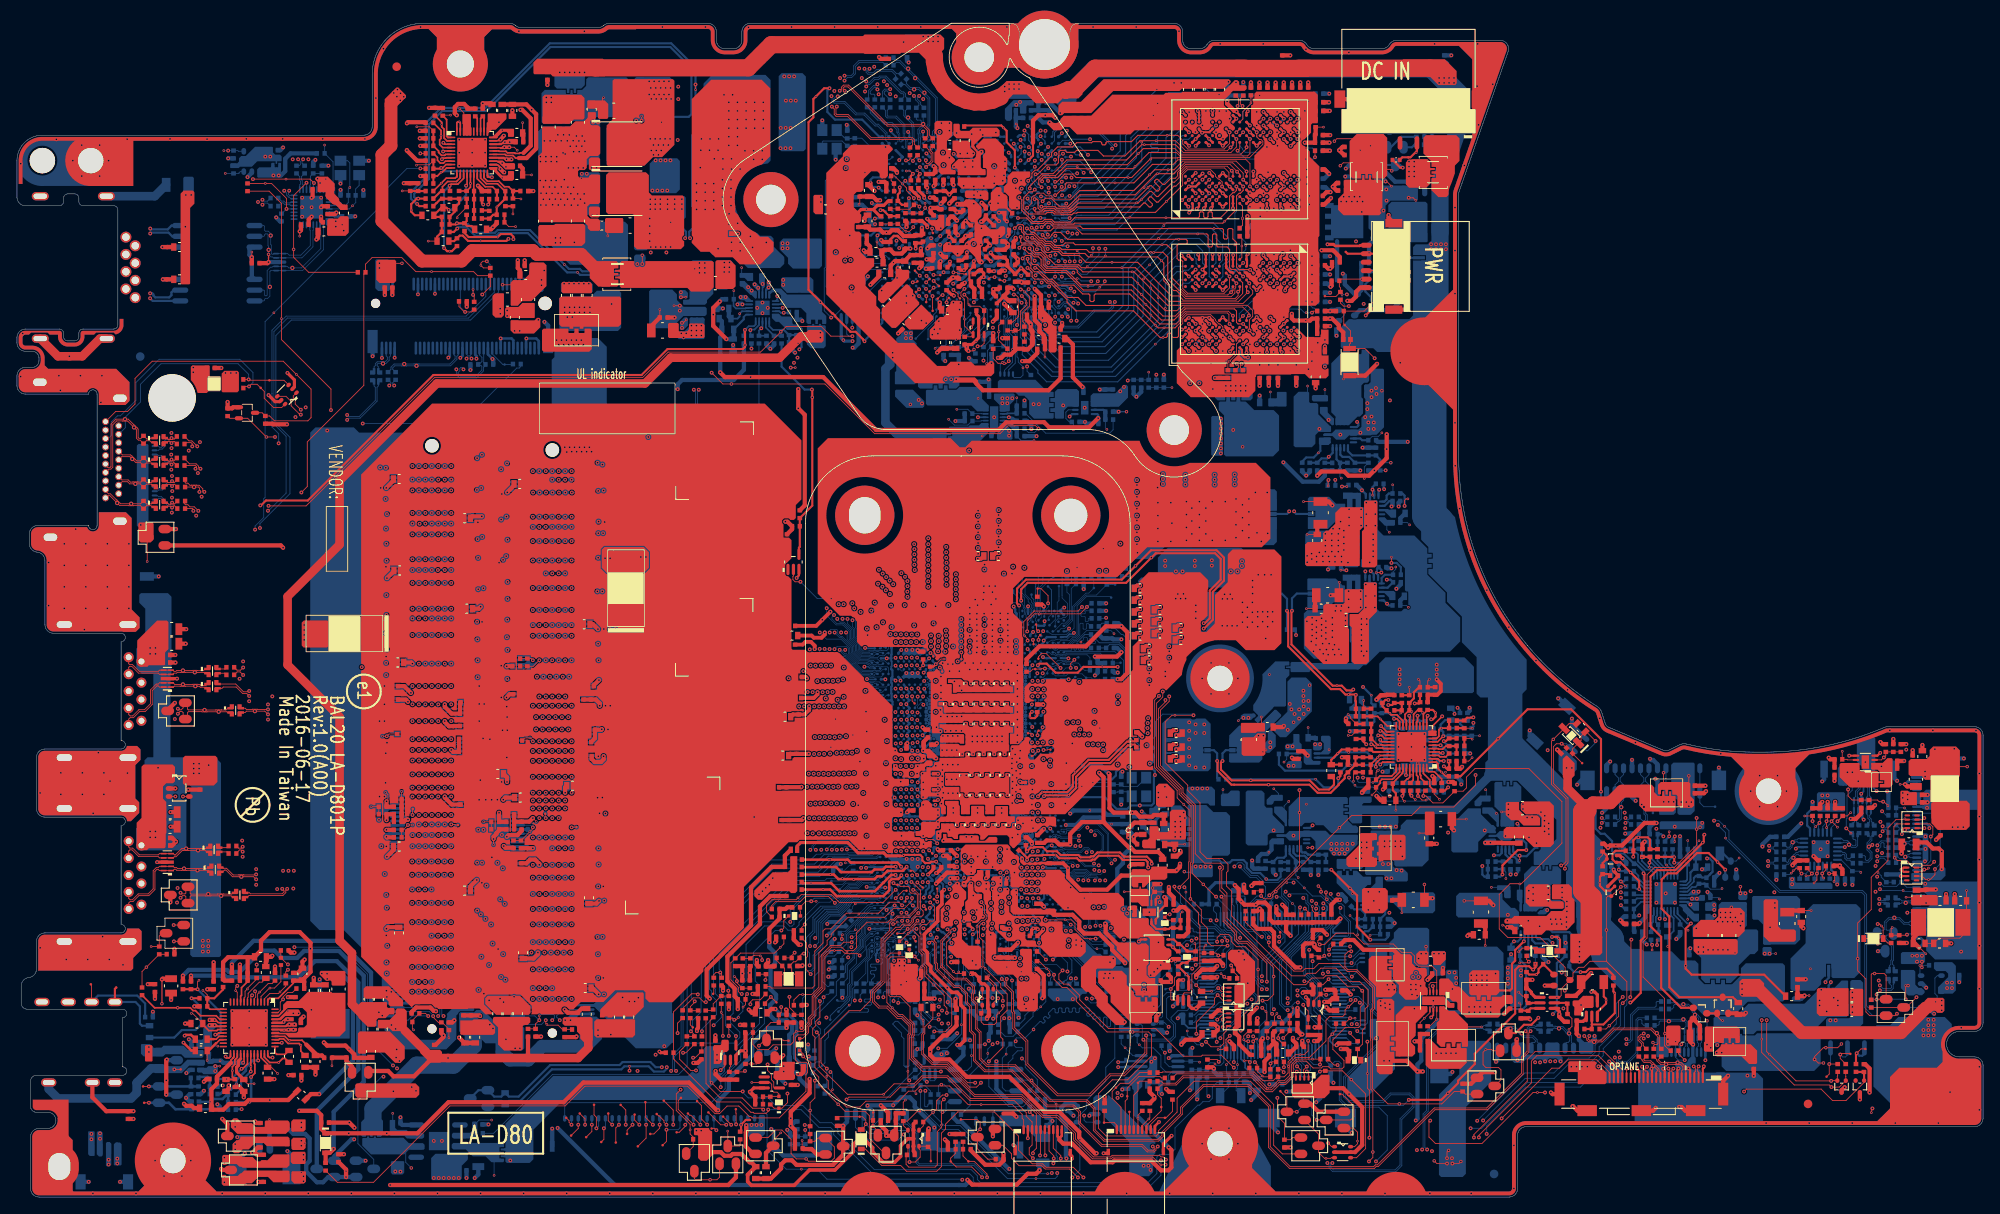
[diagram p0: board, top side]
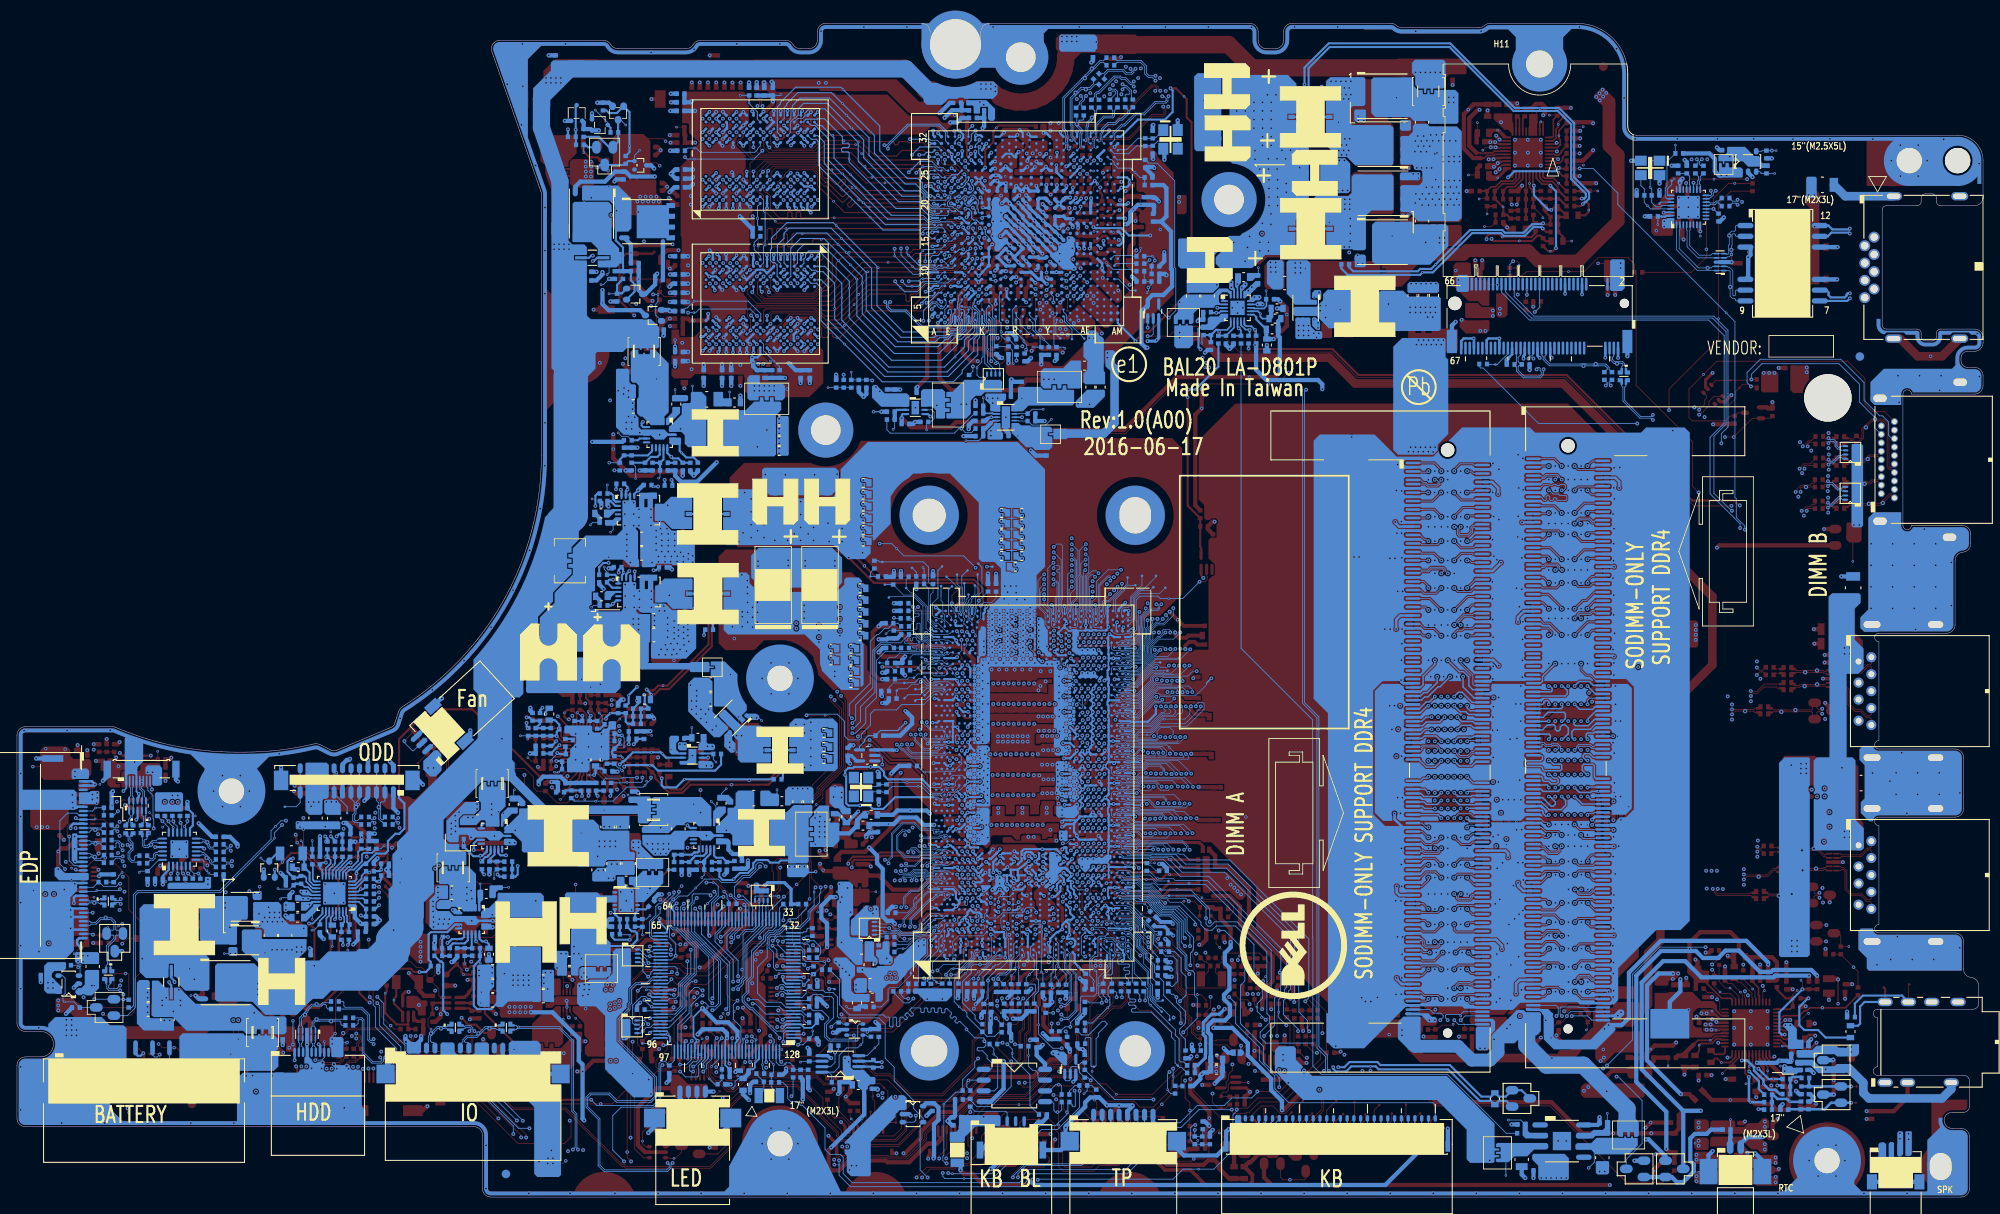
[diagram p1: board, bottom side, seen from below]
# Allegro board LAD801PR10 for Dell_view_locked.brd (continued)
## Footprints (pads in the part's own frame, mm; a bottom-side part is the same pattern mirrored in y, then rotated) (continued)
ACES_50271-0020N-001_2P
  oval 0.787x1.6 smd: 1(0,0) 2(1.25,0)
  rect 2.108x2.997 smd: 3(3.8,-2.9) 4(-2.55,-2.9)
ACES_50406-03071-001_30P
  oval 0.254x1.295 smd: 1(0,0) 2(0.5,0) 3(1,0) 4(1.5,0) 5(2,0) 6(2.5,0) 7(3,0) 8(3.5,0) 9(4,0) 10(4.5,0) 11(5,0) 12(5.5,0) 13(6,0) 14(6.5,0) 15(7,0) 16(7.5,0) 17(8,0) 18(8.5,0) 19(9,0) 20(9.5,0) 21(10,0) 22(10.5,0) 23(11,0) 24(11.5,0) 25(12,0) 26(12.5,0) 27(13,0) 28(13.5,0) 29(14,0) 30(14.5,0)
  rect 1.194x2.692 smd: 31(16.9,1.95) 35(-2.4,1.95)
  rect 2.311x1.295 smd: 32(13.65,3.9) 33(7.25,3.9) 34(0.85,3.9)
ACES_50458-00601-001_6P-T
  oval 0.559x1.6 smd: 1(0,0) 2(2,0) 3(4,0) 4(6,0) 5(8,0) 6(10,0)
  rect 1.295x2.057 smd: 7(-3.1,-5.175) 8(13.1,-5.175)
ACES_50458-01001-P01_10P-T
  oval 0.559x1.803 smd: 1(0,0) 2(2,0) 3(4,0) 4(6,0) 5(8,0) 6(10,0) 7(12,0) 8(14,0) 9(16,0) 10(18,0)
  rect 1.295x2.057 smd: 11(-3.1,-5.275) 12(21.1,-5.275)
ACES_50463-0104A-001_10P
  oval 0.203x1.194 smd: 1(0,0) 2(-0.4,0) 3(-0.8,0) 4(-1.2,0) 5(-1.6,0) 6(-2,0) 7(-2.4,0) 8(-2.8,0) 9(-3.2,0) 10(-3.6,0)
  rect 0.889x2.007 smd: 11(-5.85,-1.37) 12(2.25,-1.37)
ACES_50673-0120N-001_12P-T
  oval 0.61x1.499 smd: 1(0,0) 3(-1,0) 5(-2,0) 7(-3,0) 9(-4,0) 11(-5,0) 13(-6,0) 15(-7,0) 17(-8,0) 19(-9,0) 21(-10,0) 23(-11,0)
  oval 0.61x1.194 smd: 2(0,2.85) 4(-1,2.85) 6(-2,2.85) 8(-3,2.85) 10(-4,2.85) 12(-5,2.85) 14(-6,2.85) 16(-7,2.85) 18(-8,2.85) 20(-9,2.85) 22(-10,2.85) 24(-11,2.85)
  rect 1.702x2.311 smd: 25(-13.25,1.425) 26(2.25,1.425)
ACES_51524-0040N-001_4P
  oval 0.61x1.448 smd: 1(0,0) 2(1,0) 3(2,0) 4(3,0)
  rect 2.489x2.21 smd: 5(-3,-3.125) 6(6,-3.125)
ACES_51524-0160N-001_16P
  oval 0.61x1.295 smd: 1(0,0) 2(1,0) 3(2,0) 4(3,0) 5(4,0) 6(5,0) 7(6,0) 8(7,0) 9(8,0) 10(9,0) 11(10,0) 12(11,0) 13(12,0) 14(13,0) 15(14,0) 16(15,0)
  rect 2.159x2.21 smd: 17(-2.825,-3.05) 18(17.825,-3.05)
ACES_51540-04001-P01_40P
  oval 0.305x1.092 smd: 1(0,0) 2(0.5,0) 3(1,0) 4(1.5,0) 5(2,0) 6(2.5,0) 7(3,0) 8(3.5,0) 9(4,0) 10(4.5,0) 11(5,0) 12(5.5,0) 13(6,0) 14(6.5,0) 15(7,0) 16(7.5,0) 17(8,0) 18(8.5,0) 19(9,0) 20(9.5,0) 21(10,0) 22(10.5,0) 23(11,0) 24(11.5,0) 25(12,0) 26(12.5,0) 27(13,0) 28(13.5,0) 29(14,0) 30(14.5,0) 31(15,0) 32(15.5,0) 33(16,0) 34(16.5,0) 35(17,0) 36(17.5,0) 37(18,0) 38(18.5,0) 39(19,0) 40(19.5,0)
  rect 0.787x2.489 smd: 41(21.2,-3.6) 42(-1.7,-3.6)
ACES_51575-00401-001_4P-T
  oval 0.406x1.194 smd: 1(0,0) 2(1,0) 3(2,0) 4(3,0)
  rect 0.787x2.007 smd: 5(-2.2,-3.4) 6(5.2,-3.4)
ACES_51625-01201-001_12P
  oval 0.305x1.092 smd: 1(0,0) 2(0.5,0) 3(1,0) 4(1.5,0) 5(2,0) 6(2.5,0) 7(3,0) 8(3.5,0) 9(4,0) 10(4.5,0) 11(5,0) 12(5.5,0)
  rect 0.991x2.489 smd: 13(-1.8,-3.6) 14(7.3,-3.6)
ACON_TARA4-9K1311_9P
  round 1.194 hole 0.711: 1(0,0) 2(-2.5,0) 3(-4.5,0) 4(-7,0) 5(-7.5,-1.5) 6(-5.5,-1.5) 7(-3.5,-1.5) 8(-1.5,-1.5) 9(0.5,-1.5)
  oval 1.397x2.591 hole 0.787x2.007: 10(-11.35,-1.59) 13(4.35,-1.59)
  oval 1.397x2.388 hole 0.787x1.803: 11(-11.35,-9.09) 12(4.35,-9.09)
ALC3246-CG_MQFN48_6X6-S
  oval 0.889x0.203 smd: 1(0,0) 2(0,-0.4) 3(0,-0.8) 4(0,-1.2) 5(0,-1.6) 6(0,-2) 7(0,-2.4) 8(0,-2.8) 9(0,-3.2) 10(0,-3.6) 11(0,-4) 12(0,-4.4) 25(6.1,-4.4) 26(6.1,-4) 27(6.1,-3.6) 28(6.1,-3.2) 29(6.1,-2.8) 30(6.1,-2.4) 31(6.1,-2) 32(6.1,-1.6) 33(6.1,-1.2) 34(6.1,-0.8) 35(6.1,-0.4) 36(6.1,0)
  oval 0.203x0.889 smd: 13(0.85,-5.25) 14(1.25,-5.25) 15(1.65,-5.25) 16(2.05,-5.25) 17(2.45,-5.25) 18(2.85,-5.25) 19(3.25,-5.25) 20(3.65,-5.25) 21(4.05,-5.25) 22(4.45,-5.25) 23(4.85,-5.25) 24(5.25,-5.25) 37(5.25,0.85) 38(4.85,0.85) 39(4.45,0.85) 40(4.05,0.85) 41(3.65,0.85) 42(3.25,0.85) 43(2.85,0.85) 44(2.45,0.85) 45(2.05,0.85) 46(1.65,0.85) 47(1.25,0.85) 48(0.85,0.85)
  rect 4.394x4.394 smd: 49(3.05,-2.2)
AON7934_DFN3X3A8-10
  oval 0.457x0.508 smd: 1(0,0) 2(0.65,0) 3(1.3,0) 4(1.95,0) 5(1.95,2.76) 6(1.3,2.76) 7(0.65,2.76) 8(0,2.76)
  rect 2.54x1.041 smd: 9(0.975,1.813)
  rect 2.54x0.559 smd: 10(0.975,0.708)
AOZ5019QI_QFN23_5X3P5
  oval 0.254x0.762 smd: 1(0,0) 2(0.5,0) 3(1,0) 4(1.5,0) 5(2,0)
  rect 3.175x1.524 smd: 6(1.475,1.335)
  custom 0.588x0.588 smd: 7(1.005,2.425)
  rect 1.956x0.864 smd: 8(1.255,4.787)
  oval 0.762x0.254 smd: 9(-0.67,2.925) 10(-0.67,1.925) 11(-0.67,1.425) 12(-0.67,0.925) 13(-0.67,0.425)
AZ5123-02SPR7G_SOT23-3
  oval 1.016x1.524 smd: 1(0,0) 2(0.965,2.083) 3(-0.965,2.083)
AZ5125-01HPR7G_SOD523-2
  rect 0.61x0.787 smd: 1(0,0) 2(1.5,0)
AZ5125-02SPR7G_SOT23-3
  oval 1.016x1.524 smd: 1(0,0) 2(0.965,2.083) 3(-0.965,2.083)
AZ5725-01F_DFN2
  rect 0.559x0.61 smd: 1(0,0) 2(0.85,0)
AZC199-02SPR7G_SOT23-3
  oval 1.016x1.524 smd: 1(0,0) 2(0.965,2.083) 3(-0.965,2.083)
BAS40C_SOT23-3
  oval 1.016x1.524 smd: 1(0,0) 2(0.965,2.083) 3(-0.965,2.083)
BAT54C-7-F_SOT23-3
  oval 1.016x1.524 smd: 1(0,0) 2(0.965,2.083) 3(-0.965,2.083)
BAV99W_SC70-3
  oval 0.508x0.559 smd: 1(0,0) 2(-0.65,-1.85) 3(0.65,-1.85)
C_5X4P5
  oval 2.997x1.6 smd: 1(0,0) 2(-4.4,0)
C_25CL33LD
  oval 3.607x1.803 smd: 1(0,0) 2(5.4,0)
C_0201
  rect 0.381x0.356 smd: 1(0,0) 2(0.584,0)
C_0402
  rect 0.508x0.559 smd: 1(0,0) 2(0.914,0)
C_0603
  rect 0.635x0.889 smd: 1(0,0) 2(1.397,0)
C_0805
  rect 0.813x1.397 smd: 1(0,0) 2(1.702,0)
C_1206
  rect 1.016x1.651 smd: 1(0,0) 2(2.667,0)
C_D2
  rect 2.388x2.794 smd: 1(0,0) 2(6.4,0)
CONCR_099AKAC19NBLCNF_19P
  round 0.813 hole 0.559: 1(0,0) 2(0.5,1.55) 3(1,0) 4(1.5,1.55) 5(2,0) 6(2.5,1.55) 7(3,0) 8(3.5,1.55) 9(4,0) 10(4.5,1.55) 11(5,0) 12(5.5,1.55) 13(6,0) 14(6.5,1.55) 15(7,0) 16(7.5,1.55) 17(8,0) 18(8.5,1.55) 19(9,0)
  oval 1.499x2.21 hole 0.889x1.6: 20(-2.75,1.7) 21(-4.65,-6.5) 22(11.75,1.7) 23(13.65,-7.75)
DDTA144VCA-7-F_SOT23-3
  oval 1.016x1.524 smd: 1(0,0) 2(0.965,2.083) 3(-0.965,2.083)
DEREN_40-42261-26001RHF_260P-T
  round 1.092 hole 1.092 unplated: (-67.775,-4.1)
  round 1.6 hole 1.6 unplated: (1.025,-4.1)
  oval 0.305x1.753 smd: 1(0,0) 2(-0.25,-8.2) 3(-0.5,0) 4(-0.75,-8.2) 5(-1,0) 6(-1.25,-8.2) 7(-1.5,0) 8(-1.75,-8.2) 9(-2,0) 10(-2.25,-8.2) 11(-2.5,0) 12(-2.75,-8.2) 13(-3,0) 14(-3.25,-8.2) 15(-3.5,0) 16(-3.75,-8.2) 17(-4,0) 18(-4.25,-8.2) 19(-4.5,0) 20(-4.75,-8.2) 21(-5,0) 22(-5.25,-8.2) 23(-5.5,0) 24(-5.75,-8.2) 25(-6,0) 26(-6.25,-8.2) 27(-6.5,0) 28(-6.75,-8.2) 29(-7,0) 30(-7.25,-8.2) 31(-7.5,0) 32(-7.75,-8.2) 33(-8,0) 34(-8.25,-8.2) 35(-8.5,0) 36(-8.75,-8.2) 37(-9,0) 38(-9.25,-8.2) 39(-9.5,0) 40(-9.75,-8.2) 41(-10,0) 42(-10.25,-8.2) 43(-10.5,0) 44(-10.75,-8.2) 45(-11,0) 46(-11.25,-8.2) 47(-11.5,0) 48(-11.75,-8.2) 49(-12,0) 50(-12.25,-8.2) 51(-12.5,0) 52(-12.75,-8.2) 53(-13,0) 54(-13.25,-8.2) 55(-13.5,0) 56(-13.75,-8.2) 57(-14,0) 58(-14.25,-8.2) 59(-14.5,0) 60(-14.75,-8.2) 61(-15,0) 62(-15.25,-8.2) 63(-15.5,0) 64(-15.75,-8.2) 65(-16,0) 66(-16.25,-8.2) 67(-16.5,0) 68(-16.75,-8.2) 69(-17,0) 70(-17.25,-8.2) 71(-17.5,0) 72(-17.75,-8.2) 73(-18,0) 74(-18.25,-8.2) 75(-18.5,0) 76(-18.75,-8.2) 77(-19,0) 78(-19.25,-8.2) 79(-19.5,0) 80(-19.75,-8.2) 81(-20,0) 82(-20.25,-8.2) 83(-20.5,0) 84(-20.75,-8.2) 85(-21,0) 86(-21.25,-8.2) 87(-21.5,0) 88(-21.75,-8.2) 89(-22,0) 90(-22.25,-8.2) 91(-22.5,0) 92(-22.75,-8.2) 93(-23,0) 94(-23.25,-8.2) 95(-23.5,0) 96(-23.75,-8.2) 97(-24,0) 98(-24.25,-8.2) 99(-24.5,0) 100(-24.75,-8.2) 101(-25,0) 102(-25.25,-8.2) 103(-25.5,0) 104(-25.75,-8.2) 105(-26,0) 106(-26.25,-8.2) 107(-26.5,0) 108(-26.75,-8.2) 109(-27,0) 110(-27.25,-8.2) 111(-27.5,0) 112(-27.75,-8.2) 113(-28,0) 114(-28.25,-8.2) 115(-28.5,0) 116(-28.75,-8.2) 117(-29,0) 118(-29.25,-8.2) 119(-29.5,0) 120(-29.75,-8.2) 121(-30,0) 122(-30.25,-8.2) 123(-30.5,0) 124(-30.75,-8.2) 125(-31,0) 126(-31.25,-8.2) 127(-31.5,0) 128(-31.75,-8.2) 129(-32,0) 130(-32.25,-8.2) 131(-32.5,0) 132(-32.75,-8.2) 133(-33,0) 134(-33.25,-8.2) 135(-33.5,0) 136(-33.75,-8.2) 137(-34,0) 138(-34.25,-8.2) 139(-34.5,0) 140(-34.75,-8.2) 141(-35,0) 142(-35.25,-8.2) 143(-35.5,0) 144(-35.75,-8.2) 145(-38,0) 146(-38.25,-8.2) 147(-38.5,0) 148(-38.75,-8.2) 149(-39,0) 150(-39.25,-8.2) 151(-39.5,0) 152(-39.75,-8.2) 153(-40,0) 154(-40.25,-8.2) 155(-40.5,0) 156(-40.75,-8.2) 157(-41,0) 158(-41.25,-8.2) 159(-41.5,0) 160(-41.75,-8.2) 161(-42,0) 162(-42.25,-8.2) 163(-42.5,0) 164(-42.75,-8.2) 165(-43,0) 166(-43.25,-8.2) 167(-43.5,0) 168(-43.75,-8.2) 169(-44,0) 170(-44.25,-8.2) 171(-44.5,0) 172(-44.75,-8.2) 173(-45,0) 174(-45.25,-8.2) 175(-45.5,0) 176(-45.75,-8.2) 177(-46,0) 178(-46.25,-8.2) 179(-46.5,0) 180(-46.75,-8.2) 181(-47,0) 182(-47.25,-8.2) 183(-47.5,0) 184(-47.75,-8.2) 185(-48,0) 186(-48.25,-8.2) 187(-48.5,0) 188(-48.75,-8.2) 189(-49,0) 190(-49.25,-8.2) 191(-49.5,0) 192(-49.75,-8.2) 193(-50,0) 194(-50.25,-8.2) 195(-50.5,0) 196(-50.75,-8.2) 197(-51,0) 198(-51.25,-8.2) 199(-51.5,0) 200(-51.75,-8.2) 201(-52,0) 202(-52.25,-8.2) 203(-52.5,0) 204(-52.75,-8.2) 205(-53,0) 206(-53.25,-8.2) 207(-53.5,0) 208(-53.75,-8.2) 209(-54,0) 210(-54.25,-8.2) 211(-54.5,0) 212(-54.75,-8.2) 213(-55,0) 214(-55.25,-8.2) 215(-55.5,0) 216(-55.75,-8.2) 217(-56,0) 218(-56.25,-8.2) 219(-56.5,0) 220(-56.75,-8.2) 221(-57,0) 222(-57.25,-8.2) 223(-57.5,0) 224(-57.75,-8.2) 225(-58,0) 226(-58.25,-8.2) 227(-58.5,0) 228(-58.75,-8.2) 229(-59,0) 230(-59.25,-8.2) 231(-59.5,0) 232(-59.75,-8.2) 233(-60,0) 234(-60.25,-8.2) 235(-60.5,0) 236(-60.75,-8.2) 237(-61,0) 238(-61.25,-8.2) 239(-61.5,0) 240(-61.75,-8.2) 241(-62,0) 242(-62.25,-8.2) 243(-62.5,0) 244(-62.75,-8.2) 245(-63,0) 246(-63.25,-8.2) 247(-63.5,0) 248(-63.75,-8.2) 249(-64,0) 250(-64.25,-8.2) 251(-64.5,0) 252(-64.75,-8.2) 253(-65,0) 254(-65.25,-8.2) 255(-65.5,0) 256(-65.75,-8.2) 257(-66,0) 258(-66.25,-8.2) 259(-66.5,0) 260(-66.75,-8.2)
  rect 3.505x4.597 smd: 261(0.425,-16.1) 262(-67.175,-16.1)
DEREN_40-42271-26001RHF_260P-T
  round 1.6 hole 1.6 unplated: (-1.025,4.1)
  round 1.092 hole 1.092 unplated: (67.775,4.1)
  oval 0.305x1.753 smd: 1(0,0) 2(0.25,8.2) 3(0.5,0) 4(0.75,8.2) 5(1,0) 6(1.25,8.2) 7(1.5,0) 8(1.75,8.2) 9(2,0) 10(2.25,8.2) 11(2.5,0) 12(2.75,8.2) 13(3,0) 14(3.25,8.2) 15(3.5,0) 16(3.75,8.2) 17(4,0) 18(4.25,8.2) 19(4.5,0) 20(4.75,8.2) 21(5,0) 22(5.25,8.2) 23(5.5,0) 24(5.75,8.2) 25(6,0) 26(6.25,8.2) 27(6.5,0) 28(6.75,8.2) 29(7,0) 30(7.25,8.2) 31(7.5,0) 32(7.75,8.2) 33(8,0) 34(8.25,8.2) 35(8.5,0) 36(8.75,8.2) 37(9,0) 38(9.25,8.2) 39(9.5,0) 40(9.75,8.2) 41(10,0) 42(10.25,8.2) 43(10.5,0) 44(10.75,8.2) 45(11,0) 46(11.25,8.2) 47(11.5,0) 48(11.75,8.2) 49(12,0) 50(12.25,8.2) 51(12.5,0) 52(12.75,8.2) 53(13,0) 54(13.25,8.2) 55(13.5,0) 56(13.75,8.2) 57(14,0) 58(14.25,8.2) 59(14.5,0) 60(14.75,8.2) 61(15,0) 62(15.25,8.2) 63(15.5,0) 64(15.75,8.2) 65(16,0) 66(16.25,8.2) 67(16.5,0) 68(16.75,8.2) 69(17,0) 70(17.25,8.2) 71(17.5,0) 72(17.75,8.2) 73(18,0) 74(18.25,8.2) 75(18.5,0) 76(18.75,8.2) 77(19,0) 78(19.25,8.2) 79(19.5,0) 80(19.75,8.2) 81(20,0) 82(20.25,8.2) 83(20.5,0) 84(20.75,8.2) 85(21,0) 86(21.25,8.2) 87(21.5,0) 88(21.75,8.2) 89(22,0) 90(22.25,8.2) 91(22.5,0) 92(22.75,8.2) 93(23,0) 94(23.25,8.2) 95(23.5,0) 96(23.75,8.2) 97(24,0) 98(24.25,8.2) 99(24.5,0) 100(24.75,8.2) 101(25,0) 102(25.25,8.2) 103(25.5,0) 104(25.75,8.2) 105(26,0) 106(26.25,8.2) 107(26.5,0) 108(26.75,8.2) 109(27,0) 110(27.25,8.2) 111(27.5,0) 112(27.75,8.2) 113(28,0) 114(28.25,8.2) 115(28.5,0) 116(28.75,8.2) 117(29,0) 118(29.25,8.2) 119(29.5,0) 120(29.75,8.2) 121(30,0) 122(30.25,8.2) 123(30.5,0) 124(30.75,8.2) 125(31,0) 126(31.25,8.2) 127(31.5,0) 128(31.75,8.2) 129(32,0) 130(32.25,8.2) 131(32.5,0) 132(32.75,8.2) 133(33,0) 134(33.25,8.2) 135(33.5,0) 136(33.75,8.2) 137(34,0) 138(34.25,8.2) 139(34.5,0) 140(34.75,8.2) 141(35,0) 142(35.25,8.2) 143(35.5,0) 144(35.75,8.2) 145(38,0) 146(38.25,8.2) 147(38.5,0) 148(38.75,8.2) 149(39,0) 150(39.25,8.2) 151(39.5,0) 152(39.75,8.2) 153(40,0) 154(40.25,8.2) 155(40.5,0) 156(40.75,8.2) 157(41,0) 158(41.25,8.2) 159(41.5,0) 160(41.75,8.2) 161(42,0) 162(42.25,8.2) 163(42.5,0) 164(42.75,8.2) 165(43,0) 166(43.25,8.2) 167(43.5,0) 168(43.75,8.2) 169(44,0) 170(44.25,8.2) 171(44.5,0) 172(44.75,8.2) 173(45,0) 174(45.25,8.2) 175(45.5,0) 176(45.75,8.2) 177(46,0) 178(46.25,8.2) 179(46.5,0) 180(46.75,8.2) 181(47,0) 182(47.25,8.2) 183(47.5,0) 184(47.75,8.2) 185(48,0) 186(48.25,8.2) 187(48.5,0) 188(48.75,8.2) 189(49,0) 190(49.25,8.2) 191(49.5,0) 192(49.75,8.2) 193(50,0) 194(50.25,8.2) 195(50.5,0) 196(50.75,8.2) 197(51,0) 198(51.25,8.2) 199(51.5,0) 200(51.75,8.2) 201(52,0) 202(52.25,8.2) 203(52.5,0) 204(52.75,8.2) 205(53,0) 206(53.25,8.2) 207(53.5,0) 208(53.75,8.2) 209(54,0) 210(54.25,8.2) 211(54.5,0) 212(54.75,8.2) 213(55,0) 214(55.25,8.2) 215(55.5,0) 216(55.75,8.2) 217(56,0) 218(56.25,8.2) 219(56.5,0) 220(56.75,8.2) 221(57,0) 222(57.25,8.2) 223(57.5,0) 224(57.75,8.2) 225(58,0) 226(58.25,8.2) 227(58.5,0) 228(58.75,8.2) 229(59,0) 230(59.25,8.2) 231(59.5,0) 232(59.75,8.2) 233(60,0) 234(60.25,8.2) 235(60.5,0) 236(60.75,8.2) 237(61,0) 238(61.25,8.2) 239(61.5,0) 240(61.75,8.2) 241(62,0) 242(62.25,8.2) 243(62.5,0) 244(62.75,8.2) 245(63,0) 246(63.25,8.2) 247(63.5,0) 248(63.75,8.2) 249(64,0) 250(64.25,8.2) 251(64.5,0) 252(64.75,8.2) 253(65,0) 254(65.25,8.2) 255(65.5,0) 256(65.75,8.2) 257(66,0) 258(66.25,8.2) 259(66.5,0) 260(66.75,8.2)
  rect 3.505x4.597 smd: 261(-0.425,-7.9) 262(67.175,-7.9)
DMN66D0LDW-7_SOT363-6
  oval 0.432x0.61 smd: 1(0,0) 2(0.65,0) 3(1.3,0) 4(1.3,1.9) 5(0.65,1.9) 6(0,1.9)
EM5209VF_DFN14_3X2-S
  oval 0.203x0.711 smd: 1(0,0) 2(0.4,0) 3(0.8,0) 4(1.2,0) 5(1.6,0) 6(2,0) 7(2.4,0) 8(2.4,2) 9(2,2) 10(1.6,2) 11(1.2,2) 12(0.8,2) 13(0.4,2) 14(0,2)
  rect 2.591x0.991 smd: 15(1.2,1)
F_1206L150PR
  rect 0.991x1.803 smd: 1(0,0) 2(2.8,0)
F_MF-NSMF050-2
  rect 0.991x1.6 smd: 1(0,0) 2(3,0)
F_SMD1812P110TF-24
  rect 1.778x3.15 smd: 1(0,0) 2(5.23,0)
FDV301N_NL_SOT23-3
  oval 1.016x1.524 smd: 1(0,0) 2(0.965,2.083) 3(-0.965,2.083)
FIDUCIAL_C40M80
  round 1.016 smd: 1(0,0)
H5GC4H24AJR-R0C_BGA_170P
  round 0.343 smd: A1(0,0) A2(0.8,0) A3(1.6,0) A4(2.4,0) A5(3.2,0) A10(7.201,0) A11(8.001,0) A12(8.801,0) A13(9.601,0) A14(10.401,0) B1(0,-0.8) B2(0.8,-0.8) B3(1.6,-0.8) B4(2.4,-0.8) B5(3.2,-0.8) B10(7.201,-0.8) B11(8.001,-0.8) B12(8.801,-0.8) B13(9.601,-0.8) B14(10.401,-0.8) C1(0,-1.6) C2(0.8,-1.6) C3(1.6,-1.6) C4(2.4,-1.6) C5(3.2,-1.6) C10(7.201,-1.6) C11(8.001,-1.6) C12(8.801,-1.6) C13(9.601,-1.6) C14(10.401,-1.6) D1(0,-2.4) D2(0.8,-2.4) D3(1.6,-2.4) D4(2.4,-2.4) D5(3.2,-2.4) D10(7.201,-2.4) D11(8.001,-2.4) D12(8.801,-2.4) D13(9.601,-2.4) D14(10.401,-2.4) E1(0,-3.2) E2(0.8,-3.2) E3(1.6,-3.2) E4(2.4,-3.2) E5(3.2,-3.2) E10(7.201,-3.2) E11(8.001,-3.2) E12(8.801,-3.2) E13(9.601,-3.2) E14(10.401,-3.2) F1(0,-4) F2(0.8,-4) F3(1.6,-4) F4(2.4,-4) F5(3.2,-4) F10(7.201,-4) F11(8.001,-4) F12(8.801,-4) F13(9.601,-4) F14(10.401,-4) G1(0,-4.801) G2(0.8,-4.801) G3(1.6,-4.801) G4(2.4,-4.801) G5(3.2,-4.801) G10(7.201,-4.801) G11(8.001,-4.801) G12(8.801,-4.801) G13(9.601,-4.801) G14(10.401,-4.801) H1(0,-5.601) H2(0.8,-5.601) H3(1.6,-5.601) H4(2.4,-5.601) H5(3.2,-5.601) H10(7.201,-5.601) H11(8.001,-5.601) H12(8.801,-5.601) H13(9.601,-5.601) H14(10.401,-5.601) J1(0,-6.401) J2(0.8,-6.401) J3(1.6,-6.401) J4(2.4,-6.401) J5(3.2,-6.401) J10(7.201,-6.401) J11(8.001,-6.401) J12(8.801,-6.401) J13(9.601,-6.401) J14(10.401,-6.401) K1(0,-7.201) K2(0.8,-7.201) K3(1.6,-7.201) K4(2.4,-7.201) K5(3.2,-7.201) K10(7.201,-7.201) K11(8.001,-7.201) K12(8.801,-7.201) K13(9.601,-7.201) K14(10.401,-7.201) L1(0,-8.001) L2(0.8,-8.001) L3(1.6,-8.001) L4(2.4,-8.001) L5(3.2,-8.001) L10(7.201,-8.001) L11(8.001,-8.001) L12(8.801,-8.001) L13(9.601,-8.001) L14(10.401,-8.001) M1(0,-8.801) M2(0.8,-8.801) M3(1.6,-8.801) M4(2.4,-8.801) M5(3.2,-8.801) M10(7.201,-8.801) M11(8.001,-8.801) M12(8.801,-8.801) M13(9.601,-8.801) M14(10.401,-8.801) N1(0,-9.601) N2(0.8,-9.601) N3(1.6,-9.601) N4(2.4,-9.601) N5(3.2,-9.601) N10(7.201,-9.601) N11(8.001,-9.601) N12(8.801,-9.601) N13(9.601,-9.601) N14(10.401,-9.601) P1(0,-10.401) P2(0.8,-10.401) P3(1.6,-10.401) P4(2.4,-10.401) P5(3.2,-10.401) P10(7.201,-10.401) P11(8.001,-10.401) P12(8.801,-10.401) P13(9.601,-10.401) P14(10.401,-10.401) R1(0,-11.201) R2(0.8,-11.201) R3(1.6,-11.201) R4(2.4,-11.201) R5(3.2,-11.201) R10(7.201,-11.201) R11(8.001,-11.201) R12(8.801,-11.201) R13(9.601,-11.201) R14(10.401,-11.201) T1(0,-12.002) T2(0.8,-12.002) T3(1.6,-12.002) T4(2.4,-12.002) T5(3.2,-12.002) T10(7.201,-12.002) T11(8.001,-12.002) T12(8.801,-12.002) T13(9.601,-12.002) T14(10.401,-12.002) U1(0,-12.802) U2(0.8,-12.802) U3(1.6,-12.802) U4(2.4,-12.802) U5(3.2,-12.802) U10(7.201,-12.802) U11(8.001,-12.802) U12(8.801,-12.802) U13(9.601,-12.802) U14(10.401,-12.802)
H_3P0-G
  round 3.505 hole 2.997: 1(0,0)
H_3P0N
  round 2.997 hole 2.997 unplated: (0,0)
H_3P2
  round 3.708 hole 3.2: 1(0,0)
H_3P2X2P6
  oval 3.708x3.099 hole 3.2x2.591: 1(0,0)
H_3P5
  round 4.013 hole 3.505: 1(0,0)
H_3P7
  round 4.216 hole 3.708: 1(0,0)
H_3P7X4P3
  oval 4.216x4.801 hole 3.708x4.293: 1(0,0)
H_3P9
  round 4.42 hole 3.912: 1(0,0)
H_5P6N
  round 5.588 hole 5.588 unplated: (0,0)
H_6P0
  round 6.502 hole 5.994: 1(0,0)
INPAQ_HCM1012GH900BP_4P-NPM
  rect 0.711x0.305 smd: 1(0,0) 2(1.25,0) 3(1.25,-0.5) 4(0,-0.5)
INPAQ_MCM1012B900F06BP_4P
  rect 0.711x0.305 smd: 1(0,0) 2(1.25,0) 3(1.25,-0.5) 4(0,-0.5)
INPAQ_MCM1012B900F06BP_4P-NPM
  rect 0.711x0.305 smd: 1(0,0) 2(1.25,0) 3(1.25,-0.5) 4(0,-0.5)
IP4292CZ10-TBR_XSON10_2P5X1
  oval 0.254x0.889 smd: 1(0,0)
  oval 0.254x0.838 smd: 2(0.5,-0.025) 3(1,-0.025) 4(1.5,-0.025) 5(2,-0.025) 6(2,1.125) 7(1.5,1.125) 8(1,1.125) 9(0.5,1.125) 10(0,1.125)
ISL62771HRTZ-T_TQFN40_5X5-S
  oval 0.203x1.016 smd: 1(0,0) 2(0.4,0) 3(0.8,0) 4(1.2,0) 5(1.6,0) 6(2,0) 7(2.4,0) 8(2.8,0) 9(3.2,0) 10(3.6,0) 21(3.6,4.975) 22(3.2,4.975) 23(2.8,4.975) 24(2.4,4.975) 25(2,4.975) 26(1.6,4.975) 27(1.2,4.975) 28(0.8,4.975) 29(0.4,4.975) 30(0,4.975)
  oval 1.016x0.203 smd: 11(4.288,0.688) 12(4.288,1.088) 13(4.288,1.488) 14(4.288,1.888) 15(4.288,2.288) 16(4.288,2.688) 17(4.288,3.088) 18(4.288,3.488) 19(4.288,3.888) 20(4.288,4.288) 31(-0.688,4.288) 32(-0.688,3.888) 33(-0.688,3.488) 34(-0.688,3.088) 35(-0.688,2.688) 36(-0.688,2.288) 37(-0.688,1.888) 38(-0.688,1.488) 39(-0.688,1.088) 40(-0.688,0.688)
  rect 3.505x3.505 smd: 41(1.8,2.488)
ISL62883CHRTZ-T_TQFN40_5X5-S
  oval 0.203x0.991 smd: 1(0,0) 2(0.4,0) 3(0.8,0) 4(1.2,0) 5(1.6,0) 6(2,0) 7(2.4,0) 8(2.8,0) 9(3.2,0) 10(3.6,0) 21(3.6,4.95) 22(3.2,4.95) 23(2.8,4.95) 24(2.4,4.95) 25(2,4.95) 26(1.6,4.95) 27(1.2,4.95) 28(0.8,4.95) 29(0.4,4.95) 30(0,4.95)
  oval 0.991x0.203 smd: 11(4.275,0.675) 12(4.275,1.075) 13(4.275,1.475) 14(4.275,1.875) 15(4.275,2.275) 16(4.275,2.675) 17(4.275,3.075) 18(4.275,3.475) 19(4.275,3.875) 20(4.275,4.275) 31(-0.675,4.275) 32(-0.675,3.875) 33(-0.675,3.475) 34(-0.675,3.075) 35(-0.675,2.675) 36(-0.675,2.275) 37(-0.675,1.875) 38(-0.675,1.475) 39(-0.675,1.075) 40(-0.675,0.675)
  rect 3.505x3.505 smd: 41(1.8,2.475)
ISL95520HRZ-T_QFN32_4X4-S
  oval 0.889x0.203 smd: 1(0,0) 2(0,-0.4) 3(0,-0.8) 4(0,-1.2) 5(0,-1.6) 6(0,-2) 7(0,-2.4) 8(0,-2.8) 17(4.1,-2.8) 18(4.1,-2.4) 19(4.1,-2) 20(4.1,-1.6) 21(4.1,-1.2) 22(4.1,-0.8) 23(4.1,-0.4) 24(4.1,0)
  oval 0.203x0.889 smd: 9(0.65,-3.45) 10(1.05,-3.45) 11(1.45,-3.45) 12(1.85,-3.45) 13(2.25,-3.45) 14(2.65,-3.45) 15(3.05,-3.45) 16(3.45,-3.45) 25(3.45,0.65) 26(3.05,0.65) 27(2.65,0.65) 28(2.25,0.65) 29(1.85,0.65) 30(1.45,0.65) 31(1.05,0.65) 32(0.65,0.65)
  rect 2.642x2.642 smd: 33(2.05,-1.4)
ISL95808HRZ-TS2378_DFN8_2X2-S
  oval 0.254x0.787 smd: 1(0,0) 2(0.5,0) 3(1,0) 4(1.5,0) 5(1.5,2.2) 6(1,2.2) 7(0.5,2.2) 8(0,2.2)
  rect 1.549x0.889 smd: 9(0.75,1.1)
JUMP_43X39
  custom 0.191x0.191 smd: 1(0,0) 2(0.914,0)
JUMP_43X79
  custom 0.188x0.188 smd: 1(0,0) 2(1.1,0)
JUMP_43X79-NPM
  custom 0.188x0.188 smd: 1(0,0) 2(1.1,0)
JUMP_43X118
  custom 0.187x0.187 smd: 1(0,0) 2(1.1,0)
JXT_FP202DH-008M10M_8P
  oval 0.61x1.448 smd: 1(0,0) 2(1,0) 3(2,0) 4(3,0) 5(4,0) 6(5,0) 7(6,0) 8(7,0)
  rect 2.159x2.21 smd: 9(-2.825,-3.125) 10(9.825,-3.125)
JXT_FP226H-006S1BM_6P
  oval 0.61x1.295 smd: 1(0,0) 2(1,0) 3(2,0) 4(3,0) 5(4,0) 6(5,0)
  rect 0.991x2.007 smd: 7(-2.6,-3.25) 8(7.6,-3.25)
JXT_FP241AH-010GAAM_10P
  oval 0.305x1.092 smd: 1(0,0) 2(0.5,0) 3(1,0) 4(1.5,0) 5(2,0) 6(2.5,0) 7(3,0) 8(3.5,0) 9(4,0) 10(4.5,0)
  rect 0.406x0.787 smd: 11(-1,-2.65) 12(5.5,-2.65)
JXT_WB247H-004S10M_4P
  oval 0.61x1.549 smd: 1(0,0) 2(1,0) 3(2,0) 4(3,0)
  rect 1.194x1.803 smd: 5(-1.3,-3.875) 6(4.3,-3.875)
L2N7002WT1G_SC70-3
  oval 0.711x0.889 smd: 1(0,0) 2(0.65,1.9) 3(-0.65,1.9)
L03ESDL5V0CC3-2_SOT23-3
  oval 1.016x1.524 smd: 1(0,0) 2(0.965,2.083) 3(-0.965,2.083)
L05ESDL5V0NA-4_SLP2510P8-10-9
  rect 0.203x0.686 smd: 1(0,0) 2(-0.5,0) 4(-1.5,0) 5(-2,0) 6(-2,-0.875) 7(-1.5,-0.875) 8(-0.5,-0.875) 9(0,-0.875)
  rect 0.406x1.549 smd: 3(-1,-0.437)
L_5X5X3_M
  custom 0.54x0.54 smd: 1(0,0) 4(4.35,0)
  rect 0.762x0.508 smd: 2(0.699,0) 3(3.652,0)
L_5X5X3_M_2P
  rect 2.159x2.794 smd: 1(0,0) 2(4.35,0)
L_5X5X3_M_2P-NPM
  rect 2.159x2.794 smd: 1(0,0) 2(4.35,0)
L_7X7X3_M_2P
  rect 2.362x3.505 smd: 1(0,0) 2(6.05,0)
L_7X7X4_M
  custom 0.591x0.591 smd: 1(0,0) 4(6.05,0)
  rect 0.762x0.508 smd: 2(0.8,0) 3(5.25,0)
LCN_DAN05-67406-0100_67P
  round 1.092 hole 1.092 unplated: (-0.75,-5.275)
  round 1.6 hole 1.6 unplated: (19.25,-5.275)
  oval 0.305x1.549 smd: 1(0,0) 2(0.25,-7.55) 3(0.5,0) 4(0.75,-7.55) 5(1,0) 6(1.25,-7.55) 7(1.5,0) 8(3.75,-7.55) 9(4,0) 10(4.25,-7.55) 11(4.5,0) 12(4.75,-7.55) 13(5,0) 14(5.25,-7.55) 15(5.5,0) 16(5.75,-7.55) 17(6,0) 18(6.25,-7.55) 19(6.5,0) 20(6.75,-7.55) 21(7,0) 22(7.25,-7.55) 23(7.5,0) 24(7.75,-7.55) 25(8,0) 26(8.25,-7.55) 27(8.5,0) 28(8.75,-7.55) 29(9,0) 30(9.25,-7.55) 31(9.5,0) 32(9.75,-7.55) 33(10,0) 34(10.25,-7.55) 35(10.5,0) 36(10.75,-7.55) 37(11,0) 38(11.25,-7.55) 39(11.5,0) 40(11.75,-7.55) 41(12,0) 42(12.25,-7.55) 43(12.5,0) 44(12.75,-7.55) 45(13,0) 46(13.25,-7.55) 47(13.5,0) 48(13.75,-7.55) 49(14,0) 50(14.25,-7.55) 51(14.5,0) 52(14.75,-7.55) 53(15,0) 54(15.25,-7.55) 55(15.5,0) 56(15.75,-7.55) 57(16,0) 58(16.25,-7.55) 59(16.5,0) 60(16.75,-7.55) 61(17,0) 62(17.25,-7.55) 63(17.5,0) 64(17.75,-7.55) 65(18,0) 66(18.25,-7.55) 67(18.5,0)
  rect 1.194x2.743 smd: 68(-1.1,-0.775) 69(19.6,-0.775)
LMBT3904LT1G_SOT23-3
  oval 1.016x1.524 smd: 1(0,0) 2(0.965,2.083) 3(-0.965,2.083)
LMUN5113T1G_SOT323-3
  oval 0.711x0.889 smd: 1(0,0) 2(0.65,1.9) 3(-0.65,1.9)
LN2306LT1G_SOT23-3
  oval 1.016x1.524 smd: 1(0,0) 2(0.965,2.083) 3(-0.965,2.083)
LRB715FT1G_SOT323-3
  oval 0.711x0.889 smd: 1(0,0) 2(0.65,1.9) 3(-0.65,1.9)
LTC015EUBFS8TL_UMT3F
  oval 0.787x0.889 smd: 1(0,0) 2(-0.65,-1.6) 3(0.65,-1.6)
MDU1512RH_POWERDFN56-8-5
  oval 0.61x1.27 smd: 1(0,0) 2(1.27,0) 3(2.54,0) 4(3.81,0)
  custom 1.105x1.105 smd: 5(1.905,3.715)
MEC1404-NU-TR_VTQFP128_14X14
  oval 1.753x0.203 smd: 1(0,0) 2(0,-0.4) 3(0,-0.8) 4(0,-1.2) 5(0,-1.6) 6(0,-2) 7(0,-2.4) 8(0,-2.8) 9(0,-3.2) 10(0,-3.6) 11(0,-4) 12(0,-4.4) 13(0,-4.8) 14(0,-5.2) 15(0,-5.6) 16(0,-6) 17(0,-6.4) 18(0,-6.8) 19(0,-7.2) 20(0,-7.6) 21(0,-8) 22(0,-8.4) 23(0,-8.8) 24(0,-9.2) 25(0,-9.6) 26(0,-10) 27(0,-10.4) 28(0,-10.8) 29(0,-11.2) 30(0,-11.6) 31(0,-12) 32(0,-12.4) 65(15.654,-12.4) 66(15.654,-12) 67(15.654,-11.6) 68(15.654,-11.2) 69(15.654,-10.8) 70(15.654,-10.4) 71(15.654,-10) 72(15.654,-9.6) 73(15.654,-9.2) 74(15.654,-8.8) 75(15.654,-8.4) 76(15.654,-8) 77(15.654,-7.6) 78(15.654,-7.2) 79(15.654,-6.8) 80(15.654,-6.4) 81(15.654,-6) 82(15.654,-5.6) 83(15.654,-5.2) 84(15.654,-4.8) 85(15.654,-4.4) 86(15.654,-4) 87(15.654,-3.6) 88(15.654,-3.2) 89(15.654,-2.8) 90(15.654,-2.4) 91(15.654,-2) 92(15.654,-1.6) 93(15.654,-1.2) 94(15.654,-0.8) 95(15.654,-0.4) 96(15.654,0)
  oval 0.203x1.753 smd: 33(1.627,-14.027) 34(2.027,-14.027) 35(2.427,-14.027) 36(2.827,-14.027) 37(3.227,-14.027) 38(3.627,-14.027) 39(4.027,-14.027) 40(4.427,-14.027) 41(4.827,-14.027) 42(5.227,-14.027) 43(5.627,-14.027) 44(6.027,-14.027) 45(6.427,-14.027) 46(6.827,-14.027) 47(7.227,-14.027) 48(7.627,-14.027) 49(8.027,-14.027) 50(8.427,-14.027) 51(8.827,-14.027) 52(9.227,-14.027) 53(9.627,-14.027) 54(10.027,-14.027) 55(10.427,-14.027) 56(10.827,-14.027) 57(11.227,-14.027) 58(11.627,-14.027) 59(12.027,-14.027) 60(12.427,-14.027) 61(12.827,-14.027) 62(13.227,-14.027) 63(13.627,-14.027) 64(14.027,-14.027) 97(14.027,1.627) 98(13.627,1.627) 99(13.227,1.627) 100(12.827,1.627) 101(12.427,1.627) 102(12.027,1.627) 103(11.627,1.627) 104(11.227,1.627) 105(10.827,1.627) 106(10.427,1.627) 107(10.027,1.627) 108(9.627,1.627) 109(9.227,1.627) 110(8.827,1.627) 111(8.427,1.627) 112(8.027,1.627) 113(7.627,1.627) 114(7.227,1.627) 115(6.827,1.627) 116(6.427,1.627) 117(6.027,1.627) 118(5.627,1.627) 119(5.227,1.627) 120(4.827,1.627) 121(4.427,1.627) 122(4.027,1.627) 123(3.627,1.627) 124(3.227,1.627) 125(2.827,1.627) 126(2.427,1.627) 127(2.027,1.627) 128(1.627,1.627)
MHPC_NS681677_12P
  oval 0.635x1.905 smd: 1(0,0) 2(1.27,0) 3(2.54,0) 4(6.35,0) 5(7.62,0) 6(8.89,0) 7(8.89,8.765) 8(7.62,8.765) 9(6.35,8.765) 10(2.54,8.765) 11(1.27,8.765) 12(0,8.765)
MURAT_BLM15AG102SN1D_2P
  rect 0.457x0.508 smd: 1(0,0) 2(0.85,0)
MURAT_BLM15BB221SN1D_2P
  rect 0.457x0.508 smd: 1(0,0) 2(0.85,0)
MURAT_BLM15BD601SN1D_2P
  rect 0.508x0.762 smd: 1(0,0) 2(0.75,0)
MURAT_BLM15PD600SN1D_2P
  rect 0.508x0.762 smd: 1(0,0) 2(0.75,0)
MURAT_BLM15PX221SN1D_2P
  rect 0.457x0.508 smd: 1(0,0) 2(0.85,0)
MURAT_BLM15PX330SN1D_2P
  rect 0.508x0.762 smd: 1(0,0) 2(0.75,0)
NCT7718W_MSOP8
  oval 0.381x1.575 smd: 1(0,0) 2(0.65,0) 3(1.3,0) 4(1.95,0) 5(1.95,4.35) 6(1.3,4.35) 7(0.65,4.35) 8(0,4.35)
PESD5V0U2BT_SOT23-3
  oval 1.016x1.524 smd: 1(0,0) 2(0.965,2.083) 3(-0.965,2.083)
R0402_0OHM
  rect 0.508x0.559 smd: 1(0,0) 2(0.914,0)
R0603_0OHM
  rect 0.635x0.889 smd: 1(0,0) 2(1.397,0)
R0805_0OHM
  rect 0.813x1.397 smd: 1(0,0) 2(1.702,0)
R_0402
  rect 0.508x0.559 smd: 1(0,0) 2(0.914,0)
R_0402-NPM
  rect 0.508x0.559 smd: 1(0,0) 2(0.914,0)
R_0603
  rect 0.635x0.889 smd: 1(0,0) 2(1.397,0)
R_0805
  rect 0.813x1.397 smd: 1(0,0) 2(1.702,0)
R_1206
  rect 1.016x1.651 smd: 1(0,0) 2(2.667,0)
R_1206_4P
  custom 0.476x0.476 smd: 1(0,0) 4(5.08,0)
  rect 1.397x0.381 smd: 2(1.206,0) 3(3.873,0)
RB551V-30_SOD323-2
  rect 0.559x0.813 smd: 1(0,0) 2(2.3,0)
RB751S40T1G_SOD523-2
  rect 0.406x0.406 smd: 1(0,0) 2(1.4,0)
RHU002N06_SOT323-3
  oval 0.813x0.914 smd: 1(0,0) 2(0.65,1.6) 3(-0.65,1.6)
RP_0804_8P4R
  oval 0.66x0.254 smd: 1(0,0) 2(0,-0.5) 3(0,-1) 4(0,-1.5) 5(1.15,-1.5) 6(1.15,-1) 7(1.15,-0.5) 8(1.15,0)
RT8207PGQW_WQFN20_3X3-S
  oval 0.203x0.889 smd: 1(0,0) 2(0.4,0) 3(0.8,0) 4(1.2,0) 5(1.6,0) 11(1.6,3.1) 12(1.2,3.1) 13(0.8,3.1) 14(0.4,3.1) 15(0,3.1)
  oval 0.889x0.203 smd: 6(2.35,0.75) 7(2.35,1.15) 8(2.35,1.55) 9(2.35,1.95) 10(2.35,2.35) 16(-0.75,2.35) 17(-0.75,1.95) 18(-0.75,1.55) 19(-0.75,1.15) 20(-0.75,0.75)
  rect 1.702x1.702 smd: 21(0.8,1.55)
RT904225GSP_SO8
  oval 0.635x1.854 smd: 1(0,0) 2(1.27,0) 3(2.54,0) 4(3.81,0) 5(3.81,5.157) 6(2.54,5.157) 7(1.27,5.157) 8(0,5.157)
  rect 2.159x2.159 smd: 9(1.905,2.579)
RTL8106E-CG_QFN32_4X4-S
  oval 0.203x0.838 smd: 1(0,0) 2(0.4,0) 3(0.8,0) 4(1.2,0) 5(1.6,0) 6(2,0) 7(2.4,0) 8(2.8,0) 17(2.8,4.15) 18(2.4,4.15) 19(2,4.15) 20(1.6,4.15) 21(1.2,4.15) 22(0.8,4.15) 23(0.4,4.15) 24(0,4.15)
  oval 0.838x0.203 smd: 9(3.475,0.675) 10(3.475,1.075) 11(3.475,1.475) 12(3.475,1.875) 13(3.475,2.275) 14(3.475,2.675) 15(3.475,3.075) 16(3.475,3.475) 25(-0.675,3.475) 26(-0.675,3.075) 27(-0.675,2.675) 28(-0.675,2.275) 29(-0.675,1.875) 30(-0.675,1.475) 31(-0.675,1.075) 32(-0.675,0.675)
  rect 2.692x2.692 smd: 33(1.4,2.075)
RUM002N02GT2L_VMT3
  oval 0.508x0.457 smd: 1(0,0)
  oval 0.406x0.457 smd: 2(-0.4,-1.15) 3(0.4,-1.15)
SANTA_130460-N_8P-T
  round 1.295 hole 0.889: 1(0,0) 2(-1.02,1.1) 3(-2.04,0) 4(-3.06,1.1) 5(-4.08,0) 6(-5.1,1.1) 7(-6.12,0) 8(-7.14,1.1)
  oval 0.991x2.007 hole 0.61x1.6: 9(4.83,-10.1) 10(4.83,-2.3) 11(-11.97,-2.3) 12(-11.97,-10.1)
SDMK0340L-7-F_SOD323-2
  rect 1.346x0.66 smd: 1(0,0) 2(2.4,0)
SHORTPADS
  custom 0.19x0.19 smd: 1(-0.483,0) 2(0.483,0)
SIR472DP-T1-GE3_POWERPAK8-5
  oval 0.61x1.27 smd: 1(0,0) 2(1.27,0) 3(2.54,0) 4(3.81,0)
  custom 1.105x1.105 smd: 5(1.905,3.715)
SIS412DN-T1-GE3_POWERPAK8-5
  oval 0.406x0.991 smd: 1(0,0) 2(0.66,0) 3(1.32,0) 4(1.98,0)
  custom 0.559x0.559 smd: 5(0.99,2.247)
SKL-U_BGA_1356P-T
  round 0.356 smd: A3(-0.965,0) A70(-40.166,0) B2(-0.483,0.483) B71(-40.629,0.462) BA1(0,22.166) BA71(-40.629,22.166) BB2(-0.462,22.628) BB70(-40.166,22.628) C1(0,0.965)
  round 0.33 smd: A4(-1.615,0) A69(-39.516,0) AY1(0,21.516) AY71(-40.629,21.516) B3(-1.118,0.635) B70(-39.999,0.63) BA2(-0.629,21.999) BA70(-39.999,21.999) BB3(-1.113,22.628) BB69(-39.516,22.628) C2(-0.635,1.118) C71(-40.629,1.113) D1(0,1.615)
  round 0.305 smd: A5(-2.266,0) A68(-38.866,0) AA2(-0.975,10.804) AA4(-1.951,10.804) AA63(-35.427,10.719) AA64(-36.077,10.719) AA65(-36.727,10.719) AA66(-37.377,10.719) AA67(-38.028,10.719) AA68(-38.678,10.719) AA69(-39.328,10.719) AA70(-39.978,10.719) AA71(-40.629,10.719) AB4(-1.951,11.467) AB6(-2.729,11.181) AB7(-3.379,11.181) AB8(-4.029,11.181) AB9(-4.679,11.181) AB10(-5.33,11.181) AB11(-5.98,11.181) AB12(-6.63,11.181) AB13(-7.28,11.181) AB15(-8.126,11.305) AB16(-8.776,11.305) AB17(-9.426,11.305) AB18(-10.077,11.305) AB19(-10.727,11.305) AB20(-11.377,11.305) AB21(-12.027,11.305) AB62(-34.958,11.176) AC3(-1.626,12.13) AC63(-35.427,11.633) AC64(-36.077,11.633) AC65(-36.727,11.633) AC66(-37.377,11.633) AC67(-38.028,11.633) AC68(-38.678,11.633) AC69(-39.328,11.633) AC70(-39.978,11.633) AC71(-40.629,11.633) AD4(-1.951,12.792) AD6(-2.729,12.248) AD7(-3.379,12.248) AD8(-4.029,12.248) AD9(-4.679,12.248) AD10(-5.33,12.248) AD11(-5.98,12.248) AD12(-6.63,12.248) AD13(-7.28,12.248) AD15(-8.126,12.143) AD16(-8.776,12.143) AD17(-9.426,12.143) AD18(-10.077,12.143) AD19(-10.727,12.143) AD20(-11.377,12.143) AD21(-12.027,12.143) AD62(-34.958,12.09) AE62(-34.958,13.005) AE63(-35.427,12.547) AE64(-36.077,12.547) AE65(-36.727,12.547) AE66(-37.377,12.547) AE67(-38.028,12.547) AE68(-38.678,12.547) AE69(-39.328,12.547) AF2(-0.975,13.455) AF4(-1.951,13.455) AF6(-2.729,13.315) AF7(-3.379,13.315) AF8(-4.029,13.315) AF9(-4.679,13.315) AF10(-5.33,13.315) AF11(-5.98,13.315) AF12(-6.63,13.315) AF13(-7.28,13.315) AF15(-8.126,12.982) AF16(-8.776,12.982) AF17(-9.426,12.982) AF18(-10.077,12.982) AF19(-10.727,12.982) AF20(-11.377,12.982) AF21(-12.027,12.982) AF63(-35.427,13.462) AF64(-36.077,13.462) AF65(-36.727,13.462) AF66(-37.377,13.462) AF67(-38.028,13.462) AF68(-38.678,13.253) AF69(-39.328,13.253) AG4(-1.951,14.118) AG15(-8.126,13.82) AG16(-8.776,13.82) AG17(-9.426,13.82) AG18(-10.077,13.82) AG19(-10.727,13.82) AG20(-11.377,13.82) AG21(-12.027,13.82) AG62(-34.958,13.919) AG69(-39.003,13.916) AH3(-1.626,14.781) AH6(-2.729,14.381) AH7(-3.379,14.381) AH8(-4.029,14.381) AH9(-4.679,14.381) AH10(-5.33,14.381) AH11(-5.98,14.381) AH12(-6.63,14.381) AH13(-7.28,14.381) AH63(-35.427,14.376) AH64(-36.077,14.376) AH65(-36.727,14.376) AH66(-37.377,14.376) AH67(-38.028,14.376) AJ4(-1.951,15.444) AJ15(-8.126,14.658) AJ16(-8.776,14.658) AJ17(-9.426,14.658) AJ18(-10.077,14.658) AJ19(-10.727,14.658) AJ20(-11.377,14.658) AJ21(-12.027,14.658) AJ62(-34.958,14.833) AK6(-2.729,15.321) AK7(-3.379,15.321) AK8(-4.029,15.321) AK9(-4.679,15.321) AK10(-5.33,15.321) AK11(-5.98,15.321) AK12(-6.63,15.321) AK13(-7.28,15.321) AK15(-8.126,15.496) AK16(-8.776,15.496) AK17(-9.426,15.496) AK18(-10.077,15.496) AK19(-10.727,15.496) AK20(-11.377,15.496) AK21(-12.027,15.496) AK22(-12.719,15.323) AK23(-13.633,15.323) AK25(-14.547,15.323) AK27(-15.462,15.323) AK28(-16.376,15.323) AK30(-17.291,15.323) AK32(-18.205,15.323) AK33(-19.119,15.323) AK35(-20.034,15.323) AK37(-20.948,15.323) AK38(-21.863,15.323) AK40(-22.777,15.323) AK42(-23.691,15.323) AK43(-24.606,15.323) AK45(-25.52,15.323) AK46(-26.435,15.323) AK48(-27.349,15.323) AK50(-28.263,15.323) AK52(-29.178,15.323) AK53(-30.092,15.323) AK55(-31.007,15.323) AK56(-31.921,15.323) AK58(-32.835,15.323) AK60(-33.75,15.323) AK62(-34.774,15.458) AK63(-35.427,15.291) AK64(-36.077,15.291) AK65(-36.727,15.291) AK66(-37.377,15.291) AK67(-38.028,15.291) AK68(-38.678,15.143) AK69(-39.653,15.143) AL2(-0.975,16.107) AL4(-1.951,16.107) AL23(-13.176,15.788) AL25(-14.09,15.788) AL27(-15.005,15.788) AL28(-15.919,15.788) AL30(-16.833,15.788) AL32(-17.748,15.788) AL33(-18.662,15.788) AL35(-19.577,15.788) AL37(-20.491,15.788) AL38(-21.405,15.788) AL40(-22.32,15.788) AL42(-23.234,15.788) AL43(-24.149,15.788) AL45(-25.063,15.788) AL46(-25.977,15.788) AL48(-26.892,15.788) AL50(-27.806,15.788) AL52(-28.721,15.788) AL53(-29.635,15.788) AL55(-30.549,15.788) AL56(-31.464,15.788) AL58(-32.378,15.788) AL60(-33.293,15.788) AL61(-34.207,15.788) AL63(-35.427,16.159) AL64(-36.077,16.159) AL65(-36.727,16.159) AL66(-37.377,16.159) AM4(-1.951,16.77) AM5(-2.66,16.261) AM7(-3.575,16.261) AM8(-4.489,16.261) AM10(-5.403,16.261) AM11(-6.318,16.261) AM13(-7.232,16.261) AM15(-8.147,16.261) AM16(-9.061,16.261) AM18(-9.975,16.261) AM20(-10.89,16.261) AM21(-11.804,16.261) AM22(-12.719,16.261) AM23(-13.633,16.261) AM25(-14.547,16.261) AM27(-15.462,16.261) AM28(-16.376,16.261) AM30(-17.291,16.261) AM32(-18.205,16.261) AM33(-19.119,16.261) AM35(-20.034,16.261) AM37(-20.948,16.261) AM38(-21.863,16.261) AM40(-22.777,16.261) AM42(-23.691,16.261) AM43(-24.606,16.261) AM45(-25.52,16.261) AM46(-26.435,16.261) AM48(-27.349,16.261) AM50(-28.263,16.261) AM52(-29.178,16.261) AM53(-30.092,16.261) AM55(-31.007,16.261) AM56(-31.921,16.261) AM58(-32.835,16.261) AM60(-33.75,16.261) AM61(-34.664,16.261) AM68(-38.353,16.37) AM69(-39.003,16.37) AN3(-1.626,17.433) AN5(-2.66,16.911) AN7(-3.575,16.911) AN8(-4.489,16.911) AN10(-5.403,16.911) AN11(-6.318,16.911) AN13(-7.232,16.911) AN15(-8.147,16.911) AN16(-9.061,16.911) AN18(-9.975,16.911) AN20(-10.89,16.911) AN21(-11.804,16.911) AN22(-12.719,16.911) AN23(-13.633,16.911) AN25(-14.547,16.911) AN27(-15.462,16.911) AN28(-16.376,16.911) AN30(-17.291,16.911) AN32(-18.205,16.911) AN33(-19.119,16.911) AN35(-20.034,16.911) AN37(-20.948,16.911) AN38(-21.863,16.911) AN40(-22.777,16.911) AN42(-23.691,16.911) AN43(-24.606,16.911) AN45(-25.52,16.911) AN46(-26.435,16.911) AN48(-27.349,16.911) AN50(-28.263,16.911) AN52(-29.178,16.911) AN53(-30.092,16.911) AN55(-31.007,16.911) AN56(-31.921,16.911) AN58(-32.835,16.911) AN60(-33.75,16.911) AN61(-34.664,16.911) AN63(-35.579,16.911) AN65(-36.493,16.911) AN66(-37.407,16.911) AN68(-38.678,17.033) AN69(-39.328,17.033) AP4(-1.951,18.096) AP5(-2.66,17.561) AP7(-3.575,17.561) AP8(-4.489,17.561) AP10(-5.403,17.561) AP11(-6.318,17.561) AP13(-7.232,17.561) AP15(-8.147,17.561) AP16(-9.061,17.561) AP18(-9.975,17.561) AP20(-10.89,17.561) AP21(-11.804,17.561) AP22(-12.719,17.561) AP23(-13.633,17.561) AP25(-14.547,17.561) AP27(-15.462,17.561) AP28(-16.376,17.561) AP30(-17.291,17.561) AP32(-18.205,17.561) AP33(-19.119,17.561) AP35(-20.034,17.561) AP37(-20.948,17.561) AP38(-21.863,17.561) AP40(-22.777,17.561) AP42(-23.691,17.561) AP43(-24.606,17.561) AP45(-25.52,17.561) AP46(-26.435,17.561) AP48(-27.349,17.561) AP50(-28.263,17.561) AP52(-29.178,17.561) AP53(-30.092,17.561) AP55(-31.007,17.561) AP56(-31.921,17.561) AP58(-32.835,17.561) AP60(-33.75,17.561) AP61(-34.664,17.561) AP63(-35.579,17.561) AP65(-36.493,17.561) AP66(-37.407,17.561) AP68(-38.353,17.646) AP70(-39.572,17.646) AR5(-2.66,18.211) AR7(-3.575,18.211) AR8(-4.489,18.211) AR10(-5.403,18.211) AR11(-6.318,18.211) AR13(-7.232,18.211) AR15(-8.147,18.211) AR16(-9.061,18.211) AR18(-9.975,18.211) AR20(-10.89,18.211) AR21(-11.804,18.211) AR22(-12.719,18.211) AR23(-13.633,18.211) AR25(-14.547,18.211) AR27(-15.462,18.211) AR28(-16.376,18.211) AR30(-17.291,18.211) AR32(-18.205,18.211) AR33(-19.119,18.211) AR35(-20.034,18.211) AR37(-20.948,18.211) AR38(-21.863,18.211) AR40(-22.777,18.211) AR42(-23.691,18.211) AR43(-24.606,18.211) AR45(-25.52,18.211) AR46(-26.435,18.211) AR48(-27.349,18.211) AR50(-28.263,18.211) AR52(-29.178,18.211) AR53(-30.092,18.211) AR55(-31.007,18.211) AR56(-31.921,18.211) AR58(-32.835,18.211) AR60(-33.75,18.211) AR61(-34.664,18.211) AR63(-35.579,18.211) AR65(-36.493,18.211) AR66(-37.407,18.211) AR68(-38.678,18.26) AR69(-39.328,18.26) AT2(-0.975,18.759) AT4(-1.951,18.759) AT5(-2.66,18.862) AT7(-3.575,18.862) AT8(-4.489,18.862) AT10(-5.403,18.862) AT11(-6.318,18.862) AT13(-7.232,18.862) AT15(-8.147,18.862) AT16(-9.061,18.862) AT18(-9.975,18.862) AT20(-10.89,18.862) AT21(-11.804,18.862) AT22(-12.719,18.862) AT23(-13.633,18.862) AT25(-14.547,18.862) AT27(-15.462,18.862) AT28(-16.376,18.862) AT30(-17.291,18.862) AT32(-18.205,18.862) AT33(-19.119,18.862) AT35(-20.034,18.862) AT37(-20.948,18.862) AT38(-21.863,18.862) AT40(-22.777,18.862) AT42(-23.691,18.862) AT43(-24.606,18.862) AT45(-25.52,18.862) AT46(-26.435,18.862) AT48(-27.349,18.862) AT50(-28.263,18.862) AT52(-29.178,18.862) AT53(-30.092,18.862) AT55(-31.007,18.862) AT56(-31.921,18.862) AT58(-32.835,18.862) AT60(-33.75,18.862) AT61(-34.664,18.862) AT63(-35.579,18.862) AT65(-36.493,18.862) AT66(-37.407,18.862) AT68(-38.353,18.823) AT69(-39.003,18.823) AU4(-1.951,19.422) AU5(-2.66,19.512) AU7(-3.575,19.512) AU8(-4.489,19.512) AU10(-5.403,19.512) AU11(-6.318,19.512) AU13(-7.232,19.512) AU15(-8.147,19.512) AU16(-9.061,19.512) AU18(-9.975,19.512) AU20(-10.89,19.512) AU21(-11.804,19.512) AU22(-12.719,19.512) AU23(-13.633,19.512) AU25(-14.547,19.512) AU27(-15.462,19.512) AU28(-16.376,19.512) AU30(-17.291,19.512) AU32(-18.205,19.512) AU33(-19.119,19.512) AU35(-20.034,19.512) AU37(-20.948,19.512) AU38(-21.863,19.512) AU40(-22.777,19.512) AU42(-23.691,19.512) AU43(-24.606,19.512) AU45(-25.52,19.512) AU46(-26.435,19.512) AU48(-27.349,19.512) AU50(-28.263,19.512) AU52(-29.178,19.512) AU53(-30.092,19.512) AU55(-31.007,19.512) AU56(-31.921,19.512) AU58(-32.835,19.512) AU60(-33.75,19.512) AU61(-34.664,19.512) AU63(-35.579,19.512) AU65(-36.493,19.512) AU66(-37.407,19.512) AV3(-1.626,20.113) AV68(-38.343,20.026) AV69(-39.328,20.215) AV70(-39.978,20.215) AW1(0,20.866) AW5(-2.534,20.226) AW6(-3.184,20.353) AW7(-3.75,20.678) AW8(-4.328,20.353) AW9(-4.898,20.678) AW10(-5.561,20.353) AW11(-6.171,20.678) AW12(-6.749,20.353) AW13(-7.319,20.678) AW14(-7.982,20.353) AW15(-8.592,20.678) AW16(-9.17,20.353) AW17(-9.74,20.678) AW18(-10.403,20.353) AW20(-11.012,20.678) AW21(-11.59,20.353) AW22(-12.16,20.678) AW23(-12.849,20.353) AW25(-13.486,20.678) AW26(-14.05,20.353) AW27(-14.713,20.678) AW28(-15.326,20.353) AW29(-15.94,20.678) AW30(-16.603,20.353) AW31(-17.167,20.678) AW32(-17.83,20.353) AW33(-18.467,20.678) AW34(-19.031,20.353) AW35(-19.694,20.678) AW36(-20.307,20.353) AW37(-20.921,20.678) AW38(-21.584,20.353) AW39(-22.148,20.678) AW41(-22.785,20.353) AW42(-23.423,20.678) AW43(-23.986,20.353) AW44(-24.649,20.678) AW45(-25.263,20.353) AW46(-25.876,20.678) AW47(-26.477,20.353) AW48(-27.041,20.678) AW49(-27.669,20.353) AW50(-28.298,20.678) AW51(-28.862,20.353) AW52(-29.463,20.678) AW53(-30.076,20.353) AW54(-30.69,20.678) AW55(-31.352,20.353) AW56(-31.916,20.678) AW57(-32.554,20.353) AW59(-33.191,20.678) AW60(-33.755,20.353) AW61(-34.418,20.678) AW62(-35.032,20.353) AW63(-35.645,20.678) AW64(-36.308,20.353) AW65(-36.872,20.678) AW66(-37.407,20.215) AW67(-38.332,20.685) AW68(-38.936,20.936) AW69(-39.581,20.85) AW70(-39.999,21.349) AW71(-40.629,20.866) AY2(-0.629,21.348) AY3(-1.286,21.342) AY4(-2.04,21.357) AY5(-2.649,21.003) AY8(-4.328,21.003) AY12(-6.749,21.003) AY16(-9.17,21.003) AY21(-11.59,21.003) AY26(-14.05,21.003) AY27(-14.713,21.328) AY29(-15.94,21.328) AY30(-16.603,21.003) AY34(-19.031,21.003) AY35(-19.694,21.328) AY37(-20.921,21.328) AY38(-21.584,21.003) AY43(-23.986,21.003) AY44(-24.649,21.328) AY46(-25.876,21.328) AY47(-26.477,21.003) AY51(-28.862,21.003) AY52(-29.463,21.328) AY54(-30.69,21.328) AY55(-31.352,21.003) AY60(-33.755,21.003) AY61(-34.418,21.328) AY63(-35.645,21.328) AY64(-36.308,21.003) AY66(-37.535,21.003) AY68(-38.85,21.581) B5(-2.266,0.65) B6(-2.847,0.975) B10(-5.325,0.975) B14(-7.803,0.975) B18(-10.281,0.975) B22(-12.759,0.975) B26(-15.237,0.975) B30(-17.715,0.975) B34(-20.194,0.975) B39(-22.672,0.975) B44(-25.15,0.975) B48(-27.628,0.975) B53(-30.106,0.975) B58(-32.584,0.975) B62(-35.062,0.975) B66(-37.54,0.975) B69(-39.349,0.63) BA3(-1.279,21.999) BA5(-2.599,21.94) BA8(-4.328,21.653) BA12(-6.749,21.653) BA16(-9.17,21.653) BA21(-11.59,21.653) BA23(-12.849,21.572) BA28(-15.326,21.572) BA32(-17.83,21.572) BA36(-20.307,21.572) BA41(-22.785,21.572) BA45(-25.263,21.572) BA49(-27.669,21.653) BA53(-30.076,21.572) BA57(-32.554,21.572) BA62(-35.032,21.572) BA68(-39.349,21.999) BB4(-1.763,22.628) BB68(-38.866,22.628) C4(-1.699,0.978) C5(-2.266,1.3) C7(-3.523,1.3) C8(-4.086,0.975) C9(-4.65,1.3) C11(-6.001,1.3) C12(-6.564,0.975) C13(-7.128,1.3) C15(-8.479,1.3) C16(-9.042,0.975) C17(-9.606,1.3) C19(-10.957,1.3) C20(-11.52,0.975) C21(-12.084,1.3) C23(-13.435,1.3) C24(-13.998,0.975) C25(-14.562,1.3) C27(-15.913,1.3) C28(-16.476,0.975) C29(-17.04,1.3) C31(-18.391,1.3) C32(-18.954,0.975) C33(-19.518,1.3) C36(-20.869,1.3) C37(-21.433,0.975) C38(-21.996,1.3) C40(-23.347,1.3) C41(-23.911,0.975) C42(-24.474,1.3) C45(-25.825,1.3) C46(-26.389,0.975) C47(-26.952,1.3) C50(-28.303,1.3) C51(-28.867,0.975) C52(-29.43,1.3) C54(-30.781,1.3) C55(-31.345,0.975) C56(-31.908,1.3) C59(-33.259,1.3) C60(-33.823,0.975) C61(-34.386,1.3) C63(-35.737,1.3) C64(-36.301,0.975) C65(-36.864,1.3) C67(-38.799,1.015) C68(-38.936,1.693) C70(-39.999,1.28) D3(-0.975,1.706) D4(-1.624,1.646) D5(-2.224,1.951) D6(-2.873,1.991) D7(-3.523,1.951) D8(-4.086,1.626) D9(-4.65,1.951) D10(-5.325,1.991) D11(-6.001,1.951) D12(-6.564,1.626) D13(-7.128,1.951) D14(-7.803,1.991) D15(-8.479,1.951) D16(-9.042,1.626) D17(-9.606,1.951) D18(-10.281,1.991) D19(-10.957,1.951) D20(-11.52,1.626) D21(-12.084,1.951) D22(-12.759,1.991) D23(-13.435,1.951) D24(-13.998,1.626) D25(-14.562,1.951) D26(-15.237,1.991) D27(-15.913,1.951) D28(-16.476,1.626) D29(-17.04,1.951) D30(-17.715,1.991) D31(-18.391,1.951) D32(-18.954,1.626) D33(-19.518,1.951) D34(-20.194,1.991) D36(-20.869,1.951) D37(-21.433,1.626) D38(-21.996,1.951) D39(-22.672,1.991) D40(-23.347,1.951) D41(-23.911,1.626) D42(-24.474,1.951) D44(-25.15,1.991) D45(-25.825,1.951) D46(-26.389,1.626) D47(-26.952,1.951) D48(-27.628,1.991) D50(-28.303,1.951) D51(-28.867,1.626) D52(-29.43,1.951) D53(-30.106,1.991) D54(-30.781,1.951) D55(-31.345,1.626) D56(-31.908,1.951) D58(-32.584,1.991) D59(-33.259,1.951) D60(-33.823,1.626) D61(-34.386,1.951) D62(-35.062,1.991) D63(-35.737,1.951) D64(-36.301,1.626) D65(-36.864,1.951) D66(-37.54,1.991) D67(-38.213,1.3) D68(-39.582,1.779) D69(-38.876,2.343) D71(-40.629,1.763) E1(0,2.274) E2(-0.65,2.274) E3(-1.3,2.274) E5(-2.66,2.723) E6(-3.575,2.723) E8(-4.489,2.723) E10(-5.403,2.723) E11(-6.318,2.723) E13(-7.232,2.723) E15(-8.147,2.723) E16(-9.061,2.723) E18(-9.975,2.723) E20(-10.89,2.723) E21(-11.804,2.723) E22(-12.719,2.723) E23(-13.633,2.723) E25(-14.547,2.723) E27(-15.462,2.723) E28(-16.376,2.723) E30(-17.291,2.723) E32(-18.205,2.723) E33(-19.119,2.723) E35(-20.034,2.723) E37(-20.948,2.723) E38(-21.863,2.723) E40(-22.777,2.723) E42(-23.691,2.723) E43(-24.606,2.723) E45(-25.52,2.723) E46(-26.435,2.723) E48(-27.349,2.723) E50(-28.263,2.723) E52(-29.178,2.723) E53(-30.092,2.723) E55(-31.007,2.723) E56(-31.921,2.723) E58(-32.835,2.723) E60(-33.75,2.723) E61(-34.664,2.723) E63(-35.629,2.659) E65(-36.645,2.659) E66(-37.661,2.659) E68(-38.213,1.951) F2(-0.975,2.848) F4(-1.951,2.848) F5(-2.66,3.373) F6(-3.575,3.373) F8(-4.489,3.373) F10(-5.403,3.373) F11(-6.318,3.373) F13(-7.232,3.373) F15(-8.147,3.373) F16(-9.061,3.373) F18(-9.975,3.373) F20(-10.89,3.373) F21(-11.804,3.373) F22(-12.719,3.373) F23(-13.633,3.373) F25(-14.547,3.373) F27(-15.462,3.373) F28(-16.376,3.373) F30(-17.291,3.373) F32(-18.205,3.373) F33(-19.119,3.373) F35(-20.034,3.373) F37(-20.948,3.373) F38(-21.863,3.373) F40(-22.777,3.373) F42(-23.691,3.373) F43(-24.606,3.373) F45(-25.52,3.373) F46(-26.435,3.373) F48(-27.349,3.373) F50(-28.263,3.373) F52(-29.178,3.373) F53(-30.092,3.373) F55(-31.007,3.373) F56(-31.921,3.373) F58(-32.835,3.373) F60(-33.75,3.373) F61(-34.664,3.373) F63(-35.629,3.31) F65(-36.645,3.31) F66(-37.661,3.31) F68(-38.876,2.994) G4(-1.951,3.511) G5(-2.66,4.023) G6(-3.575,4.023) G8(-4.489,4.023) G10(-5.403,4.023) G11(-6.318,4.023) G13(-7.232,4.023) G15(-8.147,4.023) G16(-9.061,4.023) G18(-9.975,4.023) G20(-10.89,4.023) G21(-11.804,4.023) G22(-12.719,4.023) G23(-13.633,4.023) G25(-14.547,4.023) G27(-15.462,4.023) G28(-16.376,4.023) G30(-17.291,4.023) G32(-18.205,4.023) G33(-19.119,4.023) G35(-20.034,4.023) G37(-20.948,4.023) G38(-21.863,4.023) G40(-22.777,4.023) G42(-23.691,4.023) G43(-24.606,4.023) G45(-25.52,4.023) G46(-26.435,4.023) G48(-27.349,4.023) G50(-28.263,4.023) G52(-29.178,4.023) G53(-30.092,4.023) G55(-31.007,4.023) G56(-31.921,4.023) G58(-32.835,4.023) G60(-33.75,4.023) G61(-34.664,4.023) G63(-35.629,3.96) G65(-36.645,3.96) G66(-37.661,3.96) G68(-38.678,3.655) G69(-39.328,3.655) H3(-1.626,4.174) H5(-2.66,4.674) H6(-3.575,4.674) H8(-4.489,4.674) H10(-5.403,4.674) H11(-6.318,4.674) H13(-7.232,4.674) H15(-8.147,4.674) H16(-9.061,4.674) H18(-9.975,4.674) H20(-10.89,4.674) H21(-11.804,4.674) H63(-35.629,4.61) H65(-36.645,4.61) H66(-37.661,4.61) H69(-39.003,4.218) J4(-1.951,4.837) J5(-2.66,5.324) J6(-3.575,5.324) J8(-4.489,5.324) J10(-5.403,5.324) J11(-6.318,5.324) J13(-7.232,5.324) J22(-13.176,4.488) J23(-14.09,4.488) J25(-15.005,4.488) J27(-15.919,4.488) J28(-16.833,4.488) J30(-17.748,4.488) J32(-18.662,4.488) J33(-19.577,4.488) J35(-20.491,4.488) J37(-21.405,4.488) J38(-22.32,4.488) J40(-23.234,4.488) J42(-24.149,4.488) J43(-25.063,4.488) J45(-25.977,4.488) J46(-26.892,4.488) J48(-27.806,4.488) J50(-28.721,4.488) J52(-29.635,4.488) J53(-30.549,4.488) J55(-31.464,4.488) J56(-32.378,4.488) J58(-33.293,4.488) J60(-34.207,4.488) J68(-38.676,4.794) K15(-8.126,5.438) K16(-8.776,5.438) K17(-9.426,5.438) K18(-10.077,5.438) K19(-10.727,5.438) K20(-11.377,5.438) K21(-12.027,5.438) K22(-12.719,4.952) K23(-13.633,4.952) K25(-14.547,4.952) K27(-15.462,4.952) K28(-16.376,4.952) K30(-17.291,4.952) K32(-18.205,4.952) K33(-19.119,4.952) K35(-20.034,4.952) K37(-20.948,4.952) K38(-21.863,4.952) K40(-22.777,4.952) K42(-23.691,4.952) K43(-24.606,4.952) K45(-25.52,4.952) K46(-26.435,4.952) K48(-27.349,4.952) K50(-28.263,4.952) K52(-29.178,4.952) K53(-30.092,4.952) K55(-31.007,4.952) K56(-31.921,4.952) K58(-32.835,4.952) K60(-33.75,4.952) K61(-34.664,4.952) K63(-35.447,5.26) K64(-36.097,5.26) K65(-36.747,5.26) K66(-37.398,5.26) K67(-38.048,5.26) K68(-38.666,5.468) K70(-39.653,5.57) L2(-0.975,5.5) L4(-1.951,5.5) L6(-2.729,5.974) L7(-3.379,5.974) L8(-4.029,5.974) L9(-4.679,5.974) L10(-5.33,5.974) L11(-5.98,5.974) L12(-6.63,5.974) L13(-7.28,5.974) L15(-8.126,6.276) L16(-8.776,6.276) L17(-9.426,6.276) L18(-10.077,6.276) L19(-10.727,6.276) L20(-11.377,6.276) L21(-12.027,6.276) L62(-34.958,5.689) L63(-35.427,6.147) L64(-36.077,6.147) L65(-36.727,6.147) L66(-37.377,6.147) L67(-38.028,6.147) L68(-38.678,6.147) L69(-39.328,6.147) L70(-39.978,6.147) L71(-40.629,6.147) M4(-1.951,6.163) M62(-34.958,6.604) N3(-1.626,6.826) N6(-2.729,6.914) N7(-3.379,6.914) N8(-4.029,6.914) N9(-4.679,6.914) N10(-5.33,6.914) N11(-5.98,6.914) N12(-6.63,6.914) N13(-7.28,6.914) N15(-8.126,7.114) N16(-8.776,7.114) N17(-9.426,7.114) N18(-10.077,7.114) N19(-10.727,7.114) N20(-11.377,7.114) N21(-12.027,7.114) N63(-35.427,7.061) N64(-36.077,7.061) N65(-36.727,7.061) N66(-37.377,7.061) N67(-38.028,7.061) N68(-38.678,7.061) N69(-39.328,7.061) N70(-39.978,7.061) N71(-40.629,7.061) P4(-1.951,7.489) P15(-8.126,7.952) P16(-8.776,7.952) P17(-9.426,7.952) P18(-10.077,7.952) P19(-10.727,7.952) P20(-11.377,7.952) P21(-12.027,7.952) P62(-34.958,7.518) R6(-2.729,7.981) R7(-3.379,7.981) R8(-4.029,7.981) R9(-4.679,7.981) R10(-5.33,7.981) R11(-5.98,7.981) R12(-6.63,7.981) R13(-7.28,7.981) R63(-35.427,7.975) R64(-36.077,7.975) R65(-36.727,7.975) R66(-37.377,7.975) R67(-38.028,7.975) R68(-38.678,7.975) R69(-39.328,7.975) R70(-39.978,7.975) R71(-40.629,7.975) T2(-0.975,8.152) T4(-1.951,8.152) T15(-8.126,8.791) T16(-8.776,8.791) T17(-9.426,8.791) T18(-10.077,8.791) T19(-10.727,8.791) T20(-11.377,8.791) T21(-12.027,8.791) T62(-34.958,8.433) U4(-1.951,8.815) U6(-2.729,9.047) U7(-3.379,9.047) U8(-4.029,9.047) U9(-4.679,9.047) U10(-5.33,9.047) U11(-5.98,9.047) U12(-6.63,9.047) U13(-7.28,9.047) U63(-35.427,8.89) U64(-36.077,8.89) U65(-36.727,8.89) U66(-37.377,8.89) U67(-38.028,8.89) U68(-38.678,8.89) U69(-39.328,8.89) U70(-39.978,8.89) U71(-40.629,8.89) V3(-1.626,9.478) V15(-8.126,9.629) V16(-8.776,9.629) V17(-9.426,9.629) V18(-10.077,9.629) V19(-10.727,9.629) V20(-11.377,9.629) V21(-12.027,9.629) V62(-34.958,9.347) W4(-1.951,10.141) W6(-2.729,10.114) W7(-3.379,10.114) W8(-4.029,10.114) W9(-4.679,10.114) W10(-5.33,10.114) W11(-5.98,10.114) W12(-6.63,10.114) W13(-7.28,10.114) W63(-35.427,9.804) W64(-36.077,9.804) W65(-36.727,9.804) W66(-37.377,9.804) W67(-38.028,9.804) W68(-38.678,9.804) W69(-39.328,9.804) W70(-39.978,9.804) W71(-40.629,9.804) Y15(-8.126,10.467) Y16(-8.776,10.467) Y17(-9.426,10.467) Y18(-10.077,10.467) Y19(-10.727,10.467) Y20(-11.377,10.467) Y21(-12.027,10.467) Y62(-34.958,10.261)
  oval 0.254x0.343 smd: A6(-2.847,0.325) A7(-3.523,0) A9(-4.65,0) A10(-5.325,0.325) A11(-6.001,0) A13(-7.128,0) A14(-7.803,0.325) A15(-8.479,0) A17(-9.606,0) A18(-10.281,0.325) A19(-10.957,0) A21(-12.084,0) A22(-12.759,0.325) A23(-13.435,0) A25(-14.562,0) A26(-15.237,0.325) A27(-15.913,0) A29(-17.04,0) A30(-17.715,0.325) A31(-18.391,0) A33(-19.518,0) A34(-20.194,0.325) A36(-20.869,0) A38(-21.996,0) A39(-22.672,0.325) A40(-23.347,0) A42(-24.474,0) A44(-25.15,0.325) A45(-25.825,0) A47(-26.952,0) A48(-27.628,0.325) A50(-28.303,0) A52(-29.43,0) A53(-30.106,0.325) A54(-30.781,0) A56(-31.908,0) A58(-32.584,0.325) A59(-33.259,0) A61(-34.386,0) A62(-35.062,0.325) A63(-35.737,0) A65(-36.864,0) A66(-37.54,0.325) A67(-38.215,0) AY7(-3.763,21.328) AY9(-4.898,21.328) AY11(-6.184,21.328) AY13(-7.319,21.328) AY15(-8.604,21.328) AY17(-9.74,21.328) AY20(-11.025,21.328) AY22(-12.16,21.328) AY25(-13.486,21.328) AY31(-17.167,21.328) AY33(-18.467,21.328) AY39(-22.148,21.328) AY42(-23.423,21.328) AY48(-27.103,21.328) AY50(-28.236,21.328) AY56(-31.916,21.328) AY59(-33.191,21.328) AY65(-36.872,21.328) AY67(-38.216,21.328) B7(-3.523,0.65) B9(-4.65,0.65) B11(-6.001,0.65) B13(-7.128,0.65) B15(-8.479,0.65) B17(-9.606,0.65) B19(-10.957,0.65) B21(-12.084,0.65) B23(-13.435,0.65) B25(-14.562,0.65) B27(-15.913,0.65) B29(-17.04,0.65) B31(-18.391,0.65) B33(-19.518,0.65) B36(-20.869,0.65) B38(-21.996,0.65) B40(-23.347,0.65) B42(-24.474,0.65) B45(-25.825,0.65) B47(-26.952,0.65) B50(-28.303,0.65) B52(-29.43,0.65) B54(-30.781,0.65) B56(-31.908,0.65) B59(-33.259,0.65) B61(-34.386,0.65) B63(-35.737,0.65) B65(-36.864,0.65) B67(-38.215,0.65) BA4(-1.948,22.004) BA6(-3.141,21.572) BA7(-3.705,21.978) BA9(-4.898,21.978) BA10(-5.561,21.572) BA11(-6.125,21.978) BA13(-7.319,21.978) BA14(-7.982,21.572) BA15(-8.546,21.978) BA17(-9.74,21.978) BA18(-10.403,21.572) BA20(-10.966,21.978) BA22(-12.16,21.978) BA25(-13.486,21.978) BA26(-14.149,21.653) BA27(-14.812,21.978) BA29(-15.841,21.978) BA30(-16.504,21.653) BA31(-17.167,21.978) BA33(-18.467,21.978) BA34(-19.13,21.653) BA35(-19.793,21.978) BA37(-20.822,21.978) BA38(-21.485,21.653) BA39(-22.148,21.978) BA42(-23.423,21.978) BA43(-24.086,21.653) BA44(-24.748,21.978) BA46(-25.777,21.978) BA47(-26.44,21.653) BA48(-27.103,21.978) BA50(-28.236,21.978) BA51(-28.899,21.653) BA52(-29.562,21.978) BA54(-30.59,21.978) BA55(-31.253,21.653) BA56(-31.916,21.978) BA59(-33.191,21.978) BA60(-33.854,21.653) BA61(-34.517,21.978) BA63(-35.546,21.978) BA64(-36.209,21.653) BA65(-36.872,21.978) BA66(-37.535,21.653) BA67(-38.216,21.978) BB5(-2.529,22.628) BB6(-3.141,22.303) BB7(-3.705,22.628) BB9(-4.898,22.628) BB10(-5.561,22.303) BB11(-6.125,22.628) BB13(-7.319,22.628) BB14(-7.982,22.303) BB15(-8.546,22.628) BB17(-9.74,22.628) BB18(-10.403,22.303) BB20(-10.966,22.628) BB22(-12.16,22.628) BB23(-12.849,22.222) BB25(-13.486,22.628) BB26(-14.149,22.303) BB27(-14.812,22.628) BB29(-15.841,22.628) BB30(-16.504,22.303) BB31(-17.167,22.628) BB32(-17.83,22.222) BB33(-18.467,22.628) BB34(-19.13,22.303) BB35(-19.793,22.628) BB37(-20.822,22.628) BB38(-21.485,22.303) BB39(-22.148,22.628) BB41(-22.785,22.222) BB42(-23.423,22.628) BB43(-24.086,22.303) BB44(-24.748,22.628) BB46(-25.777,22.628) BB47(-26.44,22.303) BB48(-27.103,22.628) BB50(-28.236,22.628) BB51(-28.899,22.303) BB52(-29.562,22.628) BB54(-30.59,22.628) BB55(-31.253,22.303) BB56(-31.916,22.628) BB57(-32.554,22.222) BB59(-33.191,22.628) BB60(-33.854,22.303) BB61(-34.517,22.628) BB63(-35.546,22.628) BB64(-36.209,22.303) BB65(-36.872,22.628) BB66(-37.535,22.303) BB67(-38.216,22.628)
  oval 0.343x0.254 smd: AA1(-0.325,10.804) AB1(0,11.467) AB2(-0.65,11.467) AB3(-1.3,11.467) AC1(-0.325,12.13) AC2(-0.975,12.13) AD1(0,12.792) AD2(-0.65,12.792) AD3(-1.3,12.792) AF1(-0.325,13.455) AF70(-39.978,13.154) AF71(-40.629,13.154) AG1(0,14.118) AG2(-0.65,14.118) AG3(-1.3,14.118) AG70(-39.653,13.817) AG71(-40.303,13.817) AH1(-0.325,14.781) AH2(-0.975,14.781) AH68(-38.678,14.48) AH69(-39.328,14.48) AH70(-39.978,14.48) AH71(-40.629,14.48) AJ1(0,15.444) AJ2(-0.65,15.444) AJ3(-1.3,15.444) AK70(-40.303,15.143) AL1(-0.325,16.107) AL68(-38.678,15.806) AL69(-39.328,15.806) AL70(-39.978,15.806) AL71(-40.629,15.806) AM1(0,16.77) AM2(-0.65,16.77) AM3(-1.3,16.77) AM70(-39.653,16.469) AM71(-40.303,16.469) AN1(-0.325,17.433) AN2(-0.975,17.433) AN70(-39.978,17.132) AN71(-40.629,17.132) AP1(0,18.096) AP2(-0.65,18.096) AP3(-1.3,18.096) AR70(-39.978,18.16) AR71(-40.629,18.16) AT1(-0.325,18.759) AT70(-39.653,18.823) AT71(-40.303,18.823) AU1(0,19.422) AU2(-0.65,19.422) AU3(-1.3,19.422) AU68(-38.678,19.461) AU69(-39.328,19.486) AU70(-39.978,19.486) AU71(-40.629,19.486) AV1(0,20.142) AV2(-0.95,20.113) AV71(-40.629,20.215) AW2(-0.625,20.677) AW3(-1.275,20.677) E70(-39.978,2.305) E71(-40.629,2.413) F1(-0.325,2.848) F70(-39.526,2.994) F71(-40.176,2.931) G1(0,3.511) G2(-0.65,3.511) G3(-1.3,3.511) G70(-39.978,3.555) G71(-40.629,3.555) H1(-0.325,4.174) H2(-0.975,4.174) H70(-39.653,4.218) H71(-40.303,4.218) J1(0,4.837) J2(-0.65,4.837) J3(-1.3,4.837) J69(-39.328,4.881) J70(-39.978,4.881) J71(-40.629,4.881) K71(-40.303,5.57) L1(-0.325,5.5) M1(0,6.163) M2(-0.65,6.163) M3(-1.3,6.163) N1(-0.325,6.826) N2(-0.975,6.826) P1(0,7.489) P2(-0.65,7.489) P3(-1.3,7.489) T1(-0.325,8.152) U1(0,8.815) U2(-0.65,8.815) U3(-1.3,8.815) V1(-0.325,9.478) V2(-0.975,9.478) W1(0,10.141) W2(-0.65,10.141) W3(-1.3,10.141)
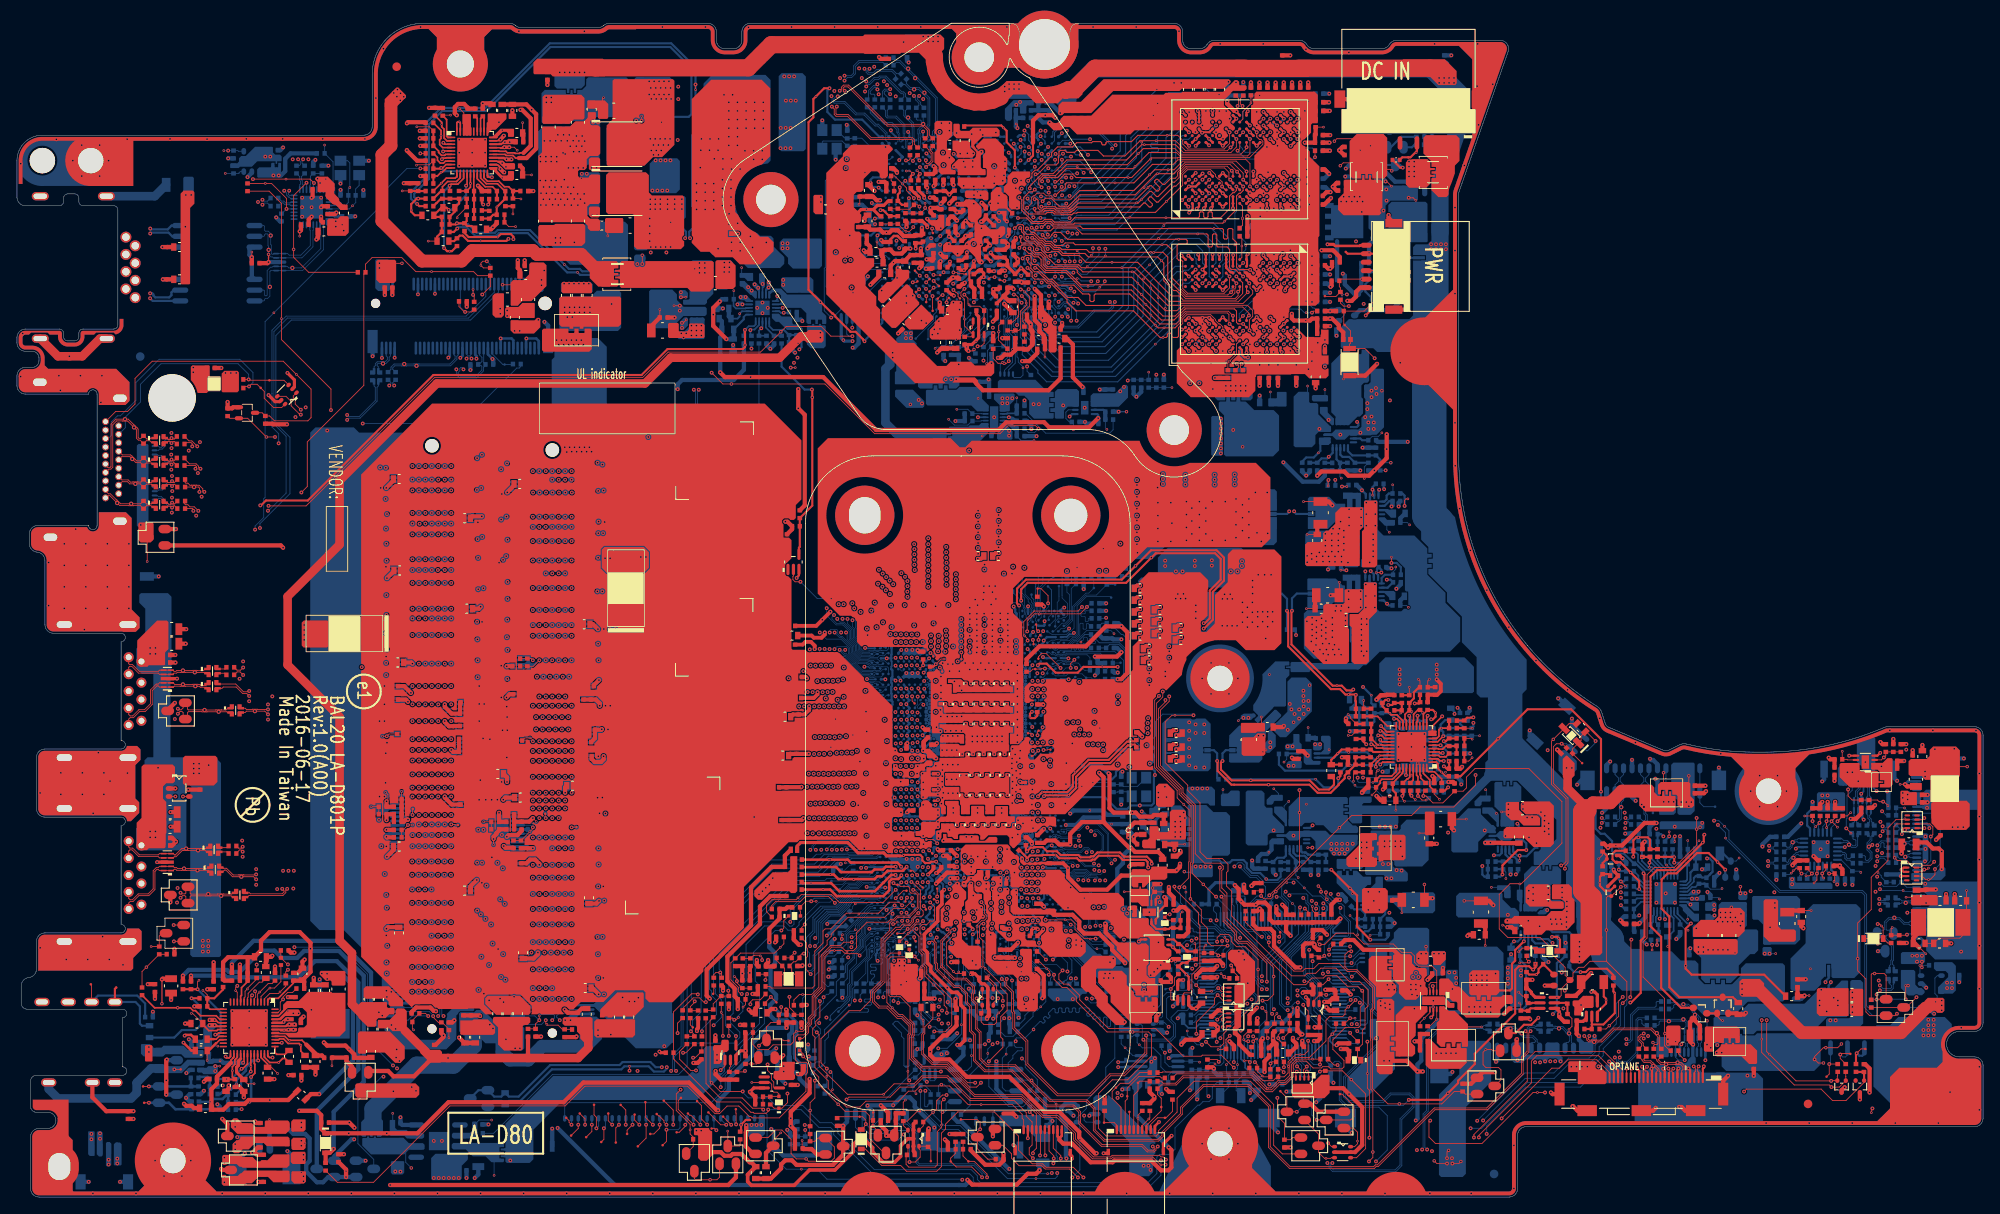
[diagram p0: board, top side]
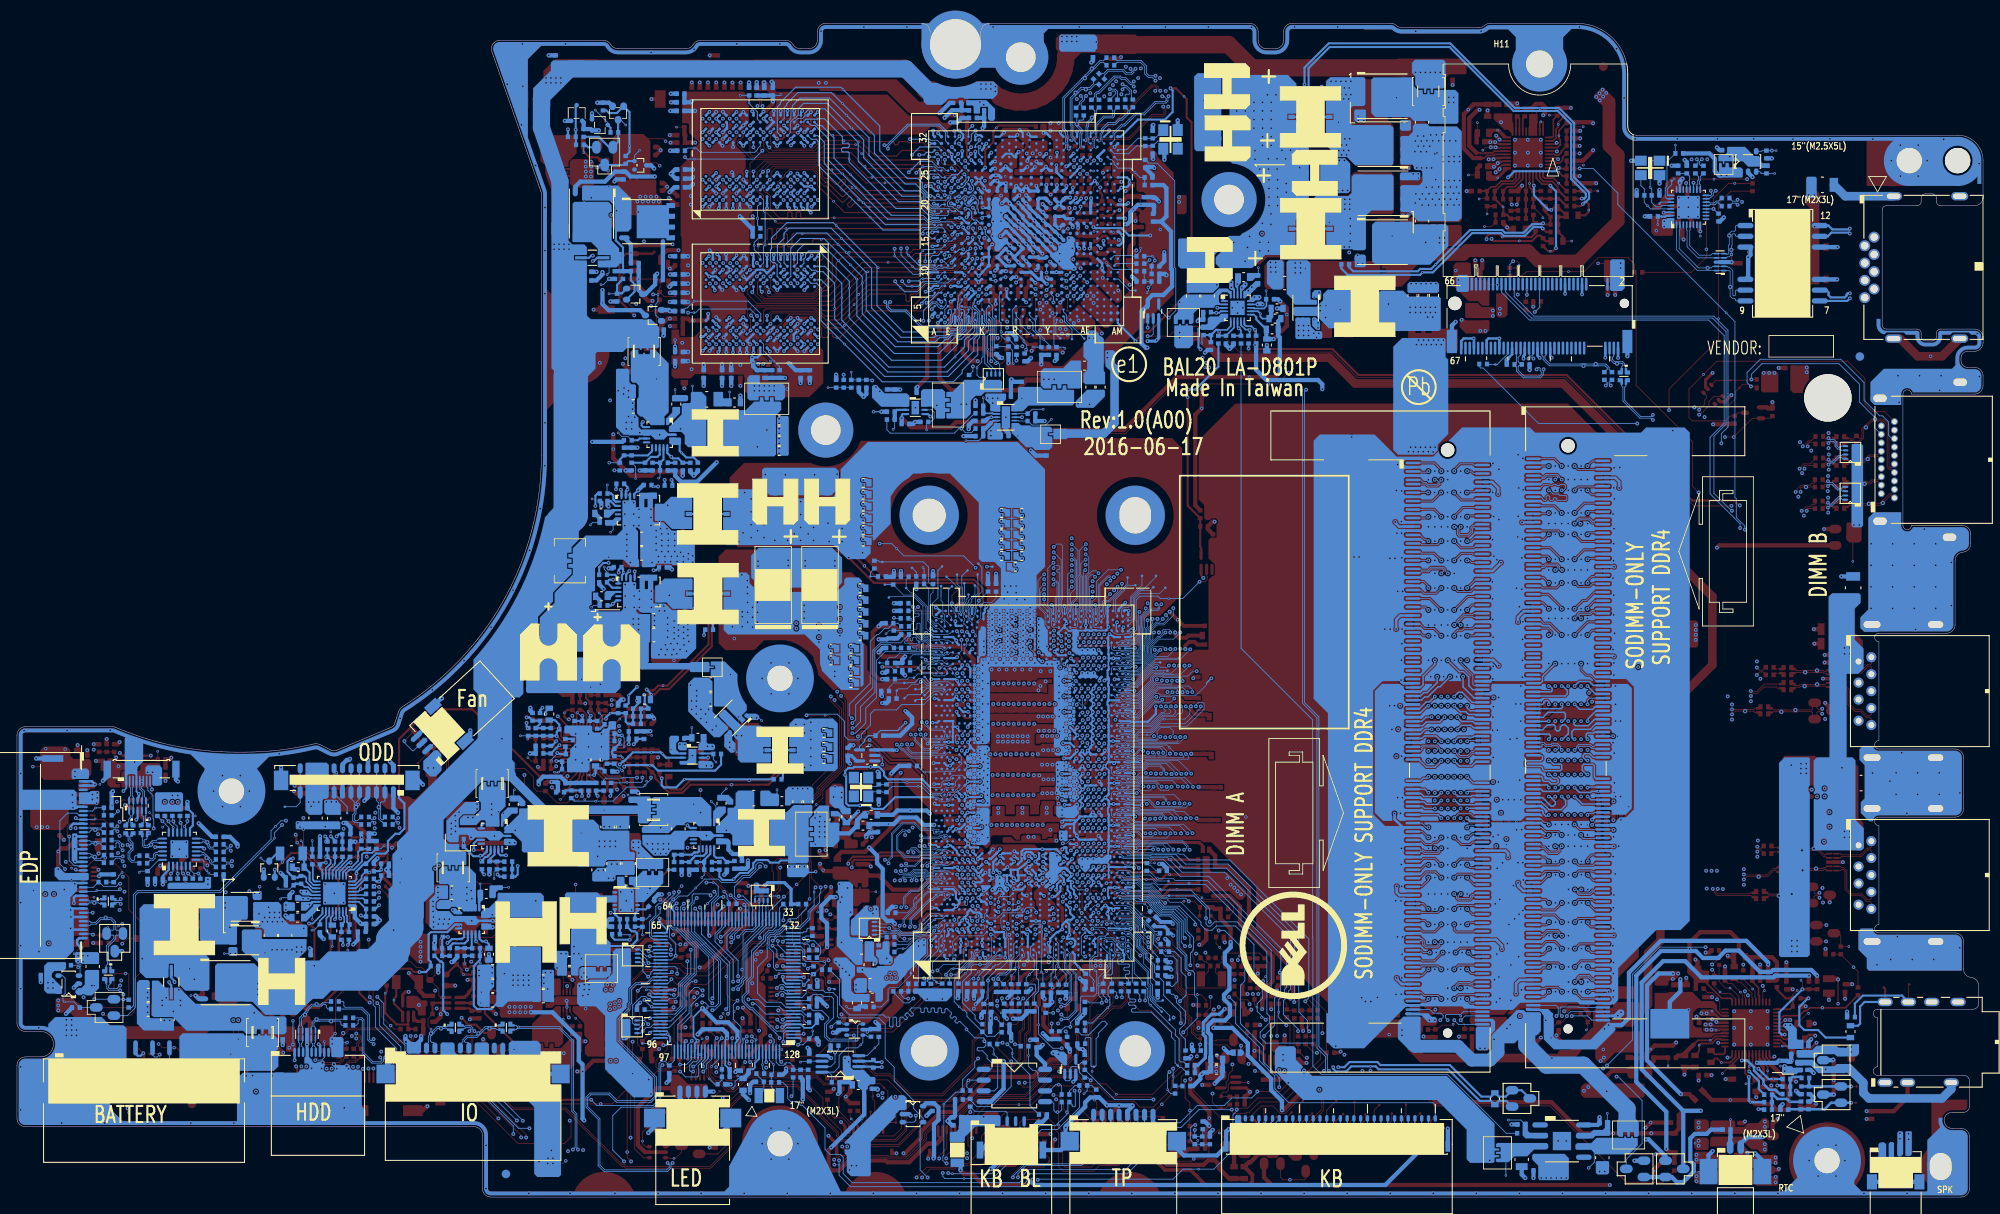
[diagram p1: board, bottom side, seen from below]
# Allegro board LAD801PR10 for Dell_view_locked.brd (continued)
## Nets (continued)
DDR_B_DQS0: JDIMM2.34 UC1.AH65
DDR_B_DQS1: JDIMM2.13 UC1.AG70
DDR_B_DQS2: JDIMM2.55 UC1.AR65
DDR_B_DQS3: JDIMM2.76 UC1.AR60
DDR_B_DQS4: JDIMM2.179 UC1.AR38
DDR_B_DQS5: JDIMM2.200 UC1.AR32
DDR_B_DQS6: JDIMM2.221 UC1.AR27
DDR_B_DQS7: JDIMM2.242 UC1.AR21
DDR_B_DQS#0: JDIMM2.32 UC1.AH66
DDR_B_DQS#1: JDIMM2.11 UC1.AG69
DDR_B_DQS#2: JDIMM2.53 UC1.AR66
DDR_B_DQS#3: JDIMM2.74 UC1.AR61
DDR_B_DQS#4: JDIMM2.177 UC1.AT38
DDR_B_DQS#5: JDIMM2.198 UC1.AT32
DDR_B_DQS#6: JDIMM2.219 UC1.AR25
DDR_B_DQS#7: JDIMM2.240 UC1.AR22
DDR_B_MA0: JDIMM2.144 UC1.BA46
DDR_B_MA1: JDIMM2.133 UC1.AY46
DDR_B_MA2: JDIMM2.132 UC1.AY47
DDR_B_MA3: JDIMM2.131 UC1.BB46
DDR_B_MA4: JDIMM2.128 UC1.BA47
DDR_B_MA5: JDIMM2.126 UC1.AY48
DDR_B_MA6: JDIMM2.127 UC1.BA48
DDR_B_MA7: JDIMM2.122 UC1.AP48
DDR_B_MA8: JDIMM2.125 UC1.BB48
DDR_B_MA9: JDIMM2.121 UC1.AP50
DDR_B_MA10: JDIMM2.146 UC1.AW46
DDR_B_MA11: JDIMM2.120 UC1.AN48
DDR_B_MA12: JDIMM2.119 UC1.AN50
DDR_B_MA13: JDIMM2.158 UC1.BA43
DDR_B_ODT0: JDIMM2.155 UC1.BA42
DDR_B_ODT1: JDIMM2.161 UC1.AW42
DDR_B_PAR: JDIMM2.143 UC1.AP43
DDR_B_RAS#: JDIMM2.152 UC1.AW44
DDR_B_WE#: JDIMM2.151 UC1.AY44
DDR_VTT_CNTL: UC1.AW67 UC2.2
DGPU_HOLD_RST#: RC48.1 UC1.P3 UV2.2
DGPU_PWR_EN: PR1116.1 RC49.2 RC50.2 RZ6.1 RZ7.1 RZ8.1 UC1.U1
DGPU_PWROK: PR1122.2 PR1403.1 RC116.2 UC1.C8
DIMM_CHA_SA0: JDIMM1.256 RD1.2 RD4.1
DIMM_CHA_SA1: JDIMM1.260 RD2.2 RD5.1
DIMM_CHA_SA2: JDIMM1.166 RD3.2 RD6.1
DIMM_CHB_SA0: JDIMM2.256 RD13.2 RD16.1
DIMM_CHB_SA1: JDIMM2.260 RD14.2 RD17.1
DIMM_CHB_SA2: JDIMM2.166 RD15.2 RD18.1
DMIC_CLK: L5.2 UA1.3
DMIC_CLK_EDP: CA9.1 JEDP1.28 L5.1 R56.1
DMIC_DATA: RA42.2 UA1.2
DMIC_DATA_EDP: JEDP1.29 RA42.1
DP_VSSR: UV1.AF19 UV1.AF20 UV1.AF23 UV1.AG14 UV1.AG23 UV1.AH14 UV1.AM14 UV1.AM16 UV1.AM18 UV1.AM20 UV1.AM22 UV1.AM24
DRAM_RST: RV36.1 UV12.J2 UV13.J2 UV14.J2 UV15.J2
DRAM_RST_G: CV97.1 RV37.1 RV38.1 UV1.L10
DRMOS_EN: PR655.2 PU603.12 PU605.12
E51_TX1: JWLAN1.36 RW6.2
EC_AGND: CE1.2 CE2.2 CE21.2 CE25.2 CE30.2 RE4.1 RE6.1 RE50.1 UE1.112
EC_MUTE#: RA8.2 RE24.1 RE28.1 UA1.47
EC_MUTE#_R: RE28.2 UE1.119
EC_SPI_CLK: RE33.2 UE1.32
EC_SPI_CS0#: RE38.1 UE1.27
EC_SPI_MISO: RE35.2 UE1.29
EC_SPI_MOSI: RE34.2 UE1.28
EC_WAKE#: RC100.1 UE1.35
EDP_AUX: C11.2 JEDP1.14
EDP_AUX#: C10.2 JEDP1.15
EDP_AUX_DN: C10.1 UC1.E45
EDP_AUX_DP: C11.1 UC1.F45
EDP_BKLT_CTRL: D3.2 R8.2 R9.2
EDP_COMP: RC4.2 UC1.E52
EDP_HPD: JEDP1.11 RP1.6 UC1.L10
EDP_TX0: C7.2 JEDP1.18
EDP_TX0#: C6.2 JEDP1.17
EDP_TX0_DN: C6.1 UC1.C47
EDP_TX0_DP: C7.1 UC1.C46
EDP_TX1: C9.2 JEDP1.21
EDP_TX1#: C8.2 JEDP1.20
EDP_TX1_DN: C8.1 UC1.D46
EDP_TX1_DP: C9.1 UC1.C45
EDP_VDD_EN: D4.2 UC1.U13
EDRAM_OPIO_RCOMP: RC121.1 UC1.H66
EMMC_RCOMP: RC8.1 UC1.AT1
EN_0.6VSP: PC203.1 PR202.2 PU200.7
EN_1.0V_VCCST_ON: CZ1.1 DZ5.2 RZ1.2 RZ9.1 UZ1.3
EN_1.2V: PC202.1 PR201.2 PU200.8
EN_1.8VALW: PC502.1 PR501.2 PR502.2 PU500.5
EN_2.5V: PC805.1 PR803.2 PU800.2
EN_3V: PR121.1 PU100.12
EN_5V: PR120.1 PU102.12
EN_+1.35VGPU: PC1404.1 PR1403.2 PR1404.1 PU1400.11
EN_+1VALW: PC304.1 PR301.2 PR302.1 PU300.11
ENABLE_VGA: PR1116.2 PU1100.8
ENLDO_3V5V: PR102.1 PR103.1 PU100.11 PU102.11
EOPIO_RCOMP: RC122.1 UC1.H65
FAN1_PWM: JFAN1.2 R50.1 UE1.47 ZT14.1(TP-1)
FAN1_TACH: CE28.1 D8.2 R55.2 RE13.1 UE1.40
FB_1.2V: PC214.1 PR204.1 PR207.1 PU200.6
FB_1.8VALW: PC503.2 PR504.1 PR505.1 PU500.6
FB_+1.35VGPU: PC1409.2 PR1410.1 PR1411.1 PU1400.14
FB_+1VALW: PC309.2 PR309.1 PR310.1 PU300.14
FB_GND: RV158.1 UV1.AD20
FB_IA: PR645.2 PR648.2 PR650.1 PU602.17
FB_VDDC: RV159.1 UV1.AC20
FB_VDDCI: TP67.1(TP-1) UV1.W1
FB_VSA: PR646.1 PR649.1 PR652.1 PU602.25
FCCM_GT: PR671.2 PU602.11
FCCM_IA: PR659.2 PU602.21
FCCM_VSA: PR679.2 PU602.29
FW_UPDATE: DX3.2 J3D1.8 RX10.2 RX13.2 UE1.34
FW_UPDATE_PCH: DX3.1 UC1.AP5
GPIO19_CTF: RV151.2 RV152.1 UV1.M2
GPIO28: RV21.2 UV1.R5
GPP_B23: RC39.1 UC1.AM7
GPP_C5: RC38.1 UC1.W1
GPU_PWR_LEVEL: RV260.1 UE1.21 UV1.T9
GT1N: PL605.2 PR673.1
GT1P: PL605.3 PR674.2
GT_SNUB1: PC678.1 PR676.2
GT_SW1: PL605.4 PR676.1 PU605.8
H_CATERR#: RC111.2 UC1.D63
H_CPU_SVIDALRT#: RC153.1 UC1.B63
H_CPUPWRGD: CC15.1 RC95.2 UC1.A68
H_CPUPWRGD_R: RC95.1 TP7.1(TP-1)
H_DRAMRST#: RD7.2 RD8.2 UC1.AT13
H_PROCHOT#: CE26.1 PC605.2 PQ2.6 PQ3.1 PQ721.1 PR678.1 PR777.1 RC113.2 RC117.1 UE2.4
H_PROCHOT#_R: RC117.2 UC1.C65
H_PROCHOT_EC: RE53.2 UE1.83 UE2.2
H_THERMTRIP#: RC112.2 TP14.1(TP-1) UC1.C63
H_VCCST_PWRGD: RC96.1 RC104.1 UC7.4
HDA_BIT_CLK: RC124.2 UC1.AY22
HDA_CODEC_BITCLK: CC16.1 RC124.1 UA1.6
HDA_CODEC_RST#: RC127.1 TP74.1(TP-1)
HDA_CODEC_SDIN0: RA7.2 UA1.8
HDA_CODEC_SDOUT: RC125.1 UA1.5
HDA_CODEC_SYNC: RC123.1 UA1.10
HDA_RST#: CC89.1 RC127.2 UC1.AW22
HDA_SDIN0: RA7.1 UC1.BA21
HDA_SDOUT: RC125.2 RC126.2 RC129.2 UC1.BB22
HDA_SYNC: RC123.2 UC1.BA22
HDD_DEVSLP: RS1.2 UC1.J1
HDD_DEVSLP_R: JHDD1.8 RS1.1
HDMI_CLK: CI2.1 UC1.G56
HDMI_CLK#: CI1.1 UC1.F56
HDMI_CLK#_R: CI1.2 LI1.2 RI2.1 RPI2.7
HDMI_CLK#_R_C: JHDMI1.12 LI1.1 RI2.2 RI3.1
HDMI_CLK_R: CI2.2 LI1.3 RI1.1 RPI2.8
HDMI_CLK_R_C: JHDMI1.10 LI1.4 RI1.2 RI3.2
HDMI_DATA0: CI4.1 UC1.G53
HDMI_DATA0#: CI3.1 UC1.F53
HDMI_DATA0#_R: CI3.2 LI2.2 RI4.1 RPI2.5
HDMI_DATA0#_R_C: JHDMI1.9 LI2.1 RI4.2 RI6.1
HDMI_DATA0_R: CI4.2 LI2.3 RI5.1 RPI2.6
HDMI_DATA0_R_C: JHDMI1.7 LI2.4 RI5.2 RI6.2
HDMI_DATA1: CI6.1 UC1.F58
HDMI_DATA1#: CI5.1 UC1.E58
HDMI_DATA1#_R: CI5.2 LI4.2 RI11.1 RPI1.5
HDMI_DATA1#_R_C: JHDMI1.6 LI4.1 RI11.2 RI12.1
HDMI_DATA1_R: CI6.2 LI4.3 RI10.1 RPI1.6
HDMI_DATA1_R_C: JHDMI1.4 LI4.4 RI10.2 RI12.2
HDMI_DATA2: CI8.1 UC1.F55
HDMI_DATA2#: CI7.1 UC1.E55
HDMI_DATA2#_R: CI7.2 LI3.2 RI8.1 RPI1.7
HDMI_DATA2#_R_C: JHDMI1.3 LI3.1 RI8.2 RI9.1
HDMI_DATA2_R: CI8.2 LI3.3 RI7.1 RPI1.8
HDMI_DATA2_R_C: JHDMI1.1 LI3.4 RI7.2 RI9.2
HDMI_HPD: QI3.3 RI15.2 UC1.L9
HDMI_HPD_B: JHDMI1.19 QI3.1 RI16.1
HDMI_PLL_GND: QI1.1 RPI1.1 RPI1.2 RPI1.3 RPI1.4 RPI2.1 RPI2.2 RPI2.3 RPI2.4
HOST_DEBUG_TX: JDEG1.8 JWLAN1.30 RE59.2 RW6.1 RW8.1 UE1.81 ZT57.1(TP-1)
HPOUT_L: CA35.1 DA4.2 JHP1.1 RA30.1 RA36.2 ZT19.1(TP-1)
HPOUT_R: CA34.1 DA4.3 JHP1.2 RA34.1 RA37.2 ZT22.1(TP-1)
I2C_SCL_TP: Q10.1 R34.2 UC1.U6
I2C_SCL_TP_Q: JTP1.6 Q10.6 R46.2 ZT9.1(TP-1)
I2C_SDA_TP: Q10.4 R33.2 UC1.U7
I2C_SDA_TP_Q: JTP1.7 Q10.3 R47.2 ZT8.1(TP-1)
I_ADP: PC748.1 PR774.1 RE51.2
I_ADP_R: CE25.1 RE51.1 UE1.110
I_BATT: PC749.2 PR775.1 RE54.2
I_BATT_R: CE30.1 RE54.1 UE1.114
I_SYS: PR620.1 PR727.1 PU703.8 RE44.1
ICSP_CLK: RE24.2 RE60.1 UE1.101
ICSP_CLK_R: JDEG1.2 RE60.2 ZT53.1(TP-1)
ICSP_CLR: RE61.1 UE1.87
ICSP_CLR_R: JDEG1.3 RE61.2 ZT54.1(TP-1)
ICSP_DAT: RE26.2 RE63.1 UE1.102
ICSP_DAT_R: JDEG1.5 RE63.2 ZT56.1(TP-1)
ILMT_+1.35VGPU: PR1406.2 PR1407.1 PU1400.13
ILMT_+1VALW: PR304.2 PR305.1 PU300.13
IMON_IA: PC625.2 PR629.2 PU602.14
IMON_VGA: PC1117.2 PR1117.2 PU1100.10
IMON_VSA: PC643.1 PR651.1 PU602.23
IMVP_VR_ON: PR616.1 PR655.1 RC107.2
INT_TP#: JTP1.4 Q9.3 R39.2 ZT10.1(TP-1)
INTRUDER#: RC91.1 UC1.AP16
IR_CAM_DETECT#: JEDP1.34 RC64.2 UC1.P4
IR_GND: JEDP1.25 JEDP1.26 R54.1
ISEN1_VGA: PC1120.2 PR1124.1 PU1100.13
ISEN2_VGA: PC1119.2 PR1104.1 PU1100.12
ISOLATE#: RL3.2 RL4.1 UL1.20
ISUMN_GT: PC624.2 PC626.2 PC641.1 PH602.2 PR632.1 PR633.2 PR638.1 PR673.2
ISUMN_IA: PC642.2 PC645.1 PC646.2 PH605.2 PL603.2 PR640.2 PR644.2 PR656.2
ISUMN_VSA: PC633.2 PC637.2 PC644.1 PH604.2 PL601.2 PR636.2 PR641.2 PR643.1
ISUMP_GT: PC624.1 PC626.1 PR628.1 PR633.1 PR637.1 PR674.1 PU602.7
ISUMP_IA: PC642.1 PC646.1 PR653.1 PR656.1 PR657.1 PR661.2 PU602.19
ISUMP_VSA: PC633.1 PC637.1 PR624.2 PR642.1 PR643.2 PR654.1 PU602.27
JACK_PLUG: JHP1.5 RA39.2 ZT20.1(TP-1)
JACK_PLUG_DET: JHP1.6 RA40.1 ZT21.1(TP-1)
JTAG_TCK: RV369.1 UV1.L3
JTAG_TDI_GPU: RP34.7 UV1.L5
JTAG_TDO_GPU: RP34.8 UV1.K4
JTAG_TMS_GPU: RP34.6 UV1.L1
JTAG_TRSTB: RP34.5 UV1.L6
KB_BL_CTRL#: EC3001.1 JKBBL1.4 Q8.1 ZT52.1(TP-1)
KB_DET#: JKB1.30 RC45.1 UC1.BB7 ZT24.1(TP-1)
KB_LED_BL_DET: R26.1 R27.1 UC1.W8
KB_LED_DET_C: JKBBL1.2 R26.2 ZT51.1(TP-1)
KB_LED_PWM: Q8.2 UE1.44
KSI0: JKB1.22 RPE1.4 UE1.98 ZT32.1(TP-1)
KSI1: JKB1.24 RPE1.3 UE1.99 ZT30.1(TP-1)
KSI2: JKB1.26 RPE1.2 UE1.6 ZT28.1(TP-1)
KSI3: JKB1.23 RPE1.1 UE1.7 ZT31.1(TP-1)
KSI4: JKB1.27 RPE2.1 UE1.104 ZT27.1(TP-1)
KSI5: JKB1.25 RPE2.2 UE1.105 ZT29.1(TP-1)
KSI6: JKB1.28 RPE2.3 UE1.107 ZT26.1(TP-1)
KSI7: JKB1.29 RPE2.4 UE1.108 ZT25.1(TP-1)
KSO0: JKB1.13 RPE3.8 UE1.2 ZT41.1(TP-1)
KSO1: JKB1.15 RPE3.7 UE1.14 ZT39.1(TP-1)
KSO2: JKB1.14 RPE3.6 UE1.15 ZT40.1(TP-1)
KSO3: JKB1.16 RPE3.5 UE1.16 ZT38.1(TP-1)
KSO4: JKB1.20 RPE4.8 UE1.37 ZT34.1(TP-1)
KSO5: JKB1.21 RPE4.7 UE1.38 ZT33.1(TP-1)
KSO6: JKB1.18 RPE4.6 UE1.39 ZT36.1(TP-1)
KSO7: JKB1.19 RPE4.5 UE1.50 ZT35.1(TP-1)
KSO8: JKB1.17 RPE6.8 UE1.46 ZT37.1(TP-1)
KSO9: JKB1.7 RE15.1 UE1.68 ZT47.1(TP-1)
KSO10: JKB1.5 RPE5.8 UE1.72 ZT49.1(TP-1)
KSO11: JKB1.6 RPE5.7 UE1.74 ZT48.1(TP-1)
KSO12: JKB1.12 RPE5.6 UE1.75 ZT42.1(TP-1)
KSO13: JKB1.9 RPE5.5 UE1.76 ZT45.1(TP-1)
KSO14: JKB1.8 RPE6.6 UE1.77 ZT46.1(TP-1)
KSO15: JKB1.10 RPE6.7 UE1.86 ZT44.1(TP-1)
KSO16: JKB1.11 RPE6.5 UE1.92 ZT43.1(TP-1)
L_BKLT_CTRL: R8.1 UC1.R11
L_BKLT_EN_EC: RC6.2 UC1.R12 UE1.91
LAN_EN: RL6.2 UE1.3 UL3.4
LAN_MDI0N: EU3501.2 EU3501.8 TL1.5 UL1.2
LAN_MDI0P: EU3501.1 EU3501.9 TL1.6 UL1.1
LAN_MDI1N: EU3501.5 EU3501.6 TL1.1 UL1.5
LAN_MDI1P: EU3501.4 EU3501.7 TL1.2 UL1.4
LAN_TXN_C_PCH_RXN6: CL2.2 UL1.18
LAN_TXP_C_PCH_RXP6: CL1.2 UL1.17
LAN_WAKE#: RC85.2 RC100.2 UC1.AM15
LANXIN: CL10.1 UL1.28 YL1.1
LANXOUT: CL11.1 UL1.29 YL1.3
LCD_BRIGHTNESS: JEDP1.23 RP2.2
LCD_TST: D3.3 RP2.6 UE1.26
LCD_TST_C: JEDP1.12 RP2.3
LCD_VCC_TEST_EN: RE44.2 RE64.2 UE1.113
LCD_VCC_TEST_EN_R: D4.3 RE64.1
LCDVDD_EN: D4.1 R10.1 U1.4
LDO1_CAP: CA20.2 RA41.2 UA1.27
LDO2_CAP: CA21.2 UA1.39
LDO3_CAP: CA22.2 UA1.7
LDO_+1.35VGPU: PC1406.1 PU1400.16 PU1400.17
LDO_+1VALW: PC306.1 PU300.16 PU300.17
LED1: RL1.2 UL1.26
LG1_VGA: PQ1105.4 PQ1106.4 PU1100.24
LG2_VGA: PQ1102.4 PQ1103.4 PU1100.27
LG_1.2V: PQ201.8 PU200.15
LGATE_CHG: PQ708.4 PU703.21
LID_CLOSE#: CE19.1 D5.1 R22.1 RE25.2 UE1.41
LID_CLOSE#_C: EC2902.1 JPWR1.2 R22.2 ZT3.1(TP-1)
LINE1-L_C: CA32.2 RA28.1
LINE1-L_R: CA33.2 RA32.1
LINE1_L: CA32.1 UA1.22
LINE1_R: CA33.1 UA1.21
LOM_TCT: CL12.1 TL1.3 TL1.4
LPC_LAD0: JDB1.8 UC1.AY13 UE1.59
LPC_LAD1: JDB1.7 UC1.BA13 UE1.60
LPC_LAD2: JDB1.6 UC1.BB13 UE1.61
LPC_LAD3: JDB1.5 UC1.AY12 UE1.62
LPC_LFRAME#: JDB1.4 UC1.BA12 UE1.58
LPSS_UART2_CTS#: RC43.1 UC1.AD4
LX1_VGA: PC1118.2 PL1103.4 PQ1104.1 PQ1104.2 PQ1104.3 PQ1105.5 PQ1106.5 PR1125.1 PU1100.23
LX2_VGA: PC1108.2 PL1102.4 PQ1101.1 PQ1101.2 PQ1101.3 PQ1102.5 PQ1103.5 PR1107.1 PU1100.28
LX_1.2V: PC200.2 PC207.1 PL200.2 PQ201.9 PU200.16
LX_1.8VALW: PL501.1 PR506.1 PU500.2 PU500.3
LX_3V: PC102.2 PL100.1 PR106.1 PU100.6 PU100.19 PU100.20
LX_5V: PC114.2 PL101.1 PR112.1 PU102.6 PU102.19 PU102.20
LX_+1.35VGPU: PC1407.2 PL1401.1 PR1408.1 PU1400.6 PU1400.19 PU1400.20
LX_+1VALW: PC307.2 PL301.1 PR307.1 PU300.6 PU300.19 PU300.20
M0_MA0: UV1.K17 UV12.H4 UV13.K4
M0_MA1: UV1.J20 UV12.H5 UV13.K5
M0_MA2: UV1.H23 UV12.H11 UV13.K11
M0_MA3: UV1.G23 UV12.H10 UV13.K10
M0_MA4: UV1.G24 UV12.K11 UV13.H11
M0_MA5: UV1.H24 UV12.K10 UV13.H10
M0_MA6: UV1.J19 UV12.K5 UV13.H5
M0_MA7: UV1.K19 UV12.K4 UV13.H4
M0_MA8: UV1.G20 UV12.J5 UV13.J5
M1_MA0: UV1.J14 UV14.H4 UV15.K4
M1_MA1: UV1.K14 UV14.H5 UV15.K5
M1_MA2: UV1.J11 UV14.H11 UV15.K11
M1_MA3: UV1.J13 UV14.H10 UV15.K10
M1_MA4: UV1.H11 UV14.K11 UV15.H11
M1_MA5: UV1.G11 UV14.K10 UV15.H10
M1_MA6: UV1.J16 UV14.K5 UV15.H5
M1_MA7: UV1.L15 UV14.K4 UV15.H4
M1_MA8: UV1.G14 UV14.J5 UV15.J5
M2_SLOT2_PEDET: JSSD1.18 UC1.G4
M_ADBI0: UV1.L18 UV12.J4 UV13.J4
M_ADBI1: UV1.K16 UV14.J4 UV15.J4
M_CAS#0: UV1.G19 UV12.L3 UV13.G3
M_CAS#1: UV1.G16 UV14.L3 UV15.G3
M_CKE0: UV1.K20 UV12.J3 UV13.J3
M_CKE1: UV1.J17 UV14.J3 UV15.J3
M_CLK0: RV79.2 UV1.H26 UV12.J12 UV13.J12
M_CLK1: RV85.2 UV1.G9 UV14.J12 UV15.J12
M_CLK#0: RV80.2 UV1.H25 UV12.J11 UV13.J11
M_CLK#1: RV86.2 UV1.H9 UV14.J11 UV15.J11
M_CS0B#0: UV1.H22 UV12.G12 UV13.L12
M_CS1B#0: UV1.G13 UV14.G12 UV15.L12
M_DA0: UV1.K27 UV13.A2
M_DA1: UV1.J29 UV13.B2
M_DA2: UV1.H30 UV13.A4
M_DA3: UV1.H32 UV13.B4
M_DA4: UV1.G29 UV13.F2
M_DA5: UV1.F28 UV13.F4
M_DA6: UV1.F32 UV13.E4
M_DA7: UV1.F30 UV13.E2
M_DA8: UV1.C30 UV12.M11
M_DA9: UV1.F27 UV12.T13
M_DA10: UV1.A28 UV12.N11
M_DA11: UV1.C28 UV12.T11
M_DA12: UV1.E27 UV12.N13
M_DA13: UV1.G26 UV12.U13
M_DA14: UV1.D26 UV12.M13
M_DA15: UV1.F25 UV12.U11
M_DA16: UV1.A25 UV12.F4
M_DA17: UV1.C25 UV12.B4
M_DA18: UV1.E25 UV12.E4
M_DA19: UV1.D24 UV12.A4
M_DA20: UV1.E23 UV12.B2
M_DA21: UV1.F23 UV12.E2
M_DA22: UV1.D22 UV12.A2
M_DA23: UV1.F21 UV12.F2
M_DA24: UV1.E21 UV13.M11
M_DA25: UV1.D20 UV13.M13
M_DA26: UV1.F19 UV13.N13
M_DA27: UV1.A19 UV13.N11
M_DA28: UV1.D18 UV13.U13
M_DA29: UV1.F17 UV13.T13
M_DA30: UV1.A17 UV13.U11
M_DA31: UV1.C17 UV13.T11
M_DA32: UV1.E17 UV15.U13
M_DA33: UV1.D16 UV15.U11
M_DA34: UV1.F15 UV15.T11
M_DA35: UV1.A15 UV15.T13
M_DA36: UV1.D14 UV15.N11
M_DA37: UV1.F13 UV15.M13
M_DA38: UV1.A13 UV15.M11
M_DA39: UV1.C13 UV15.N13
M_DA40: UV1.E11 UV14.B2
M_DA41: UV1.A11 UV14.A4
M_DA42: UV1.C11 UV14.A2
M_DA43: UV1.F11 UV14.B4
M_DA44: UV1.A9 UV14.E2
M_DA45: UV1.C9 UV14.F2
M_DA46: UV1.F9 UV14.F4
M_DA47: UV1.D8 UV14.E4
M_DA48: UV1.E7 UV14.M11
M_DA49: UV1.A7 UV14.N11
M_DA50: UV1.C7 UV14.T11
M_DA51: UV1.F7 UV14.M13
M_DA52: UV1.A5 UV14.U11
M_DA53: UV1.E5 UV14.N13
M_DA54: UV1.C3 UV14.U13
M_DA55: UV1.E1 UV14.T13
M_DA56: UV1.G7 UV15.F4
M_DA57: UV1.G6 UV15.E4
M_DA58: UV1.G1 UV15.E2
M_DA59: UV1.G3 UV15.F2
M_DA60: UV1.J6 UV15.A4
M_DA61: UV1.J1 UV15.B2
M_DA62: UV1.J3 UV15.A2
M_DA63: UV1.J5 UV15.B4
M_DBI0#: UV1.H27 UV13.D2
M_DBI1#: UV1.A27 UV12.P13
M_DBI2#: UV1.C23 UV12.D2
M_DBI3#: UV1.C19 UV13.P13
M_DBI4#: UV1.C15 UV15.P13
M_DBI5#: UV1.E9 UV14.D2
M_DBI6#: UV1.C5 UV14.P13
M_DBI7#: UV1.H4 UV15.D2
M_EDC_0: UV1.H28 UV13.C2
M_EDC_1: UV1.C27 UV12.R13
M_EDC_2: UV1.A23 UV12.C2
M_EDC_3: UV1.E19 UV13.R13
M_EDC_4: UV1.E15 UV15.R13
M_EDC_5: UV1.D10 UV14.C2
M_EDC_6: UV1.D6 UV14.R13
M_EDC_7: UV1.G5 UV15.C2
M_RAS#0: UV1.G22 UV12.G3 UV13.L3
M_RAS#1: UV1.G17 UV14.G3 UV15.L3
M_WCKA0_0: UV1.E32 UV12.P4 UV13.D4
M_WCKA0_0#: UV1.E30 UV12.P5 UV13.D5
M_WCKA0_1: UV1.A21 UV12.D4 UV13.P4
M_WCKA0_1#: UV1.C21 UV12.D5 UV13.P5
M_WCKA1_0: UV1.E13 UV14.D4 UV15.P4
M_WCKA1_0#: UV1.D12 UV14.D5 UV15.P5
M_WCKA1_1: UV1.E3 UV14.P4 UV15.D4
M_WCKA1_1#: UV1.F4 UV14.P5 UV15.D5
M_WE#0: UV1.G25 UV12.L12 UV13.G12
M_WE#1: UV1.H10 UV14.L12 UV15.G12
MCT: CL13.1 RL14.1 RL15.1
MCT0: RL15.2 TL1.9
MCT1: RL14.2 TL1.10
MDO0+: JLAN1.1 TL1.7
MDO0-: JLAN1.2 TL1.8
MDO1+: JLAN1.3 TL1.11
MDO1-: JLAN1.6 TL1.12
ME_FWP_EC: RC126.1 RE19.1 UE1.80
ME_SUS_PWR_ACK: RC84.2 UC1.AR13 UE1.42
MEC_XTAL1: CE3.1 RE47.2 YE1.1
MEC_XTAL1_R: RE47.1 UE1.123
MEC_XTAL2: CE4.1 RE45.1 UE1.125 YE1.2
MIC_CAP: CA26.1 UA1.19
MODEL_ID: CE1.1 RE3.2 RE4.2 UE1.109
MPHYP_PWR_EN: TP13.1(TP-1) UC1.AM10
NCT7718_DXN: C22.2 C23.2 Q14.3 U2.3
NCT7718_DXP: C22.1 C23.1 Q14.1 Q14.2 U2.2
NRB_BIT: RC44.2 UC1.AR7
NTC_IA: PR635.2 PU602.15
OCP_L: PR1112.2 PU1100.4
ONE_DIMM#: RC181.2 RC182.1 UC1.M2
PANEL_BKEN_EC: RP2.8 UE1.117
PBAT_CHG_SMBCLK: PD2.3 PR18.2 PR770.1 RE9.1 UE1.9
PBAT_CHG_SMBDAT: PD2.2 PR20.2 PR769.1 RE8.1 UE1.8
PBAT_PRES#: CE16.1 PC14.1 PC753.2 PD3.2 PR15.2 PR16.1 PR756.1 PR764.1 UE1.97
PCH_BATLOW#: RC89.1 UC1.AU13
PCH_DPWROK: RC87.1 RC97.2 UC1.BB20
PCH_HDMI_CLK: QI2.1 RC1.1 UC1.L13
PCH_HDMI_DATA: QI2.4 RC2.1 UC1.L12
PCH_JTAG_TCK1: RC147.1 TPC3.1(TP-1) UC1.B56
PCH_PCIE_WAKE#: RC99.2 UC1.BB15
PCH_PLTRST#: RC108.1 UC1.AN10 UC4.1 UC4.2
PCH_PLTRST#_EC: CE27.1 JDB1.3 JSSD1.23 RC108.2 RC109.1 RL12.1 RW4.2 UC4.4 UE1.56 UV2.1
PCH_POPIRCOMP: RC120.1 UC1.AU16
PCH_RSMRST#: RE20.1 UC5.1 UE1.88
PCH_RSMRST#_Q: RC94.2 RC97.1 RC148.1 UC1.AY17 UC5.4
PCH_RTCRST#: CC5.1 JCMOS1.1 QC2.1 RC78.1 TPS7.1(TP-1) UC1.AM16
PCH_RTCX1: CC8.1 RC82.2 UC1.AM18 YC2.1
PCH_RTCX2: RC82.1 RC83.2 UC1.AM20
PCH_RTCX2_R: CC9.1 RC83.1 YC2.2
PCH_SMB_ALERT#: RC37.1 UC1.R10
PCH_SMBCLK: JDIMM1.253 JDIMM2.253 QC1.1 RC28.2
PCH_SMBDATA: JDIMM1.254 JDIMM2.254 QC1.4 RC27.2
PCH_SPI_CLK_0_R: RC178.1 UC3.6
PCH_SPI_CLK_R: RC21.2 RC24.2 RC178.2 RE33.1
PCH_SPI_CLK_R1: RC24.1 UC1.AV2
PCH_SPI_CS#0_R1: RC18.2 RE38.2 UC1.AU3 UC3.1
PCH_SPI_D0_0_R: RC179.1 UC3.5
PCH_SPI_D0_R: RC23.2 RC179.2 RE34.1
PCH_SPI_D0_R1: RC23.1 RC40.2 UC1.AV3
PCH_SPI_D1_0_R: RC180.1 UC3.2
PCH_SPI_D1_R: RC22.2 RC180.2 RE35.1
PCH_SPI_D1_R1: RC22.1 UC1.AW3
PCH_SPI_D2_0_R: RC176.2 UC3.3
PCH_SPI_D2_R: RC26.2 RC176.1
PCH_SPI_D2_R1: RC19.2 RC26.1 RC41.2 UC1.AW2
PCH_SPI_D3_0_R: RC177.2 UC3.7
PCH_SPI_D3_R: RC25.2 RC177.1
PCH_SPI_D3_R1: RC20.2 RC25.1 UC1.AU4
PCI_CLK_LPC1: RC15.1 RC16.1 UC1.AY9
PCIE_CRX_LANTX_N6: CL2.1 UC1.G18
PCIE_CRX_LANTX_P6: CL1.1 UC1.F18
PCIE_CRX_SSDTX_N11: JSSD1.8 UC1.E28
PCIE_CRX_SSDTX_N12: JSSD1.14 UC1.E30
PCIE_CRX_SSDTX_P11: JSSD1.9 UC1.E27
PCIE_CRX_SSDTX_P12: JSSD1.15 UC1.F30
PCIE_CRX_WLANTX_N5: JWLAN1.35 UC1.F16
PCIE_CRX_WLANTX_P5: JWLAN1.33 UC1.E16
PCIE_CTX_C_SSDRX_N11: CS18.2 JSSD1.6
PCIE_CTX_C_SSDRX_N12: CS16.2 JSSD1.12
PCIE_CTX_C_SSDRX_P11: CS19.2 JSSD1.5
PCIE_CTX_C_SSDRX_P12: CS17.2 JSSD1.11
PCIE_CTX_LANRX_N6: CL4.1 UC1.D20
PCIE_CTX_LANRX_P6: CL3.1 UC1.C20
PCIE_CTX_SSDRX_N11: CS18.1 UC1.D24
PCIE_CTX_SSDRX_N12: CS16.1 UC1.A25
PCIE_CTX_SSDRX_P11: CS19.1 UC1.C24
PCIE_CTX_SSDRX_P12: CS17.1 UC1.B25
PCIE_CTX_WLANRX_N5: CW1.2 JWLAN1.29
PCIE_CTX_WLANRX_N5_C: CW1.1 UC1.C19
PCIE_CTX_WLANRX_P5: CW2.2 JWLAN1.27
PCIE_CTX_WLANRX_P5_C: CW2.1 UC1.D19
PCIE_PTX_LANRX_N6_C: CL4.2 UL1.14
PCIE_PTX_LANRX_P6_C: CL3.2 UL1.13
PCIE_RCOMPN: RC65.1 UC1.F5
PCIE_RCOMPP: RC65.2 UC1.E5
PCIE_WAKE#: JSSD1.19 RC99.1 RE12.2 UE1.4 UL1.21
PECI_EC: DE1.1 RE23.2 UC1.A54
PECI_MEC1404: RE23.1 UE1.94
PEG_CLKREQ#: RC71.2 RV153.1 UC1.AR10
PEG_CLKREQ#_G: RV153.2 RV368.2 UV1.N7
PEG_GTX_C_HRX_N0: CV2.1 UC1.G13
PEG_GTX_C_HRX_N1: CV4.1 UC1.F11
PEG_GTX_C_HRX_N2: CV6.1 UC1.G16
PEG_GTX_C_HRX_N3: CV8.1 UC1.F15
PEG_GTX_C_HRX_P0: CV1.1 UC1.H13
PEG_GTX_C_HRX_P1: CV3.1 UC1.G11
PEG_GTX_C_HRX_P2: CV5.1 UC1.H16
PEG_GTX_C_HRX_P3: CV7.1 UC1.G15
PEG_GTX_HRX_N0: CV2.2 UV1.AG31
PEG_GTX_HRX_N1: CV4.2 UV1.AF28
PEG_GTX_HRX_N2: CV6.2 UV1.AF26
PEG_GTX_HRX_N3: CV8.2 UV1.AD26
PEG_GTX_HRX_P0: CV1.2 UV1.AH30
PEG_GTX_HRX_P1: CV3.2 UV1.AG29
PEG_GTX_HRX_P2: CV5.2 UV1.AF27
PEG_GTX_HRX_P3: CV7.2 UV1.AD27
PEG_HTX_C_GRX_N0: CV306.2 UC1.A17
PEG_HTX_C_GRX_N1: CV305.2 UC1.C16
PEG_HTX_C_GRX_N2: CV309.2 UC1.C17
PEG_HTX_C_GRX_N3: CV304.2 UC1.A19
PEG_HTX_C_GRX_P0: CV312.2 UC1.B17
PEG_HTX_C_GRX_P1: CV308.2 UC1.D16
PEG_HTX_C_GRX_P2: CV307.2 UC1.D17
PEG_HTX_C_GRX_P3: CV313.2 UC1.B19
PEG_HTX_GRX_N0: CV306.1 UV1.AE31
PEG_HTX_GRX_N1: CV305.1 UV1.AD28
PEG_HTX_GRX_N2: CV309.1 UV1.AC31
PEG_HTX_GRX_N3: CV304.1 UV1.AB28
PEG_HTX_GRX_P0: CV312.1 UV1.AF30
PEG_HTX_GRX_P1: CV308.1 UV1.AE29
PEG_HTX_GRX_P2: CV307.1 UV1.AD30
PEG_HTX_GRX_P3: CV313.1 UV1.AC29
PHASE_CHG: PC721.2 PL700.1 PQ704.1 PQ704.2 PQ704.3 PQ708.5 PR766.1 PU703.22
PIRQA#: RC187.2 UC1.BB11
PLL_ANALOG_IN: TP68.1(TP-1) UV1.AA1
PLL_ANALOG_OUT: RV83.1 UV1.AA3
PLT_RST#_LAN: RL12.2 UL1.19
PLT_RST_NGFF#: JWLAN1.44 RW4.1
PLT_RST_VGA#: RV4.1 UE1.24 UV1.AL27 UV2.4
PME#: TP12.1(TP-1) UC1.AU11
POK: CC10.1 PR13.1 PR107.2 PR113.2 PR301.1 PR501.1 PU100.9 PU102.9 RC102.1 UC5.2
POWER_SW#_MB: EC2901.1 ED2901.1 JPWR1.3 RE43.2 SW1.1 ZT2.1(TP-1)
POWER_SW_IN#: CE33.1 RE41.2 RE43.1 UE1.127
PROG: PR753.2 PU703.9
PROH: PQ720.2 PR777.2 PR781.2 PU703.5
PROJECT_ID1: RC51.2 RC52.1 UC1.AY8
PROJECT_ID2: RC53.2 RC54.1 UC1.BA8
PS_0: CV29.1 RV8.2 RV9.1 UV1.AC19
PS_1: CV28.1 RV11.2 RV12.1 UV1.AD19
PS_2: CV11.1 RV13.1 RV28.2 UV1.AE17
PS_3: CV15.1 RV15.2 RV16.1 UV1.AE20
PS_ID: PD5.1 PR3.1 PR4.2 UE1.36
PSID: PJPDC1.3 PL2.2 ZT103.1(TP-1)
PSID-1: PQ5.2 PR6.1 PR9.2
PSID-2: PQ5.1 PQ6.2 PR8.2 PR11.1
PSID-3: PQ6.3 PR4.1
PTP_DIS#: D6.1 RE22.1 RE26.1
PTP_DIS#_R: RE22.2 UE1.90
PWM1_GT: PR680.1 PU602.12 PU605.13
PWM_IA: PR662.1 PU602.22 PU603.13
PWM_VSA: PU602.30 PU606.3
PWR_LED_R#: Q15.2 Q16.1
PWRGD_VGA: PR1119.2 PR1122.1 PU1100.9 PU1100.20
PX_EN: TP73.1(TP-1) UV1.AB16
RESET_OUT#: CE31.1 RE16.1 UC1.BA20 UE1.73
RING2: RA25.2 RA35.1 UA1.17
RING2_R: CA36.1 DA5.2 JHP1.4 RA35.2 ZT23.1(TP-1)
RTC_DET#: Q1.1 RC46.1 UC1.P1
RTC_PWR: D1.3 Q1.2 R1.1 R2.1
RTCRST_ON: QC2.2 RC164.1 UE1.31
RUNPWROK: RE42.1 UE1.48
SA_SNUB: PC622.1 PR627.2
SA_SW: PL601.4 PQ601.9 PR619.2 PR627.1 PU606.8
SATA3_CRX_HDDTX_N0: CS3.1 UC1.F20
SATA3_CRX_HDDTX_P0: CS4.1 UC1.E20
SATA3_CTX_HDDRX_N0: CS2.1 UC1.B21
SATA3_CTX_HDDRX_P0: CS1.1 UC1.A21
SATA_CRX_ODDTX_N1: CS10.2 UC1.G21
SATA_CRX_ODDTX_P1: CS9.2 UC1.F21
SATA_CTX_ODDRX_N1: CS11.2 UC1.D21
SATA_CTX_ODDRX_P1: CS12.2 UC1.C21
SATA_LED#: Q5.3 RC69.1 UC1.H1
SATA_LED_EN: Q5.2 R23.2 UE1.30
SATA_ODD_DA#: JODD1.23 JODD1.24 TP46.1(TP-1)
SATA_ODD_PRSNT#: JODD1.15 JODD1.16 TP47.1(TP-1)
SATA_RXN0_R: CS3.2 EU3101.2 EU3101.8 JHDD1.5
SATA_RXN2_R: CS10.1 JODD1.9 JODD1.10
SATA_RXP0_R: CS4.2 EU3101.1 EU3101.9 JHDD1.6
SATA_RXP2_R: CS9.1 JODD1.11 JODD1.12
SATA_TXN0_R: CS2.2 EU3101.4 EU3101.7 JHDD1.3
SATA_TXN2_R: CS11.1 JODD1.5 JODD1.6
SATA_TXP0_R: CS1.2 EU3101.5 EU3101.6 JHDD1.2
SATA_TXP2_R: CS12.1 JODD1.3 JODD1.4
SD_RCOMP: RC130.1 UC1.AB7
SERIRQ: RC14.2 UC1.AY11 UE1.55
SIO_EXT_SCI#: RC70.1 UC1.J2 UE1.66
SIO_EXT_SMI#: RC5.2 UC1.L6 UE1.10
SIO_EXT_WAKE#: RC47.1 UC1.AD3 UE1.116
SIO_PWRBTN#: RC93.2 UC1.BA15 UE1.52
SIO_RCIN#: RC13.2 UC1.AW13 UE1.53
SIO_SLP_A#: TPS6.1(TP-1) UC1.AN16
SIO_SLP_LAN#: RC88.1 TP10.1(TP-1) UC1.AW15
SIO_SLP_S0#: TPS2.1(TP-1) UC1.AT11 UC9.2
SIO_SLP_S3#: CE29.1 DZ4.1 RC103.1 RZ2.1 TPS3.1(TP-1) UC1.AP15 UC9.1 UE1.23 UZ3.3 UZ3.5
SIO_SLP_S4#: DZ5.1 PR201.1 PR803.1 RZ1.1 TPS4.1(TP-1) UC1.BA16 UE1.67
SIO_SLP_S5#: PQ711.2 TPS5.1(TP-1) UC1.AY16
SIO_SLP_SUS#: TP75.1(TP-1) UC1.AN15
SIO_SLP_WLAN#: TP11.1(TP-1) UC1.BB17
SLEEVE: RA26.2 RA38.1 UA1.18
SLEEVE_R: CA37.1 DA5.3 JHP1.3 RA38.2 ZT18.1(TP-1)
SM_RCOMP0: RC10.1 UC1.AR18
SM_RCOMP1: RC11.1 UC1.AT18
SM_RCOMP2: RC12.1 UC1.AU18
SMBCLK: QC1.6 RC29.1 UC1.R7
SMBDATA: QC1.3 RC30.1 UC1.R8
SML0_SMBCLK: RC33.1 UC1.R9
SML0_SMBDATA: RC34.1 UC1.W2
SML1CLK: Q11.3 QV1.6 RC31.1 RE11.1 UC1.W3 UE1.12
SML1DATA: Q11.6 QV1.3 RC32.1 RE10.1 UC1.V3 UE1.11
SNUB_+1.35VGPU: PC1408.1 PR1408.2
SNUB_+1VALW: PC308.1 PR307.2
SOC_XDP_TDI: RC141.1 TPC5.1(TP-1) UC1.D59 UC1.D60
SOC_XDP_TDO: RC142.1 TPC1.1(TP-1) UC1.A56 UC1.A61
SOC_XDP_TMS: RC140.1 TPC4.1(TP-1) UC1.C59 UC1.C60
SOC_XDP_TRST#: TPC6.1(TP-1) UC1.B59 UC1.C61
SPKR: DA3.3 RC128.2 UC1.AW5
SRTCRST#: CC4.1 RC77.1 UC1.AN18
SUS_STAT#/LPCPD#: RC35.1 UC1.BA11
SUSCLK: RC74.2 RC75.2 RC110.1 RC189.2 UC1.BA17
SUSCLK_EC: RC75.1 RE45.2
SUSCLK_SSD: JSSD1.22 RC189.1
SUSCLK_WLAN: JWLAN1.42 RC74.1
SVI2_SVC: PU1100.3 RV84.1 RV89.2 RV157.2
SVI2_SVD: PU1100.5 RV87.1 RV88.2 RV155.2
SVI2_SVT: PU1100.7 RV156.2
SYS_PWROK: UC1.B6 UE1.89
SYS_RESET#: RC86.2 TPS1.1(TP-1) UC1.B5
SYSPWR_PRES: RE29.1 RE32.1 UE1.120
T_CRIT#: R29.2 U2.4
TESTEN: RV17.2 RV154.2 UV1.K7
THM_SML1_CLK: C24.1 Q11.4 R49.2 U2.8
THM_SML1_DATA: C25.1 Q11.1 R48.2 U2.7
TON_1.2V: PR208.2 PU200.9
TOUCH_SCREEN_PD#: D5.2 R19.2 RC115.2 RC118.1
TOUCH_SCREEN_PD#_R: RC118.2 UC1.A7
TOUCHPAD_INTR#: DZ3.1 Q9.1 RE14.1 UE1.33
TOUCHPAD_INTR#_D: DZ3.2 RC114.2 UC1.BA5
TP_EN: C16.1 JEDP1.39 R19.1
TP_LOCK#: D6.2 JTP1.3 R41.2 ZT11.1(TP-1)
TP_ON#_GATE: C18.2 Q12.2 Q13.2 R38.2
TP_PW_EN#: R38.1 UE1.49
UG1_VGA: PQ1104.4 PU1100.22
UG2_VGA: PQ1101.4 PU1100.29
UG_1.2V: PQ201.1 PU200.17
UGATE_CHG: PR761.1 PU703.23
USB2_ID: RC67.1 UC1.AG3
USB2_VBUSSENSE: RC68.1 UC1.AG4
USB3_CM_P0: RX16.2 RX17.2 UX2.14
USB3_CRX_C_RD_DTX_N3: CX6.2 UX2.11
USB3_CRX_C_RD_DTX_P3: CX7.2 UX2.12
USB3_CRX_DTX_N1: LU3.3 RU5.2 UC1.H8
USB3_CRX_DTX_N1_C: EU2601.1 EU2601.9 JUSB1.5 LU3.4 RU5.1
USB3_CRX_DTX_N2: LU6.3 RU11.2 UC1.J6
USB3_CRX_DTX_N2_C: EU2603.1 EU2603.9 JUSB2.5 LU6.4 RU11.1
USB3_CRX_DTX_N3: CX6.1 UC1.J10
USB3_CRX_DTX_P1: LU3.2 RU6.2 UC1.G8
USB3_CRX_DTX_P1_C: EU2601.2 EU2601.8 JUSB1.6 LU3.1 RU6.1
USB3_CRX_DTX_P2: LU6.2 RU12.2 UC1.H6
USB3_CRX_DTX_P2_C: EU2603.2 EU2603.8 JUSB2.6 LU6.1 RU12.1
USB3_CRX_DTX_P3: CX7.1 UC1.H10
USB3_CRX_L_DTX_N3: DX1.4 DX1.7 J3D1.5 LX2.2 RX9.2
USB3_CRX_L_DTX_P3: DX1.5 DX1.6 J3D1.6 LX2.1 RX8.2
USB3_CRX_RD_DTX_N3: LX2.3 RX9.1 UX2.20
USB3_CRX_RD_DTX_P3: LX2.4 RX8.1 UX2.19
USB3_CTX_C_DRX_N3: CX11.2 LX1.3 RX4.1
USB3_CTX_C_DRX_P3: CX9.2 LX1.4 RX7.1
USB3_CTX_C_RD_DRX_N3: CX8.2 UX2.8
USB3_CTX_C_RD_DRX_P3: CX10.2 UX2.9
USB3_CTX_DRX_N1: CU2.1 UC1.C13
USB3_CTX_DRX_N1_C: EU2601.4 EU2601.7 JUSB1.8 LU2.4 RU3.1
USB3_CTX_DRX_N1_R: CU2.2 LU2.3 RU3.2
USB3_CTX_DRX_N2: CU4.1 UC1.B13
USB3_CTX_DRX_N2_C: EU2603.4 EU2603.7 JUSB2.8 LU5.4 RU9.1
USB3_CTX_DRX_N2_R: CU4.2 LU5.3 RU9.2
USB3_CTX_DRX_N3: CX8.1 UC1.B15
USB3_CTX_DRX_P1: CU1.1 UC1.D13
USB3_CTX_DRX_P1_C: EU2601.5 EU2601.6 JUSB1.9 LU2.1 RU4.1
USB3_CTX_DRX_P1_R: CU1.2 LU2.2 RU4.2
USB3_CTX_DRX_P2: CU3.1 UC1.A13
USB3_CTX_DRX_P2_C: EU2603.5 EU2603.6 JUSB2.9 LU5.1 RU10.1
USB3_CTX_DRX_P2_R: CU3.2 LU5.2 RU10.2
USB3_CTX_DRX_P3: CX10.1 UC1.A15
USB3_CTX_L_DRX_N3: DX1.1 DX1.10 J3D1.2 LX1.2 RX4.2
USB3_CTX_L_DRX_P3: DX1.2 DX1.9 J3D1.3 LX1.1 RX7.2
USB3_CTX_RD_DRX_N3: CX11.1 UX2.23
USB3_CTX_RD_DRX_P3: CX9.1 UX2.22
USB3_DE1_P0: RX28.2 RX29.2 UX2.3
USB3_DE2_P0: RX22.2 RX23.2 UX2.16
USB3_EQ1_P0: RX30.2 RX31.2 UX2.2
USB3_EQ2_P0: RX24.2 RX25.2 UX2.17
USB3_ERD_P0: RX18.2 RX19.2 UX2.5
USB3_OS1_P0: RX26.2 RX27.2 UX2.4
USB3_OS2_P0: RX20.2 RX21.2 UX2.15
USB3_P0_PIN6: RX11.2 RX12.2 UX2.6
USB3_P0_PIN18: RX14.2 RX15.2 UX2.18
USB20_VCCA: JIOB1.13 JIOB1.14 JIOB1.15 JIOB1.16 UU3.1
USB30_VCCA: CU6.1 CU7.1 CU8.1 CU9.1 CU10.1 CU18.1 CU19.1 CU20.1 CU21.1 CU22.1 JUSB1.1 JUSB2.1 UU1.1
USB_CAMERA_EDP: JEDP1.32 L3.4 R18.1
USB_CAMERA_EDP#: JEDP1.31 L3.1 R17.1
USB_EN#: RE17.1 UE1.13 UU1.4 UU3.4
USB_OC#0_1: RPC1.3 UC1.A9 UU1.3
USB_OC#2_3: RPC1.2 UC1.C9 UU3.3
USB_OC#4_5: RPC1.1 UC1.D9
USB_OC#6_7: RPC1.4 UC1.B9
USB_PN1: LU1.2 RU1.2 UC1.AB9
USB_PN1_C: EU2602.3 JUSB1.2 LU1.1 RU1.1
USB_PN2: LU4.2 RU8.1 UC1.AD6
USB_PN2_C: EU2604.3 JUSB2.2 LU4.1 RU8.2
USB_PN3: LU7.3 RU14.1 UC1.AH3
USB_PN3_C: JIOB1.8 LU7.4 RU14.2
USB_PN5: L3.2 R17.2 UC1.AJ1
USB_PN6: LU8.2 RU15.1 UC1.AF6
USB_PN6_C: JIOB1.3 LU8.1 RU15.2
USB_PN7: L4.2 R20.2 UC1.AH1
USB_PN7_TPNL: DA6.2 JEDP1.36 L4.1 R20.1
USB_PN8: LW1.3 RW1.2 UC1.AF8
USB_PN8_R: JWLAN1.5 LW1.4 RW1.1
USB_PP1: LU1.3 RU2.2 UC1.AB10
USB_PP1_C: EU2602.2 JUSB1.3 LU1.4 RU2.1
USB_PP2: LU4.3 RU7.1 UC1.AD7
USB_PP2_C: EU2604.2 JUSB2.3 LU4.4 RU7.2
USB_PP3: LU7.2 RU13.1 UC1.AJ3
USB_PP3_C: JIOB1.7 LU7.1 RU13.2
USB_PP5: L3.3 R18.2 UC1.AJ2
USB_PP6: LU8.3 RU16.1 UC1.AF7
USB_PP6_C: JIOB1.4 LU8.4 RU16.2
USB_PP7: L4.3 R21.2 UC1.AH2
USB_PP7_TPNL: DA6.3 JEDP1.37 L4.4 R21.1
USB_PP8: LW1.2 RW2.2 UC1.AF9
USB_PP8_R: JWLAN1.3 LW1.1 RW2.1
USBCOMP: RC66.1 UC1.AB6
VBIOS_ID1: RC59.2 RC60.1 UC1.AP8
VBIOS_ID2: RC61.2 RC62.1 UC1.AW7
VBIOS_ID3: RC190.2 RC191.1 UC1.AY7
VCI_IN1: RE30.1 UE1.126
VCIN0_PH: C32.1 C33.1 R42.2 R43.2 R44.1 RE37.1
VCREF0: CE23.1 RE46.2 RE48.1 UE1.25
VD_IN1_C: C32.2 C33.2 R44.2 R45.1
VGA_SMB_CK3: QV1.1 RV6.2 UV1.U7
VGA_SMB_DA3: QV1.4 RV5.2 UV1.U8
VIDALERT_N: PR607.1 RC152.2 RC153.2
VIDSCLK: PR606.1 UC1.A63
VIDSOUT: PR609.1 RC154.2 UC1.D64
VL: PC126.1 PU102.15
VR_ALERT#: PR625.2 PU602.36
VR_CAP: CE24.1 TP44.1(TP-1) UE1.18
VR_SCLK: PR618.2 PU602.37
VR_SDA: PR626.2 PU602.35
VRALERT#: RC92.1 UC1.AM11
VSA_SEN+: PC640.2 PC650.1 PC652.1 PR649.2 RC159.2 UC1.H20
VSA_SEN-: PC649.1 PC650.2 PU602.26 RC160.1 UC1.H21
VSUM+_VGA: PC1230.1 PC1232.1 PR1108.1 PR1126.1 PR1131.1 PR1132.1 PU1100.14
VSUM-_VGA: PC1119.1 PC1120.1 PC1230.2 PC1231.1 PC1232.2 PH1102.2 PR1110.1 PR1128.1 PR1132.2 PR1136.1 PR1137.1
VTTREF_1.2V: PC210.1 PU200.4
WAKEB: RV162.2 RV163.1 UV1.AJ27
WHITE_LED_BAT: JLED1.3 Q4.1 ZT16.1(TP-1)
WHITE_LED_PWR: JPWR1.5 Q15.1 ZT1.1(TP-1)
WLAN_RADIO_DIS#: JWLAN1.48 RC3.1 UC1.B7
XCLK_BIASREF: RC76.1 UC1.E42
XDP_HOOK0: RC148.2 TPC32.1(TP-1)
XDP_ITP_PMODE: RC143.2 TPC7.1(TP-1) UC1.E8
XDP_OBS0_R: TP15.1(TP-1) UC1.C55
XDP_OBS1_R: TP16.1(TP-1) UC1.D55
XDP_OBS2_R: TP17.1(TP-1) UC1.B54
XDP_OBS3_R: TP18.1(TP-1) UC1.C56
XDP_PRDY#: TPC31.1(TP-1) UC1.D56
XDP_PREQ#: TPC30.1(TP-1) UC1.D61
XDP_PRSENT_CPU: RC144.1 RC175.2 TPC33.1(TP-1)
XDP_SPI_IO2: RC41.1 RC145.1 TPC9.1(TP-1)
XDP_SPI_SI: RC40.1 RC139.2 TPC8.1(TP-1)
XTAL24_IN: CC6.1 RC80.2 UC1.E37 YC1.3
XTAL24_OUT: CC7.1 RC80.1 UC1.E35 YC1.1
XTALIN: CV17.1 RV20.1 UV1.AM28 YV1.1
XTALOUT: CV18.1 RV20.2 UV1.AK28 YV1.3
N16741477: TP61.1(TP-1) UV1.AB8
N16741489: TP57.1(TP-1) UV1.AD7
N16741505: TP63.1(TP-1) UV1.AB4
N16741517: TP55.1(TP-1) UV1.AD9
N16741525: TP65.1(TP-1) UV1.Y8
N16741803: RV29.2 UV1.AC22
N16741825: RV59.2 UV1.AB22
N16751828: TP58.1(TP-1) UV1.AC8
N16751830: TP54.1(TP-1) UV1.AE8
N16751834: TP52.1(TP-1) UV1.AE9
N16751836: TP50.1(TP-1) UV1.N9
N16751838: TP64.1(TP-1) UV1.AB2
N16751842: TP60.1(TP-1) UV1.AB9
N16751844: TP56.1(TP-1) UV1.AC10
N16751848: TP51.1(TP-1) UV1.L9
N16751852: TP62.1(TP-1) UV1.AB7
N16751854: TP59.1(TP-1) UV1.AC7
N16751856: TP53.1(TP-1) UV1.Y11
N16751858: TP66.1(TP-1) UV1.Y7
N16808781: RV157.1 UV1.AJ11
N16808782: RV155.1 UV1.AK12
N16808783: RV156.1 UV1.AL11
N17003698: TP71.1(TP-1) UE1.96
N17003752: JDIMM1.134 RD23.2
N17004366: JDIMM2.134 RD24.2
N17230024: TP48.1(TP-1) UL1.27
N17230026: TP49.1(TP-1) UL1.25
N17231159: RL2.2 UL1.31
N17237617: PC705.1 PC760.1 PC762.1 PC763.1 PC764.1 PC765.1 PC780.1 PC781.1 PJP701.2 PL704.2 PQ704.5
N17268429: PQ720.1 PR790.1 PR791.2
N17273333: QA1.3 RA5.2 RA6.1
N17274212: RL7.2 UL3.3
N17284062: PL601.3 PR624.1
N17297569: JDEG1.9 RE56.2 ZT58.1(TP-1)
N17389450: PC128.1 PD102.2 PR114.2 PR120.2 PR121.2 PR122.1
N17415515: PJP2.2 PJPDC1.1 PJPDC1.2 PL4.1 ZT101.1(TP-1) ZT102.1(TP-1)
N17426748: CZ3.1 UZ1.6
N17427506: CZ14.2 UZ4.6
N17444580: PC695.2 PR601.2 PR606.2 PR618.1
N17452420: PBATT1.5 PR15.1 ZT106.1(TP-1)
N17563414: RA9.1 UA1.4
N17745606: C13.1 R56.2
N17847259: TP72.1(TP-1) UV1.AL9
N17855318: PQ740.4 PR778.1
N17855352: PC742.1 PC744.1 PQ709.1 PQ718.4 PR762.1 PR778.2
N17877344: TP69.1(TP-1) UV1.R1
N17877347: TP70.1(TP-1) UV1.R3
N18047481: JDEG1.1 RE58.2 ZT60.1(TP-1)
N18047924: D8.1 JFAN1.3 R30.1 R55.1 ZT15.1(TP-1)
N18330820: CZ19.2 UZ5.10
N18330832: CZ18.2 UZ5.12
N18336277: Q13.1 R37.1
N18336387: C18.1 Q12.3 R35.2
N18390627: PQ710.2 PQ711.1
N18612614: TP28.1(TP-1) UC1.AY4
N18612616: TP29.1(TP-1) UC1.BB3
N18612618: TP27.1(TP-1) UC1.BB5
N18855880: R57.2 U1.3
N18894766: PC640.1 PR646.2
N18894780: PC601.1 PR652.2
N18894855: PC632.1 PR636.1 PU602.28
N18894856: PC632.2 PR641.1
N18894871: PH604.1 PR642.2
N19050685: RX6.1 UX2.24
N19050753: RX5.1 UX2.7
N19179553: JDEG1.4 ZT55.1(TP-1)
N19179559: JDEG1.7 RE57.2
N19179561: JDEG1.6 RE55.2
N19675639: CX3.1 UX1.6
N19910104: CE18.1 RE27.1
N20135010: PC1227.2 PR1136.2 PU1100.15
N20135022: PC1227.1 PR1137.2
N20135024: PC1110.1 PR1114.1 PU1100.25
N20135039: PR1121.2 PU1100.11
N20135040: PC1122.1 PC1124.1 PR1133.1 PR1138.1 PU1100.16
N20135043: PC1229.1 PR1139.1 PU1100.17
N20135074: PC1121.1 PR1125.2
N20135091: PC1118.1 PR1123.2
N20135096: PL1103.3 PR1124.2 PR1126.2
N20135098: PL1103.2 PR1128.2
N20135126: PH1101.2 PR1120.2 PR1121.1
N20135134: PC1123.1 PR1129.2 PR1133.2 PR1134.1 PR1135.1 PU1100.18
N20135137: PC1122.2 PR1129.1
N20135139: PC1233.1 PR1135.2
N20135141: PC1123.2 PC1228.2 PR1130.1 PU1100.19
N20135144: PC1228.1 PR1134.2
N20135171: PH1102.1 PR1131.2
N20135184: PL1102.3 PR1104.2 PR1108.2
N20135197: PC1109.1 PR1107.2
N20135212: PC1108.1 PR1103.2
N20135219: PL1102.2 PR1110.2
N20135248: PU1100.39 PU1100.40
N20135251: PR1140.1 PU1100.36 PU1100.37 PU1100.38
N20135257: PR1101.2 PU1100.1
N20135258: PR1111.2 PU1100.2
N20135263: PR1105.2 PU1100.34
N20135264: PR1106.2 PU1100.32 PU1100.33
N20750654: CC14.1 DZ4.2 RC103.2 RC192.1 UC6.2
N21194767: PR1401.2 PU1400.9
N21194773: PC1405.1 PR1405.2 PU1400.15
N21195175: PR1409.1 PR1410.2
N23700319: PD4.2 PL2.1 PQ6.1 PR6.2
N26505655: PR604.2 PR607.2 PR625.1
N26505677: PR605.2 PR609.2 PR626.1
N26506002: PR616.2 PU602.40
N26506037: PR612.2 PU602.39
N26506689: PR678.2 PU602.38
N26508248: PC603.1 PR602.1 PU602.34
N26508256: PC604.1 PR603.1 PU602.33
N26509112: PR608.1 PU602.32
N26509117: PR611.1 PU602.31
N26518420: PC630.1 PR640.1 PU602.20
N26519264: PH605.1 PR657.2
N26522108: PC639.2 PR645.1
N26523008: PC647.2 PR650.2
N26523611: PC629.2 PR639.1
N26526626: PC627.1 PR632.2
N26527807: PH602.1 PR628.2
N26528911: PC627.2 PR638.2 PU602.8
N26532119: PC621.2 PR623.1
N26532121: PR621.2 PR622.2 PR623.2 PU602.5
N26533060: PC616.2 PR617.2 PU602.4
N26533062: PC614.2 PR617.1
N26533293: PR610.2 PU602.3
N26533871: PC613.2 PR613.2 PU602.2
N26535263: PL603.3 PR661.1
N26554964: PC617.2 PR621.1
N26566701: PC631.1 PR630.2
N26570644: PC630.2 PR644.1
N27286345: PD704.1 PR743.2
N28424999: TP30.1(TP-1) UC1.AW71
N28425002: TP31.1(TP-1) UC1.AW70
N28483977: PQ1.2 PR2.1 PR12.2 PR13.2
N28483985: PQ1.3 PR5.2
N28484391: PC16.1 PQ2.3 PR28.2
N28484395: PC16.2 PQ2.2 PR29.1
N28484412: PQ2.5 PR31.1 PR33.2
N28484439: PC14.2 PQ3.2 PR32.1
N28484451: PQ1.5 PQ1.6 PR7.1 PR10.2
N28712229: PC671.2 PU605.5
N28712232: PR672.2 PU605.3
N28712235: PC671.1 PR672.1
N28714500: PR769.2 PU703.3
N28714504: PR770.2 PU703.4
N28714507: PC744.2 PQ709.3 PQ718.1 PQ718.2 PQ718.3 PQ740.1 PQ740.2 PQ740.3 PR737.1 PR763.1
N28714524: PC750.1 PU703.27
N28714534: PC752.2 PR754.1
N28714559: PR774.2 PU703.6
N28714562: PR775.2 PU703.7
N28714564: PC721.1 PR771.2
N28714572: PC757.2 PR743.1 PU703.18
N28714582: PR755.2 PU703.12
N28714583: PC708.1 PR776.1 PU703.14
N28714585: PC708.2 PR742.1 PU703.15
N28714598: PC747.1 PR740.2 PU703.31
N28714599: PC747.2 PR772.2 PU703.32
N28714601: PC750.2 PU703.28
N28714604: PR773.1 PU703.25
N28714606: PQ704.4 PR761.2
N28714608: PR745.1 PU703.26
N28714612: PR771.1 PU703.24
N28714614: PR757.2 PU703.17
N28714617: PQ718.5 PR703.1
N28714625: PR757.1 PR779.2
N28714693: PC779.1 PL700.2 PQ717.1 PQ717.2 PQ717.3 PR765.1
N28714721: PR742.2 PR765.2
N28714724: PR765.3 PR776.2
N28714743: PQ709.2 PR737.2 PR738.1
N28714752: PR703.2 PR772.1
N28714753: PR703.3 PR740.1
N28714782: PC767.1 PR766.2
N28714793: PC779.2 PQ717.4 PR773.2
N28714854: PC655.2 PU603.5
N28714856: PR660.2 PU603.3
N28714858: PC655.1 PR660.1
N28714964: PR659.1 PU603.1
N28718522: PC611.2 PU606.2
N28718526: PC611.1 PR619.1
N28810503: CZ10.1 UZ3.12
N28810563: CZ11.1 UZ3.10
N28842863: CC56.1 UC1.AL1
N28843886: CC69.1 UC1.BB10
N28856399: TP19.1(TP-1) UC1.BA70
N28856402: TP20.1(TP-1) UC1.BA68
N28857231: TP21.1(TP-1) UC1.BB68
N28857234: TP22.1(TP-1) UC1.BB69
N28857237: TP23.1(TP-1) UC1.AK13
N28857240: TP24.1(TP-1) UC1.AK12
N28861827: RC138.1 UC1.C64
N28938912: CC2.2 RC21.1
N29189918: PR764.2 PU703.13
N29207759: PH601.2 PR610.1 PR631.2
N29270847: PH603.2 PR635.1 PR647.2
N29708599: TP25.1(TP-1) UC1.AU5
N29708601: TP26.1(TP-1) UC1.AT5
N32012960: PQ601.8 PU606.5
N32012964: PQ601.1 PU606.1
N32015249: PR679.1 PU606.7
N32433695: RV120.1 UV14.J13
N32433703: RV116.1 UV14.J1
N32433714: RV118.1 UV14.J10
N32434049: RV121.1 UV15.J13
N32434050: RV117.1 UV15.J1
N32434053: RV119.1 UV15.J10
N32437553: RV123.1 UV12.J13
N32437559: RV132.1 UV13.J13
N32437560: RV131.1 UV13.J1
N32437563: RV133.1 UV13.J10
N32778757: PR671.1 PU605.1
N32842463: RC137.2 UC1.U11 UC1.U12
N33124395: PC204.2 PR210.1 PU200.12
N33124472: PC207.2 PR203.1
N33188643: CA31.1 RA23.2 RA24.1
N36085760: PD6.1 PR11.2
N37640332: RV2.2 UV1.N10
N37640410: RV3.1 UV1.AA22
N37828209: RV1.1 UV1.Y22
N38038746: CV96.1 RV36.2 RV37.2
N38038992: CV98.2 UV1.K8
N38038994: CV99.2 UV1.L7
N38038995: CV98.1 RV40.2
N38038996: CV99.1 RV41.2
N38349725: RV39.2 UV1.K25
N38996077: RV134.1 UV12.J1
N38996080: RV135.1 UV12.J10
N39282118: PC501.1 PJP501.2 PU500.8 PU500.9 PU500.10
N39282176: PC504.1 PR506.2
N39282188: PR503.1 PR504.2
N40598435: PC102.1 PR100.2
N40598492: PC119.1 PU102.16 PU102.17
N40598500: PC114.1 PR111.2
N40598503: PC113.2 PR108.1
N40598539: PC127.2 PR117.1
N40598619: PD102.1 PR116.2
N40605947: PC305.1 PR303.2 PU300.15
N40606056: PR308.1 PR309.2
N40664383: JDIMM1.165 TP41.1(TP-1)
N40665360: JDIMM2.165 TP42.1(TP-1)
N40665398: JDIMM2.162 TP43.1(TP-1)
N41321201: PC790.1 PQ721.2 PR790.2
N41527020: JDIMM1.162 TP40.1(TP-1)
N124752685: CD30.2 RD11.1
N124753277: CD59.2 RD22.1
N233927670: PR620.2 PU602.1

Pads without a net: FD1 1; FD2 1; FD3 1; FD4 1; JDIMM1 87 88 91 92 95 97 100 101 104 105; JDIMM2 87 88 91 92 95 97 100 101 104 105; JEDP1 5; JHDD1 9; JHDMI1 13 14; JIOB1 11; JKB1 2 3; JKBBL1 3; JLAN1 4 5 7 8; JPWR1 4; JSSD1 17; JWLAN1 6 8 9 11 12 13 14 15 16 17 19 20 21 22 23 24 26 28 32 34 38 40 47 50 51 52 53 54 56 57 58 59 60 62 63 65; PD3 3; PD4 3; PJPDC1 4; PU100 10 15; PU102 10; PU300 9 10 12; PU500 1 4 7; PU602 13; PU603 4 9; PU605 4 9; PU800 1 5; PU1100 35; PU1400 10 12; RP1 4 5; RP2 4 5; UA1 11 12 14 15 23 24 48; UC1 A3 A4 A6 A11 A23 A26 A27 A29 A31 A33 A36 A38 A40 A45 A47 A50 A52 A65 A69 AB1 AB4 AB11 AB12 AB13 AB62 AC1 AC2 AC3 AD1 AD2 AD9 AD10 AD11 AD12 AE62 AF11 AF12 AF13 AG1 AG2 AG62 AH7 AH8 AH9 AH10 AH11 AH12 AK6 AK7 AK9 AK10 AL25 AL27 AM1 AM2 AM3 AM4 AN1 AN2 AN3 AN5 AN8 AN11 AN13 AP1 AP2 AP3 AP4 AP7 AP11 AP13 AP56 AR56 AT15 AU1 AU2 AU7 AU8 AU56 AW1 AW9 AW17 AW20 AW48 AW68 AW69 AY1 AY2 AY5 AY20 AY21 AY68 B2 B3 B11 B23 B26 B27 B29 B31 B33 B36 B38 B40 B45 B47 B50 B52 B69 B70 BA3 BA4 BA9 BB2 BB4 BB9 C2 C4 C7 C11 C12 C15 C23 C27 C28 C29 C31 C32 C33 C36 C37 C38 C50 C51 C52 C54 C70 C71 D1 D3 D4 D5 D7 D8 D12 D15 D23 D27 D28 D29 D31 D32 D33 D36 D37 D38 D50 D51 D52 D54 D71 E1 E2 E3 E10 E22 E23 E25 E38 E40 E48 E61 F6 F10 F25 F48 F50 F52 F60 F61 F65 G1 G2 G3 G50 G61 G65 H2 H3 H5 H11 H63 J3 J4 J5 J68 J71 K45 K46 L7 M1 M3 M4 N1 N2 N3 N7 N8 N9 N11 N12 P62 U2 U3 U4 U8 U9 V1 V2 V62 W4 W7 W10 W11 W12; UC2 1; UC6 1; UC7 1; UE2 1; UL1 3 6 7 9 10 11 22 24; UV1 AA5 AA6 AA29 AA31 AB23 AB25 AB26 AB27 AB30 AC1 AC3 AC5 AC6 AC16 AC23 AC25 AD2 AD4 AD10 AD11 AD13 AD16 AD22 AD23 AD24 AE1 AE3 AE5 AE6 AE10 AE11 AE13 AE16 AE19 AE22 AE23 AE24 AE25 AE26 AF2 AF4 AF6 AF7 AF8 AF9 AF10 AF11 AF13 AF16 AF17 AF22 AF24 AF25 AG1 AG3 AG5 AG6 AG7 AG8 AG9 AG10 AG11 AG13 AG15 AG16 AG17 AG18 AG19 AG20 AG21 AG22 AG24 AG25 AG26 AH1 AH3 AH5 AH6 AH8 AH12 AH16 AH18 AH20 AH22 AH24 AH26 AJ7 AJ9 AJ13 AJ15 AJ17 AJ19 AJ21 AJ23 AJ25 AK1 AK3 AK5 AK6 AK8 AK10 AK14 AK16 AK18 AK20 AK22 AK24 AK26 AL7 AL13 AL15 AL17 AL19 AL21 AL23 AL25 AM3 AM5 AM6 AM8 AM10 AM12 AM26 J8 J22 J25 K13 K30 L16 L17 L29 L31 M4 M27 M28 M30 N1 N3 N5 N6 N8 N26 N29 N31 P2 P4 P7 P8 P10 P23 P24 P26 P27 P28 P30 R6 R29 R31 T2 T4 T7 T8 T23 T24 T26 T27 T28 T30 U5 U6 U23 U24 U26 U29 U31 V2 V4 V6 V27 V28 V30 W3 W5 W6 W7 W8 W23 W24 W29 W31 Y2 Y4 Y6 Y23 Y24 Y26 Y27 Y28 Y30; UV12 A5 A11 A13 B11 B13 E11 E13 F11 F13 M2 M4 N2 N4 R2 T2 T4 U2 U4 U5; UV13 A5 A11 A13 B11 B13 E11 E13 F11 F13 M2 M4 N2 N4 R2 T2 T4 U2 U4 U5; UV14 A5 A11 A13 B11 B13 E11 E13 F11 F13 M2 M4 N2 N4 R2 T2 T4 U2 U4 U5; UV15 A5 A11 A13 B11 B13 E11 E13 F11 F13 M2 M4 N2 N4 R2 T2 T4 U2 U4 U5; YC1 2 4

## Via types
v1: diameter 0.305, hole 0.152, TOP to BOTTOM, 581 vias
v2: diameter 0.457, hole 0.203, TOP to BOTTOM, 5398 vias
v3: diameter 0.406, hole 0.203, TOP to BOTTOM, 185 vias
v4: diameter 0.508, hole 0.254, TOP to BOTTOM, 58 vias

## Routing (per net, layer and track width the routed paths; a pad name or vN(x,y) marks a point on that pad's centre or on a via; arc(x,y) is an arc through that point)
0.6V_DDR_VTT_ON: length 27.5
  TOP w0.254: v2(93.76,95.28) 93.81,95.24 v3(93.81,94.37) 93.81,81.59 RC9.2 CC90.1 92.34,76.73 92.24,76.63 UC2.4
  BOTTOM w0.254: PR202.1 90.19,97.99 92.89,95.28 v2(93.76,95.28)
1.2V_VTT_PWRGD: length 258.3
  TOP w0.254: v2(85.87,102.32) v3(85.87,100.54) 85.87,100.32 85.62,100.06 76.73,100.06 73.67,97 49.11,97 34.31,82.19 29.36,82.19 28.79,81.62 v2(28.7,81.62)
  IN3 w0.142: v2(126.17,23.42) 126.17,20.87 127.79,19.25 127.79,15.93 121.96,10.1 121.66,10.1 120.49,8.93 115.19,8.93 110.97,4.71 110.74,4.71 109.39,3.35 55.47,3.35 54.75,4.07 48.64,4.07 40.81,11.89 40.81,17.22 37.07,20.97 37.07,28.03 33.6,31.49 28.7,31.49 25.82,34.37 25.82,38.67 27.11,39.97 27.11,54.11 25.6,55.63 25.6,59.6 28.03,62.02 28.03,64.52 27.66,64.89 27.66,78.93 28.7,79.97 v2(28.7,81.62)
  BOTTOM w0.102: v2(126.17,23.42) 126.68,22.91 127.29,22.91 128.52,24.14 RC106.1
  BOTTOM w0.203: PR209.2 85.74,102.2 v2(85.87,102.32) 86.31,102.76 86.93,102.76 87.13,102.96 PU200.10
2.5V_VIN: length 1.8
  BOTTOM w0.102: 56.28,4.31 v1(56.28,2.56)
3V_FB: length 3.5
  BOTTOM w0.254: PU100.13 175.57,40.41 176.17,39.81 PR110.1 PC113.1 174.41,39.6 PR109.2
3V_SN: length 0.8
  TOP w0.102: 166.2,42.94 v1(165.36,42.94)
3V_VIN: length 0.7
  TOP w0.102: 175.79,45.45 v1(175.11,45.45)
  vias: v2(175.91,46.37) v2(175.91,45.74) v2(175.91,45.11) v2(178.12,44.79) v2(178.71,44.79)
5V_FB: length 3.5
  BOTTOM w0.254: PU102.13 178.26,29.41 178.22,29.37 ; 178.22,29.37 PC127.1 PR118.1 ; 178.22,29.37 PR115.2
5V_SN: length 2.8
  TOP w0.102: v1(173.18,29.69) PC125.1
  TOP w0.508: PR112.2 173.18,31.77 PC125.1
5V_VIN:
  vias: v2(178.33,36.16) v2(178.83,36.53) v2(178.83,35.77) v2(178.83,35.01) v2(180.62,36.47) v2(180.62,35.7) v2(180.62,34.94) v3(178.24,35.21)
+0.6V_DDR_VTT: length 151.5
  TOP w1.016: 40.6,21.68 39.52,22.76 39.52,28.79 38.06,30.25 38.06,56.66 31.92,62.79 31.92,70.86 38.06,76.99 38.06,84.54 49.52,96.01 74.08,96.01 77.12,99.05 89.96,99.05 92.47,101.55 93.81,101.55
  IN2 w1.016: 58.95,16.47 49.93,16.47 47.64,18.76 44,18.76 43.01,19.75 43.01,20.41
  BOTTOM w0.305: JDIMM2.258 43.12,21.38 v2(43.08,21.41)
  vias: v2(42.69,21.8) v2(58.76,17.55) v2(59.33,17.55) v2(94.76,102) v2(94.76,101.41) v3(57.68,18.61)
+0.6VSP:
  vias: v3(94.76,105.59)
+0.95VSDGPU: length 16.2
  TOP w0.508: 113.18,95.97 113.94,95.2 121.68,95.2 123.1,96.61 LV8.1 ; RV30.2 101.66,108.64 v2(100.67,107.65)
  vias: v2(109.04,126.73) v2(109.56,96.5) v2(109.99,126.73) v2(109.99,125.84) v2(110.19,96.5) v2(110.78,96.5) v3(109.98,122.64)
+0.95VSDGPU_ON: length 3.5
  BOTTOM w0.102: v1(117.93,94.32) CZ15.2
  BOTTOM w0.203: RZ7.2 116.81,92.48 116.75,92.42 UZ5.3
  BOTTOM w0.508: CZ15.2 RZ7.2
+0.95VSDGPU_OUT:
  vias: v1(113.37,94.24)
+1.0V_AMPHYPLL: length 12.2
  TOP w0.508: v2(130.7,27.61) 130.7,27.65 129.18,29.17 129.18,29.55 127.63,31.1 125.89,31.1 125.3,31.69 125.3,32.51 124.5,33.31 122.3,33.31 121.81,33.8
  vias: v1(117.9,35.67) v2(117.85,36.17)
+1.0V_APLL: length 27.6
  TOP w0.508: L1.2 132.8,44.18 CC83.1 131.81,44.18 131.08,43.45 v1(131.08,43.29) v2(131.08,42.45)
  IN2 w0.254: v2(131.08,42.45) 131.08,42.35 130.51,41.78 130.51,39.26 129.24,37.99 127.45,37.99 127.45,37.99 124.74,37.99 122.52,35.77 118.88,35.77 118.86,35.79 118.32,35.79 118.17,35.64 117.39,35.64 117.23,35.81 114.21,35.81 113.86,36.16 113.86,36.55 v2(113.43,36.98)
  BOTTOM w0.254: UC1.V15 113.53,36.98 v2(113.43,36.98)
+1.0V_APLLEBB: length 13.6
  IN2 w0.508: 116.73,39.71 116.73,39.39 115.99,38.65 v2(115.99,38.28) ; 117.11,41.67 117.12,41.68 117.84,41.68 118.89,42.73 118.89,43.39
  BOTTOM w0.254: v2(115.99,38.28) 116.36,38.57 UC1.N18
  BOTTOM w0.508: RC162.1 131.22,44.01 CC63.1 v1(129.1,44.01) 128.5,44.01 127.72,44.79 125.81,44.79 124.93,43.9 v2(123.72,43.9)
+1.0V_CLK2: length 22
  TOP w0.102: v1(137.74,41.63) CC76.1
  TOP w0.508: v2(136.53,40.93) CC76.1 135.4,41.63 RC170.1
  IN2 w0.508: 122,38.33 122.59,38.33 124,39.74 126.58,39.74 126.79,39.95 127.52,39.95 131.72,44.15 133.31,44.15 v2(136.53,40.93)
  BOTTOM w0.254: UC1.K19 118.42,38.88 v2(118.49,38.88)
+1.0V_CLK4: length 25.5
  TOP w0.102: v2(116.74,38.31) v1(116.38,37.95)
  IN2 w0.254: v2(116.74,38.31) 117.31,38.88 117.61,38.88 118.08,39.35 118.08,40.09 118.36,40.37 118.76,40.37 118.84,40.29 120.11,40.29 120.16,40.33 120.93,40.33 121.32,40.72 122.31,40.72 126.64,45.05 132.23,45.05 132.67,45.48 v2(132.67,45.51)
  BOTTOM w0.254: v2(116.74,38.31) 116.74,39.53 UC1.N20
  BOTTOM w0.381: v2(132.67,45.51) 134.01,44.16 CC84.1 134.08,44.26 135.05,45.23 RC173.1
+1.0V_CLK5: length 32.3
  TOP w0.508: RC171.1 135.26,45.07 CC77.1 134.11,45.08 133.92,44.89 132.43,44.89 131.95,45.37 v3(131.57,45.37) 129.37,45.37 128.86,45.88 128.86,49.89 v2(128.76,49.99)
  IN2 w0.508: v2(128.76,49.99) 128.76,49.93 128.8,49.89 128.8,47.92 123.25,42.37 119.5,42.37 117.6,40.46 117.6,39.55 v2(117.59,39.55)
  BOTTOM w0.254: UC1.L19 117.48,39.55 v2(117.59,39.55)
  BOTTOM w0.508: RC76.2 127.87,50.88 v2(128.76,49.99)
+1.0V_MPHYGT:
  vias: v2(115.08,36.35) v2(115.99,37.65) v2(115.99,36.98) v2(116.82,36.29) v2(124.92,30.33) v2(124.92,29.74) v2(125.56,30.2) v2(125.56,29.61) v3(115.77,35.59)
+1.0V_PRIM: length 294.8
  TOP w0.508: CC57.1 110.46,39.06 110.57,38.95 v2(110.88,38.95) ; CE17.1 155.87,18.13 v2(155.66,17.93) ; v2(117.68,28.22) 117.65,28.26 CC72.1 116.85,28.27 CC87.1 v2(115.33,28.27)
  IN2 w0.508: v2(155.66,17.93) 155.4,18.18 155.4,19.2 153.68,20.92 152.71,20.92 152.41,20.62 148.14,20.62 147.42,21.35 147.04,21.72 146.63,21.72 146.6,21.74 144.04,21.74 142.96,20.66 142.96,19.9 142.45,19.39 141.37,19.39 140.86,18.88 140.86,17.37 141.22,17.01 142.56,17.01 142.92,16.65 142.92,14.88 142.41,14.37 140.68,14.37 140.36,14.05 134.7,14.05 133.37,12.72
  IN2 w2.54: 131.47,10.43 128.16,7.13 121.5,7.13 ; 112.92,93.62 110.38,93.62 107.78,91.02 77.74,91.02 76.37,92.39 44.74,92.39 36.15,83.81 36.15,32.95 39.07,30.03 39.07,15.81 43.74,11.14 45.74,11.14 45.83,11.04 45.91,11.04 46.64,10.31 57.12,10.31 63.32,4.11 102.76,4.11 103.13,4.48 ; 109.37,4.97 110.18,4.97 110.79,5.58 110.94,5.58 110.97,5.61 114.37,5.61
  BOTTOM w0.203: UC1.A10 123.43,34.14 v2(123.97,34.14) ; v2(155.66,17.93) 155.64,17.91 155.36,17.91 154.88,18.39 154.88,18.92 155.14,19.18 UE1.95 ; UC1.A14 123.17,36.32 124.08,36.32 v2(124.29,36.54) ; v2(115.33,28.27) 115.32,28.28 UC1.T1
  BOTTOM w0.254: v2(116.79,41.05) 117.2,40.64 UC1.L21 ; v2(117.66,38.29) 117.99,37.96 UC1.K17 ; UC1.AB19 112.46,38.97 112.55,38.97 v2(112.55,38.97) 112.65,38.97 UC1.Y18 v2(112.55,38.26) UC1.AB17 ; UC1.AB20 112.49,40.23 v2(112.54,40.23) ; UC1.AF18 110.54,38.61 v2(110.88,38.95) ; v2(108.4,40.26) 108.05,39.91 UC1.AK20 ; UC1.P18 115.41,38.61 v2(115.08,38.94) ; v2(114.28,40.22) UC1.V20 ; v2(114.27,40.81) UC1.V21 ; UC1.L1 117.98,28.49 117.71,28.22 v2(117.68,28.22) ; UC1.AF19 110.81,39.58 v2(110.86,39.58)
  BOTTOM w0.508: 135.44,42.93 135.43,42.92 133.71,42.92 RC162.2 132.8,44.44 132.14,45.1 RC161.2
  vias: v2(116.22,94.26) v2(116.22,93.67) v2(116.81,94.26) v2(116.81,93.67) v2(117.39,94.26) v2(129.82,12.28) v2(129.81,11.7) v2(130.3,12) v2(133.73,26.19) v2(134.12,26.58) v2(134.53,26.96) v2(134.91,27.38) v2(135.3,27.77) v2(136.61,44.3) v2(136.61,43.71) v2(136.61,43.08) v2(136.61,42.51) v2(137.18,44.91) v2(137.24,44.3) v2(137.24,43.71) v2(137.24,43.08) v2(137.24,42.51) v2(137.62,45.38) v2(137.75,44.72) v3(113.33,40.18)
+1.0V_SRAM: length 27.7
  TOP w0.508: CC62.1 110.21,40.92 110.87,40.26 110.87,40.26 v2(110.87,40.26)
  IN1 w0.508: 113.49,40.91 111.67,40.91 111.01,40.26 v2(110.87,40.26) ; 113.49,40.91 114.21,41.63 118.8,41.63 119.53,42.36 121.97,42.36 122.78,43.17 122.78,44.56 123.25,45.03 124,45.03 v2(124.23,45.25) ; 113.49,40.91 113.49,40.1 114,39.59 v2(114.28,39.59)
  BOTTOM w0.254: UC1.AF21 110.57,40.56 v2(110.87,40.26) 110.52,39.91 UC1.AF20 ; UC1.T19 114.6,39.26 v2(114.28,39.59) 114.32,39.59 114.65,39.91 UC1.T20
  BOTTOM w0.508: RC161.1 128.57,45.1 128.06,45.61 v1(126.54,45.61) 124.59,45.61 v2(124.23,45.25)
+1.0V_VCCST: length 143.9
  TOP w0.457: 123.97,37.74 v2(123.97,38.82) 123.4,39.39 121.66,39.39
  TOP w0.508: 123.97,37.74 125.44,36.27 128.6,36.27 130.26,37.93 131.4,37.93 CC41.1 CC44.1 ; v2(127.15,63.78) 129.76,63.78 v2(130.27,64.29) ; v2(137.18,39.33) 137.18,39.13 137.17,39.12 137.17,38.93 v3(136.81,38.58) 136.7,38.47 RZ4.2
  IN1 w0.508: v2(170.36,48.7) 169.4,47.74 168.55,47.74 168.33,47.96 163.04,47.96 162.53,47.45 162.53,47.08 162.02,46.57 159.86,46.57 155.79,42.5 154.58,42.5 154.07,41.99 154.07,41.45 152.65,40.03 147.74,40.03 146.78,39.07 145.05,39.07 144.47,39.65 138.31,39.65 137.99,39.33 v2(137.18,39.33)
  IN2 w0.508: v2(127.15,63.78) 127.82,63.1 127.82,58.08 v2(127.1,57.36)
  IN3 w0.508: v2(130.27,65.81) v2(130.27,64.29) 130.27,64.28 130.64,63.9 130.64,61.24 131.27,60.6 131.27,58.04 130.64,57.41 130.64,52.69 131.15,52.18 134.62,52.18 136.87,49.93 152.23,49.93 153.69,48.47 158.96,48.47 159.47,47.96 159.47,47.26 160.1,46.63 168.29,46.63 v2(170.36,48.7)
  BOTTOM w0.203: v2(123.97,38.82) 123.8,38.82 123.8,38.82 UC1.A18
  BOTTOM w0.254: UC1.K20 118.54,39.91 v2(118.56,39.89) 118.56,39.91 118.56,39.92 118.56,40.04 UC1.K21
  BOTTOM w0.508: v2(130.27,64.29) 129.76,64.79 RC152.1 ; PR605.1 PR604.1 PR601.1 165.99,48.87 166.01,48.86 166.6,48.86 166.61,48.85 PC602.1 167.2,49.03 167.77,49.6 169.84,49.6 170.36,49.08 v2(170.36,48.7) ; v2(127.1,57.36) 126.32,56.58 126.32,55.85 127.72,54.45 RC104.2 ; RC154.1 128.06,65.92 RC138.2 129.19,65.92 129.3,65.81 v2(130.27,65.81) ; v2(127.15,63.78) 127.48,63.45 RC111.1 127.51,63.02 RC112.1
+1.0V_VCCST_C: length 0.9
  TOP w0.102: 131.5,36.02 v1(130.6,36.02)
+1.0V_VCCSTG: length 82.2
  TOP w0.508: 129.81,29.81 128.41,31.22 128.41,31.99 128.42,32 128.42,32.2 v2(128.35,32.26) ; CC42.1 121.16,41.79 121.45,42.08 122.45,42.08 122.92,41.61 v2(124.23,41.61) 124.23,42.85 125.62,44.25 128.16,44.25 ; v2(127.65,50.06) 128.16,49.55 128.16,44.25 ; RZ4.1 135.13,40.22 134.63,40.73 131.87,40.73 v2(131.37,41.23) 131.18,41.23 128.16,44.25 ; v2(129.84,61.11) 130.24,61.11 130.96,61.82 130.96,66.65 v2(130.27,67.34) 128.42,67.34 126.07,64.98 120.59,64.98 119.08,63.47 RC141.2
  IN2 w0.254: v2(119.75,39.81) 119.74,39.81 119.74,39.81 119.76,39.79 119.76,39.62 120.02,39.37 120.78,39.37 120.81,39.4 122.26,39.4 124.23,41.36 v2(124.23,41.61)
  IN3 w0.508: v2(127.65,50.06) 127.65,50.5 128.92,51.77 128.92,53.7 129.26,54.04 129.26,57.62 129.85,58.21 v2(129.85,58.29) 130.11,58.29 130.64,58.82 130.64,60.31 v2(129.84,61.11)
  BOTTOM w0.203: UC1.A22 123.24,41.29 123.27,41.3 123.52,41.55 124.17,41.55 v2(124.23,41.61)
  BOTTOM w0.254: v2(119.75,39.81) 119.74,39.81 119.74,39.72 UC1.G20
  BOTTOM w0.508: RC140.2 v2(129.84,61.11) ; v2(130.27,67.34) 129.9,67.71 RC113.1 ; v2(129.85,58.29) 129.32,58.29 129.06,58.55 RC142.2 ; v2(128.35,32.26) 128.69,32.59 129.28,32.59 129.79,33.1 129.79,38.73 130.45,39.39 130.45,40.31 v2(131.37,41.23)
  vias: v3(132.18,26.82)
+1.0V_XDP: length 2.6
  BOTTOM w0.102: v1(134.09,22.51) 133.81,22.23 RC149.2
  BOTTOM w0.508: RC149.2 132.54,22.5 131.82,22.5 RC143.1
+1.0VS_VCCIO: length 28.6
  TOP w0.508: v2(121.05,58.1) 121.02,58.13 RC4.1 ; v2(106.9,52.67) 106.94,52.71 CC49.1 106.94,53.72 CC50.1
  IN1 w0.508: v2(121.05,58.1) 120.77,58.1 120.35,57.68 120.35,56.79 119.91,56.35 119.46,56.35 119.08,55.97 119.08,46.88 116.74,44.54 109.56,44.54 109.03,45.06 v2(108.63,45.06)
  BOTTOM w0.254: v2(106.9,52.67) 106.9,52.54 UC1.AM42 107.67,51.77 UC1.AL42 v2(108.4,51.77)
  vias: v2(103.46,27.29) v2(104.09,27.88) v2(104.09,27.29) v2(104.68,27.88) v2(104.68,27.29) v2(106.88,46.28) v2(108.63,45.67) v2(128.21,25.83) v2(128.34,26.38) v2(128.77,25.84) v2(128.9,26.39) v2(129.32,25.85) v3(104.27,25.04)
+1.2V_DDR: length 137.4
  BOTTOM w0.152: UC1.BB23 101.03,41.38 101.01,41.38 100.16,41.38 v2(99.95,41.16) ; UC1.BB41 100.35,51.32
  BOTTOM w0.178: v2(100.23,54.93) 100.3,54.97 100.65,54.97 UC1.BB47 ; v2(99.23,46.24) 100.15,46.24 100.27,46.35 101.04,46.35 101.06,46.36 UC1.BB32
  BOTTOM w0.203: UC1.BB51 100.55,57.43 100.39,57.28 v2(100.14,57.28) ; v2(106.93,41.64) 107.62,41.64 UC1.AL23
  BOTTOM w0.254: 100.35,51.32 99.5,51.32 v2(99.43,51.39) ; v2(104.28,45.39) 103.96,45.08 UC1.AU28 ; v2(104.24,49.02) 104.24,49.02 103.96,48.74 UC1.AU35 ; v2(104.33,42.62) 104.25,42.61 UC1.AU23 ; v2(106.96,51.74) 107.21,51.49 UC1.AM40 ; v2(103.58,52.69) 103.58,52.53 103.89,52.23 UC1.AU42
  BOTTOM w0.305: JDIMM1.124 58.08,56.38 v2(57.81,56.64) ; v2(42.76,56.16) 42.76,56.37 43.27,56.87 JDIMM2.124 ; JDIMM2.199 54.24,36.12 54.84,36.72 v2(54.84,37.08) ; v2(54.65,49.2) 54.58,49.12 JDIMM2.147 ; JDIMM1.142 57.94,51.87 v2(57.78,51.87) ; v2(56.86,74.85) 57.84,73.88 JDIMM1.54 ; JDIMM1.148 57.65,48.38 57.17,48.86 v2(57.17,48.98) ; JDIMM1.123 68.61,56.62 69.72,55.52 v2(69.72,55.18) 69.67,55.13 69.67,54.97 69.37,54.67 68.75,54.67 68.3,55.13 JDIMM1.129 ; v2(55.99,46.87) 55.99,45.77 55.34,45.12 JDIMM2.163 ; JDIMM2.112 43.65,59.87 43.35,60.18 v2(43.35,60.3) ; JDIMM1.12 57.89,84.37 57.19,83.67 v2(57.19,82.96) ; v2(54.52,58.18) 54.08,58.62 JDIMM2.117 ; v2(55.07,24) 55.07,25.21 54.65,25.63 JDIMM2.241 ; JDIMM1.136 57.76,53.38 57.28,53.85 v2(57.28,55.09) ; JDIMM2.153 53.98,47.62 54.51,47.09 v2(54.51,46.87) ; JDIMM1.178 56.32,40.87 56.02,40.57 v2(56.02,40.09) ; JDIMM1.135 68.17,53.62 68.57,53.22 v2(68.57,52.02) 68.47,52.13 JDIMM1.141 ; JDIMM1.160 57.96,45.38 56.66,46.67 v2(56.66,46.89) 56.66,47.01 57.11,47.46 57.63,47.46 57.89,47.2 58.06,47.03 58.06,46.95 58.13,46.87 JDIMM1.154 ; JDIMM2.12 43.39,84.88 42.91,84.39 v2(42.91,83.68) ; JDIMM2.135 54.43,54.12 54.44,54.12 v2(54.98,54.12) ; JDIMM2.96 43.64,63.87 v2(43.54,63.78) ; v2(43.35,56.16) 43.35,55.68 43.65,55.38 JDIMM2.130 ; JDIMM2.123 54.39,57.13 55.11,57.84 v2(55.11,58.18) ; JDIMM1.159 68.37,45.63 v2(68.71,45.28) 68.71,45.06 68.28,44.63 JDIMM1.163 ; JDIMM1.112 58.22,59.38 58.07,59.52 57.55,59.52 57.13,59.1 v2(57.13,58.95) ; v2(57.84,55.08) 58.05,54.87 JDIMM1.130 ; v2(55.3,46.87) 55.3,46.66 54.77,46.12 JDIMM2.159 ; JDIMM1.199 68.84,35.63 69.16,35.94 v2(69.16,36.65) ; JDIMM2.33 54.28,79.62 54.28,79.62 v2(54.37,79.62) ; v2(43.35,58.14) 43.58,58.38 JDIMM2.118 ; JDIMM1.33 68.22,79.13 68.23,79.12 68.88,79.12 69.32,79.56 v2(69.32,79.65) ; v2(68.48,47.12) 68.43,47.12 68.43,47.13 JDIMM1.153 ; JDIMM1.96 57.79,63.38 v2(57.12,62.7) ; JDIMM2.54 v2(43.52,74.38) ; v2(69.42,57.97) 69.42,58.19 69.11,58.51 68.47,58.51 68.09,58.13 JDIMM1.117 ; JDIMM1.147 68.52,48.62 69.05,48.1 v2(69.05,47.14) ; v2(69.16,25.85) 69.16,25.73 68.55,25.13 JDIMM1.241 ; v2(57.77,57.88) JDIMM1.118 ; v2(54.52,56.16) 53.99,55.62 JDIMM2.129 ; JDIMM1.220 57.43,30.38 56.75,29.69 v2(56.75,29.26) ; v2(43.35,47.26) 43.46,47.38 JDIMM2.154 ; v2(69.22,67.03) 69.22,68.14 68.73,68.62 JDIMM1.75 ; JDIMM2.148 v2(43.48,48.87) ; JDIMM2.178 v2(43.57,41.38) ; v2(54.52,60.3) 54.35,60.13 JDIMM2.111 ; JDIMM2.75 54.17,69.13 54.86,68.44 v2(54.86,67.86) ; v2(55.78,54.02) 54.38,52.62 JDIMM2.141 ; JDIMM2.220 v2(43.55,30.87) ; v2(42.76,47.26) 42.76,46.5 43.38,45.87 JDIMM2.160 ; JDIMM1.111 68.75,59.62 69.98,58.39 v2(69.98,57.97) ; JDIMM2.136 44.84,53.87 43.9,53.87 v2(43.64,53.61) ; JDIMM2.142 v2(43.5,52.38)
  vias: v2(63.65,101.12) v2(63.9,100.59) v2(64.23,101.12) v2(64.48,100.59) v2(64.62,88.48) v2(64.81,101.12) v2(64.85,87.91) v2(65.07,100.59) v2(65.18,88.48) v2(65.4,101.12) v2(65.44,87.95) v2(65.65,100.59) v2(65.77,88.48) v2(65.98,101.12) v2(66.02,87.95) v2(66.24,100.59) v2(66.35,88.48) v2(66.57,101.12) v2(66.6,87.95) v2(66.82,100.59) v2(66.93,88.48) v2(67.19,87.95) v2(67.52,88.48) v2(67.77,87.95) v3(86.95,44.85)
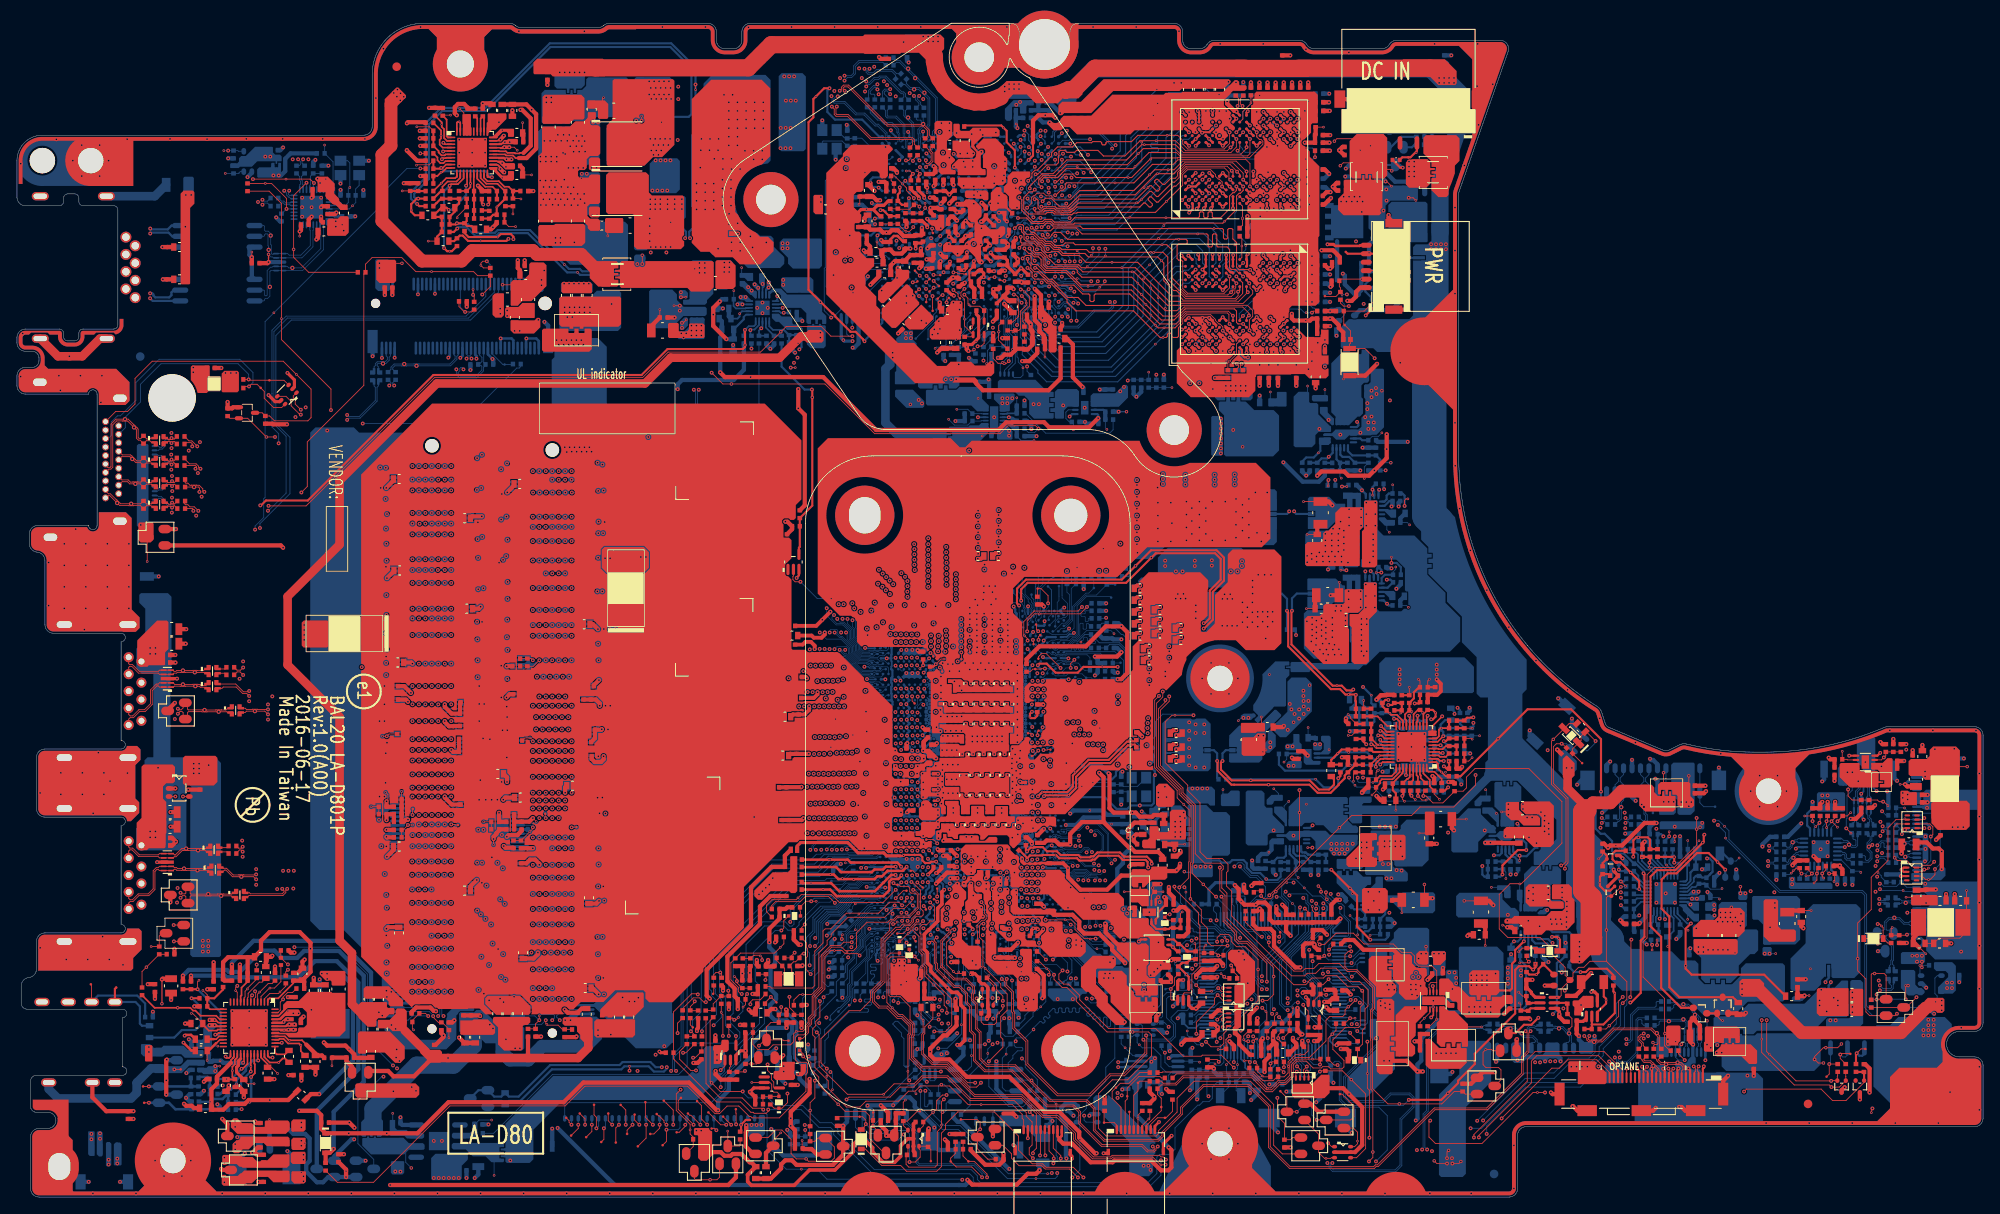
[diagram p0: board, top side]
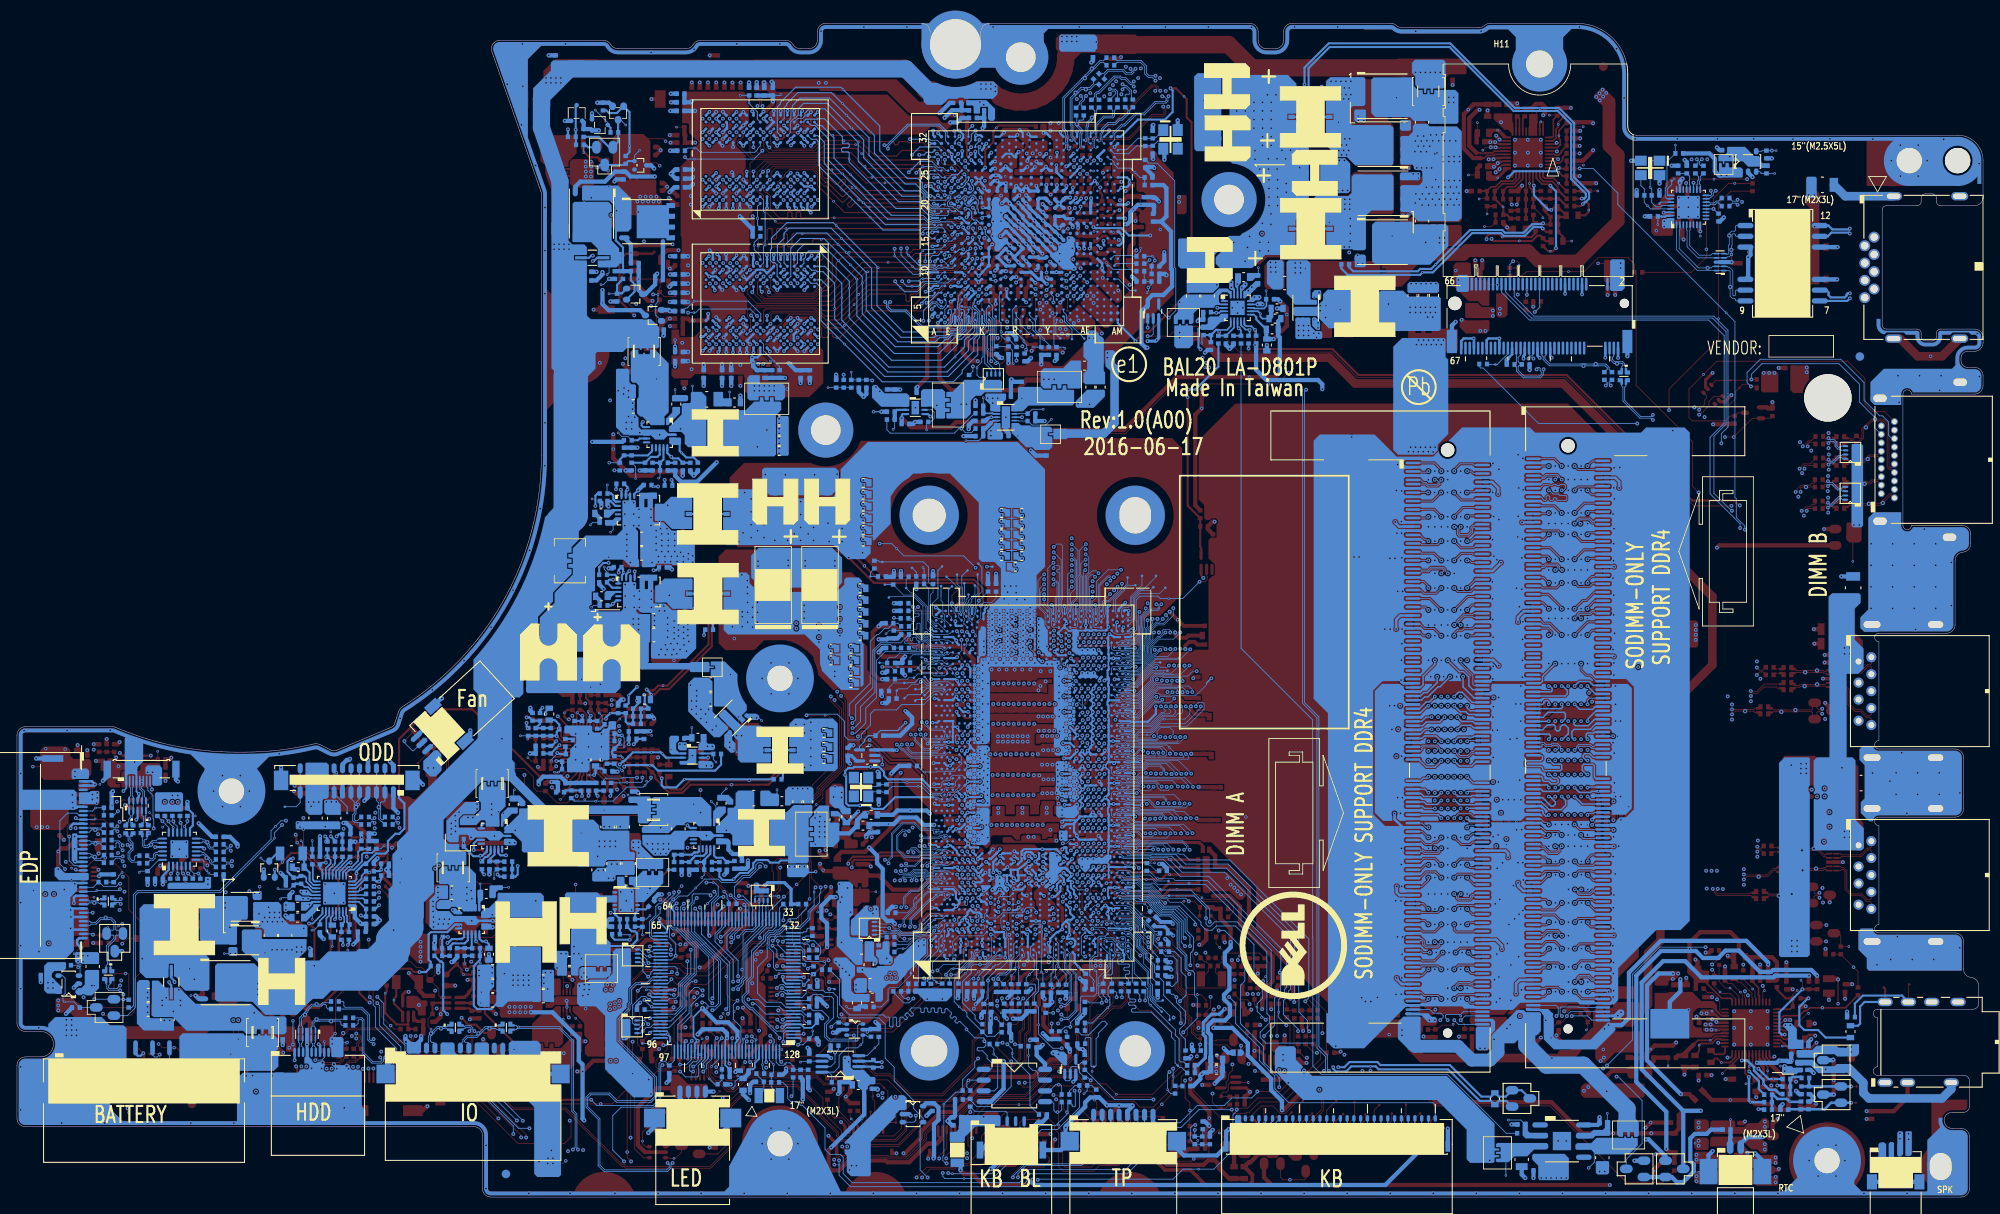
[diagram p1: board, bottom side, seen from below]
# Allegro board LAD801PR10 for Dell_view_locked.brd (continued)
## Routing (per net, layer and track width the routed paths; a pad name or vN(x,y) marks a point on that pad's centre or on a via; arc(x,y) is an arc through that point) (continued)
+1.2VP: length 63.1
  IN2 w0.254: v2(66.35,104.38) 66.35,102.41 69.87,98.89 70.05,98.89 70.11,98.83 90.01,98.83 91.3,100.12 92.19,100.12 v2(92.29,100.03)
  IN2 w0.762: 88.79,106.57 88.79,106.13 89.43,105.49 89.43,102.07 88.67,101.31 86.7,101.31 84.85,99.46 70.37,99.46 67.14,102.7 67.14,103.14
  BOTTOM w0.254: PR207.2 92.35,102.63 92.54,102.44 92.54,100.28 v2(92.29,100.03)
  vias: v2(64.6,104.99) v2(64.6,104.38) v2(64.92,103.83) v2(65.18,104.99) v2(65.18,104.38) v2(65.5,103.84) v2(65.77,104.99) v2(65.77,104.38) v2(66.35,104.99) v2(66.93,104.99) v2(66.93,104.38) v2(67.58,104.99) v2(67.58,104.38) v2(88.66,107.92) v2(88.66,107.34) v3(70.14,105.38)
+1.8V_AVDD: length 7
  TOP w0.203: 34.13,17.99 33.62,18.5 v1(32.16,18.5) 32.06,18.5 31.6,18.96 UA1.40
  TOP w0.508: 34.13,17.99 35.21,16.91 CA12.1 35.97,16.7 RA5.1
+1.8V_CPVDD: length 23.8
  TOP w0.203: UA1.36 29.59,16.67 29.79,16.46 v2(30.15,16.46)
  TOP w0.508: CA13.1 41.69,16.42 CA14.1 39.82,16.42 RA6.2 39.78,16.84 v1(39.18,17.44) 38.75,17.87 36.58,17.87 36.21,18.24 v2(36.2,18.24)
  IN2 w0.508: v2(36.2,18.24) 36.34,18.38 36.34,20.47 34.5,22.31 31.2,22.31 29.46,20.57 29.1,20.57 28.6,20.06 28.6,17.42 29.55,16.46 v2(30.15,16.46)
+1.8V_PRIM: length 302.9
  IN1 w1.016: 114.06,29.11 118.13,29.11 118.22,29.01 118.66,29.01 119.71,27.96 120.24,27.96 121.06,27.14 122.5,27.14 122.81,27.45 122.82,27.45 122.97,27.6 123.69,27.6 123.81,27.48 127.42,27.48 129.2,29.26 130.68,29.26 131.46,30.04 131.46,30.51 131.96,31.02 132.23,31.02 136.22,35.01 137.41,35.01 140.07,37.67 144.35,37.67 144.86,38.18 147.15,38.18 148.11,39.14 153.01,39.14 153.36,39.48 155.39,39.48 155.4,39.48 156.02,39.48 157.63,37.87 157.63,34.43 159.03,33.02 159.85,33.02 160.98,31.88 160.98,28.03 162.64,26.38 162.7,26.38 163.05,26.02
  IN2 w1.016: 116.03,90.07 110.51,90.07 109.11,88.67 71.58,88.67 69.77,90.49 45.52,90.49 38.06,83.02 38.06,33.74 40.98,30.82 40.98,17.69 44.93,13.74 45.93,13.74
  IN3 w1.016: 47.78,11.9 48.92,10.76 49.37,10.76 52.43,7.7 56.08,7.7 56.46,7.31 62.67,7.31 63,6.98 89.14,6.98 89.83,7.67 89.83,8.29 90.9,9.37 99.3,9.37 99.54,9.61 105.12,9.61 106.07,10.56 109.59,10.56 110.61,11.58 110.61,12.87 113.28,15.55 113.28,20.39 112.22,21.45 112.22,23.52
  BOTTOM w0.203: v2(112.7,27.87) 112.61,27.96 112.61,28.79 UC1.AA1
  BOTTOM w0.254: v2(110.91,36.98) UC1.AF16
  vias: v2(46.56,12.98) v2(47.07,12.53) v2(113.11,27.39) v2(117.02,90.41) v2(117.02,89.84) v2(164.67,25.97) v2(165.02,26.45) v2(165.31,25.96) v3(44.39,12.48)
+1.8VALWP: length 8.9
  TOP w0.102: v2(166.2,28.72) v3(166.2,29.56)
  BOTTOM w0.254: PC503.1 PR503.2 159.39,31.37 159,31.37 158.74,31.1 158.74,30.35 159.47,29.62 163.3,29.62
  vias: v2(165.32,28.15) v2(165.63,28.72)
+1.8VGS: length 122.2
  TOP w0.381: 101,116.52 101.48,117.01 102.23,117.01 102.75,117.53 RV11.1 ; 101,116.52 101.79,115.73 RV28.1 ; 101,116.52 99.56,116.52 99.23,116.2 LV2.1
  TOP w0.508: PR1113.1 v2(47.52,125.82) ; LV6.1 115.58,103.77 v2(115.11,103.3) ; LV7.1 120.34,99.59 119.39,98.64 v2(118.57,98.64) ; RV8.1 104.93,115.07 v2(104.93,114.46)
  IN1 w0.508: v2(115.11,103.3) 114.72,103.3 114.21,102.79 114.21,99.76 114.95,99.02 v2(114.95,98.4)
  IN2 w0.508: v2(118.57,98.64) 117.37,99.84 115.46,99.84 114.95,99.33 v2(114.95,98.4)
  IN3 w0.508: v2(102.45,123.9) 102.45,127.21 101.49,128.17 98.19,128.17 97.55,127.53 95.77,127.53 94.76,128.54 94.76,135.25 93.64,136.37 88.16,136.37 85.71,133.91 82.04,133.91 79.73,136.23 62.26,136.23 55.82,129.78 51.52,129.78 47.55,125.82 v2(47.52,125.82)
  BOTTOM w0.254: v2(102.45,123.9) 102.45,123.93 UV1.AM30 ; v2(98.23,113.47) 100.74,113.47 101.6,114.33 104.8,114.33 v2(104.93,114.46)
  BOTTOM w0.508: v2(96.31,108.79) 96.35,108.79 96.49,108.93 RV87.2 97.16,108.91 RV84.2 ; RV81.2 RV82.2 v2(111.09,98.26) ; RV152.2 v2(114.95,98.4)
  BOTTOM w1.016: 108.71,90.09 103.72,90.09 102.44,91.36 102.44,97.74 102.89,98.19
  vias: v2(103.28,99.62) v2(103.3,99.05) v3(97.05,114.17)
+1.8VGS_GPU_ON: length 5.2
  BOTTOM w0.127: CZ16.2 118.46,89.25 v1(119.96,89.25)
  BOTTOM w0.203: 117.01,91.34 116.74,91.62 UZ5.5
  BOTTOM w0.508: 117.01,91.34 117.68,90.68 RZ8.2 CZ16.2
+1.8VGS_OUT:
  vias: v1(113.85,89.81)
+1.35V_MEM_GFX: length 139.5
  TOP w0.254: UV12.G4 v2(143.05,119.23) UV12.H3 ; UV14.P12 v2(139.83,102.23) ; UV14.T12 v2(138.23,102.23) ; v2(139.85,120.78) 139.52,120.45 UV12.C5 ; v2(139.03,109.43) 138.63,109.03 UV14.T3 ; UV14.G11 v2(146.23,103.03) ; UV14.T1 v2(138.17,111.09) ; v2(140.63,118.45) 140.23,118.85 UV12.D3 ; v2(141.81,111.21) 141.83,111.2 UV14.M1 ; v2(142.63,111.15) 142.63,111.15 UV14.L1 UV14.L2 142.63,109.64 143.15,109.12 143.34,109.12 UV14.K3 ; UV12.K12 145.03,126.05 v2(145.43,125.65) 145.83,125.25 UV12.L11 ; v2(140.63,120.85) 141.03,120.45 UV12.E5 ; UV12.D11 140.23,125.25 v2(140.61,124.87) 141.03,124.45 UV12.E10 ; UV14.P11 v2(139.83,103.03) ; UV12.F3 141.83,118.85 v2(142.23,118.45) 142.63,118.05 UV12.G2 ; UV14.G14 v2(145.83,99.66) ; UV12.B1 138.67,117.2 138.67,116.57 v2(138.26,116.16) ; UV14.C10 v2(149.43,103.83) ; UV14.L11 v2(143.03,102.23) UV14.K12 ; UV14.M12 v2(142.23,101.43) UV14.L13 ; v2(140,116.68) 140.23,116.91 UV12.D1 ; UV12.F12 v2(141.43,125.65) ; UV14.M14 v2(142.23,99.83) UV14.L14 ; v2(139.03,118.45) 138.63,118.85 UV12.B3 ; UV14.P14 v2(139.83,99.83) ; v2(139.83,108.63) UV14.P3 140.23,109.03 v2(139.83,109.43) 140.22,109.83 UV14.P2 UV14.P1 140.23,111.27 v2(140.24,111.29) ; UV12.G1 142.63,117.24 v2(142.23,116.85) 141.83,117.25 UV12.F1 ; UV14.M3 141.83,109.03 v2(141.43,109.43) ; UV14.D11 v2(147.85,103.01) UV14.E10 ; v2(145.43,100.63) UV14.G13 UV14.H12 ; UV14.D14 v2(148.23,99.71) ; UV12.K3 145.03,118.85 v2(145.43,118.45) ; UV14.L4 v2(142.23,107.83) ; UV14.R5 v2(139.03,107.83) ; UV14.N5 v2(141.43,107.83) ; UV14.T14 v2(139.03,99.83) ; v2(139.03,124.05) 139.43,124.44 UV12.C10
  TOP w0.508: CV52.1 118.04,110.29 v2(118.04,110.68) 117.55,111.17 CV178.1 ; CV177.1 118.53,107.92 v2(118.48,107.97) 118.44,108.01 CV176.1 ; CV227.1 v2(152.75,109.94) ; CV51.1 CV40.1 116.87,112.18 v2(116.87,112.43) 116.53,112.77 CV175.1
  BOTTOM w0.254: UV14.F12 146.23,102.22 v2(146.22,102.22) ; v2(140,116.68) 140.23,116.91 UV12.D1 ; UV14.C10 v2(149.43,103.83) ; v2(150.23,116.85) 149.83,117.25 UV12.T1 ; v2(146.23,120.05) 145.83,119.65 UV12.L4 ; v2(149.43,118.45) 149.83,118.84 UV12.T3 ; UV14.M14 v2(142.23,99.83) UV14.L14 ; v2(139.83,103.73) 139.52,103.43 UV14.R10 ; v2(138.26,128.02) 138.63,127.65 UV12.B14 ; UV14.L13 v2(142.23,101.43) UV14.M12 ; UV14.N5 v2(141.43,107.83) ; UV12.E5 141.03,120.45 v2(140.63,120.85) ; v2(146.61,99.65) 146.63,99.67 UV14.F14 ; UV12.R10 149.03,124.4 v2(148.68,124.05) ; UV12.N5 147.43,120.79 v2(147.57,120.93) ; v2(120.05,110.49) 119.66,110.87 UV1.H13 ; UV14.B14 v2(150.2,99.86) ; UV12.D12 140.23,126.05 v2(139.83,126.45) ; UV14.F3 v2(146.23,109.43) UV14.G2 ; v2(139.03,118.45) 138.63,118.85 UV12.B3 ; v2(142.63,128.15) 142.63,128.15 UV12.G14 ; v2(147.03,118.45) 146.63,118.85 UV12.M3 ; v2(142.25,124.87) 142.63,125.24 UV12.G11 ; UV12.L2 145.83,118.05 v2(145.43,118.45) 145.03,118.85 UV12.K3 ; v2(140.24,111.29) 140.23,111.27 UV14.P1 ; UV14.D1 148.23,111.19 v2(148.26,111.23) ; v2(119.89,115.61) 119.66,115.84 UV1.H19 ; UV12.F1 141.83,117.25 v2(142.23,116.85) 142.63,117.24 UV12.G1 ; UV14.T1 v2(138.17,111.09) ; v2(150.2,111.71) 149.83,111.35 UV14.B1 ; UV14.C5 149.03,107.36 v2(148.71,107.04) ; UV14.D12 148.23,101.74 v2(148.54,101.43) ; UV14.T12 v2(138.23,102.23) ; v2(140.23,128.16) 140.23,128.16 UV12.D14 ; UV12.H3 v2(143.05,119.23) UV12.G4 ; UV14.D3 148.13,109.03 v2(147.73,109.43) 148.13,109.83 UV15.P2 ; UV14.M3 141.83,109.03 v2(141.43,109.43) ; UV1.K24 118.07,120.32 v2(118.43,119.96) ; v2(148.63,124.85) 148.23,125.25 UV12.P11 ; UV1.L22 117.49,118.72 v2(117.81,119.04) 117.81,119.27 UV1.K23 118.06,119.58 v2(118.43,119.96) ; v2(139.85,120.78) 139.52,120.45 UV12.C5 ; UV14.L1 142.63,111.15 v2(142.63,111.15) ; v2(118.43,119.96) 118.79,120.32 UV1.J24 ; v2(118.43,119.96) 118.86,119.53 UV1.J23 ; v2(117.96,116.76) 117.91,116.72 UV1.L20 UV1.L21 ; UV14.T14 v2(139.03,99.83) ; UV12.N10 147.43,123.91 v2(147.43,123.91) ; v2(138.26,116.16) 138.67,116.57 138.67,117.2 UV12.B1 ; UV12.C10 139.43,124.44 v2(139.03,124.05) ; v2(140.63,103.74) 140.94,103.43 UV14.N10 ; v2(149.43,128.05) 149.83,127.65 UV12.T14 ; UV1.J9 118.83,108.32 v2(118.48,107.97) 118.13,108.32 UV1.K9 ; v2(146.65,116.71) 146.63,116.73 UV12.M1 ; UV12.M14 146.63,127.65 v2(146.23,128.05) 145.83,127.65 UV12.L14 ; UV14.G11 v2(146.23,103.03) ; UV14.M1 141.83,111.2 v2(141.81,111.21) ; UV12.R5 149.03,120.45 v2(149.43,120.05) ; v2(141.82,128.15) 141.83,128.14 UV12.F14 ; UV14.H12 UV14.G13 v2(145.43,100.63) ; UV12.F12 v2(141.43,125.65) ; UV14.D14 v2(148.23,99.71) ; v2(116.87,112.43) 117.26,112.04 UV1.L13 UV1.L12 ; UV1.L12 117.8,110.92 v2(118.04,110.68) ; UV1.L12 UV1.L11 UV1.K10 118.06,109.08 v2(118.45,108.69) 118.86,109.1 UV1.J10 ; UV14.B3 149.52,109.34 v2(149.52,109.42) ; v2(143.03,127.25) 142.63,126.85 UV12.G13 UV12.H12 ; v2(150.23,125.65) 149.83,126.05 UV12.T12 ; UV14.G14 v2(145.83,99.66) ; UV12.E10 141.03,124.45 v2(140.61,124.87) 140.23,125.25 UV12.D11 ; UV12.M12 146.63,126.05 v2(146.23,126.45) 145.83,126.85 UV12.L13 ; UV14.R5 v2(139.03,107.83) ; UV14.E5 v2(147.02,107.02) ; UV14.F1 v2(146.15,111.11) 145.83,110.78 UV14.G1 ; v2(145.43,116.85) 145.83,117.24 UV12.L1 ; UV12.D3 140.23,118.85 v2(140.63,118.45) 140.23,118.05 UV13.P2 ; UV14.P14 v2(139.83,99.83) ; v2(146.21,108.63) 145.83,108.25 UV14.G4 UV14.H3 144.63,109.43 143.83,109.43 UV14.K3 UV14.L2 ; UV12.L11 145.83,125.25 v2(145.43,125.65) 145.03,126.05 UV12.K12 ; UV12.P14 148.23,127.65 v2(148.63,128.05) ; UV1.H16 120.29,114.35 v2(120.29,114.41) ; UV15.D13 140.29,101.08 140.29,101.77 UV14.P12 v2(139.83,102.23) ; UV14.L4 v2(142.23,107.83) ; v2(139.03,109.43) 138.63,109.03 UV14.T3 ; UV14.D11 v2(147.85,103.01) UV14.E10 ; UV12.G2 142.63,118.05 v2(142.23,118.45) 141.83,118.85 UV12.F3 ; UV12.P3 148.23,118.85 v2(148.63,118.45) ; UV14.P3 v2(139.83,108.63) ; UV14.K12 v2(143.03,102.23) UV14.L11 ; v2(148.25,116.68) 148.23,116.7 UV12.P1 ; UV14.P11 v2(139.83,103.03) ; UV13.D13 148.16,126.78 148.16,126.11 UV12.P12 148.23,126.05 v2(148.63,125.65) ; UV12.B12 138.63,126.05 v2(139,125.67) ; UV14.B12 150.22,101.44 v2(150.31,101.44)
  BOTTOM w0.508: CV334.1 v2(150.89,98.19) ; CV342.1 152.55,119.15 v2(152.17,119.53) ; CV162.1 v2(152.75,111.02) ; CV343.1 152.36,120.17 v2(152.16,120.36) ; CV161.1 v2(147.66,98.19) ; v2(140.86,98.39) 140.05,97.57 CV333.1 CV165.1 ; CV341.1 CV235.1 152.44,129.18 v2(152.3,129.32) ; CV164.1 v2(148.74,98.19) ; RV33.1 119.61,127.33 RV32.1 121,126.81 v2(121.81,126.81) ; CV173.1 v2(152.75,105.62) ; RV54.1 143.76,131.51 v2(143.78,131.53) ; CV233.1 v2(151.91,128.17) ; CV170.1 v2(152.75,106.7) ; RV117.2 RV131.2 145.24,114.32 v2(146.64,115.72) ; CV336.1 v2(152.74,98.64) ; CV169.1 v2(152.75,107.78) ; CV221.1 v2(152.75,99.72) ; CV166.1 v2(152.75,108.86) ; CV198.1 v2(152.17,121.25)
  vias: v2(142.59,95.72) v2(142.59,95.13) v2(143.17,95.72) v2(143.17,95.13) v2(143.76,95.72) v2(143.76,95.13) v2(144.34,95.72) v2(144.34,95.13) v2(144.93,95.72) v2(144.93,95.13) v2(146.58,98.19) v2(152.33,97.69) v2(152.42,118.13) v2(152.42,117.12) v2(153.43,100.8) v3(141.05,95.34)
+1.35VGPUP: length 17
  IN3 w0.508: v2(143.45,90.52) 143.45,87.32 144.07,86.7 v2(149.37,86.7)
  BOTTOM w0.508: PC1409.1 155.12,85.74 PR1409.2 154.26,85.11 153.57,84.42 151.66,84.42 v2(149.37,86.7)
  vias: v3(144.57,88.52)
+1VALWP: length 11.9
  BOTTOM w0.254: PC310.1 141.83,39.71 142.08,39.46 143.05,39.46 143.35,39.77 144.67,39.77 145.05,39.39 145.05,38.87 145.68,38.24 146.63,38.24 v3(147.34,37.53) 147.46,37.41 148.66,37.41 149.05,37.81 PR308.2 149.92,38.62 PC309.1
+2.5V_MEM: length 30.5
  BOTTOM w1.524: 57.2,18.75 57.21,18.74 57.21,17.1 58.14,16.16 60.3,16.16 61.92,17.79 67,17.79 67.07,17.87
  BOTTOM w2.032: 53.82,19.6 53.82,17.9 51.48,15.56 47.15,15.56 41.99,10.41 41.99,9.14
  vias: v2(55.77,20.34) v2(56.15,19.9) v2(68.54,19.71) v2(68.54,19.07) v3(70.05,19.17)
+2.5VP: length 2.3
  BOTTOM w0.102: 45.85,5.42 45.85,4.09 v3(46.51,3.43)
+3.3V_ALW_DSW: length 54.3
  TOP w0.508: RC90.2 90.85,34.19 90.66,34 RC93.1 RC89.2 89.95,32.86 88.74,31.66 v2(88.74,30.08) ; v2(92.15,14.51) 92.5,14.51 92.74,14.75 RC163.1 ; v2(110.89,38.28) 109.72,38.28 v1(109.11,37.68) v2(108.41,36.98)
  IN1 w0.508: 102.77,37.33 101.36,38.74 101.36,39.39 100.73,40.03 98.89,40.03 97.51,38.65 97.51,37.86 90.46,30.82 89.25,30.82 88.74,30.31 v2(88.74,30.08)
  BOTTOM w0.254: UC1.AD17 111.32,37.96 v2(110.89,38.28) 111.3,38.62 UC1.AD18 ; v2(108.41,36.98) 108.41,37.56 UC1.AJ17
  BOTTOM w0.508: RC85.1 93.16,13.1 92.32,13.94 92.32,14.33 v2(92.15,14.51) 91.96,14.69 91.45,14.69 CC81.1 91.09,15.05 CC80.1 91.09,19.13 91.43,19.47 91.43,20.21 90.8,20.85 89.41,20.85 88.83,21.43 88.83,22.66 89.53,23.36 89.53,23.87 88.89,24.51 88.89,27.04 89.43,27.58 89.43,28.79 88.74,29.47 v2(88.74,30.08)
+3.3V_HDA: length 18.9
  TOP w0.254: 104.16,40.26 104.54,40.26 v1(104.58,40.3) 104.65,40.38 106.54,40.38 106.79,40.12 106.79,39.73 107.1,39.42 107.68,39.42 107.83,39.57 v2(108.41,39.57)
  TOP w0.381: 104.16,40.26 102.59,40.26 102.24,40.61 99.21,40.61 97.99,41.83 92.44,41.83 92.02,41.41 L2.2
  BOTTOM w0.254: v2(108.41,39.57) 108.41,39.57 108.72,39.26 UC1.AJ19
+3.3V_OUT:
  vias: v3(164.83,22.23)
+3.3V_SPI: length 54.2
  TOP w0.432: v2(109.37,36.26) 109.1,35.99 109.1,34.57 108.6,34.07 108.6,32.55 107.57,31.51 107.54,31.51 107.02,31 107.02,29.22 107.38,28.85 107.38,27.62 107.79,27.22 107.79,26.64 v3(109.73,24.7) 110.27,24.15 110.9,24.15 111.33,23.72 111.33,22.66 111.79,22.21 111.79,18.48 111.26,17.96 v2(110.91,17.96)
  TOP w0.508: RC17.1 88.52,21.74 88.98,22.19 v2(89.45,22.19)
  IN1 w0.508: v2(89.45,22.19) 89.45,21.91 90.07,21.3 91.24,21.3 91.35,21.18 v2(95.48,21.18) ; v2(110.91,17.96) 110.5,17.96 109.83,18.63 107.66,18.63 105.87,20.42 105.87,21.13 v2(106.19,21.46)
  BOTTOM w0.254: v2(109.37,36.26) 109.24,36.38 109.24,36.89 UC1.AJ16
  BOTTOM w0.381: v2(89.45,22.19) 90.07,21.58 91,21.58 91.98,20.59 91.98,19.17 91.69,18.88 91.69,16.88 91.73,16.84 91.73,16.44 92.63,15.54 RC20.1 RC139.1
  BOTTOM w0.508: RC19.1 106.83,20.57 106.83,20.83 v2(106.19,21.46) 105.94,21.71 RC18.1 ; UC3.8 110.63,15.73 111.63,16.72 CC3.1 111.23,17.65 v2(110.91,17.96)
+3.3V_WLAN: length 20
  TOP w0.102: v3(57.27,107.65) 58.36,107.65 58.44,107.73 ; 44.6,110.18 v3(45.41,110.18)
  IN1 w1.016: 60.9,107.98 56.28,107.98 55.14,109.12 46.31,109.12 45.48,109.94 43.71,109.94
  vias: v2(42.75,110.2) v2(42.75,109.62) v2(61.87,108.22) v2(61.87,107.59) v3(62.19,109.33)
+3V_DVDD: length 33.1
  TOP w0.203: CA17.1 27.21,25.43 26.49,24.71 26.49,23.82 26.39,23.72 UA1.9 ; CA16.1 32.59,25.23 30.82,23.46 29.79,23.46 29.59,23.25 UA1.1
  TOP w0.508: CA15.1 34.63,26.57 v3(34.63,29.3) 34.63,29.99 33.36,31.26 29.8,31.26 28.79,30.24 28.79,29.11 CA5.1 27.98,28.3 27.21,28.3 ; CA15.1 33.6,25.54 CA16.1 ; CA15.1 33.88,25.41 RA8.1 ; CA17.1 CA6.1 27.21,28.3 ; 27.21,28.3 24.9,28.3 24.32,27.72 RA3.2 24.47,25.54 RA2.1
+3VALW: length 710.7
  TOP w0.381: v2(137.56,25.61) 137.05,25.61 136.91,25.47 UC9.5
  TOP w0.432: Q2.2 Q2.5 157.82,5.29
  TOP w0.508: 163.15,28.4 162.38,29.18 158.82,29.18 157.67,30.33 156.64,30.33 RE15.2 ; PR16.2 218.01,15.67 218.52,15.17 v2(218.52,12.34) ; v2(174.33,14.74) 172.88,14.74 Q16.2 171.51,13.37 R53.1 ; PR28.1 178.37,21.09 v2(178.48,20.97) ; RE25.1 144.74,36.2 v2(144.74,36.85) ; v2(161.56,90) v3(161.56,88.26) 161.56,87.2 v2(160.1,85.74) 159.49,85.13 157.04,85.13 156.55,85.62 153.86,85.62 v2(153.37,85.13) ; v2(37.36,5.68) 36.91,5.22 D2.2 RC88.2 ; 157.82,5.29 158.67,6.14 158.67,10.6 v2(157.12,12.15) 156.42,12.85 154.34,12.85 ; RE56.1 135.9,12.41 v2(135.55,12.76) ; JPWR1.1 158.45,107.31 157.96,106.82 157.96,106.27 157.45,105.75 v2(156.93,105.75) ; 143.81,19.26 144.17,18.9 144.17,18.05 145.44,16.78 RE40.2 ; v2(193.38,44.14) 193.16,44.14 193.16,44.14 191.97,44.14 189.31,41.48 187.92,41.48 v2(187.66,41.23) 187.2,41.69 PR791.1 ; CC85.1 110.83,20.24 109.66,19.07 109.28,19.07 107.71,17.51 v2(107.71,17.16) 107.71,16.75 108.22,16.24 109.97,16.24 112.03,14.18 117.07,14.18 121.21,10.04 122.95,10.04 124.28,8.72 124.28,8.71 125.3,7.69 125.3,7.01 127.15,5.16 v2(127.34,5.16) ; RE59.1 133.61,12.37 v2(134.14,11.84) 134.14,11.61 RE57.1 RE55.1 ; R35.1 91.76,7.91 v2(91.27,8.4) v3(91.27,9.3) 91.27,10.05 93.49,12.27 v2(93.49,13.94) ; v2(137.35,17.99) 137.35,18.06 137.85,18.56 139.27,18.56 139.78,19.07 RE2.2 ; RE58.1 v2(128.29,11.83) ; RA11.2 v2(19.58,26.12)
  IN1 w0.508: 155.85,106.07 155.57,106.35 155.57,112.55 154.07,114.05 154.07,114.07 153.69,114.45 153.69,120.52 155.11,121.94 156.5,121.94 159.48,124.93 166.52,124.93 166.91,125.32 v2(166.91,126) ; 155.85,106.07 156.29,106.07 156.6,105.75 v2(156.93,105.75) ; 155.85,106.07 155.57,105.79 155.57,103.24 157.88,100.92 160.24,100.92 162.29,98.87 162.29,94.93 162.9,94.32 162.9,91.34 v2(161.56,90) ; v2(153.5,38) 152.86,37.36 151.59,37.36 150.94,38.01 v2(148.48,38.01) ; v2(178.48,20.97) 179.12,20.34 179.88,20.34 ; 179.88,20.34 183.08,20.34 185.15,22.41 185.15,23.34 185.08,23.4 185.08,24.76 186.41,26.08 186.41,39.72 187.66,40.97 v2(187.66,41.23) ; 179.88,20.34 179.88,18.08 177.34,15.54 175.43,15.54 174.63,14.74 v2(174.33,14.74) 173.91,14.74 172.87,15.78 172.87,18.69 169.72,21.83 168.21,21.83 167.54,22.5 165.69,22.5 165.15,23.04 v2(165.15,23.77)
  IN2 w0.508: v2(134.14,11.84) 134.14,12.43 134.59,12.88 135.43,12.88 v2(135.55,12.76) ; v2(107.71,17.16) 107.41,16.85 105.18,16.85 101.4,20.63 98.6,20.63 95.93,17.96 95.93,16.68 94.7,15.45 v2(90.44,15.45) ; v2(218.52,12.34) 215.16,12.34 214.14,11.32 182.54,11.32 181.61,10.38 178.68,10.38 v2(174.33,14.74) ; v2(37.36,5.68) 38.75,5.68 38.76,5.66 38.82,5.66 39.17,5.31 39.17,5.29 45.21,5.29 46.19,4.32 v2(58.19,4.32) ; v2(137.35,17.99) 137.35,18.41 141.65,22.71 142.71,22.71 145.18,25.18 v2(145.18,25.23) 145.18,25.26 146.59,26.67 148.31,26.67 149.82,25.16 149.83,25.16 149.97,25.02 151.43,25.02 151.59,24.86 153.32,24.86 153.56,25.1 154.55,25.1 155.15,24.5 155.15,22.88 156.17,21.86 157.63,21.86 159.41,20.08 159.41,19.26 159.91,18.75 v2(160.29,18.75) 164.8,23.26
  IN2 w1.016: 56.53,105.68 56.53,108.45 55.52,109.47 51.3,109.47 43.9,116.87 43.9,122.52 42.82,123.59 32.4,123.59 31.58,122.77 30.82,122.77 ; 75.18,94.3 62.5,94.3 58.35,98.44 58.35,101.23 56.05,103.53 56.05,104.2 ; 158.71,42.94 158.26,43.39 154.45,43.39 153.69,44.15 153.69,47.31 154.41,48.02 156.74,48.02 157.31,48.6 160.4,48.6 160.93,49.13 161.4,49.13 162.96,50.69 167.22,50.69 168.01,49.9 170.87,49.9 174.33,53.36 174.33,61.94 162.98,73.28 162.98,78.98 161.25,80.72 161.25,82.3 162.71,83.76 162.71,87.01 161.31,88.41 161.31,89.11 ; 77.16,94.3 78.53,92.92 103.72,92.92 106.36,95.56 119.11,95.56 120.2,94.47 125.92,94.47 126.83,93.55 132.66,93.55 133.14,94.03 139.25,94.03 140.15,93.13 142.79,93.13 143.35,92.57 156.08,92.57 156.99,91.65 156.99,90.13 157.82,89.3 159.98,89.3
  IN3 w0.508: 128.77,8.62 128.77,11.14 128.29,11.62 v2(128.29,11.83) ; 128.77,8.62 133.05,8.62 135.66,11.23 135.66,11.91 135.66,11.91 135.66,12.42 135.66,12.42 135.66,12.65 v2(135.55,12.76) 135.55,14 137.35,15.8 v2(137.35,17.99) 137.18,18.15 137.18,20.19 138.08,21.09 138.08,25.09 v2(137.56,25.61) ; 128.77,8.62 127.34,7.19 v2(127.34,5.16) ; v2(158.58,41.87) 157.76,42.69 155.16,42.69 154.33,43.52 154.33,44.76 152.8,46.29 152.8,48.02 151.51,49.32 136.47,49.32 134.64,51.15 v2(133.62,51.15)
  BOTTOM w0.254: PR3.2 v2(166.91,126)
  BOTTOM w0.381: UC7.5 132.85,51.46 133.47,52.09 CC13.1
  BOTTOM w0.508: RE17.2 137.48,25.54 v2(137.56,25.61) ; PR304.1 v2(153.5,38) ; R43.1 91.79,8.92 v2(91.27,8.4) ; PR209.1 85.74,97.62 84.54,96.41 78.44,96.41 77.93,95.9 v2(77.93,95.33) ; v2(193.38,44.14) 193.06,44.14 192.55,43.63 192.55,42.87 PR756.2 ; v2(107.71,17.16) 107.71,17.42 108.03,17.74 RC92.2 ; PR1405.1 v2(153.37,85.13) ; CC13.1 133.9,51.43 v2(133.62,51.15) ; v2(148.48,38.01) 148.16,38.33 PR303.1 ; v2(37.36,5.68) 37.36,10.06 40.9,13.6 40.9,26.13 37.99,29.04 33.87,29.04 33.04,28.21 31.24,28.21 30.37,29.08 28.81,29.08 26.29,26.57 25,26.57 24.77,26.8 20.25,26.8 v2(19.58,26.12) ; RE18.2 137.55,18.62 137.35,18.41 v2(137.35,17.99) ; PR1406.1 v2(160.1,85.74)
  vias: v2(29.29,122.77) v2(29.88,122.77) v2(56.99,104.83) v2(57,104.22) v2(82.57,16.79) v2(82.57,16.15) v2(90.44,14.82) v2(144.12,28.97) v2(144.62,28.68) v2(157.94,39.97) v2(158.58,41.24) v2(158.58,40.6) v2(158.58,39.97) v2(159.21,41.87) v2(159.21,41.24) v2(164.42,25.07) v2(164.42,24.48) v2(164.55,23.9) v2(165,25.07) v2(165,24.48) v2(165.56,24.92) v3(144.76,28)
+3VALW_EC: length 108.3
  TOP w0.508: v2(150.22,30.82) 149.69,31.36 CE8.2 ; CE12.1 141.29,20.39 v2(141.62,20.06) 141.62,19.71 RE2.1 ; v2(151.61,18.43) 151.61,17.92 CE11.1 ; CE8.2 152.84,32.4 CE9.1 155.61,32.42 156.05,32.85 v2(156.1,32.85) ; CE8.2 CE15.1 148.16,32.4 CE7.2 147.76,34.21 147.22,34.75 146.39,34.75 v2(146.13,34.49) 144.8,34.49 v1(144.4,34.9) 144.1,35.19 144.1,36.34 143.66,36.78 v2(143.66,36.81) ; v2(154.33,24.47) 155.33,24.47 CE10.1 155.52,24.28 CE5.1 155.14,23.42 154.77,23.04 v2(154.2,23.04) ; v2(146.92,18.74) 146.92,18.64 146.74,18.46 CE21.1 146.77,17.56 CE13.1 ; v2(141.56,27.27) 141.12,26.82 CE6.1 140.86,26.83 CE20.1 139.78,26.83 139.09,26.15 v2(139.09,25.92) ; RE3.1 v2(151.03,22.31)
  IN2 w0.508: v2(141.56,27.27) 141.56,27.45 142.3,28.19 143.57,28.19 143.73,28.03 144.89,28.03 145.78,28.92 148.64,28.92 150.22,30.5 v2(150.22,30.82) ; v2(154.2,23.04) 154.2,23.07 153.82,22.69 152.8,22.69 152.04,21.93 151.41,21.93 v2(151.03,22.31) ; v2(146.92,18.74) 146.92,18.03 148.55,16.41 148.55,14.69 147.72,13.87 v2(147.72,13.3) ; v2(136.35,22.51) 137.21,23.37 137.21,23.74 137.97,24.5 137.97,24.88 139.01,25.92 v2(139.09,25.92)
  IN3 w0.508: v2(136.92,21.11) 136.92,21.99 136.42,22.5 136.42,22.51 v2(136.35,22.51) ; v2(141.62,20.06) 141.62,19.81 141.98,19.45 142.61,19.45 142.8,19.64 143.3,19.64 143.81,19.13 143.81,17.14 144.82,16.13 144.82,15.51 147.03,13.3 v2(147.72,13.3)
  BOTTOM w0.203: UE1.43 145.96,34.32 v2(146.13,34.49) ; v2(154.33,24.47) 155.03,24.47 155.11,24.38 UE1.82 ; v2(156.1,32.85) 156.1,32.45 155.23,31.58 155.23,31.33 155.38,31.18 UE1.65 ; v2(150.22,30.82) 150.36,30.96 UE1.54 ; UE1.22 141.48,27.18 v2(141.56,27.27) ; v2(139.09,25.92) 139.08,25.92 139.08,25.93 139.13,25.98 UE1.19 ; RE8.2 137.55,20.57 138.16,19.96 139.02,19.96 139.44,20.38 UE1.5 141.16,20.38 141.23,20.31 141.24,20.31 141.49,20.06 v2(141.62,20.06) ; v2(146.92,18.74) 146.92,18.43 147.16,18.2 UE1.115 ; UE1.103 151.96,18.13 151.65,18.43 v2(151.61,18.43) 152.1,18.93 152.1,21.24 v2(151.03,22.31)
  BOTTOM w0.381: RE12.1 RE14.2 140.59,36.33 141.37,37.1 143.36,37.1 v2(143.66,36.81)
  BOTTOM w0.508: v2(151.03,22.31) 151.03,22.26 149.4,20.62 148.01,20.62 146.92,19.54 v2(146.92,18.74) ; v2(136.35,22.51) 136.36,22.51 137.24,23.39 RE11.2 RE10.2 ; v2(136.92,21.11) 137.31,21.49 RE9.2 RE8.2 ; v2(147.72,13.3) 148.32,13.3 RE1.1
+3VALW_PCH: length 199.8
  TOP w0.457: v2(108.42,38.24) 108.51,38.24 109.02,38.75 CC65.1
  TOP w0.508: RC84.1 92.59,22.67 v2(93.16,22.67) ; RC45.2 87.32,22.48 87.1,22.27 87.1,21.77 RC17.2 86.69,21.74 v2(86.32,22.12) ; v2(81.71,23.41) 81.35,23.77 81.35,26.82 86.58,32.06 86.58,36.56 88.98,38.96 CC61.1 90.57,40.28 L2.1 ; v2(216.3,44.63) 216.9,44.63 217.53,45.26 RX13.1 ; RX2.1 v2(221.32,54.05)
  IN1 w0.508: 216.32,44.63 v2(216.3,44.63) ; 216.32,44.63 217.13,43.82 217.13,25.86 215.86,24.59 215.86,20.84 214.9,19.89 210.86,19.89 207.75,16.78 202.73,16.78 200.47,14.52 190.95,14.52 190.68,14.25 185.87,14.25 185.37,14.74 175.59,14.74 174.91,14.06 173.73,14.06 171.91,15.87 171.91,18.74 169.46,21.19 167.95,21.19 167.28,21.86 165.25,21.86 162.65,24.47 v2(162.45,24.47) ; 216.32,44.63 216.32,47.29 217.13,48.09 217.13,51.65 218.52,53.05 220.31,53.05 v2(221.32,54.05) ; v2(81.71,23.41) 82.58,23.41 82.81,23.18 84.92,23.18 85.99,22.12 v2(86.32,22.12)
  IN2 w0.508: 94.91,24.22 94.61,24.22 93.16,22.77 v2(93.16,22.67) 93.16,22.02 92.65,21.51 86.92,21.51 v2(86.32,22.12) ; 94.91,24.22 94.91,31.57 v2(95.57,32.23) ; 94.91,24.22 96.66,24.22 v2(97.35,23.52) 98.29,22.59 99.71,22.59 99.74,22.62 102.26,22.62 102.71,22.17 106.64,22.17 107.14,21.66 107.14,21.46 108.93,19.67 110.55,19.67 v2(110.89,19.33)
  BOTTOM w0.076: RC29.2 114.7,21.92 ; RC47.2 109.94,24.1
  BOTTOM w0.254: UC1.Y16 112.97,37.31 v2(112.54,37.62) ; UC1.AK15 107.98,36.21 107.66,35.89 v2(107.66,35.41) ; UC1.AK17 108.14,37.96 v2(108.42,38.24) ; v2(111.7,36.98) 111.38,36.66 UC1.AD15 ; UC1.Y15 113.01,36.64 113.37,36.28 114.26,36.28 v2(114.32,36.35) ; UC1.AJ21 109.29,41.04 v2(110.96,41.04) 110.98,41.06 113.12,41.06 113.4,40.78 113.4,39.71 UC1.V19 ; v2(114.33,36.99) 114.65,37.31 UC1.T16 ; v2(110,36.32) 109.99,36.32 109.99,36.33 UC1.AG15
  BOTTOM w0.381: v2(118.83,22.76) 118.47,23.11 118.47,23.16 118.01,23.61 RC33.2
  BOTTOM w0.457: RC35.2 96.98,32.47 95.81,32.47 v2(95.57,32.23)
  BOTTOM w0.508: RC39.2 110.16,22.64 v2(109.79,23.01) 109.94,23.15 109.94,24.1 ; v2(110.89,19.33) 110.2,18.64 RC129.1 RC128.1 ; RC37.2 RC29.2 ; 114.7,21.92 RC30.2 115.46,21.36 v2(115.14,21.04) ; RC34.2 RC38.2 ; RC38.2 RC31.2 RC32.2 ; RC38.2 114.64,23.92 v2(115.07,23.48) ; v2(119.91,23.31) 119.83,23.39 119.83,24.25 RC46.2 ; v2(97.35,23.52) 97.35,23.97 97.35,23.97 RC44.1
  vias: v2(114.85,30.95) v2(119.02,22.23) v2(130.53,33.98) v2(130.94,33.46) v2(161.63,25.04) v2(161.82,24.47) v2(162.26,25.06)
+3VALWP: length 62.4
  IN1 w0.508: v2(163.21,41.36) 166.2,38.37 173.14,38.37 174.76,36.75 176.01,36.75 179.24,33.52 179.24,30.11 180.63,28.73 180.66,28.73 182.2,27.19 v2(182.2,26.5)
  IN3 w0.254: v2(174.21,40.33) 173.43,39.54 172.64,39.54 172.36,39.26 172.36,38.75 172.11,38.5 164.61,38.5 163.6,39.52 162.89,39.52 161.94,40.46 v2(161.94,41.36) ; v2(161.31,41.36) 161.31,40.56 162.73,39.13 163.44,39.13 164.45,38.12 172.36,38.12 172.84,38.6 v2(172.84,39.06)
  BOTTOM w0.254: v2(174.21,40.33) 174.87,40.33 175.12,40.58 PU100.14 ; PR109.1 PR108.2 PR107.1 173.1,37.81 172.84,38.06 v2(172.84,39.06)
  BOTTOM w0.508: PR113.1 182.22,27.23 182.22,26.51 v2(182.2,26.5)
  vias: v2(161.31,42) v2(161.94,42) v2(162.58,42) v2(162.58,41.36) v2(163.21,42) v3(163.41,40.2)
+3VGS: length 148.4
  TOP w0.102: v2(112.22,99.85) 112.73,99.85 v3(112.88,100.01)
  TOP w0.356: QV1.5 QV1.2
  TOP w0.381: RV5.1 112.63,100.6 113.43,101.39 QV1.5 ; RV6.1 113.16,104.17 113.43,103.9 QV1.2
  TOP w0.508: v2(112.22,99.85) 112.03,100.04 112.03,100.34 RV5.1 ; v2(116.22,101.37) 116.25,101.35 RV154.1 ; PR1115.1 v2(47.58,124.04)
  IN1 w0.508: v2(120.54,93.56) 120.54,95.48 119.03,96.99 118.13,96.99 117.68,97.43 117.68,101.62 116.72,102.58 v2(115.11,102.58)
  IN2 w0.508: v2(47.58,124.04) 49.04,122.58 49.04,119.84 53.32,115.57 57.82,115.57 63.81,109.59 63.81,102.53 62.71,101.43 62.71,99.65 64.04,98.32 83.14,98.32 84.48,96.98 91.59,96.98 94.83,100.23 v2(98.57,100.23) 98.72,100.37 109.66,100.37 110.19,99.85 v2(112.22,99.85) 112.36,99.71 113.49,99.71 114.99,101.21 116.07,101.21 v2(116.22,101.37)
  IN3 w0.508: v2(119.91,93.56) 119.91,94.13 116.35,97.68 116.35,99.66 116.22,99.78 v2(116.22,101.37) 116.22,101.81 115.45,102.58 v2(115.11,102.58)
  BOTTOM w0.508: LV4.1 96.94,115.1 ; 96.94,115.1 95.78,113.94 95.78,109.52 95.65,109.39 95.65,107.46 96.67,106.44 97.97,106.44 98.52,105.88 UV2.5 98.52,105.22 99.27,104.48 99.27,100.73 98.76,100.23 v2(98.57,100.23) ; 96.94,115.1 96.32,115.72 96.32,119.05 96.68,119.41 RV162.1
+3VGS_GPU_ON: length 3.6
  BOTTOM w0.102: v1(128.56,90.58) 128.38,90.76 RZ6.2
  BOTTOM w0.254: UZ4.3 128.14,92.89 CZ13.2
  BOTTOM w0.508: CZ13.2 128.36,91.76 RZ6.2
+3VGS_OUT:
  vias: v2(123.4,93.41)
+3VLP: length 209.8
  TOP w0.508: v2(173.18,41.81) v3(173.79,41.81) 175.12,41.81 175.17,41.76 PC111.1 ; RE29.2 146.27,21.06 v2(146.32,21.11)
  IN1 w0.508: v2(182.57,24.35) 182.57,24.77 182.84,25.04 182.84,27.45 180.93,29.36 180.89,29.36 179.88,30.37 179.88,36.76 179.25,37.39 175.03,37.39 173.5,38.91 173.5,41.49 v2(173.18,41.81)
  IN2 w0.508: v2(182.57,24.35) 182.57,23.75 181.44,22.62 178.05,22.62 175.44,20.02 163.18,20.02 160.01,16.85 154.64,16.85 153.6,17.89 153.6,18.77 153.24,19.13 152.87,19.13 152.01,19.99 147.88,19.99 146.78,21.08 146.36,21.08 146.34,21.11 v2(146.32,21.11) 144.31,21.11 143.72,20.52 143.72,18.75 144.8,17.67 145.56,17.67 146.62,16.61 146.62,15.37 144.51,13.26 141.18,13.26 140.71,12.78 139.4,12.78 138.61,12 136.39,12 127.71,3.32 124.23,3.32 123.01,2.1 118.24,2.1 117.05,3.29 v2(117.05,3.32) 111.55,3.32 110.26,2.03 62.46,2.03 58.67,5.82 46.99,5.82 45.1,7.71 40.34,7.71 39.77,7.14 v2(39.77,6.81)
  BOTTOM w0.508: v2(117.05,3.32) 116.98,3.32 111.42,8.88 110.94,8.88 110.43,9.38 R42.1 ; D1.2 37.45,4.81 39.45,6.81 v2(39.77,6.81)
+3VS: length 582.3
  TOP w0.305: JDB1.9 122.74,7.16 122.96,6.94 123.24,7.22 JDB1.10
  TOP w0.381: v2(75.77,17.17) 75.91,17.04 RC188.1 ; v2(29.67,94.63) 30.45,93.85 30.99,93.85 QI2.5 ; RC43.2 112.97,26.37 RC27.1 113.48,25.49 113.82,25.15 114.12,25.15 114.51,24.76 QC1.5 ; QI2.2 32.72,95.59 32.72,96.42 v2(31.9,97.24) ; CE22.1 153.6,20.11 UE2.5
  TOP w0.406: QC1.2 QC1.5
  TOP w0.432: 105.74,6.88 105.74,7.89 Q10.2 105.75,8.61 R34.1 ; 105.74,6.88 105.74,6 Q10.5 105.75,5.42 105.89,5.28 R33.1 ; 105.74,6.88 105.06,6.88 104.22,6.04 104.22,4.81 103.52,4.1 102.15,4.1 100.92,5.33 100.92,5.83 100.14,6.61 99.06,6.61 98.64,6.19 98.64,5.35 96.48,3.19 93.48,3.19 91.67,1.38 86.63,1.38 86.19,1.83 86.19,2.63 ; QC1.2 114.51,22.27 114.65,22.13 RC28.1
  TOP w0.508: v2(165.82,14.82) v3(165.18,14.82) 163.93,16.08 v2(161.88,16.08) ; PR1112.1 48.13,126.83 46.11,126.83 v2(45.99,126.71) ; RD15.1 v2(43.58,43.33) ; v2(92.16,95.34) v3(92.16,93.07) 92.92,92.31 92.92,81.61 RC9.1 ; RC13.1 RC14.1 91.64,30.36 92.22,29.78 v2(92.45,29.78) ; RA2.2 v2(25.36,27.43) ; R11.1 v2(228.56,35.75) ; 86.19,2.63 R36.1 86.62,4.1 86.43,4.1 85.45,5.08 84.41,5.08 84.21,4.88 83.44,4.88 83.03,5.29 81.81,5.29 ; v2(114.42,21.04) 114.42,21.19 114.65,21.42 RC28.1 ; 122.96,6.94 122.96,6.75 123.4,6.3 124.46,6.3 126.66,4.1 129.23,4.1 129.43,4.31 133.78,4.31 134.94,3.15 135.81,3.15 136.16,3.51 136.16,5.54 v2(135.85,5.86) ; PR1119.1 47.19,122.29 45.99,123.49 v2(45.99,123.53) ; v2(219.16,46.25) 218.84,45.93 RX10.1 ; CE22.1 153.12,20.03 153.12,20.03 v2(153.05,20.03) ; RD13.1 51.34,20.61 v2(51.58,20.85) ; RC190.1 85.35,20.31 85.35,20.31 v2(85.28,20.31) ; R50.2 181.69,52.79 181.69,52.79 v2(181.68,52.79) ; v2(166.96,49.68) 167.15,49.49 PR612.1 ; v2(24.85,93.81) RI15.1 25.37,93.06 25.5,93.19 QI3.2 ; v2(87.27,27.96) 87.27,27.41 RC61.1 ; 48.81,16.24 46.82,14.25 44.41,14.25 43.78,14.88 41.61,14.88 QA1.2 ; RE13.2 145.83,32.14 146.32,31.65 147.85,31.65 148.27,31.23 148.27,29.62 150.8,27.09 v2(151.38,27.09) ; RC57.1 v2(85.55,26.38) 85.55,27.19 RC53.1 RC59.1 ; RD1.1 60.28,16.41 ; R23.1 v2(150.2,5.85) ; RX1.1 v2(222.84,53.44) ; v2(120.95,23.46) 121.1,23.61 121.1,26.18 120.37,26.92 RC70.2 ; R16.1 v2(227.54,35.75) ; RD3.1 58.5,41.22 57.62,41.22 v2(57.42,41.42) ; v2(86.76,23.96) RC73.1 RC71.1
  TOP w1.016: 45.74,19.65 48.19,17.2 ; 50.1,16.41 v3(50.85,16.41) 66.19,16.41 67.39,17.61 67.39,19.65
  IN1 w0.508: v2(153.05,20.03) 153.05,20.02 154.81,18.27 154.81,17.76 155.88,16.69 156.89,16.69 157.51,16.08 v2(161.25,16.08) ; v2(57.42,41.42) 52.79,41.42 52.1,42.11 46.4,42.11 45.18,43.33 v2(43.58,43.33) ; v2(150.2,5.85) 147.41,5.85 143.91,9.35 140.48,9.35 137.12,5.99 135.97,5.99 v2(135.85,5.86)
  IN1 w1.016: 184.86,16.26 185.71,16.26 187.89,18.44 187.89,24.02 188.78,24.91 188.78,31.58 ; 181.22,51.8 181.22,50.08 184.43,46.87 189.42,46.87 190.63,45.65 190.63,44.93
  IN2 w0.508: v2(151.38,27.09) 151.76,26.71 153.29,26.71 153.75,27.17 155.03,27.17 155.79,26.42 155.79,23.14 156.43,22.5 157.89,22.5 158.46,21.93 160.04,21.93 ; v2(44.17,20.3) 44.17,21.85 42.12,23.9 42.12,31.3 39.2,34.22 39.2,41.55 40.98,43.33 v2(43.58,43.33) ; v2(122.75,23.36) 122.71,23.4 121.01,23.4 v2(120.95,23.46)
  IN2 w1.016: 58.73,104.13 61.02,101.84 61.02,98.28 62.45,96.85 80.18,96.85 81.69,95.34 v2(92.16,95.34) 93.43,94.06 102.89,94.06 106.19,97.36 117.05,97.36 117.36,97.05 119.24,97.05 119.81,96.48 127.97,96.48 128.86,95.59 129.37,95.59 ; 182.27,15.03 176.81,15.03 175.88,15.96 v2(174.45,15.96) 168.83,15.96 167.69,14.82 v2(165.82,14.82) 164.9,14.82 163.71,16.01 162.83,16.01 ; 131.46,95.4 133.31,95.4 133.54,95.17 139.72,95.17 140.62,94.27 143.26,94.27 143.82,93.71 156.83,93.71 159.59,96.48 163.02,96.48 164.04,95.46 v2(164.04,89.11) 164.04,88.61 165.18,87.46 165.18,80.79 170.35,75.62 170.35,68.43 176.1,62.67 176.1,55.32 178.69,52.73 179.66,52.73 ; 58.06,105.49 58.06,105.49 58.06,109.16 55.9,111.32 52.46,111.32 48.79,115 48.79,117.7 45.99,120.5 v2(45.99,123.53) v2(45.99,126.71)
  IN3 w0.508: 28.66,94.7 29.61,94.7 v2(29.67,94.63) ; v2(31.9,97.24) 31.46,97.69 28.53,97.69 ; v2(166.96,49.68) 167.28,49.99 171.03,49.99 173.76,52.73 v2(180.55,52.73)
  BOTTOM w0.254: CX5.2 214.7,37.9 213.99,38.61 UX2.1 ; RX16.1 211.16,45.25 211.16,43.84 211.49,43.5 UX2.13
  BOTTOM w0.381: v2(95.52,30.85) 95.8,31.13 RC36.2 96.15,31.52 96.53,31.9 97.66,31.9 RC187.1
  BOTTOM w0.432: Q11.2 134.91,19.76 R48.1 ; R49.1 131.25,19.76 Q11.5
  BOTTOM w0.508: RC51.1 96.18,27.7 v2(95.8,27.7) ; v2(164.04,89.11) 160.5,89.11 PR1401.1 ; RC72.1 96.28,26 v2(95.7,26) ; v2(210.46,44.09) 208.87,42.51 CX4.2 ; RL16.1 31.04,115.13 v2(30.57,115.6) ; RC181.1 117.11,20.39 RC63.1 117.05,20.46 v2(117.05,21.11) 117.05,21.79 RC49.1 ; R28.1 138.45,17.42 v2(138.64,17.61) ; R5.1 220.73,47.73 220.59,47.87 v2(220.59,47.87) ; RC114.1 93.31,17.43 v2(93.31,17.99) ; RC64.1 120.88,24.24 120.88,23.53 v2(120.95,23.46) ; CX5.2 v2(214.7,36.89) ; v2(135.85,5.86) 131.97,9.74 C20.1 ; RL3.1 34.94,122.13 v2(35.2,122.39) ; R48.1 135.26,19.4 v2(135.65,19.4) ; v2(130.64,20.66) 130.24,20.27 R29.1 131.16,19.82 R49.1 ; JIOB1.12 174.6,16.1 v2(174.45,15.96) ; v2(25.36,27.43) 25.36,27.68 27.91,30.23 38.02,30.23 41.76,26.48 41.76,21.14 42.61,20.3 v2(44.17,20.3) ; RX16.1 v2(211.79,46.63) ; RC42.1 112.79,21.91 RC55.1 112.79,21.68 113.43,21.04 v2(114.42,21.04)
  vias: v2(44.66,19.84) v2(57.82,104.61) v2(57.82,103.97) v2(64.66,20.87) v2(65.3,20.87) v2(75.33,16.8) v2(80.14,7.84) v2(80.71,7.84) v2(109.05,16.85) v2(109.68,16.98) v2(124.54,23.36) v2(128.92,27.71) v2(129.31,28.15) v2(130.13,95.08) v2(130.57,95.59) v2(133.81,15.96) v2(134.22,16.38) v2(160.84,23.14) v2(160.86,22.58) v2(161.36,22.88) v2(161.38,22.33) v2(161.92,22.74) v2(161.95,22.17) v2(183.33,15.37) v2(183.95,15.39) v2(184.59,15.39) v2(185.22,15.39) v2(209.38,37.5) v2(209.38,36.92) v2(212.93,47.39) v2(213.57,47.39) v2(222.84,52.79) v2(227.65,25.3) v2(227.65,24.66) v2(228.24,25.3) v2(228.24,24.66)
+3VS_CAM: length 2.6
  TOP w0.102: 223.59,35.37 v1(222.82,35.37)
  BOTTOM w0.305: v2(225.18,34.69) 225.18,35.34 224.97,35.55 224.08,35.55 JEDP1.30
+5V_AVDD: length 18.6
  TOP w0.203: 25.23,15.84 25.23,16.15 25.47,16.39 25.47,16.4 25.52,16.45 25.52,16.46 25.59,16.53 UA1.26
  TOP w0.508: 25.23,15.84 23.59,14.2 CA10.1 23.59,13.38 22.94,12.73 CA11.1 23.13,10.31 24.35,10.31 25.02,10.98 26.86,10.98 27.33,11.45 v3(29.81,11.45) 31.99,11.45 RA4.2
+5V_CAM:
  vias: v2(215.91,50.13) v2(216.49,50.13) v3(217.18,49.07)
+5V_HDD: length 4.4
  BOTTOM w0.102: v3(194.38,19.3) 194.73,18.95 v2(194.73,18.63) ; v3(199.35,20.79) v2(199.35,17.99) ; 193.75,18.23 v3(192.97,18.23)
  vias: v2(194.73,18.07) v2(199.79,17.61)
+5V_HDMI: length 11
  IN1 w1.016: 13.04,91.34 14.42,92.73 14.42,95.53 16.8,97.91 19.65,97.91
  vias: v2(20.8,97.88) v2(20.8,97.33)
+5V_KB_BL: length 1.7
  TOP w0.508: ZT61.1 117.5,9.86 v2(117.88,9.48)
+5V_OUT: length 2
  TOP w0.102: 170.8,20.07 v1(172.75,20.07)
+5V_PVDD:
  vias: v3(34.73,22.09)
+5VALW: length 544.4
  TOP w0.203: v2(167,24.9) 167.06,24.84 UZ3.4 ; PU602.9 PU602.10 166.96,55.58 v2(168.1,56.72) ; 59.75,123.21 59.32,123.21 59.25,123.15 58.76,123.15 58.69,123.21 57.86,123.21 57.67,123.4 56.85,123.4 56.82,123.44 PU1100.26
  TOP w0.254: CZ22.1 134.61,33.62 134.61,33.07 134.31,32.76 UZ1.4 ; UX1.4 219.44,52.08 v2(219.77,52.41)
  TOP w0.305: CZ5.1 136.84,28.99 v2(136.35,29.49) 136.09,29.75 UZ2.3
  TOP w0.508: v2(135.34,35.39) 135.52,35.21 CZ22.1 ; v2(176.92,18.63) 176.88,18.58 Q15.3 ; v2(127.53,91.91) 126.45,90.83 121.75,90.83 121.14,91.43 117.39,91.43 117.37,91.41 116.67,91.41 115.78,90.51 101.34,90.51 95.1,96.75 v3(86.53,96.75) 83.5,96.75 v2(82.95,97.31) ; EC2230.1 156.03,110.93 155.23,111.72 v2(153.88,111.72) ; v2(150.38,51.85) 150.53,51.7 PC685.1 ; Q3.3 v2(154.2,10.07) 153.51,10.07 152.56,11.02 Q4.3 ; v2(59.39,128.29) 59.58,128.29 60.6,127.28 60.6,124.06 59.75,123.21
  IN1 w0.508: v2(56.85,126.83) 56.85,128.04 57.65,128.84 58.84,128.84 v2(59.39,128.29) ; v2(219.77,52.41) 219.54,52.18 219.54,51.2 v2(219.92,50.82) ; v2(162.13,81.49) 162.13,76.49 162.83,75.79 162.83,73.7 161.98,72.85 v2(161.57,72.85) 161.57,71.13 165.63,67.08 165.63,60.15 168.1,57.68 v2(168.1,56.72) 168.1,56.66 170.52,54.25 170.52,52.16 171.34,51.33 171.34,48.48 169.49,46.63 163.22,46.63 162.23,45.64 160.64,45.64 160.13,45.13 160.13,37.72 161.56,36.28 161.56,34.12 161.87,33.81 v2(161.87,33.55) 161.87,28.4 163.01,27.27 166.39,27.27 167,26.66 v2(167,24.9) 168.89,23.01 170.71,23.01 v2(171.28,22.44) ; v2(163.26,125.87) 159.52,125.87 156.23,122.58 154.7,122.58 153.05,120.93 153.05,113.83 153.87,113.02 153.87,111.73 v2(153.88,111.72) 153.87,111.71 153.87,101.62 155.2,100.29 159.97,100.29 161.63,98.64 161.63,94.32 v2(161.94,94)
  IN2 w0.508: v2(82.95,97.31) 82.3,96.66 81.59,96.66 80.53,97.71 63.51,97.71 62.08,99.14 62.08,102.01 60.5,103.59 60.5,108.24 56.17,112.57 52.57,112.57 49.68,115.46 49.68,118.07 48.41,119.34 48.41,121.46 46.88,122.99 46.88,126.71 47.01,126.83 v2(56.85,126.83) ; v2(127.53,91.91) 127.34,92.1 125.49,92.1 124.67,91.27 120.79,91.27 120.05,92.02 v2(117,92.02) ; v2(161.07,50.2) 161.03,50.2 160.99,50.16 159.81,50.16 159.28,50.69 152.17,50.69 151.01,51.85 v2(150.38,51.85) ; v2(136.35,29.49) 136.66,29.49 138.55,31.37 139.27,31.37 139.82,30.82 141.24,30.82 141.74,31.32 142.2,31.32 143.79,32.92 151.73,32.92 152.84,31.81 156.89,31.81 157.99,32.92 161.24,32.92 v2(161.87,33.55) ; v2(154.2,10.07) 155.22,9.04 v2(164.99,9.04) ; v2(219.92,50.82) 218.84,50.82 218.46,50.44 217.32,50.44 216.84,50.92 211.45,50.92 210.48,49.95 210.48,46.98 208.02,44.52 204.61,44.52 199.77,49.36 195.19,49.36 193.57,50.98 189.66,50.98 188.3,52.33 182.23,52.33 181.76,51.87 178.3,51.87 175.22,54.95 175.22,62.3 163.87,73.65 163.87,79.34 162.13,81.08 v2(162.13,81.49) 162.13,81.93 163.66,83.45 163.66,87.46 162.58,88.54 162.58,93.5 162.07,94 v2(161.94,94)
  IN3 w0.508: v2(161.94,94) 161.94,95.97 161.31,96.61 146.71,96.61 145.68,97.63 140.67,97.63 140.1,97.06 136.55,97.06 135.08,95.59 131.58,95.59 127.91,91.91 v2(127.53,91.91) ; v2(168.1,56.72) 166.77,55.39 166.77,51.14 166.26,50.63 163.14,50.63 162.71,50.2 v2(161.07,50.2)
  BOTTOM w0.203: UZ5.4 v2(117,92.02) 117.24,92.02 117.42,91.84
  BOTTOM w0.254: PU603.2 161.67,71.9 PC661.1 162.01,72.85 v2(161.57,72.85) ; PU606.6 v2(150.38,51.85) ; PC677.1 161.88,82.13 161.31,81.56 PU605.2 ; v2(127.53,91.91) 127.53,92.29 127.43,92.39 UZ4.4
  BOTTOM w0.508: PR602.2 161.62,50.2 v2(161.07,50.2) ; PD5.3 165.06,126.81 PR8.1 164.23,126.02 PD6.3 v2(163.26,125.87) ; PC677.1 162.25,81.61 v2(162.13,81.49) ; 117.42,91.84 117.67,91.59 CZ30.1 ; v2(164.99,9.04) 165.19,9.24 165.19,15.64 165.64,16.09 165.64,18.71 168.73,21.8 v2(171.28,21.8) ; v2(123.78,4.55) 123.78,4.65 123.73,4.71 123.73,8.58 123.21,9.1 123.21,10.56 123.72,11.07 CU17.1 124.69,11.07 UU3.5 ; v2(135.34,35.39) 135.97,35.39 137.02,34.34 137.02,32.94 136.35,32.27 v2(136.35,29.49) ; v2(82.95,97.31) 82.95,101.43 83.14,101.62 PR206.1 83.14,103.34 PR210.2 ; CZ27.1 127.55,91.88 v2(127.53,91.91)
  vias: v2(20.85,51.14) v2(20.85,50.56) v2(20.85,49.99) v2(21.48,51.14) v2(21.48,50.56) v2(21.48,49.99) v2(21.93,30.24) v2(21.93,29.61) v2(21.93,28.97) v2(22.56,30.24) v2(22.56,29.61) v2(22.56,28.97) v2(49.17,2.25) v2(49.75,2.25) v2(50.34,2.25) v2(50.95,2.25) v2(51.53,2.25) v2(52.11,2.25) v2(171.91,22.44) v2(171.91,21.8) v2(172.55,22.44) v2(172.55,21.8) v2(173.18,22.44) v2(173.18,21.8) v2(173.82,22.44) v2(173.82,21.8) v3(22.61,50.97) v3(169.31,24.55)
+5VALWP: length 20
  TOP w0.254: 174.4,24.78 174.81,24.38 176.1,24.38 176.33,24.61 176.33,27.51 176.71,27.89 176.71,29.14 v2(177.74,30.17)
  BOTTOM w0.254: PU102.14 177.81,30.24 v2(177.74,30.17) ; PC120.1 175.95,22.19 177.63,22.19 178.01,22.57 178.01,27.27 177.3,27.98 PR117.2 PR115.1
  vias: v2(171.53,26.17) v2(171.53,25.59) v2(171.53,25) v2(172.17,26.17) v2(172.17,25.59) v2(172.17,25) v2(172.8,26.17) v2(172.8,25.59) v2(172.8,25) v2(173.39,26.17) v2(173.39,25.59) v2(173.39,25) v3(174.4,26.37)
+5VS: length 311.6
  TOP w0.508: v2(112.11,2.03) 112.68,1.47 117.93,1.47 119.21,2.75 120.23,2.75 120.61,3.13 v2(120.61,3.17) ; v2(31.39,76.62) 31.12,76.89 QI1.2 ; RA4.1 34.66,12.15 v2(35.64,12.15) ; R12.1 v2(228.15,29.93) ; Q7.3 84.8,2.32 83.9,1.42 v2(44.02,1.42)
  TOP w1.016: 182.9,49.77 182.9,48.21 185.06,46.06 185.06,45.69
  TOP w1.524: 185.06,45.69 185.9,46.53 187.94,46.53 189.31,47.9 192.23,47.9
  TOP w2.54: 185.69,30.64 185.69,35.26 184.81,36.15 184.81,45.43 185.06,45.69
  IN1 w1.524: 32.6,39.71 32.6,43.83 31.39,45.04 v2(31.39,76.62) 31.39,86.76 25.99,92.16 25.99,95.65
  IN2 w1.016: 184.42,50.63 186.56,50.63 187.75,49.44 191.9,49.44 194.08,47.26
  IN2 w2.54: 186.48,28.78 187.6,27.66 187.6,22.69
  IN3 w0.508: v2(44.02,1.42) 41.04,1.42 39.67,2.79 39.67,5.77 35.77,9.68 35.77,12.02 v2(35.64,12.15) ; v2(228.15,29.93) 226.08,29.93 224.29,31.72 224.29,44.27 221.3,47.26 218.4,47.26 218.02,46.89 216.17,46.89 214.68,45.39 210.74,45.39 208.74,43.39 204.36,43.39 200.51,47.24 194.67,47.24
  BOTTOM w0.508: v2(36.57,26.36) 36.59,26.36 36.59,26.38 38.25,26.38 39.63,24.99 39.63,16.13 v2(35.64,12.15) ; v2(120.61,3.17) 120.61,3.67 F3.2 ; v2(112.11,2.03) 112.11,1.68 111.86,1.42 111.11,1.42 70.5,1.42 v2(63.77,8.15)
  vias: v2(24.59,97.24) v2(25.23,97.24) v2(25.86,97.24) v2(31.39,38.5) v2(32.02,38.5) v2(32.66,38.5) v2(35.96,26.37) v2(36.6,25.74) v2(167.39,16.97) v2(167.98,16.97) v2(168.56,16.97) v2(169.15,16.97) v2(169.73,16.97) v2(182.77,50.63) v2(183.41,50.63) v2(184.3,30.12) v2(184.3,29.53) v2(184.3,28.95) v2(184.3,28.36) v2(184.3,27.78) v2(194.24,46.63) v2(194.82,46.63) v2(195.41,46.63) v2(200.49,17.04) v2(201.07,17.04) v3(191.64,46.32)
+5VS_ODD: length 2.2
  TOP w0.102: 197.2,48.76 v3(197.2,49.7) ; 194.22,48.8 v3(194.22,50.07)
  vias: v2(196.3,46.61) v2(196.91,46.61) v2(197.49,46.61) v3(197.2,46.12)
+17.4V_BATT+: length 17.6
  TOP w0.508: v2(203.92,21.74) 203.73,21.55 PR780.2 202.9,21.68 PQ710.3
  IN3 w0.508: v2(195.72,30.45) 195.72,26.25 200.42,21.55 203.73,21.55 v2(203.92,21.74)
  BOTTOM w0.508: PR745.2 196.17,30.9 v2(195.72,30.45)
  vias: v2(212.62,23.2) v2(212.62,22.61) v2(214.78,23.2) v2(214.78,22.61) v3(212.81,24.45) v3(213.46,21.9) v3(214.29,23.51)
+17.4V_BATT++: length 5.3
  TOP w0.102: v3(213.08,15.82) 212.47,15.82 v2(212.03,16.25) 212.03,16.59 213.07,17.63 v3(213.36,17.63) 214.76,17.63 v3(215.2,18.06)
+19V_ADPIN: length 5.3
  TOP w0.102: 161.23,121.26 161.98,121.26 v3(162.16,121.09) ; v3(156.09,121.7) 156.43,122.04 157.5,122.04 ; 158.03,124.88 155.68,124.88 v3(155.39,124.59)
+19V_VIN: length 140.5
  TOP w0.508: v2(185.67,26.43) 184.6,25.37 PR5.1 184.5,24.42 PR7.2 PR31.2
  IN1 w0.508: v2(157.94,112.77) 157.94,107.4 158.96,106.39 165.66,106.39 166.55,105.49 166.55,71.45 173.3,64.7 173.3,56.78 185.08,45 185.08,43.4 185.67,42.82 v2(185.67,26.43)
  IN2 w0.508: v2(192.23,29.8) 192.02,30.02 192.02,36.43 193.9,38.32 196.5,38.32 197.51,39.32 202.11,39.32 v2(202.79,38.65)
  IN3 w0.508: v2(192.23,29.8) 191.6,29.8 190.96,29.16 188.08,29.16 185.67,26.75 v2(185.67,26.43)
  BOTTOM w0.457: PR729.1 191.69,30.35 v2(192.23,29.8)
  BOTTOM w0.508: 155.71,112.79 PC742.2 ; PD704.2 v2(202.79,38.65)
  vias: v2(156.18,117.47) v2(156.48,118.04) v2(156.81,117.47) v2(157.12,118.04) v2(157.45,117.47) v2(157.75,118.04) v2(158.08,117.47) v2(158.39,118.04) v2(158.72,117.47) v3(158.62,116.24)
+19VB: length 356.9
  TOP w1.524: 205.13,24.59 205.32,24.59 210.51,19.4 222.22,19.4 225.13,22.31 ; 67.95,109.83 66.56,111.23 61.32,111.23 60.87,111.69 53.69,111.69 52.45,110.44 47.77,110.44 43.05,115.17 43.05,122.98 44.11,124.05 44.11,128.96
  TOP w2.032: 166.73,133.18 166.71,133.21 151.18,133.21 ; 68.22,133.24 68.22,133.25 86.25,133.25 88.98,135.98 100.67,135.98 ; 108.21,134.68 108.21,133.98 108.42,132.95 108.82,131.99 109.4,131.13 110.13,130.39 111,129.82 111.96,129.42 112.98,129.22 114.02,129.22 115.04,129.42 116,129.82 ; 124.92,130.96 127.18,133.21 144.83,133.21
  IN1 w1.524: 62.96,132.78 57.06,132.78 54.26,129.99 50.62,129.99 50.26,130.35 46.67,130.35
  IN1 w2.032: 68.27,133.18 68.28,133.18 86.44,133.18 89.24,135.98 103.52,135.98 ; 108.03,134.9 108.03,134.42 arc(108.39,132.64) 109.39,131.13 110.13,130.39 111,129.82 111.96,129.42 112.98,129.22 114.02,129.22 115.04,129.42 115.69,129.69
  IN2 w1.524: 229,42.38 229,40.79 229.89,39.9 229.89,34.06 226.33,30.5 226.33,24.27
  IN2 w2.032: 169.25,129.12 169.25,122.81 168.04,119.38 167.94,119.09 167.85,118.45 167.87,118.28 167.87,114.64
  BOTTOM w1.016: 173.57,49.87 173.57,49.55 169.71,45.7 PL302.1
  BOTTOM w2.032: 166.71,133.12 127.04,133.12 124.09,130.17 123.58,130.17 ; 167.85,113.82 167.85,119.81 170.04,126.19 170.04,129.6 170.01,129.63
  BOTTOM w4.064: 185.99,33.95 185.99,31.8 187.53,30.26 187.53,29.23 ; 167.53,79.53 166.58,80.48 166.58,96.92 ; 175.53,53.3 175.53,62.57
  vias: v2(44.44,130.28) v2(44.81,129.85) v2(44.88,130.68) v2(45.24,130.24) v2(45.21,129.41) v2(45.63,129.82) v2(64.03,132.71) v2(64.61,132.71) v2(65.19,132.71) v2(65.78,132.71) v2(66.36,132.71) v2(66.95,132.71) v2(106.89,136.94) v2(106.89,136.36) v2(107.47,136.94) v2(107.47,136.36) v2(108.06,136.94) v2(108.06,136.36) v2(108.64,136.94) v2(108.64,136.36) v2(116.5,131.04) v2(116.5,130.45) v2(117.02,131.33) v2(117.02,130.74) v2(117.61,131.33) v2(117.61,130.74) v2(118.19,131.33) v2(118.19,130.74) v2(166.79,112.43) v2(166.79,111.85) v2(167.38,112.43) v2(167.38,111.85) v2(167.75,132.05) v2(167.75,131.47) v2(167.96,112.43) v2(167.96,111.85) v2(168.33,132.05) v2(168.33,131.47) v2(168.55,112.43) v2(168.55,111.85) v2(168.92,132.05) v2(168.92,131.47) v2(169.5,132.05) v2(169.5,131.47) v2(203.47,25.17) v2(203.47,24.53) v2(203.47,23.9) v2(227.03,23.2) v2(227.03,22.61) v2(227.03,22.03) v2(228.3,43.65) v2(228.94,43.65) v2(229.57,43.65) v3(104.58,136.29)
+19VB_1.2V: length 23.6
  IN1 w0.254: v2(81.13,110.22) 81.13,110.56 81.6,111.02 85.43,111.02 86.86,109.59 89.3,109.59 89.81,109.09 89.81,107.27 90.25,106.83 90.25,106 89.68,105.43 89.68,100.16 88.98,99.46 87.29,99.46 v2(86.63,100.11)
  BOTTOM w0.254: PR208.1 v2(86.63,100.11)
  vias: v1(79.94,109.53) v2(80.5,110.22) v2(80.5,109.64) v2(80.5,109.05) v2(81.13,109.64) v2(81.13,109.05)
+19VB_+1.35VGPU:
  vias: v1(156.46,96.54)
+19VB_+1VALW:
  vias: v1(152.09,46.36)
+19VB_GPU: length 24.2
  IN3 w3.048: 66.19,112.93 68.54,112.93 70.69,115.09 70.69,127.83 69.28,129.25 65.23,129.25
  vias: v2(62.44,129.75) v2(62.44,129.17) v2(63.02,129.75) v2(63.02,129.17) v2(63.52,113.18) v2(63.52,112.6) v2(64.1,113.18) v2(64.1,112.6) v3(65.74,112.65)
+VCC_CORE: length 50.4
  TOP w0.457: v2(132.48,68.78) 132.93,68.78 PC1080.1 ; v2(132.48,65.99) 132.93,65.99 PC1082.1 ; PC1079.1 132.93,70.18 v2(132.48,70.18) ; v2(132.48,67.39) 132.93,67.39 PC1081.1 ; PC1070.1 135.28,66.24 v2(134.83,66.24) ; PC1073.1 135.28,67.64 v2(134.83,67.64) ; PC1074.1 137.75,66.88 v2(137.31,66.88) ; PC1078.1 132.93,71.58 v2(132.48,71.58) ; PC1076.1 134.01,64.46 v2(133.56,64.46) ; v2(133.56,63.07) 134.01,63.07 PC1077.1 ; v2(134.83,69.04) 135.28,69.04 PC1071.1 ; v2(137.31,65.48) 137.75,65.48 PC1075.1
  BOTTOM w0.102: 106.91,47.65 UC1.AM33 ; UC1.AM33 107.52,47.65 ; UC1.AM33 107.21,47.35 ; UC1.AM33 107.21,47.96 ; 119.45,46.44 UC1.G32 ; UC1.G32 119.72,46.47 ; UC1.G32 119.15,46.74 ; UC1.AM35 107.52,48.57 ; UC1.AM35 107.21,48.26 ; UC1.AM35 107.21,48.87 ; UC1.AM35 106.91,48.57 ; 107.52,46.74 UC1.AM32 ; UC1.AM32 106.95,47.01 ; UC1.AM32 107.21,47.05 ; 119.45,48.26 UC1.G35 ; UC1.G35 119.76,48.57 ; UC1.G35 119.72,48.3 ; UC1.G35 119.15,48.57 ; UC1.J37 119.29,49.94 ; UC1.J37 118.99,49.64 ; UC1.J37 118.99,50.25 ; UC1.J37 118.68,49.94 ; 108.46,50.4 UC1.AK38 ; UC1.AK38 108.15,50.7 ; UC1.AK38 108.42,50.66 ; UC1.AK38 107.85,50.4 ; 107.85,48.57 UC1.AK35 ; UC1.AK35 108.46,48.57 ; UC1.AK35 108.15,48.87 ; UC1.AK35 108.42,48.84 ; UC1.G33 119.45,47.96 ; UC1.G33 119.72,47.92 ; UC1.G33 119.15,47.65 ; 106.91,49.48 UC1.AM37 ; UC1.AM37 107.21,49.79 ; UC1.AM37 107.21,49.18 ; UC1.AM37 107.52,49.48 ; 108.46,49.48 UC1.AK37 ; UC1.AK37 108.15,49.18 ; UC1.AK37 108.42,49.22 ; UC1.AK37 107.85,49.48 ; 106.91,50.4 UC1.AM38 ; UC1.AM38 106.95,50.13 ; UC1.AM38 107.52,50.4 ; UC1.AM38 107.21,50.09 ; UC1.AL33 107.99,47.2 ; UC1.AL33 107.38,47.2 ; UC1.AL33 107.69,46.89 ; UC1.AL33 107.69,47.5 ; UC1.K40 118.52,51.62 ; UC1.K40 118.22,51.31 ; UC1.K40 118.83,51.31 ; UC1.K40 118.26,51.58 ; 107.69,48.72 UC1.AL37 ; UC1.AL37 107.99,49.03 ; UC1.AL37 107.38,49.03 ; UC1.AL37 107.69,49.33 ; 119.15,49.48 UC1.G37 ; UC1.G37 119.72,49.75 ; UC1.G37 119.45,49.79 ; UC1.G37 119.76,49.48 ; 118.22,48.57 UC1.K35 ; UC1.K35 118.83,48.57 ; UC1.K35 118.52,48.26 ; UC1.K35 118.26,48.3 ; 118.22,53.14 UC1.K43 ; UC1.K43 118.52,52.84 ; UC1.K43 118.26,52.87 ; UC1.K42 118.83,52.23 ; UC1.K42 118.22,52.23 ; UC1.K42 118.52,52.53 ; UC1.K42 118.52,51.92 ; UC1.AK33 108.42,47.39 ; UC1.AK33 108.15,47.35 ; UC1.AK33 108.46,47.65 ; UC1.AK33 107.85,47.65 ; UC1.J33 118.99,48.42 ; UC1.J33 119.29,48.11 ; UC1.J33 118.99,47.81 ; UC1.J33 118.68,48.11 ; 118.99,51.46 UC1.J40 ; UC1.J40 118.68,51.77 ; UC1.J40 119.29,51.77 ; UC1.J40 118.99,52.07 ; 119.15,52.23 UC1.G42 ; UC1.G42 119.45,51.92 ; UC1.G42 119.72,51.96 ; 118.99,45.98 UC1.J30 ; UC1.J30 119.29,46.28 ; UC1.J30 118.99,46.59 ; UC1.J30 118.68,46.28 ; 118.22,50.4 UC1.K38 ; UC1.K38 118.83,50.4 ; UC1.K38 118.26,50.13 ; UC1.K38 118.52,50.09 ; UC1.G40 119.72,51.58 ; UC1.G40 119.76,51.31 ; UC1.G40 119.15,51.31 ; UC1.G40 119.45,51.62 ; UC1.K37 118.26,49.75 ; UC1.K37 118.83,49.48 ; UC1.K37 118.22,49.48 ; UC1.K37 118.52,49.79 ; 108.15,51.01 UC1.AK40 ; UC1.AK40 108.42,51.05 ; UC1.AK40 108.46,51.31 ; UC1.G30 119.72,46.09 ; UC1.G30 119.15,45.83 ; UC1.G30 119.45,46.13 ; 118.83,47.65 UC1.K33 ; UC1.K33 118.52,47.96 ; UC1.K33 118.26,47.92 ; 107.69,50.55 UC1.AL40 107.99,50.86 ; UC1.G38 119.72,50.13 ; UC1.G38 119.45,50.09 ; UC1.G38 119.15,50.4 ; UC1.G38 119.76,50.4
  BOTTOM w0.152: UC1.A44 124.32,53.68 v2(124.48,53.52)
  BOTTOM w0.203: v2(123.78,51.21) UC1.A39 ; v2(123.65,46.44) 123.47,46.25 UC1.A30 ; UC1.A34 v2(123.73,48.73)
  vias: v2(106.82,49.97) v2(106.89,48.93) v2(106.91,48.09) v2(106.88,47.19) v2(108.38,50.88) v2(108.63,49.33) v2(108.63,48.72) v2(108.63,47.5) v2(109.04,46.42) v2(109.13,49.01) v2(109.21,54.41) v2(109.19,51.03) v2(109.15,50.39) v2(109.15,49.66) v2(109.15,48.39) v2(109.16,47.11) v2(109.27,47.69) v2(109.8,54.41) v2(109.77,51.02) v2(109.84,47.66) v2(110.38,54.41) v2(110.38,51.02) v2(110.4,47.66) v2(110.97,54.41) v2(110.99,51.02) v2(110.95,47.66) v2(112.1,52.24) v2(112.61,49.8) v2(112.61,47.41) v2(113.41,52.23) v2(113.81,49.8) v2(113.81,47.41) v2(114.68,52.24) v2(115.02,49.8) v2(115.02,47.41) v2(115.89,52.23) v2(116.23,49.8) v2(116.23,47.41) v2(117.1,52.25) v2(117.43,52.9) v2(117.38,51.75) v2(117.36,51.17) v2(117.36,50.58) v2(117.43,49.8) v2(117.43,49.01) v2(117.42,48.23) v2(117.43,47.41) v2(117.39,46.49) v2(117.74,52.23) v2(117.83,47.82) v2(117.93,51.33) v2(117.85,50.3) v2(117.93,49.46) v2(117.9,48.61) v2(118.33,52.67) v2(118.28,51.78) v2(118.33,49.94) v2(118.32,48.11) v2(119.72,46.32) v2(119.77,48.09) v2(133.56,61.8) v2(133.56,60.4) v2(135.44,62.02) v2(135.44,61.44) v2(135.91,64.4) v2(135.91,63.07) v2(136.67,70.62) v2(136.93,71.16) v2(137.26,70.62) v2(137.59,71.18) v2(137.84,70.62) v2(139.05,69.83) v2(139.05,69.07) v2(139.05,68.31) v2(142.18,70.58) v2(142.16,67.4) v2(142.44,71.13) v2(142.74,67.4) v2(142.77,70.58) v2(143.1,71.14) v2(143.33,67.4) v2(143.35,70.58) v2(143.91,67.4) v2(144.55,70.17) v2(144.55,69) v2(144.55,67.84) v2(145.13,69.59) v2(145.13,68.42) v2(145.13,67.25) v2(145.74,72.74) v2(145.74,71.98) v2(145.74,71.21) v2(145.71,70.17) v2(145.71,69) v2(145.71,67.84) v2(146.35,69.06) v2(146.35,68.47) v2(146.35,67.3) v2(146.4,73.42) v2(146.93,69.06) v2(146.93,67.89) v2(147.16,73.42) v2(147.52,69.06) v2(147.52,68.47) v2(147.52,67.3) v2(147.92,73.42) v2(148.1,69.06) v2(148.1,67.89) v3(147.29,65.91)
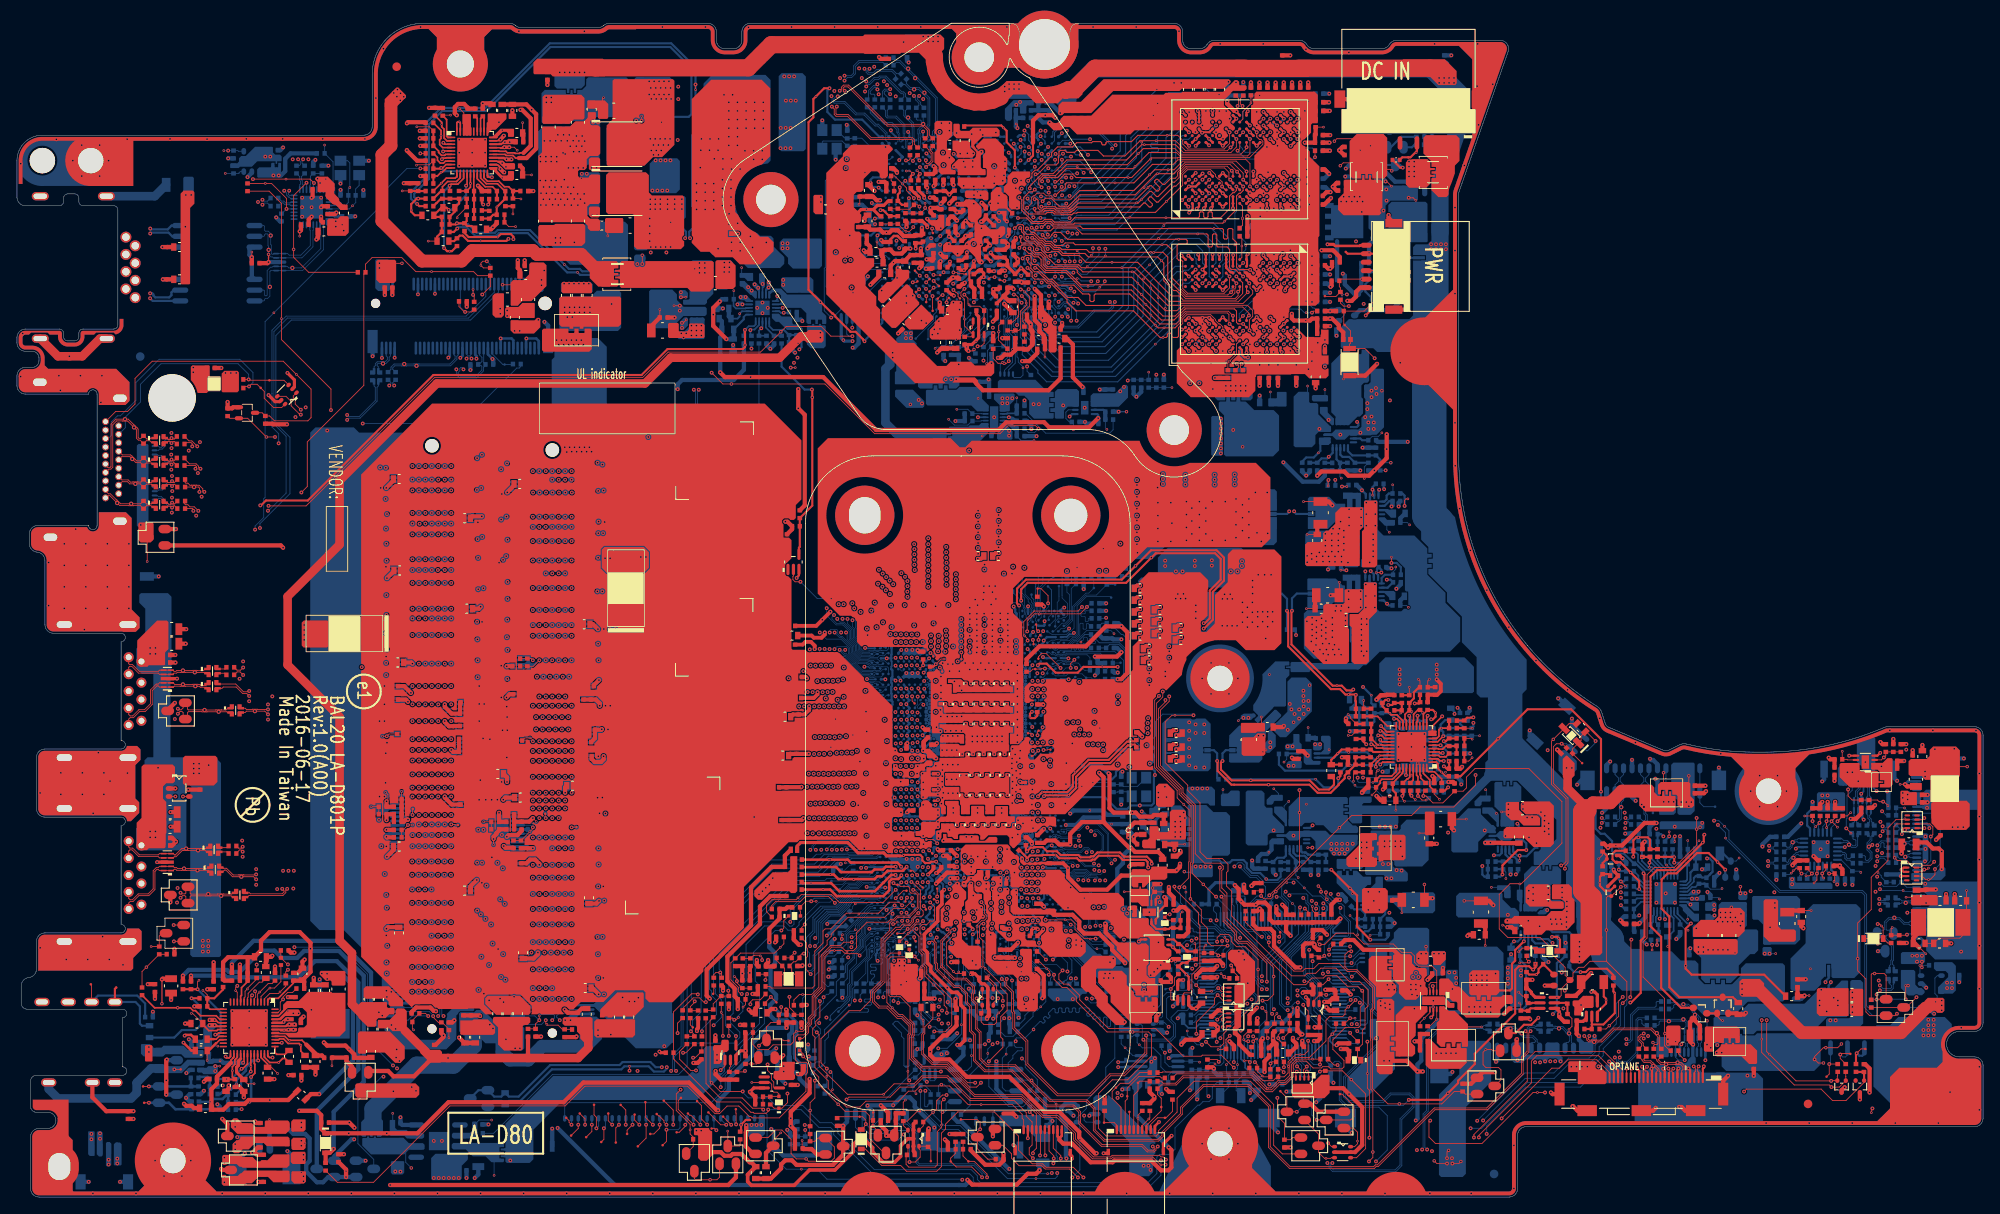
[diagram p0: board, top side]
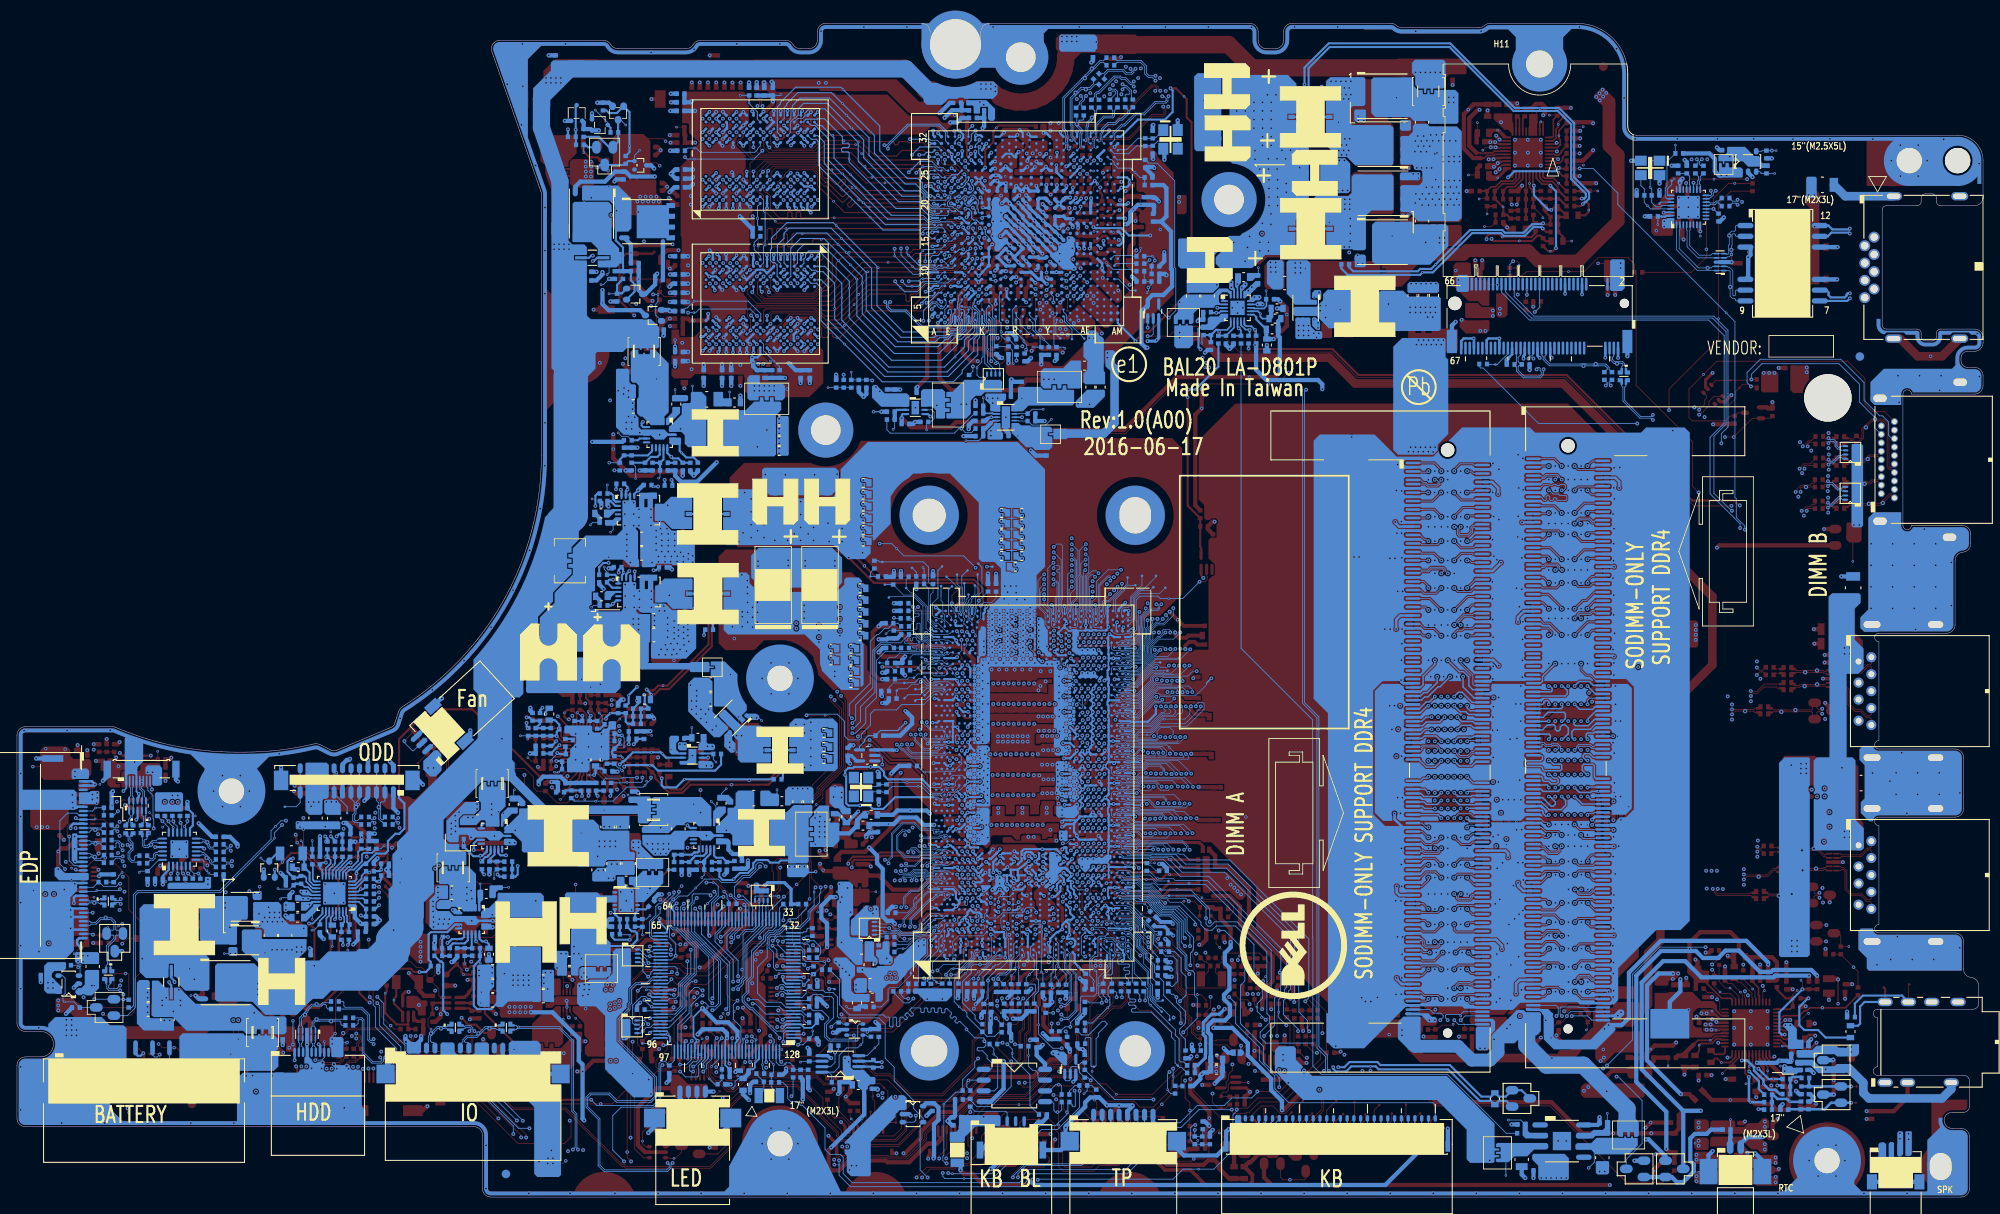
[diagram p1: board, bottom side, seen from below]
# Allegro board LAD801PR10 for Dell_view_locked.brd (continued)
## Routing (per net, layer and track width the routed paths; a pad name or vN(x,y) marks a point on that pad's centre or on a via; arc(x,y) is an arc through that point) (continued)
+VCC_CORE_G0: length 1.1
  TOP w0.254: TP32.1 118.03,46.76 118.01,46.74 v2(117.96,46.74)
  BOTTOM w0.254: UC1.K32 v2(117.96,46.74)
+VCC_CORE_G1: length 1
  TOP w0.254: TP33.1 108.53,46.76 v2(108.63,46.86)
  BOTTOM w0.254: v2(108.63,46.86) 108.53,46.76 108.17,46.76 UC1.AK32
+VCC_GT: length 124.1
  BOTTOM w0.102: UC1.AC70 111.84,68.82 ; UC1.AC70 111.84,68.21 ; UC1.AC70 112.15,68.51 ; UC1.AC70 112.11,68.78 ; 107.85,52.23 UC1.AK42 ; UC1.AK42 108.15,52.53 ; UC1.AK42 108.42,52.49 ; UC1.AK42 108.46,52.23 ; UC1.AA69 113.06,67.86 ; UC1.AA69 112.76,67.56 ; UC1.AA69 112.76,68.17 ; UC1.AA69 112.45,67.86 ; 116.11,68.51 UC1.N70 ; UC1.N70 116.41,68.82 ; UC1.N70 116.41,68.21 ; UC1.N70 116.72,68.51 ; UC1.AL53 107.69,58.48 ; UC1.AL53 107.69,57.87 ; UC1.AL53 107.99,58.17 ; UC1.AL53 107.38,58.17 ; 108.46,57.71 UC1.AK52 ; UC1.AK52 108.15,58.02 ; UC1.AK52 108.42,57.98 ; UC1.AK52 107.85,57.71 ; 113.67,68.21 UC1.W70 ; UC1.W70 113.4,68.25 ; UC1.W70 113.67,68.82 ; UC1.W70 113.37,68.51 ; UC1.R63 115.81,63.96 ; UC1.R63 115.19,63.96 ; UC1.R63 115.5,64.27 ; UC1.R63 115.5,63.66 ; UC1.AK45 108.15,54.36 ; UC1.AK45 108.46,54.06 ; UC1.AK45 107.85,54.06 ; UC1.AK45 108.42,54.32 ; 115.19,64.61 UC1.R64 ; UC1.R64 115.81,64.61 ; UC1.R64 115.5,64.92 ; UC1.R64 115.5,64.31 ; UC1.L64 117.06,64.35 ; UC1.L64 117.02,64.61 ; UC1.L64 117.33,64.92 ; UC1.L64 117.33,64.31 ; UC1.L67 117.33,66.87 ; UC1.L67 117.02,66.56 ; UC1.L67 117.33,66.26 ; UC1.L67 117.06,66.3 ; UC1.K50 118.52,57.1 ; UC1.K50 118.83,56.8 ; UC1.K50 118.52,56.49 ; UC1.K50 118.22,56.8 ; UC1.U68 114.85,67.48 ; UC1.U68 114.59,66.91 ; UC1.U68 114.89,67.21 ; UC1.U68 114.32,66.95 ; UC1.AK60 108.42,62.02 ; UC1.AK60 107.85,62.29 ; UC1.AK60 108.15,61.98 ; UC1.AK60 108.46,62.29 ; UC1.R69 115.81,67.86 ; UC1.R69 115.5,67.56 ; UC1.R69 115.19,67.86 ; UC1.R69 115.5,68.17 ; UC1.AL60 107.69,62.13 ; UC1.AL60 107.38,61.83 ; UC1.AL60 107.99,61.83 ; UC1.AL60 107.69,61.52 ; UC1.R67 115.5,66.87 ; UC1.R67 115.19,66.56 ; UC1.R67 115.23,66.3 ; UC1.R67 115.5,66.26 ; UC1.W64 113.4,64.35 ; UC1.W64 113.37,64.61 ; UC1.W64 113.67,64.31 ; UC1.W64 113.67,64.92 ; 118.99,60.3 UC1.J55 ; UC1.J55 118.99,59.69 ; UC1.J55 118.68,60 ; UC1.AC71 111.84,69.47 ; UC1.AC71 111.84,68.86 ; UC1.AC71 112.15,69.16 ; UC1.AC71 112.11,69.43 ; 118.22,61.37 UC1.K58 ; UC1.K58 118.52,61.68 ; UC1.K58 118.83,61.37 ; UC1.K58 118.52,61.07 ; UC1.N63 116.41,64.27 ; UC1.N63 116.11,63.96 ; UC1.N63 116.41,63.66 ; UC1.N63 116.72,63.96 ; 117.33,65.61 UC1.L66 ; UC1.L66 117.33,66.22 ; UC1.L66 117.06,65.65 ; UC1.L66 117.02,65.91 ; UC1.M62 116.87,63.8 ; UC1.M62 117.18,63.49 ; UC1.M62 116.87,63.19 ; UC1.M62 116.57,63.49 ; UC1.L63 117.06,64.23 ; UC1.L63 117.33,63.66 ; UC1.L63 117.33,64.27 ; UC1.L63 117.02,63.96 ; 107.85,55.88 UC1.AK48 ; UC1.AK48 108.15,55.58 ; UC1.AK48 108.46,55.88 ; UC1.AK48 108.15,56.19 ; UC1.R70 115.5,68.82 ; UC1.R70 115.19,68.51 ; UC1.R70 115.81,68.51 ; UC1.R70 115.5,68.21 ; 107.52,57.71 UC1.AM52 107.21,57.41 ; 118.99,57.56 UC1.J50 ; UC1.J50 118.68,57.26 ; UC1.J50 118.99,56.95 ; 116.41,64.31 UC1.N64 ; UC1.N64 116.11,64.61 ; UC1.N64 116.72,64.61 ; UC1.N64 116.41,64.92 ; 107.85,59.54 UC1.AK55 ; UC1.AK55 108.15,59.85 ; UC1.AK55 108.42,59.81 ; UC1.AK55 108.46,59.54 ; 107.69,56.04 UC1.AL50 ; UC1.AL50 107.99,56.34 ; UC1.AL50 107.69,56.65 ; UC1.AL50 107.38,56.34 ; 118.99,55.12 UC1.J46 ; UC1.J46 118.68,55.43 ; UC1.J46 118.99,55.73 ; UC1.AM58 107.52,61.37 ; UC1.AA67 113.06,66.56 ; UC1.AA67 112.49,66.3 ; UC1.AA67 113.02,66.83 ; UC1.AA67 112.76,66.26 ; 113.37,69.16 UC1.W71 ; UC1.W71 113.98,69.16 ; UC1.W71 113.67,68.86 ; UC1.W71 113.67,69.47 ; 108.46,53.14 UC1.AK43 ; UC1.AK43 108.42,52.87 ; UC1.AK43 107.85,53.14 ; UC1.AK43 108.15,52.84 ; UC1.R65 115.81,65.26 ; UC1.R65 115.5,65.57 ; UC1.R65 115.5,64.96 ; UC1.R65 115.19,65.26 ; 108.15,54.66 UC1.AK46 ; UC1.AK46 108.46,54.97 ; UC1.AK46 108.15,55.28 ; UC1.AK46 107.85,54.97 ; UC1.AK58 108.15,61.68 ; UC1.AK58 108.46,61.37 ; UC1.AK58 108.42,61.64 ; UC1.AK58 107.85,61.37 ; 118.99,62.44 UC1.J60 118.68,62.74 ; 118.99,59.39 UC1.J53 ; UC1.J53 118.68,59.08 ; UC1.J53 118.99,58.78 ; UC1.L69 117.06,67.6 ; UC1.L69 117.33,68.17 ; UC1.L69 117.33,67.56 ; UC1.L69 117.02,67.86 ; 115.5,65.61 UC1.R66 ; UC1.R66 115.5,66.22 ; UC1.R66 115.23,65.65 ; UC1.R66 115.19,65.91 ; UC1.AK53 108.42,58.36 ; UC1.AK53 108.46,58.63 ; UC1.AK53 108.15,58.32 ; UC1.AK53 107.85,58.63 ; UC1.N66 116.72,65.91 ; UC1.N66 116.15,66.18 ; UC1.N66 116.68,66.18 ; UC1.N66 116.41,66.22 ; 118.52,55.58 UC1.K48 ; UC1.K48 118.52,56.19 ; UC1.K48 118.83,55.88 ; UC1.K48 118.22,55.88 ; 118.99,62.13 UC1.J58 ; UC1.J58 118.68,61.83 ; UC1.J58 118.99,61.52 ; 113.37,65.91 UC1.W66 ; UC1.W66 113.4,65.65 ; UC1.W66 113.67,66.22 ; UC1.W66 113.67,65.61 ; UC1.W67 113.67,66.87 ; UC1.W67 113.37,66.56 ; UC1.W67 113.4,66.3 ; UC1.W67 113.67,66.26 ; UC1.L68 117.06,66.95 ; UC1.L68 117.33,67.52 ; UC1.L68 117.02,67.21 ; UC1.L68 117.33,66.91 ; 117.02,68.51 UC1.L70 ; UC1.L70 117.33,68.21 ; UC1.L70 117.33,68.82 ; UC1.L70 117.06,68.25 ; UC1.K60 118.52,62.59 ; UC1.K60 118.83,62.29 ; UC1.K60 118.52,61.98 ; UC1.K60 118.22,62.29 ; UC1.N69 116.41,68.17 ; UC1.N69 116.41,67.56 ; UC1.N69 116.11,67.86 ; UC1.N69 116.72,67.86 ; UC1.L65 117.06,65 ; UC1.L65 117.33,64.96 ; UC1.L65 117.33,65.57 ; UC1.L65 117.02,65.26 ; UC1.R68 115.5,67.52 ; UC1.R68 115.23,66.95 ; UC1.R68 115.19,67.21 ; UC1.R68 115.5,66.91 ; 118.52,58.32 UC1.K53 ; UC1.K53 118.22,58.63 ; UC1.K53 118.83,58.63 ; UC1.K53 118.52,58.93 ; 113.06,64.61 UC1.AA64 ; UC1.AA64 112.49,64.35 ; UC1.AA64 112.76,64.31 ; UC1.AA64 112.76,64.92 ; UC1.AC67 112.11,66.3 ; UC1.AC67 112.15,66.56 ; UC1.AC67 111.84,66.26 ; UC1.N71 116.72,69.16 ; UC1.N71 116.41,68.86 ; UC1.N71 116.11,69.16 ; UC1.N71 116.41,69.47 ; 107.69,60.3 UC1.AL56 ; UC1.AL56 107.99,60 ; UC1.AL56 107.69,59.69 ; 114.28,69.16 UC1.U71 ; UC1.U71 114.89,69.16 ; UC1.U71 114.59,69.47 ; UC1.U71 114.59,68.86 ; 118.22,59.54 UC1.K55 ; UC1.K55 118.52,59.24 ; UC1.K55 118.83,59.54 ; UC1.K55 118.52,59.85 ; 118.99,56.65 UC1.J48 ; UC1.J48 118.99,56.04 ; UC1.J48 118.68,56.34 ; UC1.W68 113.4,66.95 ; UC1.W68 113.67,66.91 ; UC1.W68 113.67,67.52 ; UC1.W68 113.37,67.21 ; UC1.U65 114.89,65.26 ; UC1.U65 114.32,65 ; UC1.U65 114.85,65.53 ; UC1.U65 114.59,64.96 ; 118.99,57.87 UC1.J52 ; UC1.J52 118.99,58.48 ; UC1.J52 118.68,58.17 ; 111.84,67.52 UC1.AC68 112.11,67.48 ; UC1.AC66 111.84,66.22 ; UC1.AC66 112.11,66.18 ; UC1.AC66 112.15,65.91 ; 118.68,53.6 UC1.J43 118.99,53.9 ; UC1.AC69 112.11,68.13 ; UC1.AC69 111.84,68.17 ; UC1.AC69 111.84,67.56 ; UC1.AC69 112.15,67.86 ; 118.52,57.41 UC1.K52 ; UC1.K52 118.22,57.71 ; UC1.K52 118.83,57.71 ; UC1.K52 118.52,58.02 ; 107.52,55.88 UC1.AM48 107.21,56.19 ; UC1.W65 113.67,65.57 ; UC1.W65 113.4,65 ; UC1.W65 113.67,64.96 ; UC1.W65 113.37,65.26 ; UC1.AL46 107.99,54.51 ; UC1.AL46 107.69,54.21 ; UC1.AL46 107.69,54.82 ; UC1.W69 113.4,67.6 ; UC1.W69 113.67,67.56 ; UC1.W69 113.67,68.17 ; UC1.W69 113.37,67.86 ; UC1.AA66 112.49,66.18 ; UC1.AA66 113.02,66.18 ; UC1.AA66 112.76,66.22 ; UC1.AA66 113.06,65.91 ; 107.85,60.46 UC1.AK56 ; UC1.AK56 108.15,60.15 ; UC1.AK56 108.46,60.46 ; UC1.AK56 108.42,60.19 ; 115.19,69.16 UC1.R71 ; UC1.R71 115.81,69.16 ; UC1.R71 115.5,68.86 ; UC1.R71 115.5,69.47 ; 116.41,66.26 UC1.N67 ; UC1.N67 116.15,66.3 ; UC1.N67 116.72,66.56 ; UC1.N67 116.68,66.83 ; 113.67,63.66 UC1.W63 ; UC1.W63 113.37,63.96 ; UC1.W63 113.67,64.27 ; UC1.W63 113.4,64.23 ; UC1.Y62 113.52,63.49 ; UC1.Y62 112.91,63.49 ; UC1.Y62 113.21,63.8 ; UC1.Y62 113.21,63.19 ; 112.76,63.66 UC1.AA63 ; UC1.AA63 113.06,63.96 ; UC1.AA63 112.45,63.96 ; UC1.AA63 112.76,64.27 ; UC1.AA71 112.76,69.47 ; UC1.AA71 112.45,69.16 ; UC1.AA71 112.76,68.86 ; UC1.AA71 113.06,69.16 ; 107.52,58.63 UC1.AM53 107.21,58.32 ; 118.99,60.61 UC1.J56 ; UC1.J56 118.68,60.91 ; UC1.J56 118.99,61.22 ; UC1.L62 117.52,63.23 ; UC1.L62 118.09,63.49 ; UC1.L62 117.48,63.49 ; UC1.L62 117.79,63.19 ; 118.99,54.21 UC1.J45 ; UC1.J45 118.99,54.82 ; UC1.J45 118.68,54.51 ; 107.69,52.38 UC1.AL43 ; UC1.AL43 107.69,52.99 ; UC1.AL43 107.99,52.68 ; 117.33,68.86 UC1.L71 ; UC1.L71 117.02,69.16 ; UC1.L71 117.06,69.43 ; UC1.L71 117.06,68.9 ; 107.21,57.1 UC1.AM50 ; UC1.AM50 107.52,56.8 ; UC1.AM50 107.21,56.49 ; UC1.K56 118.83,60.46 ; UC1.K56 118.52,60.15 ; UC1.K56 118.22,60.46 ; UC1.K56 118.52,60.76 ; UC1.AA70 113.06,68.51 ; UC1.AA70 112.76,68.21 ; UC1.AA70 112.76,68.82 ; UC1.AA70 112.45,68.51 ; UC1.AM56 107.52,60.46 ; UC1.T62 115.04,63.8 ; UC1.T62 114.74,63.49 ; UC1.T62 115.35,63.49 ; UC1.T62 115.04,63.19 ; UC1.AK50 108.42,56.53 ; UC1.AK50 107.85,56.8 ; UC1.AK50 108.46,56.8 ; UC1.AK50 108.15,56.49
  BOTTOM w0.127: v2(100.26,61.12) 100.29,61.09 UC1.BB57 ; UC1.AK70 108.33,69.69 v2(108.35,69.71)
  BOTTOM w0.203: UC1.A48 123.33,55.99 v2(123.9,55.99) ; UC1.A53 123.34,58.83 v2(123.67,58.83) ; UC1.AC64 UC1.AC65 UC1.AC66 ; v2(124.67,66.57) 124.52,66.41 124.14,66.41 123.83,66.1 123.38,66.1 123.35,66.08 UC1.A66 ; v2(124.05,61.09) 124.05,61.1 124.03,61.12 UC1.A58 ; UC1.A62 123.98,63.6 v2(124.02,63.56) ; UC1.AC67 UC1.AC68
  BOTTOM w0.254: UC1.AU58 104.09,61.25 104.09,61.24 104.21,61.11 v2(104.21,60.93) ; v2(104.31,64.56) 104.3,64.56 103.96,64.22 UC1.AU63 ; v2(100.34,66.31) 100.57,66.08 101.08,66.08 101.09,66.07 UC1.BB66
  BOTTOM w0.508: RC155.1 v2(117.37,73.56)
  vias: v2(108.47,55.44) v2(108.94,57.49) v2(108.91,54.96) v2(108.99,61.42) v2(108.99,60.36) v2(108.99,59.54) v2(108.99,58.83) v2(108.97,56.71) v2(109.19,63) v2(109.74,56.7) v2(109.81,62.89) v2(110,62.06) v2(110.12,58.18) v2(110.31,56.7) v2(110.38,62.89) v2(110.87,56.71) v2(111.15,62.06) v2(111.32,58.18) v2(111.42,56.72) v2(111.84,63.01) v2(112.39,69.54) v2(112.39,68.83) v2(112.4,68.19) v2(112.38,67.52) v2(112.39,66.23) v2(112.38,62.25) v2(112.53,60.6) v2(112.53,58.18) v2(112.53,55.83) v2(112.8,63.01) v2(113.02,70.5) v2(113.23,68.84) v2(113.21,68.19) v2(113.23,67.51) v2(113.23,66.87) v2(113.23,66.24) v2(113.23,65.6) v2(113.2,64.25) v2(113.3,69.84) v2(113.26,64.86) v2(113.33,62.25) v2(113.37,80.99) v2(113.37,79.72) v2(113.37,78.45) v2(113.37,77.18) v2(113.37,75.91) v2(113.69,63.01) v2(113.74,60.6) v2(113.74,58.18) v2(113.74,55.83) v2(114.05,72.09) v2(114.04,71.33) v2(113.96,70.5) v2(114.13,74.64) v2(114.07,68.84) v2(114.07,66.92) v2(114.1,64.93) v2(114.22,62.25) v2(114.64,63.01) v2(114.68,72.09) v2(114.9,69.92) v2(114.94,60.6) v2(114.94,58.18) v2(114.94,55.83) v2(115.03,68.17) v2(115.03,66.19) v2(115.03,64.94) v2(115.03,64.28) v2(115.06,71.38) v2(115.06,68.88) v2(115.06,67.53) v2(115.06,66.9) v2(115.06,65.58) v2(115.17,62.25) v2(115.38,72.09) v2(115.46,70.58) v2(115.53,63.01) v2(115.78,80.48) v2(115.78,79.21) v2(115.78,77.94) v2(115.78,76.67) v2(115.78,75.4) v2(115.95,64.28) v2(115.97,68.88) v2(115.98,68.15) v2(115.98,67.51) v2(116,66.27) v2(115.98,64.91) v2(116.06,62.25) v2(116.15,60.6) v2(116.15,58.18) v2(116.15,55.83) v2(116.42,63.01) v2(116.89,68.85) v2(116.86,68.17) v2(116.86,67.51) v2(116.89,66.87) v2(116.89,66.24) v2(116.86,65.58) v2(116.89,64.92) v2(116.86,64.25) v2(116.95,62.25) v2(117.3,63.01) v2(117.36,60.6) v2(117.36,58.18) v2(117.36,55.83) v2(118,62.76) v2(118,61.8) v2(118,60.91) v2(118,59.96) v2(118,59.07) v2(118,58.18) v2(118,57.23) v2(118,56.34) v2(118,55.45) v2(118,54.5) v2(118,53.68) v2(132.1,84.02) v2(132.1,82.63) v2(132.1,81.23) v2(132.1,79.83) v2(132.1,78.43) v2(132.1,77.04) v2(132.16,76.03) v2(134.54,83.72) v2(134.58,81.93) v2(134.58,80.41) v2(134.58,78.89) v2(134.58,77.36) v2(136.1,81.93) v2(136.1,77.36) v2(137.94,82.06) v2(137.94,80.54) v2(137.94,79.01) v2(137.94,77.49) v2(138.58,81.3) v2(138.58,79.77) v2(138.58,78.25) v2(139.47,82.06) v2(139.47,80.54) v2(139.47,79.01) v2(139.47,77.49) v2(140.23,81.3) v2(140.23,79.77) v2(140.23,78.25) v2(140.99,82.06) v2(140.99,77.49) v2(142.51,82.06) v2(142.51,77.49) v2(143.78,82.38) v2(143.78,80.85) v2(143.78,79.33) v2(143.78,77.81) v2(144.55,81.68) v2(144.55,80.16) v2(144.55,78.63) v2(145.31,82.38) v2(145.31,80.85) v2(145.31,79.33) v2(145.31,77.81) v2(146.07,83.14) v2(146.26,78.38) v2(146.77,77.36) v2(147.47,83.14) v2(147.53,78.31) v3(136.23,79.52)
+VCC_SA: length 16
  TOP w0.457: PC1058.1 137.18,51.45 v2(136.74,51.45) ; PC1059.1 137.18,52.84 v2(136.74,52.84) ; v2(136.74,54.5) 137.18,54.5 PC1060.1
  BOTTOM w0.102: 119.45,43.69 UC1.G27 ; UC1.G27 119.45,44.3 ; UC1.G27 119.72,44.26 ; UC1.G27 119.15,44 ; UC1.J22 119.29,41.71 ; UC1.J22 118.68,41.71 ; UC1.J22 118.99,42.02 ; UC1.G23 119.72,42.44 ; UC1.G23 119.15,42.17 ; UC1.G23 119.45,42.47 ; 119.15,43.08 UC1.G25 ; UC1.G25 119.45,42.78 ; UC1.G25 119.45,43.39 ; UC1.G25 119.76,43.08 ; UC1.K28 118.83,44.91 ; UC1.K28 118.52,44.61 ; UC1.K28 118.52,45.22 ; UC1.K28 118.22,44.91 ; UC1.J27 118.99,44.76 ; UC1.J27 118.68,44.45 ; UC1.J27 118.99,44.15 ; UC1.J27 119.29,44.45 ; UC1.G28 119.72,44.64 ; UC1.G28 119.15,44.91 ; UC1.G28 119.45,44.61 ; 118.99,42.32 UC1.J23 ; UC1.J23 118.68,42.63 ; UC1.J23 119.29,42.63 ; UC1.J23 118.99,42.93 ; UC1.K27 118.52,44.3 ; UC1.K27 118.26,44.26 ; UC1.K27 118.83,44 ; 118.22,42.17 UC1.K23 ; UC1.K23 118.83,42.17 ; UC1.K23 118.52,41.86 ; UC1.K23 118.52,42.47 ; 118.52,45.52 UC1.K30 ; UC1.K30 118.26,45.56 ; UC1.K30 118.22,45.83 ; UC1.K25 118.26,42.82 ; UC1.K25 118.22,43.08 ; UC1.K25 118.52,42.78 ; UC1.K25 118.83,43.08
  vias: v2(108.69,42.93) v2(108.69,42.35) v2(110,43.33) v2(111.51,43.9) v2(112.72,43.9) v2(113.93,43.9) v2(115.13,43.9) v2(116.34,43.9) v2(117.39,42.41) v2(117.58,43.9) v2(118.08,44.47) v2(118.05,42.79) v2(119.71,44.45) v2(119.84,43.52) v2(138.26,56.03) v2(138.26,55.01) v2(138.26,53.99) v2(138.26,52.98) v2(138.26,51.96) v2(138.26,50.95) v2(139.02,55.77) v2(139.02,54.76) v2(139.02,50.69) v2(140.04,55.77) v2(140.04,54.76) v2(140.04,50.69) v3(118.66,44.1)
+VDD_CT: length 8.8
  TOP w0.102: v1(99.32,117.15) 99.41,117.24 LV3.2
  TOP w0.508: v2(108.98,117.2) 109.38,117.6 CV63.1 ; v2(101.8,117.62) 101.41,117.62 100.96,118.07 CV61.1 99.43,118.07 LV3.2 ; CV62.1 108.16,117.94 v2(107.68,117.94)
  BOTTOM w0.381: UV1.AB20 108.5,116.72 v2(108.98,117.2) ; v2(108.98,117.2) UV1.AB21 108.24,117.94 v2(107.68,117.94) ; v2(108.98,117.2) UV1.AA20 ; v2(108.98,117.2) 109.26,117.49 109.46,117.68 UV1.AA21
+VDDR3: length 16.9
  IN3 w0.508: v2(107.37,115.43) 103.09,115.43 102.47,114.8 v2(101.21,114.8)
  BOTTOM w0.381: v2(107.37,115.43) 107.39,115.44 108.19,115.44 UV1.AB18 UV1.AA18 UV1.AA17 109.07,114.33 v2(108.97,114.33) 108.58,114.72 UV1.AB17
  BOTTOM w0.508: LV4.2 97.8,116.11 CV123.1 97.89,117.08 CV64.1 99.68,117.08 v1(100.2,116.56) 100.58,116.18 100.58,115.17 100.96,114.8 v2(101.21,114.8)
GND: length 3018.4
  TOP w0.152: v2(29.67,110.32) 29.67,110.82 29.67,110.83 v3(29.67,111.23) ; v2(17.1,25.68) v3(17.1,22.82)
  TOP w0.203: UZ3.11 167.06,21.45 v2(166.81,21.2)
  TOP w0.254: v2(139.32,111.19) 139.43,111.09 UV14.R1 ; UV12.C3 139.43,118.85 v2(139.83,118.45) ; v2(147.03,119.25) 147.03,119.24 UV12.N3 ; UX1.5 v2(216.11,52.08) ; v2(140.61,124.1) 140.26,124.45 UV12.D10 ; UV12.U12 150.63,126.05 v2(151.03,125.65) ; UV14.K13 v2(143.03,101.43) ; UV12.F10 141.83,124.45 v2(142.23,124.05) 142.63,124.44 UV12.G10 ; CV11.2 RV13.2 102.88,115.75 102.18,116.45 v2(101.86,116.45) ; UV14.R4 v2(139.03,108.63) UV14.R3 ; v2(143.09,99.77) 143.43,100.11 UV14.K14 ; v2(150.23,128.05) 150.63,127.65 UV12.U14 ; UV12.H13 143.43,126.85 v2(143.83,127.25) 143.43,127.65 UV12.H14 ; UV14.E1 147.02,111.04 v2(147.02,111.14) ; v2(138.23,125.65) 137.83,126.05 UV12.A12 ; UV14.C11 v2(149.43,103.03) UV14.B10 ; UV14.L5 v2(142.23,107.03) UV14.M5 ; UV14.R14 v2(139.03,100.63) ; v2(147.83,124.85) 148.23,124.45 UV12.P10 ; UV14.N14 v2(141.43,99.83) ; UV12.C13 UV12.C14 139.43,128.01 v2(139.28,128.16) ; v2(149.43,124.85) 149.83,124.45 UV12.T10 ; UV14.A3 v2(150.23,108.63) 149.43,108.63 UV14.C4 ; UV14.R12 v2(139.03,102.23) UV14.R11 ; v2(150.29,111.02) 150.63,110.68 UV14.A1 ; v2(145.18,128.13) 145.03,127.97 UV12.K14 ; UV12.M5 146.63,120.45 v2(147.03,120.05) ; UV14.N12 v2(141.43,101.43) ; v2(141.03,111.21) 141.03,111.18 141.03,111.18 UV14.N1 ; v2(191.1,15.13) 191.35,14.88 JSSD1.16 ; UV12.L5 145.83,121.01 v2(145.83,121.01) ; UV12.K2 145.43,117.65 v2(145.43,117.65) 145.03,117.25 UV12.K1 ; UV14.M10 v2(142.23,103.83) UV14.L10 ; JSSD1.13 192.85,15.07 192.79,15.13 v2(192.79,15.13) ; UV12.M10 146.63,124.44 v2(146.23,124.05) 145.83,124.45 UV12.L10 ; UV12.E3 141.03,118.85 v2(141.43,118.45) ; v2(151.03,116.85) 150.63,117.25 UV12.U1 ; v2(187.8,15.99) 188.85,14.94 JSSD1.21 ; UV14.F5 v2(146.23,107.03) UV14.G5 ; UV12.E12 141.03,126.03 140.64,125.65 139.85,125.65 v2(139.79,125.59) 139.43,125.96 UV12.C12 ; v2(143.43,116.68) 143.43,116.68 UV12.H1 UV12.H2 ; UV12.N14 147.43,127.65 v2(147.03,128.05) ; v2(138.23,99.83) UV14.U14 ; UV14.A14 150.63,100.23 v2(151,99.86) ; v2(151.2,101.53) 150.93,101.53 150.63,101.83 UV14.A12 ; v2(91.97,73.05) 91.97,73.1 92.24,73.37 UC2.3 ; RP1.3 v2(222.21,37.87) ; UV14.G10 v2(146.23,103.83) UV14.F10 ; v2(147.85,103.77) 148.2,103.43 UV14.D10 ; v2(149.14,116.68) 149.03,116.79 UV12.R1 ; UV14.N3 v2(141.43,108.63) ; UV12.R11 149.03,125.25 v2(149.43,125.65) 149.03,126.05 UV12.R12 ; UV14.P10 v2(140.63,103.03) ; v2(139.16,116.63) 139.43,116.9 UV12.C1 ; UV12.N12 147.43,126.05 v2(147.03,126.45) ; v2(194.16,15.13) 194.35,14.95 JSSD1.10 ; v2(137.46,128.02) UV12.A14 ; UV12.C11 139.43,125.24 v2(139.03,124.85) 138.63,124.45 UV12.B10 ; UV14.H14 v2(145.03,99.66) ; UV12.R3 149.03,118.85 v2(149.43,119.25) 149.03,119.65 UV12.R4 ; v2(149.18,99.71) 149.03,99.87 UV14.C14 ; v2(195.98,15.17) 195.85,15.04 JSSD1.7 ; v2(132.32,30.15) 132.57,30.4 UZ2.5 ; UV12.C4 139.03,119.25 v2(138.23,119.25) 137.83,118.85 UV12.A3 ; v2(147.45,116.68) 147.43,116.7 UV12.N1 ; v2(149.43,127.25) 149.03,127.65 UV12.R14 ; v2(104.13,119.14) 104.13,118.52 103.9,118.3 RV12.2 104.37,117.08 CV28.2 ; v2(147.44,99.7) 147.43,99.71 UV14.E14 ; UV12.E14 141.03,128.16 v2(141.02,128.17) ; UV14.B5 149.59,107.19 v2(149.59,106.99) ; v2(149.43,120.85) 149.83,120.45 UV12.T5 ; v2(140.84,116.68) 141.03,116.86 UV12.E1 ; v2(197.15,15.18) 197.35,14.98 JSSD1.4 ; UV14.U12 137.46,101.46 v2(137.38,101.46) ; UV12.A1 137.83,117.2 v2(138.17,116.85) ; UV14.C1 149.03,110.97 v2(149.3,111.25) ; JSSD1.1 198.85,15.14 198.97,15.26 v2(198.97,15.42) ; v2(145.43,126.45) 145.03,126.85 UV12.K13 ; UV12.U3 150.63,118.85 v2(150.23,119.25) ; v2(134.6,35.39) 134.56,35.39 134.31,35.14 UZ1.5 ; CV89.2 116.49,116.99 CV53.2 ; UV14.E3 v2(147.03,109.43) ; UV12.G5 142.63,120.45 v2(142.23,120.85) 141.83,120.45 UV12.F5 ; UV14.H2 145.09,109.89 145.09,110.57 UV14.H1 145.03,111.12 v2(145.18,111.28) ; UV14.T10 v2(139.03,103.03) ; RP1.2 222.53,38.37 v2(222.28,38.62) 222.54,38.87 RP1.1 ; UV12.B5 138.63,120.45 v2(139.03,120.85) ; JDB1.2 v2(119.24,6.95) ; UV14.C12 v2(149.43,101.43) UV14.C13 ; UV14.E12 v2(147.03,101.43) ; UV14.U3 v2(138.23,108.63) ; v2(144.63,100.63) UV14.H13 ; UV14.K2 UV14.K1 143.43,111.12 v2(143.46,111.15) ; UV14.U1 v2(137.36,111.09) ; UV14.T5 v2(139.03,107.03) ; UV14.C3 v2(148.63,109.43)
  TOP w0.305: CV26.2 103,112.98 103.43,113.41 103.86,113.41 104.48,112.78 CV35.2 ; JPWR1.6 158.46,112.31 158.38,112.24 155.46,112.24 155.28,112.42 ; v2(134.7,8.86) 134.22,8.38 JDEG1.10
  TOP w0.356: CC65.2 108.11,38.7 v2(107.46,38.06)
  TOP w0.381: PC1085.2 118.43,48.92 v2(118.32,49.03) ; UC9.3 138.21,22.63 138.59,22.25 v2(139.07,22.25) ; UC5.3 84.81,16.74 85.33,17.26 v2(85.93,17.26) ; JDEG1.12 135.22,6.27 v2(136.19,7.24) ; CV52.2 116.82,109.84 CV176.2 118.42,109.61 v2(118.43,109.61) 118.49,109.61 CV177.2 ; CV52.2 116.82,110.52 CV40.2 CV51.2 115.36,110.87 114.86,111.37 v2(114.86,111.45) ; CV52.2 115.92,109.98 CV112.2 ; CV118.2 112.95,108.89 113.41,109.36 RV2.1 114.03,109.01 v2(114.03,108.55) 113.78,108.55 113.44,108.2 CV73.2 113.44,107.53 CV125.2 ; EU2601.3 v2(18.88,61.17) ; v2(86.46,12.41) 86.92,12.87 UC6.3 ; PQ1.1 185.11,21.11 184.73,20.73 184.08,20.73 PR10.1 ; v2(154.58,112.42) 155.28,112.42 ; v2(107.37,114.43) 107.37,114.6 106.79,115.18 CV29.2 RV9.2 ; v2(116.83,37.65) 116.69,37.51 CC55.2 ; v2(108.63,48.11) 108.57,48.05 PC1030.2 ; PQ721.3 188.82,37.84 PC790.2 188.82,37.98 188.48,38.33 188.48,38.34 188.33,38.48 v2(188.33,38.63) ; v2(106,111.92) 106,112.54 CV21.2 106.69,112.57 CV20.2 ; CV100.2 111.33,109.37 111.7,109.37 v2(111.7,109.36) 111.97,109.63 CV74.2 ; v2(110.51,106.36) 110.38,106.49 110.23,106.49 109.71,107.01 CV104.2 ; PQ2.1 179.1,23.57 178.63,24.03 178.63,24.17 178.17,24.63 PR29.2 ; v2(185.69,24.21) 186.08,24.21 186.41,23.88 PQ1.4 ; CV76.2 110.05,110 v2(110.05,110.38) ; PQ2.4 181.54,22.27 181.92,21.89 v2(181.92,21.6) ; v2(152.03,23.58) 152.03,23.57 152.3,23.3 UE2.3 ; CV62.2 108.48,118.71 CV63.2 109.54,118.71 v2(109.97,118.28) 110.46,118.77 110.46,118.76 CV111.2
  TOP w0.406: v2(117.54,6.15) 117.74,5.95 JDB1.11 ; v2(189.38,39.97) 189.04,40.3 PQ720.3 ; EU2603.3 v2(16.53,39.52) ; JDEG1.11 128.57,5.16 v2(128.16,5.16) ; v2(124.42,4.53) 124.42,4.81 124.24,4.99 JDB1.12
  TOP w0.457: v2(136.74,52.03) 136.37,52.03 PC1058.2 ; PC1060.2 136.37,55.08 v2(136.74,55.08) ; v2(80.2,19.59) 80.2,19.8 80.35,19.95 CC89.2 ; v2(94.09,64.66) 94.09,65.07 93.65,65.51 93,65.51 92.68,65.19 CC35.2 ; PC1059.2 136.37,53.43 v2(136.74,53.43) ; PC1082.2 132.11,66.57 v2(132.48,66.57) ; v2(132.48,69.37) 132.11,69.37 PC1080.2 ; v2(93.44,57.9) 93.44,57.47 92.91,56.95 CC34.2 ; v2(167.47,61.07) 167.47,61.05 167.94,60.58 167.94,59.68 167.52,59.26 PC647.1 167.26,59.27 PR647.1 ; PC1180.2 113.72,75.32 v2(113.34,75.32) ; PC1079.2 132.11,70.76 v2(132.48,70.76) ; PC1081.2 132.11,67.97 v2(132.48,67.97) ; v2(137.31,66.06) 136.94,66.06 PC1075.2 ; v2(134.83,68.22) 134.46,68.22 PC1073.2 ; v2(133.56,65.05) 133.19,65.05 PC1076.2 ; PC1078.2 132.11,72.16 v2(132.48,72.16) ; PC1182.2 115.42,75.98 v2(115.8,75.98) ; CC39.2 94.27,67.4 v3(94.99,68.12) v2(95.94,69.07) ; PC1071.2 134.46,69.62 v2(134.83,69.62) ; PC1070.2 134.46,66.83 v2(134.83,66.83) ; v2(137.31,67.46) 136.94,67.46 PC1074.2 ; PC1077.2 133.19,63.65 v2(133.56,63.65) ; v2(95.28,66.62) 95.28,66.37 94.9,66 93.98,66 93.73,66.25 CC38.2 ; v2(94.43,59.57) 94.43,59.33 93.99,58.89 CC43.2
  TOP w0.508: CV46.2 CV179.2 100.62,112.16 CV27.2 100.08,111.51 v2(99.88,111.71) ; CV19.2 99.97,115.53 v2(99.97,115.17) ; CU19.2 18.31,41.48 v2(18.75,41.93) 18.3,42.38 CU7.2 ; v2(79.79,15.83) 80.3,15.83 CC16.2 ; v2(178.75,25.64) PR32.2 178.03,25.62 PR29.2 ; DA1.1 24.82,8.62 v2(24.21,9.23) ; v2(141.18,15.16) 141.04,15.31 CE32.1 ; CC50.2 107.09,55.15 v2(106.82,55.43) ; v2(149.24,34.5) 149.69,34.05 CE8.1 150.55,33.31 CE27.2 ; v2(180.93,12.34) 181.12,12.15 JSSD1.31 ; v2(108.6,41.03) 108.72,40.92 CC62.2 ; CD37.2 CD38.2 52.79,18.18 v2(52.15,18.82) ; RA9.2 v2(30.44,27.2) ; RD4.2 v2(61.82,18.93) ; v2(147.15,14.76) 147.15,16.01 147.68,16.54 CE13.2 ; v2(156.03,35.08) 155.62,35.08 155.04,34.5 CE18.2 ; v2(33.93,28.03) 33.67,27.77 CA15.2 33.11,26.45 CA16.2 ; v2(29.67,110.32) 29.55,110.2 CL12.2 ; DA2.1 24.21,3.2 v2(24.09,3.32) ; v2(34.75,117.92) 34.87,118.03 CL14.2 ; CA22.1 29.36,27.71 29.42,27.77 CA5.2 29.99,28.34 v2(30.12,28.47) ; v2(156.16,17.48) 156.17,17.48 156.17,17.47 156.86,17.47 CE17.2 157.12,16.27 DE1.2 ; PR611.2 PR608.2 159.21,48.35 158.71,47.84 158.71,47.77 v2(158.64,47.71) ; v2(160.42,98.32) 159.03,96.93 SW1.2 ; CC28.2 93.02,61.36 v2(93.17,61.22) ; CD51.2 46.51,63.08 v2(46.65,62.94) ; v2(18.12,43.71) CU8.2 ; CD23.2 58.63,83.95 v2(57.83,83.16) ; v2(201.82,14.31) 201.25,13.73 JSSD1.35 ; CD22.2 67.96,67.59 v2(68.53,67.02) ; JPWR1.7 v2(163.88,104.71) ; v2(219.79,53.68) 220.03,53.44 RX3.2 ; v2(47.58,120.48) PC1117.1 PR1117.1 ; v2(114.32,37.62) 114.5,37.8 CC64.2 ; v2(35.01,25.86) CA1.2 CA3.2 ; CE29.2 152.86,30.58 CE9.2 153.96,31.51 v2(154.51,30.95) ; v2(90.72,22.12) 90.77,22.07 CC5.2 ; EC2216.2 v2(204.86,14.31) ; CW7.2 v2(59.89,110.54) ; v2(180.2,24.95) PQ3.3 ; PR680.2 166.4,58.41 PR647.1 ; RE50.2 150.15,17 CE11.2 150.88,18.12 150.5,18.51 v2(150.5,18.78) ; RX31.1 215.31,38.67 215.01,38.97 v2(215.01,39.11) 214.32,39.11 RX29.1 ; RX27.1 212.39,39.74 v2(211.92,40.22) ; CD21.2 60.94,28.15 61.45,28.66 v2(61.45,28.85) ; v2(93.4,52.3) 93.4,52.3 CC27.2 91.22,52.3 CC36.2 ; RC94.1 83.28,24.8 v2(83.28,24.36) ; JPWR1.8 161.78,115.53 v2(161.78,115.88) ; CU21.2 v2(18.12,45.42) ; v2(160.36,47.33) 160.86,46.82 PC604.2 ; CU5.2 v2(20.2,48.07) ; v2(18.63,58.31) 17.77,57.46 EU2602.1 ; v2(82.4,14.88) 82.4,14.47 83.03,13.85 CC10.2 RC102.2 ; CV160.2 v2(146.58,95.73) ; v2(115.72,99.02) 116.1,99.02 116.48,99.4 117.22,99.4 117.73,99.91 RV41.1 ; v2(90.38,16.72) 90.11,16.46 QC2.3 ; CE26.2 153.68,19.12 CE22.2 153.69,18.67 153.43,18.41 v2(152.99,18.41) ; CV198.2 154.26,121.25 v2(154.77,120.74) ; RA18.1 v2(32.02,14.39) ; v2(109.44,6.8) 109.81,6.44 C26.2 ; v2(121.76,105.66) 121.7,105.6 CV93.2 ; v2(59.07,110.54) 59.07,109.62 59.33,109.37 CW6.2 ; EC2901.2 v2(154.88,104.54) RV118.2 ; PR10.1 183.98,19.84 PR2.2 183.97,19.27 v2(184.23,19) ; v2(106.44,109.61) 106.59,109.76 106.59,109.8 106.69,109.89 CV33.2 CV34.2 ; C2.2 v2(225.35,47.46) ; v2(43.64,73.04) 44.47,73.86 CD52.2 ; CC34.2 91.53,56.95 CC37.2 ; CV39.2 103.38,121.39 103.8,120.98 v2(103.8,120.87) ; CA30.2 28.32,4.99 28.09,5.23 v2(27.77,5.23) 28.4,5.85 CA27.2 ; RV135.2 v2(154.86,123.47) ; v2(215.57,12.95) 215.21,12.59 PD2.1 ; v2(110.87,115.22) 110.41,115.68 CV106.2 109.83,115.36 CV102.2 ; RV369.2 115.15,101.94 v2(115.14,101.94) ; CV67.2 CV70.2 109.03,100.15 v2(108.54,99.66) ; EU2604.1 v2(18.09,34.78) ; CE15.2 148.55,33.56 v2(148.55,34.31) ; v2(117.79,113.18) 117.79,112.95 117.55,112.71 CV178.2 ; CC8.2 92.59,27.27 v2(92.65,27.33) ; v2(101.14,118.71) 100.49,119.36 CV61.2 ; v2(50.46,58.14) 50.46,57.85 51.26,57.05 CD47.2 52.27,58.32 CD48.2 ; CV394.2 v2(154.9,125.31) ; RE32.2 145.38,21.47 v2(146.26,22.35) ; CZ3.2 v2(134.89,36.93) ; CZ10.2 CZ11.2 165.5,18.39 EC2215.2 ; v2(92.53,48.4) 92.49,48.36 CC26.2 90.75,48.35 CC31.2 ; PR1101.1 49.32,128.51 PR1111.1 v2(48.61,128.52) ; v2(54.69,69.65) 54.47,69.43 CD55.2 ; v2(56.86,45.34) RD11.2 RD12.2 ; CD29.2 57.78,62.65 v2(57.77,62.63) ; CZ6.2 135.07,25.38 v2(136.11,25.38) 136.11,25.92 135.79,26.23 CZ4.2 ; C16.2 v2(222.9,29.98) ; CD43.2 51.29,46.32 50.46,47.14 v2(50.46,47.26) ; RX17.1 RX21.1 212.68,46.38 v2(212.93,46.63) ; v2(57.8,48.98) 57.8,49.52 CD26.2 ; CV66.2 109.01,116.56 108.71,116.56 108.56,116.72 v2(107.76,116.72) 107.76,116.2 CV65.2 ; v2(39.8,8.18) v3(39.2,8.79) C1.2 ; v2(134.64,21.55) 134.64,21.54 134.38,21.29 CZ8.2 ; RV53.2 v2(154.81,124.42) ; v2(51.22,52.76) 51.44,52.54 CD44.2 CD45.2 ; RW8.2 v2(53.05,105.05) ; C27.2 112.5,5.52 114.21,3.81 115.86,3.81 116.36,4.31 EC3001.2 v2(116.36,5.16) ; v2(101.93,112.93) 102.16,112.69 CV26.2 ; PC1229.2 PC1124.2 54.83,118.88 v2(54.37,119.34) ; v2(111,113.51) 110.69,113.81 CV77.2 ; CC45.2 105.2,45.62 v2(104.99,45.41) ; CE5.2 154.82,22.02 v2(154.45,22.39) ; v2(57.74,58.95) 58.12,59.33 CD18.2 ; RE19.2 152.91,24.85 152.91,24.02 RE53.1 152.6,24.19 151.76,24.19 v2(151.66,24.09) ; CC86.2 110.46,27.75 110.44,27.74 110.22,27.74 v2(110.19,27.71) ; PC711.1 189.56,32.23 v2(189.12,32.66) ; RV17.1 117.75,101.34 117.75,100.74 117.73,100.73 RV41.1 ; EC2302.2 v2(15.44,25.12) ; R2.2 v2(38.56,5.05) ; v2(115.11,7.17) 115.11,7.79 Q8.3 ; PC125.2 171.22,30.95 v2(171.09,30.82) ; RD6.2 60.2,41.16 60.21,41.16 v2(60.85,41.16) ; EC2902.2 155.06,107.54 v2(154.93,107.41) ; CD24.2 67.88,24.66 v2(68.62,23.93) ; v2(17.1,25.68) 17.19,25.77 RA22.1 ; CX13.2 CX3.2 213.89,51.65 v2(213.7,51.84) ; RD5.2 65.92,18.87 v2(66,18.95) ; v2(51.88,127.66) 51.65,127.89 51.65,128.61 52.02,128.98 52.74,128.98 53.17,128.56 PR1140.2 PR1105.1 ; EC2222.2 v2(85.05,113.68) ; CV88.2 108.84,104.9 v2(108.84,105.55) ; RV41.1 118.74,100.11 RV40.1 119.22,100.02 119.78,100.58 119.78,102.11 CV85.2 119.57,102.33 v2(119.57,102.97) 119.57,103.05 119.13,103.48 CV86.2 ; C5.2 v2(223.6,52.73) ; v2(43.59,44.47) RD22.2 RD21.2 CD58.2 ; CD25.2 68.34,34.63 v2(68.66,34.94) ; RC164.2 v2(85.93,17.26) 85.93,19.37 RC191.2 ; RD18.2 43.64,42.44 v2(43.58,42.51) ; v2(117.05,31.65) 116.4,31.65 CC60.2 ; CV235.2 v2(154.76,129.18) ; CC44.2 CC41.2 131.46,39.28 v2(131.2,39.01) ; PC112.2 v2(167.47,41.68) ; v2(210.71,31.71) 210.46,31.96 PC767.2 ; v2(175.41,21.61) 176.04,22.24 EC2229.2 ; v2(181.92,21.6) 181.92,21.28 182.52,20.68 PR33.1 ; CX2.1 v2(214.38,49.11) ; RC158.2 106.39,64.36 v2(106.24,64.51) ; v2(156.75,56.48) 156.75,56.13 PC601.2 ; CC4.2 v2(92.54,19.96) ; RV123.2 v2(145.55,131.52) ; v2(26.29,27.43) CA6.2 CA17.2 ; RC136.1 120.88,69.92 v2(121.11,69.7) ; CV124.2 115.76,107.13 v2(115.16,107.13) 115.16,106.61 CV82.2 ; CC57.2 109.7,40.28 v2(109.24,40.28) ; CE28.2 146.28,33.74 146.56,34.03 v2(146.58,34.03) 146.84,33.76 CE7.1 ; PC622.2 149.31,55.46 v2(149.43,55.59) ; v2(107.3,110.65) 107.83,110.65 CV113.2 108.1,110.68 CV127.2 ; v2(88.6,27.96) 88.6,27.71 88.35,27.46 RC62.2 89.3,27.21 CC9.2 ; R40.2 C19.2 102.75,9.97 v2(101.9,10.82) ; PC1233.2 56.58,114.87 v2(56.14,114.43) 55.91,114.2 PC1231.2 ; v2(86.02,8.47) 86.02,7.71 85.97,7.66 85.97,5.95 86.84,5.09 Q13.3 ; CV233.2 v2(154.83,128.17) ; PC605.1 169.38,48.99 v2(168.85,48.99) ; CV158.2 154.46,118.58 v2(154.92,118.58) ; v2(28.09,8.91) 28.26,8.74 CA28.2 ; EC2210.2 v2(150.18,134.71) ; CD12.2 67.79,51.7 68.15,51.34 68.89,51.34 69.2,51.65 v2(69.2,52.02) ; v2(46.12,58.44) 45.87,58.7 CD41.2 ; CA4.2 33.48,20.98 v2(33.8,21.3) ; v2(108.5,53.54) 108.32,53.36 CC49.2 ; CZ25.2 166.92,26.18 v2(166.38,25.63) ; v2(64.6,22.12) 64.97,21.75 CD9.2 66.62,22.25 CD10.2 ; CV227.2 154.65,109.56 v2(154.9,109.56) 155.11,109.78 EC2230.2 ; CV157.2 154.2,117.12 154.64,117.56 154.66,117.56 v2(154.99,117.89) ; CI9.2 v2(24.1,97.83) ; CV211.2 v2(150.4,131.52) ; v2(142.26,27.27) 142.26,27.43 142.2,27.49 142.2,27.53 141.82,27.9 141.3,27.9 141.27,27.87 RE48.2 CE23.2 ; v2(170.45,50.76) 170.25,50.55 PR631.1 169.8,50.58 PC621.1 ; CD16.2 CD15.2 68.27,58.71 68.74,58.24 v2(68.74,57.97) ; RX19.1 RX12.1 209.95,39.72 209.44,39.22 v2(209.44,39.14) ; CZ23.2 v2(168.19,27.04) ; CL6.2 35.98,116.91 v2(35.87,116.8) ; RE16.2 153.43,29.18 153.03,29.57 v2(153.03,29.81) 152.91,29.93 151.99,29.93 151.7,29.64 151.7,28.54 CE31.2 ; PJPDC1.8 v2(157.05,129.56) ; v2(50.46,56.16) 50.46,56.06 50.97,55.55 51.47,55.55 51.51,55.59 CD46.2 ; RC110.2 v2(83.97,22.16) ; CV390.2 v2(154.88,102.77) ; v2(89.43,30.06) 89.54,30.17 RC60.2 ; CC33.2 104.92,53.46 v2(105.01,53.55) ; CU20.2 v2(19.96,67.01) ; v2(110.7,23.39) 110.7,22.47 110.83,22.34 CC85.2 ; CZ22.2 136.43,35.36 135.87,35.92 v2(135.87,36.58) ; CV225.2 v2(153.18,95.43) ; CV161.2 v2(147.66,95.73) ; CC82.2 131.72,42.04 v2(131.72,42.5) 132,42.78 CC83.2 ; PC644.2 PR654.2 v2(156.28,51.89) ; v2(43.64,40.16) 44.41,40.93 CD54.2 ; CZ21.2 131.84,33.32 CZ2.2 131.33,34.14 v2(131.21,34.02) ; v2(121.13,43.44) 120.4,42.71 CC42.2 ; CX1.2 CX12.2 v2(222.59,51.46) ; v2(226.36,42.15) 226.88,42.67 EC2212.2 ; CV164.2 v2(148.74,95.73) ; v2(119.71,41.71) 119.71,41.88 119.14,42.44 RC160.2 ; PC685.2 151.71,52.61 v2(152.23,52.1) ; CZ7.2 137.65,30.77 138.16,31.28 CZ1.2 RZ9.2 138.16,33.74 137.69,34.21 137.22,34.21 136.82,33.81 v2(136.41,33.81) ; v2(101.68,134.51) 101.89,134.31 EC2207.2 ; CC12.2 v2(92.09,13.23) ; PC4.2 155.66,119.66 v2(155.21,119.21) 155.66,118.77 PC3.2 ; ED2901.2 156.44,102.03 155.92,102.55 155.92,102.87 155.13,103.66 v2(154.88,103.66) RV49.2 ; CL5.2 34.41,115.34 v2(34.75,115.68) ; v2(86.46,12.41) 87.03,11.84 CC14.2 RC192.2 ; CC75.2 120.79,34.61 v2(121.12,34.28) ; v2(183.48,10.71) 183.55,10.71 184.07,10.2 JSSD1.32 ; C4.2 v2(224.75,53.34) ; v2(17.61,12.09) v3(17.61,13.77) 17.61,16.15 v2(17.67,16.21) ; v2(32.72,28.85) 32.29,28.85 CA9.2 ; C15.2 225.11,36.22 C14.2 v2(226.32,36.3) ; RV116.2 RV134.2 v2(145.13,115.73) ; JSSD1.34 196.77,10.2 196.35,10.62 v2(196.06,10.62) ; v2(68.98,55.2) 68.98,55.21 68.92,55.14 CD17.2 68.17,54.13 CD14.2 ; CD42.2 45.68,60.29 v2(46.47,59.49) ; CA25.1 v2(30.36,13.92) ; v2(54.24,37.41) 53.49,36.66 CD49.2 ; CL8.2 35.87,115.23 v2(35.87,115.68) ; CU9.2 v2(19.9,65.3) ; RX23.1 v2(213.57,46.63) ; CA29.2 v2(28.45,1.79) ; CE24.2 139.09,22.25 v2(139.07,22.25) ; v2(35.33,113) 35.48,113.15 35.48,113.35 35.52,113.39 CL7.2 ; CD19.2 57.61,47.14 v2(57.36,46.89) ; PC1110.2 v2(58.44,128.23) ; PJPDC1.7 v2(172.23,131.09) ; RA24.2 v2(18.57,29.29) ; CV247.2 v2(146.55,131.51) ; RX15.1 RX25.1 v2(214.46,46.63) ; CU6.2 v2(18.67,63.97) ; CE12.2 140.94,21.31 141.65,22.02 v2(142.1,22.02) ; v2(54.63,21.36) 54.55,21.44 CD36.2 CD35.2 ; RD17.2 46.55,21.84 47.09,22.37 48.76,22.37 49.17,21.96 49.39,21.96 v2(49.42,21.93) ; EC2204.2 v2(62.57,131.23) ; RI16.2 30.14,91.25 30.21,91.18 v2(31.85,91.18) ; RV120.2 v2(141.31,96.66) ; v2(110.91,37.64) 110.88,37.61 v2(110.1,37.61) ; CC11.2 v2(82.38,19.07) ; CE10.2 156.84,24.38 v2(157.32,23.91) ; CD20.2 64.66,48.35 v2(64.66,47.71) ; CV221.2 v2(154.27,100.35) ; CC87.2 116.85,29.18 CC72.2 117.23,29.17 v2(118.07,30.01) ; CW8.2 v2(43.39,106.45) ; v2(191.98,41.93) 191.73,41.68 PR752.1 ; v2(141.56,25.99) 141.48,25.91 CE6.2 140.86,25.92 CE20.2 ; QI1.3 v2(18.75,78.82) ; JSSD1.33 192.97,10.2 v2(193.3,10.53) ; CS5.2 CS6.2 198.51,20.24 PQ711.3 197.34,20.65 CS7.2 197.34,18.36 v2(197.7,18) ; CD11.2 60.08,39.38 60.52,39.83 61.1,39.83 61.61,39.32 v2(61.61,39.2) ; CV80.2 CV125.2 ; v2(68.65,61) 68.04,60.4 CD13.2 ; EC2226.2 49.37,17.95 50.31,18.89 v2(50.31,19.07) 50.06,19.33 RD16.2 ; v2(54.83,80.33) 53.71,80.33 CD50.2 ; CV213.2 v2(147.5,131.51) ; UU1.2 v2(18.68,48.21) ; PR1130.2 v2(60.9,118.71) ; v2(57.79,42.52) 57.98,42.71 59.01,42.71 59.04,42.73 59.05,42.73 59.28,42.96 59.28,42.98 59.52,43.22 CD28.2 ; CV92.2 123.1,102.63 123.27,102.8 v2(123.27,103.15) ; v2(125.69,95.59) 124.54,96.73 124.54,100.6 123.85,101.3 CV91.2 ; CV334.2 v2(150.89,95.73) ; R54.2 222.31,40.57 v2(222.27,40.54) ; v2(92.77,44.69) 92.56,44.49 CC29.2 CC30.2 ; CZ5.2 136.31,28.08 v2(136.18,27.95) ; C3.2 v2(225.34,46.57) ; PD3.1 v2(217.37,11.53) ; v2(45.63,119.64) PH1101.1 47.3,119.64 PR1120.1 ; CC1.2 91.42,78.8 CC90.2 90.88,79.7 v2(90.63,79.7) ; CU18.2 v2(18.69,63.07) ; v2(111.79,107.88) 111.65,107.75 111.51,107.75 111.21,107.45 CV114.2 ; CC76.2 136.81,40.23 137.23,40.66 v2(137.23,40.86) ; v2(43.55,83.68) 44.41,84.53 CD53.2 ; RC58.2 v2(86.44,26.45) 86.44,27.19 RC54.2 ; CV242.2 v2(148.46,131.51) ; CV248.2 v2(151.36,131.52) ; PC1.2 156.36,123.91 v2(155.97,123.53) 155.97,123.52 156.53,122.96 PC2.2 ; v2(199.22,47.9) 198.97,47.65 CS13.2 ; v2(108.13,121.64) 108.3,121.46 RV59.1 108.07,120.71 RV29.1 ; CC51.2 CC52.2 CC53.2 v2(108.22,23.42) ; v2(43.58,31.66) 43.76,31.84 CD56.2 ; PC651.1 162.4,59.27 161.56,59.27 161.51,59.22 PC654.1 160.88,59.22 v2(160.36,58.7) ; CS14.2 v2(199.15,48.54) ; CZ12.2 EC2215.2 ; EC2215.2 v2(164.84,18.38) ; CV81.2 116.46,105.37 v2(116.46,105.4) ; v2(145.62,36.72) 145.63,36.72 145.63,36.72 145.96,37.05 CE19.2 ; CV243.2 v2(149.42,131.52) ; PC1111.2 55.9,129.06 v2(54.95,129.06) PR1106.1 ; CV210.2 v2(152.3,131.52) ; RC151.2 132.22,54.84 v2(132.71,54.35) ; PC1226.2 v2(47.52,124.93) ; v2(101.64,119.79) 102.34,119.79 RV16.2 CV15.2 ; CW9.2 v2(44.28,106.44) ; CA2.2 v2(31.96,23.6) ; v2(103.94,101.91) 104.41,102.38 EC2223.2 ; EC2301.2 v2(13.73,9.22) ; RA17.1 v2(23.2,27.7) ; CC54.2 106.65,25.93 v2(106.52,25.8)
  TOP w1.016: JLAN1.11 9.79,101.3 7.7,99.21 v3(6.18,99.21) 4.84,99.21 JLAN1.12
  GND1 w0.203: 4.22,29.27 JUSB2.11 ; JUSB2.11 6.96,30.15 ; JUSB2.11 4.22,30.15 ; JUSB2.11 6.96,29.27 ; JUSB2.11 5.59,29.27 ; 121.72,14.96 HCPU4.1 ; HCPU4.1 126.88,14.96 ; HCPU4.1 121.72,17.25 ; HCPU4.1 126.88,19.54 ; HCPU4.1 124.3,19.54 ; HCPU4.1 121.72,19.54 ; HCPU4.1 124.3,14.96 ; HCPU4.1 126.88,17.25 ; 18.4,2.37 H1.1 ; H1.1 20.33,4.3 ; H1.1 16.98,2.88 ; H1.1 16.47,4.3 ; H1.1 19.82,5.72 ; H1.1 18.4,6.23 ; H1.1 16.98,5.72 ; H1.1 19.82,2.88 ; H8.1 90.53,116.1 ; H8.1 90.53,119.3 ; H8.1 87.33,119.3 ; H8.1 88.93,119.88 ; H8.1 88.93,115.52 ; H8.1 91.11,117.7 ; H8.1 86.75,117.7 ; H8.1 87.33,116.1 ; JHDMI1.11 10.91,87.96 ; JHDMI1.11 9.87,87.5 ; JHDMI1.11 10.91,87.04 ; JHDMI1.11 11.03,87.5 ; JHDMI1.11 9.99,87.04 ; JHDMI1.11 9.99,87.96 ; 10.55,117.43 JLAN1.10 ; JLAN1.10 9.37,117.43 ; JLAN1.10 11.73,118.77 ; JLAN1.10 11.73,117.43 ; JLAN1.10 9.37,118.1 ; JLAN1.10 9.37,118.77 ; JLAN1.10 10.55,118.77 ; JLAN1.10 11.73,118.1 ; H5.1 143.32,62.62 ; H5.1 141.9,63.13 ; H5.1 143.32,59.78 ; H5.1 139.97,61.2 ; H5.1 141.9,59.27 ; H5.1 143.83,61.2 ; H5.1 140.48,59.78 ; H5.1 140.48,62.62 ; H3.1 143.32,7.72 ; H3.1 141.9,4.37 ; H3.1 139.97,6.3 ; H3.1 140.48,7.72 ; H3.1 143.32,4.88 ; H3.1 141.9,8.23 ; H3.1 140.48,4.88 ; H3.1 143.83,6.3 ; JUSB1.11 6.96,51.85 ; JUSB1.11 4.22,50.97 ; JUSB1.11 4.22,51.85 ; JUSB1.11 5.59,50.97 ; JUSB1.11 6.96,50.97 ; JHDMI1.20 12.15,80.68 ; JHDMI1.20 13.43,80.68 ; JHDMI1.20 13.43,78.82 ; JHDMI1.20 12.15,78.82 ; JHDMI1.20 10.87,78.82 ; JHDMI1.20 10.87,80.68 ; JHDMI1.20 13.43,79.75 ; JHDMI1.20 10.87,79.75 ; 1.57,118.77 JLAN1.9 ; JLAN1.9 3.93,118.77 ; JLAN1.9 1.57,118.1 ; JLAN1.9 2.75,117.43 ; JLAN1.9 2.75,118.77 ; JLAN1.9 1.57,117.43 ; JLAN1.9 3.93,117.43 ; JLAN1.9 3.93,118.1 ; H9.1 115.1,132.9 ; H9.1 115.68,134.5 ; H9.1 113.5,132.32 ; H9.1 111.9,136.1 ; H9.1 111.31,134.5 ; H9.1 115.1,136.1 ; H9.1 111.9,132.9 ; H9.1 113.5,136.69 ; JUSB1.4 15.28,55.6 ; JUSB1.4 14.68,56.98 ; JUSB1.4 14.08,55.6 ; JUSB1.4 15.28,56.8 ; JUSB1.4 14.68,55.43 ; JUSB1.4 14.08,56.8 ; JUSB1.4 15.46,56.2 ; JUSB1.4 13.9,56.2 ; JHDMI1.22 12.15,95.18 ; JHDMI1.22 12.15,93.32 ; JHDMI1.22 10.87,95.18 ; JHDMI1.22 13.43,94.25 ; JHDMI1.22 13.43,95.18 ; JHDMI1.22 13.43,93.32 ; JHDMI1.22 10.87,93.32 ; JHDMI1.22 10.87,94.25 ; 14.68,33.73 JUSB2.4 ; JUSB2.4 14.68,35.28 ; JUSB2.4 15.46,34.5 ; JUSB2.4 14.08,33.9 ; JUSB2.4 14.08,35.1 ; JUSB2.4 15.28,33.9 ; JUSB2.4 13.9,34.5 ; JUSB2.4 15.28,35.1 ; 11.54,83.46 JHDMI1.2 ; JHDMI1.2 12.46,83.46 ; JHDMI1.2 11.42,83 ; JHDMI1.2 12.46,82.54 ; JHDMI1.2 12,82.42 ; JHDMI1.2 11.54,82.54 ; JHDMI1.2 12.58,83 ; JLAN1.11 11.73,101.3 ; JLAN1.11 9.37,100.63 ; JLAN1.11 9.37,101.3 ; JLAN1.11 11.73,100.63 ; JLAN1.11 11.73,101.97 ; JLAN1.11 10.55,100.63 ; JLAN1.11 9.37,101.97 ; JLAN1.11 10.55,101.97 ; JUSB1.10 14.56,50.97 ; JUSB1.10 14.56,51.85 ; JUSB1.10 13.09,52.73 ; JUSB1.10 14.56,52.73 ; JUSB1.10 13.09,50.97 ; JUSB1.10 11.62,51.85 ; JUSB1.10 11.62,50.97 ; H10.1 136.5,92.69 ; H10.1 134.9,92.1 ; H10.1 134.32,90.5 ; H10.1 138.1,92.1 ; H10.1 134.9,88.9 ; H10.1 138.69,90.5 ; H10.1 138.1,88.9 ; H10.1 136.5,88.32 ; HCPU3.1 101.67,15.58 ; HCPU3.1 97.71,17.25 ; HCPU3.1 98.33,15.58 ; HCPU3.1 100,19.54 ; HCPU3.1 98.33,18.92 ; HCPU3.1 100,14.96 ; HCPU3.1 102.29,17.25 ; HCPU3.1 101.67,18.92 ; JHDMI1.8 12.58,86 ; JHDMI1.8 11.54,85.54 ; JHDMI1.8 12.46,86.46 ; JHDMI1.8 11.54,86.46 ; JHDMI1.8 11.42,86 ; JHDMI1.8 12.46,85.54 ; JUSB2.13 14.56,44.97 ; JUSB2.13 13.09,46.73 ; JUSB2.13 13.09,44.97 ; JUSB2.13 14.56,45.85 ; JUSB2.13 11.62,46.73 ; JUSB2.13 14.56,46.73 ; JUSB2.13 11.62,45.85 ; 9.87,90.5 JHDMI1.17 ; JHDMI1.17 9.99,90.96 ; JHDMI1.17 10.91,90.04 ; JHDMI1.17 11.03,90.5 ; JHDMI1.17 9.99,90.04 ; JHDMI1.17 10.91,90.96 ; 2.67,76.92 JHDMI1.21 ; JHDMI1.21 5.23,76.92 ; JHDMI1.21 5.23,78.78 ; JHDMI1.21 2.67,78.78 ; JHDMI1.21 3.95,76.92 ; JHDMI1.21 3.95,78.78 ; JHDMI1.21 5.23,77.85 ; JHDMI1.21 2.67,77.85 ; JUSB2.12 5.59,46.73 ; JUSB2.12 6.96,46.73 ; JUSB2.12 4.22,45.85 ; JUSB2.12 6.96,45.85 ; JUSB2.12 4.22,46.73 ; 5,1.57 H12.1 ; H12.1 3.27,3.6 ; H12.1 3.27,5.63 ; H12.1 3.27,1.57 ; H12.1 6.73,3.6 ; H12.1 5,5.63 ; H12.1 6.73,5.63 ; H12.1 6.73,1.57 ; 97.71,80.45 HCPU1.1 ; HCPU1.1 97.71,77.87 ; HCPU1.1 102.29,83.03 ; HCPU1.1 97.71,83.03 ; HCPU1.1 100,77.87 ; HCPU1.1 102.29,77.87 ; HCPU1.1 102.29,80.45 ; HCPU1.1 100,83.03 ; 2.75,100.63 JLAN1.12 ; JLAN1.12 2.75,101.97 ; JLAN1.12 3.93,100.63 ; JLAN1.12 3.93,101.97 ; JLAN1.12 3.93,101.3 ; JLAN1.12 1.57,101.97 ; JLAN1.12 1.57,101.3 ; JLAN1.12 1.57,100.63 ; JUSB1.12 5.59,68.43 ; JUSB1.12 6.96,67.55 ; JUSB1.12 6.96,68.43 ; JUSB1.12 4.22,68.43 ; JUSB1.12 4.22,67.55 ; 1.42,96.15 JHDMI1.23 ; JHDMI1.23 2.7,97.08 ; JHDMI1.23 3.98,97.08 ; JHDMI1.23 3.98,95.22 ; JHDMI1.23 1.42,97.08 ; JHDMI1.23 2.7,95.22 ; JHDMI1.23 1.42,95.22 ; JHDMI1.23 3.98,96.15 ; 13.09,29.27 JUSB2.10 ; JUSB2.10 11.62,29.27 ; JUSB2.10 14.56,30.15 ; JUSB2.10 14.56,29.27 ; JUSB2.10 11.62,30.15 ; JUSB2.10 13.09,31.03 ; JUSB2.10 14.56,31.03 ; H11.1 52.3,135.73 ; H11.1 53.79,135.19 ; H11.1 50.81,135.19 ; H11.1 54.33,133.7 ; H11.1 50.27,133.7 ; H11.1 50.81,132.21 ; H11.1 52.3,131.67 ; H11.1 53.79,132.21 ; 13.09,66.67 JUSB1.13 ; JUSB1.13 14.56,67.55 ; JUSB1.13 11.62,67.55 ; JUSB1.13 11.62,68.43 ; JUSB1.13 13.09,68.43 ; JUSB1.13 14.56,68.43 ; JUSB1.13 14.56,66.67 ; JUSB1.7 13.18,60.48 ; JUSB1.7 13.96,59.7 ; JUSB1.7 13.18,58.92 ; JUSB1.7 13.78,59.1 ; JUSB1.7 13.78,60.3 ; HCPU2.1 126.04,82.19 ; HCPU2.1 124.3,78.06 ; HCPU2.1 121.91,80.45 ; HCPU2.1 126.04,78.71 ; HCPU2.1 122.56,78.71 ; HCPU2.1 124.3,82.84 ; HCPU2.1 122.56,82.19 ; HCPU2.1 126.69,80.45 ; JUSB2.7 13.78,38.6 ; JUSB2.7 13.78,37.4 ; JUSB2.7 13.18,38.78 ; JUSB2.7 13.18,37.22 ; JUSB2.7 13.96,38 ; 205.18,49.32 H4.1 ; H4.1 208.02,49.32 ; H4.1 204.67,47.9 ; H4.1 206.6,49.83 ; H4.1 205.18,46.48 ; H4.1 206.6,45.97 ; H4.1 208.53,47.9 ; H4.1 208.02,46.48 ; 6.77,122.3 H2.1 ; H2.1 10.12,123.72 ; H2.1 8.7,120.37 ; H2.1 10.12,120.88 ; H2.1 7.28,120.88 ; H2.1 7.28,123.72 ; H2.1 8.7,124.23 ; H2.1 10.63,122.3 ; JHDMI1.5 10.91,84.04 ; JHDMI1.5 9.87,84.5 ; JHDMI1.5 9.99,84.04 ; JHDMI1.5 9.99,84.96 ; JHDMI1.5 11.03,84.5 ; JHDMI1.5 10.91,84.96
  IN1 w1.016: JLAN1.9 4.05,119.4 7.15,119.4 7.74,119.15 8.38,119.02 8.88,119.02 9.8,118.1 JLAN1.10
  VCC w0.203: H9.1 115.68,134.5 ; H9.1 115.1,136.1 ; H9.1 115.1,132.9 ; H9.1 111.9,132.9 ; H9.1 113.5,136.69 ; H9.1 113.5,132.32 ; H9.1 111.9,136.1 ; H9.1 111.31,134.5 ; JHDMI1.17 10.91,90.96 ; JHDMI1.17 11.03,90.5 ; JHDMI1.17 10.91,90.04 ; 6.77,122.3 H2.1 ; H2.1 10.12,120.88 ; H2.1 10.12,123.72 ; H2.1 10.63,122.3 ; H2.1 8.7,120.37 ; H2.1 7.28,120.88 ; H2.1 7.28,123.72 ; 11.54,85.54 JHDMI1.8 ; JHDMI1.8 11.42,86 ; JHDMI1.8 11.54,86.46 ; JHDMI1.8 12.58,86 ; JHDMI1.8 12.46,86.46 ; JHDMI1.8 12.46,85.54 ; H11.1 53.79,135.19 ; H11.1 50.27,133.7 ; H11.1 50.81,132.21 ; H11.1 52.3,135.73 ; H11.1 50.81,135.19 ; H11.1 53.79,132.21 ; H11.1 54.33,133.7 ; H11.1 52.3,131.67 ; 10.87,94.25 JHDMI1.22 ; JHDMI1.22 13.43,93.32 ; JHDMI1.22 12.15,95.18 ; JHDMI1.22 10.87,93.32 ; JHDMI1.22 13.43,94.25 ; JHDMI1.22 13.43,95.18 ; JHDMI1.22 12.15,93.32 ; JHDMI1.22 10.87,95.18 ; JUSB1.13 14.56,67.55 ; JUSB1.13 14.56,66.67 ; JUSB1.13 14.56,68.43 ; JUSB1.13 13.09,68.43 ; JUSB1.13 11.62,68.43 ; 14.08,35.1 JUSB2.4 ; JUSB2.4 15.46,34.5 ; JUSB2.4 14.08,33.9 ; JUSB2.4 15.28,33.9 ; JUSB2.4 13.9,34.5 ; JUSB2.4 14.68,35.28 ; JUSB2.4 14.68,33.73 ; JUSB2.4 15.28,35.1 ; 14.68,55.43 JUSB1.4 ; JUSB1.4 14.08,55.6 ; JUSB1.4 14.68,56.98 ; JUSB1.4 15.28,55.6 ; JUSB1.4 14.08,56.8 ; JUSB1.4 13.9,56.2 ; JUSB1.4 15.46,56.2 ; JUSB1.4 15.28,56.8 ; JUSB1.11 6.96,50.97 ; JUSB1.11 4.22,50.97 ; JUSB1.11 5.59,50.97 ; JLAN1.10 10.55,118.77 ; JLAN1.10 11.73,118.77 ; JLAN1.10 9.37,118.77 ; JUSB2.13 14.56,44.97 ; JUSB2.13 14.56,45.85 ; JUSB2.13 11.62,46.73 ; JUSB2.13 14.56,46.73 ; JUSB2.13 13.09,46.73 ; JUSB1.7 13.78,59.1 ; JUSB1.7 13.96,59.7 ; JUSB1.7 13.78,60.3 ; 18.4,2.37 H1.1 ; H1.1 19.82,5.72 ; H1.1 18.4,6.23 ; H1.1 20.33,4.3 ; H1.1 16.98,2.88 ; H1.1 16.98,5.72 ; H1.1 19.82,2.88 ; H1.1 16.47,4.3 ; 5.59,29.27 JUSB2.11 ; JUSB2.11 4.22,29.27 ; JUSB2.11 6.96,29.27 ; JUSB2.12 6.96,46.73 ; JUSB2.12 4.22,46.73 ; JUSB2.12 5.59,46.73 ; JUSB2.10 14.56,29.27 ; JUSB2.10 13.09,29.27 ; JUSB2.10 14.56,30.15 ; JUSB2.10 14.56,31.03 ; JUSB2.10 11.62,29.27 ; JUSB1.12 5.59,68.43 ; JUSB1.12 6.28,68.43 ; JUSB1.12 6.96,68.43 ; JLAN1.12 3.93,100.96 ; JLAN1.12 3.93,100.63 ; JLAN1.12 3.34,100.63 ; 10.87,79.75 JHDMI1.20 ; JHDMI1.20 12.15,80.68 ; JHDMI1.20 13.43,80.68 ; JHDMI1.20 13.43,78.82 ; JHDMI1.20 10.87,80.68 ; JHDMI1.20 12.15,78.82 ; JHDMI1.20 13.43,79.75 ; JHDMI1.20 10.87,78.82 ; 3.95,76.92 JHDMI1.21 ; JHDMI1.21 5.23,76.92 ; JHDMI1.21 5.23,77.85 ; JUSB2.7 13.78,37.4 ; JUSB2.7 13.96,38 ; JUSB2.7 13.78,38.6 ; 11.54,83.46 JHDMI1.2 ; JHDMI1.2 12,82.42 ; JHDMI1.2 12.46,82.54 ; JHDMI1.2 11.42,83 ; JHDMI1.2 11.54,82.54 ; JHDMI1.2 12.58,83 ; JHDMI1.2 12.46,83.46 ; H12.1 6.73,5.63 ; H12.1 3.27,1.57 ; H12.1 3.27,5.63 ; H12.1 5,1.57 ; H12.1 5,5.63 ; H12.1 6.73,3.6 ; H12.1 3.27,3.6 ; H12.1 6.73,1.57 ; 11.62,50.97 JUSB1.10 ; JUSB1.10 14.56,50.97 ; JUSB1.10 14.56,52.73 ; JUSB1.10 14.56,51.85 ; JUSB1.10 13.09,50.97 ; JLAN1.9 2.75,118.77 ; JLAN1.9 1.57,118.77 ; JLAN1.9 3.93,118.77 ; JHDMI1.23 3.34,97.08 ; JHDMI1.23 3.98,96.15 ; JHDMI1.23 3.98,97.08 ; JHDMI1.5 10.91,84.96 ; JHDMI1.5 11.03,84.5 ; JHDMI1.5 10.91,84.04 ; H4.1 208.02,46.48 ; H4.1 204.67,47.9 ; H4.1 208.53,47.9 ; H4.1 205.18,49.32 ; H4.1 206.6,45.97 ; H4.1 205.18,46.48 ; H4.1 206.6,49.83 ; H4.1 208.02,49.32 ; JHDMI1.11 11.03,87.5 ; JHDMI1.11 10.91,87.04 ; JHDMI1.11 10.91,87.96 ; JLAN1.11 11.73,100.63 ; JLAN1.11 10.55,100.63 ; JLAN1.11 9.37,100.63
  IN3 w0.508: v2(17.1,25.68) 17.1,25.68 17.1,22.81 17.67,22.24 v2(17.67,16.21)
  GND2 w0.203: JHDMI1.21 3.95,78.78 ; JHDMI1.21 5.23,76.92 ; JHDMI1.21 3.95,76.92 ; JHDMI1.21 2.67,78.78 ; JHDMI1.21 2.67,77.85 ; JHDMI1.21 2.67,76.92 ; JHDMI1.21 5.23,78.78 ; JHDMI1.21 5.23,77.85 ; 1.42,97.08 JHDMI1.23 ; JHDMI1.23 1.42,96.15 ; JHDMI1.23 2.7,95.22 ; JHDMI1.23 1.42,95.22 ; JHDMI1.23 3.98,96.15 ; JHDMI1.23 3.98,97.08 ; JHDMI1.23 3.98,95.22 ; JHDMI1.23 2.7,97.08 ; 9.99,90.96 JHDMI1.17 ; JHDMI1.17 9.87,90.5 ; JHDMI1.17 10.91,90.04 ; JHDMI1.17 9.99,90.04 ; JHDMI1.17 10.91,90.96 ; JHDMI1.17 11.03,90.5 ; 11.54,82.54 JHDMI1.2 ; JHDMI1.2 12.46,83.46 ; JHDMI1.2 12,82.42 ; JHDMI1.2 12.46,82.54 ; JHDMI1.2 11.54,83.46 ; JHDMI1.2 12.58,83 ; JHDMI1.2 11.42,83 ; JHDMI1.8 12.46,85.54 ; JHDMI1.8 11.42,86 ; JHDMI1.8 12.46,86.46 ; JHDMI1.8 11.54,86.46 ; JHDMI1.8 11.54,85.54 ; JHDMI1.8 12.58,86 ; JUSB2.13 14.56,44.97 ; JUSB2.13 14.56,45.85 ; JUSB2.13 14.56,46.73 ; JUSB2.13 11.62,46.73 ; JUSB2.13 11.62,45.85 ; JUSB2.13 13.09,46.73 ; JUSB2.13 13.09,44.97 ; 121.72,17.25 HCPU4.1 ; HCPU4.1 121.72,19.54 ; HCPU4.1 126.88,14.96 ; HCPU4.1 126.88,19.54 ; HCPU4.1 126.88,17.25 ; HCPU4.1 121.72,14.96 ; HCPU4.1 124.3,14.96 ; HCPU4.1 124.3,19.54 ; H1.1 19.82,5.72 ; H1.1 18.4,2.37 ; H1.1 16.98,2.88 ; H1.1 20.33,4.3 ; H1.1 18.4,6.23 ; H1.1 16.98,5.72 ; H1.1 19.82,2.88 ; H1.1 16.47,4.3 ; H12.1 6.73,1.57 ; H12.1 3.27,1.57 ; H12.1 3.27,3.6 ; H12.1 5,1.57 ; H12.1 3.27,5.63 ; H12.1 6.73,5.63 ; H12.1 6.73,3.6 ; H12.1 5,5.63 ; 4.22,45.85 JUSB2.12 ; JUSB2.12 6.96,46.73 ; JUSB2.12 6.96,45.85 ; JUSB2.12 4.22,46.73 ; JUSB2.12 5.59,46.73 ; 9.87,87.5 JHDMI1.11 ; JHDMI1.11 10.91,87.96 ; JHDMI1.11 9.99,87.04 ; JHDMI1.11 9.99,87.96 ; JHDMI1.11 10.91,87.04 ; JHDMI1.11 11.03,87.5 ; HCPU1.1 102.29,77.87 ; HCPU1.1 100,83.03 ; HCPU1.1 97.71,77.87 ; HCPU1.1 97.71,83.03 ; HCPU1.1 100,77.87 ; HCPU1.1 102.29,80.45 ; HCPU1.1 102.29,83.03 ; HCPU1.1 97.71,80.45 ; 134.9,88.9 H10.1 ; H10.1 138.1,92.1 ; H10.1 136.5,88.32 ; H10.1 134.32,90.5 ; H10.1 138.1,88.9 ; H10.1 136.5,92.69 ; H10.1 134.9,92.1 ; H10.1 138.69,90.5 ; 5.59,29.27 JUSB2.11 ; JUSB2.11 4.22,29.27 ; JUSB2.11 4.22,30.15 ; JUSB2.11 6.96,30.15 ; JUSB2.11 6.96,29.27 ; 13.09,29.27 JUSB2.10 ; JUSB2.10 11.62,29.27 ; JUSB2.10 13.09,31.03 ; JUSB2.10 14.56,30.15 ; JUSB2.10 14.56,29.27 ; JUSB2.10 14.56,31.03 ; JUSB2.10 11.62,30.15 ; H3.1 143.32,4.88 ; H3.1 139.97,6.3 ; H3.1 140.48,4.88 ; H3.1 141.9,4.37 ; H3.1 143.32,7.72 ; H3.1 143.83,6.3 ; H3.1 140.48,7.72 ; H3.1 141.9,8.23 ; JUSB1.4 15.46,56.2 ; JUSB1.4 13.9,56.2 ; JUSB1.4 14.68,56.98 ; JUSB1.4 14.08,55.6 ; JUSB1.4 14.08,56.8 ; JUSB1.4 14.68,55.43 ; JUSB1.4 15.28,55.6 ; JUSB1.4 15.28,56.8 ; 13.18,58.92 JUSB1.7 ; JUSB1.7 13.78,60.3 ; JUSB1.7 13.96,59.7 ; JUSB1.7 13.78,59.1 ; JUSB1.7 13.18,60.48 ; JLAN1.10 11.73,118.1 ; JLAN1.10 10.55,117.43 ; JLAN1.10 9.37,118.77 ; JLAN1.10 9.37,118.1 ; JLAN1.10 11.73,117.43 ; JLAN1.10 10.55,118.77 ; JLAN1.10 11.73,118.77 ; JLAN1.10 9.37,117.43 ; 10.55,100.63 JLAN1.11 ; JLAN1.11 11.73,101.3 ; JLAN1.11 10.55,101.97 ; JLAN1.11 9.37,100.63 ; JLAN1.11 9.37,101.97 ; JLAN1.11 9.37,101.3 ; JLAN1.11 11.73,101.97 ; JLAN1.11 11.73,100.63 ; 111.9,136.1 H9.1 ; H9.1 115.68,134.5 ; H9.1 113.5,132.32 ; H9.1 111.31,134.5 ; H9.1 115.1,136.1 ; H9.1 111.9,132.9 ; H9.1 115.1,132.9 ; H9.1 113.5,136.69 ; JUSB2.7 13.18,38.78 ; JUSB2.7 13.18,37.22 ; JUSB2.7 13.78,38.6 ; JUSB2.7 13.78,37.4 ; JUSB2.7 13.96,38 ; 11.62,67.55 JUSB1.13 ; JUSB1.13 13.09,68.43 ; JUSB1.13 11.62,68.43 ; JUSB1.13 14.56,67.55 ; JUSB1.13 14.56,66.67 ; JUSB1.13 14.56,68.43 ; JUSB1.13 13.09,66.67 ; JHDMI1.20 12.15,80.68 ; JHDMI1.20 10.87,79.75 ; JHDMI1.20 13.43,79.75 ; JHDMI1.20 10.87,80.68 ; JHDMI1.20 12.15,78.82 ; JHDMI1.20 10.87,78.82 ; JHDMI1.20 13.43,78.82 ; JHDMI1.20 13.43,80.68 ; 122.56,78.71 HCPU2.1 ; HCPU2.1 122.56,82.19 ; HCPU2.1 126.04,78.71 ; HCPU2.1 126.69,80.45 ; HCPU2.1 124.3,82.84 ; HCPU2.1 121.91,80.45 ; HCPU2.1 124.3,78.06 ; HCPU2.1 126.04,82.19 ; 4.22,50.97 JUSB1.11 ; JUSB1.11 5.59,50.97 ; JUSB1.11 4.22,51.85 ; JUSB1.11 6.96,50.97 ; JUSB1.11 6.96,51.85 ; H4.1 206.6,49.83 ; H4.1 208.53,47.9 ; H4.1 204.67,47.9 ; H4.1 206.6,45.97 ; H4.1 205.18,46.48 ; H4.1 208.02,49.32 ; H4.1 208.02,46.48 ; H4.1 205.18,49.32 ; JHDMI1.5 10.91,84.96 ; JHDMI1.5 9.99,84.96 ; JHDMI1.5 11.03,84.5 ; JHDMI1.5 9.99,84.04 ; JHDMI1.5 10.91,84.04 ; JHDMI1.5 9.87,84.5 ; 1.57,101.97 JLAN1.12 ; JLAN1.12 3.93,101.97 ; JLAN1.12 3.93,101.3 ; JLAN1.12 2.75,100.63 ; JLAN1.12 2.75,101.97 ; JLAN1.12 3.93,100.63 ; JLAN1.12 1.57,100.63 ; JLAN1.12 1.57,101.3 ; 141.9,59.27 H5.1 ; H5.1 143.32,59.78 ; H5.1 143.32,62.62 ; H5.1 139.97,61.2 ; H5.1 141.9,63.13 ; H5.1 143.83,61.2 ; H5.1 140.48,59.78 ; H5.1 140.48,62.62 ; JLAN1.9 3.93,117.43 ; JLAN1.9 3.93,118.77 ; JLAN1.9 2.75,117.43 ; JLAN1.9 1.57,118.77 ; JLAN1.9 3.93,118.1 ; JLAN1.9 1.57,117.43 ; JLAN1.9 1.57,118.1 ; JLAN1.9 2.75,118.77 ; H11.1 53.79,132.21 ; H11.1 54.33,133.7 ; H11.1 50.81,135.19 ; H11.1 52.3,131.67 ; H11.1 50.81,132.21 ; H11.1 53.79,135.19 ; H11.1 52.3,135.73 ; H11.1 50.27,133.7 ; 8.7,120.37 H2.1 ; H2.1 6.77,122.3 ; H2.1 7.28,123.72 ; H2.1 8.7,124.23 ; H2.1 10.63,122.3 ; H2.1 10.12,123.72 ; H2.1 7.28,120.88 ; H2.1 10.12,120.88 ; 98.33,15.58 HCPU3.1 ; HCPU3.1 97.71,17.25 ; HCPU3.1 100,19.54 ; HCPU3.1 100,14.96 ; HCPU3.1 98.33,18.92 ; HCPU3.1 101.67,18.92 ; HCPU3.1 101.67,15.58 ; HCPU3.1 102.29,17.25 ; JUSB1.10 13.09,52.73 ; JUSB1.10 14.56,52.73 ; JUSB1.10 13.09,50.97 ; JUSB1.10 11.62,51.85 ; JUSB1.10 11.62,50.97 ; JUSB1.10 14.56,50.97 ; JUSB1.10 14.56,51.85 ; JUSB2.4 15.28,35.1 ; JUSB2.4 15.28,33.9 ; JUSB2.4 14.08,35.1 ; JUSB2.4 13.9,34.5 ; JUSB2.4 14.68,33.73 ; JUSB2.4 14.68,35.28 ; JUSB2.4 15.46,34.5 ; JUSB2.4 14.08,33.9 ; JUSB1.12 5.59,68.43 ; JUSB1.12 6.96,67.55 ; JUSB1.12 4.22,68.43 ; JUSB1.12 4.22,67.55 ; JUSB1.12 6.96,68.43 ; JHDMI1.22 13.43,93.32 ; JHDMI1.22 13.43,94.25 ; JHDMI1.22 13.43,95.18 ; JHDMI1.22 10.87,94.25 ; JHDMI1.22 10.87,95.18 ; JHDMI1.22 12.15,95.18 ; JHDMI1.22 12.15,93.32 ; JHDMI1.22 10.87,93.32 ; 88.93,115.52 H8.1 ; H8.1 90.53,119.3 ; H8.1 87.33,119.3 ; H8.1 91.11,117.7 ; H8.1 88.93,119.88 ; H8.1 86.75,117.7 ; H8.1 90.53,116.1 ; H8.1 87.33,116.1
  BOTTOM w0.076: UC1.F35 120.67,48 120.95,48 121.31,47.64 121.32,47.64 121.53,47.43 121.53,47.35 121.86,47.02 121.86,46.84 122.06,46.65 122.96,46.65 123.13,46.82 123.13,47.03 123.28,47.18 123.76,47.18 ; RC130.2 110.89,24.1
  BOTTOM w0.089: 124.16,48.34 122.98,48.34 122.8,48.52 122.8,48.9 122.59,49.12 121.97,49.12 121.81,49.27 121.81,49.52 121.56,49.77 120.39,49.77 UC1.F37 119.77,49.15 v2(119.77,49.03)
  BOTTOM w0.127: UC1.BB60 101.13,62.43 100.56,62.43 100.42,62.58 v2(99.96,62.58)
  BOTTOM w0.152: v2(109.86,69.86) 109.66,69.66 UC1.AG71 ; PC311.2 137.77,38.32 v3(137.69,38.4) ; v2(104.71,69.86) 104.65,69.79 UC1.AT71 ; UC1.BB67 100.52,67.07 v2(100.25,67.07) ; v2(167.06,23.16) 167.04,23.14 v3(167.04,22.42) ; v3(130.87,92.67) v2(129.94,92.67) ; v3(154.27,101.14) v2(154.27,100.35)
  BOTTOM w0.178: v2(100.21,42.63) 100.37,42.63 100.41,42.67 101.16,42.67 UC1.BB26 ; UC1.BB43 100.33,52.62 v2(100.3,52.64) ; UC1.BB34 101.14,47.64 99.86,47.64 v2(99.82,47.68) ; UC1.AM71 107.01,69.12 107.01,69.79 v2(106.94,69.86)
  BOTTOM w0.203: v2(154.08,34.66) 154.15,34.66 154.54,34.26 154.54,33.88 154.36,33.7 UE1.64 ; UC1.AL52 v2(108.38,57.26) ; UE1.100 153.16,18.25 v2(152.99,18.41) ; v2(119.26,69.71) UC1.H71 ; UC1.AP68 105.89,66.83 107.05,66.83 UC1.AM68 107.49,66.89 107.58,66.8 107.85,66.8 108.26,67.21 UC1.AK68 108.45,67.21 UC1.AH67 ; UV1.AF32 105.26,125.54 v2(105.11,125.69) ; UC1.D44 UC1.D45 121.52,54.37 121.52,54.75 121.49,54.78 121.49,55.12 121.52,55.14 121.52,55.48 UC1.D47 UC1.D48 ; UC1.AW62 103.12,63.27 103.18,63.21 103.18,62.65 103.12,62.59 UC1.AW60 ; UC1.F38 v2(119.71,50.86) UC1.F40 ; UC1.AW21 103.19,40.19 103.19,40.94 103.12,41.01 UC1.AW23 ; UC1.AY3 102.13,29.68 101.62,29.16 UC1.BA2 101.45,29.14 101.45,28.81 101.39,28.75 101.39,28.75 101.31,28.66 UC1.BA1 101.31,28.08 v2(101.52,27.87) ; v2(143.53,15.92) 143.56,15.95 UE1.124 ; v2(103.08,125.88) 103.08,125.7 UV1.AH32 ; UC1.AW32 103.12,46 103.23,45.89 103.23,45.24 UC1.AW30 ; UC1.AW16 103.12,38 103.14,38.01 103.14,38.55 103.12,38.57 UC1.AW18 103.12,39.22 103.42,39.52 ; v2(217.53,47.59) 217.8,47.86 J3D1.4 ; v2(100.54,31.66) 100.56,31.68 UC1.BB6 UC1.BA6 102.13,31.68 102.17,31.72 UC1.AW6 ; UC1.C1 122.51,28.33 v2(122.19,28.02) ; v2(157.32,23.91) 157.31,23.91 156.99,23.58 UE1.84 ; UC1.BA18 UC1.BB18 100.25,38.94 v2(100.15,38.84) ; v2(141.56,25.99) 141.56,25.51 141.23,25.18 UE1.17 ; UV1.F22 121.45,118.53 121.7,118.53 v2(121.7,118.53) ; UC1.AT68 104.61,66.85 103.48,66.85 UC1.AV68 ; UC1.A67 123.77,66.75 v2(124.1,67.08) ; v2(106.26,61.84) UC1.AN58 ; UC1.AW12 103.12,35.41 103.22,35.51 103.22,36.42 UC1.AW14 ; UC1.BB38 100.19,50.02 v2(100.15,49.98) ; v2(123.95,113.83) 123.79,113.83 123.7,113.92 UV1.B16 ; UC1.F35 119.77,48.9 v2(119.77,49.03) ; UV1.K2 118.06,103 v2(117.96,102.91) ; UC1.BB55 101.17,59.79 100.14,59.79 v2(100.08,59.73) ; UC1.AW26 103.14,42.6 103.14,43.44 103.12,43.46 UC1.AW28 ; v2(105.6,61.82) UC1.AP58 ; v2(89.68,106.32) 89.69,106.3 89.69,105.94 PU200.1 ; v2(219.35,47.9) 219,48.25 J3D1.1 ; v2(100.03,64.8) 100.09,64.74 UC1.BB64 ; UE1.51 149.16,33.65 148.55,34.26 v2(148.55,34.31) ; UC1.AW51 103.12,57 103.22,56.9 103.22,56.62 103.12,56.53 UC1.AW49 ; PU200.3 v2(90.32,104.92) ; v2(100,44.91) 100.14,45.04 UC1.BB30 ; UC1.AW43 103.12,52.14 103.15,52.11 103.15,51.81 103.12,51.78 UC1.AW41 103.17,51.32 v2(103.63,50.86) 103.12,50.35 UC1.AW38 103.12,49.63 103.14,49.62 103.14,49.3 103.12,49.28 UC1.AW36 103.12,48.41 103.15,48.38 103.15,48.08 103.12,48.05 UC1.AW34 ; UZ5.11 v2(113.35,92.02) ; UC1.AL55 v2(108.38,59.08) ; UC1.AL58 v2(108.38,60.91)
  BOTTOM w0.22: v2(123.93,112.19) 123.87,112.24 123.34,112.24 UV1.B14 ; v2(123.76,117.23) 123.65,117.12 UV1.B20 ; v2(124.12,119.28) 123.56,118.72 UV1.B22 ; v2(124.16,115.52) UV1.B18 ; v2(123.62,110.4) 123.3,110.72 UV1.B12
  BOTTOM w0.229: JKB1.1 v2(87.81,8.5)
  BOTTOM w0.25: v2(120.74,125.84) 120.28,125.37 120.28,124.99 120.47,124.8 120.47,124.73 UV1.G31 ; UV1.B26 123.26,122.4 v2(123.25,122.4) ; UV1.H17 119.85,114.92 120.47,115.54 v2(120.72,115.54) ; v2(123.74,120.3) 123.72,120.3 123.72,120.32 UV1.B24
  BOTTOM w0.254: UC1.AW45 103.12,53.36 103.17,53.31 103.17,52.94 103.12,52.9 UC1.AW43 ; UC1.AW45 103.12,54.22 103.17,54.26 103.17,54.56 103.12,54.61 UC1.AW47 103.12,55.38 103.17,55.42 103.17,55.73 103.12,55.77 UC1.AW49 ; UC1.AW45 v2(102.61,53.8) UC1.BA45 ; v2(103.63,50.86) UC1.AU38 ; v2(109.22,123.24) 109.22,122.75 UV1.AA27 ; 119.71,53.65 119.45,53.92 UC1.G45 ; 119.71,53.65 119.7,53.65 119.45,53.2 UC1.G43 ; 119.71,53.65 v2(119.73,53.65) ; UC1.AT42 UC1.AR42 105.26,52.35 v2(105.6,52.69) ; UV14.H13 v2(144.63,100.63) ; v2(137.38,101.46) 137.46,101.46 UV14.U12 ; UC1.N19 116.29,39.26 v2(115.92,39.64) 115.55,39.26 UC1.P19 ; UV1.T6 113.2,105.92 v2(112.87,105.58) ; UV12.N3 147.43,118.85 v2(147.03,119.25) ; UX2.10 210.01,41.29 v2(209.82,41.11) ; UC1.G5 119.72,31.46 119.72,31.85 UC1.G6 119.82,32.48 v2(119.82,32.63) 119.96,32.77 119.96,32.82 120.1,32.96 UC1.F8 ; UC1.K70 UC1.K71 117.75,69 117.75,69.37 117.56,69.55 v2(117.56,69.68) ; UC1.AM27 UC1.AK27 108.47,43.68 v2(108.63,43.68) ; UC1.AM27 UC1.AM25 106.88,42.75 v2(106.88,42.63) 106.88,42.49 UC1.AN23 UC1.AP23 UC1.AR23 105.24,42.19 104.64,42.19 UC1.AT23 ; UC1.AM27 107.21,44.12 106.88,44.45 ; UV1.N27 115.26,123.11 114.63,123.11 114.23,122.72 UV1.R27 ; UC1.F13 120.1,35.98 v2(120.35,36.22) 120.35,36.28 UC1.E15 ; UV14.F10 v2(146.23,103.83) UV14.G10 ; UC1.K22 UC1.G22 v2(119.71,41.71) ; v2(119.78,62.76) 119.45,62.43 UC1.G60 UC1.G58 ; v2(124.16,92.1) 124.45,92.39 UZ4.5 ; PU605.10 159.09,82.95 v2(158.64,83.4) ; UV14.N12 v2(141.43,101.43) ; UV1.P32 114.13,125.12 v2(113.92,125.33) ; UC1.AN40 106.24,51.63 v2(106.24,51.75) 106.24,51.91 UC1.AN42 106.56,52.31 v2(106.22,52.66) 106.22,52.5 105.94,52.23 UC1.AP42 105.6,52.54 v2(105.6,52.69) ; v2(147.03,120.05) 146.63,120.45 UV12.M5 ; UC1.E11 120.76,34.85 121.16,35.25 121.16,36.01 UC1.D14 UC1.B14 ; UC1.E11 120.75,34.64 v2(121.12,34.28) ; UC1.E11 120.75,35 v2(120.49,35.27) ; UV12.R11 149.03,125.25 v2(149.43,125.65) 149.03,126.05 UV12.R12 ; UV12.G5 142.63,120.45 v2(142.23,120.85) 141.83,120.45 UV12.F5 ; UV12.A14 v2(137.46,128.02) ; UC1.F8 120.41,32.71 v2(120.41,32.63) 120.75,32.29 UC1.E6 ; UC1.F8 119.79,33.34 119.79,33.6 UC1.G10 119.08,33.57 118.41,33.57 118.15,33.32 UC1.J8 ; v2(106.95,35.33) 106.95,35.51 UC1.AM13 107.21,36.16 107.59,36.54 107.59,37 v2(107.44,37.15) 107.61,37.31 UC1.AK16 107.98,37.44 107.61,37.81 107.61,37.82 107.46,37.97 v2(107.46,38.06) 107.98,38.58 UC1.AK18 ; UC1.W9 113.83,33.21 v2(113.94,33.1) ; v2(121.76,105.66) 121.65,105.66 121.39,105.92 UV1.F6 ; UC1.AL48 107.67,55.43 UC1.AM46 ; v2(116,66.89) UC1.N68 ; v2(109.75,34.12) 110,33.87 UC1.AF10 ; UV15.C13 v2(139.03,100.63) UV14.R14 ; UV1.M6 116.46,105.41 v2(116.46,105.4) ; UC1.AK8 107.77,32.18 v2(107.77,30.94) 107.78,30.94 108.03,30.69 UC1.AJ4 UC1.AL4 107.08,30.2 107.08,29.8 UC1.AL2 ; UC1.AK8 107.99,32.73 107.52,32.73 107.23,33.02 UC1.AM8 107.67,33.48 v2(107.67,34.1) 107.74,34.1 UC1.AK11 ; UC1.AK8 108.6,32.11 v2(108.6,31.58) 108.69,31.59 UC1.AH6 109.24,31.26 UC1.AF4 110.02,30.19 v2(110.23,29.98) 110.23,29.72 UC1.AF2 110.08,29.45 110.08,28.92 UC1.AF1 ; v2(106.23,47.29) 106.23,47.07 UC1.AN32 106.24,46.42 v2(106.24,46.27) 106.24,46.17 106.56,45.85 UC1.AN30 ; v2(106.17,49.97) 106.56,49.51 UC1.AN37 v2(106.25,48.94) ; UC1.AD62 111.1,63.21 v2(110.95,63.21) ; UC1.AW57 103.49,61.09 v2(103.63,60.95) ; UC1.AW57 103.12,61.25 103.26,61.38 103.26,62.15 UC1.AW60 ; UC1.AW57 103.12,60.7 103.2,60.62 103.2,60.28 103.12,60.2 UC1.AW55 103.12,59.42 103.17,59.38 103.17,58.65 UC1.AW53 ; v2(138.23,125.65) 137.83,126.05 UV12.A12 ; v2(150.23,119.25) 150.63,118.85 UV12.U3 ; UC1.E71 121.11,69.21 v2(121.11,69.7) ; UC1.R13 115.51,35.82 v2(115.97,36.28) 116.43,35.82 UC1.N13 ; UC1.BB70 100.82,68.73 100.82,69.15 v2(100.77,69.2) 100.84,69.27 101.2,69.27 UC1.BA71 ; v2(121.07,57.27) 120.84,56.8 UC1.E50 ; 102.57,46.36 v2(102.55,46.39) 102.53,46.36 ; 102.57,46.36 102.53,46.36 ; 102.57,46.36 UC1.AW32 103.12,46.74 v2(103.53,47.14) ; UV12.C11 139.43,125.24 v2(139.03,124.85) 138.63,124.45 UV12.B10 ; v2(121.27,102.91) 121.25,102.91 121.25,103.91 UV1.F2 ; v2(105.6,52.69) 105.26,53.02 UC1.AR43 105.26,53.18 105.01,53.43 v2(105.01,53.55) 105.01,53.78 UC1.AR45 104.98,54.37 v2(104.98,54.45) 104.98,54.69 UC1.AR46 104.93,55.3 v2(104.93,55.42) 104.93,55.55 105.26,55.88 UC1.AR48 105.26,55.88 104.95,56.19 v2(104.95,56.32) 104.95,56.49 UC1.AR50 105,57.06 v2(105,57.22) 105,57.36 105.26,57.62 UC1.AR52 104.9,58.08 v2(104.9,58.16) 104.9,58.27 UC1.AR53 104.96,58.93 v2(104.96,59.1) 104.96,59.24 UC1.AR55 v2(104.91,60.01) UC1.AT56 ; UC1.AV1 103.33,28 v2(103.46,27.88) ; UC1.D6 121.65,31.57 v2(122.01,31.57) 122.01,30.96 UC1.C5 ; v2(121.12,34.28) 121.38,34.54 UC1.D11 ; v2(121.12,34.28) 121.48,33.91 UC1.D10 UC1.B10 ; UC1.BA28 v2(102.63,43.86) UC1.AW28 103.12,44.23 103.17,44.27 103.17,44.68 103.12,44.72 UC1.AW30 ; UV1.B8 123.77,107.52 124.08,107.21 v2(124.31,107.21) ; UC1.V17 113.76,37.88 113.76,37.4 UC1.V16 114,37.31 v2(114.32,37.62) 114.65,37.96 UC1.T17 ; UC1.V17 UC1.Y17 ; UC1.V17 UC1.V18 ; UV1.C32 123.25,125.51 v2(123.25,125.54) ; UV12.M10 146.63,124.44 v2(146.23,124.05) 145.83,124.45 UV12.L10 ; 102.53,46.36 UC1.BA32 ; v2(124.25,124.31) 124.25,124.28 124.21,124.32 UV1.A30 ; UV14.M10 v2(142.23,103.83) UV14.L10 ; UV14.E14 147.44,100.22 147.44,99.95 147.44,99.96 v2(147.44,99.7) ; v2(113.75,34.16) 114.04,33.87 UC1.U10 ; v2(119.77,47.28) 119.69,47.2 UC1.J32 118.27,47.2 v2(118.14,47.33) ; v2(119.77,47.28) 120.1,47.61 UC1.F33 ; v2(119.77,47.28) 120.1,46.95 UC1.F32 ; UC1.AM46 107.21,54.89 v2(106.81,54.49) 107.21,54.09 UC1.AM45 ; UC1.AM46 v2(106.82,55.43) ; UV14.A1 150.63,110.68 v2(150.29,111.02) ; UC1.AT58 v2(104.9,61.83) UC1.AR58 ; 103.52,34.44 103.57,34.44 103.96,34.05 UC1.AU10 ; 103.52,34.44 v2(103.52,34.41) ; 103.52,34.44 103.47,34.44 UC1.AW10 ; UC1.G66 119.52,66.34 v2(119.86,66.68) ; v2(143.46,111.15) 143.43,111.12 UV14.K1 UV14.K2 ; UC1.BA41 102.36,51.32 v2(102.5,51.19) 102.63,51.32 UC1.AW41 ; v2(108.82,125.68) 108.82,125.48 UV1.AB32 ; v2(140.61,124.1) 140.26,124.45 UV12.D10 ; UV12.H13 143.43,126.85 v2(143.83,127.25) 143.43,127.65 UV12.H14 ; UC1.D30 122.01,46.25 v2(122.01,46.25) 122.01,46.25 UC1.B30 ; 114.13,68.19 v2(114.12,68.19) ; 114.13,68.19 114.31,68.37 114.31,68.37 114.46,68.51 UC1.U70 ; 114.13,68.19 UC1.U69 v2(114.12,67.51) ; UV12.C1 139.43,116.9 v2(139.16,116.63) ; v2(106.2,48.08) 105.91,48.37 UC1.AP35 UC1.AR35 UC1.AT35 ; v2(106.2,48.08) 106.56,48.44 UC1.AN35 ; v2(106.2,48.08) 106.56,47.72 UC1.AN33 ; 123.76,47.18 128.32,47.18 129.7,45.8 130.96,45.8 131.36,46.21 v2(132.44,46.21) 133.84,46.21 134.1,46.46 134.1,49.68 v2(134.22,49.8) 134.22,50.25 133.84,50.63 133.29,50.63 133.17,50.75 v2(131.2,50.75) 130.21,50.75 129.62,50.17 129.62,49.75 129.17,49.29 125.12,49.29 124.16,48.34 ; UV1.C1 122.9,103.52 v2(123.27,103.15) ; v2(104.31,37.14) 103.96,36.79 UC1.AU15 ; UC1.U64 v2(114.12,64.27) UC1.U63 ; v2(122.87,105.64) 123.14,105.92 UV1.B6 ; v2(118.33,50.84) 118.34,50.86 UC1.J38 v2(119.71,50.86) ; UC1.F27 120.1,43.96 120.61,43.45 120.91,43.45 120.92,43.44 v2(121.13,43.44) UC1.D25 ; UC1.AR15 104.9,37.05 v2(104.9,37.14) 104.9,37.23 UC1.AR16 104.95,37.91 v2(104.95,37.97) ; UV12.K14 145.03,127.97 v2(145.18,128.13) ; UV12.H2 UV12.H1 143.43,116.68 v2(143.43,116.68) ; v2(104.92,33.55) 104.92,33.49 105.26,33.14 UC1.AR8 ; UV1.P6 115.16,106.22 v2(115.16,107.13) ; 102.39,41.38 UC1.BA23 ; 102.39,41.38 v2(102.39,41.39) ; 102.39,41.38 UC1.AW23 103.12,41.84 103.17,41.89 103.17,42.23 103.12,42.27 UC1.AW26 ; v2(112.57,39.64) 112.63,39.64 UC1.Y19 UC1.V18 ; UC1.BA53 UC1.AW53 ; UC1.AW53 103.27,58.46 103.27,58.09 103.17,57.99 103.17,57.44 UC1.AW51 ; v2(101.17,70.14) 101.96,69.36 UC1.AY71 ; UC1.L20 117.01,39.91 UC1.N21 115.97,40.95 v2(115.97,41.04) ; UC1.A5 123.99,30.29 v2(124.07,30.29) ; 103.27,33.42 103.27,33.68 103.12,33.83 UC1.AW10 ; 103.27,33.42 103.27,33.28 103.12,33.13 UC1.AW8 ; 103.27,33.42 v2(103.28,33.42) ; PU102.18 v2(175.79,32.6) ; v2(119.14,38.88) 118.8,38.54 UC1.H18 118.8,38.47 118.51,38.18 v2(118.51,38.05) ; UC1.P20 115.87,40.26 v2(115.95,40.26) 115.65,40.56 UC1.P21 UC1.T21 ; UC1.E46 v2(120.98,55.43) 121.04,55.49 UC1.D47 ; UV12.K1 145.03,117.25 v2(145.43,117.65) 145.03,118.05 UV12.K2 ; v2(116.98,123.24) 117.26,122.96 UV1.L27 ; UC1.L16 117.17,37.31 v2(116.83,37.65) 117.14,37.96 UC1.L17 UC1.L18 ; UV14.N3 v2(141.43,108.63) ; UV14.R11 v2(139.03,102.23) UV14.R12 ; UV12.E1 141.03,116.86 v2(140.84,116.68) ; UC1.AW36 v2(102.48,48.84) UC1.BA36 ; UV1.F26 121.26,122.08 121.64,122.46 v2(121.64,123.02) 121.64,123.1 UV1.E28 ; UC1.K18 118.19,38.46 118.19,38.37 v2(118.51,38.05) ; UC1.AK63 108.22,63.93 109.07,63.93 UC1.AH63 109.11,63.96 v2(109.51,64.36) 109.26,64.61 UC1.AH64 ; UC1.B58 UC1.D58 121.21,61.12 v2(121,60.91) 120.78,60.46 UC1.E56 ; UV12.T10 149.83,124.45 v2(149.43,124.85) ; v2(118.51,38.05) 118.51,37.91 118.04,37.44 UC1.K16 118.21,37.14 v2(119.07,37.14) UC1.H15 ; v2(116,65.65) UC1.N65 ; UC1.AP70 v2(105.83,67.46) UC1.AP68 105.45,66.89 105.39,66.82 105.1,66.82 105.04,66.89 UC1.AT68 ; UC1.AM55 107.21,59.6 107.02,59.79 107.02,59.98 v2(107.01,59.98) ; v2(143.09,99.77) 143.09,99.83 143.43,100.17 UV14.K14 ; v2(139.32,111.19) 139.43,111.09 UV14.R1 ; v2(108.63,44.28) 108.45,44.45 UC1.AL28 106.88,44.45 ; v2(151,99.86) 150.63,100.23 UV14.A14 ; UV1.K32 118.23,125.29 v2(118.77,125.29) 118.86,125.21 UV1.J31 ; UV1.M32 115.96,125.12 v2(115.47,125.61) ; UC1.A70 UC1.B71 123.01,69.16 123.41,69.56 v2(123.53,69.56) ; UC1.B44 v2(121.99,53.68) UC1.D44 ; UC1.AW14 v2(102.41,36.52) UC1.BA14 ; UV12.F10 141.83,124.45 v2(142.23,124.05) 142.63,124.44 UV12.G10 ; UV12.R1 149.03,116.79 v2(149.14,116.68) ; v2(119.71,41.71) 119.71,41.68 120.08,41.25 UC1.F22 ; v2(119.71,41.71) 119.71,41.76 120.06,42.17 UC1.F23 ; UV14.D10 148.2,103.43 v2(147.85,103.77) ; UV14.M5 v2(142.23,107.03) UV14.L5 ; UC1.AE65 UC1.AE66 UC1.AE67 UC1.AE68 UC1.AE69 111.06,67.86 v2(111.39,68.19) ; UC1.AK21 108.12,40.7 108.12,41.22 UC1.AK22 108.38,41.25 v2(108.6,41.03) ; UV14.C14 149.03,99.87 v2(149.18,99.71) ; v2(121.72,117.26) 121.56,117.26 121.42,117.12 UV1.F20 ; v2(112.39,65.57) UC1.AA65 ; UV14.N1 141.03,111.18 141.03,111.18 v2(141.03,111.21) ; v2(150.23,128.05) 150.63,127.65 UV12.U14 ; UV12.C12 139.43,125.96 v2(139.79,125.59) ; UC1.AU32 103.92,46.74 v2(103.53,47.14) ; v2(106.51,121.53) 106.86,121.18 UV1.AD25 UV1.AC24 ; UC1.AT2 104.72,29.8 v2(104.93,30.02) 104.93,30.27 UC1.AT4 ; 115.14,37.96 UC1.T17 ; 115.14,37.96 UC1.P17 ; 115.14,37.96 115.14,37.01 v2(115.11,36.98) UC1.T15 ; UC1.T17 UC1.T18 UC1.V18 ; v2(116.99,32.28) 117.22,32.28 UC1.L8 ; UC1.AA2 UC1.AA4 112.67,30.93 v2(112.74,31) 112.87,31 113.13,31.26 UC1.W6 ; UC1.B62 UC1.D62 121.14,63.6 v2(121.02,63.72) ; UV14.C3 v2(148.63,109.43) ; v2(121.21,67.95) 121.21,67.49 UC1.D69 UC1.F68 ; v2(108.84,105.55) 108.47,105.92 UV1.AB6 ; v2(139.28,128.16) 139.43,128.01 UV12.C14 ; v2(112.37,66.92) UC1.AA68 ; UV14.F5 v2(146.23,107.03) UV14.G5 ; UV14.N14 v2(141.43,99.83) ; UV14.E3 v2(147.03,109.43) ; v2(107.23,107.16) 106.87,107.52 UV1.AD8 ; UC1.B22 122.26,41.29 122.06,41.49 v2(122.06,41.49) 122.06,41.49 121.75,41.49 121.55,41.29 UC1.D22 121.48,41.25 121.03,40.8 121.03,40.61 UC1.E21 ; 121.1,59.08 v2(121.09,59.08) ; 121.1,59.08 120.91,58.68 UC1.E53 ; 121.1,59.08 121.1,59.08 121.1,59.08 121.48,58.7 UC1.D53 UC1.B53 ; UC1.G52 119.72,57.98 v2(119.72,58.13) ; UC1.AP32 v2(105.54,47.2) ; UC1.AK68 108.33,67.48 v2(108.11,67.7) 108.11,67.97 UC1.AK69 ; UC1.E18 120.98,38.74 120.98,38.89 v2(121.01,38.92) 121.01,38.92 121.38,38.92 UC1.D18 UC1.B18 ; UV12.K13 145.03,126.85 v2(145.43,126.45) ; v2(149.43,120.85) 149.83,120.45 UV12.T5 ; v2(112.79,35.58) 113.13,35.58 UC1.W13 ; v2(119.57,102.97) 119.65,103.05 119.65,103.91 UV1.H2 ; UV14.R3 v2(139.03,108.63) UV14.R4 ; UV12.N1 147.43,116.7 v2(147.45,116.68) ; UC1.AB18 111.71,38.16 v2(111.71,37.67) 111.36,37.31 UC1.AD16 111.24,37.31 v2(110.91,37.64) ; UC1.AV68 103.17,67.16 v2(103.17,67.27) 103.26,67.36 UC1.AV69 UC1.AV70 UC1.AV71 103.26,69.63 v2(103.1,69.79) ; UV14.A3 v2(150.23,108.63) 149.43,108.63 UV14.C4 ; UC1.G55 119.45,59.65 v2(119.76,59.96) ; UV12.L5 145.83,121.01 v2(145.83,121.01) ; UV14.B5 149.59,107.19 v2(149.59,106.99) ; UC1.T2 UC1.T4 115.49,30.66 UC1.R6 UC1.N6 116.94,31.65 v2(117.05,31.65) ; v2(109.78,35.46) 109.45,35.46 UC1.AH13 108.82,36.09 UC1.AJ15 ; UV14.T5 v2(139.03,107.03) ; UV1.K28 118.06,123.58 117.82,123.82 117.82,124.01 117.57,124.27 v2(117.57,124.29) ; UV1.AD32 106.86,125.71 v2(106.88,125.73) ; UC1.B66 UC1.D66 121.1,65.7 v2(121.1,65.67) 121.1,65.47 UC1.E65 ; UC1.J28 v2(119.78,45.37) 119.78,45.36 120.1,45.04 UC1.F28 ; v2(124.61,109.08) 124.24,109.08 124.2,109.12 UV1.B10 ; UV1.AE27 v2(106.45,122.33) ; v2(119.21,64.67) 119.52,64.36 UC1.G63 ; UV14.E1 147.02,111.04 v2(147.02,111.14) ; v2(149.3,111.25) 149.03,110.97 UV14.C1 ; UC1.G48 119.75,55.58 v2(119.75,55.46) ; v2(119.18,113.21) 119.16,113.21 119.16,112.91 119.55,112.52 UV1.H14 ; UC1.AW18 UC1.BA18 ; UV12.N14 147.43,127.65 v2(147.03,128.05) ; v2(141.43,118.45) 141.03,118.85 UV12.E3 ; UV1.F14 121.26,112.2 v2(121.58,111.88) ; UC1.L4 118.07,30.39 v2(118.07,30.01) 118.07,29.6 UC1.L2 ; v2(120.72,115.54) 120.74,115.52 UV1.F18 ; UC1.K61 118.52,63.67 UC1.K63 118.16,63.98 v2(117.85,64.3) ; UC1.AN38 106.56,50.51 v2(106.24,50.83) 105.91,50.5 UC1.AP38 ; UV12.C3 139.43,118.85 v2(139.83,118.45) ; v2(217.82,44.54) 217.67,44.69 DX1.3 ; UC1.AL32 v2(108.33,46.28) ; v2(121.75,107.45) 121.73,107.47 121.54,107.47 121.49,107.52 UV1.F8 121.08,107.52 120.98,107.42 120.56,107.42 UV1.G8 ; UC1.AW10 102.8,34.1 102.57,33.87 v2(102.57,33.87) 102.35,34.1 UC1.BA10 ; v2(103.53,47.14) 103.12,47.54 UC1.AW34 ; v2(111.8,40.22) 111.8,40.22 112.14,40.56 UC1.AB21 112.32,40.72 112.85,40.72 UC1.Y21 113.06,40.52 113.06,39.96 UC1.Y20 ; v2(114.12,65.6) UC1.U66 ; v2(111.39,64.87) 110.97,64.6 UC1.AE64 ; UC1.J42 118.99,52.68 UC1.G43 ; v2(114.12,66.24) UC1.U67 ; UC1.D34 v2(121.99,48.73) UC1.B34 ; UV12.R3 149.03,118.85 v2(149.43,119.25) 149.03,119.65 UV12.R4 ; UX2.21 v2(215.6,41.29) ; UV12.U12 150.63,126.05 v2(151.03,125.65) ; UV1.T32 113.26,125.55 v2(113.62,125.91) ; v2(106.89,40.81) 107.21,40.49 UC1.AM21 ; UV12.E12 v2(141.43,126.45) ; UV1.AD6 106.81,105.92 v2(106.41,106.32) 106.06,106.67 UV1.AE7 ; UC1.AB8 111.73,32.56 v2(111.71,32.59) 111.69,32.56 UC1.AD8 ; UV12.A1 137.83,117.2 v2(138.17,116.85) ; UV14.B10 v2(149.43,103.03) UV14.C11 ; UV12.N12 147.43,126.05 v2(147.03,126.45) ; v2(108.63,49.94) UC1.AL38 ; v2(106.95,61.88) 107.21,62.15 UC1.AM60 ; UV14.E12 v2(147.03,101.43) ; UC1.L11 117.5,34.57 117.79,34.86 117.8,34.85 118.15,34.85 UC1.J11 118.15,34.97 v2(118.51,35.33) 118.15,35.69 UC1.J13 ; UC1.J25 118.25,43.54 v2(118.13,43.66) ; v2(147.83,124.85) 148.23,124.45 UV12.P10 ; UC1.N10 116.33,33.63 v2(116.14,33.63) ; UC1.D39 121.79,50.9 v2(121.86,50.9) 122.19,50.9 UC1.B39 ; UV12.R14 149.03,127.65 v2(149.43,127.25) 149.03,126.85 UV13.C13 ; UC1.AH67 109.09,66.51 v2(108.71,66.22) ; UC1.G43 119.45,53.01 v2(119.82,52.65) 120.1,52.36 UC1.F42 ; UV12.A3 137.83,118.85 v2(138.23,119.25) 139.03,119.25 UV12.C4 ; UV1.G27 120.4,122.78 v2(120.4,123.42) ; 106.88,44.45 106.56,44.77 UC1.AN28 UC1.AP28 UC1.AR28 ; UC1.AD21 UC1.AD20 111.45,39.91 v2(111.78,39.58) 111.46,39.26 UC1.AD19 ; v2(141.02,128.17) 141.03,128.16 UV12.E14 ; v2(107.59,63.56) 107.22,63.2 UC1.AM61 ; v2(108.5,53.54) 108.45,53.6 UC1.AL45 107.23,53.14 UC1.AM43 ; UC1.AB15 112.18,36.73 v2(112.55,37.01) UC1.AB16 ; UC1.C25 v2(121.88,43.48) UC1.D26 ; UV12.B5 138.63,120.45 v2(139.03,120.85) ; v2(110.76,35.53) 111.12,35.82 UC1.AD13 ; UC1.AR28 105.26,45.14 v2(104.99,45.41) 104.61,45.03 UC1.AT28 UC1.AR28 ; UV14.U3 v2(138.23,108.63) ; v2(145.18,111.28) 145.03,111.12 UV14.H1 145.09,110.57 145.09,109.89 UV14.H2 ; UV14.C12 v2(149.43,101.43) ; UV14.A12 150.63,101.83 150.93,101.53 v2(151.2,101.53) ; UC1.D48 UC1.B48 ; UV1.F10 UV1.G10 120.43,109.12 120.15,108.84 120.15,108.75 v2(120.14,108.75) ; UV14.U1 v2(137.36,111.09) ; v2(102.43,61.09) UC1.BA57 ; UC1.BA49 101.76,56.15 100.56,56.15 100.49,56.08 98.51,56.08 97.57,57.02 v2(97.57,57.9) ; UV14.T10 v2(139.03,103.03) ; UV14.P10 v2(140.63,103.03) ; UC1.BA62 v2(102.59,63.57) UC1.AW62 103.12,63.98 103.17,64.03 103.17,64.8 UC1.AW64 103.19,64.91 103.19,65.88 UC1.AW66 v2(103.03,66.43) UC1.AY66 UC1.BA66 ; UC1.AR5 105.38,31.2 105.84,31.65 v2(106.1,31.65) ; v2(151.03,116.85) 150.63,117.25 UV12.U1 ; v2(217.53,47.59) 217.53,47.23 217.67,47.09 DX1.8 ; UC1.AP10 105.91,34.16 v2(105.68,34.4) 105.26,34.81 UC1.AR11 ; UC1.F1 UC1.F2 120.55,29.59 v2(120.55,30) 120.55,30.41 UC1.F4 ; v2(108.63,48.11) UC1.AL35 ; UV1.J27 v2(118.86,123.37) ; UV14.H14 v2(145.03,99.66) ; UV14.U14 v2(138.23,99.83) ; JHDD1.1 v2(199.15,16.15) ; v2(118.32,49.03) UC1.J35 119.77,49.03 v2(119.77,49.03) ; UV14.K13 v2(143.03,101.43) ; PU603.10 v2(159.04,73.83)
  BOTTOM w0.3: UV1.F12 121.66,110.32 v2(121.66,110.25) ; v2(112.61,125.43) 112.29,125.12 UV1.V32 ; v2(121.62,119.9) 121.62,119.91 121.45,120.25 UV1.F24 ; v2(103.91,109.63) 103.91,109.37 UV1.AH10 ; UV1.K6 118.1,105.92 118.5,105.51 v2(118.5,105.53)
  BOTTOM w0.305: v2(119.33,107.13) 118.92,106.72 UV1.J7 UV1.H6 ; v2(55.69,23.21) 55.61,23.12 JDIMM2.251 ; JDIMM1.22 57.75,81.88 57.11,81.23 v2(57.11,79.95) ; JDIMM1.176 58.22,41.38 57.77,41.82 57.77,42.25 57.79,42.27 v2(57.79,42.52) 57.8,42.52 57.8,42.5 57.93,42.38 JDIMM1.172 ; JDIMM1.26 58.04,80.88 57.73,80.57 v2(57.73,80.3) 57.73,80.18 58.04,79.88 JDIMM1.30 ; v2(69.93,67.02) 69.87,67.08 69.87,68.6 69.35,69.13 JDIMM1.73 ; UV1.U27 112.67,122.51 112.67,122.32 v2(112.73,122.26) ; JEDP1.27 224.99,37.05 v2(225.08,36.96) ; JDIMM1.86 57.98,65.88 v2(57.79,66.06) 57.71,66.14 57.71,66.57 58.02,66.88 JDIMM1.82 ; v2(225.56,43.53) 225.56,43.75 225.26,44.05 224.08,44.05 JEDP1.13 ; UV1.W27 110.86,122.73 v2(110.49,123.1) ; JDIMM2.43 54.03,77.13 54.34,77.43 v2(54.34,77.64) 54.34,77.82 54.03,78.13 JDIMM2.39 ; JDIMM1.9 68.32,85.13 69.06,85.86 v2(69.06,86.43) ; JDIMM1.167 68.45,43.63 69.41,44.59 v2(69.41,45.26) ; JDIMM2.36 v2(43.53,78.87) ; JDIMM2.217 54.4,31.63 55.26,32.48 v2(55.26,32.83) ; JDIMM2.52 43.8,74.87 v2(43.59,75.08) 43.59,75.65 43.81,75.87 JDIMM2.48 ; JDIMM2.244 43.92,24.87 43.58,24.53 v2(43.58,24.34) ; JDIMM1.248 57.77,23.38 v2(57.4,23.01) 57.4,22.68 57.7,22.38 JDIMM1.252 ; JDIMM2.184 43.92,39.87 v2(43.64,40.16) 43.64,40.57 43.94,40.87 JDIMM2.180 ; JDIMM1.226 58.09,28.87 57.88,28.66 v2(57.35,28.66) 57.35,29.18 58.04,29.87 JDIMM1.222 ; JHDD1.7 196.15,17.86 v2(196.31,18.03) ; JDIMM1.72 58.13,69.38 57.83,69.07 v2(57.83,68.13) 58.09,67.88 JDIMM1.78 ; JDIMM2.31 54.63,80.13 v2(54.83,80.33) 54.83,80.76 54.46,81.13 JDIMM2.27 ; JDIMM1.251 68.09,22.63 69.24,23.78 v2(69.24,23.92) ; v2(57.2,42.73) 57.85,43.38 JDIMM1.168 ; v2(54.72,33.37) 53.98,32.63 JDIMM2.213 ; JDIMM1.81 68.42,67.13 v2(68.53,67.02) 68.53,67.91 68.31,68.13 JDIMM1.77 ; JWLAN1.37 54.05,99.39 54.2,99.24 v2(54.2,98.93) ; JDIMM2.193 54.02,37.63 v2(54.24,37.41) 54.24,36.93 53.93,36.63 JDIMM2.197 ; JDIMM2.214 43.88,32.38 43.58,32.07 v2(43.58,31.66) 43.86,31.38 JDIMM2.218 ; JDIMM1.10 57.32,84.88 57.1,85.09 v2(57.1,85.88) 57.11,85.88 JDIMM1.6 ; JDIMM2.98 43.89,63.38 v2(43.54,63.03) ; JDIMM2.168 43.34,43.87 v2(42.7,44.51) ; JDIMM1.238 57.84,25.87 v2(57.61,25.65) 57.61,26.57 57.92,26.87 JDIMM1.234 ; JDIMM2.175 54.15,42.12 55.02,43 v2(55.02,43.33) ; JDIMM1.93 68.23,64.13 68.6,63.75 v2(68.6,63.34) 68.6,62.93 68.3,62.62 JDIMM1.99 ; v2(42.98,41.4) 42.98,41.62 43.25,41.88 43.69,41.88 43.7,41.87 JDIMM2.176 ; JDIMM2.57 54.6,73.62 55.02,73.2 v2(55.02,71.85) ; JDIMM1.69 68.41,70.13 69.04,70.76 v2(69.04,71.47) 69.04,72.73 68.65,73.13 JDIMM1.57 ; JDIMM2.86 43.61,66.38 v2(43.47,66.52) 43.47,67.14 43.7,67.38 JDIMM2.82 ; v2(112.73,121.56) 112.8,121.56 113.23,121.12 UV1.T25 ; v2(57.77,62.63) 58.01,62.87 59.05,62.87 JDIMM1.98 ; 57.54,34.56 58.22,33.87 JDIMM1.206 ; 57.54,34.56 v2(57.54,34.6) ; 57.54,34.56 57.54,33.56 58.22,32.87 JDIMM1.210 ; UV1.Y25 110.08,121.12 v2(110.53,121.57) 110.98,121.12 UV1.W25 ; UV1.R27 114.06,123.02 v2(113.75,123.34) ; JDIMM2.189 53.98,38.63 54.28,38.93 v2(54.28,39.46) 54.11,39.63 JDIMM2.185 ; JDIMM2.222 43.96,30.38 43.67,30.08 43.67,29.65 v2(43.67,29.64) 43.94,29.38 JDIMM2.226 ; JDIMM2.2 43.8,87.37 42.84,86.42 v2(42.84,86.09) ; JDIMM2.202 43.83,35.38 v2(43.55,35.65) 43.55,36.66 43.77,36.88 44.85,36.88 JDIMM2.196 ; JDIMM2.223 55.89,30.12 v2(56.1,29.91) ; JDIMM1.192 57.52,37.38 57.3,37.59 57.3,38.78 57.31,38.79 v2(57.31,38.79) 57.32,38.79 57.74,38.38 JDIMM1.188 ; UV1.AH28 104.42,122.75 104.42,122.72 ; JDIMM1.36 58.16,78.38 57.85,78.07 v2(57.85,77.56) 58.04,77.38 JDIMM1.40 ; JDIMM2.102 43.76,62.38 43.54,62.16 v2(43.54,61.59) 43.76,61.38 JDIMM2.106 ; JEDP1.33 224.08,34.05 225.39,34.05 v2(225.57,33.87) ; JDIMM1.61 68.2,72.13 68.46,71.87 v2(68.46,71.47) 68.46,71.46 68.12,71.13 JDIMM1.65 ; JDIMM1.181 68.29,40.13 68.6,40.43 v2(68.6,41.14) 68.6,41.32 68.29,41.63 JDIMM1.175 ; JDIMM1.189 68.58,38.13 68.77,38.31 68.77,39.09 v2(68.61,39.24) 68.49,39.13 JDIMM1.185 ; UV1.AG27 104.42,122.72 ; 104.42,122.72 v2(104.06,122.36) ; JDIMM2.40 43.78,77.87 43.57,77.66 v2(43.57,77.09) 43.78,76.87 JDIMM2.44 ; JDIMM1.243 68.41,24.63 68.62,24.42 v2(68.62,23.93) 68.31,23.63 JDIMM1.247 ; JDIMM2.93 54.11,64.62 54.33,64.41 v2(54.33,63.34) 54.12,63.13 JDIMM2.99 ; JDIMM2.85 54.06,66.62 54.37,66.32 54.37,65.87 v2(54.31,65.81) 54.13,65.62 JDIMM2.89 ; v2(69.13,78.34) 69.13,77.04 68.72,76.62 JDIMM1.43 ; v2(111.79,107.88) 112.22,108.32 UV1.U9 ; v2(109.29,121.77) 109.29,120.95 UV1.AB24 ; UV1.AC27 107.27,123.11 v2(107.27,123.14) ; v2(107.28,108.69) UV1.AC9 ; JDIMM2.72 43.8,69.87 43.58,69.66 v2(43.58,68.69) 43.9,68.38 JDIMM2.78 ; JDIMM1.64 58.17,71.38 57.86,71.07 v2(57.86,70.58) 58.07,70.38 JDIMM1.68 ; v2(111.66,122.19) 111.38,121.92 UV1.W26 ; JDIMM1.56 58.13,73.38 57.83,73.07 57.83,72.63 v2(57.87,72.59) 58.08,72.38 JDIMM1.60 ; JDIMM1.52 58.16,74.38 v2(57.34,75.19) ; JDIMM1.39 68.27,77.62 68.57,77.93 v2(68.57,78.34) 68.29,78.62 JDIMM1.35 ; v2(54.86,39.45) 54.86,39.99 54.22,40.63 JDIMM2.181 ; JDIMM2.231 54.54,28.12 v2(54.78,28.36) 54.81,28.39 54.81,28.82 54.5,29.12 JDIMM2.227 ; JDIMM2.77 54.06,68.62 54.27,68.41 v2(54.27,67.88) 54.02,67.62 JDIMM2.81 ; JDIMM2.47 54.09,76.13 54.4,75.82 v2(54.4,75.42) 54.1,75.13 JDIMM2.51 ; JDIMM2.68 43.72,70.87 v2(43.57,71.03) 43.57,71.66 43.78,71.87 JDIMM2.64 ; v2(118.51,118.99) 118.51,118.97 UV1.K22 ; JDIMM1.197 68.14,36.13 68.57,36.56 v2(68.57,36.65) 68.57,36.91 68.36,37.13 JDIMM1.193 ; JEDP1.38 224.08,31.55 225.41,31.55 v2(225.57,31.71) ; JDIMM2.171 54.19,43.12 v2(54.41,43.34) 54.41,43.93 54.2,44.14 53.07,44.14 JDIMM2.167 ; JDIMM1.231 68.27,27.63 68.6,27.95 68.6,28.6 68.54,28.66 v2(68.53,28.66) 67.96,28.66 67.93,28.63 JDIMM1.227 ; UV1.Y32 110.5,125.56 v2(110.83,125.56) ; JEDP1.9 224.08,46.05 224.77,46.05 224.89,45.93 v2(225.29,45.93) ; JDIMM1.18 58.11,82.88 v2(57.83,83.16) 57.83,83.57 58.14,83.88 JDIMM1.14 ; v2(69.2,83.37) 69.2,82.03 68.79,81.62 JDIMM1.23 ; v2(54.76,83.67) 54.76,82.43 54.45,82.13 JDIMM2.23 ; v2(69.27,34.97) 69.27,33.49 68.91,33.13 JDIMM1.209 ; JDIMM1.107 68.43,60.62 68.65,60.84 v2(68.65,61) 68.65,61.32 68.34,61.62 JDIMM1.103 ; JDIMM2.19 53.94,83.13 54.25,83.43 v2(54.25,83.44) 54.25,83.82 53.94,84.13 JDIMM2.15 ; v2(43.58,42.51) 43.95,42.87 JDIMM2.172 ; JDIMM1.19 68.26,82.62 68.56,82.93 v2(68.56,83.32) 68.26,83.62 JDIMM1.15 ; JDIMM2.201 54.71,35.63 55.38,36.3 v2(55.38,36.75) ; v2(69.07,30.7) 69.07,31.66 68.6,32.13 JDIMM1.213 ; JDIMM1.1 68.22,87.13 68.48,86.86 v2(68.48,86.65) 68.48,86.43 68.18,86.13 JDIMM1.5 ; JDIMM2.61 54.07,72.62 54.41,72.28 54.41,71.74 v2(54.4,71.73) 54.3,71.62 JDIMM2.65 ; JDIMM2.22 v2(43.49,82.37) ; v2(57.11,25.97) 57.09,25.98 57.09,27.38 57.59,27.87 JDIMM1.230 ; JDIMM2.192 43.63,37.87 v2(43.38,38.12) 43.37,38.14 43.37,38.57 43.67,38.87 JDIMM2.188 ; JDIMM1.218 57.21,30.87 v2(55.92,32.16) 57.93,32.16 58.22,31.87 JDIMM1.214 ; JDIMM1.2 58.1,86.88 57.8,86.57 57.8,86.58 v2(57.8,86.58) ; JDIMM2.10 43.81,85.37 43.51,85.68 v2(43.51,86.05) 43.51,86.07 43.81,86.37 JDIMM2.6 ; v2(54.87,77.9) 54.87,78.23 53.97,79.13 JDIMM2.35 ; JWLAN1.31 52.55,99.28 v2(52.29,99.03) ; JDIMM2.247 54.15,24.12 54.45,24.43 v2(54.45,24.45) 54.45,24.82 54.15,25.12 JDIMM2.243 ; JDIMM2.69 54.37,70.62 54.59,70.41 54.59,69.76 v2(54.69,69.65) 54.66,69.62 JDIMM2.73 ; JDIMM1.205 68.45,34.13 68.71,34.39 68.71,34.89 v2(68.66,34.94) 68.47,35.13 JDIMM1.201 ; JDIMM2.234 43.89,27.38 v2(43.58,27.68) 43.58,28.11 43.85,28.38 JDIMM2.230 ; JDIMM2.239 55.39,26.12 55.69,26.43 v2(55.69,27.38) 55.67,27.41 54.16,27.41 53.88,27.12 JDIMM2.235 ; UV1.AG12 103.91,110.17 v2(103.91,109.63) ; JWLAN1.55 58.55,101.1 58.33,101.31 v2(57.05,101.31) JWLAN1.49 ; JDIMM1.51 68.32,74.62 68.56,74.87 68.56,75.3 68.55,75.31 v2(68.55,75.43) 68.36,75.62 JDIMM1.47 ; JEDP1.19 225.07,41.05 v2(225.1,41.08) ; JDIMM2.9 54.3,85.62 54.84,86.17 v2(54.84,87.59) ; UV1.F16 121.28,113.92 121.59,113.61 v2(121.59,113.56) ; v2(108.13,121.64) 107.94,121.64 UV1.AC26 ; JDIMM2.210 43.78,33.38 43.62,33.54 v2(43.62,34.14) 43.86,34.38 JDIMM2.206 ; JEDP1.35 224.08,33.05 v2(225.53,33.05) ; UV1.K11 118.43,109.74 v2(118.43,109.61) ; JEDP1.16 v2(225.1,42.55) ; JDIMM1.44 58.01,76.38 57.7,76.07 v2(57.7,75.63) 57.7,75.63 57.95,75.38 JDIMM1.48 ; JDIMM2.103 54.12,62.13 54.34,61.91 v2(54.34,61.34) 54.12,61.13 JDIMM2.107 ; JDIMM1.94 58.14,63.88 57.86,64.16 v2(57.86,64.57) 57.86,64.57 58.16,64.88 JDIMM1.90 ; JWLAN1.7 v2(44.55,99.04) ; JDIMM1.85 68.27,66.13 68.55,65.85 v2(68.55,65.29) 68.38,65.13 JDIMM1.89 ; JDIMM2.90 43.86,65.38 43.64,65.16 v2(43.64,64.62) 43.88,64.38 JDIMM2.94 ; JDIMM2.26 43.92,81.37 43.64,81.1 v2(43.64,80.59) 43.86,80.37 JDIMM2.30 ; JDIMM1.202 57.98,34.87 57.75,35.11 57.03,35.11 v2(57,35.13) 57,35.99 57.39,36.38 JDIMM1.196 ; JDIMM1.171 66.34,42.63 65.63,41.92 65.21,41.92 64.7,42.43 v2(64.66,42.43) ; JDIMM1.184 56.74,39.38 v2(56.67,39.44) 56.67,39.99 57.05,40.38 JDIMM1.180 ; JWLAN1.61 60.05,101.27 v2(60.09,101.31) 61.25,101.31 61.55,101.01 JWLAN1.67 ; JWLAN1.1 v2(43.05,99.02) ; v2(50.88,99.05) 51.05,99.22 JWLAN1.25 ; v2(56.98,23.42) 57.94,24.38 JDIMM1.244 ; JDIMM1.27 68.27,80.62 68.6,80.3 v2(68.6,79.7) 68.58,79.7 68.5,79.62 JDIMM1.31 ; v2(225.05,39.62) 224.98,39.55 JEDP1.22 ; JDIMM2.56 43.86,73.87 43.64,73.66 v2(43.64,73.04) 43.8,72.87 JDIMM2.60 ; JWLAN1.18 v2(49.3,106.58) ; JDIMM1.239 68.33,25.63 v2(68.56,25.85) 68.56,26.32 68.26,26.63 JDIMM1.235 ; JDIMM2.252 43.93,22.87 43.63,23.18 v2(43.63,23.61) 43.89,23.87 JDIMM2.248 ; JDIMM2.5 53.97,86.62 54.28,86.93 v2(54.28,87.18) 54.28,87.31 53.96,87.62 JDIMM2.1 ; JDIMM2.14 43.86,84.37 43.55,84.07 v2(43.55,83.68) 43.86,83.37 JDIMM2.18 ; v2(56.08,98.89) 56.03,98.94 56.03,98.96 55.55,99.44 JWLAN1.43 ; UV1.AE14 106.06,111.97 v2(106,111.92) ; JDIMM2.205 54.01,34.63 54.29,34.35 54.29,33.8 v2(54.28,33.8) 54.11,33.63 JDIMM2.209 ; JDIMM1.223 68.17,29.63 68.48,29.93 v2(68.48,30.69) 68.48,30.77 68.12,31.13 JDIMM1.217 ; UV1.U25 v2(111.83,121.54) ; JDIMM1.106 58.1,60.88 v2(57.84,61.14) 57.84,61.57 58.14,61.88 JDIMM1.102 ; JDIMM2.238 v2(43.62,26.38) ; JWLAN1.10 v2(47.3,106.52)
  BOTTOM w0.381: v2(114.03,108.55) 114.43,108.55 UV1.P9 ; UV1.V11 111.46,109.6 111.7,109.37 v2(111.7,109.36) ; UC7.3 128.66,52.76 128.64,52.74 v2(128.12,52.74) ; v2(107.32,13.59) 107.01,13.91 UC4.3 ; UV1.H20 119.18,117.79 119.18,117.83 v2(119.2,117.83) ; UV1.Y10 109.3,109.12 v2(109.3,109.12) 109.29,109.12 UV1.AB10 ; UV1.P25 114.75,121.12 v2(115.27,121.64) 115.79,121.12 UV1.N25 ; v2(107.37,114.43) 107.37,114.63 UV1.AC17 ; UV1.R12 UV1.T13 113.26,111.98 v2(113.69,112.41) 114.2,112.92 UV1.R15 114.72,113.38 114.72,113.44 115.2,113.92 UV1.N16 115.78,113.4 v2(115.86,113.4) ; UV1.R12 114.26,110.79 v2(113.78,110.31) 113.39,109.92 UV1.T11 ; UV1.R12 114.79,111.45 v2(114.86,111.45) 115.26,111.85 UV1.N13 UV1.M12 UV1.N11 115.22,109.88 114.3,109.88 UV1.R11 ; UV1.T21 113.26,117.62 v2(112.86,117.22) 112.46,116.82 UV1.U20 UV1.V18 111.37,115.72 v2(110.87,115.22) 110.46,114.8 UV1.Y17 110.26,114.72 UV1.AA16 109.42,113.92 v2(108.9,113.4) 108.46,112.95 UV1.AB15 ; v2(158.39,22.94) 158.4,22.94 158.78,22.56 RE20.2 ; EU3101.3 v2(197.7,18) ; v2(110.91,117.17) UV1.Y20 ; UV1.N18 UV1.R17 114.17,114.72 v2(113.76,114.31) 113.65,114.31 UV1.T16 112.46,113.12 UV1.U15 112.46,112.9 112.05,112.49 v2(112.05,112.44) 112.05,112.36 111.6,111.92 UV1.V13 111.46,111.83 v2(110.94,111.31) ; UV2.3 97.22,101.37 v3(97.47,101.12) 97.59,101 v2(98.56,101) ; UV1.AA11 109.58,109.92 v2(110.05,110.38) ; U2.5 136.26,16.68 135.97,16.4 v2(135.85,16.4) ; v2(115.72,117.28) 115.7,117.28 UV1.N21 115.19,117.72 114.8,117.32 v2(114.8,117.26) UV1.R20 UV1.T18 113.26,115.52 UV1.U17 112.26,114.72 UV1.V16 111.41,113.92 v2(111,113.51) 110.46,112.97 UV1.Y15 110.38,112.92 v2(109.91,112.45) 109.91,112.37 UV1.AA13
  BOTTOM w0.4: v2(123.95,103.87) 123.92,103.87 123.92,104.06 UV1.A3
  BOTTOM w0.457: PC1140.2 136.36,52.03 v2(136.74,52.03) ; v2(132.1,80.42) 131.73,80.42 PC1014.2 ; v2(132.48,66.57) 132.11,66.57 PC1082.2 ; PC1027.2 131.66,77.62 v2(132.1,77.62) ; v2(135.91,64.99) 135.48,64.99 PC1069.2 ; PC1173.2 135.54,63.65 v2(135.91,63.65) ; PC1080.2 132.11,69.37 v2(132.48,69.37) ; RC109.2 105.95,17.2 106.04,17.29 106.04,17.31 v2(106.19,17.46) 106.57,17.46 106.83,17.72 RC145.2 ; v2(115.8,78.52) 115.41,78.52 PC1136.2 ; PC1184.2 131.73,81.81 v2(132.1,81.81) ; v2(133.56,63.65) 133.19,63.65 PC1077.2 ; PC1076.2 133.19,65.05 v2(133.56,65.05) ; PC1021.2 115.41,79.79 v2(115.8,79.79) ; PC1059.2 136.37,53.43 v2(136.74,53.43) ; v2(132.48,67.97) 132.11,67.97 PC1081.2 ; PC1130.2 115.41,77.25 v2(115.8,77.25) ; v2(114.1,74.05) 114.5,74.05 PC1178.2 ; PC1079.2 132.11,70.76 v2(132.48,70.76) ; v2(113.34,79.13) 113.73,79.13 PC1019.2 ; v2(133.56,62.38) 133.19,62.38 PC1072.2 ; PC1002.2 133.19,60.98 v2(133.56,60.98) ; v2(115.8,75.98) 115.41,75.98 PC1132.2 ; PC1025.2 131.73,83.21 v2(132.1,83.21) ; PC1016.2 113.73,76.59 v2(113.34,76.59) ; PC1018.2 113.73,75.32 v2(113.34,75.32) ; PC1022.2 113.73,77.86 v2(113.34,77.86) ; PC1015.2 131.73,79.02 v2(132.1,79.02) ; PC1017.2 115.41,81.06 v2(115.8,81.06) ; PC1179.2 131.73,84.61 v2(132.1,84.61) ; v2(132.48,72.16) 132.11,72.16 PC1078.2 ; PC1020.2 113.73,80.4 v2(113.34,80.4) ; PC1060.2 136.37,55.08 v2(136.74,55.08)
  BOTTOM w0.508: RL6.1 v2(24.91,122.57) ; DA6.1 v2(219.5,29.02) ; PC661.2 163.23,72.3 v2(162.71,71.78) ; v2(88.96,8.02) 89.28,7.7 JKB1.31 90.36,4.91 94.25,4.91 95.08,5.73 JTP1.10 ; PC802.2 54.42,2.67 v2(54,2.25) ; PC128.2 v2(182.66,30) 182.6,30.06 PR122.2 ; PC1406.2 151.59,85.61 v2(152.06,85.14) 152.48,85.56 PC1405.2 ; PQ5.3 162.06,129.13 PR9.1 v2(163.45,129.13) ; v2(130.39,50.19) 130.24,50.05 CC6.2 ; v2(155.28,13.48) 154.96,13.8 CE16.2 ; v2(112.29,99.01) 112.68,98.62 RV21.1 ; JODD1.25 v2(200.75,50.68) ; PC677.2 162.97,81.94 v2(162.97,81.49) ; JODD1.26 184.53,49.17 v2(184.02,48.66) ; PR731.2 189.57,33.11 v2(189.12,32.66) 189.57,32.22 PR732.2 ; v2(178.43,55.06) 178.43,54.38 179.04,53.77 JFAN1.5 ; CC69.2 96.09,30.11 v2(96.45,30.46) ; CC80.2 89.69,15.05 CC81.2 89.72,14.29 v2(90.63,13.38) ; PR753.1 PC751.1 190.39,42.87 PC752.1 v2(189.69,42.89) ; JEDP1.42 227.51,51.75 227.51,51.75 v2(229.64,51.75) ; v2(198.75,38.68) 199.17,38.68 PC757.1 ; CZ29.2 114.66,96.41 v2(114.61,96.47) 114.33,96.2 CZ31.2 ; CZ20.1 111.72,87.5 v2(112.31,88.09) ; CV233.2 v2(154.83,128.17) ; J3D1.12 221.25,49.62 v2(221.76,49.11) ; v2(135.05,12.17) 134.88,12.33 C24.2 133.69,13.55 C20.2 ; C17.2 v2(229.09,25.36) ; PC748.2 188.03,38.33 v2(188.33,38.63) 188.03,38.94 PC749.1 ; v2(193.25,49.36) 193.5,49.11 JODD1.13 ; C25.2 135.92,17.35 135.98,17.29 v2(135.98,17.23) ; PC769.1 PC768.1 200.25,37.74 200.3,37.74 v2(200.81,38.25) ; JDIMM2.262 36.95,23.03 35.71,24.28 v2(35.71,25.69) ; PR738.2 v2(161.89,105.68) ; v2(189.38,39.97) 189.81,39.54 PR727.2 ; v2(168.85,48.99) 168.25,48.99 PC602.2 168.1,48.84 168.1,47.96 PC695.1 ; v2(141.18,15.16) 141.18,14.81 141.56,14.44 CE4.2 ; J3D1.11 213.15,49.27 v2(212.93,49.05) ; v2(91.78,99.64) 91.46,99.96 PR204.2 ; CV165.2 v2(138.39,96.04) ; v2(17.67,16.21) 17.73,16.15 DA5.1 ; RC52.2 95.95,27.04 v2(95.75,26.85) ; CV64.2 97.89,117.99 CV123.2 97.62,117.9 v2(97.19,117.47) ; v2(129.88,59.1) 129.95,59.17 RC147.2 ; v2(226.12,21.63) 225.41,22.34 R10.2 ; v2(145.43,12.27) 145.43,13.23 145.07,13.6 CE3.2 ; JCMOS1.2 89.03,17.04 v2(89.56,17.56) ; v2(109.49,98.65) 109.29,98.85 RV83.2 ; v2(93.4,16.59) 93.62,16.38 CC88.2 ; UU3.2 126.68,9.79 v2(126.49,9.61) ; PR653.2 160.99,58.32 160.61,58.7 v2(160.36,58.7) ; JLED1.4 v2(149.73,12.44) ; JKBBL1.5 118.14,5.55 v2(117.54,6.15) ; JSPK1.5 v2(12.15,1.79) ; v2(176.17,38.07) 176.17,38.08 PR110.2 ; RV38.2 132.6,95.01 v2(132.04,94.44) 131.71,94.77 CV97.2 ; PD4.1 157.12,121.75 v2(156.74,121.37) ; JODD1.7 190.5,47.18 v2(190.93,46.75) ; v2(128.23,34.25) 128.68,34.25 129.19,33.74 RC7.2 ; CX5.1 v2(215.61,36.89) ; PR502.1 162.06,31.9 v2(162.48,32.33) 162.02,32.79 PC502.2 ; v2(125.69,95.59) 125.79,95.48 CZ28.2 ; RC56.2 112.65,24.2 v2(112.27,24.58) ; v2(162.12,74.19) 161.64,74.19 PR662.2 ; EC2201.2 v2(163.54,109.18) ; C34.2 121.62,8.47 v2(122.13,8.98) 121.68,9.42 EC3002.2 121.25,9.61 R27.2 ; JSPK1.6 v2(8.46,1.79) ; RC134.2 129.43,61.89 v2(129.84,61.89) ; v2(97.87,126.51) 97.94,126.45 CV17.2 ; v2(115.72,99.02) 115.93,99.02 RV151.1 ; CC13.2 133.6,53.31 v2(133.24,53.31) ; v2(225.19,24.71) 224.72,25.18 U1.2 ; RV368.1 114.05,101.43 114.56,101.94 v2(115.14,101.94) ; JODD1.14 193.5,51.06 192.99,51.57 192.75,51.57 v2(192.62,51.71) ; CL10.2 v2(38.17,118.85) ; R45.2 91.21,7.57 v2(90.86,7.92) ; CL9.2 31.07,123.53 v2(31.39,123.85) ; v2(158.64,83.4) 158.03,84.02 PH601.1 ; JIOB1.2 184.6,18.2 184.23,18.56 v2(184.23,19) ; v2(152.61,38) PR305.2 PR310.2 ; CV164.2 v2(148.74,95.73) ; EC2203.2 155.61,101.67 v2(155.64,101.64) ; CU10.2 v2(13.04,50.03) ; PC204.1 v2(83.27,104.86) ; C13.2 222.02,38.07 v2(222.21,37.87) ; RL4.2 v2(36.73,121.7) ; CE33.2 138.58,12.82 v2(138.36,12.61) ; v2(96.58,111.49) 96.58,110.42 97.14,109.86 RV88.1 ; v2(124.62,9.61) 124.61,9.61 124.05,10.16 CU17.2 ; RC122.2 v2(128.47,69.18) ; v2(127.15,61.56) 127.48,61.89 RC146.2 ; RC121.2 v2(128.47,70.06) ; v2(154.93,107.41) 154.56,107.78 CV169.2 ; PQ712.3 155.02,104.68 v2(154.88,104.54) RV118.2 ; v2(154.92,118.58) 154.35,119.15 CV342.2 ; PR505.2 156.73,35.24 156.29,35.69 156.24,35.69 156.22,35.71 v2(155.85,35.71) ; CV235.2 v2(154.76,129.18) ; v2(120.25,89.79) CZ16.1 ; v2(171.34,57.73) 171.34,57.38 PC641.2 ; RC156.2 v2(116.41,73.56) ; v2(127.72,95.29) EC2225.2 128.36,95.29 CZ26.2 ; RV89.1 99.85,108.13 v2(100.36,108.64) ; YL1.2 v2(41.51,122.29) ; CV391.2 RV120.2 RV121.2 v2(141.31,96.66) ; PR755.1 192.6,41.07 PC753.1 v2(191.98,41.93) ; v2(142.89,131.6) 142.74,131.44 RV55.2 ; v2(153.24,11.2) 153.73,11.68 153.73,12.42 JLED1.1 ; PH603.1 154.9,74.31 v2(154.64,74.06) ; EC2209.2 121.86,129.11 v2(123.05,127.91) ; v2(183.41,56.45) 183.41,55.73 JFAN1.4 ; CV162.2 v2(154.88,111.02) ; JIOB1.18 169.07,14.53 v2(169.31,14.76) ; v2(56.08,98.89) 56.18,98.8 EC3201.2 ; JHDD1.13 200.99,13.47 v2(201.82,14.31) ; EC2214.2 158.79,47.85 158.71,47.77 158.71,47.77 v2(158.64,47.71) ; RC48.2 119.02,24.15 v2(119.02,23.39) ; v2(115.52,16.01) 115.53,16.01 115.53,12.76 117.03,11.26 UC3.4 ; v2(156.75,56.48) 156.99,56.72 PC645.2 ; CV161.2 v2(147.66,95.73) ; CU22.2 v2(16.72,73.23) ; UL3.2 27.7,120.86 v2(27.2,120.36) ; CE14.2 147,14.91 v2(147.15,14.76) ; v2(197.37,29.35) 197.25,29.23 EC2202.2 ; v2(97.76,121.42) 97.88,121.55 98.71,121.55 98.78,121.47 RV4.2 98.78,121.45 98.78,121.4 97.97,120.58 RV163.2 ; v2(97.87,122.47) 97.94,122.54 CV18.2 ; PR1411.2 PR1407.2 v2(158.45,85.74) ; v2(45.24,9.42) PR802.2 45.44,8.51 PU800.8 ; PD6.2 v2(164.08,127.89) ; v2(114.62,18.45) 114.64,18.47 114.64,19.26 RC182.2 RC6.1 ; EU3501.3 v2(29.67,110.32) ; CC7.2 v2(130.24,46.31) ; v2(204.11,14.33) 204.08,14.36 PC8.2 ; PC1404.2 PR1404.2 v2(158.72,88.43) ; v2(110.7,23.39) 110.89,23.58 110.89,24.1 ; CV221.2 v2(154.27,100.35) ; v2(115.26,92.02) 115.26,90.44 114.94,90.12 CZ17.2 ; 229.01,12.38 v2(228.01,12.38) ; v2(162.83,109.13) 162.83,108.88 163.55,108.16 EC2208.2 ; v2(229.31,28.96) 229.19,28.85 JEDP1.41 ; PC209.2 v2(84.47,100.54) ; RL2.1 v2(39.9,115.72) ; PC210.2 PC213.2 92.47,103.53 v2(92.63,103.37) ; PC618.1 PC619.1 v2(171.41,52.35) ; v2(31.9,5.42) 32.38,4.94 JRTC1.4 ; JDIMM2.261 36.95,90.09 v2(36.59,90.45) ; v2(131.72,42.5) 131.72,42.68 131.38,43.02 131.34,43.02 131.33,43.03 130.41,43.03 CC63.2 ; PC203.2 89.3,100.54 v2(88.86,100.1) 88.41,100.54 PC202.2 ; JRTC1.2 28.58,6.31 28.06,6.83 28.01,6.83 27.77,7.07 v2(25.99,7.07) ; v2(187.92,51.4) 187.5,50.98 JODD1.2 ; v2(119.64,90.62) 119.64,91.08 119.13,91.59 CZ30.2 ; JODD1.8 v2(190.5,51.59) ; v2(180.64,27.74) 180.52,27.74 179.98,28.28 PR118.2 ; v2(145.69,39.71) 145.69,38.95 145.89,38.75 PC306.2 PC305.2 ; CV170.2 v2(154.88,106.7) ; CV173.2 v2(154.88,105.62) ; PC805.2 v2(55.61,8.57) ; v2(74.47,89.69) 75.15,89 JDIMM1.261 ; YV1.2 96.56,123.57 v2(96.56,122.41) ; JKB1.32 v2(63.13,8.07) ; PC649.2 158.81,54.96 PC652.2 v2(157.19,54.96) ; CV336.2 v2(154.27,98) ; YL1.4 v2(38.16,119.59) ; CV343.2 154.2,120.17 v2(154.77,120.74) 154.26,121.25 CV198.2 ; v2(157.44,7.57) 156.73,8.28 156.73,9.29 JLED1.5 ; YV1.4 v2(94.99,127.04) ; EC2206.2 104.98,134.07 v2(105.17,133.88) ; Q1.3 v2(41.12,4.29) ; CV334.2 v2(150.89,95.73) ; CZ13.1 v2(129.94,92.67) ; v2(187.8,15.99) 188.42,15.37 JIOB1.17 ; RX5.2 v2(207.52,37.43) ; v2(108.22,23.42) 108.16,23.48 RC68.2 RC67.2 ; EC2205.2 v2(169.18,134.72) ; JIOB1.1 185.6,18.13 186.08,18.61 v2(186.08,19) ; CZ27.2 126.2,91.23 v2(125.97,91.46) CZ14.1 ; JFAN1.6 182.82,57.9 181.88,58.84 v2(181.78,58.84) ; RC144.2 129.38,73.19 RC131.1 128.47,73.28 v2(128.47,73.9) ; v2(26.88,5.16) 26.03,4.31 JRTC1.3 ; EC3202.2 v2(53.49,97.59) ; CV395.2 v2(144.65,131.56) ; CC3.2 112.35,18.57 v2(112.41,18.5) ; v2(118.15,21.15) 118.15,21.18 118.13,21.2 118.13,21.6 RC50.1 ; CV341.2 v2(154.78,130.2) ; CZ15.1 v2(118.84,94) ; v2(97.17,39.31) 96.78,39.31 96.27,38.8 RC87.2 ; C21.2 130.46,12.77 130.38,12.7 v2(130.37,12.7) ; RV135.2 v2(154.86,123.47) ; v2(148.74,7.64) 147.73,8.65 147.73,9.29 JLED1.6 ; PC126.2 v2(176.23,28.66) ; JTP1.5 100.9,10.13 100.32,10.71 v2(100.32,10.79) 100.36,10.82 v2(101.9,10.82) 101.92,10.84 v2(103.35,10.84) 103.35,10.85 104.25,11.76 CC2.1 105.31,11.76 105.9,11.17 105.9,10.65 108.2,8.35 v2(108.2,8.2) 108.22,8.17 108.22,7.43 107.73,6.94 JTP1.9 108.77,5.55 JKBBL1.6 ; JODD1.1 187.5,45.88 v2(186.96,45.34) ; PC7.2 v2(200.55,17.93) ; RC8.2 105.85,24.64 CC56.2 106.15,25.44 v2(106.52,25.8) ; PC1408.2 v2(146.58,94.58) ; CV96.2 v2(135.28,97.04) ; v2(204.86,14.31) 204.81,14.25 204.81,12.38 ; DA4.1 v2(17.61,12.09) ; CL11.2 v2(40.86,118.83) ; CV333.2 v2(139.46,96.04) ; JDIMM1.262 75.15,18.68 76.03,17.8 v2(76.35,17.8) ; RC133.1 v2(123.84,73.86) ; CV166.2 v2(154.88,108.86) ; CZ18.1 111.79,92.43 CZ19.1 v2(110.7,91.57) ; v2(62.21,103.27) 62.65,102.83 JWLAN1.69 ; v2(196.16,42.57) PR779.1 196.16,40.18 PR751.1 ; RX6.2 v2(216.49,36.83) ; CC15.2 v2(125.82,71.74) ; JWLAN1.68 v2(41.95,99.22) ; RV123.2 v2(145.55,131.52) ; RC132.1 v2(127.64,73.89) ; PD5.2 v2(167.28,126.99) ; v2(205.89,41.36) 205.89,41.62 206.77,42.51 CX4.1 ; PC801.2 v2(53.02,2.25)
  BOTTOM w1.016: JLAN1.10 16.26,118.1 CL13.2
  vias: v2(0.43,96.82) v2(0.45,121.94) v2(0.68,101.89) v2(2.73,47.68) v2(2.74,29.41) v2(3.73,74.88) v2(3.73,69.8) v2(4.64,124.81) v2(4.95,96.92) v2(5.13,95.19) v2(5.18,50.06) v2(5.18,47.52) v2(5.58,77.08) v2(5.58,74.54) v2(5.58,72) v2(5.58,69.46) v2(5.81,28.03) v2(6.59,122.3) v2(6.94,78.82) v2(7.49,96.92) v2(7.65,124.13) v2(7.65,120.47) v2(7.72,50.06) v2(7.72,47.52) v2(7.95,66.96) v2(8.12,77.08) v2(8.12,74.54) v2(8.12,72) v2(8.12,69.46) v2(8.35,28.03) v2(8.99,45.28) v2(8.96,0.43) v2(9.6,52.44) v2(9.75,124.13) v2(9.75,120.47) v2(9.9,93.77) v2(10.03,96.92) v2(10.11,30.74) v2(10.26,50.06) v2(10.26,47.52) v2(10.66,77.08) v2(10.66,74.54) v2(10.66,72) v2(10.66,69.46) v2(10.81,122.3) v2(10.89,28.03) v2(13,124.83) v2(13.2,77.08) v2(13.2,74.54) v2(13.2,72) v2(13.2,69.46) v2(14.04,0.43) v2(16.29,4.3) v2(17.35,6.13) v2(17.35,2.47) v2(18.05,124.86) v2(18.22,90.16) v2(18.23,88.37) v2(18.19,87.61) v2(18.21,85.83) v2(18.28,85.08) v2(18.32,83.3) v2(18.28,82.53) v2(18.27,80.76) v2(18.63,56.41) v2(18.94,36.47) v2(18.88,34.75) v2(19.45,6.13) v2(19.45,2.47) v2(20.26,88.08) v2(20.51,4.3) v2(21.14,80.4) v2(21.34,85.43) v2(21.58,89.08) v2(21.79,82.64) v2(22.42,124.83) v2(24.2,0.43) v2(25.42,21.93) v2(25.42,19.96) v2(25.42,17.99) v2(26.26,61.16) v2(26.56,42.06) v2(26.63,40.16) v2(26.68,63.21) v2(27.05,124.86) v2(27.39,58.51) v2(27.39,21.93) v2(27.39,19.96) v2(27.39,17.99) v2(28.21,38.69) v2(28.21,36.85) v2(28.43,117.42) v2(29.28,0.43) v2(29.36,21.93) v2(29.36,19.96) v2(29.36,17.99) v2(29.61,58.13) v2(29.61,56.34) v2(30.12,59.08) v2(30.69,36.34) v2(31.34,124.86) v2(32.53,122.45) v2(32.6,36.4) v2(32.85,92.04) v2(33.64,117.92) v2(33.64,116.8) v2(33.64,115.68) v2(33.88,67.5) v2(33.88,66.92) v2(33.88,66.33) v2(33.88,65.75) v2(34.05,93.18) v2(34.37,122.45) v2(34.36,0.43) v2(34.75,116.8) v2(35.87,117.92) v2(36.06,124.86) v2(39.44,0.43) v2(41.04,124.86) v2(42.34,129.69) v2(43.23,135.5) v2(44.52,0.43) v2(44.62,3.02) v2(44.72,16.46) v2(45.1,16.05) v2(45.23,3) v2(46.65,84.66) v2(46.65,79.47) v2(46.65,73.99) v2(46.65,68.28) v2(46.65,52.76) v2(46.65,42.72) v2(46.65,41.4) v2(46.62,36.3) v2(46.62,25.38) v2(47.41,86.26) v2(47.41,84.66) v2(47.41,83.39) v2(47.41,80.72) v2(47.41,78.2) v2(47.41,75.26) v2(47.41,73.99) v2(47.41,72.47) v2(47.41,69.42) v2(47.41,66.32) v2(47.41,60.3) v2(47.41,58.14) v2(47.41,56.16) v2(47.41,54.03) v2(47.41,51.51) v2(47.41,49.87) v2(47.41,48.31) v2(47.41,47.26) v2(47.41,45.09) v2(47.41,43.97) v2(47.41,41.4) v2(47.38,39.6) v2(47.38,38.03) v2(47.38,34.71) v2(47.38,32.44) v2(47.38,29.31) v2(47.38,27.15) v2(47.38,24.23) v2(47.61,138.06) v2(48.17,84.66) v2(48.17,73.99) v2(48.17,62.94) v2(48.17,51.51) v2(48.17,49.87) v2(48.17,45.09) v2(48.17,42.72) v2(48.17,41.4) v2(48.94,86.26) v2(48.94,84.66) v2(48.94,83.39) v2(48.94,80.72) v2(48.94,79.47) v2(48.94,78.2) v2(48.94,75.26) v2(48.94,73.99) v2(48.94,72.47) v2(48.94,69.42) v2(48.94,68.28) v2(48.94,66.32) v2(48.94,62.94) v2(48.94,60.3) v2(48.94,58.14) v2(48.94,56.16) v2(48.94,54.03) v2(48.94,52.76) v2(48.94,51.51) v2(48.94,49.87) v2(48.94,48.31) v2(48.94,47.26) v2(48.94,45.09) v2(48.94,43.97) v2(48.94,42.72) v2(48.94,41.4) v2(48.9,39.6) v2(48.9,38.03) v2(48.9,36.3) v2(48.9,34.71) v2(48.9,32.44) v2(48.9,30.84) v2(48.9,29.31) v2(48.9,27.15) v2(48.9,25.38) v2(48.9,24.23) v2(49.17,6.62) v2(49.6,0.43) v2(49.7,79.47) v2(49.7,68.28) v2(49.7,62.94) v2(49.7,51.51) v2(49.7,49.87) v2(49.7,45.09) v2(49.7,43.97) v2(50.12,6.62) v2(50.43,39.6) v2(50.43,38.03) v2(50.43,34.71) v2(50.43,32.44) v2(50.43,29.31) v2(50.43,27.15) v2(50.43,24.23) v2(50.46,86.26) v2(50.46,83.39) v2(50.46,80.72) v2(50.46,79.47) v2(50.46,78.2) v2(50.46,75.26) v2(50.46,72.47) v2(50.46,69.42) v2(50.46,68.28) v2(50.46,66.32) v2(50.46,60.3) v2(50.46,54.03) v2(50.46,51.51) v2(50.46,49.87) v2(50.46,48.31) v2(50.46,45.09) v2(50.46,43.97) v2(50.46,42.72) v2(51.22,84.66) v2(51.22,79.47) v2(51.22,73.99) v2(51.22,68.28) v2(51.22,62.94) v2(51.22,41.4) v2(51.19,30.84) v2(52.16,124.76) v2(52.16,123.24) v2(52.16,121.71) v2(53.69,124.76) v2(53.69,123.24) v2(53.69,121.71) v2(54.68,0.43) v2(55.21,124.76) v2(55.21,123.24) v2(55.21,121.71) v2(58.69,102.2) v2(59.2,137.57) v2(59.3,102.2) v2(59.76,0.43) v2(60.85,79.08) v2(60.85,67.5) v2(60.85,52.64) v2(60.85,51.47) v2(60.85,46.8) v2(60.85,35.76) v2(60.85,30.08) v2(60.85,24.65) v2(61.23,56.63) v2(61.23,55.18) v2(61.5,103.51) v2(61.61,85.66) v2(61.64,83.13) v2(61.61,80.27) v2(61.61,77.4) v2(61.61,75.12) v2(61.61,71.87) v2(61.61,69.28) v2(61.61,66.23) v2(61.62,59.06) v2(61.61,57.97) v2(61.61,53.78) v2(61.61,51.47) v2(61.61,49.59) v2(61.61,47.71) v2(61.61,46.8) v2(61.61,45.86) v2(61.61,44.71) v2(61.61,42.43) v2(61.61,37.69) v2(61.61,33.99) v2(61.61,32.18) v2(61.61,30.08) v2(61.61,26.87) v2(61.61,23.38) v2(61.74,122.77) v2(61.74,122.19) v2(61.72,119.95) v2(61.81,118.46) v2(61.79,117.07) v2(62.11,119.18) v2(62.08,117.73) v2(62.09,61.4) v2(62.2,124.62) v2(62.39,122.77) v2(62.39,122.19) v2(62.35,119.94) v2(62.44,118.45) v2(62.4,117.05) v2(62.37,73.59) v2(62.37,63.34) v2(62.37,49.59) v2(62.37,45.86) v2(62.37,30.08) v2(62.81,119.18) v2(62.82,117.75) v2(62.76,56.63) v2(62.76,55.18) v2(62.89,124.63) v2(63.01,122.77) v2(63.01,122.19) v2(63.01,119.95) v2(62.98,28.85) v2(63.11,118.43) v2(63.14,85.66) v2(63.14,84.64) v2(63.14,80.27) v2(63.14,79.08) v2(63.14,77.4) v2(63.14,75.12) v2(63.14,71.87) v2(63.14,69.28) v2(63.14,67.5) v2(63.14,66.23) v2(63.15,59.06) v2(63.14,57.97) v2(63.14,53.78) v2(63.14,52.64) v2(63.14,51.47) v2(63.14,49.59) v2(63.14,47.71) v2(63.14,46.8) v2(63.14,45.86) v2(63.14,44.71) v2(63.14,42.43) v2(63.14,41.16) v2(63.14,39.2) v2(63.14,37.69) v2(63.14,35.76) v2(63.14,33.99) v2(63.14,32.18) v2(63.14,30.08) v2(63.14,26.87) v2(63.14,24.65) v2(63.14,23.38) v2(63.18,117.09) v2(63.16,83.13) v2(63.55,124.63) v2(63.46,119.17) v2(63.49,117.76) v2(63.52,55.18) v2(63.59,119.95) v2(63.62,61.4) v2(63.67,122.76) v2(63.67,122.17) v2(63.8,125.34) v2(63.82,118.45) v2(63.85,117.06) v2(63.9,79.08) v2(63.9,67.5) v2(63.9,63.34) v2(63.91,59.06) v2(63.9,57.97) v2(63.9,49.59) v2(63.9,45.86) v2(63.9,35.76) v2(64.14,117.75) v2(64.19,124.63) v2(64.21,119.19) v2(64.28,56.63) v2(64.28,55.18) v2(64.47,125.34) v2(64.52,118.43) v2(64.53,107.78) v2(64.5,28.85) v2(64.6,117.06) v2(64.66,85.66) v2(64.69,83.13) v2(64.66,80.27) v2(64.66,79.08) v2(64.66,77.4) v2(64.66,75.12) v2(64.66,73.59) v2(64.66,71.87) v2(64.66,69.28) v2(64.66,67.5) v2(64.66,66.23) v2(64.66,57.97) v2(64.66,53.78) v2(64.66,51.47) v2(64.66,49.59) v2(64.66,46.8) v2(64.66,39.2) v2(64.66,37.69) v2(64.66,35.76) v2(64.66,33.99) v2(64.66,32.18) v2(64.66,26.87) v2(64.66,23.38) v2(64.84,0.43) v2(64.9,124.63) v2(64.94,117.75) v2(65.04,121.44) v2(64.98,119.17) v2(65.15,125.33) v2(65.12,107.78) v2(65.14,61.4) v2(65.26,124) v2(65.34,118.39) v2(65.39,117.05) v2(65.42,84.64) v2(65.42,79.08) v2(65.42,67.5) v2(65.42,63.34) v2(65.42,53.78) v2(65.42,52.64) v2(65.42,51.47) v2(65.42,41.16) v2(65.42,35.76) v2(65.42,30.08) v2(65.6,124.64) v2(65.63,121.44) v2(65.65,123.35) v2(65.67,119.16) v2(65.73,117.77) v2(65.7,107.78) v2(65.98,125.2) v2(65.97,124.01) v2(66.14,118.37) v2(66.21,121.44) v2(66.16,117.05) v2(66.28,124.62) v2(66.31,123.35) v2(66.29,107.78) v2(66.47,117.75) v2(66.63,124.01) v2(66.67,125.2) v2(66.8,121.44) v2(66.92,137.56) v2(66.9,118.37) v2(66.87,107.78) v2(66.96,124.61) v2(67.01,123.36) v2(66.96,117.29) v2(67.46,107.78) v2(69.36,75.38) v2(69.92,0.43) v2(69.96,75.38) v2(70.57,67.02) v2(72.22,23.07) v2(72.85,23.07) v2(73.3,23.52) v2(73.59,75.53) v2(74.19,75.53) v2(74.76,111.46) v2(74.95,118.77) v2(75,0.43) v2(75.33,122.32) v2(75.53,118.77) v2(75.91,122.32) v2(76.13,138.07) v2(76.12,118.77) v2(76.5,122.32) v2(76.6,111.46) v2(76.7,118.77) v2(77.08,122.32) v2(77.93,124.73) v2(78,131.02) v2(78,129.56) v2(78.35,101.92) v2(78.94,101.92) v2(79.56,102.83) v2(79.56,102.25) v2(79.56,101.66) v2(80.14,102.83) v2(80.14,102.25) v2(80.14,101.66) v2(80.08,0.43) v2(80.73,102.83) v2(80.73,102.25) v2(80.73,101.66) v2(81.21,138.07) v2(83.43,110.28) v2(83.44,109.71) v2(83.42,109.15) v2(84.04,110.29) v2(84.03,109.71) v2(84,109.15) v2(84.98,105.33) v2(85.16,0.43) v2(85.57,105.33) v2(86.29,138.03) v2(86.65,8.5) v2(87.24,8.5) v2(87.31,104.92) v2(87.52,35.71) v2(87.93,105.55) v2(87.93,104.3) v2(87.93,36.09) v2(88.32,36.49) v2(88.56,104.92) v2(88.74,36.86) v2(90.09,126.15) v2(90.06,123.77) v2(90.24,0.43) v2(90.3,112.55) v2(90.3,111.96) v2(90.38,108.22) v2(90.38,107.64) v2(90.49,132.24) v2(90.65,123.77) v2(90.7,129.38) v2(90.67,126.15) v2(90.89,112.54) v2(90.89,111.96) v2(91.08,132.24) v2(91.23,123.77) v2(91.28,129.38) v2(91.26,126.15) v2(91.37,138.07) v2(91.66,132.24) v2(91.87,129.38) v2(93.97,49.96) v2(94.04,44.68) v2(94.19,62.71) v2(94.39,48.42) v2(94.6,42.92) v2(94.69,54.29) v2(94.83,118) v2(94.83,117.42) v2(94.86,40.98) v2(95.05,60.91) v2(95.22,57.9) v2(95.32,0.43) v2(95.42,62.72) v2(95.38,46.48) v2(95.73,49.92) v2(95.85,64.66) v2(95.83,44.68) v2(95.91,52.33) v2(96.25,60.91) v2(96.2,59.61) v2(96.3,48.41) v2(96.45,138.07) v2(96.41,130.52) v2(96.45,54.25) v2(96.45,42.92) v2(96.71,40.98) v2(97.08,132.04) v2(97.21,66.62) v2(97.34,46.48) v2(97.38,68.23) v2(97.57,49.97) v2(97.66,44.65) v2(98.21,42.92) v2(98.44,48.43) v2(98.5,52.44) v2(99.33,133.18) v2(99.65,132.04) v2(100.03,130.45) v2(100.4,0.43) v2(101.11,133.37) v2(101.53,138.07) v2(101.64,130.13) v2(102,106.97) v2(102.11,73.57) v2(102.25,131.66) v2(102.48,71.6) v2(102.63,131.21) v2(103.36,72.32) v2(103.65,129.88) v2(103.81,108.46) v2(104.92,64.56) v2(104.94,39.9) v2(105.03,72.68) v2(105.02,71.44) v2(105.3,130.26) v2(105.48,0.43) v2(105.61,64.56) v2(105.6,39.9) v2(105.85,76.45) v2(105.85,74.62) v2(106.25,39.88) v2(106.25,38.97) v2(106.36,94.06) v2(106.61,138.07) v2(106.69,103.43) v2(106.75,93.64) v2(106.84,65.49) v2(106.89,129.56) v2(107.24,103.12) v2(107.49,77.73) v2(107.49,76.4) v2(107.49,74.56) v2(107.49,72.65) v2(109.13,52.74) v2(109.11,22.01) v2(109.1,20.48) v2(109.3,42.06) v2(109.51,58.18) v2(109.54,55.01) v2(109.61,75.44) v2(109.63,73.54) v2(109.68,52.74) v2(109.67,49.29) v2(110.04,37) v2(110.14,55.01) v2(110.27,52.74) v2(110.26,49.29) v2(110.42,64.96) v2(110.43,45.92) v2(110.43,45.33) v2(110.57,60.85) v2(110.56,0.43) v2(110.74,72.89) v2(110.74,71.13) v2(110.71,58.18) v2(110.76,55.02) v2(110.81,49.29) v2(110.75,32.4) v2(110.85,52.74) v2(110.9,43.9) v2(111.18,60.31) v2(111.31,49.76) v2(111.39,67.53) v2(111.39,66.88) v2(111.39,66.23) v2(111.39,65.55) v2(111.42,59.79) v2(111.4,55.01) v2(111.49,52.27) v2(111.92,60.6) v2(111.92,58.18) v2(111.92,55.83) v2(111.96,49.76) v2(112,47.41) v2(111.97,42.5) v2(112.11,43.9) v2(112.61,42.5) v2(112.68,54.37) v2(112.68,53.74) v2(112.78,52.28) v2(113.13,60.6) v2(113.13,58.18) v2(113.13,55.83) v2(113.2,49.8) v2(113.2,47.41) v2(113.27,54.37) v2(113.27,53.74) v2(113.3,45.92) v2(113.3,45.33) v2(113.32,43.9) v2(113.85,54.37) v2(113.85,53.74) v2(114.04,52.28) v2(114.33,60.6) v2(114.33,58.18) v2(114.33,55.83) v2(114.43,54.37) v2(114.43,53.74) v2(114.41,49.8) v2(114.41,47.41) v2(114.52,43.9) v2(115.02,54.37) v2(115.02,53.74) v2(115.27,52.28) v2(115.54,60.6) v2(115.54,58.18) v2(115.54,55.83) v2(115.6,54.37) v2(115.6,53.74) v2(115.62,49.8) v2(115.62,47.41) v2(115.64,0.43) v2(115.73,43.9) v2(115.83,118.17) v2(116.15,45.9) v2(116.15,45.32) v2(116.19,54.37) v2(116.19,53.74) v2(116.49,52.25) v2(116.75,60.6) v2(116.75,58.18) v2(116.75,55.83) v2(116.77,138.07) v2(116.82,49.8) v2(116.82,47.41) v2(116.97,43.9) v2(117.72,119.92) v2(117.85,65.6) v2(117.85,64.95) v2(117.86,128.88) v2(118.32,129.22) v2(118.45,36.28) v2(120.72,0.43) v2(125.18,37.45) v2(125.41,55.17) v2(125.8,0.43) v2(125.94,93.14) v2(126.26,43.6) v2(126.93,138.07) v2(127.08,38.61) v2(128.36,37.36) v2(130.88,0.43) v2(132.01,138.07) v2(132.94,25.06) v2(132.94,24.47) v2(133.56,33.62) v2(134.63,47.73) v2(134.63,47.15) v2(134.79,34.8) v2(135.17,85.31) v2(135.17,84.73) v2(135.17,84.14) v2(135.43,75.09) v2(135.43,74.46) v2(135.96,0.43) v2(136.48,131.47) v2(136.7,73.83) v2(137.06,137.58) v2(137.33,131.47) v2(137.48,73.83) v2(137.82,85.24) v2(137.82,84.65) v2(137.82,84.07) v2(138.64,48.21) v2(138.93,75.09) v2(138.93,74.46) v2(139.02,38.99) v2(139.22,48.21) v2(139.6,38.99) v2(139.79,61.2) v2(139.81,48.21) v2(139.79,6.3) v2(140.19,38.99) v2(140.39,48.21) v2(140.85,63.03) v2(140.85,59.37) v2(140.77,38.99) v2(140.85,8.13) v2(140.85,4.47) v2(140.94,75.14) v2(140.94,74.51) v2(141.04,0.43) v2(141.27,85.24) v2(141.27,84.65) v2(141.27,84.07) v2(141.91,136.07) v2(142,91.84) v2(142,91.26) v2(142,90.68) v2(142,90.09) v2(142,89.51) v2(142,88.92) v2(142,88.34) v2(142,87.76) v2(142.95,63.03) v2(142.95,59.37) v2(142.95,8.13) v2(142.95,4.47) v2(143.17,73.83) v2(143.63,85.26) v2(143.63,84.68) v2(143.63,84.09) v2(143.96,73.83) v2(144.01,61.2) v2(144.01,6.3) v2(144.5,75.02) v2(144.48,74.46) v2(146.12,0.43) v2(146.99,136.07) v2(149.89,55.12) v2(150.13,58.18) v2(150.32,57.55) v2(150.57,42.65) v2(150.69,57) v2(151.23,57.54) v2(151.23,56.46) v2(151.2,0.43) v2(151.73,59.75) v2(151.73,59.12) v2(151.76,58.53) v2(151.77,57.9) v2(151.77,57) v2(152.04,135.44) v2(152.18,75.66) v2(152.18,74.91) v2(152.15,67.94) v2(152.33,58.54) v2(152.31,57.54) v2(152.7,75.92) v2(152.72,75.28) v2(152.66,65.56) v2(152.73,34.95) v2(152.76,68.35) v2(152.76,67.59) v2(152.76,66.95) v2(152.76,66.25) v2(153.22,65.14) v2(153.28,75.59) v2(153.31,74.95) v2(153.27,68.02) v2(153.27,67.26) v2(153.27,66.62) v2(153.27,65.92) v2(153.61,76.07) v2(153.69,64.6) v2(153.88,68.3) v2(153.88,67.54) v2(153.88,66.9) v2(153.88,66.2) v2(154.02,75.61) v2(154.04,74.98) v2(154.01,65.3) v2(154.07,64.1) v2(154.32,78.26) v2(154.32,77.49) v2(154.32,76.86) v2(154.32,76.16) v2(154.39,67.97) v2(154.39,67.21) v2(154.39,66.57) v2(154.39,65.87) v2(154.45,64.6) v2(154.7,75.59) v2(154.65,63.99) v2(154.81,74.98) v2(154.77,65.3) v2(155.02,41.68) v2(155.02,41.04) v2(155.09,78.26) v2(155.09,77.49) v2(155.09,76.86) v2(155.09,76.16) v2(155.15,68.35) v2(155.15,67.59) v2(155.15,66.83) v2(155.15,66.06) v2(155.23,78.87) v2(155.21,64.6) v2(155.34,40.54) v2(155.4,65.17) v2(155.42,63.99) v2(155.47,75.59) v2(155.47,74.95) v2(155.51,69.17) v2(155.61,69.74) v2(155.66,41.68) v2(155.66,41.04) v2(155.85,78.26) v2(155.85,77.49) v2(155.85,76.86) v2(155.85,76.16) v2(155.93,64.64) v2(155.99,78.87) v2(155.97,40.54) v2(156.09,89.96) v2(156.23,75.59) v2(156.23,74.95) v2(156.22,69.74) v2(156.15,69.17) v2(156.18,63.99) v2(156.29,41.68) v2(156.29,41.04) v2(156.28,0.43) v2(156.51,78.64) v2(156.51,77.87) v2(156.51,77.11) v2(156.51,76.35) v2(156.61,40.54) v2(156.7,68.6) v2(156.7,68.01) v2(156.7,67.43) v2(156.93,41.68) v2(156.93,41.04) v2(156.99,74.87) v2(157.1,135.07) v2(157.12,81.16) v2(157.12,80.2) v2(157.12,79.24) v2(157.07,71.5) v2(157.07,70.54) v2(157.07,69.58) v2(157.56,41.68) v2(158.45,90.19) v2(158.54,81.16) v2(158.54,80.2) v2(158.54,79.24) v2(158.49,71.5) v2(158.49,70.54) v2(158.49,69.58) v2(158.85,105.39) v2(159.02,92.03) v2(159.28,93.68) v2(159.28,92.98) v2(159.39,91.4) v2(159.39,90.64) v2(159.39,36.02) v2(159.39,33.88) v2(159.77,95.15) v2(159.77,94.38) v2(159.77,92.1) v2(160.04,91.4) v2(160.04,90.64) v2(160.04,34.95) v2(160.29,95.46) v2(160.36,94.76) v2(160.74,43.71) v2(160.69,36.02) v2(160.69,33.88) v2(161.12,39.29) v2(161.37,43.71) v2(161.36,0.43) v2(161.54,37.62) v2(161.75,39.29) v2(162.01,43.71) v2(162.12,37.62) v2(162.64,43.71) v2(162.73,38.58) v2(162.96,54.64) v2(162.96,53.12) v2(162.96,51.59) v2(163.09,62.25) v2(163.09,61.67) v2(163.09,61.09) v2(163.09,60.5) v2(163.15,98.44) v2(163.32,38.52) v2(164.19,122.18) v2(164.19,121.6) v2(164.19,121.01) v2(164.19,120.43) v2(164.48,54.64) v2(164.48,53.12) v2(164.48,51.59) v2(164.8,122.18) v2(164.8,121.6) v2(164.8,121.01) v2(164.8,120.43) v2(165.12,5.54) v2(166.01,54.64) v2(166.01,53.12) v2(166.01,51.59) v2(166.66,0.44) v2(166.9,5.42) v2(167.14,28.72) v2(167.21,136.07) v2(167.47,62.83) v2(167.47,62.24) v2(167.47,61.66) v2(167.72,28.72) v2(168.31,28.72) v2(168.8,43.01) v2(168.93,26.5) v2(169.62,116.76) v2(169.62,111.68) v2(169.62,106.6) v2(169.62,91.36) v2(169.64,86.28) v2(169.56,26.5) v2(169.75,25.87) v2(169.75,25.23) v2(170.18,81.23) v2(170.72,121.72) v2(171.43,76.31) v2(171.52,0.43) v2(172.29,136.07) v2(172.4,126.52) v2(173.38,71.62) v2(174.08,131.31) v2(175.57,42.6) v2(175.85,27.07) v2(175.85,26.44) v2(175.85,25.8) v2(175.85,25.17) v2(175.97,67.25) v2(176.57,6.1) v2(176.57,1.02) v2(176.99,16.15) v2(177.4,26.76) v2(177.4,26.12) v2(177.63,46.37) v2(177.63,45.79) v2(178.34,42.44) v2(178.26,32.6) v2(179.17,63.3) v2(179.75,45.42) v2(180.21,44.99) v2(180.17,44.41) v2(180.16,43.77) v2(180.18,43.14) v2(180.25,16.02) v2(180.67,44.09) v2(180.67,43.45) v2(180.69,42.82) v2(180.9,32.79) v2(181.03,32.22) v2(181.49,32.79) v2(181.62,32.22) v2(182.07,32.79) v2(182.07,16.02) v2(182.25,36.53) v2(182.25,35.94) v2(182.25,35.36) v2(182.2,32.22) v2(182.82,34.88) v2(182.82,34.29) v2(182.82,33.71) v2(182.77,33.04) v2(182.77,32.45) v2(182.77,31.87) v2(182.9,59.85) v2(186.7,56.48) v2(186.77,43.58) v2(188.93,17.16) v2(189.63,45.36) v2(189.69,43.52) v2(190.9,53.63) v2(192.39,19) v2(193.37,36.93) v2(193.37,34.75) v2(194.47,35.84) v2(195.54,43.71) v2(195.56,36.93) v2(195.56,34.75) v2(198.08,31.71) v2(198.78,44.15) v2(200.6,32.49) v2(200.93,33.58) v2(200.93,32.99) v2(200.97,52.3) v2(201.19,32.49) v2(201.52,33.58) v2(201.52,32.99) v2(201.77,32.49) v2(202.1,33.58) v2(202.1,32.99) v2(202.35,32.49) v2(202.69,32.99) v2(202.94,32.49) v2(203.28,32.02) v2(203.52,32.54) v2(204.49,47.9) v2(204.49,36.09) v2(205.55,49.73) v2(205.55,46.07) v2(206.31,8.73) v2(207.28,35.96) v2(207.65,49.73) v2(207.65,46.07) v2(208.71,47.9) v2(211.39,8.73) v2(211.92,41.87) v2(212.74,41.04) v2(213.57,41.87) v2(213.57,40.22) v2(213.89,20.85) v2(214.52,20.85) v2(216.49,24.15) v2(216.49,23.52) v2(216.49,22.44) v2(216.49,21.8) v2(216.47,8.73) v2(218.01,51.33) v2(218.84,41.55) v2(219.22,39.07) v2(219.22,36.03) v2(219.35,23.9) v2(219.41,37.81) v2(219.6,25.55) v2(219.79,44.28) v2(219.79,42.63) v2(219.79,33.87) v2(219.98,40.59) v2(220.91,55.07) v2(221.55,8.73) v2(224.87,19.71) v2(224.87,19.07) v2(225.44,20.92) v2(225.44,20.28) v2(225.44,19.71) v2(225.44,19.07) v2(225.99,55.07) v2(226.08,20.92) v2(226.08,20.28) v2(226.08,19.71) v2(226.08,19.07) v2(226.63,8.73) v2(229.33,19.97) v2(231.07,55.04) v2(231.47,49.98) v2(231.47,44.9) v2(231.47,39.82) v2(231.47,34.74) v2(231.47,29.66) v2(231.47,24.58) v2(231.47,15.36) v2(231.47,10.28) v3(10.98,49.08) v3(12.5,27.4) v3(44.15,24.21) v3(44.79,17.42) v3(58.63,23.64) v3(64.41,123.21) v3(64.56,120.06) v3(64.66,123.08) v3(71.43,23.55) v3(78.62,101.43) v3(89.15,37.64) v3(105.38,93.53) v3(113.22,33.88) v3(133.94,36.47) v3(134.64,30.05) v3(135.4,48.42) v3(135.59,47.2) v3(150.58,56.03) v3(152.47,60.41) v3(152.93,64.41) v3(154.41,63.33) v3(156.12,79.7) v3(160.99,95.14) v3(165.23,51.21) v3(179.23,41.76) v3(179.6,31.96) v3(198.52,43.64) v3(202.22,34.19) v3(203.35,33.42)
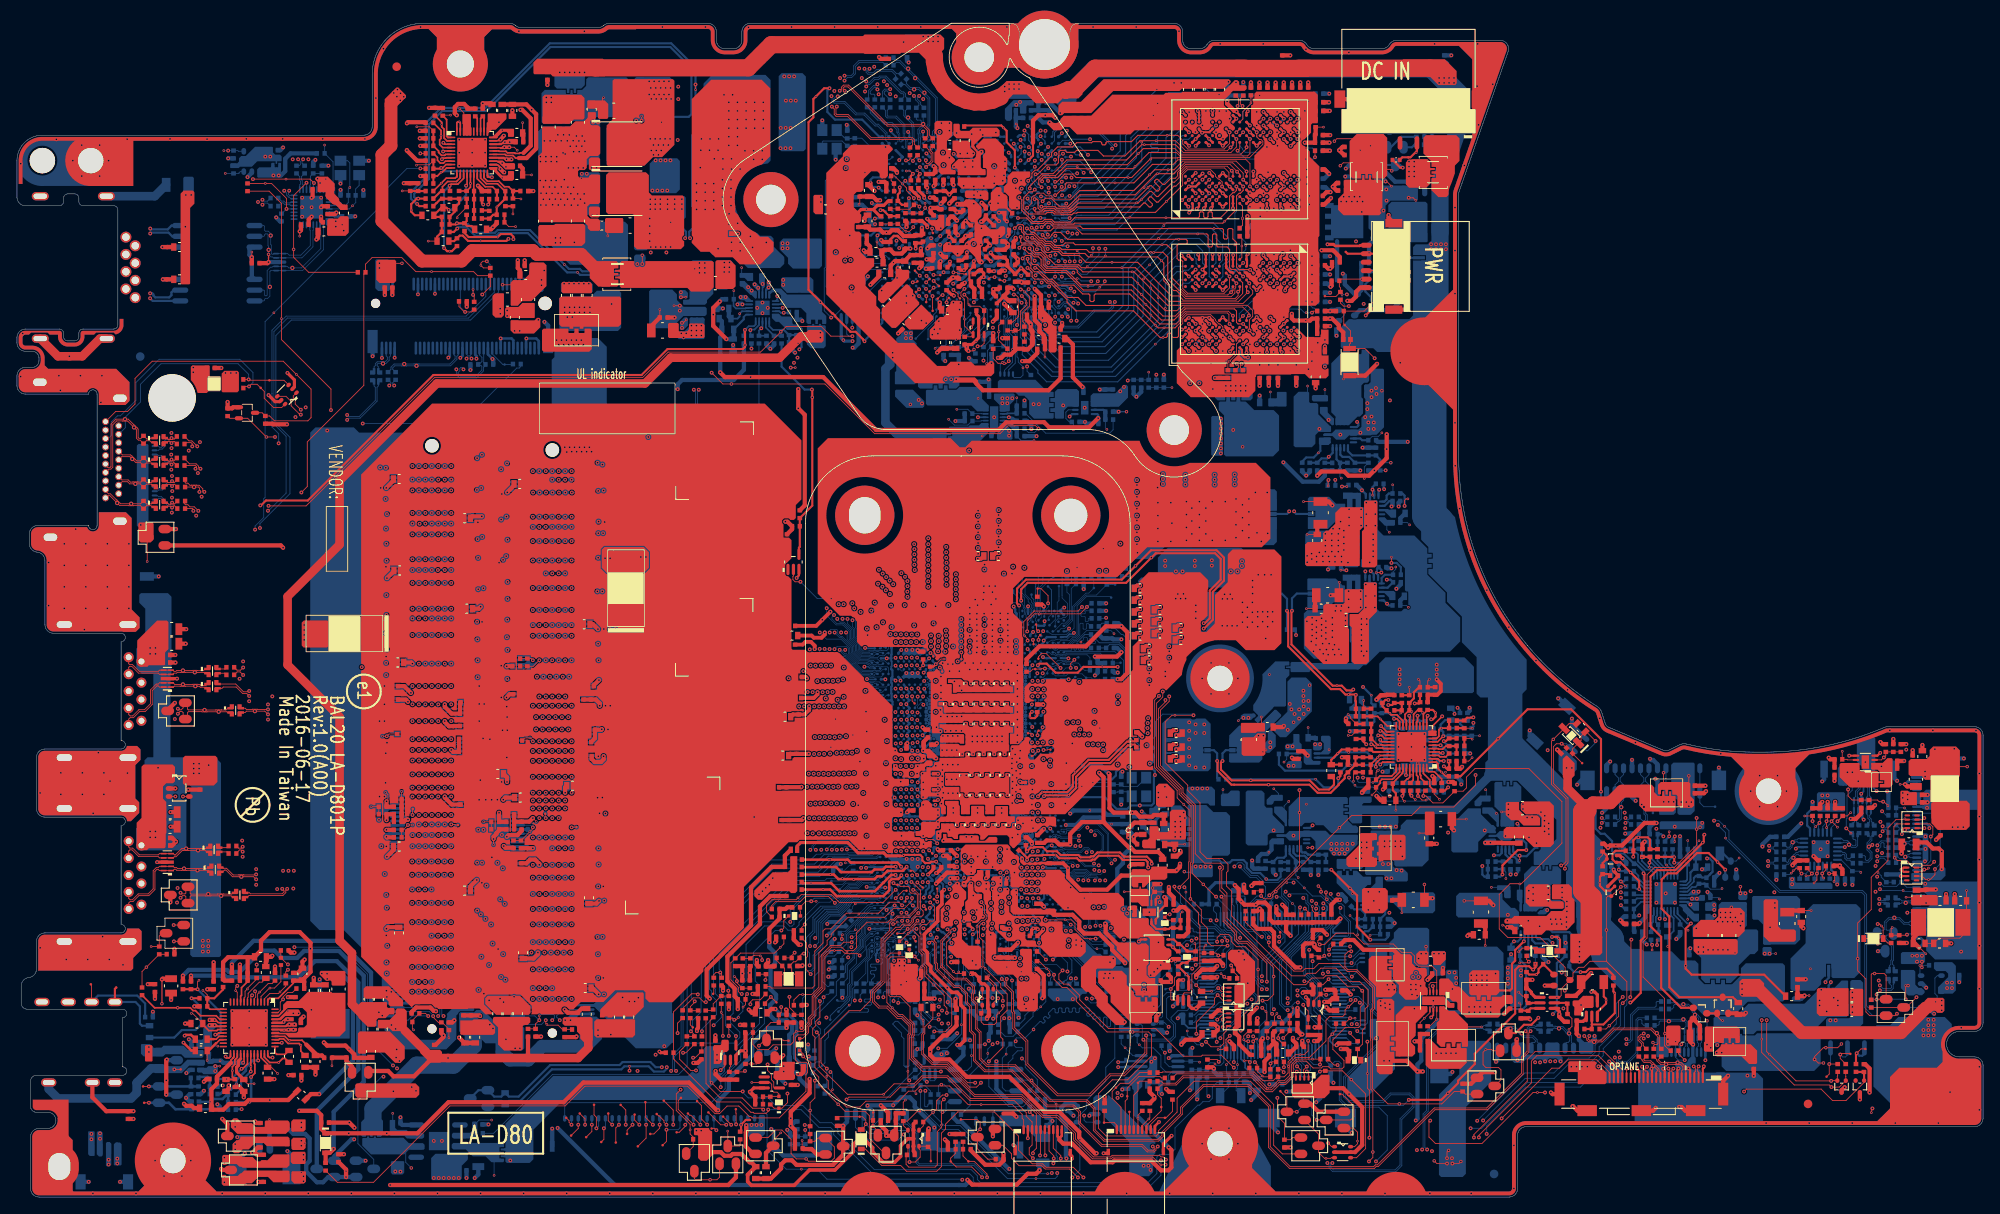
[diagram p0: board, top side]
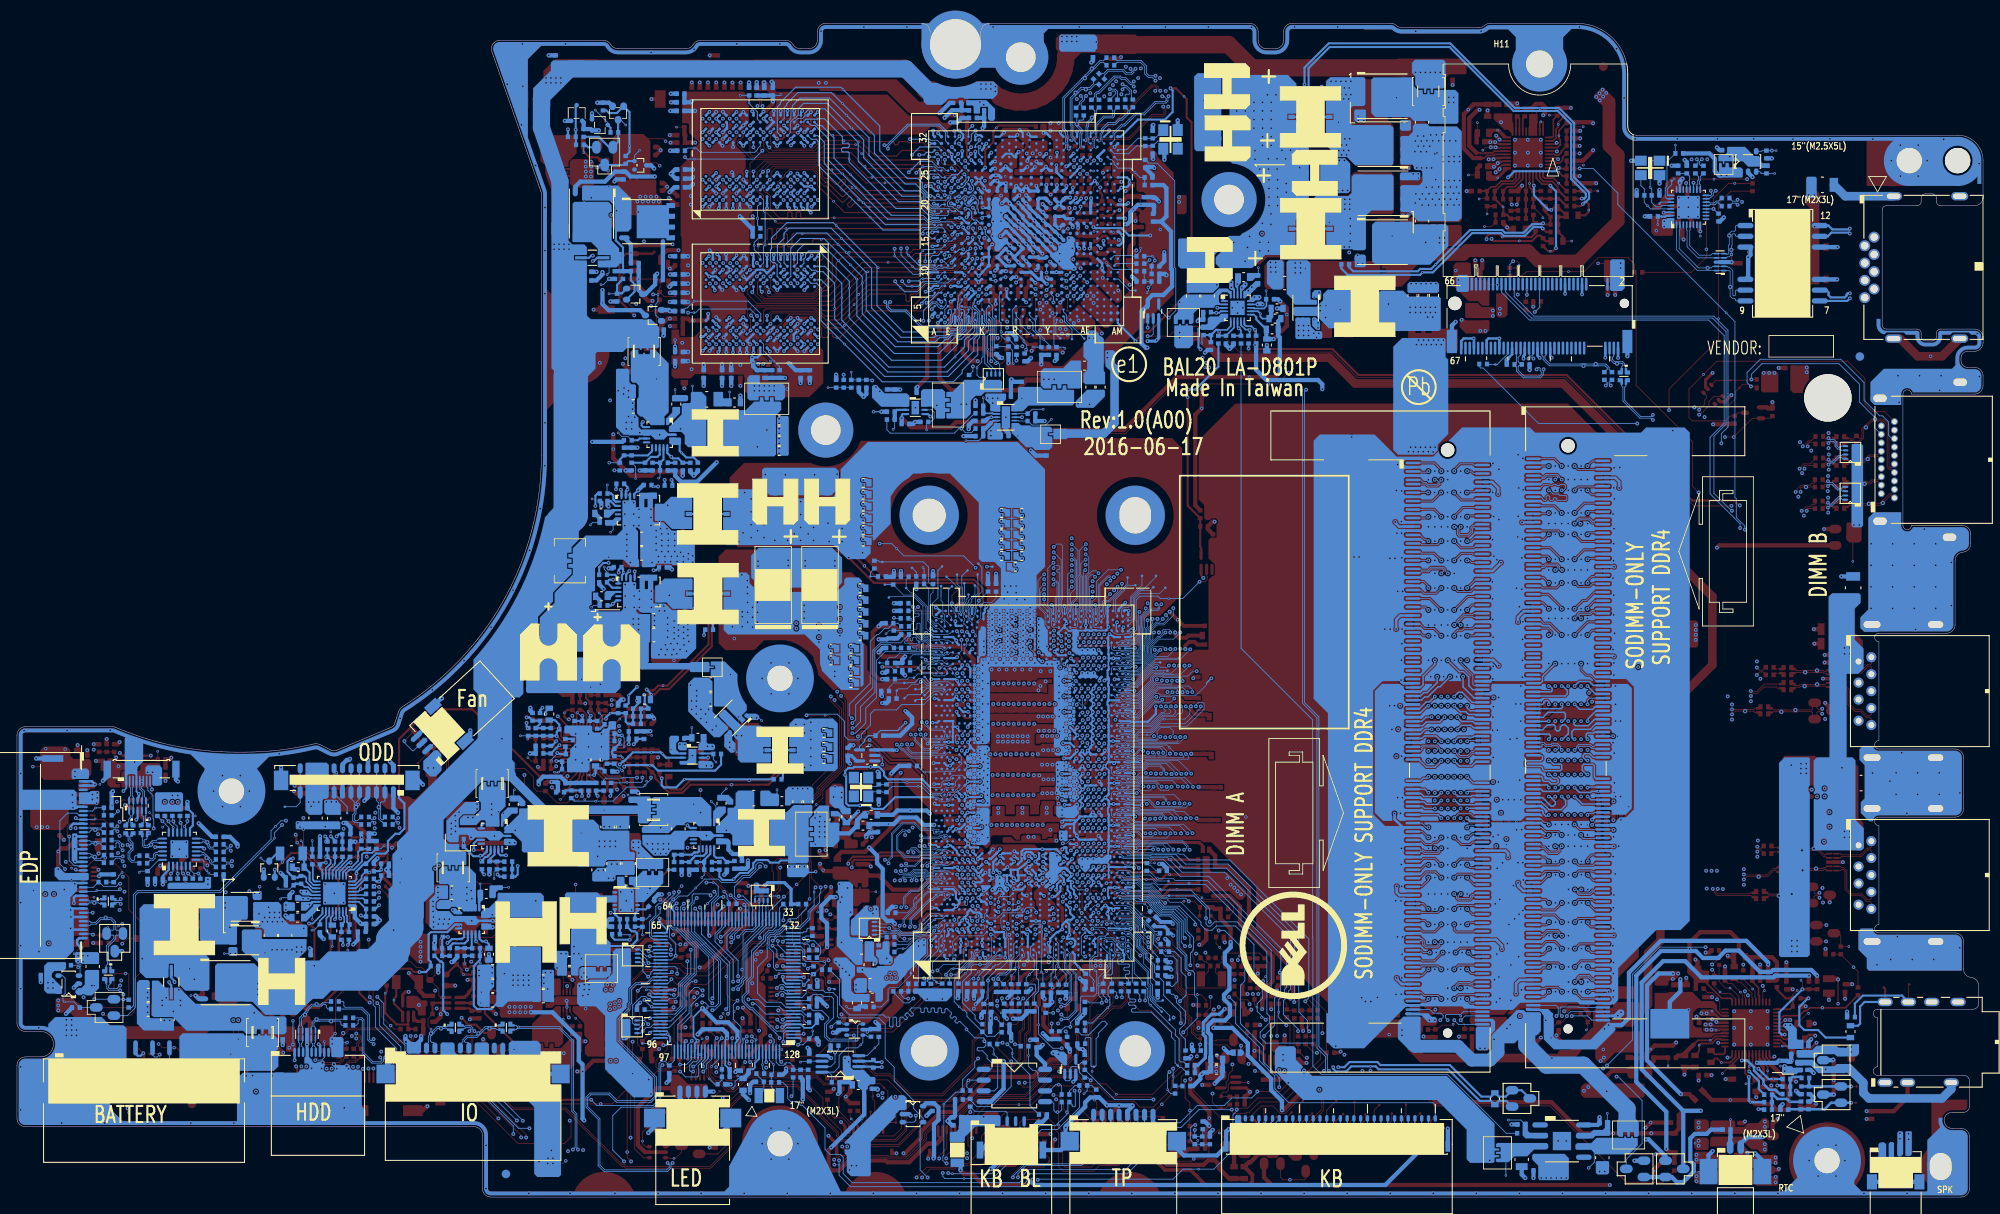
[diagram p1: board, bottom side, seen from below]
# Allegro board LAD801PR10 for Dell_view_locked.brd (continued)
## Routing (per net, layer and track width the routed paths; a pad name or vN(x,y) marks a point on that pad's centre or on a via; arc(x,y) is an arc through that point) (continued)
V3D3_STB: length 10.8
  TOP w0.102: v1(21.47,25.58) 21.3,25.42 v2(21.3,24.52)
  TOP w0.203: UA1.20 23.77,19.36 23.57,19.17 v2(23.39,19.17)
  TOP w0.254: RA11.1 RA12.1 v2(21.3,24.52)
  BOTTOM w0.254: v2(21.3,24.52) 24.02,21.8 24.02,19.42 23.77,19.17 v2(23.39,19.17)
VCC_EDRAM_SENSE: length 1.9
  TOP w0.102: v2(112.36,64.95) 112.36,64.33 TP34.1
  BOTTOM w0.102: UC1.AC63 111.84,64.16 112.36,64.68 v2(112.36,64.95)
VCC_GT_SENSE: length 77.1
  TOP w0.254: v2(118.45,70.37) 118.45,71.72 119.21,72.48 130.82,72.48 v3(133.8,75.46) 134.31,75.96 141.32,75.96 141.98,75.3 141.98,72.85 140.7,71.56 140.7,68.31 140.11,67.71 v2(139.97,67.71) ; v2(168.3,53.8) 168.54,53.8 168.86,54.12 PR622.1 169.8,54.12 PC617.1
  IN1 w0.254: v2(139.97,67.71) 140.99,67.71 146.15,62.56 151.63,62.56 156.19,58 159.75,58 161.85,55.9 164.73,55.9 165.41,55.23 165.41,54.37 165.67,54.11 167.1,54.11 167.41,53.8 v2(168.3,53.8)
  BOTTOM w0.076: UC1.J70 118.81,68.75 118.81,68.92 118.86,69.06 118.86,69.35 118.72,69.49 118.72,69.49 118.69,69.52 118.69,69.82 118.57,69.94 118.57,70.01 118.45,70.14 v2(118.45,70.37) RC155.2
  BOTTOM w0.254: v2(168.3,53.8) 168.36,53.8 168.36,53.68 168.79,53.25 PC620.1 168.94,53.24 PC618.2
VCCEOPIO_SENSE: length 1.1
  TOP w0.102: TP36.1 108.08,63.87 v2(107.75,64.2)
  BOTTOM w0.076: UC1.AL63 107.52,63.96 v2(107.75,64.2)
VCCIO_SENSE: length 3
  TOP w0.102: TP38.1 108.1,42.19 v2(108.54,41.74)
  BOTTOM w0.076: v2(108.54,41.74) 108.1,41.74 107.67,42.17 UC1.AM23
VCCSA_B+:
  vias: v1(147.73,61.65)
VCCSENSE: length 63
  TOP w0.254: PC653.1 PR648.1 163.34,57.44 PC639.1 PC651.2 162.21,58.06 v2(161.75,58.06) ; v2(121.14,47.3) 121.24,47.4 v1(124.04,47.4) 124.92,48.28 124.92,49.59 126.54,51.2 128.94,51.2 131.03,53.3 v2(131.34,53.3) 131.43,53.4 131.86,53.4 132.04,53.22 RC150.2
  IN3 w0.254: v2(131.34,53.3) 131.44,53.41 131.62,53.41 131.87,53.66 131.87,57.17 132.49,57.78 135.97,57.78 136.86,58.68 136.86,59.64 136.81,59.7 136.81,63.5 139.53,66.22 149.18,66.22 157.63,57.76 160.77,57.76 161.19,58.19 161.63,58.19 v2(161.75,58.06)
  BOTTOM w0.254: v2(121.14,47.3) 120.75,46.91 UC1.E32
VCCSENSE_VCCGTUS: length 2.6
  TOP w0.102: v1(109.34,63.49) 108.99,63.49 v2(108.37,62.87)
  TOP w0.254: RC157.2 108.09,62.58 v2(108.37,62.87)
  BOTTOM w0.254: UC1.AK62 108.02,63.23 v2(108.37,62.87)
VCCSENSE_VGA: length 85.9
  TOP w0.102: v2(106.51,120.74) 106.51,120.81 v1(106.19,121.13)
  TOP w0.254: PR1138.2 54.83,117.3 55,117.13 v2(55,117.12) ; v2(106.51,120.74) 106.33,120.56 RV159.2
  IN3 w0.254: v2(55,117.12) 55,117.22 55.38,117.6 55.78,117.6 56.34,117.04 56.34,115.91 57.23,115.02 57.23,108.12 59.71,105.64 59.71,104.49 61.42,102.78 67.55,102.78 68.81,101.53 73.53,101.53 76.06,98.99 89.77,98.99 91.24,100.46 91.24,105 93.69,107.46 94.33,107.46 95.66,107.46 96.79,108.59 96.79,111.02 97.3,111.53 97.3,114.21 97.94,114.84 97.94,120.01 100.25,122.32 103.01,122.32 103.65,121.68 105.56,121.68 v2(106.51,120.74)
VCCST_PWRGD: length 9.4
  BOTTOM w0.076: RC96.2 126.41,68.29 126.36,68.24 126.36,67.98 126.28,67.9 126.08,67.9 126,67.98 126,68.44 125.93,68.52 125.57,68.52 125.5,68.6 125.5,68.75 125.57,68.82 125.93,68.82 126,68.9 126,69.08 125.91,69.17 125.28,69.17 125.2,69.09 125.2,66.35 124.86,66 124.5,66 124.15,65.66 123.11,65.66 122.85,65.4 UC1.B65
VCCSTG_EN: length 5.1
  TOP w0.254: RZ3.1 138.43,28.07 DZ2.1 137.45,27.64 137.37,27.57 137.34,27.57 RZ2.2 v1(137.96,26.25) 138.21,25.99 UC9.4
VCCSTG_EN_R: length 4.8
  TOP w0.102: v1(138.93,29.91) 139.02,29.82 RZ3.2
  TOP w0.254: UZ2.4 136.44,30.4 CZ7.1 137.19,29.86 DZ2.2 138.06,28.99 RZ3.2
VDD_1.2V: length 11
  TOP w0.508: v2(83.67,101.24) 82.13,102.79 v3(82.13,104.13) 82.13,104.92 v2(82.89,105.68)
  BOTTOM w0.203: PU200.11 85.99,104.12 85.72,103.85
  BOTTOM w0.254: 85.72,103.85 85.72,103.57 PR206.2
  BOTTOM w0.508: PR206.2 84.54,101.31 PC209.1 v2(83.67,101.24) ; v2(82.89,105.68) 83.15,105.94 PR205.1
VDD_CHG: length 29.2
  TOP w0.254: v2(190.65,40.16) 190.66,40.17 PR781.1 190.66,42.11 190.99,42.44 v3(191.24,42.44) 192.36,42.44 192.61,42.19 PR750.2 PR749.2
  IN2 w0.254: v2(199.35,39.96) 197.26,39.96 196.61,40.6 193.02,40.6 192.57,40.16 v2(190.65,40.16) 190.65,38.36 189.88,37.6 189.88,35.14 v2(189.19,34.44)
  BOTTOM w0.203: PU703.19 197,36.44 197.78,37.22 197.78,37.64
  BOTTOM w0.254: 197.78,37.64 198.02,37.88 PR760.1 198.58,37.88 198.76,37.7 199.27,37.7 ; 199.27,37.7 199.32,37.7 199.68,38.06 199.68,38.06 199.82,38.21 199.83,38.21 199.99,38.38 199.99,39.61 199.64,39.96 v2(199.35,39.96) ; 199.27,37.7 PC768.2 ; v2(189.19,34.44) 189.63,34 PR741.1
VDDIO_VGA: length 6.6
  TOP w0.102: v1(47.16,126.29) 48.64,126.29 PR1113.2
  TOP w0.203: PU1100.6 50.57,123.04 50.45,122.92 50.07,122.92 49.74,123.26 49.74,123.42 PR1115.2
  TOP w0.254: PR1113.2 PC1226.1 PR1115.2
VDDP_CHG: length 5.3
  BOTTOM w0.102: PC769.2 199.28,36.79 199.73,36.33 201.04,36.33 v1(201.11,36.4)
  BOTTOM w0.203: PR760.2 198.37,36.97 197.98,36.58 197.57,36.58 197.03,36.04 PU703.20
  BOTTOM w0.254: PC769.2 199.08,36.98 199.01,36.98 198.88,36.97 PR760.2
VDDR4: length 2.1
  BOTTOM w0.381: UV1.U12 UV1.V12 111.33,110.79 110.59,110.79 UV1.Y12
VSS_EDRAM_SENSE: length 1.4
  TOP w0.102: v2(111.39,64.27) 111.4,64.26 TP35.1
  BOTTOM w0.102: UC1.AE63 111.08,63.96 v2(111.39,64.27)
VSS_GT_SENSE: length 80.6
  TOP w0.203: v2(167.91,53.32) 167.91,53.29 167.89,53.32 PU602.6
  TOP w0.254: v2(139.97,67.08) 140.02,67.08 141.05,68.11 141.05,71.42 142.36,72.73 142.36,75.46 141.5,76.32 133.78,76.32 v3(131.93,74.48) 130.32,72.86 119.02,72.86 117.95,71.79 117.95,70.05 v2(118.2,69.8)
  IN1 w0.254: v2(167.91,53.32) 167.81,53.42 167.25,53.42 166.94,53.73 165.52,53.73 165.03,54.21 165.03,54.53 165.03,55.07 164.58,55.52 161.69,55.52 159.59,57.62 155.83,57.62 151.32,62.13 145.69,62.13 140.73,67.08 v2(139.97,67.08)
  BOTTOM w0.076: UC1.J69 118.59,67.95 118.26,68.29 118.26,68.91 118.2,68.96 v2(118.2,69.8) 118.2,69.86 117.94,70.13 116.99,70.13 116.41,70.7 RC156.1
  BOTTOM w0.254: v2(167.91,53.32) 167.91,53.29 167.97,53.29 PC620.2 169.79,52.34 PC619.2
VSS_MECH: length 82.3
  TOP w0.254: v2(95.84,130.83) 95.21,130.83 v1(94.24,129.87) 93.94,129.56 93.94,127.4 93.36,126.83 93.36,107.06 96.16,104.26 96.23,104.26 96.51,103.98 96.51,103.91 98.29,102.13 98.3,102.13 98.32,102.1 98.91,102.1 99.78,101.24 99.78,101.18 v2(99.97,100.98)
  IN2 w0.254: v2(95.84,130.83) 96.09,131.09 98.51,131.09 100.51,129.08 115.25,129.08 115.53,128.8 115.53,127.99 115.92,127.6 119.53,127.6 120.8,128.87 123.15,128.87 123.83,128.18 v2(123.83,125.83)
  BOTTOM w0.254: v2(95.84,130.83) 95.59,130.58 95.59,128.04 96.49,127.14 99.68,127.14 101.7,125.12 UV1.AM32 ; UV1.AM1 102.06,103.14 99.97,101.05 v2(99.97,100.98) ; UV1.A32 123.83,125.29 v2(123.83,125.83)
VSSEOPIO_SENSE: length 1.7
  TOP w0.102: TP37.1 109.13,62.22 v2(108.86,62.48)
  BOTTOM w0.076: v2(108.86,62.48) 108.74,62.6 108.74,63.39 UC1.AJ62
VSSIO_SENSE: length 1.1
  TOP w0.102: TP39.1 v2(107.59,40.91)
  BOTTOM w0.076: v2(107.59,40.91) 107.25,41.25 UC1.AM22
VSSSENSE: length 65
  TOP w0.203: PU602.18 163.48,56.18 162.77,56.9 162.08,56.9 PC653.2
  TOP w0.254: v2(161.75,58.66) 161.41,58.66 PC654.2 161.05,57.92 PC653.2 ; RC151.1 131.89,53.78 131.5,53.78 v2(131.34,53.94) 131.15,53.74 130.94,53.74 128.78,51.59 126.38,51.59 124.54,49.74 124.54,48.44 123.88,47.78 v1(120.92,47.78) v2(120.43,47.29)
  IN3 w0.254: v2(161.75,58.66) 161.66,58.57 161.07,58.57 160.62,58.12 157.77,58.12 149.3,66.6 139.37,66.6 136.43,63.66 136.43,59.54 136.48,59.48 136.48,58.84 135.81,58.16 132.16,58.16 131.47,57.48 131.47,54.07 v2(131.34,53.94)
  BOTTOM w0.254: UC1.E33 120.43,47.33 v2(120.43,47.29)
VSSSENSE_VCCGTUS: length 2.1
  TOP w0.102: v1(106.49,62.35) v2(106.88,62.74)
  TOP w0.254: v2(106.88,62.74) 106.89,62.75 RC158.1
  BOTTOM w0.254: v2(106.88,62.74) UC1.AL61
VSSSENSE_VGA: length 84.4
  TOP w0.102: v1(104.9,121.07) 105.35,121.07 v2(105.68,120.74)
  TOP w0.254: v2(105.68,120.74) 105.43,120.48 RV158.2 ; PR1139.2 55.7,117.23 v2(55.58,117.12)
  IN3 w0.254: v2(55.58,117.12) 55.96,116.74 55.96,115.75 56.85,114.86 56.85,107.96 59.33,105.48 59.33,104.33 61.26,102.4 67.4,102.4 68.65,101.15 73.37,101.15 75.9,98.61 89.93,98.61 91.62,100.31 91.62,104.85 93.85,107.07 95.82,107.07 97.18,108.43 97.18,110.87 97.68,111.37 97.68,114.05 98.32,114.68 98.32,119.85 100.41,121.94 102.89,121.94 103.51,121.32 105.1,121.32 v2(105.68,120.74)
3D_CAM_EN: length 208.7
  TOP w0.102: UX1.3 219.91,51.58 v2(220.2,51.88) 220.24,51.88 220.43,52.07 RX3.1 RX2.2 RX1.2 ; v2(159.52,7) 159.52,12.61 159.28,12.84 v1(159.28,14.57) v2(159.28,18.34) ; DX2.2 103.05,28.79 102.61,28.34 102.61,22.95 104.02,21.54 104.45,21.54 105.62,20.37 105.62,19.13 105.5,19 105.5,16.46 106.73,15.23 109.55,15.23 112.93,11.85 118.5,11.85 120.94,9.41 122.64,9.41 124.64,7.41 124.64,6.93 124.64,6.74 126.86,4.51 129.06,4.51 129.26,4.71 133.98,4.71 134.88,3.81 135.46,3.81 v2(135.48,3.83)
  IN1 w0.119: v2(159.28,18.34) 159.11,18.51 159.11,23.23 158.25,24.09 158.25,24.97 158.49,25.21 158.49,25.72 158.49,25.92 157.54,26.87 156.5,26.87 v2(154.77,28.6) ; v2(135.48,3.83) 136.8,2.51 149.58,2.51 154.07,7 v2(159.52,7) 160.5,6.02 173.57,6.02 177.08,9.53 213.91,9.53 218.96,14.57 218.96,16.67 221.06,18.77 221.06,50.51 220.2,51.37 v2(220.2,51.88)
  BOTTOM w0.102: UE1.71 154.95,28.78 v2(154.77,28.6)
3D_CAM_EN_PCH: length 4
  TOP w0.102: DX2.1 104.19,30.19 v1(105.11,31.11) 105.45,31.44 105.45,31.84 v2(106.22,32.61)
  BOTTOM w0.076: UC1.AN7 106.56,32.27 v2(106.22,32.61)
+BIF_VDDC: length 1.5
  BOTTOM w0.381: v2(113.66,118.19) 113.8,118.19 114.26,117.74 UV1.R21 ; v2(112.88,118.23) 112.46,117.81 UV1.U21
  vias: v1(113.29,118.62) v2(111.25,123.11) v2(112.09,123.17) v2(112.8,123.14)
+DCBAT_CAM: length 4.9
  TOP w0.102: v2(222.7,48.7) v1(222.12,48.7)
  TOP w0.508: R51.1 222.95,48.45 v2(222.7,48.7)
  BOTTOM w0.305: JEDP1.3 224.07,49.05 223.05,49.05 v2(222.7,48.7) 222.85,48.55 224.07,48.55 JEDP1.4
+DCBAT_LCD: length 2.6
  TOP w0.102: F1.2 v3(230.03,50.79)
  vias: v2(225.06,50.22) v2(225.06,49.62) v3(226.22,52.85) v3(228.51,52.9)
+DP_VDDC: length 6.6
  TOP w0.508: RV30.1 103.05,109.92 v1(103.39,110.26) 103.56,110.43 CV30.1 104.71,110.47 105.39,111.15 CV34.1 CV33.1 106.61,111.22 v2(106.61,111.94)
  BOTTOM w0.305: UV1.AD14 106.86,112.19 v2(106.61,111.94)
+DP_VDDR: length 7.4
  TOP w0.102: v1(101.44,112.71) 101.44,112.08 CV27.1
  TOP w0.508: v2(105.38,111.92) 104.77,111.92 CV35.1 104.71,111.69 104.35,111.33 103.45,111.33 CV26.1 102.29,111.78 CV27.1 102.02,111.01 102.16,110.87 RV27.1
  BOTTOM w0.305: UV1.AF14 105.26,112.04 v2(105.38,111.92)
+FB0_VREFCL: length 6.6
  TOP w0.254: v2(143.84,128.08) 143.84,128.04 144.23,127.65 UV12.J14
  TOP w0.508: v2(143.84,128.08) 143.75,128.17 143.59,128.17 142.74,129.02 v2(142.74,129.28)
  BOTTOM w0.102: v1(141.79,130.1) 141.91,129.98 RV55.1
  BOTTOM w0.254: v2(143.84,128.08) 143.84,128.04 144.23,127.65 UV12.J14
  BOTTOM w0.508: CV395.1 RV54.2 RV55.1 v2(142.74,129.28)
+FB0_VREFDL: length 21.6
  TOP w0.102: RV52.2 v1(154.11,126.25)
  TOP w0.254: UV12.U10 150.63,124.44 v2(150.23,124.05) ; v2(138.26,124.05) 137.86,124.45 UV12.A10
  TOP w0.508: RV52.2 153.18,125.39 CV394.1 RV53.1 v2(151.9,124.42)
  IN2 w0.508: v2(151.9,124.42) 151.52,124.05 v2(150.23,124.05) 150.23,123.69 149.31,122.77 139.08,122.77 138.26,123.6 v2(138.26,124.05)
  BOTTOM w0.254: UV12.U10 150.63,124.44 v2(150.23,124.05) ; UV12.A10 137.86,124.45 v2(138.26,124.05)
+FB1_VREFCL: length 7.2
  TOP w0.254: UV14.J14 144.48,99.97 144.48,99.4 144.8,99.08 v2(145.19,99.08)
  BOTTOM w0.254: v2(145.19,99.08) 144.55,99.08 144.23,99.4 UV14.J14
  BOTTOM w0.508: RV51.1 CV391.1 RV50.2 145.07,98.03 v1(145.07,98.47) 145.19,98.6 v2(145.19,99.08)
+FB1_VREFDL: length 20.1
  TOP w0.254: v2(138.23,103.73) 138.09,103.73 137.83,103.47 UV14.U10
  TOP w0.508: RV48.2 CV390.1 RV49.1 152.75,103.66 152.52,103.43 v1(152.01,103.43) UV14.A10 150.37,103.68 v2(150.37,104.22)
  IN1 w0.508: v2(150.37,104.22) 150.05,104.22 149.66,104.61 139.1,104.61 v2(138.23,103.73)
  BOTTOM w0.254: UV14.U10 138.13,103.73 v2(138.23,103.73) ; v2(150.37,104.22) 150.37,103.68 150.63,103.43 UV14.A10
+LAN_VDD10: length 9.4
  TOP w0.102: v2(33.35,113.95) v1(33.35,113.39)
  TOP w0.508: v2(37.67,116.17) 37.5,115.99 CL6.1 ; CL5.1 33.5,114.09 v2(33.35,113.95)
  IN2 w0.508: v2(37.67,116.17) 37.28,116.17 35.06,113.95 v2(33.35,113.95)
  BOTTOM w0.203: UL1.8 v2(33.35,113.95) ; v2(37.67,116.17) 37.64,116.2 UL1.30
+LAN_VDD33: length 6.4
  BOTTOM w0.508: v2(30.88,120.55) 31.13,120.55 31.64,121.05 31.64,122.52 32.28,123.15 RL1.1
  vias: v2(30.24,120.55) v2(37.61,115.15) v2(37.61,114.51) v3(38.54,114.04)
+LAN_VDDREG: length 3
  TOP w0.635: 37.52,117.59 38.31,116.79 RL5.2
  TOP w1.016: 36.9,118.97 36.9,118.21 37.52,117.59
  vias: v1(36.43,120.11) v2(35.45,120.16) v2(35.75,119.66)
+LCDVDD:
  vias: v3(223.06,24.95)
+LCDVDD_LCD: length 48.4
  TOP w0.127: v2(224.11,28.47) v3(223.55,28.47) ; v2(224.69,27.77) v3(224.69,27.09)
  IN1 w1.016: 223.03,28.54 222.01,29.55 222.01,35.46 223.35,36.79 223.35,44.66 223.07,44.94 223.07,45.97
  IN3 w1.016: 224.18,47.96 224.64,47.96 225,48.32 226.86,48.32 227.22,47.96 227.22,40.72 230.22,37.72 230.22,28.66 229.21,27.64 225.95,27.64
  vias: v2(222.43,47.69) v2(222.43,47.1) v2(223.01,47.5) v2(223.01,46.91) v2(224.11,27.77) v2(224.69,28.47) v3(222.5,46.49)
+LINE1_VREFO_L: length 5.6
  TOP w0.203: UA1.31 v1(27.59,15.41) 27.59,14.82 v2(27.58,14.81)
  BOTTOM w0.254: RA29.1 25.81,12.11 26.44,12.73 26.44,13.67 v2(27.58,14.81)
+LINE1_VREFO_R: length 5.5
  TOP w0.203: v2(26.49,15.13) 26.61,15.13 27.19,15.71 UA1.30
  BOTTOM w0.254: v2(26.49,15.13) 25.29,13.92 v1(24.72,13.92) RA33.1
+MIC2-VREFO: length 6.2
  TOP w0.203: v2(26.67,15.84) 26.78,15.95 26.78,16.91 UA1.29
  BOTTOM w0.508: RA26.1 22.63,16.1 RA25.1 23.03,15.98 23.13,16.08 v1(23.96,16.08) 24.09,16.08 24.33,15.84 v2(26.67,15.84)
+MPLL_PVDD: length 5.1
  TOP w0.381: LV6.2 115.58,105.46 116.39,106.27 CV82.1
  TOP w0.508: CV81.1 116.96,105.76 116.42,106.3 CV82.1 116.83,106.75 CV124.1 117.4,107.29 v2(117.55,107.14)
  BOTTOM w0.381: UV1.L8 117.17,107.52 v2(117.55,107.14)
+MVREFDA: length 8.9
  TOP w0.102: v1(117.87,126.63) 118,126.5 v2(118,126.13)
  IN1 w0.508: v2(118,126.13) 116.99,125.12 116.99,124.05 117.21,123.82 117.22,123.82 118.36,122.68 v2(118.36,122.32)
  BOTTOM w0.254: UV1.K26 118.06,122.02 v2(118.36,122.32)
  BOTTOM w0.508: CV94.1 117.82,126.31 v2(118,126.13) ; CV94.1 RV33.2 ; CV94.1 RV34.1
+MVREFSA: length 12.7
  TOP w0.254: v2(119.33,122.37) 119.84,122.88 119.84,124.41
  TOP w0.508: v2(122.48,127.37) 122.19,127.65 v3(121.28,127.65) 120.48,127.65 119.84,127.02 119.84,124.41
  BOTTOM w0.254: v2(119.33,122.37) 119.31,122.37 UV1.J26
  BOTTOM w0.508: v2(122.48,127.37) 121.6,128.24 RV32.2 ; CV95.1 119.61,128.24 RV32.2 ; RV35.1 120.48,129.04 RV32.2
+PCIE_VDDC: length 11.3
  BOTTOM w0.381: v2(116.54,122.2) 116.78,122.2 UV1.L26 ; UV1.L23 116.66,119.92 v2(116.28,119.92) 116.26,119.92 UV1.N23 ; v2(111.66,119.32) UV1.V22 UV1.U22 v2(112.86,119.25) 113.26,118.85 UV1.T22 113.46,118.72 v2(114.04,119.3) UV1.R22 ; v2(116.54,121.37) 116.81,121.37 UV1.L25 ; UV1.N24 116.1,120.56 v2(116.42,120.56) 116.82,120.56 UV1.L24 ; UV1.N22 v2(115.26,119.62) 115.76,119.62 UV1.N23 ; UV1.N23 116.26,119.12 UV1.M22
  vias: v1(115.32,120.45) v2(104.86,101.94) v2(104.86,101.35) v2(105.44,101.94) v2(105.44,101.35)
+RTC_CELL: length 306.8
  TOP w0.508: RE30.2 143.54,17.85 v2(143.01,18.38) ; RC77.2 91.64,20.6 RC78.2 v2(90.77,19.96) ; RA12.2 v2(20.53,26.12) ; v2(33.29,10.18) 35.38,10.18 35.88,9.67 C1.1 35.88,8.04 D2.1 v2(39.14,7.52) v3(43.62,7.52) 47.23,7.52 50.89,11.19 64.48,11.19 66.81,13.51 79.26,13.51 82.52,10.25 v2(82.7,10.25) ; CC70.1 CC71.1 88.87,35.52 87.64,34.28 87.64,32.21 83.8,28.38 83.8,25.45 84.65,24.6 84.65,23.7 RC91.2 v2(85.02,22.19)
  IN1 w0.508: v2(85.02,22.19) 85.8,21.41 86.69,21.41 87.33,22.05 87.33,23.33 88.89,24.88 88.89,27.08 92.24,30.43 92.8,30.43 95.34,32.97 96.6,32.97 v2(100.22,36.59)
  IN2 w0.508: v2(145.56,11.45) 145.56,11.12 145.14,10.69 140.35,10.69 139.51,11.53 v2(139.2,11.53) 139.03,11.53 135.74,8.25 133.71,8.25 126.89,1.42 62.2,1.42 58.7,4.93 46.48,4.93 45.51,5.9 39.66,5.9 39.14,6.43 v2(39.14,7.52)
  IN3 w0.254: v2(107.45,39.91) 106.99,39.91 106.5,39.43 105.86,39.43 105.85,39.44 104.89,39.44 104.88,39.44 103.35,39.44 100.91,37.01 100.63,37.01 v2(100.22,36.59)
  IN3 w0.508: v2(85.02,22.19) 85.07,22.19 87.36,19.9 90.71,19.9 v2(90.77,19.96) ; v2(143.01,18.38) 142.92,18.28 142.92,15.79 140.45,13.32 140.45,12.78 v2(139.2,11.53)
  BOTTOM w0.254: UC1.BB14 101.15,36.54 101.06,36.54 101.03,36.55 100.27,36.55 100.22,36.6 v2(100.22,36.59) ; UC1.AK19 107.98,39.32 107.45,39.84 v2(107.45,39.91)
  BOTTOM w0.508: v2(139.2,11.53) 139.2,11.58 139.21,11.59 139.21,13.67 139.24,13.7 139.24,13.88 RE41.1 ; 35.36,10.18 40.26,15.08 40.26,25.31 37.74,27.84 35.13,27.84 33.23,25.93 24.72,25.93 24.52,26.12 v2(20.53,26.12) ; 35.36,10.18 D1.1 ; 35.36,10.18 v2(33.29,10.18) ; v2(82.7,10.25) 82.7,11.35 83.97,12.62 83.97,13.97 86.72,16.72 86.72,18.14 88.54,19.96 v2(90.77,19.96) ; RE7.2 146.26,12.15 v2(145.56,11.45)
+RTC_CELL_VBAT: length 6.2
  BOTTOM w0.102: v1(147.47,12.82) 147.21,13.09 147.21,13.61 146.83,13.99 RE7.1
  BOTTOM w0.203: CE14.1 145.45,15.07 145.07,15.07 144.86,15.28 144.86,15.81 144.36,16.31 UE1.122
  BOTTOM w0.508: CE14.1 145.61,14.57 146.12,14.06 146.2,14.06 RE7.1
+RTC_VCC: length 3.3
  BOTTOM w0.102: v1(29.79,9.14) R1.2
  BOTTOM w0.508: R1.2 29.79,7.09 29.83,7.04 JRTC1.1
+SPLL_PVDD: length 8.3
  TOP w0.102: LV7.2 v1(121.25,99.12)
  TOP w0.508: v2(120.03,106.29) 120.03,104.75 120.05,104.73 CV86.1 120.05,103.47 120.62,102.9 CV85.1 120.62,102.16 121.12,101.66 121.12,101.16 CV84.1 121.25,101.03 LV7.2
  BOTTOM w0.381: v2(120.03,106.29) 119.66,106.66 UV1.H7
+SPLL_VDDC: length 3.1
  TOP w0.508: v2(120.05,107.16) 120.79,106.43 CV93.1
  BOTTOM w0.305: UV1.H8 120.01,107.16 v2(120.05,107.16)
  vias: v3(120.96,103.73)
+TP_VDD: length 43.1
  TOP w0.102: R47.1 104.54,11.19 v1(104.8,11.45)
  TOP w0.508: R39.1 101.89,8.46 102.54,7.8 v2(102.54,7.23) 103.42,7.23 Q9.2 103.66,7.48 R40.1 C19.1 104.52,9.89 R47.1 ; R32.1 R31.1 v2(110,7.44) ; R46.1 107.46,7.82 107.54,7.89 107.54,8.04 107.53,8.05 v2(107.53,8.1) ; R36.2 R37.2 88.93,2.18 90.13,3.38 90.13,3.84 ZT59.1 91.41,4.34 91.95,3.8 96.25,3.8 97.45,4.99 Q12.1 97.45,8.38 v2(97.43,8.4) R41.1
  IN2 w0.508: v2(110,7.44) 108.04,7.44 107.53,7.94 v2(107.53,8.1) 103.4,8.1 v2(102.54,7.23) 98.03,7.23 97.43,7.83 v2(97.43,8.4)
  BOTTOM w0.508: v2(97.43,8.4) 97.9,8.88 JTP1.8
+TPAN_VDD: length 6.6
  TOP w0.102: v1(225.15,28.71) 224.44,29.42 v2(224.36,29.42)
  TOP w0.508: v2(224.36,29.42) 223.86,29.93 R13.2 223.67,30.57 224.29,31.19 F2.2
  BOTTOM w0.305: v2(224.36,29.42) 224.79,29.85 224.79,30.34 224.57,30.55 224.08,30.55 JEDP1.40
+TPAN_VDD_F: length 10.3
  TOP w0.102: v1(229.95,36.16) R11.2 229.95,32.84 F2.1 229.52,30.9 229.18,30.55 226.7,30.55 R12.2 R13.1
+TSVDD: length 9.8
  TOP w0.508: v2(106.74,114.37) 106.74,113.79 CV20.1 106.69,113.49 CV21.1 105.89,113.4 104.58,113.4 103.9,114.09 103.18,114.09 102.91,113.81 v1(102.56,113.81) 102.15,113.81 101.81,114.16 100.63,114.16 CV19.1 99.25,114.47 LV2.2
  BOTTOM w0.381: v2(106.74,114.37) 106.74,114.8 UV1.AD17
+V_DDR_REFA: length 6.7
  TOP w0.102: v2(60.85,44.71) v1(61.25,44.31)
  TOP w0.508: RD12.1 58.64,45.15 RD10.2 ; RD12.1 59.51,44.28 CD28.1 60.43,44.3 v2(60.85,44.71) ; RD12.1 RD9.2
  BOTTOM w0.305: v2(60.85,44.71) 60.51,44.38 JDIMM1.164
+V_DDR_REFA_R: length 154
  TOP w0.127: v2(56.22,42.25) v1(56.22,41.57)
  TOP w0.508: v2(56.22,42.25) 56.22,42.51 56.56,42.85 56.56,42.95 56.86,43.25 CD30.1 RD9.1
  IN1 w0.381: 90.95,90.83 92.09,90.83 94.69,88.23 103.39,88.23 110.19,81.44 110.19,72.22 110.18,72.22 110.18,71.84 109.8,71.46 107.36,71.46 104.67,68.77 103.09,68.77 v2(102.15,67.82)
  IN1 w0.508: v2(56.22,42.25) 56.22,44.09 54.5,45.81 47.14,45.81 45.1,47.84 45.1,49.62 39.45,55.27 39.45,84.2 46.08,90.83 90.95,90.83
  BOTTOM w0.152: UC1.AY67 102.22,66.83 102.22,67.75 v2(102.15,67.82)
+V_DDR_REFB: length 5.9
  TOP w0.102: RD20.2 v1(45.37,47.87)
  TOP w0.508: v2(46.12,44.54) 46.06,44.54 46.03,44.51 45.87,44.51 45.64,44.28 CD58.1 RD21.1 RD19.2 RD20.2
  BOTTOM w0.305: v2(46.12,44.54) 45.78,44.87 JDIMM2.164
+V_DDR_REFB_R: length 145.7
  TOP w0.102: v2(43.59,46.7) 43.62,46.7 43.75,46.83 43.75,47.49 v1(43.49,47.75)
  TOP w0.508: RD19.1 CD59.1 v2(43.59,46.7)
  IN1 w0.381: 92.41,91.46 95.14,88.74 103.6,88.74 110.69,81.65 110.69,74.31 111.29,73.71 111.29,70.08 110.19,68.98 105.6,68.98 104.87,68.26 103.38,68.26 102.36,67.24 v2(101.39,67.24)
  IN1 w0.508: v2(43.59,46.7) 43.96,46.7 44.47,47.2 44.47,49.35 38.82,55.01 38.82,84.46 45.82,91.46 92.41,91.46
  BOTTOM w0.254: v2(101.39,67.24) 101.5,67.13 UC1.BA67
+VGA_CORE: length 75
  TOP w0.254: CV118.1 112.81,109.8 112.34,109.33 112.34,108.19 CV73.1
  TOP w0.381: CV118.1 112.87,109.82 v2(112.87,110.43) ; CV87.1 117.01,113.57 v2(116.83,113.39) ; v2(115.84,115.16) 115.78,115.16 CV90.1 ; CV115.1 112.45,114.65 v2(111.89,115.22) 111.61,114.94 CV77.1 ; v2(115.83,116.16) 116.4,116.16 CV89.1 116.48,115.41 v2(116.76,115.12) ; CV117.1 110.05,113.32 v2(109.94,113.32) 109.94,113.83 CV102.1 ; 114.29,115.58 CV79.1 ; CV72.1 114.76,112.42 v2(114.76,112.28) 114.6,112.28 CV101.1 ; CV100.1 111.48,110.52 111.82,110.86 CV74.1 112.04,110.94 v2(112.04,111.47) ; v2(114.88,110.4) CV75.1
  TOP w0.508: CV114.1 110.96,108.49 v2(110.42,108.49) 110.31,108.49 109.75,107.93 CV104.1 ; v2(113.79,117.33) 114.28,116.83 CV78.1 ; v2(107.23,109.53) 107.86,109.53 CV113.1 ; CV112.1 116.1,109.32 v2(116.53,109.32) ; CV116.1 111.39,116.22 v2(110.89,116.22) 110.51,116.59 CV106.1 ; v2(109.98,117.24) 109.98,117.24 CV111.1 ; CV127.1 107.77,112.3 v2(107.41,111.94) ; v2(113.73,115.11) 113.88,115.11 114.29,115.52 CV105.1 ; CV76.1 108.84,110.33 v2(108.93,110.42) ; CV126.1 109.32,110.92 v2(108.91,111.33) ; CV80.1 CV125.1 112.52,107.53 CV73.1 ; CV103.1 112.37,113.42 v2(111.89,113.42) 111.89,113.3 CV71.1
  BOTTOM w0.381: UV1.N12 115.26,110.78 v2(114.88,110.4) ; UV1.W10 UV1.W9 ; UV1.W9 110.52,107.77 v2(110.42,107.77) ; UV1.W9 111.46,108.32 UV1.U10 UV1.T10 ; UV1.U11 112.46,110.03 v2(112.87,110.43) 113.26,110.83 UV1.T12 ; v2(113.79,117.33) 113.26,116.8 UV1.T20 112.46,115.92 UV1.U18 112.39,115.72 v2(111.89,115.22) 111.46,114.79 UV1.V17 110.66,113.92 UV1.Y16 110.46,113.88 109.94,113.36 v2(109.94,113.32) 109.9,113.32 109.5,112.92 UV1.AA15 108.91,112.36 v2(108.88,112.36) 108.46,111.94 UV1.AB13 107.86,111.32 UV1.AC13 107.41,111.57 v2(107.41,111.94) 107.41,112.26 UV1.AC14 107.82,112.68 v2(107.82,113.14) ; UV1.Y9 110.25,108.32 v2(110.42,108.49) ; UV1.M18 116.26,115.62 v2(116.76,115.12) ; v2(108.91,111.33) 108.5,110.92 UV1.AB12 ; UV1.AB11 108.46,109.94 v2(108.93,110.42) 109.43,110.92 UV1.AA12 ; UV1.M13 UV1.M15 ; UV1.Y18 110.89,116.15 v2(110.89,116.22) 110.96,116.22 UV1.V20 UV1.V21 111.31,117.87 110.61,117.87 UV1.Y21 v2(109.98,117.24) ; UV1.AA12 UV1.Y13 110.89,112.35 110.89,112.42 111.39,112.92 UV1.V15 111.89,113.35 v2(111.89,113.42) 112.39,113.92 UV1.U16 UV1.T17 113.35,114.72 v2(113.73,115.11) 114.26,115.63 UV1.R18 UV1.N20 115.82,116.16 v2(115.83,116.16) 115.83,116.29 UV1.M20 UV1.M21 ; UV1.AA12 109.46,110.96 ; UV1.N15 115.26,112.78 v2(114.76,112.28) 114.4,111.92 UV1.R13 ; v2(116.53,109.32) 116.26,109.59 UV1.M11 ; UV1.M16 UV1.M17 116.26,114.74 v2(115.84,115.16) 115.71,115.16 UV1.N17 115.06,114.72 UV1.R16 UV1.T15 113.26,112.85 v2(112.86,112.45) 112.46,112.05 UV1.U13 112.46,111.89 v2(112.04,111.47) ; v2(107.23,109.53) 107.66,109.97 UV1.AC11
  vias: v2(80.16,119.59) v2(80.16,118.57) v2(80.16,117.56) v2(80.16,116.54) v2(80.73,124.86) v2(80.67,123.53) v2(81.17,119.59) v2(81.17,118.57) v2(81.17,117.56) v2(81.17,116.54) v2(81.74,124.86) v2(81.68,123.53) v2(82.19,119.59) v2(82.19,118.57) v2(82.19,117.56) v2(82.19,116.54) v2(82.25,122.51) v2(82.7,123.53) v2(82.7,111.91) v2(82.76,124.86) v2(83.21,120.03) v2(83.21,119.02) v2(83.21,118) v2(83.21,116.99) v2(83.27,122.51) v2(83.27,121.3) v2(83.4,130.07) v2(83.97,129.18) v2(83.97,128.16) v2(83.97,127.15) v2(83.97,126.13) v2(83.97,125.11) v2(83.97,124.1) v2(83.99,116.02) v2(83.99,114.78) v2(84.22,120.03) v2(84.22,119.02) v2(84.22,118) v2(84.22,116.99) v2(84.28,122.51) v2(84.28,121.3) v2(84.28,112.67) v2(84.28,111.65) v2(84.41,130.07) v2(84.98,129.18) v2(84.98,128.16) v2(84.98,127.15) v2(84.98,126.13) v2(84.98,125.11) v2(84.98,124.1) v2(85.01,114.9) v2(85.3,121.3) v2(85.3,112.67) v2(85.3,111.65) v2(85.87,123.46) v2(85.87,122.45) v2(86,129.18) v2(86,128.16) v2(86,127.15) v2(86,126.13) v2(86.51,113.35) v2(86.76,112.06) v2(86.89,123.46) v2(86.89,122.45) v2(87.02,129.18) v2(87.02,128.16) v2(87.02,127.15) v2(87.02,126.13) v2(87.04,110.43) v2(87.9,123.46) v2(87.9,122.45) v2(88.03,129.18) v2(88.03,128.16) v2(88.03,127.15) v2(88.03,126.13) v2(88.39,112.64) v2(104.91,106.32) v2(104.91,105.49) v2(105.66,106.36) v2(107.96,101.76) v2(108.2,102.39) v2(108.63,101.88) v2(108.73,103.36) v2(108.86,102.44) v2(109.76,104.31) v2(110.46,105.55) v2(111.18,104.72) v2(111.19,102.3) v2(111.27,105.5) v3(80.6,121.47)
AC_DIS: length 141
  IN1 w0.119: v2(182.4,22.26) 182.94,22.8 183.44,22.8 184.27,23.63 184.27,24.52 185.23,25.48 185.23,42.58 184.64,43.16 184.64,44.82 172.86,56.59 172.86,64.51 166.11,71.26 166.11,105.2 165.73,105.58 162.39,105.58 161.66,104.86 158.58,104.86 156.93,106.51 v2(156.87,106.51)
  IN3 w0.142: v2(182.4,22.26) 182.27,22.38 177.88,22.38 175.33,19.83 162.68,19.83 160.24,22.26 160.24,25.66 158.49,27.42 158.49,28.51 157.44,29.57 v2(157.24,29.57)
  BOTTOM w0.102: UE1.69 157.23,29.58 v2(157.24,29.57) ; v2(156.87,106.51) v1(156.29,106.51) 156.29,105.63 156.56,105.36 156.56,104.06 PQ712.2
AC_PRESENT: length 12.8
  TOP w0.102: DZ1.2 92.41,33.7 92.36,33.76 RC90.1 92.36,34.21 93.05,34.9 v2(93.68,34.9) v1(94.27,34.9)
  BOTTOM w0.076: UC1.AY15 101.84,37.14 101.65,37.34 99.69,37.34 99.07,36.71 98.17,36.71 96.85,35.39 96.27,35.39 96.14,35.26 95.21,35.26
  BOTTOM w0.102: v2(93.68,34.9) 94.04,35.26 95.21,35.26
ACAV_IN: length 173.9
  TOP w0.102: CE32.2 141.56,16.22 141.75,16.03 v2(141.75,15.96) ; v2(90.16,31.46) 90.44,31.74 90.44,32.6 DZ1.1 ; PR12.1 187.42,19.83 v3(187.81,20.22) 188.92,21.33 188.92,23.13 v2(189.4,23.61)
  IN1 w0.119: v2(172.23,9) 172.15,9.08 167.86,9.08 164.29,12.65 158.1,12.65 152.85,17.9 146.81,17.9 145.99,17.08 144.95,17.08 144.21,16.34 142.28,16.34 141.9,15.96 v2(141.75,15.96)
  IN1 w0.254: v2(191.34,33.23) 191.98,32.6 191.98,31.26 189.76,29.04 189.76,23.97 v2(189.4,23.61)
  IN2 w0.127: v2(141.75,15.96) 141.12,16.59 138.15,16.59 136.54,18.2 134.16,18.2 133.88,17.92 130.45,17.92 125.83,13.3 120.85,13.3 119.17,14.97 110.74,14.97 109.66,13.89 108.6,13.89 107.62,14.88 104.65,14.88 101.63,11.86 100.1,11.86 98.23,9.99 94.46,9.99 92.69,11.77 84.3,11.77 83.2,12.87 83.11,12.87 v2(83.01,12.97)
  BOTTOM w0.102: v2(189.4,23.61) 188.64,22.85 188.64,20.43 186.14,17.92 186.14,17.09 185.83,16.78 185.44,16.4 183.02,16.4 181.27,14.64 177.85,14.64 172.23,9.02 v2(172.23,9) ; v2(83.01,12.97) 83.01,14.09 84.86,15.93 84.86,17.73 87.59,20.46 87.59,24.98 87.08,25.49 87.08,27.33 86.86,27.54 86.86,28.88 89.44,31.46 v2(90.16,31.46) ; v2(141.75,15.96) 141.96,16.16 UE1.128
  BOTTOM w0.203: PU703.2 191.56,34.84 PR741.2 PR731.1 191.22,33.11 v2(191.34,33.23)
ACIN_CHG: length 102.1
  TOP w0.508: v2(191.41,32.35) 191.29,32.23 PC711.2
  IN1 w0.508: v2(162.83,107.02) 165.98,107.02 167.16,105.84 167.16,71.81 173.94,65.04 173.94,62.69 188.46,48.16 190.4,48.16 191.54,47.02 191.54,42.35 191.37,42.19 191.37,41.47 191.94,40.9 191.94,39.15 190.73,37.94 190.73,32.85 191.24,32.35 v2(191.41,32.35)
  BOTTOM w0.508: PR729.2 190.72,31.36 PR732.1 191.28,32.22 v2(191.41,32.35) 192.04,32.98 192.04,33.81 ; v2(162.83,107.02) v1(162.83,105.5) 162.83,105.36 162.12,104.65 158.4,104.65 PQ712.1
ACLIM: length 4.9
  TOP w0.254: v2(195.47,39.46) v3(195.47,40.11) 195.44,40.14 PR749.1
  BOTTOM w0.203: PU703.16 195.87,38.55 196.17,38.85 PR751.2 195.97,39.46 v2(195.47,39.46)
ADJ_2.5V: length 1.2
  BOTTOM w0.102: v1(44.32,9.88) PR802.1
ALERT#: length 2.6
  BOTTOM w0.102: U2.6 138.43,16.03 R28.2 139.4,16.01 v1(139.49,15.92)
ALL_SYS_PWRGD: length 120.7
  TOP w0.102: v2(147.72,35.61) 151.28,39.16 v3(151.28,45.37) v2(151.28,48.02) ; UC6.4 89.36,12.87 89.26,12.98 89.26,13.58 88.99,13.86 88.99,14.5 88.54,14.95 v2(88.54,15.64)
  IN2 w0.127: v2(147.72,35.61) 147.72,34.31 146.83,33.42 143.66,33.42 142.01,31.77 141.56,31.77 141.44,31.65 140.08,31.65 139.91,31.82 137.38,31.82 135.72,30.16 135.72,26.85 134.42,25.55 132.13,25.55 130.18,23.59 126.95,23.59 126.79,23.43 126.79,23.42 v2(126.79,23.42) 125.55,22.19 121.58,22.19 120.93,21.54 119.95,21.54 117.88,19.47 114.25,19.47 113.18,18.4 113.18,18.31 112.68,17.82 112.15,17.82 111.58,18.38 109.15,18.38 108.89,18.64 104.37,18.64 101.69,21.33 98.31,21.33 95.19,18.21 95.19,17.06 94.28,16.15 89.04,16.15 v2(88.54,15.64)
  IN3 w0.142: v2(129.83,51.03) 130.18,51.39 131.29,51.39 132.01,50.67 134.52,50.67 136.55,48.63 150.67,48.63 v2(151.28,48.02)
  BOTTOM w0.076: RC107.1 RC105.2 RC106.2 127.6,24.15
  BOTTOM w0.102: RE42.2 147.02,34.9 v2(147.72,35.61) ; 127.6,24.15 127.6,23.84 127.19,23.42 v2(126.79,23.42) ; v2(129.83,51.03) 129.83,51.81 130.13,52.11 UC7.2
ALWON: length 50.7
  IN2 w0.127: v2(145.23,18.97) 145.23,19.02 145.75,19.54 150.8,19.54 151.19,19.16 151.19,17.53 152.32,16.4 160.15,16.4 163.27,19.51 175.56,19.51 178.23,22.18 180.56,22.18 v2(181.16,21.58)
  BOTTOM w0.102: v2(145.23,18.97) 144.76,18.5 UE1.121
  BOTTOM w0.254: v2(181.16,21.58) 181.63,22.05 v1(181.63,23.56) 181.63,27.59 181.83,27.79 181.98,27.79 PR114.1
AMBER_LED_BAT: length 11.6
  TOP w0.102: ZT17.1 156.29,12.15 157.69,10.75 157.69,9.48 157.31,9.1 154.43,9.1 Q3.1 v2(153.31,9.1)
  BOTTOM w0.102: JLED1.2 152.7,11.58 152.73,11.56 152.73,9.68 v2(153.31,9.1)
ASGATE: length 109.6
  TOP w0.102: v2(161.42,119.84) 161.56,119.84 v1(162.12,119.28)
  IN1 w0.508: v2(161.42,119.84) 160.48,118.9 160.48,108.67 161.42,107.73 166.13,107.73 167.77,106.09 167.77,72.06 174.55,65.29 174.55,62.94 188.71,48.77 190.65,48.77 192.15,47.28 192.15,42.63 192.59,42.19 192.59,41.14 193.16,40.57 193.16,38.65 191.95,37.44 191.95,33.76 192.86,32.85 v2(193.76,32.85)
  BOTTOM w0.203: PU703.30 193.87,32.96 v2(193.76,32.85)
  BOTTOM w0.508: v2(161.42,119.84) 161.18,120.08 PR762.2
AUD_AGND: length 40.7
  TOP w0.203: v2(24.61,16.58) 24.61,16.53 24.73,16.41 25.01,16.41 25.19,16.59 UA1.25 ; v2(31.24,18.2) 31.2,18.16 UA1.38
  TOP w0.508: CA26.2 v2(19.83,20.47) ; v2(22.05,13.61) 22.37,13.93 CA10.2 ; v2(13.73,10.13) EC2301.1 ZT64.1 8.9,11.76 JHP1.7 ; RA22.2 v2(18.18,23.26) ; CA21.1 35.2,15.31 CA12.2 v2(35.21,14.45) ; EC2302.1 v2(16.27,23.39) ; v2(19.71,11) 19.94,10.77 20.62,10.77 20.88,10.5 CA11.2 ; RA17.2 v2(22.45,24.52) ; CA20.1 24.97,12.79 v2(24.97,13.17) ; RA41.1 26.23,12.99 CA23.2 v2(26.75,11.77) ; RA18.2 v2(33.55,13.75) ; CA7.2 v2(20.92,22.5)
  GND1 w0.203: JHP1.7 9.98,12.84 ; JHP1.7 7.82,13.52 ; JHP1.7 8.9,12.84 ; JHP1.7 9.98,13.52 ; JHP1.7 7.82,12.84
  VCC w0.203: 8.9,12.84 JHP1.7 ; JHP1.7 7.82,12.84 ; JHP1.7 9.98,12.84
  GND2 w0.203: 8.9,12.84 JHP1.7 ; JHP1.7 9.98,12.84 ; JHP1.7 7.82,12.84 ; JHP1.7 9.98,13.52 ; JHP1.7 7.82,13.52
  BOTTOM w0.508: 19.95,11.7 v2(19.95,11.7) ; 19.95,11.7 20.39,12.14 CA34.2 ; 19.95,11.7 20.37,11.28 CA35.2 ; v2(20.28,18.62) 20.59,18.31 CA37.2 ; v2(19.98,14.64) 20.35,15 CA36.2 ; v2(22.05,12.53) 21.66,12.14 RA34.2 ; v2(23.64,10.95) 23.91,10.68 RA30.2 ; RA40.2 v2(16.03,21.87)
AUD_HP1_JACK_L: length 7.6
  TOP w0.203: v2(27.61,14.17) 28.06,14.61 28.06,15.68 27.99,15.75 UA1.32
  BOTTOM w0.305: v2(27.61,14.17) 27.61,11.36 v1(27.44,11.19) RA27.1
AUD_HP1_JACK_L1: length 5.6
  BOTTOM w0.305: RA28.2 24.9,10.31 RA27.2 RA29.2 24.77,12.08 24.26,11.58 23.12,11.58 v1(22.78,11.23) 21.51,11.23 RA36.1
AUD_HP1_JACK_R: length 7.8
  TOP w0.203: v2(28.46,16.12) 28.39,16.19 UA1.33
  BOTTOM w0.305: RA31.1 23.97,12.15 24.47,12.66 25.21,12.66 v1(25.9,13.35) 25.9,13.82 27,14.92 27,15.31 27.81,16.12 v2(28.46,16.12)
AUD_HP1_JACK_R1: length 3.3
  BOTTOM w0.305: RA31.2 22.74,12.61 22.74,12.62 RA32.2 RA33.2 22.49,14.18 21.53,14.18 RA37.1
AUD_PC_BEEP: length 10.8
  TOP w0.203: CA31.2 16.24,22.33 v3(18.96,22.33) 20.45,22.33 20.78,21.99 21.06,21.99 21.66,21.39 23.5,21.39 23.93,20.96 UA1.16
AUD_PC_BEEP_C: length 3.1
  TOP w0.102: v1(15.83,29.56) RA23.1 16.78,30.82 17.1,31.13 DA3.1
AUD_SENSE: length 11.2
  TOP w0.254: RA10.1 v2(20.59,23.46)
  BOTTOM w0.254: v2(20.59,23.46) 20.65,23.46 21.67,22.44 21.67,20.29 21.09,19.71 19.45,19.71 18.56,18.82 RA39.1
AUD_SENSE_A: length 6.7
  TOP w0.102: v1(21.93,24.38) 22.45,23.87 RA10.2
  TOP w0.203: UA1.13 22.75,22.16 22.45,22.47 CA7.1
  TOP w0.254: CA7.1 RA10.2 23.27,23.45 24.32,24.5 RA3.1
AUD_SPK_L+: length 13.2
  IN1 w1.016: 35.71,19.52 36.47,19.52 38.12,17.87 38.12,12.81 34.52,9.21
  vias: v1(31.52,19.69) v2(32.02,19.75) v2(32.61,19.75) v2(33.55,8.8) v2(33.55,8.22)
AUD_SPK_L+_C: length 16
  IN1 w1.016: 25.04,8.46 24.35,7.77 22.94,7.77 21.74,8.98 15.32,8.98 13.48,7.14 10.62,7.14
  vias: v2(9.8,7.52) v2(9.8,6.88) v2(25.74,8.91) v2(25.74,8.28)
AUD_SPK_L-: length 18.5
  IN1 w1.016: 34.82,7.77 39.39,12.34 39.39,18.73 37.42,20.69 34.53,20.69
  vias: v1(33.97,6.36) v2(32.14,20.36) v2(32.72,20.36) v2(33.55,6.64) v2(33.55,6.06)
AUD_SPK_L-_C: length 17.9
  IN1 w1.016: 25.04,6.25 22.24,6.25 20.72,7.77 16.38,7.77 14.47,5.87 8.53,5.87
  vias: v2(8.78,7.45) v2(8.78,6.82) v2(25.74,6.25) v2(25.74,5.61)
AUD_SPK_R+: length 23.6
  IN1 w1.016: 34.73,5.82 34.73,6.03 35.96,7.25 35.96,7.26 40.66,11.96 40.66,19.07 37.42,22.31 34.12,22.31
  vias: v1(31.96,21.95) v2(32.59,21.68) v2(33.23,21.68) v2(33.8,4.99) v2(33.8,4.41)
AUD_SPK_R+_C: length 16.9
  IN3 w1.016: 23.52,4.27 23.39,4.4 23.39,6.88 21.45,8.81 14.9,8.81 13.86,7.77 13.1,7.77 12.08,6.75 12.08,5.48
  vias: v2(11.83,4.53) v2(11.83,3.96) v2(24.47,4.66) v2(24.47,4.02)
AUD_SPK_R-: length 32.2
  IN1 w1.016: 34.44,3.39 35.29,4.25 35.29,4.75 36.02,5.48 36.02,5.68 41.93,11.58 41.93,19.65 37.93,23.65 33.29,23.65 31.51,21.87
  vias: v1(33.54,2.91) v2(31.45,20.66) v2(31.96,20.98) v2(33.8,2.45) v2(33.8,1.87)
AUD_SPK_R-_C: length 19.5
  IN3 w1.016: 23.64,2.11 21.93,3.83 21.93,6.27 20.55,7.64 16.15,7.64 14.12,5.61 14.12,3.96 13.1,2.94 10.75,2.94
  vias: v2(10.81,4.41) v2(10.81,3.83) v2(24.47,2.37) v2(24.47,1.74)
AUD_VREF: length 5.1
  TOP w0.102: CA23.1 26.75,13.8 27.19,13.37 v1(27.97,13.37)
  TOP w0.203: UA1.28 26.39,16.33
  TOP w0.381: 26.39,16.33 26.11,16.05 26.11,15.52 25.9,15.31 25.9,14.72 CA23.1
BA: length 32.5
  TOP w0.254: v2(201.49,38.63) v3(200.59,39.53) 199.53,40.59 198.15,40.59 195.75,38.19 194.71,38.19 193.98,37.47 193.98,34.02 194.9,33.1 194.9,24.76 196.08,23.58 PQ710.1 202.4,23.58 PR780.1
  BOTTOM w0.254: PD704.3 v2(201.49,38.63)
BAT1_LED#: length 43.4
  TOP w0.102: Q2.1 155.07,5.94 v2(154.64,6.37)
  IN3 w0.142: v2(139.77,17.97) 139.7,17.9 139.7,15.52 137.67,13.48 137.67,9.66 135.1,7.09 135.1,5.76 134.51,5.17 134.51,3.95 135.23,3.23 151.5,3.23 v2(154.64,6.37)
  BOTTOM w0.102: v1(138.03,19.6) 138.03,19.12 RE18.1 139.18,17.97 v2(139.77,17.97) 139.4,18.34 139.4,18.69 139.49,18.78 UE1.1
BAT2_LED#: length 20.9
  TOP w0.102: Q2.4 158,4.64 159.07,5.72 159.07,12.16 v3(157.38,13.85) 156.34,14.9 RE21.1 153.77,14.9 153.69,14.81 v2(153.69,14.81)
  BOTTOM w0.102: UE1.106 150.76,16.28 151.53,15.51 151.53,14.28 151.63,14.18 153.05,14.18 v2(153.69,14.81)
BATT_WHITE_LED_R#: length 6.7
  TOP w0.102: Q2.3 155.04,4.64 154.96,4.56 v1(154.4,4.56) 154.22,4.56 153.52,5.26 Q5.1 153.52,7.42 151.87,9.07 Q4.2
BEEP: length 154.9
  TOP w0.102: DA3.2 v2(18.51,30.17) ; v2(72.25,14.91) v1(72.25,15.44)
  IN1 w0.119: v2(18.51,30.17) 19.45,30.17 26.34,23.28 28.68,23.28 29.99,24.59 39.75,24.59 41.75,22.59 41.75,21.26 44.14,18.87 44.14,18.1 44.14,18.05 48.3,13.89 53.3,13.89 54.25,12.94 58.85,12.94 59.8,13.89 71.22,13.89 v2(72.25,14.91)
  IN2 w0.127: v2(72.25,14.91) 72.7,14.46 78.6,14.46 79.54,15.4 86.18,15.4 87.24,14.34 91.09,14.34 91.37,14.06 92.63,14.06 93.31,14.73 94.46,14.73 96.04,13.16 101.18,13.16 104.22,16.2 104.26,16.2 112.5,16.2 113.83,17.54 114.99,17.54 114.99,17.54 118.46,17.54 122.12,21.2 126.76,21.2 128.04,22.48 134.99,22.48 136.92,24.41 136.92,25.93 137.52,26.53 139.59,26.53 139.72,26.66 139.72,28.09 140.82,29.2 142.12,29.2 142.38,28.94 143.03,28.94 144.14,30.06 146.96,30.06 147.54,30.64 v2(147.66,30.64)
  BOTTOM w0.102: v2(147.66,30.64) 147.66,30.88 146.76,31.78 UE1.45
BKLT_CTRL: length 33.7
  TOP w0.102: v2(226.14,39.56) 225.72,39.15 224.8,39.15 224.53,38.87 RP1.8 223.74,38.87 222.9,39.71 221.8,39.71 v3(221.48,40.03) 221.38,40.13 221.38,43.71 221.7,44.03 RP2.7 ; R9.1 222.54,22.36 D3.1 222.85,22.38 v2(224.05,23.58)
  IN1 w0.119: v2(224.05,23.58) 224.05,24.91 226.02,26.88 226.02,36.01 225.81,36.22 225.81,39.06 226.14,39.38 v2(226.14,39.56)
BLON_OUT_C: length 8.7
  TOP w0.102: v1(225.46,38.82) 225.29,38.64 v2(224.97,38.64) 224.7,38.37 RP1.7 ; RP2.1 v2(224.98,43.53)
  IN1 w0.119: v2(224.97,38.64) 224.52,39.09 224.52,43.08 v2(224.98,43.53)
  BOTTOM w0.102: v2(224.97,38.64) 224.88,38.55 JEDP1.24
BLUETOOTH_EN: length 214.1
  IN3 w0.142: v2(29.61,80.98) 29.61,78.88 28.64,77.91 28.64,65.29 29,64.93 29,60.8 28.2,60 28.2,55.85 28.99,55.06 28.99,35.62 30.44,34.17 34.67,34.17 39.72,29.13 39.72,22.07 43.47,18.32 43.47,17.09 44.93,15.62 45.42,15.62 49.4,11.64 49.45,11.64 52.1,8.99 55.79,8.99 56.79,7.99 62.45,7.99 63.46,9 89.27,9 90.34,10.07 99.01,10.07 99.25,10.32 103.55,10.32 106.7,13.47 106.7,16.78 107.53,17.61 108.61,17.61 v2(108.67,17.55)
  BOTTOM w0.102: JWLAN1.46 56.3,106.77 53.25,103.72 31.9,103.72 30.31,102.12 30.31,91.21 31.74,89.78 31.74,83.05 29.64,80.95 29.64,80.98 v2(29.61,80.98) ; UC1.AB2 111.65,28.83 111.65,25.87 111.4,25.61 111.4,24.28 111.67,24.01 111.67,24 111.91,23.77 RC42.2 111.91,22.82 111.4,22.31 v1(111.4,20.34) 111.4,19.22 109.72,17.55 v2(108.67,17.55)
BOARD_ID: length 5.3
  BOTTOM w0.102: v1(150.24,13.96) 149.59,13.31 RE1.2 148.75,13.82 RE6.2 CE2.1 148.75,15.54 148.76,15.55 UE1.111
BOARD_ID2: length 9.2
  BOTTOM w0.102: UC1.AB3 112.35,29.49 112.35,28.46 111.91,28.01 111.91,26.83 v1(112.47,26.26) 112.86,25.88 RC56.1 111.88,25.12 111.78,25.02 111.78,24.24 112.79,23.23 RC55.2
BOARD_ID3: length 22.9
  TOP w0.102: RC58.1 RC57.2 84.92,25.28 v2(84.92,25.48) 84.92,25.72 v1(84.63,26.01)
  IN3 w0.142: v2(84.92,25.48) 85.04,25.36 86.62,25.36 88.43,27.17 91,27.17 91.69,27.87 95.08,27.87 95.91,28.7 96.4,28.7 97.19,29.48 v2(98.42,29.48)
  BOTTOM w0.076: UC1.BA7 101.26,32.24 101.01,32.49 100.37,32.49 99.78,31.91 99.78,31.15 99.08,30.44 99.08,30.14 v2(98.42,29.48)
BP_0: length 4.7
  BOTTOM w0.102: v1(112.02,100.32) 111.98,100.28 111.51,100.28 111.51,100.29 RV82.1 111.22,100.42 111.22,101.46 112.07,102.31 112.07,103.13 UV1.U1
BP_1: length 5
  BOTTOM w0.102: RV81.1 110.19,100.6 v1(110.8,101.21) 110.8,101.33 111.78,102.31 111.78,103.38 112.46,104.06 UV1.U3
BREATH_LED#: length 34.2
  TOP w0.102: Q16.3 170.83,12.15 R53.2 169.53,12.46 168.06,10.99 v3(163.05,10.99) 161.7,10.99 159.89,12.8 159.89,18.59 159.85,18.64 159.85,21.96 160.12,22.23 160.12,22.39 160.12,24.76 158.05,26.83 156.99,26.83 156.63,27.18 156.63,28.58 157.05,29 v2(157.38,29)
  BOTTOM w0.102: UE1.70 156.76,29.18 156.94,29 v2(157.38,29)
BST1_VGA:
  vias: v1(57.24,120.26)
BST2_VGA:
  vias: v1(57.24,125.89)
BST_1.2V:
  vias: v2(87.95,107.74)
BST_1.2V_R: length 1
  BOTTOM w0.102: PC200.1 85.48,108.82 v1(85.48,109.67)
BST_3V:
  vias: v1(174.51,45.28)
BST_5V: length 1.2
  BOTTOM w0.102: v1(177.26,36.95) 177.25,36.94 PR111.1
BST_+1.35VGPU:
  vias: v2(154.71,91.7)
BST_+1.35VGPU_R: length 1.1
  BOTTOM w0.102: v1(154.27,95.28) 154.27,94.51 154.13,94.36 PR1402.2
BST_+1VALW: length 1.2
  BOTTOM w0.102: 149.46,45.7 149.46,46.14 v1(150.01,46.69)
BST_+1VALW_R: length 1.3
  BOTTOM w0.102: PR306.2 148.8,47.62 v1(148.24,48.18)
CAM_DETECT#: length 130.4
  TOP w0.102: v2(215.77,43.5) v1(216.33,42.95)
  IN2 w0.127: v2(118.31,27.44) 118.93,28.06 118.93,29.44 120.05,30.57 122.32,30.57 122.95,31.2 122.95,32.2 123.97,33.21 129.56,33.21 130.74,32.03 132.8,32.03 136.04,35.27 139.38,35.27 141.07,36.96 141.89,36.96 142.76,37.83 144.93,37.83 145.07,37.97 146.6,37.97 147.38,38.75 150.5,38.75 152.27,36.98 159.64,36.98 160.97,38.31 162.04,38.31 162.61,37.74 173.59,37.74 174.51,38.66 177.61,38.66 180.48,41.53 181.4,41.53 182.84,42.98 183.75,42.98 186.62,45.85 192.71,45.85 193.39,45.17 197.08,45.17 198.7,43.55 199.68,43.55 200.53,42.7 208.23,42.7 208.26,42.72 208.27,42.72 208.94,43.39 215.66,43.39 v2(215.77,43.5)
  BOTTOM w0.102: RC63.2 118.24,20.39 118.88,21.04 118.88,21.43 120.39,22.94 120.39,25.39 119.35,26.43 119.35,27.19 119.1,27.44 v2(118.31,27.44) 117.63,27.44 116.35,28.72 116.35,28.82 UC1.P2 ; J3D1.7 216.6,48.43 216.47,48.29 216.47,48 215.86,47.39 215.86,44.69 215.77,44.61 v2(215.77,43.5)
CAP_LED: length 2.9
  TOP w0.254: R25.2 85.41,7.83 v2(85.41,8.51) 85.41,8.54 85.96,9.1 ZT50.1
  BOTTOM w0.254: JKB1.4 v2(85.41,8.51)
CAP_LED#: length 102
  TOP w0.102: v2(78.28,12.67) 77.77,12.17 77.77,10.22 79.4,8.58 v1(79.4,7.93) 79.4,7.44 79.76,7.08 R24.2 79.76,5.95 Q6.3
  IN2 w0.127: v2(78.28,12.67) 79.32,12.67 80.29,13.64 84.13,13.64 84.57,13.19 88.68,13.19 89.22,12.65 91.46,12.65 91.56,12.56 95.3,12.56 97.16,10.7 98.22,10.7 99.63,12.11 101.53,12.11 104.55,15.13 107.72,15.13 108.71,14.15 109.59,14.15 110.67,15.23 119.28,15.23 120.95,13.55 125.76,13.55 130.36,18.15 133.78,18.15 134.07,18.43 136.33,18.43 141.05,23.16 142.53,23.16 143.27,23.9 143.27,23.98 146.49,27.2 148.42,27.2 150.15,25.47 v2(151.85,25.47)
  BOTTOM w0.102: v2(151.85,25.47) 152.3,25.47 152.98,24.79 152.98,22 155,19.98 UE1.93
CAP_LED_Q: length 3.9
  TOP w0.102: v1(83.84,7.78) Q7.1 85.2,6.02 85.3,6.12 R25.1
CAP_LED_R#: length 5.6
  TOP w0.102: Q6.1 79.9,2.17 80.03,2.04 v3(81.76,2.04) 82.57,2.04 82.87,2.35 Q7.2
CBN: length 4
  TOP w0.203: CA24.1 31.63,16.35 31.34,16.35 v1(30.87,15.88) 29.81,15.88 29.19,16.5 UA1.35
CBP: length 2.6
  TOP w0.203: CA24.2 31.64,16.85 30.64,16.85 30.44,17.05 UA1.37
CCLIM: length 4.4
  TOP w0.102: v2(192.55,39.46) v1(192.55,38.91)
  TOP w0.254: PR752.2 PR750.1 192.61,39.52 v2(192.55,39.46)
  BOTTOM w0.203: v2(192.55,39.46) 192.79,39.46 193.87,38.38 PU703.11
CFG0: length 12
  BOTTOM w0.076: UC1.E68 121.8,66.57 122.09,66.4 123.8,66.4 124.1,66.7 124.24,66.7 124.68,67.14 124.68,69.62 126.1,71.04 127.32,71.04 128.55,72.26
  BOTTOM w0.102: 128.55,72.26 RC131.2 128.97,72.27 128.99,72.29 129.22,72.29 129.24,72.27 TPC10.1
CFG1: length 8.7
  BOTTOM w0.076: UC1.B67 123.15,67.08 123.57,67.08 124.52,68.03 124.52,69.69 126.09,71.27 126.42,71.27 TPC11.1 127.02,72.88 126.89,73.01
  BOTTOM w0.102: 126.89,73.01 126.73,73.18 RC132.2
CFG2: length 11.7
  BOTTOM w0.076: TPC12.1 128.94,70.86 126.16,70.86 125.04,69.75 125.04,66.41 124.81,66.19 124.23,66.19 123.87,65.82 122.72,65.82 122.41,65.72 122.04,65.72 UC1.D65
CFG3: length 15.9
  BOTTOM w0.076: UC1.D67 122.31,66.75 123.27,67.71 123.65,67.71 124.16,68.22 124.16,71.06 123.84,71.38 RC133.2 124.15,72.34 124.38,72.57 124.38,73.01
  BOTTOM w0.102: 124.38,73.01 124.38,74.34 124.99,74.95 TPC13.1 130.13,74.95 130.27,75.09 RC175.1
CFG4: length 5.2
  TOP w0.102: v2(121.62,70.06) 121.62,70.97 120.79,71.8 TPC14.1 120.35,71.76 RC136.2
  BOTTOM w0.076: UC1.E70 121.17,68.79 121.37,68.99 121.37,69.35 121.67,69.64 121.67,70.02 v2(121.62,70.06)
CFG5: length 5.1
  BOTTOM w0.076: 122.91,70.88 122.91,70.38 122.7,70.17 122.7,68.91 122.51,68.72 122.51,68.2 UC1.C68
  BOTTOM w0.102: TPC15.1 122.91,70.88
CFG6: length 4.2
  BOTTOM w0.076: 122.02,69.04 122.02,68.77 121.7,68.45 UC1.D68
  BOTTOM w0.102: 122.02,69.04 122.02,71.65 TPC16.1
CFG7: length 8.6
  BOTTOM w0.076: UC1.C67 122.46,67.91 122.77,68.22 123.21,68.22 123.37,68.38 123.65,68.38 123.91,68.64 123.91,70.06 123.27,70.7 123.27,70.96
  BOTTOM w0.102: TPC17.1 123.27,73.92 123.27,70.96
CFG8: length 5
  BOTTOM w0.076: 121.01,73.01 121.01,72.33 120.56,71.88 120.56,69.1 120.61,69.05 120.61,68.78 UC1.F71
  BOTTOM w0.102: TPC20.1 121.01,73.01
CFG9: length 4.9
  BOTTOM w0.076: 119.85,69.86 119.85,69.52 119.65,69.32 119.65,69.06 119.71,68.94 119.71,68.8 119.64,68.57 119.64,68.44 119.72,68.22 119.72,67.96 UC1.G69 ; 119.65,70.21 119.65,70.39 118.9,71.14 TPC21.1
  BOTTOM w0.089: 119.85,69.86 119.85,70.01 119.65,70.21
CFG10: length 6
  BOTTOM w0.076: 121.98,72.99 120.73,71.73 120.73,69.16 120.8,69.1 120.8,68.88 120.81,68.87 120.81,68.39 UC1.F70
  BOTTOM w0.102: TPC22.1 122.05,72.99 121.98,72.99
CFG11: length 7.4
  BOTTOM w0.076: UC1.G68 119.82,67.29 120.22,67.69 120.22,67.93 120.11,68.04 120.11,68.23 120.28,68.4 120.28,68.87 120.4,68.99 120.4,71.95 120.45,72.01 120.45,73.01
  BOTTOM w0.102: TPC23.1 120.45,73.27 120.45,73.01
CFG12: length 7.2
  BOTTOM w0.076: UC1.H70 119.03,68.42 119.03,68.65 118.97,68.78 118.97,68.89 119.03,69.03 119.03,69.42 118.89,69.56 118.89,69.56 118.86,69.59 118.86,70.67 118.08,71.45 118.08,73.01
  BOTTOM w0.102: TPC24.1 118.08,74.31 118.08,73.01
CFG13: length 2.2
  BOTTOM w0.076: 119.94,70.51 119.94,70.22 120.07,70.1 120.07,69.38 119.92,69.23 UC1.G71
  BOTTOM w0.102: 119.94,70.51 119.67,70.78 TPC25.1
CFG14: length 6.6
  BOTTOM w0.076: UC1.H69 119.26,67.74 119.53,68.01 119.53,68.27 119.47,68.43 119.47,68.57 119.53,68.79 119.53,68.91 119.5,68.99 119.49,69.02 119.49,69.39 119.65,69.55 119.65,69.87 119.27,70.25 119.27,70.53 118.55,71.25 118.55,72.78 118.59,72.82 118.59,73.01
  BOTTOM w0.102: TPC26.1 118.59,73.01
CFG15: length 4.1
  BOTTOM w0.076: 120.17,70.63 120.17,70.27 120.23,70.21 120.23,69.05 120.11,68.94 120.11,68.71 UC1.G70
  BOTTOM w0.102: TPC27.1 120.16,72.1 120.12,72.07 120.12,70.67 120.17,70.63
CFG16: length 2.4
  TOP w0.102: TPC19.1 120.49,66.11 v2(120.49,65.74)
  BOTTOM w0.076: UC1.E63 120.49,64.49 v2(120.49,65.74)
CFG17: length 2.2
  TOP w0.102: v2(119.83,65.74) 119.91,65.66 TPC18.1
  BOTTOM w0.076: UC1.F63 120.17,64.76 119.87,65.06 119.87,65.7 v2(119.83,65.74)
CFG18: length 11.6
  IN1 w0.119: v2(117.49,74.38) 116.86,73.75 116.86,69.8 118.7,67.96 119.85,67.96 v2(121.04,66.78)
  BOTTOM w0.076: v2(121.04,66.78) 120.82,66.55 UC1.E66
  BOTTOM w0.102: TPC29.1 v2(117.49,74.38)
CFG19: length 1.6
  TOP w0.102: TPC28.1 120.26,67.51 120.26,66.97 v2(120.45,66.78)
  BOTTOM w0.076: UC1.F66 120.17,66.49 v2(120.45,66.78)
CFG_RCOMP: length 12.5
  TOP w0.254: v2(129.83,62.56) v1(128.01,62.56) 125.8,62.56 125.12,61.88 122.51,61.88 121.44,62.94 120.59,62.94 v2(120.41,62.76)
  BOTTOM w0.076: v2(129.83,62.56) 128.81,62.56 128.34,62.09 RC134.1
  BOTTOM w0.254: v2(120.41,62.76) 120.41,62.62 UC1.E60
CHG_AMBER_LED_R#: length 4.1
  TOP w0.102: Q3.2 157.63,8.14 158.11,7.66 v1(158.11,6.6) 158.11,6.28 157.77,5.94 Q2.6
CLK_ITPXDP_N: length 1.6
  TOP w0.102: v2(120.47,52.68) 119.85,52.06 119.7,52.06 TP8.1
  BOTTOM w0.076: UC1.F43 120.1,53.04 v2(120.47,52.68)
CLK_ITPXDP_P: length 1.4
  TOP w0.102: v2(121.09,52.75) 121.52,52.75 121.57,52.8 TP9.1
  BOTTOM w0.076: v2(121.09,52.75) 121.08,52.75 120.75,53.08 UC1.E43
CLK_PCI_LPC_MEC: length 77.5
  TOP w0.102: v2(151.9,34.04) 152.34,33.6 RE27.2
  IN1 w0.119: v2(95.14,23.58) 95.14,24.85 97.1,26.81 107.09,26.81 108.12,25.77 111.34,25.77 112.12,25 112.97,25 113.52,24.44 114.68,24.44 115.22,23.9 119.1,23.9 119.45,23.55 119.45,22.92 119.57,22.8 124.42,22.8 124.55,22.93 127.45,22.93 127.93,23.4 130.14,23.4 131.61,24.87 131.61,25.37 133.9,27.66 133.9,27.98 136.64,30.72 137.01,30.72 139.97,33.68 145.25,33.68 146.06,32.86 150.73,32.86 v2(151.9,34.04)
  BOTTOM w0.102: CC88.1 94.06,18.59 94.76,19.29 94.76,19.81 94.06,20.51 94.06,21.9 95.14,22.97 v2(95.14,23.58) 95.48,23.92 95.73,23.92 96.08,24.28 RC15.2 ; UE1.57 151.56,33.69 v2(151.9,34.04)
CLK_PCI_LPDEBUG: length 46.9
  TOP w0.102: JDB1.1 118.74,9.12 118.56,9.3 118.56,9.76 117.42,10.91 v1(113.72,10.91) 112.2,10.91 110,13.1 106.56,13.1 105.95,12.5 105.16,12.5 103.98,11.31 100.13,11.31 99.44,10.62 97.86,10.62 95.68,12.8 95.68,13.72 94.13,15.27 94.13,18.87 93.86,19.14 93.86,19.86 94.22,20.22 94.22,20.72 94.71,21.21 v2(94.71,23.12)
  BOTTOM w0.102: RC16.2 95.35,28.96 94.89,28.5 94.59,28.2 94.59,26.61 94,26.01 94,23.83 v2(94.71,23.12)
CLK_PCIE_LAN_N2: length 161
  IN3 w0.142: v2(128.12,53.4) 128.12,53.89 128.55,54.33 128.55,57.91 129.13,58.49 129.13,66.81 130.22,67.9 130.22,75.19 129.62,75.8 129.62,84.07 126.37,87.33 114.32,87.33 106.89,94.76 77.69,94.76 72.68,99.77 57.64,99.77 55.94,101.48 34.3,101.48 32.78,103 32.78,116.88 32.11,117.55 v2(32.11,118.75)
  BOTTOM w0.076: UC1.D41 122.1,52.45 122.41,52.14 123.86,52.14 124.22,51.78 126.46,51.78 127.4,52.72 127.56,52.72 127.93,53.09 127.93,53.21 v2(128.12,53.4)
  BOTTOM w0.102: UL1.16 32.13,118.2 32.02,118.3 32.02,118.66 v2(32.11,118.75)
CLK_PCIE_LAN_P2: length 160.9
  IN3 w0.142: v2(127.53,53.4) 127.53,53.42 127.87,53.75 127.87,54 128.3,54.43 128.3,58.01 128.88,58.59 128.88,66.92 129.97,68.01 129.97,75.09 129.37,75.69 129.37,83.97 126.26,87.08 114.22,87.08 106.79,94.51 77.59,94.51 72.57,99.52 57.54,99.52 55.84,101.23 34.2,101.23 32.53,102.89 32.53,116.77 31.86,117.45 31.86,118.39 31.52,118.73 v2(31.52,118.75)
  BOTTOM w0.076: v2(127.53,53.4) 127.65,53.4 127.77,53.28 127.77,53.16 127.5,52.89 127.33,52.89 126.39,51.95 124.29,51.95 123.93,52.3 122.59,52.3 122.5,52.39 UC1.C41
  BOTTOM w0.102: v2(31.52,118.75) 31.53,118.75 31.82,118.46 31.82,118.22 32.04,117.99 32.12,117.99 32.32,117.8 UL1.15
CLK_PCIE_LAN_REQ#: length 183
  TOP w0.102: RC73.2 88.07,23.73 88.07,23.68 87.67,23.28 86.77,23.28 86.51,23.01 v2(86.51,22.76) ; v2(37.04,92.86) 37.04,95.34 31.2,101.18 v1(31.2,103.65) 31.2,117.24 29.75,118.69 RL13.1
  IN3 w0.142: v2(37.04,92.86) 37.17,92.99 39.68,92.99 41.84,90.82 41.84,37.96 45.97,33.84 45.97,33.37 46.04,33.29 46.04,24.07 47.57,22.55 49.81,22.55 51.01,21.34 51.01,20.82 56.93,14.9 60.32,14.9 60.58,14.64 62.11,14.64 62.47,14.28 73.63,14.28 75.17,15.81 75.76,15.81 78.89,18.94 81.45,18.94 83.14,20.63 83.14,22.06 84.03,22.95 85.3,22.95 85.49,22.76 v2(86.51,22.76) 88.42,20.85 92.38,20.85 92.69,21.15 93.64,21.15 96.11,23.63 96.85,23.63 99.33,26.11 100.35,26.11 102.17,27.93 102.17,29.01 103.33,30.16 103.33,30.8 103.98,31.44 103.98,32.16 v2(104.4,32.59)
  BOTTOM w0.076: v2(104.4,32.59) 104.61,32.8 UC1.AT8
CLK_PCIE_LAN_REQ#_R: length 8.3
  TOP w0.102: v2(31.79,116.6) 31.79,117.84 30.03,119.61 v1(29.29,119.61) RL13.2
  BOTTOM w0.102: UL1.12 v2(31.79,116.6) 31.24,116.05 RL16.2
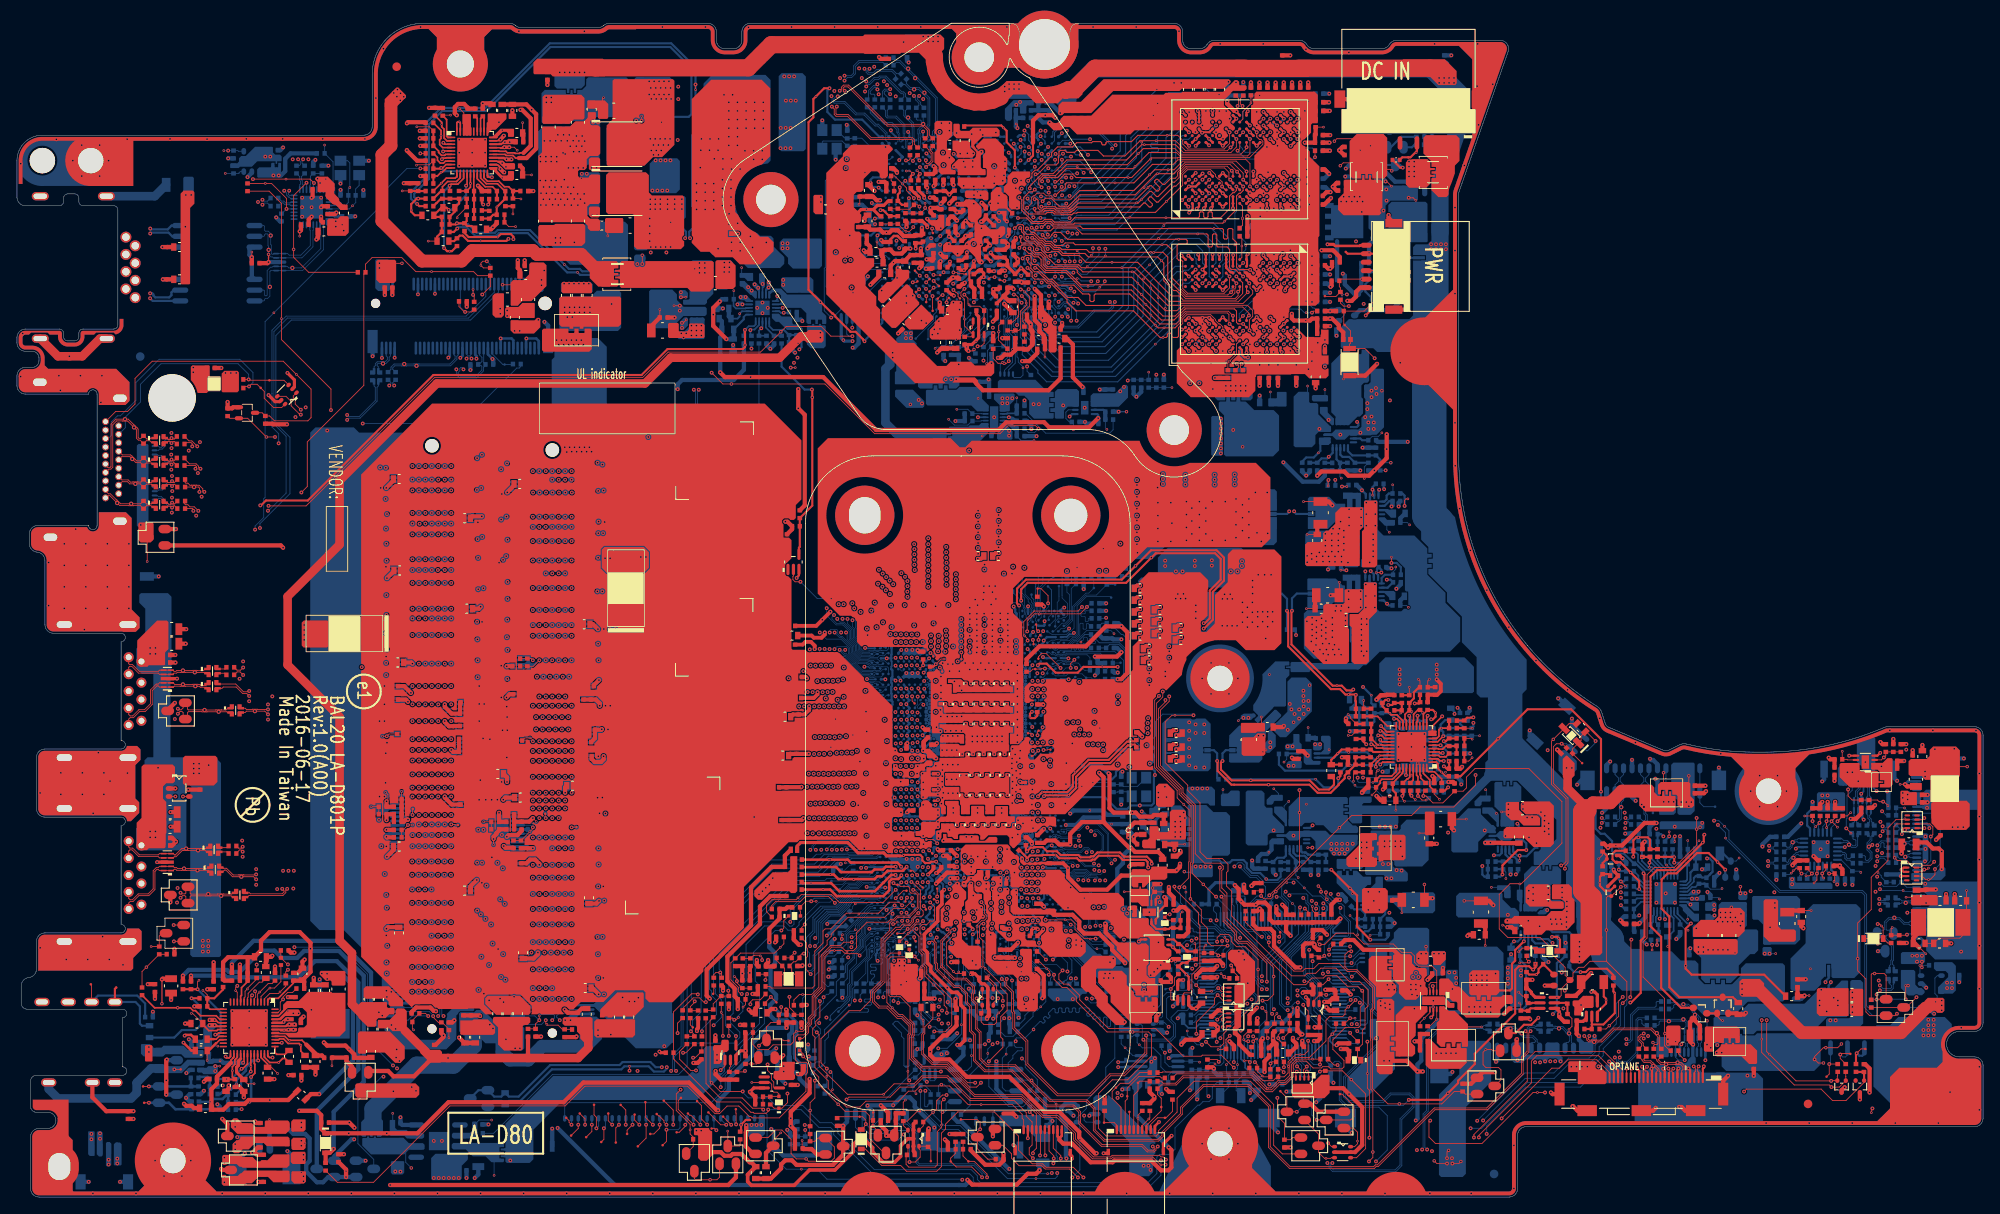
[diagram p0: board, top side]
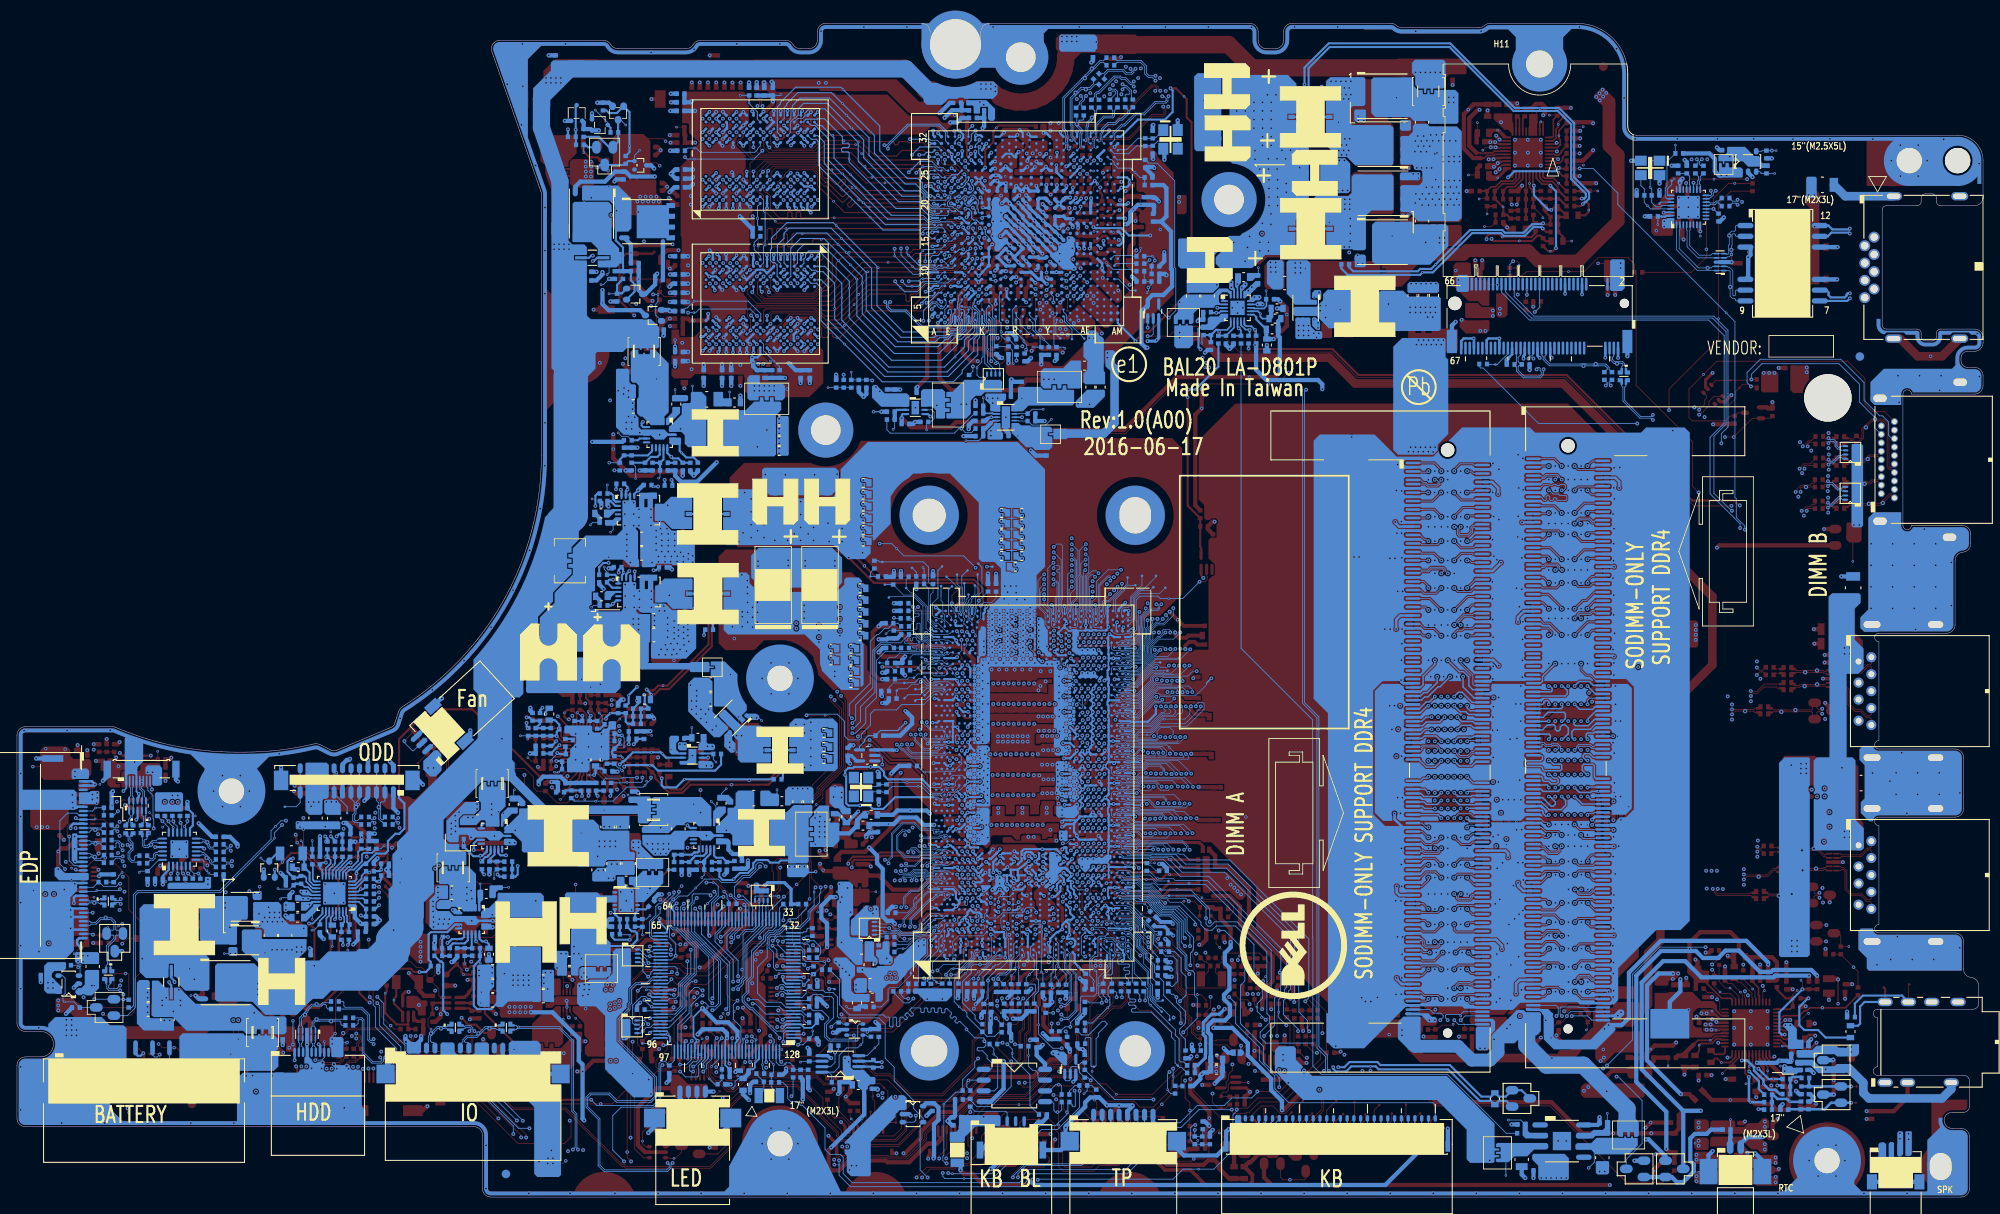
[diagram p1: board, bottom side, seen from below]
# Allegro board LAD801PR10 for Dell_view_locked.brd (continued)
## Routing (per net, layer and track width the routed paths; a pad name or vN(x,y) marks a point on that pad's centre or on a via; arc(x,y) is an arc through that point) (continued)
CLK_PCIE_SSD_N3: length 104
  TOP w0.102: v2(197.77,15.41) 197.96,15.22 197.96,14.81 197.85,14.7 JSSD1.3
  IN3 w0.142: v2(121.08,51.67) 121.19,51.56 121.19,50.31 125.1,46.39 125.18,46.39 129.62,41.95 130.26,41.95 130.56,41.66 131.82,41.66 132.89,40.58 135.26,40.58 135.84,40 137.62,40 138.04,39.58 144.61,39.58 145.22,38.97 149.32,38.97 153.02,35.27 154.07,35.27 155.42,33.92 155.42,30.22 156.05,29.59 156.05,28.01 159.47,24.59 159.47,21.94 160.91,20.5 160.91,19.89 161.74,19.05 175.65,19.05 178.2,21.61 180.17,21.61 180.92,20.86 182.14,20.86 183.27,21.98 193.51,21.98 196.87,18.62 196.87,16.94 197.93,15.89 197.93,15.57 v2(197.77,15.41)
  BOTTOM w0.076: v2(121.08,51.67) 121.31,51.67 UC1.D40
CLK_PCIE_SSD_P3: length 103.9
  TOP w0.102: v2(198.36,15.41) 198.24,15.3 198.24,14.84 198.35,14.73 JSSD1.2
  IN3 w0.142: v2(198.36,15.41) 198.18,15.59 198.18,15.99 197.12,17.04 197.12,18.73 193.61,22.24 183.16,22.24 182.04,21.11 181.03,21.11 180.28,21.86 178.1,21.86 175.54,19.31 161.84,19.31 161.16,19.99 161.16,20.61 159.72,22.05 159.72,24.7 156.31,28.11 156.31,29.69 155.67,30.32 155.67,34.02 154.18,35.52 153.12,35.52 149.42,39.22 145.32,39.22 144.72,39.83 138.15,39.83 137.73,40.25 135.95,40.25 135.36,40.83 133,40.83 131.92,41.91 130.66,41.91 130.36,42.2 129.72,42.2 125.28,46.65 125.21,46.65 121.44,50.42 121.44,51.09 v2(121.86,51.52)
  BOTTOM w0.076: UC1.C40 121.86,51.57 v2(121.86,51.52)
CLK_PCIE_SSD_REQ#: length 179.7
  TOP w0.102: JSSD1.20 189.35,15.02 187.21,17.16 179.06,17.16 178.14,16.24 178.14,13.67 171.85,7.38 v2(171.85,7.03) ; v2(80.31,23.91) 80.23,23.99 79.57,23.99 77.44,21.85 RC188.2 77.44,16.3 82.52,11.22 85.34,11.22 86.56,10 86.84,10 86.95,9.89 88.37,9.89 88.61,10.12 v2(88.61,10.32)
  IN1 w0.119: v2(104.32,33.55) 103.84,33.55 103.33,34.05 103.14,34.05 102.83,34.37 102.83,35.01 101.87,35.96 101.87,37.25 100.67,38.45 100.67,39.11 100.45,39.32 99.17,39.32 98.2,38.36 98.2,37.56 95.14,34.49 95.14,33.75 92.51,31.13 91.95,31.13 89.73,28.91 87.21,28.91 86,27.7 86,25.4 84.48,23.87 83.1,23.87 82.63,24.35 80.75,24.35 v2(80.31,23.91) ; v2(134.93,4.33) 134.93,4.42 135.34,4.83 136.18,4.83 137.78,3.23 149.24,3.23 154.5,8.49 160.09,8.49 161.55,7.03 v2(171.85,7.03)
  BOTTOM w0.076: v2(104.32,33.55) 104.61,33.84 UC1.AT10
  BOTTOM w0.102: v2(88.61,10.32) 92.49,10.32 94.59,8.21 95.97,8.21 96.34,7.84 96.34,7.35 100.94,2.75 112.36,2.75 112.8,2.32 112.8,1.87 113.45,1.22 133.58,1.22 134.93,2.57 v1(134.93,3.79) v2(134.93,4.33)
CLK_PCIE_WLAN_N1: length 128.3
  IN3 w0.142: v2(126.91,53.43) 126.91,54.06 127.78,54.92 127.78,58.27 128.36,58.85 128.36,67.13 129.38,68.16 129.38,74.46 128.67,75.18 128.67,83.12 128.62,83.16 128.62,83.54 125.61,86.56 112.92,86.56 105.49,93.99 77.37,93.99 72.39,98.97 57.09,98.97 56.49,99.57 55.54,99.57 54.47,98.5 52.35,98.5 52.01,98.16 52.01,97.87 51.83,97.69 v2(51.83,97.67)
  BOTTOM w0.076: v2(126.91,53.43) 126.91,52.82 126.36,52.28 124.19,52.28 123.99,52.48 123.34,52.48 122.95,52.87 122.95,52.88 UC1.B42
  BOTTOM w0.102: v2(51.83,97.67) 51.83,97.06 52.22,96.66 54.21,96.66 55.04,97.49 55.04,97.9 55.26,98.12 EC3201.1 55.05,98.46 JWLAN1.41
CLK_PCIE_WLAN_P1: length 128.3
  IN3 w0.142: v2(52.66,97.67) 52.44,97.67 52.26,97.85 52.26,98.05 52.45,98.25 54.57,98.25 55.64,99.32 56.38,99.32 56.99,98.71 72.28,98.71 77.26,93.73 105.39,93.73 112.82,86.3 125.51,86.3 128.37,83.44 128.37,83.06 128.42,83.01 128.42,75.08 129.13,74.36 129.13,68.26 128.11,67.24 128.11,58.95 127.53,58.37 127.53,55.03 126.64,54.14 126.64,53.76 126.33,53.45 v2(126.33,53.43)
  BOTTOM w0.076: UC1.A42 123.43,53.05 123.27,53.05 123.19,52.98 123.19,52.87 123.41,52.65 124.05,52.65 124.26,52.44 126.3,52.44 126.75,52.89 126.75,53.07 126.39,53.43 v2(126.33,53.43)
  BOTTOM w0.102: v2(52.66,97.67) 52.66,97.77 52.53,97.9 52.36,97.9 52.23,97.77 52.23,97.5 52.03,97.3 52.03,97.14 52.31,96.87 54.13,96.87 54.83,97.57 54.83,98.03 54.73,98.13 54.51,98.13 EC3202.1 54.56,98.4 54.66,98.4 54.84,98.59 54.84,99.08 54.55,99.37 JWLAN1.39
CLK_PCIE_WLAN_REQ#: length 166.4
  IN3 w0.142: v2(40.79,91.27) 40.79,63.51 41.32,62.97 41.32,37.28 45.52,33.08 45.52,23.73 48.53,20.72 49.65,20.72 52.5,17.87 53.22,17.87 56.71,14.37 60.11,14.37 60.37,14.12 61.89,14.12 62.25,13.75 76.73,13.75 77.33,14.35 77.98,14.35 79,15.37 80.47,15.37 81.6,16.5 81.6,17.16 82.88,18.44 85.37,18.44 86.04,19.11 92.51,19.11 93.11,19.71 93.8,19.71 v2(94.62,20.53)
  BOTTOM w0.076: 99.51,30.39 100.11,30.99 100.11,31.77 100.37,32.03 100.66,32.03 100.7,31.99 102.36,31.99 102.51,32.13 102.51,32.47 102.62,32.58 103.88,32.58 104.36,32.11 UC1.AT7
  BOTTOM w0.102: RW9.1 59.42,98 59.24,97.82 58.95,97.82 52.4,91.27 v2(40.79,91.27) ; v2(94.62,20.53) 94.62,21.77 95.62,22.77 95.62,22.78 96.64,23.8 96.64,25.39 97.35,26.1 RC72.2 97.72,26.52 97.72,27.39 98.61,28.28 98.61,28.76 99.51,29.66 99.51,30.39
CLK_PCIE_WLAN_REQ#_R: length 3.7
  BOTTOM w0.102: RW9.2 58.45,98.24 ZT63.1 57.31,98.24 56.05,99.5 JWLAN1.45
CLK_PEG_VGA: length 114.7
  IN1 w0.119: v2(96.07,129.91) 95.2,129.04 93.72,129.04 91.72,127.04 91.72,122.35 91.72,121.23 92.03,120.91 92.03,115.76 91.37,115.1 91.37,107.14 91.97,106.54 91.97,101.45 92.71,100.7 92.71,98.27 93.51,97.47 99.05,91.93 99.06,91.93 99.08,91.91 104.74,91.91 112.25,84.4 115.02,84.4 115.02,84.41 116.59,84.41 116.94,84.05 119.82,81.18 119.82,77.38 122.48,74.71 122.48,73.39 124.99,70.89 124.99,68.1 126.47,66.62 126.47,59.41 125.89,58.83 v2(125.89,54.58)
  BOTTOM w0.076: v2(125.89,54.58) 125.89,53.93 124.85,52.89 124.3,52.89 123.75,53.44 123.34,53.44 123.24,53.41 123.05,53.41 122.96,53.44 122.71,53.44 122.23,53.3 122.18,53.3 121.8,53.19 UC1.D42
  BOTTOM w0.102: v2(96.07,129.91) 96.14,129.83 96.14,129.32 96.39,129.07 97.56,129.07 98.94,127.7 99.91,127.7 101.22,126.39 101.52,126.39 102.42,125.49 102.42,124.76 UV1.AK30
CLK_PEG_VGA#: length 114.6
  IN1 w0.119: v2(96.82,129.89) 96.63,129.89 96.24,129.5 95.96,129.5 95.29,128.82 93.81,128.82 91.94,126.95 91.94,122.26 91.94,121.32 92.25,121 92.25,115.67 91.58,115.01 91.58,107.23 92.19,106.63 92.19,101.54 92.93,100.79 92.93,98.36 93.6,97.69 99.14,92.15 99.15,92.15 99.17,92.13 104.83,92.13 112.34,84.62 112.75,84.62 114.93,84.62 116.68,84.62 117.03,84.27 120.02,81.29 120.03,81.27 120.03,77.47 122.7,74.81 122.7,73.48 125.2,70.98 125.2,68.19 126.69,66.71 126.69,59.32 126.11,58.74 126.11,54.95 126.48,54.59 v2(126.48,54.58)
  BOTTOM w0.076: v2(126.48,54.58) 126.42,54.58 126.06,54.23 126.06,53.86 124.92,52.73 124.23,52.73 123.68,53.28 123.37,53.28 123.25,53.22 123.1,53.22 122.91,53.28 122.74,53.28 122.24,53.11 122.17,53.02 UC1.C42
  BOTTOM w0.102: UV1.AK32 102.72,125.12 102.62,125.22 102.62,125.58 101.6,126.59 101.31,126.59 100,127.9 99.03,127.9 97.65,129.28 96.48,129.28 96.35,129.41 96.35,129.62 96.62,129.89 v2(96.82,129.89)
CLK_SMB: length 4.6
  TOP w0.102: ZT104.1 213.76,14.52 v2(213.76,15.69) PR18.1
  BOTTOM w0.102: PBATT1.7 213.91,15.84 v2(213.76,15.69)
CLK_TP_SIO: length 109.6
  TOP w0.102: v2(114.42,2.33) 114.42,2.71 112.92,4.21 ZT13.1 111.58,4.85 C27.1 111.6,5.66 R32.2
  IN3 w0.142: v2(114.42,2.33) 115.02,1.73 122.86,1.73 124.11,2.98 126.63,2.98 127.27,2.33 153.34,2.33 154.57,3.56 v2(154.57,4.02)
  BOTTOM w0.102: JTP1.1 104.9,8.98 106.27,7.61 106.27,4.09 106.44,3.92 112.96,3.92 114.42,2.46 v2(114.42,2.33) ; UE1.78 156.9,25.98 157.59,25.29 158.93,25.29 159.61,24.61 159.61,22.96 159.8,22.77 159.8,22.2 161.01,20.99 161.01,18.41 156.67,14.08 156.67,11.89 157.18,11.38 161.09,11.38 161.98,12.27 164.29,12.27 164.78,11.79 164.78,10.6 163.34,9.16 163.34,3.7 162.64,3 155.18,3 154.76,3.43 154.76,3.83 v2(154.57,4.02)
CLKRUN#: length 77.9
  TOP w0.102: v2(97.3,30.45) 97.3,30.88 v1(97.37,30.96)
  IN2 w0.127: v2(154.08,34.07) 154.08,34.07 153.67,34.48 153.67,34.82 152.78,35.71 151.74,35.71 151.39,36.07 150.26,36.07 149.75,36.58 147.36,36.58 147.23,36.45 146.66,36.45 145.82,35.61 144.09,35.61 142.67,34.19 140.46,34.19 139.83,33.55 137.81,33.55 134.48,30.22 134.48,28.97 129.81,24.3 125.83,24.3 125.83,24.3 125.8,24.3 125.4,23.9 115.25,23.9 115.24,23.9 114.89,23.9 114.89,23.9 104.54,23.9 101.17,27.27 98.32,27.27 97.3,28.28 v2(97.3,30.45)
  BOTTOM w0.076: 100.43,34.14 100.55,34.26 100.88,34.26 101.01,34.39 102.49,34.39 UC1.AW11 ; RC36.1 97.06,30.69 v2(97.3,30.45)
  BOTTOM w0.102: UE1.63 153.96,33.95 v2(154.08,34.07) ; 100.43,34.14 99.94,33.66 99.94,33.6 99,32.66 99,32.65 97.68,31.32 97.25,31.32 RC36.1
CMP_STRAP0: length 2.6
  TOP w0.102: v1(146.24,18.65) 146.09,18.65 v2(145.81,18.38) 145.81,17.88 RE40.1
  BOTTOM w0.102: UE1.118 145.96,18.23 v2(145.81,18.38)
CMP_VIN0: length 5.9
  TOP w0.102: v1(142.02,26.36) v2(142.4,25.99) 142.58,25.8 RE52.1
  BOTTOM w0.102: v2(142.4,25.99) 141.99,26.39 141.45,26.39 141.44,26.38 UE1.20 138.44,26.38 138.36,26.3 RE37.2
CMP_VOUT0: length 54.1
  TOP w0.102: RE52.2 143.92,26.16 RE49.2 143.39,27.15 v2(143.21,27.33) ; v1(177.25,27.65) 178.2,27.65 v2(178.33,27.77) 178.07,28.03 PR116.1
  IN2 w0.127: v2(143.21,27.33) 145.18,27.33 146.07,28.22 152.29,28.22 152.67,27.83 v2(152.82,27.83) 153.44,28.44 153.44,28.55 154.49,29.61 155.6,29.61 156.67,28.53 156.67,27.45 157.94,26.18 163.15,26.18 163.79,25.55 165.63,25.55 166.2,24.97 166.2,24.53 166.68,24.05 168.44,24.05 169.12,23.37 176.91,23.37 178.33,24.78 v2(178.33,27.77)
  BOTTOM w0.102: UE1.85 155.17,23.18 154.9,23.45 154.2,23.45 153.89,23.76 153.89,25.17 152.82,26.24 v2(152.82,27.83)
CMSRC: length 97.1
  IN1 w0.508: v2(162.06,108.34) 166.38,108.34 168.38,106.34 168.38,72.32 175.16,65.54 175.16,63.19 188.97,49.38 190.9,49.38 192.76,47.53 192.76,42.88 193.2,42.44 193.2,41.39 193.77,40.82 193.77,38.39 192.56,37.19 192.56,34.02 193.12,33.46 194.01,33.46 194.39,33.08 v2(194.39,32.79)
  BOTTOM w0.102: v1(163.01,107.66) 162.74,107.66 v2(162.06,108.34)
  BOTTOM w0.203: v2(194.39,32.79) 194.27,32.92 PU703.29
  BOTTOM w0.508: PR763.2 v2(162.06,108.34)
COMP: length 5.3
  BOTTOM w0.203: PC751.2 PR754.2 191.66,40.71 v1(191.66,40.07) 191.66,39.67 192.37,38.96 192.81,38.96 193.47,38.31 PU703.10
COMP_IA: length 3.4
  TOP w0.203: PU602.16 164.28,56.72 v2(164.21,56.79)
  BOTTOM w0.102: v1(164.53,57.3) 164.53,57.11 v2(164.21,56.79)
  BOTTOM w0.254: v2(164.21,56.79) 164.35,56.65 PC636.2 PR639.2
COMP_VSA: length 4.7
  TOP w0.203: v2(160.8,53.94) 161.03,53.72 PU602.24
  BOTTOM w0.102: PR630.1 160.66,52.04 v1(160.46,51.84)
  BOTTOM w0.254: v2(160.8,53.94) 160.8,53.54 PC628.1 161.68,52.66 161.68,52.28 PR630.1
CORE_SNUB: length 2.7
  TOP w0.102: v1(152.08,69.43) PC662.1
  TOP w0.508: PR663.2 153.12,70.88 PC662.1
CORE_SW: length 2.5
  TOP w0.102: PR663.1 155.97,71.07 v1(155.97,72.55)
  TOP w0.508: v2(154.96,71.02) PR663.1
CPU_B+: length 37.3
  TOP w0.508: PR603.2 161.36,48.34 v2(161.12,48.09)
  IN1 w0.254: v2(159.21,64.41) 162.45,64.41 164.98,61.88 164.98,59.97 167.6,57.36 167.6,56.45 169.37,54.68 169.37,50.5 167.72,48.85 162.26,48.85 161.51,48.09 v2(161.12,48.09)
  BOTTOM w0.762: 151.72,62.63 158.13,62.63 158.71,63.21
  vias: v2(158.58,68.22) v2(158.58,67.59) v2(158.58,66.95) v2(158.58,66.32) v2(158.58,65.68) v2(158.58,65.05) v2(158.58,64.41) v2(159.1,72.29) v2(159.1,70.93) v2(159.1,69.57) v2(159.15,81.95) v2(159.15,80.59) v2(159.15,79.23) v2(159.21,68.22) v2(159.21,67.59) v2(159.56,74.88) v2(159.96,78.22) v2(159.96,77.58) v2(159.96,76.95) v2(159.96,76.22) v2(159.96,75.59) v2(160.22,81.95) v2(160.22,80.59) v2(160.22,79.23) v2(160.17,72.29) v2(160.17,70.93) v2(160.17,69.57) v3(158.86,63.86)
CPU_DP3_AUXN: length 1.2
  TOP w0.102: TP1.1 119.52,54.73 v2(119.74,54.51)
  BOTTOM w0.076: v2(119.74,54.51) 119.74,54.68 UC1.G46
CPU_DP3_AUXP: length 1.2
  TOP w0.102: TP2.1 120.38,54.91 v2(120.38,54.49)
  BOTTOM w0.076: UC1.F46 120.38,54.7 v2(120.38,54.49)
CPU_POPIRCOMP: length 14.3
  TOP w0.305: RC119.1 v1(95.08,36.28) 95.92,36.28 96.7,35.5 102.18,35.5 102.89,36.21 102.89,37.23 103.19,37.53 103.95,37.53 104.31,37.88 v2(104.31,37.97)
  BOTTOM w0.254: UC1.AT16 104.31,37.9 104.31,37.97 v2(104.31,37.97)
CPU_XDP_TCK0: length 6.8
  BOTTOM w0.076: TPC2.1 125.39,62.24 125.39,62.14 125.17,61.93 123.91,61.93 123.78,61.79 UC1.A59 ; TPC2.1 125.39,62.69 125.39,62.8 125.17,63.02 123.8,63.02 123.63,63.19 123.37,63.19 122.88,62.95 122.86,62.92 UC1.B61 ; TPC2.1 125.91,62.16 126.02,62.16 126.02,62.16 RC146.1
CPVEE: length 3.4
  TOP w0.102: CA25.2 30.01,15.31 v1(30.74,14.58)
  TOP w0.203: CA25.2 29.56,15.69 28.79,16.46 UA1.34
CS_1.2V: length 3.8
  BOTTOM w0.102: v1(84.55,106.95) PR205.2
  BOTTOM w0.203: PR205.2 84.52,105.92 84.52,105.14 84.81,104.85 85.93,104.85 86,104.92 PU200.13
CSI2_COMP: length 10.2
  BOTTOM w0.076: UC1.E13 120.75,36 121.37,36.62 123.27,36.62 123.32,36.57 123.33,36.57 123.34,36.55 123.75,36.55 124.17,36.97 124.43,36.97 125.01,36.38 125.01,36.16 v1(125.9,35.28) 126.17,35.01 126.17,34.26 126.87,33.55 RC7.1
DAT_SMB: length 4.6
  TOP w0.102: ZT105.1 216.2,16.95 215.19,16.95 v2(215.06,16.82) 215.06,16.34 PR20.1
  BOTTOM w0.102: v2(215.06,16.82) 215.35,16.53 215.67,16.53 215.91,16.77 PBATT1.6
DAT_TP_SIO: length 111.8
  TOP w0.102: R31.2 110.71,5.66 C26.1 110.72,5.18 110.13,4.59 ZT12.1 110.79,3.55 112.62,3.55 v2(113.84,2.33)
  IN3 w0.142: v2(113.84,2.33) 113.84,2.31 114.66,1.48 122.96,1.48 124.22,2.74 126.52,2.74 127.17,2.09 153.48,2.09 155.15,3.76 v2(155.15,4.02)
  BOTTOM w0.102: JTP1.2 103.9,8.76 104.06,8.6 104.99,8.6 106.07,7.53 106.07,4.01 106.36,3.71 112.88,3.71 113.84,2.75 v2(113.84,2.33) ; UE1.79 157.01,25.58 157.51,25.09 158.85,25.09 159.41,24.53 159.41,22.88 159.6,22.69 159.6,22.12 160.8,20.91 160.8,18.5 156.47,14.17 156.47,11.81 157.1,11.18 161.18,11.18 162.07,12.07 164.21,12.07 164.58,11.7 164.58,10.69 163.14,9.25 163.14,3.79 162.56,3.21 155.26,3.21 154.96,3.51 154.96,3.83 v2(155.15,4.02)
DBC_EN: length 147.1
  TOP w0.102: v2(152.8,41.23) v1(152.24,41.23)
  IN1 w0.119: v2(106.91,31.71) 107.21,31.71 107.78,32.28 108.46,32.28 109.09,31.65 109.09,30.61 109.32,30.38 110.95,30.38 111.11,30.22 117.13,30.22 117.77,30.87 118.49,30.87 120.14,29.22 124.36,29.22 124.63,28.95 126.86,28.95 128.6,30.7 128.98,30.7 130.98,32.7 131.88,32.7 132.4,33.22 132.4,34.09 133.38,35.07 133.38,36.71 136.57,39.9 137.55,39.9 139.46,41.8 139.46,45.19 140.47,46.2 152.21,46.2 153.23,45.18 153.23,41.48 152.98,41.23 v2(152.8,41.23)
  IN2 w0.127: v2(152.8,41.23) 152.8,41.23 152.8,40.92 153.71,40.01 155.93,40.01 156.42,39.52 158.73,39.52 159.63,40.43 159.63,42.88 159.56,42.96 159.56,44.2 162.34,46.98 162.34,47.65 163.02,48.34 168.17,48.34 168.58,47.93 172.56,47.93 176.08,51.45 181.94,51.45 182.4,51.91 188.13,51.91 189.48,50.56 193.4,50.56 195.01,48.94 196.08,48.94 199.87,45.15 200.51,45.15 202.2,43.46 207.73,43.46 209.57,45.3 219.77,45.3 v2(219.99,45.53)
  BOTTOM w0.076: UC1.AM5 107.21,31.41 106.92,31.71 v2(106.91,31.71)
  BOTTOM w0.102: v2(219.99,45.53) 220.47,45.05 R6.2
DBC_EN_R: length 3.5
  BOTTOM w0.102: R6.1 R5.2 222.61,45.93 v1(222.63,45.91) 222.99,45.55 224.07,45.55 JEDP1.10
DDC_CLK_HDMI: length 32.8
  TOP w0.102: RI13.1 26.89,95.65 v2(27.37,95.65) 27.62,95.9 28.33,95.9 ZT66.1 29.17,95.06 29.17,94.26 30.25,93.17 31.23,93.17 QI2.6
  BOTTOM w0.102: JHDMI1.15 10.76,89.5 11.17,89.91 11.17,91.49 11.86,92.18 12.2,92.18 14.04,94.02 14.04,96.12 16.77,98.86 26.28,98.86 27.83,97.3 27.83,96.11 v2(27.37,95.65)
DDC_DATA_HDMI: length 27.5
  TOP w0.102: QI2.3 31.5,96.37 ZT65.1 29.76,96.39 27.42,96.39 27.42,96.38 v2(27.33,96.48) RI14.1
  BOTTOM w0.102: JHDMI1.16 12.78,90.78 12.78,92.03 14.56,93.81 14.56,95.9 16.99,98.33 26.08,98.33 27.33,97.08 v2(27.33,96.48)
DDR4_DRAMRST#: length 26
  TOP w0.102: CD29.1 60.19,62.65 RD8.1 60.9,62.63 v2(61.61,63.34)
  IN1 w0.119: v2(47.41,62.94) 48.45,63.99 61.1,63.99 61.61,63.47 v2(61.61,63.34)
  BOTTOM w0.102: JDIMM1.108 60.03,60.38 60.18,60.53 60.18,61.61 61.61,63.04 v2(61.61,63.34) ; v2(47.41,62.94) 47.41,62.18 46.81,61.58 46.32,61.58 45.62,60.87 JDIMM2.108
DDR_A_ACT#: length 49.7
  IN1 w0.188: v2(94.83,62.72) 94.83,62.79 94.42,63.2 92.11,63.2 90.25,65.06 89.63,65.06 89.06,65.63 69.53,65.63 68.73,64.84 68.02,64.84 67.48,64.3 66.51,64.3 65.87,63.66 65.87,63.16 65.61,62.89 61.94,62.89 61.33,62.29 v2(61.33,61.4)
  BOTTOM w0.076: UC1.BA55 101.6,60.01 101.38,60.01 101.37,60.02 101.36,60.02 101.36,60.02 101.27,60.06 101.07,60.06 100.98,60.02 100.98,60.02 100.62,60.02 100.55,60.09 99.73,60.09 97.88,61.95 96.68,61.95 96.53,61.8 95.75,61.8 v2(94.83,62.72)
  BOTTOM w0.17: JDIMM1.114 60.01,58.88 61.33,60.2 v2(61.33,61.4)
DDR_A_ALERT#: length 49.9
  IN1 w0.188: v2(91.01,61.21) 89.03,63.19 87.79,63.19 87.22,63.76 72.37,63.76 71.23,62.63 69.99,62.63 69.78,62.43 67.91,62.43 65.97,60.48 63.8,60.48 62.38,59.07 v2(62.38,59.06)
  BOTTOM w0.076: UC1.AW50 102.57,56.83 102.32,57.08 102.13,57.08 102.1,57.05 101.94,57 101.65,57 101.61,57.03 101.37,57.03 101.37,57.03 101.21,56.98 101.07,56.98 101.04,57 101.03,57.01 100.95,57.04 100.87,57.04 100.86,57.03 100.7,57.03 100.6,56.93 100.41,56.74 99.77,56.74 97.86,58.66 97.29,58.66 97.15,58.8 97.15,58.97 97.07,59.05 95.7,59.05 95.54,59.21 95.11,59.21 95.09,59.19 92.85,59.19 91.59,60.45 91.59,60.65
  BOTTOM w0.17: JDIMM1.116 60.25,58.38 61.44,59.56 61.88,59.56 v2(62.38,59.06) ; v2(91.01,61.21) 91.01,61.21 91.01,61.23 91.59,60.65
DDR_A_BG0: length 50.5
  IN1 w0.188: v2(62.86,61.4) 62.86,62.24 63.04,62.43 65.8,62.43 66.34,62.96 66.34,63.46 66.71,63.83 67.67,63.83 68.21,64.37 68.93,64.37 69.72,65.16 88.86,65.16 89.43,64.59 90.06,64.59 91.92,62.73 92.79,62.73 92.79,62.73 93.6,62.73 v2(93.6,62.72)
  BOTTOM w0.076: UC1.AY55 102.37,59.89 102.08,59.6 101.92,59.52 101.74,59.52 101.58,59.57 101.44,59.57 101.22,59.51 101.1,59.51 101.02,59.54 100.99,59.56 100.64,59.56 100.44,59.36 99.8,59.36 98.16,61 98.16,61.36 97.73,61.78 96.75,61.78 96.6,61.64 95.52,61.64 95.45,61.71 94.62,61.71 v2(93.6,62.72)
  BOTTOM w0.17: JDIMM1.115 66.26,58.62 65.86,59.02 65.47,59.02 64.27,60.22 64.04,60.22 v2(62.86,61.4)
DDR_A_BG1: length 50.9
  IN1 w0.188: v2(92.76,62.06) 92.55,62.26 92.28,62.26 92.08,62.06 91.49,62.06 91.15,62.39 91.15,62.83 90.93,63.06 90.49,63.06 90.25,63.3 90.25,63.74 89.86,64.13 88.18,64.13 88.09,64.22 88.09,64.6 88,64.7 71.38,64.7 71.07,64.39 71.07,63.78 70.88,63.6 70.5,63.6 70.31,63.78 70.31,64.57 70.19,64.7 69.91,64.7 69.62,64.41 69.62,63.59 69.45,63.41 69.18,63.41 68.96,63.63 68.96,63.8 68.85,63.9 68.41,63.9 67.87,63.36 66.99,63.36 66.81,63.17 66.81,62.64 65.85,61.68 65.5,61.68 65.22,61.96 64.28,61.96 64.14,61.83 64.14,61.64 v2(64.38,61.4)
  BOTTOM w0.076: UC1.AY54 102.05,59.33 101.79,59.33 101.58,59.4 101.44,59.4 101.21,59.34 101.07,59.34 100.95,59.39 100.71,59.39 100.49,59.18 99.75,59.18 97.99,60.94 97.99,61.29 97.66,61.62 96.82,61.62 96.67,61.47 93.78,61.47 93.19,62.06 v2(92.76,62.06)
  BOTTOM w0.17: JDIMM1.113 66.37,59.13 65.97,59.52 65.57,59.52 64.38,60.71 v2(64.38,61.4)
DDR_A_BS0: length 51.1
  IN1 w0.076: v2(103.61,57.22) 103.61,57.22 103.14,56.76 103.14,55.98 101.68,54.52 100.25,53.08 100.13,53.08
  IN1 w0.089: 100.13,53.08 99.31,52.26 99.07,52.26 98.71,51.9 93.27,51.9 92.29,52.89
  IN1 w0.188: 92.29,52.89 91.48,53.7 80.01,53.7 76.21,49.9 70.36,49.9 69.99,49.53 67.13,49.53 66.73,49.12 62.26,49.12 v2(60.85,47.71)
  BOTTOM w0.076: v2(103.61,57.22) 103.61,57.23 103.96,57.58 UC1.AU52
  BOTTOM w0.17: v2(60.85,47.71) 60.69,47.87 JDIMM1.150
DDR_A_BS1: length 51.3
  IN1 w0.076: 95.43,53.14 98.49,53.14 98.6,53.25 100.08,53.25 102.94,56.11 102.94,57.29 103.31,57.66 103.8,57.66 103.99,57.47 103.99,56.62 v2(104.29,56.32)
  IN1 w0.089: 95.43,53.14 95.19,53.14
  IN1 w0.188: 95.19,53.14 93.91,53.14 92.88,54.17 79.82,54.17 79.43,53.78 79.28,53.78 78.89,54.17 78.66,54.17 78.37,53.87 78.37,53.61 78.68,53.3 78.68,53.03 78.41,52.76 78.15,52.76 77.84,53.07 77.57,53.07 77.3,52.81 77.3,52.54 77.61,52.23 77.61,51.97 77.35,51.7 77.08,51.7 76.77,52.01 76.51,52.01 76.24,51.74 76.24,51.48 76.55,51.17 76.55,50.9 76.28,50.64 76.02,50.64 75.71,50.95 75.44,50.95 74.86,50.37 70.17,50.37 69.79,49.99 66.94,49.99 66.53,49.59 v2(65.42,49.59)
  BOTTOM w0.076: UC1.AT48 104.29,56.21 v2(104.29,56.32)
  BOTTOM w0.17: v2(65.42,49.59) 65.6,49.41 66.02,49.41 66.31,49.13 JDIMM1.145
DDR_A_CAS#: length 51.8
  IN1 w0.076: v2(103.67,55.41) 103.99,55.09 103.99,54.15 103.89,54.05 103.37,54.05 103.25,54.17 102.42,54.17 102.25,53.99 102.25,52.63 101.12,51.5 100.06,51.5 99.54,50.98 99.25,50.98 99.03,51.21 97.98,51.21 97.95,51.24 91.49,51.24 90.9,51.83
  IN1 w0.188: 90.9,51.83 82.91,51.83 79.11,48.03 71.14,48.03 70.76,47.66 67.91,47.66 67.5,47.25 62.82,47.25 v2(62.37,46.8)
  BOTTOM w0.076: v2(103.67,55.41) 103.96,55.71 UC1.AU48
  BOTTOM w0.17: JDIMM1.156 59.85,46.38 59.92,46.3 61.75,46.3 62.25,46.8 v2(62.37,46.8)
DDR_A_CKE0: length 48.8
  IN1 w0.188: v2(96.02,62.72) 96.02,62.83 95.19,63.66 92.31,63.66 90.44,65.53 89.82,65.53 89.25,66.1 68.14,66.1 67.9,65.85 67.41,65.85 67.32,65.76 67.32,65.5 67.52,65.3 67.52,65.03 67.29,64.81 66.95,64.81 66.79,64.97 66.52,64.97 66.24,64.68 65.81,64.68 65.62,64.49 65.62,64.1 65.44,63.91 65.1,63.91 64.87,64.14 64.87,64.49 64.68,64.68 64.51,64.68 64.07,64.24 64.07,63.93 v2(64.66,63.34)
  BOTTOM w0.076: v2(96.02,62.72) 96.23,62.51 97.04,62.51 97.37,62.85 97.68,62.85 97.91,62.61 97.91,62.61 99.94,60.59 100.58,60.59 100.64,60.65 100.64,60.65 100.7,60.71 100.99,60.71 101.14,60.61 101.34,60.61 UC1.BA56
  BOTTOM w0.17: JDIMM1.109 66.37,60.13 66.05,60.45 66.05,61.48 64.66,62.86 v2(64.66,63.34)
DDR_A_CKE1: length 48.1
  IN1 w0.188: v2(97.53,62.48) 95.88,64.13 92.5,64.13 90.64,66 90.02,66 89.44,66.57 67.95,66.57 67.7,66.32 67.21,66.32 66.04,65.15 64.32,65.15 63.14,63.97 v2(63.14,63.34)
  BOTTOM w0.076: UC1.BB56 100.82,60.43 99.87,60.43 97.81,62.48 v2(97.53,62.48)
  BOTTOM w0.17: v2(63.14,63.34) 61.8,62.01 61.3,62.01 60.65,61.35 60.65,60.34 60.19,59.88 JDIMM1.110
DDR_A_CKE2: length 7.5
  BOTTOM w0.076: UC1.AW56 102.53,60.19 101.39,60.19 101.3,60.22 101.04,60.22 100.94,60.19 100.69,60.19 100.62,60.26 99.8,60.26 97.95,62.11 96.52,62.11 96.51,62.11 TP3.1
DDR_A_CKE3: length 6.3
  BOTTOM w0.076: TP4.1 97.68,63.09 98.08,62.68 100.01,60.76 100.51,60.76 100.63,60.88 101.05,60.88 101.17,60.79 101.7,60.79 UC1.AY56
DDR_A_CLK0: length 50.7
  IN1 w0.076: 93.64,56.37 101.05,56.37 103.22,58.53 103.99,58.53 104.17,58.71 104.17,58.88 v2(104.38,59.08)
  IN1 w0.119: v2(63.91,52.64) 64.17,52.38 64.17,52.16 64.42,51.91 65.94,51.91 66.51,52.48 72.85,52.48 73.22,52.85 73.39,52.85 73.7,52.54 74.11,52.54 74.43,52.86 74.43,53.27 74.12,53.58 74.12,53.75 74.37,54 74.54,54 74.85,53.69 75.2,53.69 75.59,54.07 75.59,54.42 75.27,54.73 75.27,54.9 76.6,56.23 93.51,56.23 93.64,56.37
  BOTTOM w0.076: v2(104.38,59.08) 104.38,58.86 UC1.AT53
  BOTTOM w0.102: v2(63.91,52.64) 64.14,52.86 64.14,53 64.45,53.32 66.11,53.32 66.3,53.13 JDIMM1.137
DDR_A_CLK1: length 50.7
  IN1 w0.076: v2(104.27,60) 104.11,60.15 104.11,60.37 103.93,60.55 103.27,60.55 102.92,60.21 102.89,60.21 102.88,60.19
  IN1 w0.119: 102.88,60.19 101.32,58.63 100.01,58.63 98.77,57.39 92.98,57.39 92.88,57.29 76.16,57.29 72.43,53.57 66.09,53.57 65.89,53.36 62.02,53.36 61.78,53.12 61.78,52.8 v2(61.61,52.64)
  BOTTOM w0.076: UC1.AT55 v2(104.27,60)
  BOTTOM w0.102: v2(61.61,52.64) 61.83,52.42 61.83,52.28 61.64,52.09 60.79,52.09 60.3,52.58 60.12,52.58 59.83,52.87 JDIMM1.138
DDR_A_CLK#0: length 50.8
  IN1 w0.076: 93.49,56.52 93.5,56.53 93.51,56.53 93.52,56.52 93.56,56.56 93.67,56.57 93.67,56.56 93.72,56.56 93.75,56.54 100.98,56.54 103.14,58.7 103.93,58.7 104.01,58.78 104.01,59.26 103.93,59.33 103.78,59.33 103.62,59.18 v2(103.62,59.08)
  IN1 w0.119: v2(64.66,52.64) 64.39,52.37 64.39,52.25 64.51,52.13 65.85,52.13 66.42,52.7 72.76,52.7 73.13,53.07 73.48,53.07 73.79,52.75 74.02,52.75 74.21,52.95 74.21,53.18 73.9,53.49 73.9,53.84 74.28,54.22 74.63,54.22 74.94,53.91 75.11,53.91 75.37,54.16 75.37,54.33 75.05,54.64 75.05,54.99 76.51,56.45 93.41,56.45 93.49,56.52
  BOTTOM w0.076: v2(103.62,59.08) 103.96,58.74 UC1.AU53
  BOTTOM w0.102: JDIMM1.139 66.35,52.62 66.19,52.79 66.19,52.95 66.02,53.11 64.53,53.11 64.34,52.92 64.34,52.77 64.48,52.64 v2(64.66,52.64)
DDR_A_CLK#1: length 50.6
  IN1 w0.076: 103.03,60.04 103.04,60.04 103.04,60.07 103.08,60.11 103.34,60.38 103.86,60.38 103.94,60.3 103.94,60.19 103.74,60 v2(103.63,60)
  IN1 w0.119: 103.03,60.04 101.41,58.42 100.1,58.42 98.86,57.17 93.07,57.17 92.97,57.08 76.25,57.08 72.52,53.35 66.19,53.35 65.98,53.15 62.11,53.15 61.99,53.03 61.99,52.84 62.2,52.64 v2(62.37,52.64)
  BOTTOM w0.076: UC1.AU55 v2(103.63,60)
  BOTTOM w0.102: JDIMM1.140 60.22,52.38 60.7,51.89 61.73,51.89 62.03,52.19 62.03,52.3 v2(62.37,52.64)
DDR_A_CS#0: length 52.8
  IN1 w0.076: 90.94,52.3 91.83,51.4 98.02,51.4 98.05,51.37 98.89,51.37 99.28,51.76 101.13,51.76 102.07,52.7 102.07,54.07 102.42,54.42 v2(103.62,54.42)
  IN1 w0.188: 90.94,52.3 82.72,52.3 82.07,51.64 81.63,51.64 80.98,52.3 80.59,52.3 80.33,52.04 80.33,51.77 81.13,50.98 81.13,50.71 80.87,50.44 80.6,50.44 79.8,51.24 79.54,51.24 79.27,50.98 79.27,50.71 80.07,49.91 80.07,49.65 79.8,49.38 79.54,49.38 78.74,50.18 78.47,50.18 78.21,49.91 78.21,49.65 78.82,49.03 78.82,48.77 78.56,48.5 78.29,48.5 77.67,49.11 77.41,49.11 76.79,48.5 70.94,48.5 70.57,48.12 67.71,48.12 67.3,47.71 v2(65.42,47.71)
  BOTTOM w0.076: UC1.AU45 103.96,54.08 v2(103.62,54.42)
  BOTTOM w0.17: JDIMM1.149 65.83,48.13 v2(65.42,47.71)
DDR_A_CS#1: length 55.1
  IN1 w0.076: 97.19,50.9 97.82,50.9 97.85,50.88 98.89,50.88 99.12,50.65 100.77,50.65 103.64,53.52 v2(103.65,53.52)
  IN1 w0.089: 89.55,50.89 92.18,50.89 92.18,50.9 97.19,50.9
  IN1 w0.188: 89.55,50.89 83.3,50.89 78.04,45.64 75.94,45.64 75.75,45.82 75.75,46.95 75.61,47.1 75.15,47.1 75,46.95 75,45.17 74.86,45.03 74.39,45.03 74.25,45.17 74.25,46.95 74.1,47.1 73.64,47.1 73.5,46.95 73.5,45.17 73.36,45.03 72.89,45.03 72.75,45.17 72.75,46.95 72.6,47.1 71.52,47.1 71.15,46.72 69.93,46.72 69.41,46.21 65.37,46.21 65.02,45.86 v2(64.66,45.86)
  BOTTOM w0.076: UC1.AU43 103.65,53.45 v2(103.65,53.52)
  BOTTOM w0.17: v2(64.66,45.86) 65.87,45.86 66.14,46.13 JDIMM1.157
DDR_A_D0: length 67.8
  IN1 w0.119: v2(62.37,85.66) 62.79,86.07 67.32,86.07 70.17,88.93 90.37,88.93 91.53,87.77 93.5,87.77 94.13,87.14 102.82,87.14 108.86,81.1 108.86,74.65 v2(107.49,73.29)
  BOTTOM w0.076: v2(107.49,73.29) 107.11,72.9 107.11,71.75 107.65,71.21 107.65,69.19 UC1.AL71
  BOTTOM w0.102: v2(62.37,85.66) 62.37,85.83 61.67,86.53 60.17,86.53 60.02,86.37 JDIMM1.4
DDR_A_D1: length 69.3
  IN1 w0.119: v2(63.9,85.66) 64.31,85.24 65.94,85.24 66.06,85.12 66.06,84.73 66.18,84.61 66.42,84.61 66.54,84.73 66.54,85.12 66.66,85.24 66.9,85.24 67.02,85.12 67.02,84.73 67.14,84.61 67.38,84.61 67.5,84.73 67.5,85.12 67.62,85.24 68.93,85.24 71.59,87.91 90.45,87.91 91.25,87.1 93.22,87.1 93.86,86.47 102.54,86.47 107.91,81.1 107.91,77.45 v2(107.49,77.03)
  BOTTOM w0.076: v2(107.49,77.03) 106.76,76.3 106.76,73.31 106.57,73.12 106.57,69.59 106.78,69.39 106.78,69.02 106.76,68.99 106.73,68.91 106.73,68.79 106.79,68.57 106.79,68.43 106.74,68.27 106.74,68.09 106.78,68.01 106.78,67.53 106.79,67.41 106.97,67.22 107.14,67.21 UC1.AL68
  BOTTOM w0.102: JDIMM1.3 64.72,86.62 63.9,85.8 v2(63.9,85.66)
DDR_A_D2: length 70.1
  IN1 w0.119: v2(105.85,75.84) 105.85,75.86 105.41,76.3 105.41,80.31 101.46,84.26 92.95,84.26 92.35,84.86 78.16,84.86 78.04,84.98 78.04,85.52 77.92,85.64 77.68,85.64 77.56,85.52 77.56,84.98 77.45,84.86 77.21,84.86 77.09,84.98 77.09,85.52 76.97,85.64 76.73,85.64 76.61,85.52 76.61,84.98 76.49,84.86 76.25,84.86 76.13,84.98 76.13,85.52 76.01,85.64 75.77,85.64 75.65,85.52 75.65,84.98 75.54,84.86 75.3,84.86 75.18,84.98 75.18,85.52 75.06,85.64 74.82,85.64 74.7,85.52 74.7,84.98 74.58,84.86 74.33,84.86 74.21,84.98 74.21,85.43 74.09,85.55 73.85,85.55 73.73,85.43 73.73,84.98 73.61,84.86 73.11,84.86 70.49,82.24 68.11,82.24 68.03,82.32 63.21,82.32 v2(62.4,83.13)
  BOTTOM w0.076: UC1.AN68 106.16,67.73 106.12,67.94 106.15,68.04 106.17,68.15 106.12,68.32 105.91,68.52 105.91,69.31 105.91,69.31 105.91,73.29 105.48,73.73 105.48,75.46 v2(105.85,75.84)
  BOTTOM w0.102: v2(62.4,83.13) 61.52,82.25 60.05,82.25 59.93,82.37 JDIMM1.20
DDR_A_D3: length 69.1
  IN1 w0.119: v2(63.93,83.13) 64.4,82.66 68.17,82.66 68.25,82.57 70.35,82.57 73.88,86.1 78.26,86.1 78.38,85.98 78.38,85.48 78.5,85.36 78.74,85.36 78.86,85.48 78.86,85.98 78.97,86.1 79.21,86.1 79.33,85.98 79.33,85.48 79.45,85.36 79.69,85.36 79.81,85.48 79.81,85.98 79.93,86.1 80.17,86.1 80.29,85.98 80.29,85.48 80.41,85.36 80.65,85.36 80.77,85.48 80.77,85.98 80.88,86.1 81.12,86.1 81.24,85.98 81.24,85.48 81.36,85.36 81.6,85.36 81.72,85.48 81.72,85.98 81.84,86.1 82.08,86.1 82.2,85.98 82.2,85.48 82.32,85.36 82.56,85.36 82.68,85.48 82.68,85.98 82.79,86.1 83.03,86.1 83.15,85.98 83.15,85.41 83.27,85.29 92.39,85.29 93.09,84.6 101.6,84.6 105.83,80.37 v2(105.83,77.04)
  BOTTOM w0.076: UC1.AN69 106.54,67.96 106.54,68.22 106.62,68.44 106.62,68.57 106.55,68.8 106.55,68.96 106.61,69.08 106.61,69.32 106.4,69.53 106.4,73.19 106.6,73.38 106.6,76.27 v2(105.83,77.04)
  BOTTOM w0.102: JDIMM1.21 64.93,82.13 v2(63.93,83.13)
DDR_A_D4: length 68.8
  IN1 w0.119: v2(107.49,72.01) 109.19,73.71 109.19,81.23 102.96,87.47 94.27,87.47 93.64,88.11 91.67,88.11 90.5,89.27 70.04,89.27 67.18,86.41 61.6,86.41 v2(60.85,85.66)
  BOTTOM w0.076: UC1.AL70 107.67,68.66 107.84,68.84 107.9,68.96 107.92,69.04 107.92,69.32 107.81,69.43 107.81,71.69 v2(107.49,72.01)
  BOTTOM w0.102: JDIMM1.8 60.1,85.37 60.38,85.66 v2(60.85,85.66)
DDR_A_D5: length 69.3
  IN1 w0.119: v2(65.42,85.66) 68.87,85.66 69.34,86.13 71.45,88.24 71.8,88.24 71.92,88.36 71.92,88.47 72.04,88.59 72.28,88.59 72.4,88.47 72.4,88.36 72.52,88.24 72.76,88.24 72.88,88.36 72.88,88.47 73,88.59 73.24,88.59 73.36,88.47 73.36,88.36 73.47,88.24 73.71,88.24 73.83,88.36 73.83,88.47 73.95,88.59 74.19,88.59 74.31,88.47 74.31,88.36 74.43,88.24 74.67,88.24 74.79,88.36 74.79,88.47 74.91,88.59 75.15,88.59 75.27,88.47 75.27,88.36 75.38,88.24 75.62,88.24 75.74,88.36 75.74,88.47 75.86,88.59 76.1,88.59 76.22,88.47 76.22,88.36 76.34,88.24 76.58,88.24 76.7,88.36 76.7,88.47 76.82,88.59 77.06,88.59 77.18,88.47 77.18,88.36 77.29,88.24 77.53,88.24 77.65,88.36 77.65,88.47 77.77,88.59 78.01,88.59 78.13,88.47 78.13,88.36 78.25,88.24 78.49,88.24 78.61,88.36 78.61,88.47 78.73,88.59 78.97,88.59 79.09,88.47 79.09,88.36 79.21,88.24 79.44,88.24 79.56,88.36 79.56,88.47 79.68,88.59 79.92,88.59 80.04,88.47 80.04,88.36 80.16,88.24 80.4,88.24 80.52,88.36 80.52,88.47 80.64,88.59 80.88,88.59 81,88.47 81,88.36 81.12,88.24 81.35,88.24 81.47,88.36 81.47,88.47 81.59,88.59 81.83,88.59 81.95,88.47 81.95,88.36 82.07,88.24 82.31,88.24 82.43,88.36 82.43,88.47 82.55,88.59 82.79,88.59 82.91,88.47 82.91,88.36 83.03,88.24 83.26,88.24 83.38,88.36 83.38,88.47 83.5,88.59 83.74,88.59 83.86,88.47 83.86,88.36 83.98,88.24 84.22,88.24 84.34,88.36 84.34,88.47 84.46,88.59 84.7,88.59 84.82,88.47 84.82,88.36 84.94,88.24 85.3,88.24 85.42,88.36 85.42,88.47 85.54,88.59 85.78,88.59 85.9,88.47 85.9,88.36 86.02,88.24 90.58,88.24 91.39,87.44 93.36,87.44 93.99,86.8 102.68,86.8 108.52,80.96 108.52,74.95 v2(107.49,73.92)
  BOTTOM w0.076: v2(107.49,73.92) 107.98,73.43 107.98,69.51 108.09,69.4 108.09,69.01 108.08,68.97 108.06,68.9 108.05,68.82 108.01,68.69 108.01,68.69 107.94,68.5 107.94,68.33 107.67,68.07 UC1.AL69
  BOTTOM w0.102: JDIMM1.7 66.39,85.62 66.3,85.53 65.55,85.53 v2(65.42,85.66)
DDR_A_D6: length 67.8
  IN1 w0.119: v2(105.89,73.99) 103.18,76.7 103.18,82.06 101.32,83.93 92.81,83.93 92.21,84.52 78.19,84.52 78.07,84.41 78.07,83.89 77.95,83.77 77.71,83.77 77.59,83.89 77.59,84.41 77.47,84.52 77.24,84.52 77.12,84.41 77.12,83.89 77,83.77 76.76,83.77 76.64,83.89 76.64,84.41 76.52,84.52 76.28,84.52 76.16,84.41 76.16,83.89 76.04,83.77 75.8,83.77 75.68,83.89 75.68,84.41 75.56,84.52 75.33,84.52 75.21,84.41 75.21,83.89 75.09,83.77 74.85,83.77 74.73,83.89 74.73,84.41 74.61,84.52 74.37,84.52 74.25,84.41 74.25,83.89 74.13,83.77 73.89,83.77 73.77,83.89 73.77,84.41 73.65,84.52 73.25,84.52 70.63,81.9 67.74,81.9 67.66,81.99 62.02,81.99 v2(60.88,83.13)
  BOTTOM w0.076: UC1.AN70 106.08,68.78 106.08,69.34 106.07,69.34 106.07,73.87 105.95,73.99 v2(105.89,73.99)
  BOTTOM w0.102: v2(60.88,83.13) 60.79,83.22 60.03,83.22 59.88,83.37 JDIMM1.16
DDR_A_D7: length 66.8
  IN1 w0.119: v2(65.45,83.13) 68.17,83.13 68.39,82.91 70.21,82.91 73.74,86.43 83.73,86.43 83.85,86.31 83.85,85.75 83.97,85.63 84.21,85.63 84.33,85.75 84.33,86.31 84.45,86.43 84.69,86.43 84.81,86.31 84.81,85.75 84.93,85.63 85.17,85.63 85.29,85.75 85.29,86.31 85.41,86.43 85.64,86.43 85.76,86.31 85.76,85.75 85.88,85.63 86.12,85.63 86.24,85.75 86.24,86.31 86.36,86.43 86.6,86.43 86.72,86.31 86.72,85.75 86.84,85.63 87.08,85.63 87.2,85.75 87.2,86.31 87.32,86.43 87.55,86.43 87.67,86.31 87.67,85.75 87.79,85.63 88.03,85.63 88.15,85.75 88.15,86.31 88.27,86.43 88.51,86.43 88.63,86.31 88.63,85.75 88.75,85.63 88.99,85.63 89.11,85.75 89.11,86.31 89.23,86.43 89.46,86.43 89.58,86.31 89.58,85.75 89.7,85.63 92.53,85.63 93.23,84.93 101.74,84.93 106.26,80.41 106.26,78.54 106.27,78.53 106.27,75.57 105.92,75.21 v2(105.85,75.21)
  BOTTOM w0.076: v2(105.85,75.21) 105.92,75.21 106.43,74.7 106.43,73.45 106.24,73.26 106.24,69.37 106.34,69.27 UC1.AN71
  BOTTOM w0.102: JDIMM1.17 65.67,83.13 65.66,83.13 v2(65.45,83.13)
DDR_A_D8: length 58.8
  IN1 w0.119: v2(65.42,80.27) 65.49,80.34 66.78,80.34 66.85,80.27 69.91,80.27 70.03,80.15 70.03,79.98 70.15,79.86 70.39,79.86 70.51,79.98 70.51,80.15 70.63,80.27 71.96,80.27 72.81,81.12 80.83,81.12 80.95,81.24 80.95,82.71 81.07,82.83 81.3,82.83 81.42,82.71 81.42,81.24 81.54,81.12 81.85,81.12 81.97,81.24 81.97,82.71 82.08,82.83 82.32,82.83 82.44,82.71 82.44,81.48 82.56,81.36 82.9,81.36 83.01,81.48 83.01,82.25 83.24,82.48 91.02,82.48 97.61,75.89 98.53,75.89 99.11,75.3 102.27,75.3 103.9,73.67 103.9,73.44 104.16,73.18 v2(104.74,73.18)
  BOTTOM w0.076: UC1.AR70 105.31,68.66 105.58,68.93 105.58,69.25 105.58,69.25 105.58,73.08 105.24,73.42 104.97,73.42 v2(104.74,73.18)
  BOTTOM w0.102: v2(65.42,80.27) 65.57,80.13 JDIMM1.29
DDR_A_D9: length 60.6
  IN1 w0.119: v2(63.9,80.27) 64.31,80.69 66.99,80.69 67.07,80.61 71.82,80.61 72.67,81.45 79.37,81.45 79.66,81.74 79.66,82.77 79.78,82.89 80.01,82.89 80.13,82.77 80.13,81.68 80.25,81.56 80.49,81.56 80.61,81.68 80.61,82.85 80.93,83.16 90.81,83.16 97.75,76.22 98.66,76.22 99.24,75.65 102.39,75.65 104.32,73.73 v2(104.32,73.61)
  BOTTOM w0.076: UC1.AR68 105.22,67.41 105.54,67.74 105.54,67.77 105.55,67.86 105.54,67.92 105.49,68.03 105.48,68.09 105.51,68.24 105.75,68.52 105.75,69.28 105.74,69.28 105.74,73.22 105.08,73.89 104.59,73.89 v2(104.32,73.61)
  BOTTOM w0.102: v2(63.9,80.27) 63.9,80.32 64.74,81.16 66.15,81.16 66.19,81.13 JDIMM1.25
DDR_A_D10: length 57.2
  IN1 w0.119: v2(102.96,71.16) 102.96,72.04 101.51,73.49 98.25,73.49 97.67,74.08 96.86,74.08 90.81,80.13 90.35,80.13 89.53,79.31 88.42,79.31 88.3,79.43 88.3,80.52 88.15,80.67 87.91,80.67 87.79,80.55 87.79,79.43 87.67,79.31 87.43,79.31 87.31,79.43 87.31,80.55 87.19,80.67 86.95,80.67 86.83,80.55 86.83,79.43 86.71,79.31 86.48,79.31 86.36,79.43 86.36,80.55 86.24,80.67 86,80.67 85.88,80.55 85.88,79.43 85.76,79.31 85.52,79.31 85.4,79.43 85.4,80.55 85.28,80.67 85.04,80.67 84.92,80.55 84.92,79.43 84.8,79.31 73.56,79.31 71.84,77.59 65.61,77.59 v2(65.42,77.4)
  BOTTOM w0.076: UC1.AU71 103.88,69.27 103.88,70.24 v2(102.96,71.16)
  BOTTOM w0.102: v2(65.42,77.4) 65.63,77.61 65.89,77.61 66.41,78.13 JDIMM1.37
DDR_A_D11: length 59.7
  IN1 w0.119: v2(63.9,77.4) 64.42,77.92 69.63,77.92 69.75,78.04 69.75,78.27 69.87,78.39 70.11,78.39 70.23,78.27 70.23,78.04 70.35,77.92 70.59,77.92 70.71,78.04 70.71,78.27 70.83,78.39 71.07,78.39 71.19,78.27 71.19,78.04 71.31,77.92 71.7,77.92 73.42,79.64 83.54,79.64 84.9,81 88.52,81 88.64,80.88 88.64,79.76 88.75,79.64 88.99,79.64 89.11,79.76 89.11,80.8 89.23,80.92 89.47,80.92 89.59,80.8 89.59,80.6 89.71,80.48 90.93,80.48 97,74.41 97.91,74.41 98.5,73.83 101.49,73.83 v2(101.67,74.01)
  BOTTOM w0.076: UC1.AU68 104.36,67.21 104.79,67.23 104.91,67.34 104.99,67.49 104.99,67.56 104.92,67.75 104.94,68.21 104.87,68.43 104.87,68.57 104.93,68.79 104.93,68.91 104.9,68.99 104.88,69.02 104.88,69.39 105.08,69.59 105.08,70.27 104.58,70.77 104.58,72.62 103.18,74.02 101.68,74.02 v2(101.67,74.01)
  BOTTOM w0.102: v2(63.9,77.4) 64.33,76.97 66.24,76.97 66.39,77.13 JDIMM1.41
DDR_A_D12: length 57.6
  IN1 w0.119: v2(62.37,80.27) 63.12,81.02 67.19,81.02 67.27,80.94 71.68,80.94 72.53,81.79 78.8,81.79 79.32,82.31 79.32,83.01 79.81,83.5 91.88,83.5 92.51,82.87 92.51,82.67 98.62,76.56 98.82,76.56 99.39,75.99 102.53,75.99 105.44,73.08 105.44,72.5 105.04,72.1 v2(105.04,72.08)
  BOTTOM w0.076: v2(105.04,72.08) 105.34,72.08 105.41,72 105.41,69.26 UC1.AR71
  BOTTOM w0.102: JDIMM1.24 61.32,81.37 62.37,80.32 v2(62.37,80.27)
DDR_A_D13: length 58.7
  IN1 w0.119: v2(60.85,80.27) 61.94,81.36 67.4,81.36 67.48,81.28 71.54,81.28 72.38,82.12 77.49,82.12 79.2,83.83 92.02,83.83 92.85,83.01 92.85,82.81 98.73,76.92 98.93,76.92 99.53,76.32 102.67,76.32 105.78,73.22 105.78,71.56 105.06,70.83 v2(105.04,70.83)
  BOTTOM w0.076: UC1.AR69 105.11,67.96 105.11,68.22 105.04,68.44 105.04,68.57 105.1,68.8 105.1,68.9 105.11,68.91 105.05,69.06 105.05,69.32 105.25,69.52 105.25,70.63 v2(105.04,70.83)
  BOTTOM w0.102: JDIMM1.28 60.75,80.37 v2(60.85,80.27)
DDR_A_D14: length 57.3
  IN1 w0.119: v2(102.08,72.02) 102.08,72.45 101.37,73.16 98.12,73.16 97.53,73.74 95.94,73.74 90.71,78.97 75.72,78.97 75.53,78.79 75.53,77.69 75.42,77.57 75.18,77.57 75.06,77.69 75.06,78.85 74.94,78.97 74.52,78.97 74.4,78.85 74.4,77.69 74.28,77.57 74.04,77.57 73.92,77.69 73.92,78.77 73.8,78.89 73.62,78.89 71.98,77.25 66.01,77.25 65.26,76.5 63.28,76.5 v2(62.37,77.4)
  BOTTOM w0.076: v2(102.08,72.02) 102.08,71.46 103.15,70.4 103.42,70.4 103.71,70.11 103.71,68.79 UC1.AU70
  BOTTOM w0.102: v2(62.37,77.4) 61.59,76.62 60.11,76.62 59.86,76.88 JDIMM1.42
DDR_A_D15: length 58.1
  IN1 w0.119: v2(101.57,72.37) 101.12,72.82 97.98,72.82 97.39,73.41 95.8,73.41 90.8,78.41 79.26,78.41 78.09,77.24 77.42,77.24 77.3,77.36 77.3,78.52 77.18,78.64 76.94,78.64 76.83,78.52 76.83,77.36 76.71,77.24 76.47,77.24 76.35,77.36 76.35,78.52 76.23,78.64 75.99,78.64 75.87,78.52 75.87,77.36 75.75,77.24 72.82,77.24 72.5,76.92 66.15,76.92 65.39,76.17 61.04,76.17 60.72,76.48 60.72,77.28 v2(60.85,77.4)
  BOTTOM w0.076: v2(101.57,72.37) 101.57,71.74 103.08,70.23 103.35,70.23 103.53,70.05 103.53,68.71 103.61,68.63 103.61,68.45 103.99,68.07 UC1.AU69
  BOTTOM w0.102: JDIMM1.38 59.95,77.88 60.42,77.4 v2(60.85,77.4)
DDR_A_D16: length 50.9
  IN1 w0.119: v2(63.9,75.12) 64.31,74.7 72.18,74.7 73.42,75.94 80.95,75.94 81.07,76.06 81.07,76.99 81.19,77.11 81.43,77.11 81.55,76.99 81.55,76.06 81.67,75.94 81.84,75.94 82.97,77.08 90.3,77.08 95.26,72.11 96.85,72.11 98.53,70.43 v2(98.53,70.07)
  BOTTOM w0.076: v2(98.53,70.07) 98.33,69.86 98.33,69.38 99.25,68.46 99.25,67.32 99.32,67.25 99.32,66.27 100.09,65.5 100.76,65.5 UC1.BB65
  BOTTOM w0.102: JDIMM1.45 66.37,76.13 66.21,75.97 64.75,75.97 v2(63.9,75.12)
DDR_A_D17: length 52.6
  IN1 w0.119: v2(98.55,68.07) 98.55,68.67 99.18,69.3 99.18,70.26 96.99,72.45 95.4,72.45 90.4,77.45 80.61,77.45 80.49,77.33 80.49,76.4 80.38,76.28 80.14,76.28 80.02,76.4 80.02,77.33 79.9,77.45 79.66,77.45 79.54,77.33 79.54,76.4 79.42,76.28 73.22,76.28 72.8,75.85 66.44,75.85 65.71,75.12 v2(65.42,75.12)
  BOTTOM w0.076: v2(98.55,68.07) 98.55,67.31 98.82,67.04 98.82,66.06 99.55,65.34 99.55,64.72 99.84,64.43 100.45,64.43 100.52,64.5 101.02,64.5 101.1,64.47 101.22,64.47 101.44,64.53 101.58,64.53 101.74,64.48 101.97,64.48 102.01,64.51 102.61,64.51 102.8,64.7 UC1.AW65
  BOTTOM w0.102: JDIMM1.49 65.43,75.13 v2(65.42,75.12)
DDR_A_D18: length 54
  IN1 w0.119: v2(95.51,69.49) 95.03,69 94.86,69 92.76,71.11 92.37,71.11 90.09,73.38 89.14,73.38 89.03,73.5 89.03,74.45 88.88,74.6 88.69,74.6 88.55,74.46 88.55,73.5 88.43,73.38 88.19,73.38 88.07,73.5 88.07,74.45 87.93,74.6 87.74,74.6 87.59,74.45 87.59,73.5 87.47,73.38 76.93,73.38 76.21,72.66 74.52,72.66 74.08,72.22 66.37,72.22 65.59,71.45 64.31,71.45 v2(63.9,71.87)
  BOTTOM w0.076: v2(95.51,69.49) 95.51,69.48 95.51,68.63 96.63,67.51 97.42,67.51 98.16,66.77 98.16,65.79 98.89,65.06 98.89,64.45 99.56,63.77 100.52,63.77 100.63,63.66 101.52,63.66 101.72,63.87 101.86,63.88 101.99,63.88 102.12,63.86 102.28,63.86 102.29,63.87 102.29,63.87 102.6,64.18 UC1.AW63
  BOTTOM w0.102: v2(63.9,71.87) 64.52,71.25 65.93,71.25 66.31,71.62 JDIMM1.63
DDR_A_D19: length 52.7
  IN1 w0.119: v2(97.96,68.22) 97.96,68.61 97.68,68.89 97.26,68.89 95.85,70.3 94.51,70.3 93.04,71.78 92.65,71.78 89.16,75.27 84.53,75.27 84.05,74.78 84.05,74.17 83.93,74.05 83.76,74.05 83.64,74.17 83.64,74.71 83.52,74.83 83.28,74.83 83.16,74.71 83.16,74.17 83.05,74.05 76.53,74.05 75.8,73.33 74.24,73.33 73.8,72.89 65.95,72.89 65.34,72.28 61.27,72.28 v2(60.85,71.87)
  BOTTOM w0.076: UC1.AY63 102.05,64.28 101.79,64.28 101.58,64.36 101.44,64.36 101.21,64.29 101.07,64.29 100.98,64.34 100.59,64.34 100.52,64.26 99.77,64.26 99.38,64.65 99.38,65.27 98.65,66 98.65,66.98 97.96,67.67 v2(97.96,68.22)
  BOTTOM w0.102: v2(60.85,71.87) 59.84,72.88 JDIMM1.58
DDR_A_D20: length 51.5
  IN1 w0.119: v2(60.85,75.12) 60.49,75.12 60.37,75 60.37,74.49 60.49,74.37 73.19,74.37 73.63,74.8 75.19,74.8 75.92,75.53 81.9,75.53 83.11,76.74 90.16,76.74 95.12,71.78 96.71,71.78 98.09,70.4 98.09,69.92 98.57,69.44 98.74,69.44 v2(98.76,69.47)
  BOTTOM w0.076: v2(98.76,69.47) 98.76,69.18 99.41,68.53 99.41,67.38 99.48,67.32 99.48,66.34 100.16,65.66 100.98,65.66 101.2,65.56 101.2,65.55 101.21,65.55 101.35,65.41 UC1.BA65
  BOTTOM w0.102: v2(60.85,75.12) 60.57,75.12 60.33,74.88 JDIMM1.50
DDR_A_D21: length 51.9
  IN1 w0.119: v2(99.51,69.05) 99.51,69.05 99.51,70.4 97.13,72.78 95.54,72.78 90.54,77.78 79.52,77.78 78.35,76.61 73.08,76.61 72.66,76.18 66.3,76.18 65.65,75.54 62.79,75.54 v2(62.37,75.12)
  BOTTOM w0.076: UC1.AY65 101.94,65.41 101.68,65.67 101.4,65.67 101.26,65.73 101.23,65.73 101.02,65.83 100.23,65.83 99.65,66.41 99.65,68.91 v2(99.51,69.05)
  BOTTOM w0.102: v2(62.37,75.12) 61.54,75.96 60.28,75.96 60.2,75.88 JDIMM1.46
DDR_A_D22: length 52.5
  IN1 w0.119: v2(65.42,71.87) 66.11,72.56 73.94,72.56 74.38,73 76.04,73 76.76,73.72 84.27,73.72 84.38,73.84 84.38,74.64 84.5,74.76 84.74,74.76 84.86,74.64 84.86,73.84 84.98,73.72 85.23,73.72 85.35,73.84 85.35,74.71 85.47,74.83 85.71,74.83 85.83,74.71 85.83,73.84 85.94,73.72 86.18,73.72 86.3,73.84 86.3,74.71 86.42,74.83 86.66,74.83 86.78,74.71 86.78,73.84 86.9,73.72 87.14,73.72 87.26,73.84 87.26,74.81 87.38,74.93 89.02,74.93 92.51,71.44 92.9,71.44 94.37,69.97 95.71,69.97 96.36,69.32 96.36,68.7 v2(96.38,68.68)
  BOTTOM w0.076: v2(96.38,68.68) 96.13,68.43 96.13,68.24 96.69,67.67 97.49,67.67 98.32,66.84 98.32,65.86 99.05,65.13 99.05,64.52 99.63,63.93 100.59,63.93 100.7,63.83 101.03,63.83 101.29,64.08 UC1.BA63
  BOTTOM w0.102: v2(65.42,71.87) 65.42,72.07 65.98,72.62 JDIMM1.59
DDR_A_D23: length 51.5
  IN1 w0.119: v2(62.37,71.87) 62.2,71.87 61.8,71.47 61.8,71.3 62.01,71.1 65.73,71.1 66.52,71.89 74.22,71.89 74.62,72.29 77.16,72.29 77.32,72.44 77.32,72.93 77.44,73.05 77.68,73.05 77.8,72.93 77.8,72.44 77.91,72.33 78.15,72.33 78.27,72.44 78.27,72.93 78.39,73.05 78.63,73.05 78.75,72.93 78.75,72.44 78.87,72.33 79.12,72.33 79.82,73.03 89.97,73.03 92.23,70.77 92.62,70.77 95.06,68.33 95.98,68.33 96.09,68.23 v2(96.75,68.23)
  BOTTOM w0.076: UC1.BB63 100.83,64.1 99.7,64.1 99.22,64.58 99.22,65.2 98.49,65.93 98.49,66.91 97.56,67.84 97.09,67.84 96.75,68.18 v2(96.75,68.23)
  BOTTOM w0.102: v2(62.37,71.87) 61.97,71.46 60.42,71.46 60.01,71.88 JDIMM1.62
DDR_A_D24: length 49.4
  IN1 w0.119: v2(63.9,69.28) 64.42,69.8 66.26,69.8 66.85,70.39 74.55,70.39 75.16,70.99 81.4,70.99 81.52,71.11 81.52,71.49 81.64,71.61 81.88,71.61 82,71.49 82,71.11 82.12,70.99 82.36,70.99 82.48,71.11 82.48,71.49 82.59,71.61 82.83,71.61 82.95,71.49 82.95,71.11 83.07,70.99 83.31,70.99 83.43,71.11 83.43,71.61 83.55,71.73 89.3,71.73 91.57,69.47 92.08,69.47 94.52,67.03 95.45,67.03 95.86,66.62 v2(95.86,66.62)
  BOTTOM w0.076: UC1.BA61 101.28,63.05 101,63.33 100.49,63.33 100.38,63.44 99.43,63.44 98.56,64.31 98.56,64.93 97.32,66.17 97.1,66.17 96.82,66.45 96.82,66.85 96.68,66.99 95.99,66.99 95.86,66.86 v2(95.86,66.62)
  BOTTOM w0.102: v2(63.9,69.28) 65.25,70.62 JDIMM1.67
DDR_A_D25: length 50.3
  IN1 w0.119: v2(60.85,69.28) 62.04,70.47 65.99,70.47 66.57,71.06 74.28,71.06 74.88,71.66 79.68,71.66 79.8,71.78 79.8,72.12 80.08,72.4 89.58,72.4 91.84,70.14 92.36,70.14 94.8,67.7 95.73,67.7 96.03,67.4 96.44,67.4 96.62,67.22 97.32,67.22 97.79,66.75 v2(97.79,66.62)
  BOTTOM w0.076: UC1.AW61 102.67,62.95 102.35,63.27 102.12,63.27 101.99,63.25 101.77,63.25 101.77,63.25 101.76,63.25 101.51,63.5 100.56,63.5 100.45,63.6 99.5,63.6 98.72,64.38 98.72,64.99 97.92,65.8 97.92,66.49 v2(97.79,66.62)
  BOTTOM w0.102: JDIMM1.70 60.25,69.88 v2(60.85,69.28)
DDR_A_D26: length 49.1
  IN1 w0.119: v2(63.9,66.23) 63.66,66.23 63.53,66.35 63.53,66.62 63.65,66.74 65.75,66.74 66.66,67.65 67.15,67.65 67.61,68.11 76,68.11 76.17,68.28 76.17,68.72 76.28,68.84 76.52,68.84 76.64,68.72 76.64,68.28 76.76,68.16 77,68.16 77.12,68.28 77.12,68.72 77.24,68.84 77.48,68.84 77.6,68.72 77.6,68.28 77.72,68.16 77.96,68.16 78.08,68.28 78.08,68.72 78.19,68.84 89.16,68.84 90.68,67.33 91.19,67.33 93.06,65.46 95.44,65.46 95.59,65.31 95.59,65 v2(95.26,64.68)
  BOTTOM w0.076: v2(95.26,64.68) 96.16,63.78 97.68,63.78 98.57,62.89 98.57,62.89 99.63,61.83 100.74,61.83 UC1.BB59
  BOTTOM w0.102: JDIMM1.79 66.4,67.62 65.87,67.09 64.76,67.09 v2(63.9,66.23)
DDR_A_D27: length 51.3
  IN1 w0.089: 95.6,65.67 96.43,64.84 v2(96.43,64.65)
  IN1 w0.119: 95.6,65.67 93.32,65.67 91.33,67.66 90.82,67.66 89.3,69.18 75.9,69.18 75.3,68.58 67.6,68.58 67.01,67.99 66.52,67.99 65.61,67.08 60.09,67.08 59.96,66.95 59.96,66.69 60.08,66.57 60.73,66.57 60.85,66.45 v2(60.85,66.23)
  BOTTOM w0.076: v2(96.43,64.65) 96.72,64.94 97.85,64.94 98.06,64.72 98.06,64.1 99.22,62.94 100.18,62.94 100.29,62.84 100.43,62.84 100.64,62.62 100.98,62.62 100.98,62.62 101.08,62.66 101.27,62.66 101.36,62.62 101.36,62.62 101.37,62.62 101.38,62.61 101.6,62.61 101.69,62.64 101.95,62.64 102.05,62.57 102.66,62.57 102.8,62.43 UC1.AW59
  BOTTOM w0.102: v2(60.85,66.23) 60.02,66.23 59.87,66.38 JDIMM1.84
DDR_A_D28: length 48.3
  IN1 w0.119: v2(62.37,69.28) 62.37,69.67 62.83,70.13 66.12,70.13 66.71,70.72 74.41,70.72 75.02,71.33 80.11,71.33 80.23,71.45 80.23,71.95 80.35,72.07 89.44,72.07 91.7,69.81 92.22,69.81 94.66,67.37 95.59,67.37 95.89,67.07 96,67.07 96.45,66.62 v2(96.45,66.62)
  BOTTOM w0.076: v2(96.45,66.62) 96.45,66.59 97.04,66 97.25,66 98.39,64.86 98.39,64.24 99.36,63.27 100.32,63.27 100.42,63.17 100.73,63.17 UC1.BB61
  BOTTOM w0.102: v2(62.37,69.28) 60.77,70.88 JDIMM1.66
DDR_A_D29: length 50.2
  IN1 w0.119: v2(94.69,66.62) 94.46,66.62 91.94,69.14 91.43,69.14 89.91,70.66 89.15,70.66 89.03,70.78 89.03,71.28 88.91,71.4 88.67,71.4 88.55,71.28 88.55,70.78 88.43,70.66 88.19,70.66 88.07,70.78 88.07,71.28 87.95,71.4 87.71,71.4 87.59,71.28 87.59,70.78 87.47,70.66 87.24,70.66 87.12,70.78 87.12,71.28 87,71.4 86.76,71.4 86.64,71.28 86.64,70.78 86.52,70.66 86.28,70.66 86.16,70.78 86.16,71.28 86.04,71.4 85.8,71.4 85.68,71.28 85.68,70.78 85.56,70.66 85.32,70.66 85.2,70.78 85.2,71.28 85.08,71.4 84.84,71.4 84.72,71.28 84.72,70.78 84.6,70.66 84.36,70.66 84.24,70.78 84.24,71.28 84.12,71.4 83.88,71.4 83.77,71.28 83.77,70.78 83.65,70.66 75.3,70.66 74.69,70.05 66.99,70.05 66.4,69.46 65.61,69.46 v2(65.42,69.28)
  BOTTOM w0.076: UC1.AY61 102.02,62.82 101.7,62.82 101.6,62.79 101.39,62.79 101.3,62.82 101.06,62.82 100.95,62.79 100.71,62.79 100.49,63 100.35,63 100.25,63.11 99.29,63.11 98.23,64.17 98.23,64.79 97.18,65.84 95.48,65.84 v2(94.69,66.62)
  BOTTOM w0.102: JDIMM1.71 65.77,69.62 v2(65.42,69.28)
DDR_A_D30: length 50.1
  IN1 w0.119: v2(65.42,66.23) 65.71,66.23 66.8,67.32 67.29,67.32 67.75,67.78 78.53,67.78 78.65,67.9 78.65,68.39 78.77,68.51 79,68.51 79.12,68.39 79.12,67.9 79.24,67.78 79.48,67.78 79.6,67.9 79.6,68.39 79.72,68.51 79.96,68.51 80.08,68.39 80.08,67.9 80.2,67.78 80.44,67.78 80.56,67.9 80.56,68.39 80.68,68.51 80.91,68.51 81.03,68.39 81.03,67.9 81.15,67.78 81.39,67.78 81.51,67.9 81.51,68.39 81.63,68.51 81.87,68.51 81.99,68.39 81.99,67.9 82.11,67.78 82.35,67.78 82.47,67.9 82.47,68.39 82.59,68.51 82.82,68.51 82.94,68.39 82.94,67.9 83.06,67.78 83.3,67.78 83.42,67.9 83.42,68.39 83.54,68.51 83.78,68.51 83.9,68.39 83.9,67.9 84.02,67.78 84.26,67.78 84.38,67.9 84.38,68.39 84.5,68.51 89.02,68.51 90.54,66.99 91.05,66.99 92.92,65.13 94.56,65.13 94.68,65.01 v2(94.68,64.68)
  BOTTOM w0.076: v2(94.68,64.68) 94.68,63.86 94.95,63.59 97.64,63.59 98.41,62.82 98.41,62.82 99.56,61.67 100.5,61.67 100.7,61.47 100.98,61.47 101.11,61.53 101.11,61.6 101.26,61.75 101.48,61.75 UC1.BA59
  BOTTOM w0.102: v2(65.42,66.23) 66.02,66.23 66.42,66.62 JDIMM1.83
DDR_A_D31: length 50.7
  IN1 w0.119: v2(62.37,66.23) 62.79,65.81 65.77,65.81 66.94,66.98 67.43,66.98 67.89,67.44 84.59,67.44 84.71,67.56 84.71,67.98 84.83,68.1 85.07,68.1 85.19,67.98 85.19,67.5 85.31,67.38 85.55,67.38 85.67,67.5 85.67,67.98 85.79,68.1 86.02,68.1 86.14,67.98 86.14,67.5 86.26,67.38 86.5,67.38 86.62,67.5 86.62,67.98 86.74,68.1 86.98,68.1 87.1,67.98 87.1,67.5 87.22,67.38 89.57,67.38 90.29,66.66 90.91,66.66 92.78,64.79 93.34,64.79 v2(93.51,64.63)
  BOTTOM w0.076: v2(93.51,64.63) 94.72,63.42 97.58,63.42 98.24,62.75 98.24,62.75 99.5,61.5 100.44,61.5 100.63,61.31 101.01,61.31 101.05,61.33 101.19,61.37 101.94,61.37 102.15,61.58 UC1.AY59
  BOTTOM w0.102: v2(62.37,66.23) 62.37,66.48 61.97,66.88 61.42,66.88 61.24,67.07 60.23,67.07 59.92,67.38 JDIMM1.80
DDR_A_D32: length 51.2
  IN1 w0.076: 89.61,48.96 90.89,48.96 91.89,49.96 v2(93.39,49.96)
  IN1 w0.119: v2(62.37,42.43) 62.37,43.48 62.61,43.72 62.81,43.72 62.93,43.6 62.93,42.96 63.05,42.84 63.29,42.84 63.41,42.96 63.41,43.6 63.53,43.72 63.77,43.72 63.89,43.6 63.89,43.31 64.01,43.19 64.25,43.19 64.37,43.31 64.37,43.6 64.49,43.72 64.91,43.72 65.01,43.62 65.01,43.37 65.17,43.2 66.5,43.2 66.61,43.1 75.66,43.1 76.27,43.71 78.84,43.71 84.1,48.96 89.61,48.96
  BOTTOM w0.076: v2(93.39,49.96) 93.39,50 94.89,51.5 98.73,51.5 99.22,51.01 100.48,51.01 100.59,51.11 100.99,51.11 101.4,50.95 101.68,50.95 101.94,50.68 UC1.AY39
  BOTTOM w0.102: v2(62.37,42.43) 61.54,41.59 60.5,41.59 60.22,41.87 JDIMM1.174
DDR_A_D33: length 49
  IN1 w0.076: v2(98.73,50.04) 98.73,50.15 98.51,50.37 92.85,50.37 92.65,50.17 91.36,50.17 90.49,49.3 89.61,49.3
  IN1 w0.119: 89.61,49.3 83.96,49.3 78.7,44.04 76.13,44.04 75.52,43.43 67.13,43.43 66.51,44.05 62.47,44.05 v2(60.85,42.43)
  BOTTOM w0.076: UC1.AW39 102.8,50.03 102.51,49.74 102.01,49.74 101.72,49.76 101.66,49.78 101.34,49.78 101.27,49.76 101.06,49.75 100.94,49.78 100.6,49.78 100.44,49.61 99.88,49.61 99.45,50.04 v2(98.73,50.04)
  BOTTOM w0.102: v2(60.85,42.43) 60.69,42.43 60.24,42.87 JDIMM1.170
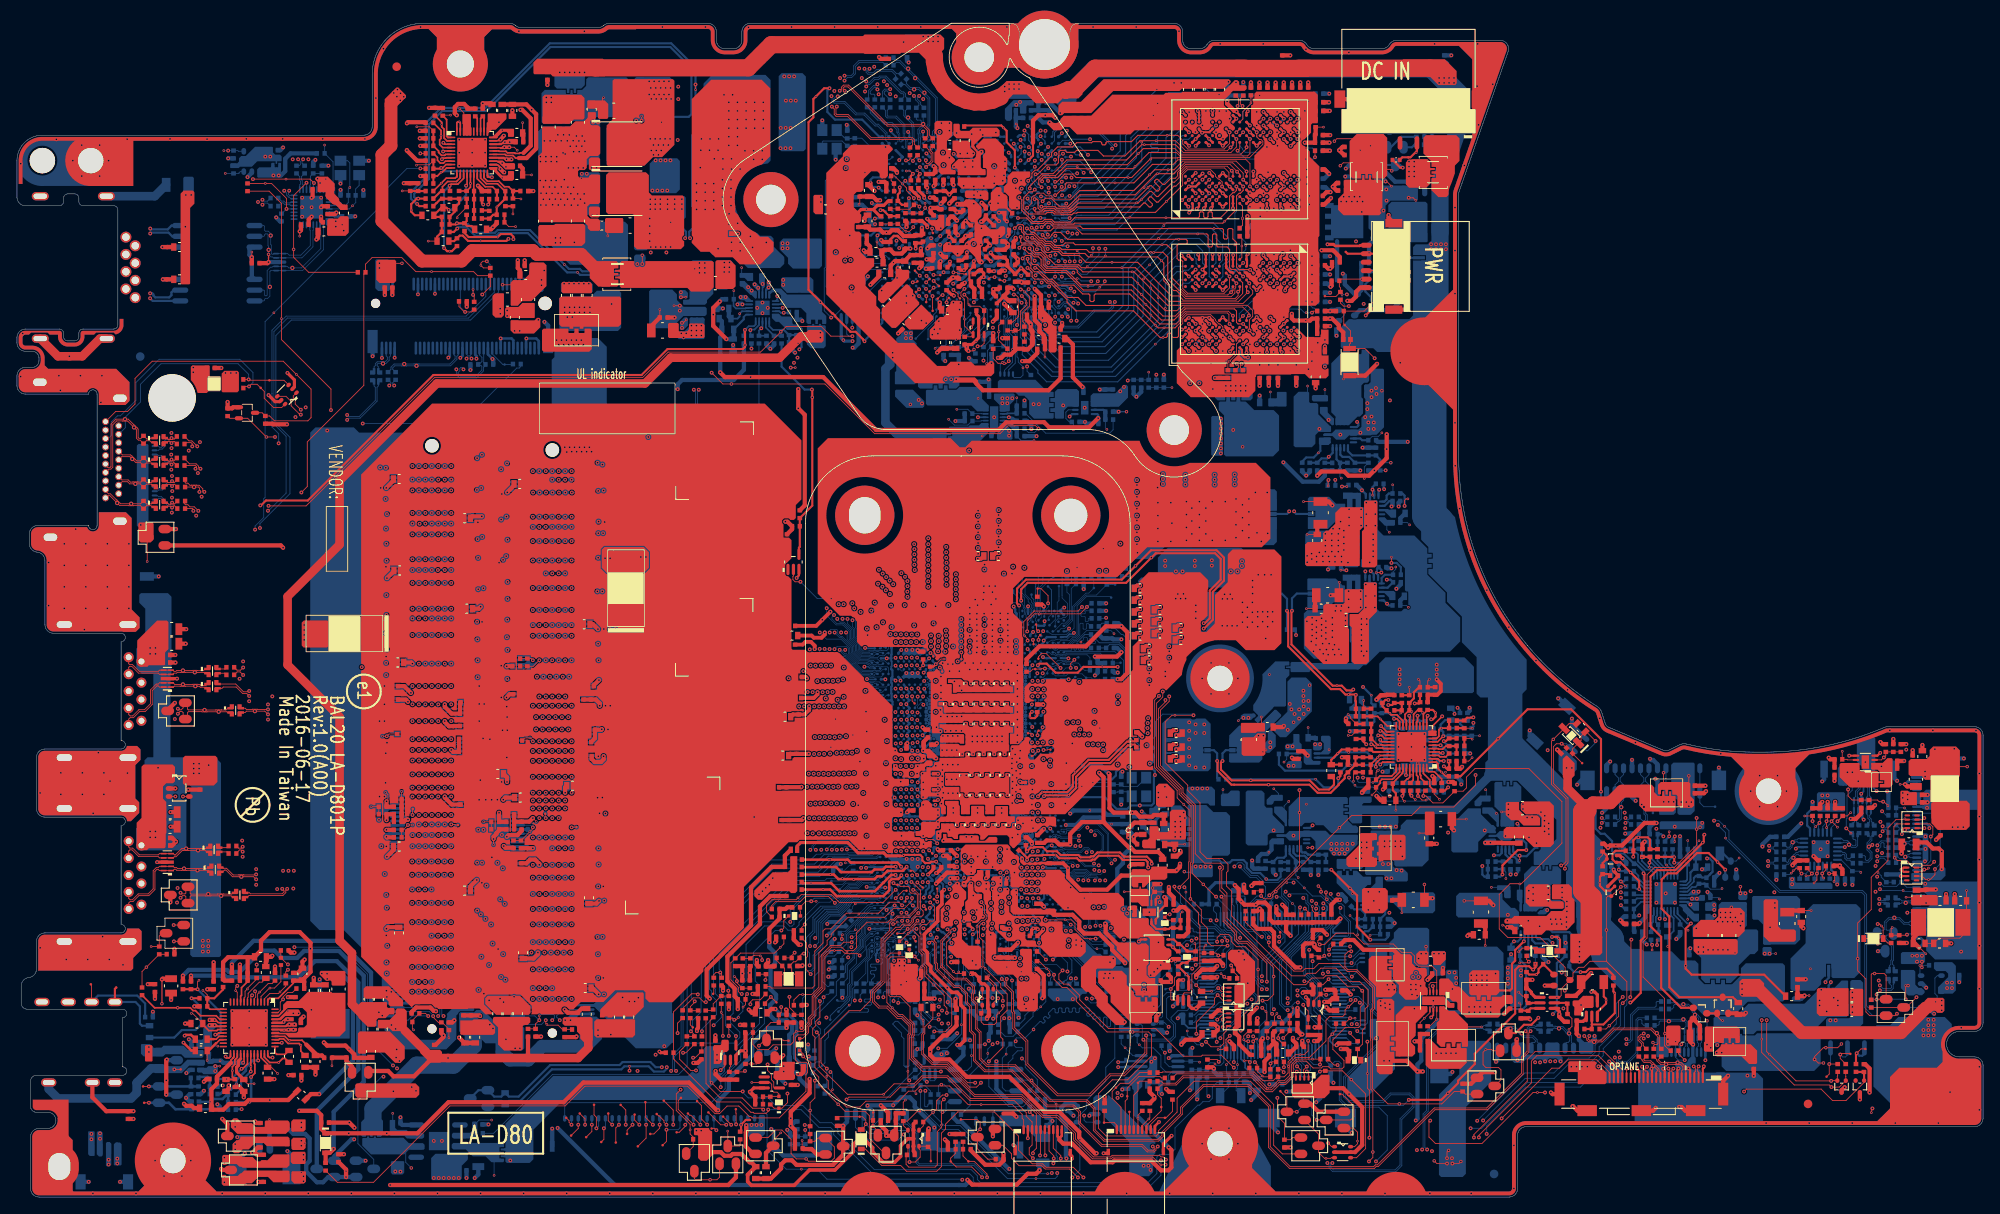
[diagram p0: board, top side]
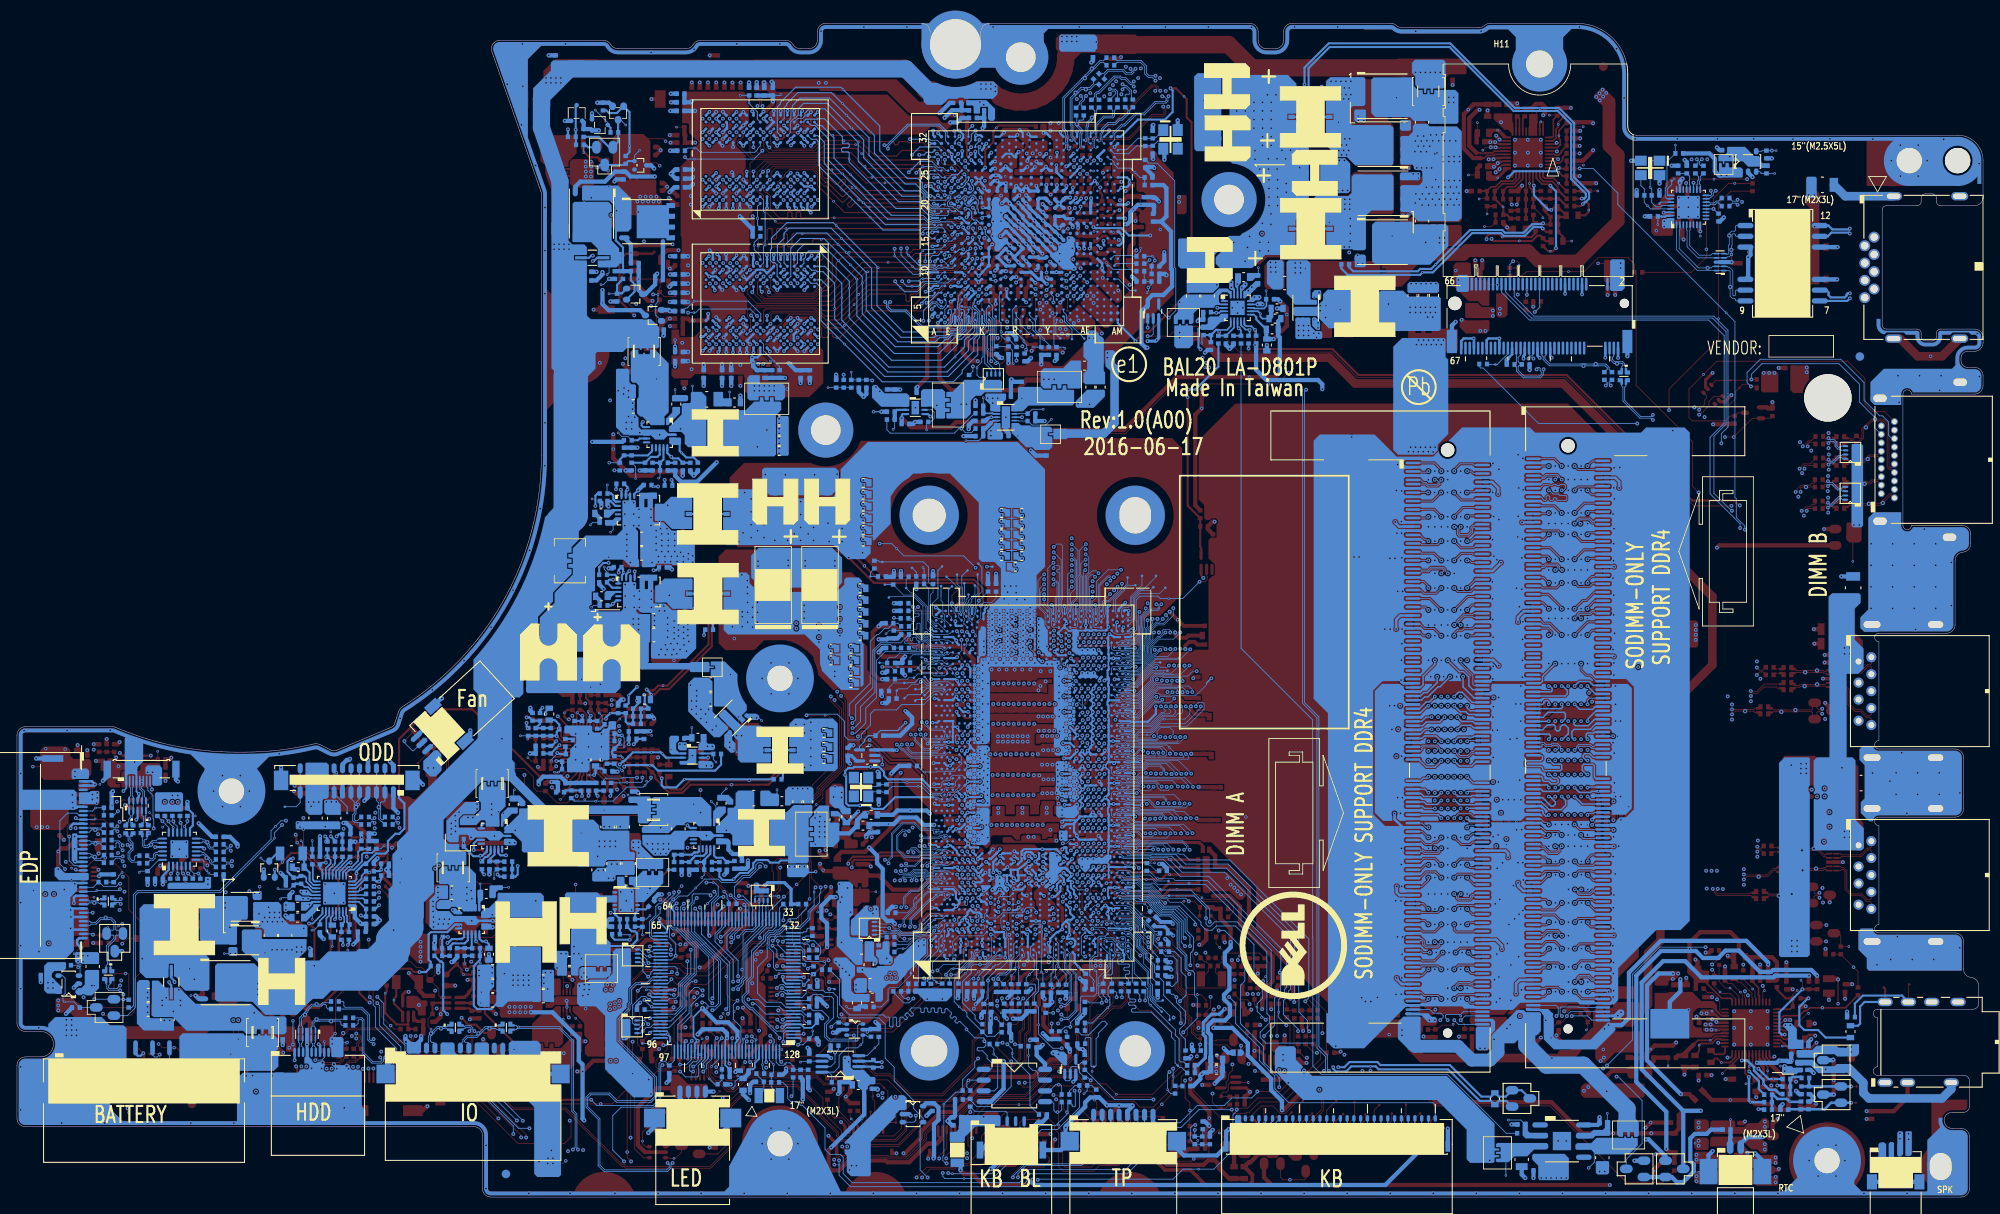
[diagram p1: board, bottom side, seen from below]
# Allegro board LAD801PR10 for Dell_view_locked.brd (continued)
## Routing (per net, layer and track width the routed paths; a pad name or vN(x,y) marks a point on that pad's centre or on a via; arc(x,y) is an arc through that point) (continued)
DDR_A_D34: length 50.7
  IN1 w0.076: v2(98.15,50.01) 97.02,48.87 95.54,48.87 95.35,48.68 95.35,48.29 94.94,47.88 92.88,47.88 92.57,47.57 92.29,47.57 90.53,45.81 89.73,45.81
  IN1 w0.119: v2(65.42,39.2) 65.66,39.44 68.22,39.44 68.43,39.64 68.44,39.66 68.78,39.66 68.78,39.66 69.03,39.41 69.03,39.41 69.11,39.32 71.21,39.32 71.8,38.74 73.87,38.74 73.99,38.62 73.99,37.92 74.1,37.8 74.34,37.8 74.46,37.92 74.46,38.62 74.58,38.74 74.82,38.74 74.94,38.62 74.94,37.92 75.06,37.8 75.3,37.8 75.42,37.92 75.42,38.62 75.54,38.74 75.78,38.74 75.9,38.62 75.9,37.92 76.01,37.8 76.25,37.8 76.37,37.92 76.37,38.62 76.49,38.74 76.73,38.74 76.85,38.62 76.85,37.92 76.97,37.8 77.23,37.8 77.39,37.96 77.39,38.2 77.5,38.31 77.9,38.31 85.4,45.81 89.73,45.81
  BOTTOM w0.076: UC1.AY37 102.05,49.56 101.79,49.56 101.64,49.61 101.4,49.61 101.24,49.57 101.12,49.57 100.92,49.61 100.67,49.61 100.51,49.45 99.81,49.45 99.58,49.67 98.48,49.67 v2(98.15,50.01)
  BOTTOM w0.102: v2(65.42,39.2) 65.81,39.2 66.38,38.63 JDIMM1.187
DDR_A_D35: length 52
  IN1 w0.076: v2(94.98,48.44) 94.49,48.93 92.17,48.93 90.07,46.83 89.82,46.83
  IN1 w0.119: v2(60.85,39.2) 60.03,39.2 59.9,39.33 59.9,40.33 60.02,40.45 67.8,40.45 68.02,40.66 69.2,40.66 69.2,40.66 69.53,40.33 71.63,40.33 72.2,39.76 77,39.76 78.81,41.56 79.73,41.56 84.99,46.82 89.81,46.82 89.82,46.83
  BOTTOM w0.076: UC1.AW37 102.58,49.46 102.26,49.13 101.78,49.13 101.56,48.91 99.64,48.91 99.38,49.18 95.64,49.18 94.98,48.51 v2(94.98,48.44)
  BOTTOM w0.102: JDIMM1.186 60.52,38.87 v2(60.85,39.2)
DDR_A_D36: length 48.9
  IN1 w0.076: v2(95.14,49.95) 94.62,49.43 91.86,49.43 90.72,48.29
  IN1 w0.119: 90.72,48.29 84.38,48.29 79.12,43.03 77.71,43.03 77.59,42.92 77.59,42.43 77.41,42.25 77.24,42.25 77.12,42.36 77.12,42.92 77,43.03 76.76,43.03 76.64,42.92 76.64,41.48 76.49,41.32 76.28,41.32 76.16,41.44 76.16,42.31 76.04,42.43 75.8,42.43 75.68,42.31 75.68,41.35 75.57,41.23 75.33,41.23 75.21,41.35 75.21,42.31 75.09,42.43 74.85,42.43 74.73,42.31 74.73,41.35 74.61,41.23 72.81,41.23 72.62,41.42 72.62,41.99 72.5,42.11 71.94,42.11 71.62,42.43 v2(65.42,42.43)
  BOTTOM w0.076: UC1.BB39 100.84,50.68 99.08,50.68 98.59,51.17 96.36,51.17 v2(95.14,49.95)
  BOTTOM w0.102: JDIMM1.169 66.14,43.13 65.44,42.43 v2(65.42,42.43)
DDR_A_D37: length 50.3
  IN1 w0.076: 90.79,48.63 91.76,49.59 94.22,49.59 v2(94.56,49.94)
  IN1 w0.119: 90.79,48.63 84.24,48.63 78.98,43.37 76.41,43.37 75.8,42.76 74.51,42.76 74.39,42.64 74.39,41.68 74.27,41.57 74.03,41.57 73.91,41.68 73.91,42.64 73.79,42.76 73.56,42.76 73.44,42.64 73.44,41.68 73.32,41.57 73.08,41.57 72.96,41.68 72.96,42.64 72.84,42.76 72.6,42.76 72.48,42.64 72.48,42.56 72.36,42.44 72.12,42.44 72,42.56 72,42.64 71.88,42.76 66.47,42.76 66.36,42.87 64.34,42.87 v2(63.9,42.43)
  BOTTOM w0.076: v2(94.56,49.94) 95.96,51.33 98.66,51.33 99.15,50.84 100.55,50.84 100.66,50.95 100.95,50.95 101.2,50.83 101.2,50.83 101.21,50.82 101.35,50.68 UC1.BA39
  BOTTOM w0.102: JDIMM1.173 66.31,42.13 65.77,41.59 65.07,41.59 64.79,41.87 64.41,41.87 63.9,42.38 v2(63.9,42.43)
DDR_A_D38: length 50.8
  IN1 w0.076: 89.73,46.48 90.09,46.48 92.37,48.77 93.61,48.77 93.81,48.57 v2(93.81,48.42)
  IN1 w0.119: v2(62.37,39.2) 62.37,39.5 62.25,39.62 61.48,39.62 61.36,39.74 61.36,39.99 61.48,40.11 67.94,40.11 68.16,40.33 69.06,40.33 69.06,40.33 69.4,39.99 71.49,39.99 72.06,39.42 77.14,39.42 78.94,41.23 79.87,41.23 85.13,46.48 89.73,46.48
  BOTTOM w0.076: v2(93.81,48.42) 93.81,48.64 94.51,49.34 99.44,49.34 99.71,49.08 101.01,49.08 101.29,49.36 UC1.BA37
  BOTTOM w0.102: JDIMM1.182 61.7,39.87 v2(62.37,39.2)
DDR_A_D39: length 49.8
  IN1 w0.076: 89.73,46.15 90.34,46.15 92.22,48.03 92.68,48.03 93.05,48.4 v2(93.19,48.4)
  IN1 w0.119: 89.73,46.15 85.27,46.15 79.8,40.68 79.63,40.68 79.43,40.89 79.26,40.89 79.09,40.72 79.09,40.55 79.29,40.35 79.29,40.18 79.13,40.01 78.96,40.01 78.66,40.3 78.49,40.3 78.33,40.13 78.33,39.96 78.62,39.67 78.62,39.5 78.45,39.33 78.28,39.33 77.99,39.63 77.82,39.63 77.65,39.46 77.65,39.29 77.94,38.99 77.94,38.83 77.76,38.65 77.6,38.65 77.18,39.07 71.94,39.07 71.35,39.66 69.26,39.66 68.92,39.99 68.92,39.99 68.3,39.99 68.29,39.98 68.08,39.77 63.77,39.77 63.65,39.65 63.65,39.45 v2(63.9,39.2)
  BOTTOM w0.076: UC1.BB37 100.65,49.36 100.58,49.28 99.74,49.28 99.51,49.51 94.14,49.51 93.19,48.55 v2(93.19,48.4)
  BOTTOM w0.102: v2(63.9,39.2) 64.66,39.97 66,39.97 66.34,39.63 JDIMM1.183
DDR_A_D40: length 51.7
  IN1 w0.076: 89.22,44.52 89.97,44.52 92.53,47.08 92.78,47.08 93.09,47.39 96.8,47.39 v2(97.83,48.41)
  IN1 w0.119: v2(65.42,37.69) 65.76,38.02 66.25,38.02 66.37,37.91 66.37,37.16 66.49,37.04 66.73,37.04 66.85,37.16 66.85,37.91 66.96,38.02 67.2,38.02 67.32,37.91 67.32,36.69 67.44,36.57 67.68,36.57 67.8,36.69 67.8,37.91 67.92,38.02 68.16,38.02 68.28,37.91 68.28,37.32 68.4,37.2 68.64,37.2 68.76,37.32 68.76,37.91 68.87,38.02 70.68,38.02 70.92,37.78 70.92,36.63 71.04,36.5 77.93,36.5 85.94,44.52 89.22,44.52
  BOTTOM w0.076: v2(97.83,48.41) 98.3,47.94 99.33,47.94 99.63,48.24 100.2,48.24 100.38,48.06 100.95,48.06 101.04,48.1 101.06,48.1 101.3,48.1 101.39,48.06 101.6,48.06 101.78,48.13 102.05,48.13 UC1.AY35
  BOTTOM w0.102: v2(65.42,37.69) 65.42,37.4 66.2,36.63 JDIMM1.195
DDR_A_D41: length 52.8
  IN1 w0.076: v2(96.88,48.43) 96.01,47.55 93.02,47.55 92.71,47.24 92.43,47.24 90.04,44.85
  IN1 w0.119: 90.04,44.85 85.8,44.85 77.79,36.84 73.38,36.84 73.26,36.96 73.26,37.29 73.14,37.41 72.9,37.41 72.78,37.29 72.78,36.96 72.66,36.84 72.42,36.84 72.3,36.96 72.3,37.65 72.18,37.77 71.94,37.77 71.82,37.65 71.82,36.96 71.71,36.84 71.39,36.84 71.25,36.98 71.25,37.92 70.81,38.36 63.76,38.36 63.64,38.23 63.64,37.95 v2(63.9,37.69)
  BOTTOM w0.076: UC1.AW35 102.56,48.23 102.24,48.55 101.74,48.55 101.54,48.75 99.57,48.75 99.31,49.01 97.46,49.01 v2(96.88,48.43)
  BOTTOM w0.102: JDIMM1.191 66.45,37.63 65.71,38.36 64.57,38.36 v2(63.9,37.69)
DDR_A_D42: length 52.1
  IN1 w0.076: 98.62,46.37 97.68,45.43 92.51,45.43 91.88,44.79 91.88,44.13 89.45,41.7
  IN1 w0.119: 98.62,46.37 v2(98.63,46.38) ; v2(63.9,33.99) 64.34,33.55 65.99,33.55 66.48,33.07 72.2,33.07 72.32,33.19 72.32,33.54 72.43,33.66 72.67,33.66 72.79,33.54 72.79,33.19 72.91,33.07 73.15,33.07 73.27,33.19 73.27,33.54 73.39,33.66 73.63,33.66 73.75,33.54 73.75,33.19 73.87,33.07 74.11,33.07 74.23,33.19 74.23,33.54 74.34,33.66 74.58,33.66 74.7,33.54 74.7,33.19 74.82,33.07 75.06,33.07 75.18,33.19 75.18,33.54 75.3,33.66 75.54,33.66 75.66,33.54 75.66,33.19 75.78,33.07 76.02,33.07 76.14,33.19 76.14,33.54 76.25,33.66 79.07,33.66 87.11,41.7 89.45,41.7
  BOTTOM w0.076: v2(98.63,46.38) 98.86,46.61 100.59,46.61 100.62,46.57 100.99,46.57 101.23,46.68 101.83,46.68 UC1.AY33
  BOTTOM w0.102: JDIMM1.207 66.25,33.63 66.21,33.59 64.3,33.59 v2(63.9,33.99)
DDR_A_D43: length 51.5
  IN1 w0.076: 89.52,42.04 91.71,44.23 91.71,44.86 92.45,45.59 93.9,45.59 v2(94.76,46.45)
  IN1 w0.119: v2(65.42,33.99) 66.44,33.99 66.57,33.87 66.57,33.52 66.68,33.41 66.97,33.41 67.09,33.53 67.09,33.97 67.2,34.09 67.44,34.09 67.56,33.97 67.56,33.53 67.68,33.41 67.92,33.41 68.04,33.53 68.04,33.74 68.16,33.86 68.4,33.86 68.52,33.74 68.52,33.53 68.64,33.41 68.88,33.41 69,33.53 69,33.74 69.11,33.86 69.35,33.86 69.47,33.74 69.47,33.53 69.59,33.41 69.83,33.41 69.95,33.53 69.95,33.74 70.07,33.86 70.31,33.86 70.43,33.74 70.43,33.53 70.55,33.41 70.79,33.41 70.91,33.53 70.91,33.88 71.02,34 71.26,34 71.38,33.88 71.38,33.53 71.5,33.41 71.74,33.41 71.86,33.53 71.86,33.88 71.98,34 78.93,34 86.97,42.04 89.52,42.04
  BOTTOM w0.076: UC1.AW33 102.8,47.65 102.59,47.86 102.08,47.86 101.98,47.93 101.73,47.93 101.6,47.89 101.38,47.89 101.37,47.89 101.36,47.9 101.36,47.9 101.27,47.93 101.07,47.93 100.98,47.9 100.98,47.9 100.31,47.9 100.13,48.08 99.69,48.08 99.09,47.47 95.38,47.47 94.76,46.85 v2(94.76,46.45)
  BOTTOM w0.102: JDIMM1.203 66.05,34.63 v2(65.42,33.99)
DDR_A_D44: length 50
  IN1 w0.076: 89.22,44.18 89.87,44.18 92.6,46.91 92.85,46.91 93.16,47.22 97.8,47.22 98.62,48.05
  IN1 w0.119: v2(60.85,37.69) 60.85,37.69 60.85,37.04 60.98,36.92 61.61,36.92 61.96,37.26 65.79,37.26 66.82,36.24 69.76,36.24 69.88,36.36 69.88,36.98 70,37.1 70.24,37.1 70.36,36.98 70.36,36.29 70.48,36.17 78.07,36.17 86.08,44.18 89.22,44.18 ; 98.62,48.05 v2(99.02,48.45)
  BOTTOM w0.076: v2(99.02,48.45) 99.07,48.41 100.77,48.41 UC1.BB35
  BOTTOM w0.102: JDIMM1.194 60.03,36.87 v2(60.85,37.69)
DDR_A_D45: length 51.4
  IN1 w0.076: 89.22,45.19 90.14,45.19 92.36,47.41 92.64,47.41 92.95,47.72 95.02,47.72 v2(95.71,48.41)
  IN1 w0.119: 89.22,45.19 85.67,45.19 77.65,37.17 73.84,37.17 72.91,38.11 71.54,38.11 70.95,38.7 61.61,38.7 61.49,38.57 61.49,38.25 61.61,38.12 62.25,38.12 62.37,38 v2(62.37,37.69)
  BOTTOM w0.076: UC1.BA35 101.28,48.33 101.02,48.58 99.5,48.58 99.24,48.85 97.6,48.85 97.43,48.68 97.43,48.45 96.99,48.02 96.11,48.02 v2(95.71,48.41)
  BOTTOM w0.102: v2(62.37,37.69) 61.97,38.1 60.3,38.1 60.08,37.87 JDIMM1.190
DDR_A_D46: length 51.3
  IN1 w0.076: 89.44,42.71 91.38,44.65 91.38,44.99 92.35,45.96 93.14,45.96 v2(93.59,46.41)
  IN1 w0.119: 89.44,42.71 86.69,42.71 78.68,34.69 70.76,34.69 70.59,34.53 68.34,34.53 68.11,34.76 66.21,34.76 65.84,35.13 60.27,35.13 60.03,34.89 60.03,34.11 60.15,33.99 v2(60.85,33.99)
  BOTTOM w0.076: v2(93.59,46.41) 94.08,45.92 95.39,45.92 97.64,45.92 98.49,46.77 100.65,46.77 100.69,46.74 100.95,46.74 101.21,46.86 101.35,47 UC1.BA33
  BOTTOM w0.102: v2(60.85,33.99) 60.23,33.38 JDIMM1.208
DDR_A_D47: length 50.3
  IN1 w0.076: v2(94.18,46.44) 93.5,45.77 92.39,45.77 91.55,44.93 91.55,44.33 89.59,42.37
  IN1 w0.119: 89.59,42.37 86.83,42.37 78.82,34.36 70.9,34.36 70.73,34.19 68.21,34.19 67.97,34.43 65.4,34.43 65.3,34.53 65.3,34.72 65.22,34.8 64.82,34.8 64.7,34.68 64.7,34.52 64.59,34.4 64.35,34.4 64.23,34.52 64.23,34.68 64.11,34.8 63.55,34.8 63.43,34.68 63.43,34.53 63.31,34.41 63.07,34.41 62.95,34.53 62.95,34.68 62.84,34.8 62.31,34.8 62.19,34.67 62.19,34.18 v2(62.37,33.99)
  BOTTOM w0.076: v2(94.18,46.44) 94.53,46.08 95.32,46.08 97.54,46.08 98.39,46.94 100.78,46.94 UC1.BB33
  BOTTOM w0.102: v2(62.37,33.99) 61.97,34.4 60.36,34.4 60.33,34.38 JDIMM1.204
DDR_A_D48: length 51.8
  IN1 w0.076: v2(93.44,44.7) 93.44,44.62 89.22,40.4
  IN1 w0.119: v2(65.42,32.18) 65.82,31.77 69.51,31.77 69.63,31.65 69.63,31.2 69.75,31.08 69.99,31.08 70.11,31.2 70.11,31.65 70.23,31.77 70.47,31.77 70.59,31.65 70.59,31.19 70.7,31.07 70.94,31.07 71.06,31.19 71.06,31.65 71.18,31.77 71.42,31.77 71.54,31.65 71.54,31.19 71.66,31.07 71.9,31.07 72.02,31.19 72.02,31.65 72.14,31.77 72.38,31.77 72.5,31.65 72.5,31.19 72.62,31.07 72.85,31.07 72.97,31.19 72.97,31.65 73.09,31.77 73.33,31.77 73.45,31.65 73.45,31.19 73.57,31.07 73.81,31.07 73.93,31.19 73.93,31.65 74.05,31.77 74.29,31.77 74.41,31.65 74.41,31.19 74.53,31.07 74.76,31.07 74.88,31.19 74.88,31.65 75,31.77 79.02,31.77 87.65,40.4 89.22,40.4
  BOTTOM w0.076: v2(93.44,44.7) 94.26,45.52 95.23,45.52 95.46,45.75 99.36,45.75 99.57,45.96 100.47,45.96 100.64,46.13 100.98,46.13 101.4,45.97 101.68,45.97 101.94,45.7 UC1.AY31
  BOTTOM w0.102: JDIMM1.211 65.87,32.63 v2(65.42,32.18)
DDR_A_D49: length 52.2
  IN1 w0.076: v2(98.85,44.67) 98.25,45.26 92.58,45.26 92.04,44.72 92.04,43.89 89.22,41.07
  IN1 w0.119: 89.22,41.07 87.37,41.07 79.33,33.03 76.87,33.03 76.28,32.44 66.22,32.44 65.73,32.93 63.12,32.93 v2(62.37,32.18)
  BOTTOM w0.076: UC1.AW31 102.8,45.01 102.58,44.79 102.02,44.79 102,44.77 101.73,44.77 101.58,44.83 101.44,44.83 101.22,44.76 101.1,44.76 101.02,44.79 100.99,44.81 100.61,44.81 100.41,44.6 100.28,44.6 100,44.32 99.19,44.32 v2(98.85,44.67)
  BOTTOM w0.102: v2(62.37,32.18) 62.37,31.54 62.11,31.28 60.03,31.28 59.93,31.38 JDIMM1.216
DDR_A_D50: length 51.5
  IN1 w0.076: 91.02,40.14 91.02,40.4 91.09,40.48 91.09,41.31 93.14,43.36 96.98,43.36 v2(98.26,44.63)
  IN1 w0.119: v2(63.74,28.85) 63.54,28.85 63.42,28.97 63.42,29.33 63.54,29.45 65.38,29.45 65.89,29.97 67.42,29.97 67.98,29.41 68.87,29.41 69.01,29.26 75.8,29.26 76.16,29.61 76.39,29.61 76.74,29.97 79.77,29.97 88.4,38.59 89.47,38.59 91.02,40.14
  BOTTOM w0.076: UC1.AY29 102.05,44.58 101.79,44.58 101.58,44.65 101.44,44.65 101.21,44.59 101.07,44.59 100.95,44.64 100.68,44.64 100.48,44.44 100.35,44.44 100.07,44.16 98.73,44.16 v2(98.26,44.63)
  BOTTOM w0.102: v2(63.74,28.85) 64.72,27.86 66.13,27.86 66.4,28.13 JDIMM1.229
DDR_A_D51: length 52.5
  IN1 w0.076: 91.7,39.4 91.78,39.48 91.78,41.3 92.76,42.28 94.61,42.28 v2(95.26,42.92)
  IN1 w0.119: 91.7,39.4 89.89,37.59 88.81,37.59 80.18,28.96 77.16,28.96 76.37,28.18 69.98,28.18 69.48,27.68 66.28,27.68 66.05,27.91 61.62,27.91 v2(60.69,28.85)
  BOTTOM w0.076: UC1.AW29 102.8,44.47 102.56,44.23 102.42,44.23 102.3,44.12 102.02,44.12 101.99,44.14 101.7,44.14 101.33,43.77 100.38,43.77 100.27,43.66 96,43.66 v2(95.26,42.92)
  BOTTOM w0.102: JDIMM1.228 60.22,28.38 v2(60.69,28.85)
DDR_A_D52: length 49.9
  IN1 w0.076: 89.22,40.74 92.21,43.72 92.21,44.65 92.65,45.1 94.81,45.1 v2(95.22,44.69)
  IN1 w0.119: v2(63.9,32.18) 63.9,32.47 64.02,32.59 65.59,32.59 66.08,32.11 76.91,32.11 77.02,32.23 77.02,32.58 77.14,32.7 77.38,32.7 77.5,32.58 77.5,32.23 77.62,32.11 77.86,32.11 77.98,32.23 77.98,32.58 78.1,32.7 78.34,32.7 78.46,32.58 78.46,32.23 78.58,32.11 78.88,32.11 79.01,32.24 79.01,32.58 79.13,32.7 79.47,32.7 87.51,40.74 89.22,40.74
  BOTTOM w0.076: UC1.BB31 100.78,45.63 99.7,45.63 99.5,45.42 95.95,45.42 v2(95.22,44.69)
  BOTTOM w0.102: JDIMM1.215 66.37,31.63 66.03,31.29 64.68,31.29 63.9,32.07 v2(63.9,32.18)
DDR_A_D53: length 50.5
  IN1 w0.076: 89.22,40.07 90,40.84 90,40.92 93.02,43.94 93.88,43.94 v2(94.63,44.69)
  IN1 w0.119: v2(60.85,32.18) 61.59,31.44 62.82,31.44 62.94,31.32 62.94,30.94 63.05,30.82 63.29,30.82 63.41,30.94 63.41,31.32 63.53,31.44 68.92,31.44 69.62,30.74 75.19,30.74 75.9,31.44 79.16,31.44 87.79,40.07 89.22,40.07
  BOTTOM w0.076: v2(94.63,44.69) 95.53,45.59 99.43,45.59 99.64,45.8 100.54,45.8 100.71,45.97 100.95,45.97 101.21,45.84 101.35,45.7 UC1.BA31
  BOTTOM w0.102: JDIMM1.212 60.65,32.38 v2(60.85,32.18)
DDR_A_D54: length 50.7
  IN1 w0.076: 91.59,40.28 91.59,41.34 92.69,42.44 93.37,42.44 v2(93.85,42.92)
  IN1 w0.119: v2(62.21,28.85) 62.81,28.25 66.19,28.25 66.42,28.02 69.34,28.02 69.84,28.51 76.23,28.51 77.02,29.29 80.05,29.29 88.67,37.92 89.75,37.92 91.52,39.7 91.52,40.21 91.59,40.28
  BOTTOM w0.076: v2(93.85,42.92) 94.76,43.83 100.21,43.83 100.31,43.93 100.82,43.93 101.27,44.38 UC1.BA29
  BOTTOM w0.102: JDIMM1.224 61.69,29.38 v2(62.21,28.85)
DDR_A_D55: length 49.6
  IN1 w0.076: v2(93.24,42.94) 93,42.7 92.71,42.7 91.27,41.25 91.27,39.92
  IN1 w0.119: 91.27,39.92 89.61,38.26 88.54,38.26 79.91,29.63 76.88,29.63 76.42,29.17 76.19,29.17 75.94,28.93 68.87,28.93 68.73,29.07 68.12,29.07 67.9,28.85 67.9,28.47 67.78,28.35 67.46,28.35 67.34,28.46 67.34,29.43 67.22,29.55 66.99,29.55 66.87,29.43 66.87,28.53 66.75,28.41 66.51,28.41 66.39,28.53 66.39,29.51 66.27,29.63 66.03,29.63 65.91,29.51 65.91,28.7 65.79,28.58 65.52,28.58 v2(65.26,28.85)
  BOTTOM w0.076: v2(93.24,42.94) 94.3,43.99 100.14,43.99 100.24,44.1 100.57,44.1 UC1.BB29
  BOTTOM w0.102: v2(65.26,28.85) 66.01,28.85 66.29,29.13 JDIMM1.225
DDR_A_D56: length 54.3
  IN1 w0.076: v2(97.04,42.92) 97.04,42.41 96.58,41.95 92.93,41.95 92.67,41.68
  IN1 w0.119: v2(65.42,26.87) 65.57,26.72 69.35,26.72 69.96,26.11 71.7,26.11 71.82,26.23 71.82,26.62 71.94,26.74 72.18,26.74 72.3,26.62 72.3,26.23 72.42,26.11 72.66,26.11 72.78,26.23 72.78,27.09 72.9,27.21 73.14,27.21 73.26,27.09 73.26,26.23 73.38,26.11 73.61,26.11 73.73,26.23 73.73,27.09 73.85,27.21 74.09,27.21 74.21,27.09 74.21,26.23 74.33,26.11 74.57,26.11 74.69,26.23 74.69,27.09 74.81,27.21 75.05,27.21 75.17,27.09 75.17,26.94 75.29,26.82 75.52,26.82 75.64,26.94 75.64,27.09 75.76,27.21 76.77,27.21 77.56,28 80.63,28 87.44,34.82 88,34.82 88.47,34.82 92.3,38.64 92.3,41.32 92.67,41.68
  BOTTOM w0.076: UC1.AY27 102.08,43.25 101.73,43.6 100.45,43.6 100.34,43.5 97.62,43.5 v2(97.04,42.92)
  BOTTOM w0.102: JDIMM1.237 66.17,26.13 v2(65.42,26.87)
DDR_A_D57: length 55.3
  IN1 w0.076: v2(95.84,42.92) 95.04,42.11 92.83,42.11 91.97,41.25 91.97,39
  IN1 w0.119: v2(63.9,26.87) 64.31,27.29 65.79,27.29 66.02,27.05 69.81,27.05 69.98,26.88 69.98,26.56 70.1,26.44 70.34,26.44 70.46,26.56 70.46,27.43 70.58,27.55 70.82,27.55 70.94,27.43 70.94,26.56 71.06,26.44 71.3,26.44 71.42,26.56 71.42,27.43 71.54,27.55 71.77,27.55 71.89,27.43 71.89,27.19 72.01,27.07 72.25,27.07 72.37,27.19 72.37,27.43 72.49,27.55 76.63,27.55 77.42,28.33 80.49,28.33 87.31,35.15 88.14,35.15 88.34,35.15 91.97,38.78 91.97,39
  BOTTOM w0.076: v2(95.84,42.92) 95.84,42.83 96.31,42.36 99.1,42.36 99.74,43 100.36,43 100.43,42.93 101.06,42.93 101.06,42.93 101.07,42.93 101.11,42.97 102.52,42.97 UC1.AW27
  BOTTOM w0.102: v2(63.9,26.87) 64.3,27.28 66.17,27.28 66.33,27.13 JDIMM1.233
DDR_A_D58: length 54.2
  IN1 w0.119: v2(60.85,26.87) 60.46,26.87 60.34,26.76 60.34,26.08 60.46,25.96 66.57,25.96 67.1,25.44 76,25.44 77.89,27.33 80.9,27.33 87.72,34.15 88.75,34.15 92.97,38.37 92.97,41.04 93.42,41.49 96.92,41.49 97.3,41.12 v2(97.3,41.01)
  BOTTOM w0.076: v2(97.3,41.01) 97.67,41.39 99.65,41.39 99.84,41.58 100.97,41.58 101.36,41.77 101.65,41.77 101.9,42.02 UC1.AY25
  BOTTOM w0.102: JDIMM1.236 60.35,26.38 v2(60.85,26.87)
DDR_A_D59: length 55.1
  IN1 w0.076: 93.16,41.71 97.21,41.71 v2(97.89,41.02)
  IN1 w0.119: 93.16,41.71 92.64,41.18 92.64,38.51 88.61,34.48 87.86,34.48 87.86,34.48 87.58,34.48 80.76,27.66 77.69,27.66 76.91,26.88 76.1,26.88 75.98,26.76 75.98,25.89 75.86,25.77 75.62,25.77 75.5,25.89 75.5,26.26 75.38,26.38 75.14,26.38 75.02,26.26 75.02,25.89 74.9,25.77 69.82,25.77 69.22,26.38 62.86,26.38 v2(62.37,26.87)
  BOTTOM w0.076: 101.58,41.2 101.61,41.22 101.61,41.49 101.88,41.77 102.36,41.77 102.62,42.02 UC1.AW25 ; 99.66,40.87 99.75,40.79 100.24,40.79 100.61,41.16 101.06,41.16 101.1,41.12 101.5,41.12 101.57,41.18
  BOTTOM w0.102: v2(62.37,26.87) 61.87,27.38 JDIMM1.232 ; 99.66,40.87 99.52,41.02 v2(97.89,41.02) ; 101.58,41.2 101.57,41.18
DDR_A_D60: length 52.9
  IN1 w0.089: v2(98.8,42.92) 99.04,42.68 99.04,41.16 98.41,40.53 98.39,40.53 98.15,40.29
  IN1 w0.119: v2(63.9,23.38) 64.78,22.5 68.78,22.5 69.74,21.54 73.36,21.54 74.79,22.96 77.03,22.96 78.91,24.85 82.93,24.85 84.16,26.08 84.16,27.07 88.75,31.67 89.78,31.67 96.68,38.57 96.68,39.48 97.39,40.18 98.05,40.18 98.15,40.29
  BOTTOM w0.076: v2(98.8,42.92) 98.86,42.92 99.27,43.33 100.41,43.33 100.43,43.35 UC1.BB27
  BOTTOM w0.102: v2(63.9,23.38) 64.3,23.78 65.92,23.78 66.26,24.13 JDIMM1.245
DDR_A_D61: length 53.1
  IN1 w0.089: v2(97.62,42.92) 98.52,42.03 98.52,41.11 97.92,40.52
  IN1 w0.119: 97.92,40.52 97.09,40.52 96.35,39.77 96.35,38.71 89.64,32 88.61,32 83.78,27.17 83.78,26.17 82.79,25.18 78.77,25.18 76.89,23.29 74.65,23.29 73.22,21.87 71.39,21.87 71.27,21.99 71.27,22.51 71.15,22.63 70.91,22.63 70.79,22.51 70.79,21.99 70.68,21.87 70.44,21.87 70.32,21.99 70.32,22.72 70.2,22.84 65.96,22.84 v2(65.42,23.38)
  BOTTOM w0.076: UC1.BA27 101.39,43.35 101.18,43.13 101.04,43.13 101,43.09 100.51,43.09 100.43,43.17 99.63,43.17 98.99,42.53 98.02,42.53 v2(97.62,42.92)
  BOTTOM w0.102: JDIMM1.249 65.67,23.12 v2(65.42,23.38)
DDR_A_D62: length 53.4
  IN1 w0.119: v2(62.37,23.38) 62.79,23.79 65.59,23.79 66.22,23.17 71.28,23.17 72.24,22.21 73.09,22.21 74.51,23.63 76.75,23.63 78.64,25.52 82.65,25.52 83.39,26.26 83.39,27.26 88.47,32.34 89.5,32.34 95.22,38.06 95.22,40.09 v2(96.12,40.98)
  BOTTOM w0.076: v2(96.12,40.98) 96.69,41.55 99.58,41.55 99.77,41.74 100.58,41.74 100.93,41.74 101.2,41.87 101.35,42.02 UC1.BA25
  BOTTOM w0.102: JDIMM1.246 59.05,23.87 61.88,23.87 v2(62.37,23.38)
DDR_A_D63: length 52.6
  IN1 w0.119: v2(60.85,23.38) 60.58,23.38 60.47,23.49 60.47,23.93 60.56,24.02 62.49,24.02 62.6,24.13 65.73,24.13 66.35,23.51 71.63,23.51 72.09,23.97 76.61,23.97 78.5,25.85 81.51,25.85 88.33,32.67 89.36,32.67 94.89,38.2 94.89,40.38 v2(95.52,41.01)
  BOTTOM w0.076: UC1.BB25 100.62,42.02 100.51,41.91 99.71,41.91 99.51,41.72 96.23,41.72 v2(95.52,41.01)
  BOTTOM w0.102: v2(60.85,23.38) 60.85,23.29 60.43,22.87 JDIMM1.250
DDR_A_DQS0: length 69.1
  IN1 w0.076: v2(107.49,75.19) 107.31,75.37 107.08,75.37 106.91,75.54 106.91,78.93 106.89,78.95
  IN1 w0.124: v2(63.9,84.64) 64.03,84.51 64.03,84.49 64.03,84.49 64.03,84.08 64.34,83.76 68.64,83.76 69.58,84.7 69.79,84.7 70.21,84.28 70.56,84.28 70.99,84.71 70.99,85.06 70.58,85.47 70.58,85.65 70.85,85.91 71.02,85.91 71.5,85.44 71.85,85.44 72.24,85.83 72.24,86.18 71.8,86.62 71.8,86.8 72.06,87.06 90.1,87.06 90.9,86.26 92.87,86.26 93.51,85.62 102.19,85.62 106.89,80.93 106.89,78.95
  BOTTOM w0.076: UC1.AM69 107.11,67.85 107.42,68.16 107.42,68.65 107.46,68.75 107.46,68.95 107.4,69.06 107.4,69.32 107.48,69.4 107.48,70.18 106.94,70.72 106.94,73.03 107.09,73.18 107.09,75.08 107.21,75.19 v2(107.49,75.19)
  BOTTOM w0.102: v2(63.9,84.64) 64.07,84.47 64.07,84.11 64.28,83.9 65.55,83.9 65.78,84.13 JDIMM1.13
DDR_A_DQS1: length 58.9
  IN1 w0.124: v2(102.52,73.16) 102.74,73.16 102.89,73.31 102.89,73.49 101.92,74.46 98.76,74.46 98.18,75.04 97.26,75.04 90.67,81.63 84.38,81.63 83.02,80.27 73.16,80.27 71.91,79.02 66.09,79.02 65.62,79.5 62.16,79.5 62.03,79.36 62.03,79.18 62.15,79.06 62.35,79.06 v2(62.37,79.08)
  BOTTOM w0.076: UC1.AT70 104.65,67.98 104.65,67.95 104.59,67.89 104.51,67.89 104.45,67.95 104.39,68.08 104.39,68.3 104.42,68.38 104.42,68.65 104.37,68.78 104.37,68.89 104.42,69.03 104.42,69.52 104.33,69.6 104.33,72.21 103.26,73.29 102.99,73.29 102.85,73.16 v2(102.52,73.16)
  BOTTOM w0.102: v2(62.37,79.08) 62.13,79.08 61.99,78.94 61.99,78.2 61.78,77.99 60.66,77.99 60.2,78.45 60.2,78.93 60.1,79.03 59.99,79.03 59.83,78.88 JDIMM1.34
DDR_A_DQS2: length 52
  IN1 w0.124: v2(63.9,73.59) 63.69,73.59 63.52,73.43 63.52,73.25 63.64,73.12 64.99,73.12 65.6,73.74 73.45,73.74 73.89,74.17 75.45,74.17 76.18,74.9 82.16,74.9 83.37,76.11 89.9,76.11 94.86,71.15 96.45,71.15 97.25,70.34 97.25,70.2 v2(97.5,69.95)
  BOTTOM w0.076: v2(97.5,69.95) 97.36,69.95 97.28,69.88 97.28,69.47 97.36,69.39 98.08,69.39 99.08,68.39 99.08,67.25 99.15,67.18 99.15,66.2 100.02,65.33 100.52,65.33 100.71,65.14 100.95,65.14 101.07,65.19 101.28,65.19 101.39,65.14 101.6,65.14 101.68,65.18 101.93,65.18 102.26,64.84 UC1.AY64
  BOTTOM w0.102: v2(63.9,73.59) 63.62,73.87 63.62,74.01 63.72,74.12 65.05,74.12 65.39,73.78 66.26,73.78 66.42,73.62 JDIMM1.55
DDR_A_DQS3: length 50
  IN1 w0.076: v2(97.69,64.57) 97.56,64.57 97.21,64.92 97.21,65.74 96.9,66.05 96.33,66.05 96.14,66.23 93.96,66.23 93.93,66.26
  IN1 w0.124: v2(61.61,67.5) 61.95,67.84 61.95,68.58 62.2,68.83 66.66,68.83 67.25,69.42 74.95,69.42 75.55,70.02 89.65,70.02 91.16,68.51 91.68,68.51 93.93,66.26
  BOTTOM w0.076: UC1.BA60 101.86,62.35 101.86,62.23 101.78,62.15 101.31,62.15 101.29,62.12 101.11,62.09 100.95,62.16 99.77,62.16 98.9,63.03 98.9,63.03 97.82,64.11 97.63,64.11 97.39,64.34 97.39,64.46 97.5,64.57 v2(97.69,64.57)
  BOTTOM w0.102: JDIMM1.76 60.07,68.38 60.23,68.53 61.18,68.53 61.84,67.87 61.84,67.73 v2(61.61,67.5)
DDR_A_DQS4: length 50.5
  IN1 w0.076: 89.48,47.66 89.49,47.66 89.51,47.64 89.56,47.64 89.58,47.61 90.31,47.61 91.95,49.26 96.22,49.26 96.54,49.58 96.54,49.75 v2(96.32,49.96)
  IN1 w0.124: 89.48,47.66 84.64,47.66 79.38,42.4 78.46,42.4 76.65,40.6 72.55,40.6 71.98,41.17 71.71,41.17 71.59,41.3 71.59,41.55 71.34,41.8 70.79,41.8 70.54,41.55 70.54,41.23 70.48,41.17 69.93,41.17 69.87,41.23 69.87,41.55 69.62,41.8 67.31,41.8 67.06,41.55 67.06,41.38 66.97,41.29 66.54,41.29 66.44,41.38 66.44,41.55 66.19,41.8 64.27,41.8 64.05,41.57 64.05,41.3 v2(63.9,41.16)
  BOTTOM w0.076: v2(96.32,49.96) 96.54,50.18 96.54,50.49 97.05,51 98.53,51 99.01,50.51 100.45,50.51 100.54,50.42 100.95,50.42 101.07,50.47 101.28,50.47 101.39,50.42 101.6,50.42 101.68,50.45 101.96,50.45 102.07,50.41 102.21,50.32 102.26,50.28 UC1.AY38
  BOTTOM w0.102: v2(63.9,41.16) 64.07,40.98 64.07,40.74 64.27,40.55 65.93,40.55 66.15,40.76 66.32,40.76 66.46,40.63 JDIMM1.179
DDR_A_DQS5: length 52
  IN1 w0.076: v2(96.05,46.45) 96.21,46.45 96.37,46.6 96.37,46.76 96.26,46.86 93.26,46.86 92.98,46.58 92.74,46.58 89.52,43.37 89.27,43.37 89.24,43.34 89.22,43.34
  IN1 w0.124: v2(62.37,35.76) 62.19,35.76 61.95,36 61.95,36.07 62.11,36.22 65.64,36.22 66.47,35.39 69.45,35.39 69.51,35.32 78.42,35.32 86.43,43.34 89.22,43.34
  BOTTOM w0.076: v2(96.05,46.45) 96.28,46.68 96.28,46.95 96.64,47.3 100.51,47.3 100.63,47.42 101.02,47.42 101.1,47.38 101.23,47.38 101.36,47.43 101.63,47.43 101.71,47.4 101.93,47.4 101.99,47.43 102.08,47.48 102.09,47.52 102.09,47.6 102.03,47.67 UC1.BA34
  BOTTOM w0.102: JDIMM1.200 59.92,35.38 60.07,35.53 60.18,35.53 60.28,35.43 60.28,35.26 60.49,35.05 61.89,35.05 62.1,35.26 62.1,35.49 v2(62.37,35.76)
DDR_A_DQS6: length 51.3
  IN1 w0.076: 89.22,39.44 89.24,39.45 89.27,39.45 90.65,40.83 90.65,41.34 93.08,43.78 96.4,43.78 96.65,44.03 96.65,44.45 v2(96.41,44.69)
  IN1 w0.124: v2(63.9,30.08) 64.06,30.25 64.06,30.46 64.42,30.81 67.77,30.81 68.33,30.25 69.22,30.25 69.36,30.11 75.46,30.11 76.16,30.81 79.42,30.81 88.05,39.44 89.22,39.44
  BOTTOM w0.076: UC1.AY30 102.3,45.31 102.27,45.34 101.99,45.47 101.68,45.47 101.6,45.44 101.39,45.44 101.28,45.49 101.07,45.49 100.95,45.44 100.34,45.44 100.31,45.47 99.77,45.47 99.56,45.26 96.8,45.26 96.56,45.02 96.56,44.84 v2(96.41,44.69)
  BOTTOM w0.102: JDIMM1.221 66.49,30.13 66.33,30.28 66.23,30.28 66.09,30.14 66.09,29.75 65.77,29.43 64.33,29.43 64.08,29.68 64.08,29.91 v2(63.9,30.08)
DDR_A_DQS7: length 54.6
  IN1 w0.124: v2(61.61,24.65) 61.93,24.96 61.93,25.09 62.18,25.33 66.08,25.33 66.61,24.81 76.26,24.81 78.15,26.7 81.16,26.7 87.98,33.52 89.01,33.52 93.84,38.34 93.84,40.71 v2(93.58,40.97)
  BOTTOM w0.076: UC1.BA26 102.03,42.68 102.09,42.62 102.09,42.54 102.08,42.49 101.99,42.44 101.93,42.42 101.71,42.42 101.63,42.45 101.36,42.45 101.23,42.4 101.12,42.4 100.98,42.45 100.59,42.45 100.38,42.24 99.57,42.24 99.38,42.05 94.39,42.05 93.77,41.43 93.77,41.16 v2(93.58,40.97)
  BOTTOM w0.102: v2(61.61,24.65) 61.88,24.65 61.98,24.75 61.98,24.9 61.76,25.12 60.6,25.12 60.51,25.03 60.23,25.03 60.08,24.87 JDIMM1.242
DDR_A_DQS#0: length 69.1
  IN1 w0.076: v2(107.49,75.77) 107.49,75.72 107.31,75.54 107.15,75.54 107.08,75.61 107.08,78.93 107.1,78.95
  IN1 w0.124: v2(64.66,84.64) 64.63,84.61 64.45,84.61 64.24,84.4 64.24,84.17 64.43,83.98 68.55,83.98 69.49,84.92 69.87,84.92 70.3,84.49 70.48,84.49 70.78,84.8 70.78,84.97 70.37,85.38 70.37,85.74 70.76,86.13 71.11,86.13 71.59,85.65 71.76,85.65 72.03,85.92 72.03,86.09 71.58,86.53 71.58,86.89 71.97,87.28 90.18,87.28 90.99,86.47 92.96,86.47 93.59,85.84 102.28,85.84 107.1,81.01 107.1,78.95
  BOTTOM w0.076: UC1.AM70 107.05,68.14 107.16,68.14 107.25,68.23 107.25,68.69 107.29,68.78 107.29,68.89 107.24,69.03 107.24,69.39 107.32,69.47 107.32,70.11 106.78,70.65 106.78,73.1 106.93,73.24 106.93,75.14 107.49,75.71 v2(107.49,75.77)
  BOTTOM w0.102: v2(64.66,84.64) 64.45,84.64 64.26,84.45 64.26,84.19 64.36,84.09 65.47,84.09 65.7,84.32 66.03,84.32 66.34,84.62 JDIMM1.11
DDR_A_DQS#1: length 58.8
  IN1 w0.124: v2(102.94,72.74) 102.94,73.05 103.11,73.22 103.11,73.57 102.01,74.67 98.85,74.67 98.26,75.26 97.35,75.26 90.76,81.85 84.29,81.85 82.93,80.49 73.07,80.49 71.82,79.24 66.18,79.24 65.71,79.71 61.99,79.71 61.74,79.46 61.74,79.21 v2(61.61,79.08)
  BOTTOM w0.076: v2(102.94,72.74) 102.94,73.01 103.05,73.13 103.19,73.13 104.17,72.14 104.17,69.53 104.26,69.45 104.26,69.06 104.2,68.95 104.2,68.73 104.26,68.62 104.26,68.41 104.22,68.33 104.22,68.04 104.31,67.86 104.44,67.72 104.47,67.7 104.49,67.7 UC1.AT69
  BOTTOM w0.102: JDIMM1.32 59.86,79.38 60.01,79.22 60.18,79.22 60.39,79.01 60.39,78.53 60.74,78.18 61.7,78.18 61.8,78.28 61.8,78.89 v2(61.61,79.08)
DDR_A_DQS#2: length 51.9
  IN1 w0.124: v2(63.14,73.59) 63.31,73.42 63.31,73.16 63.55,72.91 65.08,72.91 65.69,73.52 73.54,73.52 73.98,73.96 75.54,73.96 76.26,74.68 82.25,74.68 83.46,75.9 89.81,75.9 94.77,70.93 96.36,70.93 97.04,70.25 97.04,70.08 v2(96.92,69.95)
  BOTTOM w0.076: v2(96.92,69.95) 97.12,69.75 97.12,69.4 97.29,69.23 98.02,69.23 98.92,68.32 98.92,67.18 98.98,67.11 98.98,66.13 99.95,65.17 100.45,65.17 100.64,64.98 100.99,64.98 101.06,65.01 101.1,65.03 101.12,65.03 101.23,65.03 101.36,64.98 101.63,64.98 101.71,65.01 101.86,65.01 102,64.88 102,64.82 101.92,64.74 UC1.BA64
  BOTTOM w0.102: v2(63.14,73.59) 63.43,73.89 63.43,74.09 63.65,74.31 65.13,74.31 65.47,73.97 66.22,73.97 66.37,74.13 JDIMM1.53
DDR_A_DQS#3: length 50
  IN1 w0.076: v2(97.04,64.57) 97.04,65.67 96.83,65.88 96.26,65.88 96.07,66.07 93.82,66.07
  IN1 w0.124: 93.82,66.07 91.59,68.29 91.08,68.29 89.56,69.81 75.64,69.81 75.04,69.21 67.34,69.21 66.75,68.62 62.29,68.62 62.16,68.49 62.16,67.71 v2(62.37,67.5)
  BOTTOM w0.076: v2(97.04,64.57) 97.23,64.38 97.23,64.28 97.56,63.95 97.75,63.95 98.74,62.96 99.7,62 100.92,62 101.09,61.92 101.37,61.97 101.38,61.98 101.85,61.98 102.16,62.29 UC1.AY60
  BOTTOM w0.102: JDIMM1.74 60.08,68.88 60.23,68.72 61.26,68.72 62.03,67.95 62.03,67.84 v2(62.37,67.5)
DDR_A_DQS#4: length 50.5
  IN1 w0.076: v2(96.97,49.96) 96.7,49.7 96.7,49.51 96.29,49.1 92.02,49.1 90.38,47.45 89.57,47.45 89.48,47.45
  IN1 w0.124: 89.48,47.45 84.73,47.45 79.47,42.19 78.54,42.19 76.74,40.39 72.46,40.39 71.89,40.96 71.62,40.96 71.37,41.21 71.37,41.46 71.25,41.58 70.87,41.58 70.75,41.46 70.75,41.14 70.56,40.96 69.84,40.96 69.66,41.14 69.66,41.46 69.53,41.58 67.4,41.58 67.28,41.46 67.28,41.29 67.06,41.08 66.45,41.08 66.23,41.29 66.23,41.46 66.1,41.58 64.36,41.58 64.26,41.48 64.26,41.37 64.47,41.16 v2(64.66,41.16)
  BOTTOM w0.076: UC1.BA38 102,49.94 102.11,49.94 102.18,49.98 102.18,50.05 102.18,50.06 102.18,50.13 102.15,50.15 102.08,50.21 101.99,50.26 101.93,50.29 101.71,50.29 101.63,50.25 101.36,50.25 101.23,50.3 101.12,50.3 100.98,50.25 100.47,50.25 100.38,50.35 98.94,50.35 98.46,50.84 97.11,50.84 96.7,50.43 96.7,50.23 v2(96.97,49.96)
  BOTTOM w0.102: v2(64.66,41.16) 64.46,41.16 64.27,40.97 64.27,40.82 64.35,40.74 65.85,40.74 66.07,40.95 66.32,40.95 66.49,41.13 JDIMM1.177
DDR_A_DQS#5: length 51.8
  IN1 w0.076: 89.22,43.55 89.24,43.55 89.26,43.53 89.45,43.53 92.67,46.75 92.91,46.75 93.19,47.03 96.33,47.03 96.53,46.83 96.53,46.62 v2(96.7,46.45)
  IN1 w0.124: 89.22,43.55 86.34,43.55 78.33,35.54 69.6,35.54 69.53,35.61 66.56,35.61 65.73,36.43 62.02,36.43 61.74,36.16 61.74,35.89 v2(61.61,35.76)
  BOTTOM w0.076: UC1.AY34 102.34,47.57 102.26,47.49 102.23,47.41 102.21,47.36 102.07,47.28 101.96,47.23 101.68,47.23 101.6,47.27 101.39,47.27 101.28,47.22 101.07,47.22 100.98,47.26 100.7,47.26 100.58,47.14 96.71,47.14 96.45,46.88 96.45,46.7 v2(96.7,46.45)
  BOTTOM w0.102: v2(61.61,35.76) 61.75,35.76 61.91,35.6 61.91,35.34 61.81,35.24 60.57,35.24 60.47,35.34 60.47,35.51 60.25,35.72 60.08,35.72 59.92,35.87 JDIMM1.198
DDR_A_DQS#6: length 51.3
  IN1 w0.076: 89.28,39.22 90.81,40.76 90.81,41.27 93.15,43.61 96.47,43.61 96.82,43.96 96.82,44.44 v2(97.06,44.69)
  IN1 w0.089: 89.22,39.22 89.28,39.22
  IN1 w0.124: 89.22,39.22 88.14,39.22 79.51,30.6 76.25,30.6 75.54,29.89 69.27,29.89 69.13,30.04 68.24,30.04 67.68,30.6 64.51,30.6 64.28,30.37 64.28,30.26 64.45,30.08 v2(64.66,30.08)
  BOTTOM w0.076: UC1.BA30 102,44.99 102.07,45 102.15,45.08 102.15,45.16 102.11,45.21 101.99,45.28 101.93,45.31 101.71,45.31 101.63,45.27 101.36,45.27 101.23,45.32 101.1,45.32 100.99,45.27 100.27,45.27 100.24,45.3 99.84,45.3 99.63,45.09 96.87,45.09 96.73,44.95 96.73,44.88 96.92,44.69 v2(97.06,44.69)
  BOTTOM w0.102: v2(64.66,30.08) 64.49,30.08 64.27,29.85 64.27,29.76 64.41,29.62 65.69,29.62 65.9,29.83 65.9,30.22 66.15,30.47 66.32,30.47 66.47,30.63 JDIMM1.219
DDR_A_DQS#7: length 54.6
  IN1 w0.124: v2(62.37,24.65) 62.14,24.88 62.14,25 62.27,25.12 66,25.12 66.52,24.6 76.35,24.6 78.24,26.48 81.25,26.48 88.07,33.3 89.1,33.3 94.05,38.25 94.05,40.79 v2(94.23,40.97)
  BOTTOM w0.076: UC1.AY26 102.28,42.59 102.26,42.57 102.26,42.51 102.23,42.43 102.21,42.38 102.07,42.3 101.96,42.25 101.68,42.25 101.6,42.29 101.39,42.29 101.28,42.23 101.07,42.23 100.95,42.29 100.66,42.29 100.44,42.07 99.64,42.07 99.44,41.88 94.46,41.88 93.94,41.36 93.94,41.16 94.13,40.97 v2(94.23,40.97)
  BOTTOM w0.102: JDIMM1.240 60.07,25.38 60.23,25.22 60.43,25.22 60.52,25.31 61.84,25.31 62.17,24.98 62.17,24.85 v2(62.37,24.65)
DDR_A_MA0: length 48
  IN1 w0.076: 99.11,55.08 100,54.19 100.55,54.19 102.34,55.98 v2(102.34,56.32)
  IN1 w0.188: 99.11,55.08 99.09,55.1 78.27,55.1 74.48,51.3 69.78,51.3 69.4,50.93 66.55,50.93 66.15,50.52 63.32,50.52 v2(62.37,51.47)
  BOTTOM w0.076: UC1.AY50 102.15,56.51 v2(102.34,56.32)
  BOTTOM w0.17: JDIMM1.144 59.81,51.38 60.33,50.86 61.77,50.86 v2(62.37,51.47)
DDR_A_MA1: length 48.4
  IN1 w0.076: v2(96.8,58.68) 96.42,58.3 94.51,58.3 94.51,58.3 91.99,58.3 91.64,57.96
  IN1 w0.188: v2(63.9,53.78) 64.35,54.23 72.16,54.23 73.6,55.67 73.6,55.93 72.58,56.95 72.58,57.22 72.84,57.48 73.11,57.48 74.13,56.47 74.39,56.47 74.66,56.73 74.66,57 74.23,57.42 74.23,57.69 74.5,57.96 74.77,57.96 75.19,57.53 75.46,57.53 75.88,57.96 91.64,57.96
  BOTTOM w0.076: v2(96.8,58.68) 96.98,58.49 97.72,58.49 99.64,56.58 100.65,56.58 UC1.BB50
  BOTTOM w0.17: v2(63.9,53.78) 64.52,54.41 65.9,54.41 66.18,54.13 JDIMM1.133
DDR_A_MA2: length 49.8
  IN1 w0.076: 90.4,58.42 90.73,58.42 91.05,58.75 94.65,58.75 94.93,58.46 95.63,58.46 96.22,59.05 97.49,59.05 v2(97.51,59.03)
  IN1 w0.188: 90.4,58.42 72.93,58.42 72.11,57.6 72.11,56.51 72.72,55.91 72.72,55.64 71.77,54.7 64.09,54.7 63.77,54.38 63.33,54.38 63.01,54.7 62.71,54.7 62.37,54.37 v2(62.37,53.78)
  BOTTOM w0.076: UC1.AY51 102.33,57.25 102.06,57.25 102.01,57.2 101.92,57.17 101.7,57.17 101.66,57.19 101.3,57.19 101.28,57.17 101.26,57.17 101.07,57.17 100.99,57.2 100.64,57.2 100.34,56.91 99.92,56.91 97.8,59.03 v2(97.51,59.03)
  BOTTOM w0.17: JDIMM1.132 60.04,54.38 60.15,54.26 61.89,54.26 v2(62.37,53.78)
DDR_A_MA3: length 48.9
  IN1 w0.076: 90.02,58.89 90.19,59.06 95.17,59.06 v2(95.4,58.83)
  IN1 w0.188: v2(65.04,55.18) 68.24,55.18 68.75,55.68 69.17,55.68 69.36,55.87 69.36,56.14 69.64,56.42 70.13,56.42 70.42,56.13 70.42,55.87 70.25,55.7 70.25,55.35 70.44,55.17 70.78,55.17 70.95,55.34 71.22,55.34 71.35,55.2 71.62,55.2 71.88,55.47 71.88,55.74 70.27,57.35 70.27,57.62 70.53,57.89 70.8,57.89 71.15,57.53 71.42,57.53 71.69,57.8 71.69,58.06 71.33,58.42 71.33,58.68 71.54,58.89 71.84,58.89 72.23,58.5 72.35,58.5 72.74,58.89 90.02,58.89
  BOTTOM w0.076: UC1.BA50 101.35,56.63 101.2,56.63 100.99,56.41 99.57,56.41 97.67,58.31 95.92,58.31 v2(95.4,58.83)
  BOTTOM w0.17: v2(65.04,55.18) 65.79,55.18 66.35,54.62 JDIMM1.131
DDR_A_MA4: length 48.7
  IN1 w0.076: v2(93.85,59.57) 93.5,59.22 90.21,59.22 90.08,59.36
  IN1 w0.188: 90.08,59.36 71.34,59.36 70.6,58.62 68.73,58.62 68.29,58.18 68.29,57.71 68.48,57.52 69.33,57.52 69.52,57.33 69.52,56.96 69.33,56.77 68.48,56.77 68.29,56.58 68.29,55.9 68.1,55.71 62.18,55.71 61.99,55.52 v2(61.99,55.18)
  BOTTOM w0.076: v2(93.85,59.57) 94.41,60.14 97.24,60.14 97.66,59.73 97.8,59.73 99.48,58.05 100.8,58.05 UC1.BB52
  BOTTOM w0.17: v2(61.99,55.18) 61.51,55.66 60.38,55.66 60.09,55.38 JDIMM1.128
DDR_A_MA5: length 50.7
  IN1 w0.076: v2(95.61,59.58) 95.61,59.74 95.12,60.23 93.54,60.23 93.43,60.34 90.03,60.34 89.61,60.76
  IN1 w0.188: v2(61.99,56.63) 61.46,56.09 61.13,56.09 60.73,56.5 60.73,56.76 61.33,57.36 64.85,57.36 65.01,57.52 65.65,57.52 68.15,60.02 70.02,60.02 70.76,60.76 79.58,60.76 79.79,60.97 79.79,61.43 80.26,61.89 86.45,61.89 87.02,61.32 88.03,61.32 88.59,60.76 89.61,60.76
  BOTTOM w0.076: UC1.BA51 101.6,57.66 101.38,57.66 101.37,57.66 101.36,57.67 101.36,57.67 101.27,57.7 101.07,57.7 100.98,57.67 100.97,57.66 99.4,57.66 97.66,59.4 97.2,59.4 97.05,59.24 95.96,59.24 v2(95.61,59.58)
  BOTTOM w0.17: v2(61.99,56.63) 61.48,56.12 60.18,56.12 59.93,55.88 JDIMM1.126
DDR_A_MA6: length 49.8
  IN1 w0.076: 90.08,59.83 90.31,59.59 v2(93.26,59.59)
  IN1 w0.188: 90.08,59.83 87.64,59.83 87.46,60.01 87.46,60.2 87.27,60.39 86.89,60.39 86.7,60.2 86.7,60.01 86.52,59.83 86.14,59.83 85.95,60.01 85.95,60.41 85.77,60.6 85.39,60.6 85.2,60.41 85.2,60.01 85.01,59.83 71.15,59.83 70.41,59.09 68.54,59.09 67.82,58.37 67.82,57.87 67.63,57.68 67.14,57.68 66.96,57.49 66.96,57.11 67.14,56.93 67.63,56.93 67.82,56.73 67.82,56.37 67.63,56.18 63.71,56.18 63.52,56.38 v2(63.52,56.63)
  BOTTOM w0.076: UC1.BA52 101.28,58.1 101.02,58.35 100.69,58.35 100.55,58.22 99.55,58.22 97.87,59.89 97.77,59.89 97.36,60.3 93.7,60.3 93.26,59.87 v2(93.26,59.59)
  BOTTOM w0.17: JDIMM1.127 66.1,55.62 65.66,56.06 64.09,56.06 v2(63.52,56.63)
DDR_A_MA7: length 51
  IN1 w0.076: 89.3,61.7 90.33,60.67 93.64,60.67 94.28,61.31 95.29,61.31 v2(95.66,60.93)
  IN1 w0.188: v2(62.37,57.97) 62.21,58.14 62.21,58.41 62.39,58.59 63.05,58.59 63.22,58.42 64.95,58.42 65.14,58.61 65.14,59.36 65.33,59.55 66.36,59.55 68.3,61.49 68.79,61.49 68.83,61.45 68.83,61.45 69.33,60.96 69.63,60.96 70.37,61.7 74.16,61.7 74.34,61.88 74.34,62.64 74.53,62.83 86.84,62.83 87.41,62.26 88.42,62.26 88.98,61.7 89.3,61.7
  BOTTOM w0.076: UC1.AW52 102.61,58 102.27,58.33 101.79,58.33 101.6,58.52 100.62,58.52 100.48,58.38 99.61,58.38 97.47,60.52 95.74,60.52 95.66,60.6 v2(95.66,60.93)
  BOTTOM w0.17: JDIMM1.122 59.88,56.88 59.96,56.95 60.68,56.95 61.01,57.28 61.68,57.28 v2(62.37,57.97)
DDR_A_MA8: length 50.3
  IN1 w0.076: v2(95.03,59.57) 94.66,59.94 93.59,59.94 93.36,60.17 89.88,60.17 89.76,60.29
  IN1 w0.188: v2(65.04,56.63) 65.04,56.86 65.23,57.06 65.68,57.06 65.87,56.86 65.87,56.77 66,56.65 66.31,56.65 66.49,56.82 66.49,57.7 68.35,59.55 70.22,59.55 70.95,60.29 80.07,60.29 80.26,60.48 80.26,61.24 80.45,61.43 80.83,61.43 81.01,61.24 81.01,60.48 81.2,60.29 81.58,60.29 81.76,60.48 81.76,61.24 81.95,61.43 82.33,61.43 82.52,61.24 82.52,60.48 82.7,60.29 83.04,60.29 83.23,60.48 83.23,61.2 83.46,61.43 83.83,61.43 84.02,61.24 84.02,60.6 84.21,60.41 84.58,60.41 84.77,60.6 84.77,61.24 84.96,61.43 86.25,61.43 86.83,60.86 87.84,60.86 88.4,60.29 89.76,60.29
  BOTTOM w0.076: v2(95.03,59.57) 95.03,59.9 95.11,59.97 97.17,59.97 97.59,59.56 97.73,59.56 99.47,57.83 100.94,57.83 101.04,57.87 101.06,57.87 101.3,57.87 101.39,57.83 101.6,57.83 101.68,57.86 101.68,57.86 101.78,57.9 UC1.AY52
  BOTTOM w0.17: v2(65.04,56.63) 65.7,56.63 66.21,56.13 JDIMM1.125
DDR_A_MA9: length 48.6
  IN1 w0.076: v2(94.41,60.88) 94.03,60.5 90.18,60.5 89.44,61.24
  IN1 w0.188: 89.44,61.24 89.42,61.23 88.79,61.23 88.23,61.79 87.21,61.79 86.64,62.36 79.51,62.36 79.32,62.17 79.32,61.42 79.13,61.23 78.76,61.23 78.57,61.42 78.57,62.17 78.38,62.36 78.01,62.36 77.82,62.17 77.82,61.42 77.63,61.23 77.25,61.23 77.07,61.42 77.07,62.17 76.88,62.36 76.5,62.36 76.31,62.17 76.31,61.42 76.13,61.23 75.75,61.23 75.56,61.42 75.56,62.17 75.38,62.36 75,62.36 74.81,62.17 74.81,61.42 74.62,61.23 70.57,61.23 69.83,60.49 67.96,60.49 66.36,58.89 66.19,58.89 65.99,59.08 65.74,59.08 65.6,58.94 65.6,58.58 65.71,58.48 65.71,58.26 v2(65.42,57.97)
  BOTTOM w0.076: v2(94.41,60.88) 94.41,61.13 94.59,61.31 96.74,61.31 96.88,61.45 97.59,61.45 97.83,61.22 97.83,60.87 99.68,59.01 100.73,59.01 UC1.BB54
  BOTTOM w0.17: v2(65.42,57.97) 65.53,57.97 66.3,57.2 66.33,57.2 66.41,57.13 JDIMM1.121
DDR_A_MA10: length 51.6
  IN1 w0.076: v2(104.37,57.22) 104.37,57.53 104,57.9 103.29,57.9 102.71,57.32 102.71,56.12 100.2,53.61 95.16,53.61
  IN1 w0.188: v2(60.85,49.59) 61.32,50.06 66.34,50.06 66.74,50.46 69.6,50.46 69.97,50.84 74.67,50.84 78.47,54.63 93.11,54.63 94.14,53.61 95.16,53.61
  BOTTOM w0.076: UC1.AT50 104.61,57.02 104.41,57.22 v2(104.37,57.22)
  BOTTOM w0.17: v2(60.85,49.59) 60.13,48.87 JDIMM1.146
DDR_A_MA11: length 49.5
  IN1 w0.188: v2(97.44,61.09) 97.44,61.29 96.65,62.08 93.44,62.08 92.97,61.61 92.97,61.61 92.95,61.59 91.3,61.59 89.23,63.66 87.99,63.66 87.42,64.23 72.17,64.23 71.04,63.1 69.79,63.1 69.59,62.89 67.72,62.89 65.78,60.95 62.09,60.95 60.85,59.71 v2(60.85,57.97)
  BOTTOM w0.076: v2(97.44,61.09) 97.44,61.02 99.75,58.71 100.35,58.71 100.48,58.85 101.01,58.85 101.29,59.13 UC1.BA54
  BOTTOM w0.17: v2(60.85,57.97) 60.85,57.72 60.51,57.38 JDIMM1.120
DDR_A_MA12: length 50.3
  IN1 w0.076: v2(96.84,60.96) 96.14,61.66 94.13,61.66 93.3,60.83 90.59,60.83 88.7,62.72
  IN1 w0.188: v2(64.67,59.06) 64.54,59.06 64.03,59.58 64.03,59.84 64.2,60.02 64.53,60.02 64.67,59.88 65,59.88 65.13,60.02 66.16,60.02 68.11,61.96 68.99,61.96 69.35,61.6 69.61,61.6 70.18,62.16 72.18,62.16 72.37,62.35 72.37,63.11 72.56,63.3 72.94,63.3 73.12,63.11 73.12,62.31 73.28,62.16 73.72,62.16 73.88,62.31 73.88,63.11 74.06,63.3 87.03,63.3 87.6,62.72 88.7,62.72
  BOTTOM w0.076: UC1.AW54 102.58,59.22 102.27,58.92 101.72,58.92 101.49,58.68 100.55,58.68 100.41,58.55 99.68,58.55 97.51,60.72 96.92,60.72 96.84,60.79 v2(96.84,60.96)
  BOTTOM w0.17: JDIMM1.119 66.48,57.62 65.67,58.43 65.3,58.43 v2(64.67,59.06)
DDR_A_MA13: length 53.2
  IN1 w0.076: v2(104.36,54.48) 104.62,54.22 104.62,53.31 104.48,53.17 104.06,53.17 103.97,53.08 103.44,53.08 100.84,50.48 99.05,50.48 98.82,50.71 96.87,50.71 96.86,50.72
  IN1 w0.089: 89.56,50.43 89.69,50.56 92.25,50.56 92.41,50.72 96.86,50.72
  IN1 w0.188: 89.56,50.43 83.49,50.43 78.23,45.17 75.66,45.17 75.05,44.56 72.69,44.56 72.28,44.98 72.28,46 72.02,46.25 70.12,46.25 69.61,45.74 65.65,45.74 65.3,45.39 61.32,45.39 v2(60.85,45.86)
  BOTTOM w0.076: v2(104.36,54.48) 104.36,54.57 UC1.AU46
  BOTTOM w0.17: v2(60.85,45.86) 60.83,45.87 JDIMM1.158
DDR_A_ODT0: length 53.1
  IN1 w0.076: v2(104.25,53.55) 103.92,53.88 103.4,53.88 103.28,53.77 103.28,53.43 101.19,51.33 100.15,51.33 99.63,50.81 99.18,50.81 98.96,51.04 97.91,51.04 97.88,51.07 91.08,51.07 90.79,51.36
  IN1 w0.188: v2(63.9,46.8) 64.37,46.32 64.82,46.32 65.18,46.68 69.22,46.68 69.73,47.19 70.95,47.19 71.33,47.57 76.06,47.57 76.24,47.38 76.24,46.29 76.43,46.1 76.81,46.1 77,46.29 77,47.38 77.18,47.57 77.56,47.57 77.75,47.38 77.75,46.58 77.94,46.39 78.13,46.39 78.5,46.76 78.5,47.38 78.69,47.57 79.31,47.57 83.1,51.36 90.79,51.36
  BOTTOM w0.076: v2(104.25,53.55) 104.25,53.69 UC1.AT45
  BOTTOM w0.17: JDIMM1.155 65.95,46.63 65.65,46.33 64.37,46.33 v2(63.9,46.8)
DDR_A_ODT1: length 54.9
  IN1 w0.076: 96.7,50.55 98.75,50.55 98.98,50.32 99.17,50.32 99.9,49.59 100.45,49.59 101.52,50.66 101.52,50.85 102.97,52.3 103.75,52.3 104.21,52.75 v2(104.29,52.75)
  IN1 w0.089: 90.79,49.96 91.17,50.34 92.45,50.34 92.65,50.55 96.7,50.55
  IN1 w0.188: v2(63.9,44.71) 64.11,44.92 67.08,44.92 67.21,44.79 67.21,44.28 67.4,44.09 67.78,44.09 67.96,44.28 67.96,44.68 68.15,44.87 68.53,44.87 68.72,44.68 68.72,44.28 68.9,44.09 69.28,44.09 69.47,44.28 69.47,44.65 69.66,44.84 70.03,44.84 70.22,44.65 70.22,44.28 70.41,44.09 70.78,44.09 70.97,44.28 70.97,45.68 71.08,45.79 71.62,45.79 71.72,45.68 71.72,44.28 71.91,44.09 75.25,44.09 75.86,44.7 78.43,44.7 83.69,49.96 90.79,49.96
  BOTTOM w0.076: v2(104.29,52.75) 104.29,52.84 104.59,53.14 UC1.AT43
  BOTTOM w0.17: JDIMM1.161 64.31,45.13 v2(63.9,44.71)
DDR_A_PAR: length 49.1
  IN1 w0.076: v2(104.27,58.17) 103.32,58.17 100.97,55.82 100.53,55.82
  IN1 w0.188: 100.53,55.82 100.28,55.57 78.08,55.57 77.5,54.99 77.24,54.99 76.99,55.24 76.72,55.24 76.46,54.97 76.46,54.7 76.7,54.46 76.7,54.19 74.28,51.77 69.59,51.77 69.21,51.4 66.36,51.4 65.98,51.02 64.35,51.02 v2(63.9,51.47)
  BOTTOM w0.076: UC1.AT52 v2(104.27,58.17)
  BOTTOM w0.17: v2(63.9,51.47) 64.65,50.72 65.64,50.72 66.54,51.62 JDIMM1.143
DDR_A_RAS#: length 51.1
  IN1 w0.076: v2(103.59,56.32) 103.59,56.17 101.71,54.29 101.71,53.52 101.71,53.52 101.71,52.85 100.95,52.09 99.14,52.09 98.79,51.73 92.78,51.73 92,52.52
  IN1 w0.188: v2(62.37,47.71) 63.31,48.65 66.91,48.65 67.33,49.06 70.18,49.06 70.55,49.43 76.41,49.43 80.2,53.23 91.28,53.23 92,52.52
  BOTTOM w0.076: v2(103.59,56.32) 103.59,56.43 UC1.AU50
  BOTTOM w0.17: JDIMM1.152 60.25,47.38 60.36,47.27 61.93,47.27 v2(62.37,47.71)
DDR_A_WE#: length 50
  IN1 w0.076: 91.34,52.52 92.29,51.57 98.09,51.57 98.12,51.54 98.82,51.54 99.21,51.92 101.04,51.92 101.89,52.77 101.89,54.21 103.52,55.83 103.86,55.83 v2(104.28,55.41)
  IN1 w0.188: 91.34,52.52 91.09,52.76 85.46,52.76 80.4,52.76 76.6,48.97 70.75,48.97 70.37,48.59 67.52,48.59 67.11,48.18 64.37,48.18 v2(63.9,47.71)
  BOTTOM w0.076: UC1.AT46 v2(104.28,55.41)
  BOTTOM w0.17: JDIMM1.151 66.31,47.62 65.96,47.27 64.34,47.27 v2(63.9,47.71)
DDR_B_ACT#: length 70.4
  IN3 w0.076: 92.79,64.17 93.2,63.77 97.23,63.77 98.39,62.61 98.39,62.47 100.21,60.65 103.32,60.65 103.43,60.55 105.5,60.55 105.9,60.15 105.9,59.91 106.75,59.07 v2(106.88,59.07)
  IN3 w0.224: v2(46.65,60.3) 48.82,62.48 51.42,62.48 53.26,64.32 55.94,64.32 57.16,65.54 59.32,65.54 60.48,66.69 67.51,66.69 68.31,67.5 70.75,67.5 71.46,66.79 84.22,66.79 85.09,67.65 89.31,67.65 92.79,64.17
  BOTTOM w0.076: v2(106.88,59.07) 106.88,58.94 UC1.AN53
  BOTTOM w0.17: JDIMM2.114 45.72,59.38 v2(46.65,60.3)
DDR_B_ALERT#: length 74.9
  IN3 w0.076: 106.77,56.21 106.77,57.41 106.48,57.7 105.9,57.7 105.07,58.54 103.96,58.54 103.38,57.96 101.25,57.96 98.41,60.81 98.41,61.11 97.73,61.78 97.48,61.78 97.35,61.91 97.34,61.91 96.84,62.41 96.84,62.42 96.17,63.09 93.26,63.09
  IN3 w0.089: 106.77,56.21 107.26,55.73 107.26,54.28 106.65,53.67 v2(106.22,53.67) ; 93.26,63.09 92.98,62.81 91.24,62.81
  IN3 w0.224: 91.24,62.81 89.28,64.78 69.41,64.78 68.78,64.15 68.75,64.15 68.22,63.62 68.22,63.6 67.99,63.38 66.05,63.38 65.62,63.81 60.44,63.81 60.15,63.52 59.43,63.52 58.02,62.11 57.09,62.11 56.79,61.81 54,61.81 52.03,59.83 48.16,59.83 46.65,58.32 v2(46.65,58.14)
  BOTTOM w0.102: v2(106.22,53.67) UC1.AN43 ; v2(46.65,58.14) 46.65,58.61 46.39,58.87 JDIMM2.116
DDR_B_BG0: length 71.1
  IN3 w0.076: 91.81,63.73 92.11,63.43 97.09,63.43 98.06,62.47 98.06,61.92 99.66,60.32 100.52,60.32 101.38,59.47 105.83,59.47 v2(106.24,59.05)
  IN3 w0.224: 91.81,63.73 89.49,66.05 88.89,66.65 85.5,66.65 85.28,66.43 85.28,66.01 85.06,65.78 68.38,65.78 67.75,65.15 60.36,65.15 59.73,64.53 58.57,64.53 57.7,63.67 56.71,63.67 56.36,63.32 54.97,63.32 54.49,62.84 53.2,62.84 51.41,61.05 51.26,61.05 51.07,60.86 50.76,60.86 50.18,61.43 49.87,61.43 49.38,60.95 49.38,60.62 v2(49.7,60.3)
  BOTTOM w0.076: v2(106.24,59.05) 106.24,58.18 105.91,57.85 UC1.AP52
  BOTTOM w0.17: v2(49.7,60.3) 49.56,60.3 49.04,59.78 49.04,59.38 49.29,59.13 JDIMM2.115
DDR_B_BG1: length 71.1
  IN3 w0.076: 92.91,63.26 96.23,63.26 97.01,62.49 97.01,62.48 97.4,62.09 97.41,62.09 97.55,61.95 97.8,61.95 99.59,60.16 100.45,60.16 101.91,58.7 105.14,58.7 105.97,57.87 106.83,57.87 106.91,57.95 v2(106.91,58.09)
  IN3 w0.089: 91.35,63.5 91.69,63.16 92.8,63.16 92.91,63.26
  IN3 w0.224: 91.35,63.5 91.27,63.5 89.48,65.28 88.68,65.28 88.46,65.5 88.46,65.92 88.24,66.15 87.79,66.15 87.57,65.92 87.57,65.5 87.34,65.28 86.89,65.28 86.67,65.5 86.67,65.92 86.45,66.15 86,66.15 85.78,65.92 85.78,65.5 85.55,65.28 69.2,65.28 68.57,64.65 67.6,64.65 67.37,64.43 67.37,64.11 67.15,63.88 66.7,63.88 66.48,64.11 66.48,64.43 66.26,64.65 65.72,64.65 65.39,64.31 64.83,64.31 64.49,64.65 63.93,64.65 63.6,64.31 63.04,64.31 62.7,64.65 62.14,64.65 61.81,64.31 61.25,64.31 60.92,64.65 60.57,64.65 59.94,64.03 58.77,64.03 57.91,63.17 56.92,63.17 56.44,62.68 56.44,62.54 56.22,62.31 55.77,62.31 55.64,62.44 55.64,62.69 55.52,62.81 55.18,62.81 54.7,62.34 53.82,62.34 53.11,61.63 52.71,61.63 52.28,61.2 52.28,60.8 52.03,60.55 51.47,60.55 v2(51.22,60.3)
  BOTTOM w0.076: UC1.AN52 106.56,57.69 106.49,57.62 106.32,57.62 106.19,57.74 106.19,57.9 106.64,58.35 106.83,58.35 106.91,58.27 v2(106.91,58.09)
  BOTTOM w0.17: v2(51.22,60.3) 51.08,60.3 50.82,60.04 50.82,59.76 50.95,59.62 JDIMM2.113
DDR_B_BS0: length 67.8
  IN3 w0.076: v2(94.1,54.28) 93.73,54.28 93.66,54.21
  IN3 w0.224: v2(46.65,48.31) 46.46,48.12 44.17,48.12 43.95,48.34 43.95,49.15 44.17,49.37 52.63,49.37 54.01,47.99 59,47.99 59.46,47.53 60.09,47.53 60.38,47.24 60.38,46.6 60.66,46.33 66.89,46.33 68.17,47.61 72.53,47.61 75.08,50.15 79.6,50.15 83.02,53.58 91.79,53.58 92.43,54.21 93.66,54.21
  BOTTOM w0.076: v2(94.1,54.28) 94.87,53.51 99.43,53.51 99.6,53.34 100.79,53.34 UC1.BB44
  BOTTOM w0.17: JDIMM2.150 46.59,48.38 v2(46.65,48.31)
DDR_B_BS1: length 70.1
  IN3 w0.224: v2(51.22,49.87) 52.84,49.87 53.39,49.33 53.83,49.33 54.06,49.1 54.06,48.71 54.28,48.49 55.11,48.49 55.34,48.71 55.34,49.1 55.56,49.33 56.01,49.33 56.23,49.1 56.23,48.71 56.45,48.49 58.33,48.49 58.56,48.71 58.56,48.77 58.78,49 59.38,49 59.6,48.77 59.6,48.2 59.77,48.03 60.28,48.03 60.41,48.16 60.41,48.43 60.6,48.62 61.09,48.62 61.46,48.25 61.77,48.25 62.12,48.6 62.44,48.6 62.86,48.18 63.27,48.18 63.71,48.62 64.16,48.62 64.6,48.18 65.06,48.18 65.5,48.62 65.89,48.62 66.11,48.4 66.11,47.15 66.34,46.93 66.78,46.93 67.01,47.15 67.01,48.4 67.23,48.62 67.58,48.62 67.8,48.4 67.8,48.33 68.03,48.11 68.48,48.11 68.7,48.33 68.7,48.4 68.92,48.62 69.37,48.62 69.59,48.4 69.59,48.33 69.82,48.11 70.26,48.11 70.49,48.33 70.49,48.4 70.71,48.62 71.39,48.62 71.59,48.82 71.9,48.82 72.3,48.43 72.61,48.43 72.93,48.74 72.93,49.06 72.53,49.45 72.53,49.77 72.83,50.06 73.14,50.06 73.52,49.69 73.84,49.69 74.06,49.91 74.06,50.4 74.31,50.65 79.39,50.65 82.82,54.08 91.58,54.08 92.22,54.71 92.43,54.71 93.36,54.71 93.51,54.86 95.08,54.86 95.3,54.64 95.3,54.3 v2(95.28,54.28)
  BOTTOM w0.076: UC1.BA44 101.43,53.21 101.32,53.21 100.98,53.55 99.63,53.55 99.5,53.68 95.08,53.68 94.98,53.78 94.98,54.04 95.21,54.28 v2(95.28,54.28)
  BOTTOM w0.17: v2(51.22,49.87) 51.08,49.87 50.64,49.43 50.3,49.43 50.1,49.23 50.1,48.99 50.34,48.75 50.94,48.75 51.23,49.05 51.79,49.05 51.96,49.22 51.96,49.5 52.09,49.62 JDIMM2.145
DDR_B_CAS#: length 70.2
  IN3 w0.076: v2(97.27,52.43) 97.27,52.41 95.46,50.59 89.42,50.59 88.74,49.91
  IN3 w0.224: 88.74,49.91 84.4,49.91 81.12,46.63 76.54,46.63 71.51,41.61 68.08,41.61 66.16,39.68 60.24,39.68 58.55,41.37 58.55,42.41 57.6,43.37 55.65,43.37 55.13,43.89 53.13,43.89 51.43,45.59 48.42,45.59 46.75,47.26 v2(46.65,47.26)
  BOTTOM w0.076: v2(97.27,52.43) 97.27,52.13 97.19,52.04 96.4,52.04 96.32,52.12 96.32,52.65 96.85,53.18 99.29,53.18 99.46,53.01 100.45,53.01 100.62,52.85 100.99,52.85 101.1,52.9 101.22,52.9 101.44,52.83 101.58,52.83 101.74,52.89 101.92,52.89 102.08,52.81 102.18,52.81 UC1.AY43
  BOTTOM w0.17: v2(46.65,47.26) 46.61,47.26 46.23,46.87 JDIMM2.156
DDR_B_CKE0: length 67
  IN3 w0.175: 93.04,64.63 93.04,64.32 93.38,63.98 97.47,63.98 99.91,61.54 102.76,61.54 102.94,61.36 105.49,61.36 105.96,60.9 v2(107.01,60.9)
  IN3 w0.224: 93.04,64.63 89.52,68.16 84.88,68.16 84.01,67.29 71.67,67.29 70.96,68 60.69,68 59.22,66.53 57.44,66.53 55.74,64.82 52.34,64.82 v2(50.46,62.94)
  BOTTOM w0.076: UC1.AN56 v2(107.01,60.9)
  BOTTOM w0.17: v2(50.46,62.94) 51.96,61.44 51.96,60.87 52.21,60.62 JDIMM2.109
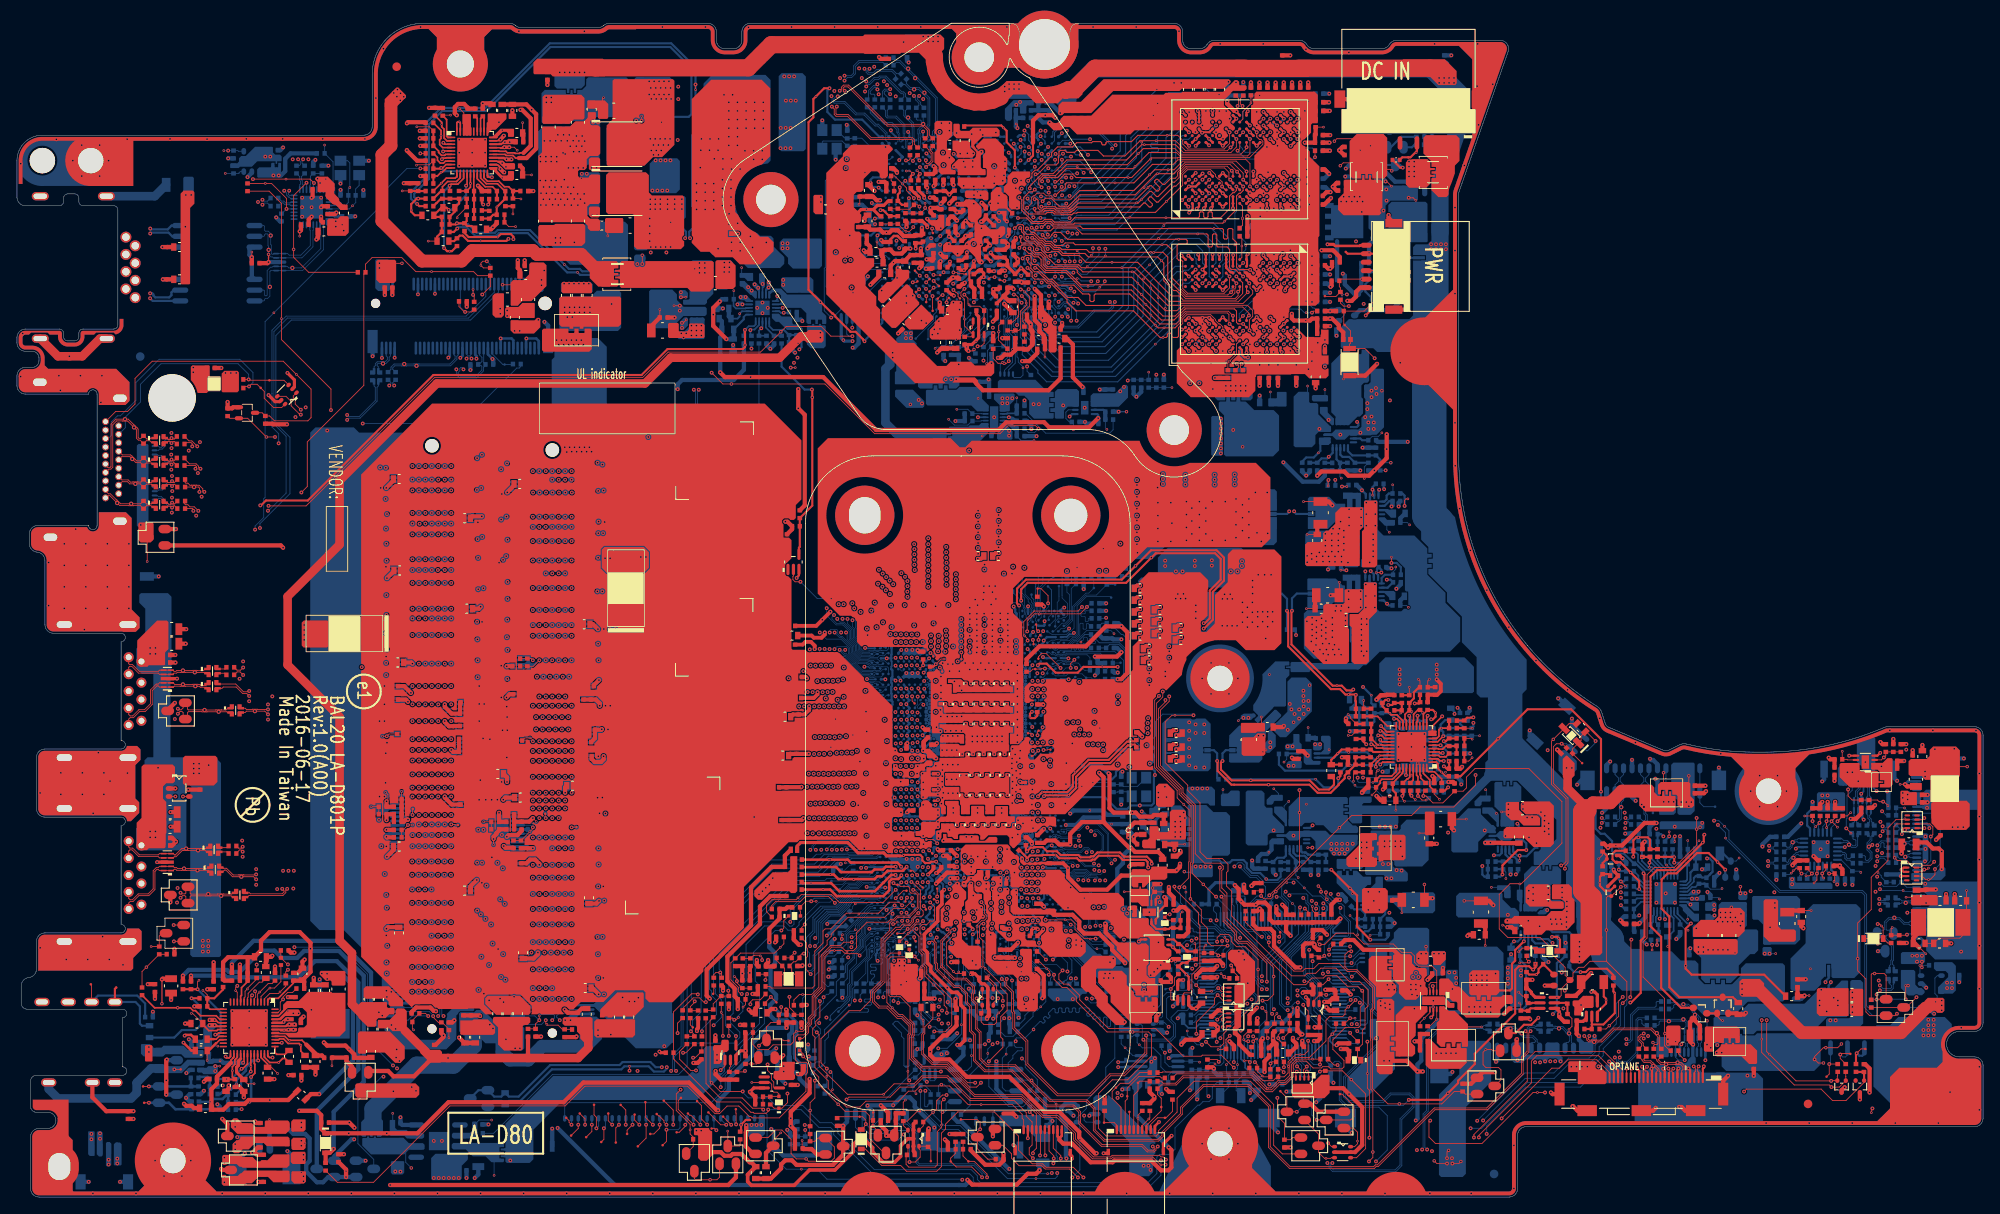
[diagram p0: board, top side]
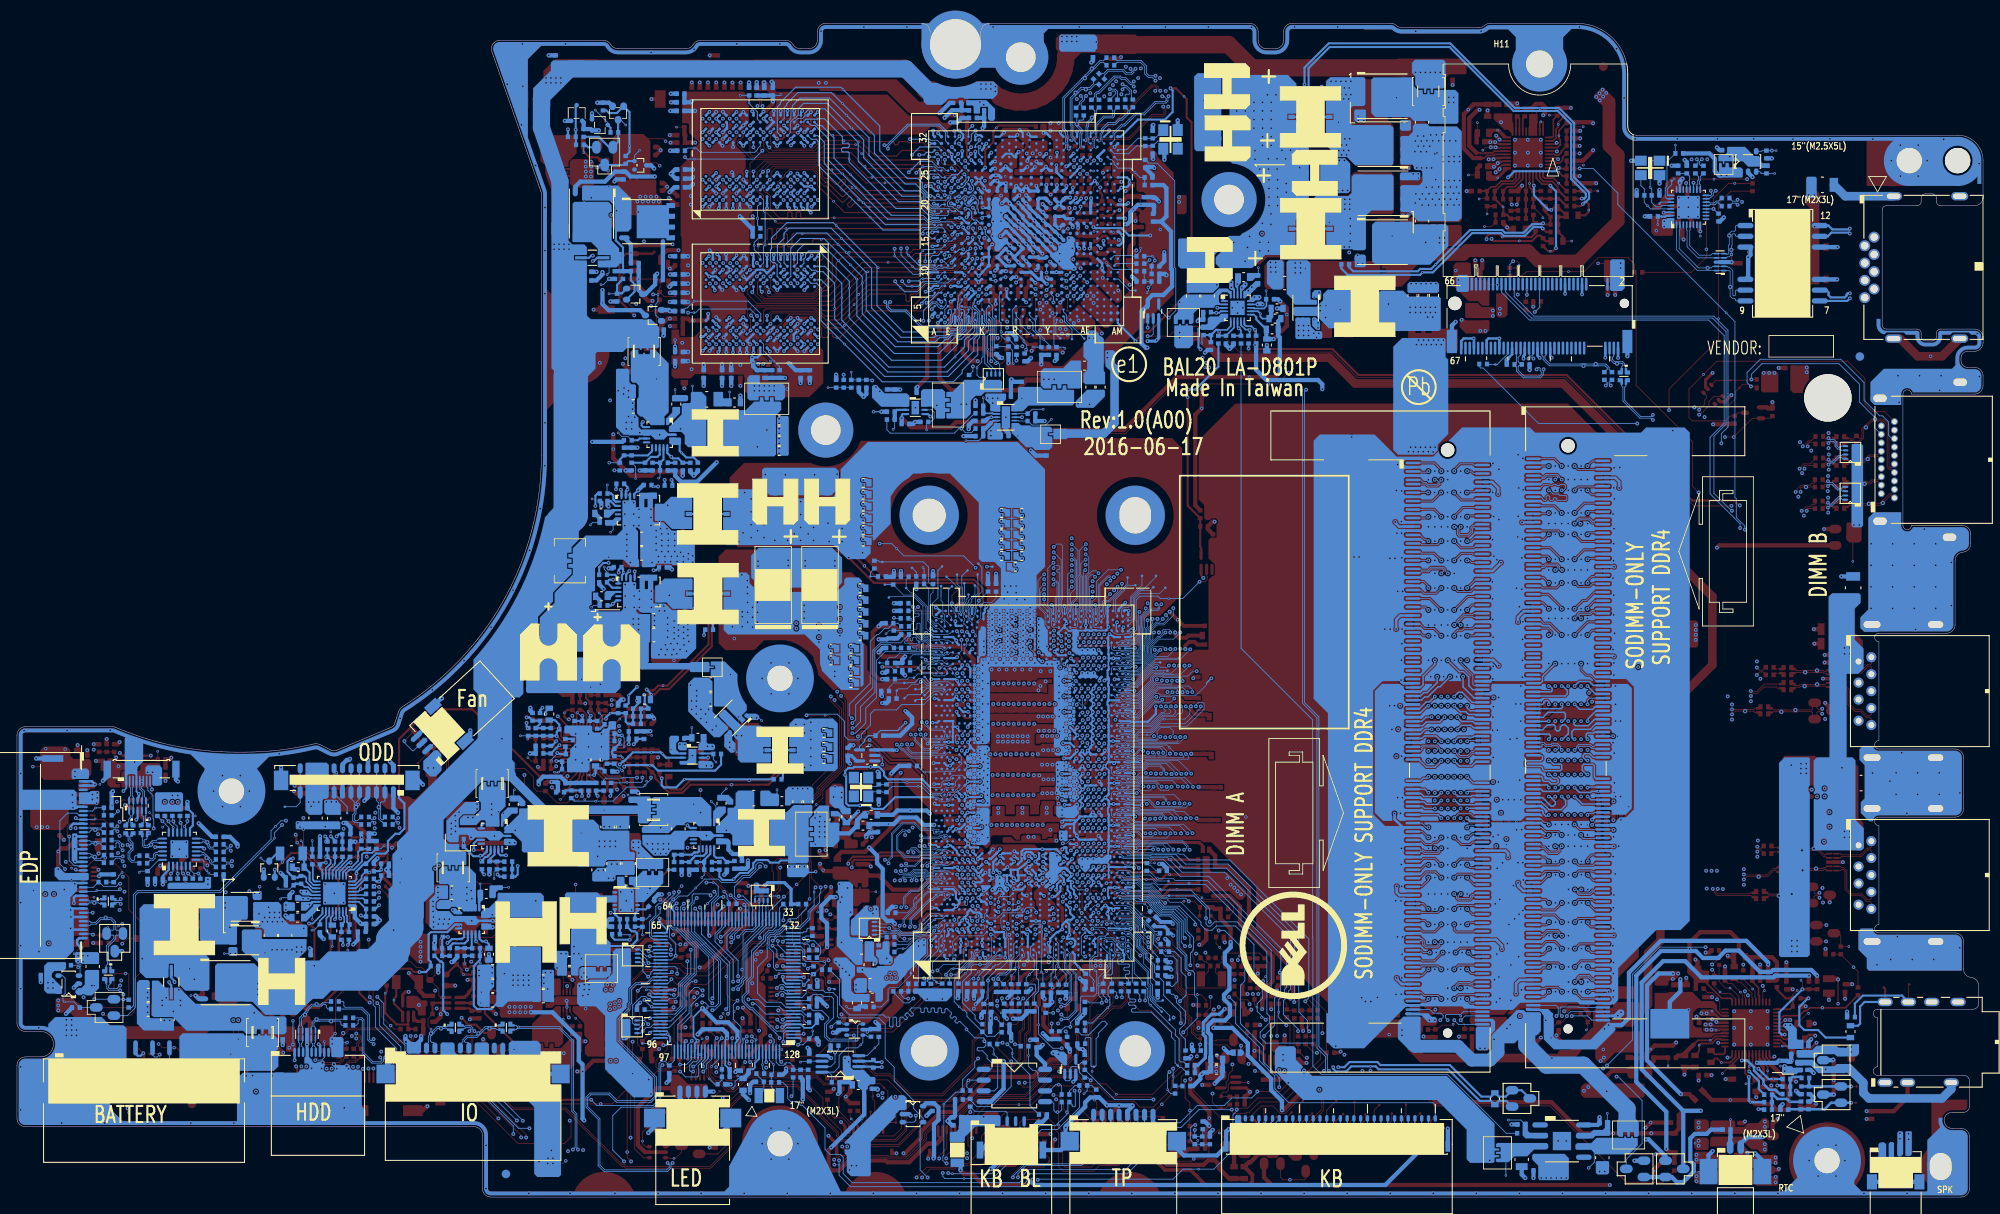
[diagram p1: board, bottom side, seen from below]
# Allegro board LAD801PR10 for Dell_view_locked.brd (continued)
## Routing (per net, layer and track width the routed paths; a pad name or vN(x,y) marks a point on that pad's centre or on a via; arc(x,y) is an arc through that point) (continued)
DDR_B_CKE1: length 67.7
  IN3 w0.076: 92.14,64.11 92.65,63.6 97.16,63.6 98.22,62.54 98.22,62.4 100.14,60.49 103.26,60.49 103.37,60.38 105.16,60.38 v2(105.54,60)
  IN3 w0.224: v2(48.17,60.3) 48.17,60.45 49.66,61.93 51.58,61.93 53.47,63.82 56.15,63.82 57.37,65.03 59.53,65.03 60.15,65.65 67.54,65.65 68.17,66.29 84.43,66.29 85.3,67.15 89.1,67.15 92.14,64.11
  BOTTOM w0.076: UC1.AP55 v2(105.54,60)
  BOTTOM w0.17: v2(48.17,60.3) 47.63,60.84 46.44,60.84 45.97,60.38 JDIMM2.110
DDR_B_CKE2: length 1.1
  TOP w0.102: v2(106.32,60.03) 106.32,59.84 TP5.1
  BOTTOM w0.076: UC1.AN55 106.56,59.78 v2(106.32,60.03)
DDR_B_CKE3: length 1.5
  TOP w0.102: v2(105.58,59.08) 105.58,58.54 TP6.1
  BOTTOM w0.076: v2(105.58,59.08) 105.92,58.67 UC1.AP53
DDR_B_CLK0: length 70.1
  IN3 w0.089: 102.32,54.69 102.49,54.86 105.72,54.86 105.81,54.77 105.81,54.62 v2(105.64,54.46)
  IN3 w0.142: v2(49.7,52.76) 49.99,52.46 49.99,52.26 50.17,52.08 53.74,52.08 54.3,51.52 57.17,51.52 57.5,51.2 58.06,51.2 58.52,51.66 60.44,51.66 60.74,51.96 66.03,51.96 66.17,51.82 66.17,51.54 66.46,51.25 67.1,51.25 67.39,51.54 67.39,51.82 67.53,51.96 67.91,51.96 68.81,52.85 69.48,52.85 69.62,52.71 69.62,51.75 69.91,51.46 70.55,51.46 70.84,51.75 70.84,52.71 70.98,52.85 71.59,52.85 71.88,53.14 71.88,53.54 72.02,53.68 72.45,53.68 72.59,53.54 72.59,53.14 72.88,52.85 73.51,52.85 73.8,53.14 73.8,53.29 73.94,53.43 74.37,53.43 74.51,53.29 74.51,53.14 74.8,52.85 78.48,52.85 81.9,56.28 90.3,56.28 90.32,56.3 90.69,56.3 90.86,56.47 97.71,56.47 98.8,55.39 100.54,55.39 100.86,55.07 100.86,54.87 101.25,54.47 102.1,54.47 102.32,54.69
  BOTTOM w0.076: v2(105.64,54.46) 105.91,54.18 UC1.AP45
  BOTTOM w0.102: JDIMM2.137 51.78,53.62 51.54,53.38 50.96,53.38 50.85,53.49 50.15,53.49 49.85,53.19 49.85,52.91 v2(49.7,52.76)
DDR_B_CLK1: length 69.3
  IN3 w0.076: v2(105.59,55.44) 105.66,55.44 105.9,55.68 105.9,55.78 105.81,55.87 105.25,55.87 105.18,55.79 103.33,55.79 103.06,55.52 102.45,55.52 102.18,55.79 101.97,55.79 101.74,56.02
  IN3 w0.142: 101.74,56.02 101.73,56.03 99.46,56.03 98.31,57.18 81.53,57.18 79.07,54.73 78.54,54.73 78.39,54.58 78.39,54.16 78.11,53.87 77.47,53.87 77.18,54.16 77.18,54.58 77.04,54.73 76.61,54.73 76.47,54.58 76.47,54.35 76.18,54.06 75.7,54.06 75.41,54.35 75.41,54.58 75.27,54.73 71.64,54.73 70.68,53.76 68.43,53.76 67.74,53.06 67,53.06 66.81,53.26 66.04,53.26 65.85,53.06 60.57,53.06 60.06,52.56 54.54,52.56 53.91,53.19 50.95,53.19 50.83,53.31 47.84,53.31 47.73,53.2 47.73,53.04 47.84,52.93 47.84,52.85 47.93,52.76 v2(48.17,52.76)
  BOTTOM w0.076: v2(105.59,55.44) 105.91,55.11 UC1.AP46
  BOTTOM w0.102: v2(48.17,52.76) 47.92,53.01 47.92,53.17 47.7,53.39 46.3,53.39 46.03,53.13 45.91,53.13 45.66,53.38 JDIMM2.138
DDR_B_CLK#0: length 70
  IN3 w0.089: 102.15,54.85 102.17,54.87 102.21,54.87 102.23,54.9 102.27,54.9 102.42,55.04 105.79,55.04 105.99,54.85 105.99,54.71 v2(106.23,54.47)
  IN3 w0.142: v2(50.46,52.76) 50.33,52.62 50.33,52.45 50.45,52.33 53.85,52.33 54.4,51.78 57.27,51.78 57.6,51.45 57.95,51.45 58.42,51.91 60.33,51.91 60.63,52.21 66.14,52.21 66.42,51.92 66.42,51.65 66.57,51.5 66.99,51.5 67.14,51.65 67.14,51.92 67.43,52.21 67.81,52.21 68.7,53.11 69.58,53.11 69.87,52.82 69.87,51.85 70.02,51.71 70.44,51.71 70.58,51.85 70.58,52.82 70.87,53.11 71.48,53.11 71.62,53.25 71.62,53.65 71.91,53.94 72.55,53.94 72.84,53.65 72.84,53.25 72.98,53.11 73.41,53.11 73.55,53.25 73.55,53.39 73.84,53.68 74.47,53.68 74.76,53.39 74.76,53.25 74.91,53.11 78.37,53.11 81.8,56.53 90.6,56.53 90.77,56.7 97.81,56.7 98.89,55.62 100.64,55.62 101.09,55.17 101.09,54.96 101.35,54.7 102,54.7 102.15,54.85
  BOTTOM w0.076: UC1.AN45 106.32,54.06 106.23,54.15 v2(106.23,54.47)
  BOTTOM w0.102: v2(50.46,52.76) 50.26,52.76 50.05,52.96 50.05,53.11 50.23,53.29 50.76,53.29 50.87,53.18 51.62,53.18 51.86,53.42 51.97,53.42 52.03,53.36 52.03,53.17 52.07,53.12 JDIMM2.139
DDR_B_CLK#1: length 69.3
  IN3 w0.076: v2(106.17,55.43) 106.06,55.53 106.06,55.85 105.88,56.03 105.18,56.03 105.11,55.95 103.27,55.95 102.99,55.68 102.51,55.68 102.25,55.95 102.04,55.95 101.94,56.05 101.94,56.1 101.92,56.12 101.92,56.17 101.9,56.18
  IN3 w0.142: v2(47.41,52.76) 47.41,53 47.48,53.06 47.48,53.31 47.74,53.56 50.94,53.56 51.06,53.44 54.01,53.44 54.64,52.81 59.96,52.81 60.46,53.32 65.75,53.32 65.94,53.51 66.91,53.51 67.11,53.32 67.64,53.32 68.33,54.01 70.57,54.01 71.54,54.98 75.37,54.98 75.66,54.69 75.66,54.46 75.81,54.31 76.08,54.31 76.22,54.46 76.22,54.69 76.51,54.98 77.14,54.98 77.43,54.69 77.43,54.27 77.57,54.12 78,54.12 78.14,54.27 78.14,54.69 78.43,54.98 78.97,54.98 81.43,57.43 98.38,57.43 99.56,56.26 101.83,56.26 101.9,56.18
  BOTTOM w0.076: UC1.AN46 v2(106.17,55.43)
  BOTTOM w0.102: JDIMM2.140 45.7,52.87 45.75,52.92 46.12,52.92 46.39,53.19 47.61,53.19 47.71,53.08 47.71,52.95 47.53,52.76 v2(47.41,52.76)
DDR_B_CS#0: length 67.3
  IN3 w0.076: 87.65,52.57 87.67,52.59 92.02,52.59 92.86,53.43 98.32,53.43 98.44,53.3 98.44,52.9 98,52.45 v2(97.92,52.45)
  IN3 w0.224: v2(51.22,48.31) 51.35,48.31 51.4,48.27 52.31,48.27 54.17,46.41 57.68,46.41 58.1,46.83 58.51,46.83 58.73,46.6 58.73,45.79 59.07,45.45 59.39,45.45 59.48,45.54 59.79,45.54 60.11,45.22 60.11,44.91 60.02,44.82 60.02,44.5 60.28,44.24 61.78,44.24 62,44.02 62,43.88 62.22,43.66 62.67,43.66 62.9,43.88 62.9,43.96 63.12,44.18 63.44,44.18 63.84,43.78 64.14,43.78 64.61,44.24 65.7,44.24 65.93,44.47 65.93,44.99 66.16,45.22 66.7,45.22 67.01,44.91 67.21,44.91 67.53,44.6 67.94,44.6 68.16,44.82 68.16,45.23 67.85,45.54 67.85,45.86 68.1,46.11 68.51,46.11 68.87,45.75 69.43,45.75 69.64,45.96 69.64,46.16 69.78,46.3 70.1,46.3 70.34,46.06 70.34,44.89 70.63,44.6 70.94,44.6 71.23,44.89 71.23,45.93 71.46,46.15 72.5,46.15 75.49,49.15 80.02,49.15 83.44,52.57 87.65,52.57
  BOTTOM w0.076: UC1.BB42 100.79,51.9 99.91,51.9 99.7,52.12 98.81,52.12 98.74,52.04 97.71,52.04 97.64,52.12 97.64,52.37 97.71,52.45 v2(97.92,52.45)
  BOTTOM w0.17: JDIMM2.149 51.41,48.62 51.22,48.44 v2(51.22,48.31)
DDR_B_CS#1: length 71.1
  IN3 w0.076: v2(94.02,52.28) 94.12,52.28 94.47,51.93 94.67,51.93 94.76,51.84 94.76,51.4 94.67,51.3 89.02,51.3 88.63,50.92 88.53,50.92
  IN3 w0.224: 88.53,50.92 83.98,50.92 80.7,47.64 76.12,47.64 71.1,42.61 67.9,42.61 67.67,42.84 67.2,42.84 66.83,42.47 66.83,41.77 65.74,40.69 60.66,40.69 59.56,41.79 59.56,42.83 58.01,44.37 56.06,44.37 55.55,44.89 53.55,44.89 51.85,46.6 49.8,46.6 49.57,46.82 49.57,47.14 v2(49.7,47.26)
  BOTTOM w0.076: v2(94.02,52.28) 93.92,52.28 93.7,52.06 93.7,51.74 93.77,51.66 99.18,51.66 99.28,51.76 99.59,51.76 99.77,51.57 100.45,51.57 100.5,51.53 100.99,51.53 101.02,51.54 101.17,51.6 102.36,51.6 102.46,51.7 102.46,51.88 102.38,51.96 UC1.AY42
  BOTTOM w0.17: JDIMM2.157 52.09,46.63 51.18,45.71 49.77,45.71 49.23,46.25 49.23,46.79 v2(49.7,47.26)
DDR_B_D0: length 86.5
  IN3 w0.076: v2(109.6,65.66) 110.13,66.19 110.13,68.86
  IN3 w0.089: 110.13,68.86 108.79,70.19 108.79,70.51
  IN3 w0.142: 108.79,70.51 107.92,71.38 107.92,78.86 101.77,85.01 72.6,85.01 67.62,89.99 61.82,89.99 54.53,82.7 53.7,82.7 52.56,81.56 47.49,81.56 v2(46.65,80.72)
  BOTTOM w0.076: UC1.AF65 109.86,65.29 v2(109.6,65.66)
  BOTTOM w0.102: JDIMM2.28 46.5,80.87 v2(46.65,80.72)
DDR_B_D1: length 85.2
  IN3 w0.076: v2(109.59,65.02) 109.19,65.42 109.19,68.1 107.38,69.92 107.38,70.07
  IN3 w0.142: 107.38,70.07 106.34,71.11 106.34,78.92 101.32,83.94 83.41,83.94 82,82.53 78.75,82.53 78.6,82.68 78.6,82.94 78.46,83.08 78.18,83.08 78.04,82.94 78.04,82.68 77.89,82.53 77.47,82.53 77.33,82.68 77.33,83.8 77.19,83.94 71.97,83.94 70.22,85.69 67.74,85.69 66.46,86.96 60.31,86.96 54.98,81.63 54.15,81.63 52.71,80.19 50.23,80.19 v2(49.7,80.72)
  BOTTOM w0.076: v2(109.59,65.02) 109.84,64.65 UC1.AF64
  BOTTOM w0.102: v2(49.7,80.72) 50.54,81.56 51.98,81.56 52.05,81.62 JDIMM2.25
DDR_B_D2: length 85.5
  IN3 w0.076: v2(107.81,64.96) 107.44,65.32 107.44,65.64 107.17,65.92 107.17,66.94 104.95,69.16 104.65,69.16 104.22,69.59 104.19,69.59 103.97,69.81 103.97,69.92
  IN3 w0.142: 103.97,69.92 103.97,69.97 103.88,70.06 103.88,72.41 101.85,74.44 100.24,74.44 99.98,74.7 97.91,74.7 93.71,78.91 85.3,78.91 85.16,79.05 85.16,79.83 85.01,79.97 84.73,79.97 84.59,79.83 84.59,79.05 84.44,78.91 84.18,78.91 84.03,79.05 84.03,80.1 83.89,80.25 83.61,80.25 83.46,80.1 83.46,79.05 83.32,78.91 83.04,78.91 82.89,79.05 82.89,80.1 82.75,80.25 82.47,80.25 82.33,80.1 82.33,79.05 82.18,78.91 81.9,78.91 81.76,79.05 81.76,80.1 81.61,80.25 81.33,80.25 81.19,80.1 81.19,79.05 81.05,78.91 80.76,78.91 80.62,79.05 80.62,80.1 80.48,80.25 71.27,80.25 69.09,82.42 59.96,82.42 58.37,80.84 57.4,80.84 54.88,78.32 54.01,78.32 53.11,77.41 48.32,77.41 48.17,77.56 v2(48.17,78.2)
  BOTTOM w0.076: UC1.AK65 108.11,65.26 v2(107.81,64.96)
  BOTTOM w0.102: JDIMM2.42 45.74,77.38 45.76,77.36 47.34,77.36 v2(48.17,78.2)
DDR_B_D3: length 86.1
  IN3 w0.076: v2(108.65,64.4) 108.49,64.57 107.55,64.57 107.28,64.84 107.28,65.57 107,65.85 107,66.84 105.01,68.83 104.71,68.83 103.87,69.68 103.68,69.68
  IN3 w0.142: 103.68,69.68 103.52,69.84 103.52,71.2 100.64,74.08 100.1,74.08 99.83,74.35 97.77,74.35 93.56,78.55 80.22,78.55 80.07,78.7 80.07,79.57 79.93,79.72 79.65,79.72 79.51,79.57 79.51,78.7 79.36,78.55 79.09,78.55 78.95,78.7 78.95,79.57 78.81,79.72 78.53,79.72 78.38,79.57 78.38,78.7 78.24,78.55 77.96,78.55 77.81,78.7 77.81,79.57 77.67,79.72 77.39,79.72 77.24,79.57 77.24,78.7 77.1,78.55 76.82,78.55 76.68,78.7 76.68,79.57 76.53,79.72 76.25,79.72 76.11,79.57 76.11,78.7 75.96,78.55 75.68,78.55 75.54,78.7 75.54,79.57 75.4,79.72 75.11,79.72 74.97,79.57 74.97,78.7 74.83,78.55 74.56,78.55 73.41,79.7 71.3,79.7 68.94,82.07 60.11,82.07 57.56,79.52 57.1,79.52 54.79,77.21 53.41,77.21 53.25,77.05 47.79,77.05 v2(46.65,78.2)
  BOTTOM w0.076: v2(108.65,64.4) 108.44,64.61 UC1.AK64
  BOTTOM w0.102: v2(46.65,78.2) 46.63,78.2 46.46,78.38 JDIMM2.38
DDR_B_D4: length 85.6
  IN3 w0.076: 109.93,67.88 109.93,66.6 v2(109.59,66.26)
  IN3 w0.142: v2(48.17,80.72) 48.65,81.2 52.71,81.2 53.85,82.35 54.68,82.35 61.97,89.63 67.48,89.63 72.46,84.65 101.62,84.65 107.06,79.21 107.06,71.56 108.75,69.87 108.75,69.06 109.93,67.88
  BOTTOM w0.076: UC1.AF66 110.01,65.94 109.69,66.26 v2(109.59,66.26)
  BOTTOM w0.102: v2(48.17,80.72) 47.02,81.87 JDIMM2.24
DDR_B_D5: length 85.2
  IN3 w0.076: v2(109.56,66.84) 109.56,67.97 107.84,69.69 107.84,70.11 107.76,70.19
  IN3 w0.142: v2(51.22,80.72) 51.34,80.84 52.86,80.84 54,81.99 54.83,81.99 62.12,89.28 67.33,89.28 72.31,84.3 79.04,84.3 79.18,84.15 79.18,83.67 79.33,83.53 79.61,83.53 79.75,83.67 79.75,84.15 79.89,84.3 80.16,84.3 80.31,84.15 80.31,83.03 80.45,82.89 80.73,82.89 80.88,83.03 80.88,84.15 81.02,84.3 81.3,84.3 81.44,84.15 81.44,83.03 81.59,82.89 81.86,82.89 82,83.03 82,84.15 82.14,84.3 101.47,84.3 106.7,79.07 106.7,71.25 107.76,70.19
  BOTTOM w0.076: v2(109.56,66.84) 109.73,66.84 UC1.AF67
  BOTTOM w0.102: v2(51.22,80.72) 51.32,80.62 JDIMM2.29
DDR_B_D6: length 84
  IN3 w0.076: v2(107.81,66.26) 107.81,66.77 107.26,67.32 107.26,67.94 105.28,69.92
  IN3 w0.142: v2(51.22,78.2) 51.29,78.13 52.81,78.13 53.72,79.04 54.58,79.04 57.1,81.55 58.07,81.55 60.68,84.16 60.72,84.16 60.86,84.3 60.86,84.97 61,85.11 61.29,85.11 61.43,84.97 61.43,84.3 61.57,84.16 61.86,84.16 62,84.3 62,84.97 62.14,85.11 62.42,85.11 62.57,84.97 62.57,84.3 62.71,84.16 65.94,84.16 66.09,84.02 66.09,83.61 66.23,83.47 66.51,83.47 66.65,83.61 66.65,84.02 66.8,84.16 67.07,84.16 67.21,84.02 67.21,83.61 67.35,83.46 67.64,83.46 67.78,83.61 67.78,84.02 67.92,84.16 69.59,84.16 70.07,83.68 70.07,83.48 69.66,83.07 69.66,82.87 69.86,82.67 70.06,82.67 70.47,83.08 70.67,83.08 70.87,82.87 70.87,82.67 70.46,82.26 70.46,82.06 70.66,81.86 70.87,81.86 71.27,82.27 71.48,82.27 71.68,82.07 71.68,81.87 71.27,81.46 71.27,81.26 71.47,81.06 71.67,81.06 72.08,81.47 72.28,81.47 72.78,80.96 90.41,80.96 90.55,80.82 90.55,80.3 90.69,80.16 90.98,80.16 91.12,80.3 91.12,80.82 91.26,80.96 91.61,80.96 91.76,80.82 91.76,79.8 91.9,79.65 92.18,79.65 92.32,79.8 92.32,80.82 92.47,80.96 92.67,80.96 98.21,75.42 100.28,75.42 100.54,75.16 102.15,75.16 104.6,72.71 104.6,70.6 105.28,69.92
  BOTTOM w0.076: v2(107.81,66.26) 108.11,66.56 UC1.AK67
  BOTTOM w0.102: JDIMM2.41 51.79,77.62 v2(51.22,78.2)
DDR_B_D7: length 84.5
  IN3 w0.076: 104.3,69.9 104.3,69.75 104.56,69.49 104.86,69.49 107.33,67.01 107.33,66.07 v2(107.81,65.6)
  IN3 w0.142: 104.3,69.9 104.3,69.96 104.3,70.4 104.24,70.46 104.24,72.56 102,74.8 100.39,74.8 100.13,75.06 98.06,75.06 93.86,79.27 90.21,79.27 90.05,79.42 90.05,80.46 89.91,80.61 89.64,80.61 89.5,80.46 89.5,79.41 89.35,79.27 89.07,79.27 88.93,79.41 88.93,80.46 88.79,80.61 88.5,80.61 88.36,80.46 88.36,79.41 88.22,79.27 87.93,79.27 87.79,79.41 87.79,80.46 87.65,80.61 87.36,80.61 87.22,80.46 87.22,79.41 87.08,79.27 86.79,79.27 86.65,79.41 86.65,80.46 86.51,80.61 86.22,80.61 86.08,80.46 86.08,79.41 85.94,79.27 85.66,79.27 85.51,79.41 85.51,80.46 85.37,80.61 71.41,80.61 69.24,82.78 66.4,82.78 65.42,83.76 60.79,83.76 58.22,81.19 57.25,81.19 54.73,78.68 53.87,78.68 52.96,77.77 50.12,77.77 v2(49.7,78.2)
  BOTTOM w0.076: v2(107.81,65.6) 108.18,65.86 UC1.AK66
  BOTTOM w0.102: JDIMM2.37 52.14,78.62 52.12,78.6 50.1,78.6 v2(49.7,78.2)
DDR_B_D8: length 89.4
  IN3 w0.076: v2(110.74,72.31) 111.95,73.52 111.95,74.93
  IN3 w0.142: v2(48.17,86.26) 48.7,85.74 51.3,85.74 59.17,93.6 70.16,93.6 73.68,90.08 73.68,89.33 74.4,88.62 103.27,88.62 111.95,79.94 111.95,74.93
  BOTTOM w0.076: v2(110.74,72.31) 111.31,71.73 111.31,69.72 110.32,68.73 UC1.AF70
  BOTTOM w0.102: v2(48.17,86.26) 47.77,85.85 46.09,85.85 46.07,85.88 JDIMM2.8
DDR_B_D9: length 90.7
  IN3 w0.076: 111.59,75.25 111.59,74.34 v2(110.74,73.49)
  IN3 w0.142: 111.59,75.25 111.59,79.79 103.12,88.26 74.25,88.26 73.33,89.18 73.33,89.93 70.01,93.24 59.32,93.24 51.45,85.38 47.06,85.38 46.65,85.79 v2(46.65,86.26)
  BOTTOM w0.076: v2(110.74,73.49) 111.47,72.76 111.47,69.65 110.64,68.81 110.64,68.36 110.54,68.27 110.54,67.53 UC1.AF68
  BOTTOM w0.102: JDIMM2.4 46.03,86.88 v2(46.65,86.26)
DDR_B_D10: length 89
  IN3 w0.142: v2(109.64,74.2) 109.92,74.2 110.07,74.35 110.07,79.16 102.48,86.74 73.61,86.74 71.8,88.55 71.8,89.3 69.38,91.72 59.95,91.72 57.53,89.3 57.53,88.43 54.77,85.66 54.22,85.66 51.84,83.29 51.33,83.29 v2(51.22,83.39)
  BOTTOM w0.076: UC1.AH71 109.05,69.21 109.05,70.55 108.9,70.7 108.9,73.66 108.97,73.74 109.18,73.74 109.26,73.81 109.26,73.97 109.18,74.04 108.97,74.04 108.9,74.12 108.9,74.37 109.05,74.52 109.48,74.52 109.64,74.36 v2(109.64,74.2)
  BOTTOM w0.102: JDIMM2.21 52.14,82.62 51.96,82.45 51.96,82.38 51.77,82.19 51.63,82.19 51.53,82.29 51.53,82.66 51.42,82.76 51.22,82.76 51.12,82.66 51.12,82.29 51.02,82.19 50.79,82.19 50.69,82.29 50.69,82.41 50.59,82.51 50.38,82.51 50.28,82.41 50.28,82.29 50.18,82.19 49.21,82.19 49.1,82.29 49.1,82.68 49.21,82.78 49.92,82.78 50.09,82.95 50.71,82.95 51.15,83.39 v2(51.22,83.39)
DDR_B_D11: length 90.7
  IN3 w0.142: v2(109.64,74.85) 109.59,74.85 108.57,75.88 108.57,79.13 102.04,85.66 72.87,85.66 67.89,90.64 61.26,90.64 54.98,84.36 54.43,84.36 52.29,82.21 47.66,82.21 47.52,82.35 47.52,82.69 47.37,82.83 47.09,82.83 46.95,82.69 46.95,82.35 46.8,82.21 45.72,82.21 45.48,82.45 45.48,83.64 45.63,83.78 46.51,83.78 46.65,83.64 v2(46.65,83.39)
  BOTTOM w0.076: v2(109.64,74.85) 110.31,74.19 110.31,69.79 109.89,69.37 109.89,69.03 109.89,69.03 109.92,68.94 109.92,68.74 109.89,68.65 109.89,68.65 109.89,68.65 109.88,68.63 109.88,68.41 109.92,68.28 109.92,68.02 109.9,68 109.9,67.95 109.89,67.93 109.89,67.67 109.88,67.66 109.88,67.41 109.68,67.21 UC1.AH68
  BOTTOM w0.102: v2(46.65,83.39) 46.14,82.87 JDIMM2.20
DDR_B_D12: length 88
  IN3 w0.076: v2(110.73,71.72) 111.13,71.72 112.08,72.68
  IN3 w0.142: 112.08,72.68 112.39,72.98 112.39,80.01 103.41,88.98 74.54,88.98 74.04,89.48 74.04,90.23 70.31,93.96 58.92,93.96 53.89,88.92 53.69,88.92 53.38,89.23 53.18,89.23 52.98,89.03 52.98,88.83 53.28,88.52 53.28,88.32 53.08,88.12 52.88,88.12 52.57,88.43 52.37,88.43 52.17,88.23 52.17,88.02 52.48,87.72 52.48,87.52 52.28,87.32 52.08,87.32 51.77,87.62 51.57,87.62 51.37,87.42 51.37,87.22 51.67,86.91 51.67,86.71 v2(51.22,86.26)
  BOTTOM w0.076: v2(110.73,71.72) 111.14,71.31 111.14,69.99 UC1.AF71
  BOTTOM w0.102: JDIMM2.7 52.17,86.13 52.03,86.26 v2(51.22,86.26)
DDR_B_D13: length 89.8
  IN3 w0.076: v2(110.74,70.54) 111.37,70.54 112.08,71.26
  IN3 w0.142: v2(49.7,86.26) 57.76,94.32 70.46,94.32 75.44,89.34 103.56,89.34 112.74,80.16 112.74,71.92 112.08,71.26
  BOTTOM w0.076: UC1.AF69 110.12,67.96 110.12,68.23 110.09,68.33 110.08,68.33 110.05,68.41 110.05,68.62 110.09,68.71 110.09,68.97 110.05,69.06 110.05,69.3 110.74,69.99 v2(110.74,70.54)
  BOTTOM w0.102: v2(49.7,86.26) 50.56,87.13 JDIMM2.3
DDR_B_D14: length 89.3
  IN3 w0.142: v2(48.17,83.39) 48,83.39 47.86,83.25 47.86,82.79 48.08,82.57 48.43,82.57 48.57,82.71 48.57,82.82 48.71,82.96 49,82.96 49.14,82.82 49.14,82.71 49.28,82.57 52.14,82.57 54.44,84.86 54.98,84.86 61.11,91 68.04,91 68.33,90.71 68.53,90.71 68.82,91 69.02,91 69.22,90.8 69.22,90.6 68.93,90.31 68.93,90.11 69.14,89.91 69.34,89.91 69.66,90.23 69.86,90.23 70.06,90.02 70.06,89.82 69.74,89.5 69.74,89.3 73.02,86.02 102.19,86.02 108.93,79.28 108.93,78.96 109.07,78.82 109.11,78.82 109.25,78.67 109.25,78.39 109.11,78.25 109.07,78.25 108.93,78.1 108.93,77.82 109.07,77.68 109.11,77.68 109.25,77.54 109.25,77.25 109.11,77.11 109.07,77.11 108.93,76.97 108.93,76.05 109.07,75.91 109.44,75.91 v2(109.61,76.08)
  BOTTOM w0.076: UC1.AH70 109,68.66 108.85,68.8 108.85,68.81 108.85,68.81 108.73,69.06 108.73,69.3 108.88,69.45 108.88,70.48 108.73,70.63 108.73,75.2 v2(109.61,76.08)
  BOTTOM w0.102: v2(48.17,83.39) 47.77,83.8 45.79,83.8 45.71,83.87 JDIMM2.16
DDR_B_D15: length 91
  IN3 w0.142: v2(49.7,83.39) 50.16,82.93 51.99,82.93 54.37,85.31 54.91,85.31 58.16,88.55 58.16,88.75 57.93,88.99 57.93,89.19 58.13,89.39 58.33,89.39 58.56,89.16 58.76,89.16 58.96,89.36 58.96,89.56 58.73,89.79 58.73,89.99 58.93,90.19 59.13,90.19 59.37,89.96 59.57,89.96 59.77,90.16 59.77,90.36 59.54,90.6 59.54,90.8 59.74,91 59.94,91 60.17,90.77 60.37,90.77 60.97,91.36 69.23,91.36 70.63,89.96 70.63,89.75 70.32,89.43 70.32,89.23 70.52,89.03 70.72,89.03 71.04,89.35 71.24,89.35 71.44,89.15 71.44,88.4 73.47,86.38 102.34,86.38 109.61,79.11 v2(109.61,76.71)
  BOTTOM w0.076: UC1.AH69 109,68.07 108.6,68.46 108.6,68.95 108.56,69.02 108.56,69.37 108.72,69.52 108.72,70.39 108.57,70.54 108.57,76.85 108.77,77.05 109.27,77.05 v2(109.61,76.71)
  BOTTOM w0.102: v2(49.7,83.39) 49.68,83.37 49.53,83.37 49.24,83.66 49.24,83.93 49.38,84.08 49.87,84.08 49.97,83.97 50.27,83.97 50.37,84.08 50.68,84.08 50.78,83.97 51.08,83.97 51.19,84.08 51.79,84.08 52.24,83.62 JDIMM2.17
DDR_B_D16: length 69.9
  IN3 w0.076: v2(104.27,66.4) 104.27,67.44 102.91,68.79 102.45,68.79 101.97,69.28
  IN3 w0.142: 101.97,69.28 101.96,69.29 101.96,70.51 101.23,71.23 101.01,71.23 99.27,72.98 97.2,72.98 93.74,76.43 83.91,76.43 83.16,77.19 80.36,77.19 80.21,77.04 80.21,76.5 80.07,76.36 79.79,76.36 79.64,76.5 79.64,77.04 79.5,77.19 73.99,77.19 72.96,78.22 70.36,78.22 69.46,79.12 67.18,79.12 65.6,80.7 60.67,80.7 58.13,78.15 57.67,78.15 55.36,75.85 53.98,75.85 53.82,75.69 50.12,75.69 v2(49.7,75.26)
  BOTTOM w0.076: UC1.AT66 104.61,66.05 v2(104.27,66.4)
  BOTTOM w0.102: v2(49.7,75.26) 51.06,76.62 JDIMM2.45
DDR_B_D17: length 69.1
  IN3 w0.076: v2(103.64,66.4) 103.64,67.82 102.94,68.53 101.82,68.53 101.6,68.75
  IN3 w0.142: 101.6,68.75 101.6,70.36 101.08,70.87 100.86,70.87 99.12,72.62 97.05,72.62 93.59,76.08 90.48,76.08 90.18,75.78 83.71,75.78 83.57,75.92 83.57,76.27 83.43,76.41 83.14,76.41 83,76.27 83,75.92 82.86,75.78 82.59,75.78 82.44,75.92 82.44,76.69 82.3,76.83 82.02,76.83 81.88,76.69 81.88,75.92 81.73,75.78 81.45,75.78 81.31,75.92 81.31,76.69 81.16,76.83 80.88,76.83 80.74,76.69 80.74,75.92 80.6,75.78 79.58,75.78 78.52,76.83 73.84,76.83 72.81,77.86 70.22,77.86 69.31,78.76 67.03,78.76 66.29,79.51 60.4,79.51 57.83,76.93 57.07,76.93 55.13,74.99 53.95,74.99 53.65,75.3 51.26,75.3 v2(51.22,75.26)
  BOTTOM w0.076: UC1.AU66 103.96,66.08 v2(103.64,66.4)
  BOTTOM w0.102: JDIMM2.49 51.33,75.62 51.22,75.52 v2(51.22,75.26)
DDR_B_D18: length 72.5
  IN3 w0.076: v2(105.45,65.5) 105.45,65.55 105.8,65.91 106.28,65.91 106.44,65.75 106.44,65.15 106.21,64.93 104.14,64.93 103.71,64.5 102.17,64.5 100.73,65.93 100.19,65.93 99.52,66.6 99.52,66.81 98.92,67.41 98.92,68.32 98.64,68.61 97.79,68.61 97.73,68.67
  IN3 w0.142: 97.73,68.67 97.23,69.17 96.5,69.17 92.2,73.48 91.79,73.48 91.49,73.17 73.19,73.17 72.34,74.02 66.53,74.02 65.88,74.67 61.93,74.67 61.38,74.12 61.18,74.12 61.05,74.26 61.05,74.55 60.9,74.69 60.62,74.69 60.48,74.55 60.48,74.16 60.34,74.02 59.38,74.02 58.48,73.12 56.94,73.12 56.09,72.27 54.59,72.27 54.47,72.15 54.22,72.15 53.98,71.91 48.23,71.91 48.08,72.05 48.08,72.38 v2(48.17,72.47)
  BOTTOM w0.076: v2(105.45,65.5) 105.45,65.41 105.83,65.03 UC1.AP65
  BOTTOM w0.102: JDIMM2.62 46.07,72.38 46.39,72.06 47.77,72.06 v2(48.17,72.47)
DDR_B_D19: length 72.8
  IN3 w0.076: 98.39,68.81 98.67,68.81 99.8,67.68 100.17,67.68 103.18,64.66 103.64,64.66 104.08,65.09 105.68,65.09 v2(106.07,65.49)
  IN3 w0.142: 98.39,68.81 98.1,68.81 97.38,69.53 96.65,69.53 92.35,73.83 91.64,73.83 91.34,73.53 77.87,73.53 77.73,73.67 77.73,74.24 77.59,74.38 77.3,74.38 77.16,74.24 77.16,73.67 77.02,73.53 76.73,73.53 76.59,73.67 76.59,74.24 76.45,74.38 76.17,74.38 76.02,74.24 76.02,73.67 75.88,73.53 75.6,73.53 75.45,73.67 75.45,74.24 75.31,74.38 75.03,74.38 74.89,74.24 74.89,73.67 74.74,73.53 74.46,73.53 74.32,73.67 74.32,74.24 74.17,74.38 73.89,74.38 73.75,74.24 73.75,73.67 73.61,73.53 73.34,73.53 72.49,74.38 71.3,74.38 71.16,74.52 71.16,74.81 71.02,74.95 70.73,74.95 70.59,74.81 70.59,74.52 70.45,74.38 70.17,74.38 70.02,74.52 70.02,74.81 69.88,74.95 69.6,74.95 69.45,74.81 69.45,74.52 69.31,74.38 69.03,74.38 68.89,74.52 68.89,74.81 68.74,74.95 68.46,74.95 68.32,74.81 68.32,74.52 68.17,74.38 66.77,74.38 65.53,75.61 60.74,75.61 59.5,74.38 59.23,74.38 58.33,73.48 56.79,73.48 55.94,72.63 53.65,72.63 53.5,72.49 53.5,72.41 53.36,72.27 53.08,72.27 52.93,72.41 52.93,72.49 52.79,72.63 52.51,72.63 52.37,72.49 52.37,72.41 52.22,72.27 51.94,72.27 51.8,72.41 51.8,72.49 51.65,72.63 51.39,72.63 v2(51.22,72.47)
  BOTTOM w0.076: UC1.AN65 106.53,65.03 v2(106.07,65.49)
  BOTTOM w0.102: v2(51.22,72.47) 51.88,73.13 JDIMM2.59
DDR_B_D20: length 71.5
  IN3 w0.076: 102.91,69.28 103.07,69.12 103.45,69.12 v2(106.19,66.39)
  IN3 w0.142: v2(46.65,75.26) 47.79,76.4 53.52,76.4 53.68,76.56 55.06,76.56 57.37,78.87 57.83,78.87 60.38,81.42 68.67,81.42 71.03,79.05 73.14,79.05 74.29,77.9 83.46,77.9 84.21,77.15 94.04,77.15 97.5,73.7 99.56,73.7 101.31,71.95 101.53,71.95 102.67,70.8 102.67,69.52 102.91,69.28
  BOTTOM w0.076: UC1.AN66 106.56,66.01 v2(106.19,66.39)
  BOTTOM w0.102: v2(46.65,75.26) 46.54,75.38 JDIMM2.50
DDR_B_D21: length 71.2
  IN3 w0.076: 102.4,69.28 102.73,68.96 103.38,68.96 105.55,66.79 v2(105.55,66.38)
  IN3 w0.142: 102.4,69.28 102.31,69.37 102.31,70.65 101.38,71.59 101.16,71.59 99.41,73.34 97.35,73.34 93.89,76.79 84.06,76.79 83.31,77.54 74.14,77.54 72.99,78.69 70.89,78.69 68.52,81.06 60.52,81.06 57.98,78.51 57.52,78.51 55.21,76.2 53.83,76.2 53.67,76.05 48.96,76.05 v2(48.17,75.26)
  BOTTOM w0.076: UC1.AP66 v2(105.55,66.38)
  BOTTOM w0.102: JDIMM2.46 47.06,76.38 v2(48.17,75.26)
DDR_B_D22: length 71.3
  IN3 w0.076: 98.39,69.16 98.55,69.16 99.84,67.87 100.21,67.87 102.96,65.12 103.82,65.12 104.19,65.49 v2(104.27,65.49)
  IN3 w0.142: 98.39,69.16 98.28,69.16 97.93,69.51 97.93,70.25 97.67,70.51 96.18,70.51 92.5,74.19 91.49,74.19 91.19,73.89 78.23,73.89 78.09,74.03 78.09,74.6 77.95,74.74 73.26,74.74 72.83,75.18 72.63,75.18 72.38,74.93 72.18,74.93 71.98,75.13 71.98,75.33 72.22,75.58 72.22,75.78 72.03,75.97 71.21,75.97 71.07,75.83 71.07,75.45 70.93,75.31 70.64,75.31 70.5,75.45 70.5,75.83 70.36,75.97 68.09,75.97 67.95,75.83 67.95,74.88 67.81,74.73 67.52,74.73 67.38,74.88 67.38,75.83 67.24,75.97 66.95,75.97 66.81,75.83 66.81,75.41 66.67,75.27 66.38,75.27 66.24,75.41 66.24,75.83 66.1,75.97 60.6,75.97 59.36,74.73 59.08,74.73 58.19,73.84 56.64,73.84 55.79,72.99 51.04,72.99 50.94,72.89 49.84,72.89 49.7,72.75 v2(49.7,72.47)
  BOTTOM w0.076: v2(104.27,65.49) 104.61,65.14 UC1.AT65
  BOTTOM w0.102: v2(49.7,72.47) 50.29,71.88 51.91,71.88 52.16,72.13 JDIMM2.63
DDR_B_D23: length 70
  IN3 w0.076: v2(103.66,65.49) 102.94,65.49 102.32,66.1 102.32,66.84 100.45,68.71
  IN3 w0.089: 98.89,70.69 98.95,70.63 99.12,70.63 100.12,69.63 100.12,69.04 100.45,68.71
  IN3 w0.142: v2(46.65,72.47) 46.65,73.11 46.79,73.25 50.7,73.25 50.8,73.35 55.64,73.35 56.49,74.2 58.04,74.2 58.93,75.09 59.21,75.09 60.45,76.33 60.69,76.33 60.83,76.47 60.83,76.78 60.97,76.92 61.25,76.92 61.4,76.78 61.4,76.47 61.54,76.33 61.82,76.33 61.97,76.47 61.97,76.78 62.11,76.92 62.39,76.92 62.53,76.78 62.53,76.47 62.68,76.33 62.96,76.33 63.1,76.47 63.1,76.78 63.25,76.92 63.53,76.92 63.67,76.78 63.67,76.47 63.81,76.33 72.18,76.33 73.41,75.1 78.1,75.1 78.95,74.25 90.86,74.25 91.16,74.55 92.96,74.55 96.42,71.09 98.49,71.09 98.89,70.69
  BOTTOM w0.076: UC1.AU65 103.96,65.18 v2(103.66,65.49)
  BOTTOM w0.102: v2(46.65,72.47) 46.65,72.72 46.14,73.23 45.85,73.23 45.7,73.38 JDIMM2.58
DDR_B_D24: length 66.5
  IN3 w0.076: v2(104.27,63.66) 104.13,63.66 103.78,64 101.9,64 100.54,65.36 100.07,65.36 99.03,66.4 99.03,66.6 98.14,67.49 95.89,67.49 94.68,68.7
  IN3 w0.142: v2(51.22,69.42) 51.1,69.42 50.88,69.63 50.88,70.1 51.03,70.24 52.36,70.24 52.58,70.02 52.58,69.73 52.72,69.59 52.93,69.59 53.07,69.73 53.07,70.1 53.21,70.24 53.5,70.24 53.64,70.1 53.64,69.73 53.78,69.59 54.07,69.59 54.21,69.73 54.21,70.1 54.35,70.24 55.99,70.24 57.11,71.36 58.66,71.36 59.94,72.65 66.52,72.65 66.66,72.51 66.66,72.48 66.84,72.3 67.04,72.3 67.23,72.48 67.23,72.51 67.37,72.65 67.65,72.65 67.8,72.51 67.8,72.48 67.98,72.3 68.18,72.3 68.36,72.48 68.36,72.51 68.51,72.65 68.79,72.65 68.93,72.51 68.93,72.48 69.12,72.3 69.32,72.3 69.5,72.48 69.5,72.51 69.65,72.65 69.91,72.65 70.06,72.51 70.06,71.95 70.2,71.81 70.48,71.81 70.63,71.95 70.63,72.51 70.77,72.65 71.05,72.65 71.19,72.51 71.19,71.95 71.34,71.81 91.57,71.81 94.68,68.7
  BOTTOM w0.076: UC1.AT61 104.61,63.31 v2(104.27,63.66)
  BOTTOM w0.102: JDIMM2.71 51.93,70.13 v2(51.22,69.42)
DDR_B_D25: length 66.6
  IN3 w0.076: 94.18,68.7 95.55,67.32 98.07,67.32 98.86,66.53 98.86,66.26 99.95,65.17 100.48,65.17 101.02,64.63 101.02,64.06 101.88,63.2 102.74,63.2 102.96,63.41 102.96,63.46 103.31,63.81 103.45,63.81 v2(103.63,63.63)
  IN3 w0.142: v2(48.17,69.42) 48.89,68.7 51.91,68.7 52.43,69.23 55.48,69.23 57.26,71.01 58.8,71.01 60.09,72.29 66.05,72.29 66.41,71.94 69.25,71.94 69.74,71.45 91.43,71.45 94.18,68.7
  BOTTOM w0.076: v2(103.63,63.63) 103.63,63.53 UC1.AU61
  BOTTOM w0.102: JDIMM2.66 45.82,71.38 46.81,70.39 47.2,70.39 v2(48.17,69.42)
DDR_B_D26: length 69.8
  IN3 w0.076: 93.74,65.42 93.89,65.27 97.82,65.27 98.28,64.8 98.28,64.32 99.2,63.41 100.5,63.41 101.97,61.94 104.15,61.94 104.58,62.37 105.16,62.37 v2(105.54,62.74)
  IN3 w0.142: 93.74,65.42 89.95,69.21 84.44,69.21 83.71,68.48 71.96,68.48 71.23,69.21 66.09,69.21 65.6,69.7 60.67,69.7 58.55,67.58 57.01,67.58 56.04,66.61 53.07,66.61 52.33,65.87 51.91,65.87 51.12,65.09 48.81,65.09 48.67,65.23 48.67,65.74 48.82,65.89 49.11,65.89 49.54,66.32 v2(49.7,66.32)
  BOTTOM w0.076: UC1.AP60 105.91,62.36 v2(105.54,62.74)
  BOTTOM w0.102: v2(49.7,66.32) 51.09,67.72 51.84,67.72 52.25,68.13 JDIMM2.79
DDR_B_D27: length 69.4
  IN3 w0.076: 93.55,65.11 97.75,65.11 98.12,64.74 98.12,64.26 99.13,63.24 100.43,63.24 101.9,61.77 104.25,61.77 104.67,62.2 106.09,62.2 106.17,62.27 v2(106.17,62.74)
  IN3 w0.142: 93.55,65.11 89.8,68.85 84.59,68.85 83.73,67.98 71.95,67.98 71.09,68.85 60.56,68.85 60.12,68.4 58.94,67.22 57.16,67.22 56.17,66.24 53.2,66.24 52.48,65.52 52.06,65.52 51.27,64.73 47.77,64.73 46.65,65.85 v2(46.65,66.32)
  BOTTOM w0.076: UC1.AN60 106.56,62.35 v2(106.17,62.74)
  BOTTOM w0.102: v2(46.65,66.32) 46.1,66.87 JDIMM2.84
DDR_B_D28: length 69
  IN3 w0.076: 95.7,68.7 96.57,67.83 98.27,67.83 99.36,66.74 99.36,66.53 100.15,65.74 100.67,65.74 102.08,64.33 103.92,64.33 104.06,64.19 105.64,64.19 v2(106.17,63.66)
  IN3 w0.142: 95.7,68.7 91.87,72.52 72.38,72.52 72.22,72.68 72.22,73.22 72.07,73.37 65.49,73.37 64.84,74.02 62.2,74.02 61.54,73.37 59.65,73.37 58.36,72.08 56.82,72.08 55.99,71.26 48.65,71.26 46.81,69.42 v2(46.65,69.42)
  BOTTOM w0.076: UC1.AN61 106.56,63.26 v2(106.17,63.66)
  BOTTOM w0.102: v2(46.65,69.42) 46.65,69.52 45.79,70.38 JDIMM2.70
DDR_B_D29: length 68.3
  IN3 w0.076: v2(105.54,63.66) 105.17,64.03 103.99,64.03 103.85,64.17 101.99,64.17 100.6,65.55 100.11,65.55 99.19,66.47 99.19,66.67 98.21,67.65 96.24,67.65 95.19,68.7
  IN3 w0.142: 95.19,68.7 91.72,72.17 71.86,72.17 71.72,72.31 71.72,72.87 71.57,73.01 59.79,73.01 58.51,71.72 56.96,71.72 56.14,70.9 49.18,70.9 48.98,70.7 48.98,69.98 49.54,69.42 v2(49.7,69.42)
  BOTTOM w0.076: v2(105.54,63.66) 105.91,63.28 UC1.AP61
  BOTTOM w0.102: JDIMM2.67 51.28,71.13 49.7,69.55 v2(49.7,69.42)
DDR_B_D30: length 68.8
  IN3 w0.076: 93.3,66.4 93.3,66.25 94.06,65.49 98,65.49 98.45,65.04 98.45,64.39 99.27,63.57 100.57,63.57 102.04,62.1 103.72,62.1 v2(104.28,62.66)
  IN3 w0.142: 93.3,66.4 93.3,66.44 90.18,69.56 84.29,69.56 83.56,68.84 77.77,68.84 77.63,68.98 77.63,69.16 77.49,69.3 77.2,69.3 77.06,69.16 77.06,68.98 76.92,68.84 76.65,68.84 76.51,68.98 76.51,69.42 76.36,69.56 76.08,69.56 75.94,69.42 75.94,68.98 75.8,68.84 75.51,68.84 75.37,68.98 75.37,69.42 75.23,69.56 74.94,69.56 74.8,69.42 74.8,68.98 74.66,68.84 74.37,68.84 74.23,68.98 74.23,69.42 74.09,69.56 73.8,69.56 73.66,69.42 73.66,68.98 73.52,68.84 73.24,68.84 73.09,68.98 73.09,69.42 72.95,69.56 72.67,69.56 72.52,69.42 72.52,68.98 72.38,68.84 72.11,68.84 71.38,69.56 66.24,69.56 65.75,70.06 60.52,70.06 59.03,68.56 57.48,68.56 55.89,66.97 52.84,66.97 52.1,66.23 51.75,66.23 51.57,66.05 51.36,66.05 51.22,66.19 v2(51.22,66.32)
  BOTTOM w0.076: v2(104.28,62.66) 104.24,62.62 104.24,62.17 104.33,62.08 104.51,62.08 104.61,62.18 UC1.AT60
  BOTTOM w0.102: v2(51.22,66.32) 51.16,66.26 51.02,66.26 50.86,66.42 50.86,66.65 51.34,67.13 53.04,67.13 JDIMM2.83
DDR_B_D31: length 68.4
  IN3 w0.076: v2(103.63,62.7) 101.67,62.7 100.64,63.74 99.34,63.74 98.61,64.46 98.61,65.11 97.98,65.74 94.13,65.74 93.56,66.31 93.56,66.69
  IN3 w0.142: 93.56,66.69 90.32,69.92 81.17,69.92 81.03,69.78 81.03,69.57 80.89,69.43 80.6,69.43 80.46,69.57 80.46,69.78 80.32,69.92 80.04,69.92 79.89,69.78 79.89,69.34 79.75,69.19 79.47,69.19 79.32,69.34 79.32,69.78 79.18,69.92 78.9,69.92 78.76,69.78 78.76,69.34 78.61,69.19 78.33,69.19 78.19,69.34 78.19,69.78 78.04,69.92 66.39,69.92 65.9,70.42 60.38,70.42 58.88,68.92 57.33,68.92 55.74,67.33 52.69,67.33 52.11,66.75 48.6,66.75 v2(48.17,66.32)
  BOTTOM w0.076: UC1.AU60 103.96,62.35 103.63,62.68 v2(103.63,62.7)
  BOTTOM w0.102: JDIMM2.80 45.63,67.87 45.63,67.87 46.62,67.87 v2(48.17,66.32)
DDR_B_D32: length 70
  IN3 w0.076: 92.03,49.18 100.21,49.18 101.51,50.48 101.51,50.96 102.4,51.84 103.55,51.84 v2(103.62,51.78)
  IN3 w0.142: 92.03,49.18 91.97,49.11 90.13,49.11 89.38,48.36 85.05,48.36 81.76,45.08 77.18,45.08 71.41,39.31 69.61,39.31 68.9,38.6 68.66,38.6 68.37,38.89 68.16,38.89 67.97,38.7 67.97,38.5 68.23,38.24 68.23,37.98 68.08,37.83 67.81,37.83 67.56,38.08 67.36,38.08 67.13,37.86 67.13,37.54 67.35,37.32 67.35,37.05 67.21,36.91 66.96,36.91 66.67,37.2 66.47,37.2 66.18,36.91 60.52,36.91 59.75,37.68 59.75,37.98 56.41,41.32 55.84,41.32 55.35,41.81 53.55,41.81 53.04,42.33 52.49,42.33 51.67,43.15 50.12,43.15 v2(49.7,42.72)
  BOTTOM w0.076: v2(103.62,51.78) 103.62,51.55 103.85,51.31 UC1.AU40
  BOTTOM w0.102: v2(49.7,42.72) 50.1,43.13 51.61,43.13 52.1,43.63 JDIMM2.169
DDR_B_D33: length 70.7
  IN3 w0.076: v2(104.29,51.67) 104.02,51.41 103.19,51.41 103.04,51.56 102.35,51.56 101.68,50.89 101.68,50.41 100.28,49.01 92.39,49.01 92.13,48.75 92.03,48.75
  IN3 w0.142: v2(51.22,42.72) 51.59,42.72 52.38,41.94 52.92,41.94 53.41,41.46 55.2,41.46 55.7,40.96 56.26,40.96 58.09,39.13 58.09,38.83 60.38,36.55 67.35,36.55 69.76,38.95 71.56,38.95 74.82,42.21 75.02,42.21 75.59,41.63 75.79,41.63 75.99,41.83 75.99,42.04 75.42,42.61 75.42,42.81 75.62,43.01 75.82,43.01 76.4,42.44 76.6,42.44 76.8,42.64 76.8,42.84 76.22,43.42 76.22,43.62 76.42,43.82 76.63,43.82 77.2,43.24 77.4,43.24 77.6,43.44 77.6,43.65 77.03,44.22 77.03,44.42 77.33,44.72 81.91,44.72 85.19,48 89.53,48 90.28,48.75 92.03,48.75
  BOTTOM w0.076: v2(104.29,51.67) 104.61,51.34 UC1.AT40
  BOTTOM w0.102: v2(51.22,42.72) 51.22,42.55 51.32,42.44 51.72,42.44 51.9,42.63 JDIMM2.173
DDR_B_D34: length 71.5
  IN3 w0.076: 93.21,47.14 100.61,47.14 101.95,48.47 101.95,49.06 102.26,49.38 103.59,49.38 104.13,49.92 104.2,49.92 v2(104.21,49.93)
  IN3 w0.142: 93.21,47.14 92.57,46.5 91.21,46.5 90.47,45.76 86.12,45.76 82.84,42.48 79.81,42.48 72.92,35.58 72.47,35.58 72.09,35.96 71.79,35.96 71.57,35.74 71.57,35.47 71.96,35.08 71.96,34.88 71.72,34.64 71.51,34.64 71.11,35.04 70.86,35.04 70.61,34.79 70.61,34.46 71.01,34.07 71.01,33.86 70.77,33.62 70.43,33.62 69.95,34.1 68.89,34.1 68.74,33.96 68.74,33.46 68.6,33.32 68.18,33.32 68.03,33.46 68.03,33.96 67.89,34.1 67.46,34.1 67.32,33.96 67.32,33.46 67.18,33.32 66.75,33.32 66.61,33.46 66.61,33.96 66.47,34.1 66.04,34.1 65.9,33.96 65.9,33.46 65.76,33.32 60.43,33.32 55.08,38.67 53.02,38.67 52.09,39.6 v2(51.19,39.6)
  BOTTOM w0.076: UC1.AT37 104.29,49.91 104.22,49.92 v2(104.21,49.93)
  BOTTOM w0.102: v2(51.19,39.6) 51.71,40.12 JDIMM2.183
DDR_B_D35: length 70.5
  IN3 w0.076: v2(103.63,49.94) 103.6,49.94 103.21,49.54 102.19,49.54 100.7,48.05 99.67,48.05 99.01,47.39 93.11,47.39
  IN3 w0.142: 93.11,47.39 92.58,46.85 91.06,46.85 90.32,46.12 85.98,46.12 82.69,42.84 79.66,42.84 74.89,38.06 74.38,38.06 73.99,38.44 73.72,38.44 73.53,38.25 73.53,38.05 74.01,37.57 74.01,37.37 73.7,37.07 73.5,37.07 73.02,37.55 72.82,37.55 72.52,37.25 72.52,37.05 73,36.57 73,36.37 72.7,36.06 72.5,36.06 72.04,36.52 71.84,36.52 69.78,34.46 59.8,34.46 55.23,39.03 53.17,39.03 52.17,40.03 50.09,40.03 v2(49.67,39.6)
  BOTTOM w0.076: v2(103.63,49.94) 103.63,49.92 103.96,49.48 UC1.AU37
  BOTTOM w0.102: JDIMM2.187 52.17,39.12 52.1,39.19 50.07,39.19 v2(49.67,39.6)
DDR_B_D36: length 70.8
  IN3 w0.076: 101.74,52.14 104.33,52.14 104.71,51.77 v2(105.57,51.77)
  IN3 w0.142: v2(48.17,43.97) 48.6,43.54 51.79,43.54 52.64,42.69 53.18,42.69 53.7,42.17 55.5,42.17 55.99,41.68 56.55,41.68 60.1,38.13 60.1,37.83 60.67,37.26 66.03,37.26 68.43,39.67 71.26,39.67 77.03,45.44 81.61,45.44 84.9,48.72 89.23,48.72 89.98,49.47 99.07,49.47 101.74,52.14
  BOTTOM w0.076: v2(105.57,51.77) 105.57,51.62 UC1.AR40
  BOTTOM w0.102: JDIMM2.170 47.58,43.38 v2(48.17,43.97)
DDR_B_D37: length 72.4
  IN3 w0.076: 91.99,48.38 92.45,48.85 100.35,48.85 102.32,50.82 102.95,50.82 103.37,51.24 105.15,51.24 v2(105.54,50.86)
  IN3 w0.142: 91.99,48.38 90.41,48.38 89.68,47.65 85.34,47.65 82.06,44.36 79.03,44.36 75.52,40.85 75.08,40.85 74.76,41.17 74.48,41.17 74.27,40.97 74.27,40.77 74.63,40.41 74.63,40.21 74.38,39.97 74.18,39.97 73.81,40.35 73.46,40.35 71.71,38.59 69.91,38.59 67.5,36.19 60.23,36.19 59.5,36.92 57.74,38.68 57.74,38.98 56.11,40.61 55.55,40.61 55.39,40.76 53.6,40.76 52.78,41.58 51.65,41.58 50.93,42.3 47.84,42.3 v2(47.41,42.72)
  BOTTOM w0.076: UC1.AP40 v2(105.54,50.86)
  BOTTOM w0.102: v2(47.41,42.72) 47.41,42.55 47.18,42.32 45.81,42.32 45.75,42.38 JDIMM2.174
DDR_B_D38: length 72.9
  IN3 w0.076: 93.49,46.91 100.62,46.91 102.11,48.4 102.11,49 102.33,49.21 103.67,49.21 104.01,49.55 105.15,49.55 v2(105.54,49.94)
  IN3 w0.142: v2(48.14,39.6) 48.7,39.05 52.14,39.05 52.87,38.31 54.93,38.31 60.28,32.96 69.01,32.96 69.16,33.1 69.16,33.6 69.3,33.74 69.73,33.74 69.87,33.6 69.87,33.11 70.01,32.96 70.8,32.96 79.96,42.12 82.99,42.12 86.27,45.4 90.62,45.4 91.36,46.14 92.72,46.14 93.49,46.91
  BOTTOM w0.076: UC1.AP37 v2(105.54,49.94)
  BOTTOM w0.102: JDIMM2.186 45.77,39.38 45.99,39.15 47.69,39.15 v2(48.14,39.6)
DDR_B_D39: length 72.1
  IN3 w0.076: v2(105.57,49.04) 105.21,49.39 104.08,49.39 103.73,49.05 103.21,49.05 99.98,45.82 98.23,45.82 98.19,45.78
  IN3 w0.142: v2(46.62,39.6) 46.62,38.95 46.89,38.69 51.99,38.69 52.73,37.95 54.79,37.95 60.13,32.6 71.06,32.6 80.22,41.76 83.14,41.76 86.42,45.04 90.77,45.04 91.51,45.78 98.19,45.78
  BOTTOM w0.076: UC1.AR37 v2(105.57,49.04)
  BOTTOM w0.102: v2(46.62,39.6) 46.62,39.93 46.18,40.38 JDIMM2.182
DDR_B_D40: length 72.8
  IN3 w0.076: 91.76,44.05 91.77,44.06 99,44.06 99.64,44.7 99.64,45.13 99.78,45.28 100.14,45.28 103.33,48.47 103.78,48.47 104.13,48.11 v2(104.27,48.11)
  IN3 w0.142: 91.76,44.05 91.71,44.05 91.34,43.68 87.02,43.68 83.74,40.4 82.21,40.4 77.08,35.27 76.88,35.27 76.37,35.78 76.17,35.78 75.97,35.58 75.97,35.38 76.48,34.87 76.48,34.67 76.27,34.46 76.07,34.46 75.63,34.91 75.3,34.91 71.63,31.24 68.42,31.24 68.17,30.99 59.81,30.99 57.83,32.98 57.5,33.3 57.13,33.3 54.83,35.61 54.69,35.61 54.03,36.27 52.47,36.27 51.55,37.19 48.98,37.19 v2(48.14,38.03)
  BOTTOM w0.076: UC1.AT33 104.4,47.93 v2(104.27,48.11)
  BOTTOM w0.102: JDIMM2.190 46.04,38.38 46.16,38.49 47.68,38.49 v2(48.14,38.03)
DDR_B_D41: length 72.5
  IN3 w0.076: 92.6,43.86 92.64,43.9 99.07,43.9 99.71,44.54 100.39,44.54 101.85,46 101.85,46.67 102.02,46.84 102.36,47.18 102.47,47.18 103.39,48.1 v2(103.62,48.1)
  IN3 w0.142: v2(46.62,38.03) 47.81,36.83 51.4,36.83 52.33,35.91 53.88,35.91 54.54,35.25 54.68,35.25 56.98,32.94 57.35,32.94 59.1,31.19 59.66,30.64 67.93,30.64 68.42,30.15 69.12,30.15 69.85,30.88 71.77,30.88 74.43,33.53 74.76,33.53 75.16,33.13 75.38,33.13 75.58,33.33 75.58,33.53 75.2,33.91 75.2,34.18 75.4,34.38 75.6,34.38 76.05,33.93 76.25,33.93 82.35,40.04 83.89,40.04 87.17,43.32 91.49,43.32 92.02,43.86 92.6,43.86
  BOTTOM w0.076: v2(103.62,48.1) 103.96,47.76 UC1.AU33
  BOTTOM w0.102: JDIMM2.194 45.97,37.38 v2(46.62,38.03)
DDR_B_D42: length 71.8
  IN3 w0.076: v2(103.66,46.31) 103.03,45.68 102.47,45.68 100.66,43.88 99.98,43.88 99.35,43.24 99.35,42.42 99.06,42.13 98.19,42.13
  IN3 w0.142: 98.19,42.13 92.96,42.13 92.27,41.44 87.95,41.44 84.67,38.15 83.14,38.15 74.16,29.18 72.74,29.18 71.67,28.11 70.97,28.11 70.82,27.96 70.82,27.73 70.68,27.58 70.36,27.58 70.22,27.73 70.22,28 70.07,28.14 69.79,28.14 69.5,27.85 68.23,27.85 67.81,28.27 66.04,28.27 65.81,28.04 59.6,28.04 58.88,28.75 58.88,28.75 56.57,31.06 56.2,31.06 55.89,31.38 55.6,31.38 55.43,31.54 53.18,33.79 51.09,33.79 50.94,33.94 50.94,34.15 50.8,34.29 50.52,34.29 50.37,34.15 50.37,33.94 50.23,33.79 49.59,33.79 49.36,34.03 49.36,34.4 v2(49.67,34.71)
  BOTTOM w0.076: UC1.AU30 103.66,46.24 v2(103.66,46.31)
  BOTTOM w0.102: v2(49.67,34.71) 50.51,33.87 51.99,33.87 52.24,34.12 JDIMM2.207
DDR_B_D43: length 72.1
  IN3 w0.076: 98.19,42.49 98.94,42.49 99.16,42.72 99.16,43.29 99.91,44.04 100.59,44.04 102.4,45.85 102.61,45.85 103.46,46.7 103.88,46.7 v2(104.27,46.31)
  IN3 w0.142: v2(51.19,34.71) 51.75,34.15 53.33,34.15 55.58,31.9 55.75,31.73 56.03,31.73 56.35,31.42 56.72,31.42 59.03,29.11 59.03,29.11 59.74,28.4 65.66,28.4 65.89,28.62 67.96,28.62 68.38,28.2 69.35,28.2 69.68,28.54 70.17,28.54 70.3,28.66 70.3,29.17 70.48,29.35 70.85,29.35 70.99,29.21 70.99,28.61 71.13,28.47 71.42,28.47 71.56,28.61 71.56,29.21 71.7,29.35 72.41,29.35 73.01,29.96 73.39,29.96 73.81,29.54 74.01,29.54 74.24,29.76 74.24,29.97 73.73,30.47 73.73,30.68 73.93,30.88 74.13,30.88 74.64,30.37 74.84,30.37 74.99,30.51 74.99,30.71 74.5,31.2 74.5,31.4 74.7,31.6 74.9,31.6 75.33,31.17 75.65,31.17 82.99,38.51 84.52,38.51 87.8,41.79 92.12,41.79 92.82,42.49 98.19,42.49
  BOTTOM w0.076: v2(104.27,46.31) 104.61,45.85 UC1.AT30
  BOTTOM w0.102: v2(51.19,34.71) 51.61,35.12 JDIMM2.203
DDR_B_D44: length 73.6
  IN3 w0.076: v2(104.9,48.11) 104.53,48.48 104,48.48 103.84,48.63 103.26,48.63 100.11,45.49 99.76,45.49 99.47,45.2 99.47,44.77 98.96,44.26 92.59,44.26
  IN3 w0.142: v2(49.67,38.03) 50.14,37.55 51.7,37.55 52.62,36.63 54.18,36.63 54.84,35.96 54.98,35.96 57.28,33.66 57.65,33.66 59.96,31.35 68.03,31.35 68.27,31.59 71.48,31.59 76.17,36.28 76.37,36.28 76.75,35.9 77.2,35.9 80.2,38.9 80.2,39.1 79.69,39.61 79.69,39.81 79.89,40.01 80.1,40.01 80.6,39.5 80.8,39.5 81.01,39.7 81.01,39.9 80.53,40.38 80.53,40.59 80.7,40.75 80.96,40.75 81.41,40.31 81.61,40.31 82.06,40.75 83.56,40.75 86.84,44.04 91.19,44.04 91.56,44.41 92.44,44.41 92.59,44.26
  BOTTOM w0.076: v2(104.9,48.11) 105.04,47.93 UC1.AR33
  BOTTOM w0.102: JDIMM2.191 51.96,38.12 51.65,38.43 50.07,38.43 v2(49.67,38.03)
DDR_B_D45: length 73.9
  IN3 w0.076: 98.19,45.13 99.16,45.13 99.69,45.65 100.05,45.65 103.19,48.8 103.91,48.8 104.06,48.65 105,48.65 v2(105.54,48.11)
  IN3 w0.142: v2(51.19,38.03) 51.2,38.04 51.72,38.04 52.77,36.99 54.33,36.99 54.99,36.32 55.21,36.32 57.51,34.02 57.8,34.02 60.11,31.71 67.88,31.71 68.12,31.95 71.33,31.95 76.17,36.79 76.37,36.79 76.88,36.28 77.08,36.28 77.28,36.48 77.28,36.69 76.77,37.19 76.77,37.4 76.97,37.6 77.17,37.6 77.68,37.09 77.88,37.09 78.09,37.29 78.09,37.49 77.58,38 77.58,38.2 77.78,38.4 77.98,38.4 78.49,37.89 78.69,37.89 78.89,38.09 78.89,38.29 78.38,38.8 78.38,39 78.58,39.21 78.78,39.21 79.29,38.7 79.49,38.7 79.69,38.9 79.69,39.1 79.19,39.61 79.19,39.81 80.49,41.11 83.41,41.11 86.69,44.39 91.04,44.39 91.77,45.13 98.19,45.13
  BOTTOM w0.076: UC1.AP33 105.68,47.93 v2(105.54,48.11)
  BOTTOM w0.102: JDIMM2.195 52.09,37.12 v2(51.19,38.03)
DDR_B_D46: length 73
  IN3 w0.076: v2(104.9,46.31) 104.53,45.93 104.06,45.93 103.65,45.52 102.53,45.52 100.73,43.71 100.05,43.71 99.51,43.18 99.51,42.35 98.94,41.77 98.19,41.77
  IN3 w0.142: 98.19,41.77 93.11,41.77 92.42,41.08 88.1,41.08 84.82,37.79 83.29,37.79 74.31,28.82 72.89,28.82 71.29,27.22 70.21,27.22 69.95,27.49 68.08,27.49 67.66,27.91 66.19,27.91 65.94,27.66 59.47,27.66 58.73,28.39 58.73,28.39 56.42,30.7 56.05,30.7 55.74,31.02 55.45,31.02 55.28,31.18 55.28,31.18 53.03,33.44 48.84,33.44 48.14,34.13 v2(48.14,34.71)
  BOTTOM w0.076: v2(104.9,46.31) 105.26,45.85 UC1.AR30
  BOTTOM w0.102: v2(48.14,34.71) 47.74,35.12 46.1,35.12 45.86,34.87 JDIMM2.204
DDR_B_D47: length 73.6
  IN3 w0.076: 97.92,41.42 98.82,41.42 99.68,42.28 99.68,43.11 100.12,43.55 100.8,43.55 102.6,45.35 103.71,45.35 104.13,45.77 104.6,45.77 104.71,45.88 105.1,45.88 v2(105.54,46.31)
  IN3 w0.142: v2(46.62,34.71) 48.25,33.08 52.88,33.08 55.13,30.83 55.3,30.66 55.59,30.66 55.9,30.34 56.27,30.34 58.58,28.03 58.58,28.03 59.32,27.3 66.09,27.3 66.34,27.55 67.51,27.55 67.93,27.13 69.8,27.13 70.06,26.87 71.44,26.87 73.04,28.46 74.46,28.46 83.43,37.44 84.97,37.44 88.25,40.72 92.56,40.72 93.26,41.42 97.82,41.42 97.82,41.42 97.92,41.42
  BOTTOM w0.076: v2(105.54,46.31) 105.91,45.85 UC1.AP30
  BOTTOM w0.102: v2(46.62,34.71) 45.78,33.87 JDIMM2.208
DDR_B_D48: length 73.4
  IN3 w0.076: 95.41,39.56 95.87,40.03 98.36,40.03 98.97,40.63 99.95,40.63 100.32,41 100.32,41.76 101.65,43.08 101.65,43.46 102.48,44.3 103.49,44.3 v2(103.64,44.45)
  IN3 w0.142: v2(46.62,32.44) 46.62,31.52 46.85,31.29 52.23,31.29 54.42,29.1 54.42,29.1 54.59,28.93 54.84,28.93 55.2,28.58 55.2,28.18 55.58,27.81 56.08,27.81 56.73,27.16 57.01,27.16 58.6,25.57 60.02,25.57 60.52,25.07 63.65,25.07 63.95,25.37 66.06,25.37 66.32,25.11 66.34,25.11 66.34,24.71 66.54,24.51 66.69,24.36 68.44,24.36 68.62,24.53 69.1,24.53 69.28,24.36 71.64,24.36 72.31,25.02 73.15,25.02 74.35,26.23 74.67,26.23 84.15,35.71 85.68,35.71 88.96,38.99 93.28,38.99 93.75,39.47 95.31,39.47 95.41,39.56
  BOTTOM w0.076: v2(103.64,44.45) 103.63,44.45 103.63,44.44 UC1.AU27
  BOTTOM w0.102: JDIMM2.216 46.26,31.87 46.62,32.23 v2(46.62,32.44)
DDR_B_D49: length 74.4
  IN3 w0.076: v2(104.27,44.45) 104.17,44.45 103.81,44.81 102.77,44.81 101.48,43.53 101.48,43.15 99.98,41.64 99.74,41.64 98.32,40.22 95.56,40.22 95.17,39.83
  IN3 w0.142: v2(48.14,32.44) 47.77,32.06 47.77,31.79 47.91,31.64 48.4,31.64 48.54,31.79 48.54,31.87 48.68,32.01 48.96,32.01 49.11,31.87 49.11,31.79 49.25,31.64 52.38,31.64 54.57,29.46 54.73,29.29 54.99,29.29 55.56,28.72 55.56,28.33 55.73,28.17 56.23,28.17 56.87,27.52 57.16,27.52 58.75,25.93 60.17,25.93 60.38,25.73 66.49,25.73 66.69,25.52 66.69,24.86 66.84,24.71 68.29,24.71 68.62,25.04 69.1,25.04 69.43,24.71 71.49,24.71 72.16,25.38 73,25.38 73.72,26.1 73.72,26.29 74.02,26.59 74.52,26.59 84,36.07 85.53,36.07 88.81,39.35 93.13,39.35 93.6,39.83 95.16,39.83 95.17,39.83
  BOTTOM w0.076: v2(104.27,44.45) UC1.AT27
  BOTTOM w0.102: v2(48.14,32.44) 47.71,32.87 JDIMM2.212
DDR_B_D50: length 73.2
  IN3 w0.076: v2(104.27,43.54) 104.11,43.54 103.52,42.94 102.45,42.94 100.98,41.48 100.98,40.73 100.23,39.97 99.24,39.97 97.87,38.6 97.13,38.6
  IN3 w0.142: v2(49.67,29.31) 49.67,29.03 49.81,28.89 51.83,28.89 56.88,23.85 57.16,23.85 57.82,23.18 57.82,22.65 57.96,22.5 58.38,22.5 58.5,22.63 58.5,22.76 58.65,22.91 59.02,22.91 59.16,22.76 59.16,22.41 59.51,22.05 63.93,22.05 64.47,22.59 65.8,22.59 65.92,22.47 67.72,22.47 67.93,22.26 69.93,22.26 70.14,22.47 71.52,22.47 71.94,22.05 73.16,22.05 76.37,25.27 84.67,33.57 86.78,33.57 90.26,37.05 94,37.05 94.53,37.58 96.11,37.58 97.13,38.6
  BOTTOM w0.076: UC1.AT25 104.27,43.54 v2(104.27,43.54)
  BOTTOM w0.102: JDIMM2.225 52.08,29.63 51.55,30.15 50.51,30.15 v2(49.67,29.31)
DDR_B_D51: length 72.6
  IN3 w0.076: 97.35,38.83 97.86,38.83 99.17,40.14 100.16,40.14 100.82,40.8 100.82,41.55 102.38,43.11 103.29,43.11 103.59,43.41 v2(103.59,43.54)
  IN3 w0.142: 97.35,38.83 96.86,38.83 95.97,37.94 94.39,37.94 93.86,37.41 89.98,37.41 86.5,33.93 84.52,33.93 75.3,24.71 74.99,24.71 73.72,23.43 73.72,23.33 72.84,22.46 72.04,22.46 71.67,22.83 69.99,22.83 69.78,22.62 68.08,22.62 67.87,22.83 66.07,22.83 65.95,22.95 63.76,22.95 63.61,22.81 63.61,22.55 63.47,22.41 63.19,22.41 63.05,22.55 63.05,22.81 62.9,22.95 62.62,22.95 62.48,22.81 62.48,22.55 62.33,22.41 62.05,22.41 61.91,22.55 61.91,22.81 61.76,22.95 61.46,22.95 61.32,22.81 61.32,22.55 61.18,22.41 60.89,22.41 60.75,22.55 60.75,22.81 60.61,22.95 60.23,22.95 60.08,22.81 60.08,22.55 59.94,22.41 59.66,22.41 59.52,22.55 59.52,23.9 59.37,24.05 59.03,24.05 58.89,23.9 58.89,23.41 58.75,23.26 58.46,23.26 58.32,23.41 58.32,23.9 58.18,24.05 57.46,24.05 57.31,24.2 57.02,24.2 55.8,25.43 55.8,25.77 55.5,26.08 55.15,26.08 52.61,28.62 52.61,28.75 52.05,29.31 v2(51.19,29.31)
  BOTTOM w0.076: UC1.AU25 103.96,43.14 103.59,43.51 v2(103.59,43.54)
  BOTTOM w0.102: v2(51.19,29.31) 51.88,28.63 JDIMM2.229
DDR_B_D52: length 74.7
  IN3 w0.076: 95.22,40.28 95.22,40.31 95.33,40.42 98.29,40.42 99.67,41.81 99.91,41.81 101.32,43.22 101.32,43.6 101.46,43.74 101.45,43.74 102.74,45.02 103.87,45.02 104.05,44.84 105.15,44.84 v2(105.54,44.45)
  IN3 w0.142: v2(49.67,32.44) 49.67,32.14 49.81,32 52.53,32 54.72,29.82 54.88,29.65 55.14,29.65 55.46,29.34 55.57,29.34 57.02,27.88 57.31,27.88 58.9,26.29 60.32,26.29 60.52,26.09 66.3,26.09 66.61,26.4 66.96,26.4 67.1,26.25 67.1,25.47 67.49,25.07 68.14,25.07 68.47,25.4 69.25,25.4 69.58,25.07 71.35,25.07 71.7,25.42 71.7,25.71 71.89,25.9 72.12,25.9 72.28,25.74 72.85,25.74 73.36,26.25 73.36,26.55 73.06,26.85 73.06,27.06 73.35,27.34 73.64,27.34 74.04,26.95 74.37,26.95 83.85,36.43 85.38,36.43 88.67,39.71 92.98,39.71 93.46,40.18 95.12,40.18 95.22,40.28
  BOTTOM w0.076: v2(105.54,44.45) UC1.AP27
  BOTTOM w0.102: v2(49.67,32.44) 50.52,33.29 51.96,33.29 52.12,33.12 JDIMM2.211
DDR_B_D53: length 75.2
  IN3 w0.076: v2(106.17,44.45) 105.61,45.02 104.12,45.02 103.96,45.19 102.67,45.19 100.87,43.38 100.19,43.38 99.84,43.04 99.84,42.21 98.22,40.59 95.17,40.59
  IN3 w0.142: 95.17,40.59 95.04,40.59 95,40.54 93.31,40.54 92.83,40.07 88.52,40.07 85.24,36.79 83.7,36.79 74.37,27.46 74.03,27.46 73.68,27.81 73.31,27.81 72.55,27.05 72.55,26.85 72.9,26.5 72.9,26.3 72.7,26.1 72.5,26.1 72.15,26.45 71.95,26.45 71.71,26.22 71.49,26.22 71.34,26.07 71.34,25.57 71.2,25.43 70.91,25.43 70.77,25.57 70.77,26.07 70.62,26.22 70.3,26.22 70.15,26.07 70.15,25.57 70.01,25.43 69.73,25.43 69.58,25.57 69.58,26.34 69.44,26.48 68.38,26.48 68.13,26.23 68.13,25.57 67.99,25.43 67.64,25.43 67.46,25.61 67.46,26.67 67.22,26.9 66.61,26.9 66.15,26.44 60.67,26.44 60.47,26.65 59.05,26.65 57.46,28.24 57.17,28.24 55.67,29.74 55.59,29.74 55.32,30.01 55.03,30.01 54.87,30.18 54.86,30.18 52.61,32.43 51.2,32.43 v2(51.19,32.44)
  BOTTOM w0.076: v2(106.17,44.45) UC1.AN27
  BOTTOM w0.102: JDIMM2.215 51.5,32.12 v2(51.19,32.44)
DDR_B_D54: length 75.3
  IN3 w0.076: v2(106.17,43.54) 106.12,43.54 105.58,43 104.05,43 103.66,42.61 102.58,42.61 101.31,41.34 101.31,40.59 100.37,39.64 99.38,39.64 97.6,37.87 97.42,37.87 97.26,37.71
  IN3 w0.142: 97.26,37.71 96.41,36.87 94.83,36.87 94.3,36.34 90.56,36.34 87.06,32.84 84.95,32.84 77.19,25.07 73.45,21.34 57.95,21.34 56.2,23.09 56.2,23.51 51.54,28.17 47.76,28.17 v2(46.62,29.31)
  BOTTOM w0.076: v2(106.17,43.54) UC1.AN25
  BOTTOM w0.102: v2(46.62,29.31) 46.18,28.87 JDIMM2.228
DDR_B_D55: length 74.5
  IN3 w0.076: 97.83,38.4 97.9,38.4 99.31,39.81 100.3,39.81 101.15,40.66 101.15,41.41 102.51,42.78 103.59,42.78 103.98,43.17 105.16,43.17 v2(105.56,43.57)
  IN3 w0.142: 97.83,38.4 97.62,38.19 97.23,38.19 96.26,37.22 94.68,37.22 94.15,36.7 90.41,36.7 86.93,33.21 84.82,33.21 76.83,25.22 76.83,25.22 73.31,21.7 58.1,21.7 56.56,23.24 56.56,23.66 51.69,28.53 48.93,28.53 v2(48.14,29.31)
  BOTTOM w0.076: UC1.AP25 105.91,43.21 v2(105.56,43.57)
  BOTTOM w0.102: v2(48.14,29.31) 47.58,29.87 JDIMM2.224
DDR_B_D56: length 78.5
  IN3 w0.076: 98.43,37.25 99.6,38.42 100.33,38.42 100.7,38.79 100.7,39.19 102.75,41.24 102.75,41.41 103.43,42.08 103.78,42.08 104.15,41.72 v2(104.27,41.72)
  IN3 w0.142: v2(48.14,27.15) 48.14,26.51 48.29,26.37 51.4,26.37 53.08,24.7 53.08,24.2 55.23,22.05 55.31,22.05 57.39,19.97 60.9,19.97 61.39,19.48 61.39,18.76 61.64,18.51 62.25,18.51 62.64,18.12 64.03,18.12 64.38,18.47 64.38,19.29 64.82,19.73 65.77,19.73 65.93,19.89 67.28,19.89 67.75,19.42 67.75,18.47 68.1,18.12 68.97,18.12 69.64,18.79 72.84,18.79 78.56,24.51 78.56,24.51 85.52,31.47 87.63,31.47 90.97,34.82 92.67,34.82 93.01,34.48 93.97,34.48 94.46,34.97 94.87,34.97 95.39,35.5 96.97,35.5 98.43,36.96 98.43,37.25
  BOTTOM w0.076: UC1.AT22 104.27,41.71 v2(104.27,41.72)
  BOTTOM w0.102: JDIMM2.232 47.42,27.87 v2(48.14,27.15)
DDR_B_D57: length 77.3
  IN3 w0.076: v2(103.63,41.72) 103.3,41.72 102.92,41.34 102.92,41.17 100.87,39.12 100.87,38.72 100.39,38.25 99.72,38.25 98.67,37.2
  IN3 w0.142: v2(46.62,27.15) 46.62,26.9 47.51,26.01 51.26,26.01 52.72,24.55 52.72,24.06 55.07,21.7 55.15,21.7 57.24,19.61 60.75,19.61 61.03,19.33 61.03,18.61 61.49,18.15 62.11,18.15 62.49,17.76 64.17,17.76 64.74,18.33 64.74,18.95 65.16,19.37 65.92,19.37 66.06,19.51 66.82,19.51 67.39,18.94 67.39,18.32 67.95,17.76 69.12,17.76 69.79,18.43 72.99,18.43 78.92,24.36 78.92,24.36 85.67,31.11 87.77,31.11 91.12,34.46 92.52,34.46 92.86,34.12 94.12,34.12 94.61,34.61 95.02,34.61 95.54,35.14 97.12,35.14 98.67,36.68 98.67,37.2
  BOTTOM w0.076: UC1.AU22 103.96,41.35 103.63,41.69 v2(103.63,41.72)
  BOTTOM w0.102: v2(46.62,27.15) 46.34,26.87 JDIMM2.236
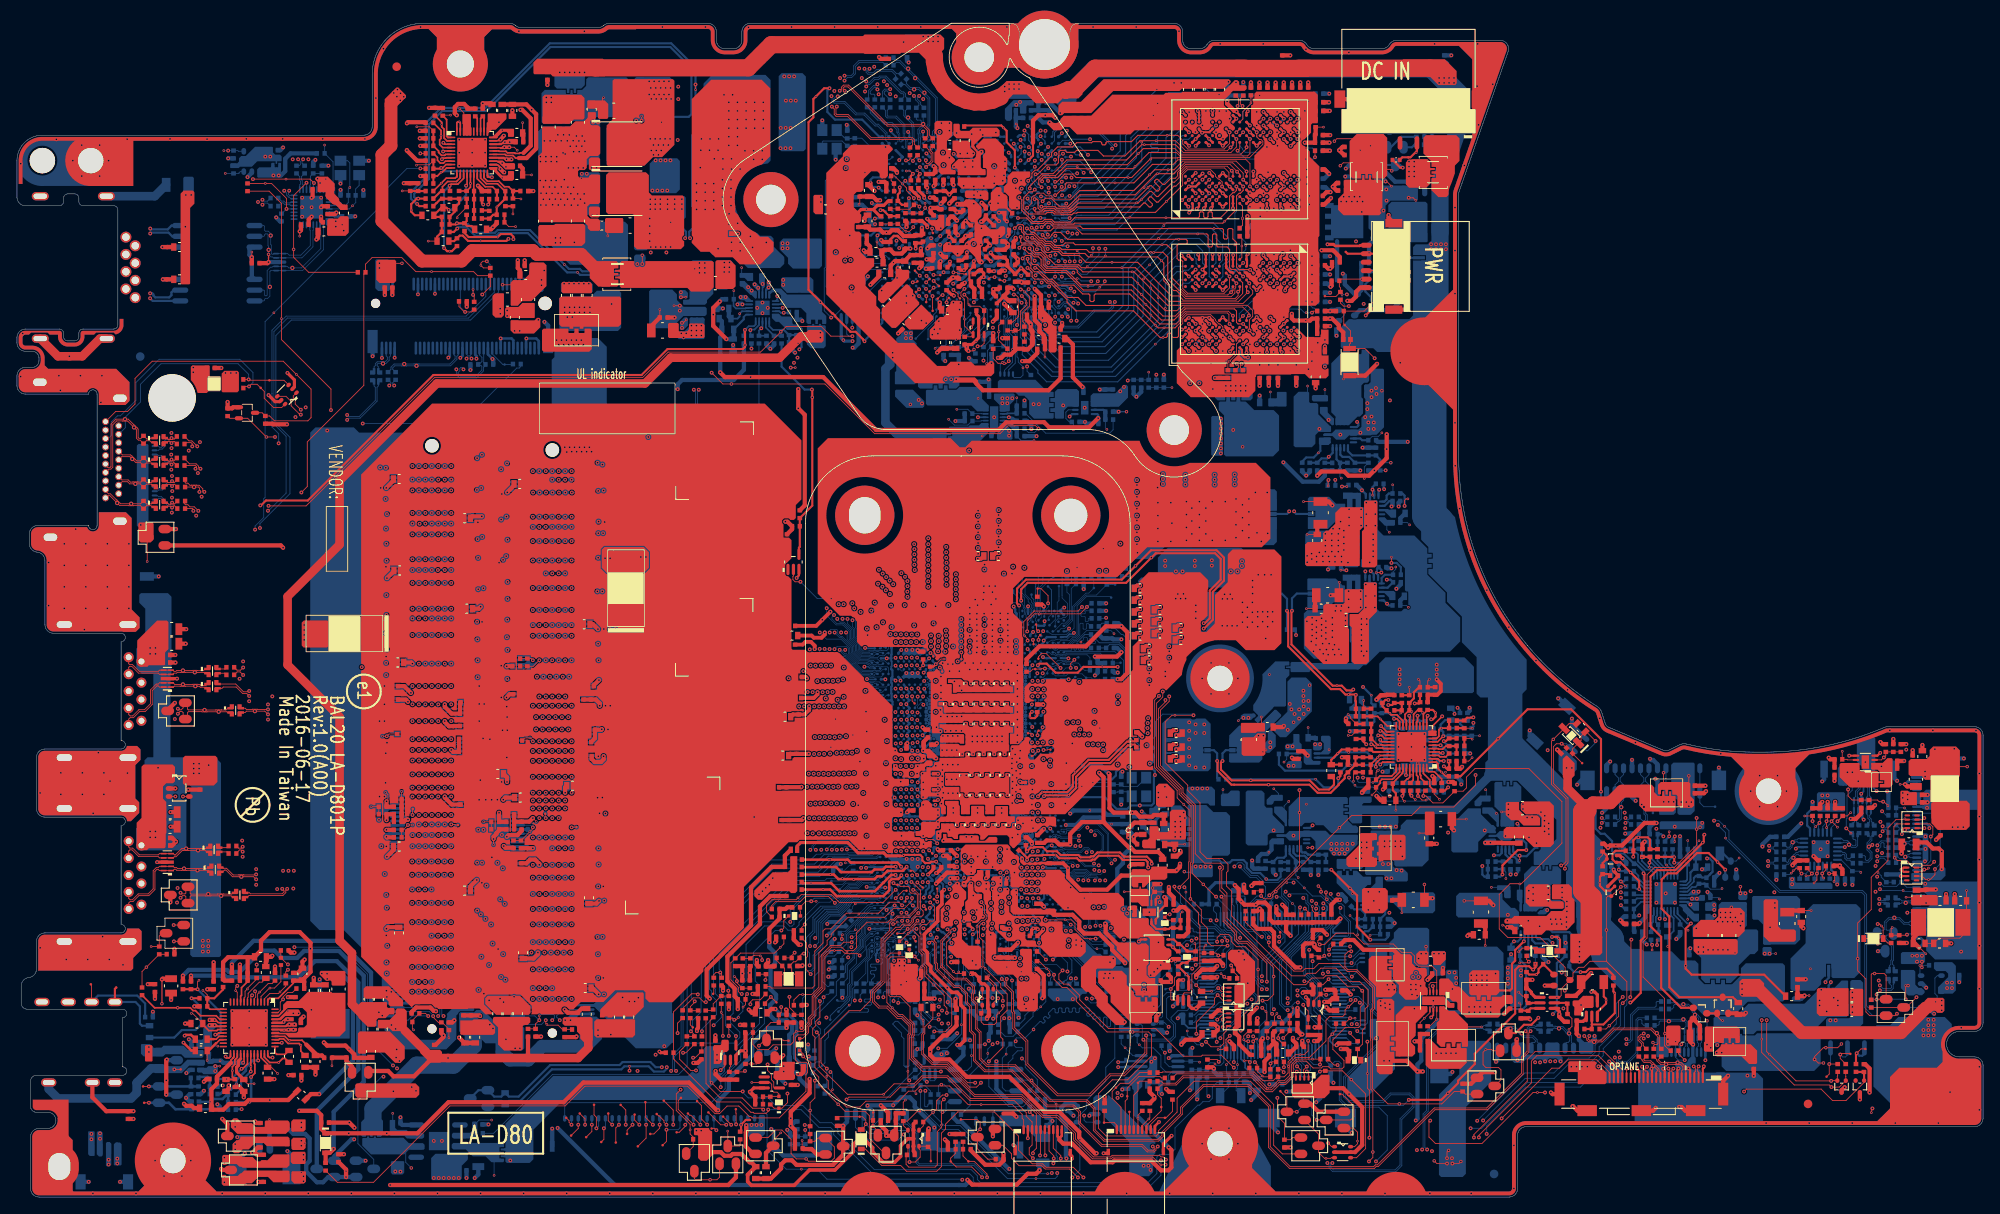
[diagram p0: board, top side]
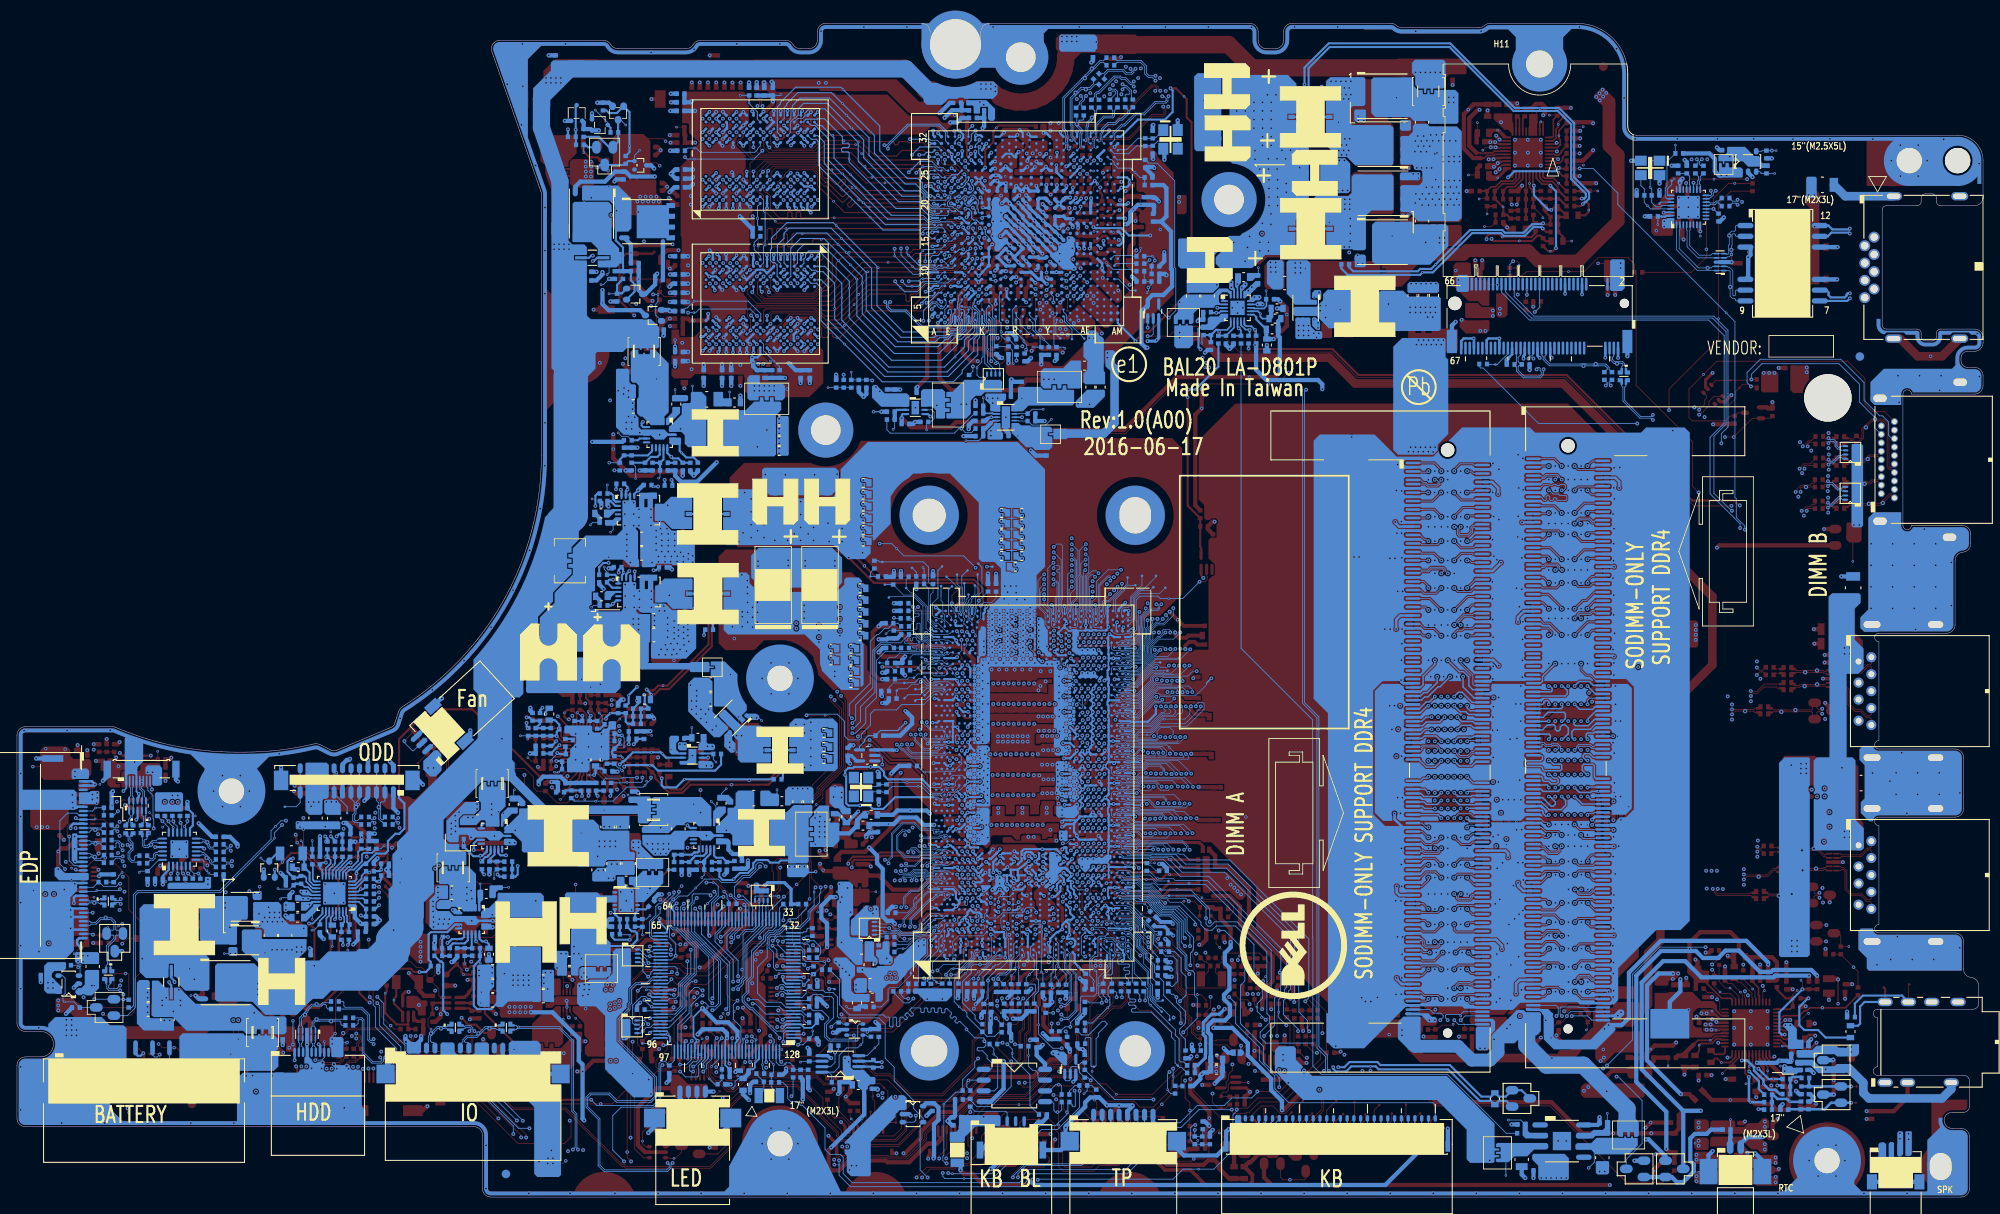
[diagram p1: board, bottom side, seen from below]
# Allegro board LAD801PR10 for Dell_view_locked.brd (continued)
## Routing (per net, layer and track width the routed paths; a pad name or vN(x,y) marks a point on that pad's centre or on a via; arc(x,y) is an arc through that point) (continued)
DDR_B_D58: length 76.7
  IN3 w0.076: v2(103.68,40.81) 103.68,40.81 103.6,40.74 103.58,40.74 100.6,37.76 99.97,37.76 99.32,37.11 99.32,35.41
  IN3 w0.142: v2(51.19,24.23) 51.19,23.42 53.33,21.29 53.33,20.82 56.06,18.09 59.4,18.09 59.75,17.73 59.75,17.28 59.6,17.12 58.69,17.12 58.57,17 58.57,16.64 58.71,16.5 59.99,16.5 60.22,16.72 60.76,16.72 61.25,16.24 65.13,16.24 65.23,16.34 65.23,16.66 65.56,16.99 66.57,16.99 66.82,16.74 66.82,16.47 67.05,16.24 69.75,16.24 70.42,16.91 73.63,16.91 79.41,22.69 79.75,22.69 80.04,22.39 80.4,22.39 80.71,22.71 80.71,22.97 80.51,23.16 80.51,23.37 80.79,23.65 80.79,24.07 82.52,25.8 82.98,25.8 84.05,26.88 84.05,27.34 86.3,29.59 89.67,29.59 90.04,29.96 90.04,30.16 89.86,30.35 89.86,30.55 90.74,31.43 90.94,31.43 91.13,31.25 91.33,31.25 92.68,32.59 94.75,32.59 95.18,33.02 97.05,33.02 99.32,35.3 99.32,35.41
  BOTTOM w0.076: v2(103.68,40.81) 103.67,40.72 UC1.AU21
  BOTTOM w0.102: v2(51.19,24.23) 51.8,23.63 JDIMM2.249
DDR_B_D59: length 77.5
  IN3 w0.076: v2(104.27,40.81) 104.26,40.81 103.78,40.33 103.41,40.33 100.67,37.59 100.09,37.59 99.52,37.03 99.52,34.99 98.67,34.14
  IN3 w0.142: 98.67,34.14 97.2,32.66 95.33,32.66 94.9,32.23 93.91,32.23 93.42,31.74 92.33,31.74 91.35,30.76 91.11,30.76 90.94,30.93 90.74,30.93 90.36,30.55 90.36,30.35 90.51,30.2 90.51,29.91 89.82,29.23 86.45,29.23 84.41,27.19 84.41,26.73 82.46,24.78 82.46,23.4 81.09,22.04 79.4,22.04 73.92,16.55 71.19,16.55 70.52,15.88 66.71,15.88 66.46,16.13 66.46,16.45 66.28,16.63 65.8,16.63 65.59,16.43 65.59,16.07 65.4,15.88 61.1,15.88 60.84,16.14 58.56,16.14 58.21,16.49 58.21,17.47 57.95,17.73 55.91,17.73 52.97,20.67 52.97,21.14 50.27,23.84 50.06,23.84 v2(49.67,24.23)
  BOTTOM w0.076: UC1.AT21 104.27,40.8 v2(104.27,40.81)
  BOTTOM w0.102: JDIMM2.245 51.68,24.63 51.56,24.75 50.18,24.75 v2(49.67,24.23)
DDR_B_D60: length 79.2
  IN3 w0.076: v2(106.17,41.71) 105.91,41.97 105.91,42.11 105.71,42.32 104.73,42.32 104.66,42.25 104.08,42.25 103.88,42.45 102.65,42.45 101.48,41.28 101.48,40.52 100.43,39.48 99.45,39.48 97.91,37.94 97.91,37.44 97.8,37.34
  IN3 w0.142: v2(51.19,27.15) 51.63,27.15 53.79,25 53.79,24.5 55.54,22.76 55.61,22.76 57.68,20.69 61.19,20.69 61.43,20.44 65.47,20.44 65.71,20.69 67.8,20.69 67.94,20.54 67.94,20.24 68.08,20.1 68.37,20.1 68.51,20.24 68.51,20.54 68.65,20.69 68.94,20.69 69.08,20.54 69.08,19.65 69.22,19.51 69.5,19.51 69.65,19.65 69.65,20.54 69.79,20.69 70.07,20.69 70.22,20.54 70.22,19.65 70.36,19.51 70.64,19.51 70.78,19.65 70.78,20.54 70.93,20.69 71.21,20.69 71.35,20.54 71.35,19.65 71.5,19.51 71.78,19.51 71.92,19.65 71.92,20.54 72.06,20.69 72.35,20.69 72.49,20.54 72.49,20.02 72.63,19.88 72.92,19.88 73.06,20.02 73.06,20.54 73.2,20.69 73.72,20.69 74.64,21.6 77.84,24.8 77.84,24.81 85.22,32.19 87.33,32.19 90.83,35.69 94.57,35.69 95.1,36.22 96.68,36.22 97.8,37.34
  BOTTOM w0.076: UC1.AN22 v2(106.17,41.71)
  BOTTOM w0.102: JDIMM2.237 52.3,26.63 51.88,27.04 51.3,27.04 v2(51.19,27.15)
DDR_B_D61: length 79
  IN3 w0.076: 98.2,37.23 98.2,38 99.51,39.31 100.5,39.31 101.64,40.46 101.64,41.21 102.72,42.28 103.81,42.28 104.01,42.08 104.73,42.08 104.8,42.15 105.64,42.15 105.75,42.05 105.75,41.92 v2(105.54,41.71)
  IN3 w0.142: 98.2,37.23 96.83,35.86 95.25,35.86 94.72,35.33 90.98,35.33 87.48,31.83 85.37,31.83 78.2,24.66 72.69,19.15 69.12,19.15 68.96,18.99 68.96,18.62 68.82,18.48 68.25,18.48 68.11,18.62 68.11,19.57 67.35,20.33 65.86,20.33 65.62,20.09 64.21,20.09 64.02,19.89 64.02,18.99 63.51,18.48 62.79,18.48 62.28,18.99 62.28,19.93 62.12,20.09 61.29,20.09 61.04,20.33 57.54,20.33 55.46,22.41 55.38,22.41 53.43,24.35 53.43,24.85 51.55,26.73 49.81,26.73 49.67,26.87 v2(49.67,27.15)
  BOTTOM w0.076: UC1.AP22 v2(105.54,41.71)
  BOTTOM w0.102: JDIMM2.233 50.14,27.63 v2(49.67,27.15)
DDR_B_D62: length 78.6
  IN3 w0.076: v2(105.59,40.86) 105.18,40.45 104.33,40.45 103.96,40.08 103.39,40.08 100.74,37.43 100.16,37.43 99.69,36.96 99.69,34.65 98.93,33.89
  IN3 w0.142: v2(48.14,24.23) 48.93,23.45 50.15,23.45 52.61,20.99 52.61,20.52 57.35,15.78 60.69,15.78 60.95,15.52 70.73,15.52 71.4,16.19 74.07,16.19 79.55,21.68 81.24,21.68 82.82,23.25 82.82,24.63 84.77,26.58 84.77,27.04 86.6,28.87 89.97,28.87 92.48,31.38 93.57,31.38 93.83,31.64 95.7,31.64 96.36,32.3 97.35,32.3 98.93,33.89
  BOTTOM w0.076: UC1.AP21 105.93,40.46 v2(105.59,40.86)
  BOTTOM w0.102: JDIMM2.250 45.73,23.38 45.75,23.39 47.3,23.39 v2(48.14,24.23)
DDR_B_D63: length 79.4
  IN3 w0.076: v2(106.21,40.87) 105.62,40.29 104.4,40.29 104.03,39.92 103.46,39.92 100.81,37.26 100.23,37.26 99.85,36.89 99.85,34.3
  IN3 w0.142: v2(46.62,24.23) 47.78,23.07 50.03,23.07 52.25,20.84 52.25,20.37 57.2,15.42 60.54,15.42 60.8,15.16 70.88,15.16 71.55,15.83 74.45,15.83 74.95,16.34 75.55,16.34 79.87,20.66 80.87,20.66 84.37,24.16 84.37,25.67 85.13,26.43 85.13,26.89 86.75,28.51 90.12,28.51 92.63,31.02 93.72,31.02 93.98,31.28 95.85,31.28 96.51,31.95 97.5,31.95 99.85,34.3
  BOTTOM w0.076: v2(106.21,40.87) 106.2,40.76 UC1.AN21
  BOTTOM w0.102: JDIMM2.246 46.22,24.38 46.36,24.23 v2(46.62,24.23)
DDR_B_DQS0: length 85.2
  IN3 w0.076: v2(108.65,64.99) 108.18,65.46 108.18,66.82 107.47,67.52 107.47,68.42 106.04,69.86 106.04,70.12 105.87,70.29 105.82,70.29 105.81,70.31
  IN3 w0.14: 105.81,70.31 105.47,70.65 105.47,73.24 102.64,76.07 98.48,76.07 92.94,81.61 76.58,81.61 76.31,81.89 76.31,82.59 76.17,82.73 75.75,82.73 75.61,82.59 75.61,81.89 75.34,81.61 74.75,81.61 74.48,81.89 74.48,82.54 74.34,82.68 73.92,82.68 73.78,82.54 73.78,81.89 73.51,81.61 73.05,81.61 69.86,84.81 67.37,84.81 66.1,86.08 60.67,86.08 59.69,85.1 59.69,84.9 59.9,84.69 59.9,84.3 59.47,83.87 59.09,83.87 58.87,84.09 58.68,84.09 58.49,83.9 58.49,82.88 57.91,82.31 56.93,82.31 55.38,80.75 54.51,80.75 52.58,78.81 48.14,78.81 47.51,79.45 v2(47.49,79.45)
  BOTTOM w0.076: UC1.AH65 109.07,65.27 v2(108.65,64.99)
  BOTTOM w0.102: v2(47.49,79.45) 47.49,79.48 47.68,79.68 47.68,79.76 47.52,79.92 46.5,79.92 46.11,79.53 45.84,79.53 45.68,79.38 JDIMM2.34
DDR_B_DQS1: length 89.2
  IN3 w0.076: 110.35,73.58 110.35,73.56 110.32,73.53 110.32,72.68 110.14,72.49 109.88,72.49 v2(109.64,72.25)
  IN3 w0.14: 110.35,73.58 110.35,73.96 110.94,74.55 110.94,79.52 102.85,87.61 73.98,87.61 72.68,88.92 72.68,89.66 69.75,92.59 59.58,92.59 56.64,89.65 56.64,89.26 56.66,89.25 56.66,88.98 56.43,88.75 56.16,88.75 56.15,88.77 55.76,88.77 55.33,88.34 55.33,87.95 55.47,87.81 55.47,87.61 54.4,86.54 53.86,86.54 52.87,85.55 52.54,85.55 52.05,85.06 52.05,84.73 51.48,84.16 50.3,84.16 50.19,84.27 50.19,84.39 v2(50.46,84.66)
  BOTTOM w0.076: v2(109.64,72.25) 109.64,72.44 109.55,72.53 109.32,72.53 109.23,72.43 109.23,70.88 109.45,70.66 109.45,69.07 109.37,68.91 109.37,68.78 109.43,68.65 109.43,68.38 109.39,68.3 109.39,68.08 109.45,67.95 109.51,67.89 109.62,67.89 109.69,67.96 109.69,68.15 UC1.AG70
  BOTTOM w0.102: v2(50.46,84.66) 50.4,84.66 50.19,84.86 50.19,84.97 50.29,85.08 51.47,85.08 51.77,84.78 52.02,84.78 52.17,84.62 JDIMM2.13
DDR_B_DQS2: length 71
  IN3 w0.076: 97.86,71.74 98.71,71.74 100.19,70.27 100.23,70.27 101.14,69.36 101.14,68.7 101.64,68.2 102.41,68.2 102.57,68.04 102.57,67.57 102.48,67.48 102.48,66.17 102.79,65.87 104.97,65.87 105.05,65.78 105.05,65.62 104.92,65.49 v2(104.85,65.49)
  IN3 w0.14: v2(50.46,73.99) 50.29,73.99 50.15,74.13 50.15,74.28 50.29,74.42 51.51,74.42 51.93,74 55.37,74 57.43,76.05 58.9,76.05 59.22,76.38 59.22,76.76 59.16,76.82 59.16,77.02 59.46,77.32 59.65,77.32 59.72,77.26 59.81,77.26 60.1,77.26 60.67,77.83 65.6,77.83 66.45,76.98 66.9,76.98 67.18,77.25 67.18,77.75 67.32,77.89 67.74,77.89 67.88,77.75 67.88,77.3 68.15,77.02 68.54,77.02 68.9,77.39 69.35,77.39 69.76,76.98 72.45,76.98 73.48,75.95 75.11,75.95 75.31,75.75 78.36,75.75 79.21,74.9 90.54,74.9 90.85,75.2 93.23,75.2 96.69,71.74 97.86,71.74
  BOTTOM w0.076: v2(104.85,65.49) 105.26,65.07 UC1.AR65
  BOTTOM w0.102: JDIMM2.55 52.21,74.13 52.05,74.28 51.78,74.28 51.56,74.5 50.31,74.5 50.14,74.34 50.14,74.09 50.24,73.99 v2(50.46,73.99)
DDR_B_DQS3: length 68.2
  IN3 w0.076: v2(104.9,62.74) 104.58,63.06 104.58,63.06 104.56,63.08 103.28,63.08 103.18,62.98 103.17,62.98 103.06,62.87 101.74,62.87 100.71,63.9 100.11,63.9 99.61,64.4 99.52,64.4 99.45,64.46
  IN3 w0.14: v2(47.41,68.28) 47.67,68.02 47.67,67.67 47.94,67.4 51.84,67.4 52.75,68.31 55.8,68.31 57.32,69.82 58.86,69.82 60.11,71.07 66.17,71.07 66.66,70.57 91.06,70.57 94.03,67.61 94.03,66.4 94.48,65.94 98.18,65.94 99.11,65.01 99.11,64.81 99.45,64.46
  BOTTOM w0.076: UC1.AR60 105.26,62.38 v2(104.9,62.74)
  BOTTOM w0.102: JDIMM2.76 45.72,68.87 45.87,69.03 46.02,69.03 46.31,68.74 47.58,68.74 47.68,68.64 47.68,68.54 v2(47.41,68.28)
DDR_B_DQS4: length 71.4
  IN3 w0.076: v2(104.86,50.86) 104.68,50.68 104.68,50.48 104.51,50.31 102.67,50.31 100.65,48.28 99.61,48.28 99.06,47.73 98.75,47.73
  IN3 w0.089: 98.7,47.71 98.72,47.71 98.75,47.73
  IN3 w0.14: 98.7,47.71 92.48,47.71 92.27,47.5 90.78,47.5 90.04,46.77 85.71,46.77 82.42,43.49 79.39,43.49 75,39.09 73.45,39.09 71.46,37.1 71.01,37.1 70.43,37.68 70.24,37.68 69.94,37.38 69.94,37.19 70.54,36.59 70.54,36.2 70.17,35.83 68.39,35.83 67.66,35.11 60.07,35.11 55.45,39.73 55.18,39.73 55.03,39.88 53.23,39.88 52.44,40.68 50.18,40.68 49.88,40.98 49.88,41.29 49.76,41.4 v2(49.7,41.4)
  BOTTOM w0.076: v2(104.86,50.86) 104.91,50.8 104.95,50.79 UC1.AR38
  BOTTOM w0.102: v2(49.7,41.4) 49.9,41.19 49.9,40.86 50.23,40.53 51.2,40.53 51.79,41.12 JDIMM2.179
DDR_B_DQS5: length 72.7
  IN3 w0.076: v2(104.9,47.2) 104.67,47.43 104.67,47.44 104.66,47.58 104.51,47.73 103.94,47.73 103.91,47.7 103.22,47.7 102.54,47.01 102.43,47.01 102.01,46.6 102.01,45.93 100.46,44.37 99.78,44.37 99.05,43.65 98.83,43.65
  IN3 w0.14: v2(48.14,36.3) 48.14,36.18 48.02,36.07 48.02,35.96 48.16,35.82 51.32,35.82 52.11,35.03 53.84,35.03 54.28,34.6 54.41,34.6 56.32,32.69 56.71,32.3 57.08,32.3 59.39,29.99 59.39,29.99 59.88,29.5 69.39,29.5 70.12,30.23 72.04,30.23 74.29,32.48 75.71,32.48 82.62,39.39 84.16,39.39 87.44,42.67 91.75,42.67 92.66,43.58 92.73,43.65 98.83,43.65
  BOTTOM w0.076: v2(104.9,47.2) UC1.AR32
  BOTTOM w0.102: JDIMM2.200 45.71,35.87 45.86,36.03 46.01,36.03 46.34,35.7 47.63,35.7 47.84,35.91 47.84,36.17 47.97,36.3 v2(48.14,36.3)
DDR_B_DQS6: length 73.8
  IN3 w0.076: v2(104.9,44.45) 105.1,44.26 105.1,44.09 105.02,44.02 104.73,44.02 104.68,44.07 103.36,44.07 102.77,43.48 102.28,43.48 100.49,41.69 100.49,40.94 100.02,40.47 99.03,40.47 98.41,39.84 96.63,39.84 95.9,39.12
  IN3 w0.14: 95.9,39.12 95.6,38.82 94.02,38.82 93.49,38.29 89.18,38.29 85.95,35.06 84.42,35.06 74.94,25.58 74.62,25.58 73.42,24.37 72.58,24.37 71.91,23.71 69.63,23.71 69.42,23.5 68.45,23.5 68.24,23.71 66.42,23.71 66.09,24.03 65.24,24.03 65.1,24.17 65.1,24.45 64.82,24.72 64.22,24.72 63.94,24.45 63.94,24.17 63.8,24.03 60.65,24.03 59.76,24.92 58.34,24.92 58.18,25.08 57.39,25.08 56.68,25.79 56.68,26.29 56.02,26.95 55.51,26.95 53.49,28.98 53.49,29.12 52.12,30.49 51.43,30.49 51.14,30.19 50.3,30.19 50.11,30.38 50.11,30.52 v2(50.43,30.84)
  BOTTOM w0.076: v2(104.9,44.45) 105.26,44.09 UC1.AR27
  BOTTOM w0.102: v2(50.43,30.84) 50.32,30.84 50.12,31.04 50.12,31.16 50.22,31.27 51.37,31.27 51.86,30.78 52.09,30.78 52.25,30.63 JDIMM2.221
DDR_B_DQS7: length 77.9
  IN3 w0.076: 97.11,34 99.03,35.92 99.03,37.05 99.9,37.92 100.53,37.92 101.2,38.59 101.2,38.98 103.4,41.18 104.63,41.18 104.69,41.12 v2(104.93,40.89)
  IN3 w0.14: 97.11,34 96.78,33.67 94.91,33.67 94.48,33.24 92.5,33.24 92.23,33.51 91.41,33.51 88.14,30.24 86.03,30.24 79.79,24 79.79,23.99 73.36,17.56 70.15,17.56 69.48,16.88 67.59,16.88 66.84,17.64 65.29,17.64 64.54,16.88 61.51,16.88 59.66,18.73 56.33,18.73 53.97,21.09 53.97,21.56 51.84,23.69 51.84,24.19 51.31,24.71 48.04,24.71 47.38,25.37 v2(47.38,25.38)
  BOTTOM w0.076: v2(104.93,40.89) 104.92,40.88 104.92,40.78 UC1.AR21
  BOTTOM w0.102: v2(47.38,25.38) 47.68,25.68 47.68,25.78 47.5,25.96 46.56,25.96 46.12,25.53 45.88,25.53 45.73,25.38 JDIMM2.242
DDR_B_DQS#0: length 85.2
  IN3 w0.076: 105.97,70.47 105.99,70.45 105.99,70.41 106.2,70.19 106.2,69.92 107.64,68.49 107.64,67.59 108.35,66.89 108.35,65.53 108.48,65.39 108.59,65.39 108.72,65.53 v2(108.72,65.6)
  IN3 w0.14: v2(48.17,79.47) 48.09,79.38 48.09,79.19 48.23,79.04 52.48,79.04 54.42,80.98 55.28,80.98 56.84,82.54 57.81,82.54 58.26,82.98 58.26,83.99 58.58,84.31 58.97,84.31 59.18,84.1 59.38,84.1 59.68,84.4 59.68,84.6 59.46,84.81 59.46,85.2 60.58,86.31 66.19,86.31 67.47,85.04 69.95,85.04 73.15,81.84 73.41,81.84 73.55,81.98 73.55,82.64 73.83,82.91 74.44,82.91 74.71,82.64 74.71,81.98 74.85,81.84 75.24,81.84 75.38,81.98 75.38,82.68 75.66,82.95 76.26,82.95 76.54,82.68 76.54,81.98 76.68,81.84 93.03,81.84 98.58,76.3 102.73,76.3 105.7,73.33 105.7,70.74 105.97,70.47
  BOTTOM w0.076: v2(108.72,65.6) 109.09,65.87 UC1.AH66
  BOTTOM w0.102: JDIMM2.32 45.72,79.87 45.87,79.72 46.03,79.72 46.42,80.11 47.6,80.11 47.87,79.84 47.87,79.69 48.1,79.47 v2(48.17,79.47)
DDR_B_DQS#1: length 89.4
  IN3 w0.076: v2(109.64,72.9) 109.88,72.66 110.07,72.66 110.16,72.75 110.16,73.53 110.13,73.56 110.13,73.58
  IN3 w0.14: v2(49.7,84.66) 49.96,84.39 49.96,84.18 50.21,83.93 51.58,83.93 52.28,84.64 52.28,84.96 52.63,85.32 52.96,85.32 53.95,86.31 54.5,86.31 55.7,87.52 55.7,87.9 55.56,88.05 55.56,88.24 55.85,88.54 56.05,88.54 56.07,88.53 56.52,88.53 56.88,88.89 56.88,89.34 56.87,89.36 56.87,89.56 59.68,92.37 69.65,92.37 72.45,89.57 72.45,88.82 73.88,87.39 102.75,87.39 110.72,79.42 110.72,74.65 110.13,74.06 110.13,73.58
  BOTTOM w0.076: v2(109.64,72.9) 109.43,72.7 109.25,72.7 109.06,72.5 109.06,70.81 109.28,70.59 109.28,69.1 109.21,68.95 109.21,68.75 109.26,68.62 109.26,68.41 109.23,68.33 109.23,68.04 109.31,67.86 109.4,67.77 109.56,67.61 UC1.AG69
  BOTTOM w0.102: JDIMM2.11 52.17,85.13 52.01,84.97 51.84,84.97 51.55,85.27 50.22,85.27 50,85.05 50,84.96 v2(49.7,84.66)
DDR_B_DQS#2: length 71.1
  IN3 w0.076: v2(104.9,66.4) 104.53,66.03 102.86,66.03 102.65,66.24 102.65,67.41 102.74,67.5 102.74,68.11 102.48,68.36 101.71,68.36 101.3,68.77 101.3,69.43 100.3,70.43 100.25,70.43 98.78,71.91 97.98,71.91 97.95,71.94 97.9,71.94 97.87,71.97 97.86,71.97
  IN3 w0.14: 97.86,71.97 96.78,71.97 93.33,75.43 90.75,75.43 90.45,75.13 79.31,75.13 78.46,75.98 75.4,75.98 75.2,76.18 73.57,76.18 72.54,77.21 69.85,77.21 69.44,77.62 68.81,77.62 68.44,77.25 68.24,77.25 68.1,77.39 68.1,77.84 67.83,78.11 67.22,78.11 66.95,77.84 66.95,77.35 66.81,77.21 66.54,77.21 65.69,78.06 60.58,78.06 60.01,77.49 59.81,77.49 59.75,77.55 59.36,77.55 58.93,77.12 58.93,76.73 58.99,76.67 58.99,76.47 58.8,76.28 57.33,76.28 55.28,74.22 52.02,74.22 51.6,74.65 50.19,74.65 49.87,74.32 49.87,74.21 v2(49.65,73.99)
  BOTTOM w0.076: UC1.AR66 105.26,66.04 v2(104.9,66.4)
  BOTTOM w0.102: v2(49.65,73.99) 49.85,73.99 49.95,74.09 49.95,74.42 50.23,74.69 51.64,74.69 51.86,74.47 52,74.47 52.16,74.62 JDIMM2.53
DDR_B_DQS#3: length 68.2
  IN3 w0.076: 99.61,64.62 100.17,64.07 100.78,64.07 101.81,63.03 102.99,63.03 103.2,63.24 104.49,63.24 v2(104.9,63.66)
  IN3 w0.14: v2(48.17,68.28) 47.9,68 47.9,67.77 48.04,67.63 51.75,67.63 52.7,68.58 55.75,68.58 57.23,70.05 58.77,70.05 60.03,71.31 66.25,71.31 66.76,70.8 91.16,70.8 94.25,67.7 94.25,66.49 94.58,66.17 98.27,66.17 99.33,65.11 99.33,64.91 99.61,64.62
  BOTTOM w0.076: UC1.AR61 105.26,63.29 v2(104.9,63.66)
  BOTTOM w0.102: JDIMM2.74 45.72,69.38 45.87,69.22 46.1,69.22 46.39,68.93 47.66,68.93 47.87,68.72 47.87,68.58 v2(48.17,68.28)
DDR_B_DQS#4: length 71.3
  IN3 w0.076: 98.75,47.91 99,47.91 99.54,48.45 100.58,48.45 102.6,50.47 104.44,50.47 104.52,50.55 104.52,50.73 104.38,50.86 v2(104.23,50.86)
  IN3 w0.089: 98.7,47.94 98.72,47.94 98.75,47.91
  IN3 w0.14: v2(50.46,41.4) 50.27,41.4 50.12,41.25 50.12,41.06 50.27,40.91 52.53,40.91 53.33,40.11 55.12,40.11 55.28,39.96 55.54,39.96 60.16,35.34 67.57,35.34 68.29,36.06 70.08,36.06 70.31,36.3 70.31,36.49 69.71,37.09 69.71,37.48 70.14,37.91 70.53,37.91 71.11,37.33 71.36,37.33 73.35,39.32 74.91,39.32 79.3,43.71 82.33,43.71 85.61,47 89.95,47 90.68,47.73 92.18,47.73 92.38,47.94 98.7,47.94
  BOTTOM w0.076: UC1.AT38 104.51,50.3 104.38,50.3 104.22,50.51 104.26,50.79 104.22,50.83 v2(104.23,50.86)
  BOTTOM w0.102: JDIMM2.177 52.23,41.63 51.92,41.32 51.71,41.32 51.12,40.72 50.31,40.72 50.09,40.94 50.09,41.31 50.2,41.41 50.45,41.41 v2(50.46,41.4)
DDR_B_DQS#5: length 72.7
  IN3 w0.076: 98.83,43.42 99.06,43.42 99.85,44.21 100.53,44.21 102.18,45.86 102.18,46.53 102.49,46.85 102.6,46.85 103.29,47.53 103.98,47.53 104.01,47.57 104.44,47.57 104.5,47.51 104.5,47.35 104.34,47.2 v2(104.27,47.2)
  IN3 w0.14: 98.83,43.42 92.83,43.42 91.85,42.44 87.53,42.44 84.25,39.16 82.72,39.16 75.81,32.25 74.39,32.25 72.14,30 70.21,30 69.49,29.27 59.79,29.27 59.3,29.76 59.3,29.76 56.99,32.07 56.62,32.07 56.19,32.49 54.32,34.37 54.18,34.37 53.75,34.8 52.02,34.8 51.23,35.59 48.07,35.59 47.8,35.87 47.8,35.95 47.44,36.3 v2(47.38,36.3)
  BOTTOM w0.076: v2(104.27,47.2) UC1.AT32
  BOTTOM w0.102: v2(47.38,36.3) 47.55,36.3 47.65,36.2 47.65,35.99 47.55,35.89 46.42,35.89 46.09,36.22 45.85,36.22 45.7,36.38 JDIMM2.198
DDR_B_DQS#6: length 73.9
  IN3 w0.076: 96.02,38.91 96.78,39.68 98.48,39.68 99.1,40.3 100.09,40.3 100.65,40.87 100.65,41.62 102.35,43.32 102.84,43.32 103.43,43.91 104.61,43.91 v2(104.95,43.57)
  IN3 w0.14: v2(49.67,30.84) 49.87,30.64 49.87,30.3 50.2,29.96 51.23,29.96 51.53,30.26 52.02,30.26 53.26,29.02 53.26,28.89 55.42,26.73 55.92,26.73 56.45,26.2 56.45,25.69 57.29,24.85 58.09,24.85 58.24,24.7 59.66,24.7 60.55,23.8 63.9,23.8 64.17,24.08 64.17,24.35 64.31,24.49 64.73,24.49 64.87,24.35 64.87,24.08 65.14,23.8 66,23.8 66.32,23.48 68.14,23.48 68.35,23.27 69.51,23.27 69.73,23.48 72.01,23.48 72.67,24.15 73.51,24.15 74.72,25.35 75.03,25.35 84.51,34.83 86.05,34.83 89.27,38.06 93.59,38.06 94.12,38.59 95.7,38.59 96.02,38.91
  BOTTOM w0.076: v2(104.95,43.57) 105.26,43.25 UC1.AR25
  BOTTOM w0.102: JDIMM2.219 52.23,31.12 52.08,30.97 51.94,30.97 51.45,31.46 50.15,31.46 49.93,31.24 49.93,31.04 49.73,30.84 v2(49.67,30.84)
DDR_B_DQS#7: length 77.9
  IN3 w0.076: 97.02,34.23 97.1,34.23 98.86,35.99 98.86,37.11 99.83,38.09 100.46,38.09 101.03,38.66 101.03,39.05 103.33,41.35 105.03,41.35 105.1,41.42 105.1,41.53 v2(104.9,41.73)
  IN3 w0.14: 97.02,34.23 96.69,33.9 94.82,33.9 94.39,33.47 92.59,33.47 92.32,33.74 91.32,33.74 88.04,30.46 85.94,30.46 79.56,24.09 79.56,24.09 73.26,17.78 70.06,17.78 69.39,17.11 67.68,17.11 66.93,17.87 65.2,17.87 64.44,17.11 61.61,17.11 59.76,18.96 56.42,18.96 54.2,21.18 54.2,21.65 52.07,23.79 52.07,24.28 51.41,24.94 48.28,24.94 48.14,25.08 v2(48.14,25.38)
  BOTTOM w0.076: UC1.AR22 105.2,41.33 104.9,41.71 v2(104.9,41.73)
  BOTTOM w0.102: v2(48.14,25.38) 47.87,25.65 47.87,25.86 47.58,26.15 46.48,26.15 46.04,25.72 45.9,25.72 45.74,25.87 JDIMM2.240
DDR_B_MA0: length 69.3
  IN3 w0.224: v2(97.78,54.39) 97.87,54.48 97.87,54.76 97.68,54.95 97.02,54.95 96.79,55.17 96.79,55.31 96.57,55.53 91.61,55.53 91.17,55.09 82.4,55.09 78.97,51.66 73,51.66 71.4,50.06 65.56,50.06 65.15,50.47 64.67,50.47 64.26,50.06 63.77,50.06 63.36,50.47 62.88,50.47 62.47,50.06 61.98,50.06 61.58,50.47 61.09,50.47 60.68,50.06 58.57,50.06 58.52,50 57,50 56.67,50.33 53.8,50.33 53.25,50.89 51.14,50.89 50.98,51.05 47.11,51.05 46.79,50.73 44.76,50.73 44.47,51.01 44.47,51.81 44.69,52.03 46.4,52.03 46.65,51.78 v2(46.65,51.51)
  BOTTOM w0.076: v2(97.78,54.39) 97.78,54.25 97.86,54.17 99.71,54.17 99.84,54.05 101.42,54.05 101.5,54.12 UC1.BA46
  BOTTOM w0.17: v2(46.65,51.51) 46.79,51.51 47.16,51.88 47.16,52.13 46.97,52.32 46.41,52.32 45.96,51.87 JDIMM2.144
DDR_B_MA1: length 71
  IN3 w0.076: 89.47,58.12 89.63,58.28 91.88,58.28 v2(92.26,57.9)
  IN3 w0.224: v2(51.22,54.03) 51.33,54.13 54.3,54.13 54.93,53.5 59.67,53.5 60.88,54.71 61.23,54.71 61.45,54.49 61.45,54.47 61.68,54.24 62.12,54.24 62.35,54.47 62.35,54.49 62.57,54.71 63.02,54.71 63.24,54.49 63.24,54.47 63.46,54.25 63.91,54.25 64.13,54.47 64.13,54.49 64.36,54.71 64.8,54.71 65.03,54.49 65.03,54.47 65.25,54.25 65.7,54.25 66.15,54.7 66.49,54.7 66.72,54.92 66.72,55.77 66.94,56 67.39,56 67.61,55.77 67.61,54.9 67.83,54.68 68.15,54.68 68.37,54.9 68.37,55.36 68.68,55.67 69.89,55.67 70.41,55.14 70.73,55.14 71.25,55.67 71.66,55.67 71.89,55.89 71.89,56.89 72.11,57.11 72.56,57.11 72.78,56.89 72.78,55.89 73,55.67 73.45,55.67 73.67,55.89 73.67,56.89 73.9,57.11 74.31,57.11 74.54,56.89 74.54,55.92 74.79,55.67 75.24,55.67 75.46,55.89 75.46,56.89 75.69,57.11 76.13,57.11 76.36,56.89 76.36,55.89 76.58,55.67 77.03,55.67 77.27,55.91 77.27,56.89 77.49,57.11 77.9,57.11 78.12,56.89 78.12,56.01 78.42,55.72 78.73,55.72 81.14,58.12 89.47,58.12
  BOTTOM w0.076: v2(92.26,57.9) 92.26,57.72 94.13,55.85 97.07,55.85 98.1,54.82 99.53,54.82 99.95,54.4 100.51,54.4 100.69,54.58 100.95,54.58 101.07,54.52 101.21,54.52 101.44,54.59 101.58,54.59 101.79,54.51 101.89,54.41 UC1.AY46
  BOTTOM w0.17: JDIMM2.133 51.82,54.62 51.21,54.62 51.04,54.45 51.04,54.21 v2(51.22,54.03)
DDR_B_MA2: length 70.8
  IN3 w0.076: v2(94.63,57.9) 94.89,58.16 94.89,58.82 94.68,59.03 92.3,59.03 91.78,59.56 88.28,59.56 88.12,59.72
  IN3 w0.224: 88.12,59.72 76.73,59.72 76.34,59.33 73.38,59.33 72.7,58.65 70.97,58.65 70.45,58.14 70.45,57.78 70.18,57.5 61.45,57.5 60.59,56.65 59.23,56.65 58.23,55.65 53.77,55.65 53.77,55.64 45.01,55.64 44.79,55.42 44.79,53.33 45.01,53.11 45.51,53.11 45.74,53.33 45.74,53.87 45.89,54.03 v2(46.65,54.03)
  BOTTOM w0.076: UC1.AY47 102.47,55.02 102.3,55.19 102.13,55.19 102.08,55.24 101.71,55.24 101.63,55.21 101.52,55.21 101.51,55.2 101.38,55.2 101.37,55.2 101.36,55.21 101.32,55.21 101.3,55.23 101.27,55.24 101.07,55.24 100.98,55.21 100.98,55.21 100.48,55.21 100.39,55.3 100.08,55.3 99.99,55.21 98.18,55.21 96.7,56.69 95.32,56.69 94.95,57.05 94.56,57.05 94.44,57.17 94.44,57.71 v2(94.63,57.9)
  BOTTOM w0.17: v2(46.65,54.03) 46.82,54.2 46.82,54.59 46.65,54.76 45.91,54.76 45.8,54.87 JDIMM2.132
DDR_B_MA3: length 69.8
  IN3 w0.076: v2(92.85,57.9) 93.2,58.25 93.2,58.48 93.12,58.56 92.1,58.56 92.02,58.64 86.77,58.64
  IN3 w0.224: v2(49.7,54.03) 49.7,54.41 49.92,54.64 55.83,54.64 56.43,54.04 59.43,54.04 61.05,55.66 65.44,55.66 66.28,56.5 70.79,56.5 71.94,57.65 77.53,57.65 77.75,57.87 77.75,58.45 77.98,58.67 78.33,58.67 78.55,58.45 78.55,57.15 78.77,56.93 79.22,56.93 79.45,57.15 79.45,58.42 79.67,58.64 86.77,58.64
  BOTTOM w0.076: UC1.BB46 100.77,54.24 99.88,54.24 99.59,54.53 v1(98.6,54.53) 98.16,54.53 97.13,55.56 93.86,55.56 91.88,57.54 91.88,58.22 92.02,58.35 92.57,58.35 92.85,58.08 v2(92.85,57.9)
  BOTTOM w0.17: v2(49.7,54.03) 49.56,54.03 48.91,54.67 48.91,55.33 49.3,55.72 49.6,55.72 49.87,55.45 49.87,55.19 50.04,55.01 50.28,55.01 50.45,55.19 50.45,55.55 50.62,55.72 51.07,55.72 51.08,55.7 51.39,55.7 51.96,55.13 JDIMM2.131
DDR_B_MA4: length 70.2
  IN3 w0.224: v2(94.04,57.9) 94.23,58.08 94.23,58.55 93.98,58.8 92.2,58.8 91.87,59.13 87.07,59.13 86.98,59.22 77.16,59.22 76.94,58.99 76.94,58.37 76.71,58.15 76.27,58.15 76.04,58.37 76.04,58.6 75.82,58.82 75.37,58.82 75.15,58.6 75.15,58.37 74.92,58.15 74.48,58.15 74.25,58.37 74.25,58.6 74.03,58.82 73.58,58.82 73.36,58.6 73.36,58.37 73.14,58.15 71.18,58.15 70.95,57.93 70.95,57.38 70.58,57 66.08,57 65.23,56.16 60.84,56.16 60.45,55.77 60.13,55.77 59.76,56.14 59.44,56.14 59.12,55.83 59.12,55.51 59.5,55.13 59.5,54.82 59.22,54.54 58.95,54.54 58.54,54.95 58.38,54.95 57.97,54.54 57.04,54.54 56.45,55.14 48.34,55.14 48.17,54.97 v2(48.17,54.03)
  BOTTOM w0.076: v2(94.04,57.9) 93.97,57.9 93.55,57.48 93.55,56.98 94.14,56.4 v1(96.55,56.4) 96.76,56.4 98.17,54.98 99.6,54.98 100.02,54.57 100.45,54.57 100.62,54.74 100.99,54.74 101.02,54.73 101.1,54.7 101.22,54.7 101.44,54.76 101.75,54.76 101.82,54.84 UC1.BA47
  BOTTOM w0.17: v2(48.17,54.03) 48.32,54.03 48.49,54.2 48.49,54.93 48.23,55.19 46.34,55.19 45.65,55.87 JDIMM2.128
DDR_B_MA5: length 70.3
  IN3 w0.076: v2(96.97,57.9) 97.05,57.9 97.46,58.31 97.46,58.56 97.14,58.88 97.14,59.98 96.98,60.14 90.11,60.14 88.64,61.61 88.64,61.74
  IN3 w0.224: 88.64,61.74 88.11,62.26 82.25,62.26 82.03,62.04 82.03,61.48 81.8,61.25 81.36,61.25 81.13,61.48 81.13,62.04 80.91,62.26 80.56,62.26 80.33,62.04 80.33,61.48 80.11,61.25 70.27,61.25 69.05,60.03 59.52,60.03 58.68,59.19 58.68,58.66 58.46,58.44 56.03,58.44 55.3,57.72 53.61,57.72 53.04,57.15 49.71,57.15 49.23,56.67 48.72,56.67 48.24,57.15 47.9,57.15 47.67,56.93 47.67,56.56 48.07,56.16 v2(48.17,56.16)
  BOTTOM w0.076: UC1.AY48 102.18,55.67 102.18,55.81 102.1,55.89 100.67,55.89 100.6,55.82 98.27,55.82 96.91,57.18 96.61,57.18 96.48,57.32 96.48,57.48 96.9,57.9 v2(96.97,57.9)
  BOTTOM w0.17: JDIMM2.126 45.8,56.38 46.56,55.61 48.07,55.61 48.24,55.78 48.24,56.09 v2(48.17,56.16)
DDR_B_MA6: length 69.1
  IN3 w0.076: v2(95.8,57.9) 96.22,58.32 96.22,58.83 95.85,59.2 92.37,59.2 91.85,59.72 89.77,59.72 89.58,59.91 88.53,59.91 88.22,60.23
  IN3 w0.224: v2(51.22,56.16) 51.24,56.15 53.72,56.15 54.28,56.71 54.99,56.71 55.21,56.49 55.21,56.37 55.44,56.15 55.89,56.15 56.11,56.37 56.11,56.49 56.33,56.71 56.82,56.71 57.38,56.15 58.02,56.15 59.05,57.17 60.21,57.17 60.38,57.35 60.38,58.2 60.62,58.44 65.16,58.44 65.39,58.66 65.39,58.8 65.61,59.03 66.06,59.03 66.28,58.8 66.28,58.66 66.51,58.44 66.95,58.44 67.18,58.66 67.18,58.8 67.4,59.03 67.85,59.03 68.07,58.8 68.07,58.66 68.29,58.44 69.45,58.44 69.87,58.85 70.12,58.85 70.3,59.03 70.3,59.86 70.67,60.23 71.02,60.23 71.24,60.01 71.24,59.38 71.47,59.16 71.91,59.16 72.14,59.38 72.14,60.01 72.36,60.23 72.71,60.23 73.11,59.83 73.6,59.83 74,60.23 74.5,60.23 74.9,59.83 75.39,59.83 75.79,60.23 82.97,60.23 83.19,60.45 83.19,61.01 83.42,61.24 83.86,61.24 84.09,61.01 84.09,60.45 84.31,60.23 84.66,60.23 84.88,60.45 84.88,61.01 85.11,61.24 85.55,61.24 85.78,61.01 85.78,60.45 86,60.23 86.35,60.23 86.58,60.45 86.58,61.01 86.8,61.24 87.25,61.24 87.47,61.01 87.47,60.45 87.69,60.23 88.22,60.23
  BOTTOM w0.076: v2(95.8,57.9) 95.75,57.9 95.27,57.42 95.27,57.12 95.54,56.85 96.77,56.85 98.13,55.49 100.46,55.49 100.58,55.37 100.95,55.37 101.04,55.41 101.06,55.41 101.3,55.41 101.39,55.37 101.6,55.37 101.68,55.4 101.78,55.44 101.83,55.54 101.8,55.64 UC1.BA48
  BOTTOM w0.17: JDIMM2.127 51.46,56.13 51.43,56.16 v2(51.22,56.16)
DDR_B_MA7: length 72
  IN3 w0.076: 90.12,60.37 90.19,60.3 97.05,60.3 98.44,58.91 98.44,58.19 99.94,56.69 105.48,56.69 105.56,56.62 v2(105.56,56.41)
  IN3 w0.089: 90,61.09 90,60.49 90.12,60.37
  IN3 w0.224: v2(46.65,56.16) 45.39,56.16 45.17,56.38 45.17,57.3 45.52,57.65 52.83,57.65 54.01,58.83 55.7,58.83 56.51,59.64 58.41,59.64 59.31,60.54 68.84,60.54 70.06,61.76 79.55,61.76 79.83,62.03 79.83,62.54 80.05,62.76 88.32,62.76 90,61.09
  BOTTOM w0.076: UC1.AP48 105.91,55.98 v2(105.56,56.41)
  BOTTOM w0.17: JDIMM2.122 45.64,57.38 46.65,56.36 v2(46.65,56.16)
DDR_B_MA8: length 67.8
  IN3 w0.076: v2(96.38,57.9) 96.47,57.9 96.66,58.1 96.66,58.29 96.43,58.53 96.43,58.86 96.79,59.22 96.79,59.53 96.35,59.97 89.8,59.97 89.51,60.27 89.31,60.27 89.2,60.38
  IN3 w0.224: v2(49.7,56.16) 49.7,56.42 49.92,56.65 53.25,56.65 53.82,57.21 55.97,57.21 56.19,57.44 56.19,57.71 56.41,57.94 56.86,57.94 57.08,57.71 57.08,57.48 57.31,57.25 57.81,57.25 58.41,57.86 58.73,57.86 58.91,57.68 59.23,57.68 59.54,57.99 59.54,58.31 59.18,58.67 59.18,58.98 59.72,59.52 60.03,59.52 60.22,59.33 60.22,59.14 60.41,58.95 60.92,58.95 61.17,59.21 61.17,59.28 61.43,59.53 69.26,59.53 70.48,60.75 82.47,60.75 82.69,60.97 82.69,61.54 82.91,61.76 87.75,61.76 87.97,61.54 87.97,61.04 88.22,60.79 88.79,60.79 89.2,60.38
  BOTTOM w0.076: v2(96.38,57.9) 96.32,57.9 95.84,57.42 95.84,57.17 95.99,57.02 96.84,57.02 98.2,55.66 100.53,55.66 100.59,55.6 100.81,55.6 UC1.BB48
  BOTTOM w0.17: JDIMM2.125 51.88,56.62 51.3,57.2 49.44,57.2 49.27,57.03 49.27,56.45 49.56,56.16 v2(49.7,56.16)
DDR_B_MA9: length 67.7
  IN3 w0.076: v2(105.6,57.22) 105.6,57.25 105.23,57.63 100.86,57.63 98.08,60.41 98.08,60.97 97.59,61.45 95.55,61.45 95.37,61.63 90.88,61.63
  IN3 w0.224: v2(49.7,58.14) 50.22,58.66 52.42,58.66 53.59,59.83 55.28,59.83 56.09,60.64 58,60.64 59.73,62.37 69.01,62.37 69.39,62.76 71.46,62.76 71.68,62.98 71.68,63.55 71.9,63.77 72.35,63.77 72.57,63.55 72.57,62.98 72.8,62.76 73.15,62.76 73.37,62.98 73.37,63.55 73.6,63.77 88.74,63.77 90.88,61.63
  BOTTOM w0.076: UC1.AP50 105.64,56.82 105.57,56.91 v2(105.6,57.22)
  BOTTOM w0.17: v2(49.7,58.14) 49.61,58.05 49.61,57.81 49.79,57.62 JDIMM2.121
DDR_B_MA10: length 70.4
  IN3 w0.224: v2(46.65,49.87) 47.32,50.54 50.77,50.54 50.93,50.38 53.04,50.38 53.6,49.83 56.46,49.83 56.79,49.5 60.04,49.5 60.42,49.12 65.62,49.12 66.05,49.55 66.51,49.55 66.94,49.12 67.4,49.12 67.84,49.55 68.3,49.55 68.73,49.12 69.08,49.12 69.51,49.55 69.97,49.55 70.41,49.12 71.18,49.12 73.21,51.16 79.18,51.16 82.61,54.58 91.38,54.58 91.87,55.07 92.08,55.07 92.22,55.22 95.32,55.22 95.52,55.01 95.7,55.01 95.91,55.22 96.2,55.22 96.35,55.07 96.35,54.82 95.87,54.34 v2(95.87,54.28)
  BOTTOM w0.076: v2(95.87,54.28) 95.52,54.63 95.52,55.01 95.9,55.4 96.98,55.4 97.41,54.97 97.41,54.14 97.55,54.01 99.64,54.01 99.76,53.88 101.49,53.88 101.73,54.12 102.22,54.12 102.42,54.22 102.61,54.41 UC1.AW46
  BOTTOM w0.17: JDIMM2.146 45.67,49.38 45.84,49.55 45.84,50.9 46.01,51.07 47.09,51.07 47.26,50.9 47.26,50.35 46.79,49.87 v2(46.65,49.87)
DDR_B_MA11: length 72.5
  IN3 w0.076: 95.87,61.65 95.9,61.62 97.66,61.62 98.24,61.04 98.24,60.48 100.93,57.79 105.3,57.79 105.5,57.59 105.77,57.59 105.83,57.54 106.41,57.54 106.61,57.34 106.61,56.69 v2(106.19,56.28)
  IN3 w0.089: 95.87,61.65 95.31,62.22 93.58,62.22 93.36,62.43 91.73,62.43 91.48,62.18 91.16,62.18
  IN3 w0.224: v2(48.17,58.14) 47.9,58.42 47.9,58.86 48.12,59.08 49.44,59.08 49.69,59.33 52.24,59.33 53.67,60.77 55.24,60.77 55.78,61.31 57,61.31 57.3,61.61 58.25,61.61 59.52,62.88 68.8,62.88 69.17,63.25 69.28,63.25 69.5,63.47 69.5,64.05 69.72,64.27 70.16,64.27 70.38,64.05 70.38,63.49 70.6,63.26 70.95,63.26 71.18,63.49 71.18,64.05 71.4,64.27 89.07,64.27 91.16,62.18
  BOTTOM w0.076: UC1.AN48 106.53,55.89 v2(106.19,56.28)
  BOTTOM w0.17: v2(48.17,58.14) 47.59,57.55 46.06,57.55 45.81,57.8 45.81,57.8 45.74,57.87 JDIMM2.120
DDR_B_MA12: length 71.4
  IN3 w0.076: 100.01,56.86 100.02,56.86 106.15,56.86 106.22,56.93 v2(106.22,57.17)
  IN3 w0.089: 100.01,56.86 98.61,58.26 98.61,58.98 97.12,60.48 90.91,60.48 90.57,60.81
  IN3 w0.224: 90.57,60.81 90.57,61.22 88.53,63.27 79.33,63.27 79.1,63.04 79.1,62.48 78.88,62.26 78.43,62.26 78.21,62.48 78.21,63.04 77.99,63.27 77.54,63.27 77.32,63.04 77.32,62.54 77.03,62.26 76.68,62.26 76.46,62.48 76.46,63.04 76.24,63.27 75.79,63.27 75.57,63.04 75.57,62.48 75.34,62.26 74.99,62.26 74.77,62.48 74.77,63.04 74.55,63.27 74.1,63.27 73.87,63.04 73.87,62.48 73.65,62.26 69.6,62.26 69.22,61.87 68.48,61.87 68.26,61.65 68.26,61.26 68.03,61.04 67.62,61.04 67.39,61.26 67.39,61.68 67.21,61.87 66.95,61.87 66.73,61.65 66.73,61.26 66.5,61.04 66.06,61.04 65.83,61.26 65.83,61.65 65.61,61.87 61.01,61.87 60.79,61.65 60.79,61.33 60.52,61.06 60.2,61.06 59.84,61.43 59.49,61.43 58.21,60.14 56.3,60.14 55.49,59.33 53.8,59.33 52.63,58.16 51.24,58.16 v2(51.22,58.14)
  BOTTOM w0.076: UC1.AN50 106.58,57.07 106.51,57.15 v2(106.22,57.17)
  BOTTOM w0.17: v2(51.22,58.14) 51.2,58.17 51.2,58.41 51.38,58.59 51.62,58.59 51.79,58.42 51.79,58.3 51.96,58.13 JDIMM2.119
DDR_B_MA13: length 67
  IN3 w0.076: 88.63,50.42 89.16,50.95 95.58,50.95 96.69,52.06 v2(96.69,52.41)
  IN3 w0.224: 88.63,50.42 84.19,50.42 80.91,47.13 76.33,47.13 71.31,42.11 67.87,42.11 65.95,40.19 60.45,40.19 59.06,41.58 59.06,42.62 57.81,43.87 55.86,43.87 55.34,44.39 53.34,44.39 51.64,46.09 49.34,46.09 v2(48.17,47.26)
  BOTTOM w0.076: v2(96.69,52.41) 96.69,52.64 97.07,53.02 99.22,53.02 99.39,52.85 99.49,52.85 100.07,52.27 100.51,52.27 100.62,52.39 100.72,52.39 100.73,52.39 100.98,52.39 101.12,52.34 101.23,52.34 101.32,52.38 101.35,52.39 101.59,52.39 UC1.BA43
  BOTTOM w0.17: v2(48.17,47.26) 48.14,47.26 47.25,46.38 JDIMM2.158
DDR_B_ODT0: length 67.9
  IN3 w0.076: 88.55,51.66 92.8,51.66 93,51.86 93,52.46 93.26,52.72 94.78,52.72 94.86,52.64 94.86,52.4 94.75,52.3 v2(94.62,52.3)
  IN3 w0.224: v2(51.22,47.26) 51.35,47.26 51.51,47.1 52.05,47.1 53.76,45.39 56.15,45.39 56.67,44.88 57.06,44.88 57.48,45.3 57.8,45.3 60.06,43.04 60.06,42.18 60.29,41.96 61.51,41.96 61.74,41.74 61.74,41.42 61.96,41.19 62.41,41.19 62.63,41.42 62.63,41.74 62.85,41.96 63.47,41.96 63.8,41.62 64.41,41.62 64.72,41.93 65.31,41.93 65.61,41.62 65.96,41.62 66.32,41.98 66.32,42.3 66.06,42.57 66.06,42.88 66.29,43.12 66.76,43.12 66.99,43.34 66.99,43.37 67.21,43.59 67.66,43.59 67.88,43.37 67.88,43.34 68.1,43.12 69.1,43.12 69.33,43.34 69.33,43.37 69.55,43.59 70,43.59 70.22,43.37 70.22,43.34 70.44,43.12 70.89,43.12 75.91,48.14 80.43,48.14 83.86,51.57 88.45,51.57 88.55,51.66
  BOTTOM w0.076: UC1.BA42 101.45,52.01 101.3,52.01 101.04,51.75 100.92,51.69 100.62,51.69 100.58,51.74 99.84,51.74 99.66,51.92 98.85,51.92 98.76,51.83 94.33,51.83 94.26,51.89 94.26,52 94.37,52.1 94.37,52.14 94.52,52.3 v2(94.62,52.3)
  BOTTOM w0.17: JDIMM2.155 51.95,47.12 50.96,46.14 50.68,46.14 50.44,46.38 50.44,46.62 50.88,47.06 50.88,47.09 51.05,47.26 v2(51.22,47.26)
DDR_B_ODT1: length 69.9
  IN3 w0.076: v2(99.07,52.65) 99.07,52.79 99.17,52.89 99.56,52.89 99.71,52.73 99.71,51.94 99.53,51.76 99.28,51.76 99.07,51.55 99.07,51.47 99.06,51.46 99.06,50.81 98.65,50.4 98,50.4 97.94,50.34 96.05,50.34 96.04,50.33 92.97,50.33 92.8,50.16 91.29,50.16
  IN3 w0.224: 91.29,50.16 89.7,50.16 88.95,49.41 84.61,49.41 81.33,46.13 76.75,46.13 71.72,41.11 70.92,41.11 70.69,40.88 70.69,40.58 70.47,40.36 70.02,40.36 69.8,40.58 69.8,40.88 69.57,41.11 69.22,41.11 68.79,40.67 67.86,40.67 67.61,40.43 67.61,39.82 67.28,39.49 66.68,39.49 65.7,38.51 65.7,38.38 65.47,38.16 65.03,38.16 64.8,38.38 64.8,38.51 64.58,38.73 64.13,38.73 63.91,38.51 63.91,38.38 63.68,38.16 63.24,38.16 63.01,38.38 63.01,38.51 62.79,38.73 62.34,38.73 62.12,38.51 62.12,38.38 61.9,38.16 61.45,38.16 61.23,38.38 61.23,38.51 61,38.73 60.48,38.73 58.05,41.16 58.05,41.75 57.8,42 57.21,42 56.35,42.86 53.99,42.86 53.47,43.38 52.93,43.38 51.87,44.44 51.11,44.44 50.88,44.66 50.88,44.86 51.11,45.09 v2(51.22,45.09)
  BOTTOM w0.076: UC1.AW42 102.87,52.03 102.87,52.14 102.77,52.24 102.36,52.24 102.2,52.4 101.98,52.4 101.78,52.19 101.68,52.19 101.6,52.22 101.39,52.22 101.28,52.17 101.06,52.17 101.04,52.19 100.95,52.22 100.75,52.22 100.75,52.22 100.69,52.22 100.54,52.07 100.04,52.07 99.43,52.68 99.1,52.68 v2(99.07,52.65)
  BOTTOM w0.17: v2(51.22,45.09) 51.35,44.96 51.59,44.96 51.9,45.27 51.9,45.49 52.03,45.62 52.03,45.63 JDIMM2.161
DDR_B_PAR: length 73.6
  IN3 w0.076: 102.02,53.11 102.06,53.15 105.91,53.15 105.98,53.22 105.98,53.39 105.8,53.57 v2(105.65,53.57)
  IN3 w0.224: 102.02,53.11 100.34,53.11 100.14,53.31 100.14,54.04 99.92,54.26 99.19,54.26 97.56,55.9 91.27,55.9 90.96,55.59 82.19,55.59 78.77,52.16 71.75,52.16 71.53,51.94 71.53,50.9 71.19,50.56 69.24,50.56 69.02,50.78 69.02,51.2 68.79,51.42 68.35,51.42 68.12,51.2 68.12,50.78 67.9,50.56 66.18,50.56 65.77,50.97 58.81,50.97 58.35,50.51 57.21,50.51 56.88,50.83 54.01,50.83 53.46,51.39 51.35,51.39 v2(51.22,51.51)
  BOTTOM w0.076: v2(105.65,53.57) 105.59,53.57 105.51,53.5 105.51,53.28 105.7,53.06 105.83,53.06 105.91,53.13 UC1.AP43
  BOTTOM w0.17: v2(51.22,51.51) 51.08,51.51 50.64,51.07 50.06,51.07 50.06,51.08 49.82,51.08 49.7,50.96 49.7,50.48 49.87,50.31 51.79,50.31 51.96,50.48 51.96,50.64 52.13,50.81 53.82,50.81 53.99,50.98 53.99,51.32 53.82,51.49 52.13,51.49 51.96,51.66 51.96,51.95 52.13,52.12 JDIMM2.143
DDR_B_RAS#: length 64.5
  IN3 w0.076: v2(97.05,54.32) 97.05,54.02 96.8,53.78 92.61,53.78 91.9,53.07
  IN3 w0.224: v2(48.17,48.31) 48.17,48.32 48.17,48.63 48.4,48.87 52.42,48.87 53.8,47.48 58.56,47.48 60.66,45.39 65.62,45.39 66.05,45.83 67.1,45.83 67.94,46.66 69.42,46.66 69.87,47.1 72.74,47.1 75.29,49.65 79.81,49.65 83.23,53.07 91.9,53.07
  BOTTOM w0.076: UC1.AW44 102.64,53.18 102.47,53.35 102.4,53.35 102.27,53.48 101.73,53.48 101.65,53.55 101.24,53.55 101.07,53.72 99.7,53.72 99.57,53.84 97.48,53.84 97.05,54.28 v2(97.05,54.32)
  BOTTOM w0.17: JDIMM2.152 46.15,47.87 46.27,47.75 47.61,47.75 v2(48.17,48.31)
DDR_B_WE#: length 63.9
  IN3 w0.076: 92.09,52.16 93.01,53.07 95.13,53.07 95.46,52.74 95.46,52.54 v2(95.21,52.29)
  IN3 w0.224: v2(49.7,48.31) 50.25,47.76 51.56,47.76 51.72,47.6 52.26,47.6 53.96,45.9 57.91,45.9 60.66,43.15 65.62,43.15 66.55,44.09 71.15,44.09 75.7,48.64 80.23,48.64 83.65,52.07 88.26,52.07 88.35,52.16 92.09,52.16
  BOTTOM w0.076: UC1.AY44 101.9,53.18 101.8,53.08 101.79,53.08 101.58,53.01 101.44,53.01 101.21,53.07 101.07,53.07 100.95,53.02 100.68,53.02 100.52,53.18 99.53,53.18 99.36,53.35 96.26,53.35 v1(95.99,53.08) v2(95.21,52.29)
  BOTTOM w0.17: JDIMM2.151 52.15,48.12 51.9,47.87 50.14,47.87 v2(49.7,48.31)
DDR_VTT_CNTL: length 17.7
  TOP w0.102: UC2.2 91.59,73.3 91.52,73.24 91.52,72.86 91.78,72.6 v2(92.41,72.6)
  BOTTOM w0.076: 100.5,66.69 100.72,66.47 101.23,66.47 101.29,66.41 102.14,66.41 102.61,66.63 UC1.AW67
  BOTTOM w0.102: 100.5,66.69 100.09,66.69 99.82,66.96 99.82,67.93 99.89,68 99.89,70.45 99.42,70.92 97.33,70.92 97.04,70.62 v1(96.04,70.62) 94.4,70.62 v2(92.41,72.6)
DGPU_HOLD_RST#: length 256.1
  TOP w0.102: v2(98.54,101.58) 96.01,101.58 94.86,102.73 90.73,102.73 v3(90.1,102.1) 87.71,99.71 76.81,99.71 73.79,96.69 49.24,96.69 34.11,81.56 29.67,81.56 29.67,81.56 v2(29.68,81.56)
  IN3 w0.142: v2(118.49,25.77) 118.49,24.63 118.26,24.4 118.26,22.21 117.72,21.67 117.72,20.83 116.32,19.44 116.32,14.61 110.85,9.14 107.94,9.14 106.83,8.02 102.51,8.02 101.7,7.22 91.21,7.22 89.99,6 62.59,6 62.21,6.39 56.08,6.39 55.74,6.72 52.02,6.72 48.96,9.79 48.29,9.79 43.62,14.45 43.62,15.34 43.2,15.77 43.2,18.21 39.45,21.95 39.45,29.02 34.56,33.9 30.32,33.9 28.72,35.51 28.72,35.73 28.75,35.75 28.75,54.96 27.96,55.75 27.96,60.1 28.76,60.9 28.76,64.83 28.39,65.19 28.39,78.01 29.17,78.79 29.17,81.23 29.48,81.55 29.66,81.55 v2(29.68,81.56)
  BOTTOM w0.076: UC1.P3 115.99,29.7 115.72,29.42 115.72,28.35 115.91,28.15 116.42,28.15 116.99,27.58 116.99,27.58
  BOTTOM w0.102: 116.99,27.58 118.49,26.08 v2(118.49,25.77) 118.49,25.6 RC48.1 ; v2(98.54,101.58) 98.12,101.58 97.87,101.83 UV2.2
DGPU_PWR_EN: length 368
  TOP w0.102: v2(81.94,97.27) 83.26,95.94 v3(84.27,95.94) 95.3,95.94 101.16,90.08 115.96,90.08 116.88,91 117.69,91 117.71,91.03 120.14,91.03 v2(120.49,90.68) ; PR1116.1 v2(47.58,123.15)
  IN1 w0.119: v2(81.94,97.27) 81.52,97.68 65.17,97.68 60.66,102.19 60.66,106.13 61.68,107.14 62.02,107.14 62.3,107.42 62.3,109.16 61.89,109.56 57.23,109.56 53.87,112.92 52.42,112.92 50.12,115.22 50.12,120.61 v2(47.58,123.15)
  IN2 w0.127: v2(44.83,15.18) 44.83,15.74 41.67,18.89 41.67,31.11 38.75,34.03 38.75,82.73 45.81,89.79 69.48,89.79 71.29,87.97 109.9,87.97 111.31,89.38 119.19,89.38 v2(120.49,90.68)
  IN3 w0.142: v2(117.37,25.55) 117.48,25.45 117.48,20.94 116.08,19.54 116.08,14.72 110.77,9.41 107.83,9.41 106.71,8.29 102.4,8.29 101.59,7.49 91.09,7.49 89.88,6.27 62.67,6.27 62.31,6.63 56.18,6.63 55.82,6.99 52.14,6.99 49.07,10.05 48.63,10.05 45.46,13.22 45.46,14.55 v2(44.83,15.18)
  BOTTOM w0.102: v2(120.49,90.68) 120.02,90.2 119.32,90.2 RZ8.1 ; v2(120.49,90.68) 120.8,90.68 121.33,90.14 128.89,90.14 129.29,90.54 RZ6.1 ; v2(120.49,90.68) 120.49,90.94 118.95,92.48 RZ7.1 ; RC49.2 RC50.2 117.87,22.98 117.37,23.49 v2(117.37,25.55) 117.37,25.8 116.25,26.92 115.91,26.92 114.79,28.04 114.79,28.41 UC1.U1
DGPU_PWROK: length 401
  TOP w0.102: PR1122.2 47.61,121.35 v2(47.58,121.37)
  IN3 w0.142: v2(28.09,78.76) 27.9,78.58 27.9,64.99 28.27,64.62 28.27,61.92 25.84,59.5 25.84,55.73 27.36,54.21 27.36,39.87 26.07,38.57 26.07,34.47 28.78,31.76 33.72,31.76 37.33,28.14 37.33,21.08 41.08,17.33 41.08,12 48.75,4.34 54.83,4.34 55.54,3.62 90.98,3.62 92.02,4.66 109.67,4.66 120.48,15.47 120.48,18.24 124.97,22.73 124.97,24.39 125.8,25.22 125.8,27.21 123.57,29.44 123.57,30.67 v2(124.3,31.39) ; v2(161.44,85.76) 161.44,87.97 158.51,90.89 158.51,94.06 156.42,96.16 146.52,96.16 145.5,97.18 140.86,97.18 140.29,96.61 136.74,96.61 130.51,90.38 123.09,90.38 121.69,91.78 121.69,93.84 118.07,97.46 118.07,102.03 115.83,104.27 112.11,104.27 111.62,103.78 109.63,103.78 108.98,104.42 96.03,104.42 95.19,103.59 95.19,98.78 93.54,97.12 85.46,97.12 84.27,98.31 75.6,98.31 73.11,100.81 68.55,100.81 67.29,102.08 66.44,102.08 61.16,102.08 59.99,103.25 57.17,103.25 56.08,104.34 56.08,108.86 48.5,116.44 48.5,120.46 v2(47.58,121.37)
  BOTTOM w0.076: UC1.C8 122.7,32.62 123.18,32.15 123.18,31.95 123.33,31.8 123.88,31.8 124.29,31.39 v2(124.3,31.39) 124.71,30.99 125.16,30.99 125.42,30.73 125.88,30.73 126.81,29.81 RC116.2
  BOTTOM w0.102: v2(47.58,121.37) 45.99,121.37 43.07,118.45 43.07,117.11 v1(30.3,104.34) 29.27,103.31 29.27,82.56 29.1,82.4 29.1,80.19 28.09,79.17 v2(28.09,78.76) ; PR1403.1 161.42,85.74 v2(161.44,85.76)
DIMM_CHA_SA0: length 5.4
  TOP w0.102: v1(61.61,21.38) v2(61.61,20.87) 61.17,20.43 RD4.1 RD1.2
  BOTTOM w0.102: v2(61.61,20.87) 61.59,20.87 61.09,21.38 JDIMM1.256
DIMM_CHA_SA1: length 7.3
  TOP w0.102: RD2.2 65.46,19.79 RD5.1 64.33,19.79 63.84,20.28 62.6,20.28 v1(62.5,20.38) 62.37,20.51 v2(62.37,20.87)
  BOTTOM w0.102: v2(62.37,20.87) 61.88,20.38 JDIMM1.260
DIMM_CHA_SA2: length 4.9
  TOP w0.102: RD3.2 RD6.1 v1(60.5,43.12) 60.85,43.47 v2(60.85,43.62)
  BOTTOM w0.102: JDIMM1.166 60.6,43.87 v2(60.85,43.62)
DIMM_CHB_SA0: length 8.1
  TOP w0.102: v2(49.09,21.35) 49.09,21.23 49.71,20.61 RD16.1 50.16,20.61 50.95,19.83 RD13.2 v1(50.95,18.79)
  BOTTOM w0.102: v2(49.09,21.35) 49.09,21.43 48.65,21.87 JDIMM2.256
DIMM_CHB_SA1: length 7.5
  TOP w0.102: v1(46.78,19.73) 46.64,19.87 RD14.2 46.64,20.85 RD17.1 48.18,21.68 v2(48.51,21.35)
  BOTTOM w0.102: v2(48.51,21.35) 48.53,21.35 48.51,21.38 46.64,21.38 46.14,20.87 JDIMM2.260
DIMM_CHB_SA2: length 3.9
  TOP w0.102: RD18.1 RD15.2 45.55,43.33 v2(46.12,43.9) v1(46.67,43.9)
  BOTTOM w0.102: v2(46.12,43.9) 45.65,44.38 JDIMM2.166
DMIC_CLK: length 5.7
  TOP w0.102: UA1.3 28.79,23.66 29.78,24.66 v1(29.84,24.66) 30.37,24.66 31.13,25.42 L5.2
DMIC_CLK_EDP: length 249.7
  TOP w0.102: v2(31.96,27.45) 31.91,27.45 L5.1 31.12,28.24 CA9.1
  IN1 w0.119: v2(31.96,27.45) 32.66,27.45 33.65,28.44 39.44,28.44 42.51,25.37 43.88,25.37 44.96,24.29 44.96,22.92 46.64,21.24 46.64,19.09 49.15,16.58 60.56,16.58 61.1,17.13 70.05,17.13 71.84,18.91 74.41,18.91 75.86,20.36 78.1,20.36 78.25,20.51 81.22,20.51 81.86,19.86 81.86,18.88 82.26,18.48 85.01,18.48 85.37,18.83 86.23,18.83 86.82,19.42 93.74,19.42 94.37,20.05 95.33,20.05 96.17,20.89 96.17,22.94 96.39,23.15 96.39,23.85 98.1,25.56 103.62,25.56 104.66,24.52 110.67,24.52 111.91,23.29 111.91,23.12 111.92,23.1 111.92,22.91 112.71,22.12 118.55,22.12 119.04,21.63 119.9,21.63 120.57,22.3 127.64,22.3 128.16,22.81 130.25,22.81 132.11,24.67 132.11,25.16 134.4,27.45 134.4,27.77 135.7,29.07 136.52,29.07 136.67,29.22 136.67,29.23 136.76,29.32 136.76,29.77 140.18,33.18 145.04,33.18 145.86,32.36 150.94,32.36 151.42,32.85 155.48,32.85 156.15,32.18 157.6,32.18 158.57,32.18 160.04,30.71 160.04,27.61 160.78,26.87 160.78,26.84 160.78,25.86 161.05,25.59 161.05,24.88 161.4,24.53 161.4,24.3 161.65,24.05 161.89,24.05 162.17,23.77 162.2,23.77 165.21,20.75 167.4,20.75 167.66,20.5 169.17,20.5 170.9,18.77 170.9,15.9 173.03,13.77 173.44,13.36 175.19,13.36 175.8,13.97 185.16,13.97 185.58,13.55 191.52,13.55 191.79,13.82 200.75,13.82 203.02,16.09 208.11,16.09 211.22,19.19 215.78,19.19 217.13,20.54 217.13,24.88 217.82,25.57 217.82,36.54 218.57,37.29 219.42,37.29 v2(219.73,36.98)
  BOTTOM w0.102: v2(219.73,36.98) 219.86,36.98 220.17,36.66 221.7,36.66 222.21,37.17 R56.1 222.9,36.55 JEDP1.28
DMIC_DATA: length 3.8
  TOP w0.102: RA42.2 31.71,24.88 v1(31.03,24.2) 30.85,24.03 29.83,24.03 29.19,23.38 UA1.2
DMIC_DATA_EDP: length 248
  TOP w0.102: v2(31.96,26.82) 31.71,26.57 RA42.1
  IN1 w0.119: v2(31.96,26.82) 33.7,26.82 34.75,27.87 39.3,27.87 42.3,24.87 43.67,24.87 44.46,24.08 44.46,22.71 46.14,21.03 46.14,18.88 48.94,16.08 67.97,16.08 68.51,16.63 70.26,16.63 72.04,18.41 74.62,18.41 76.07,19.86 78.31,19.86 78.46,20.01 81.01,20.01 81.36,19.65 81.36,18.62 82.01,17.98 85.22,17.98 85.57,18.33 86.44,18.33 87.02,18.92 94.91,18.92 96.67,20.69 96.67,22.73 96.89,22.95 96.89,23.65 98.3,25.06 103.41,25.06 104.45,24.02 109.82,24.02 110.28,23.56 110.28,22.98 111.65,21.62 118.34,21.62 118.83,21.13 120.11,21.13 120.78,21.8 127.85,21.8 128.33,22.28 131.43,22.28 133.67,24.51 133.67,25.51 135.72,27.56 135.72,28.21 136.08,28.57 136.73,28.57 137.17,29.02 137.26,29.11 137.26,29.56 139.71,32 142.06,32 142.59,32.53 144.86,32.53 145.55,31.84 149.5,31.84 149.73,31.62 150.9,31.62 151.63,32.35 155.27,32.35 155.94,31.68 157.72,31.68 159.24,30.15 159.24,27.7 160.28,26.66 160.28,25.66 160.55,25.38 160.55,24.67 160.9,24.32 160.9,24.09 161.44,23.55 161.68,23.55 161.96,23.27 161.99,23.27 164.8,20.46 164.8,20.39 164.92,20.27 164.98,20.27 165,20.25 167.2,20.25 167.45,20 168.67,20 170.2,18.47 170.2,15.89 172.94,13.16 173.23,12.86 175.4,12.86 176.01,13.47 184.95,13.47 185.37,13.05 191.72,13.05 191.99,13.32 201.49,13.32 203.64,15.47 204.05,15.47 204.05,15.47 208.24,15.47 211.34,18.56 215.86,18.56 217.7,20.4 217.7,24.53 218.32,25.15 218.32,36.14 218.78,36.59 219.29,36.59 219.55,36.33 v2(219.74,36.33)
  BOTTOM w0.102: v2(219.74,36.33) 219.82,36.33 219.97,36.17 v1(222.47,36.17) 222.6,36.05 JEDP1.29
DP_VSSR: length 12.3
  BOTTOM w0.254: UV1.AM22 102.03,118.72 v2(101.64,119.11) 101.55,119.2 100.93,119.2 100.68,119.45 v1(100.68,119.77) 100.68,120.04 100.96,120.32 UV1.AM24 ; v2(103.74,112.84) 103.74,112.4 UV1.AH14 ; UV1.AG23 104.46,119.59 v2(104.78,119.92) 105.18,119.52 UV1.AF23 ; v2(104.06,111.98) 104.41,112.32 UV1.AG14
  BOTTOM w0.305: v2(101.19,115.46) 101.25,115.52 UV1.AM18 ; UV1.AM16 101.95,113.92 v2(101.5,113.47) 101.44,113.42 101.44,112.73 101.86,112.32 UV1.AM14 ; v2(100.83,117.29) 101.01,117.12 UV1.AM20
  BOTTOM w0.381: v2(105.2,117.86) 105.2,117.37 UV1.AF20 UV1.AF19
DRAM_RST: length 54.5
  TOP w0.102: UV12.J2 144.23,118.05 v2(144.63,117.65) ; UV14.J2 v2(144.63,110.23)
  IN1 w0.119: v2(144.63,117.65) 144.63,116.84 145.31,116.17 149.75,116.17 153.18,112.73 153.18,101.48 149.19,97.49 134.84,97.49 v2(134.39,97.04)
  BOTTOM w0.102: RV36.1 v2(134.39,97.04) ; v2(144.63,110.23) UV14.J2 143.85,110.21 143.85,112.16 v1(143.66,112.35) 143.66,116.1 143.85,116.29 143.85,117.66 UV12.J2 144.23,118.05 v2(144.63,117.65)
DRAM_RST_G: length 26.2
  IN2 w0.127: v2(116.62,108.69) 117.05,108.69 118.22,107.52 118.58,107.52 118.9,107.2 118.9,106.84 119.08,106.66 119.08,106.48 120.88,104.69 120.88,100.65 123.85,97.68 129.69,97.68 v2(131.02,96.35)
  BOTTOM w0.102: UV1.L10 117.05,109.12 v2(116.62,108.69) ; v1(133.49,97.34) RV37.1 RV38.1 CV97.1 131.1,96.43 v2(131.02,96.35)
DRMOS_EN: length 14.8
  TOP w0.102: v2(159.89,83.48) v1(159.89,82.82)
  IN1 w0.254: v2(159.89,83.48) 161.5,81.86 161.5,74.95 160.42,73.87 v2(159.67,73.87)
  BOTTOM w0.254: PU603.12 160.04,73.5 v2(159.67,73.87) ; PR655.2 159.89,83.77 v2(159.89,83.48) 160.09,83.27 PU605.12
E51_TX1: length 2.8
  TOP w0.102: v1(53.8,107.09) v2(53.8,106.46) 53.93,106.33 RW6.2
  BOTTOM w0.102: JWLAN1.36 v2(53.8,106.46)
EC_AGND: length 15.6
  TOP w0.102: v1(151.09,18.67) v2(151.61,19.2)
  TOP w0.508: CE25.2 148.15,18.44 v2(148.15,18.75) 148.15,19.38 CE30.2 ; CE25.2 148.53,17.44 148.58,17.39 RE50.1 ; CE25.2 148.13,18.06 CE21.2 ; RE4.1 CE1.2 151.47,19.2 v2(151.61,19.2)
  BOTTOM w0.203: CE2.2 147.87,15.07 148.36,15.56 UE1.112 148.36,18.55 v2(148.15,18.75)
  BOTTOM w0.508: v2(148.15,18.75) 148.15,19.3 148.66,19.8 151,19.8 v2(151.61,19.2) ; RE6.1 CE2.2
EC_MUTE#: length 140.6
  TOP w0.102: v2(146.01,15.92) 146.27,15.66 RE28.1 146.27,14.89 v1(146.87,14.29) 146.98,14.18 RE24.1 ; RA8.2 32.51,24.15 31.94,24.15 31.39,23.6 v2(31.39,23.33) 31.06,23 31.06,22.05 30.78,21.76 UA1.47
  IN2 w0.127: v2(146.01,15.92) 146.01,15.46 144.26,13.7 141,13.7 140.59,13.29 137.09,13.29 128.26,4.46 125.62,4.46 124.92,5.16 122.26,5.16 121.24,4.15 118.45,4.15 118.22,3.92 111.52,3.92 110.05,2.45 62.63,2.45 58.85,6.23 51.6,6.23 49.68,8.15 43.58,8.15 37.36,14.38 37.36,20.41 34.63,23.14 31.58,23.14 v2(31.39,23.33)
EC_MUTE#_R: length 2.7
  TOP w0.102: RE28.2 145.43,15.29 v2(145.43,15.92) 145.27,16.08 v1(144.76,16.08)
  BOTTOM w0.102: UE1.119 145.56,16.05 v2(145.43,15.92)
EC_SPI_CLK: length 2.6
  BOTTOM w0.102: UE1.32 139.72,31.18 139.72,31.18 139.32,31.18 139.32,31.18 139.21,31.18 139.11,31.29 138.83,31.29 138.73,31.39 138.73,31.62 138.63,31.72 RE33.2
EC_SPI_CS0#: length 5.9
  BOTTOM w0.102: RE38.1 136.94,27.05 136.56,27.42 136.56,27.7 v1(136.67,27.8) 138.85,27.8 139.21,28.15 139.21,28.98 139.41,29.18 UE1.27
EC_SPI_MISO: length 2.6
  BOTTOM w0.102: RE35.2 138.41,29.19 138.41,29.64 138.64,29.86 139.15,29.86 139.27,29.98 UE1.29
EC_SPI_MOSI: length 2.8
  BOTTOM w0.102: UE1.28 139.45,29.58 138.98,29.11 138.98,28.38 138.85,28.26 RE34.2
EC_WAKE#: length 62.7
  IN2 w0.127: v2(144.27,30.58) 144.27,30.55 142.92,29.2 142.48,29.2 142.23,29.45 139.05,29.45 132.65,23.05 127.89,23.05 126.55,21.71 121.74,21.71 119.05,19.01 114.51,19.01 113.68,18.18 113.68,17.75 112.37,16.43 104.54,16.43 104.13,16.43 101.51,13.82 100.75,13.82 100.75,13.81 96.9,13.81 v2(95.95,14.76)
  BOTTOM w0.102: v2(144.27,30.58) 144.27,31 143.52,31.75 142.91,31.75 142.76,31.91 UE1.35 ; v2(95.95,14.76) 96.18,14.52 v1(96.18,12.67) 96.18,12.59 95.8,12.21 RC100.1
EDP_AUX: length 2.6
  BOTTOM w0.102: C11.2 222.01,43.54 222.36,43.54 222.38,43.56 222.94,43.56 222.97,43.54 223.18,43.54 223.19,43.55 223.91,43.55 223.91,43.55 JEDP1.14
EDP_AUX#: length 2.7
  BOTTOM w0.102: C10.2 221.96,43.33 v4(222.66,43.33) 223.09,43.33 223.37,43.05 223.91,43.05 223.91,43.05 JEDP1.15
EDP_AUX_DN: length 161
  IN3 w0.142: v2(220.05,43.17) 220.07,43.17 220.41,43.5 220.66,43.5 220.88,43.28 220.88,42.07 221.32,41.64 221.32,23.51 216.55,18.75 198.35,18.75 194.84,22.26 194.84,23.94 192.28,26.5 189.66,26.5 186.95,23.78 180.74,23.78 180.11,23.16 177.56,23.16 175.01,20.6 164.26,20.6 162.83,22.03 162.83,22.8 161.02,24.61 161.02,25.99 159.26,27.74 159.26,28.9 156.78,31.38 156.78,36.57 155.94,37.42 154.44,37.42 152.58,37.42 151.53,38.47 151.53,44.36 149.66,46.23 140.56,46.23 138.83,44.51 138.83,42.92 137.97,42.06 133.15,42.06 131.77,43.44 130.02,43.44 130.02,43.43 129.59,43.43 124.53,48.49 124.53,51.59 122.96,53.16 121.66,53.16 121.4,53.42 121.21,53.42 v2(121,53.64)
  BOTTOM w0.102: v2(220.05,43.17) 220.24,43.36 220.48,43.36 220.73,43.1 C10.1 ; v2(121,53.64) 121.22,53.86 121.22,54.41 121.12,54.52 120.85,54.52 120.75,54.41 UC1.E45
EDP_AUX_DP: length 161.1
  IN3 w0.142: v2(220.05,43.75) 220.77,43.75 221.13,43.38 221.13,42.18 221.57,41.74 221.57,23.41 216.66,18.5 198.25,18.5 194.59,22.16 194.59,23.84 192.18,26.25 189.77,26.25 187.06,23.53 180.84,23.53 180.21,22.91 177.67,22.91 175.11,20.35 164.15,20.35 162.58,21.93 162.58,22.69 160.77,24.51 160.77,25.88 159.01,27.64 159.01,28.8 156.53,31.28 156.53,36.47 155.83,37.17 154.33,37.17 152.48,37.17 151.28,38.36 151.28,44.25 149.56,45.98 140.66,45.98 139.08,44.4 139.08,42.81 138.07,41.8 133.05,41.8 131.67,43.18 130.13,43.18 129.49,43.18 124.28,48.39 124.28,51.49 122.85,52.91 121.55,52.91 121.29,53.17 120.84,53.17 v2(120.39,53.62)
  BOTTOM w0.102: C11.1 220.73,43.84 220.45,43.56 220.24,43.56 v2(220.05,43.75) ; UC1.F45 120.1,53.91 v2(120.39,53.62)
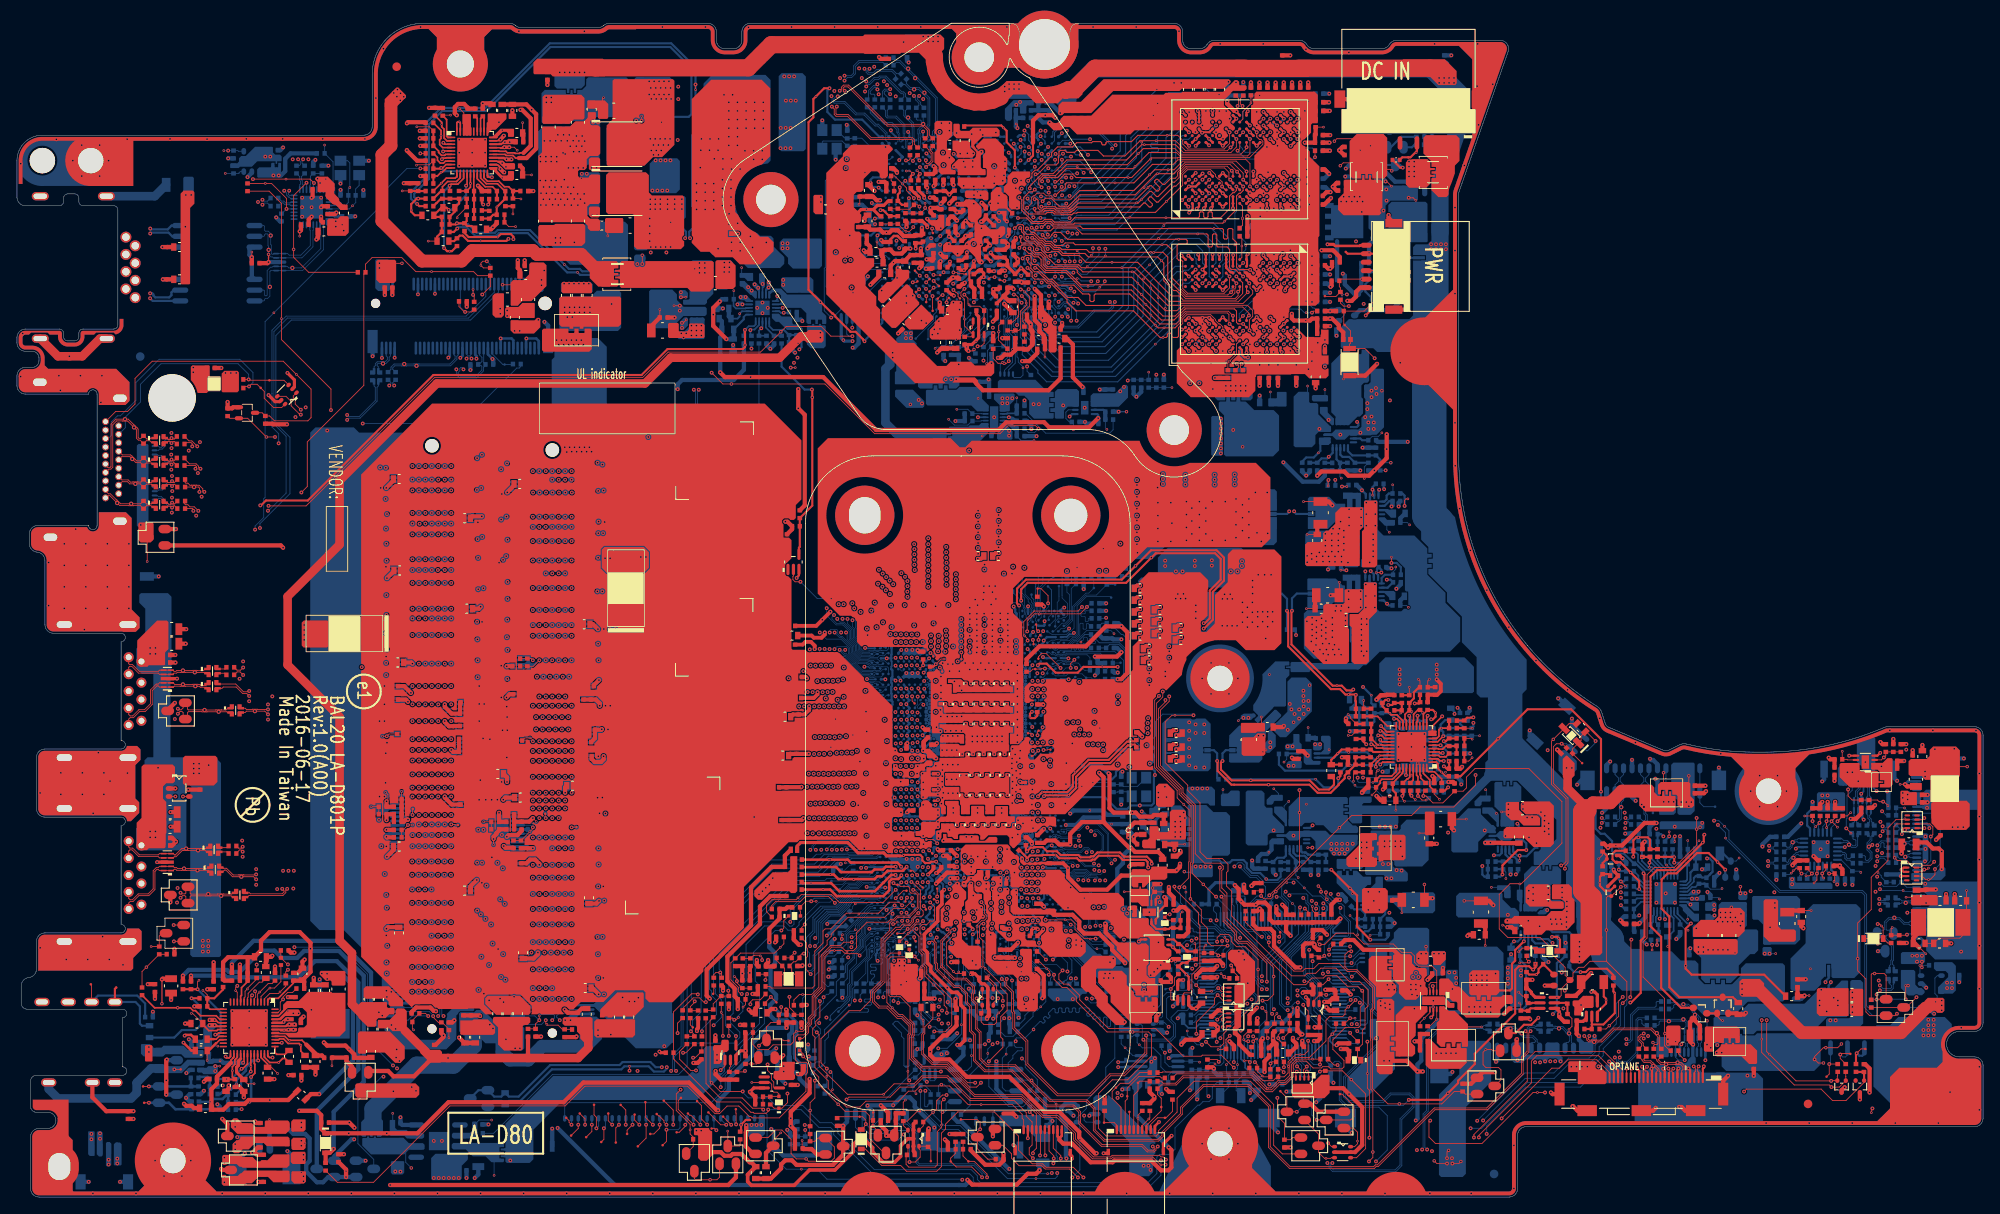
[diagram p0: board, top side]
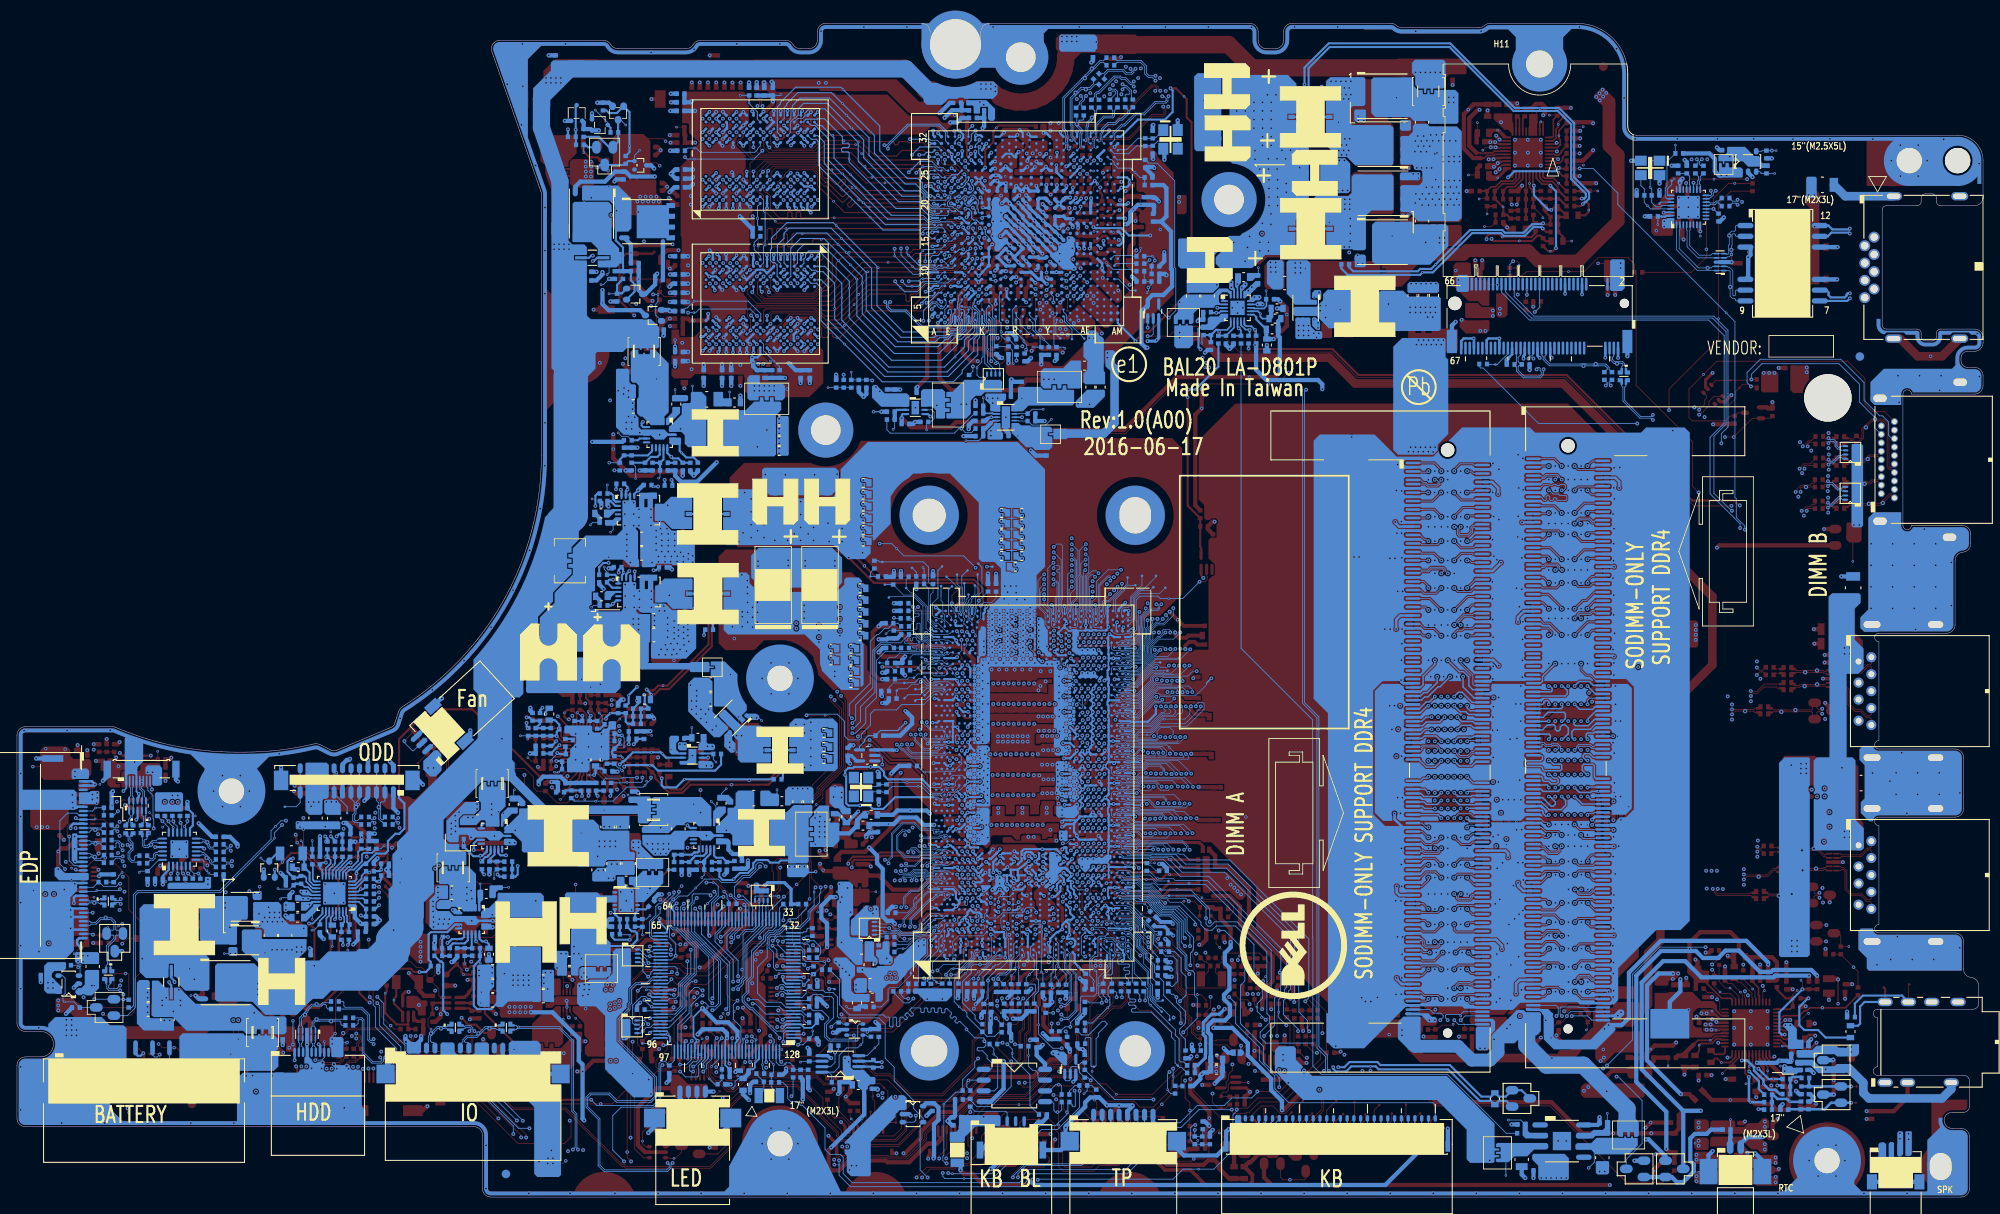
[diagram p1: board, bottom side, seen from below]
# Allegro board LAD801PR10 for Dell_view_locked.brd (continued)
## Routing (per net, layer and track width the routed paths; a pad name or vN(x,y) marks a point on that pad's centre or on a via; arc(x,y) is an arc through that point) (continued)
EDP_BKLT_CTRL: length 9.5
  TOP w0.102: R9.2 218.71,26.27 218.81,26.38 v3(219.11,26.38) 220.24,26.38 220.47,26.15 D3.2 219.49,23.34 219.46,23.31 v2(219.35,23.31)
  BOTTOM w0.102: v2(219.35,23.31) 218.75,23.31 R9.2
EDP_COMP: length 3.4
  TOP w0.254: RC4.2 120.35,56.8 120.06,56.51 119.6,56.51 v1(119.48,56.63) 119.48,57.03 v2(119.72,57.26)
  BOTTOM w0.254: v2(119.72,57.26) 120.3,57.26 UC1.E52
EDP_HPD: length 141.3
  TOP w0.102: v2(226.23,38.7) 226.23,38.04 225.65,37.46 v1(225.47,37.46) 225.13,37.46 224.71,37.87 RP1.6
  IN2 w0.127: v2(226.23,38.7) 225.79,39.13 224.67,39.13 221.62,42.18 219.52,42.18 219.03,42.67 219.03,44.6 218.59,45.05 209.82,45.05 207.98,43.2 200.74,43.2 198.01,45.93 193.6,45.93 191.27,48.26 186.87,48.26 185.95,49.17 181.69,49.17 180.23,50.63 176.34,50.63 172.39,46.68 163.12,46.68 160.32,43.89 160.32,43.28 160.4,43.2 160.4,40.11 159.04,38.76 156.1,38.76 155.79,39.08 151.51,39.08 151.07,39.52 147.07,39.52 146.28,38.73 144.76,38.73 144.61,38.59 142.44,38.59 141.92,38.07 134.62,38.07 132.22,35.67 126.35,35.67 125.3,34.62 123.62,34.62 123,34 123,33.57 121.45,32.03 118.53,32.03 v2(117.99,32.57)
  BOTTOM w0.089: UC1.L10 117.5,33.62 117.81,33.31 117.81,32.85 117.99,32.67 v2(117.99,32.57)
  BOTTOM w0.102: JEDP1.11 223.91,45.05 223.91,45.05 224.59,45.05 224.84,45.3 225.95,45.3 226.84,44.41 226.84,39.31 v2(226.23,38.7)
EDP_TX0: length 2.7
  BOTTOM w0.102: JEDP1.18 223.91,41.55 223.91,41.55 223.3,41.55 223.16,41.7 v4(222.64,41.7) 222.09,41.7 221.65,41.26 C7.2
EDP_TX0#: length 2.6
  BOTTOM w0.102: JEDP1.17 223.3,42.05 223.16,41.91 222.94,41.91 222.92,41.93 222.36,41.93 222.34,41.91 221.87,41.91 C6.2
EDP_TX0_DN: length 155.8
  IN3 w0.142: v2(219.43,41.5) 220.35,41.5 220.75,41.1 220.75,23.74 216.33,19.32 200.2,19.32 192.46,27.06 189.49,27.06 187.13,24.7 183.53,24.7 183.33,24.9 181.11,24.9 179.89,23.68 176.85,23.68 174.29,21.13 167.63,21.13 167.14,21.62 164.75,21.62 162.95,23.42 162.95,25.29 159.79,28.46 159.79,29.16 157.3,31.65 157.3,36.79 156.15,37.94 154.65,37.94 152.06,40.54 152.06,44.58 149.88,46.75 137.56,46.75 134.51,43.71 132.24,43.71 131.99,43.96 129.81,43.96 125.05,48.71 125.05,51.96 123.8,53.21 123.8,54.63 124.59,55.42 v2(124.59,56.03)
  BOTTOM w0.076: v2(124.59,56.03) 124.59,55.74 124.08,55.23 122.43,55.23 UC1.C47
  BOTTOM w0.102: v2(219.43,41.5) 219.43,41.58 219.87,42.03 220.63,42.03 C6.1
EDP_TX0_DP: length 155.7
  IN3 w0.142: v2(219.43,40.91) 219.45,40.91 219.78,41.24 220.25,41.24 220.49,41 220.49,23.84 216.23,19.57 200.3,19.57 192.57,27.31 189.38,27.31 187.02,24.95 183.64,24.95 183.44,25.15 181.01,25.15 179.79,23.93 176.74,23.93 174.19,21.38 167.74,21.38 167.24,21.87 164.85,21.87 163.2,23.53 163.2,25.4 160.04,28.56 160.04,29.27 157.55,31.75 157.55,36.9 156.26,38.19 154.76,38.19 152.31,40.64 152.31,44.68 149.98,47.01 137.46,47.01 134.41,43.96 132.35,43.96 132.1,44.21 129.91,44.21 125.31,48.81 125.31,52.06 124.05,53.31 124.05,54.53 124.84,55.31 124.84,55.68 125.17,56.01 v2(125.17,56.03)
  BOTTOM w0.076: v2(125.17,56.03) 125.11,56.03 124.14,55.07 122.64,55.07 UC1.C46
  BOTTOM w0.102: v2(219.43,40.91) 219.43,40.92 219.84,41.33 219.84,41.7 219.96,41.82 220.12,41.82 220.22,41.72 220.22,41.31 220.3,41.24 C7.1
EDP_TX1: length 2.8
  BOTTOM w0.102: C9.2 221.9,39.71 222.62,39.71 223.06,40.15 223.2,40.15 223.31,40.05 JEDP1.21
EDP_TX1#: length 2.9
  BOTTOM w0.102: C8.2 222.08,39.92 222.5,39.92 v4(222.72,40.14) 222.96,40.38 223.13,40.38 223.3,40.55 223.91,40.55 223.91,40.55 JEDP1.20
EDP_TX1_DN: length 149.2
  IN3 w0.142: v2(125.3,54.59) 125.13,54.41 125.13,53.78 126.12,52.8 126.12,49.1 130.23,44.98 132.42,44.98 132.55,44.85 134.09,44.85 137.02,47.78 150.31,47.78 153.62,44.47 153.62,41.24 154.96,39.9 155.78,39.9 157.08,38.61 158.64,37.05 158.64,33.21 161.94,29.9 161.94,28.38 163.97,26.35 163.97,23.85 165.14,22.68 169.46,22.68 170.22,23.45 175.05,23.45 176.51,24.91 179.2,24.91 180.22,25.93 183.76,25.93 183.96,25.73 186.7,25.73 189.06,28.09 192.89,28.09 200.62,20.35 215.87,20.35 218.51,22.99 218.51,37.93 218.14,38.3 218.14,39.64 218.71,40.21 v2(219.42,40.21)
  BOTTOM w0.076: v2(125.3,54.59) 125.04,54.32 125.04,54.26 124.71,53.93 123.33,53.93 123.24,53.98 123.21,53.99 123.13,53.99 122.93,53.93 122.74,53.93 122.36,54.06 122.19,54.06 122,54.12 121.91,54.21 121.85,54.49 UC1.D46
  BOTTOM w0.102: C8.1 220.57,40.19 219.44,40.19 v2(219.42,40.21)
EDP_TX1_DP: length 149.3
  IN3 w0.142: v2(124.72,54.59) 124.88,54.43 124.88,53.68 125.86,52.69 125.86,49 130.13,44.73 132.31,44.73 132.45,44.6 134.2,44.6 137.13,47.53 150.21,47.53 153.37,44.37 153.37,41.13 154.86,39.65 155.68,39.65 158.39,36.94 158.39,33.1 161.69,29.8 161.69,28.28 163.72,26.24 163.72,23.74 165.03,22.43 169.57,22.43 170.33,23.2 175.15,23.2 176.62,24.66 179.31,24.66 180.32,25.67 183.65,25.67 183.85,25.48 186.81,25.48 189.16,27.83 192.78,27.83 200.52,20.1 215.98,20.1 218.77,22.89 218.77,38.03 218.39,38.4 218.39,39.54 218.81,39.96 219.07,39.96 219.4,39.62 v2(219.42,39.62)
  BOTTOM w0.076: UC1.C45 122.17,54.57 122.24,54.64 122.4,54.64 122.47,54.56 122.47,54.26 122.57,54.17 122.63,54.14 122.77,54.09 122.91,54.09 123.1,54.15 123.25,54.15 123.37,54.09 124.64,54.09 124.87,54.32 124.87,54.43 v2(124.72,54.59)
  BOTTOM w0.102: v2(219.42,39.62) 219.78,39.98 220.21,39.98 C9.1
EDP_VDD_EN: length 139.7
  IN2 w0.127: v2(200.62,43.91) 200.62,43.91 200.62,44.69 200.41,44.89 199.77,44.89 198.73,45.93 198.73,45.97 195.98,48.72 194.92,48.72 193.31,50.33 187.81,50.33 186.46,51.68 182.5,51.68 181.96,51.14 176.13,51.14 172.67,47.67 168.48,47.67 168.06,48.09 163.13,48.09 162.59,47.55 162.59,46.88 159.81,44.1 159.81,43.06 159.89,42.99 159.89,40.32 158.83,39.27 156.31,39.27 156,39.58 151.72,39.58 151.28,40.02 146.83,40.02 146.07,39.26 145.1,39.26 144.46,39.9 140.8,39.9 140.69,40 133.56,40 130.5,36.94 125.29,36.94 124.46,36.12 123.32,36.12 122.15,34.95 120.84,34.95 120.71,34.82 118.32,34.82 117.74,34.24 116.8,34.24 116.23,34.81 v2(116.14,34.81)
  BOTTOM w0.102: D4.2 218.88,21.41 217.94,22.35 217.94,35.6 217.58,35.95 207.87,35.95 201.52,42.3 v1(201.52,42.36) 201.52,42.99 200.62,43.9 200.62,43.91 v2(200.62,43.91) ; UC1.U13 114.79,35.46 115.97,35.46 116.14,35.29 v2(116.14,34.81)
EDRAM_OPIO_RCOMP: length 10.4
  TOP w0.102: v2(119.16,66.75) 119.16,67.98 120,68.82 v1(120.59,68.82) 125.39,68.82 v2(126.2,69.63)
  BOTTOM w0.076: RC121.1 126.64,70.06 v2(126.2,69.63) ; v2(119.16,66.75) 118.87,66.46 UC1.H66
EMMC_RCOMP: length 4.9
  BOTTOM w0.102: UC1.AT1 104.72,28.74 105.37,28.09 105.37,26.12 104.91,25.66 v1(104.91,25.43) 104.91,24.66 RC8.1
EN_0.6VSP: length 3
  BOTTOM w0.203: PR202.2 PC203.1 88.33,102.6 PU200.7
EN_1.0V_VCCST_ON: length 6.1
  TOP w0.102: v1(137.45,33.65) 137.24,33.44 RZ9.1
  TOP w0.254: UZ1.3 133.81,32.21 134.39,31.63 DZ5.2 135.88,31.63 136.02,31.77 RZ1.2 136.44,31.72 137.21,31.72 CZ1.1 RZ9.1
EN_1.2V: length 2.8
  BOTTOM w0.203: PU200.8 87.93,102.66 v2(87.79,102.51) 87.52,102.25 PR201.2 PC202.1
EN_1.8VALW: length 4.4
  BOTTOM w0.102: PR501.2 160.73,30.96 159.68,30.96 v1(159.6,30.87)
  BOTTOM w0.254: PR501.2 PR502.2 PC502.1 161.39,33.39 PU500.5
EN_2.5V: length 2.2
  BOTTOM w0.102: PC805.1 54.51,9.09 v1(55.99,9.09)
EN_3V: length 2
  BOTTOM w0.254: PU100.12 176.02,40.56 176.45,40.12 176.64,40.12 177.06,39.71 PR121.1
EN_5V: length 3.4
  BOTTOM w0.254: PR120.1 180.87,29.55 180.48,29.93 179.09,29.93 178.71,30.31 PU102.12
EN_+1.35VGPU: length 6.2
  BOTTOM w0.102: v3(162.05,86.65) PR1403.2
  BOTTOM w0.254: PR1403.2 160.8,87.01 PC1404.1 PR1404.1 157.5,87.51 156.99,88.02 PU1400.11
EN_+1VALW: length 4.3
  BOTTOM w0.254: PR301.2 PC304.1 PR302.1 152.29,40.4 152.26,40.42 152.26,40.42 152.03,40.65 151.93,40.65 151.91,40.66 151.59,40.66 151.47,40.79 PU300.11
ENABLE_VGA: length 2.8
  TOP w0.203: PR1116.2 49.6,122.67 49.6,122.34 49.94,122.01 50.31,122.01 50.54,122.24 PU1100.8
ENLDO_3V5V: length 25.6
  TOP w0.102: v2(177.25,40.28) v1(177.25,39.71)
  IN1 w0.254: v2(177.25,40.28) 182.49,40.28 183.79,38.98 183.79,31.55 182.87,30.63 182.52,30.63 181.88,29.99 v2(181.12,29.99)
  BOTTOM w0.254: PU100.11 176.47,40.81 176.99,40.28 v2(177.25,40.28) 177.31,40.22 178.06,40.22 PR102.1 PR103.1 ; PU102.11 179.16,30.69 179.42,30.44 180.61,30.44 181.06,29.99 v2(181.12,29.99)
EOPIO_RCOMP: length 12
  TOP w0.102: v2(119.21,65.67) 119.21,65.87 v1(118.85,66.22) 118.75,66.33 118.75,67.9 120,69.15 125.14,69.15 v2(125.62,69.63)
  BOTTOM w0.076: v2(119.21,65.67) 118.87,65.33 UC1.H65 ; RC122.1 126.14,69.18 125.69,69.63 v2(125.62,69.63)
FAN1_PWM: length 76.2
  TOP w0.102: v2(182.58,38.75) 182.58,39.07 182.94,39.42 182.94,47.09 181.22,48.81 181.22,53.14 181.57,53.49 v2(182.2,53.49) 182.28,53.49 R50.1 ; ZT14.1 148.99,30.82 v2(148.88,30.71)
  IN2 w0.127: v2(148.88,30.71) 148.88,30.71 149.44,31.27 150.83,31.27 151.82,30.28 156.7,30.28 157.66,31.23 159.9,31.23 160.29,30.84 160.29,28.47 162.07,26.69 163.72,26.69 164.17,27.13 165.72,27.13 169.23,23.62 175.83,23.62 176.98,24.77 176.98,26.93 177.57,27.52 177.57,28.09 178.2,28.72 181.24,28.72 182.05,29.53 182.05,30.3 182.61,30.86 183.13,30.86 184.17,31.9 184.17,36.89 182.58,38.48 v2(182.58,38.75)
  BOTTOM w0.102: UE1.47 147.56,31.83 148.68,30.71 148.87,30.71 v2(148.88,30.71) ; JFAN1.2 182.76,53.49 v2(182.2,53.49)
FAN1_TACH: length 84
  TOP w0.102: CE28.1 RE13.1 144.91,32.42 146.62,30.71 v2(146.85,30.71) ; v2(182.14,39.13) 182.27,39.13 182.71,39.58 182.71,47 180.99,48.71 180.99,53.79 v3(181.21,54.01) D8.2 183.09,55.89 R55.2
  IN2 w0.127: v2(146.85,30.71) 146.85,30.84 148.22,32.22 151.44,32.22 153.13,30.53 156.59,30.53 157.55,31.49 160,31.49 160.55,30.94 160.55,28.57 162.18,26.94 163.62,26.94 164.06,27.39 165.82,27.39 169.33,23.87 175.71,23.87 176.73,24.9 176.73,27.04 177.31,27.62 177.31,28.19 178.1,28.97 181.13,28.97 181.8,29.63 181.8,30.4 182.51,31.11 183.02,31.11 183.92,32.01 183.92,36.78 182.14,38.56 v2(182.14,39.13)
  BOTTOM w0.102: UE1.40 144.76,31.94 145.12,31.58 145.97,31.58 v2(146.85,30.71)
FB_1.2V: length 6.2
  BOTTOM w0.102: v1(92.13,100.74) 92.13,101.53 PR207.1
  BOTTOM w0.203: 90.19,102.32 89.17,102.32 88.73,102.76 PU200.6
  BOTTOM w0.254: 90.19,102.32 90.46,102.32 PC214.1 ; PC214.1 91.08,101.72 PR207.1 ; PC214.1 91.08,101.71 PR204.1
FB_1.8VALW: length 4.7
  BOTTOM w0.102: v1(157.23,33.22) 157.65,32.8 PR504.1
  BOTTOM w0.254: PR504.1 158.15,32.79 PC503.2 159.01,33.45 158.69,33.77 PU500.6 157.73,33.95 PR505.1
FB_+1.35VGPU: length 4.7
  BOTTOM w0.102: PC1409.2 156.05,84.98 v1(156.2,84.83)
  BOTTOM w0.254: PU1400.14 155.64,87.05 PR1410.1 ; PR1410.1 156.91,86.64 PR1411.1 ; PR1410.1 PC1409.2
FB_+1VALW: length 4.7
  BOTTOM w0.102: v1(151.12,37.7) 150.84,37.98 PC309.2
  BOTTOM w0.254: PR309.1 150.86,39.53 PR310.1 ; PR309.1 PC309.2 ; PR309.1 150.84,39.76 150.12,40.49 PU300.14
FB_GND: length 2.4
  TOP w0.381: v2(106.38,117.83) 106.38,118.01 105.9,118.5 105.84,118.5 105.43,118.91 RV158.1
  BOTTOM w0.305: v2(106.38,117.83) 106.38,117.8 UV1.AD20
FB_IA: length 6.5
  TOP w0.102: PR650.1 165.49,60.9 v1(165.3,61.09)
  TOP w0.203: PU602.17 163.88,56.25 163.72,56.41 163.72,56.95 164.2,57.43 PR648.2
  TOP w0.254: PR648.2 164.24,58.29 PR645.2 164.76,58.84 164.76,59.55 165.37,60.16 PR650.1
FB_VDDC: length 2.3
  TOP w0.381: RV159.1 106.33,118.8 107.01,118.12 v2(107.01,117.9)
  BOTTOM w0.305: UV1.AC20 107.56,117.32 107.01,117.87 v2(107.01,117.9)
FB_VDDCI: length 2
  BOTTOM w0.102: TP67.1 110.29,102.14 110.45,102.3 110.45,102.37 110.86,102.78 UV1.W1
FB_VSA: length 4.3
  TOP w0.203: PU602.25 161.09,53.32 161.05,53.36 v1(160.7,53.36) 160.48,53.36 159.78,54.06 PR649.1
  TOP w0.254: PR652.1 PR646.1 159.73,54.07 PR649.1
FCCM_GT: length 34.1
  TOP w0.102: v1(164.06,82.38) 163.86,82.38 163.67,82.2 v2(163.67,81.55)
  TOP w0.203: PU602.11 166.28,56.68 166.39,56.79 v2(166.39,56.79)
  IN3 w0.254: v2(163.67,81.55) 163.67,78.97 162.6,77.9 162.6,73.1 169.69,66.02 169.69,59.96 167.34,57.61 166.64,57.61 166.39,57.36 v2(166.39,56.79)
  BOTTOM w0.254: PR671.2 163.42,83.02 163.67,82.76 v2(163.67,81.55)
FCCM_IA: length 32.7
  TOP w0.102: v2(162.12,74.83) v1(162.12,75.51)
  TOP w0.203: PU602.21 161.55,54.92 v2(160.89,55.58)
  IN3 w0.254: v2(160.89,55.58) 162.67,57.36 165.31,57.36 165.95,57.99 167.18,57.99 169.31,60.13 169.31,65.86 161.64,73.53 161.64,74.39 162.07,74.83 v2(162.12,74.83)
  BOTTOM w0.254: PR659.2 163.23,74.33 162.73,74.83 v2(162.12,74.83)
FCCM_VSA: length 15.7
  TOP w0.203: v2(160.28,50.77) 160.28,51.16 160.82,51.7 161.16,51.7 161.18,51.72 PU602.29
  BOTTOM w0.254: v2(160.28,50.77) 160.08,50.97 157.29,50.97 v1(157.27,50.95) 156.93,50.95 156.3,50.32 149.56,50.32 148.85,51.02 PR679.2
FW_UPDATE: length 217.1
  TOP w0.102: v2(215.98,48.09) 215.98,47.33 216.46,46.85 RX13.2 RX10.2 219.45,46.85 219.65,46.65 v2(220.12,46.65) 220.21,46.65 v1(220.68,46.18) ; DX3.2 105.24,27.96 104.86,28.34 103.09,28.34 102.84,28.09 102.84,23.81 103,23.65 104.16,23.65 105.34,22.47 105.34,20.94 105.83,20.45 105.83,19.05 105.7,18.92 105.7,16.55 106.82,15.43 109.63,15.43 112.99,12.08 118.56,12.08 121.03,9.61 122.76,9.61 124.86,7.51 124.86,6.83 126.96,4.74 129,4.74 129.18,4.92 134.77,4.92 134.94,4.74 135.19,4.74 v2(135.52,4.41)
  IN1 w0.119: v2(220.12,46.65) 220.13,46.65 220.82,45.97 220.82,18.87 218.71,16.77 218.71,14.68 213.81,9.77 176.98,9.77 173.47,6.27 161.6,6.27 159.88,7.99 154.71,7.99 149.45,2.73 137.2,2.73 v2(135.52,4.41)
  IN3 w0.142: v2(135.52,4.41) 138.58,7.48 138.58,11.8 140.02,13.25 140.02,15.56 141.94,17.48 v2(141.94,18.75)
  BOTTOM w0.102: v2(215.98,48.09) 215.98,48.28 216.2,48.5 J3D1.8 ; v2(141.94,18.75) 141.94,18.87 142.42,19.35 145.18,22.11 145.43,22.11 146.36,23.04 146.36,23.68 145.81,24.22 145.81,25.5 145.25,26.06 145.25,29.03 143.86,30.42 143.86,30.82 143.22,31.46 142.78,31.46 142.36,31.88 UE1.34
FW_UPDATE_PCH: length 5
  TOP w0.102: v1(106.33,27.95) v2(105.9,28.38) 105.24,29.04 DX3.1
  BOTTOM w0.076: UC1.AP5 106.32,30.79 106.32,28.6 106.1,28.38 v2(105.9,28.38)
GPIO19_CTF: length 7.5
  BOTTOM w0.102: UV1.M2 116.41,103.87 116.41,101.75 116.63,101.54 116.63,100.64 RV151.2 116.37,100.37 RV152.1 114.49,99.91 114.49,98.46 v1(114.37,98.34)
GPIO28: length 6.5
  BOTTOM w0.102: UV1.R5 114.45,104.73 114.45,102.43 113.13,101.11 v1(113.13,100.94) 113.13,100.87 112.8,100.54 112.8,99.79 RV21.2
GPP_B23: length 14.7
  TOP w0.102: v2(109.68,21.73) 109.68,22.31 109.37,22.63 109.37,23.79 v1(108.13,25.03) 107.08,26.08 107.08,27.05 106.76,27.36 106.76,28.59 106.4,28.96 106.4,30.76 105.68,31.48 105.68,31.8 106.09,32.21 106.51,32.21 v2(106.88,32.57)
  BOTTOM w0.076: v2(106.88,32.57) 106.88,32.45 UC1.AM7
  BOTTOM w0.102: RC39.1 v2(109.68,21.73)
GPP_C5: length 4
  BOTTOM w0.076: UC1.W1 113.33,28.44 114.13,27.64 114.13,26.62 v1(114.64,26.12) RC38.1
GPU_PWR_LEVEL: length 104.9
  TOP w0.102: v2(134.7,59.14) 134.19,58.63 134.19,50.63 136.85,47.98 136.85,47.1 v1(137.63,46.32) 138.26,45.69 138.26,39.58 138.21,39.53 138.21,37.65 v2(137.1,36.54)
  IN1 w0.119: v2(134.7,59.14) 134.71,59.15 134.71,65.24 135.31,65.84 135.31,73.1 133.54,74.87 133.54,85.03 128.18,90.38 123.15,90.38 121.3,92.23 121.3,95.34 119.14,97.5 v2(119.14,98)
  IN3 w0.142: v2(114.05,107.92) 114.42,107.55 114.42,106.28 116.41,104.29 118.13,104.29 118.64,103.78 118.64,99.59 119.14,99.08 v2(119.14,98)
  BOTTOM w0.102: UE1.21 141.28,26.78 141.3,26.76 141.88,26.76 141.89,26.77 142.34,26.77 142.66,27.1 142.66,28.88 143.19,29.41 143.19,29.83 143.17,29.85 143.17,30.53 142.93,30.77 142.5,30.77 142.22,31.05 141.9,31.05 141.29,31.66 139.52,31.66 138.36,32.82 138.36,33.61 137.24,34.73 137.24,35.77 137.1,35.92 v2(137.1,36.54) ; UV1.T9 113.65,108.32 v2(114.05,107.92) ; RV260.1 119.14,97.45 v2(119.14,98)
GT1N: length 54.4
  IN1 w0.254: v2(169.92,57.73) 169.92,57.73 169.88,57.73 169.44,58.17 169.44,66.57 165.17,70.84 165.17,86.58 164.45,87.31 156.01,87.31 155.09,86.38 150.74,86.38 150.16,85.81 150.16,81.02 v2(150.06,80.92)
  BOTTOM w0.254: PR673.1 170.2,57.45 169.92,57.73 v2(169.92,57.73) ; v2(150.06,80.92) 150.06,80.86 149.8,80.61 PL605.2
GT1P: length 54.1
  IN1 w0.254: v2(150.64,80.92) 150.58,80.98 150.58,85.69 150.89,86 155.35,86 156.27,86.92 164.19,86.92 164.73,86.39 164.73,70.65 169.06,66.31 169.06,57.61 169.57,57.1 v2(169.57,57.01)
  BOTTOM w0.254: v2(169.57,57.01) 169.57,57.24 PR674.2 ; v2(150.64,80.92) 150.64,80.86 150.9,80.61 PL605.3
GT_SNUB1: length 2.6
  TOP w0.102: v1(152.18,78.19) PC678.1
  TOP w0.508: PR676.2 153.37,79.02 PC678.1
GT_SW1: length 3.6
  TOP w0.102: v1(151.75,82.07) PR676.1
  TOP w0.508: v2(155.15,81.62) 154.7,82.07 PR676.1
H_CATERR#: length 6
  BOTTOM w0.076: UC1.D63 121.78,64.27 122.06,63.99 122.35,63.99 122.56,63.9 122.74,63.84 123.02,63.84 123.12,63.87 123.27,63.87 123.28,63.85 123.69,63.85 123.83,63.99 126.22,63.99 126.56,63.65 RC111.2
H_CPU_SVIDALRT#: length 13.3
  BOTTOM w0.076: UC1.B63 123.08,64.53 124.35,64.53 124.42,64.6 124.42,64.97 124.5,65.04 124.61,65.04 124.68,64.97 124.68,64.6 124.76,64.53 124.87,64.53 124.95,64.6 124.95,65.25 125.02,65.33 125.13,65.33 125.2,65.25 125.2,64.6 125.28,64.53 125.42,64.53 125.5,64.6 v1(125.5,65.49) 125.5,65.58 125.57,65.66 125.69,65.66 125.77,65.73 125.77,65.94 125.89,66.06 126.16,66.06 126.27,65.94 126.27,65.7 126.35,65.62 126.46,65.62 126.53,65.7 126.53,65.9 126.61,65.97 126.76,65.97 126.84,65.9 126.84,65.7 126.92,65.62 127.13,65.62 127.21,65.55 127.21,65.4 127.13,65.32 125.78,65.32 125.71,65.24 125.71,65.11 125.78,65.03 126.21,65.03 126.26,64.97 126.26,64.87 126.19,64.79 125.81,64.79 125.74,64.72 125.74,64.61 125.82,64.53 126.42,64.53 RC153.1
H_CPUPWRGD: length 7.6
  BOTTOM w0.076: 124.91,73.01 CC15.1 124.35,71.79 124.35,68.16 123.59,67.4 UC1.A68
  BOTTOM w0.102: v1(125.04,74.29) 124.91,74.16 RC95.2 124.91,73.01
H_CPUPWRGD_R: length 1.2
  BOTTOM w0.102: RC95.1 125.82,73.74 TP7.1
H_DRAMRST#: length 144.8
  TOP w0.102: RD7.2 60.2,63.54 RD8.2 60.65,63.54 v2(60.85,63.34)
  IN1 w0.119: v2(60.85,63.34) 60.84,63.36 55.5,63.36 54.67,62.53 v2(40.67,62.53)
  IN3 w0.142: v2(104.31,35.27) 104,34.95 104,34.25 104.23,34.02 105.02,34.02 105.45,33.59 105.45,32.43 105.11,32.09 104.95,32.09 103.59,30.73 103.59,29.68 102.7,28.79 102.7,27.71 100.57,25.58 99.68,25.58 98.57,24.47 98.57,23.55 98.4,23.38 98.4,23.28 98.01,22.88 96.11,22.88 95.05,21.82 95.05,18.87 94.7,18.52 86.19,18.52 85.59,17.92 83.09,17.92 82.12,16.95 82.12,16.28 79.67,13.83 77.55,13.83 76.95,13.23 62.04,13.23 61.67,13.59 60.15,13.59 59.89,13.85 56.5,13.85 53,17.35 51.43,17.35 49.8,18.98 48.59,18.98 48.08,19.49 48.08,20.43 44.87,23.64 44.87,32.17 40.67,36.37 v2(40.67,62.53)
  BOTTOM w0.076: UC1.AT13 104.61,35.57 v2(104.31,35.27)
H_PROCHOT#: length 197.7
  TOP w0.102: PR678.1 165.88,47.7 v2(165.88,47.33) 166.2,47.33 167.01,46.51 168.19,46.51 PC605.2 170.57,47.89 170.96,48.28 170.96,49.55 171.97,50.56 178.33,50.56 182.23,46.67 182.23,41.76 177.44,36.98 176.11,36.98 174.84,35.71 174.84,31.64 175.85,30.63 179.66,30.63 180.74,29.55 180.74,28.97 182.61,27.11 182.61,26.17 PQ3.1 ; PQ3.1 183.54,25.96 183.54,26.45 184.19,27.11 184.82,27.11 185.52,27.82 187.47,27.82 ; PQ3.1 182.14,24.56 182.14,23.77 181.93,23.57 PQ2.6 ; 187.47,27.82 189.89,25.41 189.89,23.36 v2(189.4,22.88) ; 187.47,27.82 v3(187.47,31.5) 187.47,35.34 187.65,35.51 PQ721.1 188.07,35.51 188.33,35.77 188.36,35.77 v2(189.19,36.6) ; CE26.1 152.29,20.43 152.3,20.44 UE2.4 152.3,21.96 151.72,22.54 v2(151.72,22.69)
  IN1 w0.119: v2(151.72,22.69) 151.72,20.37 153.41,18.69 153.41,18.18 155.59,16 156.13,16 158.97,13.15 164.49,13.15 168.07,9.58 172.39,9.58 v2(172.93,9.04)
  IN3 w0.142: v2(133.42,56.51) 134.35,56.51 135.04,57.2 136.21,57.2 137.01,58.01 137.44,58.44 137.44,59.88 137.39,59.94 137.39,63.26 139.77,65.64 148.94,65.64 158.45,56.12 158.45,52.85 159.16,52.14 159.16,50.14 160.7,48.6 164.99,48.6 165.88,47.71 v2(165.88,47.33)
  BOTTOM w0.102: v2(133.42,56.51) 133.72,56.81 133.72,58.15 131.25,60.62 131.25,65.58 130.45,66.38 130.27,66.38 129.53,67.11 129.13,67.11 RC113.2 127.98,67.71 RC117.1 ; v2(172.93,9.04) 177.9,14.01 181.32,14.01 183.22,15.91 185.64,15.91 186.62,16.89 186.62,17.72 189.12,20.23 189.12,22.6 v2(189.4,22.88) ; PR777.1 189.25,36.66 v2(189.19,36.6)
H_PROCHOT#_R: length 7.8
  BOTTOM w0.076: UC1.C65 122.42,65.4 122.68,65.15 123.88,65.15 124.57,65.84 124.93,65.84 125.37,66.28 125.37,67.63 125.45,67.71 125.69,67.71 125.75,67.64 125.75,67.07 125.81,67.01 126.07,67.01 126.13,67.07 126.13,67.6 126.21,67.68 126.35,67.68 RC117.2
H_PROCHOT_EC: length 5.6
  TOP w0.102: v2(154.43,23.86) 154.33,23.95 RE53.2 152.95,23.15 UE2.2
  BOTTOM w0.102: v2(154.43,23.86) 154.79,23.86 154.91,23.98 UE1.83 156.79,23.98 157.26,24.45 v1(157.65,24.45)
H_THERMTRIP#: length 9
  BOTTOM w0.076: UC1.C63 122.41,64.27 122.5,64.19 122.5,64.11 122.62,64.05 122.77,64.01 122.91,64.01 123.1,64.06 123.25,64.06 123.34,64.02 123.63,64.02 123.79,64.18 127.78,64.18 128.26,63.7 128.98,63.7 129.25,63.43 RC112.2 130.14,63.02 TP14.1
H_VCCST_PWRGD: length 34.6
  IN3 w0.142: v2(127.09,55.97) 126.82,56.24 125.74,56.24 125.59,56.38 125.59,56.7 125.74,56.84 126.34,56.84 126.49,56.98 126.49,57.25 126.34,57.4 125.93,57.4 125.78,57.54 125.78,57.74 126.03,57.98 126.69,57.98 126.83,58.12 126.83,58.42 127.58,59.17 127.58,60.18 127.44,60.32 127.21,60.32 127.07,60.46 127.07,60.75 127.21,60.89 127.44,60.89 127.58,61.03 127.58,62.62 127.44,62.76 127.23,62.76 127.08,62.9 127.08,63.19 127.23,63.33 127.44,63.33 127.58,63.47 127.58,64.05 127.44,64.2 127.23,64.2 127.08,64.34 127.08,64.62 127.23,64.77 127.44,64.77 127.58,64.91 127.58,65.19 127.44,65.34 127.23,65.34 127.07,65.49 127.07,65.85 127.21,66 127.43,66 127.58,66.14 127.58,66.42 127.44,66.57 127.21,66.57 127.07,66.71 127.07,66.99 127.21,67.13 127.44,67.13 127.58,67.28 127.58,67.55 127.43,67.7 127.21,67.7 127.07,67.85 127.07,68.79 127.41,69.13 127.41,71.22 127.55,71.37 127.9,71.37 128.04,71.22 128.04,68.78 v2(128.47,68.35)
  BOTTOM w0.102: v2(128.47,68.35) 128.4,68.29 RC96.1
  BOTTOM w0.142: v2(127.09,55.97) v1(127.72,55.34) 128,55.06 130.04,55.06 130.63,54.48 RC104.1 131.46,54.45 131.92,53.99 131.92,53.76 132.51,53.17 UC7.4
HDA_BIT_CLK: length 37.3
  TOP w0.102: v2(80.79,19.57) RC124.2
  BOTTOM w0.089: 96.08,39.93 96.2,40.05 98.15,40.05 98.23,40.12 101.35,40.12 101.69,40.46 101.92,40.46 UC1.AY22
  BOTTOM w0.102: 96.08,39.93 v1(95.94,39.79) 94.48,38.33 89.45,38.33 81.68,30.56 81.68,24.54 81.91,24.32 81.91,23.79 82.5,23.19 82.5,21.53 80.79,19.82 v2(80.79,19.57)
HDA_CODEC_BITCLK: length 62.1
  TOP w0.102: v2(79.75,16.44) 79.99,16.44 CC16.1 80.79,17.24 RC124.1 ; v2(27.74,23.8) 27.59,23.66 UA1.6
  IN1 w0.119: v2(27.74,23.8) 27.76,23.78 28.47,23.78 29.78,25.09 39.96,25.09 42.25,22.8 42.25,21.47 44.64,19.07 44.64,18.31 44.64,18.31 44.64,18.26 48.51,14.39 70.14,14.39 72.13,16.38 79.69,16.38 v2(79.75,16.44)
HDA_CODEC_RST#: length 1.2
  TOP w0.102: RC127.1 79.42,20.31 TP74.1
HDA_CODEC_SDIN0: length 3.5
  TOP w0.102: UA1.8 26.79,23.51 26.8,23.51 26.91,23.61 26.91,24.28 v1(27.18,24.55) 27.18,24.64 28.28,25.73 RA7.2
HDA_CODEC_SDOUT: length 62.7
  TOP w0.102: RC125.1 79.9,18.02 78.91,17.02 v2(78.57,17.02) ; v2(28.09,24.28) 28.16,24.21 28.16,23.59 27.99,23.42 UA1.5
  IN1 w0.119: v2(28.09,24.28) 29.58,25.78 34.08,25.78 35.09,26.79 38.97,26.79 45.14,20.61 45.14,19.73 45.14,18.47 48.72,14.89 69.94,14.89 71.43,16.38 72.46,17.41 75.04,17.41 75.84,18.22 77.37,18.22 v2(78.57,17.02)
HDA_CODEC_SYNC: length 64.7
  TOP w0.102: UA1.10 25.99,24.17 v1(25.79,24.36) 25.79,24.73 v2(25.99,24.92) ; v2(77.92,19.35) 77.92,20.52 RC123.1
  IN1 w0.119: v2(77.92,19.35) 76.26,19.35 74.83,17.91 72.25,17.91 70.46,16.13 68.72,16.13 68.17,15.58 48.73,15.58 45.64,18.67 45.64,18.91 45.64,18.91 45.64,19.53 45.64,20.82 39.09,27.37 34.96,27.37 33.87,26.28 28.62,26.28 27.26,24.92 v2(25.99,24.92)
HDA_RST#: length 37.5
  TOP w0.102: CC89.1 80.32,21.99 79.46,21.99 RC127.2 79.42,22.47 79.94,22.99 v2(79.94,23.1)
  BOTTOM w0.076: 94.3,40.45 94.81,40.45 94.94,40.59 97.98,40.59 98.02,40.62 100.37,40.62 100.71,40.96 101.02,40.96 101.03,40.95 102.54,40.95 UC1.AW22
  BOTTOM w0.102: v2(79.94,23.1) 79.53,23.51 79.53,30.45 88.85,39.77 93.62,39.77 94.3,40.45
HDA_SDIN0: length 97.5
  TOP w0.102: RA7.1 v2(28.28,27.43)
  IN1 w0.119: v2(28.28,27.43) 28.87,28.02 32.52,28.02 33.44,28.94 39.64,28.94 42.72,25.87 44.09,25.87 45.46,24.5 45.46,23.13 47.14,21.44 47.14,19.3 48.81,17.63 57.54,17.63 57.88,17.97 60.84,17.97 61.18,17.63 69.84,17.63 71.63,19.41 74.21,19.41 75.66,20.86 77.9,20.86 78.04,21.01 81.44,21.01 v2(82.17,20.27)
  BOTTOM w0.089: 96.29,39.45 96.7,39.87 98.35,39.87 98.43,39.94 101.42,39.94 101.61,40.13 UC1.BA21
  BOTTOM w0.102: 96.29,39.45 94.68,37.84 91.3,37.84 82.16,28.7 82.16,24.74 82.39,24.52 82.39,23.99 83.08,23.3 83.08,21.17 v2(82.17,20.27)
HDA_SDOUT: length 77.2
  TOP w0.102: RC126.2 RC125.2 79.9,19.15 v2(79.49,19.56)
  IN1 w0.119: v2(79.49,19.56) 81.57,17.48 85.55,17.48 85.9,17.83 86.64,17.83 87.23,18.42 95.57,18.42 98.32,21.16 98.32,23.71 99.11,24.5 103.27,24.5 104.43,23.33 106.83,23.33 107.53,22.63 107.53,21.1 108.6,20.03 109.39,20.03 v2(109.85,20.48)
  BOTTOM w0.076: UC1.BB22 100.61,40.46 98.09,40.46 98.03,40.4 97.63,40.4 97.62,40.41
  BOTTOM w0.102: 97.62,40.41 95.19,40.41 94.08,39.29 89.05,39.29 80.72,30.96 80.72,23.58 80.69,23.55 80.69,21.84 79.67,20.82 79.67,19.75 v2(79.49,19.56) ; RC129.2 v2(109.85,20.48)
HDA_SYNC: length 35.9
  TOP w0.102: v2(81.25,23.01) 81.01,23.01 80.51,23.5 79.77,23.5 78.52,22.25 RC123.2
  BOTTOM w0.076: UC1.BA22 101.29,40.7 100.89,40.29 98.16,40.29 98.09,40.22 96.48,40.22
  BOTTOM w0.089: 95.68,40.21 95.69,40.22 96.48,40.22
  BOTTOM w0.102: v2(81.25,23.01) 81.2,23.06 81.2,30.76 89.25,38.81 94.28,38.81 95.68,40.21
HDD_DEVSLP: length 124.2
  TOP w0.102: v2(198.12,44.73) v3(198.12,43.41) 198.12,41.53 195.47,38.88 193.12,38.88 192.27,38.03 192.27,30.57 191.8,30.1 191.8,25.96 194.32,23.45 194.32,17.91 194.41,17.82 194.41,17.82 194.95,17.28 RS1.2
  IN2 w0.127: v2(118.31,28.17) 118.31,29.18 119.95,30.82 122.21,30.82 122.7,31.31 122.7,32.3 123.86,33.46 129.03,33.46 130.73,35.16 133.67,35.16 134.31,35.81 139.57,35.81 140.97,37.21 141.78,37.21 142.65,38.08 144.82,38.08 144.97,38.23 146.5,38.23 147.28,39.01 150.6,39.01 152.38,37.23 159.54,37.23 160.87,38.56 162.14,38.56 162.72,37.99 173.49,37.99 174.41,38.91 177.51,38.91 180.38,41.78 181.29,41.78 182.74,43.23 183.68,43.23 186.53,46.08 192.81,46.08 193.46,45.43 197.42,45.43 v2(198.12,44.73)
  BOTTOM w0.076: v2(118.31,28.17) 118.64,28.5 UC1.J1
HDD_DEVSLP_R: length 4.5
  TOP w0.102: v2(196.72,16.16) 195.97,16.91 RS1.1
  BOTTOM w0.102: v1(195.65,18.34) JHDD1.8 195.65,16.47 195.96,16.16 v2(196.72,16.16)
HDMI_CLK: length 137.8
  TOP w0.102: v2(21.06,85.94) 21.16,86.04 21.16,86.21 21.05,86.31 20.27,86.31 20.26,86.32 CI2.1
  IN3 w0.089: v2(119.78,60.92) 119.78,60.77 120.2,60.35 121.75,60.35 121.87,60.47 121.92,60.47 121.94,60.49
  IN3 w0.142: 121.94,60.49 122.61,61.16 122.61,72.66 119.28,75.99 119.28,81.56 117.62,83.22 111.87,83.22 104.21,90.89 76.08,90.89 71.1,95.87 57.11,95.87 53.97,92.73 42.13,92.73 40.22,94.64 33.12,94.64 25.55,87.07 21.58,87.07 21.06,86.55 v2(21.06,85.94)
  BOTTOM w0.076: UC1.G56 119.45,60.59 v2(119.78,60.92)
HDMI_CLK#: length 137.8
  TOP w0.102: v2(21.64,85.94) 21.6,85.94 21.43,86.11 21.43,86.23 21.14,86.52 20.35,86.52 19.77,87.11 CI1.1
  IN3 w0.089: v2(120.41,60.92) 120.27,60.92 120.16,60.81 120.16,60.64 120.27,60.53 121.67,60.53 121.74,60.6 121.74,60.65 121.76,60.67
  IN3 w0.142: 121.76,60.67 122.36,61.27 122.36,72.56 119.03,75.89 119.03,81.46 117.52,82.97 111.76,82.97 104.1,90.64 75.98,90.64 71,95.61 57.22,95.61 54.08,92.47 42.03,92.47 40.12,94.38 33.22,94.38 25.66,86.82 21.69,86.82 21.31,86.45 21.31,86.29 21.64,85.96 v2(21.64,85.94)
  BOTTOM w0.076: v2(120.41,60.92) 120.54,60.92 120.62,60.84 120.62,60.72 120.28,60.38 120.18,60.38 UC1.F56
HDMI_CLK#_R: length 4.4
  TOP w0.102: RI2.1 17.29,87.18 LI1.2 17.73,87.01 17.91,86.83 18.04,86.83 v2(18.23,87.02) 18.39,86.85 18.5,86.85 CI1.2
  BOTTOM w0.102: v2(18.23,87.02) 18.04,86.83 17.71,86.83 17.07,87.47 16.71,87.47 16.56,87.61 RPI2.7
HDMI_CLK#_R_C: length 5.3
  TOP w0.102: JHDMI1.12 12.43,87.57 13.4,87.57 13.53,87.45 13.56,87.45 13.96,87.05 13.96,87.02 14.11,86.87 14.57,86.87 RI3.1 15.32,86.83 15.76,86.83 15.95,87.01 LI1.1 16.21,87.04 RI2.2
HDMI_CLK_R: length 4.4
  TOP w0.102: RI1.1 17.29,86.35 LI1.3 17.72,86.51 17.83,86.62 17.83,86.62 18.04,86.62 v2(18.23,86.43) 18.44,86.65 18.52,86.65 CI2.2
  BOTTOM w0.102: RPI2.8 16.55,87.11 16.7,87.26 16.98,87.26 17.62,86.62 18.04,86.62 v2(18.23,86.43)
HDMI_CLK_R_C: length 5.2
  TOP w0.102: RI1.2 16.21,86.49 LI1.4 15.94,86.51 15.83,86.62 15.24,86.62 RI3.2 14.57,86.66 14.02,86.66 v4(13.6,87.09) 13.32,87.37 12.37,87.37 JHDMI1.10
HDMI_DATA0: length 145.8
  TOP w0.102: CI4.1 19.93,89.02 20.54,89.02 20.68,88.88 v2(20.68,88.58)
  IN3 w0.089: 121.94,58.4 121.83,58.4 121.75,58.48 120.2,58.48 120.01,58.68 120.01,58.85 v2(119.78,59.08)
  IN3 w0.142: 121.94,58.4 122.24,58.4 122.7,57.94 123.91,57.94 124.86,58.89 124.86,61.36 125.62,62.13 125.62,63.65 125.35,63.92 125.35,68.22 125.19,68.37 125.19,73.47 120.83,77.83 120.83,82.21 118.27,84.77 112.51,84.77 104.85,92.44 76.73,92.44 71.75,97.42 56.47,97.42 53.47,94.42 42.63,94.42 40.8,96.25 32.45,96.25 26.17,89.97 21.11,89.97 20.68,89.54 v2(20.68,88.58)
  BOTTOM w0.076: v2(119.78,59.08) 119.45,58.75 UC1.G53
HDMI_DATA0#: length 145.7
  TOP w0.102: v2(21.27,88.58) 20.62,89.23 20.29,89.23 CI3.1
  IN3 w0.089: 121.94,58.65 121.88,58.65 121.87,58.66 120.27,58.66 120.19,58.75 120.19,58.99 120.27,59.08 v2(120.41,59.08)
  IN3 w0.142: 121.94,58.65 122.34,58.65 122.8,58.19 123.8,58.19 124.61,58.99 124.61,61.47 125.37,62.23 125.37,63.55 125.1,63.82 125.1,68.11 124.94,68.27 124.94,73.37 120.58,77.73 120.58,82.1 118.16,84.52 112.41,84.52 104.74,92.18 76.62,92.18 71.64,97.16 56.57,97.16 53.57,94.17 42.53,94.17 40.7,96 32.55,96 26.27,89.72 21.22,89.72 20.93,89.44 20.93,88.94 21.27,88.6 v2(21.27,88.58)
  BOTTOM w0.076: v2(120.41,59.08) 120.45,59.08 120.52,59 120.52,58.79 120.47,58.74 120.47,58.51 120.34,58.38 120.22,58.38 120.1,58.5 UC1.F53
HDMI_DATA0#_R: length 4.7
  TOP w0.102: CI3.2 18.54,89.44 18.35,89.44 v2(18.23,89.55) 18.08,89.4 17.89,89.4 17.73,89.55 LI2.2 17.29,89.72 RI4.1
  BOTTOM w0.102: v2(18.23,89.55) 18.04,89.37 17.54,89.37 17.24,89.07 17.24,88.66 17.04,88.47 16.84,88.47 16.69,88.61 RPI2.5
HDMI_DATA0#_R_C: length 13.4
  TOP w0.102: JHDMI1.9 10.45,86.31 10.66,86.1 10.99,86.1 11.09,86.2 11.09,91.21 11.67,91.79 v4(12.75,91.79) 13.12,91.79 13.74,91.18 13.77,91.18 14.17,90.78 14.17,90.75 14.29,90.62 14.29,89.63 14.4,89.53 14.63,89.53 RI6.1 14.94,89.83 15.31,89.45 15.68,89.45 15.78,89.55 LI2.1 16.38,89.72 RI4.2
HDMI_DATA0_R: length 4.8
  TOP w0.102: CI4.2 18.56,89.15 18.41,89.15 v2(18.23,88.97) 18.01,89.19 17.86,89.19 17.72,89.05 LI2.3 17.29,88.89 RI5.1
  BOTTOM w0.102: v2(18.23,88.97) 18.04,89.16 17.62,89.16 17.44,88.98 17.44,88.58 17.13,88.26 16.84,88.26 16.69,88.11 RPI2.6
HDMI_DATA0_R_C: length 13.4
  TOP w0.102: JHDMI1.7 10.85,85.9 11.08,85.9 11.3,86.12 11.3,91.13 11.76,91.58 12.44,91.58 12.47,91.56 13.06,91.56 v4(13.81,90.82) 14.09,90.53 14.09,89.54 14.31,89.32 14.52,89.32 RI6.2 15.27,89.25 15.67,89.25 15.86,89.05 LI2.4 16.38,88.89 RI5.2
HDMI_DATA1: length 136.2
  TOP w0.102: CI6.1 v4(20.89,83.78) 21.42,83.78 21.52,83.68 v2(21.52,83.21)
  IN3 w0.089: 121.84,62.63 121.84,62.61 121.8,62.58 121.8,61.61 121.49,61.3 120.86,61.3 v2(120.35,61.81)
  IN3 w0.142: 121.84,62.63 121.84,67.06 121.37,67.52 120.73,67.52 120.35,67.91 120.35,73.83 118.51,75.67 118.51,81.24 117.3,82.45 111.55,82.45 103.88,90.11 75.76,90.11 70.78,95.09 57.43,95.09 54.29,91.95 41.81,91.95 39.9,93.86 33.43,93.86 25.05,85.48 22.05,85.48 21.52,84.94 v2(21.52,83.21)
  BOTTOM w0.076: v2(120.35,61.81) 120.35,61.62 UC1.F58
HDMI_DATA1#: length 136.2
  TOP w0.102: v2(22.1,83.21) 22.02,83.21 21.91,83.31 21.91,83.57 21.5,83.99 21.19,83.99 21.17,84.01 20.59,84.01 20.57,83.99 20.41,83.99 20.16,84.24 19.93,84.24 19.83,84.34 CI5.1
  IN3 w0.089: v2(120.99,61.81) 120.99,61.62 121.13,61.48 121.42,61.48 121.62,61.68 121.62,62.58 121.58,62.61 121.58,62.63
  IN3 w0.142: 121.58,62.63 121.58,66.95 121.26,67.27 120.63,67.27 120.1,67.8 120.1,73.73 118.26,75.57 118.26,81.14 117.2,82.2 111.44,82.2 103.78,89.86 75.66,89.86 70.68,94.84 57.54,94.84 54.4,91.7 41.71,91.7 39.8,93.61 33.54,93.61 25.16,85.22 22.16,85.22 21.77,84.84 21.77,83.56 22.1,83.23 v2(22.1,83.21)
  BOTTOM w0.076: v2(120.99,61.81) 121.16,61.81 121.26,61.71 121.26,61.53 121.01,61.28 120.84,61.28 UC1.E58
HDMI_DATA1#_R: length 4.6
  TOP w0.102: CI5.2 18.56,84.31 18.46,84.31 v2(18.29,84.48) 18.12,84.3 17.83,84.3 17.66,84.47 LI4.2 17.29,84.64 RI11.1
  BOTTOM w0.102: v2(18.29,84.48) 18.11,84.3 17.73,84.3 17.07,83.64 16.69,83.64 16.54,83.79 RPI1.5
HDMI_DATA1#_R_C: length 5.1
  TOP w0.102: JHDMI1.6 12.38,84.62 13.12,84.62 13.37,84.36 13.66,84.36 13.68,84.39 14.25,84.39 14.27,84.36 14.61,84.36 RI12.1 15.28,84.33 15.86,84.33 16,84.47 LI4.1 16.38,84.64 RI11.2
HDMI_DATA1_R: length 4.6
  TOP w0.102: RI10.1 17.29,83.81 LI4.3 17.66,83.97 17.79,84.1 18.09,84.1 v2(18.29,83.89) 18.51,84.11 18.59,84.11 CI6.2
  BOTTOM w0.102: v2(18.29,83.89) 18.1,84.09 17.81,84.09 17.16,83.43 16.71,83.43 16.56,83.29 RPI1.6
HDMI_DATA1_R_C: length 5.1
  TOP w0.102: JHDMI1.4 12.41,84.41 13.03,84.41 13.29,84.16 v4(13.96,84.16) 14.54,84.16 RI12.2 15.28,84.12 15.86,84.12 16,83.97 LI4.4 16.38,83.81 RI10.2
HDMI_DATA2: length 147.1
  TOP w0.102: CI8.1 20.71,81.24 20.82,81.14 20.82,80.98 v2(20.81,80.97)
  IN3 w0.089: v2(120.43,59.9) 120.44,59.89 120.44,59.88 120.85,59.47 121.23,59.47 121.35,59.35 121.89,59.35 121.93,59.31 121.94,59.31
  IN3 w0.142: v2(20.81,80.97) 20.87,81.04 20.87,82.03 20.28,82.62 20.28,86.88 21.58,88.18 25.49,88.18 32.77,95.45 40.5,95.45 42.31,93.64 53.79,93.64 56.79,96.64 71.42,96.64 76.4,91.66 104.53,91.66 112.19,84 117.94,84 120.06,81.89 120.06,76.31 123.39,72.99 123.39,70.66 124.2,69.84 124.2,67.82 123.46,67.08 123.46,63.31 123.84,62.93 123.84,61.77 123.46,61.39 123.46,59.97 122.8,59.31 121.94,59.31
  BOTTOM w0.076: UC1.F55 120.1,59.58 v2(120.43,59.9)
HDMI_DATA2#: length 147.1
  TOP w0.102: v2(21.39,80.97) 20.92,81.45 20.41,81.45 20.16,81.7 19.88,81.7 19.78,81.8 19.78,82.08 CI7.1
  IN3 w0.089: v2(121.11,59.9) 121.09,59.88 121.09,59.74 121.18,59.65 121.3,59.65 121.43,59.52 121.88,59.52 121.92,59.56 121.94,59.56
  IN3 w0.142: 121.94,59.56 122.7,59.56 123.21,60.07 123.21,61.49 123.59,61.87 123.59,62.83 123.21,63.21 123.21,67.18 123.95,67.93 123.95,69.73 123.13,70.55 123.13,72.88 119.8,76.21 119.8,81.78 117.84,83.75 112.09,83.75 104.42,91.41 76.3,91.41 71.32,96.39 56.89,96.39 53.9,93.39 42.21,93.39 40.4,95.2 32.87,95.2 25.6,87.93 21.69,87.93 20.53,86.78 20.53,82.72 21.17,82.08 21.17,81.19 v2(21.39,80.97)
  BOTTOM w0.076: v2(121.11,59.9) 121.23,59.9 121.31,59.83 121.31,59.52 121.23,59.44 120.85,59.44 UC1.E55
HDMI_DATA2#_R: length 4.7
  TOP w0.102: RI8.1 17.29,82.1 LI3.2 17.72,81.93 17.9,81.75 18.1,81.75 v2(18.29,81.94) 18.46,81.77 18.56,81.77 CI7.2
  BOTTOM w0.102: v2(18.29,81.94) 18.1,81.75 17.93,81.75 17.04,82.64 16.69,82.64 16.54,82.79 RPI1.7
HDMI_DATA2#_R_C: length 7.2
  TOP w0.102: JHDMI1.3 10.45,83.31 10.79,82.98 11.03,82.98 11.75,82.26 11.78,82.26 12.23,81.8 v4(13.47,81.8) 14.59,81.8 RI9.1 15.28,81.79 15.86,81.79 16,81.93 LI3.1 16.38,82.1 RI8.2
HDMI_DATA2_R: length 4.6
  TOP w0.102: CI8.2 18.59,81.57 18.51,81.57 v2(18.29,81.35) 18.13,81.52 17.81,81.52 17.73,81.43 LI3.3 17.29,81.27 RI7.1
  BOTTOM w0.102: RPI1.8 16.58,82.29 16.73,82.44 16.96,82.44 17.85,81.54 18.1,81.54 v2(18.29,81.35)
HDMI_DATA2_R_C: length 7.1
  TOP w0.102: JHDMI1.1 10.45,82.69 10.53,82.77 10.94,82.77 v4(11.82,81.9) 12.12,81.6 13.17,81.6 13.19,81.58 13.75,81.58 13.77,81.6 14.56,81.6 RI9.2 15.28,81.58 15.79,81.58 15.94,81.43 LI3.4 16.38,81.27 RI7.2
HDMI_HPD: length 178.7
  TOP w0.102: RI15.2 24.87,92.15 25.13,91.89 QI3.3 27.21,91.89 v3(29.42,89.69) v2(30.44,89.69)
  IN3 w0.142: v2(30.44,89.69) 32.47,89.69 38.13,84.02 38.13,33.6 41.64,30.09 41.64,23.52 45.39,19.77 45.39,18.87 53.29,10.96 56.54,10.96 57.59,9.91 61.65,9.91 62.7,10.96 81.82,10.96 82.23,11.37 87.44,11.37 88.87,12.81 102.38,12.81 104.28,14.71 104.28,21.17 105.42,22.31 105.42,23.25 108.35,26.19 108.35,26.73 108.61,26.98 108.61,28.5 109.8,29.7 109.8,30.15 110.05,30.4 110.66,30.4 110.95,30.69 110.95,31.33 111.27,31.65 111.27,33.04 111.68,33.45 v2(111.68,33.57)
  BOTTOM w0.076: 116.27,32.93 117.22,32.93 UC1.L9
  BOTTOM w0.089: 116.27,32.93 115.66,33.54 113.28,33.54 113.08,33.75 113.08,33.91 112.79,34.19 112.03,34.19 111.68,33.83 v2(111.68,33.57)
HDMI_HPD_B: length 40.8
  TOP w0.102: QI3.1 28.92,92.54 RI16.1 29.8,92.17 30.38,91.59 34.31,91.59 34.69,91.97 34.69,95.34 v1(32.96,97.07) 31.4,98.63 15.95,98.63 13.93,96.6 13.93,93.58 13.05,92.7 11.65,92.7 JHDMI1.19
HDMI_PLL_GND: length 2.9
  TOP w0.102: QI1.1 v1(15.36,75)
  vias: v2(14.6,79.3) v2(15.23,79.3)
HOST_DEBUG_TX: length 232.9
  TOP w0.102: JDEG1.8 133.22,8.44 134.97,10.19 ZT57.1 134.97,11.67 134.53,12.11 RE59.2 134.97,13.23 136.74,13.23 137.58,14.07 145.65,14.07 147.29,12.43 148.08,12.43 148.92,13.27 149.63,13.27 150.54,14.18 150.54,15.58 151.01,16.05 152.07,16.05 152.88,15.23 153.86,15.23 154.01,15.39 154.71,15.39 154.97,15.12 156.29,15.12 156.52,15.36 156.52,16.12 155.21,17.43 155.21,18.56 156.65,20 158.22,20 158.44,20.22 158.44,22.42 158.8,22.77 158.8,24.21 v2(158.67,24.34) 158.14,24.87 156.93,24.87 155.68,26.12 154.37,26.12 154.1,25.84 152.74,25.84 152.29,25.4 152.29,25.34 152.02,25.06 150.59,25.06 142.72,32.93 142.72,35.86 142.11,36.47 142.11,38.53 142.28,38.71 142.28,39.04 141.93,39.4 140.09,39.4 138.98,40.51 138.98,46.29 137.53,47.73 137.53,48.26 134.88,50.92 134.88,57.47 135.91,58.5 v2(135.91,59.07) ; RW6.1 53.65,104.44 v2(52.86,104.44) 52.76,104.44 52.14,105.07 RW8.1
  IN3 w0.142: v2(135.91,59.07) 135.24,59.07 134.86,58.69 132.74,58.69 132.06,59.37 132.06,63.63 130.75,64.94 130.75,74.77 130.75,84.43 126.72,88.46 122.18,88.46 121.18,89.46 121.18,93.62 117.56,97.24 117.56,101.81 115.61,103.76 112.32,103.76 111.83,103.26 109.42,103.26 108.77,103.91 106.19,103.91 105.73,103.45 100.79,103.45 99.4,102.06 97.87,102.06 97.18,101.36 97.18,100.03 93.72,96.57 76.62,96.57 72.89,100.3 68.34,100.3 67.07,101.57 60.85,101.57 59.76,102.66 56.98,102.66 55.2,104.44 v2(52.86,104.44)
  BOTTOM w0.102: JWLAN1.30 52.3,105.01 v2(52.86,104.44) ; v2(158.67,24.34) 158.23,24.78 UE1.81
HPOUT_L: length 13.7
  TOP w0.102: v2(15.56,11.12) ZT19.1
  IN3 w0.305: JHP1.1 11.55,12.82 12.83,11.54 15.14,11.54 v2(15.56,11.12)
  BOTTOM w0.305: v2(15.56,11.12) DA4.2 17.93,11.12 18.69,10.36 CA35.1 21.47,10.36 RA36.2 22.94,10.36 RA30.1
HPOUT_R: length 26.8
  TOP w0.102: v2(15.56,13.05) ZT22.1
  IN3 w0.305: v2(15.56,13.05) 14.69,13.93 14.69,22.12 12.88,23.93 6.96,23.93 JHP1.2
  BOTTOM w0.305: CA34.1 DA4.3 v2(15.56,13.05) ; CA34.1 20.53,14.03 RA37.2 ; CA34.1 RA34.1
I2C_SCL_TP: length 27.8
  TOP w0.102: Q10.1 106.9,8.4 R34.2 v3(108.06,10.01) 108.48,10.43 108.48,11.36 109.16,12.04 v2(109.65,12.04)
  IN3 w0.142: v2(113.92,30.91) 113.67,30.66 113.67,30.62 113.43,30.38 113.43,29.55 111.94,28.06 111.94,26.86 111.24,26.16 111.24,21.08 111.99,20.33 111.99,15.61 109.65,13.27 v2(109.65,12.04)
  BOTTOM w0.076: v2(113.92,30.91) 113.87,30.91 113.87,30.95 114.11,30.95 UC1.U6
I2C_SCL_TP_Q: length 16.8
  TOP w0.102: ZT9.1 107.79,5.59 R46.2 107.39,6 Q10.6 106.39,5.99 106.39,5.69 106.53,5.55 106.53,4.71 105.96,4.13 v2(105.28,4.13)
  BOTTOM w0.102: v2(105.28,4.13) 105.28,7.43 104.85,7.86 102.52,7.86 102.15,7.49 100.5,7.49 99.69,8.3 99.69,9.24 99.9,9.45 JTP1.6
I2C_SDA_TP: length 38
  TOP w0.102: Q10.4 105.1,5.1 R33.2 104.87,4.88 104.87,3.85 105.19,3.53 108.29,3.53 108.55,3.79 108.55,7.74 109.05,8.23 v1(109.05,8.49) 109.05,11.25 v2(109.33,11.53)
  IN3 w0.142: v2(109.33,11.53) 109.12,11.74 109.12,13.49 111.46,15.83 111.46,20.11 110.27,21.3 110.27,25.93 111.41,27.07 111.41,28.28 112.9,29.77 112.9,30.6 112.91,30.6 113.14,30.84 113.14,30.92 113.89,31.66 v2(114.01,31.66)
  BOTTOM w0.076: UC1.U7 v2(114.01,31.66)
I2C_SDA_TP_Q: length 12.5
  TOP w0.102: ZT8.1 106.18,10.11 105.02,8.96 R47.2 104.54,8.45 Q10.3 104.59,7.39 v2(104.59,7.38)
  BOTTOM w0.102: JTP1.7 98.9,8.22 100.4,6.72 103.94,6.72 v2(104.59,7.38)
I_ADP: length 57.5
  TOP w0.102: v2(148.86,21.23) 149.22,20.88 RE51.2 ; v2(189.19,37.23) 189.19,37.23 v1(189.73,36.68)
  IN2 w0.127: v2(189.19,37.23) 187.91,37.23 185.82,35.15 185.82,31.72 184.66,30.56 184.11,30.56 183.73,30.18 183.73,26.81 179.98,23.07 177.86,23.07 175.26,20.47 163.92,20.47 163.89,20.44 163.01,20.44 159.98,17.42 157.81,17.42 153.87,21.36 152.52,21.36 152.36,21.19 148.9,21.19 v2(148.86,21.23)
  BOTTOM w0.254: PR774.1 189.49,37.23 v2(189.19,37.23) 188.94,37.48 PC748.1
I_ADP_R: length 5.9
  TOP w0.102: CE25.1 149.32,18.06 148.76,18.61 v2(148.76,18.76) 148.76,19.11 RE51.1
  BOTTOM w0.102: v2(148.76,18.76) 149.16,18.36 UE1.110 149.16,16.23 v1(149.98,15.41)
I_BATT: length 60.8
  TOP w0.102: RE54.2 147.43,21.78 v1(147.32,21.89) v2(146.88,22.33)
  IN2 w0.127: v2(146.88,22.33) 147.23,22.33 147.53,22.63 148.48,22.63 149.66,21.45 152.25,21.45 152.42,21.61 153.97,21.61 157.94,17.65 159.89,17.65 162.91,20.67 163.76,20.67 163.81,20.72 175.15,20.72 177.76,23.32 179.87,23.32 183.47,26.92 183.47,30.31 183.98,30.82 184.56,30.82 185.57,31.83 185.57,35.25 v2(188.94,38.63)
  BOTTOM w0.254: PR775.1 189.78,38.47 189.11,38.47 v2(188.94,38.63) PC749.2
I_BATT_R: length 5.1
  TOP w0.102: v1(148.61,21.67) 148.61,21.61 148.32,21.32 CE30.1 RE54.1 147.43,18.86 v2(147.53,18.76)
  BOTTOM w0.102: v2(147.53,18.76) 147.56,18.73 UE1.114
I_SYS: length 114.1
  TOP w0.102: RE44.1 149.07,15.07 v2(149.41,14.74)
  TOP w0.254: v2(190.29,22.95) 190.39,22.95 191.52,24.08 191.52,30.26 191.97,30.7 191.97,38.09 v2(191.85,38.2) ; v2(186.84,47.84) 186.84,54.03 183.32,57.55 178.17,57.55 v3(174.7,54.08) 170.27,49.65 PR620.1
  IN1 w0.119: v2(190.29,22.95) 188.56,21.22 188.56,18.16 186.54,16.14 v2(186.54,15.42)
  IN3 w0.142: v2(149.41,14.74) 149.41,13.83 151.72,11.51 151.72,10.09 153.22,8.59 172.04,8.59 173.18,7.45 v2(173.35,7.45)
  BOTTOM w0.102: v2(173.35,7.45) 173.35,8.4 177.93,12.97 184.41,12.97 186.54,15.1 v2(186.54,15.42)
  BOTTOM w0.203: PU703.8 192.1,37.24 191.85,37.49 v2(191.85,38.2)
  BOTTOM w0.254: v2(191.85,38.2) 191.85,38.45 190.97,39.33 PR727.1 190.72,39.34 189.53,40.54 188.45,40.54 188.15,40.84 188.15,41.99 187.27,42.87 186.8,42.87 186.2,43.47 186.2,46.44 186.84,47.08 v2(186.84,47.84)
ICSP_CLK: length 23.1
  TOP w0.102: RE60.1 135.05,14.69 135.12,14.76 145.93,14.76 146.97,13.73 148.16,13.73 148.62,14.18 RE24.2 149.47,14.18 149.93,14.65 149.93,15.94 150.8,16.81 v1(151.35,16.81) 151.85,16.81 152.29,17.25 v2(152.29,18.44)
  BOTTOM w0.102: UE1.101 152.76,17.97 v2(152.29,18.44)
ICSP_CLK_R: length 10.3
  TOP w0.102: JDEG1.2 130.22,10.6 129.18,11.64 129.18,12.46 ZT53.1 130.14,13.42 131.16,13.42 132.42,14.69 RE60.2
ICSP_CLR: length 31.6
  TOP w0.102: v2(157.9,23.26) 157.09,22.45 v3(157.02,22.45) 156.65,22.07 156.65,21.58 156.36,21.3 154.84,21.3 154.4,20.86 154.4,18.43 152.45,16.48 150.79,16.48 150.13,15.82 150.13,14.37 149.49,13.73 148.73,13.73 147.89,12.89 147.48,12.89 145.84,14.53 136.76,14.53 136.3,14.08 RE61.1
  BOTTOM w0.102: UE1.87 157.02,22.38 v2(157.9,23.26)
ICSP_CLR_R: length 10.1
  TOP w0.102: RE61.2 135,14.05 134.82,14.23 132.34,14.23 130.96,12.85 ZT54.1 130.96,11.56 130.72,11.33 JDEG1.3
ICSP_DAT: length 25.8
  TOP w0.102: v2(153.69,15.64) 153.74,15.69 RE26.2 v1(152.81,16.27) 150.95,16.27 150.34,15.66 150.34,14.27 149.57,13.5 148.82,13.5 147.98,12.66 147.39,12.66 145.74,14.3 137.52,14.3 136.65,13.43 135.2,13.43 134.96,13.67 RE63.1
  BOTTOM w0.102: UE1.102 152.36,16.21 152.93,15.64 v2(153.69,15.64)
ICSP_DAT_R: length 7.2
  TOP w0.102: RE63.2 132.42,13.67 ZT56.1 132.23,12.53 131.72,12.02 JDEG1.5
ILMT_+1.35VGPU: length 6.6
  BOTTOM w0.102: v1(158.92,84.8) 158.92,86.17 PR1406.2
  BOTTOM w0.254: PR1406.2 PR1407.1 157.82,86.65 157.13,87.34 156.36,87.34 156.09,87.6 PU1400.13
ILMT_+1VALW: length 3.9
  BOTTOM w0.254: PR304.2 PR305.1 152.25,39.89 152.25,39.89 152.1,40.04 152.1,40.04 151.88,40.27 150.91,40.27 150.57,40.61 PU300.13
IMON_IA: length 3.5
  TOP w0.203: v2(165.2,56.79) 165.2,56.79 165.21,56.79 165.21,56.18 165.08,56.06 PU602.14
  BOTTOM w0.102: v2(165.2,56.79) 165.43,56.79 v1(165.81,57.17)
  BOTTOM w0.254: PR629.2 PC625.2 165.2,56.22 v2(165.2,56.79)
IMON_VGA: length 3.4
  TOP w0.203: PC1117.2 49.58,120.48 v1(50.03,120.93) 50.17,120.93 50.68,121.44 PU1100.10
  TOP w0.254: PR1117.2 PC1117.2
IMON_VSA: length 4.9
  TOP w0.203: v2(160.56,54.47) 160.95,54.47 161.31,54.12 PU602.23
  BOTTOM w0.102: v1(160.28,53.14) 160.28,54.19 v2(160.56,54.47)
  BOTTOM w0.254: PC643.1 PR651.1 161.19,54.7 160.97,54.47 v2(160.56,54.47)
IMVP_VR_ON: length 108.7
  TOP w0.254: v2(168.81,48.35) 168.41,47.95 PR616.1
  IN1 w0.119: v2(124.04,29.63) 124.33,29.63 124.76,29.2 126.74,29.2 128.73,31.19 129.12,31.19 130.88,32.94 131.78,32.94 132.16,33.32 132.16,34.2 133.13,35.17 133.13,36.81 136.48,40.16 137.11,40.16 139.21,42.25 139.21,45.29 140.36,46.45 151.88,46.45 153.84,48.41 159.98,48.41 160.73,47.65 161.51,47.65 162.39,48.53 168.62,48.53 v2(168.81,48.35)
  IN3 w0.254: v2(168.81,48.35) 168.3,48.85 166.96,48.85 166.38,49.43 166.38,49.92 167.28,50.82 167.28,55.18 168.61,56.51 168.61,57.8 170.45,59.64 170.45,66.33 163.37,73.42 163.37,77.58 164.55,78.77 164.55,82.86 163.94,83.46 161.32,83.46 v2(161.25,83.53)
  BOTTOM w0.102: v2(124.04,29.63) 124.04,28.78 125.55,27.27 125.55,25.47 RC107.2
  BOTTOM w0.254: PR655.1 161.19,83.59 v2(161.25,83.53)
INT_TP#: length 4.7
  TOP w0.102: ZT10.1 100.99,9.47 100.97,9.46 R39.2 100.97,8.4 v2(100.95,8.38) 101.54,7.79 Q9.3
  BOTTOM w0.102: v2(100.95,8.38) 101.9,9.33 JTP1.4
INTRUDER#: length 30.2
  TOP w0.102: v2(86.12,23.96) 85.93,23.77 RC91.1 85.93,22.7 v1(85.64,22.41)
  IN3 w0.135: 101.42,36.18 102.78,37.54 105.17,37.54 v2(105.59,37.95)
  IN3 w0.142: v2(86.12,23.96) 86.12,24.34 88.68,26.9 95.1,26.9 95.47,27.28 96.02,27.28 97.66,28.91 98.45,28.91 99.02,29.49 99.02,31.25 101.42,33.65 101.42,36.18
  BOTTOM w0.102: UC1.AP16 105.88,37.6 v2(105.59,37.95)
IR_CAM_DETECT#: length 136.7
  IN2 w0.127: v2(222.97,33.55) 223.16,33.74 223.16,40.28 221.51,41.93 219.41,41.93 218.78,42.56 218.78,43.65 218.33,44.09 215.73,44.09 215.03,44.79 210.01,44.79 208.17,42.95 200.63,42.95 197.89,45.69 193.51,45.69 192.87,46.33 186.47,46.33 184.02,43.89 183.04,43.89 181.19,42.04 180.27,42.04 177.4,39.17 174.3,39.17 173.38,38.25 164.32,38.25 163.56,39.01 162.2,39.01 162.01,38.82 160,38.82 159.27,38.09 154,38.09 153.27,38.82 151.4,38.82 150.96,39.26 147.17,39.26 146.39,38.48 144.86,38.48 144.72,38.33 142.55,38.33 141.68,37.46 140.86,37.46 139.47,36.07 134.21,36.07 133.56,35.42 130.66,35.42 128.96,33.72 123.75,33.72 122.45,32.41 122.45,31.41 122.11,31.08 119.84,31.08 119.74,30.97 v2(117.03,30.97)
  BOTTOM w0.076: RC64.2 120.85,25.61 v1(120.04,26.41) 119.77,26.69 119.77,27.02 118.98,27.81 117.58,27.81 117.53,27.86 117.53,27.86 116.96,28.43 116.96,30.63 117.03,30.69 v2(117.03,30.97) 116.75,30.97 116.27,30.49 UC1.P4
  BOTTOM w0.102: JEDP1.34 222.97,33.55 v2(222.97,33.55)
IR_GND: length 5.6
  TOP w0.508: v2(227.03,38.7) v3(227.03,40.77) 226.67,41.13 225.97,41.13 225.26,41.84 224.24,41.84 R54.1
ISEN1_VGA: length 12.8
  TOP w0.203: PC1120.2 51.03,118.76 v2(51.03,119.34) 51.21,119.53 52.01,119.53 52.69,120.21 PU1100.13
  TOP w0.254: v2(50.37,111.97) 50.74,111.61 v1(51.04,111.61) 51.3,111.61 PR1124.1
  BOTTOM w0.254: v2(50.37,111.97) 50.37,118.68 v2(51.03,119.34)
ISEN2_VGA: length 5
  TOP w0.203: PU1100.12 52.29,120.28 51.84,119.83 50.8,119.83 50.18,119.21 PC1119.2
  TOP w0.254: PR1104.1 49.12,117.82 50.02,118.72 PC1119.2
ISOLATE#: length 3.1
  BOTTOM w0.102: UL1.20 34.55,119.39 34.63,119.47 34.63,120.47 RL3.2 RL4.1
ISUMN_GT: length 48.3
  TOP w0.254: v2(171.79,56.6) 171.74,56.56 171.03,56.56 PR632.1 170.69,56.22 PR638.1
  IN3 w0.254: v2(171.79,56.6) 171.91,56.73 171.91,57.84 171.44,58.32 171.44,66.43 164.13,73.73 164.13,77.27 165.31,78.45 165.31,83.18 163.68,84.8 155.67,84.8 v2(155.49,84.63)
  BOTTOM w0.254: PC624.2 PC626.2 PR633.2 170.2,55.85 PR673.2 PC641.1 171.48,56.6 v2(171.79,56.6) ; v2(155.49,84.63) 155.49,83.98 PH602.2
ISUMN_IA: length 27.2
  TOP w0.254: PR640.2 PR644.2 157.93,58.49 157.88,58.54 157.88,59.22 v2(157.92,59.26) 157.88,59.3 v1(157.06,59.3) 156.69,59.3 156.05,59.94 154.99,59.94 149.94,64.98 149.94,68.93 149.9,68.97 149.9,69.07 v2(149.8,69.17)
  BOTTOM w0.254: PR656.2 PC642.2 PC646.2 157.45,57.62 PC645.1 157.44,57.81 157.84,58.22 157.84,59.18 v2(157.92,59.26) ; PL603.2 149.18,71.21 149.8,70.59 v2(149.8,69.17) PH605.2
ISUMN_VSA: length 28.1
  TOP w0.254: PR641.2 PC637.2 PR643.1 PC633.2 ; PR641.2 157.89,51.01 PR636.2 ; PR641.2 157.88,51.02 156.99,50.13 PC644.1 156.61,49.73 156.61,49.42 155.91,48.72 155.91,48.66 154.96,47.71 153.41,47.71 152.45,48.66 v3(147.62,48.66) 143.56,48.66 143.56,48.66 143.25,48.66 141.63,50.28 141.63,51.39 v2(141.56,51.45)
  BOTTOM w0.254: PH604.2 141.56,49.46 v2(141.56,51.45) 141.56,52.35 141.18,52.73 PL601.2
ISUMP_GT: length 8.8
  TOP w0.203: v2(168.23,54.38) 167.57,53.72 PU602.7
  BOTTOM w0.102: v1(172.52,54.43) PR628.1
  BOTTOM w0.254: PR674.1 168.46,56.28 167.93,55.75 PR637.1 168.23,54.9 v2(168.23,54.38) 168.28,54.43 PC624.1 PC626.1 PR633.1 PR628.1
ISUMP_IA: length 9.1
  TOP w0.203: PU602.19 163.08,56.11 162.77,56.43 v2(162.43,56.43)
  BOTTOM w0.254: PR661.2 158.58,58.27 PC646.1 PC642.1 PR656.1 159.85,55.84 160.1,56.09 PR657.1 PR653.1 161.92,57.1 v1(161.93,57.09) 162.43,56.59 v2(162.43,56.43)
ISUMP_VSA: length 9.3
  TOP w0.203: PU602.27 160.74,52.52
  TOP w0.254: PR642.1 155.03,51.03 PR624.2 155.02,51.59 v1(155.79,52.35) 156.24,52.81 PR654.1 PC637.1 PR643.2 PC633.1 159.7,52.81 159.99,52.52 160.74,52.52
JACK_PLUG: length 8.2
  TOP w0.254: JHP1.5 11.55,24.57 ZT20.1
  BOTTOM w0.254: JHP1.5 13.98,23.02 14.5,22.5 14.5,20.47 14.75,20.22 RA39.2
JACK_PLUG_DET: length 10.7
  TOP w0.102: JHP1.6 8.8,25.02 ZT21.1
  BOTTOM w0.254: JHP1.6 9.55,23.77 14.18,23.77 15.12,22.83 RA40.1
JTAG_TCK: length 9.3
  TOP w0.102: RV369.1 115.15,98.95 115.72,98.38 v3(116.44,98.38) 116.72,98.38 v2(116.98,98.64)
  BOTTOM w0.102: UV1.L3 117.26,103.98 116.87,103.59 116.87,101.87 117.09,101.66 117.09,98.74 v2(116.98,98.64)
JTAG_TDI_GPU: length 8.7
  BOTTOM w0.102: RP34.7 116.98,97.62 117.75,98.4 117.75,101.81 v1(117.48,102.08) 117.33,102.23 117.33,103.16 117.56,103.39 117.56,103.69 117.55,103.71 117.55,104.13 117.56,104.14 117.56,104.81 UV1.L5
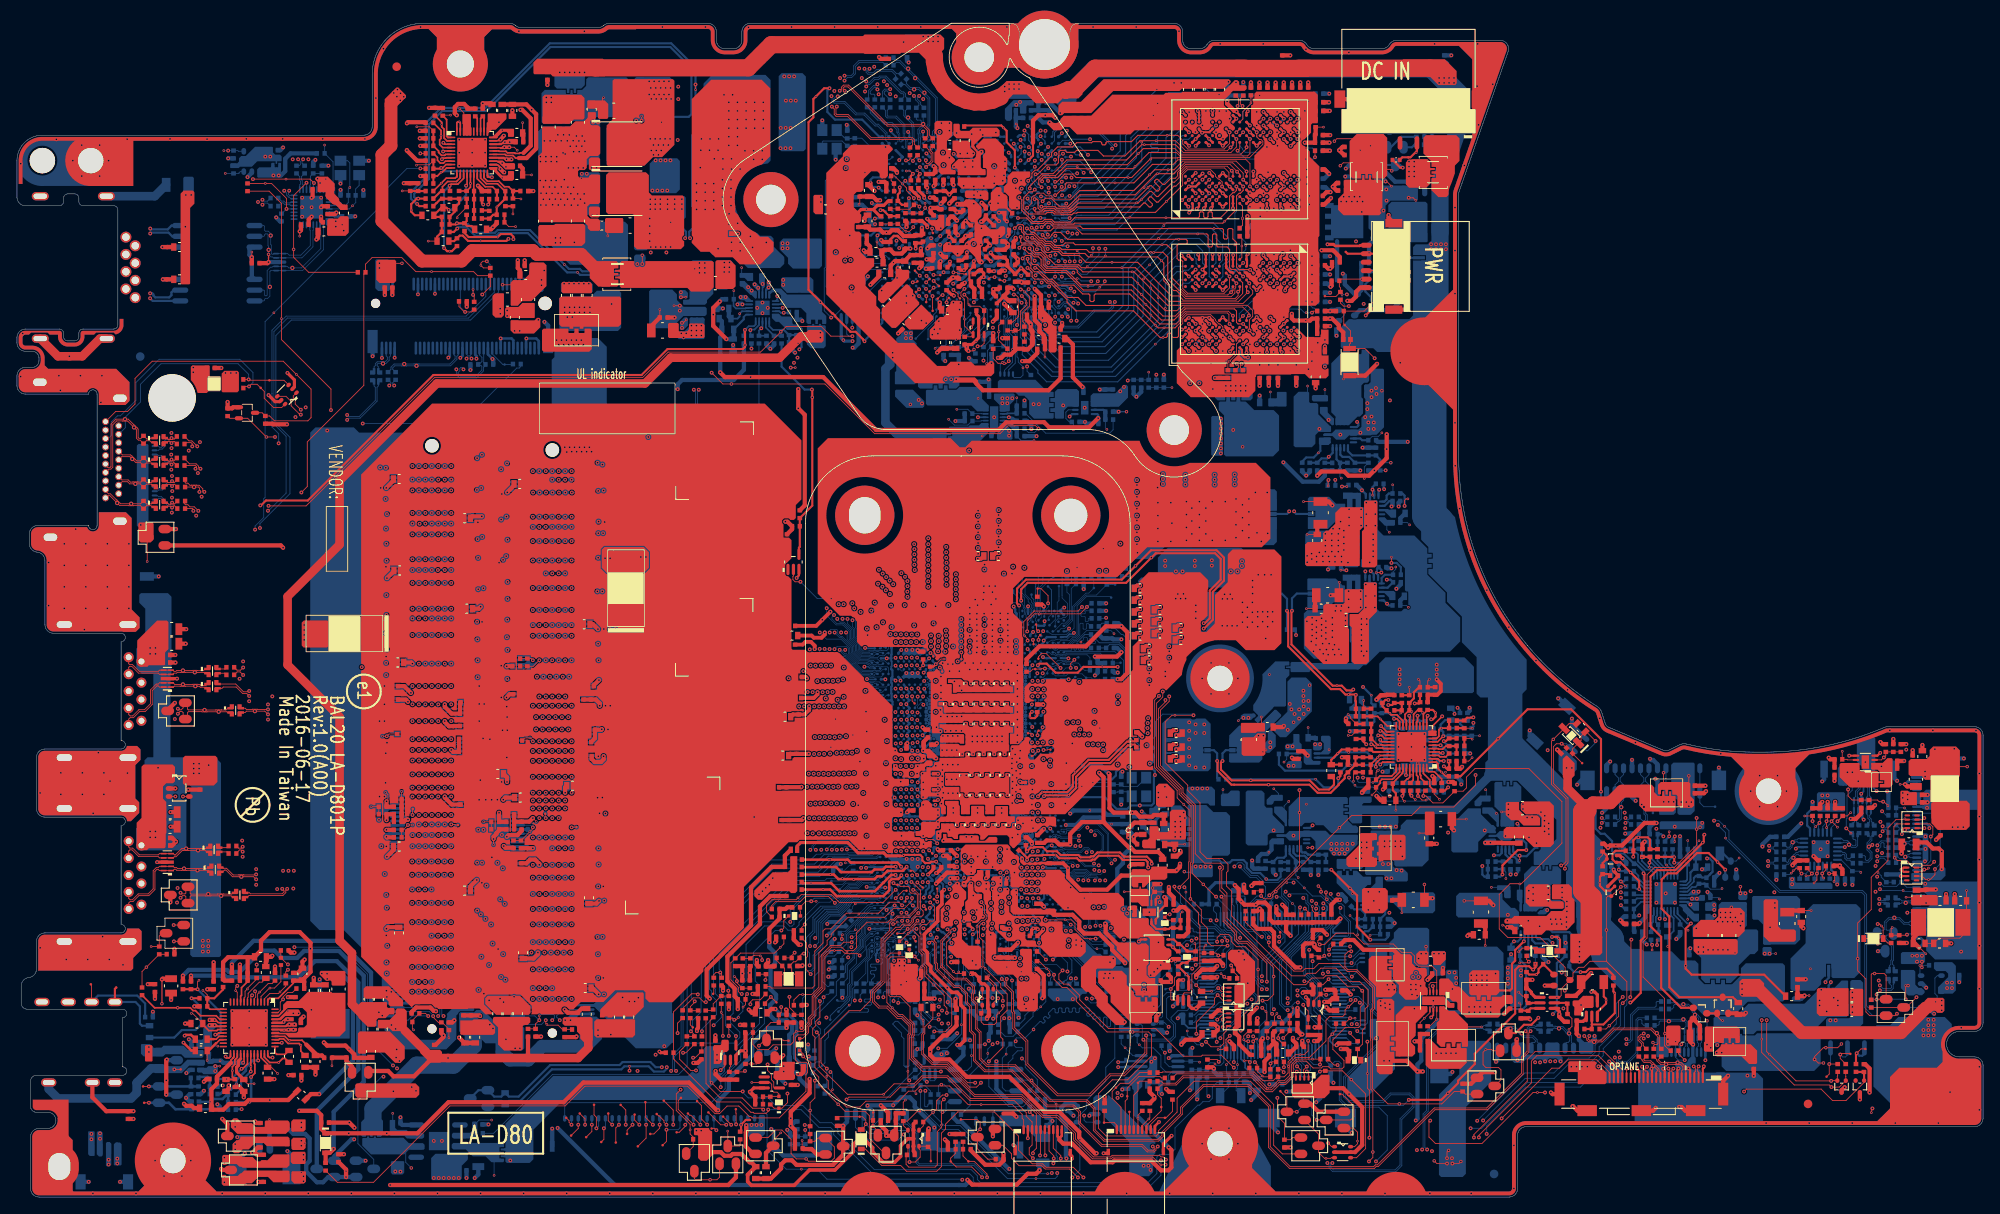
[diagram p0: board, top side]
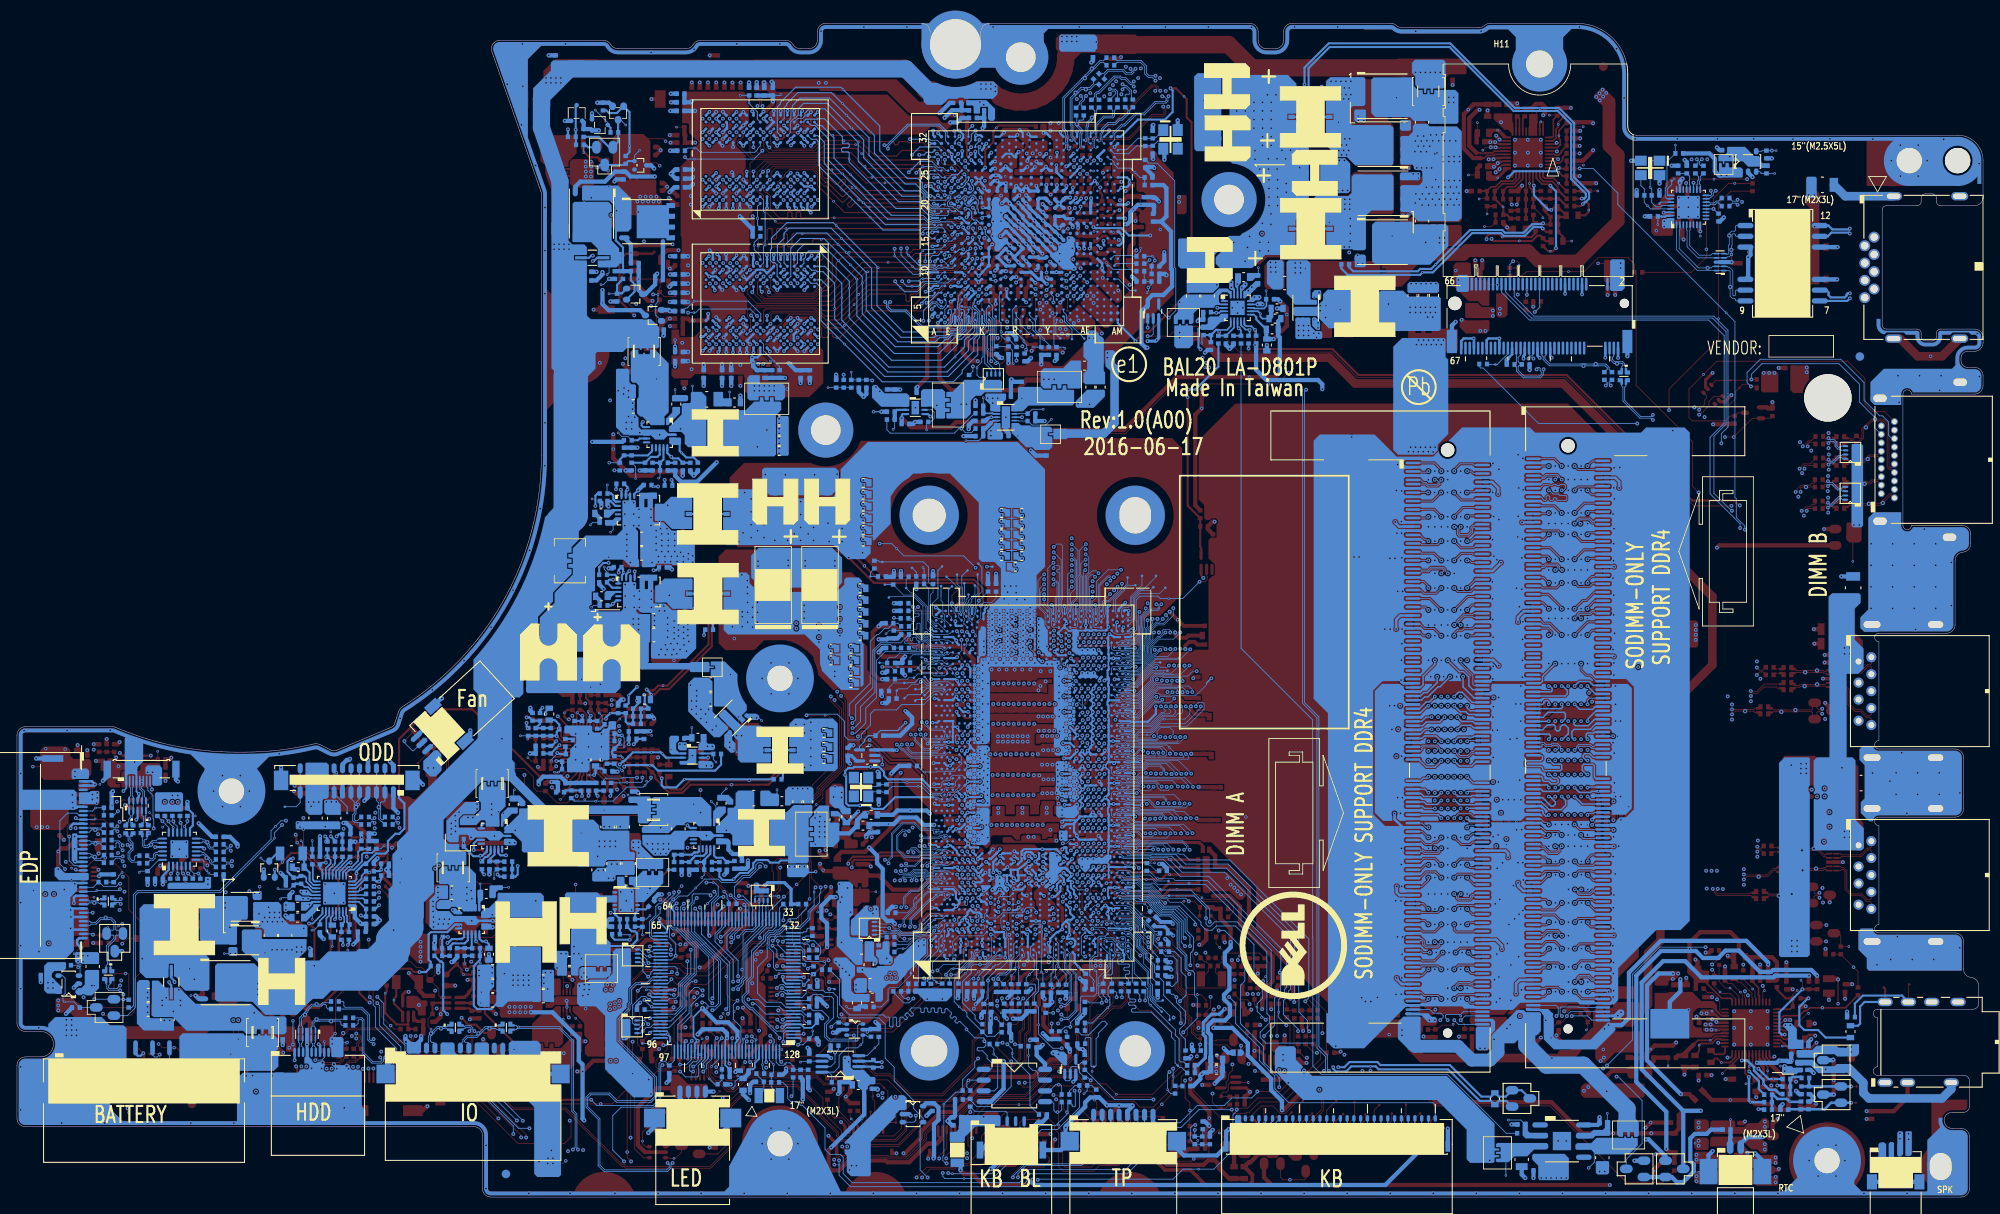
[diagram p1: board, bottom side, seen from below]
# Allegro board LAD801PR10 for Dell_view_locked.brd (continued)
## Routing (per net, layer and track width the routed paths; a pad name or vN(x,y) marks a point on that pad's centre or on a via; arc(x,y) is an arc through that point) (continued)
JTAG_TDO_GPU: length 10
  BOTTOM w0.102: UV1.K4 117.83,104.49 117.83,104.12 117.75,104.04 117.75,103.79 117.77,103.78 117.77,103.31 117.56,103.1 117.56,102.74 117.95,102.34 117.95,99.14 118.11,98.99 118.11,98.53 118.66,97.98 v1(118.66,97.85) 118.66,96.99 118.37,96.7 117.62,96.7 117.48,96.84 RP34.8
JTAG_TMS_GPU: length 7
  BOTTOM w0.102: UV1.L1 117.1,103.36 117.1,101.93 117.42,101.61 v1(117.42,100.02) 117.42,99.87 117.42,99.87 117.42,98.5 116.48,97.56 RP34.6
JTAG_TRSTB: length 9.5
  BOTTOM w0.102: RP34.5 115.98,98.21 v1(116.26,98.49) 116.86,99.09 116.86,101.6 116.64,101.81 116.64,103.65 116.83,103.84 116.83,105.17 117.26,105.6 UV1.L6
KB_BL_CTRL#: length 9.7
  TOP w0.102: EC3001.1 114.5,4.47 113.28,5.7 Q8.1 113.28,7.67 v2(113.61,8) 113.61,8.79 113.24,9.16 ZT52.1
  BOTTOM w0.102: v2(113.61,8) 113.2,8 113.11,8.09 JKBBL1.4
KB_DET#: length 52.8
  TOP w0.102: RC45.1 88.23,22.93 v2(88.92,23.61) 88.93,23.61 ZT24.1
  IN3 w0.142: v2(88.92,23.61) 89.21,23.61 90.24,24.64 92.96,24.64 94.33,26.01 94.8,26.01 95.21,26.42 95.99,26.42 97.86,28.29 v2(98.04,28.29)
  BOTTOM w0.076: UC1.BB7 100.35,32.24 99.95,31.84 99.95,31.08 99.34,30.46 99.34,29.74 98.04,28.44 v2(98.04,28.29)
  BOTTOM w0.102: v2(88.92,23.61) 88.16,22.85 88.16,20.46 85.36,17.67 85.36,16.11 83.54,14.28 83.54,12.79 81.88,11.14 64.86,11.14 64.61,10.88 JKB1.30
KB_LED_BL_DET: length 29.9
  TOP w0.102: v2(114,32.26) 113.79,32.26 113.54,32.01 113.54,30.65 113.94,30.25 113.94,27.25 v1(114.2,26.99) 116.03,25.15 116.03,24.72 116.8,23.96 116.8,22.04 116.03,21.27 116.03,18.88 116.29,18.63 116.29,17.66 v2(114.64,16.01)
  BOTTOM w0.076: UC1.W8 113.66,32.26 v2(114,32.26)
  BOTTOM w0.102: v2(114.64,16.01) 114.64,13.04 116.99,10.69 118.7,10.69 119.11,11.11 119.12,11.11 119.46,11.45 R26.1 120.26,11.59 R27.1
KB_LED_DET_C: length 6.8
  TOP w0.102: ZT51.1 119.82,9.67 v2(119.45,10.04)
  BOTTOM w0.102: JKBBL1.2 115.11,9.95 115.27,10.11 118.9,10.11 R26.2 119.46,10.04 v2(119.45,10.04)
KB_LED_PWM: length 87.2
  TOP w0.102: v2(125.14,2.31) 124.14,3.31 121.29,3.31 121.15,3.45 121.11,3.45 120.86,3.7 118.19,3.7 117.3,4.59 117.3,5.1 116.3,6.11 Q8.2 ; v2(159.47,4.21) 159.92,4.66 v3(159.92,5.31) 159.92,12.48 159.69,12.72 159.69,18.51 159.65,18.55 159.65,22.04 159.91,22.31 159.91,24.68 157.96,26.62 156.9,26.62 155.96,27.56 153.56,27.56 152.95,26.96 151.95,26.96 151.65,26.66 150.62,26.66 147.66,29.62 v2(147.66,30.06)
  IN1 w0.119: v2(159.47,4.21) 156.63,1.37 126.08,1.37 v2(125.14,2.31)
  BOTTOM w0.102: v2(147.66,30.06) 147.34,30.38 147.34,30.39 147.25,30.48 147.25,30.97 146.36,31.86 UE1.44
KSI0: length 110.9
  TOP w0.102: RPE1.4 142.79,20.18 142.64,20.03 142.64,19.61 142.35,19.32 142.35,18.14 141.94,17.73 140.83,17.73 v2(140.24,18.32) ; v2(71.01,8.53) 70.63,8.16 ZT32.1
  IN1 w0.119: v2(71.01,8.53) 75.84,3.7 95.02,3.7 95.77,2.95 109.45,2.95 112.15,5.65 118.58,5.65 119.47,6.55 119.47,6.55 119.71,6.79 129.43,6.79 133.59,10.94 134.9,10.94 136.27,12.31 136.27,13.47 138.87,16.08 138.87,16.48 140.24,17.85 v2(140.24,18.32) 140.24,18.32 140.24,18.98 140.56,19.3 140.56,20.5 141.41,21.35 144.45,21.35 145.01,21.91 147.05,21.91 147.07,21.93 147.39,22.25 147.39,22.36 149.41,24.38 v2(151.02,24.38)
  BOTTOM w0.102: JKB1.22 v2(71.01,8.53) ; UE1.98 153.96,20.33 152.62,21.67 152.62,24.07 151.98,24.72 151.49,24.72 151.16,24.38 v2(151.02,24.38)
KSI1: length 107.4
  TOP w0.102: v2(69.23,8.11) 69.23,6.8 ZT30.1 ; v2(142.23,20.06) 142.23,20.25 142.66,20.68 RPE1.3
  IN1 w0.119: v2(151.05,23.79) 151,23.79 150.66,24.13 149.51,24.13 147.64,22.26 147.64,22.15 147.15,21.67 145.11,21.67 144.38,20.94 144.37,20.94 143.49,20.06 v2(142.23,20.06) 142.23,19.93 141.1,18.8 141.1,17.77 139.58,16.25 139.58,15.78 137.01,13.2 137.01,12 135.29,10.28 133.86,10.28 129.66,6.07 120.04,6.07 119.31,5.35 117.99,4.02 115.84,4.02 115.39,4.48 111.98,4.48 109.72,2.21 95.46,2.21 94.71,2.96 74.38,2.96 v2(69.23,8.11)
  BOTTOM w0.102: UE1.99 153.56,20.21 152.39,21.38 152.39,22.64 151.25,23.79 v2(151.05,23.79) ; v2(69.23,8.11) 69.41,8.29 JKB1.24
KSI2: length 92.8
  TOP w0.102: v2(142.23,20.93) 142.47,21.18 RPE1.2 ; ZT28.1 67.81,7.73 v2(67.81,8.53)
  IN1 w0.119: v2(142.23,20.93) 141.77,20.48 141.39,20.48 141.05,20.14 141.05,19.1 140.88,18.93 140.88,17.86 139.36,16.35 139.36,15.87 136.76,13.27 136.76,12.1 135.16,10.5 133.77,10.5 129.59,6.32 119.94,6.32 119.07,5.45 117.89,4.27 115.94,4.27 115.49,4.72 111.92,4.72 109.65,2.46 95.56,2.46 94.82,3.21 74.88,3.21 69.36,8.72 68,8.72 v2(67.81,8.53)
  BOTTOM w0.102: UE1.6 141.16,20.78 141.35,20.59 141.36,20.59 141.42,20.53 141.82,20.53 v2(142.23,20.93) ; JKB1.26 v2(67.81,8.53)
KSI3: length 89.2
  TOP w0.102: ZT31.1 69.74,9 v2(70.21,8.53) ; RPE1.1 142.37,21.68 142.28,21.59 142.24,21.59 v2(141.58,20.93)
  IN1 w0.119: v2(141.58,20.93) 141.5,20.93 140.81,20.24 140.81,19.2 140.66,19.05 140.66,17.95 139.12,16.41 139.12,15.97 136.52,13.37 136.52,12.21 135.03,10.72 133.68,10.72 129.52,6.56 119.84,6.56 118.82,5.55 117.79,4.52 116.04,4.52 115.59,4.97 111.81,4.97 109.55,2.71 95.66,2.71 94.92,3.45 75.29,3.45 v2(70.21,8.53)
  BOTTOM w0.102: JKB1.23 v2(70.21,8.53) ; UE1.7 141.33,21.18 v2(141.58,20.93)
KSI4: length 103.2
  TOP w0.102: v2(152.14,14.81) 152.34,14.61 RPE2.1 ; ZT27.1 67.01,9.23 v2(67.01,8.53)
  IN1 w0.119: v2(152.14,14.81) 152.02,14.81 151.53,15.31 151.53,15.64 151.32,15.85 150.82,15.85 150.57,15.6 150.57,15.31 149.55,14.29 147.43,14.29 146.8,13.66 141.93,13.66 141.88,13.6 140.97,13.6 139.66,12.29 139.66,11.38 139.26,10.99 138.66,10.99 135.45,7.78 133.87,7.78 129.4,3.31 126.71,3.31 126.35,3.67 122.84,3.67 122.5,3.32 121.67,3.32 121.1,2.75 116.42,2.75 115.18,3.99 112.19,3.99 109.92,1.72 73.37,1.72 67.01,8.08 v2(67.01,8.53)
  BOTTOM w0.102: JKB1.27 v2(67.01,8.53) ; v2(152.14,14.81) 152.42,14.81 152.55,14.94 152.55,15.58 152.17,15.96 151.79,15.96 151.56,16.18 UE1.104
KSI5: length 101.9
  TOP w0.102: v2(68.34,8.11) 68.34,9.42 68.07,9.7 ZT29.1 ; v2(152.14,15.4) 151.73,14.99 151.73,14.65 151.84,14.53 RPE2.2
  IN1 w0.119: v2(152.14,15.4) 151.42,16.12 149.06,16.12 148.29,15.34 146.98,15.34 145.54,13.9 140.92,13.9 138.64,11.62 138.64,11.28 135.36,8 133.77,8 129.3,3.53 126.8,3.53 126.44,3.89 122.75,3.89 122.4,3.55 121.59,3.55 121.33,3.8 115.75,3.8 115.72,3.83 115.69,3.83 115.28,4.23 112.08,4.23 109.82,1.97 95.36,1.97 94.61,2.71 73.04,2.71 68.34,7.41 v2(68.34,8.11)
  BOTTOM w0.102: v2(68.34,8.11) 68.61,8.38 JKB1.25 ; UE1.105 151.16,16.26 152.02,15.4 v2(152.14,15.4)
KSI6: length 101.3
  TOP w0.102: ZT26.1 66.21,8.1 v2(66.21,8.53) ; RPE2.3 151.34,14.62 151.37,14.65 151.37,15.04 v2(150.98,15.42)
  IN1 w0.119: v2(66.21,8.53) 73.27,1.47 110.02,1.47 112.29,3.74 115.08,3.74 116.4,2.42 122.87,2.42 123.9,3.45 126.26,3.45 126.62,3.09 129.49,3.09 133.96,7.56 135.54,7.56 138.75,10.77 139.35,10.77 139.88,11.29 139.88,12.2 141.06,13.38 146.87,13.38 147.53,14.04 149.62,14.04 150.98,15.41 v2(150.98,15.42)
  BOTTOM w0.102: v2(150.98,15.42) 150.98,15.73 150.36,16.35 UE1.107 ; JKB1.28 v2(66.21,8.53)
KSI7: length 101.5
  TOP w0.102: v2(150.96,14.8) 150.84,14.69 RPE2.4 ; ZT25.1 65.12,9.02 65.12,8.82 v2(65.41,8.53)
  IN1 w0.119: v2(150.96,14.8) 149.96,13.8 147.64,13.8 147,13.16 141.15,13.16 140.1,12.11 140.1,11.2 139.44,10.55 138.84,10.55 135.63,7.34 134.05,7.34 129.58,2.87 126.53,2.87 126.17,3.23 124.03,3.23 123,2.2 116.27,2.2 114.98,3.49 112.37,3.49 110.1,1.23 72.71,1.23 v2(65.41,8.53)
  BOTTOM w0.102: v2(150.96,14.8) 150.54,15.22 150.54,15.7 149.96,16.28 UE1.108 ; JKB1.29 v2(65.41,8.53)
KSO0: length 89.4
  TOP w0.102: v2(139.11,19.26) 139.11,20.63 141.24,22.76 141.24,23.45 v2(141.62,23.83) 142.25,23.2 RPE3.8 ; v2(76.61,7.95) 76.61,6.56 ZT41.1
  IN1 w0.119: v2(76.61,7.95) 79.38,5.18 109.62,5.18 111.99,7.55 113.88,7.55 115.12,8.78 120.12,8.78 120.69,8.21 128.98,8.21 136.84,16.07 136.84,18.22 137.9,19.29 137.9,19.69 139.08,20.87 139.08,21.11 141.62,23.65 141.62,23.83 v2(141.62,23.83)
  BOTTOM w0.102: JKB1.13 78.21,8.17 77.98,7.95 v2(76.61,7.95) ; UE1.2 139.18,19.18 v2(139.11,19.26)
KSO1: length 82.8
  TOP w0.102: ZT39.1 75.66,9.59 75.73,9.59 76.32,9 76.32,8.82 v2(76.61,8.53) ; RPE3.7 142.39,23.7 v2(142.26,23.84)
  IN1 w0.119: v2(76.61,8.53) 76.66,8.53 79.77,5.42 109.51,5.42 113.09,9 120.21,9 120.78,8.43 128.89,8.43 136.62,16.16 136.62,18.35 137.66,19.39 137.66,19.79 138.83,20.97 138.83,21.21 140.48,22.86 140.48,23.28 141.45,24.24 141.85,24.24 v2(142.26,23.84)
  BOTTOM w0.102: v2(142.26,23.84) 141.86,24.24 141.45,24.24 141.31,24.09 141.2,23.98 UE1.14 ; JKB1.15 v2(76.61,8.53)
KSO2: length 83.7
  TOP w0.102: RPE3.6 142.47,24.2 142.43,24.24 142.1,24.24 v2(141.68,24.66) ; ZT40.1 77.41,10.26 v2(77.41,8.53)
  IN1 w0.119: v2(141.68,24.66) 141.52,24.66 139.77,22.91 139.12,22.91 138.45,22.24 138.45,21.54 138.45,20.93 137.41,19.89 137.41,19.49 136.39,18.48 136.39,16.25 128.8,8.66 123.04,8.66 122.3,9.39 118.97,9.39 118.46,9.89 117.7,9.89 117.03,9.22 112.97,9.22 109.41,5.67 80.27,5.67 v2(77.41,8.53)
  BOTTOM w0.102: v2(141.68,24.66) 141.55,24.66 141.27,24.38 UE1.15 ; JKB1.14 v2(77.41,8.53)
KSO3: length 85.1
  TOP w0.102: RPE3.5 142.3,24.7 v2(142.27,24.67) ; ZT38.1 75.13,7.45 75.81,8.13 v2(75.81,8.53)
  IN1 w0.119: v2(142.27,24.67) 142.02,24.92 142.02,24.92 141.85,25.08 141.51,25.08 140.73,24.3 140.73,24.22 139.66,23.16 139.02,23.16 138.2,22.35 138.2,21.44 138.2,21.03 137.16,19.99 137.16,19.59 135.59,18.02 135.59,17.96 134.86,17.22 134.86,16.04 132.08,13.27 132.08,12.25 128.71,8.88 123.13,8.88 122.37,9.64 120.44,9.64 119.62,10.45 117.95,10.45 116.94,9.44 112.87,9.44 109.34,5.92 80.61,5.92 77.58,8.95 76.22,8.95 v2(75.81,8.53)
  BOTTOM w0.102: JKB1.16 v2(75.81,8.53) ; UE1.16 141.23,24.78 141.51,25.07 141.87,25.07 v2(142.27,24.67)
KSO4: length 101.7
  TOP w0.102: v2(72.61,8.53) 71.97,7.89 ZT34.1
  IN1 w0.119: v2(72.61,8.53) 76.95,4.19 100.98,4.19 101.58,3.59 101.72,3.45 109.24,3.45 111.94,6.15 115.04,6.15 116.75,7.85 119.73,7.85 120.32,7.25 129.27,7.25 133.4,11.38 134.27,11.38 134.63,11.74 134.63,12.46 138.43,16.26 138.43,16.66 139.14,17.37 139.14,18.59 140.07,19.52 140.07,20.7 141.83,22.47 143.66,22.47 145.26,24.07 146.08,24.07 146.35,24.34 146.66,24.34 v2(146.84,24.52)
  BOTTOM w0.102: v2(146.84,24.52) 146.19,25.18 146.19,25.48 145.8,25.87 145.8,29.8 143.56,32.04 UE1.37 143.56,34.33 143.35,34.54 RPE4.8 ; JKB1.20 v2(72.61,8.53)
KSO5: length 104.9
  TOP w0.102: v2(71.81,8.53) 71.81,10.27 ZT33.1
  IN1 w0.119: v2(71.81,8.53) 76.4,3.94 100.87,3.94 101.33,3.49 101.62,3.2 109.34,3.2 112.04,5.9 115.15,5.9 116.87,7.63 119.64,7.63 120.23,7.03 129.36,7.03 133.5,11.16 134.81,11.16 136.05,12.4 136.05,13.57 138.65,16.17 138.65,16.57 139.36,17.28 139.36,18.5 140.31,19.45 140.31,20.6 141.31,21.6 143.14,21.6 145.36,23.82 146.18,23.82 146.45,24.1 147,24.1 147.42,24.52 v2(147.42,24.52)
  BOTTOM w0.102: JKB1.21 v2(71.81,8.53) ; RPE4.7 143.85,34.61 143.96,34.5 UE1.38 143.96,32.04 146.03,29.97 146.03,25.96 146.41,25.58 146.41,25.33 146.81,24.93 147.02,24.93 v2(147.42,24.52)
KSO6: length 99.7
  TOP w0.102: v2(74.21,8.53) 74.21,6.96 ZT36.1
  IN1 w0.119: v2(146.84,25.47) 146.79,25.47 145.87,24.56 145.06,24.56 143.46,22.96 141.63,22.96 139.57,20.91 139.57,20.66 138.39,19.48 138.39,19.08 137.98,18.67 137.98,17.72 137.66,17.39 137.66,16.26 129.14,7.75 120.53,7.75 119.93,8.34 115.3,8.34 114.29,7.33 114.02,7.05 112.19,7.05 109.82,4.68 78.06,4.68 v2(74.21,8.53)
  BOTTOM w0.102: JKB1.18 v2(74.21,8.53) ; v2(146.84,25.47) 146.26,26.06 146.26,30.98 145.88,31.35 145.02,31.35 144.36,32.02 UE1.39 144.35,32.82 RPE4.6
KSO7: length 114
  TOP w0.102: ZT35.1 72.85,9.09 v2(73.41,8.53) ; v2(147.42,25.42) 147.42,27.58 145.05,29.95 144.01,29.95 143.64,30.32 143.64,31.17 142.26,32.55 142.26,35.26 v2(142.07,35.45)
  IN1 w0.119: v2(73.41,8.53) 77.5,4.44 101.08,4.44 101.82,3.69 109.14,3.69 112.26,6.81 114.08,6.81 114.52,7.24 115.39,8.12 119.84,8.12 120.46,7.5 129.21,7.5 137.88,16.17 137.88,17.3 138.2,17.62 138.2,18.58 138.69,19.07 138.69,19.43 139.82,20.56 139.82,20.8 141.73,22.72 143.56,22.72 145.16,24.32 145.98,24.32 146.25,24.59 146.26,24.59 146.73,25.06 147.07,25.06 v2(147.42,25.42)
  BOTTOM w0.102: v2(142.07,35.45) 142.14,35.52 144.75,35.52 144.85,35.42 RPE4.5 ; JKB1.19 v2(73.41,8.53) ; v2(147.42,25.42) 147.42,27.99 149.56,30.12 149.56,31.08 148.76,31.88 UE1.50
KSO8: length 111.4
  TOP w0.102: ZT37.1 74.12,9.42 v2(75.01,8.53)
  IN1 w0.119: v2(75.01,8.53) 78.61,4.93 109.72,4.93 112.09,7.3 113.95,7.3 114.07,7.42 114.07,7.42 115.21,8.56 120.03,8.56 120.59,7.99 129.07,7.99 137.43,16.35 137.43,17.48 137.76,17.81 137.76,18.8 138.15,19.18 138.15,19.58 139.33,20.76 139.33,21.01 141.53,23.21 143.36,23.21 144.96,24.82 145.6,24.82 146.67,25.89 146.67,25.89 v2(146.84,26.06) 150.77,26.06 150.94,25.88 153.61,25.88 155.02,24.47 155.02,24 156.48,22.53 156.48,20.81 156.89,20.4 v2(157.44,20.4)
  BOTTOM w0.102: JKB1.17 v2(75.01,8.53) ; v2(146.84,26.06) 146.84,27.91 148.16,29.23 148.16,30.77 147.16,31.77 UE1.46 ; v2(157.44,20.4) 157.87,20.84 RPE6.8
KSO9: length 91.7
  TOP w0.102: ZT47.1 83.01,8.53 v2(83.66,8.53) ; RE15.1 155.26,29.7 v2(154.75,29.19)
  IN1 w0.119: v2(154.75,29.19) 154.33,29.19 154.04,28.9 153.8,28.9 153.37,28.47 153.37,27.7 153.08,27.41 152.45,27.41 151.85,28.02 142.09,28.02 142,27.93 141.29,27.93 139.96,26.6 139.96,26.17 139.21,25.42 138.96,25.42 138.96,25.42 138.91,25.42 136.73,23.24 136.49,23.24 135.78,22.53 135.78,21.65 134.12,19.99 134.12,18.36 132.42,16.66 132.42,15.5 130.85,13.93 130.11,13.93 128.85,12.67 128.85,11.73 128.21,11.09 120.97,11.09 120.13,11.93 117.5,11.93 116.33,10.77 111.09,10.77 109.15,8.83 105.52,8.83 104.92,8.23 102.21,8.23 101.37,7.39 84.79,7.39 83.66,8.52 v2(83.66,8.53)
  BOTTOM w0.102: v2(83.66,8.53) 83.01,9.18 JKB1.7 ; UE1.68 155.01,29.98 154.75,29.73 v2(154.75,29.19)
KSO10: length 93
  TOP w0.102: v2(84.83,8.57) 84.83,9.89 84.79,9.92 ZT49.1
  IN1 w0.119: v2(157.25,28.43) 157.22,28.4 156.2,28.4 155.41,29.18 155.41,29.46 155.03,29.85 154.29,29.85 153.84,29.39 153.6,29.39 152.71,28.51 145.66,28.51 145.51,28.65 144.67,29.5 143.98,29.5 143.24,28.76 142.62,28.76 142.41,28.76 141.99,29.17 141.43,29.17 141.04,28.78 141.04,28.55 139.07,26.58 138.82,26.58 138.14,25.91 138.14,25.35 136.52,23.73 136.19,23.73 133.62,21.16 133.62,18.49 131.98,16.85 131.98,15.71 130.63,14.37 129.77,14.37 126.95,11.56 121.16,11.56 120.3,12.42 117.36,12.42 116.15,11.21 110.83,11.21 108.92,9.3 105.33,9.3 105.29,9.26 103.26,9.26 103.1,9.42 89.34,9.42 87.82,7.89 85.44,7.89 84.83,8.51 v2(84.83,8.57)
  BOTTOM w0.102: v2(84.83,8.57) 84.61,8.79 JKB1.5 ; UE1.72 156.78,28.38 156.8,28.4 157.25,28.4 v2(157.25,28.43) 157.65,28.43 158.45,29.22 RPE5.8
KSO11: length 93.2
  TOP w0.102: v2(84.24,8.53) 83.29,9.48 ZT48.1
  IN1 w0.119: v2(84.24,8.53) 85.13,7.64 87.92,7.64 89.45,9.17 103,9.17 103.16,9.01 105.39,9.01 105.43,9.05 109.02,9.05 110.96,10.99 116.24,10.99 117.43,12.18 120.23,12.18 121.1,11.31 127.02,11.31 129.86,14.15 130.76,14.15 132.2,15.59 132.2,16.75 133.87,18.42 133.87,20.09 135.54,21.76 135.54,22.63 136.39,23.48 136.62,23.48 138.39,25.24 138.39,25.8 138.92,26.33 139.18,26.33 141.28,28.44 141.28,28.68 141.53,28.93 141.89,28.93 142.56,28.26 152.82,28.26 153.7,29.14 153.94,29.14 154.4,29.6 154.93,29.6 155.17,29.36 155.17,29.08 156.64,27.62 v2(157.41,27.62)
  BOTTOM w0.102: UE1.74 157.37,27.58 v2(157.41,27.62) 157.6,27.8 157.6,27.99 158.33,28.72 RPE5.7 ; JKB1.6 83.81,8.96 v2(84.24,8.53)
KSO12: length 97.2
  TOP w0.102: v2(78.82,8.53) 78.82,8.35 78.11,7.64 ZT42.1
  IN1 w0.119: v2(78.82,8.53) 79.01,8.34 79.01,8.12 80.96,6.16 108.04,6.16 111.55,9.67 116.85,9.67 117.88,10.7 119.69,10.7 120.5,9.89 122.43,9.89 123.22,9.1 128.61,9.1 131.86,12.34 131.86,13.36 134.64,16.14 134.64,17.32 135.37,18.05 135.37,18.12 136.92,19.66 136.92,20.09 137.96,21.14 137.96,21.34 137.96,22.45 138.7,23.19 138.7,23.2 138.91,23.4 139.56,23.4 140.48,24.33 140.48,24.4 141.41,25.32 143.62,25.32 145.08,26.78 150.39,26.78 151.05,26.13 153.57,26.13 153.8,26.35 v2(154.03,26.35)
  BOTTOM w0.102: RPE5.6 158.4,28.22 157.84,27.66 157.84,27.47 157.55,27.18 UE1.75 154.26,27.18 154.03,26.96 v2(154.03,26.35) ; JKB1.12 79.01,8.71 v2(78.82,8.53)
KSO13: length 98.5
  TOP w0.102: ZT45.1 80.73,10.81 80.73,9.22 v2(81.41,8.54)
  IN1 w0.119: v2(157.45,26.01) 157.19,26.27 155.87,26.27 154.85,27.29 153.68,27.29 153.32,26.92 153.11,26.92 153.11,26.92 152.25,26.92 151.65,27.52 144.44,27.52 143.56,26.65 140.95,26.65 140.45,26.15 140.45,25.96 139.75,25.26 139.75,24.63 139.26,24.14 138.61,24.14 137.96,23.5 137.96,23.5 137.22,22.75 137.22,22.39 134.61,19.78 134.61,18.22 132.98,16.6 132.86,16.48 132.86,15.31 130.95,13.4 130.21,13.4 129.29,12.49 129.29,11.55 128.34,10.6 120.8,10.6 119.96,11.44 117.63,11.44 116.52,10.33 111.27,10.33 108.42,7.47 106.76,7.47 106.44,7.79 102.46,7.79 101.57,6.9 84.38,6.9 82.53,8.76 81.62,8.76 v2(81.41,8.54)
  BOTTOM w0.102: RPE5.5 158.34,27.72 158.07,27.45 158.07,26.63 v2(157.45,26.01) 157.14,26.31 157.14,26.49 156.85,26.78 UE1.76 ; JKB1.9 v2(81.41,8.54)
KSO14: length 97.4
  TOP w0.102: ZT46.1 82.3,8.08 v2(82.49,7.89)
  IN1 w0.119: v2(82.49,7.89) 83.98,6.41 107.98,6.41 111.46,9.89 116.7,9.89 117.76,10.95 119.76,10.95 120.57,10.13 129.34,10.13 131.64,12.43 131.64,13.46 133.3,15.13 133.3,16.29 135.1,18.09 135.1,18.23 136.67,19.8 136.67,20.2 137.71,21.24 137.71,22.55 138.46,23.3 138.46,23.3 138.81,23.65 139.46,23.65 140.24,24.43 140.24,24.5 141.31,25.57 143.52,25.57 144.98,27.03 150.49,27.03 151.15,26.38 153.47,26.38 153.6,26.5 153.89,26.8 154.41,26.8 v2(154.64,26.56) 154.69,26.51 154.76,26.51 155.27,26 155.27,24.34 158.39,21.22 158.39,20.76 v2(158.04,20.41)
  BOTTOM w0.102: v2(82.49,7.89) 82.21,8.18 JKB1.8 ; RPE6.6 158.61,19.84 v2(158.04,20.41) ; v2(154.64,26.56) 154.82,26.38 UE1.77
KSO15: length 102.2
  TOP w0.102: v2(80.61,8.53) 79.49,9.65 79.35,9.65 ZT44.1
  IN1 w0.119: v2(157.31,23.26) 155.53,25.04 155.53,26.26 154.75,27.04 153.79,27.04 153.37,26.62 151.25,26.62 150.6,27.28 144.82,27.28 143.94,26.4 141.05,26.4 140.74,26.09 140.74,25.91 139.99,25.16 139.99,24.53 139.36,23.9 138.71,23.9 138.21,23.4 138.21,23.4 137.46,22.65 137.46,22.29 134.85,19.68 134.85,18.16 133.08,16.39 133.08,15.22 131.42,13.55 131.42,12.53 129.24,10.35 120.7,10.35 119.86,11.19 117.7,11.19 116.61,10.11 111.36,10.11 107.91,6.65 84.32,6.65 82.92,8.05 82.44,8.54 81.99,8.54 81.58,8.12 81.02,8.12 v2(80.61,8.53)
  BOTTOM w0.102: RPE6.7 159.08,20.34 159.28,20.54 159.28,22.62 158.8,23.11 158.8,23.11 158.56,23.35 158.55,23.35 158.24,23.66 157.72,23.66 v2(157.31,23.26) 156.84,22.78 UE1.86 ; JKB1.10 v2(80.61,8.53)
KSO16: length 107.9
  TOP w0.102: v2(79.81,8.53) 78,10.34 78,11.38 ZT43.1
  IN1 w0.119: v2(158.09,19.59) 158.23,19.59 158.87,20.23 158.87,23.13 158.01,23.99 158.01,25.07 158.24,25.31 158.24,25.86 157.48,26.62 155.86,26.62 154.95,27.54 153.58,27.54 153.22,27.17 152.35,27.17 151.75,27.77 142.19,27.77 142.1,27.68 141.39,27.68 140.2,26.49 140.2,26.07 139.5,25.36 139.5,24.73 139.15,24.39 138.5,24.39 137.72,23.6 137.72,23.6 136.97,22.86 136.97,22.49 134.36,19.88 134.36,18.29 132.64,16.57 132.64,15.4 130.86,13.63 130.12,13.63 129.07,12.58 129.07,11.64 128.28,10.85 120.87,10.85 120.03,11.69 117.56,11.69 116.43,10.55 111.18,10.55 109.24,8.61 105.61,8.61 105.02,8.01 102.34,8.01 101.47,7.15 84.45,7.15 82.62,8.98 80.25,8.98 v2(79.81,8.53)
  BOTTOM w0.102: JKB1.11 v2(79.81,8.53) ; UE1.92 156.82,20.38 157.21,20 157.69,20 v2(158.09,19.59) 158.34,19.34 RPE6.5
L_BKLT_CTRL: length 134.9
  IN2 w0.127: v2(200.17,44.41) 199.89,44.41 198.11,46.19 193.67,46.19 191.34,48.51 186.97,48.51 186.06,49.43 181.8,49.43 180.34,50.89 176.24,50.89 172.77,47.42 168.37,47.42 167.96,47.83 163.24,47.83 162.85,47.44 162.85,46.77 160.06,43.99 160.06,43.17 160.14,43.09 160.14,40.22 158.94,39.01 156.21,39.01 155.89,39.33 151.61,39.33 151.17,39.77 146.94,39.77 146.18,39.01 144.99,39.01 144.36,39.64 140.69,39.64 140.59,39.75 133.67,39.75 130.61,36.69 125.39,36.69 124.57,35.86 123.43,35.86 122.26,34.7 120.94,34.7 120.11,33.86 116.47,33.86 116.1,34.23 v2(116.1,34.23)
  BOTTOM w0.102: R8.1 218.36,22.36 218.17,22.55 218.17,35.69 217.68,36.18 207.96,36.18 201.93,42.21 201.93,43.22 v1(201.41,43.75) 200.74,44.41 v2(200.17,44.41) ; v2(116.1,34.23) 115.78,34.23 UC1.R11
L_BKLT_EN_EC: length 81.2
  IN2 w0.127: v2(143.59,39.01) 143.21,39.39 141.56,39.39 141.37,39.2 141.37,38.89 141.03,38.55 133.68,38.55 131.57,36.43 125.5,36.43 124.67,35.61 123.53,35.61 121.73,33.8 120.54,33.8 120.34,33.6 117.04,33.6 116.62,33.18 115.83,33.18 115.34,33.67 115.34,34.25 v2(114.89,34.69)
  IN3 w0.142: v2(114.89,34.69) 115.46,34.12 115.46,33.3 115.91,32.85 115.91,32.13 116.33,31.71 116.33,27.26 115.61,26.53 115.61,25.16 116.25,24.52 116.25,24.13 116.71,23.66 116.71,21.66 116.41,21.36 116.41,21.11 v2(116.44,21.11)
  BOTTOM w0.102: RC6.2 115.74,20.36 116.15,20.77 116.15,20.82 v2(116.44,21.11) ; UC1.R12 115.36,35.17 v2(114.89,34.69) ; v2(143.59,39.01) 144.04,39.45 144.48,39.45 144.75,39.19 144.75,38.74 145.55,37.93 146.34,37.93 147.16,37.12 148.8,37.12 149.2,37.52 150.8,37.52 v1(151.84,36.48) 152.8,35.52 153.79,35.52 154.8,34.52 154.8,32.08 154.47,31.75 154.04,31.75 151.78,29.5 151.78,26.31 153.21,24.88 153.21,22.33 154.76,20.78 UE1.91
LAN_EN: length 240.6
  IN2 w0.127: v2(24.91,123.48) 26.24,122.15 26.24,118.59 34.69,110.14 34.69,32.35 37.61,29.43 37.61,15.2 44.21,8.6 49.75,8.6 51.89,6.46 58.94,6.46 62.72,2.68 109.92,2.68 111.39,4.15 118.13,4.15 119.59,5.61 129.08,5.61 137.02,13.54 140.48,13.54 140.89,13.96 143.66,13.96 143.97,14.27 143.97,17.42 143.59,17.8 141.95,17.8 141.52,18.24 v2(141.52,18.31)
  BOTTOM w0.102: v2(141.52,18.31) 141.5,18.32 141.5,19.29 141.2,19.58 UE1.3 ; UL3.4 26.12,123.4 26.04,123.48 RL6.2 v2(24.91,123.48) v1(24.4,123.48)
LAN_MDI0N: length 15.4
  BOTTOM w0.089: UL1.2 35.75,114.11 35.84,114.03 35.84,111.91 33.56,109.64 v4(32.48,109.64) 32.07,109.64 31.89,109.82 EU3501.8 EU3501.2 30.19,109.82 30.09,109.72 29.9,109.72 29.51,109.33 29.51,106.44 29.43,106.35 29.3,106.35 29.21,106.44 29.21,106.93 29.12,107.02 TL1.5
LAN_MDI0P: length 15.3
  BOTTOM w0.089: UL1.1 36.15,111.78 33.69,109.32 EU3501.9 EU3501.1 29.95,109.32 29.83,109.2 v4(29.83,107.4) 29.83,106.31 29.56,106.03 29.3,106.03 29.21,105.94 29.21,105.83 29.12,105.75 TL1.6
LAN_MDI1N: length 12.6
  BOTTOM w0.089: TL1.1 29.12,114.64 29.21,114.55 29.21,114.06 29.3,113.97 29.65,113.97 29.93,113.69 v4(29.93,113.45) 29.93,112.4 30,112.32 30,111.34 30.09,111.25 30.22,111.25 30.29,111.32 EU3501.5 EU3501.6 31.93,111.32 32.11,111.14 33.48,111.14 34.59,112.26 34.59,114.07 34.55,114.11 UL1.5
LAN_MDI1P: length 12.7
  BOTTOM w0.089: TL1.2 29.12,113.37 29.21,113.45 29.21,113.56 29.3,113.65 29.52,113.65 29.61,113.56 29.61,112.27 29.69,112.19 v4(29.69,111.77) 29.69,111.21 29.96,110.93 30.14,110.93 30.25,110.82 EU3501.4 EU3501.7 33.61,110.82 34.91,112.13 34.91,114.07 34.95,114.11 UL1.4
LAN_TXN_C_PCH_RXN6: length 2.1
  BOTTOM w0.102: UL1.18 33.75,119.45 33.66,119.54 33.66,119.94 33.55,120.04 33.55,120.41 CL2.2
LAN_TXP_C_PCH_RXP6: length 2.1
  BOTTOM w0.102: CL1.2 33.35,120.41 33.35,119.95 33.45,119.85 33.45,119.54 33.35,119.45 UL1.17
LAN_WAKE#: length 33
  TOP w0.089: 103.01,32.41 103.19,32.59 103.49,32.59 103.89,32.99 105.24,32.99 106.38,34.13 106.38,35.74 105.88,36.24 v2(105.71,36.24)
  TOP w0.102: 103.01,32.41 102.94,32.34 102.94,31.45 101.92,30.43 101.92,25.54 100.67,24.28 100.67,23.19 99.46,21.99 98.14,21.99 94.84,18.69 94.84,15.84 v2(95.52,15.16)
  BOTTOM w0.102: RC85.2 95.27,13.1 RC100.2 95.52,13.35 v1(95.52,14.25) v2(95.52,15.16) ; UC1.AM15 106.78,36.24 v2(105.71,36.24)
LANXIN: length 8.5
  BOTTOM w0.102: UL1.28 37.88,117 38.03,116.85 38.58,116.85 39.08,117.35 CL10.1 39.08,118.95 v1(39.26,119.13) 39.26,122.02 39,122.29 YL1.1
LANXOUT: length 6.9
  BOTTOM w0.102: YL1.3 40.36,119.37 39.95,118.95 CL11.1 39.96,118.18 39.96,117.35 v1(39.57,116.97) 39.21,116.6 UL1.29
LCD_BRIGHTNESS: length 8
  TOP w0.102: v2(225.74,42.54) 225.98,42.78 225.98,43.69 225.64,44.03 RP2.2
  BOTTOM w0.102: JEDP1.23 224.7,39.05 224.75,39.1 225.14,39.1 225.74,39.69 v2(225.74,42.54)
LCD_TST: length 153.9
  TOP w0.102: v2(221.74,21.63) 221.53,21.41 D3.3 218.52,21.41 218.08,21.86 218.08,25.74 217.12,26.7 v3(217.12,28.14) 217.12,32.34 218.71,33.93 218.71,37.74 220.68,39.7 220.68,43.58 221.63,44.53 RP2.6
  IN2 w0.127: v2(221.74,21.63) 221.74,24.81 219.03,27.52 219.03,29.13 217.19,30.97 217.19,38.07 214.19,41.07 214.19,41.9 213.38,42.71 209.22,42.71 208.55,42.04 208.54,42.04 208.46,41.95 198.83,41.95 197.99,42.78 196.65,42.78 196.43,43.01 194.05,43.01 192.19,41.15 188.34,41.15 187.75,41.73 183.4,41.73 181.63,39.96 181.63,38.71 183.66,36.68 183.66,32.11 182.91,31.37 182.4,31.37 181.54,30.51 181.54,29.74 181.03,29.23 177.99,29.23 177.06,28.3 177.06,27.73 176.47,27.14 176.47,25.1 175.5,24.13 169.44,24.13 165.93,27.64 163.96,27.64 163.51,27.2 162.33,27.2 160.8,28.72 160.8,30.84 160.8,30.84 160.8,31.05 160.11,31.74 157.45,31.74 157.07,31.37 152.65,31.37 151.55,32.47 143.97,32.47 142.15,30.65 v2(142.15,30.22)
  BOTTOM w0.102: v2(142.15,30.22) 142.15,29.76 141.17,28.78 UE1.26
LCD_TST_C: length 3.3
  TOP w0.102: RP2.3 224.77,44.53 v2(224.96,44.72)
  BOTTOM w0.102: v1(222.68,44.63) 222.76,44.55 JEDP1.12 224.79,44.55 v2(224.96,44.72)
LCD_VCC_TEST_EN: length 2.9
  TOP w0.102: RE64.2 148.06,15.96 v2(147.86,15.76) 147.83,15.73 RE44.2
  BOTTOM w0.102: v2(147.86,15.76) 147.96,15.86 UE1.113
LCD_VCC_TEST_EN_R: length 91.5
  TOP w0.102: v2(222.78,23.34) v1(222.78,24.95) ; RE64.1 v2(149.44,15.32)
  IN2 w0.127: v2(149.44,15.32) 150.38,14.38 158.67,14.38 163.35,9.7 218.79,9.7 219.5,10.41 219.5,18.79 222.78,22.07 v2(222.78,23.34)
  BOTTOM w0.102: D4.3 v2(222.78,23.34)
LCDVDD_EN: length 7.9
  BOTTOM w0.102: D4.1 224.47,22.38 R10.1 225.17,23.03 v1(226.31,23.03) 226.49,23.21 226.49,23.74 226.22,24.01 226.22,25.84 226.51,26.13 U1.4
LDO1_CAP: length 4.4
  TOP w0.203: UA1.27 25.99,16.49 25.78,16.27 25.78,16.26 25.7,16.18 25.7,15.67 25.41,15.37 v1(25.41,14.9) 25.41,14.2 RA41.2
  TOP w0.254: CA20.2 25.66,13.87 RA41.2
LDO2_CAP: length 4.8
  TOP w0.203: CA21.2 33.48,17.21 v1(33.48,17.92) 33.28,18.12 31.99,18.12 31.46,18.66 30.97,18.66 30.87,18.56 UA1.39
LDO3_CAP: length 3.9
  TOP w0.102: UA1.7 27.19,23.51 27.27,23.59 27.27,24.04 28.59,25.36 28.91,25.36 CA22.2
LDO_+1.35VGPU: length 3.6
  BOTTOM w0.254: 153.74,88.86 153.74,88.05 v1(153.5,87.81) 152.96,87.27 152.07,87.27 151.59,86.8 PC1406.1
LDO_+1VALW: length 3.1
  BOTTOM w0.508: 147.97,41.74 147.97,40.99 v1(147.68,40.69) 147.47,40.48 146.79,40.48 146.39,40.07 PC306.1
LED1: length 7.4
  BOTTOM w0.102: UL1.26 37.28,117.8 37.48,118.01 37.48,119.09 37.28,119.29 37.28,122.16 RL1.2 v1(36.29,124.14)
LG1_VGA: length 6.6
  IN1 w1.016: 59.96,122.26 61.11,121.12 63.96,121.12 64.73,120.36 65.74,120.36
  vias: v1(66.58,120.22) v2(57.74,122.45) v2(58.31,122.45) v2(66.63,120.74) v2(67.21,120.74) v2(67.84,115.85) v2(68.42,115.85)
LG2_VGA: length 10.8
  TOP w0.102: v1(59,123.53) 58.66,123.87 v2(58.06,123.87)
  IN1 w1.016: 68.12,122.39 65.3,122.39 63.96,123.72 59.01,123.72
  vias: v2(57.49,123.87) v2(67.77,121.44) v2(67.95,126.8) v2(68.36,121.44) v2(68.54,126.8)
LG_1.2V: length 7.2
  TOP w0.102: v2(78.44,103.15) 78.58,103.15 v1(78.94,103.51)
  IN3 w0.762: 84.63,106.02 84.01,105.4 84.01,104.55 83.04,103.59 79.59,103.59
  vias: v2(78.44,102.56) v2(85.36,106.2) v2(85.95,106.2)
LGATE_CHG: length 6.4
  TOP w0.102: v2(203.28,35.84) v3(203.28,36.62)
  IN3 w0.762: 198.01,37.04 202.9,37.04 203.41,36.53
  vias: v2(197.76,36.03) v2(198.34,36.03) v2(203.87,35.84)
LID_CLOSE#: length 194.7
  TOP w0.102: D5.1 218.87,30.5 v2(219.47,29.9) ; v2(157.1,105.13) 156.46,105.13 156.1,105.49 R22.1 ; v2(172.04,49.8) 172.04,48.6 169.48,46.03 165.5,46.03 164.49,45.01 157.41,45.01 v3(155.98,43.59) 152.33,39.93 152.33,39.89 148.13,35.69 148.13,35.44 147.89,35.2 147.08,35.2 v2(146.75,35.53) 146.77,35.55 CE19.1 146.07,36.14 RE25.2
  IN1 w0.119: v2(172.04,49.8) 172.17,49.93 172.17,55.75 172.2,55.78 172.2,56.13 172.17,56.16 172.17,56.4 172.2,56.43 172.2,56.77 172.17,56.81 172.17,64.32 165.49,71 165.49,99.09 161.56,103.02 158.41,103.02 157.1,104.33 v2(157.1,105.13)
  IN2 w0.127: v2(219.47,29.9) 217.44,31.93 217.44,38.14 214.42,41.16 214.42,42.03 213.51,42.94 209.13,42.94 208.46,42.26 208.44,42.26 208.42,42.24 198.87,42.24 198.07,43.04 196.75,43.04 196.56,43.24 193.95,43.24 192.09,41.38 188.43,41.38 187.85,41.96 183.3,41.96 181.85,40.51 180.91,40.51 177.11,36.72 162.95,36.72 160.66,34.44 158.88,34.44 156.7,32.26 153.02,32.26 151.92,33.36 150.66,33.36 149.82,34.2 149.82,34.77 148.52,36.07 147.57,36.07 147.44,35.94 147.16,35.94 v2(146.75,35.53)
  BOTTOM w0.102: UE1.41 145.16,34.43 146.26,35.53 v2(146.75,35.53)
LID_CLOSE#_C: length 6.7
  TOP w0.102: JPWR1.2 156.17,108.31 EC2902.1 155.98,107.42 156.1,107.29 R22.2 155.57,106.27 154.31,106.27 ZT3.1
LINE1-L_C: length 13.5
  TOP w0.305: CA32.2 20.56,17.3 v2(19.64,18.22)
  IN3 w0.305: v2(26.5,10.37) 26.01,10.37 19.64,16.74 v2(19.64,18.22)
  BOTTOM w0.305: v2(26.5,10.37) 25.88,10.37 RA28.1
LINE1-L_R: length 10.7
  TOP w0.305: CA33.2 20.53,19.13 19.87,19.13 v2(19.78,19.04)
  IN3 w0.305: v2(24.28,13.17) 23.93,13.17 21.74,15.37 21.74,17.93 20.53,19.13 19.87,19.13 v2(19.78,19.04)
  BOTTOM w0.305: RA32.1 23.79,13.17 v2(24.28,13.17)
LINE1_L: length 3.6
  TOP w0.102: CA32.1 v1(22.43,16.12)
  TOP w0.203: UA1.22 23.93,18.56 23.51,18.15 23.48,18.15
  TOP w0.305: CA32.1 22.63,17.3 23.48,18.15
LINE1_R: length 2
  TOP w0.203: 23.2,18.63 23.5,18.63 23.83,18.96 UA1.21
  TOP w0.305: 23.2,18.63 CA33.1
LOM_TCT: length 5.9
  TOP w0.102: v2(27.7,110.89) v1(27.7,111.51)
  TOP w0.508: CL12.1 27.69,110.88 v2(27.7,110.89)
  BOTTOM w0.508: TL1.3 27.64,112.1 27.43,111.89 27.43,111.17 v2(27.7,110.89) 27.7,108.6 TL1.4
LPC_LAD0: length 143
  TOP w0.102: v2(123.12,4.55) 123.12,4.89 122.24,5.77 JDB1.8
  IN1 w0.119: v2(93.5,27.35) 93.5,28.72 93.13,29.09 93.13,29.79 93.49,30.15 95.41,30.15 96.53,31.27 98.64,31.27 101.06,28.85 106.8,28.85 108.74,26.91 108.89,26.77 111.76,26.77 112.24,26.28 112.53,25.99 113.38,25.99 113.93,25.44 115.09,25.44 115.64,24.89 119.1,24.89 119.1,24.89 119.51,24.89 119.51,24.89 119.65,24.75 119.66,24.75 122.94,24.75 123.3,24.4 129.72,24.4 130.61,25.29 130.61,25.58 130.61,25.58 130.61,25.78 132.9,28.07 132.9,28.39 136.23,31.71 136.62,31.71 139.82,34.91 146.35,34.91 147.39,33.86 149.44,33.86 150.86,35.29 v2(151.72,35.29) ; v2(149.88,22.06) 149.88,19.96 149.09,19.17 146.67,19.17 146.34,18.84 146.34,18.12 145.78,17.57 144.95,17.57 144.75,17.57 144.01,16.83 141.73,16.83 140.77,15.87 140.77,14.41 138.2,11.84 138.2,11.52 137.94,11.26 135.12,8.44 133.59,8.44 129.28,4.13 127,4.13 126.16,4.97 123.54,4.97 v2(123.12,4.55)
  BOTTOM w0.076: UC1.AY13 101.99,35.85 101.88,35.96 101.77,36.06 101.56,36.13 101.44,36.13 101.21,36.07 101.07,36.07 100.95,36.12 100.68,36.12 100.64,36.08 100.57,36.01 99.48,36.01
  BOTTOM w0.102: 99.48,36.01 98.46,36.01 97.3,34.85 97.3,34.73 96.69,34.12 95.02,34.12 93.88,32.99 93.88,31.39 93.14,30.65 93.14,29.14 93.49,28.78 93.49,27.36 v2(93.5,27.35) ; v2(149.88,22.06) 149.88,22.06 149.88,22.05 149.63,22.05 148.93,22.76 148.93,27.91 150.87,29.85 150.87,29.88 152.36,31.36 UE1.59 152.36,34.36 152.03,34.69 152.03,34.98 151.72,35.29 v2(151.72,35.29)
LPC_LAD1: length 140
  TOP w0.102: v2(122.29,4.56) 122.29,4.88 121.74,5.43 JDB1.7
  IN1 w0.119: v2(94.15,30.57) 94.85,31.27 95.35,31.27 95.35,31.27 95.62,31.27 95.87,31.52 98.71,31.52 101.09,29.14 106.86,29.14 108.99,27.01 111.86,27.01 112.49,26.38 112.63,26.24 113.48,26.24 114.04,25.68 115.2,25.68 115.74,25.14 119.61,25.14 119.78,24.97 123.04,24.97 123.36,24.64 129.62,24.64 130.37,25.39 130.37,25.47 130.37,25.88 132.66,28.17 132.66,28.49 136.12,31.96 136.55,31.96 140.59,35.99 142.31,35.99 143,35.3 146.3,35.3 146.87,34.73 148.87,34.73 149.53,35.39 149.88,35.39 v2(150.09,35.59) ; v2(151.09,22.96) 150.62,22.49 150.62,22.13 151.09,21.67 151.09,18.43 150.8,18.15 146.71,18.15 145.88,17.32 144.85,17.32 144.11,16.58 141.79,16.58 141.34,16.13 141.34,15.67 141.6,15.41 141.6,14.93 138.42,11.75 138.42,11.37 135.27,8.22 133.68,8.22 129.21,3.75 126.9,3.75 126.54,4.11 122.74,4.11 v2(122.29,4.56)
  BOTTOM w0.076: 99.12,35.48 99.24,35.6 101.04,35.6 101.29,35.85 UC1.BA13
  BOTTOM w0.102: v2(150.09,35.59) 150.26,35.77 152.09,35.77 152.26,35.6 152.26,34.79 152.76,34.29 UE1.60 152.76,31.44 151.1,29.78 151.1,29.76 149.15,27.82 149.15,22.85 149.54,22.46 150.26,22.46 150.76,22.96 v2(151.09,22.96) ; 99.12,35.48 98.46,35.48 97.68,34.7 97.68,34.57 96.85,33.74 95.53,33.74 94.34,32.55 94.34,30.76 v2(94.15,30.57)
LPC_LAD2: length 135.8
  TOP w0.102: v2(121.3,4.91) 121.24,4.98 121.24,7.95 JDB1.6
  IN1 w0.119: v2(149.88,23.45) 149.88,23.45 149.87,23.45 149.03,22.61 149.03,21.97 149.33,21.67 149.33,20.53 148.47,19.66 144.99,19.66 144.57,19.24 144.57,18.09 143.8,17.32 141.86,17.32 141.86,17.32 141.59,17.32 140.32,16.05 140.32,15.47 137.72,12.87 137.72,11.67 135.59,9.54 134.06,9.54 129.09,4.57 127.18,4.57 126.34,5.41 121.8,5.41 v2(121.3,4.91) ; v2(153.23,34.04) 153.07,34.21 153.06,34.21 152.99,34.28 152.97,34.25 152.49,34.25 152.11,34.63 150.9,34.63 149.78,33.52 149.78,33.51 149.63,33.36 146.27,33.36 145.46,34.18 139.76,34.18 136.8,31.22 136.43,31.22 133.4,28.18 133.4,27.87 131.11,25.58 131.11,25.29 131.11,25.08 130.15,24.13 129.93,23.9 123.17,23.9 122.76,24.31 119.4,24.31 119.3,24.4 115.43,24.4 114.89,24.94 113.73,24.94 113.17,25.5 112.33,25.5 112.18,25.64 112.18,25.64 112.04,25.79 111.55,26.27 108.33,26.27 107.28,27.32 106.06,27.32 105.09,28.29 102.83,28.29 101.92,27.39 97.81,27.39 96.81,28.39 94.46,28.39 93.54,29.31 v2(93.54,29.62)
  BOTTOM w0.076: 98.99,35.67 99.09,35.77 100.76,35.77 UC1.BB13
  BOTTOM w0.102: v2(93.54,29.62) 93.54,30.7 94.11,31.27 94.11,32.77 95.27,33.93 96.77,33.93 97.49,34.65 97.49,34.77 98.38,35.67 98.99,35.67 ; v2(153.23,34.04) 153.16,33.96 UE1.61 153.16,31.52 151.33,29.69 151.33,29.66 149.73,28.07 149.73,23.6 149.88,23.45 v2(149.88,23.45)
LPC_LAD3: length 137.2
  TOP w0.102: v2(120.67,4.91) 120.74,4.98 JDB1.5
  IN1 w0.119: v2(120.67,4.91) 121.18,4.41 121.5,4.41 122.28,5.19 126.25,5.19 127.09,4.35 129.19,4.35 134.16,9.32 135.68,9.32 137.94,11.58 137.94,12.78 140.54,15.38 140.54,15.96 141.66,17.08 143.9,17.08 144.81,17.99 144.81,18.19 144.81,19.14 145.09,19.42 148.99,19.42 149.58,20 149.58,21.78 149.44,21.92 149.44,22.42 v2(149.88,22.87) ; v2(94.13,29.61) 94.13,29.61 94.82,28.92 99.84,28.92 100.22,28.54 105.19,28.54 105.96,27.77 107.18,27.77 108.43,26.52 111.65,26.52 112,26.18 112.28,25.89 112.43,25.75 113.28,25.75 113.83,25.19 114.99,25.19 115.53,24.65 119.2,24.65 119.41,24.65 119.53,24.53 122.85,24.53 123.23,24.15 129.83,24.15 130.86,25.18 130.86,25.68 133.15,27.97 133.15,28.29 136.33,31.47 136.69,31.47 139.65,34.43 145.56,34.43 146.37,33.61 149.53,33.61 150.8,34.88 152.21,34.88 152.59,34.5 152.87,34.5 152.99,34.62 v2(153.23,34.62)
  BOTTOM w0.076: UC1.AY12 102.28,35.28 102,35.57 101.99,35.57 101.99,35.56 101.65,35.56 101.52,35.44 99.41,35.44 99.26,35.29
  BOTTOM w0.102: v2(149.88,22.87) 150.29,23.28 150.29,28.3 151.55,29.57 151.55,29.59 153.56,31.6 UE1.62 153.56,33.73 153.65,33.81 153.65,34.21 v2(153.23,34.62) ; v2(94.13,29.61) 94.57,30.06 94.57,32.46 95.66,33.55 96.93,33.55 97.87,34.49 97.87,34.62 98.54,35.29 99.26,35.29
LPC_LFRAME#: length 111.7
  TOP w0.102: v2(119.84,5.17) 119.84,5.17 119.82,5.19 119.82,5.33 120.24,5.75 JDB1.4 120.24,9.83 119.96,10.11 118.45,11.62 112.49,11.62 109.82,14.29 106.74,14.29 105.81,13.36 105.42,13.36 105.42,13.36 105.08,13.36 105.08,13.36 103.46,13.36 v1(102.23,12.13) 97.96,12.13 94.61,15.47 94.61,19.15 94.34,19.42 v2(94.34,19.44)
  IN1 w0.119: v2(148.26,22.16) 148,22.16 146.53,20.69 144.47,20.69 143.69,19.91 143.69,17.91 143.6,17.82 142.06,17.82 142.04,17.83 141.48,17.83 139.83,16.19 139.83,15.68 137.23,13.08 137.23,11.87 135.39,10.03 133.93,10.03 129.75,5.85 120.45,5.85 119.84,5.25 119.84,5.17 v2(119.84,5.17)
  BOTTOM w0.089: 100.26,35.26 100.27,35.26 101.8,35.26 UC1.BA12
  BOTTOM w0.102: v2(94.34,19.44) 92.68,21.1 92.68,23.46 93.01,23.79 93.01,26.45 93.27,26.72 93.64,26.72 93.91,26.98 93.91,28.52 94.82,29.44 94.82,32.39 95.79,33.36 97.01,33.36 98.06,34.41 98.06,34.54 98.62,35.1 99.42,35.1 99.59,35.26 100.26,35.26 ; UE1.58 151.96,31.29 150.64,29.97 150.64,29.95 148.06,27.37 148.06,22.36 v2(148.26,22.16)
LPSS_UART2_CTS#: length 6.9
  TOP w0.102: v2(110.52,30.94) 109.66,30.08 109.66,27.42 v1(110.46,26.61) 110.7,26.38 111.3,26.38 111.31,26.37 RC43.1
  BOTTOM w0.076: UC1.AD4 110.68,30.78 v2(110.52,30.94)
LX1_VGA: length 18.9
  IN1 w1.016: 58.88,121.12 59.87,120.13 59.87,117.59 61.62,115.84 65.87,115.84 66.73,114.98 73.74,114.98
  vias: v1(77.11,115.02) v2(57.23,122.01) v2(57.68,121.56) v2(74.63,115.47) v2(74.63,114.58) v2(74.63,113.69) v2(74.63,112.8) v2(74.69,117.74) v2(74.69,117.16) v2(74.69,116.57) v2(74.76,112.1) v2(75.28,117.74) v2(75.28,117.16) v2(75.28,116.57) v2(75.34,112.1) v2(75.88,117.75) v2(75.88,117.17) v2(75.88,116.58) v2(75.93,112.1) v2(76.51,112.1) v2(76.74,117.74) v2(76.74,117.16) v2(76.74,116.57) v2(77.09,112.1) v2(77.58,117.75) v2(77.58,117.17) v2(77.58,116.58) v2(78.43,117.75) v2(78.43,117.17) v2(78.43,116.58)
LX2_VGA: length 17
  IN1 w1.016: 58.88,125.25 60.79,125.25 61.99,126.45 65.79,126.45 67.1,127.77 69.7,127.77 72.28,125.18 73.74,125.18
  vias: v1(76.03,126.83) v2(57.55,124.48) v2(58.12,124.48) v2(74.57,131.66) v2(74.57,130.1) v2(74.69,124.86) v2(74.76,130.87) v2(74.82,129.58) v2(74.82,123.49) v2(75.08,124.14) v2(75.08,122.97) v2(75.15,131.66) v2(75.15,130.1) v2(75.34,130.87) v2(75.28,124.86) v2(75.41,129.58) v2(75.41,123.49) v2(75.74,131.66) v2(75.74,130.1) v2(75.66,124.14) v2(75.66,122.97) v2(75.93,130.87) v2(75.86,124.86) v2(75.99,129.58) v2(75.99,123.49) v2(76.24,124.14) v2(76.32,131.66) v2(76.32,130.1) v2(76.45,124.86) v2(76.51,130.87) v2(76.57,129.58) v2(76.83,124.14) v2(76.9,131.66) v2(76.9,130.1) v2(77.03,124.86) v2(77.09,130.87) v2(77.16,129.58)
LX_1.2V: length 8.2
  TOP w0.102: v2(78.19,105.18) v1(77.5,105.18)
  TOP w0.508: PC207.1 v2(77.55,103.78)
  IN3 w0.762: 78.99,105.43 81.17,105.43 83.07,107.33 84.86,107.33
  vias: v2(78.19,104.6) v2(86.25,107.37) v2(86.66,106.96)
LX_1.8VALW: length 2.8
  TOP w0.102: v3(166.01,36.89) PR506.1
  TOP w0.508: PR506.1 166.21,35.27 v2(166.96,35.27)
LX_3V: length 7.9
  TOP w0.102: PR106.1 v1(170.96,44.6)
  TOP w0.508: v2(169.5,43.27) 169.25,43.52 PR106.1
  IN1 w0.508: v2(176.98,44.05) 176.89,43.97 173.82,43.97 v2(173.12,43.27)
  BOTTOM w0.254: v2(176.98,44.05) 177.12,43.91 PU100.6
LX_5V: length 8.5
  TOP w0.102: v3(170.7,34.95) PR112.1
  TOP w0.508: PR112.1 173.63,34.95 v2(174.14,34.44)
  IN3 w0.508: v2(180.49,33.87) 176.42,33.87 v2(175.85,33.3)
LX_+1.35VGPU: length 6.7
  IN1 w0.508: v2(153.63,90.64) 154.06,91.08 157.68,91.08 v2(158.07,91.46)
  BOTTOM w0.102: 152.23,94.89 v1(152.23,95.7)
  BOTTOM w0.254: v2(158.07,91.46) 158.22,91.32 158.22,91.04 158.04,90.86 PU1400.6
LX_+1VALW: length 5.7
  IN1 w0.508: v2(148.23,43.27) 152.23,43.27 v2(152.82,43.86)
  BOTTOM w0.254: v2(152.82,43.86) 152.51,43.55 PU300.6
M0_MA0: length 33.5
  TOP w0.102: 136.69,119.29 137.29,119.89 137.29,120.73 137.99,121.43 142.44,121.43 142.95,120.91 142.95,120.2 v2(143.11,120.05)
  TOP w0.127: v2(143.11,120.05) 143.43,119.72 UV12.H4 ; v2(120.03,116.61) 120.03,116.36 120.16,116.24 121.09,116.24 121.25,116.4 122.28,116.4 122.45,116.23 123.23,116.23 123.31,116.15 124.21,116.15 124.29,116.23 124.31,116.23 124.36,116.28 124.41,116.28 124.55,116.42 124.61,116.42 124.69,116.5 125.02,116.82 v1(131.38,116.82) 132.42,116.82 132.9,117.3 133.08,117.3 133.56,116.82 133.74,116.82 133.92,117 133.92,117.18 133.44,117.66 133.44,117.84 133.62,118.02 133.8,118.02 134.42,117.4 134.6,117.4 136.48,119.29 136.69,119.29
  BOTTOM w0.127: v2(120.03,116.61) 119.63,116.61 119.29,116.27 119.29,115.52 119.05,115.29 118.71,115.29 118.34,114.92 UV1.K17 ; UV12.H4 143.43,119.72 v2(143.11,120.05)
M0_MA1: length 31.2
  TOP w0.102: 136.52,119.75 137.09,120.32 137.09,120.82 137.9,121.63 142.75,121.63 v2(143.29,121.1)
  TOP w0.127: 136.52,119.75 136.29,119.75 134.6,118.06 134.42,118.06 133.8,118.68 133.62,118.68 v1(132.62,117.67) 132.23,117.29 125.16,117.29 124.52,116.65 124.46,116.65 124.32,116.51 124.27,116.51 124.22,116.46 124.2,116.46 124.11,116.37 123.41,116.37 123.33,116.46 122.55,116.46 122.37,116.63 121.16,116.63 120.99,116.47 120.67,116.47 120.44,116.7 120.44,117.63 120.31,117.75 v2(120.03,117.75) ; UV12.H5 143.43,120.96 v2(143.29,121.1)
  BOTTOM w0.127: v2(120.03,117.75) 120.09,117.7 120.09,117.21 119.83,116.95 119.51,116.95 119.14,117.32 UV1.J20 ; UV12.H5 143.43,120.96 v2(143.29,121.1)
M0_MA2: length 30
  TOP w0.102: 137.33,123.49 137.57,123.26 143.19,123.26 143.83,123.9 v2(143.83,124.85)
  TOP w0.127: UV12.H11 143.43,125.25 v2(143.83,124.85) ; v2(119.46,119.02) 119.46,119.28 120.93,120.75 122.21,120.75 123.83,122.38 130.86,122.38 132.66,124.18 v1(132.98,124.18) 136.65,124.18 137.33,123.49
  BOTTOM w0.127: v2(143.83,124.85) 143.43,125.25 UV12.H11 ; UV1.H23 119.66,119.46 119.46,119.27 v2(119.46,119.02)
M0_MA3: length 29.6
  TOP w0.102: v2(143.15,123.85) 142.76,123.46 137.84,123.46 136.65,124.64
  TOP w0.127: UV12.H10 143.43,124.13 v2(143.15,123.85) ; v2(120.15,120.69) 120.39,120.69 121.49,121.79 122.57,121.79 122.84,122.06 122.84,122.86 122.9,122.92 122.9,123.34 123.07,123.51 123.61,123.51 123.84,123.28 124.76,123.28 124.99,123.51 127.5,123.51 128.16,122.84 130.66,122.84 132.47,124.64 v1(134.37,124.64) 136.65,124.64
  BOTTOM w0.127: UV1.G23 119.98,120 119.98,120.52 v2(120.15,120.69) ; v2(143.15,123.85) 143.43,124.13 UV12.H10
M0_MA4: length 29.8
  TOP w0.102: v2(145.43,124.85) 145.43,123.12 145.16,122.85 137.16,122.85 136.76,123.25 136.2,123.25
  TOP w0.127: v2(145.43,124.85) 145.03,125.25 UV12.K11 ; 136.2,123.25 133.53,123.25 v1(131.87,121.6) 131.62,121.35 126.88,121.35 126.53,121.35 126.53,121.35 123.77,121.35 122.72,120.3 121.12,120.3 120.92,120.09 v2(120.92,119.86)
  BOTTOM w0.127: UV12.K11 145.03,125.25 v2(145.43,124.85) ; UV1.G24 v2(120.92,119.86)
M0_MA5: length 30.8
  TOP w0.102: v2(145.03,123.88) 145.03,123.73 144.36,123.06 137.24,123.06 136.58,123.71 136.31,123.71
  TOP w0.127: UV12.K10 145.03,123.88 v2(145.03,123.88) ; v2(120.86,119.15) 120.52,119.48 120.52,120.02 121.03,120.52 122.49,120.52 123.77,121.81 126.33,121.81 130.95,121.81 v1(132.26,123.12) 132.85,123.71 136.31,123.71
  BOTTOM w0.127: UV12.K10 145.03,123.88 v2(145.03,123.88) ; UV1.H24 119.66,120.08 119.67,120.08 119.67,119.96 120.03,119.59 120.03,119.47 120.35,119.15 v2(120.86,119.15)
M0_MA6: length 31.5
  TOP w0.102: v2(119.14,116.74) 119.65,117.24 119.65,117.91 119.88,118.13 120,118.13 120.32,118.46 121.09,118.46 121.4,118.15 121.99,118.15 122.39,117.75 124.32,117.75 125.34,118.77 125.66,118.77 ; 137.35,122.09 137.5,122.24 143.8,122.24 v2(145.03,121.01)
  TOP w0.127: 125.66,118.77 131.74,118.77 134.19,121.22 v1(135.78,121.22) 136.47,121.22 137.35,122.09 ; v2(145.03,121.01) 145.03,120.45 UV12.K5
  BOTTOM w0.127: UV12.K5 145.03,121.01 v2(145.03,121.01) ; UV1.J19 118.86,116.45 v2(119.14,116.74)
M0_MA7: length 34
  TOP w0.102: 136.57,120.85 136.57,120.87 137.74,122.04 143.4,122.04 144.63,120.81 v2(144.63,120.05)
  TOP w0.127: UV12.K4 145.03,119.65 v2(144.63,120.05) ; v2(120.97,117.51) 121.32,117.85 121.98,117.85 122.92,116.91 123.52,116.91 123.6,116.83 123.92,116.83 124.01,116.91 124.03,116.91 125.37,118.26 131.89,118.26 134.38,120.76 v1(134.51,120.76) 136.48,120.76 136.57,120.85
  BOTTOM w0.102: UV1.K19 118.4,116.12 118.5,116.22 118.5,116.54 118.64,116.67 118.64,117.03 118.46,117.21 118.46,117.52 118.82,117.88 118.82,117.99 118.99,118.16 119.01,118.16 119.06,118.21 119.35,118.21 119.56,118.01 119.75,118.01 119.88,118.13 120.19,118.13 120.32,118.01 120.32,118.01 120.4,117.92 120.41,117.91 120.41,117.91 120.62,117.7 120.78,117.7 v2(120.97,117.51)
  BOTTOM w0.127: UV12.K4 145.03,119.65 v2(144.63,120.05)
M0_MA8: length 30.5
  TOP w0.102: 136.62,120.22 136.89,120.48 136.89,120.9 137.82,121.84 143.09,121.84 143.91,121.01 v2(143.91,120.99)
  TOP w0.127: v2(143.91,120.99) 144.23,120.67 UV12.J5 ; 136.62,120.22 136.09,120.22 135.37,119.49 135.15,119.49 134.55,120.09 134.37,120.09 134.19,119.91 134.19,119.73 134.79,119.13 134.79,118.91 134.6,118.72 134.42,118.72 133.8,119.33 133.62,119.33 v1(133.41,119.12) 132.04,117.75 125.24,117.75 124.22,116.74 124.17,116.74 124.12,116.69 124.1,116.69 124.02,116.6 123.5,116.6 123.42,116.69 122.64,116.69 122.47,116.86 v2(120.83,116.86)
  BOTTOM w0.127: UV1.G20 120.46,117.06 120.66,116.86 v2(120.83,116.86) ; UV12.J5 144.23,120.67 v2(143.91,120.99)
M1_MA0: length 35.3
  TOP w0.102: v2(145.35,107.83) 145.44,107.74 145.44,107.28 145.76,106.96 145.76,106.58 144.6,105.43 137.36,105.43 137.16,105.23 136.86,105.23
  TOP w0.127: UV14.H4 145.03,108.15 v2(145.35,107.83) ; 136.86,105.23 135.7,105.23 131.76,109.17 v1(131.55,109.17) 125.72,109.17 125.11,109.78 121.57,109.78 121.27,110.09 121.27,110.98 120.81,111.44 120.47,111.44 120.47,111.43 120.14,111.43 120.13,111.44 119.91,111.66 119.91,112.08 119.65,112.34 118.52,112.34 118.23,112.05 v2(118.23,112.01)
  BOTTOM w0.127: UV1.J14 118.74,112.52 118.23,112.02 v2(118.23,112.01) ; UV14.H4 145.03,108.15 v2(145.35,107.83)
M1_MA1: length 33.4
  TOP w0.102: v2(145.17,106.77) 144.03,105.63 137.19,105.63 137.12,105.69
  TOP w0.127: v2(118.39,113.29) 118.39,112.7 118.52,112.57 119.95,112.57 120.29,112.22 120.61,112.22 120.88,111.95 120.88,111.7 121.5,111.08 121.5,110.9 121.78,110.62 121.84,110.62 122.46,110.01 125.21,110.01 125.55,109.66 v1(130.32,109.66) 131.93,109.66 135.89,105.69 137.12,105.69 ; v2(145.17,106.77) 145.03,106.92 UV14.H5
  BOTTOM w0.127: UV1.K14 118.39,112.85 v2(118.39,113.29) ; v2(145.17,106.77) 145.03,106.92 UV14.H5
M1_MA2: length 33.7
  TOP w0.127: v2(118.62,110.75) 118.98,111.11 119.49,111.11 119.63,110.98 119.63,110.23 119.81,110.04 120.34,110.04 121.29,109.09 123.71,109.09 125.77,107.03 131.45,107.03 v1(133.16,105.31) 134.98,103.49 136.48,103.49 137.79,104.81 143.58,104.81 143.85,104.54 143.85,103.21 144.03,103.03 v2(144.63,103.03) UV14.H11
  BOTTOM w0.127: UV1.J11 118.86,110.52 v2(118.62,110.75) ; UV14.H11 v2(144.63,103.03)
M1_MA3: length 33.4
  TOP w0.102: 136.62,103.96 137.68,105.02 144.58,105.02 145.31,104.29 v2(145.31,104.03)
  TOP w0.127: v2(145.31,104.03) 145.03,103.74 UV14.H10 ; v2(118.83,111.94) 118.83,111.85 119.34,111.34 119.59,111.34 119.98,110.95 120.49,110.95 120.8,110.64 120.8,109.91 121.38,109.32 123.81,109.32 125.48,107.64 131.49,107.64 v1(132.62,106.51) 135.18,103.96 136.62,103.96
  BOTTOM w0.127: UV1.J13 118.83,111.35 v2(118.83,111.94) ; v2(145.31,104.03) 145.03,103.74 UV14.H10
M1_MA4: length 31.7
  TOP w0.102: 136.83,102.8 137.3,103.27 137.3,103.72 137.9,104.32 142.77,104.32 142.95,104.14 142.95,103.1 v2(143.03,103.03)
  TOP w0.127: 136.83,102.8 136.59,102.56 134.6,102.56 v1(134.32,102.84) 131.96,105.21 126.1,105.21 125.16,106.15 123.95,106.15 122.03,108.07 121.59,108.07 121.12,108.54 121.07,108.54 120.43,109.18 120,109.18 119.59,109.59 119.59,109.94 119.2,110.33 v2(119.2,110.71) ; UV14.K11 v2(143.03,103.03)
  BOTTOM w0.127: UV14.K11 v2(143.03,103.03) ; v2(119.2,110.71) 119.2,110.57 UV1.H11
M1_MA5: length 30.4
  TOP w0.102: v2(143.43,103.99) 142.9,104.52 137.82,104.52 137.1,103.8 137.1,103.38 136.74,103.03
  TOP w0.127: v2(120.09,109.65) 120.28,109.65 121.16,108.77 121.21,108.77 121.68,108.3 122.12,108.3 122.81,107.61 124.66,107.61 125.7,106.56 126.42,106.56 126.55,106.44 126.55,105.8 126.68,105.67 126.93,105.67 127.06,105.8 127.06,106.44 127.18,106.56 131.25,106.56 v1(133.75,104.07) 134.79,103.03 136.74,103.03 ; UV14.K10 v2(143.43,103.99)
  BOTTOM w0.127: v2(120.09,109.65) 120.09,109.75 UV1.G11 ; UV14.K10 v2(143.43,103.99)
M1_MA6: length 32
  TOP w0.102: 143.21,106.77 143.15,106.77 142.82,106.44 137.99,106.44 137.23,107.2
  TOP w0.127: 137.23,107.2 137.23,107.47 136.2,108.51 136.2,111.8 135.62,112.38 v1(135.06,112.38) 124.82,112.38 124.62,112.58 123.64,112.58 123.34,112.28 122.46,112.28 122,112.74 121.39,112.74 120.99,113.14 120.67,113.14 120.07,113.74 119.98,113.83 119.67,113.83 119.21,114.3 v2(119.12,114.3) ; 143.21,106.77 v2(143.21,106.77) 143.43,106.99 UV14.K5
  BOTTOM w0.127: UV14.K5 143.21,107.21 v2(143.21,106.77) ; v2(119.12,114.3) 119.12,114.02 118.86,113.76 UV1.J16
M1_MA7: length 35.7
  TOP w0.102: 137.05,107 137.14,107 137.9,106.24 143.22,106.24 143.66,106.68 143.66,107.2 143.75,107.29 143.75,107.75 v2(143.83,107.83)
  TOP w0.127: UV14.K4 v2(143.83,107.83) ; 137.05,107 135.74,108.31 135.74,110.92 135.18,111.48 v1(133.73,111.48) 126.48,111.48 126.15,111.81 124.62,111.81 124.61,111.8 123.26,111.8 123,112.05 122.36,112.05 121.91,112.51 121.3,112.51 120.9,112.91 120.58,112.91 119.88,113.6 119.13,113.6 118.73,114 118.73,114.62 118.6,114.74 118.11,114.74 v2(117.69,114.33)
  BOTTOM w0.127: UV14.K4 v2(143.83,107.83) ; UV1.L15 117.26,113.2 117.68,113.62 117.68,113.86 117.69,113.87 v2(117.69,114.33)
M1_MA8: length 31.4
  TOP w0.102: v2(144.04,106.83) 144.04,106.37 143.71,106.04 137.82,106.04 137.32,106.54 137.18,106.54
  TOP w0.127: 137.18,106.54 136.75,106.97 136.42,106.97 135.27,108.12 135.27,110.21 v1(135,110.48) 134.55,110.93 126.37,110.93 125.96,111.34 124.48,111.34 124.48,111.34 123.39,111.34 122.91,111.83 122.27,111.83 121.82,112.28 121.21,112.28 120.8,112.68 120.48,112.68 120.08,113.08 119.85,113.08 v2(119.74,113.19) ; v2(144.04,106.83) 144.23,107.02 UV14.J5
  BOTTOM w0.127: UV14.J5 144.23,107.02 v2(144.04,106.83) ; v2(119.74,113.19) 120.41,112.52 UV1.G14
M2_SLOT2_PEDET: length 92.5
  TOP w0.102: JSSD1.18 190.35,15.07 v2(190.44,15.16) ; v2(123.33,26.74) 122.89,26.3 122.89,25.69 123.46,25.13 124.02,25.13 125.35,23.79 125.35,23.28 128.74,19.89 134.31,19.89 137.58,16.62 139.69,16.62 139.81,16.74 142.06,16.74 v2(143.53,15.27) ; v2(166.69,9.02) 166.55,8.87 166.55,7.08 167.3,6.33 172.81,6.33 178.82,12.34 v1(179.34,12.34) v2(180.23,12.34)
  IN1 w0.119: v2(143.53,15.27) 144.02,14.78 145.83,14.78 148.46,17.41 152.62,17.41 157.74,12.29 163.96,12.29 166.69,9.55 v2(166.69,9.02)
  IN2 w0.127: v2(190.44,15.16) 188.69,13.4 181.24,13.4 180.23,12.4 v2(180.23,12.34)
  BOTTOM w0.076: v2(123.33,26.74) 122.62,27.45 120.62,27.45 120.23,27.84 120.23,29.33 120.07,29.48 119.91,29.48 119.71,29.68 119.71,30.23 UC1.G4
M_ADBI0: length 32.2
  TOP w0.127: v2(118.07,115.53) 119.09,115.53 119.73,114.88 121.06,114.88 121.31,115.14 121.95,115.14 122.28,114.81 124.65,114.81 124.76,114.92 142.23,114.92 v1(142.46,115.15) 143.85,116.54 143.85,118.14 144.15,118.45 144.3,118.45 144.63,118.77 v2(144.63,119.25) 144.23,119.65 UV12.J4
  BOTTOM w0.102: v2(118.07,115.53) 117.88,115.72 UV1.L18
  BOTTOM w0.127: UV12.J4 144.23,119.65 v2(144.63,119.25)
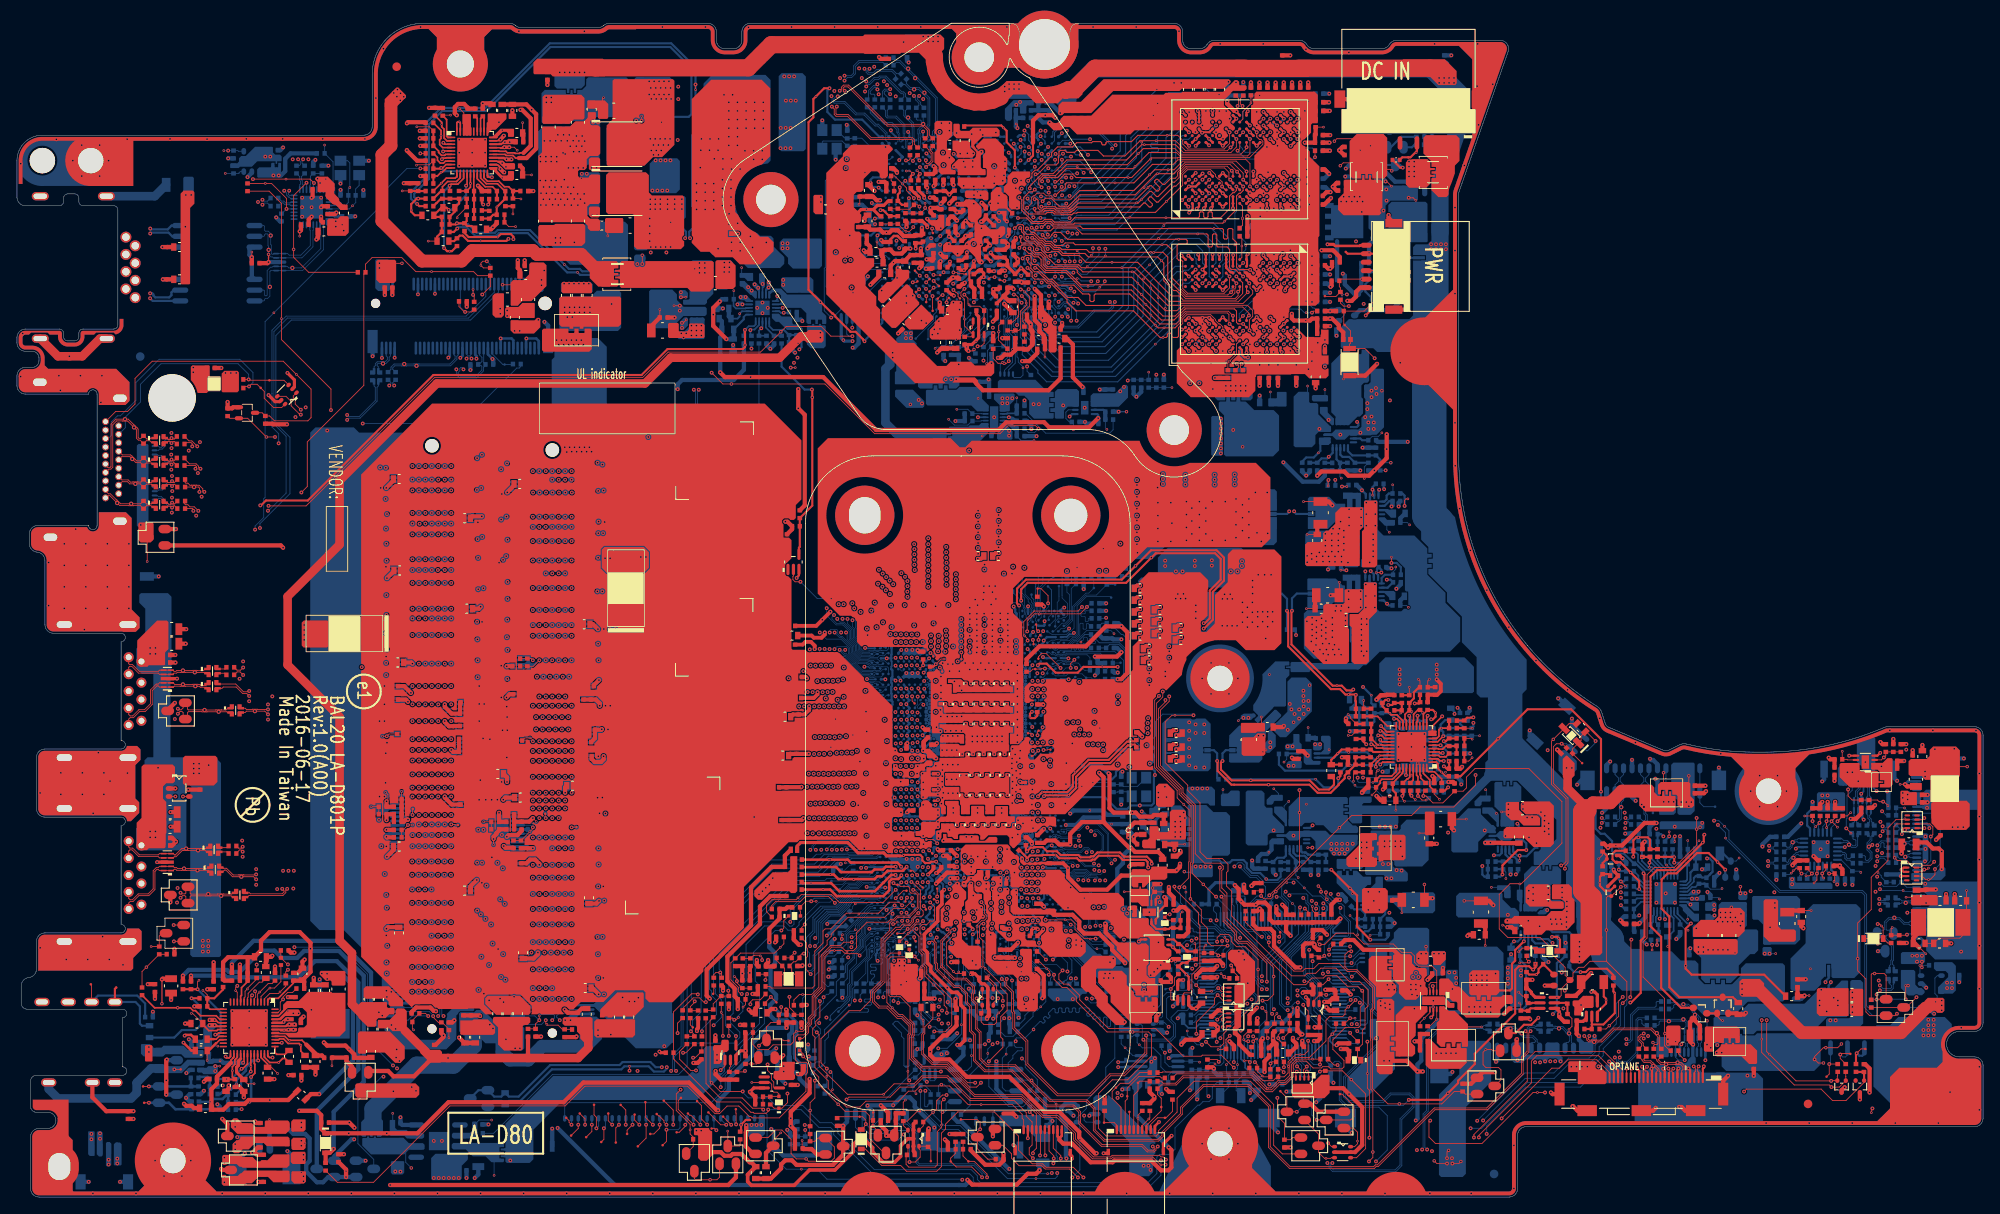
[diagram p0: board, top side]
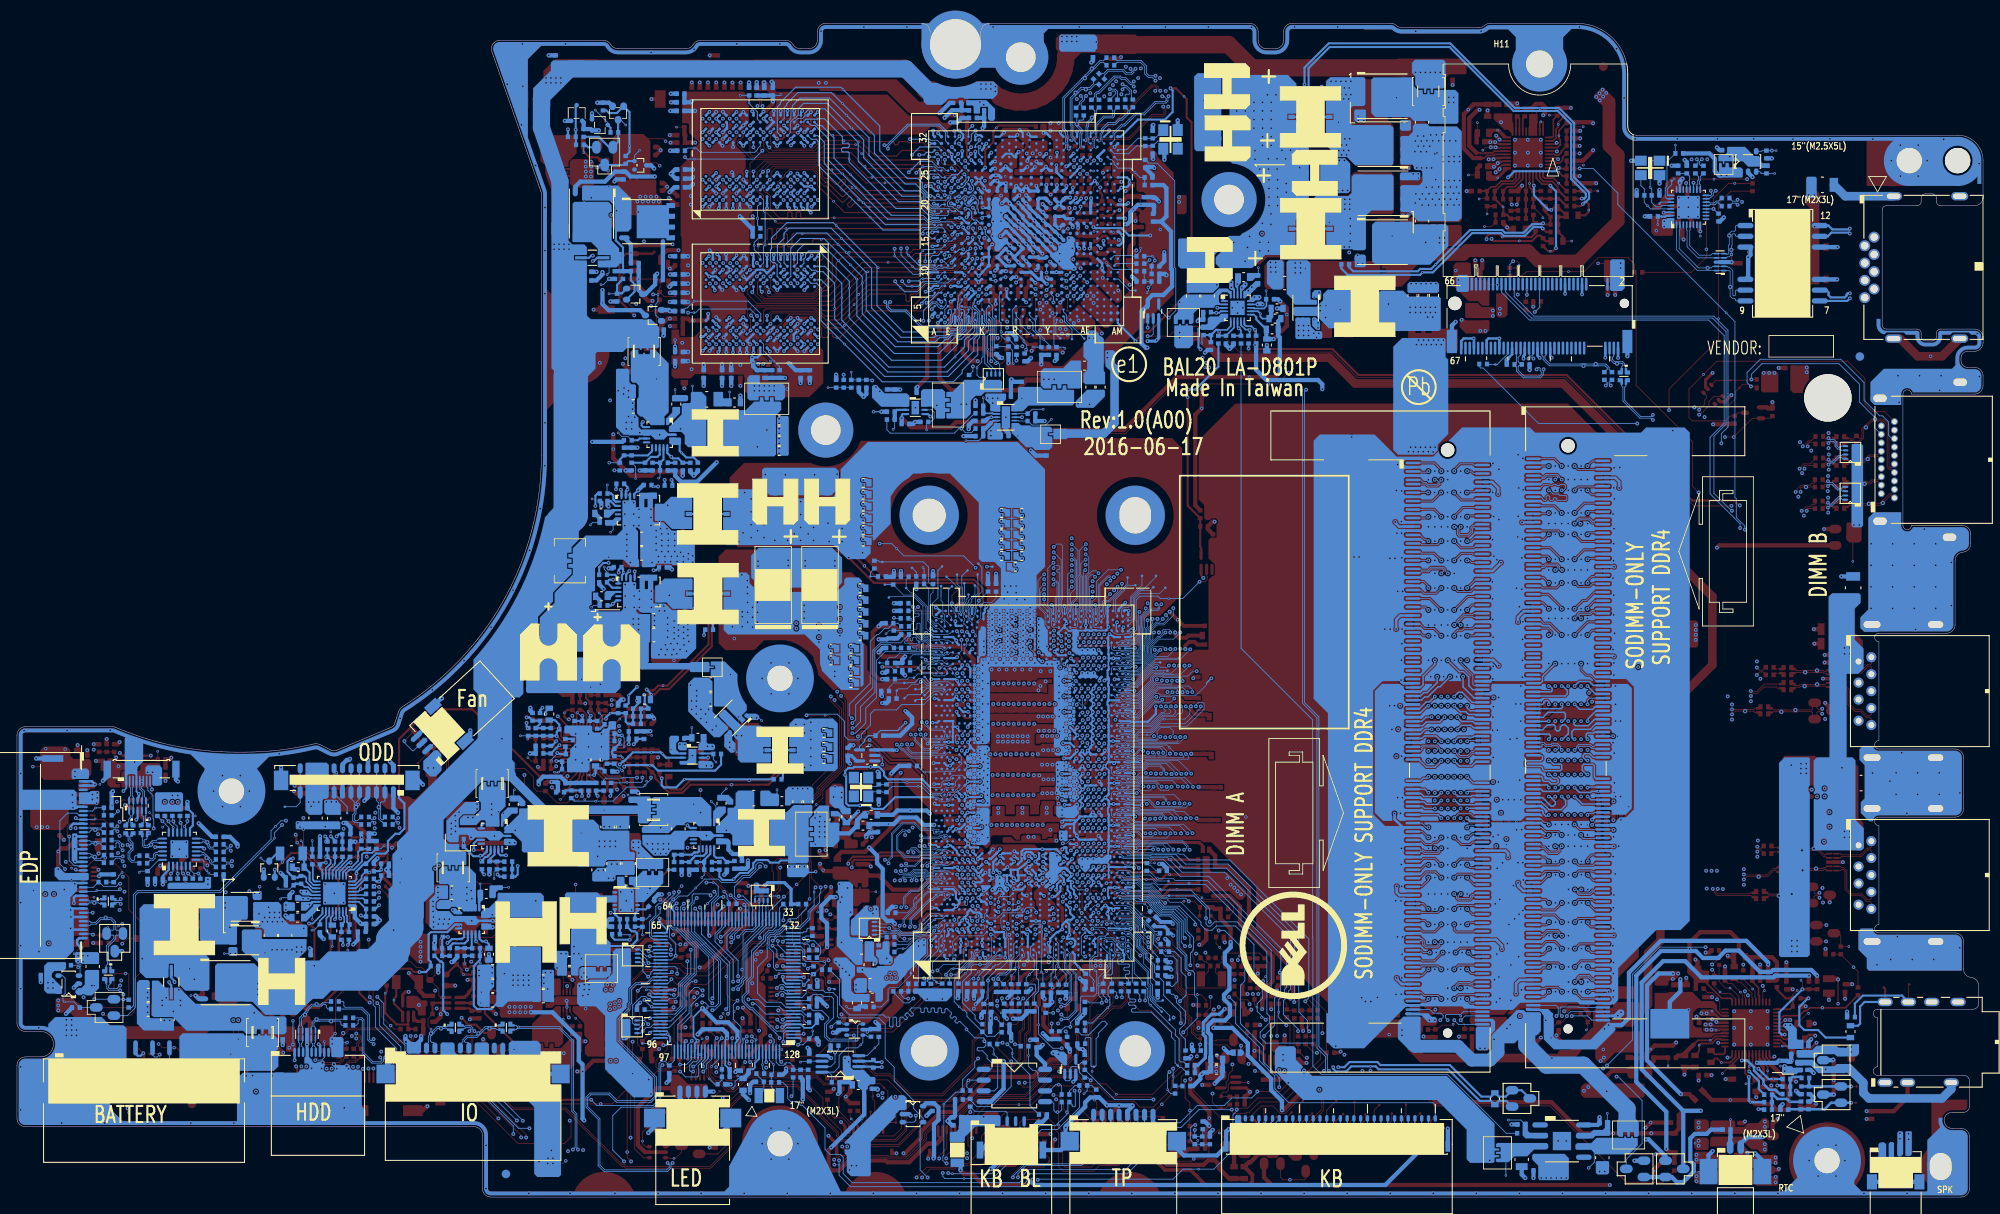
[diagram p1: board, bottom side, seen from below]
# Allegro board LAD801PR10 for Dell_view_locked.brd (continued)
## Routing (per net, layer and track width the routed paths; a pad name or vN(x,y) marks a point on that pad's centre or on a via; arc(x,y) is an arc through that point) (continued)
M_ADBI1: length 34.6
  TOP w0.102: 137.47,105.94 137.47,105.9 137.54,105.83 143.79,105.83 144.57,106.61
  TOP w0.127: 144.57,106.61 144.57,107.89 UV14.J4 v2(143.83,108.63) ; 137.47,105.94 137.08,106.33 136.16,106.33 132.19,110.3 v1(129.15,110.3) 126.1,110.3 125.29,111.11 123.3,111.11 122.81,111.6 122.04,111.6 121.91,111.46 121.44,111.46 121.15,111.75 121.15,112.01 120.71,112.45 120.39,112.45 120.04,112.8 119.03,112.8 118.78,113.04 118.78,113.62 118.5,113.9 118.5,114.18 v2(118.34,114.35)
  BOTTOM w0.127: v2(118.34,114.35) 118.28,114.29 118.19,114.29 118.06,114.17 UV1.K16 ; UV14.J4 v2(143.83,108.63)
M_CAS#0: length 33.1
  TOP w0.102: v2(145.43,119.25) 145.43,121.95 144.94,122.45 137.24,122.45 137.18,122.39 136.92,122.39
  TOP w0.127: v2(122.46,118.22) 122.53,118.22 123.12,118.81 123.39,118.81 123.65,119.07 123.65,119.54 123.78,119.67 v1(129.52,119.67) 131.74,119.67 133.93,121.85 136.39,121.85 136.92,122.39 ; v2(145.43,119.25) 145.83,118.85 UV12.L3
  BOTTOM w0.102: UV1.G19 120.46,116.13 120.65,116.32 120.83,116.32 121.13,116.62 121.3,116.62 121.54,116.86 122.01,116.86 122.14,116.99 122.14,117.02 122.14,117.02 122.14,117.34 122.14,117.34 122.14,117.41 121.75,117.79 121.75,118.04 121.93,118.22 122.46,118.22 v2(122.46,118.22)
  BOTTOM w0.127: v2(145.43,119.25) 145.83,118.85 UV12.L3
M_CAS#1: length 34.2
  TOP w0.102: 137.5,110.4 137.5,107.22 138.07,106.65 142.39,106.65 143.03,107.29 v2(143.03,108.63)
  TOP w0.127: UV14.L3 v2(143.03,108.63) ; 137.5,110.4 137.35,110.55 137.03,110.55 136.84,110.74 136.84,112.25 137.01,112.43 137.9,112.43 138.03,112.56 138.03,112.89 137.9,113.01 v1(137.03,113.01) 123.92,113.01 123.1,113.83 122.32,113.83 122.07,113.58 122.07,113.48 121.75,113.17 121.33,113.17 v2(120.97,113.53)
  BOTTOM w0.127: UV1.G16 120.78,113.72 v2(120.97,113.53) ; UV14.L3 v2(143.03,108.63)
M_CKE0: length 34.7
  TOP w0.127: UV12.J3 144.23,118.85 v2(143.83,119.25) 143.83,118.77 143.57,118.51 143.42,118.51 143.02,118.12 143.02,116.61 141.96,115.55 141.12,115.55 141,115.68 141,116.13 140.87,116.25 140.61,116.25 140.49,116.13 140.49,115.68 140.36,115.55 140.11,115.55 139.98,115.68 139.98,116.13 139.85,116.25 139.6,116.25 139.47,116.13 139.47,115.68 139.34,115.55 v1(135.52,115.55) 124.75,115.55 124.23,115.04 122.37,115.04 122.04,115.37 121.22,115.37 120.96,115.11 119.83,115.11 118.52,116.42 118.52,117.67 v2(118.24,117.96)
  BOTTOM w0.127: UV1.K20 118.06,117.78 v2(118.24,117.96) ; UV12.J3 144.23,118.85 v2(143.83,119.25)
M_CKE1: length 34
  TOP w0.127: v2(144.63,108.63) UV14.J3 144.12,109.03 143.68,109.46 143.23,109.46 143.03,109.67 143.03,111.82 142.73,112.11 141.65,112.11 141.52,112.24 141.52,113.52 141.39,113.65 141.14,113.65 141.01,113.52 141.01,112.24 140.89,112.11 140.62,112.11 140.49,112.24 140.49,113.5 140.34,113.65 v1(139.28,113.65) 125.63,113.65 124.93,114.35 122.25,114.35 121.92,114.02 120.12,114.02 119.76,114.38 v2(119.68,114.38)
  BOTTOM w0.127: UV14.J3 v2(144.63,108.63) ; v2(119.68,114.38) 119.67,114.38 119.14,114.92 UV1.J17
M_CLK0: length 34.6
  TOP w0.112: RV79.2 144.1,129.63 144.1,128.86 v2(143.97,128.74) ; UV12.J12 144.23,126.04 v2(143.83,125.65)
  IN1 w0.13: v2(143.83,125.65) 144.12,125.94 144.12,126.82 144.29,126.99 144.29,128.41 144.04,128.66 144.04,128.67 v2(143.97,128.74)
  IN3 w0.155: v2(143.83,125.65) 144.18,125.3 144.18,125.12 144.24,125.07 144.24,123.78 144.38,123.64 144.38,123.16 144.06,122.83 138.02,122.83 137.61,123.24 127.2,123.24 126.5,122.55 125.74,122.55 125.43,122.24 124.16,122.24 123.87,121.94 122.04,121.94 121.93,122.06 121.38,122.06 121.27,121.94 120.73,121.94 120.66,122.01 120.34,122.01 v2(120.06,122.29)
  BOTTOM w0.102: v2(120.06,122.29) 119.69,121.92 UV1.H26
  BOTTOM w0.112: UV12.J12 144.23,126.04 v2(143.83,125.65)
M_CLK1: length 35.3
  TOP w0.112: UV14.J12 v2(144.63,102.23) ; RV85.2 144.3,97.88 144.3,98.16 v2(144.46,98.32)
  IN3 w0.155: v2(120.86,107.92) 120.7,107.76 120.7,107.37 121.03,107.04 122.17,107.04 123.03,107.9 124.59,107.9 126.18,106.31 129.78,106.31 130.5,105.59 137.22,105.59 137.63,105.19 143.37,105.19 144.17,104.39 144.17,102.86 144.28,102.75 144.28,102.58 v2(144.63,102.23) 144.36,101.95 144.36,101.2 144.1,100.95 144.1,99.4 144.29,99.21 144.29,98.49 v2(144.46,98.32)
  BOTTOM w0.102: v2(120.86,107.92) UV1.G9
  BOTTOM w0.112: UV14.J12 v2(144.63,102.23)
M_CLK#0: length 35
  TOP w0.112: v2(144.56,128.74) 144.3,128.99 144.3,129.63 RV80.2 ; v2(144.63,125.65) 144.23,125.25 UV12.J11
  IN1 w0.13: v2(144.63,125.65) 144.34,125.94 144.34,126.73 144.51,126.9 144.51,128.69 v2(144.56,128.74)
  IN3 w0.155: v2(120.06,121.57) 120.25,121.75 120.56,121.75 120.62,121.69 121.37,121.69 121.49,121.8 121.82,121.8 121.94,121.69 123.97,121.69 124.27,121.99 125.54,121.99 125.84,122.29 126.61,122.29 127.31,122.99 137.5,122.99 137.91,122.58 144.16,122.58 144.63,123.05 144.63,123.74 144.49,123.88 144.49,125.17 144.43,125.23 144.43,125.45 v2(144.63,125.65)
  BOTTOM w0.102: UV1.H25 120.06,121.52 v2(120.06,121.57)
  BOTTOM w0.112: UV12.J11 144.23,125.25 v2(144.63,125.65)
M_CLK#1: length 35.4
  TOP w0.112: UV14.J11 v2(143.83,102.23) ; v2(143.87,98.32) 144.09,98.1 144.09,97.94 RV86.2
  IN3 w0.155: v2(120.06,107.92) 120.45,107.53 120.45,107.26 120.92,106.79 122.28,106.79 123.13,107.64 124.48,107.64 126.07,106.06 129.67,106.06 130.39,105.34 137.12,105.34 137.52,104.93 143.27,104.93 143.92,104.29 143.92,102.76 144.03,102.64 144.03,102.43 v2(143.83,102.23) 144.1,101.95 144.1,101.31 143.85,101.05 143.85,99.3 144.04,99.11 144.04,98.49 v2(143.87,98.32)
  BOTTOM w0.102: v2(120.06,107.92) UV1.H9
  BOTTOM w0.112: UV14.J11 v2(143.83,102.23)
M_CS0B#0: length 32.5
  TOP w0.102: v2(143.03,125.65) 143.03,124.31 142.39,123.67 138.1,123.67 137.5,124.26 137.5,124.67 137.29,124.89 137.29,124.91 136.92,125.28 136.9,125.28
  TOP w0.127: v2(119.27,119.91) 119.27,119.92 119.72,120.36 119.72,120.81 120.08,121.17 120.35,121.17 122.03,122.86 122.03,123.22 122.73,123.91 124.49,123.91 124.99,124.41 126.75,124.41 126.88,124.54 127.81,124.54 127.94,124.42 127.94,124.29 128.07,124.16 128.32,124.16 128.45,124.29 128.45,124.42 128.57,124.54 131.47,124.54 132.2,125.28 v1(135.67,125.28) 136.9,125.28 ; v2(143.03,125.65) 142.63,126.05 UV12.G12
  BOTTOM w0.127: UV1.H22 119.41,118.52 119.07,118.86 119.07,119.28 119.27,119.48 119.27,119.91 v2(119.27,119.91) ; UV12.G12 142.63,126.05 v2(143.03,125.65)
M_CS1B#0: length 35.8
  TOP w0.102: 145.37,103.52 145.75,103.91 145.75,104.61 145.13,105.22 137.45,105.22 136.82,104.59
  TOP w0.127: v2(119.43,111.94) 119.43,111.82 120.08,111.17 120.74,111.17 121.04,110.88 121.04,109.99 121.48,109.55 124.88,109.55 125.06,109.37 125.06,109.09 125.62,108.54 131.49,108.54 v1(132.2,107.83) 135.44,104.59 136.82,104.59 ; 145.37,103.52 145.37,102.29 v2(145.38,102.27) 145.38,102.2 145.75,101.83 UV14.G12
  BOTTOM w0.127: UV14.G12 145.75,101.83 145.38,102.2 v2(145.38,102.27) ; v2(119.43,111.94) 119.43,111.94 119.69,111.69 119.81,111.69 120.18,111.32 UV1.G13
M_DA0: length 59.7
  IN3 w0.175: v2(118.38,123.91) 118.38,124.11 116.73,125.75 116.73,126.98 121.45,131.69 123.99,131.69 126.52,134.23 148.39,134.23 150.88,131.74 150.88,131.38 153.04,129.22 153.04,123.8 152.61,123.38 152.61,119.23 v2(151.03,117.65)
  BOTTOM w0.127: v2(118.38,123.91) 118.38,123.91 118.45,123.85 118.45,123.1 UV1.K27 ; UV13.A2 v2(151.03,117.65)
M_DA1: length 56
  IN3 w0.175: v2(150.23,117.65) 150.23,117.91 151.59,119.28 151.59,123.33 152.35,124.09 152.35,128.62 149.95,131.01 149.95,131.69 148.1,133.54 126.8,133.54 124.27,131.01 121.73,131.01 117.44,126.72 117.44,125.88 118.38,124.95 v2(118.38,124.74)
  BOTTOM w0.127: v2(118.38,124.74) 118.38,124.74 118.38,124.61 118.86,124.13 UV1.J29 ; UV13.B2 v2(150.23,117.65)
M_DA2: length 49.8
  IN3 w0.175: v2(151.03,120.05) 151.03,123.73 151.45,124.15 151.45,128.55 148.94,131.06 148.94,131.74 147.82,132.86 126.8,132.86 124.47,130.53 124.37,130.53 124.36,130.52 122.28,130.52 122.05,130.29 122.04,130.29 119.31,127.55 119.31,127.55 118.53,126.76 118.53,126.15 v2(118.83,125.85)
  BOTTOM w0.127: v2(151.03,120.05) UV13.A4 ; v2(118.83,125.85) 118.86,125.85 119.34,125.37 119.34,124.67 119.66,124.35 UV1.H30
M_DA3: length 46.5
  IN3 w0.102: v2(150.23,120.05) 150.64,120.46 150.64,128.4
  IN3 w0.175: v2(119.21,126.39) 119.21,126.48 119.79,127.06 119.79,127.35 122.24,129.8 124.7,129.8 126.95,132.05 146.78,132.05 147.06,131.76 147.06,131.32 147.46,130.93 148.39,130.93 150.62,128.7 150.62,128.42 150.64,128.4
  BOTTOM w0.127: v2(119.21,126.39) 119.66,125.95 UV1.H32 ; v2(150.23,120.05) UV13.B4
M_DA4: length 45.3
  IN3 w0.102: 144.92,126.83 145.7,126.83 145.85,126.68 145.85,126.29 146.07,126.07 146.48,126.07 146.65,125.9 146.65,117.69 146.52,117.56 146.31,117.56 v2(146.23,117.65)
  IN3 w0.175: 144.92,126.83 142.86,126.83 142.36,127.32 139.08,127.32 138.96,127.2 137.33,127.2 137.13,127 137.13,125.43 136.95,125.25 136.54,125.25 136.36,125.43 136.36,126.74 136.19,126.92 135.84,126.92 135.66,126.74 135.66,125.43 135.49,125.25 135.14,125.25 134.96,125.43 134.96,126.74 134.79,126.92 134.44,126.92 134.26,126.74 134.26,125.43 134.09,125.25 133.68,125.25 133.51,125.42 133.51,125.8 133.33,125.97 124.57,125.97 122.93,124.33 120.82,124.33 v2(120.78,124.29)
  BOTTOM w0.127: v2(120.78,124.29) 120.78,124.24 UV1.G29 ; UV13.F2 v2(146.23,117.65)
M_DA5: length 45.9
  IN3 w0.102: 144.61,126.33 144.87,126.07 145.55,126.07 145.81,125.8 145.81,121.53 145.41,121.13 145.41,119.87 146.06,119.22 146.21,119.22 v2(146.23,119.25)
  IN3 w0.175: 144.61,126.33 142.51,126.33 141.97,126.86 139.37,126.86 139.19,126.68 138.25,126.68 137.65,126.09 137.65,124.79 137.43,124.57 133.07,124.57 132.89,124.74 132.89,125.12 132.72,125.29 132.37,125.29 132.19,125.12 132.19,124.74 132.01,124.57 131.66,124.57 131.49,124.74 131.49,125.12 131.31,125.29 130.96,125.29 130.79,125.12 130.79,124.09 130.61,123.92 130.26,123.92 130.09,124.09 130.09,125.12 129.91,125.29 128.84,125.29 128.66,125.12 128.66,124.09 128.49,123.92 128.14,123.92 127.96,124.09 127.96,125.12 127.79,125.29 127.44,125.29 127.26,125.12 127.26,124.23 127.08,124.05 126.52,124.05 126.35,123.88 126.35,123.59 126.15,123.39 125.77,123.39 125.6,123.56 125.6,125.12 125.42,125.29 124.99,125.29 124.79,125.09 124.79,123.71 124.61,123.53 121.8,123.53 121.62,123.71 v2(121.62,123.91)
  BOTTOM w0.127: UV13.F4 v2(146.23,119.25) ; UV1.F28 121.26,123.55 v2(121.62,123.91)
M_DA6: length 45.8
  IN3 w0.102: 147.68,127.94 148.21,127.4 148.21,124.69 148.16,124.64 148.16,120.25 148.21,120.2 148.21,119.63 v2(147.83,119.25)
  IN3 w0.175: v2(121.31,125.81) 122.26,125.81 123.38,126.93 123.67,126.93 124.01,127.27 125.81,127.27 126.82,128.28 132.5,128.28 132.69,128.47 132.69,129.06 132.86,129.24 133.21,129.24 133.39,129.06 133.39,128.47 133.56,128.3 133.91,128.3 134.09,128.47 134.09,129.06 134.26,129.24 134.61,129.24 134.79,129.06 134.79,128.47 134.98,128.28 135.3,128.28 135.48,128.46 135.48,129.06 135.65,129.24 136.06,129.24 136.23,129.06 136.23,128.48 136.41,128.31 136.76,128.31 136.93,128.48 136.93,129.06 137.11,129.24 137.61,129.24 137.78,129.06 137.78,128.75 137.96,128.58 138.31,128.58 138.48,128.75 138.48,129.06 138.66,129.24 139.01,129.24 139.19,129.06 139.19,128.75 139.36,128.58 139.71,128.58 139.89,128.75 139.89,129.06 140.06,129.24 141.66,129.24 142.24,128.66 143.11,128.66 143.68,129.24 144.69,129.24 145.46,128.46 147.21,128.46 147.53,128.14 147.53,128.09 147.68,127.94
  BOTTOM w0.127: v2(121.31,125.81) 121.3,125.81 121.3,125.82 121.26,125.77 UV1.F32 ; UV13.E4 v2(147.83,119.25)
M_DA7: length 45.6
  IN3 w0.102: v2(147.03,117.65) 147.41,118.03 147.41,120.2 147.05,120.57 147.05,124.06 147.41,124.43 147.41,126.6 147.15,126.87 146.87,126.87 146.61,127.13 146.61,127.4 146.35,127.67 145.62,127.67
  IN3 w0.175: 145.62,127.67 138.5,127.67 138.43,127.6 132.94,127.6 132.76,127.42 132.76,126.83 132.59,126.66 132.24,126.66 132.06,126.83 132.06,127.42 131.89,127.6 131.47,127.6 131.29,127.42 131.29,126.83 131.12,126.66 130.77,126.66 130.59,126.83 130.59,127.42 130.42,127.6 130.07,127.6 129.89,127.42 129.89,126.83 129.72,126.66 129.37,126.66 129.19,126.83 129.19,127.42 129.01,127.6 128.66,127.6 128.49,127.42 128.49,126.83 128.31,126.66 127.96,126.66 127.79,126.83 127.79,127.42 127.61,127.6 127.26,127.6 127.09,127.42 127.09,126.83 126.91,126.66 124.29,126.66 123.96,126.33 123.45,126.33 122.3,125.18 v2(120.73,125.18)
  BOTTOM w0.127: UV1.F30 121.26,124.59 120.73,125.12 v2(120.73,125.18) ; UV13.E2 v2(147.03,117.65)
M_DA8: length 28.4
  TOP w0.127: v2(147.03,125.65) 146.63,125.25 UV12.M11
  IN1 w0.102: 140.8,126.55 140.8,125.22 141.59,124.43 142.39,124.43 142.52,124.29 145.94,124.29 147.03,125.39 v2(147.03,125.65)
  IN1 w0.145: 140.8,126.55 140.4,126.95 128.7,126.95 v2(126.57,124.83)
  BOTTOM w0.102: 124.43,124.83 124.24,124.83 124.11,124.7 123.35,124.7 122.97,124.32 UV1.C30
  BOTTOM w0.127: 124.43,124.83 v2(126.57,124.83)
M_DA9: length 38.9
  TOP w0.127: v2(150.23,127.25) 149.83,126.85 UV12.T13
  IN1 w0.145: v2(150.23,127.25) 150.64,127.66 150.64,128.21 149.29,129.56 148.85,129.56 147.03,131.37 147.03,131.63 145.99,132.68 128.83,132.68 125.41,129.26 121.18,125.03 121.18,124.13 120.99,123.93 120.99,123.21 v2(120.88,123.1)
  BOTTOM w0.127: v2(120.88,123.1) UV1.F27
M_DA10: length 29.4
  TOP w0.127: v2(147.83,125.65) 147.43,125.25 UV12.N11
  IN1 w0.102: v2(147.83,125.65) 147.1,124.91 147.1,124.11 146.32,123.34 144.64,123.34 144.13,123.85 143.82,123.85 143.3,123.34 137.12,123.34
  IN1 w0.145: v2(125.49,122.97) 126.24,123.73 126.4,123.73 128.97,126.29 134.16,126.29 137.12,123.34
  BOTTOM w0.127: UV1.A28 123.9,123.28 124.61,123.28 124.91,122.97 v2(125.49,122.97)
M_DA11: length 31.8
  TOP w0.127: UV12.T11 149.83,125.25 v2(150.23,124.85)
  IN1 w0.145: v2(150.23,124.85) 149.62,124.24 149.62,123.59 149.05,123.02 136.51,123.02 133.89,125.64 129.24,125.64 126.58,122.98 v2(126.33,122.98)
  BOTTOM w0.127: UV1.C28 122.88,123.52 123.27,123.91 125.4,123.91 v2(126.33,122.98)
M_DA12: length 35.4
  TOP w0.127: UV12.N13 147.43,126.85 v2(147.83,127.25)
  IN1 w0.145: v2(147.83,127.25) 148.23,127.64 148.23,129.13 146.04,131.32 146.04,131.63 145.65,132.02 129.14,132.02 124.73,127.61 122.51,125.39 v2(122.51,123.09)
  BOTTOM w0.102: v2(122.51,123.09) 122.43,123.09 UV1.E27
M_DA13: length 42.7
  TOP w0.127: UV12.U13 150.63,126.85 v2(151.03,127.25)
  IN1 w0.145: v2(151.03,127.25) 151.16,127.38 151.16,128.61 149.56,130.21 149.15,130.21 147.99,131.37 147.99,131.63 146.29,133.33 127.66,133.33 120,125.67 120,123.25 v2(120.86,122.39)
  BOTTOM w0.102: v2(120.86,122.39) 120.86,122.32 UV1.G26
M_DA14: length 34.2
  TOP w0.127: UV12.M13 146.63,126.85 v2(147.03,127.25)
  IN1 w0.145: v2(122.45,122.4) 122.46,122.4 122.98,122.92 122.98,123.28 123.08,123.38 123.08,123.79 123.15,123.85 123.15,124.55 123.57,124.97 123.57,125.22 123.77,125.42 124,125.42 124.24,125.66 124.24,126.14 129.31,131.21 132.91,131.21 133.19,130.92 142.69,130.92 142.82,131.05 145.67,131.05 147.49,129.23 147.49,127.69 147.05,127.25 v2(147.03,127.25)
  BOTTOM w0.127: UV1.D26 122.5,121.95 122.5,122.34 122.45,122.39 v2(122.45,122.4)
M_DA15: length 34.6
  TOP w0.127: UV12.U11 150.63,125.25 v2(151.03,124.85)
  IN1 w0.145: v2(121.65,121.4) 121.65,121.41 121.77,121.52 123.36,121.52 124.14,122.3 126.82,122.3 129.51,124.99 133.5,124.99 136.12,122.37 149.48,122.37 151.03,123.92 v2(151.03,124.85)
  BOTTOM w0.102: v2(121.65,121.4) 121.62,121.4 121.34,121.12 UV1.F25
M_DA16: length 21.6
  TOP w0.127: v2(141.43,119.25) 141.83,119.64 UV12.F4
  IN3 w0.175: v2(141.43,119.25) 141.43,121.03 140.78,121.68 138.24,121.68 137.61,122.32 127.59,122.32 126.89,121.62 126.12,121.62 125.82,121.31 125.31,121.31 125.05,121.05 v2(125.05,120.8)
  BOTTOM w0.102: v2(125.05,120.8) 124.99,120.74 124.54,120.74 124.16,121.12 UV1.A25
M_DA17: length 18.2
  TOP w0.127: UV12.B4 138.63,119.65 v2(139.03,120.05)
  IN3 w0.175: v2(125.82,120.87) 126.44,120.24 128.14,120.24 128.85,120.95 138.13,120.95 v2(139.03,120.05)
  BOTTOM w0.102: 123.97,121.56 123.67,121.56 123.23,121.12 UV1.C25
  BOTTOM w0.127: v2(125.82,120.87) 125.1,121.58 v1(125.05,121.58) 123.99,121.58 123.97,121.56
M_DA18: length 23
  TOP w0.127: v2(140.63,119.25) 141.03,119.64 UV12.E4
  IN3 w0.175: v2(140.63,119.25) 141.05,119.66 141.05,121.02 140.66,121.41 137.56,121.41 137.34,121.63 127.87,121.63 127.17,120.93 v2(126.7,120.93)
  BOTTOM w0.102: UV1.E25 122.31,121.12 122.65,121.46 123.23,121.46 123.89,122.12
  BOTTOM w0.127: 123.89,122.12 123.99,122.22 125.41,122.22 v1(126.32,121.31) v2(126.7,120.93)
M_DA19: length 17.4
  TOP w0.127: UV12.A4 137.83,119.65 v2(138.23,120.05)
  IN3 w0.175: v2(138.23,120.05) 137.13,120.05 136.91,120.27 136.77,120.27 136.76,120.27 129.13,120.27 128.51,119.65 126.07,119.65 125.81,119.91 125.21,119.91 125.11,120.01 124.66,120.01 v2(124.38,120.29)
  BOTTOM w0.102: v2(124.38,120.29) 124.38,120.47 124.15,120.7 123.21,120.7 122.83,120.32 UV1.D24
M_DA20: length 18.8
  TOP w0.127: UV12.B2 138.63,118.04 v2(138.23,117.65)
  IN3 w0.102: v2(122.45,119.21) 122.45,118.9 122.84,118.5 122.84,118.1 123.31,117.63 124.1,117.63
  IN3 w0.175: v2(138.23,117.65) 137.13,116.54 125.18,116.54 124.1,117.63
  BOTTOM w0.102: UV1.E23 122.36,119.21 v2(122.45,119.21)
M_DA21: length 23.7
  TOP w0.127: UV12.E2 141.03,118.04 v2(140.63,117.65)
  IN3 w0.102: v2(140.63,117.65) 140.38,117.4 140.38,115.84 140.37,115.83 ; 124.15,116.8 123.36,116.8 122.8,117.36 122.71,117.36 122.07,118.01 122.07,118.35 122.13,118.41 122.13,118.65 v2(121.69,119.09)
  IN3 w0.175: 140.37,115.83 140.25,115.72 138.08,115.72 137.86,115.94 125.01,115.94 124.15,116.8
  BOTTOM w0.102: UV1.F23 v2(121.69,119.09)
M_DA22: length 17.2
  TOP w0.127: UV12.A2 v2(137.42,117.64)
  IN3 w0.175: v2(137.42,117.64) 136.83,117.05 125.58,117.05 124.73,117.89 124.73,118.47 124.43,118.77 123.65,118.77 v2(123.22,119.2)
  BOTTOM w0.127: v2(123.22,119.2) 122.74,118.72 UV1.D22
M_DA23: length 25.1
  TOP w0.127: v2(141.47,117.65) 141.83,118 UV12.F2
  IN3 w0.175: v2(120.78,118.08) 121.57,118.08 122.55,117.09 122.73,117.09 123.26,116.56 123.92,116.56 125.01,115.47 125.01,115.43 125.19,115.26 137.57,115.26 137.8,115.03 140.54,115.03 140.94,115.43 140.94,115.43 141.47,115.97 v2(141.47,117.65)
  BOTTOM w0.127: UV1.F21 121.1,118.08 v2(120.78,118.08)
M_DA24: length 32.8
  BOTTOM w0.102: 124.52,117.96 124.18,117.61 122.36,117.61 UV1.E21
  BOTTOM w0.127: UV13.M11 142.21,125.63 142.21,128.63 141.86,128.98 141.86,129.15 140.06,130.95 134.71,130.95 v1(134.45,130.7) 130.13,126.37 130.13,123.44 126.87,120.18 125.62,120.18 125.13,119.69 125.13,119.11 124.55,118.54 124.55,117.99 124.52,117.96
M_DA25: length 29
  BOTTOM w0.102: 141.4,128.54 141.4,127.28 UV13.M13 ; UV1.D20 122.83,117.12 123.13,116.81 123.39,116.81 123.4,116.83 123.9,116.83 124.78,117.71
  BOTTOM w0.127: 141.4,128.54 141.12,128.83 141.12,129 139.8,130.32 135.82,130.32 v1(134.54,129.04) 130.77,125.27 130.77,123.18 127.13,119.54 125.88,119.54 124.78,118.45 124.78,117.71
M_DA26: length 28.9
  BOTTOM w0.102: 140.4,128.81 140.4,128.64 140.61,128.43 140.61,127.27 141.03,126.86 UV13.N13 ; UV1.F19 121.63,116.32 121.93,116.62 122.99,116.62 123,116.61 123.52,116.61 123.53,116.62 124,116.62 125,117.62 125,118.36 125.37,118.72 125.46,118.72
  BOTTOM w0.127: 140.4,128.81 139.53,129.68 136.08,129.68 v1(134.03,127.63) 131.4,125 131.4,122.89 127.24,118.72 125.46,118.72
M_DA27: length 26.8
  BOTTOM w0.102: 139.59,128.58 139.75,128.43 139.75,127.66 140.09,127.32 140.21,127.32 140.68,126.85 140.68,125.59 UV13.N11 ; UV1.A19 123.68,116.34 124,116.34 125.06,117.39 125.2,117.53 125.2,117.89 125.4,118.09
  BOTTOM w0.127: 139.59,128.58 139.13,129.05 138.72,129.05 138.72,129.05 137.05,129.05 136.53,129.05 136.52,129.05 136.34,129.05 v1(133.46,126.16) 132.04,124.74 132.04,124.56 132.03,124.56 132.03,122.63 127.49,118.09 125.43,118.09 125.43,118.09 125.4,118.09
M_DA28: length 21.8
  BOTTOM w0.102: UV1.D18 122.83,115.52 122.92,115.43 123.13,115.21 123.39,115.21 123.43,115.26 123.88,115.26 124,115.14 124.32,115.14 125.02,115.84
  BOTTOM w0.127: 125.02,115.84 125.5,115.84 125.5,115.85 128.78,115.85 v1(133.56,120.63) 135.53,122.59 135.53,124.99 136.99,126.45 137.43,126.45 UV13.U13
M_DA29: length 24
  BOTTOM w0.102: 125.24,115.38 124.85,115.38 124.4,114.93 123.92,114.93 123.8,115.05 123.51,115.05 123.47,115.01 123.05,115.01 122.97,115.09 121.63,115.09 UV1.F17
  BOTTOM w0.127: UV13.T13 138.23,126.45 137.76,126.45 136.16,124.86 136.16,122.33 v1(132.94,119.1) 129.22,115.38 125.24,115.38
M_DA30: length 20
  BOTTOM w0.102: UV1.A17 125.28,114.72
  BOTTOM w0.127: UV13.U11 137.45,125.25 136.67,124.47 136.67,121.94 v1(132.05,117.31) 129.49,114.75 125.31,114.75 125.28,114.72
M_DA31: length 22.3
  BOTTOM w0.102: UV1.C17 123.22,114.72 123.53,114.41 125.11,114.41 125.41,114.11
  BOTTOM w0.127: 125.41,114.11 129.75,114.11 v1(131.27,115.64) 137.37,121.74 137.37,124.57 137.62,124.81 138.2,124.81 UV13.T11
M_DA32: length 45.1
  IN3 w0.175: v2(150.23,100.63) 150.78,101.18 150.78,102.02 151.07,102.31 151.07,104.58 152.14,105.65 152.14,112.33 150.47,114 136.43,114 135.85,114.57 121.79,114.57 v2(121.66,114.44)
  BOTTOM w0.102: UV1.E17 121.79,114.45 121.65,114.45 121.65,114.45 121.65,114.44 v2(121.66,114.44)
  BOTTOM w0.127: UV15.U13 v2(150.23,100.63)
M_DA33: length 41.4
  IN3 w0.175: v2(125.05,113.68) 125.26,113.89 135.57,113.89 136.14,113.32 150.19,113.32 151.46,112.05 151.46,105.94 150.79,105.27 150.79,102.72 v2(150.31,102.24)
  BOTTOM w0.102: v2(125.05,113.68) 125.05,113.93 124.77,114.21 123.44,114.21 123.28,114.37 122.74,114.37 122.46,114.1 UV1.D16
  BOTTOM w0.127: v2(150.31,102.24) 150.31,102.31 UV15.U11
M_DA34: length 39.9
  IN3 w0.175: v2(122.45,112.84) 122.43,112.84 122.01,113.26 122.01,113.7 122.22,113.9 123.28,113.9 123.77,113.41 123.86,113.41 124.61,112.67 134.86,112.67 135.55,111.98 147.43,111.98 147.85,111.56 147.85,110.87 148.19,110.53 148.19,109.16 149.05,108.3 149.05,107.29 149.13,107.21 149.13,105.49 149.01,105.37 149.01,102.61 v2(149.37,102.25)
  BOTTOM w0.102: UV1.F15 121.35,113.12 121.65,112.81 122.43,112.81 v2(122.45,112.84)
  BOTTOM w0.127: UV15.T11 149.45,102.25 v2(149.37,102.25)
M_DA35: length 40.6
  IN3 w0.175: v2(124.49,113.7) 124.49,113.38 124.66,113.21 135.29,113.21 135.86,112.63 149.91,112.63 150.7,111.83 150.7,110.6 150.6,110.5 150.6,109.42 150.65,109.38 150.65,105.52 149.9,104.77 149.9,101.09 v2(149.43,100.63)
  BOTTOM w0.102: v2(124.49,113.7) 124.49,113.58 124.02,113.12 UV1.A15
  BOTTOM w0.127: UV15.T13 v2(149.43,100.63)
M_DA36: length 32.3
  IN3 w0.175: v2(125.43,110.41) 125.57,110.28 125.57,110.28 125.97,109.87 131.26,109.87 132.46,108.68 132.46,108.68 132.6,108.54 137.35,108.54 137.62,108.27 137.62,107.45 138.79,106.29 145.91,106.29 147.43,104.76 147.43,102.53 v2(147.74,102.23)
  BOTTOM w0.102: UV1.D14 122.91,111.87 123.7,111.87 123.76,111.81 124.9,111.81 v1(125.04,111.67) 125.29,111.42 125.29,110.55 v2(125.43,110.41)
  BOTTOM w0.127: v2(147.74,102.23) 147.74,102.32 UV15.N11
M_DA37: length 34.5
  IN3 w0.175: v2(120.3,111.83) 121.24,110.89 121.24,110.07 121.86,109.46 123.05,109.46 124.23,108.29 124.92,108.29 125.75,107.46 125.97,107.46 126.45,106.98 130.06,106.98 130.77,106.27 137.25,106.27 138.07,105.45 143.48,105.45 143.67,105.27 144.66,105.27 145.73,104.2 145.73,102.9 145.8,102.83 145.8,101.06 v2(146.23,100.63)
  BOTTOM w0.127: UV15.M13 v2(146.23,100.63) ; UV1.F13 121.06,111.52 120.75,111.83 v2(120.3,111.83)
M_DA38: length 31.3
  IN3 w0.175: v2(147.06,102.24) 147.01,102.29 147.01,104.8 145.8,106.01 138.68,106.01 137.25,107.43 131.54,107.43 130.95,108.03 130.95,108.28 131.3,108.63 131.3,108.88 131.05,109.12 130.8,109.12 130.45,108.77 130.2,108.77 129.78,109.19 125.47,109.19 124.76,109.9 v2(124.76,110.41)
  BOTTOM w0.102: UV1.A13 123.86,111.31 124.61,111.31 124.76,111.16 v2(124.76,110.41)
  BOTTOM w0.127: v2(147.06,102.24) 147.06,102.24 147.01,102.24 UV15.M11
M_DA39: length 32.6
  IN3 w0.175: v2(124.18,110.41) 124.18,108.89 124.41,108.67 124.43,108.67 124.43,108.66 125.18,108.66 125.33,108.51 129.5,108.51 131.06,106.95 137.34,106.95 138.56,105.73 145.68,105.73 146.65,104.77 146.65,102 146.61,101.96 146.61,101.05 v2(147.03,100.63)
  BOTTOM w0.102: v2(124.18,110.41) 124.18,110.82 123.89,111.11 123.27,111.11 UV1.C13
  BOTTOM w0.127: UV15.N13 v2(147.03,100.63)
M_DA40: length 32.1
  TOP w0.127: v2(150.16,110.21) 150.16,110.16 UV14.B2
  IN1 w0.145: v2(150.16,110.21) 149.76,110.6 149.76,111.45 149.53,111.69 149.53,111.98 148.08,113.42 147.79,113.42 147.72,113.49 132.74,113.49 130.62,111.38 123.79,111.38 v2(122.86,110.45)
  BOTTOM w0.102: UV1.E11 122.58,110.44 122.85,110.44 v2(122.86,110.45)
M_DA41: length 38.6
  TOP w0.127: v2(150.17,107.8) 150.6,108.23 UV14.A4
  IN1 w0.145: v2(126.92,111.96) 126.92,112.32 129.77,115.18 149.83,115.18 152.01,112.99 152.01,109.64 v2(150.17,107.8)
  BOTTOM w0.127: v2(126.92,111.96) 126.92,111.34 v1(126.72,111.14) 125.54,109.97 123.71,109.97 UV1.A11
M_DA42: length 34.9
  TOP w0.127: UV14.A2 150.63,109.83 v2(151.04,110.24)
  IN1 w0.145: v2(127.63,111.94) 127.63,112.07 128.23,112.68 130.08,114.52 148.92,114.52 151.36,112.08 151.36,110.56 v2(151.04,110.24)
  BOTTOM w0.102: UV1.C11 123.23,109.92 123.53,109.61 123.79,109.61 123.89,109.71 124.99,109.71 125.2,109.5 125.95,109.5 v1(126.24,109.78) 127.63,111.17 v2(127.63,111.94)
M_DA43: length 38.6
  TOP w0.127: UV14.B4 149.52,107.92 149.52,107.88 v2(149.46,107.83)
  IN1 w0.145: v2(149.46,107.83) 149.46,108.59 150.58,109.7 150.58,110.5 150.71,110.63 150.71,111.81 148.45,114.06 130.54,114.06 v2(128.38,111.9)
  BOTTOM w0.102: UV1.F11 121.56,109.61 122.19,109.61 122.29,109.71 122.58,109.71 122.68,109.61 123.25,109.61 123.45,109.41 124.07,109.41 124.12,109.46 124.95,109.46 125.53,108.89 126.21,108.89 v1(128.38,111.06) v2(128.38,111.9)
M_DA44: length 26.5
  TOP w0.127: v2(147.77,110.2) 147.77,110.17 UV14.E2
  IN1 w0.145: v2(126.71,108.06) 126.71,108.33 127.39,109.01 133.28,109.01 133.48,109.21 133.49,109.21 134.96,110.68 143.7,110.68 143.97,110.96 144.93,110.96 145.21,110.68 147.28,110.68 v2(147.77,110.2)
  BOTTOM w0.102: 125.53,108.1 125.25,108.38 v1(125.06,108.38) 123.72,108.38 UV1.A9
  BOTTOM w0.127: 125.53,108.1 126.67,108.1 v2(126.71,108.06)
M_DA45: length 26.6
  TOP w0.127: UV14.F2 146.63,109.87 v2(146.99,110.23)
  IN1 w0.145: v2(127.49,108.07) 127.98,108.56 133.76,108.56 135.23,110.03 137.69,110.03 138.03,110.38 143.77,110.38 144.1,110.71 144.83,110.71 145.16,110.38 146.84,110.38 v2(146.99,110.23)
  BOTTOM w0.102: 125.59,107.47 125.05,108.01 123.53,108.01 123.48,108.06 123.12,108.06 UV1.C9
  BOTTOM w0.127: 125.59,107.47 v1(126.33,107.47) 126.93,107.47 127.49,108.03 v2(127.49,108.07)
M_DA46: length 29.3
  TOP w0.127: UV14.F4 v2(147.03,108.63)
  IN1 w0.145: v2(147.03,108.63) 146.63,108.23 145.94,108.23 144.3,109.88 138.23,109.88 137.73,109.38 135.22,109.38 133.74,107.9 128.47,107.9 v2(128.31,108.06)
  BOTTOM w0.102: UV1.F9 121.63,108.32 122.09,107.86 123.4,107.86 123.45,107.81 124.73,107.81 125.71,106.83
  BOTTOM w0.127: 125.71,106.83 127.19,106.83 v1(127.72,107.36) 128.31,107.95 v2(128.31,108.06)
M_DA47: length 30.4
  TOP w0.127: UV14.E4 v2(147.83,108.63)
  IN1 w0.145: v2(124.72,106.83) 125.15,107.27 135.42,107.27 135.56,107.41 135.56,108.58 135.71,108.73 136,108.73 136.14,108.58 136.14,107.8 136.29,107.65 136.64,107.65 136.79,107.8 136.79,108.6 137.22,109.03 144.8,109.03 145.9,107.92 147.12,107.92 v2(147.83,108.63)
  BOTTOM w0.102: v2(124.72,106.83) 124.71,106.83 124.15,106.83 124.05,106.93 123.88,106.93 123.6,107.21 123.13,107.21 122.83,107.52 UV1.D8
M_DA48: length 23.3
  TOP w0.127: UV14.M11 v2(141.43,102.23)
  IN3 w0.175: v2(141.43,102.23) 141.62,102.42 141.62,104.35 141.31,104.67 127.21,104.67 126.55,105.33 125.86,105.33 124.78,106.41 v2(122.43,106.41)
  BOTTOM w0.127: UV1.E7 122.37,106.41 v2(122.43,106.41)
M_DA49: length 21.7
  TOP w0.127: UV14.N11 v2(140.63,102.23)
  IN3 w0.175: v2(140.63,102.23) 141.05,102.65 141.05,103.91 140.57,104.39 137.98,104.39 137.57,103.98 126.93,103.98 126.26,104.65 125.6,104.65 125.17,105.08 v2(125.17,105.43)
  BOTTOM w0.127: v2(125.17,105.43) 125.17,105.44 125.17,105.53 124.35,106.35 123.88,106.35 123.66,106.57 UV1.A7
M_DA50: length 17.9
  TOP w0.127: UV14.T11 v2(138.23,103.03)
  IN3 w0.175: v2(138.23,103.03) 137.8,103.46 126.49,103.46 125.98,103.97 125.4,103.97 124.62,104.75 v2(124.62,105.53)
  BOTTOM w0.127: v2(124.62,105.53) 124.38,105.53 123.19,106.72 UV1.C7
M_DA51: length 29.2
  TOP w0.127: UV14.M13 v2(141.43,100.63)
  IN3 w0.175: v2(121.72,106.35) 122.27,105.8 122.27,104.27 122.04,104.04 122.04,103.77 121.75,103.48 121.75,101.68 122.19,101.24 122.18,101.23 122.18,100.67 122.27,100.58 122.27,100.4 124.36,98.31 139.87,98.31 140.93,99.37 140.93,100.12 v2(141.43,100.63)
  BOTTOM w0.127: UV1.F7 121.35,106.72 v2(121.72,106.35)
M_DA52: length 15.4
  TOP w0.127: UV14.U11 137.57,102.37 v2(137.4,102.37)
  IN3 w0.175: v2(137.4,102.37) 137.07,102.7 126.28,102.7 125.16,103.82 124.93,103.82 v2(123.99,104.76)
  BOTTOM w0.102: v2(123.99,104.76) 123.99,104.79 UV1.A5
M_DA53: length 25
  TOP w0.127: UV14.N13 v2(140.63,100.63)
  IN3 w0.175: v2(140.63,100.63) 140.25,100.25 140.25,99.65 139.59,99 124.82,99 122.03,101.79 122.03,103.36 122.46,103.79 v2(122.46,103.87)
  BOTTOM w0.102: UV1.E5 122.46,104.72 v2(122.46,103.87)
M_DA54: length 18.2
  TOP w0.127: UV14.U13 v2(137.43,100.63)
  IN3 w0.175: v2(137.43,100.63) 136.76,99.96 125.51,99.96 123.72,101.75 123.72,103.46 v2(123.27,103.91)
  BOTTOM w0.102: UV1.C3 v2(123.27,103.91)
M_DA55: length 19.4
  TOP w0.127: UV14.T13 v2(138.23,100.63)
  IN3 w0.175: v2(122.44,103.18) 122.42,103.16 122.42,102.36 125.31,99.48 137.08,99.48 v2(138.23,100.63)
  BOTTOM w0.102: UV1.E1 122.39,103.18 v2(122.44,103.18)
M_DA56: length 41.2
  BOTTOM w0.102: 122.24,102.08 121.88,102.45 121.06,102.45 120.84,102.67 120.84,103.18 120.97,103.31 120.97,103.73 120.83,103.86 120.83,103.96 120.76,104.03 120.76,104.66 120.97,104.86 120.97,105.65 120.86,105.76 120.86,106.32 UV1.G7
  BOTTOM w0.127: UV15.F4 141.83,108.23 142.24,108.64 142.24,109.99 142.51,110.26 142.77,110.26 143.03,110.52 143.03,111.78 142.91,111.9 142.91,113.16 141.09,114.97 135.6,114.97 v1(135.27,114.64) 130.46,109.83 130.46,105.18 127.36,102.08 122.24,102.08
M_DA57: length 37.6
  BOTTOM w0.102: UV1.G6 120.46,105.63 120.76,105.33 120.76,104.94 120.54,104.72 120.31,104.72 120.12,104.53 120.12,104.23 120.16,104.19 120.16,104.14 120.17,104.13 120.17,103.71 120.16,103.7 120.16,103.66 120.15,103.65 120.15,102.86 120.18,102.83
  BOTTOM w0.127: 120.18,102.83 120.18,102.36 120.83,101.71 121.6,101.71 122.13,101.18 122.42,101.18 123.25,100.35 128.32,100.35 132.2,104.23 132.2,108.6 v1(133.59,110) 136.7,113.11 139.47,113.11 140.63,111.95 140.63,108.63 140.63,108.63 141.03,108.23 UV15.E4
M_DA58: length 33.8
  BOTTOM w0.127: UV1.G1 120.41,103.47 120.41,102.46 120.93,101.94 121.69,101.94 122.22,101.41 123.09,101.41 123.58,100.92 127.99,100.92 131.73,104.66 131.73,109.1 v1(134.07,111.45) 136.37,113.75 139.91,113.75 141.42,112.23 141.42,110.22 UV15.E2
M_DA59: length 35.9
  BOTTOM w0.102: 120.64,102.55 120.64,102.57 120.62,102.58 120.62,102.76 120.64,102.78 120.64,103.26 120.76,103.39 120.76,103.64 120.63,103.78 120.63,103.87 120.46,104.04 UV1.G3
  BOTTOM w0.127: UV15.F2 141.83,110.15 142.21,110.53 142.21,112.34 141.42,113.13 141.42,113.75 140.83,114.34 135.86,114.34 v1(134.65,113.12) 131.1,109.57 131.1,104.92 127.62,101.45 123.67,101.45 123.48,101.64 122.32,101.64 121.72,102.23 120.96,102.23 120.64,102.55
M_DA60: length 33.9
  BOTTOM w0.102: 118.7,101.57 118.55,101.73 118.55,103.64 118.64,103.73 118.64,104.1 118.53,104.2 118.53,104.43 118.85,104.74 118.93,104.74 119.16,104.97 119.16,104.99 119.16,104.99 119.16,105.26 118.96,105.47 118.96,105.82 UV1.J6
  BOTTOM w0.127: UV15.A4 137.35,108.23 137.34,108.24 137.06,108.24 136.19,107.37 136.19,103.45 v1(135.3,102.56) 129.57,96.84 122.04,96.84 119.04,99.83 119.04,101.23 118.7,101.57
M_DA61: length 31.7
  BOTTOM w0.102: UV1.J1 118.75,103.41 118.75,101.83 119.31,101.27 119.36,101.27
  BOTTOM w0.127: 119.36,101.27 119.68,100.95 119.68,99.88 122.19,97.36 129.2,97.36 135.45,103.62 v1(135.45,104.86) 135.45,107.82 136.82,109.19 137.51,109.19 137.69,109.37 138.17,109.37 UV15.B2
M_DA62: length 30.9
  BOTTOM w0.102: 119.65,101.47 118.95,102.17 118.95,103.18 119.16,103.39 119.16,103.69 118.93,103.92 118.93,104.25 UV1.J3
  BOTTOM w0.127: 119.65,101.47 119.79,101.47 120.15,101.11 120.15,100.29 122.49,97.94 129.07,97.94 134.61,103.48 134.61,104.75 v1(134.61,106.13) 134.61,107.82 136.62,109.83 UV15.A2
M_DA63: length 34.9
  BOTTOM w0.102: 118.58,100.02 118.58,101.21 118.34,101.45 118.34,103.32 118.33,103.34 118.33,103.7 118.39,103.77 118.39,104.06 118.32,104.13 118.32,104.52 118.86,105.06 UV1.J5
  BOTTOM w0.127: UV15.B4 138.63,108.23 138.23,107.83 137.59,107.83 137.05,107.29 137.05,103.42 v1(134.28,100.65) 129.83,96.2 121.46,96.2 120.41,97.24 120.41,97.56 118.58,99.4 118.58,100.02
M_DBI0#: length 46.2
  IN3 w0.102: v2(148.63,117.65) 149.01,118.03 149.01,120.2 148.8,120.42 148.8,123.63 149.06,123.89 149.06,124.2 149.01,124.25 149.01,127.4 148.75,127.67 148.47,127.67 148.25,127.89 148.25,128.23
  IN3 w0.175: 148.25,128.23 148.25,128.39 148.02,128.62 148.02,128.62 147.49,129.15 146.72,129.15 146.59,129.27 145.62,129.27 144.97,129.92 144.97,129.92 144.89,130 132.36,130 131.42,129.07 126.48,129.07 125.44,128.02 123.79,128.02 122.15,126.39 120.68,126.39 120.17,125.88 120.17,123.88 119.4,123.11 v2(119.38,123.11)
  BOTTOM w0.127: v2(119.38,123.11) 119.4,123.11 119.4,122.98 UV1.H27 ; UV13.D2 v2(148.63,117.65)
M_DBI1#: length 31.7
  TOP w0.127: UV12.P13 148.23,126.85 v2(148.63,126.45)
  IN1 w0.102: v2(148.63,126.45) 148.25,126.07 146.07,126.07 145.85,126.29 145.85,126.29 145.81,126.33 145.81,127.21 145.77,127.26
  IN1 w0.145: v2(124.32,122.77) 124.35,122.8 124.35,123.57 129.32,128.54 137.17,128.54 137.67,129.04 141.09,129.04 141.39,128.74 142.93,128.74 143.53,129.34 144.78,129.34 145.77,128.34 145.77,127.26
  BOTTOM w0.127: UV1.A27 124.27,122.72 v2(124.32,122.77)
M_DBI2#: length 19.5
  TOP w0.127: UV12.D2 140.23,118.04 v2(139.83,117.65)
  IN3 w0.102: 138.82,118.83 139.19,118.83 139.41,118.6 139.41,118.06 v2(139.83,117.65)
  IN3 w0.175: 138.82,118.83 138.06,118.83 137.3,119.58 129.41,119.58 128.71,118.88 125.83,118.88 124.97,119.74 124.08,119.74 124.01,119.81 v2(123.24,119.81)
  BOTTOM w0.127: v2(123.24,119.81) 122.95,119.52 UV1.C23
M_DBI3#: length 24.8
  BOTTOM w0.102: UV13.P13 139.81,127.27 139.26,127.27 138.96,127.57 138.96,127.91 ; UV1.C19 123.1,116.08 123.45,116.08 123.53,116 123.82,116 123.95,116.13 124.09,116.13 125.2,117.24 125.22,117.24
  BOTTOM w0.127: 125.22,117.24 125.43,117.45 127.91,117.45 132.67,122.22 v1(132.67,124.47) 136.61,128.41 138.46,128.41 138.96,127.91
M_DBI4#: length 35.6
  IN3 w0.175: v2(147.83,100.63) 147.83,101.63 148.27,102.07 148.27,106.38 147.05,107.61 146.24,107.61 143.96,109.88 138.54,109.88 138.02,109.36 132.74,109.36 131.54,110.56 126.25,110.56 125.98,110.83 125.92,110.89 125.33,110.89 125.2,111.02 124.17,111.02 123.24,111.94 v2(123.24,112.82)
  BOTTOM w0.127: UV15.P13 v2(147.83,100.63) ; v2(123.24,112.82) 122.94,113.12 UV1.C15
M_DBI5#: length 29.6
  TOP w0.127: v2(148.61,110.21) 148.61,110.21 UV14.D2
  IN1 w0.145: v2(122.45,108.6) 122.85,108.2 125.01,108.2 126.47,109.66 133.01,109.66 133.21,109.86 133.22,109.86 135.06,111.71 147.37,111.71 147.85,111.23 147.85,110.97 v2(148.61,110.21)
  BOTTOM w0.102: v2(122.45,108.6) 122.34,108.6 UV1.E9
M_DBI6#: length 20.5
  TOP w0.127: UV14.P13 v2(139.83,101.43)
  IN3 w0.175: v2(124.99,103.4) 124.99,102.96 126.02,101.93 137.52,101.93 137.64,101.81 139.45,101.81 v2(139.83,101.43)
  BOTTOM w0.102: v2(124.99,103.4) 124.99,104.62 123.98,105.63 123.45,105.63 122.94,105.12 UV1.C5
M_DBI7#: length 33.8
  BOTTOM w0.102: 119.95,102.79 119.95,102.79 119.95,103.73 119.96,103.74 119.96,103.78 119.96,103.79 119.96,104.04 119.96,104.05 119.96,104.1 119.66,104.4 UV1.H4
  BOTTOM w0.127: 119.95,102.79 119.95,102.27 120.74,101.48 121.21,101.48 123.16,99.54 128.41,99.54 132.83,103.96 132.83,108.3 v1(132.87,108.34) 136.96,112.43 139.07,112.43 139.85,111.66 139.85,110.21 UV15.D2
M_EDC_0: length 51.8
  IN3 w0.102: v2(149.43,117.65) 149.43,117.68 149.82,118.07 149.82,128.25 149.45,128.61 149.28,128.61
  IN3 w0.175: 149.28,128.61 149.28,128.61 147.86,130.04 147.09,130.04 146.96,130.16 145.99,130.16 145.34,130.81 145.33,130.81 145.19,130.96 131.55,130.96 131.23,130.63 131.23,130.13 131.05,129.96 130.7,129.96 130.53,130.13 130.53,130.67 130.35,130.85 130,130.85 129.83,130.67 129.83,130.13 129.65,129.96 129.3,129.96 129.12,130.13 129.12,130.66 128.95,130.83 128.6,130.83 128.42,130.66 128.42,130.13 128.25,129.96 127.9,129.96 127.72,130.13 127.72,130.68 127.55,130.86 127.18,130.86 126.99,130.67 126.99,130.13 126.82,129.96 126.11,129.96 125.07,128.91 122.61,128.91 119.59,125.89 119.59,124.13 v2(119.36,123.89)
  BOTTOM w0.127: UV13.C2 v2(149.43,117.65) ; v2(119.36,123.89) 119.66,123.59 UV1.H28
M_EDC_1: length 35.1
  TOP w0.127: UV12.R13 149.03,126.85 v2(148.63,127.25)
  IN1 w0.102: 146.63,128.35 146.64,128.34 146.64,127.06 146.83,126.87 148.25,126.87 v2(148.63,127.25)
  IN1 w0.145: 146.63,128.35 146.63,128.69 145.13,130.19 143.17,130.19 143.04,130.06 141.19,130.06 141.03,129.9 137.11,129.9 136.61,129.4 132.96,129.4 132.82,129.55 132.82,130.08 132.68,130.23 132.39,130.23 132.24,130.08 132.24,129.55 132.1,129.4 131.81,129.4 131.66,129.55 131.66,130.08 131.52,130.23 131.23,130.23 131.08,130.08 131.08,129.55 130.94,129.4 128.97,129.4 124.3,124.74 124.05,124.74 123.81,124.49 123.81,123.67 123.4,123.26 123.4,123.13 v2(123.38,123.11)
  BOTTOM w0.127: UV1.C27 123.23,123.09 123.36,123.09 v2(123.38,123.11)
M_EDC_2: length 17.6
  TOP w0.127: v2(139.03,117.65) 139.43,118.04 UV12.C2
  IN3 w0.175: v2(124.73,119.28) 125.24,118.77 125.24,118.21 125.46,117.99 129.08,117.99 129.5,118.41 138.26,118.41 v2(139.03,117.65)
  BOTTOM w0.102: UV1.A23 123.86,119.72 124.29,119.72 v2(124.73,119.28)
M_EDC_3: length 25.9
  BOTTOM w0.102: UV1.E19 122.06,115.94 122.16,115.84 123.41,115.84 123.46,115.78 123.88,115.78 124,115.9 124.45,115.9
  BOTTOM w0.127: 124.45,115.9 125.21,116.65 128.24,116.65 133.74,122.15 v1(133.74,122.48) 133.74,123.21 133.86,123.33 134.51,123.33 134.64,123.46 134.64,123.71 134.51,123.84 133.86,123.84 133.74,123.97 133.74,124.23 133.86,124.36 134.51,124.36 134.54,124.38 134.54,125.13 136.66,127.25 137.45,127.25 137.51,127.18 138.83,127.18 139.17,126.85 UV13.R13
M_EDC_4: length 38.8
  IN3 w0.175: v2(148.63,100.63) 148.95,100.95 148.95,101.69 148.67,101.97 148.67,106.37 147.16,107.88 146.36,107.88 143.99,110.25 136.62,110.25 136.44,110.43 136.44,110.91 136.27,111.09 135.92,111.09 135.74,110.91 135.74,110.43 135.57,110.25 135.22,110.25 135.04,110.43 135.04,110.91 134.87,111.09 134.52,111.09 134.34,110.91 134.34,110.43 134.17,110.25 133.11,110.25 131.91,111.45 126.62,111.45 126.35,111.72 126.35,111.72 126.29,111.78 125.33,111.78 125.2,111.91 124.8,111.91 124.1,112.61 124.04,112.61 123.21,113.44 v2(122.48,113.44)
  BOTTOM w0.102: UV1.E15 122.38,113.44 v2(122.48,113.44)
  BOTTOM w0.127: UV15.R13 v2(148.63,100.63)
M_EDC_5: length 32.1
  TOP w0.127: UV14.C2 v2(149.44,110.24)
  IN1 w0.145: v2(149.44,110.24) 148.67,111.02 148.67,111.62 147.73,112.56 134.7,112.56 134.01,111.87 133.81,111.87 133.42,112.26 133.21,112.26 133.01,112.06 133.01,111.85 133.4,111.46 133.4,111.26 132.86,110.72 132.86,110.72 132.66,110.52 126.11,110.52 126.1,110.51 125.07,109.48 124.44,109.48 123.56,108.61 v2(123.25,108.61)
  BOTTOM w0.102: v2(123.25,108.61) 123.17,108.61 122.66,109.12 UV1.D10
M_EDC_6: length 22.7
  TOP w0.127: UV14.R13 v2(139.81,100.65)
  IN3 w0.175: v2(139.81,100.65) 139.41,101.05 125.76,101.05 124.34,102.46 v2(124.34,103.4)
  BOTTOM w0.102: v2(124.34,103.4) 124.39,103.45 124.39,104.92 123.89,105.42 123.53,105.42 123.35,105.24 123.35,105.18 122.99,104.81 122.73,104.81 122.55,104.99 122.55,105.04 122.32,105.28 122.32,105.78 UV1.D6
M_EDC_7: length 34.9
  BOTTOM w0.102: UV1.G5 120.36,105.02 119.53,105.02 119.22,104.71 119.22,103.92 119.37,103.78 119.37,103.31 119.17,103.11 119.17,102.57
  BOTTOM w0.127: 119.17,102.57 120.53,101.21 120.8,101.21 120.95,101.06 120.95,100.62 122.83,98.74 128.74,98.74 133.72,103.72 v1(133.72,107.27) 133.72,108.06 137.29,111.63 138.51,111.63 138.89,111.25 138.89,110.89 139.08,110.7 139.08,110.17 UV15.C2
M_RAS#0: length 32.9
  TOP w0.102: v2(142.14,119.24) 142.15,119.25 142.15,119.78 141.81,120.12 141.69,120.12 141.37,120.44 141.37,120.64 140.79,121.23 138.07,121.23 137.5,120.65 137.5,119.4 137.31,119.21
  TOP w0.127: v2(120.05,118.88) 119.77,118.6 119.39,118.6 118.75,117.96 118.75,116.57 119.32,116 121.33,116 121.5,116.17 122.18,116.17 122.36,116 123.14,116 123.22,115.92 124.3,115.92 124.31,115.92 124.32,115.91 124.37,115.91 124.41,115.95 124.47,115.95 124.62,116.1 125,116.1 125.09,116.19 134.28,116.19 v1(135.58,117.49) 137.31,119.21 ; v2(142.14,119.24) 142.54,118.85 UV12.G3
  BOTTOM w0.127: UV12.G3 142.54,118.85 v2(142.14,119.24) ; UV1.G22 120.1,118.88 v2(120.05,118.88)
M_RAS#1: length 33.3
  TOP w0.127: v2(120.86,114.45) 120.95,114.45 121.41,114.91 121.85,114.91 122.18,114.58 125.4,114.58 125.7,114.28 v1(141.19,114.28) 142.18,114.28 142.3,114.16 142.3,113.18 142.43,113.05 142.69,113.05 142.81,113.18 142.81,114.16 142.94,114.28 143.29,114.28 143.41,114.16 143.41,113.07 143.85,112.63 143.85,109.73 144.15,109.43 145.42,109.43 v2(145.45,109.41) UV14.G3
  BOTTOM w0.102: v2(120.86,114.45) 120.8,114.45 120.46,114.79 UV1.G17
  BOTTOM w0.127: v2(145.45,109.41) UV14.G3
M_WCKA0_0: length 39.2
  TOP w0.112: v2(148.63,120.05) 148.23,119.65 UV12.P4
  IN1 w0.13: v2(148.63,120.05) 148.42,120.26 148.42,121.31 148.01,121.71 133.66,121.71 133.53,121.84 133.53,123.22 133.27,123.48 132.7,123.48 132.44,123.22 132.44,121.84 132.31,121.71 131.93,121.71 131.8,121.84 131.8,123.22 131.54,123.48 130.97,123.48 130.71,123.22 130.71,121.84 130.58,121.71 130.03,121.71 129.9,121.84 129.9,123.56 129.58,123.88 v2(129.58,124.12)
  BOTTOM w0.112: v2(148.63,120.05) 148.23,119.65 UV12.P4 ; v2(129.58,124.12) 129.32,124.12 126.85,126.59 123.06,126.59 122.18,125.71 122.18,125.23 122.07,125.12 UV1.E32
M_WCKA0_0#: length 39.6
  TOP w0.112: UV12.P5 148.23,120.44 v2(147.83,120.05)
  IN1 w0.13: v2(129.17,123.71) 129.44,123.71 129.68,123.47 129.68,121.75 129.94,121.49 130.67,121.49 130.93,121.75 130.93,123.13 131.06,123.26 131.45,123.26 131.58,123.13 131.58,121.75 131.83,121.49 132.4,121.49 132.66,121.75 132.66,123.13 132.79,123.26 133.18,123.26 133.31,123.13 133.31,121.75 133.57,121.49 147.92,121.49 148.2,121.22 148.2,120.26 147.98,120.05 v2(147.83,120.05)
  BOTTOM w0.112: UV12.P5 148.23,120.44 v2(147.83,120.05) ; UV1.E30 122.38,124.64 122.38,125.63 123.15,126.39 126.76,126.39 129.17,123.98 v2(129.17,123.71)
M_WCKA0_1: length 20
  TOP w0.112: v2(140.63,120.05) 140.23,119.65 UV12.D4
  IN1 w0.13: v2(140.63,120.05) 140.32,119.73 140.32,119.57 139.81,119.06 138.98,119.06 138.35,118.42 124.9,118.42 124.66,118.66 124.01,118.66 123.88,118.53 123.88,118.35 124.1,118.13 v2(124.16,118.13)
  BOTTOM w0.112: v2(140.63,120.05) 140.23,119.65 UV12.D4 ; UV1.A21 123.88,118.13 v2(124.16,118.13)
M_WCKA0_1#: length 20
  TOP w0.112: UV12.D5 140.23,120.44 v2(139.83,120.05)
  IN1 w0.13: v2(139.83,120.05) 139.97,120.05 140.1,119.91 140.1,119.66 139.72,119.28 138.89,119.28 138.26,118.64 124.99,118.64 124.75,118.88 123.92,118.88 123.66,118.62 123.66,118.36 123.51,118.21 v2(123.27,118.21)
  BOTTOM w0.112: v2(139.83,120.05) 140.23,120.44 UV12.D5 ; v2(123.27,118.21) 122.98,117.92 UV1.C21
M_WCKA1_0: length 35.1
  TOP w0.112: UV14.D4 148.23,108 148.06,107.83 v2(147.83,107.83)
  IN1 w0.13: v2(122.49,111.2) 122.49,111.2 122.28,111 122.28,110.75 122.37,110.67 122.37,109.23 122.05,108.91 122.05,108.01 123.75,106.31 126.08,106.31 127.37,105.02 136.44,105.02 137.05,105.62 147.03,105.62 147.69,106.29 147.69,106.99 148.25,107.55 148.25,107.73 148.1,107.88 147.88,107.88 v2(147.83,107.83)
  BOTTOM w0.112: v2(147.83,107.83) 148.06,107.83 148.23,108 UV14.D4 ; UV1.E13 122.38,111.52 122.49,111.41 v2(122.49,111.2)
M_WCKA1_0#: length 35.1
  TOP w0.112: UV14.D5 v2(148.63,107.83)
  IN1 w0.13: v2(121.89,111.06) 122.07,110.89 122.07,110.66 122.15,110.58 122.15,109.32 121.84,109 121.84,107.92 123.66,106.09 125.99,106.09 127.28,104.8 136.54,104.8 137.14,105.41 147.12,105.41 147.91,106.2 147.91,106.9 148.46,107.46 148.46,107.66 v2(148.63,107.83)
  BOTTOM w0.112: UV1.D12 122.24,110.72 v2(121.89,111.06) ; UV14.D5 v2(148.63,107.83)
M_WCKA1_1: length 26
  TOP w0.112: UV14.P4 v2(139.83,107.83)
  IN1 w0.13: v2(139.83,107.83) 140.11,107.55 140.11,106.96 139.6,106.45 136.42,106.45 135.91,105.94 133.3,105.94 132.63,106.6 129.43,106.6 129.09,106.26 129.09,105.81 v2(128.91,105.62)
  BOTTOM w0.112: UV1.E3 122.06,104.62 121.94,104.74 121.79,104.74 121.7,104.65 121.7,104.21 121.78,104.13 121.78,103.7 121.75,103.68 121.75,103.33 122.32,102.76 125.11,102.76 127.02,104.67 128.76,104.67 129.15,105.06 129.15,105.38 v2(128.91,105.62) ; UV14.P4 v2(139.83,107.83)
M_WCKA1_1#: length 26.1
  TOP w0.112: UV14.P5 v2(140.63,107.83)
  IN1 w0.13: v2(140.63,107.83) 140.32,107.52 140.32,106.86 139.69,106.23 136.51,106.23 136,105.72 133.21,105.72 132.54,106.39 129.52,106.39 129.31,106.17 129.31,105.81 v2(129.49,105.62)
  BOTTOM w0.112: v2(129.49,105.62) 129.36,105.49 129.36,104.98 128.85,104.47 127.11,104.47 125.19,102.56 122.23,102.56 121.54,103.25 121.54,103.76 121.57,103.79 121.57,104.05 121.26,104.36 UV1.F4 ; UV14.P5 v2(140.63,107.83)
M_WE#0: length 32.2
  TOP w0.102: 136.92,122.65 145.37,122.65 146.95,124.23 146.95,124.58 146.75,124.78 146.56,124.78
  TOP w0.127: 136.92,122.65 136.89,122.61 133.79,122.61 131.48,120.31 v1(131.07,120.31) 124.93,120.31 124.52,120.71 123.59,120.71 122.67,119.79 v2(122.46,119.79) ; UV12.L12 145.83,126.05 v2(146.23,125.65) 146.23,125.11 146.56,124.78
  BOTTOM w0.127: v2(146.23,125.65) 145.83,126.05 UV12.L12 ; UV1.G25 120.94,120.64 121.61,120.64 v2(122.46,119.79)
M_WE#1: length 32.6
  TOP w0.102: 137,102.57 137.5,103.08 137.5,103.64 137.98,104.12 140.8,104.12 141.35,103.56 141.35,103.45 141.78,103.02 141.89,103.02 142.23,102.69 v2(142.23,102.23)
  TOP w0.127: v2(119.19,109.63) 119.22,109.63 119.73,109.12 119.73,108.6 120.03,108.31 121.02,108.31 121.49,107.84 121.91,107.84 123.86,105.9 123.86,105.6 124.88,104.57 131.69,104.57 134.83,101.43 v1(135.19,101.43) 135.56,101.43 135.68,101.56 135.68,101.8 135.81,101.93 136.07,101.93 136.19,101.8 136.19,101.56 136.32,101.43 136.86,101.43 137,101.57 137,102.57 ; UV14.L12 v2(142.23,102.23)
  BOTTOM w0.102: v2(119.19,109.63) 119.54,109.29 119.54,109.24 UV1.H10
  BOTTOM w0.127: UV14.L12 v2(142.23,102.23)
MCT:
  vias: v2(19.92,118.24) v2(20.56,118.24) v3(19.86,114.5)
MCT0: length 3.3
  TOP w0.508: RL15.2 17.68,108.29 17.67,108.29 v2(17.22,108.29)
  BOTTOM w0.508: TL1.9 v2(17.22,108.29)
MCT1: length 3.4
  TOP w0.508: v2(17.17,112.1) 17.74,112.1 17.74,112.1 RL14.2
  BOTTOM w0.508: TL1.10 v2(17.17,112.1)
MDO0+: length 20.6
  IN3 w0.203: JLAN1.1 14.16,114.58 14.16,114.8 14.91,115.55 17.22,115.55 18.03,114.75 18.03,107.28 16.8,106.05 v2(15.71,106.05)
  BOTTOM w0.267: v2(15.71,106.05) 16.01,105.75 TL1.7
MDO0-: length 20.6
  IN3 w0.203: JLAN1.2 13.79,112.41 13.79,113.75 14.49,114.44 14.49,114.66 15.05,115.22 17.09,115.22 17.7,114.61 17.7,107.42 16.66,106.38 16.02,106.38 15.77,106.64 v2(15.71,106.64)
  BOTTOM w0.267: v2(15.71,106.64) 15.96,106.64 16.09,106.52 16.09,106.38 16.31,106.16 17.96,106.16 18.22,106.42 18.22,106.75 18.49,107.02 TL1.8
MDO1+: length 12
  IN3 w0.203: v2(15.72,113.7) 15.75,113.73 16.04,113.73 16.28,113.49 16.28,110.75 15.36,109.83 15.03,109.83 14.83,110.04 14.83,110.82 14.42,111.23 JLAN1.3
  BOTTOM w0.267: TL1.11 18.31,113.37 17.88,113.8 15.82,113.8 v2(15.72,113.7)
MDO1-: length 12
  IN3 w0.203: v2(15.72,114.28) 15.85,114.15 16.08,114.15 16.61,113.62 16.61,110.61 15.5,109.5 14.64,109.5 13.95,108.82 JLAN1.6
  BOTTOM w0.267: TL1.12 18.24,114.64 17.78,114.18 15.82,114.18 v2(15.72,114.28)
ME_FWP_EC: length 93.9
  TOP w0.102: RE19.1 154.04,25.04 v2(154.71,25.71) ; RC126.1 78.16,17.2 78.16,16.26 79.48,14.94 v2(80.09,14.94)
  IN2 w0.127: v2(80.09,14.94) 81.14,13.89 84.24,13.89 84.68,13.45 88.79,13.45 89.35,12.88 91.73,12.88 91.8,12.81 95.41,12.81 97.27,10.95 98.11,10.95 99.53,12.37 101.42,12.37 104.44,15.39 107.83,15.39 108.81,14.4 109.53,14.4 110.6,15.48 119.39,15.48 121.06,13.81 125.66,13.81 132.52,20.67 135.94,20.67 136.16,20.46 137.87,20.46 140.82,23.41 142.42,23.41 143.02,24.01 143.02,24.09 146.39,27.46 148.52,27.46 150.05,25.93 152.54,25.93 152.86,25.61 154.6,25.61 v2(154.71,25.71)
  BOTTOM w0.102: v2(154.71,25.71) 154.71,25.61 155.13,25.18 UE1.80
ME_SUS_PWR_ACK: length 82.7
  TOP w0.089: v2(105.57,35.28) 105.57,34.97 104.64,34.03 103.37,34.03 103.14,33.8 103.12,33.8 102.91,33.58 102.91,33.57 102.35,33.01 102.25,33.01
  TOP w0.102: 102.25,33.01 98.03,33.01 96.04,31.03 96.04,30.76 95.56,30.28 95.56,29.79 94.58,28.81 94.58,24.75 93.72,23.89 v1(92.67,23.89) 92.28,23.89 91.64,23.25 RC84.2
  IN1 w0.119: v2(105.57,35.28) 106.07,34.79 106.07,34.04 105.7,33.68 105.7,32.22 105.83,32.09 106.26,32.09 106.52,31.83 106.52,31.44 106.64,31.32 107.26,31.32 107.27,31.33 108.16,31.33 108.35,31.14 108.54,31.14 108.88,30.79 108.88,30.29 109.58,29.59 111.27,29.59 111.69,30.01 117.21,30.01 117.86,30.66 118.41,30.66 120.09,28.97 124.23,28.97 124.49,28.71 126.96,28.71 128.7,30.45 129.08,30.45 131.08,32.45 131.98,32.45 132.65,33.12 132.65,33.99 133.63,34.97 133.63,36.53 135.55,38.46 143.7,38.46 v2(144.25,39.01)
  BOTTOM w0.089: UC1.AR13 105.57,35.46 v2(105.57,35.28)
  BOTTOM w0.102: UE1.42 145.56,34.5 146.18,35.12 146.91,35.12 147.28,35.48 147.28,36.61 146.18,37.7 145.46,37.7 144.25,38.91 v2(144.25,39.01)
MEC_XTAL1: length 3.2
  BOTTOM w0.102: RE47.2 144.68,14.48 CE3.1 143.81,12.58 YE1.1
MEC_XTAL1_R: length 2.7
  BOTTOM w0.102: RE47.1 143.77,14.93 143.96,15.11 v1(143.96,15.63) UE1.123
MEC_XTAL2: length 5.9
  BOTTOM w0.102: UE1.125 143.16,16.16 142.65,15.66 v1(142.65,15.63) 142.65,14.69 CE4.1 142.91,14.02 142.93,13.99 RE45.1 142.93,13 YE1.2
MIC_CAP: length 4.7
  TOP w0.102: v1(20.58,21.67) 20.73,21.67 CA26.1
  TOP w0.203: CA26.1 21.93,20.34 22.63,19.64 23.57,19.64 23.7,19.76 UA1.19
MODEL_ID: length 5.7
  TOP w0.102: v1(150.49,22.33) 150.49,21.78 RE3.2 RE4.2 CE1.1 150.12,19.54 v2(149.35,18.76)
  BOTTOM w0.102: UE1.109 149.56,18.55 v2(149.35,18.76)
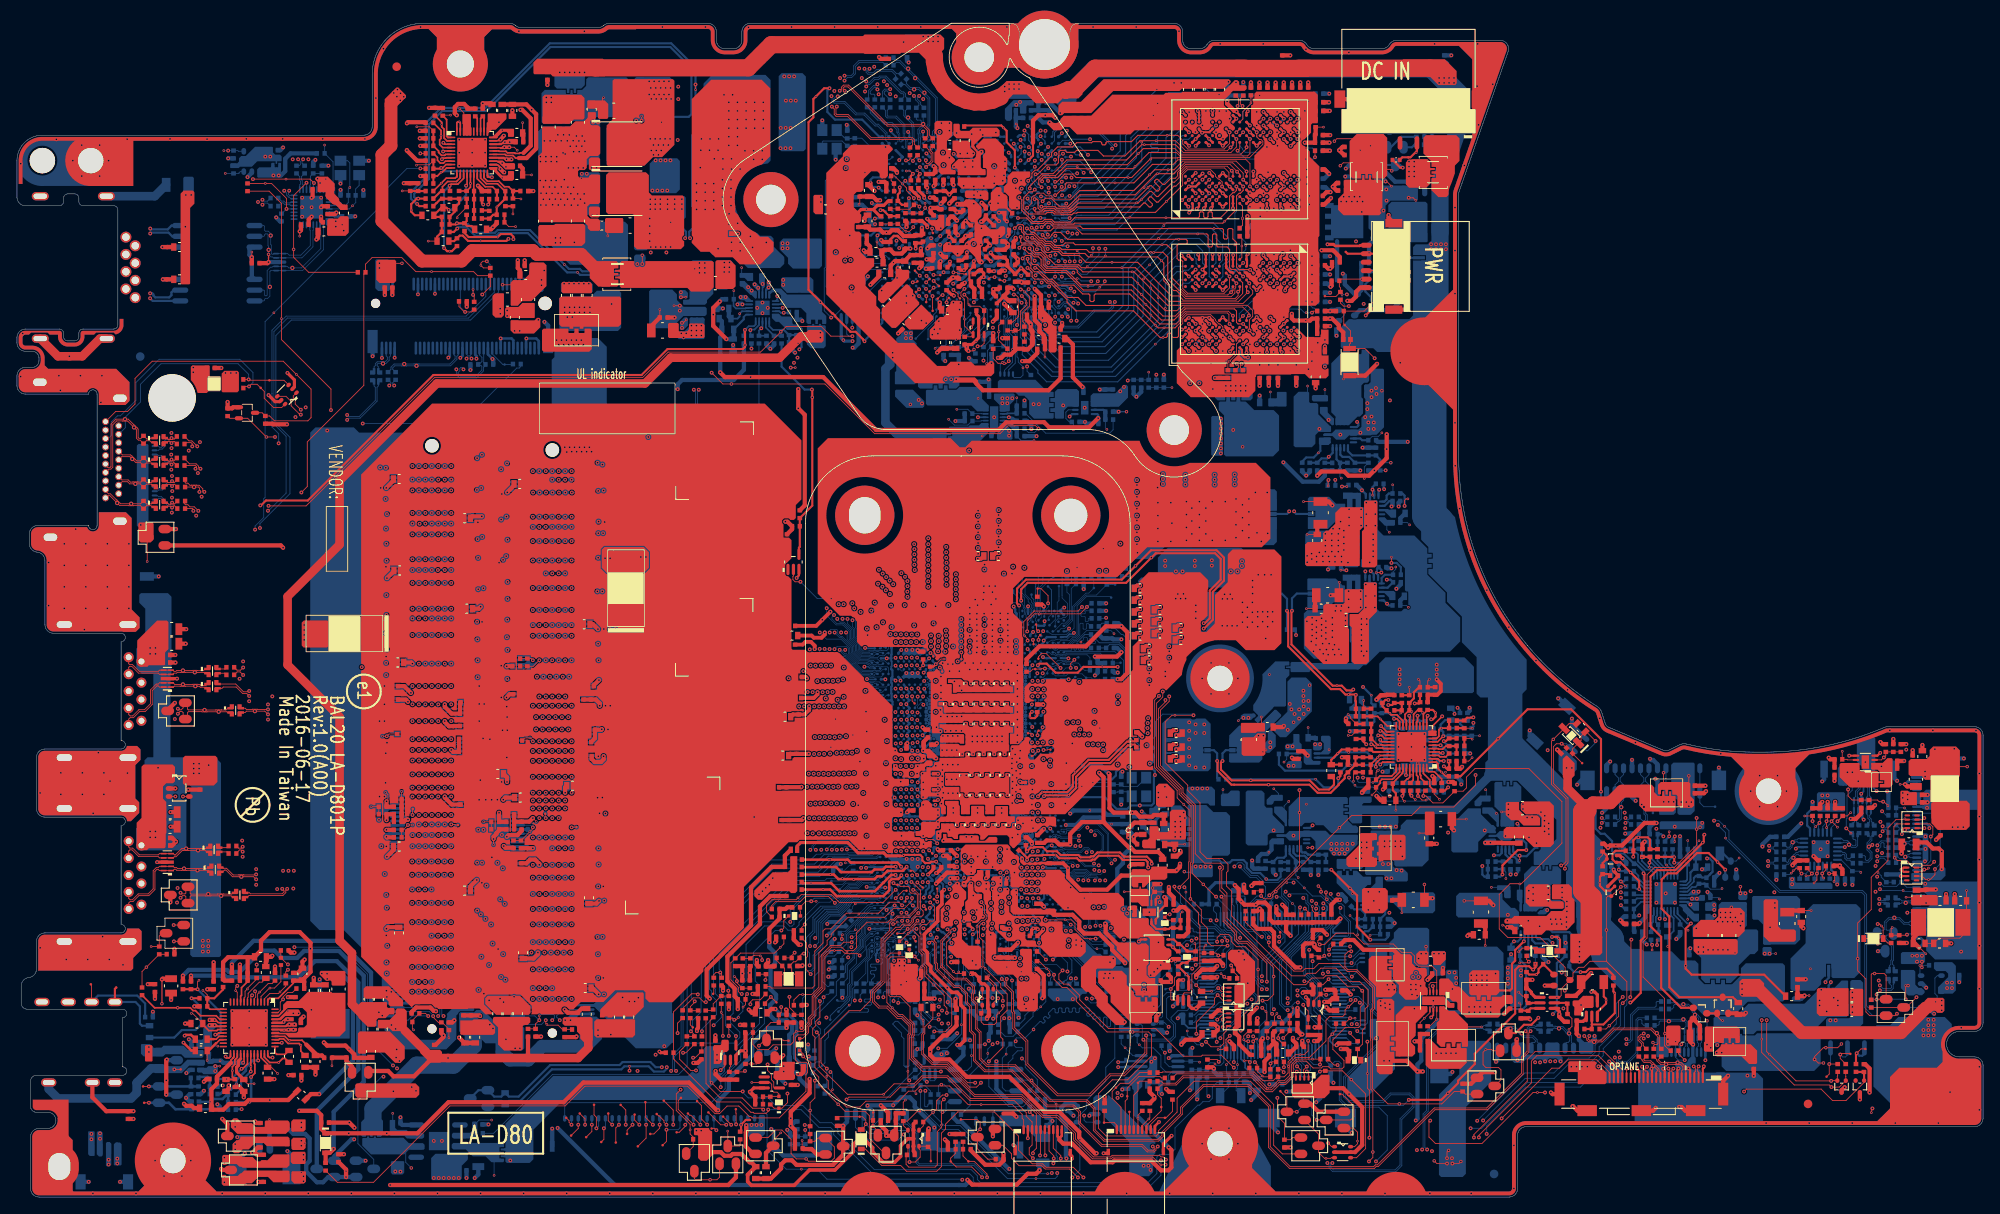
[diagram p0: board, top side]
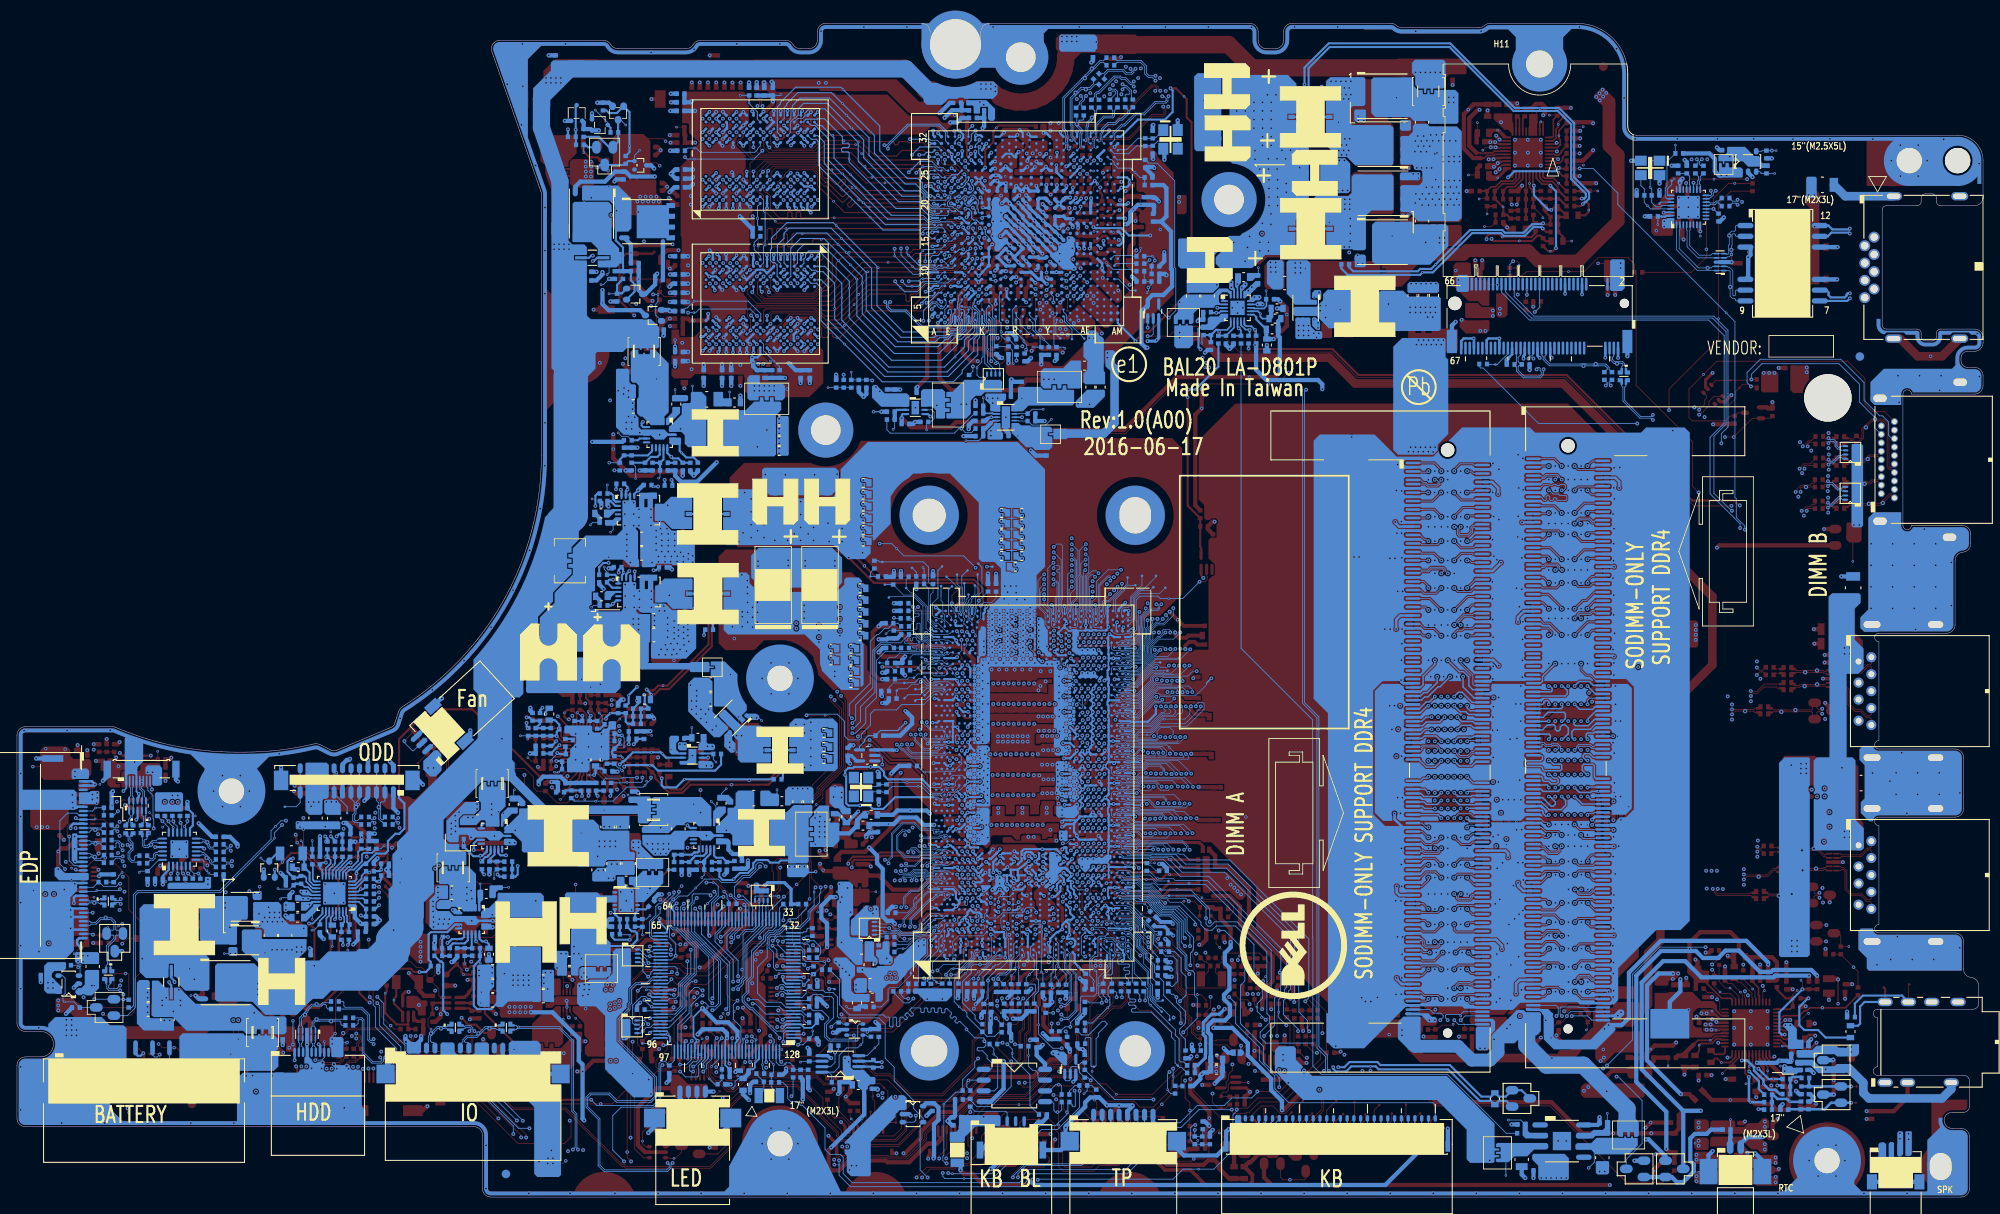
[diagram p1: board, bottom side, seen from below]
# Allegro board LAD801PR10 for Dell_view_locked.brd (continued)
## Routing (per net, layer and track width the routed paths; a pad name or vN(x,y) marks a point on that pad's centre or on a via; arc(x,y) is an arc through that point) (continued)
MPHYP_PWR_EN: length 1
  TOP w0.089: TP13.1 107.21,34.09 v2(106.95,34.34)
  BOTTOM w0.076: v2(106.95,34.34) 107.21,34.08 UC1.AM10
NCT7718_DXN: length 89.2
  IN1 w0.254: v2(76.65,15.32) 76.65,15.17 76.32,14.85 76.32,13.38 78.26,11.44 89.01,11.44 89.54,10.9 95.34,10.9 96.93,12.5 103.59,12.5 105.87,10.22 108.71,10.22 110.97,12.48 114.95,12.48 116.83,14.36 119.78,14.36 121.76,12.39 126.4,12.39 129.27,15.25 129.27,15.39 129.79,15.92 v2(129.89,15.92)
  BOTTOM w0.254: v2(129.89,15.92) 129.9,15.93 130.63,15.93 C23.2 131.03,16.03 U2.3 ; v2(76.65,15.32) 76.65,15.15 76.31,14.81 75.12,14.81 74.51,15.42 71.64,15.42 71.29,15.07 63.1,15.07 59.37,11.35 58.02,11.35 C22.2 57.13,11.35 56.22,11.35 Q14.3
NCT7718_DXP: length 91.6
  IN1 w0.254: v2(129.89,15.33) 129.89,15.15 126.62,11.88 121.55,11.88 119.57,13.86 117.04,13.86 115.16,11.97 111.18,11.97 108.92,9.71 105.66,9.71 103.38,11.99 97.14,11.99 95.55,10.39 89.33,10.39 88.8,10.93 78.05,10.93 75.81,13.17 75.81,15.06 76.06,15.31 v2(76.06,15.32)
  BOTTOM w0.254: Q14.1 54.43,12.6 Q14.2 56.29,11.85 57.13,11.85 C22.1 58.02,11.85 59.16,11.85 62.89,15.58 71.08,15.58 71.43,15.93 74.72,15.93 75.33,15.32 v2(76.06,15.32) ; v2(129.89,15.33) 130.82,15.33 C23.1 130.99,15.38 U2.2
NRB_BIT: length 12.4
  BOTTOM w0.076: UC1.AR7 105.02,32.11 104.74,31.83 103.63,31.83 103.22,31.43 102.71,31.43 102.67,31.46 102.22,31.46 102.17,31.41 101.32,31.41 101.23,31.32 100.7,31.32 100.58,31.2 100.57,31.2
  BOTTOM w0.102: 100.57,31.2 99.7,30.33 99.7,29.58 98.8,28.69 98.8,28.2 97.94,27.33 97.94,25.8 RC44.2
NTC_IA: length 2.4
  TOP w0.203: PU602.15 164.68,56.21 164.73,56.26 164.73,56.97 165.24,57.48 PR635.2
OCP_L: length 4.5
  TOP w0.203: PU1100.4 50.21,123.84 49.86,124.19 49.86,124.76 50.02,124.92 v1(50.02,125.24) 50.02,125.85 PR1112.2
ONE_DIMM#: length 16.2
  BOTTOM w0.076: UC1.M2 118.11,29.19 118.45,28.85 118.76,28.85 118.85,28.79 118.87,28.73 118.88,28.72 118.9,28.63 118.9,28.47
  BOTTOM w0.102: RC182.1 116.07,19.45 116.56,18.97 117.5,18.97 RC181.2 119.85,21.32 119.85,21.75 120.15,22.05 120.35,22.05 v1(120.75,22.45) 121.36,23.06 121.36,25.5 121.3,25.55 121.3,25.74 118.9,28.14 118.9,28.47
PANEL_BKEN_EC: length 115.8
  TOP w0.102: RP2.8 222.53,43.53 222.33,43.33 v2(222.33,42.82) ; v1(218.73,9.96) 218.73,10.33 v2(218.85,10.46)
  IN1 w0.119: v2(218.85,10.46) 219.54,11.14 219.54,16.9 221.31,18.67 221.31,41.8 v2(222.33,42.82)
  IN2 w0.127: v2(218.85,10.46) 218.36,9.96 163.41,9.96 157.22,16.15 152.21,16.15 150.96,17.4 150.96,19.03 150.7,19.29 146.14,19.29 v2(145.81,18.96)
  BOTTOM w0.102: UE1.117 146.36,18.09 146.26,18.18 146.26,18.52 v2(145.81,18.96)
PBAT_CHG_SMBCLK: length 128.5
  TOP w0.102: v2(206.38,20.87) 206.38,17.16 v1(206.68,16.86) 209.84,13.71 v2(213.98,13.71) 214.02,13.74 PD2.3 214.71,14.27 214.75,14.31 PR18.2
  IN1 w0.119: v2(145.63,23.32) 146.39,23.32 146.66,23.6 147.21,23.6 149,25.38 151.34,25.38 151.72,25.01 152.25,25.01 153.55,23.7 153.55,22.21 157.97,17.8 162.2,17.8 168.92,11.08 176.17,11.08 176.37,11.28 181.37,11.28 181.78,11.69 184.21,11.69 184.63,11.27 192.5,11.27 192.77,11.54 200.78,11.54 201.08,11.24 204.49,11.24 205.99,12.73 206.44,13.19 206.86,13.19 206.86,13.19 207.39,13.19 213.52,13.19 213.98,13.66 v2(213.98,13.71)
  IN3 w0.142: v2(189.19,35.96) 190.56,35.96 192.51,34.01 196.2,34.01 196.95,33.25 196.95,27.18 201.17,22.96 205.27,22.96 206.38,21.86 v2(206.38,20.87)
  BOTTOM w0.102: v2(189.19,35.96) 189.38,35.96 189.57,35.77 PR770.1 ; RE9.1 138.89,21.49 139.39,21.98 UE1.9 141.48,21.98 142,22.5 143.69,22.5 144.51,23.32 v2(145.63,23.32)
PBAT_CHG_SMBDAT: length 130.2
  TOP w0.102: v2(205.79,20.87) v1(205.79,18.64) 205.79,17.06 209.64,13.22 213.77,13.22 v2(214.01,12.98) 214.95,12.98 PD2.2 215.71,14.24 215.71,14.25 PR20.2
  IN1 w0.119: v2(145.12,22.82) 145.17,22.77 146.74,22.77 147.09,22.77 147.21,22.88 149.2,24.88 151.14,24.88 151.51,24.51 152.04,24.51 153.05,23.5 153.05,22 157.76,17.3 161.99,17.3 168.71,10.58 176.37,10.58 176.57,10.78 181.58,10.78 181.98,11.19 184,11.19 184.42,10.77 192.71,10.77 192.98,11.04 200.39,11.04 200.69,10.74 204.7,10.74 206.19,12.23 206.65,12.69 213.73,12.69 v2(214.01,12.98)
  IN3 w0.142: v2(189.19,35.33) 190.45,35.33 192.3,33.48 195.98,33.48 196.42,33.04 196.42,26.96 200.95,22.44 205.05,22.44 205.79,21.7 v2(205.79,20.87)
  BOTTOM w0.102: v2(145.12,22.82) 144.8,22.82 143.56,21.58 UE1.8 139.37,21.58 139.08,21.3 139.08,20.85 138.83,20.6 RE8.1 ; PR769.1 189.63,34.89 v2(189.19,35.33)
PBAT_PRES#: length 129.2
  TOP w0.102: v2(203.71,12.45) 204,12.74 212.8,12.74 214.14,11.4 215.74,11.4 217.87,13.53 PD3.2
  TOP w0.254: PC14.1 179.11,27.12 v2(178.83,26.84) 178.75,26.84 178.35,27.24 177.15,27.24 176.72,26.81 176.72,21.67 171.95,16.91 171.95,15.7 169.98,13.73 169.98,13.45 v3(168.77,12.24) 168,11.47 v2(164.17,11.47) ; PD3.2 217.87,14.74 PR16.1 216.93,14.76 PR15.2
  IN2 w0.254: v2(194.19,42.56) 192.49,40.85 188.81,40.85 185.25,37.29 185.25,31.96 184.42,31.13 183.85,31.13 183.15,30.44 183.15,28.13 181.86,26.84 v2(178.83,26.84)
  IN3 w0.142: v2(203.71,12.45) 203.66,12.4 182.85,12.4 181.69,11.24 164.4,11.24 v2(164.17,11.47)
  BOTTOM w0.102: v2(164.17,11.47) 163.51,10.81 156.87,10.81 156.17,11.51 156.17,15.76 155.91,16.02 155.46,16.02 CE16.1 154.93,15.52 154.36,16.1 UE1.97
  BOTTOM w0.254: PR764.1 193.5,41.92 PC753.2 PR756.1 193.93,42.82 v2(194.19,42.56)
PCH_BATLOW#: length 19
  TOP w0.102: RC89.1 88.41,33.67 88.41,34.44 89.05,35.09 91.91,35.09 v1(92.13,35.3) 92.5,35.68 96.09,35.68 97.01,34.76 102.16,34.76 v2(103.65,36.25)
  BOTTOM w0.076: v2(103.65,36.25) 103.96,35.94 UC1.AU13
PCH_DPWROK: length 5
  BOTTOM w0.076: RC97.2 97.74,39.41 v1(97.71,39.44) ; RC97.2 98.73,39.5 UC1.BB20 ; RC97.2 98.39,39.17 98.21,39.17 97.55,38.5 RC87.1
PCH_HDMI_CLK: length 190.9
  TOP w0.102: QI2.1 32.6,94.54 32.6,94.3 32.82,94.07 32.82,93.57 v2(33.48,92.91)
  IN3 w0.142: v2(33.48,92.91) 33.72,92.91 34.56,92.07 34.56,89.68 39.14,85.11 39.14,84.5 39.18,84.46 39.18,34.03 42.68,30.53 42.68,23.95 46.63,20.01 46.63,19.21 48.12,17.72 48.97,17.72 50.82,15.88 51.99,15.88 55.86,12.01 56.97,12.01 58.02,10.96 61.22,10.96 62.27,12.01 81.39,12.01 81.8,12.42 83.91,12.42 85.83,14.33 90.56,14.33 90.87,14.64 90.87,14.98 91.65,15.77 94.13,15.77 96.05,13.85 101.95,13.85 103.2,15.1 103.2,21.57 104.37,22.74 104.37,24.64 107.53,27.8 107.53,29.06 108.92,30.46 108.92,30.8 109.03,30.91 109.03,31.84 109.48,32.3 109.83,32.3 110.04,32.51 110.04,33 110.03,33 111.93,34.9 112.15,34.9 112.87,34.9 113.57,35.6 116.46,35.6 116.71,35.35 v2(117.04,35.35) 117.69,34.7 117.69,34.09 118.16,33.62 121.41,33.62 122.83,32.2 122.83,31.29 122.53,30.98 122.53,29.34 124.9,26.97 v2(124.9,25.81)
  BOTTOM w0.076: UC1.L13 v2(117.04,35.35)
  BOTTOM w0.102: v2(124.9,25.81) 124.7,25.61 124.7,25.46 RC1.1
PCH_HDMI_DATA: length 192.6
  TOP w0.102: QI2.4 31.73,94.48 32.34,93.87 32.34,93.37 33.28,92.42 33.38,92.42 v2(33.48,92.32)
  IN3 w0.142: v2(33.48,92.32) 33.48,92.29 34.04,91.73 34.04,89.47 38.61,84.9 38.61,84.28 38.65,84.24 38.65,33.82 42.16,30.31 42.16,23.74 45.91,19.99 45.91,19.08 47.79,17.2 48.76,17.2 50.6,15.35 51.78,15.35 55.65,11.48 56.75,11.48 57.8,10.43 61.44,10.43 62.49,11.48 81.6,11.48 82.01,11.9 84.13,11.9 86.04,13.81 90.78,13.81 91.39,14.42 91.39,14.77 91.87,15.24 93.91,15.24 95.83,13.33 102.16,13.33 103.72,14.88 103.72,21.35 104.89,22.52 104.89,23.47 107.83,26.41 107.83,26.95 108.08,27.2 108.08,28.88 109.44,30.24 109.44,30.97 109.33,31.08 109.33,31.76 109.6,32.03 109.94,32.03 110.31,32.4 110.31,32.62 110.31,32.62 110.31,32.9 112.04,34.63 112.99,34.63 113.68,35.33 116.35,35.33 116.85,34.83 116.96,34.83 117.04,34.74 v2(117.04,34.69) 117.32,34.69 117.42,34.59 117.42,33.97 118.04,33.35 118.27,33.35 121.3,33.35 122.56,32.09 122.56,31.52 122,30.96 122,30.78 122,30.78 122,29.12 124.37,26.75 124.37,25.87 v2(124.31,25.81)
  BOTTOM w0.076: UC1.L12 117.5,35.15 v2(117.04,34.69)
  BOTTOM w0.102: RC2.1 124.21,25.17 124.51,25.47 124.51,25.61 v2(124.31,25.81)
PCH_JTAG_TCK1: length 7.5
  BOTTOM w0.076: UC1.B56 123.03,60.65 123.25,60.65 123.37,60.71 123.63,60.71 123.81,60.53 124.47,60.53 124.94,61 ; TPC3.1 128.51,60.66 129.04,60.13 RC147.1
  BOTTOM w0.102: TPC3.1 126.89,60.66 126.85,60.7 126.01,60.7 125.54,61.17 125.11,61.17 124.94,61
PCH_PCIE_WAKE#: length 29.8
  TOP w0.102: RC99.2 84.4,21.12 v2(84.6,20.92) 84.82,20.92 v1(85.11,21.2)
  BOTTOM w0.076: UC1.BB15 100.8,37.13 99.72,37.13 99.14,36.55 98.24,36.55 96.91,35.22 96.34,35.22 95.9,34.79 94.6,34.79 92.53,32.72
  BOTTOM w0.102: v2(84.6,20.92) 85.62,21.93 85.62,22.81 85.01,23.43 85.01,24.54 86,25.54 86,29.81 88.18,31.99 90.43,31.99 90.94,31.48 91.61,31.48 91.78,31.66 92.25,32.12 92.25,32.44 92.53,32.72
PCH_PLTRST#: length 32.4
  TOP w0.102: v2(106.32,33.51) 106.2,33.51 105.56,32.87 105.56,32.55 105.22,32.21 104.47,32.21 104.1,31.84 103.65,31.84 102.15,30.34 102.15,25.44 100.89,24.19 100.89,23.04 101.63,22.31 102.6,22.31 103.83,21.08 104.33,21.08 105.22,20.19 105.22,19.3 105.09,19.17 v1(105.09,14.84) 105.09,13.92 v2(105.25,13.76)
  BOTTOM w0.076: UC1.AN10 106.56,33.76 v2(106.32,33.51)
  BOTTOM w0.102: v2(105.25,13.76) 105.58,14.1 RC108.1 106.57,14.72 106.57,15.29 106.67,15.39 107.46,15.39 107.66,15.19 UC4.2 107.66,13.82 107.75,13.73 108.2,13.73 108.31,13.84 UC4.1
PCH_PLTRST#_EC: length 383.8
  TOP w0.102: v2(175.12,9.28) 181.04,15.21 181.92,15.21 182.91,16.2 186.34,16.2 187.85,14.69 JSSD1.23 ; v2(97.85,11.51) 98.14,11.8 102.99,11.8 104.17,12.98 105.75,12.98 106.86,14.09 109.7,14.09 112.4,11.39 117.62,11.39 119.04,9.96 119.04,9.56 119.74,8.86 JDB1.3 119.74,6.14 119.4,5.8 119.4,5.02 v2(119.83,4.58) ; v2(151.34,34.18) 151.34,33.44 CE27.1 ; v2(33.55,83.14) 34.25,83.84 34.25,89.12 40.91,95.78 40.91,108.91 RL12.1 41.12,110.08 41.89,110.85 45.39,110.85 47.05,109.2 v1(48.9,109.2) 53.86,109.2 54.33,108.72 RW4.2 55.84,107.45 v2(54.88,106.49)
  IN1 w0.119: v2(175.12,9.28) 174.32,10.08 168.5,10.08 164.62,13.96 163.71,13.96 162.75,14.92 162.75,15.84 161.78,16.8 157.55,16.8 152.55,21.8 152.55,22.81 152.3,23.07 151.91,23.07 151.61,23.38 150.65,23.38 150.14,23.89 149.62,23.89 148.79,23.06 148.79,21.97 148.43,21.62 v2(148.04,21.62) 146.87,20.44 144.57,20.44 143.94,19.81 143.94,17.81 143.7,17.57 141.96,17.57 141.53,17.57 140.08,16.12 140.08,15.57 137.48,12.97 137.48,11.77 135.49,9.79 134,9.79 129.84,5.63 120.75,5.63 120.25,5.13 120.25,5.09 120.25,4.88 119.96,4.58 v2(119.83,4.58) ; v2(32.72,29.48) 32.72,30.43 35.01,32.72 35.01,69.88 33.55,71.34 v2(33.55,83.14)
  IN1 w0.142: v2(97.85,11.51) 96.02,9.68 48.09,9.68 44.91,12.85 44.91,13.85 44.36,14.41 v2(44.36,15.53)
  IN3 w0.142: v2(98.52,102.59) 97.86,102.59 96.91,101.63 96.91,100.14 93.61,96.84 76.73,96.84 73,100.57 68.45,100.57 67.18,101.83 66.55,101.83 60.98,101.83 59.81,103 57.07,103 55.84,104.24 55.84,105.54 v2(54.88,106.49)
  BOTTOM w0.102: v2(44.36,15.53) 41.33,18.56 41.33,26.31 38.15,29.48 v2(32.72,29.48) ; UV2.1 v2(98.52,102.59) ; v2(97.85,11.51) 102.42,11.51 105.92,15.01 RC108.2 RC109.1 106.34,15.87 106.6,15.62 106.83,15.62 107.01,15.81 UC4.4 ; v2(148.04,21.62) 147.83,21.83 147.83,27.69 151.16,31.02 UE1.56 151.16,34 v2(151.34,34.18)
PCH_POPIRCOMP: length 12.9
  TOP w0.305: RC120.1 92.68,37.04 v1(93.66,37.04) 96.03,37.04 96.98,36.09 101.19,36.09 102.2,37.1 102.21,37.1 103.11,38.01 v2(103.63,38.01)
  BOTTOM w0.254: v2(103.63,38.01) 103.63,37.92 103.96,37.6 UC1.AU16
PCH_RSMRST#: length 97.8
  TOP w0.102: UC5.1 83.51,15.48 v2(83.01,14.98)
  IN1 w0.119: v2(83.01,14.98) 83.22,14.98 84.55,13.64 88.68,13.64 89.5,12.82 94.6,12.82 95.84,14.06 101.16,14.06 101.32,14.22 104.06,14.22 106.3,11.97 107.25,11.97 108.54,13.26 108.54,15.01 108.86,15.33 111.4,15.33 112.72,16.65 115.83,16.65 116.58,15.9 120.5,15.9 122.34,14.07 125.91,14.07 127.66,15.82 127.66,16.41 130.7,19.44 131.34,19.44 131.75,19.86 133.13,21.23 133.13,21.37 135.68,23.92 135.68,24.77 135.88,24.97 136.62,24.97 136.9,25.25 136.9,26.22 138.49,27.81 139.35,27.81 141.22,29.68 142.19,29.68 142.33,29.53 142.62,29.25 143.03,29.25 143.77,29.99 144.88,29.99 145.86,29 152.25,29 v2(152.42,29.17)
  BOTTOM w0.102: RE20.1 157.73,21.98 UE1.88 154.21,21.98 153.66,22.52 153.66,25.07 152.42,26.32 v2(152.42,29.17)
PCH_RSMRST#_Q: length 37.3
  TOP w0.102: RC148.1 82.19,26.24 82.44,26.49 v2(82.95,26.49) 83.11,26.33 RC94.2 ; UC5.4 v2(84.81,19)
  BOTTOM w0.076: 95.21,37.36 95.3,37.36 95.52,37.58 v1(97.37,37.58) 97.46,37.58 98.36,38.49 RC97.1 99.15,38.49 99.4,38.25 100.35,38.25 100.63,38.54 101.89,38.54 UC1.AY17
  BOTTOM w0.102: 95.21,37.36 91.5,37.36 82.82,28.68 82.82,26.88 82.95,26.76 v2(82.95,26.49) 82.95,26.31 82.87,26.24 82.87,24.19 83.56,23.5 83.56,20.24 v2(84.81,19)
PCH_RTCRST#: length 36.1
  TOP w0.102: QC2.1 88.41,20.08 88.93,20.6 RC78.1 CC5.1 90.14,21.77 v2(90.14,22.42) ; QC2.1 90.36,18.54 90.44,18.46 TPS7.1 ; QC2.1 88.2,18.54 v2(87.52,17.86)
  IN3 w0.135: v2(106.83,37.17) 106.34,36.67 105.34,36.67 105.31,36.65 103.24,36.65 101.95,35.35
  IN3 w0.142: v2(90.14,22.42) 90.11,22.45 90.11,23.6 90.63,24.12 93.18,24.12 94.55,25.49 95.84,25.49 98.85,28.5 98.85,28.57 99.83,29.55 99.83,29.89 101.95,32.01 101.95,35.35
  BOTTOM w0.102: v2(106.83,37.17) 107.14,37.59 UC1.AM16 ; JCMOS1.1 87.55,17.84 v2(87.52,17.86)
PCH_RTCX1: length 25.5
  TOP w0.102: v2(92.82,28.73) 92.6,28.73 92.3,28.42 RC82.2 91.84,27.76 91.6,27.76 91.13,27.29 CC8.1 91.38,27.01 91.38,26.62 YC2.1
  IN3 w0.076: v2(107.48,38.92) 107,38.44 106.64,38.44 106.59,38.38 103.06,38.38 101,36.32 101,33.97 100.58,33.55
  IN3 w0.142: v2(92.82,28.73) 92.89,28.66 94.73,28.66 95.94,29.87 96.45,29.87 96.87,30.29 96.87,30.68 97.09,30.9 97.93,30.9 100.58,33.55
  BOTTOM w0.102: v2(107.48,38.92) 107.21,38.65 UC1.AM18
PCH_RTCX2: length 22.8
  TOP w0.102: v2(91.73,28.84) 91.38,28.5 RC82.1 RC83.2
  IN3 w0.076: 103.48,38.62 103.51,38.59 106.49,38.59 v2(106.83,38.93)
  IN3 w0.135: 103.48,38.62 102.93,38.62 101.26,36.95
  IN3 w0.142: 101.26,36.95 100.38,36.07 100.38,34.09 97.71,31.42 96.73,31.42 94.49,29.19 92.67,29.19 92.33,28.84 v2(91.73,28.84)
  BOTTOM w0.102: UC1.AM20 107.21,39.31 v2(106.83,38.93)
PCH_RTCX2_R: length 3.2
  TOP w0.102: RC83.1 89.6,27.93 CC9.1 90.52,27.01 90.52,26.5 YC2.2
PCH_SMB_ALERT#: length 12.7
  IN3 w0.142: v2(113.2,23.44) 113.2,23.73 113.86,24.4 113.86,28.89 114.43,29.46 114.43,31.13 114.45,31.14 114.45,32.41 114.9,32.86 v2(114.9,33.98)
  BOTTOM w0.102: v2(114.9,33.98) 115.01,33.87 UC1.R10 ; RC37.1 113.68,22.96 v2(113.2,23.44)
PCH_SMBCLK: length 94
  TOP w0.102: v2(116.29,22.57) 116.29,22.21 v1(115.8,21.73) 115.55,21.47 115.55,20.62 115.29,20.36 114.05,20.36 113.73,20.67 RC28.2 113.86,21.8 QC1.1
  IN1 w0.119: v2(50.31,21.36) 50.12,21.55 50.12,22.75 50.56,23.2 54.28,23.2 57.27,20.21 63.46,20.21 63.73,20.47 63.73,20.57 v2(64.03,20.87) 63.73,21.17 63.73,21.3 63.85,21.42 68.41,21.42 69.17,20.66 73.73,20.66 75.15,22.09 77.39,22.09 77.59,22.28 82.22,22.28 84.85,19.65 86,19.65 86.81,20.47 87.78,20.47 88.28,20.96 88.28,22.58 88.63,22.94 90.58,22.94 91.64,21.88 94.4,21.88 95.89,23.36 95.89,24.06 97.89,26.06 104.31,26.06 105.35,25.02 110.88,25.02 112.42,23.48 112.42,23.12 112.83,22.71 116.15,22.71 v2(116.29,22.57)
  BOTTOM w0.102: JDIMM2.253 50.36,22.63 50.11,22.37 50.11,21.56 v2(50.31,21.36) ; JDIMM1.253 65.25,22.12 64.83,21.7 63.97,21.7 63.65,21.39 63.65,21.24 v2(64.03,20.87)
PCH_SMBDATA: length 96.1
  TOP w0.102: v2(116.29,23.15) 116.29,23.71 115.55,24.44 115.55,24.95 114.64,25.86 RC27.2 114.4,25.76 115.16,24.99 QC1.4
  IN1 w0.119: v2(116.29,23.15) 116.09,22.95 112.93,22.95 112.67,23.22 112.67,23.58 110.98,25.27 105.46,25.27 104.42,26.31 97.79,26.31 95.64,24.16 95.64,23.46 94.3,22.12 91.74,22.12 90.68,23.18 88.53,23.18 88.03,22.68 88.03,21.07 87.68,20.71 86.71,20.71 85.9,19.9 84.95,19.9 82.32,22.53 77.48,22.53 77.29,22.33 75.05,22.33 73.62,20.91 69.27,20.91 68.51,21.67 63.74,21.67 63.48,21.41 63.48,21.22 v2(63.14,20.87) 63.28,20.87 63.48,20.68 63.48,20.58 63.36,20.46 57.37,20.46 54.38,23.45 50.46,23.45 49.87,22.86 49.87,21.55 v2(49.68,21.36)
  BOTTOM w0.102: JDIMM1.254 61.27,21.87 61.59,21.55 63.29,21.55 63.39,21.45 63.39,21.13 v2(63.14,20.87) ; JDIMM2.254 47.69,22.38 47.75,22.43 49.78,22.43 49.88,22.33 49.88,21.56 v2(49.68,21.36)
PCH_SPI_CLK_0_R: length 3.3
  BOTTOM w0.102: RC178.1 108.68,13.14 108.81,13.26 v3(109.04,13.26) 109.37,13.26 110.11,12.53 UC3.6
PCH_SPI_CLK_R: length 89.7
  IN1 w0.119: v2(99.46,23.2) 99.46,23.17 100.25,22.38 100.25,22.21 99.55,21.51 99.55,21.34 99.72,21.17 99.89,21.17 100.54,21.82 100.81,21.82 100.98,21.65 100.98,21.48 100.76,21.27 100.76,21.1 100.93,20.93 101.1,20.93 101.31,21.15 101.48,21.15 101.65,20.98 101.65,20.81 101.43,20.59 101.43,20.42 101.6,20.25 101.77,20.25 101.99,20.47 102.16,20.47 102.33,20.3 102.33,20.13 102.11,19.92 102.11,19.75 102.28,19.58 102.45,19.58 102.67,19.79 102.83,19.79 103.05,19.58 103.05,18.18 103.59,17.63 103.59,17.35 103.29,17.05 103.29,16.88 103.48,16.69 103.65,16.69 104.01,17.05 104.18,17.05 104.38,16.84 104.38,16.67 103.96,16.25 103.96,16.08 104.13,15.91 104.3,15.91 104.72,16.34 104.89,16.34 105.06,16.17 105.06,16 104.64,15.58 104.64,15.41 104.81,15.24 104.98,15.24 105.39,15.66 105.56,15.66 105.69,15.53 105.69,15.29 105.08,14.68 105.08,14.51 105.69,13.91 105.69,13.4 v2(106.56,12.53)
  IN3 w0.142: v2(122.7,2.84) 122.7,2.96 123.25,3.51 128.54,3.51 132.46,7.43 134.69,7.43 137.14,9.88 137.14,13.7 138.7,15.26 138.7,16.72 139.18,17.19 139.18,18.73 140.61,20.16 140.61,27.55 139.47,28.69 139.47,30.15 v2(139.12,30.5)
  BOTTOM w0.102: v2(139.12,30.5) 138.81,30.8 RE33.1 ; RC24.2 99.46,23.84 v2(99.46,23.2) ; RC178.2 107.77,12.5 107.09,13.17 RC21.2 106.56,13.15 v2(106.56,12.53) 106.56,10.56 109.17,7.96 111.05,7.96 116.82,2.18 v1(120.19,2.18) 122.46,2.18 122.7,2.43 v2(122.7,2.84)
PCH_SPI_CLK_R1: length 8.9
  BOTTOM w0.076: 100.84,28.31 100.84,28.52 101.17,28.85 101.17,29.33 101.37,29.52 101.65,29.52 101.77,29.64 101.77,29.86 102.02,30.1 102.35,30.1 102.69,30.44 103.48,30.44 103.68,30.24 103.68,29.8 UC1.AV2
  BOTTOM w0.102: RC24.1 100.13,25.19 100.35,25.41 100.35,27.81 100.84,28.31
PCH_SPI_CS#0_R1: length 78.4
  IN1 w0.119: v2(117.8,18.39) 116.84,19.34 113.31,19.34 113.19,19.22 113.19,18.79 113.07,18.67 112.83,18.67 112.71,18.79 112.71,19.22 112.59,19.34 111.97,19.34 111.54,18.91 111.28,18.91 111.16,18.79 111.16,18.51 111.03,18.38 110.81,18.38 110.69,18.5 110.69,18.79 110.57,18.91 110.15,18.91 110.04,19.03 110.04,19.5 109.92,19.62 109.68,19.62 109.56,19.5 109.56,19.19 109.44,19.07 109.2,19.07 109.08,19.19 109.08,19.41 108.96,19.53 108.72,19.53 108.6,19.41 108.6,19.19 108.48,19.07 107.8,19.07 106.89,19.98 106.89,22.46 106.76,22.59 105.67,22.59 105.42,22.33 105.42,20.88 105.3,20.76 105.1,20.76 104.97,20.89 104.97,22.71 104.85,22.83 104.61,22.83 104.46,22.69 104.46,21.87 104.34,21.75 104.11,21.75 103.99,21.87 103.99,22.38 103.87,22.5 103.77,22.5 103.65,22.62 103.65,22.8 103.77,22.92 v2(103.94,22.92)
  BOTTOM w0.076: 104.31,24.1 104.31,25.92 103.08,27.15 103.08,28.7 104.05,29.68 UC1.AU3
  BOTTOM w0.102: UC3.1 117.05,15.07 116.91,15.21 116.91,15.82 117.47,16.38 117.47,16.71 118.02,17.25 118.53,17.25 118.64,17.36 118.64,17.56 118.53,17.66 117.84,17.66 117.62,17.87 117.62,18.21 v2(117.8,18.39) 117.8,18.68 117.9,18.78 118.92,18.78 v3(119.9,19.77) 119.9,19.95 120.66,20.71 120.8,20.71 120.98,20.54 121.12,20.54 121.26,20.68 121.26,20.82 121.09,21 121.09,21.14 121.23,21.28 121.38,21.28 121.55,21.11 121.69,21.11 121.84,21.26 121.84,21.4 121.67,21.57 121.67,21.71 122.2,22.25 122.34,22.25 122.45,22.15 122.45,21.84 122.55,21.74 122.75,21.74 122.85,21.84 122.85,22.21 122.95,22.32 123.16,22.32 123.26,22.21 123.26,21.86 123.36,21.76 123.56,21.76 123.66,21.86 123.66,22.21 123.77,22.32 123.97,22.32 124.07,22.21 124.07,21.92 124.17,21.82 124.38,21.82 124.48,21.92 124.48,22.21 124.58,22.32 124.78,22.32 124.88,22.21 124.88,21.87 124.99,21.76 125.19,21.76 125.29,21.87 125.29,22.21 125.39,22.32 126.4,22.32 126.56,22.15 126.56,22.01 126.18,21.63 126.18,21.48 126.32,21.34 126.47,21.34 126.85,21.72 126.99,21.72 127.14,21.58 127.14,21.44 126.89,21.19 126.89,21.05 126.99,20.94 127.14,20.94 127.42,21.23 127.66,21.23 127.76,21.13 127.76,20.22 127.86,20.12 128.06,20.12 128.16,20.22 128.16,21.13 128.27,21.23 128.47,21.23 128.57,21.13 128.57,20.19 128.67,20.08 128.88,20.08 128.98,20.19 128.98,21.13 129.08,21.23 129.43,21.23 129.68,21.49 133.69,21.49 134.89,22.69 134.89,25.66 136.02,26.8 RE38.2 ; RC18.2 105.52,23.03 105.4,22.92 v2(103.94,22.92) 103.94,23.43 104.31,23.79 104.31,24.1
PCH_SPI_D0_0_R: length 4
  BOTTOM w0.102: UC3.5 109.81,11.26 109.6,11.04 109.6,10.2 109.42,10.03 v3(109.18,10.03) 108.94,10.03 108.68,10.28 RC179.1
PCH_SPI_D0_R: length 86.3
  IN1 w0.119: v2(107.15,12.54) 107.27,12.54 107.49,12.76 107.49,12.96 107.37,13.08 106.76,13.08 106.19,13.65 106.19,14.48 106.31,14.6 106.57,14.6 106.69,14.48 106.69,14.11 106.81,13.99 107.13,13.99 107.25,14.11 107.25,14.48 107.37,14.6 107.61,14.6 107.74,14.47 107.74,13.48 107.87,13.35 108.05,13.35 108.2,13.51 108.2,14.96 108.08,15.08 106.31,15.08 106.19,15.2 106.19,15.74 103.55,18.39 103.55,19.79 101.57,21.77 v2(101.57,23.57)
  IN3 w0.142: v2(122.07,2.84) 122.07,3.07 123.03,4.03 128.32,4.03 132.24,7.95 134.4,7.95 136.62,10.17 136.62,14.05 138.09,15.52 138.09,18.85 140.08,20.84 140.08,27.33 138.68,28.73 138.68,30.04 138.56,30.16 v2(138.56,30.26)
  BOTTOM w0.102: v2(101.57,23.57) 101.57,24.17 RC23.2 ; v2(107.15,12.54) 107.07,12.46 107.07,10.74 107.15,10.66 107.34,10.66 107.44,10.76 107.44,10.89 RC179.2 107.94,11.03 107.94,9.87 109.37,8.44 111.25,8.44 116.93,2.75 v1(121.57,2.75) 121.98,2.75 v2(122.07,2.84) ; RE34.1 137.12,28.69 137.12,29.5 137.87,30.25 138.55,30.25 v2(138.56,30.26)
PCH_SPI_D0_R1: length 10.4
  BOTTOM w0.076: UC1.AV3 102.75,30.16 102.41,29.83 102.41,29.32 102.41,29.32 102.41,29.05 102.24,28.89 101.81,28.89 101.67,28.74 101.67,28.29 101.78,28.18 101.96,28.18 102.06,28.08
  BOTTOM w0.102: RC23.1 RC40.2 100.78,25.62 101.16,26 101.16,26.21 101.06,26.31 100.77,26.31 100.67,26.41 100.67,26.61 100.77,26.72 101.24,26.72 101.34,26.82 101.34,27.02 101.24,27.12 100.77,27.12 100.67,27.22 100.67,27.39 100.77,27.49 101.92,27.49 102.06,27.63 102.06,28.08
PCH_SPI_D1_0_R: length 3.3
  BOTTOM w0.102: RC180.1 119.86,12.98 119.86,13.59 v3(119.68,13.77) 119.65,13.8 UC3.2
PCH_SPI_D1_R: length 87.8
  IN1 w0.119: v2(118.54,16.35) 116.02,18.87 113.89,18.87 112.57,17.55 109.89,17.55 109.41,18.03 107.47,18.03 103.4,22.11 v2(103.4,23.14)
  IN3 w0.142: v2(138.02,29.72) 138.02,29.69 138.01,29.69 138.01,29.27 137.87,29.12 136.84,29.12 136.7,28.98 136.7,28.7 136.84,28.55 137.87,28.55 138.01,28.41 138.01,28.13 137.87,27.98 136.84,27.98 136.7,27.84 136.7,27.56 136.84,27.42 137.87,27.42 138.01,27.27 138.01,26.77 138.37,26.41 139.61,26.41 139.82,26.21 139.82,24.59 139.67,24.45 138.82,24.45 138.68,24.3 138.68,24.02 138.82,23.88 139.67,23.88 139.84,23.71 139.84,23.48 139.7,23.34 138.82,23.34 138.68,23.2 138.68,22.91 138.82,22.77 139.7,22.77 139.84,22.63 139.84,22.21 137.82,20.19 137.82,15.63 136.27,14.08 136.27,11.24 133.22,8.19 132.14,8.19 131.53,7.58 130.87,7.58 130.61,7.85 130.41,7.85 130.2,7.65 130.2,7.45 130.59,7.06 130.59,6.86 130.44,6.72 130.13,6.72 129.8,7.04 129.6,7.04 129.4,6.84 129.4,6.64 129.88,6.16 129.88,5.93 128.45,4.5 126.29,4.5 125.5,5.29 122.42,5.29 121.86,4.74 121.86,4.36 v2(122.25,3.98)
  BOTTOM w0.102: RC22.2 103.78,23.8 103.4,23.42 v2(103.4,23.14) ; RE35.1 137.55,29.26 138.01,29.72 v2(138.02,29.72) ; v2(118.54,16.35) 118.93,15.96 118.93,15.29 120.35,13.87 RC180.2 120.53,12.39 121.16,12.39 v1(122.57,10.98) 122.57,4.92 122.7,4.79 122.7,4.34 122.34,3.98 v2(122.25,3.98)
PCH_SPI_D1_R1: length 5.2
  BOTTOM w0.076: 102.9,27.5 102.9,28.79 103.07,28.95 103.07,29.34 102.8,29.61 UC1.AW3
  BOTTOM w0.102: 102.9,27.5 102.89,27.48 102.89,26.95 103.78,26.06 RC22.1
PCH_SPI_D2_0_R: length 7.4
  BOTTOM w0.102: UC3.3 116.61,12.53 116.22,12.91 116.22,16.41 v1(116.68,16.86) 116.68,17.52 117.19,18.03 RC176.2
PCH_SPI_D2_R: length 21.9
  IN1 w0.119: v2(102.19,23.58) 102.19,22.38 103.98,20.58 103.98,18.3 106.71,15.57 111.3,15.57 113.34,17.61 115.25,17.61 115.65,18.01 v2(115.65,18.21)
  BOTTOM w0.102: v2(115.65,18.21) 116.12,18.21 RC176.1 ; RC26.2 102.33,24.27 102.19,24.13 v2(102.19,23.58)
PCH_SPI_D2_R1: length 13
  BOTTOM w0.076: 102.64,28.11 102.33,28.42 102.33,28.67 102.8,29.14 UC1.AW2
  BOTTOM w0.102: RC41.2 RC19.2 105.05,20.54 v1(103.25,22.34) 102.99,22.6 102.99,22.97 102.99,22.97 102.99,23.31 102.99,23.31 102.99,23.56 103.21,23.77 103.21,24.67 103.15,24.73 103.15,24.82 102.79,25.18 RC26.1 102.76,25.59 102.97,25.8 103.36,25.8 103.47,25.9 103.47,26.1 103.36,26.21 102.86,26.21 102.7,26.37 102.7,28.05 102.64,28.11
PCH_SPI_D3_0_R: length 5.3
  BOTTOM w0.102: RC177.2 v1(112.59,16.69) 112.59,15.44 112.1,14.95 111.78,14.95 111.48,14.64 111.48,14.12 111.15,13.8 UC3.7
PCH_SPI_D3_R: length 24.3
  IN1 w0.119: v2(114.18,18.03) 113.4,18.03 111.19,15.82 106.81,15.82 104.2,18.42 104.2,20.71 102.83,22.09 102.83,23.81 102.64,24 99.58,24 98.82,23.24 v2(98.82,23.2)
  BOTTOM w0.102: RC25.2 98.82,24.1 v2(98.82,23.2) ; v2(114.18,18.03) 114.12,17.97 113.67,17.97 RC177.1
PCH_SPI_D3_R1: length 21
  BOTTOM w0.076: 98.58,24.62 99,25.04 RC25.1 99,25.29 100.12,26.41 100.12,27.84 100.54,28.26 100.54,29.17 100.68,29.3 100.91,29.3 101.17,29.56 101.17,29.93 101.34,30.09 101.78,30.09 101.95,30.27 102.24,30.27 102.58,30.61 103.55,30.61 103.67,30.49 UC1.AU4
  BOTTOM w0.102: 98.58,24.62 98.58,23.54 98.42,23.37 98.42,22.9 v1(98.17,22.65) 95.24,19.73 95.24,19.09 94.81,18.65 94.81,16.12 94.64,15.94 94.28,15.94 RC20.2
PCI_CLK_LPC1: length 14.6
  BOTTOM w0.076: UC1.AY9 101.79,33.79 100.68,33.79 100.44,33.55
  BOTTOM w0.102: 100.44,33.55 100.4,33.55 98.89,32.03 v1(98.89,31.54) 98.72,31.37 98.27,31.37 97.85,30.95 97.85,29.87 RC16.1 96.41,28.44 95.57,28.44 95.08,27.95 95.08,26.41 94.99,26.32 94.99,25.44 95.6,24.84 95.73,24.84 96.08,25.19 RC15.1
PCIE_CRX_LANTX_N6: length 167.7
  IN1 w0.089: 121.64,39.63 121.62,39.62 121.61,39.62 121.55,39.55 121.53,39.55 121.45,39.48 120.24,39.48 120.04,39.28 120.04,39.15 v2(119.77,38.88)
  IN1 w0.119: 121.64,39.63 122.45,40.44 122.45,41.8 124.99,44.34 124.99,45.88 122.4,48.46 122.4,48.55 122.41,48.56 122.41,48.9 122.4,48.91 122.4,53.89 121.8,54.5 121.8,64.81 122.13,65.14 122.13,70.15 119.24,73.03 119.24,74.74 117.4,76.58 117.4,80.13 115.76,81.78 111.49,81.78 103.59,89.69 95.27,89.69 92.67,92.28 65.3,92.28 60.82,96.77 43.43,96.77 38.98,101.22 38.87,101.22 30.65,109.44 30.65,113.86 27.66,116.86 27.66,119.23 28.82,120.4 28.82,120.55 31.76,123.49 33.46,123.49 33.75,123.2 v2(33.75,122.46)
  BOTTOM w0.076: v2(119.77,38.88) 119.77,38.83 UC1.G18
  BOTTOM w0.102: v2(33.75,122.46) 33.63,122.33 33.63,122 CL2.1
PCIE_CRX_LANTX_P6: length 167.8
  IN1 w0.089: v2(120.43,38.87) 120.22,39.08 120.22,39.2 120.31,39.3 121.54,39.3 121.67,39.43 121.72,39.43 121.77,39.47 121.79,39.47 121.79,39.48
  IN1 w0.119: v2(33.17,122.46) 33.17,122.46 33.53,122.83 33.53,123.11 33.37,123.27 31.85,123.27 29.04,120.46 29.04,120.31 27.87,119.14 27.87,116.95 30.87,113.95 30.87,109.54 38.96,101.44 39.07,101.44 43.52,96.99 60.91,96.99 65.39,92.5 92.76,92.5 95.36,89.9 103.68,89.9 111.59,82 115.85,82 117.62,80.22 117.62,76.67 119.46,74.83 119.46,73.12 122.34,70.24 122.34,65.05 122.01,64.72 122.01,54.59 122.62,53.98 122.62,49 122.63,48.99 122.63,48.55 125.21,45.97 125.21,44.25 122.67,41.71 122.67,40.35 121.79,39.48
  BOTTOM w0.076: v2(120.43,38.87) 120.48,38.82 120.48,38.57 120.32,38.41 120.2,38.41 UC1.F18
  BOTTOM w0.102: CL1.1 33.3,121.7 33.42,121.82 33.42,122.2 v2(33.17,122.46)
PCIE_CRX_SSDTX_N11: length 98.9
  TOP w0.102: JSSD1.8 195.35,14.65 195.19,14.8 195.19,14.97 v2(195.37,15.15)
  IN3 w0.142: v2(195.37,15.15) 195.37,15.17 195.04,15.51 195.04,16.36 193.12,18.28 193.12,19.62 192.05,20.69 183.86,20.69 182.3,19.12 178.02,19.12 176.65,17.76 166.83,17.76 166.17,17.1 164.6,17.1 164.41,16.91 160.11,16.91 158.86,18.16 158.86,20.67 157.67,21.86 156.59,21.86 156.04,22.4 156.04,24.92 155.53,25.44 155.53,26.67 154.81,27.38 154.65,27.38 153.31,28.72 152.27,28.72 151.91,29.08 151.91,31.74 149.92,33.73 149.92,35.16 148.43,36.64 148.07,36.64 147.04,37.67 138.64,37.67 138.18,38.13 135.75,38.13 135.46,38.42 133.2,38.42 131.93,39.69 130.69,39.69 129.72,40.66 129.08,40.66 127.55,42.18 127.48,42.26 127.47,42.26 126.99,42.26 125.8,43.46 123.4,43.46 122.7,44.16 121.08,44.16 121,44.24 121,44.44 v2(121.01,44.45)
  BOTTOM w0.076: v2(121.01,44.45) 120.75,44.71 UC1.E28
PCIE_CRX_SSDTX_N12: length 107.7
  TOP w0.102: v2(192.26,15.37) 192.25,15.37 192,15.12 192,14.97 192.1,14.86 192.26,14.86 192.35,14.78 JSSD1.14
  IN3 w0.142: v2(120.42,45.37) 120.37,45.37 120.21,45.54 120.21,45.73 120.31,45.84 120.59,45.84 120.77,46.01 121.21,46.01 121.79,45.43 123.51,45.43 123.79,45.71 124.69,45.71 124.78,45.62 124.86,45.62 129.3,41.18 129.94,41.18 130.86,40.25 132.13,40.25 132.57,39.81 134.94,39.81 136.09,38.65 138.4,38.65 138.85,38.2 147.26,38.2 148.29,37.17 149.34,37.17 151.03,35.47 151.03,34.83 150.66,34.46 150.66,33.75 154.79,29.61 154.93,29.61 155.28,29.26 155.28,27.65 156.05,26.88 156.05,25.65 156.57,25.14 156.57,22.79 156.93,22.43 157.88,22.43 160.13,20.18 160.13,19.56 162.27,17.43 164.19,17.43 164.38,17.62 165.77,17.62 166.43,18.28 175.97,18.28 177.78,20.09 182.47,20.09 183.59,21.21 193,21.21 195.37,18.84 195.37,17.85 196.01,17.21 196.01,15.86 196.42,15.46 196.42,14.79 195.93,14.3 192.31,14.3 191.94,14.68 191.94,15.03 192.26,15.35 v2(192.26,15.37)
  BOTTOM w0.076: v2(120.42,45.37) 120.42,45.49 UC1.E30
PCIE_CRX_SSDTX_P11: length 98.9
  TOP w0.102: JSSD1.9 194.85,14.7 194.97,14.81 194.97,14.98 v2(194.79,15.15)
  IN3 w0.142: v2(120.43,44.45) 120.43,44.44 120.96,43.9 122.6,43.9 123.3,43.2 125.69,43.2 126.89,42 127.37,42 127.38,42 127.45,41.93 128.98,40.4 129.62,40.4 130.58,39.44 131.82,39.44 133.1,38.17 135.36,38.17 135.65,37.88 138.08,37.88 138.53,37.42 146.94,37.42 147.97,36.39 148.33,36.39 149.67,35.05 149.67,33.62 151.66,31.63 151.66,28.97 152.16,28.47 153.2,28.47 154.54,27.13 154.71,27.13 155.28,26.56 155.28,25.33 155.79,24.82 155.79,22.3 156.48,21.61 157.56,21.61 158.61,20.57 158.61,18.06 160.01,16.66 164.51,16.66 164.7,16.85 166.28,16.85 166.93,17.5 176.76,17.5 178.13,18.87 182.4,18.87 183.96,20.43 191.95,20.43 192.87,19.51 192.87,18.18 194.79,16.26 v2(194.79,15.15)
  BOTTOM w0.076: v2(120.43,44.45) 120.75,44.13 UC1.E27
PCIE_CRX_SSDTX_P12: length 107.7
  TOP w0.102: JSSD1.15 191.85,14.83 191.79,14.88 191.79,15.25 v2(191.68,15.37)
  IN3 w0.142: v2(120.42,46.26) 121.31,46.26 121.9,45.68 123.41,45.68 123.69,45.96 124.8,45.96 124.89,45.87 124.96,45.87 129.4,41.43 130.04,41.43 130.97,40.5 132.23,40.5 132.67,40.06 135.04,40.06 136.2,38.9 138.5,38.9 138.96,38.45 147.36,38.45 148.39,37.42 149.44,37.42 151.28,35.58 151.28,34.73 150.91,34.35 150.91,33.85 154.89,29.87 155.03,29.87 155.53,29.37 155.53,27.76 156.3,26.99 156.3,25.76 156.82,25.24 156.82,22.9 157.03,22.68 157.99,22.68 160.38,20.29 160.38,19.67 162.37,17.68 164.09,17.68 164.28,17.87 165.66,17.87 166.32,18.53 175.87,18.53 177.67,20.34 182.36,20.34 183.48,21.46 193.11,21.46 195.62,18.94 195.62,17.95 196.26,17.32 196.26,15.97 196.67,15.56 196.67,14.69 196.03,14.05 192.21,14.05 191.69,14.57 191.69,15.36 v2(191.68,15.37)
  BOTTOM w0.076: v2(120.42,46.26) 120.1,45.95 UC1.F30
PCIE_CRX_WLANTX_N5: length 126
  IN1 w0.089: 121.62,38.63 121.42,38.43 120.85,38.43 120.48,38.05 v2(120.4,38.05)
  IN1 w0.119: v2(53.61,98.94) 53.41,99.14 53.41,99.9 54.46,100.95 56.47,100.95 59.93,97.49 61.11,97.49 65.01,93.59 92.64,93.59 95.78,90.45 103.97,90.45 111.88,82.54 116.26,82.54 118.32,80.48 118.32,76.73 120.54,74.51 120.54,72.92 122.89,70.57 122.89,63.47 123.55,62.81 123.55,62.06 122.52,61.03 122.52,54.79 123.14,54.17 123.14,49.95 125.71,47.38 125.71,44.04 123.27,41.61 123.27,40.28 121.62,38.63
  BOTTOM w0.102: UC1.F16 120.23,37.51 120.37,37.54 120.49,37.73 120.43,38.04 v2(120.4,38.05) ; JWLAN1.35 53.55,99.41 53.43,99.29 53.43,99.12 v2(53.61,98.94)
PCIE_CRX_WLANTX_P5: length 126
  IN1 w0.089: 121.62,38.32 121.55,38.25 121.21,38.25 v2(121.01,38.05)
  IN1 w0.119: 121.62,38.32 122.89,39.59 123.49,40.19 123.49,41.52 125.93,43.95 125.93,47.47 123.36,50.04 123.36,54.26 122.73,54.89 122.73,60.94 123.77,61.97 123.77,62.15 123.77,62.9 123.11,63.56 123.11,70.66 120.76,73.01 120.76,74.6 118.54,76.82 118.54,80.57 116.35,82.76 111.97,82.76 104.06,90.67 95.88,90.67 92.73,93.81 65.1,93.81 61.21,97.71 60.02,97.71 56.56,101.17 54.37,101.17 53.19,99.99 53.19,99.1 v2(53.03,98.94)
  BOTTOM w0.102: JWLAN1.33 53.05,99.44 53.2,99.29 53.2,99.11 v2(53.03,98.94) ; v2(121.01,38.05) UC1.E16
PCIE_CTX_C_SSDRX_N11: length 5.3
  TOP w0.102: JSSD1.6 196.35,14.89 196.5,15.04 196.5,15.37 196.23,15.64 195.59,15.64 195.56,15.66 v4(194.52,15.66) 193.85,15.66 193.43,16.08 193.43,16.21 CS18.2
PCIE_CTX_C_SSDRX_N12: length 3.9
  TOP w0.102: CS16.2 191.7,16.18 191.7,16.09 191.92,15.87 192.63,15.87 v4(193.01,15.48) 193.48,15.01 193.48,14.88 193.35,14.75 JSSD1.12
PCIE_CTX_C_SSDRX_P11: length 5.3
  TOP w0.102: JSSD1.5 196.85,14.89 196.7,15.04 196.7,15.46 196.29,15.87 v4(195.87,15.87) 194.82,15.87 194.8,15.89 194.24,15.89 194.22,15.87 193.94,15.87 193.64,16.17 193.64,16.27 CS19.2
PCIE_CTX_C_SSDRX_P12: length 3.8
  TOP w0.102: CS17.2 191.9,16.3 191.9,16.17 192,16.07 192.71,16.07 192.95,15.84 192.98,15.84 193.37,15.45 193.37,15.41 193.69,15.1 193.69,14.84 193.85,14.68 JSSD1.11
PCIE_CTX_LANRX_N6: length 164.2
  IN1 w0.119: v2(28.95,117.68) 28.96,117.68 29.32,117.31 30.42,117.31 31.58,116.15 31.58,109.83 39.26,102.16 58.08,102.16 65.58,94.67 93.02,94.67 96.3,91.39 104.36,91.39 112.19,83.55 116.74,83.55 119.3,80.99 119.3,77.19 121.94,74.55 121.94,72.95 124.29,70.6 124.29,67.96 125.56,66.69 125.56,63.38 125.97,62.98 125.97,59.64 123.45,57.13 123.45,55.2 124.5,54.16 124.74,54.16 125.18,53.72 125.18,49.24 126.64,47.77 126.64,44.52 127.34,43.82 127.34,43.28 127.15,43.09 v2(127.15,42.71)
  BOTTOM w0.076: v2(127.15,42.71) 127.15,43.09 127.22,43.17 127.42,43.17 128,42.59 128,41.04 127.2,40.24 125.59,40.24 125.36,40.47 124.06,40.47 123.78,40.2 122.85,40.2 122.71,40.34 122.38,40.34 122.1,40.06 UC1.D20
  BOTTOM w0.102: CL4.1 29.55,117.51 29.12,117.51 v2(28.95,117.68)
PCIE_CTX_LANRX_P6: length 164.2
  IN1 w0.119: v2(126.69,43.18) 126.69,43.18 126.69,43.19 126.94,43.19 127.12,43.37 127.12,43.73 126.43,44.43 126.43,47.68 124.96,49.15 124.96,53.63 124.65,53.94 124.41,53.94 123.23,55.11 123.23,57.22 125.75,59.73 125.75,62.88 125.34,63.29 125.34,66.6 124.07,67.87 124.07,70.51 121.72,72.86 121.72,74.46 119.08,77.1 119.08,80.9 116.65,83.34 112.1,83.34 104.27,91.17 96.21,91.17 92.93,94.45 65.49,94.45 57.99,101.94 39.17,101.94 31.37,109.74 31.37,116.06 30.33,117.09 v2(28.95,117.09)
  BOTTOM w0.076: UC1.C20 122.34,40.06 122.27,39.98 122.27,39.82 122.33,39.76 122.77,39.76 122.82,39.81 122.82,39.95 122.9,40.03 123.85,40.03 124.13,40.31 125.29,40.31 125.52,40.08 127.27,40.08 128.16,40.97 128.16,42.66 127.49,43.33 127.15,43.33 127.03,43.21 126.94,43.21 126.93,43.19 126.69,43.19 126.69,43.18 v2(126.69,43.18)
  BOTTOM w0.102: v2(28.95,117.09) 29.15,117.29 29.55,117.29 CL3.1
PCIE_CTX_SSDRX_N11: length 94.1
  TOP w0.102: v2(184.87,19) 185.17,18.7 185.17,18.53 185.39,18.31 v4(186.02,18.31) 186.94,18.31 188.37,19.74 192.73,19.74 193.03,19.44 193.03,19.41 193.55,18.89 193.55,18.1 193.45,18 193.16,18 193.06,17.9 CS18.1
  IN3 w0.142: v2(184.87,19) 185.03,18.85 185.03,18.83 185.2,18.65 185.2,18.49 184.28,17.57 178.66,17.57 177.51,16.42 177.51,15.81 177.21,15.51 165.2,15.51 165,15.31 162.99,15.31 162.24,14.56 160.27,14.56 157.98,16.84 157.76,16.84 155.99,18.61 155.99,20.23 153.57,22.64 153.57,24.7 152.03,26.25 151.56,26.25 150.95,26.85 150.95,27.78 150.32,28.4 150.32,29.42 149.69,30.06 149.69,30.86 148.71,31.84 148.52,31.84 146.76,33.6 145.07,33.6 142.54,36.12 139.85,36.12 139.68,35.96 135.73,35.96 135.56,36.12 133.34,36.12 132.6,36.87 130.98,36.87 128.42,39.43 128.42,40.22 127.23,41.41 127.16,41.48 127.15,41.48 126.67,41.48 125.66,42.5 125.41,42.5 v2(125.26,42.64)
  BOTTOM w0.076: v2(125.26,42.64) 125.11,42.48 123.18,42.48 123.02,42.64 122.79,42.64 122.62,42.81 122.3,42.81 122.02,42.53 UC1.D24
PCIE_CTX_SSDRX_N12: length 91.7
  TOP w0.102: CS16.1 191.61,17.81 191.61,18.09 191.21,18.5 191.21,18.86 191.49,19.15 191.73,19.15 v2(191.88,19.29)
  IN3 w0.142: v2(129.52,39.79) 129.52,39.53 131.41,37.64 135.14,37.64 135.43,37.35 137.86,37.35 138.31,36.9 142.86,36.9 144.59,35.17 146.41,35.17 148.61,32.98 149.03,32.98 151.13,30.87 151.13,28.75 152.04,27.85 152.04,27.39 154.08,25.35 154.42,25.35 155.27,24.51 155.27,22.04 156.76,20.55 156.76,18.93 158.08,17.62 158.3,17.62 160.35,15.57 162.16,15.57 162.67,16.08 164.68,16.08 164.88,16.28 171.16,16.28 171.86,16.98 176.98,16.98 178.34,18.35 182.62,18.35 184,19.73 190.11,19.73 190.62,19.22 191.8,19.22 v2(191.88,19.29)
  BOTTOM w0.076: UC1.A25 123.2,43.1 123.15,43.15 123.15,43.34 123.21,43.41 123.78,43.41 123.82,43.44 125.25,43.44 126,44.19 127.49,44.19 128.77,42.91 128.77,40.2 129.24,39.73 129.45,39.73 v2(129.52,39.79)
PCIE_CTX_SSDRX_P11: length 94.2
  TOP w0.102: v2(185.45,19) 185.38,18.93 185.38,18.61 185.48,18.51 185.72,18.51 185.74,18.53 186.3,18.53 186.33,18.51 186.85,18.51 188.29,19.95 192.82,19.95 v4(193.42,19.34) 193.76,19 193.76,17.68 CS19.1
  IN3 w0.142: v2(185.45,19) 185.45,18.39 184.39,17.32 178.77,17.32 177.76,16.31 177.76,15.7 177.31,15.26 165.31,15.26 165.1,15.05 163.09,15.05 162.35,14.31 160.16,14.31 157.88,16.59 157.65,16.59 155.73,18.51 155.73,20.12 153.32,22.54 153.32,24.6 151.92,26 151.45,26 150.7,26.75 150.7,27.67 150.07,28.3 150.07,29.31 149.43,29.95 149.43,30.76 148.6,31.59 148.42,31.59 146.65,33.35 144.96,33.35 142.44,35.87 139.95,35.87 139.79,35.71 135.62,35.71 135.46,35.87 133.24,35.87 132.49,36.62 130.87,36.62 128.17,39.32 128.17,40.12 127.13,41.16 127.05,41.23 126.57,41.23 125.55,42.25 125.45,42.25 v2(125.26,42.06)
  BOTTOM w0.076: UC1.C24 122.25,42.53 122.18,42.47 122.18,42.33 122.27,42.24 122.67,42.24 122.77,42.34 122.77,42.39 122.79,42.41 122.79,42.42 122.85,42.48 122.95,42.48 123.11,42.32 125,42.32 v2(125.26,42.06)
PCIE_CTX_SSDRX_P12: length 91.6
  TOP w0.102: v2(191.88,18.71) 191.65,18.94 191.57,18.94 191.41,18.78 191.41,18.58 191.82,18.18 191.82,17.86 CS17.1
  IN3 w0.142: v2(129.1,39.38) 129.31,39.38 131.3,37.39 135.03,37.39 135.32,37.1 137.76,37.1 138.21,36.65 142.76,36.65 144.49,34.92 146.31,34.92 148.5,32.73 148.93,32.73 150.88,30.77 150.88,28.65 151.79,27.75 151.79,27.29 153.97,25.1 154.32,25.1 155.02,24.4 155.02,21.94 156.51,20.44 156.51,18.83 157.97,17.37 158.2,17.37 160.24,15.32 162.26,15.32 162.77,15.83 164.78,15.83 164.99,16.03 171.27,16.03 171.96,16.73 177.08,16.73 178.45,18.1 182.72,18.1 184.1,19.48 190,19.48 190.52,18.97 191.6,18.97 191.7,18.87 191.72,18.87 v2(191.88,18.71)
  BOTTOM w0.076: UC1.B25 123.08,42.84 123.68,42.84 123.77,42.93 123.77,42.99 123.77,42.99 123.77,43.17 123.89,43.28 125.32,43.28 126.07,44.02 127.43,44.02 128.61,42.84 128.61,40.13 129.1,39.63 v2(129.1,39.38)
PCIE_CTX_WLANRX_N5: length 10
  BOTTOM w0.102: CW1.2 44.32,97.69 44.32,97.83 44.57,98.09 45.37,98.09 45.4,98.06 45.96,98.06 45.98,98.09 v4(47.12,98.09) 51.15,98.09 51.89,98.82 51.89,99.2 52.05,99.37 JWLAN1.29
PCIE_CTX_WLANRX_N5_C: length 149.6
  IN3 w0.142: v2(125.11,39.08) 124.92,39.26 124.92,39.9 122.51,42.31 120.29,42.31 119.14,43.46 119.14,55.84 119.72,56.41 123.72,56.41 126.54,59.24 126.54,69.01 126.88,69.35 126.88,75.88 127.85,76.85 127.85,83.22 125.52,85.55 112.83,85.55 105.17,93.21 77.05,93.21 72.07,98.19 56.15,98.19 53.15,95.19 44.47,95.19 44.33,95.33 44.33,95.6 v2(44.5,95.76)
  BOTTOM w0.076: UC1.C19 122.28,39.49 122.51,39.26 122.65,39.26 122.72,39.24 123.62,39.24 123.93,39.54 124.58,39.54 125.04,39.08 v2(125.11,39.08)
  BOTTOM w0.102: v2(44.5,95.76) 44.32,95.94 44.32,96.09 CW1.1
PCIE_CTX_WLANRX_P5: length 10
  BOTTOM w0.102: CW2.2 44.11,97.69 44.11,97.92 44.49,98.29 v4(45.68,98.29) 46.82,98.29 46.84,98.32 47.4,98.32 47.43,98.29 51.06,98.29 51.68,98.91 51.68,99.25 51.55,99.38 JWLAN1.27
PCIE_CTX_WLANRX_P5_C: length 149.7
  IN3 w0.142: v2(43.91,95.76) 44.08,95.6 44.08,95.23 44.37,94.94 53.25,94.94 56.25,97.94 71.96,97.94 76.94,92.96 105.07,92.96 112.73,85.3 125.42,85.3 127.6,83.12 127.6,76.95 126.63,75.99 126.63,69.46 126.29,69.12 126.29,59.34 123.61,56.66 119.61,56.66 118.89,55.94 118.89,43.35 120.19,42.06 122.4,42.06 124.67,39.8 124.67,39.22 v2(124.52,39.08)
  BOTTOM w0.076: v2(124.52,39.08) 124.52,39.22 124.37,39.37 123.99,39.37 123.69,39.07 122.7,39.07 122.62,39.1 122.44,39.1 122.4,39.14 122.06,39.14 UC1.D19
  BOTTOM w0.102: CW2.1 44.1,96.1 44.1,95.95 v2(43.91,95.76)
PCIE_PTX_LANRX_N6_C: length 2.1
  BOTTOM w0.102: CL4.2 31.18,117.52 31.48,117.52 31.7,117.3 32.21,117.3 32.3,117.4 UL1.14
PCIE_PTX_LANRX_P6_C: length 2.1
  BOTTOM w0.102: UL1.13 32.29,117 32.2,117.1 31.61,117.1 31.39,117.32 31.22,117.32 CL3.2
PCIE_RCOMPN: length 2.2
  TOP w0.381: RC65.1 119.68,31.05 119.68,31.52 v1(119.88,31.72) 120.3,31.72 v2(120.41,31.6)
  BOTTOM w0.254: UC1.F5 120.1,31.29 v2(120.41,31.6)
PCIE_RCOMPP: length 1.6
  TOP w0.381: v2(121.04,31.61) 121.04,31.5 120.94,31.39 120.94,31.39 120.63,31.08 120.62,31.08 RC65.2
  BOTTOM w0.254: v2(121.04,31.61) 121.04,31.49 UC1.E5
PCIE_WAKE#: length 342.5
  TOP w0.102: v2(35.03,119.65) 34.57,120.12 v1(31.73,120.12) v2(27.83,120.12) ; v2(189.86,15.17) 189.85,15.16 JSSD1.19 ; RC99.1 v2(83.97,19.01)
  IN1 w0.119: v2(83.97,19.01) 83.51,19.46 83.51,20.28 82.03,21.76 77.77,21.76 77.6,21.59 75.36,21.59 73.93,20.16 71.32,20.16 71.18,20.02 69.53,18.37 61.49,18.37 61.15,18.71 57.57,18.71 57.23,18.37 49.12,18.37 47.89,19.61 47.89,21.75 46.2,23.44 46.2,36.45 35.9,46.76 35.9,103.49 30.15,109.24 30.15,113.66 27.05,116.76 27.05,119.33 v2(27.83,120.12) ; v2(189.86,15.17) 189.86,16.35 191.1,17.59 191.1,24.43 190.14,25.39 190.14,28.97 192.55,31.39 193.95,31.39 194.84,32.28 194.84,33.22 193.82,34.24 193.82,37.78 194.19,38.14 194.19,41.01 193.61,41.58 193.61,43.21 v2(193.37,43.46)
  IN2 w0.127: v2(83.97,19.01) 84.41,18.57 94.83,18.57 98.1,21.83 101.9,21.83 104.64,19.1 109.11,19.1 109.37,18.84 112.16,18.84 113.3,19.98 117.74,19.98 119.76,22 120.74,22 121.39,22.65 124.94,22.65 125.52,23.22 125.52,23.69 125.9,24.07 125.92,24.07 125.92,24.07 129.94,24.07 134.73,28.87 134.73,30.11 137.91,33.29 138.83,33.29 139.47,32.66 v2(140.8,32.66) 142.01,33.86 142.71,33.86 144.2,35.36 145.92,35.36 146.76,36.19 147.34,36.19 147.47,36.32 148.63,36.32 150.07,34.88 150.07,34.31 150.76,33.62 152.02,33.62 152.28,33.36 157.25,33.36 159.34,35.45 161.32,35.45 162.84,36.98 177.01,36.98 179.16,39.13 180.8,40.77 181.79,40.77 183.21,42.19 187.94,42.19 188.31,41.83 190.34,41.83 190.87,42.35 192.26,42.35 v2(193.37,43.46)
  BOTTOM w0.102: v2(35.03,119.65) 35.01,119.65 35.01,119.47 34.95,119.42 UL1.21 ; UE1.4 141.13,19.98 141.53,19.58 142.33,19.58 145.09,22.34 145.33,22.34 146.13,23.14 146.13,23.58 145.59,24.13 145.59,24.32 145.59,25.4 145.02,25.96 145.02,28.85 143.63,30.24 143.63,30.72 143.12,31.23 142.69,31.23 142.41,31.51 142.09,31.51 141.48,32.12 141.34,32.12 v2(140.8,32.66) 140.62,32.84 139.97,32.84 138.82,33.99 RE12.2
PECI_EC: length 81.3
  TOP w0.102: v2(138.77,56.85) v1(136.58,56.85) 136.23,56.85 135.44,56.06 135.44,51.25 138.09,48.6 138.09,47.97 139.54,46.52 139.54,40.74 140.32,39.96 141.7,39.96 142.16,39.96 142.84,39.28 142.84,38.48 142.66,38.3 142.66,36.7 143.27,36.09 143.27,33.17 150.34,26.1 151.88,26.1 152.18,26.4 153.18,26.4 153.79,27.01 155.59,27.01 157.16,25.43 158.37,25.43 159.35,24.44 159.35,22.54 159,22.19 159,19.98 158.69,19.67 158.69,18.03 RE23.2 158.11,17.45 158.11,16.55 DE1.1
  BOTTOM w0.076: 125.24,58.13 124.92,58.13 123.73,59.32 UC1.A54
  BOTTOM w0.102: v2(138.77,56.85) 138.63,56.98 135.15,56.98 134.28,56.12 134.28,54.4 133.83,53.94 132.54,53.94 132.3,54.18 132.3,54.62 131.22,55.7 131.22,57.03 130.77,57.49 128.16,57.49 127.52,58.13 125.24,58.13
PECI_MEC1404: length 2.7
  TOP w0.102: v2(157.25,19.37) 157.25,19.28 RE23.1
  BOTTOM w0.102: v2(157.25,19.37) 157.04,19.58 UE1.94
PEG_CLKREQ#: length 124.3
  TOP w0.089: 104.03,34.79 v2(104.4,34.42)
  TOP w0.102: 104.03,34.79 102.92,34.79 101.63,33.5 97.83,33.5 95.98,31.65 95.33,31.65 95.08,31.39 95.08,29.99 94.1,29.01 94.1,24.95 93.81,24.66 88.99,24.66 88.8,24.85 RC71.2
  IN3 w0.142: v2(104.4,34.42) 104.84,34.42 105.24,34.82 106.06,34.82 106.38,35.14 106.38,35.39 107.02,36.03 108.1,36.03 108.85,36.79 108.85,38.44 107.91,39.39 107.91,40.6 108.03,40.73 108.03,44.09 107.79,44.33 107.79,63.03 108.41,63.65 110.17,63.65 110.87,64.34 110.87,69.3 113.27,71.7 113.27,72.61 115.5,74.85 118.24,74.85 v2(118.83,74.26) ; v2(130.15,77.1) 130.14,77.11 130.14,84.29 126.53,87.9 116.25,87.9 114,90.15 v2(114,98.7)
  BOTTOM w0.076: v2(104.4,34.42) 104.78,34.42 UC1.AR10
  BOTTOM w0.102: v2(130.15,77.1) 128.72,77.1 v1(128.13,76.51) 127.28,75.66 120.23,75.66 v2(118.83,74.26) ; RV153.1 v2(114,98.7)
PEG_CLKREQ#_G: length 7.6
  BOTTOM w0.102: UV1.N7 116.03,106.55 116.03,103.33 115.83,103.14 v1(115.83,102.14) 115.83,101.66 115.42,101.24 RV368.2 114.94,101.24 RV153.2
PEG_GTX_C_HRX_N0: length 141.9
  IN1 w0.089: v2(119.71,36.22) 119.55,36.22 119.42,36.1 119.42,35.92 119.51,35.84 122.81,35.84
  IN1 w0.119: 122.81,35.84 122.84,35.8 125.97,35.8 126.19,35.58 128.99,35.58 130.07,36.66 130.07,37.19 131.61,38.73 131.61,39.9 135.3,43.59 135.3,44.89 136.34,45.92 136.34,50.03 136.07,50.3 136.07,55.55 132.85,58.78 132.85,65.53 132.96,65.64 132.96,73.63 131.34,75.25 131.34,82.61 124.96,88.98 114.78,88.98 107.28,96.49 100.98,96.49 97.78,99.69 97.78,108.07 95.94,109.91 95.94,113.2 97.2,114.46 97.2,116.63 97.88,117.31 97.88,118.23 100.94,121.29 100.94,127.85 102.1,129.01 102.1,130.85 101.9,131.05 101.83,131.05 101.49,130.72 v2(101.49,130.69)
  BOTTOM w0.076: v2(119.71,36.22) 119.83,36.1 119.83,35.82 119.67,35.66 119.56,35.66 UC1.G13
  BOTTOM w0.102: CV2.1 101.18,130.03 101.08,130.13 100.74,130.13 100.64,130.23 100.64,130.47 101.14,130.97 101.25,130.97 101.32,130.9 101.35,130.9 101.49,130.76 v2(101.49,130.69)
PEG_GTX_C_HRX_N1: length 145.5
  IN1 w0.119: v2(102.99,130.15) 102.99,130.15 102.99,130.12 103.2,130.33 103.85,130.33 104.07,130.11 104.07,129.53 101.58,127.04 101.58,121.02 98.52,117.96 98.52,117.04 97.84,116.36 97.84,114.19 97.02,113.37 97.02,109.74 99.07,107.7 99.07,99.42 101.35,97.13 107.58,97.13 112.28,92.43 113.52,92.43 113.76,92.19 113.76,91.65 114.99,90.42 116.25,90.42 117.01,91.18 121.18,91.18 122.74,89.62 128.03,89.62 132.89,84.76 132.89,74.61 134,73.5 134,58.64 137.28,55.36 137.28,45.96 135.95,44.62 135.95,43.32 132.25,39.63 132.25,38.47 130.71,36.92 130.71,36.39 129.26,34.94 125.76,34.94 125.56,35.14 121.71,35.14 121.7,35.15 121,35.15 120.57,34.72 119.85,34.72 119.66,34.91 119.66,35.08 v2(119.83,35.25)
  BOTTOM w0.076: UC1.F11 120.1,34.5 120.03,34.42 119.86,34.42 119.78,34.5 119.78,35.2 v2(119.83,35.25)
  BOTTOM w0.102: CV4.1 102.3,130.18 102.3,130.39 102.43,130.53 102.61,130.53 v2(102.99,130.15)
PEG_GTX_C_HRX_N2: length 137.2
  TOP w0.102: v2(96.12,128.67) 96.13,128.67 96.4,128.4 96.4,127.75 96.62,127.53 97.96,127.53 100.69,124.8 105.4,124.8 105.4,124.8 105.54,124.8 105.64,124.69 105.64,124.17 CV6.1
  IN1 w0.089: 122.9,38.69 122.88,38.68 122.88,38.66 122.79,38.57 121.9,37.68 121.54,37.68 121.53,37.67 119.55,37.67 119.46,37.76 119.46,37.95 119.57,38.05 v2(119.71,38.05)
  IN1 w0.119: 122.9,38.69 124.13,39.93 124.52,39.93 126.46,41.86 127.27,41.86 127.84,42.43 127.84,44.03 127.14,44.73 127.14,47.98 125.69,49.43 125.69,53.69 126.06,54.06 127.37,54.06 127.7,54.4 127.7,66.47 126.62,67.55 126.62,71.67 120.53,77.76 120.53,81.07 120.53,81.48 120.52,81.5 116.89,85.12 114.72,85.12 112.55,85.12 105.04,92.63 99.38,92.63 99.36,92.65 99.34,92.65 93.81,98.19 93.43,98.57 93.43,106.1 93.05,106.48 93.05,106.48 92.08,107.44 92.08,114.8 92.75,115.47 92.75,121.21 92.44,121.52 92.44,122.06 92.44,126.75 94.01,128.32 95.52,128.32 95.59,128.25 96.17,128.25 96.29,128.37 96.29,128.49 v2(96.12,128.67)
  BOTTOM w0.076: UC1.G16 119.57,37.48 119.75,37.48 119.82,37.56 119.82,37.98 119.75,38.05 v2(119.71,38.05)
PEG_GTX_C_HRX_N3: length 144.5
  TOP w0.102: CV8.1 107.6,125.34 107.6,125.92 106.95,126.57 102.74,126.57 98.1,131.21 97.49,131.21 97.24,130.96 97.24,130.73 v2(97.05,130.54)
  IN1 w0.089: 122.74,36.8 122.73,36.8 122.71,36.78 122.65,36.78 122.65,36.78 120.42,36.78 120.31,36.89 120.31,37.02 v2(120.4,37.11)
  IN1 w0.119: v2(97.05,130.54) 97.05,130.53 97.35,130.24 97.35,128.52 96.44,127.61 95.32,127.61 95.25,127.68 94.28,127.68 93.08,126.48 93.08,121.79 93.39,121.48 93.39,115.2 92.73,114.53 92.73,107.71 93.69,106.74 94.07,106.36 94.07,98.83 99.61,93.3 99.63,93.3 99.65,93.27 105.3,93.27 112.81,85.77 113.39,85.77 123.63,85.77 127.59,81.81 127.59,77.3 126.64,76.35 126.64,73.05 127.46,72.22 127.46,67.72 128.35,66.84 128.35,54.66 128.53,54.48 128.53,52.56 127.02,51.05 127.02,49.01 127.79,48.24 127.79,44.99 128.48,44.3 128.48,41.74 126.92,40.18 126.74,40.18 126.07,39.51 126.07,39.32 125.28,38.53 124.96,38.53 123.22,36.8 122.74,36.8
  BOTTOM w0.076: UC1.F15 120.4,36.98 v2(120.4,37.11)
PEG_GTX_C_HRX_P0: length 142.2
  IN1 w0.089: 122.71,35.63 122.69,35.64 119.46,35.64 119.25,35.85 119.25,36.05 v2(119.07,36.22)
  IN1 w0.119: 122.71,35.63 122.75,35.58 125.88,35.58 126.1,35.37 129.08,35.37 130.28,36.57 130.28,37.09 131.83,38.64 131.83,39.81 135.52,43.5 135.52,44.8 136.56,45.83 136.56,50.12 136.29,50.39 136.29,55.64 133.07,58.87 133.07,65.44 133.18,65.55 133.18,73.72 131.55,75.34 131.55,82.7 125.05,89.2 114.87,89.2 107.37,96.71 101.07,96.71 98,99.78 98,108.16 96.16,110 96.16,113.11 97.42,114.37 97.42,116.54 98.1,117.22 98.1,118.14 101.16,121.2 101.16,127.76 102.32,128.92 102.32,130.95 101.99,131.27 101.52,131.27 v2(101.49,131.3)
  BOTTOM w0.102: v2(101.49,131.3) 101.36,131.17 101.05,131.17 100.44,130.56 100.44,129.66 CV1.1 ; v2(119.07,36.22) UC1.H13
PEG_GTX_C_HRX_P1: length 145.5
  IN1 w0.119: v2(119.17,35.24) 119.4,35.01 119.4,34.86 119.76,34.5 120.66,34.5 121.1,34.93 121.61,34.93 121.62,34.92 125.47,34.92 125.67,34.72 129.35,34.72 130.93,36.3 130.93,36.83 132.47,38.38 132.47,39.54 136.16,43.23 136.16,44.53 137.5,45.87 137.5,55.45 134.22,58.73 134.22,73.59 133.11,74.7 133.11,84.85 128.12,89.84 122.83,89.84 121.27,91.4 116.92,91.4 116.16,90.64 115.08,90.64 113.98,91.74 113.98,92.28 113.61,92.65 112.37,92.65 107.67,97.35 101.44,97.35 99.28,99.51 99.28,107.79 97.24,109.83 97.24,113.28 98.06,114.1 98.06,116.27 98.74,116.95 98.74,117.87 101.8,120.93 101.8,126.95 104.29,129.44 104.29,130.2 103.94,130.54 103.16,130.54 102.99,130.71 v2(102.99,130.73)
  BOTTOM w0.102: CV3.1 102.09,130.48 102.35,130.73 v2(102.99,130.73) ; UC1.G11 119.17,35.14 v2(119.17,35.24)
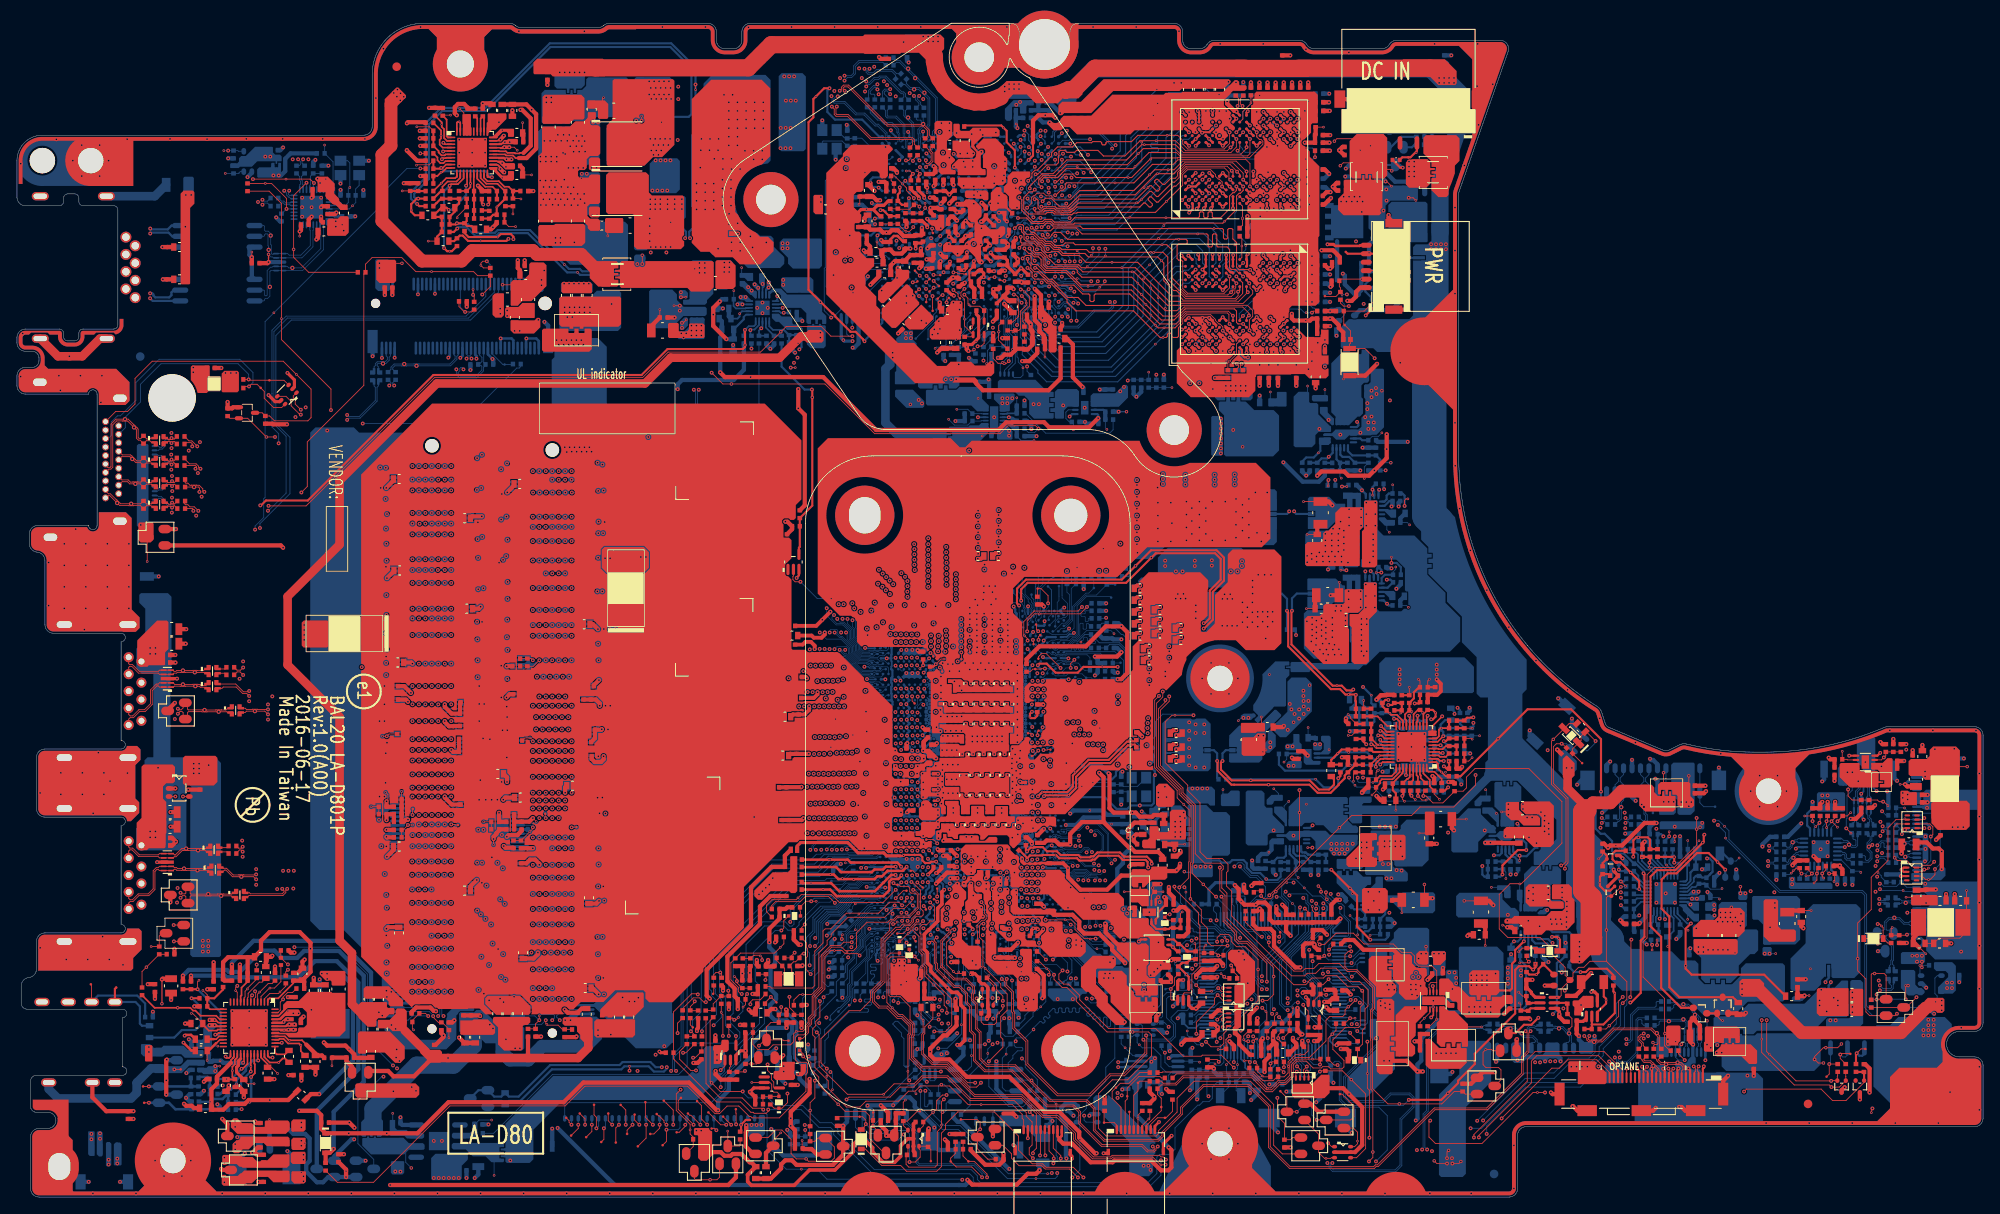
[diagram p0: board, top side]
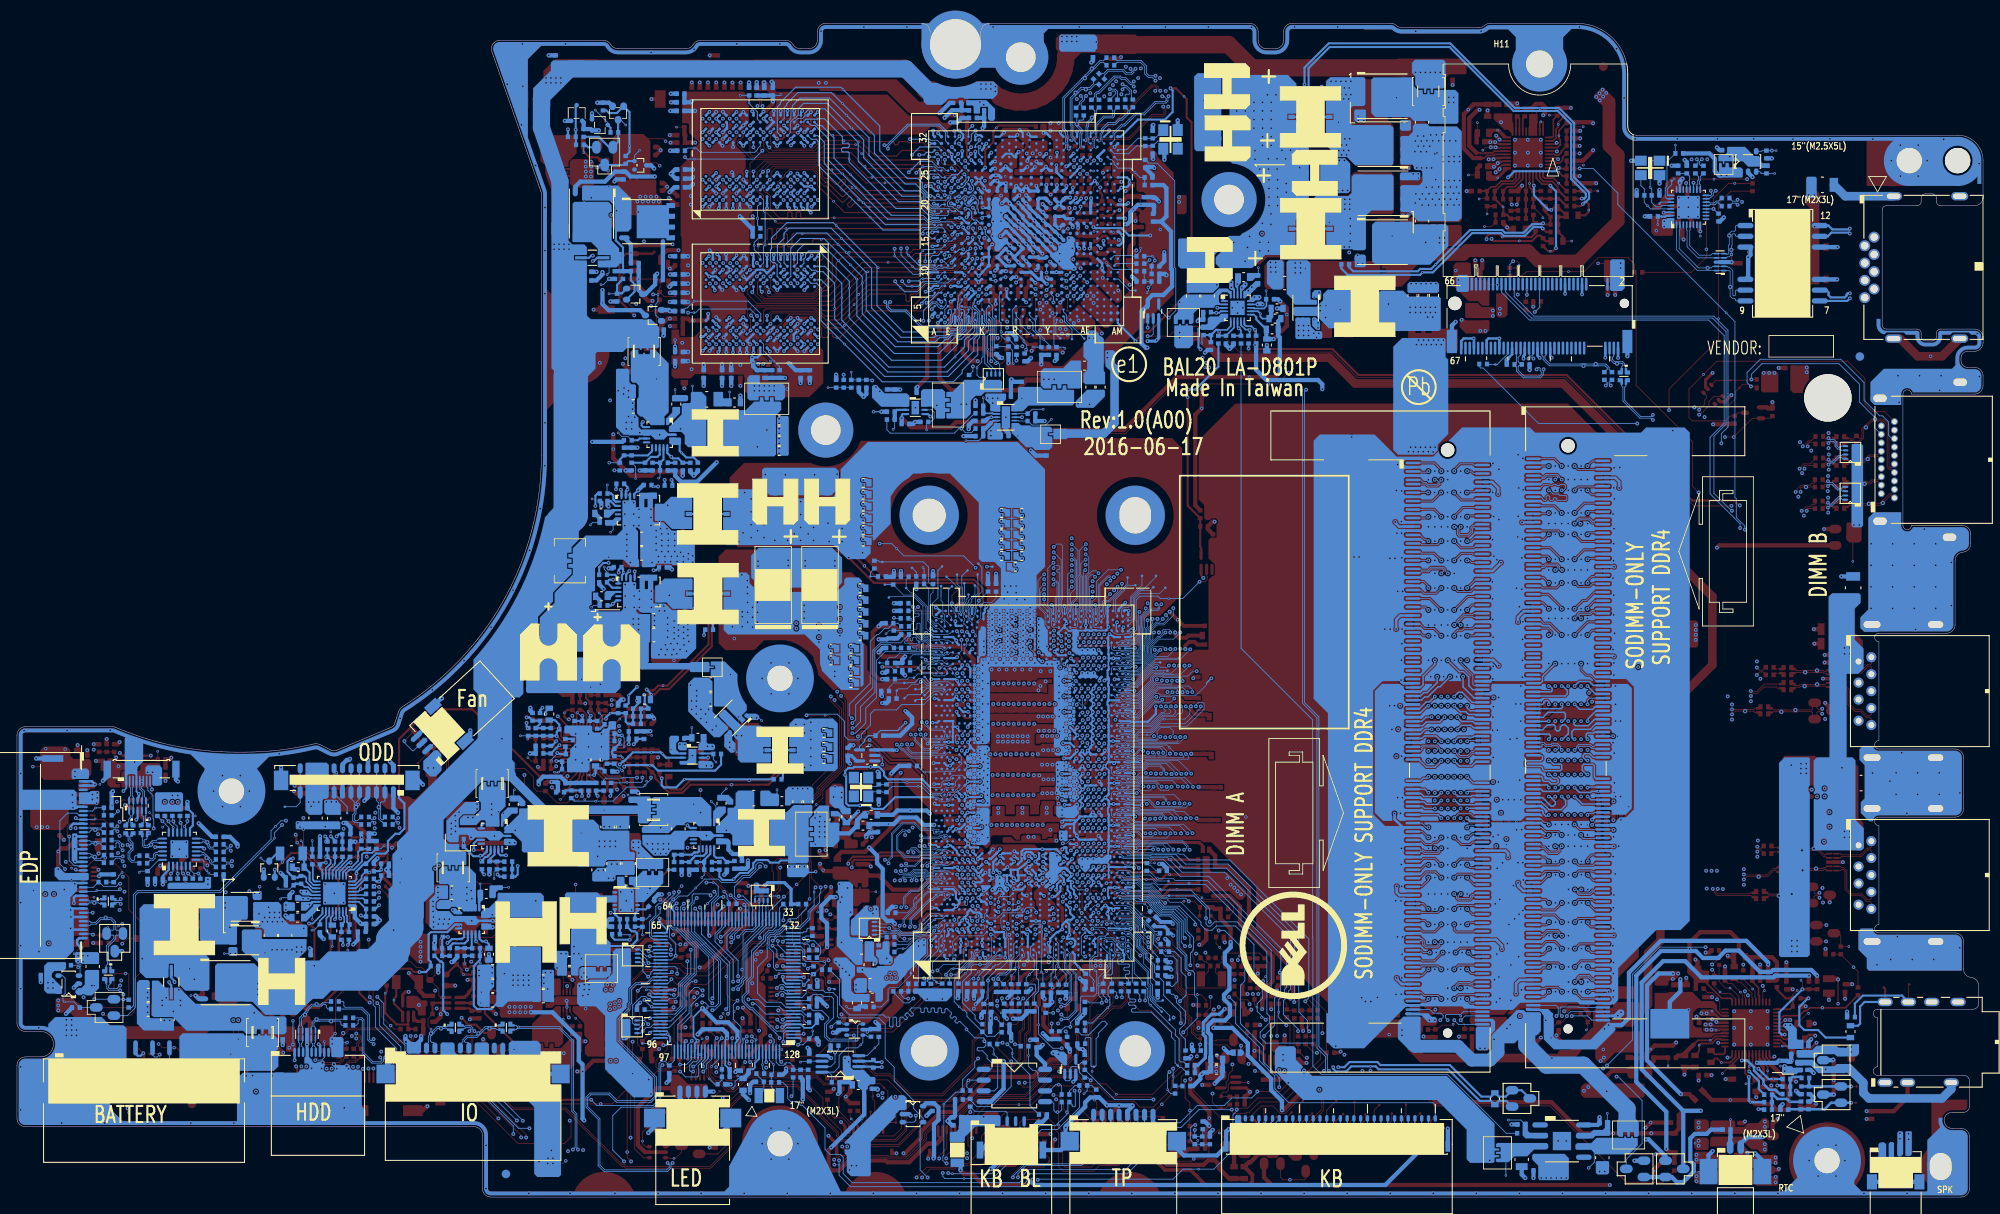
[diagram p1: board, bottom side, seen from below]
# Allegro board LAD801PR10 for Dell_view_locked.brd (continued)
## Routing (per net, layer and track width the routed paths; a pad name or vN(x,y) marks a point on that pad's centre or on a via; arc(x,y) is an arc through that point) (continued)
PEG_GTX_C_HRX_P2: length 137.2
  TOP w0.102: CV5.1 105.85,124.23 105.85,124.78 105.63,125 105.31,125 100.78,125 98.05,127.73 96.71,127.73 96.6,127.83 96.6,128.57 v2(96.7,128.67)
  IN1 w0.089: 123.05,38.54 122.99,38.47 122.96,38.47 121.97,37.49 119.48,37.49 119.29,37.68 119.29,37.86 v2(119.1,38.05)
  IN1 w0.119: 123.05,38.54 124.22,39.71 124.61,39.71 126.55,41.65 127.36,41.65 128.06,42.34 128.06,44.12 127.36,44.82 127.36,48.07 125.91,49.52 125.91,53.6 126.15,53.84 127.46,53.84 127.92,54.31 127.92,66.56 126.84,67.64 126.84,71.76 120.75,77.85 120.75,80.98 120.75,81.39 120.75,81.57 120.74,81.59 116.98,85.34 114.63,85.34 114.63,85.34 113.21,85.34 112.64,85.34 105.13,92.85 99.47,92.85 99.45,92.87 99.44,92.87 93.9,98.41 93.65,98.66 93.65,106.19 93.27,106.57 92.3,107.53 92.3,114.71 92.97,115.38 92.97,121.3 92.66,121.61 92.66,121.97 92.66,126.66 94.1,128.1 95.43,128.1 95.5,128.03 96.26,128.03 96.51,128.28 96.51,128.48 v2(96.7,128.67)
  BOTTOM w0.102: UC1.H16 v2(119.1,38.05)
PEG_GTX_C_HRX_P3: length 144.5
  TOP w0.102: CV7.1 107.4,125.21 107.4,125.84 106.87,126.37 102.65,126.37 98.02,131 97.58,131 97.44,130.87 97.44,130.73 v2(97.63,130.54)
  IN1 w0.089: 122.74,36.58 122.65,36.58 122.64,36.59 121.54,36.59 121.53,36.6 120.35,36.6 119.84,37.11 v2(119.71,37.11)
  IN1 w0.119: v2(97.63,130.54) 97.56,130.47 97.56,128.42 96.53,127.39 95.23,127.39 95.16,127.46 94.37,127.46 93.3,126.39 93.3,121.88 93.61,121.57 93.61,115.11 92.95,114.44 92.95,107.8 93.91,106.83 94.29,106.45 94.29,98.92 99.7,93.51 99.72,93.51 99.74,93.49 105.39,93.49 112.9,85.99 113.48,85.99 113.48,85.98 114.36,85.98 114.36,85.99 123.72,85.99 127.8,81.9 127.8,77.21 126.86,76.26 126.86,73.14 127.68,72.31 127.68,67.81 128.57,66.93 128.57,54.75 128.75,54.57 128.75,52.47 127.24,50.96 127.24,49.1 128.01,48.33 128.01,45.08 128.7,44.39 128.7,41.64 127.01,39.96 126.83,39.96 126.29,39.42 126.29,39.23 125.37,38.31 125.05,38.31 123.32,36.58 122.74,36.58
  BOTTOM w0.102: UC1.G15 119.69,37.11 v2(119.71,37.11)
PEG_GTX_HRX_N0: length 6.7
  BOTTOM w0.076: UV1.AG31 104.46,124.65 104.32,124.51 104.21,124.51 104.1,124.62 104.1,124.88 104.13,124.92 104.13,125.46 104.01,125.58 104.01,125.65 104,125.66 104,125.68
  BOTTOM w0.102: 104,125.68 104,126.02 103.23,126.79 102.39,126.79 101.89,127.28 101.59,127.28 100.85,128.02 100.85,128.26 CV2.2
PEG_GTX_HRX_N1: length 6.9
  BOTTOM w0.076: 104.73,125.54 104.73,125.53 104.72,125.51 104.72,125.46 104.71,125.45 104.71,125.17 105,124.89 105,124.62 104.97,124.59 104.97,123.81 UV1.AF28
  BOTTOM w0.102: CV4.2 102.65,128.23 102.65,127.62 102.72,127.55 103.74,127.55 104.73,126.55 104.73,125.54
PEG_GTX_HRX_N2: length 1.6
  TOP w0.102: v2(104.85,122.32) 105.18,122.32 105.33,122.47 CV6.2
  BOTTOM w0.102: UV1.AF26 v2(104.85,122.32)
PEG_GTX_HRX_N3: length 3.7
  TOP w0.102: v2(107.23,121.54) 107.23,121.65 107.33,121.75 107.59,121.75 108.03,122.19 108.03,123.21 107.79,123.46 107.79,123.64 107.78,123.64 107.78,123.78 CV8.2
  BOTTOM w0.102: UV1.AD26 107.23,121.55 v2(107.23,121.54)
PEG_GTX_HRX_P0: length 6.6
  BOTTOM w0.076: 103.79,125.68 103.79,125.66 103.8,125.65 103.8,125.6 103.83,125.57 103.83,125.51 103.95,125.39 103.95,125 103.91,124.96 103.91,124.57 UV1.AH30
  BOTTOM w0.102: 103.79,125.68 103.79,125.93 103.15,126.58 102.3,126.58 101.8,127.08 101.51,127.08 100.65,127.94 100.65,128.23 CV1.2
PEG_GTX_HRX_P1: length 6.9
  BOTTOM w0.076: UV1.AG29 104.46,123.86 104.58,123.74 104.69,123.74 104.79,123.84 104.79,124.67 104.82,124.7 104.82,124.81 104.53,125.1 104.53,125.53 104.52,125.54
  BOTTOM w0.102: 104.52,125.54 104.52,126.47 103.65,127.34 102.63,127.34 102.44,127.53 102.44,128.22 CV3.2
PEG_GTX_HRX_P2: length 1.5
  TOP w0.102: v2(105.68,122.26) 105.68,122.26 105.68,122.39 CV5.2
  BOTTOM w0.102: v2(105.68,122.26) 105.68,122.26 105.68,122.29 UV1.AF27
PEG_GTX_HRX_P3: length 3.6
  TOP w0.102: v2(107.21,122.34) 107.21,122.07 107.32,121.96 107.51,121.96 107.83,122.28 107.83,123.13 107.58,123.37 107.58,123.55 CV7.2
  BOTTOM w0.102: UV1.AD27 107.21,122.37 v2(107.21,122.34)
PEG_HTX_C_GRX_N0: length 142
  IN1 w0.119: v2(127.73,37.36) 127.49,37.12 127.49,37.06 127.61,36.95 128.53,36.95 128.78,37.19 128.78,37.72 129.92,38.86 129.92,39.64 130.33,40.05 130.33,40.43 130.74,40.84 130.74,41.51 131.18,41.96 131.85,41.96 134.02,44.12 134.02,45.42 135.05,46.46 135.05,48.35 134.76,48.64 134.76,51.05 133.75,52.06 131.67,52.06 130.58,53.15 130.58,54.91 131,55.33 131,63.36 130.74,63.63 130.74,67.89 130.27,68.35 130.27,74.5 129.51,75.26 129.51,82.61 124.43,87.69 114.25,87.69 111.34,90.6 110.76,90.6 110.07,91.3 110.07,91.88 106.74,95.2 100.45,95.2 96.5,99.15 96.5,100.18 96.5,106.67 94.66,108.51 94.66,113.74 95.91,114.99 95.91,118.08 99.65,121.82 99.65,127.4 99.37,127.69 99.37,131.11 99.71,131.45 99.98,131.45 v2(100.17,131.63)
  BOTTOM w0.076: UC1.A17 123.51,38.1 123.51,38.03 123.59,37.96 124.46,37.96 124.82,38.31 126.03,38.31 126.44,37.9 126.59,37.9 126.6,37.9 127.32,37.9 127.49,37.72 127.49,37.6 v2(127.73,37.36)
  BOTTOM w0.102: CV306.2 104.81,129.84 104.81,130.18 104.59,130.4 104.37,130.4 102.51,132.27 101.75,132.27 101.56,132.09 101.1,132.09 100.48,131.47 100.34,131.47 v2(100.17,131.63)
PEG_HTX_C_GRX_N1: length 144.8
  IN1 w0.119: v2(106.42,129.93) 106.22,130.13 106.22,130.73 104.5,132.44 101.4,132.44 100.59,131.64 100.59,130.17 100.1,129.68 100.1,127.86 100.29,127.67 100.29,121.55 99.65,120.91 96.56,117.81 96.56,114.73 95.3,113.47 95.3,108.77 97.14,106.93 97.14,99.92 97.14,99.91 97.14,99.42 100.71,95.85 107.01,95.85 114.52,88.34 124.7,88.34 130.56,82.47 130.56,75.12 130.92,74.76 130.92,68.62 131.38,68.15 131.38,65.26 132.05,64.59 132.05,58.56 135.41,55.2 135.41,49.86 135.7,49.58 135.7,46.19 134.66,45.16 134.66,43.86 130.97,40.17 130.97,39.78 130.56,39.37 130.56,38.59 129.42,37.45 129.42,36.92 128.8,36.3 126.74,36.3 126.14,36.9 126.14,37.14 v2(126.37,37.37)
  BOTTOM w0.076: v2(126.37,37.37) 126.14,37.59 126.14,37.74 125.89,37.98 124.96,37.98 124.6,37.63 123.17,37.63 123.06,37.51 122.95,37.51 122.87,37.59 122.87,37.7 122.94,37.77 122.94,37.84 122.9,37.88 122.62,37.88 122.5,37.77 UC1.C16
  BOTTOM w0.102: v2(106.42,129.93) 106.21,129.73 106.21,129.55 106.59,129.17 106.59,128.92 CV305.2
PEG_HTX_C_GRX_N2: length 136.2
  IN1 w0.119: v2(128.24,38.47) 128.14,38.57 128.14,38.73 128.25,38.84 128.25,39.27 130.31,41.33 130.31,44.73 129.41,45.64 129.41,51.31 130.14,52.05 130.14,55.11 130.57,55.54 130.57,57.96 130.57,62.95 129.85,63.68 129.85,74.32 129.09,75.08 129.09,82.43 124.25,87.27 114.07,87.27 111.16,90.18 110.59,90.18 109.64,91.13 109.64,91.7 106.57,94.78 100.27,94.78 96.07,98.98 96.07,103.1 95.58,103.6 95.58,106.99 94.23,108.33 94.23,113.91 95.49,115.17 95.49,118.26 99.23,121.99 99.23,127.23 98.94,127.51 98.94,131.28 99.27,131.61 99.27,131.83 99.23,131.87 99.23,132.21 99.27,132.25 99.27,132.3 99.46,132.48 100.13,132.48 100.38,132.73 100.38,132.96 v2(100.55,133.13)
  BOTTOM w0.076: UC1.C17 122.33,38.3 122.75,38.42 122.89,38.42 122.92,38.4 123.63,38.4 123.9,38.12 124.39,38.12 124.75,38.48 126.1,38.48 126.51,38.07 126.66,38.07 126.66,38.06 127.83,38.06 v2(128.24,38.47)
  BOTTOM w0.102: 104.27,132.56 103.74,132.56 103.25,133.05 101.39,133.05 101.03,132.7 100.47,132.7 100.37,132.8 100.37,132.95 v2(100.55,133.13)
PEG_HTX_C_GRX_N3: length 133.5
  IN1 w0.119: v2(127.59,39.13) 127.53,39.2 127.53,39.45 129.34,41.27 129.34,44.66 128.65,45.35 128.65,48.6 128.29,48.96 128.29,51.1 129.39,52.21 129.39,54.84 129.21,55.02 129.21,74.05 128.45,74.82 128.45,82.17 123.99,86.63 114.1,86.63 113.17,86.63 105.66,94.14 100.01,94.14 95.43,98.71 95.43,102.66 94.93,103.16 94.93,106.72 93.59,108.07 93.59,114.18 94.25,114.84 94.25,118.51 97.59,121.84 98.16,121.84 98.58,122.26 98.58,126.96 98.3,127.24 98.3,131.55 98.48,131.73 98.05,132.16 97.77,132.16 v2(97.61,132.32)
  BOTTOM w0.076: UC1.A19 123.69,39.7 123.99,39.7 124.21,39.93 125.02,39.93 125.97,38.97 126.88,38.97 126.89,38.97 126.92,38.97 126.93,38.97 127.24,38.97 127.4,39.13 v2(127.59,39.13)
  BOTTOM w0.102: v2(97.61,132.32) 98.38,132.32 98.68,132.63 98.68,133.49 99.3,134.1 102.13,134.1 CV304.2
PEG_HTX_C_GRX_P0: length 142.3
  IN1 w0.119: v2(100.17,131.05) 100,131.23 99.8,131.23 99.59,131.02 99.59,127.78 99.87,127.49 99.87,121.73 96.13,117.99 96.13,114.9 94.87,113.64 94.87,108.6 96.72,106.76 96.72,100.09 96.72,99.24 100.54,95.42 106.83,95.42 110.28,91.97 110.28,91.39 110.85,90.82 111.43,90.82 114.34,87.91 124.52,87.91 129.73,82.7 129.73,75.35 130.49,74.59 130.49,68.44 130.95,67.98 130.95,63.72 131.22,63.45 131.22,55.24 130.79,54.82 130.79,53.25 131.76,52.28 133.84,52.28 134.98,51.14 134.98,48.73 135.27,48.44 135.27,46.37 134.24,45.33 134.24,44.03 131.94,41.74 131.27,41.74 130.96,41.42 130.96,40.75 130.55,40.34 130.55,39.96 130.14,39.55 130.14,38.77 129,37.63 129,37.1 128.63,36.73 127.52,36.73 127.27,36.97 127.27,37.23 v2(127.15,37.36)
  BOTTOM w0.076: UC1.B17 123.06,37.98 123.25,37.79 124.53,37.79 124.89,38.15 125.96,38.15 126.38,37.74 126.52,37.74 126.53,37.73 127.25,37.73 127.33,37.65 127.33,37.55 v2(127.15,37.36)
  BOTTOM w0.102: CV312.2 104.6,129.81 104.6,130.1 104.5,130.2 104.29,130.2 102.42,132.07 101.83,132.07 101.65,131.88 101.19,131.88 100.57,131.26 100.39,131.26 v2(100.17,131.05)
PEG_HTX_C_GRX_P1: length 144.6
  IN1 w0.119: v2(105.8,129.93) 106,130.13 106,130.63 104.41,132.23 101.49,132.23 100.81,131.55 100.81,130.08 100.32,129.59 100.32,127.95 100.51,127.76 100.51,121.46 99.87,120.82 96.77,117.72 96.77,114.64 95.52,113.38 95.52,108.86 97.36,107.02 97.36,99.82 97.36,99.51 100.8,96.06 107.1,96.06 114.61,88.56 124.79,88.56 130.78,82.56 130.78,75.21 131.14,74.85 131.14,68.71 131.6,68.24 131.6,65.35 132.27,64.68 132.27,58.65 135.63,55.29 135.63,49.95 135.92,49.67 135.92,46.1 134.88,45.06 134.88,43.77 131.19,40.08 131.19,39.69 130.78,39.28 130.78,38.5 129.64,37.36 129.64,36.83 128.89,36.08 126.65,36.08 125.93,36.81 125.93,37.23 v2(125.79,37.37)
  BOTTOM w0.076: UC1.D16 122.01,37.58 122.3,37.28 122.81,37.28 122.88,37.35 123.12,37.35 123.24,37.46 124.67,37.46 125.02,37.82 125.82,37.82 125.98,37.67 125.98,37.56 v2(125.79,37.37)
  BOTTOM w0.102: v2(105.8,129.93) 106,129.73 106,129.46 106.38,129.08 106.38,128.84 CV308.2
PEG_HTX_C_GRX_P2: length 136.5
  IN1 w0.119: v2(99.97,133.13) 100.16,132.94 100.16,132.82 100.04,132.7 99.37,132.7 99.05,132.39 99.05,132.34 99.02,132.3 99.02,131.78 99.05,131.74 99.05,131.7 98.73,131.37 98.73,127.42 99.01,127.14 99.01,122.09 95.27,118.35 95.27,118.17 95.27,115.26 94.01,114 94.01,108.24 95.36,106.9 95.36,103.51 95.85,103.01 95.85,98.89 100.18,94.56 106.48,94.56 109.42,91.61 109.42,91.04 110.5,89.96 111.07,89.96 113.98,87.05 124.16,87.05 128.87,82.34 128.87,74.99 129.63,74.23 129.63,63.59 130.36,62.86 130.36,58.05 130.36,55.63 129.93,55.2 129.93,52.14 129.19,51.4 129.19,45.55 130.09,44.64 130.09,41.42 128.04,39.36 128.04,38.93 127.93,38.82 127.93,38.75 127.82,38.64 127.82,38.64 v2(127.65,38.47)
  BOTTOM w0.076: v2(127.65,38.47) 127.41,38.23 126.73,38.23 126.73,38.23 126.58,38.23 126.17,38.64 124.68,38.64 124.33,38.29 123.96,38.29 123.69,38.56 122.99,38.56 122.96,38.59 122.72,38.59 122.31,38.47 122.09,38.48 UC1.D17
  BOTTOM w0.102: v2(99.97,133.13) 100.16,132.95 100.16,132.72 100.38,132.49 101.12,132.49 101.47,132.84 103.16,132.84 103.64,132.37 CV307.2
PEG_HTX_C_GRX_P3: length 133.3
  IN1 w0.119: v2(127.04,39.34) 127.11,39.34 129.12,41.36 129.12,44.57 128.43,45.26 128.43,48.51 128.07,48.87 128.07,51.19 129.18,52.3 129.18,54.75 128.99,54.93 128.99,73.96 128.23,74.73 128.23,82.08 123.9,86.41 114.19,86.41 114.19,86.41 113.65,86.41 113.65,86.41 113.08,86.41 105.57,93.92 99.91,93.92 95.21,98.62 95.21,102.57 94.72,103.07 94.72,106.63 93.37,107.97 93.37,114.27 94.04,114.93 94.04,118.6 97.5,122.06 98.07,122.06 98.37,122.35 98.37,126.87 98.08,127.15 98.08,131.64 98.17,131.73 97.96,131.94 97.82,131.94 v2(97.61,131.74)
  BOTTOM w0.076: UC1.B19 122.99,39.49 123.24,39.75 123.5,39.75 123.62,39.87 123.92,39.87 124.14,40.09 125.09,40.09 126.04,39.14 126.84,39.14 127.04,39.34 v2(127.04,39.34)
  BOTTOM w0.102: CV313.2 102.13,133.9 99.39,133.9 98.89,133.4 98.89,132.54 98.46,132.11 97.98,132.11 97.61,131.74 v2(97.61,131.74)
PEG_HTX_GRX_N0: length 5
  BOTTOM w0.102: UV1.AE31 105.89,124.55 105.79,124.55 105.7,124.64 105.7,124.8 105.81,124.91 105.81,126.31 105.72,126.4 105.72,126.77 v4(105.11,127.38) 104.81,127.68 104.81,128.2 CV306.1
PEG_HTX_GRX_N1: length 4.5
  BOTTOM w0.102: CV305.1 106.89,127.53 v4(106.89,126.61) 106.89,126.31 106.47,125.89 106.47,125.56 106.53,125.5 106.53,124.99 106.58,124.93 106.58,124.5 106.54,124.47 106.54,123.83 UV1.AD28
PEG_HTX_GRX_N2: length 9.6
  BOTTOM w0.102: UV1.AC31 107.53,124.59 107.41,124.59 107.33,124.66 107.33,124.86 107.57,125.09 107.57,126.38 107.67,126.48 107.67,129.68 v4(107.03,130.31) 106.43,130.91 106.13,130.91 106.1,130.94 105.54,130.94 105.52,130.91 105.39,130.91 104.92,131.38 CV309.1
PEG_HTX_GRX_N3: length 13.7
  BOTTOM w0.102: UV1.AB28 108.21,123.77 108.21,124.12 108.15,124.18 108.15,124.44 108.21,124.5 108.21,124.93 108.15,124.99 108.15,125.24 108.21,125.3 108.21,125.65 108.54,125.97 108.54,129.73 106.31,131.96 106.31,131.99 105.91,132.39 105.88,132.39 v4(105.12,133.15) 104.18,134.09 103.75,134.09 CV304.1
PEG_HTX_GRX_P0: length 5
  BOTTOM w0.102: CV312.1 104.6,128.23 104.6,127.6 104.75,127.44 104.75,127.41 105.15,127.02 105.18,127.02 105.5,126.7 105.5,126.33 105.59,126.24 105.59,125 105.48,124.89 105.48,124.44 105.36,124.32 UV1.AF30
PEG_HTX_GRX_P1: length 4.6
  BOTTOM w0.102: UV1.AE29 106.25,123.92 106.34,124 106.34,124.57 106.36,124.59 106.36,124.84 106.31,124.9 106.31,125.43 106.26,125.47 106.26,125.98 106.66,126.38 106.66,126.98 106.56,127.08 106.19,127.08 106.08,127.2 CV308.1
PEG_HTX_GRX_P2: length 9.4
  BOTTOM w0.102: UV1.AD30 107.12,124.58 107.12,124.94 107.35,125.18 107.35,126.45 107.46,126.56 107.46,129.59 107.1,129.95 107.07,129.95 106.67,130.35 106.67,130.38 106.34,130.71 v4(105.82,130.71) 105.3,130.71 104.73,131.28 CV307.1
PEG_HTX_GRX_P3: length 13.8
  BOTTOM w0.102: CV313.1 103.72,133.88 104.1,133.88 104.76,133.22 104.76,133.19 105.15,132.79 105.19,132.79 v4(105.95,132.03) 108.33,129.64 108.33,126.07 108,125.73 108,125.39 107.94,125.33 107.94,124.9 108,124.84 108,124.59 107.99,124.58 107.99,124.57 107.95,124.53 107.95,124.09 107.99,124.05 107.99,123.64 107.9,123.55 107.76,123.55 107.66,123.65 UV1.AC29
PHASE_CHG: length 7.5
  IN3 w0.762: 199.73,35.2 201.57,35.2 202.71,34.05 206.4,34.05 206.65,34.31
  vias: v2(197.57,35.2) v2(198.15,35.2) v2(207.35,34.71) v2(207.35,34.12) v3(206.78,31.83)
PIRQA#: length 3.3
  BOTTOM w0.076: RC187.2 98.85,33.09 99,33.09 v1(99.31,33.39) 100.39,34.47 100.61,34.47 100.8,34.66 UC1.BB11
PLL_ANALOG_IN: length 2.5
  BOTTOM w0.102: TP68.1 109.08,101.56 109.09,101.56 109.36,101.83 109.36,103.11 109.26,103.21 UV1.AA1
PLL_ANALOG_OUT: length 5.3
  BOTTOM w0.102: v1(108.3,100.14) 108.44,100.29 RV83.1 109.59,100.58 109.59,103.76 109.26,104.09 UV1.AA3
PLT_RST#_LAN: length 18.5
  TOP w0.102: v2(34.15,119.69) 32.63,118.17 v3(32.63,111.83) 32.63,110.89 34.41,109.12 RL12.2
  BOTTOM w0.102: UL1.19 v2(34.15,119.69)
PLT_RST_NGFF#: length 5.2
  TOP w0.102: v2(55.42,110.42) 54.95,110.42 54.72,110.19 v1(54.72,109.94) 55.02,109.64 RW4.1
  BOTTOM w0.102: JWLAN1.44 55.8,109.22 55.81,109.23 55.81,110.04 v2(55.42,110.42)
PLT_RST_VGA#: length 142.6
  TOP w0.102: v2(142.79,29.66) 140.88,29.66 140.43,30.11 140.43,31.71 139.69,32.44 139.69,33.9 v3(138.41,35.18) 138.41,39.41 138.49,39.48 138.49,46.14 137.08,47.54 137.08,48.07 134.42,50.73 134.42,58.28 135.15,59.01 v2(135.15,59.64)
  IN3 w0.142: v2(135.15,59.64) 132.47,59.64 132.33,59.79 132.33,63.74 131.02,65.05 131.02,74.66 131.02,74.66 131.02,75.52 131.02,75.52 131.02,83.78 131.02,84.54 126.83,88.73 122.29,88.73 121.45,89.58 121.45,93.73 117.83,97.35 117.83,101.93 115.73,104.03 112.21,104.03 111.72,103.53 109.53,103.53 108.88,104.18 106.11,104.18 105.71,103.78 v2(96.03,103.78)
  BOTTOM w0.102: UV2.4 97.22,104.78 96.22,103.78 v2(96.03,103.78) 95.22,104.59 95.22,109.57 95.35,109.7 95.35,119.93 97.42,122 98.43,122 RV4.1 102.13,122.38 UV1.AL27 ; UE1.24 141.39,27.98 141.5,28.09 142.03,28.09 142.27,28.33 142.27,29.14 v2(142.79,29.66)
PME#: length 2.2
  TOP w0.089: 103.99,35.61 v2(103.65,35.27)
  TOP w0.102: TP12.1 104.53,36.15 103.99,35.61
  BOTTOM w0.076: UC1.AU11 103.65,35.17 v2(103.65,35.27)
POK: length 167.6
  TOP w0.102: UC5.2 84.16,15.39 84.03,15.26 CC10.1 RC102.1 85.76,14.77 v2(85.87,14.88)
  TOP w0.254: v2(175.22,38.06) 175.22,39.14 177.02,40.94 v2(178.02,40.94) ; v2(184.42,26.55) 185.05,26.55 185.44,26.94 187.54,26.94 188.3,26.18 PR13.1 ; v2(155.03,38.62) v3(157.23,36.42) 158.07,35.58 158.07,31.91 v2(159.62,30.36)
  IN1 w0.254: v2(178.02,40.94) 178.3,40.66 182.65,40.66 184.17,39.14 184.17,31.39 183.28,30.5 183.28,27.77 184.42,26.62 v2(184.42,26.55)
  IN2 w0.127: v2(85.87,14.88) 86.67,14.08 90.99,14.08 91.27,13.8 92.16,13.8 92.92,13.04 95.5,13.04 95.85,12.7 101.43,12.7 104.35,15.61 104.35,15.61 104.49,15.75 112.76,15.75 114.04,17.03 118.6,17.03 122.31,20.74 129.2,20.74 130.43,21.97 134.81,21.97 134.94,21.84 136.87,21.84 140.5,25.47 140.5,26.44 140.88,26.82 142.51,26.82 142.7,27.01 142.7,27.41 143.04,27.75 143.38,27.75 143.55,27.58 145.08,27.58 145.97,28.47 153,28.47 154.45,29.93 156.86,29.93 157.75,30.82 159.17,30.82 v2(159.62,30.36)
  IN2 w0.254: v2(155.03,38.62) 155.21,38.44 159.17,38.44 160.51,39.77 163.24,39.77 164.46,38.56 173.25,38.56 174.17,39.48 177.27,39.48 178.02,40.23 v2(178.02,40.94)
  BOTTOM w0.254: v2(175.22,38.06) 174.96,37.81 PR107.2 ; PU100.9 177.6,42.15 178.02,41.73 178.02,41.07 178.02,41.07 v2(178.02,40.94) ; v2(159.62,30.36) 161.39,30.36 161.7,30.67 PR501.1 ; PU102.9 180.24,32.15 181.13,31.26 183.09,31.26 183.34,31.01 183.34,28 183.1,27.75 PR113.2 183.1,27.12 183.67,26.55 v2(184.42,26.55) ; PR301.1 v2(155.03,38.62)
POWER_SW#_MB: length 176.8
  TOP w0.102: v2(190.42,30.38) 190.37,30.33 190.37,23.67 v2(190.29,23.59) ; JPWR1.3 159.93,109.31 160.56,108.68 160.56,106.2 158.9,104.54 EC2901.1 156.5,103 ZT2.1 157.29,102.21 ED2901.1 157.29,100.75 157.18,100.64 SW1.1 158.99,100.13 v2(160.14,98.98)
  IN1 w0.119: v2(140.55,11.89) 140.55,11.6 141.6,10.55 144.41,10.55 144.65,10.31 145.26,10.31 146.03,9.54 160.46,9.54 161.71,8.28 171.29,8.28 v2(171.46,8.11)
  IN3 w0.142: v2(190.42,30.38) 189.79,31 188.39,31 185.43,33.97 185.43,34.24 185.43,52.57 172.35,65.65 172.35,70.02 169.83,72.54 169.83,75.97 167.84,77.96 167.84,100.55 165.88,102.51 163.68,102.51 v2(160.14,98.98)
  BOTTOM w0.102: v2(140.55,11.89) 140.35,12.08 RE43.2 ; v2(190.29,23.59) 189.89,23.18 189.89,22.68 189.61,22.4 189.61,20.03 187.1,17.52 187.1,17.09 187.1,16.69 186.13,15.72 186.13,15.43 184.23,13.52 178.16,13.52 172.75,8.11 v2(171.46,8.11)
POWER_SW_IN#: length 5.9
  BOTTOM w0.102: CE33.1 RE41.2 RE43.1 140.35,15.48 140.71,15.84 141.17,15.84 v1(141.31,15.7) 141.46,15.55 142,15.55 142.36,15.91 UE1.127
PROG: length 6.6
  BOTTOM w0.102: v1(188.59,41.47) 188.96,41.1 PR753.2
  BOTTOM w0.203: PR753.2 189.99,40.61 191,40.61 191.21,40.41 191.21,39.6 192.17,38.63 192.68,38.63 193.07,38.24 PU703.9
PROH: length 9.5
  TOP w0.254: v2(191.34,36.35) 191.34,37.28 v3(190.33,38.3) 189.13,39.5 PQ720.2 188.54,39.5 188.2,39.85 188.2,40.51 188.55,40.86 PR781.2
  BOTTOM w0.203: PU703.5 191.65,36.04 v2(191.34,36.35) 191.04,36.35 PR777.2
PROJECT_ID1: length 10
  BOTTOM w0.076: UC1.AY8 102.17,33.17 100.31,33.17 99.18,32.03 99.18,31.4 98.91,31.13 98.3,31.13 98.02,30.85 98.02,29.04
  BOTTOM w0.102: 98.02,29.04 v1(97.9,28.91) 97.33,28.34 RC51.2 RC52.1
PROJECT_ID2: length 19.6
  TOP w0.102: RC53.2 RC54.1 86.53,28.17 86.88,28.52 86.99,28.52 87,28.53 87.61,28.53 v1(87.69,28.45) 87.89,28.25 v2(87.89,27.96)
  IN3 w0.142: v2(98.45,30.66) 97.52,29.73 97.05,29.73 96.29,28.97 95.8,28.97 94.97,28.14 91.37,28.14 90.67,27.44 88.42,27.44 v2(87.89,27.96)
  BOTTOM w0.076: UC1.BA8 100.24,32.86 99.34,31.97 99.34,31.33 98.68,30.66 v2(98.45,30.66)
PS_0: length 4
  TOP w0.102: v1(107.12,117.28) v2(107.12,116.72) 107.12,116.61 CV29.1 RV9.1 104.82,116.09 RV8.2
  BOTTOM w0.102: UV1.AC19 107.66,116.18 v2(107.12,116.72)
PS_1: length 4.7
  TOP w0.102: v2(106.45,116.87) 106.24,117.08 CV28.1 105.27,116.56 103.97,116.56 RV12.1 103.89,116.61 RV11.2
  BOTTOM w0.102: UV1.AD19 106.45,116.53 v2(106.45,116.87)
PS_2: length 5
  TOP w0.102: RV28.2 101.94,114.83 RV13.1 CV11.1 104.78,113.95 v1(104.86,113.95) 105.29,113.95 105.72,114.38 v2(105.72,114.46)
  BOTTOM w0.102: UV1.AE17 105.72,114.58 v2(105.72,114.46)
PS_3: length 6.6
  TOP w0.102: CV15.1 RV16.1 103.11,119.94 RV15.2 103.51,120.49 v1(104.46,119.54) 104.94,119.07 104.94,118.76 105.79,117.9 v2(105.79,117.87)
  BOTTOM w0.102: UV1.AE20 105.79,117.59 v2(105.79,117.87)
PS_ID: length 132
  TOP w0.102: v2(135.47,58.65) 135.46,58.65 135.46,58.43 134.65,57.61 134.65,50.82 137.31,48.17 137.31,47.64 138.75,46.19 138.75,39.43 138.61,39.29 138.61,38.21 v3(139.93,36.89) 141.38,35.45 v2(141.43,35.45)
  IN1 w0.119: v2(165.99,125.94) 165.63,126.31 154.88,126.31 151.66,123.1 151.66,121.63 151.66,114.6 153.43,112.83 153.43,101.38 149.29,97.24 149.09,97.24 138.58,97.24 132.92,91.59 132.92,85.99 133.78,85.13 133.78,74.97 135.55,73.2 135.55,65.73 134.96,65.14 134.96,60.85 135.56,60.25 135.56,59.47 135.47,59.37 v2(135.47,58.65)
  BOTTOM w0.102: v2(141.43,35.45) 143.16,33.72 UE1.36
  BOTTOM w0.254: PD5.1 165.99,128.72 v2(165.99,125.94) PR3.1 165.96,125.08 PR4.2
PSID: length 3.4
  TOP w0.254: PJPDC1.3 165.13,123.45 164.37,122.69 ZT103.1 163.4,122.69 PL2.2
PSID-1: length 9.2
  BOTTOM w0.254: PR9.2 162.38,128.22 162.07,127.91 161.14,127.91 PQ5.2 159.65,128.02 v1(159.65,124.05) 159.65,123.3 PR6.1
PSID-2: length 8.6
  BOTTOM w0.102: v1(160.09,126.5) 160.71,127.11 PQ5.1
  BOTTOM w0.254: PR8.2 163.28,125.11 162.05,123.87 PQ6.2 160.98,124.51 PR11.1 160.99,125.64 PQ5.1
PSID-3: length 2.6
  BOTTOM w0.102: v1(165.04,123.23) PR4.1
  BOTTOM w0.254: PQ6.3 164.54,123.87 164.83,124.17 PR4.1
PTP_DIS#: length 95.3
  TOP w0.102: RE22.1 155.58,19.66 v3(155.14,19.22) 154.66,18.74 RE26.1 155.35,15.58 v2(155.77,15.58) ; v2(125.79,2.31) 124.59,3.51 121.37,3.51 120.96,3.93 119.75,3.93 118.13,5.55 118.13,7.2 115.28,10.04 110.96,10.04 109.53,8.61 109.53,8.03 109.04,7.54 109.04,3.59 108.5,3.05 104.91,3.05 104.23,3.73 102,3.73 100.07,5.67 D6.1
  IN3 w0.142: v2(125.79,2.31) 126.25,1.85 157.93,1.85 v2(160.29,4.21)
  BOTTOM w0.102: v2(160.29,4.21) 161.63,5.54 161.63,9.61 160.63,10.6 156.79,10.6 155.97,11.42 155.97,15.37 v2(155.77,15.58)
PTP_DIS#_R: length 2.9
  TOP w0.102: v1(157.83,21.11) v2(157.24,21.11) 156.61,20.47 RE22.2
  BOTTOM w0.102: v2(157.24,21.11) 157.17,21.18 UE1.90
PWM1_GT: length 40.2
  TOP w0.203: PU602.12 165.88,56.97 PR680.1
  TOP w0.254: v2(166.8,56.37) 167.02,56.37 167.33,56.68 v1(167.33,57.14) 166.99,57.48 PR680.1
  IN3 w0.254: v2(166.8,56.37) 166.87,56.45 166.87,56.95 167.15,57.23 167.5,57.23 170.07,59.8 170.07,66.17 162.98,73.26 162.98,77.74 164.17,78.92 164.17,82.57 163.76,82.98 160.93,82.98 160.67,83.23 v2(160.67,83.46)
  BOTTOM w0.254: v2(160.67,83.46) 160.59,83.38 PU605.13
PWM_IA: length 32.7
  TOP w0.102: v2(160.93,73.69) v1(160.32,73.69)
  TOP w0.203: v2(160.81,55) 160.99,55 161.47,54.52 PU602.22
  IN3 w0.254: v2(160.93,73.69) 161.09,73.53 161.09,72.65 162.44,71.3 163.22,71.3 167.56,66.96 167.56,65.8 168.93,64.43 168.93,60.29 167.02,58.37 165.75,58.37 165.12,57.74 162.37,57.74 160.41,55.78 160.41,55.33 160.74,55 v2(160.81,55)
  BOTTOM w0.254: PU603.13 160.54,73.39 160.41,73.53 160.41,74.13 PR662.1 160.62,74.32 160.93,74.01 v2(160.93,73.69)
PWM_VSA: length 9.6
  TOP w0.203: PU602.30 161.08,51.32 160.8,51.04 v2(160.8,51.04)
  BOTTOM w0.254: PU606.3 155.35,51.85 155.97,52.47 v1(157.07,52.47) 159.25,52.47 160.31,51.41 160.42,51.41 160.8,51.04 v2(160.8,51.04)
PWR_LED_R#: length 8.3
  TOP w0.102: Q15.2 174.07,17.27 173.93,17.42 v1(173.25,17.42) 172.93,17.1 172.93,15.62 173.26,15.28 174.76,15.28 175.04,15 175.04,13.85 Q16.1
PWRGD_VGA: length 12.7
  TOP w0.102: PR1119.2 48.64,121.81 47.18,121.81 v1(47.12,121.76)
  TOP w0.203: v2(50.04,121.44) 50.22,121.44 50.61,121.84 PU1100.9 ; v2(56.03,120.33) 55.69,120.33 55.49,120.53 PU1100.20
  TOP w0.254: PR1119.2 PR1122.1 49.94,121.35 v2(50.04,121.44)
  BOTTOM w0.254: v2(50.04,121.44) 50.43,121.05 55.27,121.05 55.99,120.33 v2(56.03,120.33)
PX_EN: length 1.2
  TOP w0.102: TP73.1 107.94,113.85 v2(107.94,114.28)
  BOTTOM w0.102: UV1.AB16 108.1,114.28 v2(107.94,114.28)
RESET_OUT#: length 83.9
  TOP w0.102: v2(154.4,35.96) 154.4,35.24 v3(154.5,35.13) ; v2(154.2,28.47) 153.99,28.26 RE16.1 153.36,28.47 CE31.1
  IN1 w0.119: v2(154.4,35.96) 154.39,35.96 153.94,35.52 153.63,35.52 152.71,36.44 150,36.44 149.71,36.73 146.31,36.73 145.62,36.04 143.31,36.04 142.62,36.73 140.39,36.73 136.36,32.7 135.8,32.7 131.13,28.02 130.53,28.02 129.55,27.05 128.43,27.05 127.6,26.22 124.14,26.22 123.64,25.72 120.72,25.72 119.65,26.79 117.54,26.79 116.68,27.65 114.16,27.65 113.95,27.65 113.28,26.98 112.94,26.98 110.88,29.04 108.01,29.04 106.77,30.28 105.46,30.28 105.33,30.41 104.37,30.41 101.37,33.41 101.37,36.72 99.57,38.53 v2(99.57,38.84)
  BOTTOM w0.076: v2(99.57,38.84) 100.04,39.31 100.49,39.31 100.64,39.17 101,39.17 101.02,39.19 101.19,39.19 UC1.BA20
  BOTTOM w0.102: UE1.73 154.68,27.98 v2(154.2,28.47) 154.2,29.93 154.92,30.66 154.92,31.62 155.23,31.93 155.23,34.87 154.39,35.71 154.39,35.96 v2(154.4,35.96)
RING2: length 5.6
  TOP w0.102: v2(23.39,15.45) v1(23.92,15.45)
  IN3 w1.016: 24.28,21.04 24.4,20.91 24.4,18.56 23.64,17.8 23.64,16.34
  vias: v2(22.74,20.89) v2(23.32,20.89) v2(23.39,14.86)
RING2_R: length 17.2
  TOP w0.102: v2(18.56,15.07) ZT23.1
  BOTTOM w1.016: DA5.2 15.82,15.19 14.2,13.57 14.14,13.48 14.12,13.46 14.12,12.29 13.47,11.64 4.85,11.64 3.75,12.73 JHP1.4
RTC_DET#: length 111.6
  IN3 w0.142: v2(119.07,25.77) 119.31,25.77 119.45,25.63 119.45,21.85 116.57,18.97 116.57,14.51 110.95,8.9 109.66,8.9 107.54,6.77 91.14,6.77 90.1,5.74 62.48,5.74 62.08,6.14 55.98,6.14 55.67,6.45 51.91,6.45 48.85,9.52 47.96,9.52 43.26,14.21 v2(43.23,14.21)
  BOTTOM w0.076: UC1.P1 116.29,28.54 117.81,27.01 118.04,27.01 v1(118.46,26.59) 119.07,25.98 v2(119.07,25.77) 119.32,25.77 119.81,25.29 RC46.1
  BOTTOM w0.102: Q1.1 42.08,4.44 40.21,6.31 40.21,11.39 43.03,14.21 v2(43.23,14.21)
RTC_PWR: length 17.1
  TOP w0.508: R2.1 38.82,3.25 v1(38.82,3.05) v2(38.82,2.36)
  BOTTOM w0.508: R1.1 32.09,7.96 32.59,7.45 33.99,7.45 34.52,6.92 34.52,4.26 34.12,3.85 34.12,3.01 35.38,1.75 36.1,1.75 36.71,2.36 D1.3 v2(38.82,2.36) Q1.2
RTCRST_ON: length 71.8
  TOP w0.102: QC2.2 87.45,15.91 87.24,15.71 v2(86.63,15.71) RC164.1 ; v2(142.76,30.25) 142.76,30.35 v1(142.46,30.66)
  IN2 w0.127: v2(86.63,15.71) 87.12,15.23 88.71,15.23 89.38,15.89 94.41,15.89 95.45,16.93 95.45,18.1 97.18,19.83 97.18,19.83 98.42,21.07 101.58,21.07 104.24,18.41 108.76,18.41 109.3,17.87 110.06,17.87 110.7,17.23 112.46,17.23 113.43,18.21 113.43,18.29 114.38,19.24 118.96,19.24 121.67,21.96 126.43,21.96 127.77,23.31 132.54,23.31 138.94,29.7 142.23,29.7 142.76,30.23 v2(142.76,30.25)
  BOTTOM w0.102: UE1.31 142.17,30.78 142.7,30.25 v2(142.76,30.25)
RUNPWROK: length 3.5
  BOTTOM w0.102: v3(148.48,36.04) 148.15,35.71 148.15,35.22 147.94,35.01 RE42.1 147.94,33.81 147.96,33.78 UE1.48
SA_SNUB: length 0.8
  TOP w0.102: 146.78,55.82 v1(146.78,56.65)
SA_SW: length 1.8
  IN3 w1.016: 148.04,54.95 148.42,54.95 149.43,53.94
  vias: v1(146.96,52.53) v2(146.44,54.44) v2(147.02,54.44) v2(149.88,53.17) v2(150.46,53.17)
SATA3_CRX_HDDTX_N0: length 101.8
  IN3 w0.089: 121.5,39.11 121.5,39.14 121.18,39.47 120.78,39.47 120.4,39.85 v2(120.36,39.85)
  IN3 w0.142: v2(189.05,16.47) 188.93,16.35 188.93,14.72 188.08,13.86 180.71,13.86 178.75,11.9 164,11.9 163.47,11.38 156.05,11.38 152.86,14.56 152.86,15.7 150.93,17.64 150.93,19.25 150.03,20.15 148.47,20.15 147.31,21.3 147.31,22.83 147.98,23.49 147.98,25.41 147.83,25.56 147.83,26.1 146.16,27.76 146.16,28.37 144.69,29.84 143.93,29.84 142.76,31.01 141.49,31.01 140.13,32.36 137.99,32.36 137.17,31.54 132.07,31.54 131.35,32.26 131.17,32.26 128.69,34.73 126.87,34.73 125.56,33.42 123.72,33.42 121.48,35.66 121.48,38.68 121.5,38.7 121.5,39.11
  BOTTOM w0.102: CS3.1 191.2,21.15 190.96,20.91 190.96,17.02 189.96,16.01 188.98,16.01 188.87,16.12 188.87,16.29 v2(189.05,16.47)
  BOTTOM w0.127: UC1.F20 120.36,39.68 v2(120.36,39.85)
SATA3_CRX_HDDTX_P0: length 101.6
  IN3 w0.089: v2(121.19,39.9) 121.17,39.89 121.17,39.73 121.74,39.16
  IN3 w0.142: 121.74,39.16 121.74,38.82 121.76,38.8 121.76,38.59 121.74,38.57 121.74,35.76 123.82,33.68 125.45,33.68 126.76,34.99 128.8,34.99 131.27,32.51 131.46,32.51 132.17,31.79 137.06,31.79 137.89,32.62 140.24,32.62 141.59,31.26 142.86,31.26 144.03,30.09 144.8,30.09 146.41,28.47 146.41,27.87 148.08,26.2 148.08,25.66 148.23,25.51 148.23,23.39 147.56,22.72 147.56,21.41 148.57,20.4 150.14,20.4 151.18,19.36 151.18,17.75 153.12,15.81 153.12,14.66 156.15,11.63 163.37,11.63 163.89,12.15 178.65,12.15 180.61,14.11 187.97,14.11 188.68,14.82 188.68,16.27 188.48,16.47 v2(188.47,16.47)
  BOTTOM w0.102: CS4.1 191.89,20.26 191.66,20.48 191.66,20.84 191.56,20.94 191.29,20.94 191.17,20.82 191.17,16.94 190.04,15.81 188.89,15.81 188.66,16.04 188.66,16.28 v2(188.47,16.47)
  BOTTOM w0.127: UC1.E20 121.07,39.84 121.13,39.85 121.17,39.9 v2(121.19,39.9)
SATA3_CTX_HDDRX_N0: length 95.5
  IN3 w0.142: v2(126.16,40.67) 126.27,40.57 126.27,40.55 126.39,40.43 126.39,40.19 126.26,40.06 126.26,38.27 126.74,37.79 128.6,37.79 130.55,35.84 132.17,35.84 133.96,34.06 135.01,34.06 135.88,34.93 138.42,34.93 138.77,34.58 142.15,34.58 144.26,32.47 145.03,32.47 145.67,31.83 147.07,31.83 148.2,30.71 148.2,29.84 149.3,28.74 149.3,27.98 149.92,27.35 149.92,26.43 151.13,25.22 151.13,25.22 151.57,24.79 152.03,24.79 152.55,24.27 152.55,22.22 154.96,19.8 154.96,17.44 155.81,16.59 156.42,16.59 157.19,15.82 157.56,15.82 159.9,13.47 162.6,13.47 163.19,14.06 177.55,14.06 178.58,15.09 178.58,16.04 179.03,16.49 186.28,16.49 187.85,18.05 v2(189.83,18.05)
  BOTTOM w0.076: UC1.B21 123.28,40.41 123.33,40.37 123.72,40.37 124.01,40.66 125.52,40.66 125.93,41.06 126.31,41.06 126.4,40.98 126.4,40.91 v2(126.16,40.67)
  BOTTOM w0.102: v2(189.83,18.05) 190.03,18.26 190.24,18.26 190.52,18.54 190.52,21.42 191.29,22.19 CS2.1
SATA3_CTX_HDDRX_P0: length 95.4
  IN3 w0.142: v2(126.8,40.71) 126.78,40.71 126.64,40.56 126.64,40.09 126.51,39.96 126.51,38.37 126.84,38.05 128.7,38.05 130.66,36.09 132.28,36.09 134.06,34.31 134.91,34.31 135.78,35.19 138.53,35.19 138.88,34.83 142.26,34.83 144.37,32.72 145.13,32.72 145.77,32.08 147.18,32.08 148.45,30.81 148.45,29.95 149.55,28.85 149.55,28.08 150.18,27.46 150.18,26.53 151.23,25.47 151.24,25.47 151.67,25.04 152.14,25.04 152.8,24.38 152.8,22.32 155.21,19.91 155.21,17.55 155.91,16.85 156.52,16.85 157.3,16.07 157.66,16.07 160.01,13.72 162.5,13.72 163.09,14.31 177.44,14.31 178.33,15.19 178.33,16.14 178.93,16.74 186.18,16.74 187.74,18.3 189.48,18.3 189.81,18.64 v2(189.83,18.64)
  BOTTOM w0.076: UC1.A21 123.54,40.54 123.63,40.53 123.65,40.53 123.94,40.82 125.45,40.82 125.86,41.23 126.38,41.23 126.56,41.05 126.56,40.91 126.77,40.71 v2(126.8,40.71)
  BOTTOM w0.102: CS1.1 193.45,23.08 193.35,22.98 193.35,22.54 193.2,22.39 191.2,22.39 190.31,21.5 190.31,18.63 190.15,18.46 190.01,18.46 v2(189.83,18.64)
SATA_CRX_ODDTX_N1: length 119.4
  IN1 w0.119: v2(189.72,44.73) 189.54,44.55 189.28,44.55 189.03,44.3 189.03,40.56 187.68,39.2 187.68,25.47 186.8,24.6 186.8,18.89 185.8,17.89 182.17,17.89 181.03,16.75 181.03,16.2 v2(180.86,16.02)
  IN3 w0.142: v2(180.86,16.02) 181.06,15.82 181.06,15.55 178.42,12.91 163.67,12.91 163.08,12.33 159.43,12.33 157.58,14.18 155.09,14.18 154.58,14.69 154.58,15.77 153.67,16.68 153.67,18.8 151.28,21.18 150.05,21.18 149.24,21.99 149.24,25.49 148.78,25.95 148.78,26.84 147.98,27.64 147.98,27.9 144.55,31.33 143.79,31.33 141.68,33.44 137.72,33.44 136.77,32.49 132.62,32.49 132.31,32.8 132.31,33.98 131.59,34.7 130.08,34.7 129.09,35.68 124.44,35.68 123.15,36.97 123.15,39.64 121.3,41.49 120.26,41.49 119.97,41.2 119.97,40.93 v2(119.81,40.77)
  BOTTOM w0.102: CS10.2 190.04,44.51 189.94,44.51 v2(189.72,44.73)
  BOTTOM w0.127: UC1.G21 119.81,40.7 v2(119.81,40.77)
SATA_CRX_ODDTX_P1: length 119.1
  IN1 w0.119: v2(181.44,16.02) 181.25,16.21 181.25,16.66 182.27,17.67 185.89,17.67 187.02,18.8 187.02,24.51 187.89,25.38 187.89,39.11 189.25,40.47 189.25,44.21 189.37,44.33 189.54,44.33 v2(189.72,44.15)
  IN3 w0.142: v2(120.42,40.82) 120.34,40.82 120.2,40.96 120.2,41.08 120.36,41.24 121.2,41.24 122.9,39.54 122.9,36.87 124.33,35.43 128.98,35.43 129.97,34.45 131.49,34.45 132.06,33.87 132.06,32.7 132.52,32.24 136.88,32.24 137.82,33.19 141.57,33.19 143.68,31.08 144.45,31.08 147.72,27.8 147.72,27.54 148.53,26.73 148.53,25.85 148.99,25.38 148.99,21.89 149.95,20.93 151.18,20.93 153.42,18.69 153.42,16.57 154.33,15.66 154.33,14.58 154.99,13.92 157.47,13.92 159.32,12.07 163.18,12.07 163.77,12.66 178.53,12.66 181.31,15.45 181.31,15.89 v2(181.44,16.02)
  BOTTOM w0.102: CS9.2 190.04,44.31 189.88,44.31 v2(189.72,44.15)
  BOTTOM w0.127: UC1.F21 120.09,40.42 120.42,40.82 v2(120.42,40.82)
SATA_CTX_ODDRX_N1: length 117.2
  IN1 w0.119: v2(186.93,44.15) 186.75,44.33 186.6,44.33 186.33,44.06 186.33,43.44 187.21,42.55 187.99,42.55 188.5,42.04 188.5,40.63 187.25,39.38 187.25,25.65 186.37,24.77 186.37,22.45 182.61,18.69 181.76,18.69 179.65,16.58 v2(179.65,15.89)
  IN3 w0.142: v2(179.65,15.89) 179.65,14.99 178.02,13.36 163.48,13.36 162.89,12.77 159.61,12.77 157.7,14.69 155.6,14.69 155.09,15.19 155.09,15.89 154.26,16.72 154.26,19.51 152.15,21.63 150.67,21.63 150.31,21.99 150.31,25.05 149.23,26.14 149.23,27.06 148.6,27.69 148.6,27.91 144.74,31.77 143.97,31.77 141.86,33.88 138.48,33.88 138.13,34.24 136.17,34.24 134.88,32.94 133.12,32.94 132.83,33.23 132.83,34.2 131.88,35.14 130.26,35.14 129.2,36.21 125.28,36.21 124.48,37 124.48,37.72 125.56,38.8 125.56,40 124.84,40.72 v2(124.84,41.43)
  BOTTOM w0.076: v2(124.84,41.43) 124.61,41.19 123.61,41.19 123.36,41.06 123.35,41.06 123.22,41.02 123.05,41.02 122.99,41.04 122.93,41.06 122.75,41.06 122.65,41.02 122.57,41 122.46,41 122.06,40.94 UC1.D21
  BOTTOM w0.102: v2(186.93,44.15) 187.09,44.31 187.24,44.31 CS11.2
SATA_CTX_ODDRX_P1: length 117.2
  IN1 w0.119: v2(186.93,44.73) 186.75,44.55 186.51,44.55 186.11,44.15 186.11,43.35 187.12,42.33 187.9,42.33 188.28,41.95 188.28,40.72 187.03,39.47 187.03,25.74 186.16,24.86 186.16,22.54 182.52,18.91 181.67,18.91 179.43,16.67 179.43,16.27 v2(179.07,15.91)
  IN3 w0.142: v2(125.43,41.43) 125.43,41.41 125.1,41.07 125.1,40.82 125.81,40.1 125.81,38.7 124.73,37.62 124.73,37.11 125.38,36.46 129.3,36.46 130.37,35.4 131.99,35.4 133.08,34.3 133.08,33.33 133.23,33.19 134.77,33.19 136.07,34.49 138.24,34.49 138.59,34.14 141.97,34.14 144.08,32.03 144.84,32.03 148.85,28.01 148.85,27.79 149.48,27.17 149.48,26.24 150.56,25.16 150.56,22.09 150.77,21.88 152.25,21.88 154.51,19.62 154.51,16.82 155.34,15.99 155.34,15.3 155.7,14.94 157.8,14.94 159.72,13.02 162.79,13.02 163.38,13.61 177.91,13.61 179.4,15.1 179.4,15.54 179.07,15.87 v2(179.07,15.91)
  BOTTOM w0.076: UC1.C21 122.31,40.75 122.52,40.83 122.6,40.83 122.7,40.86 122.77,40.89 122.91,40.89 123.1,40.83 123.25,40.83 123.65,41.03 125.03,41.03 v2(125.43,41.43)
  BOTTOM w0.102: v2(186.93,44.73) 187.15,44.51 187.24,44.51 CS12.2
SATA_LED#: length 69.9
  TOP w0.102: v2(122.32,26.23) 122.32,25.69 123.29,24.72 123.85,24.72 124.95,23.62 124.95,23.11 128.58,19.48 v3(131.59,19.48) 133.47,19.48 133.81,19.13 133.81,16.66 130.99,13.83 129.19,13.83 127.57,12.2 127.57,8.11 128.47,7.21 134.38,7.21 134.64,7.47 134.64,7.83 136.84,10.02 136.84,11.66 138.84,13.67 145.48,13.67 148.23,10.92 148.23,6.11 149.25,5.09 Q5.3
  BOTTOM w0.102: UC1.H1 119.3,28.28 120.62,26.97 121.69,26.97 122.32,26.33 v2(122.32,26.23) 121.91,25.83 121.91,25.62 121.89,25.6 RC69.1
SATA_LED_EN: length 35.2
  TOP w0.102: Q5.2 150.47,7.02 150.22,6.77 R23.2 149.5,8.72 148.67,9.54 148.67,11.69 v2(148.66,11.7) ; v2(141.56,30.12) 141.56,30.61 141.93,30.99 142.89,30.99 143.23,30.64 143.23,30.15 143.84,29.54 144.89,29.54 146.39,28.04 v3(146.39,26.85) 146.39,23.2 144.74,21.54 144.74,19.87 144.51,19.64 v2(144.36,19.64)
  IN3 w0.142: v2(144.36,19.64) 144.55,19.45 144.55,17.41 145.17,16.79 146,16.79 148.66,14.13 v2(148.66,11.7)
  BOTTOM w0.102: UE1.30 141.3,30.38 v2(141.56,30.12)
SATA_ODD_DA#: length 6.1
  BOTTOM w0.102: JODD1.24 JODD1.23 198.5,46.53 198.96,46.06 TP46.1
SATA_ODD_PRSNT#: length 6.1
  BOTTOM w0.102: TP47.1 192.96,46.08 193.69,46.81 193.7,46.81 194.12,47.24 194.39,47.24 194.5,47.34 JODD1.15 JODD1.16
SATA_RXN0_R: length 7.8
  BOTTOM w0.102: CS3.2 193.33,20.97 v4(196.55,20.97) 196.74,20.97 197.08,20.64 197.08,20.15 197.2,20.03 EU3101.2 EU3101.8 197.2,18.27 197.05,18.12 197.05,17.74 197.15,17.64 JHDD1.5
SATA_RXN2_R: length 7.7
  BOTTOM w0.102: JODD1.10 191.5,49.85 191.89,49.45 191.89,49.02 191.5,48.63 JODD1.9 191.5,46.98 191.9,46.58 v4(191.9,46.03) 191.9,45.21 192.09,45.02 192.09,44.52 191.99,44.42 191.73,44.42 CS10.1
SATA_RXP0_R: length 7.9
  BOTTOM w0.102: JHDD1.6 196.65,17.64 196.84,17.83 196.84,18.12 196.7,18.27 EU3101.9 EU3101.1 196.7,19.97 196.87,20.15 196.87,20.55 196.67,20.75 196.25,20.75 196.23,20.77 195.14,20.77 195.13,20.75 v4(194.84,20.75) 194.5,20.75 194.48,20.77 193.81,20.77 193.7,20.65 193.7,20.4 193.55,20.26 CS4.2
SATA_RXP2_R: length 7.9
  BOTTOM w0.102: JODD1.12 192.5,49.85 192.1,49.45 192.1,49.05 192.5,48.66 JODD1.11 192.5,47.02 192.11,46.63 192.11,46.33 192.13,46.31 192.13,45.75 192.11,45.73 192.11,45.29 192.3,45.1 192.3,44.44 192.08,44.21 191.54,44.21 CS9.1
SATA_TXN0_R: length 8.9
  BOTTOM w0.102: JHDD1.3 198.15,17.64 198.34,17.83 198.34,18.12 198.2,18.27 EU3101.7 EU3101.4 198.2,20.12 198.34,20.27 198.34,21.09 v4(197.92,21.51) 197.58,21.85 197.58,22.04 197.08,22.55 196.87,22.55 196.85,22.53 196.23,22.53 196.21,22.55 195.96,22.55 195.78,22.72 195.51,22.72 195.41,22.62 195.41,22.38 195.22,22.19 CS2.2
SATA_TXN2_R: length 7.4
  BOTTOM w0.102: CS11.1 188.74,44.21 188.74,44.21 188.84,44.31 188.94,44.31 189.22,44.6 v4(189.22,46) 189.22,46.54 189.5,46.81 JODD1.5 189.5,48.64 189.1,49.04 189.1,49.45 189.5,49.85 JODD1.6
SATA_TXP0_R: length 8.9
  BOTTOM w0.102: JHDD1.2 198.65,17.64 198.55,17.74 198.55,18.12 198.7,18.27 EU3101.6 EU3101.5 198.7,20.12 198.55,20.27 198.55,21.17 198.35,21.37 198.35,21.39 197.9,21.85 197.89,21.85 197.79,21.95 197.79,22.13 197.16,22.75 v4(196.55,22.75) 196.04,22.75 195.87,22.93 195,22.93 CS1.2
SATA_TXP2_R: length 7.4
  BOTTOM w0.102: JODD1.4 188.5,49.85 188.89,49.45 188.89,49.04 188.5,48.64 JODD1.3 188.5,46.76 188.63,46.63 188.92,46.63 189.02,46.53 189.02,46.31 189,46.29 189,45.72 189.02,45.7 189.02,44.68 188.86,44.52 188.73,44.52 188.5,44.75 CS12.1
SD_RCOMP: length 8.7
  BOTTOM w0.102: RC130.1 110.89,26.38 v1(111.08,26.57) 111.08,28.73 111.02,28.79 111.02,31.06 110.94,31.14 110.94,31.39 111.02,31.47 111.02,31.71 110.94,31.79 110.94,32.04 111.11,32.21 112,32.21 UC1.AB7
SERIRQ: length 95.1
  TOP w0.102: RC14.2 93.14,29.98 93.14,29.45 93.24,29.35 93.24,28.39 93.09,28.24 93.09,26.84 v2(93.62,26.31)
  IN1 w0.119: v2(93.62,26.31) 93.09,26.84 93.09,27.8 92.41,28.48 92.41,29.15 92.88,29.62 92.88,29.89 94.5,31.51 95.24,31.51 95.25,31.52 95.55,31.52 95.8,31.77 98.78,31.77 101.16,29.39 106.97,29.39 109.09,27.26 111.96,27.26 112.74,26.48 113.49,26.48 113.58,26.48 113.78,26.28 119.44,26.28 120.53,25.19 123.13,25.19 123.43,24.89 129.52,24.89 130.12,25.49 130.12,25.98 132.41,28.28 132.41,28.61 136,32.2 136.49,32.2 140.52,36.24 142.42,36.24 143.1,35.55 145.91,35.55 146.32,35.96 147.04,35.96 147.31,35.69 147.31,35.43 147.77,34.98 148.77,34.98 149.25,35.45 149.25,35.64 v2(149.64,36.04)
  BOTTOM w0.076: UC1.AY11 101.52,35.08 100.06,35.08 99.88,34.9
  BOTTOM w0.102: v2(93.62,26.31) 93.62,26.41 94.11,26.9 94.11,28.4 95.05,29.34 95.05,32.29 95.93,33.17 97.09,33.17 98.25,34.33 98.25,34.46 98.7,34.9 99.88,34.9 ; UE1.55 150.76,34.32 v1(150.44,34.64) 149.41,35.66 149.41,35.81 v2(149.64,36.04)
SIO_EXT_SCI#: length 56
  TOP w0.102: RC70.1 120.57,27.83 v1(121.46,26.94) 121.82,26.58 121.82,26.33 v2(121.71,26.23)
  IN2 w0.127: v2(156.1,34.12) 156.1,34.12 155.37,34.85 155.37,35.58 155.38,35.59 155.38,35.94 154.85,36.47 152.06,36.47 150.94,37.59 146.94,37.59 146.81,37.46 145.28,37.46 145.14,37.32 142.97,37.32 142.1,36.45 141.28,36.45 139.6,34.76 136.25,34.76 133.46,31.97 133.46,29.39 129.29,25.22 125.45,25.22 125.45,25.21 125.43,25.21 125.15,24.94 122.47,24.94 121.82,25.6 121.82,26.13 v2(121.71,26.23)
  BOTTOM w0.076: UC1.J2 118.81,29.19 118.95,29.04 118.96,29 119.1,28.55
  BOTTOM w0.102: UE1.66 156.96,30.78 157.07,30.88 157.07,32.46 156.04,33.49 156.04,34.05 156.1,34.12 v2(156.1,34.12) ; 119.1,28.55 119.1,28.21 121.08,26.23 v2(121.71,26.23)
SIO_EXT_SMI#: length 51
  TOP w0.102: RC5.2 120.41,28.98 v2(121.37,28.02)
  IN1 w0.119: v2(121.37,28.02) 121.76,28.41 124.03,28.41 124.22,28.21 127.16,28.21 128.91,29.96 129.28,29.96 131.28,31.96 132.19,31.96 133.14,32.91 133.14,33.79 134.12,34.76 134.12,35.57 134.58,36.02 137.17,36.02 v2(137.7,36.56)
  BOTTOM w0.076: UC1.L6 117.94,30.82 120.85,30.82 121.55,30.12 121.55,29.73 121.43,29.61 121.43,29.36 121.5,29.29 121.5,28.15 v2(121.37,28.02)
  BOTTOM w0.102: UE1.10 141.2,22.38 141.8,22.99 143.49,22.99 144.54,24.04 144.54,27.14 143.4,28.28 143.4,29.29 143.42,29.31 143.42,29.93 143.4,29.95 143.4,30.63 143.03,31 142.6,31 142.32,31.28 141.99,31.28 141.38,31.89 139.61,31.89 138.59,32.91 138.59,33.71 137.88,34.42 v1(137.88,35.98) 137.88,36.38 v2(137.7,36.56)
SIO_EXT_WAKE#: length 69.5
  TOP w0.102: v2(141.88,38.88) 141.88,36.21 142.49,35.6 142.49,32.65 143.87,31.27 143.87,30.42 144.11,30.18 145.15,30.18 148.23,27.1 v3(148.23,26.03) 148.23,23.9 147.51,23.18 v2(146.91,23.18)
  IN2 w0.127: v2(110.19,28.34) 110.89,29.04 111.52,29.04 112.35,29.87 112.35,32.41 112.48,32.54 113.56,32.54 113.68,32.66 114.32,32.66 114.5,32.85 117.29,32.85 117.79,33.35 120.47,33.35 120.67,33.55 121.83,33.55 123.41,35.13 125.09,35.13 126.14,36.18 131.67,36.18 133.79,38.3 141.3,38.3 v2(141.88,38.88)
  BOTTOM w0.076: v2(110.19,28.34) 110.26,28.42 110.26,28.7 110.39,28.98 110.39,29.41 110.68,29.7 UC1.AD3
  BOTTOM w0.102: UE1.116 146.76,18.08 146.51,18.33 146.51,20.09 147.4,20.98 147.4,22.69 v2(146.91,23.18) ; RC47.1 109.94,26.31 109.68,26.57 109.68,28.15 109.87,28.34 v2(110.19,28.34)
SIO_PWRBTN#: length 85.2
  TOP w0.102: v2(96.48,34.71) 95.73,35.45 92.99,35.45 92.39,34.86 89.48,34.86 89.03,34.42 RC93.2
  IN1 w0.119: v2(148.58,35.42) 147.52,36.48 146.41,36.48 145.72,35.79 143.21,35.79 142.52,36.48 140.45,36.48 136.42,32.45 135.9,32.45 132.16,28.71 132.16,28.48 129.87,26.19 129.87,25.59 129.42,25.14 123.5,25.14 123.22,25.41 120.62,25.41 119.5,26.54 117.44,26.54 116.58,27.4 114.06,27.4 113.39,26.73 112.84,26.73 110.74,28.83 107.93,28.83 107.12,29.63 104.2,29.63 100.86,32.97 100.86,36.89 100.58,37.17 99.1,37.17 96.65,34.71 v2(96.48,34.71)
  BOTTOM w0.076: v2(96.48,34.71) 96.64,34.71 98.31,36.38 99.25,36.38 99.83,36.96 100.49,36.96 100.62,36.83 101.07,36.83 101.33,37.08 UC1.BA15
  BOTTOM w0.102: UE1.52 149.56,33.61 149.69,33.74 149.69,34.68 148.95,35.42 v2(148.58,35.42)
SIO_RCIN#: length 88.6
  TOP w0.102: RC13.2 92.55,31.79 v2(92.92,32.16)
  IN2 w0.127: v2(150.58,37.11) 150.35,37.34 147.05,37.34 146.92,37.21 145.51,37.21 145.2,36.9 145.2,36.5 145.08,36.37 143.78,36.37 142.35,34.95 140.15,34.95 139.7,34.5 136.35,34.5 133.72,31.87 133.72,29.29 129.42,24.99 125.54,24.99 125.54,24.99 125.52,24.99 125.12,24.59 115.53,24.59 115.53,24.59 114.77,24.59 114.07,25.29 112.03,25.29 112.01,25.27 112,25.27 111.32,24.59 104.96,24.59 102.25,27.29 102.25,28.28 97.26,33.28 94.04,33.28 v2(92.92,32.16)
  BOTTOM w0.076: 99.64,36.2 99.92,36.2 99.94,36.18 100.5,36.18 100.61,36.29 100.99,36.29 101.02,36.27 101.1,36.24 101.22,36.24 101.44,36.3 101.58,36.3 101.74,36.25 101.82,36.25 102.29,36.1 UC1.AW13
  BOTTOM w0.102: 99.64,36.2 98.38,36.2 97.11,34.93 97.11,34.81 96.62,34.32 94.8,34.32 93.01,32.54 93.01,32.52 92.92,32.43 v2(92.92,32.16) ; UE1.53 149.96,34.74 149.18,35.51 149.18,36.66 149.63,37.11 v1(149.78,37.11) v2(150.58,37.11)
SIO_SLP_A#: length 1.5
  TOP w0.102: TPS6.1 105.68,38.5 v2(106.18,38)
  BOTTOM w0.102: UC1.AN16 106.56,37.6 v2(106.18,38)
SIO_SLP_LAN#: length 105.1
  TOP w0.102: RC88.1 37.79,1.74 42.06,1.74 51.07,10.76 64.66,10.76 66.99,13.08 79.1,13.08 82.34,9.84 82.87,9.84 83.76,10.74 85.14,10.74 86.36,9.52 86.55,9.52 86.73,9.34 89.92,9.34 93.06,12.48 93.06,14.49 93.24,14.67 93.24,15.77 93.11,15.9 92.11,15.9 91.82,16.2 91.82,18.85 92.1,19.14 92.82,19.14 93.17,19.49 93.17,20.15 93.53,20.51 93.53,21.04 94,21.51 94,23.59 95.07,24.66 95.07,28.47 96.08,29.48 97.29,29.48 97.69,29.08 98.66,29.08 99.03,29.44 99.03,31.2 100.26,32.43 102.7,32.43 103.05,32.77 103.42,32.77 103.81,33.17 105.17,33.17 106.2,34.2 106.2,35.66 106,35.86 105.47,35.86 105.3,36.03 105.3,36.47 105.11,36.66 104.22,36.66 104.03,36.85 TP10.1 103.58,36.85 v2(103.39,37.05)
  BOTTOM w0.076: v2(103.39,37.05) 103.31,37.13 UC1.AW15
SIO_SLP_S0#: length 59.1
  TOP w0.102: TPS2.1 104.79,35.14 v2(104.98,35.33) ; v2(136.52,36.63) 136.52,36.39 139.36,33.55 139.36,32.24 139.53,32.07 139.53,27.2 138.58,26.24 138.58,24.35 138.58,24.35 138.58,24.19 138.47,24.09 137.69,24.09 137.56,23.96 UC9.2
  IN1 w0.119: v2(136.52,36.63) 136.16,37 135.59,37 135.11,36.51 134.62,36.51 133.87,35.76 133.87,34.87 132.9,33.89 132.9,33.02 132.09,32.21 131.18,32.21 129.18,30.2 128.81,30.2 127.06,28.46 124.36,28.46 124.09,28.73 120.04,28.73 118.32,30.45 117.94,30.45 117.3,29.81 111.78,29.81 111.35,29.38 108.78,29.38 107.62,30.54 106.98,30.54 106.38,31.14 105.81,31.14 105.49,31.46 105.49,33.68 105.11,34.06 105.11,35.21 v2(104.98,35.33)
  BOTTOM w0.102: v2(104.98,35.33) 104.98,35.22 UC1.AT11
SIO_SLP_S3#: length 141.9
  TOP w0.089: 104.66,32.02 104.2,31.56
  TOP w0.102: RZ2.1 136.54,25.85 136.54,25.04 136.1,24.6 v2(136.1,24.55) 136.1,23.33 136.2,23.23 136.46,23.23 136.46,23.22 UC9.1 ; 104.66,32.02 105.3,32.02 105.75,32.47 105.75,32.79 106.09,33.13 106.72,33.13 106.89,33.3 106.89,33.74 106.57,34.06 106.57,36.22 105.65,37.14 105.54,37.14 105.5,37.18 105.5,37.18 v2(105.5,37.18) ; 167.46,25.32 167.46,26.7 166.92,27.23 165.31,27.23 164.84,27.7 164.84,28.45 164.42,28.87 163.33,28.87 162.34,29.86 158.9,29.86 157.62,31.14 155.59,31.14 154.26,29.81 v2(153.66,29.81) 153.43,30.03 153.43,30.24 CE29.1 ; 167.46,25.32 167.45,25.31 166.77,25.31 166.56,25.09 166.56,24.72 166.66,24.61 UZ3.5 ; 167.46,25.32 UZ3.3 ; v2(90.88,12.22) 90.88,11.14 90.23,10.48 DZ4.1 89.3,10.48 RC103.1 ; 104.2,31.56 103.76,31.56 102.38,30.19 102.38,25.35 101.12,24.09 101.12,23.14 101.72,22.54 102.7,22.54 103.92,21.31 104.4,21.31 105.42,20.28 105.42,19.21 105.29,19.09 105.29,16.35 106.83,14.82 v2(108.98,14.82)
  IN1 w0.119: v2(90.88,12.22) 90.9,12.23 94.36,12.23 95.94,13.81 101.26,13.81 101.45,14 103.96,14 106.24,11.73 107.35,11.73 108.98,13.36 v2(108.98,14.82) 109.25,15.08 111.5,15.08 112.85,16.43 115.74,16.43 116.49,15.68 120.41,15.68 122.24,13.85 126,13.85 127.88,15.73 127.88,16.32 130.79,19.22 131.43,19.22 131.8,19.59 131.83,19.59 133.38,21.13 133.38,21.26 136.1,23.99 v2(136.1,24.55) 136.14,24.6 136.59,24.6 137.14,25.15 137.14,26.11 138.42,27.39 v2(139.04,27.39) 139.28,27.39 141.32,29.43 142.08,29.43 142.51,29 143.14,29 143.88,29.74 144.77,29.74 145.76,28.76 152.61,28.76 v2(153.66,29.81)
  BOTTOM w0.102: UE1.23 139.23,27.58 v2(139.04,27.39) ; v2(136.1,24.55) 136.06,24.6 135.53,24.6 TPS3.1 ; v2(105.5,37.18) 105.5,37.18 105.5,37.18 105.5,37.18 UC1.AP15
SIO_SLP_S4#: length 242.5
  TOP w0.102: RZ1.1 135.73,32.68 DZ5.1 135.72,33.36 v2(135.97,33.36)
  IN2 w0.127: v2(154.96,35.77) 154.65,35.46 153.75,35.46 152.99,36.22 151.95,36.22 151.6,36.57 150.47,36.57 149.96,37.08 147.15,37.08 147.02,36.96 146.45,36.96 145.61,36.12 143.88,36.12 142.46,34.69 140.25,34.69 139.62,34.06 137.6,34.06 136.9,33.36 v2(135.97,33.36) 135.57,33.36 133.97,31.76 133.97,29.18 129.55,24.76 125.64,24.76 125.64,24.76 125.61,24.76 125.21,24.36 115.43,24.36 115.43,24.36 114.7,24.36 114.7,24.36 114.64,24.36 113.96,25.04 112.1,25.04 111.42,24.36 104.83,24.36 102,27.18 102,28.18 97.15,33.03 94.81,33.03 93.24,31.46 92.67,31.46 91.65,32.47 v2(91.65,32.91)
  BOTTOM w0.076: 95.21,35.55 TPS4.1 96.78,35.55 98.1,36.88 99,36.88 99.62,37.5 101.62,37.5 UC1.BA16
  BOTTOM w0.102: PR803.1 56.23,7.52 63.18,14.48 78.05,14.48 79.05,15.48 79.05,18.16 79.06,18.17 ; PR201.1 87.52,64.76 79.08,56.31 79.08,30.68 79.05,30.65 79.05,18.18 79.06,18.17 ; 79.06,18.17 84.59,18.17 85.26,18.84 85.26,19.45 84.16,20.56 84.16,21.35 84.47,21.67 84.47,28.97 87.98,32.47 90.63,32.47 91.14,31.96 91.41,31.96 91.65,32.2 v2(91.65,32.91) 91.65,34.12 93.08,35.55 95.21,35.55 ; UE1.67 156.8,30.38 156.97,30.55 157.06,30.55 157.3,30.79 157.3,32.52 156.55,33.27 156.55,34.31 156.4,34.46 156.39,34.46 156.24,34.61 155.93,34.61 154.96,35.58 v2(154.96,35.77)
SIO_SLP_S5#: length 169.2
  TOP w0.254: PQ711.2 196.28,22.33 193.93,24.68 193.93,30.7 192.68,31.96 192.68,37.81 193.44,38.58 195.6,38.58 v3(198.84,41.82) 198.95,41.93 198.95,42.68 v2(199.03,42.76)
  IN2 w0.127: v2(91.21,32.47) 91.21,32.02 92.2,31.04 93.18,31.04 94.91,32.77 96.93,32.77 100.03,29.67 100.03,28.77 104.67,24.13 114.8,24.13 114.8,24.13 115.34,24.13 115.34,24.13 125.31,24.13 125.71,24.53 125.73,24.53 125.73,24.53 129.68,24.53 134.23,29.08 134.23,30.32 137.71,33.81 139.72,33.81 140.36,34.44 142.56,34.44 143.99,35.86 145.71,35.86 146.55,36.7 147.13,36.7 147.26,36.83 149.86,36.83 150.37,36.32 151.49,36.32 151.85,35.96 152.88,35.96 153.77,35.07 154.39,35.07 155.76,33.7 157.23,33.7 157.89,34.36 157.89,36.04 158.33,36.47 161.98,36.47 162.74,37.23 176.9,37.23 180.69,41.02 181.72,41.02 183.11,42.42 188.04,42.42 188.4,42.06 190.06,42.06 192.7,44.69 196.8,44.69 198.73,42.76 v2(199.03,42.76)
  BOTTOM w0.076: TPS5.1 97.78,37.04 98.93,37.04 99.55,37.67 101.39,37.67 101.71,37.98 102.19,37.98 UC1.AY16
  BOTTOM w0.102: v2(91.21,32.47) 91.21,34.01 93.43,36.23 96.96,36.23 TPS5.1
SIO_SLP_SUS#: length 1.5
  TOP w0.089: v2(106.2,37.12) 106.58,36.74 106.62,36.74 TP75.1
  BOTTOM w0.076: v2(106.2,37.12) 106.56,36.76 UC1.AN15
SIO_SLP_WLAN#: length 5.2
  BOTTOM w0.076: UC1.BB17 100.57,38 98.25,38 97.55,37.29 TP11.1
SLEEVE: length 1.1
  BOTTOM w0.102: RA26.2 v1(23.69,17.81)
  vias: v2(22.74,20.28) v2(23.32,20.28)
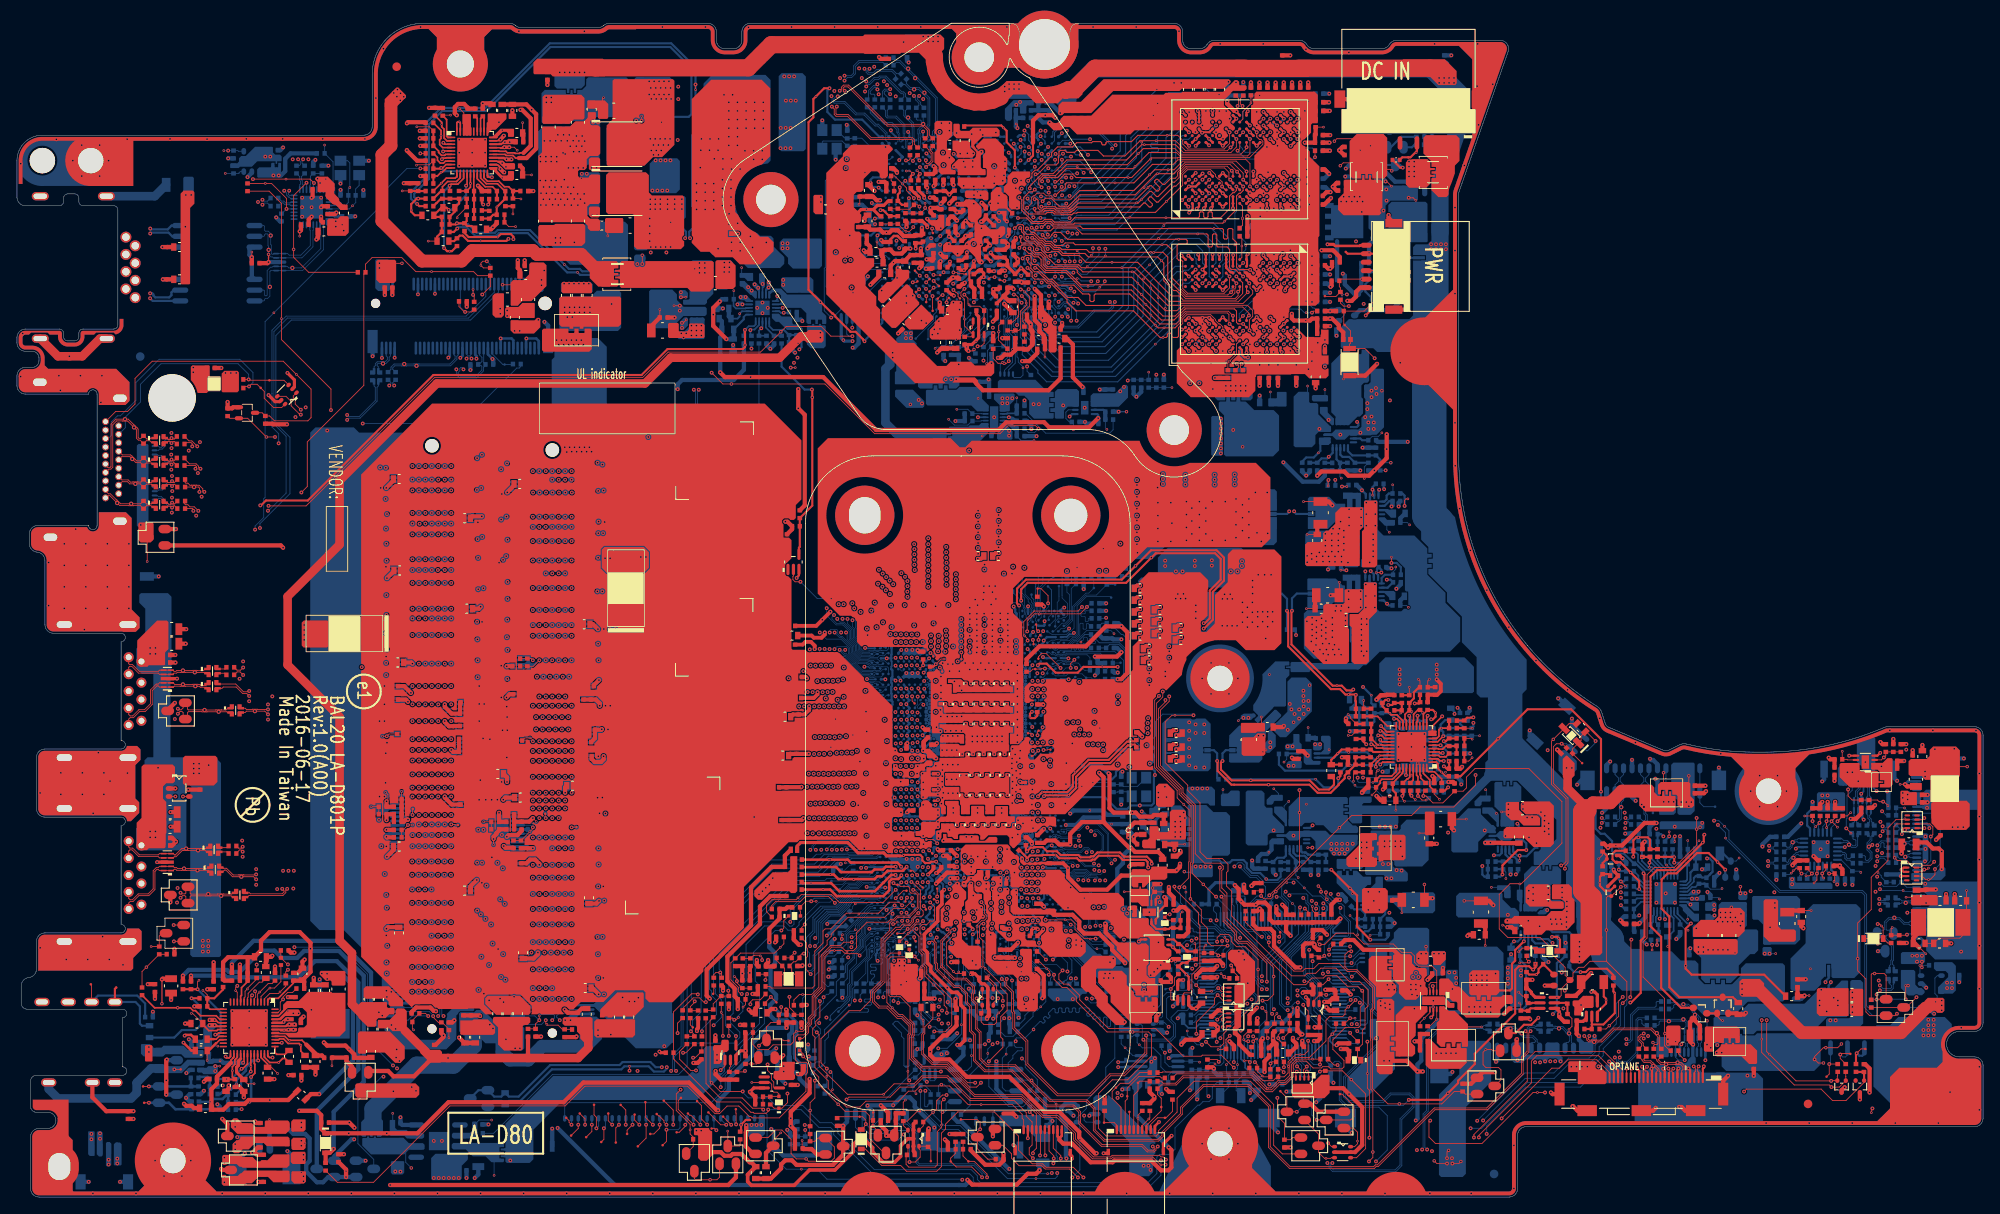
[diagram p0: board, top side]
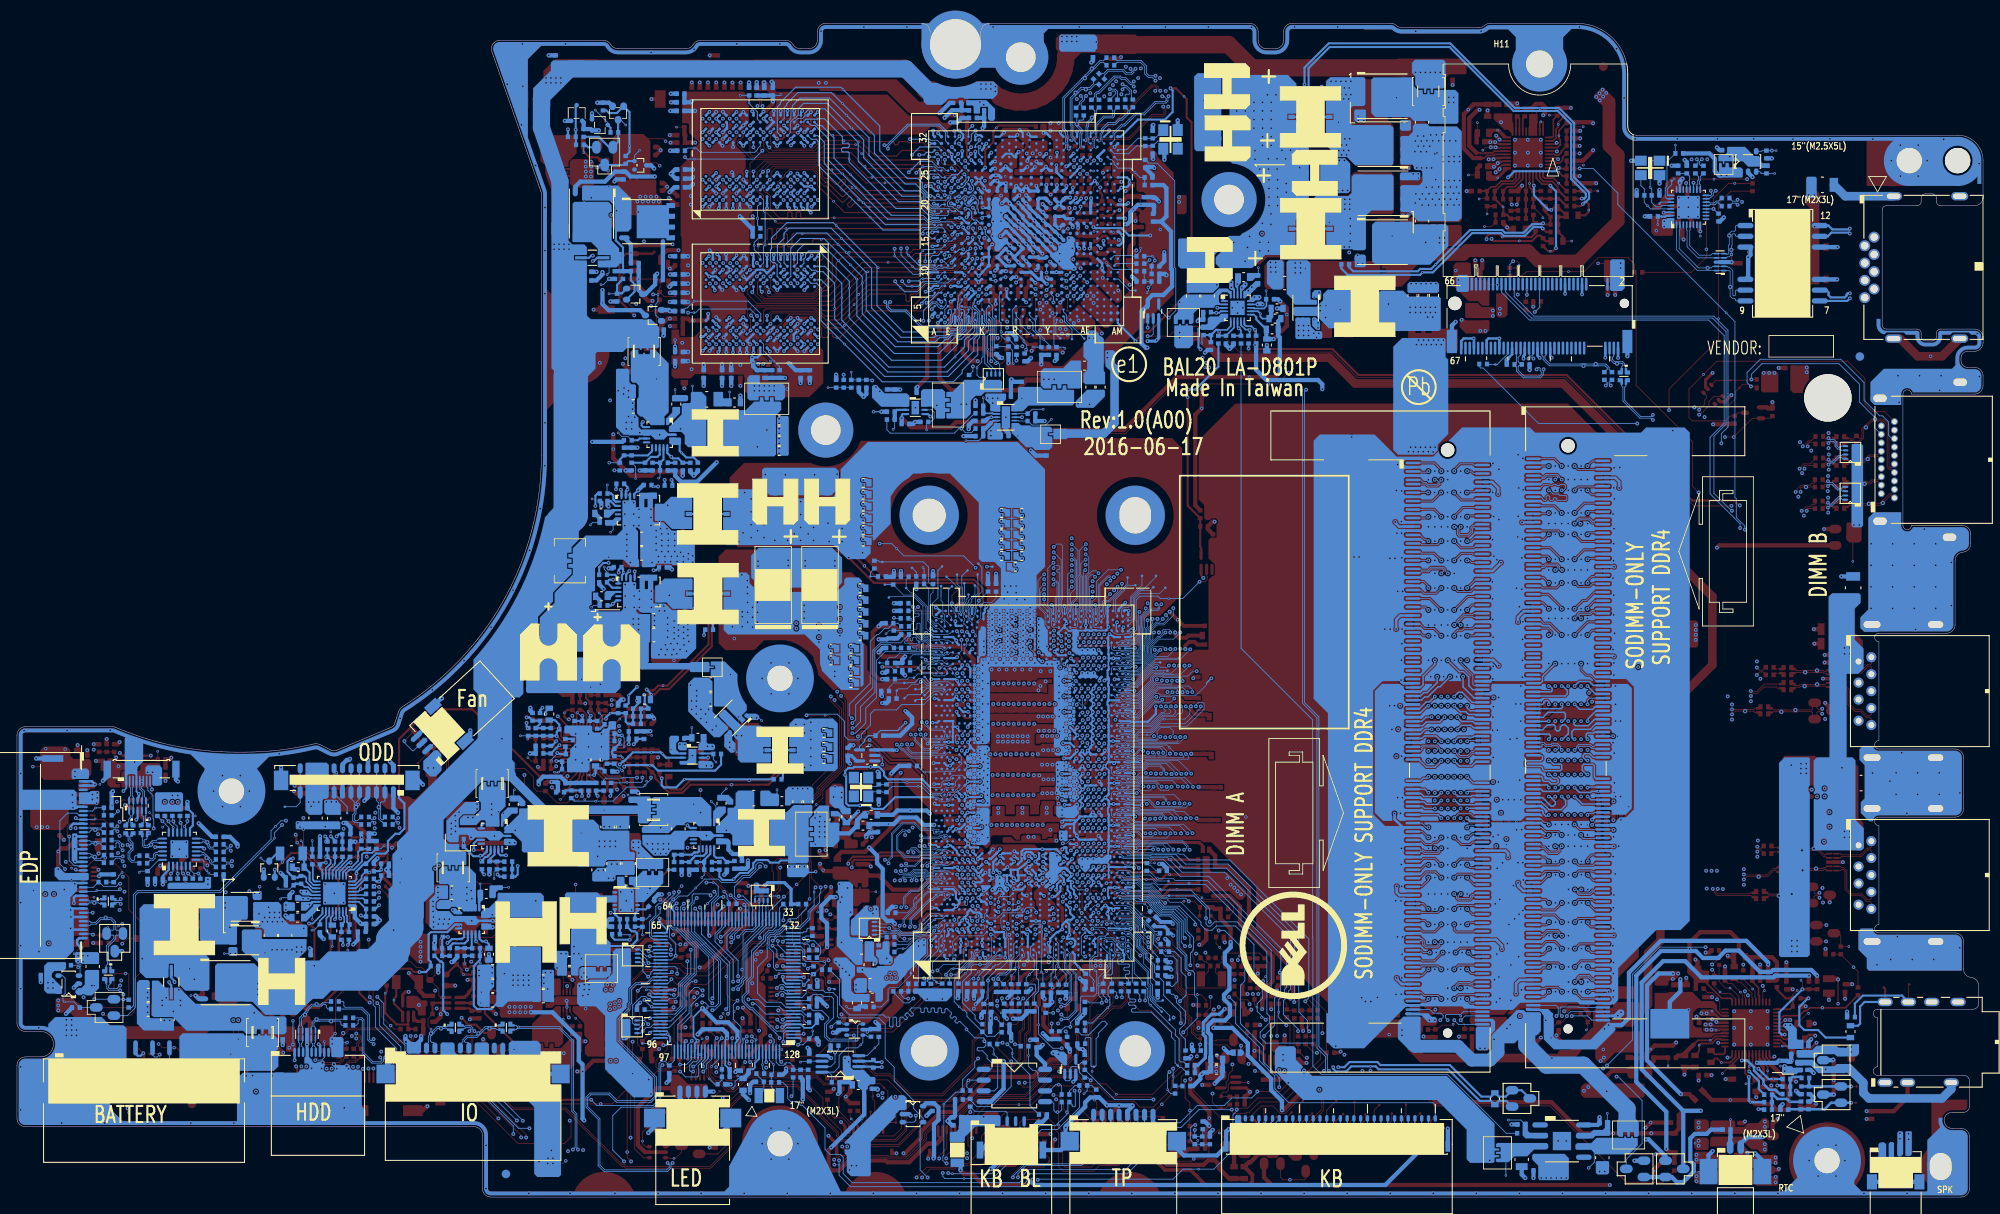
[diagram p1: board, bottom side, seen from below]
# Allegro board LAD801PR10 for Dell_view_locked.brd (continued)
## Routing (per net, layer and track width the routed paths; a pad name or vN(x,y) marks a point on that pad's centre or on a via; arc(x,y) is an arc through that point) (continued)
SLEEVE_R: length 17.6
  IN1 w1.016: 15.39,18.75 14.82,19.32 14.82,23 13.29,24.53 4.46,24.53 JHP1.3
  vias: v2(15.56,17.7) v2(15.56,17.12)
SM_RCOMP0: length 13.8
  TOP w0.305: RC10.1 v1(95.93,38.05) 96.35,38.05 96.88,37.52 101.16,37.52 101.47,37.84 102.03,37.84 102.69,38.49 102.69,38.5 104.48,38.5 104.94,38.96 v2(104.94,38.97)
  BOTTOM w0.254: UC1.AR18 104.94,38.83 v2(104.94,38.97)
SM_RCOMP1: length 12.7
  TOP w0.305: RC11.1 92.58,39.82 v1(95.78,39.82) 98,39.82 98.34,39.47 103.84,39.47 104.28,39.03 v2(104.28,38.98)
  BOTTOM w0.254: v2(104.28,38.98) 104.28,38.98 104.61,38.65 UC1.AT18
SM_RCOMP2: length 12.2
  TOP w0.305: RC12.1 v1(94.67,38.94) 96.61,38.94 97.22,38.33 100.82,38.33 101.14,38.65 102.16,38.65 102.49,38.98 v2(103.64,38.98)
  BOTTOM w0.254: UC1.AU18 103.64,38.83 v2(103.64,38.98)
SMBCLK: length 11.9
  TOP w0.102: QC1.6 113.86,23.5 113.81,23.46 113.81,23.45 v2(113.81,23.45)
  IN3 w0.142: v2(113.81,23.45) 113.81,23.45 113.81,23.6 114.39,24.18 114.39,28.68 115.28,29.57 115.28,31.28 114.98,31.58 v2(114.98,31.66)
  BOTTOM w0.076: v2(114.98,31.66) 115.43,31.93 UC1.R7
  BOTTOM w0.102: v2(113.81,23.45) 114.2,23.45 114.2,23.46 114.36,23.46 114.57,23.24 RC29.1
SMBDATA: length 12.1
  TOP w0.102: v2(115.73,23.46) 115.72,23.46 115.16,22.89 QC1.3
  IN3 w0.142: v2(115.73,23.46) 115.72,23.46 115.72,24.3 115.08,24.94 115.08,26.75 115.8,27.47 115.8,31.5 v2(115.03,32.27)
  BOTTOM w0.089: v2(115.03,32.27) 115.32,32.56 UC1.R8
  BOTTOM w0.102: RC30.1 115.78,23.15 115.78,23.4 v2(115.73,23.46)
SML0_SMBCLK: length 10.4
  BOTTOM w0.076: UC1.R9 115.84,32.87 115.84,31.87 115.52,31.54 115.38,31.54 115.22,31.38 115.22,31.15 115.22,31.14 115.22,30.8 115.22,30.79 115.22,30.77 114.97,30.52 114.97,28.12 115.25,27.83 115.68,27.83 115.94,27.58
  BOTTOM w0.102: 115.94,27.58 116.11,27.4 116.5,27.4 116.5,27.38 v1(116.75,27.13) 117.95,25.93 117.95,25.24 RC33.1
SML0_SMBDATA: length 4.5
  BOTTOM w0.076: UC1.W2 113.2,29.05 113.19,29.02 113.19,29.01 113.17,28.96 113.1,28.73 113.1,28.72 113.07,28.63 113.07,28.38 113.22,28.22 113.29,28.22 113.75,27.77
  BOTTOM w0.102: 113.75,27.77 v1(113.75,27.11) RC34.1
SML1CLK: length 236.4
  TOP w0.102: v2(116.16,25.74) 116.52,25.38 116.52,24.92 117.3,24.13 117.3,21.86 117.46,21.71 117.46,19.88 119,18.33 119,15.65 122.7,11.95 126.64,11.95 128.99,14.31 130.64,14.31 133.27,16.93 133.27,18.98 v2(133.18,19.07) ; v2(113.3,100.39) 113.33,100.41 113.75,100.41 114.08,100.74 QV1.6
  IN1 w0.119: v2(77.74,14.88) 77.62,14.76 77.62,14.59 78.24,13.96 83.52,13.96 84.34,13.14 88.47,13.14 89.88,11.73 94.57,11.73 96.15,13.31 101.47,13.31 101.66,13.5 103.76,13.5 106.13,11.13 108.17,11.13 108.29,11.25 108.29,11.96 109.48,13.15 110.48,14.14 111.38,14.14 112.41,15.18 120.2,15.18 122.17,13.21 126.07,13.21 128.38,15.52 128.38,16.11 131,18.72 131.68,18.72 132.27,19.32 132.65,19.32 132.89,19.07 v2(133.18,19.07)
  IN3 w0.142: v2(80.42,95.26) 80.25,95.44 80.25,95.64 80.39,95.78 97.97,95.78 102.47,100.28 111.86,100.28 112.08,100.28 112.34,100.54 113.16,100.54 113.3,100.39 v2(113.3,100.39)
  BOTTOM w0.076: 114.57,27.71 113.71,28.57 113.71,29.46 UC1.W3
  BOTTOM w0.102: v2(77.74,14.88) 77.56,15.06 77.56,16.59 78.57,17.6 78.57,56.57 80.26,58.26 80.26,95.03 80.42,95.2 v2(80.42,95.26) ; Q11.3 133.21,19.11 v2(133.18,19.07) 133.18,18.88 133.42,18.64 136.04,18.64 136.4,19 136.4,20.35 135.6,21.15 135.6,23.42 135.85,23.66 136.75,23.66 137,23.91 138,23.91 138.23,23.68 138.23,23.62 RE11.1 138.67,23.18 UE1.12 ; RC31.1 116.14,25.74 v2(116.16,25.74) 116.24,25.81 116.24,25.92 115.95,26.21 115.19,26.21 114.76,26.64 114.76,26.7 114.63,26.82 114.63,26.83 114.57,26.88 114.57,27.5 114.57,27.71 114.57,27.71
SML1DATA: length 234.9
  TOP w0.102: QV1.3 112.78,102.87 v2(112.54,102.63) ; v2(116.75,25.73) 116.75,25.01 117.53,24.23 117.53,21.96 117.68,21.81 117.68,19.97 119.23,18.42 119.23,15.74 122.79,12.18 126.54,12.18 128.9,14.54 130.55,14.54 133.04,17.03 133.04,18.46 132.94,18.57 v2(132.86,18.57)
  IN1 w0.119: v2(132.86,18.57) 132.86,18.76 132.54,19.07 132.37,19.07 131.78,18.48 131.1,18.48 128.63,16.01 128.63,15.42 126.18,12.96 122.07,12.96 120.1,14.93 112.51,14.93 111.48,13.9 110.58,13.9 109.73,13.05 108.54,11.86 108.54,11.15 108.28,10.88 106.02,10.88 103.65,13.25 101.76,13.25 101.57,13.06 96.25,13.06 94.67,11.49 89.78,11.49 88.37,12.9 84.24,12.9 83.42,13.71 78.14,13.71 77.37,14.48 77.37,14.67 77.16,14.88 v2(77.16,14.88)
  IN3 w0.142: v2(112.54,102.63) 112.54,101.13 111.97,100.55 102.36,100.55 97.86,96.05 80.28,96.05 79.98,95.75 79.98,95.4 v2(79.84,95.26)
  BOTTOM w0.102: UC1.V3 114.32,29.84 114.32,28.34 114.6,28.06 114.6,27.96 114.76,27.8 114.76,27.71 114.76,27.42 114.76,26.96 115.29,26.43 116.05,26.43 v2(116.75,25.73) 116.75,25.67 116.41,25.34 RC32.1 ; Q11.6 132.54,20.41 132.73,20.22 132.73,18.69 v2(132.86,18.57) 133.01,18.41 136.14,18.41 136.63,18.91 136.63,20.44 136.14,20.94 136.14,21.2 136.93,21.99 138,21.99 138.23,22.23 138.23,22.27 RE10.1 138.74,22.78 UE1.11 ; v2(77.16,14.88) 77.34,15.06 77.34,16.76 78.34,17.77 78.34,56.66 80.03,58.35 80.03,95.07 v2(79.84,95.26)
SNUB_+1.35VGPU: length 0.9
  BOTTOM w0.102: 147.84,94.11 v1(147.84,95)
SNUB_+1VALW: length 0.7
  BOTTOM w0.102: 142.25,47.39 v1(142.25,48.07)
SOC_XDP_TDI: length 3.6
  TOP w0.102: RC141.1 119.51,61.99 119.82,62.3 TPC5.1 120.78,62.3 120.84,62.36 v2(121.25,62.36)
  BOTTOM w0.076: v2(121.25,62.36) 121.25,62.36 UC1.D60 121.52,62.03 UC1.D59
SOC_XDP_TDO: length 9.7
  IN1 w0.119: v2(125.31,60.79) 124.92,61.17 v2(124.92,62.44)
  BOTTOM w0.076: 128.15,58.88 128.15,59.75 TPC1.1 127.93,59.97 126.9,59.97 126.35,60.52 125.57,60.52 v2(125.31,60.79) 125.05,60.79 124.62,60.36 123.56,60.36 UC1.A56 ; UC1.A61 123.56,62.84 124.53,62.84 v2(124.92,62.44)
  BOTTOM w0.102: 128.15,58.88 RC142.1
SOC_XDP_TMS: length 7.3
  BOTTOM w0.076: RC140.1 127.7,61.11 127.69,61.12 126.87,61.12 126.72,61.27 TPC4.1 125.83,61.54 125.82,61.54 125.63,61.74 123.96,61.74 123.72,61.5 122.47,61.5 UC1.C59
  BOTTOM w0.089: UC1.C60 122.17,62.03 UC1.C59
SOC_XDP_TRST#: length 6.3
  TOP w0.102: v2(124.72,63.4) 124.29,62.96 v2(124.29,62.44)
  BOTTOM w0.076: TPC6.1 125.17,63.68 125.15,63.67 125,63.67 v2(124.72,63.4) 124.51,63.18 123.87,63.18 123.7,63.35 123.33,63.35 123.3,63.34 123.24,63.32 122.77,63.32 122.38,62.92 UC1.C61 ; UC1.B59 123.07,61.79 123.3,62.03 123.71,62.44 v2(124.29,62.44)
SPKR: length 124.5
  TOP w0.102: DA3.3 v2(18.49,32.1)
  IN1 w0.119: v2(18.49,32.1) 18.1,31.71 18.1,30 18.34,29.75 19.55,29.75 26.25,23.06 28.81,23.06 30.09,24.34 39.65,24.34 41.5,22.49 41.5,21.16 43.89,18.76 43.89,18 43.89,17.95 48.2,13.64 53.23,13.64 54.16,12.72 58.94,12.72 59.87,13.64 71.96,13.64 v2(73.2,14.88)
  IN2 w0.127: v2(107.66,20.09) 107.17,19.6 104.49,19.6 102.01,22.09 97.99,22.09 94.73,18.82 85.87,18.82 85.05,19.65 82.19,19.65 80.73,18.18 78.13,18.18 74.83,14.88 v2(73.2,14.88)
  BOTTOM w0.102: RC128.2 108.82,19.56 108.29,20.09 v2(107.66,20.09) 107.66,20.57 106.47,21.75 106.47,23.51 106.27,23.71 104.86,23.71 104.54,24.03 104.54,26.57 v1(104.67,26.69) 105.11,27.14 105.11,28.03 104.77,28.37 104.51,28.37 104.4,28.48 104.4,30.62 104.23,30.78 103.54,30.78 UC1.AW5
SRTCRST#: length 30.3
  TOP w0.102: v2(91.12,23.62) 91.12,22.37 91.65,21.83 RC77.1 CC4.1
  IN3 w0.135: 107.71,36.65 107.54,36.47 106.76,36.47 106.05,35.76 103.26,35.76 102.18,34.68 102.18,33.11 ; v2(106.85,38.05) 106.85,38 107.25,37.6 107.71,37.6
  IN3 w0.142: v2(91.12,23.62) 91.14,23.6 93.4,23.6 94.72,24.92 96.01,24.92 98.58,27.49 98.99,27.49 99.82,28.32 99.82,28.74 102.18,31.09 102.18,33.11 ; 107.71,37.6 107.89,37.43 107.89,36.83 107.71,36.65
  BOTTOM w0.102: v2(106.85,38.05) UC1.AN18
SUS_STAT#/LPCPD#: length 4
  BOTTOM w0.076: UC1.BA11 101.44,34.66 101.19,34.91 100.5,34.91 100.19,34.6 v1(98.88,34.6) 98.56,34.28 98.56,34.04 RC35.1
SUSCLK: length 30.6
  TOP w0.102: v2(83.9,24.34) 83.97,24.28 RC110.1 RC74.2 83.05,23.72 82.12,22.79 RC75.2 82,22.01 RC189.2
  BOTTOM w0.076: 95.21,36.88 97.37,36.88 97.94,37.45 v1(98.69,37.45) 98.94,37.45 99.32,37.83 101.05,37.83 UC1.BA17
  BOTTOM w0.102: 95.21,36.88 91.7,36.88 83.97,29.14 83.97,24.41 v2(83.9,24.34)
SUSCLK_EC: length 81.9
  TOP w0.102: RC75.1 81.76,20.85 81.76,13.66 v3(81.94,13.47) 82.95,12.46 v2(85.61,12.46)
  BOTTOM w0.102: v2(85.61,12.46) 85.61,12.35 86.25,11.7 88.6,11.7 89.5,10.81 92.68,10.81 94.71,8.77 96.08,8.77 96.82,8.04 96.82,7.55 101.14,3.23 112.56,3.23 113.28,2.52 113.28,2.07 113.65,1.7 133.38,1.7 134.45,2.77 134.45,4.72 134.77,5.03 135.99,5.03 136.59,5.64 136.59,8.16 139.28,10.84 139.48,10.84 139.88,11.24 139.88,11.26 140.61,11.26 140.99,11.64 140.99,12.97 141.55,13.54 RE45.2
SUSCLK_SSD: length 135.1
  TOP w0.102: v2(88.03,10.32) 87.86,10.48 86.76,10.48 85.54,11.7 82.95,11.7 81.55,13.1 81.55,13.11 81.27,13.4 81.27,21.06 RC189.1 ; JSSD1.22 188.35,14.87 186.54,16.68 179.26,16.68 178.62,16.04 178.62,13.47 172.44,7.28 v2(172.44,7.04)
  IN1 w0.119: v2(111.5,2.04) 111.92,1.62 123.13,1.62 124.24,2.73 125.96,2.73 126.32,2.37 129.79,2.37 134.24,6.82 136.97,6.82 140.19,10.05 144.2,10.05 146.04,8.21 153.51,8.21 154.29,8.99 160.29,8.99 161.76,7.53 171.95,7.53 v2(172.44,7.04)
  BOTTOM w0.102: v2(111.5,2.04) 111.43,2.11 95.54,2.11 94.35,3.29 v1(92.53,3.29) 90.73,3.29 88.47,5.55 88.47,9.71 88.03,10.16 v2(88.03,10.32)
SUSCLK_WLAN: length 161.8
  TOP w0.102: RC74.1 v1(83.08,21.8) 83.08,21.7 83.27,21.51 v2(83.27,19.01)
  IN1 w0.119: v2(30.87,88.94) 35.65,84.16 35.65,46.66 45.96,36.35 45.96,23.34 47.64,21.65 47.64,19.5 49.02,18.13 57.33,18.13 57.67,18.47 61.05,18.47 61.39,18.13 69.63,18.13 71.42,19.91 74,19.91 75.45,21.36 77.69,21.36 77.83,21.51 81.93,21.51 83.27,20.18 v2(83.27,19.01)
  BOTTOM w0.102: v2(30.87,88.94) 30.87,90.08 30.08,90.87 30.08,94.46 30.08,94.46 30.08,94.8 30.08,94.8 30.08,102.28 31.75,103.95 52.97,103.95 55.3,106.28 JWLAN1.42
SVI2_SVC: length 75.7
  TOP w0.203: v2(50.29,124.4) 50.33,124.4 50.49,124.24 PU1100.3
  IN1 w0.142: v2(50.29,124.4) 51.45,123.24 51.45,123.03 53.88,120.6 53.88,118.57 54.24,118.21 54.24,115.09 57.53,111.8 61.85,111.8 64,109.66 64,103.93 64.72,103.21 67.11,103.21 70.68,99.64 83.2,99.64 83.2,99.64 83.63,99.64 84.48,98.79 90.37,98.79 90.62,99.05 v2(92.06,99.05)
  IN3 w0.142: v2(92.06,99.05) 93.17,100.15 93.17,104.01 95.49,106.33 97.44,106.33 v2(98.45,107.33)
  BOTTOM w0.102: RV157.2 RV89.2 RV84.1 98.08,107.7 v2(98.45,107.33) 98.45,106.93 98.61,106.77 v1(98.61,106.71)
SVI2_SVD: length 79.7
  TOP w0.203: v2(50.26,123.38) 50.32,123.44 PU1100.5
  IN1 w0.142: v2(50.26,123.38) 51.34,122.3 51.34,120.37 53.72,118 53.72,114.73 57.16,111.28 61.64,111.28 63.48,109.44 63.48,103.71 64.5,102.69 66.9,102.69 70.46,99.12 83.41,99.12 84.26,98.27 90.59,98.27 90.76,98.44 v2(91.65,98.44)
  IN3 w0.142: v2(97.68,110.51) 97.79,110.4 97.79,110.35 98.97,109.18 98.97,107.12 97.66,105.81 95.7,105.81 93.69,103.8 93.69,99.94 92.15,98.39 91.7,98.39 v2(91.65,98.44)
  BOTTOM w0.102: RV87.1 RV88.2 98.06,110.13 v2(97.68,110.51) 97.68,110.72 v1(97.98,111.02) RV155.2
SVI2_SVT: length 80.3
  TOP w0.102: v2(91.27,97.87) v1(91.8,97.87)
  TOP w0.203: PU1100.7 50.63,122.64 50.59,122.59 50.25,122.59 v2(50.13,122.47)
  IN1 w0.142: v2(50.13,122.47) 50.82,121.77 50.82,120.16 53.19,117.78 53.19,114.51 57.63,110.07 62.1,110.07 62.81,109.37 62.81,107.21 62.22,106.62 61.88,106.62 61.17,105.92 61.17,104.98 63.99,102.16 66.68,102.16 70.25,98.6 83.2,98.6 84.05,97.75 91.15,97.75 v2(91.27,97.87)
  IN3 w0.142: v2(91.27,97.87) 91.33,97.81 92.31,97.81 94.28,99.78 94.28,103.64 95.92,105.28 97.88,105.28 99.49,106.9 99.49,109.4 v2(98.32,110.57)
  BOTTOM w0.102: v2(98.32,110.57) 98.74,110.15 RV156.2
SYS_PWROK: length 60.9
  TOP w0.102: v2(153.82,36.03) 153.82,36.38 v3(153.5,36.7)
  IN1 w0.119: v2(123.9,26.62) 123.96,26.56 127.59,26.56 128.32,27.29 129.45,27.29 130.43,28.27 131.02,28.27 135.7,32.94 136.29,32.94 140.32,36.97 142.72,36.97 143.41,36.29 144.75,36.29 145.21,36.74 145.21,36.9 145.54,37.23 149.56,37.23 150.1,36.69 152.89,36.69 153.56,36.03 v2(153.82,36.03)
  BOTTOM w0.076: UC1.B6 122.5,30.67 122.78,30.39 122.78,30.05
  BOTTOM w0.089: v2(123.9,26.62) 123.9,27.65 122.67,28.88 122.67,29.35 122.52,29.49 122.52,29.8 122.78,30.05
  BOTTOM w0.102: UE1.89 154.28,21.58 153.43,22.43 153.43,24.98 152.01,26.4 152.01,29.4 154.14,31.53 154.53,31.53 155.02,32.02 155.02,34.61 153.82,35.82 v2(153.82,36.03)
SYS_RESET#: length 7.3
  BOTTOM w0.102: RC86.2 123.26,25.19 TPS1.1 123.65,25.58 123.76,25.58 123.93,25.76 123.93,26.03 124.43,26.52 124.43,26.82 124.43,27.95 123.31,29.06 123.31,29.15 123.16,29.3 123.16,30.47 UC1.B5
SYSPWR_PRES: length 4.1
  TOP w0.102: v2(145.23,18.39) 144.88,18.39 v1(144.7,18.57) 144.7,19.03 145.25,19.58 RE32.1 RE29.1
  BOTTOM w0.102: UE1.120 145.16,18.31 v2(145.23,18.39)
T_CRIT#: length 3.8
  BOTTOM w0.102: U2.4 131.63,16.68 v1(130.71,17.61) 130.24,18.07 R29.2
TESTEN: length 6.6
  TOP w0.102: RV154.2 RV17.2 118.18,102.26 118.38,102.47 118.38,104.54 119.04,105.2 v1(119.04,105.49) 119.04,105.8 v2(118.52,106.32)
  BOTTOM w0.102: UV1.K7 118.46,106.32 v2(118.52,106.32)
THM_SML1_CLK: length 10.3
  BOTTOM w0.102: R49.2 131.57,18.92 131.75,19.11 Q11.4 132.13,18.22 v1(132.38,17.97) 132.74,17.61 134.03,17.61 134.93,16.71 134.93,15.35 135.55,14.73 136.16,14.73 ; 136.16,14.73 135.79,14.36 C24.1 ; 136.16,14.73 U2.8
THM_SML1_DATA: length 9.7
  IN3 w0.142: v2(135.85,20.08) 136.42,19.51 136.42,18.94 135.4,17.92 v2(135.4,17.04)
  BOTTOM w0.102: C25.1 135.01,17.43 v2(135.4,17.04) 135.41,17.03 135.41,15.89 135.91,15.38 U2.7 ; v2(135.85,20.08) 135.85,20.1 135.35,20.6 R48.2 134.66,20.6 134.47,20.41 Q11.1
TON_1.2V: length 2.5
  BOTTOM w0.203: PU200.9 87.53,102.91 87,102.37 86.57,102.37 v2(86.51,102.3) 86.51,101.76 PR208.2
TOUCH_SCREEN_PD#: length 111.1
  TOP w0.102: R19.2 220.64,29.98 D5.2 220.12,31.79 v1(219.93,31.98) 219.69,32.22 v2(219.47,32.22)
  IN2 w0.127: v2(219.47,32.22) 217.7,34 217.7,38.21 214.65,41.26 214.65,42.2 213.68,43.17 209.03,43.17 208.36,42.49 208.35,42.49 208.32,42.47 200.43,42.47 199.61,43.29 198.6,43.29 196.97,44.92 192.52,44.92 189.89,42.28 188.64,42.28 188.2,42.72 182.95,42.72 181.5,41.27 180.59,41.27 176.8,37.48 162.63,37.48 161.88,36.73 152.16,36.73 150.39,38.5 147.49,38.5 146.71,37.72 145.18,37.72 145.03,37.57 142.86,37.57 141.99,36.7 141.18,36.7 139.49,35.01 136.14,35.01 132.9,31.77 131.97,31.77 v2(130.57,30.38)
  BOTTOM w0.076: RC115.2 130.26,30.06 v2(130.57,30.38) 130.26,30.69 RC118.1
TOUCH_SCREEN_PD#_R: length 6
  BOTTOM w0.076: UC1.A7 123.56,31.97 123.95,31.97 124.15,31.76 124.62,31.76 125.48,30.9 125.95,30.9 126.3,30.54 126.49,30.54 v1(126.59,30.45) 126.91,30.12 127.83,30.12 RC118.2
TOUCHPAD_INTR#: length 82.1
  TOP w0.102: DZ3.1 92.73,16.89 v2(92.73,16.6) 93.21,16.13 93.39,16.13 93.64,15.87 93.64,15.07 94.57,14.15 94.57,13.23 v3(96.86,10.95) 97.69,10.11 100.03,10.11 100.54,9.61 100.54,6.94 102.27,5.21 Q9.1
  IN2 w0.127: v2(141.5,32.66) 141.5,32.28 141.34,32.12 137.1,32.12 134.99,30.01 134.99,28.76 130.07,23.84 126.02,23.84 126.02,23.84 125.99,23.84 125.75,23.6 125.75,23.13 125.04,22.42 121.48,22.42 120.84,21.77 119.85,21.77 117.81,19.73 114.15,19.73 112.92,18.5 112.92,18.42 112.57,18.07 112.25,18.07 111.71,18.61 109.28,18.61 109.02,18.87 104.5,18.87 101.79,21.58 98.21,21.58 94.12,17.49 92.86,17.49 92.73,17.37 v2(92.73,16.6)
  BOTTOM w0.102: v2(141.5,32.66) 141.49,32.67 141.49,33.43 141.14,33.78 141.14,34.2 RE14.1 141.96,34.12 UE1.33
TOUCHPAD_INTR#_D: length 21
  TOP w0.102: v2(92.35,17.99) 92.32,18.02 DZ3.2 92.67,18.7 93.37,19.41 93.37,20.06 93.73,20.42 93.73,20.92 94.23,21.41 94.23,23.5 95.29,24.56 95.29,28.37 96.02,29.09 v1(96.41,29.09) 97.31,29.09 97.68,28.72 99.17,28.72 v2(99.39,28.5)
  BOTTOM w0.076: UC1.BA5 101.32,31.13 100.93,30.74 100.66,30.74 100.05,30.13 100.05,29.15 v2(99.39,28.5)
  BOTTOM w0.102: v2(92.35,17.99) 92.35,17.93 92.4,17.88 92.4,17.43 RC114.2
TP_EN: length 4
  TOP w0.102: v2(222.93,30.96) 222.87,30.9 C16.1 R19.1 221.06,31.68 v1(221.19,31.81)
  BOTTOM w0.102: JEDP1.39 223.02,31.05 v2(222.93,30.96)
TP_LOCK#: length 9.2
  TOP w0.102: R41.2 96.91,9.48 ZT11.1 99.73,9.48 100.12,9.09 v2(100.12,8.61) 100.12,8.5 D6.2
  BOTTOM w0.102: v2(100.12,8.61) 100.76,7.97 101.95,7.97 102.9,8.92 JTP1.3
TP_ON#_GATE: length 18
  TOP w0.102: R38.2 C18.2 94.11,6.58 94.49,6.96 Q12.2 96.41,5.92 96.41,4.6 96.04,4.23 93.36,4.23 v3(93.09,4.5) 91.93,4.5 91.31,5.12 91.31,6.82 90.22,7.9 89.48,7.9 88.6,7.02 Q13.2
TP_PW_EN#: length 73.4
  TOP w0.102: v2(94.11,13.74) 94.11,11.7 93.55,11.14 v3(93.55,10.22) R38.1
  IN2 w0.127: v2(94.11,13.74) 94.58,13.27 95.6,13.27 95.94,12.93 101.31,12.93 104.36,15.98 112.63,15.98 113.94,17.28 114.88,17.28 118.53,17.28 122.22,20.97 129.11,20.97 130.36,22.22 134.92,22.22 135.05,22.09 136.77,22.09 140.25,25.58 140.25,28.26 140.93,28.94 142.02,28.94 142.27,28.69 143.13,28.69 144.25,29.81 145.94,29.81 146.39,29.36 148.12,29.36 v2(148.88,30.12)
  BOTTOM w0.102: v2(148.88,30.12) 149.33,30.58 149.33,30.98 148.53,31.78 148.53,31.79 148.36,31.96 UE1.49
UG1_VGA: length 21
  TOP w0.102: v3(73.75,111.14) v2(73.75,110.09)
  IN1 w1.016: 72.73,111.02 68.66,111.02 65.36,114.32 61.04,114.32 58.25,117.12 58.25,120.04
  vias: v2(57.04,121.31) v2(57.49,120.93) v2(73.17,110.09)
UG2_VGA: length 17.4
  TOP w0.102: v2(73.68,127.02) v1(73.68,127.55)
  IN1 w1.016: 73.17,127.91 71.96,129.12 66.57,129.12 65.43,127.98 61.42,127.98 60.28,126.83 58.57,126.83 57.99,126.26
  vias: v2(57.03,124.79) v2(57.42,125.25) v2(73.04,127.02)
UG_1.2V: length 8.1
  TOP w0.102: v2(78.31,106.18) v1(78.89,106.18)
  IN3 w0.762: 85.81,108.29 82.25,108.29 80.4,106.44 79.01,106.44
  vias: v2(78.31,106.77) v2(87.01,107.7) v2(87.42,107.29)
UGATE_CHG:
  vias: v2(197.39,34.51)
USB2_ID: length 5.3
  BOTTOM w0.076: RC67.1 109.05,25.57 109.42,25.94 v1(109.42,25.95) 109.42,27.28 109.22,27.48 109.22,27.65 109.21,27.66 109.21,27.99 109.62,28.39 109.62,29.45 109.36,29.71 UC1.AG3
USB2_VBUSSENSE: length 5.9
  BOTTOM w0.076: UC1.AG4 109.36,30.24 109.05,29.93 109.05,27.58
  BOTTOM w0.089: 109.05,27.58 v1(109.05,27.18)
  BOTTOM w0.102: RC68.1 108.16,26.29 v1(109.05,27.18)
USB3_CM_P0: length 3.6
  TOP w0.102: v2(211.79,44.36) RX17.2 v1(210.87,44.97)
  BOTTOM w0.102: RX17.2 v2(211.79,44.36) 211.79,44.16 211.99,43.95 UX2.14
USB3_CRX_C_RD_DTX_N3: length 3
  BOTTOM w0.102: CX6.2 208.78,41.07 209.14,41.07 209.37,41.29 209.37,41.47 209.82,41.93 209.97,41.93 210.1,41.79 UX2.11
USB3_CRX_C_RD_DTX_P3: length 3
  BOTTOM w0.102: CX7.2 208.78,41.28 209.06,41.28 209.16,41.38 209.16,41.59 v4(209.44,41.87) 209.72,42.15 209.95,42.15 210.1,42.29 UX2.12
USB3_CRX_DTX_N1: length 169.1
  TOP w0.102: RU5.2 23.53,59.87 LU3.3 24.19,60.04 24.34,60.18 25.86,60.18 26.62,59.42 27.1,59.42 v2(27.39,59.13)
  IN3 w0.142: v2(118.63,32.56) 119.1,32.09 119.37,32.09 119.57,31.89 119.57,27.38 123.34,23.62 123.34,22.47 119.51,18.64 119.51,15.83 109.3,5.63 91.62,5.63 90.58,4.59 61.75,4.59 61.34,5 55.5,5 55.19,5.31 49.47,5.31 47.45,7.33 47.45,8.4 42.05,13.8 42.05,17.73 38.3,21.48 38.3,28.54 34.12,32.73 29.15,32.73 27.01,34.86 27.01,38.18 28.3,39.47 28.3,54.61 26.82,56.09 26.82,59.14 26.98,59.3 27.22,59.3 v2(27.39,59.13)
  BOTTOM w0.102: UC1.H8 118.8,33.22 118.72,33.3 118.55,33.3 118.44,33.2 118.44,32.74 v2(118.63,32.56)
USB3_CRX_DTX_N1_C: length 13
  TOP w0.102: JUSB1.5 13.18,56.4 13.35,56.57 13.74,56.57 14.47,57.3 15.13,57.3 15.96,58.13 15.96,59.76 16.52,60.32 16.66,60.32 16.81,60.17 EU2601.9 EU2601.1 18.45,60.17 18.56,60.29 19.26,60.29 19.28,60.27 19.88,60.27 19.9,60.29 v4(21.04,60.29) 21.27,60.29 21.29,60.27 21.52,60.27 21.63,60.16 22.32,60.16 LU3.4 22.61,59.87 RU5.1
USB3_CRX_DTX_N2: length 141.7
  TOP w0.102: v2(28.21,37.48) 27.9,37.8 v4(26.46,37.8) 25.42,37.8 24.63,38.59 24.49,38.59 24.29,38.38 LU6.3 23.84,38.21 RU11.2
  IN3 w0.142: v2(28.21,37.48) 28.21,37.5 28.07,37.64 27.85,37.64 27.71,37.5 27.71,35.32 29.61,33.42 34.41,33.42 39,28.83 39,21.77 42.75,18.02 42.75,14.09 47.8,9.04 48.69,9.04 51.73,6.01 55.48,6.01 55.79,5.69 61.89,5.69 62.3,5.29 90.29,5.29 91.33,6.33 107.72,6.33 109.85,8.45 111.14,8.45 117.01,14.33 117.01,16 118.81,17.79 118.81,18.93 121.54,21.66 121.54,24.22 118.87,26.89 118.87,31.27 118.55,31.59 v2(118.55,31.61)
  BOTTOM w0.076: UC1.J6 117.86,32.11 117.78,32.03 117.78,31.68 117.86,31.61 v2(118.55,31.61)
USB3_CRX_DTX_N2_C: length 13.7
  TOP w0.102: RU11.1 22.93,38.21 LU6.4 22.61,38.54 21.54,38.54 21.53,38.55 v4(21.29,38.55) 20.02,38.55 20.01,38.54 19.4,38.54 19.39,38.55 18.86,38.55 18.73,38.68 18.56,38.68 18.4,38.52 EU2603.1 EU2603.9 16.81,38.52 16.66,38.67 16.52,38.67 16.27,38.43 16.27,36.28 15.56,35.57 14.39,35.57 13.69,34.87 13.35,34.87 13.18,34.7 JUSB2.5
USB3_CRX_DTX_N3: length 173.1
  IN3 w0.142: v2(118.57,34.36) 119.02,34.81 120.66,34.81 120.8,34.95 121.4,34.95 123.54,32.82 127.95,32.82 128.07,32.94 128.81,32.94 130.69,31.06 130.93,31.06 131.46,30.52 131.46,30.06 131.84,29.68 133.21,29.68 133.93,30.39 137.64,30.39 138.47,31.22 139.66,31.22 140.35,30.52 140.35,29.04 141.37,28.02 143.47,28.02 143.95,27.55 143.95,26.32 143.4,25.76 143.4,22.06 145.75,19.7 146.2,19.7 146.49,19.41 146.49,18.2 147.21,17.48 149.14,17.48 150.53,16.09 150.53,13.82 150.94,13.41 152.21,13.41 155.66,9.96 211.6,9.96 223.28,21.64 223.28,29.41 223.41,29.54 223.41,43.91 221.34,45.97 219.84,45.97 218.5,44.64 218.5,44.26 217.07,42.83 215.49,42.83 214.94,43.38 210.56,43.38 208.75,41.57 208.07,41.57 207.61,41.11 206.92,41.11 206.68,40.87 v2(206.67,40.87)
  BOTTOM w0.076: v2(118.57,34.36) 118.15,33.94 UC1.J10
  BOTTOM w0.102: v2(206.67,40.87) 206.89,41.09 207.16,41.09 CX6.1
USB3_CRX_DTX_P1: length 169.2
  TOP w0.102: v2(27.39,59.71) 27.3,59.62 26.71,59.62 25.8,60.54 LU3.2 23.53,60.7 RU6.2
  IN3 w0.142: v2(119.23,32.59) 119.82,32.01 119.82,27.49 123.59,23.72 123.59,22.36 119.76,18.53 119.76,15.73 109.4,5.38 91.72,5.38 90.68,4.34 61.64,4.34 61.24,4.74 55.4,4.74 55.09,5.06 49.37,5.06 47.2,7.22 47.2,8.3 41.8,13.7 41.8,17.63 38.05,21.37 38.05,28.44 34.01,32.47 29.04,32.47 26.76,34.76 26.76,38.29 28.05,39.58 28.05,54.5 26.57,55.98 26.57,59.24 26.88,59.55 27.23,59.55 v2(27.39,59.71)
  BOTTOM w0.102: UC1.G8 119.45,32.81 v2(119.23,32.59)
USB3_CRX_DTX_P1_C: length 13.1
  TOP w0.102: RU6.1 22.61,60.7 LU3.1 22.27,60.37 22.01,60.37 22.01,60.36 21.72,60.36 21.61,60.47 21.37,60.47 21.34,60.51 20.74,60.51 20.72,60.49 v4(19.58,60.49) 18.61,60.49 18.43,60.67 EU2601.2 EU2601.8 16.81,60.67 16.66,60.53 16.43,60.53 15.75,59.85 15.75,58.21 15.05,57.51 14.38,57.51 13.65,56.78 13.35,56.78 13.18,56.95 JUSB1.6
USB3_CRX_DTX_P2: length 141.8
  TOP w0.102: v2(28.21,38.07) 28.15,38.01 26.76,38.01 26.74,38.03 26.18,38.03 26.16,38.01 25.51,38.01 24.72,38.79 24.37,38.79 24.28,38.88 LU6.2 23.84,39.05 RU12.2
  IN3 w0.142: v2(28.21,38.07) 28.04,37.89 27.74,37.89 27.45,37.6 27.45,35.22 29.5,33.17 34.3,33.17 38.75,28.73 38.75,21.66 42.5,17.92 42.5,13.99 47.7,8.79 48.59,8.79 51.62,5.75 55.38,5.75 55.69,5.44 61.79,5.44 62.19,5.04 90.39,5.04 91.43,6.07 107.83,6.07 109.95,8.2 111.24,8.2 117.26,14.22 117.26,15.89 119.06,17.69 119.06,18.82 121.79,21.55 121.79,24.32 119.12,26.99 119.12,31.58 v2(119.14,31.6)
  BOTTOM w0.076: UC1.H6 118.8,31.94 v2(119.14,31.6)
USB3_CRX_DTX_P2_C: length 13.7
  TOP w0.102: RU12.1 22.93,39.05 LU6.1 22.62,38.74 21.63,38.74 21.59,38.78 20.99,38.78 20.97,38.76 v4(19.71,38.76) 18.94,38.76 18.81,38.89 18.56,38.89 18.43,39.02 EU2603.2 EU2603.8 16.81,39.02 16.66,38.87 16.43,38.87 16.07,38.51 16.07,36.37 15.48,35.77 14.31,35.77 13.61,35.08 13.35,35.08 13.18,35.25 JUSB2.6
USB3_CRX_DTX_P3: length 173.1
  IN3 w0.142: v2(206.67,41.45) 206.76,41.36 207.51,41.36 207.97,41.82 208.65,41.82 210.46,43.63 215.04,43.63 215.59,43.08 216.97,43.08 218.25,44.36 218.25,44.74 219.73,46.23 221.44,46.23 223.66,44.01 223.66,29.43 223.53,29.3 223.53,21.53 211.7,9.71 155.56,9.71 152.1,13.16 150.83,13.16 150.28,13.71 150.28,15.99 149.04,17.23 147.11,17.23 146.24,18.1 146.24,19.31 146.1,19.45 145.65,19.45 143.15,21.95 143.15,25.87 143.7,26.42 143.7,27.44 143.37,27.77 141.27,27.77 140.1,28.94 140.1,30.42 139.55,30.97 138.57,30.97 137.75,30.14 134.03,30.14 133.31,29.43 131.74,29.43 131.21,29.95 131.21,30.42 130.83,30.8 130.59,30.8 128.7,32.69 128.18,32.69 128.06,32.57 123.43,32.57 121.29,34.7 120.91,34.7 120.73,34.53 119.34,34.53 119.19,34.39 v2(119.19,34.35)
  BOTTOM w0.076: UC1.H10 118.8,33.95 v2(119.19,34.35)
  BOTTOM w0.102: CX7.1 207.2,41.29 206.83,41.29 v2(206.67,41.45)
USB3_CRX_L_DTX_N3: length 5.7
  BOTTOM w0.102: J3D1.5 217.4,48.14 217.06,47.81 217.06,47.22 217.17,47.11 DX1.7 DX1.4 217.17,45.05 216.96,44.84 216.96,44.26 217.11,44.11 LX2.2 217.21,43.86 RX9.2
USB3_CRX_L_DTX_P3: length 5.8
  BOTTOM w0.102: J3D1.6 217,48.59 217.2,48.4 217.2,48.23 216.86,47.89 216.86,47.25 216.67,47.07 DX1.6 DX1.5 216.67,45.05 216.75,44.96 216.75,44.29 216.56,44.1 LX2.1 216.45,43.86 RX8.2
USB3_CRX_RD_DTX_N3: length 4.3
  BOTTOM w0.102: RX9.1 217.28,42.89 LX2.3 217.11,41.47 216.89,41.25 216.41,41.25 v4(216.08,41.58) 215.8,41.86 215.41,41.86 215.34,41.79 UX2.20
USB3_CRX_RD_DTX_P3: length 4.3
  BOTTOM w0.102: RX8.1 216.39,42.89 LX2.4 216.56,42.28 216.66,42.18 216.81,42.18 216.9,42.09 216.9,41.56 216.8,41.45 216.53,41.45 216,41.99 215.97,41.99 215.88,42.07 215.46,42.07 215.24,42.29 UX2.19
USB3_CTX_C_DRX_N3: length 5
  BOTTOM w0.102: RX4.1 218.91,42.76 LX1.3 218.78,42.63 218.79,42.62 218.79,42.09 218.43,41.74 v4(218.43,41.34) 218.43,41.04 218.79,40.68 218.79,39.91 218.4,39.52 217.58,39.52 CX11.2
USB3_CTX_C_DRX_P3: length 5.1
  BOTTOM w0.102: RX7.1 218.36,42.76 LX1.4 218.58,42.54 218.58,42.18 218.23,41.82 218.23,41.68 218.21,41.66 218.21,40.98 218.59,40.6 218.59,40 218.31,39.72 218.12,39.72 218.02,39.82 218.02,40.18 217.91,40.28 CX9.2
USB3_CTX_C_RD_DRX_N3: length 3.1
  BOTTOM w0.102: UX2.8 210.23,40.29 210.08,40.44 209.94,40.44 v4(209.53,40.04) 209.19,39.69 209.19,39.52 208.94,39.28 208.77,39.28 CX8.2
USB3_CTX_C_RD_DRX_P3: length 3.1
  BOTTOM w0.102: UX2.9 210.19,40.79 210.05,40.65 209.85,40.65 209.6,40.39 209.57,40.39 209.17,40 209.17,39.97 208.98,39.78 208.98,39.61 208.86,39.48 208.79,39.48 CX10.2
USB3_CTX_DRX_N1: length 195.1
  TOP w0.102: v2(26.68,61.6) 26.32,61.97 25.97,61.97 CU2.1
  IN3 w0.142: v2(26.68,61.6) 26.72,61.57 26.92,61.57 27.06,61.71 27.06,61.91 26.92,62.06 25.08,62.06 22.43,59.41 22.43,34.67 26.76,30.34 33.12,30.34 33.48,29.98 33.48,25.78 35.67,23.59 35.67,20.74 39.67,16.74 39.67,11.35 48.1,2.92 54.28,2.92 54.99,2.21 109.86,2.21 111.22,3.56 112.34,3.56 116.56,7.78 126.31,7.78 127.62,9.1 127.62,10.66 127.13,11.14 127.13,12.61 129.18,14.66 129.18,19.86 128.65,20.39 128.65,24.14 127.34,25.44 127.34,28.32 127.66,28.64 127.66,30.72 127.55,30.82 127.55,31.66 127.22,31.99 v2(127.22,32.01)
  BOTTOM w0.076: UC1.C13 122.12,35.72 121.96,35.72 121.85,35.61 121.85,35.5 122.1,35.25 122.25,35.25 122.47,35.47 122.47,35.77 122.54,35.85 122.77,35.93 122.91,35.93 123.1,35.87 123.25,35.87 123.37,35.93 124.45,35.93 125.84,34.54 125.84,34.12 127.22,32.74 v2(127.22,32.01)
USB3_CTX_DRX_N1_C: length 10.9
  TOP w0.102: JUSB1.8 13.18,62.51 13.29,62.62 13.54,62.62 14.34,61.82 16.66,61.82 16.81,61.67 EU2601.7 EU2601.4 18.36,61.67 18.51,61.82 18.83,61.82 18.93,61.92 19.26,61.92 19.28,61.91 19.88,61.91 19.9,61.92 v4(20.98,61.92) 21.21,61.92 21.22,61.91 22.07,61.91 22.16,61.81 LU2.4 22.61,61.65 RU3.1
USB3_CTX_DRX_N1_R: length 1.4
  TOP w0.102: RU3.2 23.53,61.65 LU2.3 24.51,61.81 CU2.2
USB3_CTX_DRX_N2: length 164.7
  TOP w0.102: CU4.1 25.88,40.58 26.26,40.96 26.43,40.96 26.63,40.76 v2(26.63,40.75)
  IN3 w0.142: v2(26.63,40.75) 26.61,40.75 26.27,41.09 25.85,41.09 25.37,40.61 25.37,34.18 28.52,31.04 33.42,31.04 34.61,29.86 34.61,27.75 34.18,27.32 34.18,26.07 36.36,23.88 36.36,21.03 40.37,17.03 40.37,11.64 48.39,3.62 54.57,3.62 55.28,2.91 109.57,2.91 110.93,4.26 111.15,4.26 115.37,8.48 120.67,8.48 121.85,9.66 122.41,9.66 122.88,9.18 126.71,9.18 126.92,9.39 126.92,10.28 126.43,10.76 126.43,12.9 128.48,14.95 128.48,19.57 127.95,20.1 127.95,23.85 126.51,25.28 126.51,30.58 126.32,30.78 126.32,31.52 125.98,31.85 v2(125.98,31.87)
  BOTTOM w0.094: v2(125.98,31.87) 126.03,31.87 126.06,31.9 126.38,32.22 126.38,32.78 124.16,35.01 123.87,35.01 123.48,35.4 123.32,35.4 123.06,35.66 UC1.B13
USB3_CTX_DRX_N2_C: length 11.5
  TOP w0.102: JUSB2.8 13.18,40.83 13.32,40.97 13.57,40.97 14.37,40.17 16.65,40.17 16.81,40.02 EU2603.7 EU2603.4 18.43,40.02 18.56,40.16 18.76,40.16 19.51,40.91 19.64,40.91 19.66,40.9 20.26,40.9 20.28,40.91 v4(21.36,40.91) 22.19,40.91 22.38,40.73 LU5.4 22.8,40.56 RU9.1
USB3_CTX_DRX_N2_R: length 1.4
  TOP w0.102: RU9.2 23.72,40.56 LU5.3 24.77,40.73 CU4.2
USB3_CTX_DRX_N3: length 165.3
  IN3 w0.142: v2(206.54,39.06) 206.56,39.06 206.89,39.4 208.34,39.4 209.11,40.17 210.02,40.17 210.74,40.88 210.74,41.78 211.63,42.68 214.65,42.68 215.2,42.13 217.36,42.13 219.2,43.97 219.2,44.35 219.58,44.72 220.96,44.72 221.65,44.03 221.65,42.45 222.71,41.39 222.71,35.62 222.1,35.01 222.1,22.94 217.13,17.97 214.84,17.97 208.82,11.95 183.03,11.95 181.87,10.79 155.82,10.79 152.5,14.11 151.86,14.11 151.71,14.25 151.71,15.96 150.07,17.6 150.07,19.09 149.72,19.45 148.1,19.45 146.96,20.59 146.11,20.59 144.1,22.6 144.1,25.47 144.65,26.03 144.65,27.84 143.7,28.79 142.97,28.79 142.96,28.79 142.63,28.79 142.2,29.23 141.69,29.23 141.05,29.87 141.05,30.81 139.95,31.92 138.18,31.92 137.35,31.09 131.88,31.09 131.22,31.75 130.98,31.75 129.06,33.68 127.6,33.68 127.46,33.82 127.46,34.05 v2(127.6,34.19)
  BOTTOM w0.076: UC1.B15 123.07,37.01 123.36,37.3 123.82,37.3 124.57,37.3 125.64,36.22 126.49,36.22 127.31,35.4 127.31,34.37 127.49,34.19 v2(127.6,34.19)
  BOTTOM w0.102: v2(206.54,39.06) 206.54,39.07 206.78,39.31 207.16,39.31 CX8.1
USB3_CTX_DRX_P1: length 195
  TOP w0.102: CU1.1 25.96,62.17 26.37,62.17 v2(26.68,62.48)
  IN3 w0.142: v2(26.68,62.48) 26.5,62.31 24.97,62.31 22.18,59.52 22.18,34.77 22.18,34.56 26.65,30.09 33.01,30.09 33.23,29.88 33.23,25.67 35.41,23.49 35.41,20.64 39.42,16.64 39.42,11.25 47.99,2.67 54.17,2.67 54.89,1.96 109.97,1.96 111.32,3.31 112.44,3.31 116.67,7.53 126.41,7.53 127.87,8.99 127.87,10.76 127.38,11.25 127.38,12.51 129.43,14.55 129.43,19.97 128.9,20.5 128.9,24.24 127.59,25.55 127.59,28.22 127.91,28.54 127.91,30.82 127.8,30.93 v2(127.8,32.01)
  BOTTOM w0.076: UC1.D13 121.72,35.78 121.73,35.78 122.16,36.02 122.51,36.02 122.74,36.09 122.93,36.09 123.05,36.06 123.24,36.06 123.34,36.09 124.52,36.09 126,34.61 126,34.19 127.38,32.81 127.38,32.36 127.74,32.01 v2(127.8,32.01)
USB3_CTX_DRX_P1_C: length 10.9
  TOP w0.102: JUSB1.9 13.18,62.93 13.29,62.82 13.63,62.82 14.43,62.03 16.66,62.03 16.81,62.17 EU2601.6 EU2601.5 18.39,62.17 18.53,62.03 18.74,62.03 18.84,62.13 v4(19.58,62.13) 20.66,62.13 20.67,62.15 21.28,62.15 21.31,62.11 21.98,62.11 22.18,62.31 LU2.1 22.61,62.48 RU4.1
USB3_CTX_DRX_P1_R: length 1.4
  TOP w0.102: RU4.2 23.53,62.48 LU2.2 24.51,62.31 CU1.2
USB3_CTX_DRX_P2: length 164.9
  TOP w0.102: CU3.1 26.14,41.17 26.45,41.17 26.52,41.23 26.52,41.23 v2(26.63,41.34)
  IN3 w0.142: v2(26.63,41.34) 25.74,41.34 25.12,40.72 25.12,34.08 28.41,30.79 33.31,30.79 34.35,29.75 34.35,27.85 33.93,27.43 33.93,25.96 36.11,23.78 36.11,20.93 40.12,16.93 40.12,11.54 48.28,3.37 54.46,3.37 55.18,2.65 109.68,2.65 111.03,4.01 111.26,4.01 115.48,8.23 120.78,8.23 121.95,9.4 122.31,9.4 122.78,8.93 126.82,8.93 127.17,9.28 127.17,10.38 126.69,10.87 126.69,12.8 128.73,14.84 128.73,19.68 128.2,20.21 128.2,23.95 126.77,25.39 126.77,30.69 126.57,30.89 v2(126.57,31.87)
  BOTTOM w0.094: UC1.A13 123.94,35.2 124.23,35.2 126.57,32.86 v2(126.57,31.87)
USB3_CTX_DRX_P2_C: length 11.3
  TOP w0.102: JUSB2.9 13.18,41.31 13.32,41.17 13.65,41.17 14.45,40.38 16.66,40.38 16.81,40.52 EU2603.6 EU2603.5 18.45,40.52 18.61,40.36 18.67,40.36 19.43,41.12 v4(19.96,41.12) 21.04,41.12 21.05,41.13 21.66,41.13 21.67,41.12 22.28,41.12 22.29,41.11 22.31,41.11 22.43,41.23 LU5.1 22.8,41.4 RU10.1
USB3_CTX_DRX_P2_R: length 1.4
  TOP w0.102: RU10.2 23.72,41.4 LU5.2 24.77,41.23 CU3.2
USB3_CTX_DRX_P3: length 165.3
  IN3 w0.142: v2(126.99,34.19) 127.21,33.97 127.21,33.71 127.5,33.42 128.95,33.42 130.88,31.5 131.12,31.5 131.55,31.07 131.78,30.84 137.46,30.84 138.28,31.67 139.84,31.67 140.8,30.71 140.8,29.76 141.59,28.98 142.09,28.98 142.53,28.54 142.86,28.54 143.59,28.54 144.4,27.73 144.4,26.13 143.85,25.58 143.85,22.5 146.01,20.34 146.86,20.34 148,19.2 149.61,19.2 149.82,18.99 149.82,17.5 151.46,15.86 151.46,14.15 151.75,13.86 152.39,13.86 155.71,10.54 181.98,10.54 183.14,11.7 208.93,11.7 214.95,17.72 217.23,17.72 222.35,22.84 222.35,34.9 222.96,35.51 222.96,41.5 221.91,42.55 221.91,44.13 221.06,44.98 219.47,44.98 218.95,44.45 218.95,44.44 218.95,44.07 217.26,42.38 215.3,42.38 214.75,42.93 211.53,42.93 210.48,41.89 210.48,40.99 209.92,40.42 209.01,40.42 208.23,39.65 v2(206.54,39.65)
  BOTTOM w0.076: v2(126.99,34.19) 127.15,34.34 127.15,35.33 126.42,36.05 125.58,36.05 124.5,37.13 123.59,37.13 UC1.A15
  BOTTOM w0.102: CX10.1 207.2,39.52 206.67,39.52 v2(206.54,39.65)
USB3_CTX_L_DRX_N3: length 5.7
  BOTTOM w0.102: J3D1.2 218.6,48.37 218.5,48.28 218.5,47.35 218.67,47.18 DX1.10 DX1.1 218.67,45.19 218.52,45.04 218.52,44.79 218.71,44.6 218.71,44.35 218.91,44.15 LX1.2 219.08,43.84 RX4.2
USB3_CTX_L_DRX_P3: length 5.6
  BOTTOM w0.102: J3D1.3 218.2,48.37 218.3,48.28 218.3,47.31 218.17,47.19 DX1.9 DX1.2 218.17,45.2 218.32,45.06 218.32,44.7 218.51,44.51 218.51,44.27 218.36,44.12 LX1.1 218.19,43.84 RX7.2
USB3_CTX_RD_DRX_N3: length 2.5
  BOTTOM w0.102: UX2.23 215.21,40.29 215.35,40.44 215.5,40.44 215.6,40.34 215.6,39.97 215.82,39.75 216.19,39.75 CX11.1
USB3_CTX_RD_DRX_P3: length 2.5
  BOTTOM w0.102: UX2.22 215.22,40.79 215.36,40.65 215.58,40.65 215.8,40.43 215.8,40.06 215.91,39.96 216.21,39.96 CX9.1
USB3_DE1_P0: length 3.2
  TOP w0.102: RX29.2 213.35,38.6 v2(212.93,38.17) 212.93,37.82 v1(213.11,37.64)
  BOTTOM w0.102: UX2.3 212.99,38.24 v2(212.93,38.17) 212.93,38.17 RX28.2
USB3_DE2_P0: length 3.6
  TOP w0.102: v1(213.44,43.59) 213.44,43.59 v2(213.44,44.35) 213.57,44.47 RX23.2
  BOTTOM w0.102: UX2.16 212.99,43.73 213.38,44.12 213.38,44.28 v2(213.44,44.35) 213.57,44.47 RX23.2
USB3_EQ1_P0: length 3.3
  TOP w0.102: v2(213.74,38.17) 214.34,38.17 214.35,38.17 RX31.2 214.4,37.31 v1(214.32,37.23)
  BOTTOM w0.102: UX2.2 213.49,38.42 v2(213.74,38.17) 213.82,38.09 RX30.2
USB3_EQ2_P0: length 4.1
  TOP w0.102: RX25.2 214.46,44.78 v2(214.03,44.35) v1(214.73,43.64)
  BOTTOM w0.102: RX25.2 214.46,44.78 v2(214.03,44.35) 214.01,44.33 214.01,44.22 213.49,43.7 UX2.17
USB3_ERD_P0: length 3.5
  TOP w0.102: RX19.2 211.16,38.73 v2(211.71,38.17) 211.45,37.91 v1(211.02,37.91)
  BOTTOM w0.102: UX2.5 211.99,38.45 v2(211.71,38.17) 211.16,37.62 RX18.2
USB3_OS1_P0: length 3.7
  TOP w0.102: RX27.2 212.49,38.75 212.31,38.57 v2(212.31,38.17) 212.31,37.4 v1(211.97,37.06)
  BOTTOM w0.102: RX26.2 212.05,37.91 v2(212.31,38.17) 212.49,38.36 UX2.4
USB3_OS2_P0: length 3.5
  TOP w0.102: RX21.2 212.68,44.23 v2(212.6,44.16) v1(212.16,43.71)
  BOTTOM w0.102: RX21.2 212.68,44.23 v2(212.6,44.16) 212.49,44.05 UX2.15
USB3_P0_PIN6: length 4.3
  TOP w0.102: v2(210.49,38.17) 210.27,38.4 RX12.2 209.87,38.81 v1(209.28,38.22)
  BOTTOM w0.102: RX11.2 210.27,37.95 v2(210.49,38.17) 211.02,38.17 211.49,38.65 UX2.6
USB3_P0_PIN18: length 4.5
  TOP w0.102: v2(214.74,44.35) 215.35,44.96 RX15.2 215.89,44.97 v1(216.28,45.36)
  BOTTOM w0.102: UX2.18 213.99,43.6 v2(214.74,44.35) 215.35,44.96 RX15.2
USB20_VCCA: length 36.5
  TOP w0.102: v3(167.16,4.27) 167.48,3.96 v2(168.68,3.96) ; v3(170.31,4.2) 170.07,3.96 v2(169.31,3.96) ; v3(168.87,5.5) 168.68,5.31 v2(168.68,4.59)
  IN2 w2.032: 167.03,3.96 162.45,3.96 160.87,2.37 134.89,2.37
  vias: v2(132.89,3.7) v2(133.45,3.7) v2(133.7,3.2) v2(169.26,4.59)
USB30_VCCA: length 11.1
  BOTTOM w2.032: 17.1,51.26 17.1,51.26 17.1,62.38
  vias: v2(15.7,64.79) v2(15.7,64.1) v2(15.7,43.14) v2(15.7,42.44) v2(16.34,64.79) v2(16.34,64.1) v2(16.34,43.14) v2(16.34,42.44) v3(16.64,50.65)
USB_CAMERA_EDP: length 2.7
  BOTTOM w0.102: JEDP1.32 223.52,34.55 223.35,34.72 v4(222.78,34.72) 222.29,34.72 222.21,34.64 L3.4 221.58,34.47 R18.1
USB_CAMERA_EDP#: length 2.7
  BOTTOM w0.102: JEDP1.31 223.44,35.05 223.31,34.93 223.08,34.93 223.06,34.95 222.33,34.95 222.15,35.14 L3.1 221.58,35.3 R17.1
USB_EN#: length 172.3
  TOP w0.102: UU1.4 v2(19.58,47.26)
  IN3 w0.142: v2(19.58,47.26) 19.83,47.02 19.83,40.21 20.29,39.76 20.29,34.43 27.99,26.73 29.57,26.73 31.24,25.06 32.83,25.06 34.7,23.19 34.7,20.34 38.7,16.34 38.7,10.95 48.41,1.24 123.41,1.24 v2(124.48,2.31)
  BOTTOM w0.102: v2(124.48,2.31) 125.37,3.2 v1(125.37,6.76) 125.37,8.49 UU3.4 125.02,9.33 126.13,10.44 126.13,11.39 128.43,13.69 128.43,15.32 129.5,16.38 129.5,20.41 130.23,21.14 134.96,21.14 135.12,21.31 135.12,23.62 135.65,24.15 136.55,24.15 136.8,24.4 137.94,24.4 RE17.1 138.82,24.43 138.82,24.04 139.28,23.58 UE1.13
USB_OC#0_1: length 178.5
  TOP w0.102: UU1.3 v2(18.68,47.26)
  IN3 w0.142: v2(18.68,47.26) 19.11,47.69 19.76,47.69 20.1,47.35 20.1,40.32 20.56,39.87 20.56,34.54 28.1,27 29.68,27 31.36,25.33 32.94,25.33 34.97,23.31 34.97,20.45 38.97,16.45 38.97,11.06 48.52,1.51 110.15,1.51 111.51,2.86 112.63,2.86 114.46,4.7 116.78,4.7 118.6,6.52 126.03,6.52 128.32,8.81 128.32,10.95 127.83,11.43 127.83,12.32 130.77,15.26 130.77,19.71 129.88,20.6 129.88,30.88 v2(129.02,31.74)
  BOTTOM w0.102: UC1.A9 123.96,33.19 125.24,31.9 125.24,31.66 125.64,31.27 126.1,31.27 126.31,31.06 127.54,31.06 127.94,31.47 128.75,31.47 v2(129.02,31.74) 129.12,31.84 130.13,31.84 130.25,31.96 RPC1.3
USB_OC#2_3: length 36.9
  IN3 w0.142: v2(125.88,9.61) 125.88,13.63 128.03,15.79 128.03,19.39 127.5,19.92 127.5,23.66 126.07,25.1 126.07,30.37 v2(124.3,32.14)
  BOTTOM w0.102: v2(125.88,9.61) 125.88,9.07 126.1,8.84 UU3.3 ; UC1.C9 122.4,33.19 122.7,32.89 123.55,32.89 v2(124.3,32.14) 124.5,32.14 125.56,31.08 126.02,31.08 126.23,30.87 127.62,30.87 128.02,31.28 129.61,31.28 129.79,31.46 RPC1.2
USB_OC#4_5: length 11.6
  TOP w0.102: v2(121.33,32.71) v1(123.65,32.71) 124.36,32.71 124.8,32.28 124.8,31.58 125.89,30.49 v2(127.23,30.49)
  BOTTOM w0.076: RPC1.1 130.19,30.96 130.05,31.1 128.1,31.1 127.49,30.49 127.28,30.49 127.27,30.5 127.27,30.49 v2(127.23,30.49) ; UC1.D9 121.33,32.99 v2(121.33,32.71)
USB_OC#6_7: length 9.7
  BOTTOM w0.076: RPC1.4 130.24,32.46 129.99,32.21 128.89,32.21 128.33,31.65 127.87,31.65 127.46,31.24 126.38,31.24 126.17,31.44 125.71,31.44 125.49,31.66 125.49,32.13 v1(124.93,32.69) 124.17,33.45 123.15,33.45 122.88,33.19 UC1.B9
USB_PN1: length 144.2
  TOP w0.102: RU1.2 26.42,57.7 LU1.2 26.92,57.68 27.06,57.54 27.76,57.54 27.78,57.56 28.34,57.56 28.36,57.54 v2(29.61,57.54)
  IN3 w0.089: v2(112.89,32.95) 112.72,32.95 112.61,32.95 112.34,32.68 112.34,29.95 112.13,29.74
  IN3 w0.142: v2(29.61,57.54) 29.49,57.43 29.01,57.43 28.72,57.14 28.72,56.11 29.51,55.32 29.51,36.15 30.75,34.91 34.75,34.91 40.24,29.42 40.24,22.28 43.99,18.53 43.99,17.79 46.52,15.26 47.02,15.26 52.71,9.56 55.96,9.56 57.01,8.51 62.23,8.51 63.24,9.52 88.81,9.52 89.88,10.6 95.19,10.6 95.8,11.2 96.58,11.2 97.01,10.77 98.33,10.77 98.83,11.27 103.71,11.27 106,13.55 106,16.13 105.68,16.45 105.68,17.99 107.15,19.46 107.15,23.01 109.75,25.61 109.75,26.15 110.89,27.29 110.89,28.5 112.13,29.74
  BOTTOM w0.076: UC1.AB9 v2(112.89,32.95)
USB_PN1_C: length 13.9
  TOP w0.102: RU1.1 25.17,57.7 LU1.1 24.85,57.68 24.64,57.47 24.12,57.47 24.1,57.49 23.47,57.49 23.45,57.47 v4(22.13,57.47) 21.9,57.47 21.89,57.49 20.21,57.49 20.11,57.59 20.11,58.08 EU2602.3 19.6,58.08 19.6,57.73 19.37,57.49 19.11,57.49 v2(18.98,57.62)
  IN1 w0.119: v2(18.98,57.62) 18.75,57.39 17.94,57.39 15.53,59.81 14.93,59.81 14.68,60.06 JUSB1.2
USB_PN2: length 117.7
  TOP w0.102: v2(31.29,36.37) 31.5,36.15 31.5,36 31.28,35.78 27.54,35.78 27.43,35.9 LU4.2 26.76,36.07 RU8.1
  IN3 w0.089: 111.05,29.74 111.33,30.02 111.33,31.07 111.46,31.19 111.59,31.19 v2(111.79,30.99)
  IN3 w0.142: v2(31.29,36.37) 31.45,36.2 31.45,35.96 31.73,35.69 35.06,35.69 40.94,29.8 40.94,22.57 44.69,18.82 44.69,18.58 53,10.26 56.25,10.26 57.3,9.21 61.94,9.21 62.99,10.26 82.11,10.26 82.52,10.67 87.75,10.67 88.62,11.54 93.65,11.54 94.22,12.11 102.09,12.11 102.67,12.11 104.98,14.42 104.98,18.28 105.49,18.79 105.49,21.39 106.11,22.02 106.11,22.96 109.05,25.9 109.05,26.44 109.3,26.69 109.3,28.21 110.13,29.04 110.36,29.04 111.05,29.74
  BOTTOM w0.102: v2(111.79,30.99) UC1.AD6
USB_PN2_C: length 14.5
  TOP w0.102: RU8.2 25.85,36.07 LU4.1 25.49,35.9 25.34,35.75 24.4,35.75 24.39,35.77 23.69,35.77 23.67,35.75 v4(22.56,35.75) 20.53,35.75 20.43,35.85 20.43,36.36 EU2604.3 19.92,36.36 19.92,35.88 19.82,35.77 19.42,35.77 v2(19.3,35.9)
  IN1 w0.119: v2(19.3,35.9) 19.14,35.74 17.9,35.74 15.53,38.11 14.8,38.11 14.68,38.23 JUSB2.2
USB_PN3: length 102.1
  TOP w0.102: v2(108.49,30.63) 108.21,30.44 108.18,30.3 108.18,30.3 108.25,30.2 108.41,30.04 108.41,27.69 108.57,27.54 108.57,26.96 110.6,24.93 111.23,24.93 112.11,24.05 112.11,22.99 112.56,22.53 112.56,19.66 113.03,19.2 113.03,16.18 114.21,14.99 117.41,14.99 121.54,10.86 124.66,10.86 125.45,10.07 125.45,8.74 127.99,6.19 132.75,6.19 133.41,5.53 134.04,5.53 134.14,5.63 134.14,5.79 v2(133.97,5.96)
  IN1 w0.119: v2(133.97,5.96) 134.14,5.79 134.14,4.14 136.41,1.87 150.07,1.87 153.02,4.82 165.85,4.82 166.14,5.1 166.14,5.42 v2(166.33,5.61)
  BOTTOM w0.076: v2(108.49,30.63) 108.49,30.36 UC1.AH3
  BOTTOM w0.102: RU14.1 173.71,19.59 LU7.3 173.05,19.75 172.9,19.9 167.98,19.9 166.45,18.37 166.45,10.11 166.06,9.72 166.06,5.87 v2(166.33,5.61)
USB_PN3_C: length 6.5
  BOTTOM w0.102: RU14.2 174.8,19.73 LU7.4 175.3,19.75 175.45,19.89 v4(176.17,19.89) 176.6,19.89 177.11,19.39 177.11,19.37 177.66,18.81 178.77,18.81 179.1,18.48 179.1,18.34 179,18.24 178.71,18.24 178.6,18.13 JIOB1.8
USB_PN5: length 163.4
  IN1 w0.119: v2(108.71,21.53) 108.71,21.53 109.08,21.17 110.23,21.17 111.41,19.98 117.65,19.98 118.28,19.36 121.3,19.36 122.6,20.65 127.83,20.65 128.23,20.25 131.23,20.25 132.49,21.5 132.49,21.63 134.87,24.01 134.87,25.09 138.22,28.45 138.99,28.45 141.4,30.86 142.53,30.86 142.9,31.22 144.55,31.22 146.13,29.64 151.98,29.64 152.87,30.53 157.2,30.53 158.1,29.64 158.1,27.22 159.13,26.19 159.13,25.45 159.13,25.18 159.31,25.01 159.31,23.95 159.76,23.5 159.76,21.13 161.77,19.11 165.07,19.11 165.69,18.49 165.69,16.58 170.55,11.72 175.87,11.72 176.08,11.92 181.1,11.92 181.51,12.33 184.48,12.33 184.9,11.91 192.2,11.91 192.47,12.18 201.28,12.18 201.58,11.89 203.74,11.89 205.68,13.83 206.18,13.83 211.33,13.83 212.46,14.97 215.58,14.97 217.16,16.56 217.17,16.56 217.41,16.8 217.41,16.81 220.17,19.57 220.17,32.11 219,33.28 219,34.72 219.25,34.97 219.46,34.97 v2(219.66,35.18)
  BOTTOM w0.076: 107.08,24.1 107.08,24.12 107.06,24.14 107.06,26.23 107.75,26.92 107.75,28.62 107.84,28.71 107.95,28.71 108.03,28.63 UC1.AJ1
  BOTTOM w0.102: R17.2 220.5,35.16 L3.2 220.36,34.99 220.03,34.99 220,34.96 219.88,34.96 v2(219.66,35.18) ; 107.08,24.1 107.08,22.01 107.94,21.15 108.34,21.15 108.71,21.52 v2(108.71,21.53)
USB_PN6: length 111.2
  TOP w0.102: v2(110.57,31.58) 110.48,31.67 110.31,31.67 110.14,31.51 110.14,31.16 109.18,30.19 109.18,27.22 110.56,25.83 111.98,25.83 112.94,24.87 112.94,24.07 112.79,23.93 112.79,23.27 113.25,22.81 113.25,19.95 113.71,19.48 113.71,16.36 114.47,15.61 117.77,15.61 121.91,11.47 126.21,11.47 127.16,10.52 127.16,7.94 128.3,6.8 134.57,6.8 135.05,7.28 135.05,7.66 137.24,9.86 137.24,10.6 139.9,13.26 145.31,13.26 147.82,10.75 147.82,5.95 150.18,3.59 160.02,3.59 160.23,3.8 160.46,3.8 167.17,10.51 173.35,10.51 177.45,14.61 177.45,16.53 178.12,17.2 178.12,19.4 v2(177.95,19.58)
  BOTTOM w0.076: UC1.AF6 110.21,31.31 110.56,31.31 110.65,31.4 110.65,31.51 v2(110.57,31.58)
  BOTTOM w0.102: v2(177.95,19.58) 178.14,19.77 178.14,19.99 178.36,20.21 179.03,20.21 179.11,20.13 179.2,20.13 179.32,20.25 LU8.2 179.72,20.41 RU15.1
USB_PN6_C: length 4.9
  BOTTOM w0.102: RU15.2 180.65,20.42 LU8.1 181.08,20.25 181.18,20.15 181.5,20.15 181.53,20.12 182.19,20.12 182.2,20.1 182.35,20.1 182.91,19.54 182.91,19.47 v4(183.08,19.31) 183.35,19.04 183.35,18.24 183.6,17.99 JIOB1.3
USB_PN7: length 150.7
  IN1 w0.119: v2(219.73,24.98) 219.6,24.85 219.6,24.85 219.36,24.61 219,24.61 218.71,24.32 218.71,20.08 216.7,18.06 214.48,18.06 211.38,14.97 203.85,14.97 201.7,12.82 192.2,12.82 191.93,12.55 185.16,12.55 184.74,12.97 176.22,12.97 175.61,12.36 173.02,12.36 169.39,16 167.73,16 166.55,17.19 166.55,19.03 165.82,19.75 162.27,19.75 160.4,21.63 160.4,24.11 159.95,24.56 159.95,25.28 159.78,25.45 159.78,26.46 158.74,27.49 158.74,29.95 157.51,31.18 155.61,31.18 155.12,31.66 153.09,31.66 152.6,31.18 151.74,30.31 149.97,30.31 149.61,30.68 149.61,31.03 149.29,31.34 145.34,31.34 144.82,31.86 142.63,31.86 142.27,31.5 141.13,31.5 138.72,29.09 137.96,29.09 134.17,25.3 134.17,24.3 131.44,21.57 130.31,21.57 130.03,21.29 128.1,21.29 128.09,21.3 120.99,21.3 120.32,20.63 111.88,20.63 109.91,22.6 109.62,22.6 109.54,22.68 109.37,22.68 108.86,23.2 v2(108.86,23.28)
  BOTTOM w0.076: 107.7,24.1 107.7,24.12 107.68,24.14 107.68,26.22 108.33,26.87 108.33,28.13 108.45,28.25 108.45,28.82 108.54,28.91 108.65,28.91 UC1.AH1
  BOTTOM w0.102: v2(108.86,23.28) 108.88,23.28 108.99,23.18 108.99,22.98 108.88,22.88 108.58,22.88 108.4,22.7 108.28,22.7 107.7,23.29 107.7,24.1 ; R20.2 220.71,25.73 L4.2 220.88,25.16 221.1,24.94 221.1,24.71 220.99,24.6 220.1,24.6 219.73,24.97 v2(219.73,24.98)
USB_PN7_TPNL: length 12
  BOTTOM w0.102: JEDP1.36 223.3,32.55 223.16,32.41 222.64,32.41 222.09,32.96 v4(221.43,32.96) 220.76,32.96 220.26,32.46 220.26,31.58 220.16,31.48 219.78,31.48 DA6.2 219.59,30.91 220.16,30.91 220.26,30.81 220.26,30.44 221.13,29.58 221.13,28.03 221.02,27.92 221.02,27.46 220.88,27.31 L4.1 220.71,26.64 R20.1
USB_PN8: length 160.9
  IN3 w0.142: v2(109.61,32.82) 109.43,33 109.16,33 107.35,31.18 107.35,30.92 106.83,30.4 106.83,27.84 102.87,23.88 102.87,23.02 100.3,20.45 98.68,20.45 95.45,17.22 90.24,17.22 89.44,16.41 83.92,16.41 82.95,15.44 82.26,15.44 79.96,13.13 77.84,13.13 77.24,12.53 62,12.53 60.98,11.51 58.44,11.51 57.42,12.53 56.08,12.53 52.21,16.4 51.04,16.4 49.19,18.25 48.33,18.25 47.38,19.2 47.38,20.14 44.17,23.35 44.17,31.88 39.84,36.22 39.84,91.68 39.69,91.82 39.06,91.82 v2(38.94,91.7)
  BOTTOM w0.102: RW1.2 42.79,96.38 LW1.3 42.62,95.71 42.48,95.56 42.48,93.92 40.47,91.91 39.15,91.91 v2(38.94,91.7) ; v2(109.61,32.82) 109.87,32.56 UC1.AF8
USB_PN8_R: length 4.2
  BOTTOM w0.102: JWLAN1.5 44.05,99.25 43.9,99.11 43.9,98.74 43.52,98.35 v4(43.17,98.35) 42.58,98.35 42.48,98.25 42.48,98.11 42.62,97.96 LW1.4 42.79,97.29 RW1.1
USB_PP1: length 143.8
  TOP w0.102: RU2.2 26.42,57.15 LU1.3 26.92,57.18 27.08,57.34 v4(28.06,57.34) 29.23,57.34 v2(29.61,56.96)
  IN3 w0.089: v2(112.72,33.6) 112.8,33.52 112.8,33.39 112.16,32.76 112.16,30.13 111.78,29.74
  IN3 w0.142: 111.78,29.74 110.64,28.6 110.64,27.39 109.5,26.25 109.5,25.71 106.9,23.12 106.9,19.57 105.43,18.1 105.43,16.34 105.75,16.03 105.75,13.66 103.61,11.52 98.72,11.52 98.23,11.02 97.11,11.02 96.68,11.45 95.7,11.45 95.09,10.85 89.77,10.85 88.7,9.78 63.14,9.78 62.13,8.77 57.11,8.77 56.06,9.82 52.81,9.82 47.12,15.51 46.63,15.51 44.24,17.9 44.24,18.64 40.49,22.39 40.49,29.53 34.86,35.16 30.86,35.16 29.77,36.25 29.77,55.43 28.98,56.22 28.98,57.03 29.12,57.17 29.39,57.17 v2(29.61,56.96)
  BOTTOM w0.076: UC1.AB10 112.23,33.76 112.26,33.66 112.45,33.54 v2(112.72,33.6)
USB_PP1_C: length 14.1
  TOP w0.102: v2(18.98,57.03) 19.23,57.29 19.48,57.29 19.6,57.16 19.6,56.65 EU2602.2 20.11,56.65 20.11,57.16 20.23,57.28 21.8,57.28 21.83,57.25 22.41,57.25 22.42,57.26 v4(23.79,57.26) 24.75,57.26 24.84,57.18 LU1.4 25.17,57.15 RU2.1
  IN1 w0.119: v2(18.98,57.03) 18.84,57.17 17.85,57.17 15.44,59.59 14.8,59.59 14.68,59.47 JUSB1.3
USB_PP2: length 117.6
  TOP w0.102: RU7.1 26.76,35.23 LU4.3 27.19,35.4 27.37,35.58 31.37,35.58 31.71,35.92 31.71,36.21 v2(31.87,36.37)
  IN3 w0.089: v2(111.79,31.6) 111.79,31.57 111.59,31.37 111.39,31.37 111.16,31.14 111.16,30.2 110.83,29.87
  IN3 w0.142: v2(31.87,36.37) 31.71,36.2 31.71,36.08 31.85,35.94 35.16,35.94 41.19,29.91 41.19,22.68 44.94,18.93 44.94,18.68 53.1,10.51 56.35,10.51 57.4,9.46 61.84,9.46 62.89,10.51 82,10.51 82.42,10.93 87.65,10.93 88.51,11.79 93.54,11.79 94.11,12.36 102.19,12.36 102.56,12.36 104.73,14.52 104.73,18.39 105.24,18.89 105.24,21.49 105.86,22.12 105.86,23.07 108.8,26 108.8,26.54 109.05,26.8 109.05,28.32 110.03,29.29 110.25,29.29 110.83,29.87
  BOTTOM w0.102: UC1.AD7 111.76,31.59 v2(111.79,31.6)
USB_PP2_C: length 14.7
  TOP w0.102: RU7.2 25.85,35.23 LU4.4 25.41,35.4 25.26,35.54 v4(24.09,35.54) 22.88,35.54 22.86,35.53 22.26,35.53 22.24,35.54 20.53,35.54 20.43,35.44 20.43,34.94 EU2604.2 19.92,34.94 19.92,35.44 19.79,35.57 19.55,35.57 v2(19.3,35.32)
  IN1 w0.119: JUSB2.3 14.68,37.77 14.8,37.89 15.44,37.89 17.81,35.52 19.09,35.52 v2(19.3,35.32)
USB_PP3: length 102.2
  TOP w0.102: v2(134.55,5.96) 134.35,5.76 134.35,5.55 134.13,5.32 133.32,5.32 132.66,5.99 127.91,5.99 125.24,8.65 125.24,9.99 124.58,10.65 121.46,10.65 117.32,14.79 114.13,14.79 112.82,16.1 112.82,19.11 112.36,19.58 112.36,22.44 111.9,22.9 111.9,23.97 111.14,24.73 110.51,24.73 108.36,26.88 108.36,27.46 108.21,27.61 108.21,29.95 108.1,30.06 108.02,30.18 107.87,30.2 v2(107.59,30.01)
  IN1 w0.119: v2(165.74,5.61) 165.92,5.43 165.92,5.19 165.76,5.03 152.93,5.03 149.98,2.09 136.5,2.09 134.36,4.23 134.36,5.77 v2(134.55,5.96)
  BOTTOM w0.076: UC1.AJ3 107.86,30.01 v2(107.59,30.01)
  BOTTOM w0.102: RU13.1 173.71,20.41 LU7.2 173.04,20.25 172.9,20.1 167.9,20.1 166.25,18.45 166.25,10.2 165.86,9.81 165.86,5.72 v2(165.74,5.61)
USB_PP3_C: length 6.6
  BOTTOM w0.102: JIOB1.7 179.6,18.03 179.3,18.32 179.3,18.57 178.85,19.02 177.77,19.02 v4(177.48,19.31) 176.69,20.1 176.46,20.1 176.45,20.12 175.89,20.12 175.88,20.1 175.45,20.1 175.3,20.25 LU7.1 174.8,20.25 RU13.2
USB_PP5: length 163.7
  IN1 w0.119: v2(108.71,20.95) 110.14,20.95 111.32,19.77 117.56,19.77 118.19,19.14 121.39,19.14 122.69,20.43 127.74,20.43 128.14,20.03 131.32,20.03 132.71,21.41 132.71,21.54 135.08,23.92 135.08,25 138.31,28.23 139.08,28.23 141.49,30.64 142.63,30.64 142.99,31 144.46,31 146.04,29.43 152.07,29.43 152.96,30.31 157.11,30.31 157.88,29.55 157.88,27.13 158.92,26.1 158.92,25.54 158.92,25.09 159.09,24.92 159.09,23.86 159.54,23.41 159.54,21.04 161.68,18.89 164.98,18.89 165.47,18.4 165.47,17.51 165.47,17.51 165.47,17.46 165.47,17.46 165.47,16.49 170.46,11.5 175.97,11.5 176.17,11.7 181.19,11.7 181.6,12.11 184.39,12.11 184.81,11.69 192.29,11.69 192.56,11.96 201.19,11.96 201.49,11.67 203.83,11.67 205.78,13.61 206.27,13.61 207.03,13.61 207.03,13.61 207.21,13.61 211.42,13.61 212.55,14.75 215.67,14.75 217.25,16.34 217.26,16.34 217.63,16.71 217.63,16.72 220.39,19.48 220.39,32.2 219.22,33.37 219.22,34.63 219.34,34.75 219.54,34.75 219.66,34.63 v2(219.66,34.59)
  BOTTOM w0.076: 106.88,24.1 106.88,24.12 106.9,24.14 106.9,26.3 107.59,26.99 107.59,28.69 108.03,29.13 UC1.AJ2
  BOTTOM w0.102: v2(108.71,20.95) 107.85,20.95 106.88,21.92 106.88,24.1 ; R18.2 220.5,34.61 L3.3 220.5,34.69 220.4,34.79 220.12,34.79 220.08,34.75 219.82,34.75 v2(219.66,34.59)
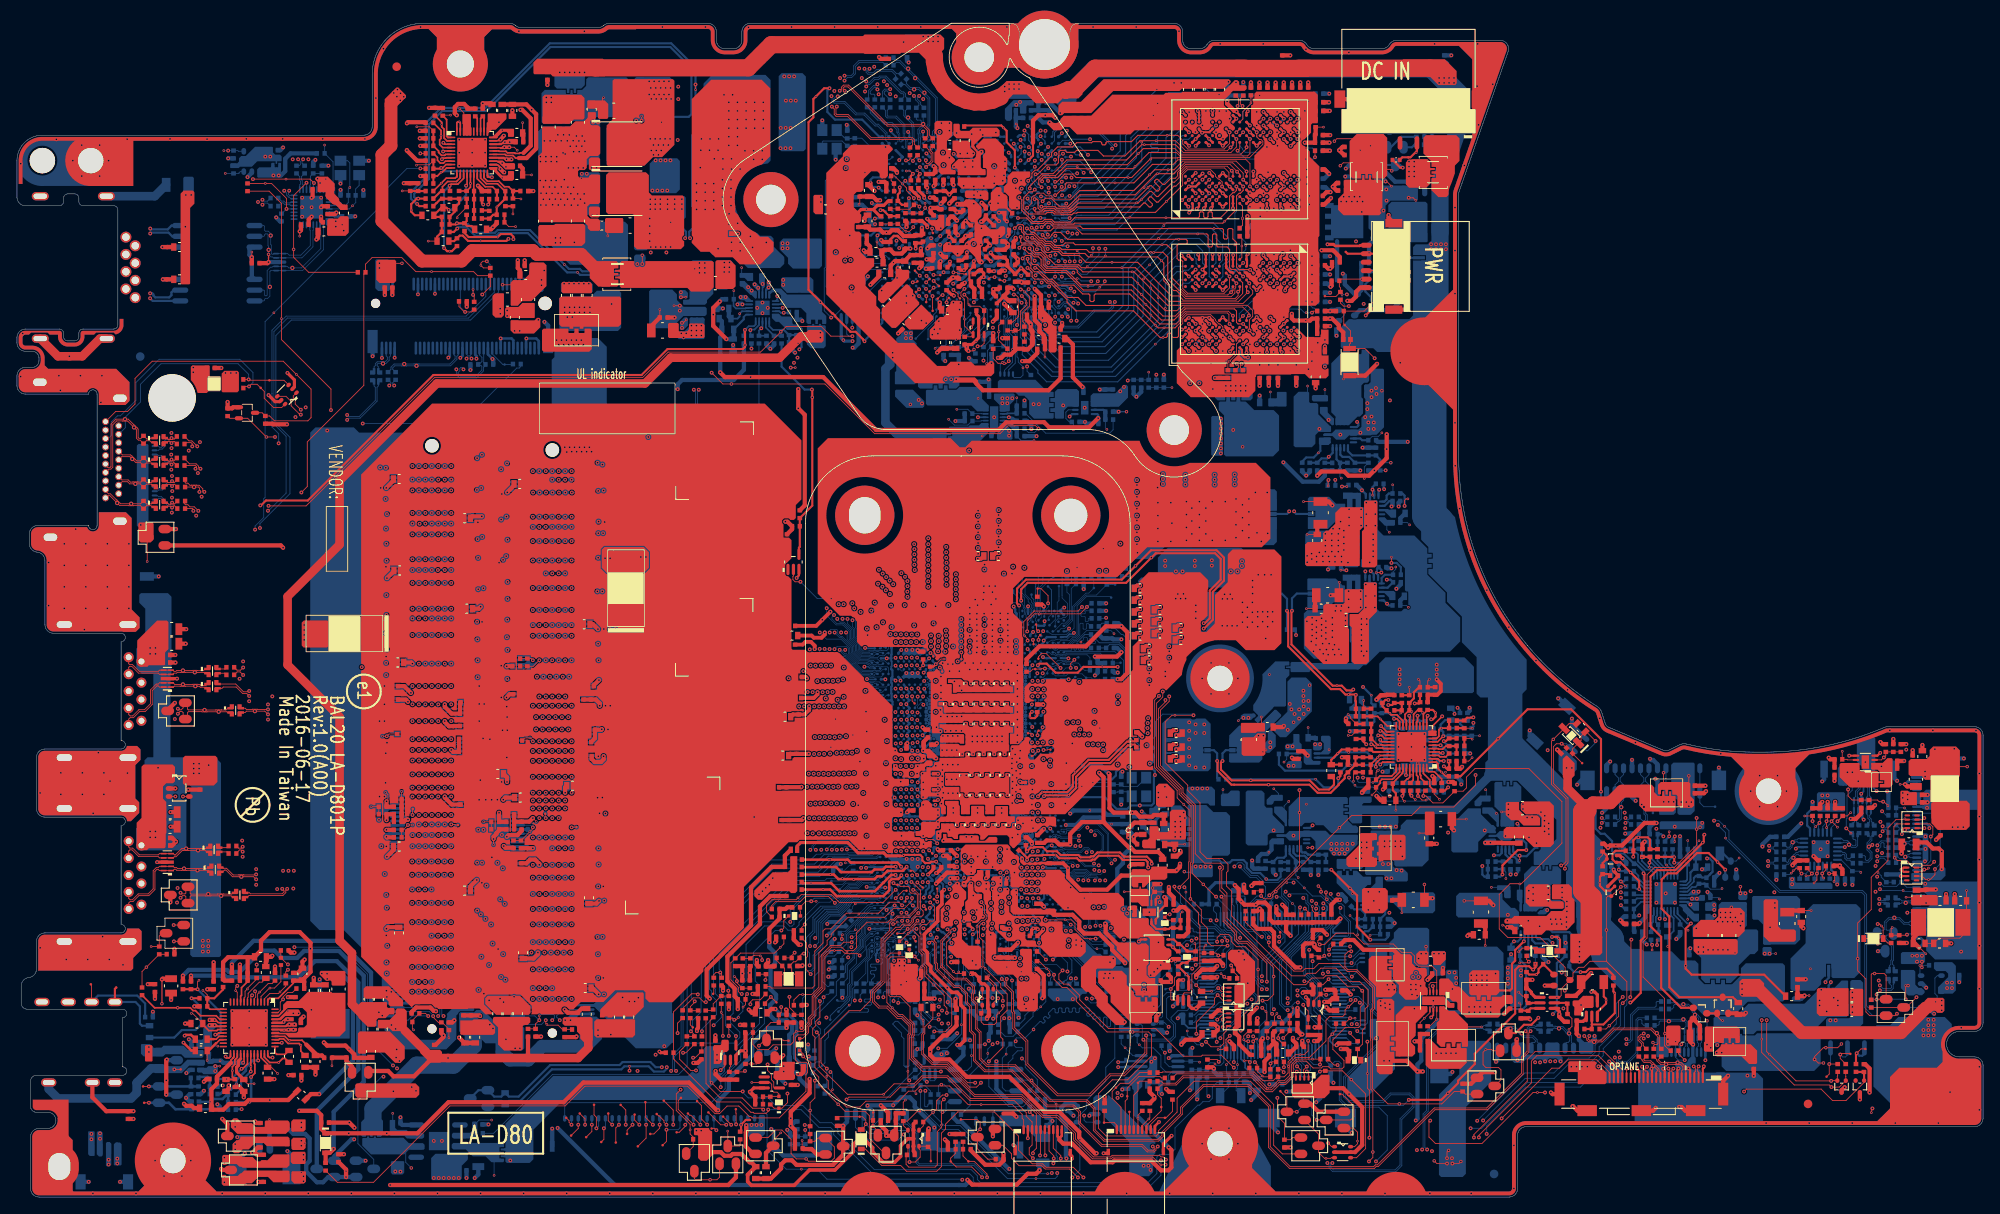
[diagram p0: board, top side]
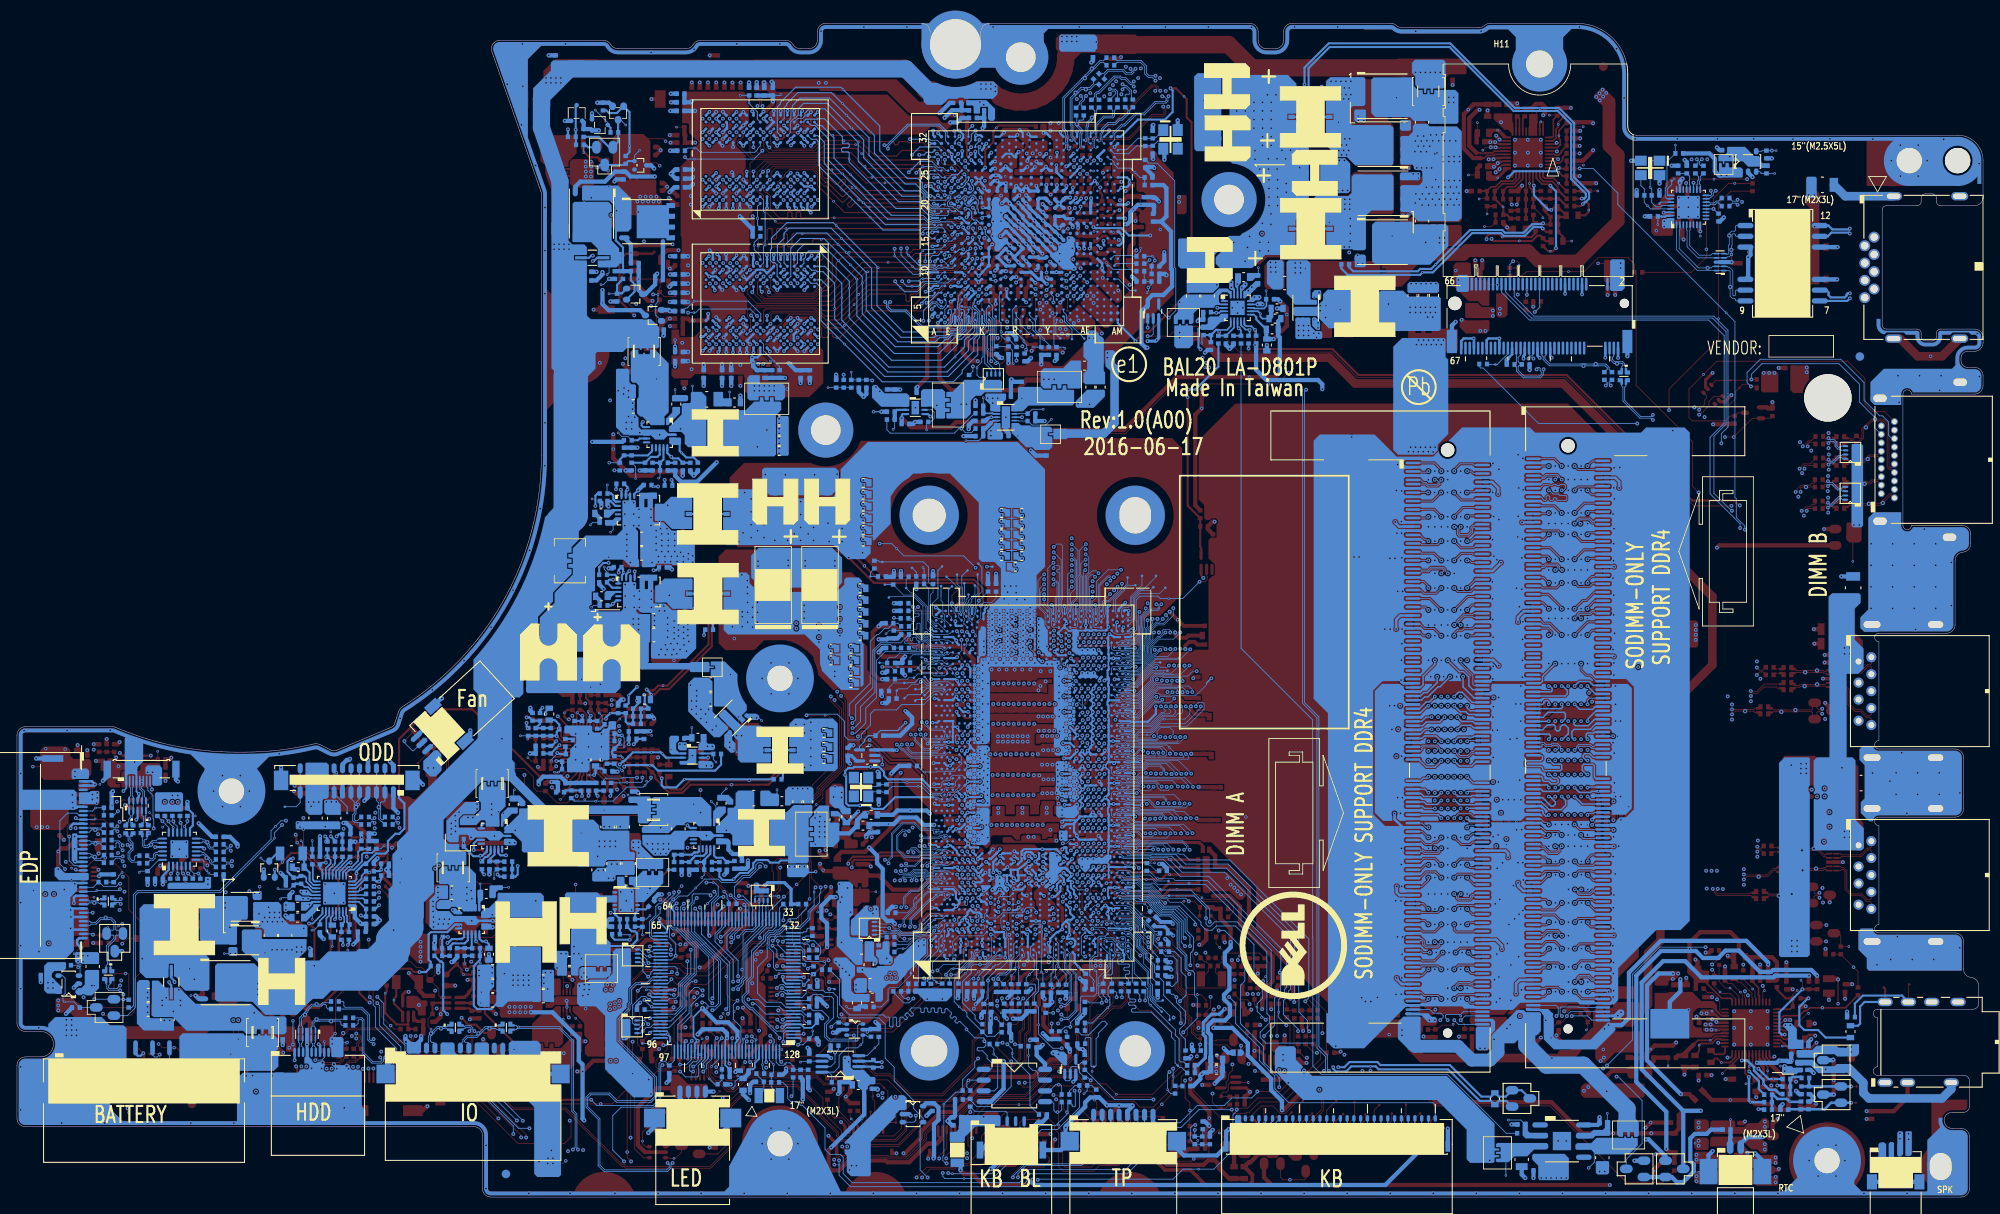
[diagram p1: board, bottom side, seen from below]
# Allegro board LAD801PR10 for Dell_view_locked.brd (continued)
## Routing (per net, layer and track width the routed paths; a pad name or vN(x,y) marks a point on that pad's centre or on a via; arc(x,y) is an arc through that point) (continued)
USB_PP6: length 111.1
  TOP w0.102: v2(109.75,31.58) 109.87,31.58 109.94,31.51 109.94,31.24 108.97,30.27 108.97,27.13 110.48,25.62 111.89,25.62 112.73,24.78 112.73,24.16 112.59,24.01 112.59,23.19 113.05,22.73 113.05,19.86 113.51,19.4 113.51,16.27 114.38,15.4 117.69,15.4 121.82,11.27 126.12,11.27 126.96,10.43 126.96,7.86 128.21,6.6 134.66,6.6 135.25,7.2 135.25,7.57 137.45,9.77 137.45,10.51 139.99,13.05 145.23,13.05 147.62,10.66 147.62,5.86 150.09,3.38 160.1,3.38 160.32,3.6 160.55,3.6 167.26,10.31 173.44,10.31 177.66,14.52 177.66,16.44 178.33,17.11 178.33,19.38 v2(178.53,19.58)
  BOTTOM w0.076: UC1.AF7 109.83,31.58 v2(109.75,31.58)
  BOTTOM w0.102: v2(178.53,19.58) 178.34,19.77 178.34,19.9 178.44,20.01 178.94,20.01 179.03,19.92 179.14,19.92 179.31,19.75 LU8.3 179.72,19.6 RU16.1
USB_PP6_C: length 4.9
  BOTTOM w0.102: RU16.2 180.64,19.57 LU8.4 181.11,19.75 181.3,19.95 181.41,19.95 181.46,19.9 v4(181.88,19.9) 182.26,19.9 182.71,19.45 182.71,19.36 183.15,18.93 183.15,18.42 182.96,18.24 182.77,18.24 182.6,18.07 JIOB1.4
USB_PP7: length 150.6
  IN1 w0.119: v2(108.74,22.46) 109.45,22.46 109.53,22.38 109.82,22.38 111.79,20.41 120.41,20.41 121.08,21.08 128,21.08 128.01,21.07 130.12,21.07 130.4,21.35 131.53,21.35 134.39,24.21 134.39,25.21 138.05,28.87 138.81,28.87 141.22,31.28 142.36,31.28 142.72,31.64 144.73,31.64 145.25,31.13 149.2,31.13 149.39,30.94 149.39,30.59 149.88,30.1 151.83,30.1 152.44,30.71 152.44,30.71 152.69,30.96 153.18,31.44 155.03,31.44 155.52,30.96 157.42,30.96 158.52,29.86 158.52,27.4 159.56,26.36 159.56,25.36 159.73,25.18 159.73,24.47 160.18,24.02 160.18,21.54 162.18,19.53 165.73,19.53 166.33,18.94 166.33,17.1 167.64,15.78 169.3,15.78 172.93,12.14 175.7,12.14 176.31,12.75 184.65,12.75 185.07,12.34 192.02,12.34 192.29,12.61 201.79,12.61 203.94,14.75 211.48,14.75 214.57,17.84 216.79,17.84 218.93,19.98 218.93,24.23 219.1,24.39 v2(219.73,24.39)
  BOTTOM w0.076: UC1.AH2 108.29,29.1 108.29,28.32 108.16,28.2 108.16,26.94 107.51,26.29 107.51,24.14 107.49,24.12 107.49,24.1
  BOTTOM w0.102: R21.2 221.54,25.73 L4.3 221.38,25.15 221.31,25.08 221.31,24.62 221.08,24.39 v2(219.73,24.39) ; 107.49,24.1 107.49,23.2 108.23,22.46 v2(108.74,22.46)
USB_PP7_TPNL: length 11.6
  BOTTOM w0.102: R21.1 221.54,26.64 L4.4 221.38,27.31 221.23,27.46 221.23,27.84 221.33,27.94 221.33,29.66 220.47,30.53 220.47,30.81 220.57,30.91 221.14,30.91 DA6.3 220.95,31.48 220.57,31.48 220.47,31.58 220.47,32.38 220.84,32.75 221.13,32.75 221.15,32.73 221.71,32.73 221.74,32.75 222,32.75 222.55,32.2 223.16,32.2 223.31,32.05 JEDP1.37
USB_PP8: length 160.5
  IN3 w0.142: v2(38.94,92.29) 39.16,92.07 39.8,92.07 40.09,91.78 40.09,36.32 44.42,31.98 44.42,23.46 47.63,20.25 47.63,19.3 48.44,18.5 49.3,18.5 51.14,16.65 52.31,16.65 56.18,12.78 57.53,12.78 58.55,11.76 60.88,11.76 61.89,12.78 77.14,12.78 77.73,13.38 79.85,13.38 82.16,15.69 82.85,15.69 83.82,16.66 89.33,16.66 90.14,17.47 95.34,17.47 98.57,20.7 100.19,20.7 102.62,23.12 102.62,23.98 106.57,27.94 106.57,30.51 107.09,31.03 107.09,31.29 109.06,33.25 109.43,33.25 109.61,33.43 v2(109.61,33.43)
  BOTTOM w0.102: v2(38.94,92.29) 39.12,92.11 40.38,92.11 42.27,94 42.27,95.56 42.12,95.71 LW1.2 41.96,96.38 RW2.2 ; UC1.AF9 109.83,33.21 v2(109.61,33.43)
USB_PP8_R: length 4.2
  BOTTOM w0.102: RW2.1 41.95,97.29 LW1.1 42.12,97.97 42.27,98.12 42.27,98.34 42.5,98.56 42.87,98.56 42.89,98.58 43.45,98.58 43.7,98.83 43.7,99.11 43.55,99.25 JWLAN1.3
USBCOMP: length 1.3
  TOP w0.305: RC66.1 112.74,31.66 v2(112.74,31.6)
  BOTTOM w0.254: v2(112.74,31.6) 112.72,31.57 112.6,31.57 UC1.AB6
VBIOS_ID1: length 40.6
  TOP w0.102: RC60.1 90.46,29.88 v1(90.03,29.46) 89.36,28.79 85.35,28.79 RC59.2 84.21,27.65 84.21,25.63 84.51,25.32 84.51,25.31 85.08,24.74 85.08,24.24 85.36,23.96 v2(85.49,23.96)
  IN3 w0.142: v2(85.49,23.96) 86.1,23.35 86.65,23.35 88.63,21.37 92.17,21.37 92.47,21.68 93.42,21.68 94.17,22.42 94.17,23.21 95.1,24.15 96.63,24.15 99.11,26.63 99.55,26.63 101.04,28.11 101.04,28.61 102.37,29.94 102.37,30.16 103.74,31.54 103.74,32.76 104.03,33.04 104.59,33.04 v2(105.04,32.59)
  BOTTOM w0.076: UC1.AP8 105.48,32.59 v2(105.04,32.59)
VBIOS_ID2: length 27
  TOP w0.089: v1(103.83,32.45) 103.59,32.22 v2(103.34,32.22)
  TOP w0.102: v2(88.28,25.61) 88.35,25.68 RC62.1 RC61.2
  IN3 w0.142: v2(88.28,25.61) 88.28,22.11 88.74,21.64 92.06,21.64 92.36,21.95 93.35,21.95 93.92,22.52 93.92,23.35 94.97,24.39 96.22,24.39 98.8,26.97 99.2,26.97 100.34,28.11 100.34,28.52 103.34,31.52 v2(103.34,32.22)
  BOTTOM w0.076: v2(103.34,32.22) 103.26,32.22 103.19,32.29 UC1.AW7
VBIOS_ID3: length 29.4
  TOP w0.102: v2(98.46,30.07) 97.52,30.07 97.14,29.69 96,29.69 94.86,28.55 94.86,24.74 93.8,23.67 93.8,21.59 93.33,21.12 93.33,20.59 92.97,20.23 92.97,19.82 92.71,19.56 v1(91.92,19.56) 91.61,19.25 91.61,18.33 91.24,17.96 89.19,17.96 88.62,17.4 87.41,17.4 86.81,18 RC191.1 86.81,20.31 RC190.2
  BOTTOM w0.076: UC1.AY7 101.93,32.3 101.53,32.7 100.34,32.7 99.62,31.98 99.62,31.22 98.47,30.07 v2(98.46,30.07)
VCI_IN1: length 4.9
  TOP w0.102: v1(141.68,17.4) 142.18,17.4 142.27,17.49 RE30.1 142.63,17.91 142.61,17.92 142.61,18.59 v2(143.05,19.03)
  BOTTOM w0.102: v2(143.05,19.03) 142.58,18.55 142.58,18.25 142.76,18.06 UE1.126
VCIN0_PH: length 83.1
  TOP w0.102: v2(113.02,13.49) 112.15,13.49 109.8,15.84 108.03,15.84 106.93,16.94 106.93,19.13 107.08,19.29 107.08,20.09 108.03,21.04 R44.1
  IN2 w0.127: v2(138.62,26.95) 137.26,26.95 136.67,26.36 136.67,24.51 134.89,22.73 127.93,22.73 126.65,21.45 122.05,21.45 118.39,17.79 115.32,17.79 v2(115.08,18.03)
  IN3 w0.142: v2(92.97,7.91) 101.63,7.91 102.28,8.56 106.42,8.56 107.71,9.86 109.85,9.86 111.29,11.3 111.29,11.75 v2(113.02,13.49) 115.08,15.55 v2(115.08,18.03)
  BOTTOM w0.102: R42.2 112.42,10.8 112.42,14.44 114.51,16.53 v1(114.51,16.95) 114.51,17.46 v2(115.08,18.03) ; R43.2 92.1,7.94 C32.1 92.1,7.15 C33.1 92.98,7.9 v2(92.97,7.91) ; RE37.1 138.35,27.21 v2(138.62,26.95)
VCREF0: length 4.9
  TOP w0.102: v1(140.23,29.72) 140.01,29.51 CE23.1 RE48.1 141.42,28.79 v2(141.7,28.51) 142.28,28.51 RE46.2
  BOTTOM w0.102: v2(141.7,28.51) 141.57,28.38 UE1.25
VD_IN1_C: length 42.5
  TOP w0.102: R44.2 106.64,21.1 v1(106.88,20.86) 106.88,19.37 106.72,19.22 106.72,16.85 107.94,15.63 109.72,15.63 112.38,12.97 113.19,12.97 v2(113.71,13.49)
  IN2 w0.127: v2(92.92,8.5) 93.39,8.97 98.65,8.97 99.85,10.18 102.06,10.18 104.92,13.04 107.59,13.04 107.75,12.88 109.02,12.88 109.02,12.88 110.08,12.88 111.16,13.96 113.24,13.96 v2(113.71,13.49)
  BOTTOM w0.102: v2(92.92,8.5) 93.13,8.5 93.49,8.15 93.49,6.74 C33.2 92.98,6.23 C32.2 R45.1
VGA_SMB_CK3: length 5.3
  TOP w0.102: v2(111.75,106.48) 112.17,106.06 112.17,105.4 v1(112.29,105.28) 112.46,105.11 113.57,105.11 RV6.2 114.08,104.6 QV1.1
  BOTTOM w0.102: v2(111.75,106.48) 111.99,106.72 UV1.U7
VGA_SMB_DA3: length 7.9
  TOP w0.102: v2(111.75,107.16) 111.34,106.75 111.34,106.36 111.75,105.94 v1(111.75,103.61) 111.75,102.8 QV1.4 112.52,101.51 RV5.2
  BOTTOM w0.102: v2(111.75,107.16) 111.91,107.16 UV1.U8
VIDALERT_N: length 59.1
  IN3 w0.142: v2(133.34,55.34) 134.76,55.34 135.58,56.16 135.63,56.16 135.63,56.16 136.64,56.16 137.45,56.96 138.49,58 138.49,60.32 138.43,60.37 138.43,62.82 140.2,64.59 148.5,64.59 156.33,56.77 156.33,53.5 158.12,51.7 158.12,49.5 v2(158.14,49.48)
  BOTTOM w0.102: v2(133.34,55.34) 133.32,55.36 133.14,55.36 132.42,56.09 132.42,57.84 130.7,59.55 130.7,64.48 129.96,65.21 128.89,65.21 RC152.2 RC153.2 ; v2(158.14,49.48) 158.14,49.08 158.28,48.93 v1(159.94,48.93) 160.15,48.93 160.2,48.87 161.81,48.87 PR607.1
VIDSCLK: length 68.6
  IN3 w0.142: v2(157.12,49.5) 157.44,49.81 157.44,51.52 155.8,53.15 155.8,56.55 148.28,64.07 140.42,64.07 138.96,62.61 138.96,60.59 139.07,60.47 139.07,57.85 138.92,57.7 136.86,55.63 135.85,55.63 135.02,54.81 133.45,54.81 v2(133.37,54.73)
  BOTTOM w0.089: 130.52,58.95 130.52,63.34 129.5,64.36 123.56,64.36 UC1.A63
  BOTTOM w0.102: 130.52,58.95 131.78,57.68 131.78,55.93 132.98,54.73 v2(133.37,54.73) ; PR606.1 166.49,47.07 166.14,46.72 161.6,46.72 159.95,48.37 158.04,48.37 v1(157.82,48.6) 157.12,49.29 v2(157.12,49.5)
VIDSOUT: length 66.6
  IN3 w0.142: v2(158.77,49.49) 158.77,49.55 158.64,49.68 158.64,51.92 157.93,52.63 157.93,55.9 148.72,65.11 139.99,65.11 137.91,63.04 137.91,60.15 137.96,60.1 137.96,58.22 137.88,58.13 136.42,56.68 135.41,56.68 135.37,56.68 134.61,55.92 v2(133.37,55.92)
  BOTTOM w0.076: 125.08,65.51 124.7,65.51 123.93,64.73 122.84,64.73 122.65,64.54 122.5,64.54 122.49,64.54 122.38,64.54 122.09,64.84 UC1.D64
  BOTTOM w0.102: PR609.1 162.71,49.17 162.44,49.43 160.43,49.43 160.38,49.49 v2(158.77,49.49) ; v2(133.37,55.92) 132.97,56.32 132.97,58.07 130.96,60.09 130.96,64.49 130.04,65.4 127.67,65.4 RC154.2 125.96,66.38 125.08,65.51
VL: length 2.4
  BOTTOM w0.254: PC126.1 176.23,29.82 v2(176.58,30.17) 177.04,30.17 177.36,30.49 PU102.15
VR_ALERT#: length 1.9
  TOP w0.203: PU602.36 164.68,49.19 PR625.2
VR_CAP: length 4.7
  TOP w0.102: v1(140.91,24.28) CE24.1 139.72,24.37 v2(139.08,25)
  BOTTOM w0.102: TP44.1 138.72,25.41 138.72,25.37 138.8,25.3 138.8,25.29 v2(139.08,25) 139.27,25.2 139.27,25.48 139.38,25.58 UE1.18
VR_SCLK: length 1.8
  TOP w0.203: PR618.2 165.25,49.62 165.08,49.78 PU602.37
VR_SDA: length 2.2
  TOP w0.203: PU602.35 164.28,49.55 164.08,49.35 163.98,49.35 163.5,48.87 PR626.2
VRALERT#: length 21.1
  TOP w0.102: v2(107.71,34.77) 108.22,34.26 108.22,32.72 108.05,32.56 v1(107.72,32.56) 107.32,32.15 106.78,32.15 106.51,31.88 106.51,31.14 106.63,31.02 106.63,29.05 106.99,28.69 106.99,27.46 107.31,27.14 107.31,26.32 110.25,23.37 110.25,20.28 109.48,19.51 108.24,19.51 v2(108.2,19.54)
  BOTTOM w0.076: UC1.AM11 107.63,34.85 v2(107.71,34.77)
  BOTTOM w0.102: RC92.1 108.03,19.38 v2(108.2,19.54)
VSA_SEN+: length 56.6
  TOP w0.254: PC640.2 157.96,54.06 PR649.2 158.82,53.76 v2(159.15,53.43) ; RC159.2 118.25,40.92 119.14,40.03 119.14,39.95 ; 119.14,39.95 v2(119.14,39.81) ; 119.14,39.95 119.49,40.31 120.95,40.31 121,40.36 v1(122.47,40.36) 122.56,40.36 122.94,39.98 125.03,39.98 125.31,39.71 126.72,39.71 126.84,39.83 127.14,39.83 127.59,40.28 129.94,40.28 130.43,39.79 133.12,39.79 133.36,39.55 133.36,38.97 v2(133.43,38.9)
  IN1 w0.254: v2(133.43,38.9) 133.36,38.97 133.36,39.73 135.56,41.93 137.73,41.93 138.45,42.66 138.45,45.64 139.95,47.14 151.25,47.14 155.31,51.2 158.93,51.2 159.25,51.52 159.25,53.33 v2(159.15,53.43)
  BOTTOM w0.254: PC640.2 157.96,54.06 PR649.2 158.82,53.76 v2(159.15,53.43) ; v2(119.14,39.81) 119.14,39.76 UC1.H20
VSA_SEN-: length 56.7
  TOP w0.203: v2(159.73,53.43) 159.91,53.43 160.35,52.98 161.08,52.98 161.15,52.92 PU602.26
  TOP w0.254: v2(133.84,39.33) 133.84,39.6 133.28,40.17 130.59,40.17 130.1,40.66 127.44,40.66 126.98,40.21 126.68,40.21 126.56,40.09 125.46,40.09 125.19,40.36 124.95,40.36 123.1,40.36 122.66,40.8 121.49,40.8 120.99,41.29 119.97,41.29 119.91,41.23 119.57,41.23 v2(119.14,40.8) 119,40.93 RC160.1
  IN1 w0.254: v2(133.84,39.33) 133.84,39.68 135.72,41.55 137.88,41.55 138.83,42.5 138.83,45.48 140.11,46.76 151.41,46.76 155.47,50.82 159.09,50.82 159.63,51.36 159.63,53.33 v2(159.73,53.43)
  BOTTOM w0.254: v2(119.14,40.8) 119.14,40.85 119.12,40.85 119.12,40.66 UC1.H21 ; PC649.1 PC650.2 v2(159.73,53.43)
VSUM+_VGA: length 12.7
  TOP w0.102: v1(48.51,112.8) PR1126.1
  TOP w0.203: v2(52.98,119.34) 53.09,119.45 PU1100.14
  TOP w0.254: PR1126.1 49.55,113.32 PR1131.1 PR1132.1 PC1232.1 49.36,115.66 PR1108.1 50.06,116.74 PC1230.1 50.67,116.74 v2(50.92,116.48)
  BOTTOM w0.254: v2(52.98,119.34) 52.98,118.22 51.24,116.48 v2(50.92,116.48)
VSUM-_VGA: length 37.3
  TOP w0.254: PR1137.1 53.04,115.16 PR1128.1 ; PR1110.1 49.47,117.28 49.48,117.28 50,117.8 PC1119.1 PC1120.1 PR1136.1 52.15,117.24 PC1230.2 51.64,116.28 PC1232.2 PR1132.2 51.76,114.77 v2(51.9,114.91) PR1128.1 ; PR1128.1 53.11,114.58 53.61,114.58 PC1231.1
  BOTTOM w0.254: v2(51.9,114.91) 52.01,114.8 53.18,114.8 54.19,113.78 56.38,113.78 56.7,114.1 60.51,114.1 v1(64.57,110.04) 65.09,109.52 66.39,109.52 66.67,109.24 74.29,109.24 74.77,109.72 PH1102.2
VTTREF_1.2V: length 1.7
  BOTTOM w0.203: PU200.4 89.91,104.52 90.09,104.34 v2(90.44,104.34) 90.99,104.34 PC210.1
WAKEB: length 6.4
  BOTTOM w0.102: RV162.2 RV163.1 99.43,120.31 v1(100.02,120.9) 100.53,121.41 102.04,121.41 102.48,121.86 102.48,122.11 102.79,122.41 102.95,122.41 UV1.AJ27
WHITE_LED_BAT: length 6.6
  TOP w0.102: v2(150.96,10.06) Q4.1 149.79,11.72 ZT16.1
  BOTTOM w0.102: JLED1.3 151.7,11.58 151.73,11.56 151.73,10.83 v2(150.96,10.06)
WHITE_LED_PWR: length 113.3
  TOP w0.254: v2(179.45,21.15) 178.63,20.33 177.75,20.33 176.77,19.35 Q15.1 ; ZT1.1 156.95,111.31 JPWR1.5 160.06,111.31 160.84,110.54 160.84,105.78 v2(159.09,104.03)
  IN1 w0.254: v2(159.09,104.03) 160.99,104.03 165.8,99.22 165.8,71.13 172.55,64.38 172.55,56.46 184.33,44.69 184.33,43.03 184.91,42.45 184.91,26 181.29,22.37 181.06,22.37 179.84,21.15 v2(179.45,21.15)
WLAN_RADIO_DIS#: length 245.9
  IN3 w0.142: v2(123.72,31.44) 123.3,31.02 123.3,30.78 123.3,29.33 125.53,27.1 125.53,25.33 124.03,23.84 124.03,22.18 120.21,18.35 120.21,15.55 109.59,4.93 91.91,4.93 90.87,3.89 55.62,3.89 54.9,4.61 48.86,4.61 41.35,12.12 41.35,17.44 37.6,21.19 37.6,28.25 33.83,32.03 28.85,32.03 26.31,34.57 26.31,38.47 27.6,39.76 27.6,54.32 26.09,55.83 26.09,59.39 28.51,61.82 28.51,64.73 28.15,65.09 28.15,78.11 28.66,78.62 v2(28.66,78.95)
  BOTTOM w0.076: UC1.B7 123.24,31.64 123.51,31.64 v2(123.72,31.44) 124.33,30.82 125.09,30.82 125.35,30.57 125.81,30.57 127.08,29.3 v1(127.39,29.3) 128.01,29.3 RC3.1
  BOTTOM w0.102: v2(28.66,78.95) 28.66,79.46 32.2,83 32.2,89.64 30.54,91.31 30.54,101.65 32.37,103.49 53.51,103.49 56.8,106.78 JWLAN1.48
XCLK_BIASREF: length 7.2
  BOTTOM w0.076: 120.47,51.14 120.47,51.95 UC1.E42
  BOTTOM w0.089: 120.47,51.14 121.36,50.25 121.72,50.25 121.73,50.25 122.05,50.25 122.06,50.25 122.29,50.25 122.37,50.25 122.38,50.25 123.33,50.25 123.43,50.15 v1(124.84,50.15) 125.01,50.15 RC76.1
XDP_HOOK0: length 1
  TOP w0.102: RC148.2 82.19,24.06 TPC32.1
XDP_ITP_PMODE: length 17
  BOTTOM w0.076: 129.15,24.15 129.15,24.5 128.94,24.72 127.95,24.72 126.46,26.21 TPC7.1 126.46,26.7 124.48,28.68 124.48,30.44 123.85,31.07 123.56,31.07 123.55,31.08 123.05,31.08 122.8,31.33 122.8,31.48 122.52,31.76 122.52,32.13 122.31,32.34 121.14,32.34 120.96,32.52 120.96,32.82 UC1.E8
  BOTTOM w0.102: RC143.2 129.95,22.45 129.15,23.25 129.15,24.15
XDP_OBS0_R: length 5.2
  BOTTOM w0.076: UC1.C55 122.62,60 124.62,60
  BOTTOM w0.102: 124.62,60 125.34,59.28 126.8,59.28 TP15.1
XDP_OBS1_R: length 3.5
  BOTTOM w0.076: 124.24,59.82 122.86,59.82 122.62,59.59 122.38,59.59 122.09,59.88 UC1.D55
  BOTTOM w0.102: TP16.1 124.24,59.82
XDP_OBS2_R: length 3.7
  BOTTOM w0.076: UC1.B54 123.15,59.64 123.78,59.64
  BOTTOM w0.102: TP17.1 125.8,58.7 124.72,58.7 123.78,59.64
XDP_OBS3_R: length 4
  BOTTOM w0.076: 125.12,60.18 122.44,60.18 UC1.C56
  BOTTOM w0.102: TP18.1 125.37,59.92 125.12,60.18
XDP_PRDY#: length 3.9
  BOTTOM w0.076: UC1.D56 121.85,60.66 121.98,60.79 122.87,60.79 122.91,60.84 123.26,60.84 123.33,60.88 123.7,60.88 123.86,60.71 124.28,60.71 124.62,61.05
  BOTTOM w0.102: 124.62,61.05 124.62,61.16 TPC31.1
XDP_PREQ#: length 5.5
  TOP w0.102: TPC30.1 120.48,63.75 120.61,63.89 120.61,63.89 120.85,64.13 121.4,64.13 v2(123.09,62.43)
  BOTTOM w0.076: UC1.D61 122.09,62.6 122.28,62.6 122.51,62.71 122.62,62.71 122.9,62.43 v2(123.09,62.43)
XDP_PRSENT_CPU: length 2
  BOTTOM w0.102: RC144.1 TPC33.1 131.24,73.7 RC175.2
XDP_SPI_IO2: length 15.3
  BOTTOM w0.102: RC145.1 105.91,18.71 105.81,18.81 105.33,18.81 105.23,18.71 105.23,15.49 105.13,15.39 TPC9.1 104.74,15.39 104.62,15.51 104.62,18.69 104.33,18.98 104.33,19.36 103.56,20.12 103.53,20.17 103.32,20.38 103.32,20.47 103.59,20.74 103.89,20.74 105.49,19.13 106.33,19.13 RC41.1
XDP_SPI_SI: length 16.3
  BOTTOM w0.102: RC139.2 94.53,15.31 94.77,15.31 TPC8.1 95.3,15.84 95.3,18.46 95.73,18.88 95.73,19.44 98.1,21.82 100.32,21.82 100.43,21.92 100.43,22.14 100.32,22.24 100.02,22.24 99.92,22.34 99.92,22.52 100.03,22.64 100.67,22.64 100.78,22.75 100.78,22.9 100.68,23.01 100.04,23.01 99.94,23.11 99.94,23.26 100.05,23.36 100.58,23.36 100.78,23.56 RC40.1
XTAL24_IN: length 14.8
  BOTTOM w0.076: UC1.E37 121.2,49.03 121.2,48.56 121.4,48.36 122.3,48.36 122.52,48.14 122.52,47.92 122.81,47.64 122.87,47.64
  BOTTOM w0.102: 122.87,47.64 123.95,47.64 125.23,48.91 v1(126.91,48.91) 129.11,48.91 RC80.2 CC6.1 130.5,48.43 132.14,48.43 YC1.3
XTAL24_OUT: length 12.6
  BOTTOM w0.076: 122.76,47.21 122.27,47.21 122.13,47.35 122.13,47.64 122,47.77 121.42,47.77 121.39,47.8 121.38,47.8 120.75,48.43 UC1.E35
  BOTTOM w0.102: 122.76,47.21 123,47.45 124.22,47.45 125.23,48.46 v1(125.6,48.46) 128.65,48.46 RC80.1 129.79,47.78 129.85,47.83 CC7.1 130.95,47.83 YC1.1
XTALIN: length 6.4
  BOTTOM w0.102: YV1.1 97.5,125.09 97.53,125.09 97.71,124.92 CV17.1 98.35,124.92 98.38,124.94 RV20.1 99.65,124.94 101,123.6 101.98,123.6 UV1.AM28
XTALOUT: length 9.5
  BOTTOM w0.102: UV1.AK28 102.45,123.11 100.77,123.11 99.85,124.03 RV20.2 98.38,124.03 98.35,124.05 CV18.1 97.89,124.05 97.33,124.61 95.09,124.61 94.99,124.51 YV1.3
N16741477: length 1.3
  TOP w0.102: v2(108.12,107.31) 107.68,106.86 TP61.1
  BOTTOM w0.102: UV1.AB8 108.45,107.31 v2(108.12,107.31)
N16741489: length 1.3
  TOP w0.102: v2(107.26,106.32) 107.26,105.62 TP57.1
  BOTTOM w0.102: UV1.AD7 v2(107.26,106.32)
N16741505: length 4.4
  BOTTOM w0.102: TP63.1 106.21,101.51 106.21,101.51 108.12,103.43 108.12,104.11 108.46,104.45 UV1.AB4
N16741517: length 1.4
  TOP w0.102: v2(106.49,108.73) 106.13,109.09 106.13,109.1 TP55.1
  BOTTOM w0.102: UV1.AD9 106.49,108.69 v2(106.49,108.73)
N16741525: length 2.1
  TOP w0.102: TP65.1 111.01,106.25 111.01,106.55 110.78,106.77 110.73,106.77 v2(110.46,107.04)
  BOTTOM w0.102: v2(110.46,107.04) 109.98,107.52 UV1.Y8
N16741803: length 2
  TOP w0.102: v2(107.35,119.11) v1(107.35,118.53)
  TOP w0.508: RV29.2 107.24,119.22 v2(107.35,119.11)
  BOTTOM w0.254: v2(107.35,119.11) 107.35,118.83 UV1.AC22
N16741825: length 1.5
  TOP w0.508: RV59.2 108.3,119.48 v2(108.12,119.31)
  BOTTOM w0.305: UV1.AB22 108.12,119.05 v2(108.12,119.31)
N16751828: length 1.2
  TOP w0.102: TP58.1 107.64,108.33 v2(107.24,107.94)
  BOTTOM w0.102: UV1.AC8 v2(107.24,107.94)
N16751830: length 1.1
  TOP w0.102: v2(106.41,107.12) 106.09,106.8 TP54.1
  BOTTOM w0.102: v2(106.41,107.12) 106.06,107.47 UV1.AE8
N16751834: length 1.2
  TOP w0.102: TP52.1 106.1,107.94 v2(105.66,107.94)
  BOTTOM w0.102: UV1.AE9 106.04,108.32 v2(105.66,107.94)
N16751836: length 1.4
  TOP w0.102: TP50.1 114.82,108.55 v2(115.31,108.55)
  BOTTOM w0.102: UV1.N9 115.63,108.55 v2(115.31,108.55)
N16751838: length 3.1
  BOTTOM w0.102: UV1.AB2 108.34,103.8 108.34,103.28 107.46,102.41 TP64.1
N16751842: length 1.5
  TOP w0.102: v2(108.12,108.1) 108.72,107.5 TP60.1
  BOTTOM w0.102: v2(108.12,108.1) 108.34,108.32 UV1.AB9
N16751844: length 1.4
  TOP w0.102: TP56.1 108.13,108.79 v2(108.11,108.82)
  BOTTOM w0.102: v2(108.11,108.82) 107.96,108.82 UV1.AC10
N16751848: length 1.3
  TOP w0.102: TP51.1 116.09,108.21 116.19,108.11 v2(116.47,108.11)
  BOTTOM w0.102: v2(116.47,108.11) 116.51,108.16 116.9,108.16 UV1.L9
N16751852: length 1.4
  TOP w0.102: TP62.1 109.02,106.43 v2(109.19,106.43)
  BOTTOM w0.102: UV1.AB7 108.95,106.43 v2(109.19,106.43)
N16751854: length 2.3
  TOP w0.102: TP59.1 108.01,104.92 107.99,104.93 v2(107.99,106.31)
  BOTTOM w0.102: UV1.AC7 107.66,106.65 v2(107.99,106.31)
N16751856: length 2.4
  TOP w0.102: v2(110.46,109.1) 110.84,109.1 110.99,108.96 111.58,108.96 111.63,108.91 TP53.1
  BOTTOM w0.102: v2(110.46,109.1) 110.46,109.1 UV1.Y11
N16751858: length 1.9
  TOP w0.102: TP66.1 109.91,106.09 109.65,105.83 v2(109.65,105.57)
  BOTTOM w0.102: v2(109.65,105.57) 109.65,106.25 109.86,106.46 UV1.Y7
N16808781: length 3.7
  BOTTOM w0.102: UV1.AJ11 103.08,109.92 102.63,109.46 100.46,109.46 100.25,109.25 RV157.1
N16808782: length 4.3
  BOTTOM w0.102: v1(99.37,111.94) 99.37,111.64 99.85,111.16 RV155.1 100.25,111.02 100.33,111.1 102.48,111.1 UV1.AK12
N16808783: length 2.7
  BOTTOM w0.102: UV1.AL11 102.23,110.15 RV156.1
N17003698: length 2.4
  BOTTOM w0.102: TP71.1 157.47,18.12 156.81,18.78 UE1.96
N17003752: length 3.5
  TOP w0.102: v2(60.85,53.78) 60.85,53.92 60.6,54.17 v1(60.51,54.17) 59.9,54.17 RD23.2
  BOTTOM w0.102: JDIMM1.134 60.76,53.87 v2(60.85,53.78)
N17004366: length 3.1
  TOP w0.102: RD24.2 43.88,54.64 v2(43.62,54.38) v1(43.11,54.38)
  BOTTOM w0.102: JDIMM2.134 v2(43.62,54.38)
N17230024: length 1.4
  BOTTOM w0.102: UL1.27 38,117.4 TP48.1
N17230026: length 2.3
  BOTTOM w0.102: UL1.25 37.13,118.2 37.23,118.3 37.23,118.96 36.72,119.47 TP49.1
N17231159: length 2.6
  BOTTOM w0.102: RL2.2 v1(38.36,114.74)
  BOTTOM w0.254: UL1.31 37.36,115.8 37.47,115.68 37.87,115.68 37.91,115.72 RL2.2
N17237617:
  vias: v1(202.65,28.81) v2(198.33,29.5) v2(198.33,28.92) v2(198.91,29.5) v2(198.91,28.92) v2(199.47,29.17) v2(200.06,29.17) v2(200.64,29.17) v2(201.22,29.17) v2(201.81,29.17)
N17268429: length 3.2
  TOP w0.102: v1(186.56,39.91) 187.03,40.38 PR791.2
  TOP w0.254: PR791.2 187.53,40.27 PQ720.1 187.03,39.4 PR790.1
N17273333: length 4.7
  TOP w0.102: RA5.2 v1(37.15,15.49)
  TOP w0.508: QA1.3 39.52,15.39 38.87,16.03 RA6.1 37.18,16.46 RA5.2
N17274212: length 2.3
  BOTTOM w0.102: UL3.3 26.34,121 26.18,120.84 26.18,120.81 26.16,120.79 RL7.2 v1(24.58,120.79)
N17284062: length 19
  TOP w0.254: v2(142.2,51.45) 142.01,51.26 142.01,50.44 143.28,49.17 v3(145.54,49.17) 152.48,49.17 153.56,48.09 154.77,48.09 155.34,48.66 155.34,49.3 PR624.1
  BOTTOM w0.254: PL601.3 142.58,52.73 142.2,52.35 v2(142.2,51.45)
N17297569: length 5.2
  TOP w0.102: JDEG1.9 133.72,8.56 134.51,9.35 ZT58.1 135.53,9.35 136.29,10.11 RE56.2
N17389450: length 22.2
  TOP w0.254: v2(181.06,30.69) 181.07,30.7 181.67,30.7 v1(181.83,30.54) 182,30.37 PD102.2
  IN1 w0.254: v2(181.06,30.69) 182.04,30.69 182.36,31.01 182.71,31.01 183.41,31.7 183.41,37.29 182.63,38.07 v2(176.8,38.07)
  BOTTOM w0.254: PR120.2 181.73,28.46 PR114.2 PC128.1 181.74,30.63 PR122.1 181.65,30.72 181.09,30.72 v2(181.06,30.69) ; PR121.2 177.06,38.33 v2(176.8,38.07)
N17426748: length 2.4
  TOP w0.102: UZ1.6 133.81,35.63 CZ3.1 v1(135.17,36.02)
N17427506: length 3.8
  BOTTOM w0.102: v1(124.61,90.53) 124.61,91.27 CZ14.2 124.14,91.46 123.72,91.88 123.72,92.61 124,92.89 UZ4.6
N17444580: length 4.6
  TOP w0.102: v1(166.21,46.84) 165.73,46.84 v2(165.25,47.33)
  TOP w0.254: v2(165.25,47.33) 165.25,47.83 165.25,47.83 PR618.1
  BOTTOM w0.254: v2(165.25,47.33) 165.25,47.83 PR601.2 165.4,47.99 PR606.2 167.16,47.99 PC695.2
N17452420: length 4.4
  TOP w0.102: ZT106.1 217.51,17.48 v2(217,16.97)
  TOP w0.254: PR15.1 216.91,16.88 v2(217,16.97)
  BOTTOM w0.254: PBATT1.5 217.91,16.93 217.66,16.68 217.3,16.68 v2(217,16.97)
N17563414: length 3.6
  TOP w0.102: RA9.1 30.1,25.2 29.64,25.2 v1(28.63,24.19) 28.39,23.95 UA1.4
N17745606: length 2.4
  BOTTOM w0.102: v1(219.5,38.31) 219.9,37.91 219.9,37.75 C13.1 221.36,37.15 R56.2
N17847259: length 3
  BOTTOM w0.102: UV1.AL9 101.97,108.32 100.63,106.98 TP72.1
N17855318: length 3.3
  BOTTOM w0.508: PQ740.4 159.48,112.41 v1(159.48,111.42) PR778.1
N17855352: length 32
  IN1 w0.508: v2(156.67,120.42) 155.53,120.42 154.3,119.19 154.3,114.7 154.68,114.32 154.68,114.3 156.39,112.6 v2(156.39,108.96)
  BOTTOM w0.508: v2(156.67,120.42) 159.54,120.42 160.12,121 PR762.1 161.36,121 162.54,119.82 165.45,119.82 166.05,119.22 PQ718.4 ; PR778.2 PC744.1 v1(158.57,108.31) 158.57,107.01 PQ709.1 157.77,106.55 156.62,107.69 PC742.1 156.62,108.72 v2(156.39,108.96)
N17877344: length 1.6
  BOTTOM w0.102: UV1.R1 114.06,103.21 114.06,103.21 114.06,102.69 TP69.1
N17877347: length 3.6
  BOTTOM w0.102: TP70.1 112.31,101.94 112.52,101.94 113.57,102.99 113.57,103.49 114,103.91 114,104.26 UV1.R3
N18047481: length 3.6
  TOP w0.102: JDEG1.1 129.72,8.48 129.42,8.78 ZT60.1 128.23,10.11 RE58.2
N18047924: length 9.5
  TOP w0.102: v2(186.2,53.81) 185.11,54.9 R55.1 184.49,54.41 184.49,53.89 D8.1 183.48,52.88 R30.1 183.48,52.34 ZT15.1
  BOTTOM w0.102: JFAN1.3 185.14,52.67 185.25,52.67 186.2,53.62 v2(186.2,53.81)
N18330820: length 4.9
  BOTTOM w0.102: UZ5.10 113.77,91.62 113.72,91.57 CZ19.2 112.64,91.57 112.16,91.09 110.57,91.09 v1(109.89,91.78)
N18330832: length 3.6
  BOTTOM w0.102: v1(110.85,92.96) 112.15,92.96 112.66,92.44 CZ18.2 113.79,92.44 113.81,92.42 UZ5.12
N18336277: length 4.7
  TOP w0.102: Q13.1 89.2,6.69 v1(90.09,7.57)
  TOP w0.508: R37.1 88.35,5.21 Q13.1
N18336387: length 3.9
  TOP w0.102: R35.2 92.62,5.8 v1(92.62,6.67)
  TOP w0.508: Q12.3 94.36,5.03 93.73,5.66 C18.1 92.75,5.66 R35.2
N18390627: length 2.4
  TOP w0.102: v1(201.19,20.82) 201.05,20.82 200.54,21.33 PQ710.2
  TOP w0.254: PQ710.2 199.32,21.68 PQ711.1
N18612614: length 13.3
  BOTTOM w0.076: 98.26,25.02 98.42,25.18 98.42,26.6 100.21,28.39 100.21,29.57 100.64,30 101.01,30 101.14,30.13 101.14,30.56 101.34,30.76 101.65,30.76 101.83,30.58 UC1.AY4
  BOTTOM w0.102: TP28.1 95.93,21.39 96.89,22.34 97.05,22.34 98,23.29 98,23.53 98.17,23.69 98.17,24.92 98.26,25.02
N18612616: length 9.4
  BOTTOM w0.076: 98.37,24.29 98.37,24.85 98.58,25.06 98.58,26.53 100.38,28.33 100.38,29.23 100.79,29.65 UC1.BB3
  BOTTOM w0.102: TP29.1 96.88,21.89 98.2,23.21 98.2,23.44 98.37,23.61 98.37,24.29
N18612618: length 10.2
  BOTTOM w0.076: UC1.BB5 100.69,31.06 99.88,30.26 99.88,29.51 99.02,28.65 99.02,27.55 98.19,26.73 98.19,25.31
  BOTTOM w0.102: 98.19,25.31 98.19,25.28 97.96,25.05 97.96,23.78 97.8,23.61 97.8,23.38 97.54,23.12 96.85,23.12 TP27.1
N18855880: length 2.3
  BOTTOM w0.102: R57.2 224.48,27.35 v1(224.45,27.32) 224.45,26.27 U1.3
N18894766: length 2
  TOP w0.102: v1(157.04,54.47) 157.45,54.47 PC640.1
  TOP w0.254: PR646.2 158.79,54.96 PC640.1
N18894780: length 2.4
  TOP w0.102: PC601.1 157.96,55.85 157.31,56.49 157.31,56.65 v1(157.02,56.94)
  TOP w0.254: PC601.1 157.97,55.82 PR652.2
N18894855: length 3.7
  TOP w0.203: PU602.28 160.74,52.12 v1(160.68,52.06) 159.67,51.05 PR636.1
  TOP w0.254: PR636.1 PC632.1
N18894856: length 2
  TOP w0.102: v1(157.64,49.07) 157.64,49.87 PR641.1
  TOP w0.254: PR641.1 157.89,50.13 PC632.2
N18894871: length 15.3
  TOP w0.254: PR642.2 156.1,49.67 v2(155.85,49.42)
  BOTTOM w0.254: v2(155.85,49.42) 155.85,48.6 155.6,48.34 154.13,48.34 v1(153.18,49.3) PH604.1
N19050685: length 3.4
  BOTTOM w0.102: v1(217.48,38.31) 217.34,38.45 RX6.1 215.15,39.79 UX2.24
N19050753: length 3.5
  BOTTOM w0.102: UX2.7 210.03,39.79 209.85,39.61 209.85,38.85 v1(209.5,38.5) 209.06,38.06 RX5.1
N19179553: length 2.1
  TOP w0.102: JDEG1.4 131.22,9.75 131.21,9.76 ZT55.1
N19179559: length 2.6
  TOP w0.102: JDEG1.7 132.72,8.44 v1(133.5,9.22) 133.62,9.34 RE57.2
N19179561: length 2.4
  TOP w0.102: JDEG1.6 v1(132.22,9.29) 132.22,9.66 RE55.2
N19675639: length 2.6
  TOP w0.102: v1(215.3,52.6) CX3.1 215.85,51.65 215.92,51.58 UX1.6
N19910104: length 2
  TOP w0.102: CE18.1 RE27.1 153.26,33.36 152.79,33.83 v1(152.79,34.28)
N20135010: length 3.1
  TOP w0.203: PR1136.2 PC1227.2 53.49,119.17 v1(53.49,119.6) PU1100.15
N20135022: length 2.7
  TOP w0.102: PR1137.2 51.92,115.7 v1(51.92,115.55)
  TOP w0.254: PR1137.2 PC1227.1
N20135024: length 14.2
  TOP w0.203: PU1100.25 57.57,123.04 57.69,122.91 58.5,122.91 58.81,122.6 59.19,122.6
  TOP w0.508: 59.19,122.6 60.11,122.6 61.23,123.72 61.23,127.79 v3(60.72,128.3) 60.09,128.93 PC1110.1 PR1114.1
N20135039: length 3.8
  TOP w0.203: PR1121.2 v1(50.05,119.64) 50.64,120.23 51.69,120.23 51.89,120.43 PU1100.11
N20135040: length 5.3
  TOP w0.203: PC1124.1 53.89,118.73 PU1100.16
  TOP w0.254: PR1133.1 PC1122.1 PR1138.1 PC1124.1
N20135043: length 4.5
  TOP w0.203: PU1100.17 54.29,120.16 55.23,119.21 56.1,119.21 PC1229.1
  TOP w0.254: PR1139.1 PC1229.1
N20135074: length 0.5
  TOP w0.102: 69.69,113.92 v1(69.69,113.42)
N20135091: length 2.3
  TOP w0.102: v1(60.71,120.61) PR1123.2
  TOP w0.508: PR1123.2 59.65,121.39 PC1118.1
N20135096: length 35.9
  TOP w0.254: PR1126.2 51.57,112.8 PR1124.2 52.22,113.45 52.58,113.45 53.2,112.82 v1(54.69,112.82) 57.73,112.82 v2(57.97,113.06)
  IN1 w0.254: v2(78.81,113.15) 78.91,113.05 78.91,111.65 76.7,109.43 65.55,109.43 61.91,113.07 59.38,113.07 58.91,113.54 58.24,113.54 57.97,113.28 v2(57.97,113.06)
  BOTTOM w0.254: v2(78.81,113.15) 78.91,113.25 78.91,113.9 78.56,114.26 PL1103.3
N20135098: length 35
  TOP w0.254: v2(58.55,113.04) 58.55,113.33 58.25,113.63 57.07,113.63 v1(56.71,113.28) 53.27,113.28 52.79,113.76 PR1128.2
  IN1 w0.254: v2(58.55,113.04) 58.96,112.63 61.85,112.63 65.42,109.05 76.85,109.05 79.29,111.49 79.29,113.05 v2(79.39,113.15)
  BOTTOM w0.254: PL1103.2 79.65,114.26 79.29,113.9 79.29,113.25 v2(79.39,113.15)
N20135126: length 2.8
  TOP w0.102: PH1101.2 v1(45.45,118.72)
  TOP w0.254: PH1101.2 46.4,118.71 PR1120.2 47.32,118.71 PR1121.1
N20135134: length 9.2
  TOP w0.203: PC1123.1 57.54,118.71 56.67,119.57 55.36,119.57 54.69,120.24 PU1100.18
  TOP w0.254: PC1123.1 57.6,117.84 PR1134.1 v1(56.61,116.83) 56.58,116.8 PR1135.1 56.17,115.91 PR1129.2 55.7,115.47 PR1133.2
N20135137: length 0.9
  TOP w0.254: PR1129.1 55.66,116.42 PC1122.2
N20135139: length 2.4
  TOP w0.102: v1(58.81,114.51) 58.01,114.51 PC1233.1
  TOP w0.254: PR1135.2 PC1233.1
N20135141: length 7.3
  TOP w0.102: PC1228.2 59.39,117.83 v1(59.44,117.77)
  TOP w0.203: PU1100.19 55.09,120.28 55.49,119.87 56.84,119.87 57.5,119.21 58.01,119.21 PC1123.2
  TOP w0.254: PC1228.2 58.5,118.69 PC1123.2 PR1130.1
N20135144: length 1.8
  TOP w0.102: v1(58.5,116.01) PC1228.1
  TOP w0.254: PC1228.1 PR1134.2
N20135171: length 28.3
  TOP w0.254: v2(51.94,114.29) 51.52,113.88 PR1131.2
  BOTTOM w0.254: PH1102.1 75.69,109.57 74.94,108.82 66.42,108.82 v1(66.12,109.11) 64.89,109.11 60.26,113.75 56.85,113.75 56.53,113.43 54.05,113.43 53.03,114.45 52.09,114.45 v2(51.94,114.29)
N20135184: length 57.9
  TOP w0.254: PR1104.2 v2(47.33,117.82) 47.15,117.82 46.5,117.17 v1(46.5,116.46) 46.5,116.27 46.93,115.85 PR1108.2
  BOTTOM w0.254: v2(47.33,117.82) 47.03,117.82 46.86,117.99 46.86,118.41 48.58,120.13 48.58,126.59 50.16,128.16 55.38,128.16 62.92,135.7 77.06,135.7 79.55,133.22 79.55,127.78 79.24,127.46 PL1102.3
N20135197: length 1.6
  TOP w0.102: v1(69.18,129.72) 69.07,129.6 PR1107.2
N20135212: length 2.3
  TOP w0.102: v1(59.65,126.78) PR1103.2
  TOP w0.508: PC1108.1 59.72,125.49 PR1103.2
N20135219: length 56.4
  TOP w0.102: v2(80.04,131.29) v1(80.04,130.67)
  TOP w0.254: PR1110.2 47.45,116.93 v2(47.2,117.18)
  BOTTOM w0.254: v2(47.2,117.18) 46.99,117.39 46.88,117.39 46.48,117.8 46.48,118.57 48.23,120.33 48.23,126.73 50.01,128.52 55.23,128.52 62.85,136.14 77.17,136.14 80.04,133.27 v2(80.04,131.29) 80.04,127.72 80.29,127.46 PL1102.2
N20135248: length 2.6
  TOP w0.203: PU1100.40 51.89,126.78 51.99,126.88 v1(52.17,126.88) 52.29,126.76 PU1100.39
N20135251: length 1
  TOP w0.102: v1(52.23,128.42) 52.71,127.93 52.71,127.61
N20135257: length 4.1
  TOP w0.102: v1(51.15,127.67) 50.29,127.67 PR1101.2
  TOP w0.203: PR1101.2 50.68,127.14 50.68,125.18 50.82,125.04 PU1100.1
N20135258: length 4
  TOP w0.203: PU1100.2 50.71,124.64 50.38,124.97 50.38,126.01 50.1,126.29 v1(50.1,126.57) 50.1,126.81 PR1111.2
N20135263: length 1.9
  TOP w0.203: PU1100.34 54.29,127.29 PR1105.2
N20135264: length 3.8
  TOP w0.203: PU1100.33 54.69,127.26 PR1106.2 55.09,127.38 PU1100.32
N20750654: length 7.2
  TOP w0.102: v1(86.67,13.52) UC6.2 88.8,13.52 89.02,13.3 89.02,12.62 89.26,12.38 89.66,12.38 89.87,12.16 DZ4.2 88.9,11.88 RC103.2 CC14.1 RC192.1
N21194767: length 3.8
  BOTTOM w0.102: v1(160.99,90.18) 160.59,89.77 159.86,89.77 159.4,89.3 PR1401.2
  BOTTOM w0.254: PU1400.9 158.45,89.51 158.65,89.3 PR1401.2
N21194773: length 3.8
  BOTTOM w0.254: PC1405.1 PR1405.2 153.37,86.65 153.88,87.16 154.54,87.16 v2(154.73,87.35) 155.19,87.81 PU1400.15
N21195175: length 0.9
  BOTTOM w0.254: PR1409.1 154.27,86.64 PR1410.2
N23700319: length 7.8
  TOP w0.254: v2(163.46,121.47) 163.16,121.47 PL2.1
  BOTTOM w0.102: v1(158.44,123.53) 159.06,122.9 PD4.2
  BOTTOM w0.254: PD4.2 159.79,122.25 PR6.2 160.24,121.79 PQ6.1 163.13,121.79 v2(163.46,121.47)
N26505655: length 5.7
  TOP w0.102: v2(164.48,47.34) 164.48,47.3 164.89,46.89 v1(164.93,46.89)
  TOP w0.254: v2(164.48,47.34) 164.3,47.53 164.3,47.89 PR625.1
  IN3 w0.254: v2(164.48,47.34) 163.92,47.9 162.49,47.9 v2(161.92,47.33)
  BOTTOM w0.254: PR604.2 v2(164.48,47.34) ; v2(161.92,47.33) 161.82,47.43 PR607.2
N26505677: length 3
  TOP w0.102: v2(163.4,47.33) 163.4,46.96 v1(163.66,46.7)
  TOP w0.254: PR626.1 163.47,47.83 163.5,47.79 163.5,47.43 v2(163.4,47.33)
  BOTTOM w0.254: v2(163.4,47.33) 163.59,47.52 PR605.2 PR609.2
N26506002: length 2.9
  TOP w0.203: PU602.40 166.28,50.39 166.49,50.18 167.2,50.18 168.04,49.34 PR616.2
N26506037: length 4.5
  TOP w0.102: v1(167.79,46.93) 167.15,47.57 PR612.2
  TOP w0.203: PU602.39 165.88,49.99 166.64,49.23 166.64,48.52 166.64,48.52 166.64,48.46 PR612.2
N26506689: length 2
  TOP w0.203: PR678.2 165.58,49.43 165.58,49.75 165.48,49.85 PU602.38
N26508248: length 4
  TOP w0.203: PU602.34 163.88,49.83 163.85,49.8 163.85,49.79 v2(163.82,49.79)
  BOTTOM w0.102: 163.85,49.79 v1(164.47,49.79)
  BOTTOM w0.254: PR602.1 162.91,50.57 163.35,50.57 PC603.1 163.66,50.35 163.66,50.35 163.66,49.99 163.85,49.8 163.85,49.79 v2(163.82,49.79)
N26508256: length 5.7
  TOP w0.102: v1(162.64,45.64) PC604.1
  TOP w0.203: PR603.1 162.28,48.86 163.41,50 163.41,50.13 163.48,50.2 PU602.33
  TOP w0.254: PC604.1 162.64,47.64 162.28,48.01 PR603.1
N26509112: length 5.3
  TOP w0.102: PR608.1 160.31,47.92 v1(159.83,47.44)
  TOP w0.203: PR608.1 160.79,48.83 160.79,49.09 160.99,49.29 162.24,49.29 163.08,50.14 PU602.32
N26509117: length 4.5
  TOP w0.102: v1(160.59,50.37) 160.31,50.08 PR611.1
  TOP w0.203: PR611.1 160.74,49.68 162.15,49.68 162.68,50.2 PU602.31
N26518420: length 4.3
  TOP w0.203: PC630.1 160.5,56.72 v1(160.8,56.41) 161.62,55.59 PU602.20
  TOP w0.254: PR640.1 159.71,56.73 PC630.1
N26519264: length 14
  IN3 w0.254: v2(150.87,66.31) 150.87,66.28 156.73,60.42 158.54,60.42 v2(158.77,60.19)
  BOTTOM w0.254: v2(158.77,60.19) v1(159.75,59.21) 159.75,58.27 160,58.01 PR657.2 ; PH605.1 150.83,66.84 150.83,66.35 v2(150.87,66.31)
N26522108: length 1.8
  TOP w0.102: v1(164.23,60.15) PR645.1
  TOP w0.254: PR645.1 PC639.2
N26523008: length 1.9
  TOP w0.102: v1(166.61,61.11) 166.4,60.9 PR650.2
  TOP w0.254: PC647.2 167.26,60.16 PR650.2
N26523611: length 2.7
  BOTTOM w0.102: PC629.2 162.88,56.07 162.88,56.77 v1(163.23,57.12)
  BOTTOM w0.254: PC629.2 163.13,55.24 163.44,55.24 PR639.1
N26526626: length 1.8
  TOP w0.102: PR632.2 v1(171.66,55.32)
  TOP w0.254: PC627.1 170.69,55.33 PR632.2
N26527807: length 45.5
  TOP w0.102: v1(154.66,83.9) 154.66,84.57 v2(154.69,84.61)
  IN3 w0.254: v2(154.69,84.61) 155.28,85.2 163.83,85.2 165.69,83.33 165.69,78.29 164.51,77.11 164.51,73.89 171.85,66.55 171.85,58.57 172.29,58.13 172.29,56.35 171.9,55.95 v2(171.79,55.95)
  BOTTOM w0.254: PR628.2 171.79,55.54 v2(171.79,55.95) ; PH602.1 154.59,84.51 v2(154.69,84.61)
N26528911: length 3.8
  TOP w0.203: PU602.8 167.46,54.12 167.72,54.37 167.72,55.13 167.93,55.33 v1(168.01,55.33) PC627.2
  TOP w0.254: PC627.2 PR638.2
N26532119: length 2
  TOP w0.102: PC621.2 171.23,51.44 v1(171.64,51.85)
  TOP w0.254: PC621.2 PR623.1
N26532121: length 3.9
  TOP w0.203: PU602.5 167.63,52.92 167.68,52.86 168.18,52.86 168.53,53.21 PR622.2
  TOP w0.254: PR622.2 169.78,53.21 PR621.2 169.8,52.33 PR623.2
N26533060: length 4.5
  TOP w0.203: v2(168.17,52.4) 167.86,52.4 167.74,52.52 PU602.4
  BOTTOM w0.102: v2(168.17,52.4) 168.17,52.31 168.85,51.62 v1(168.85,51.43)
  BOTTOM w0.254: PR617.2 167.16,53.1 PC616.2 168.03,52.27 v2(168.17,52.4)
N26533062: length 0.9
  BOTTOM w0.254: PC614.2 166.48,54.07 PR617.1
N26533293: length 2.2
  TOP w0.203: PR610.2 168.53,51.94 167.85,51.94 167.68,52.12 PU602.3
N26533871: length 4.1
  TOP w0.203: PU602.2 167.59,51.72 167.82,51.49 168.26,51.49 168.3,51.45 v2(168.29,51.45)
  BOTTOM w0.102: PR613.2 167.96,50.13 v1(168.5,50.13)
  BOTTOM w0.254: PR613.2 PC613.2 167.68,51.45 v2(168.29,51.45)
N26535263: length 18.9
  TOP w0.254: v2(157.62,59.89) 157.51,59.78 156.82,59.78 156.26,60.34 v1(155.7,60.34) 155.19,60.34 150.32,65.21 150.32,69.11 v2(150.39,69.17)
  BOTTOM w0.254: PR661.1 157.18,59.43 157.64,59.89 v2(157.62,59.89) ; PL603.3 150.96,71.21 150.39,70.64 v2(150.39,69.17)
N26554964: length 1.9
  TOP w0.102: v1(171.65,54.03) 171.55,54.13 PC617.2
  TOP w0.254: PC617.2 PR621.1
N26566701: length 2.2
  BOTTOM w0.102: PR630.2 161.44,51.09 160.97,50.63 160.79,50.63 v1(160.45,50.29)
  BOTTOM w0.254: PC631.1 PR630.2
N26570644: length 1.9
  TOP w0.102: PR644.1 v1(158.84,58.59)
  TOP w0.254: PC630.2 158.86,57.63 PR644.1
N27286345: length 2.8
  BOTTOM w0.102: v1(203.13,40.01) 202.77,39.65 PD704.1
  BOTTOM w0.254: PR743.2 201.25,40.54 PD704.1
N28424999: length 4.6
  BOTTOM w0.076: TP30.1 100.91,72.37 101.39,71.89 101.39,71.69 102.57,70.51 102.57,69.21 UC1.AW71
N28425002: length 5.2
  BOTTOM w0.076: TP31.1 100.85,72.19 101.22,71.82 101.22,71.62 102.33,70.51 102.33,68.96 102.13,68.76 UC1.AW70
N28483977: length 8.9
  TOP w0.254: PR13.2 188.3,24.26 188.46,24.1 v1(188.46,24.05) 188.46,21.71 187.12,20.36 185.76,20.36 ; PQ1.2 185.76,20.36 ; 185.76,20.36 185.76,19.84 PR12.2 PR2.1
N28483985: length 4.6
  TOP w0.254: PQ1.3 186.41,21.81 187.43,22.84 v1(187.43,23.22) 187.43,23.4 187.16,23.67 PR5.2
N28484391: length 3.4
  TOP w0.102: v1(177.2,22.9) 177.38,22.73 PR28.2
  TOP w0.254: PR28.2 177.97,22 178,21.98 PC16.1 178.26,22.01 178.52,22.27 PQ2.3
N28484395: length 3.4
  TOP w0.102: v1(177.12,24.17) 177.58,23.71 PR29.1
  TOP w0.254: PQ2.2 178.71,22.92 178.65,22.86 178.29,22.86 PC16.2 178.03,23.12 PR29.1
N28484412: length 5
  TOP w0.102: v1(183.07,19.79) 183.41,20.13 183.41,21.07 182.89,21.6 PR33.2
  TOP w0.254: PQ2.5 182.77,22.92 PR31.1 182.88,22.8 182.88,21.6 PR33.2
N28484439: length 4.6
  TOP w0.254: PQ3.2 180.05,27.47 PC14.2 179.47,26.92 179.47,26.51 v1(179.22,26.25) 178.35,26.25 PR32.1
N28484451:
  vias: v2(184.49,22.66)
N28712229: length 1.2
  BOTTOM w0.102: 161.58,79.52 161.58,78.75 v1(161.87,78.45)
N28712235: length 2.5
  BOTTOM w0.102: v1(164.27,79.32) 164,79.59 PC671.1
  BOTTOM w0.508: PR672.1 163.18,80.11 PC671.1
N28714500: length 1.8
  BOTTOM w0.203: PR769.2 191.07,35.24 PU703.3
N28714504: length 1.8
  BOTTOM w0.203: PU703.4 190.86,35.64 PR770.2
N28714507: length 12.1
  TOP w0.102: v2(164.15,117.91) 164.69,117.91 v1(164.99,117.61)
  BOTTOM w0.254: 161.09,114.19 161.26,114.03 161.26,112.88 160.42,112.04 PR737.1 ; PC744.2 159.48,108.16 159.05,107.73 159.05,106.84 PQ709.3
  BOTTOM w0.508: PC744.2 159.49,109.26 PR737.1 PR763.1
  vias: v2(161.18,116.4) v2(161.51,118.9) v2(161.54,117.58)
N28714524: length 4.6
  BOTTOM w0.102: v1(194.71,29.57) PC750.1
  BOTTOM w0.203: PC750.1 195.41,31.39 195.41,32.89 195.07,33.24 PU703.27
N28714534: length 0.9
  BOTTOM w0.254: PC752.2 191.28,42.87 PR754.1
N28714559: length 2.2
  BOTTOM w0.203: PR774.2 190.81,37.55 191.93,36.44 PU703.6
N28714562: length 2.6
  BOTTOM w0.203: PR775.2 191.25,37.92 191.25,37.58 191.99,36.84 PU703.7
N28714564: length 6.1
  IN2 w0.508: v2(200.22,33.23) 199.89,33.23 199.4,33.72 v2(199.4,36)
  BOTTOM w0.102: PC721.1 200.65,35.33 v1(200.81,35.17)
  BOTTOM w0.508: PR771.2 199.97,32.98 v2(200.22,33.23) ; v2(199.4,36) 199.74,35.66 PC721.1
N28714572: length 6.2
  BOTTOM w0.102: PR743.1 198.2,41.85 v1(198.39,42.04)
  BOTTOM w0.203: PU703.18 196.93,36.84 197.39,37.29 197.39,37.46
  BOTTOM w0.254: 197.39,37.46 197.39,38.29 PC757.2 198.03,40.36 PR743.1
N28714582: length 2.9
  BOTTOM w0.203: PU703.12 194.27,38.44 192.61,40.1 PR755.2
N28714583: length 3.4
  BOTTOM w0.203: PR776.1 194.39,40.17 PC708.1 194.38,39.36 v1(194.56,39.18) 195.07,38.68 PU703.14
N28714585: length 3.5
  BOTTOM w0.203: PR742.1 195.28,40.17 PC708.2 194.9,39.76 194.9,39.36 195.47,38.8 PU703.15
N28714598: length 2.7
  BOTTOM w0.203: PC747.1 193.3,32.43 193.3,33.04 193.47,33.21 PU703.31
  BOTTOM w0.254: PC747.1 193.63,32.1 PR740.2
N28714599: length 2.7
  BOTTOM w0.203: PU703.32 193.07,33.28 192.97,33.18 192.97,32.46 PC747.2
  BOTTOM w0.254: PR772.2 192.74,32.08 PC747.2
N28714601: length 1.9
  BOTTOM w0.203: PU703.28 194.67,33.17 194.9,32.94 194.9,32.28 PC750.2
N28714604: length 21.1
  TOP w0.254: PR773.1 208.61,23.71 206.08,26.24 197.53,26.24 196.82,26.95 v3(196.82,27.3) 196.82,31.66 v2(197.44,32.28)
  BOTTOM w0.203: v2(197.44,32.28) 197.01,32.28 195.87,33.42 PU703.25
N28714606: length 8.9
  IN3 w0.762: 199.03,32.98 199.03,32.35 200.55,30.82 203.28,30.82 205.19,28.92
  BOTTOM w0.102: v2(206.72,28.73) v1(207.44,28.73)
  vias: v2(200.18,34.46) v2(200.18,33.89) v2(206.14,28.73)
N28714608: length 3.1
  BOTTOM w0.102: PR745.1 196.82,31.51 197.07,31.51 v1(197.11,31.48)
  BOTTOM w0.203: PR745.1 196.17,32.6 195.47,33.3 PU703.26
N28714612: length 0.6
  BOTTOM w0.102: 197.06,33.33 v1(197.06,32.77)
N28714614: length 2.4
  BOTTOM w0.203: PR757.2 197,39.19 197,37.44 196.79,37.24 PU703.17
N28714617: length 1.2
  BOTTOM w0.102: v1(162.3,108.86) 162.06,109.1 162.06,109.94
N28714625: length 1.9
  BOTTOM w0.102: PR779.2 v1(197.07,42.07)
  BOTTOM w0.254: PR779.2 197.06,41.03 PR757.1
N28714693: length 1
  TOP w0.508: PC779.1 v2(210.98,25.69)
  vias: v1(211.54,26.93)
N28714721: length 42
  TOP w0.102: v2(195.54,42.56) v1(195.54,41.95)
  IN3 w0.254: v2(195.54,42.56) 195.54,42.18 196.68,41.04 202.61,41.04 206.81,36.85 208.27,36.85 208.71,36.41 216.23,36.41 217.93,34.7 217.93,27.39 215.42,24.88 213.61,24.88 213.32,25.17 v2(213.32,25.36)
  BOTTOM w0.254: v2(213.32,25.36) 213.32,25.49 213.7,25.87 PR765.2 ; v2(195.54,42.56) 195.28,42.29 PR742.2
N28714724: length 40.5
  TOP w0.102: v2(194.88,42.56) v1(194.88,43.1)
  IN3 w0.254: v2(194.88,42.56) 194.88,42.16 196.38,40.66 202.46,40.66 206.65,36.47 208.11,36.47 208.55,36.03 216.07,36.03 217.55,34.54 217.55,27.55 215.36,25.36 v2(213.95,25.36)
  BOTTOM w0.254: PR776.2 194.39,42.07 v2(194.88,42.56) ; PR765.3 213.7,24.98 213.95,25.23 v2(213.95,25.36)
N28714743: length 4.4
  BOTTOM w0.102: PR738.1 v1(162.07,106.59)
  BOTTOM w0.254: PR737.2 161.12,107.64 PR738.1 161.07,106.64 160.55,106.64 PQ709.2
N28714752: length 99.1
  TOP w0.102: v2(192.87,29.75) v1(192.87,29.15)
  IN3 w0.254: v2(192.87,29.75) 192.87,29.76 192.95,29.84 192.95,30.46 192.08,31.33 188.53,31.33 185.76,34.1 185.76,52.71 172.68,65.79 172.68,70.16 170.16,72.68 170.16,76.11 168.17,78.1 168.17,108.74 166.33,110.58 164.1,110.58 v2(163.98,110.45)
  BOTTOM w0.254: v2(163.98,110.45) 163.85,110.45 163.47,110.83 PR703.2 ; PR772.1 192.74,29.88 192.87,29.76 v2(192.87,29.75)
N28714753: length 99.8
  TOP w0.102: v2(193.45,29.74) v1(193.45,30.32)
  IN3 w0.254: v2(193.45,29.74) 193.35,29.84 193.35,30.59 192.23,31.71 188.69,31.71 186.14,34.26 186.14,52.87 173.06,65.95 173.06,70.32 170.54,72.83 170.54,76.27 168.55,78.26 168.55,108.89 166.48,110.96 164.1,110.96 v2(163.98,111.09)
  BOTTOM w0.254: v2(193.45,29.74) 193.44,29.74 193.44,30.17 PR740.1 ; v2(163.98,111.09) 164.17,111.09 164.42,110.83 PR703.3
N28714782: length 2.9
  TOP w0.102: v1(211.63,33.81) PC767.1
  TOP w0.508: PC767.1 209,33.81 PR766.2
N28714793: length 3.5
  TOP w0.102: v2(210.84,23.77) v1(211.38,23.77)
  TOP w0.508: PC779.2 PR773.2 210.78,23.71 v2(210.84,23.77)
  BOTTOM w0.508: PQ717.4 210.45,23.39 v2(210.84,23.77)
N28714854: length 1.5
  BOTTOM w0.254: PU603.5 161.21,70.4 v2(161.6,70.01) 161.8,69.81 PC655.2
N28714858: length 2.3
  BOTTOM w0.102: PC655.1 163.9,69.81 v1(164.12,69.59)
  BOTTOM w0.508: PR660.1 163.16,70.41 PC655.1
N28714964: length 3.2
  BOTTOM w0.102: v1(162.63,74.35) 162.63,74.08 162.31,73.77 PR659.1
  BOTTOM w0.254: PU603.1 160.97,73.05 161.35,73.43 PR659.1
N28718522:
  vias: v1(154.77,52.79)
N28718526: length 2.1
  BOTTOM w0.102: PR619.1 v1(152.29,55.4)
  BOTTOM w0.508: PR619.1 153.12,54.19 PC611.1
N28810503: length 2.6
  TOP w0.102: CZ10.1 166.63,20.15 v1(167.46,20.99) UZ3.12
N28810563: length 2.5
  TOP w0.102: UZ3.10 166.66,21.76 v1(166,21.09) 165.5,20.6 CZ11.1
N28842863: length 3.1
  BOTTOM w0.254: CC56.1 v1(106.67,27.17) 107.14,27.65 107.14,28.64 UC1.AL1
N28843886: length 6.4
  BOTTOM w0.076: UC1.BB10 100.69,34.1 99.18,32.58 99.18,32.57 97.67,31.06 97.67,30.3 97.21,29.84 97.09,29.84
  BOTTOM w0.102: CC69.1 97.09,29.84
N28856399: length 6.1
  BOTTOM w0.076: TP19.1 99.21,72.18 100.56,70.82 100.56,69.84 100.83,69.57 101.33,69.57 101.62,69.29 101.62,68.73 101.48,68.59 UC1.BA70
N28856402: length 7.5
  BOTTOM w0.076: TP20.1 97.55,73.18 99.02,71.72 99.43,71.72 99.6,71.54 100.4,70.75 100.4,68.51 100.57,68.34 101.02,68.34 UC1.BA68
N28857231: length 7.7
  BOTTOM w0.076: TP21.1 97.12,71.21 99.47,71.21 100.07,70.61 100.07,68.22 100.85,67.44 UC1.BB68
N28857234: length 6
  BOTTOM w0.076: TP22.1 98.27,71.55 99.36,71.55 100.23,70.68 100.23,68.29 100.47,68.05 UC1.BB69
N28857237: length 1.5
  TOP w0.102: TP23.1 108.54,36.11 108.54,36.11 v2(108.54,35.46)
  BOTTOM w0.076: v2(108.54,35.46) 108.51,35.46 UC1.AK13
N28857240: length 1
  TOP w0.102: TP24.1 108.26,35.14 v2(108.55,34.85)
  BOTTOM w0.076: v2(108.55,34.85) 108.23,35.17 UC1.AK12
N28861827: length 7.9
  BOTTOM w0.076: v1(129.39,66.48) 129.03,66.84 RC138.1 128.06,66.84 128.05,66.85 126.18,66.85 125,65.67 124.64,65.67 123.95,64.98 122.79,64.98 122.65,64.84 UC1.C64
N28938912: length 2.4
  BOTTOM w0.102: v1(106.04,12.18) 105.67,12.55 RC21.1 105.12,13.17 104.63,12.67 CC2.2
N29189918: length 2.7
  BOTTOM w0.203: PU703.13 194.67,38.51 193.5,39.67 PR764.2
N29207759: length 49.1
  TOP w0.102: v2(156.29,83.84) v1(156.85,83.84)
  TOP w0.254: v2(168.3,50.83) 168.3,50.83 168.3,50.82 168.37,50.82 168.63,50.55 PR631.2 168.93,50.57 PR610.1
  IN3 w0.254: v2(156.29,83.84) 156.67,84.22 163.72,84.22 164.93,83.02 164.93,78.61 163.75,77.43 163.75,73.58 170.83,66.49 170.83,53.1 168.56,50.83 v2(168.3,50.83)
  BOTTOM w0.254: PH601.2 156.88,83.84 v2(156.29,83.84)
N29270847: length 28.9
  TOP w0.102: v2(156.81,73.96) v1(156.15,73.96)
  TOP w0.254: v2(164.86,58.25) 165.35,58.25 PR635.1 165.49,58.41 PR647.2
  IN3 w0.254: v2(156.81,73.96) 158.22,73.96 158.64,74.38 159.98,74.38 160.44,73.91 160.44,73.28 160.74,72.99 160.74,72.5 162.32,70.92 163.06,70.92 167.18,66.8 167.18,65.64 168.55,64.27 168.55,60.44 166.86,58.76 165.37,58.76 v2(164.86,58.25)
  BOTTOM w0.254: PH603.2 156.52,73.96 v2(156.81,73.96)
N29708599: length 2.8
  TOP w0.102: TP25.1 104.16,31.09 104.17,31.11 104.53,31.11 v2(105.07,31.64)
  BOTTOM w0.076: v2(105.07,31.64) 105.02,31.6 104.36,31.6 103.96,31.2 UC1.AU5
N29708601: length 2
  TOP w0.102: v2(105.83,30.67) 105.83,30.36 TP26.1
  BOTTOM w0.076: v2(105.83,30.67) 105.62,30.87 105.02,30.87 104.7,31.2 UC1.AT5
N32012960: length 2
  IN3 w1.016: 147.78,52.35 147.78,52.16 149.05,50.89
  vias: v1(147.33,52.76) v2(147.83,53.66) v2(147.83,53.08) v2(149.99,50.89) v2(150.58,50.89)
N32012964: length 8.1
  IN3 w1.016: 153.12,54.38 151.97,55.52 150.77,55.52 149.69,56.6 146.64,56.6
  BOTTOM w0.102: v2(144.66,56.54) 144.39,56.54 v1(144.06,56.22)
  vias: v2(145.24,56.54) v2(153.12,53.43) v2(153.7,53.43)
N32015249: length 2.5
  BOTTOM w0.102: PR679.1 149.76,51.64 v1(149.45,51.33)
  BOTTOM w0.254: PU606.7 149.83,52.35 PR679.1
N32433695: length 4
  TOP w0.102: UV14.J13 144.22,101.03 143.85,100.66 143.85,99.47 v1(143.02,98.64) 142.83,98.45 RV120.1
N32433703: length 3
  TOP w0.102: UV14.J1 144.48,110.88 v1(144.48,112.22) 144.48,113.11 RV116.1
N32433714: length 10
  TOP w0.102: v2(152.75,104.35) 152.94,104.54 RV118.1 ; UV14.J10 144.23,103.59 v2(144.61,103.97)
  BOTTOM w0.102: v2(152.75,104.35) v1(152.06,104.35) 151.86,104.35 151.42,104.79 145.42,104.79 v2(144.61,103.97)
N32434049: length 4.4
  BOTTOM w0.102: RV121.1 141.94,97.96 v1(142.62,98.63) 143.83,99.85 143.83,100.63 UV15.J13
N32434050: length 3.3
  BOTTOM w0.102: RV117.1 144.94,112.65 v1(144.94,112.3) 144.94,111.79 144.23,111.08 UV15.J1
N32434053: length 11.1
  BOTTOM w0.102: RV119.1 153,104.91 152.85,104.91 v1(152.04,105.71) 145.65,105.71 144.16,104.23 144.16,103.78 144.23,103.72 UV15.J10
N32437553: length 3.7
  TOP w0.102: UV12.J13 144.24,126.85 144.61,127.21 144.61,128.1 145.55,129.04 v1(145.55,129.11) RV123.1
N32437559: length 4.7
  BOTTOM w0.102: UV13.J13 144.55,127.17 144.55,128.04 145.55,129.03 RV132.1 v1(146.57,130)
N32437560: length 3.2
  BOTTOM w0.102: RV131.1 144.55,114.66 v1(144.55,115.42) 144.55,116.93 UV13.J1
N32437563: length 10
  BOTTOM w0.102: UV13.J10 144.23,124.04 144.54,123.72 144.54,123.59 144.86,123.28 151.28,123.28 151.79,123.79 v1(152.04,123.79) 152.79,123.79 RV133.1
N32778757: length 2.9
  BOTTOM w0.102: PR671.1 162.3,83.07 162.3,84 v1(162.26,84.04)
  BOTTOM w0.254: PU605.1 161.3,82.06 161.55,82.32 161.55,82.76 161.81,83.02 PR671.1
N32842463: length 7
  TOP w0.102: RC137.2 113.3,31.36 113.23,31.43 v1(113.23,31.95) 113.23,32.08 113.82,32.66 114.13,32.66 114.32,32.86 114.32,33.26 114.13,33.45 114.13,34.37 113.76,34.74 v2(113.76,34.8)
  BOTTOM w0.076: v2(113.76,34.8) 114.05,34.52 UC1.U11 UC1.U12
N33124395: length 4
  BOTTOM w0.203: PU200.12 85.53,104.52 v1(85.24,104.23) 85.24,103.9 84.99,103.66 PR210.1
  BOTTOM w0.508: PC204.2 83.97,103.91 PR210.1
N33124472: length 2.9
  TOP w0.102: v1(75.82,104.72) PC207.2
  TOP w0.508: PR203.1 74.82,102.78 PC207.2
N33188643: length 5.6
  TOP w0.102: RA24.1 17.65,28.64 RA23.2 v3(15.27,27.13) 14.75,26.61 CA31.1
N36085760: length 3.4
  BOTTOM w0.102: v1(163.68,128.26) 162.23,126.8 PD6.1
  BOTTOM w0.254: PR11.2 161.89,126.18 PD6.1
N37640332: length 1.4
  TOP w0.381: v2(115.24,109.25) 114.71,109.25 RV2.2
  BOTTOM w0.381: v2(115.24,109.25) 115.31,109.25 115.34,109.28 115.7,109.28 UV1.N10
N37640410: length 1.4
  TOP w0.508: v2(109.24,119.41) 109.29,119.47 RV3.1
  BOTTOM w0.381: v2(109.24,119.41) 109.24,118.94 UV1.AA22
N37828209: length 1.4
  TOP w0.508: RV1.1 110.37,119.54 v2(110.48,119.43)
  BOTTOM w0.381: v2(110.48,119.43) 110.48,119.43 110.48,118.74 UV1.Y22
N38038746: length 2.7
  BOTTOM w0.102: RV37.2 133.5,95.51 RV36.2 134.39,95.52 CV96.1 v1(136.23,95.52)
N38038992: length 5.9
  TOP w0.102: v2(118.4,107.09) 118.59,107.09 v1(118.87,106.81) 119.41,106.27 119.41,105.12 118.64,104.35 118.64,103.31 118.83,103.12 CV98.2
  BOTTOM w0.102: UV1.K8 118.06,107.43 v2(118.4,107.09)
N38038994: length 4.8
  TOP w0.102: v2(117.59,106.5) 117.77,106.5 118.09,106.18 118.09,105.31 118.13,105.28 118.13,103.91 117.46,103.25 CV99.2
  BOTTOM w0.102: v2(117.59,106.5) 117.28,106.5 UV1.L7
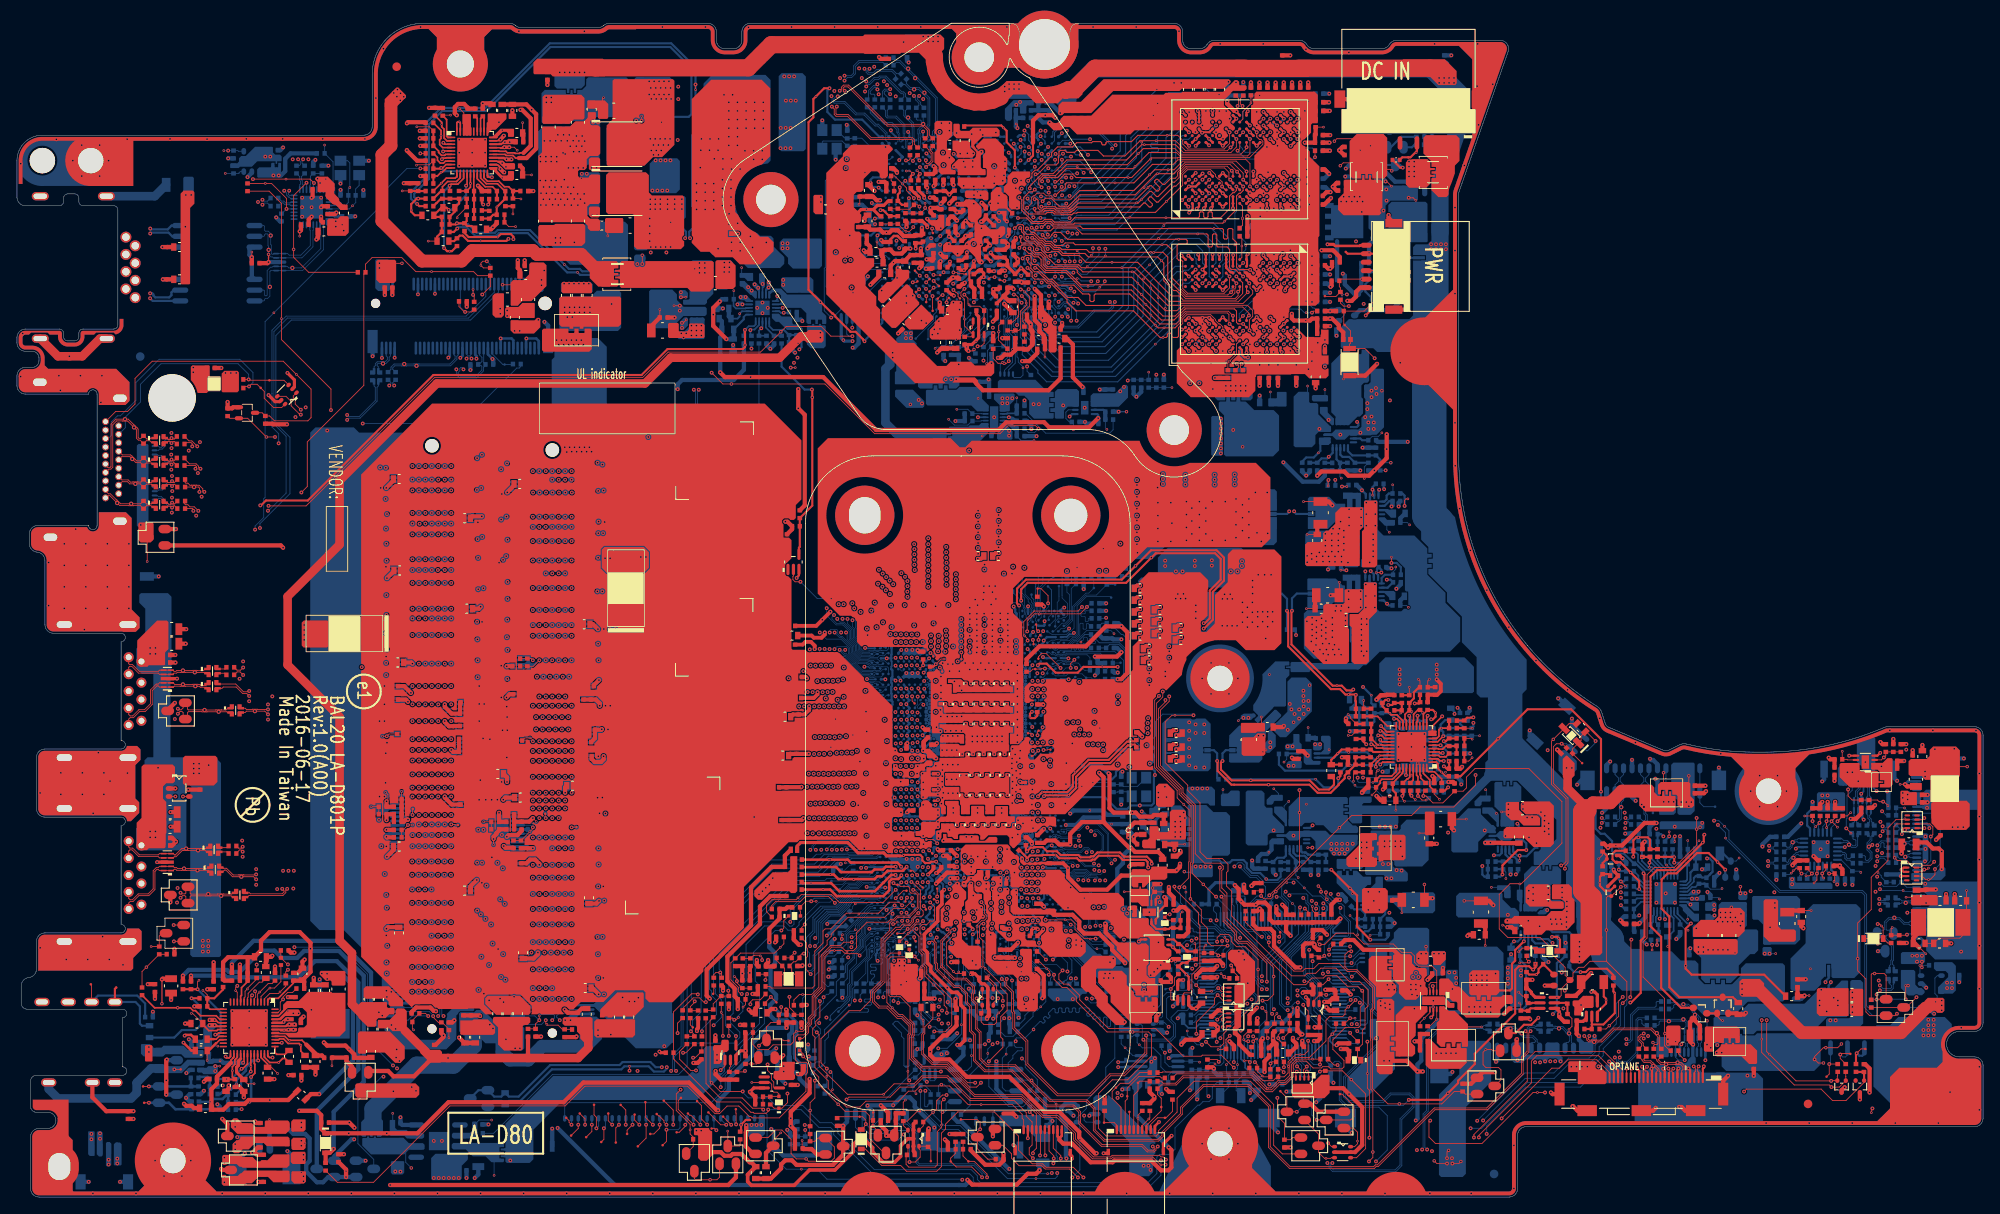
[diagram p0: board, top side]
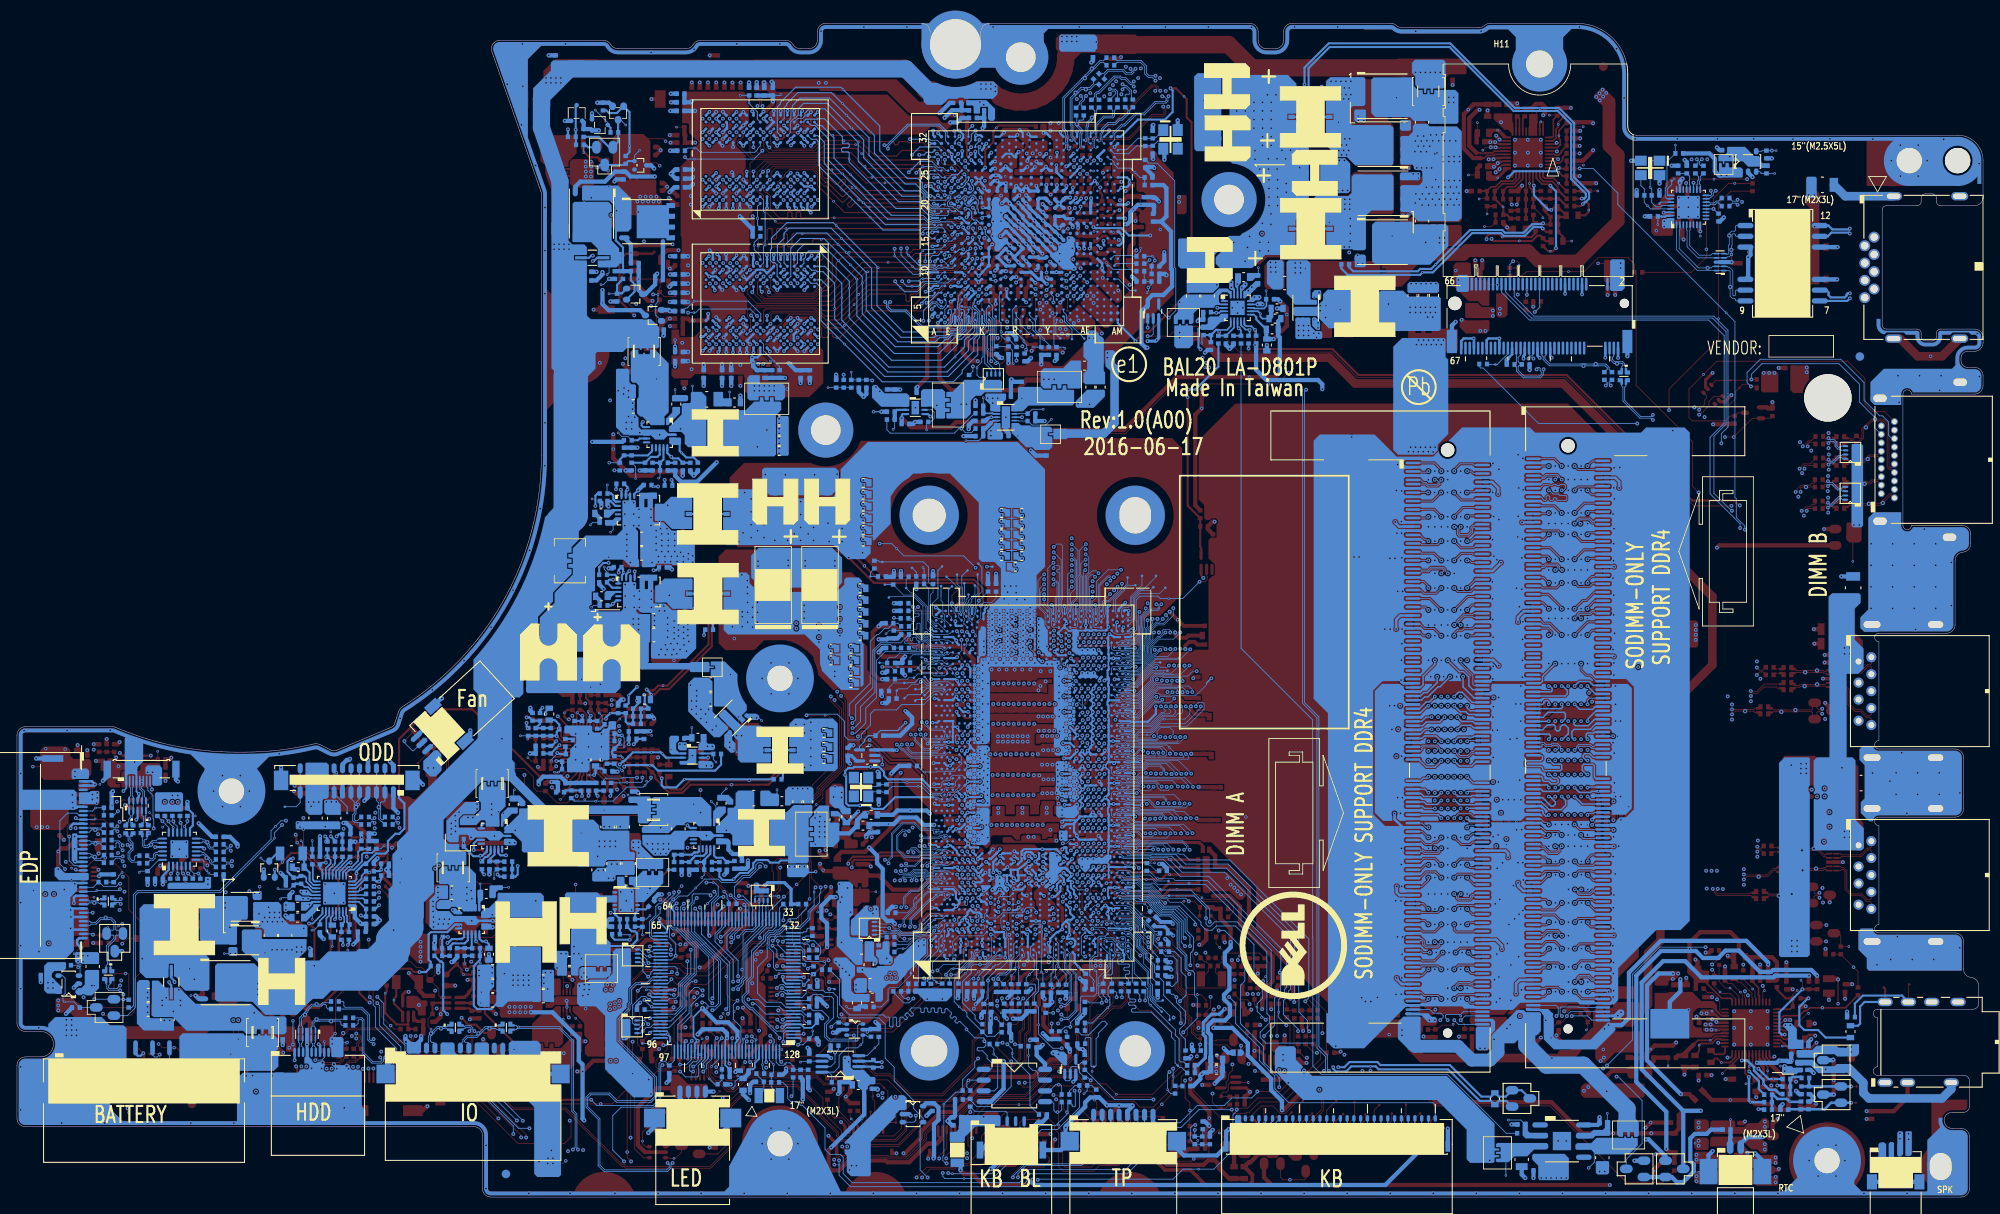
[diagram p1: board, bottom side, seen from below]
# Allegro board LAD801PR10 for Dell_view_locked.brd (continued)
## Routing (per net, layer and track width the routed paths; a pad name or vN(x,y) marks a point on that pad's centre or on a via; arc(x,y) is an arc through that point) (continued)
N38038995: length 0.9
  TOP w0.102: RV40.2 CV98.1
N38038996: length 3.8
  TOP w0.102: RV41.2 116.79,100.11 115.78,101.11 v1(115.78,102.08) 115.78,102.82 CV99.1
N38349725: length 10.6
  TOP w0.254: v2(117.7,121.48) 117.7,123.52 116.73,124.48 116.73,125.81 v1(116.38,126.17) 116.1,126.45 111.86,126.45 RV39.2
  BOTTOM w0.3: v2(117.7,121.48) UV1.K25
N38996077: length 3.2
  TOP w0.102: RV134.1 144.55,114.66 v1(144.55,115.54) 144.55,116.93 UV12.J1
N38996080: length 11.5
  TOP w0.102: v2(143.97,123.47) 144.23,123.72 UV12.J10 ; RV135.1 v2(153.1,122.71)
  BOTTOM w0.102: v2(153.1,122.71) 152.88,122.48 v1(152.01,122.48) 144.96,122.48 v2(143.97,123.47)
N39282118:
  vias: v1(157.53,35.82)
N39282176: length 2.7
  TOP w0.102: PR506.2 v1(163.34,33.55)
  TOP w0.508: PR506.2 162.28,35.07 PC504.1
N39282188: length 1.8
  BOTTOM w0.102: v1(158.13,30.94) PR504.2
  BOTTOM w0.254: PR503.1 159,31.89 PR504.2
N40598435: length 1.1
  BOTTOM w0.102: PR100.2 173.31,47.97 v1(173.22,48.06)
N40598492: length 1.7
  TOP w0.102: v1(175.24,32.08) 175.36,32.08 175.6,31.84 v2(175.79,31.84)
  TOP w0.508: v2(175.79,31.84) 176.29,31.84 PC119.1
N40598500: length 1
  BOTTOM w0.102: v1(173.91,36.54) 174.84,36.54 PC114.1
N40598503: length 2.1
  BOTTOM w0.102: PC113.2 175.62,38.34 v1(175.62,37.58)
  BOTTOM w0.254: PC113.2 175.27,38.7 PR108.1
N40598539: length 1.8
  BOTTOM w0.102: v1(179.09,27.52) PC127.2
  BOTTOM w0.254: PC127.2 179.08,28.47 PR117.1
N40598619: length 2.8
  TOP w0.102: PR116.2 177.56,29.37 v1(177.12,28.94)
  TOP w0.254: PR116.2 179.27,29.37 PD102.1
N40605947: length 3.6
  BOTTOM w0.254: PC305.1 147.4,39.53 PR303.2 148.16,39.54 148.67,40.04 149.44,40.04 149.67,40.27 PU300.15
N40606056: length 0.9
  BOTTOM w0.254: PR309.2 149.07,39.52 PR308.1
N40664383: length 2.6
  TOP w0.102: TP41.1 65.45,43.65 v2(65.42,43.62)
  BOTTOM w0.102: JDIMM1.165 66.2,44.13 65.7,43.62 v2(65.42,43.62)
N40665360: length 2.9
  TOP w0.102: TP42.1 51.73,43.9 51.67,43.97 51.63,43.97 51.63,43.97 v2(51.22,43.97)
  BOTTOM w0.102: JDIMM2.165 52.17,44.63 51.73,44.18 51.41,44.18 51.22,43.99 v2(51.22,43.97)
N40665398: length 2.7
  TOP w0.102: TP43.1 46.65,45.76 v2(46.65,45.09)
  BOTTOM w0.102: JDIMM2.162 45.87,45.38 45.96,45.28 46.46,45.28 v2(46.65,45.09)
N41321201: length 4.7
  TOP w0.254: PQ721.2 188.43,36.66 187.92,36.15 187.28,36.15 186.71,36.72 v1(186.71,37.1) 186.71,37.8 PR790.2 187.72,38.11 PC790.1
N41527020: length 4.2
  TOP w0.102: v2(62.37,44.71) 62.31,44.78 TP40.1
  BOTTOM w0.102: v2(62.37,44.71) 61.85,45.24 60.41,45.24 60.05,44.87 JDIMM1.162
N124752685: length 1.8
  TOP w0.102: CD30.2 RD11.1 v1(55.04,44.28)
N124753277: length 1.8
  TOP w0.102: v1(41.78,46.06) CD59.2 RD22.1
N233927670: length 3
  TOP w0.203: PU602.1 167.42,51.32 167.6,51.14 167.6,50.57 167.75,50.41 167.76,50.41 v1(168.03,50.14) 168.53,49.65 PR620.2

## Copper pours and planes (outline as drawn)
2.5V_VIN on BOTTOM (solid shape): 57.46,6.23 57.46,5.89 56.91,5.89 56.91,5.34 57.46,5.34 57.46,5.09 56.91,5.09 56.91,4.54 57.46,4.54 57.46,4.22 57.35,4.11 55.97,4.11 55.28,4.79 53.76,4.79 52.94,5.62 51.47,5.62 51.28,5.81 51.28,6.2 51.46,6.38 57.3,6.38
3V_SN on TOP (solid shape): 167.21,45.36 167.21,42.89 167.02,42.7 166.2,42.7 166.07,42.82 166.07,45.43 166.13,45.49 167.09,45.49
3V_VIN on TOP (solid shape): 177.19,46.56 177.19,45.67 177.82,45.04 179.34,45.04 179.66,44.72 179.66,43.9 179.59,43.83 177.69,43.83 177.06,44.47 176.23,44.47 175.6,45.1 175.6,46.5 175.72,46.63 177.12,46.63
3V_VIN on BOTTOM (solid shape): 175.2,48.46 175.7,48.46 175.7,48.99 176,48.99 176,48.46 176.5,48.46 176.5,48.99 176.86,48.99 177.44,48.41 177.44,46.82 177.19,46.56 177.19,45.67 177.82,45.04 179.22,45.04 179.66,44.6 179.66,43.96 179.6,43.9 177.76,43.9 177.2,44.46 176.72,44.46 176.6,44.33 176.6,43.77 176.53,43.7 175.07,43.7 174.99,43.78 174.99,45.36 174.26,46.09 174.26,48.85 174.4,48.99 175.2,48.99
5V_VIN on TOP (solid shape): 180.87,36.66 180.87,35.07 181.03,34.91 182.3,34.91 182.46,34.75 182.46,34.12 182.36,34.03 180.9,34.03 180.65,34.28 178.42,34.28 177.95,34.75 177.95,36.53 178.33,36.91 180.61,36.91
5V_VIN on BOTTOM (solid shape): 179.8,38.51 180.31,38.51 180.31,39.04 180.6,39.04 180.6,38.51 181.11,38.51 181.11,39.04 181.72,39.04 182.14,38.62 182.14,37.04 182.04,36.94 181.09,36.94 180.9,36.75 180.9,35.17 181,35.07 182.01,35.07 182.39,34.69 182.39,34.12 182.26,33.98 180.89,33.98 180.63,34.25 180.11,34.25 179.89,34.03 179.54,34.03 179.22,33.7 177.76,33.7 177.68,33.78 177.68,34.52 177.76,34.59 177.76,38.12 178.67,39.04 179.8,39.04
+0.6V_DDR_VTT on TOP (solid shape): 95.14,102 95.14,101.05 94.92,100.83 93.15,100.83 92.92,101.05 92.92,101.87 93.37,102.32 94.83,102.32
+0.6V_DDR_VTT on TOP (solid shape): 60.55,21.1 60.55,20.62 60.24,20.31 59.81,20.31 59.67,20.17 59.67,17.47 59.48,17.28 57.46,17.28 56.74,18 56.74,20.03 56.14,20.63 56.14,21.1 56.31,21.27 60.38,21.27
+0.6V_DDR_VTT on TOP (solid shape): 43.64,22.95 43.64,22.44 43.77,22.31 44.41,22.31 44.53,22.19 44.53,21.67 44.42,21.55 43.9,21.55 43.45,21.11 42.63,21.11 42.37,20.85 42.37,20.22 42.25,20.09 41.36,20.09 40.28,21.17 40.28,22.69 40.6,23.01 43.58,23.01
+0.6V_DDR_VTT on BOTTOM (solid shape): 95.4,102.77 95.4,100.41 95.14,100.16 93.62,100.16 93.17,100.6 93.17,102.76 93.28,102.86 95.31,102.86
+0.6V_DDR_VTT on BOTTOM (solid shape): 43.57,21.52 45.66,21.52 45.72,21.46 45.72,21.29 45.66,21.22 43.62,21.22 43.52,21.12 42.75,21.12 42.32,21.54 42.32,21.93 42.52,22.13 42.96,22.13
+0.6V_DDR_VTT on BOTTOM (solid shape): 59.95,21.01 59.95,20.74 59.93,20.72 58.17,20.72 58.04,20.58 58.04,20.18 58.12,20.1 58.28,20.1 58.33,20.09 59.69,20.09 59.84,19.95 59.84,17.55 59.61,17.32 58.48,17.32 58.2,17.59 58.2,19.04 57.6,19.64 57.6,19.64 57.55,19.7 57.55,20.77 57.83,21.04 59.92,21.04
+0.6V_DDR_VTT on IN2 (solid shape): 43.6,21.79 43.6,20.15 43.42,19.98 42.57,19.98 42.37,20.18 42.37,21.93 42.58,22.15 43.24,22.15
+0.6V_DDR_VTT on IN2 (solid shape): 59.69,17.68 59.69,16.13 59.46,15.9 58.58,15.9 58.42,16.07 58.42,17.74 58.49,17.81 59.56,17.81
+0.6VSP on BOTTOM (solid shape): 90.83,106.51 94,106.51 94,106.51 94.18,106.51 94.98,105.71 94.98,104.45 95.46,103.97 95.46,103.08 95.4,103.02 94.97,103.02 94.97,103.53 94.47,103.53 94.47,103.02 94.17,103.02 94.17,103.53 93.67,103.53 93.67,103.02 93.3,103.02 93.11,103.21 93.11,104.29 92.47,104.93 90.67,104.93 90.5,105.23 90.16,105.24 89.11,105.24 89.05,105.31 89.05,105.37 89.11,105.43 89.93,105.43 90.13,105.62 90.13,106.39 89.74,106.77 89.11,106.77 88.86,106.51 88.86,106.13 88.85,106.08 88.81,106.04 88.68,106.04 88.63,106.09 88.63,106.88 88.67,106.92 88.79,106.92 88.8,106.94 88.83,106.94 89.11,107.21 90.12,107.21
+0.95VSDGPU on TOP (solid shape): 113.37,96.35 113.37,95.9 113.24,95.78 113.05,95.78 112.73,96.09 110.38,96.09 110.33,96.15 110.37,96.19 110.52,96.37 110.53,96.6 110.55,96.69 110.63,96.73 112.99,96.73
+0.95VSDGPU on TOP (solid shape): outline of 186 points within 108.21,120.67 110.73,126.99
+0.95VSDGPU on BOTTOM (solid shape): 108.5,97.81 110.8,97.81 111.16,97.45 111.16,96.2 111.16,96.2 111.16,95.73 111.11,95.73 110.78,95.4 109.9,95.4 109.9,95.92 109.19,95.92 109.19,95.4 108.7,95.4 108.7,95.92 107.99,95.92 107.99,95.4 106.5,95.4 106.28,95.63 106.28,97.5 106.38,97.61 106.38,98.61 106.48,98.71 107.6,98.71
+0.95VSDGPU on IN1 (solid shape): outline of 1060 points within 98.16,95.9 113.18,127.58
+0.95VSDGPU_OUT on BOTTOM (solid shape): 108.57,95.27 108.58,95.27 109.32,95.27 109.32,95.27 109.32,95.79 109.77,95.79 109.77,95.27 109.78,95.27 110.83,95.27 111.16,95.6 113.67,95.6 113.84,95.43 113.84,94.19 114.62,93.4 114.62,92.78 114.55,92.71 113.26,92.71 112.57,93.4 109.7,93.4 109.7,93.4 107.4,93.4 107.21,93.6 107.21,95.15 107.32,95.27 108.12,95.27 108.12,95.27 108.12,95.79 108.57,95.79
+1.0V_AMPHYPLL on TOP (solid shape): 118.07,36.28 118.07,34.31 118.32,34.05 118.4,34.05 118.41,34.05 118.57,34.01 118.74,34.05 118.75,34.05 118.99,34.05 119.19,33.99 119.4,34.05 120.8,34.05 120.85,34.01 121.15,33.9 121.43,34.05 122.38,34.05 122.58,33.86 122.58,33.42 122.49,33.33 117.53,33.33 117.18,33.68 117.18,34.39 117.2,34.4 117.37,34.65 117.26,34.93 117.23,35.01 117.27,35.08 117.39,35.39 117.2,35.66 117.18,35.68 117.18,36.09 117.5,36.4 117.94,36.4
+1.0V_AMPHYPLL on BOTTOM (solid shape): 131.92,30.08 131.92,27.83 131.88,27.79 131.02,27.79 130.96,27.73 130.96,27.47 130.8,27.32 130.61,27.32 130.4,27.53 130.4,28.1 130.81,28.51 130.81,30.06 130.92,30.17 131.83,30.17
+1.0V_APLLEBB on IN2 (solid shape): outline of 87 points within 116.23,39.32 117.62,41.99
+1.0V_APLLEBB on IN2 (solid shape): outline of 134 points within 118.64,42.75 123.91,44.09
+1.0V_CLK2 on IN2 (solid shape): outline of 298 points within 117.86,37.36 122.38,39.39
+1.0V_MPHYGT on TOP (solid shape): outline of 883 points within 114.89,28.34 126.07,37.86
+1.0V_MPHYGT on BOTTOM (solid shape): 116.5,38.03 116.5,37.7 116.5,37.65 116.5,37.6 116.5,36.89 117.06,36.33 117.06,36.12 116.94,36 116.74,36 116.66,36.05 116.56,36.07 116.54,36.07 116.3,36.31 116.3,36.33 115.97,36.61 115.64,36.33 115.64,36.31 115.36,36.03 115.32,36 115.08,36 114.93,36.15 114.93,36.48 115.1,36.65 115.12,36.65 115.4,36.83 115.39,37.16 115.39,37.55 115.55,37.71 115.56,37.71 115.7,37.78 115.77,37.92 115.78,37.94 115.83,37.99 115.86,37.97 116.09,37.96 116.28,38.11 116.43,38.11
+1.0V_MPHYGT on BOTTOM (solid shape): outline of 154 points within 124.65,23.07 132.84,30.56
+1.0V_MPHYGT on IN1 (solid shape): outline of 87 points within 114.84,35.82 117.31,37.89
+1.0V_PRIM on TOP (solid shape): 137.88,45.46 137.88,42.32 137.73,42.17 136.04,42.17 136.04,42.18 134.45,42.18 134.3,42.03 134.3,41.18 134.26,41.14 132.9,41.14 132.72,41.32 132.72,42.02 132.88,42.19 133.37,42.19 133.58,42.4 133.58,43.7 133.65,43.76 134.53,43.76 134.68,43.61 134.68,43.2 134.82,43.06 135.71,43.06 135.98,43.34 135.98,45.43 136.26,45.71 137.63,45.71
+1.0V_PRIM on TOP (solid shape): outline of 1100 points within 111.32,25.96 136.17,41.61
+1.0V_PRIM on BOTTOM (solid shape): 137.88,45.57 137.88,45.1 138.39,44.6 138.39,43.77 137.87,43.77 137.87,43.07 138.39,43.07 138.39,42.57 137.87,42.57 137.87,41.87 138.39,41.87 138.39,41.35 138.34,41.3 135.61,41.3 134.89,42.02 134.89,44.02 135.05,44.18 135.94,44.18 136.1,44.34 136.1,46.1 136.21,46.22 137.23,46.22
+1.0V_PRIM on BOTTOM (solid shape): 117.68,94.7 117.68,94.46 117.68,94.45 117.65,94.32 117.68,94.18 117.68,94.17 117.68,94.07 117.11,93.5 117.11,92.8 117.02,92.71 116.72,92.71 116.68,92.67 115.97,92.67 115.91,92.73 115.91,93.46 115.23,94.13 115.23,94.76 115.29,94.82 116.03,94.82 116.03,94.83 117.56,94.83
+1.0V_PRIM on BOTTOM (solid shape): 135.59,28.09 135.59,27.71 134.89,27.01 134.89,25.99 134.64,25.74 134.64,23.52 134.13,23.01 131.46,23.01 131.34,23.13 131.34,23.9 131.4,23.96 132.55,23.96 132.55,23.96 132.98,23.96 132.98,23.96 133.12,23.96 133.5,24.34 133.5,25.68 133.05,26.12 133.05,27.27 134.06,28.28 135.4,28.28
+1.0V_PRIM on IN2 (solid shape): 117.68,94.64 117.68,92.86 117.22,92.4 116.99,92.4 116.91,92.39 116.83,92.36 116.82,92.35 115.38,92.35 115.31,92.37 115.25,92.37 115.18,92.37 115.12,92.35 113.47,92.35 113.46,92.36 113.35,92.37 113.24,92.36 113.23,92.35 112.9,92.35 112.74,92.51 112.74,94.85 112.81,94.92 117.4,94.92
+1.0V_PRIM on IN2 (solid shape): 110.13,5.8 110.13,3.83 109.49,3.19 102.45,3.19 101.75,3.89 101.75,4.16 104.92,4.16 104.92,4.11 104.93,4.05 104.95,4 104.97,3.95 105,3.91 105.04,3.87 105.08,3.84 105.12,3.81 105.17,3.79 105.22,3.78 105.28,3.78 105.33,3.78 105.38,3.79 105.43,3.81 105.48,3.84 105.52,3.87 105.56,3.91 105.59,3.95 105.61,4 105.63,4.05 105.63,4.11 105.63,4.16 105.63,4.21 105.61,4.26 105.59,4.31 105.56,4.36 105.52,4.39 105.48,4.43 105.43,4.45 105.38,4.47 105.33,4.49 105.28,4.49 105.22,4.49 105.17,4.47 105.12,4.45 105.08,4.43 105.04,4.39 105,4.36 104.97,4.31 104.95,4.26 104.93,4.21 104.92,4.16 101.75,4.16 101.75,5.29 102.7,6.24 109.68,6.24
+1.0V_PRIM on IN2 (solid shape): 133.68,13.61 133.68,10.82 131.71,8.84 130.32,8.84 129.27,9.9 129.27,12.5 129.5,12.72 130.02,12.72 130.02,12.67 130.03,12.62 130.04,12.57 130.07,12.52 130.1,12.47 130.13,12.43 130.17,12.4 130.22,12.37 130.27,12.36 130.32,12.34 130.37,12.34 130.43,12.34 130.48,12.36 130.53,12.37 130.58,12.4 130.62,12.43 130.65,12.47 130.68,12.52 130.71,12.57 130.72,12.62 130.73,12.67 130.73,12.72 130.72,12.78 130.71,12.83 130.68,12.87 130.65,12.92 130.62,12.96 130.58,12.99 130.53,13.02 130.48,13.04 130.43,13.05 130.37,13.05 130.32,13.05 130.27,13.04 130.22,13.02 130.17,12.99 130.13,12.96 130.1,12.92 130.07,12.87 130.04,12.83 130.03,12.78 130.02,12.72 129.5,12.72 130.64,13.87 133.43,13.87
+1.0V_PRIM on IN2 (solid shape): outline of 192 points within 113.43,4.34 121.81,8.53
+1.0V_PRIM on IN3 (solid shape): outline of 330 points within 128.86,9.93 136.04,28.92
+1.0V_PRIM on VCC: 132.78,25.67 130.68,27.77 111.1,27.77 110.34,27 107.83,27 105.56,29.28 105.56,33.07 105.62,33.13 105.62,33.34 105.56,33.4 105.56,41.36 131.26,41.36 136.21,46.31 138.39,46.31 138.39,27.77 136.38,27.77 134.28,25.67
+1.0V_VCCST on TOP (solid shape): 135.69,38.88 135.69,37.7 135.43,37.44 134.68,37.44 134.68,37.44 133.87,37.44 132.95,36.53 132.7,36.53 132.7,37.06 132.26,37.06 132.26,36.53 131.67,36.53 131.46,36.74 131.46,38.57 131.59,38.7 133.14,38.7 133.54,38.56 133.79,38.9 133.79,38.92 133.84,38.97 133.86,38.97 133.93,38.98 134.01,39.01 135.55,39.01
+1.0V_VCCST on TOP (solid shape): 118.77,40.04 118.77,39.77 118.79,39.75 118.79,39.73 119.04,39.46 119.4,39.56 119.41,39.58 119.47,39.58 119.49,39.56 119.76,39.45 120.02,39.58 120.13,39.58 120.14,39.57 120.37,39.5 120.59,39.58 121.12,39.58 121.19,39.57 121.25,39.58 121.43,39.58 121.5,39.64 122.07,39.64 122.07,39.13 121.29,39.13 121.02,39.28 120.74,39.15 120.72,39.13 120.66,39.13 120.65,39.15 120.42,39.22 120.19,39.13 119.97,39.13 119.77,39.21 119.56,39.13 119.4,39.13 119.14,39.24 118.89,39.13 118.73,39.13 118.69,39.17 118.64,39.2 118.32,39.52 118.32,40.14 118.41,40.23 118.58,40.23
+1.0V_VCCST_C on TOP (solid shape): 133.5,36.16 133.5,34.38 133.43,34.31 132.67,34.31 132.23,34.76 131.46,34.76 131.34,34.89 131.34,36.28 131.44,36.38 133.27,36.38
+1.0V_VCCSTG on TOP (solid shape): outline of 125 points within 129.72,23.77 134.58,30.06
+1.0VS_VCCIO on TOP (solid shape): 107.94,46.34 107.94,46.06 108.06,45.94 108.81,45.94 108.86,45.89 108.86,45.04 108.29,44.47 106.7,44.47 106.38,44.79 106.38,45.87 106.64,46.12 106.64,46.56 106.89,46.82 107.47,46.82
+1.0VS_VCCIO on TOP (solid shape): 108.67,51.9 108.67,51.67 108.67,51.64 108.54,51.52 108.22,51.52 107.97,51.77 107.4,51.77 107.34,51.83 107.34,52.14 107.34,52.22 107.14,52.41 106.76,52.41 106.64,52.53 106.64,52.79 106.76,52.91 107.65,52.91
+1.0VS_VCCIO on TOP (solid shape): 130.91,26.13 130.91,25.03 131.75,24.18 131.75,23.86 132.03,23.59 132.39,23.59 132.4,23.59 132.53,23.59 132.53,23.06 133.03,23.06 133.03,23.59 133.33,23.59 133.33,23.06 133.83,23.06 133.83,23.59 134.43,23.59 134.58,23.44 134.58,22 134.46,21.89 134.39,21.84 134.33,21.78 133.88,21.32 133.88,20.66 133.68,20.47 131.53,20.47 128.99,23.01 128.99,23.83 127.53,25.29 127.53,26.56 127.68,26.71 130.32,26.71
+1.0VS_VCCIO on TOP (solid shape): 104.79,28.16 104.79,27.65 104.91,27.53 104.91,27.5 105.57,27.5 105.57,27.51 106.09,27.51 106.34,27.27 106.34,27.1 106.27,27.1 106.27,26.09 106.25,26.07 106.15,25.69 106.45,25.43 106.47,25.43 106.51,25.38 106.51,23.2 106.32,23.01 105.06,23.01 104.24,23.82 103.08,23.82 103.02,23.89 103.02,27.57 103.08,27.67 103.19,27.64 103.65,27.58 103.78,28.02 103.79,28.12 103.87,28.17 104.78,28.17
+1.0VS_VCCIO on BOTTOM (solid shape): 107.4,46.1 107.4,46.11 107.5,46.11 107.59,46.05 107.69,46.03 108.12,46.03 108.41,45.96 108.63,46.16 108.71,46.22 108.8,46.19 109.02,46.09 109.25,46.17 109.32,46.11 109.32,45.03 109.06,44.78 108.56,44.78 108.54,44.78 108.33,44.8 108.15,44.71 107.8,44.71 107.79,44.71 107.69,44.73 107.58,44.71 107.57,44.71 107.2,44.71 106.8,45.1 106.78,45.13 106.75,45.15 106.64,45.26 106.64,45.58 106.67,45.6 106.78,45.69 106.82,45.83 106.82,45.95 106.64,46.13 106.64,46.39 106.77,46.53 106.98,46.53
+1.0VS_VCCIO on IN1 (solid shape): outline of 2736 points within 101.62,38.39 109.18,52.93
+1.0VS_VCCIO on IN2 (solid shape): outline of 5149 points within 102.19,24.78 130.51,46.56
+1.2V_DDR on TOP (solid shape): 82.34,33.98 72.34,33.98 72.34,48.98 82.34,48.98
+1.2V_DDR on TOP (solid shape): 86.24,62.05 78.24,62.05 78.24,70.05 86.24,70.05
+1.2V_DDR on TOP (solid shape): 86.28,82.9 78.28,82.9 78.28,90.9 86.28,90.9
+1.2V_DDR on TOP (solid shape): 64.79,102.47 65.04,102.47 65.04,101.96 65.75,101.96 65.75,102.47 66.24,102.47 66.24,101.96 66.95,101.96 66.95,102.47 67.65,102.47 67.8,102.32 67.8,100.06 67.49,99.74 62.12,99.74 61.93,99.93 61.93,102.28 62.12,102.47 64.79,102.47
+1.2V_DDR on TOP (solid shape): outline of 29365 points within 40.6,21.55 107.91,93.64
+1.2V_DDR on BOTTOM (solid shape): 69.57,100.33 69.57,88.17 69,87.6 64.81,87.6 64.32,88.09 64.32,88.8 63.07,90.04 63.07,98.8 63.39,99.11 63.39,101.17 63.58,101.36 68.54,101.36
+1.2V_DDR on BOTTOM (solid shape): outline of 252 points within 41.42,45.12 50.21,60.56
+1.2V_DDR on BOTTOM (solid shape): outline of 4269 points within 46.5,44.38 71.74,60.56
+1.2VP on TOP (solid shape): 71.27,106.07 71.27,103.01 70.95,102.7 64.22,102.7 63.96,102.95 63.96,106.07 64.15,106.26 71.08,106.26
+1.2VP on BOTTOM (solid shape): 71.27,106.7 71.27,102.58 70.88,102.2 64.15,102.2 63.96,102.39 63.96,106.07 64.15,106.26 67.71,106.26 68.4,106.95 71.01,106.95
+1.2VP on BOTTOM (solid shape): 90.18,103.91 91.2,103.91 91.46,103.66 91.46,103.11 91.59,102.97 92.18,102.97 92.29,102.86 92.29,102.39 92.23,102.32 90.82,102.32 89.87,103.27 89.49,103.27 89.05,103.72 89.05,104.16 89.11,104.23 89.86,104.23
+1.2VP on BOTTOM (solid shape): 88.92,108.03 88.92,107.23 88.74,107.05 88.57,107.05 88.44,106.91 88.44,106.09 88.38,106.03 88.28,106.03 88.24,106.07 88.24,107.16 88.41,107.33 88.41,108.03 88.54,108.16 88.79,108.16
+1.2VP on IN2 (solid shape): 67.84,104.41 67.84,103.27 67.65,103.08 66.89,103.08 66.76,103.21 66.76,104.48 66.82,104.54 67.71,104.54
+1.2VP on IN2 (solid shape): 89.24,107.97 89.24,106.32 89.05,106.13 88.6,106.13 88.35,106.38 88.35,108.1 88.41,108.16 89.05,108.16
+1.8V_PRIM on TOP (solid shape): 47.45,12.98 47.45,12.09 47.07,11.71 40.15,11.71 39.9,11.96 39.9,13.23 40.09,13.42 47.01,13.42
+1.8V_PRIM on TOP (solid shape): outline of 378 points within 108.95,26.83 113.73,37.23
+1.8V_PRIM on BOTTOM (solid shape): 116.64,91.29 116.67,91.17 116.75,91.07 117.43,90.39 117.43,89.5 117.3,89.37 115.74,89.37 115.59,89.52 115.59,90.15 115.89,90.45 115.89,91.28 115.94,91.34 116.63,91.34
+1.8V_PRIM on BOTTOM (solid shape): 162.32,26.61 162.83,26.61 162.83,27.15 163.12,27.15 163.12,26.61 163.63,26.61 163.63,27.15 164.6,27.15 165.28,27.15 165.57,26.86 165.57,26.11 165.57,26.1 165.57,26.05 165.59,26.05 165.59,25.84 165.37,25.62 164.6,25.62 164.42,25.8 162.4,25.8 162.29,25.92 162.28,25.92 161.81,26.39 161.81,27.08 161.89,27.15 162.32,27.15
+1.8V_PRIM on IN1 (solid shape): 114.6,29.51 114.6,28.63 114.54,28.57 113.55,28.57 113.43,28.45 113.43,27.39 113.02,27.16 112.37,27.82 112.37,29.06 112.92,29.62 114.49,29.62
+1.8V_PRIM on IN1 (solid shape): 164.8,26.88 164.86,26.88 165.69,26.05 165.69,25.67 165.44,25.42 163.15,25.42 163.02,25.55 163.02,26.56 163.15,26.69 164.35,26.69 164.55,26.88 164.8,26.88
+1.8V_PRIM on IN2 (solid shape): 47.55,13.23 47.55,12.66 47.17,12.28 46.98,12.28 45.45,13.8 45.45,13.93 45.96,14.44 46.34,14.44
+1.8V_PRIM on IN2 (solid shape): 117.43,90.51 117.43,89.62 117.38,89.57 115.2,89.57 115.14,89.62 115.14,90.57 115.21,90.64 117.3,90.64
+1.8V_PRIM on IN3 (solid shape): 48.34,12.15 48.34,11.96 47.77,11.39 47.57,11.39 46.18,12.78 46.18,13.1 46.63,13.55 46.95,13.55
+1.8V_PRIM on IN3 (solid shape): 113.41,28.24 113.41,24.58 112.75,23.92 112.75,23.44 112.75,23.41 112.76,23.35 112.77,23.29 112.8,23.23 112.83,23.18 112.87,23.13 112.91,23.09 112.95,23.06 112.97,23.04 112.98,23.01 112.98,22.98 112.98,22.95 112.96,22.93 112.95,22.92 112.6,22.57 111.91,22.57 111.69,22.78 111.69,24.61 111.92,24.61 111.92,24.55 111.92,24.5 111.94,24.45 111.96,24.4 111.99,24.36 112.03,24.32 112.07,24.29 112.12,24.26 112.17,24.24 112.22,24.23 112.27,24.23 112.33,24.23 112.38,24.24 112.43,24.26 112.47,24.29 112.51,24.32 112.55,24.36 112.58,24.4 112.6,24.45 112.62,24.5 112.63,24.55 112.63,24.61 112.62,24.66 112.6,24.71 112.58,24.76 112.55,24.8 112.51,24.84 112.47,24.88 112.43,24.9 112.38,24.92 112.33,24.93 112.27,24.94 112.22,24.93 112.17,24.92 112.12,24.9 112.07,24.88 112.03,24.84 111.99,24.8 111.96,24.76 111.94,24.71 111.92,24.66 111.92,24.61 111.69,24.61 111.69,25.97 112.39,26.67 112.39,27.88 112.79,28.28 113.37,28.28
+1.8VALWP on TOP (solid shape): 166.49,28.86 166.49,27.59 166.34,27.44 165.36,27.44 165.04,27.75 165.04,28.67 165.42,29.05 166.3,29.05
+1.8VALWP on BOTTOM (solid shape): 166.58,31.54 166.58,26.27 166.44,26.13 165.73,26.13 165.7,26.16 165.7,26.95 165.37,27.27 164.97,27.27 164.97,27.27 161.97,27.27 161.87,27.38 161.87,30.01 162.4,30.55 162.4,31.2 162.98,31.77 166.35,31.77
+1.8VGS on TOP (solid shape): outline of 426 points within 95.46,96.04 115.27,124.17
+1.8VGS on BOTTOM (solid shape): 103.53,99.82 103.53,98.05 103.15,97.67 102.51,97.67 102.37,97.81 102.37,99.73 102.56,99.92 103.42,99.92
+1.8VGS on BOTTOM (solid shape): 109.66,90.58 109.66,90.12 110.19,90.12 110.19,89.89 109.66,89.89 109.66,89.49 109.59,89.42 108.12,89.42 107.93,89.62 107.93,90.47 108.11,90.66 109.57,90.66
+1.8VGS_OUT on BOTTOM (solid shape): 114.59,91.25 114.59,90.31 114.56,90.28 114.56,90.16 112.87,88.47 112.16,88.47 112.14,88.47 111.83,88.16 110.13,88.16 109.78,88.5 109.78,89.3 109.78,89.76 110.31,89.76 110.31,89.79 110.32,89.79 110.32,90.22 110.31,90.22 110.31,90.25 109.78,90.25 109.78,90.67 110.03,90.91 112.23,90.91 112.38,91.06 113.47,91.06 113.75,91.34 114.5,91.34
+1.35V_MEM_GFX on TOP (solid shape): 147.9,109.83 147.94,109.76 148.03,109.61 148.19,109.53 148.25,109.5 148.27,109.43 148.37,109.19 148.61,109.07 148.63,109.07 148.74,108.96 148.74,108.95 148.82,108.81 148.96,108.74 149.03,108.67 149.01,108.57 148.96,108.52 148.95,108.52 148.8,108.43 148.73,108.27 148.7,108.21 148.63,108.18 148.63,108.18 148.56,108.21 148.52,108.27 148.44,108.44 148.27,108.52 148.21,108.56 148.19,108.63 148.08,108.88 147.83,108.98 147.76,109.01 147.72,109.07 147.65,109.23 147.51,109.32 147.5,109.32 147.39,109.43 147.38,109.47 147.39,109.51 147.43,109.53 147.63,109.61 147.74,109.83 147.78,109.84 147.82,109.84
+1.35V_MEM_GFX on TOP (solid shape): outline of 141 points within 116.4,116.54 119.53,121.03
+1.35V_MEM_GFX on TOP (solid shape): 138.23,102.67 138.3,102.65 138.33,102.58 138.42,102.42 138.58,102.33 138.65,102.3 138.67,102.23 138.77,101.98 139.01,101.87 139.02,101.87 139.14,101.76 139.14,101.75 139.23,101.6 139.39,101.53 139.45,101.5 139.47,101.43 139.47,101.42 139.45,101.36 139.39,101.32 139.22,101.24 139.13,101.07 139.1,101.01 139.03,100.98 139.03,100.98 138.96,101.01 138.92,101.07 138.63,101.33 138.33,101.07 138.3,101.01 138.23,100.98 138.23,100.98 138.16,101.01 138.12,101.07 138.05,101.23 137.9,101.32 137.82,101.39 137.85,101.49 137.9,101.54 137.91,101.54 138.12,101.89 137.78,102.12 137.72,102.12 137.72,102.22 137.74,102.27 137.8,102.33 137.82,102.33 138.02,102.4 138.16,102.65 138.23,102.67
+1.35V_MEM_GFX on TOP (solid shape): 141.17,103.49 141.17,103.37 141.59,102.95 141.62,102.89 141.6,102.82 141.55,102.75 141.53,102.67 141.5,102.61 141.43,102.58 141.43,102.58 141.36,102.61 141.32,102.67 141.24,102.84 141.07,102.92 141.01,102.96 140.98,103.02 140.89,103.27 140.65,103.38 140.63,103.38 140.52,103.5 140.52,103.51 140.02,103.64 140.15,103.14 140.16,103.14 140.27,103.02 140.27,103.01 140.33,102.84 140.46,102.72 140.51,102.63 140.46,102.54 140.28,102.14 140.63,101.87 140.7,101.85 140.73,101.78 140.8,101.63 140.95,101.54 140.96,101.54 141.07,101.42 141.07,101.38 141.06,101.34 141.02,101.33 140.83,101.25 140.7,101.01 140.63,100.98 140.63,100.98 140.56,101.01 140.52,101.07 140.44,101.24 140.27,101.32 140.21,101.36 140.18,101.42 140.08,101.68 139.83,101.78 139.76,101.81 139.72,101.87 139.65,102.02 139.51,102.12 139.5,102.12 139.39,102.23 139.5,102.34 139.51,102.34 139.73,102.65 139.47,102.92 139.41,102.96 139.38,103.02 139.29,103.27 139.05,103.38 139.03,103.38 138.92,103.5 138.92,103.51 138.81,103.67 138.63,103.73 138.6,103.74 138.58,103.77 138.58,103.79 138.6,103.87 138.68,103.9 140.76,103.9
+1.35V_MEM_GFX on TOP (solid shape): outline of 713 points within 121.5,124.67 145.04,131.78
+1.35V_MEM_GFX on TOP (solid shape): outline of 4144 points within 136.8,94.38 154.71,130.45
+1.35V_MEM_GFX on BOTTOM (solid shape): 145.75,96.67 145.75,94.26 145.5,94 144.42,94 144.42,94.52 143.71,94.52 143.71,94 143.22,94 143.22,94.52 142.51,94.52 142.51,94 141.62,94 141.31,94.32 141.31,95.72 141.56,95.97 144.16,95.97 144.29,96.1 144.29,96.92 144.35,96.99 145.43,96.99
+1.35V_MEM_GFX on IN1 (solid shape): outline of 1302 points within 116.61,107.71 120.86,120.86
+1.35V_MEM_GFX on IN3 (solid shape): outline of 1853 points within 115.22,107.65 121.86,120.94
+1.35V_MEM_GFX on VCC: 115.78,94.83 115.78,102.76 115.78,102.76 115.78,104.86 115.78,106.15 117.37,107.74 117.37,110.17 116.6,110.94 116.6,112.31 116.84,112.55 117.09,112.55 117.56,113.01 117.56,115.64 115.78,117.41 115.78,127.05 118.87,130.14 152.06,130.14 153.94,128.25 153.94,96.78 152,94.83
+1.35VGPUP on BOTTOM (solid shape): 143.09,93.88 143.1,93.87 143.84,93.88 143.84,94.39 144.29,94.39 144.29,93.88 144.3,93.87 144.93,93.87 145.94,92.86 148.23,92.86 148.86,92.23 148.86,88.1 148.16,87.4 142.58,87.4 142.39,87.6 142.39,92.23 141.75,92.86 141.75,93.73 141.89,93.87 142.63,93.87 142.64,93.88 142.64,94.39 143.09,94.39
+1VALWP on BOTTOM (solid shape): 141.12,45.43 142.64,45.43 143.08,44.98 143.08,40.53 142.83,40.28 141.05,40.28 140.93,40.15 140.93,39.42 140.89,39.38 140.8,39.4 140.71,39.38 140.26,39.38 140.16,39.4 140.07,39.38 139.62,39.38 139.53,39.4 139.44,39.38 138.99,39.38 138.89,39.4 138.8,39.38 138.71,39.38 138.52,39.57 138.52,41.97 138.51,41.97 138.51,42 138,42 138,42.45 138.51,42.45 138.51,42.47 138.52,42.47 138.52,43.17 138.51,43.17 138.51,43.2 138,43.2 138,43.65 138.51,43.65 138.51,43.67 138.52,43.67 138.52,44.65 138.08,45.09 138.08,46.2 138.13,46.25 140.29,46.25
+2.5V_MEM on TOP (solid shape): 72.92,20.87 72.92,19.14 72.6,18.82 68.34,18.82 68.09,19.07 68.09,20.7 68.38,20.99 72.8,20.99
+2.5V_MEM on TOP (solid shape): 56.41,20.09 56.41,19.37 56.17,19.14 52.41,19.14 52.28,19.26 52.28,20.79 52.34,20.85 53.74,20.85 53.86,20.97 55.52,20.97
+2.5V_MEM on BOTTOM (solid shape): 69.02,20.65 69.02,18.67 67.71,17.36 66.82,17.36 66.34,17.84 66.34,18.88 66.35,18.95 66.34,19.02 66.34,21.2 66.44,21.3 68.37,21.3
+2.5V_MEM on BOTTOM (solid shape): 43.17,9.01 43.17,7.36 42.92,7.1 42.47,7.1 42.47,7.65 41.96,7.65 41.96,7.1 41.67,7.1 41.67,7.65 41.16,7.65 41.16,7.1 40.76,7.1 40.6,7.27 40.6,8.86 41.27,9.53 42.66,9.53
+2.5V_MEM on BOTTOM (solid shape): 57.48,19.59 57.48,19.59 57.95,19.11 57.95,18.77 57.32,18.14 55.26,18.14 54.35,19.04 52.67,19.04 52.15,19.56 52.15,21.36 54.27,21.36 54.28,21.31 54.29,21.25 54.31,21.21 54.33,21.16 54.37,21.12 54.41,21.08 54.45,21.05 54.5,21.03 54.55,21.01 54.6,21 54.66,21 54.71,21.01 54.76,21.03 54.81,21.05 54.85,21.08 54.89,21.12 54.92,21.16 54.95,21.21 54.97,21.25 54.98,21.31 54.99,21.36 54.98,21.41 54.97,21.47 54.95,21.51 54.92,21.56 54.89,21.6 54.85,21.64 54.81,21.67 54.76,21.69 54.71,21.71 54.66,21.72 54.6,21.72 54.55,21.71 54.5,21.69 54.45,21.67 54.41,21.64 54.37,21.6 54.33,21.56 54.31,21.51 54.29,21.47 54.28,21.41 54.27,21.36 52.15,21.36 52.15,21.61 52.34,21.8 53.91,21.8 54.2,22.09 54.98,22.09
+2.5VP on BOTTOM (solid shape): 46.22,6.36 47.88,6.36 48.08,6.16 48.08,5.7 47.95,5.57 46.22,5.57 45.68,5.03 41.77,5.03 40.72,6.08 40.72,6.9 40.8,6.98 42.97,6.98 43,7 45.58,7
+3.3V_ALW_DSW on IN1 (solid shape): outline of 345 points within 102.64,36.34 108.67,37.74
+3.3V_OUT on TOP (solid shape): 166.34,22.45 166.34,21.86 164.99,20.51 164.99,19.35 164.98,19.34 164.98,19.05 164.46,18.53 164.46,18.22 164.68,17.99 164.68,17.99 164.92,17.76 164.92,16.92 164.57,16.57 162.59,16.57 162.59,17.27 162.05,17.27 162.05,17.72 162.59,17.72 162.59,18.32 162.58,18.32 162.58,18.47 162.05,18.47 162.05,18.92 162.58,18.92 162.58,21.45 163.66,22.52 166.26,22.52
+3.3V_SPI on IN3 (solid shape): outline of 741 points within 95.32,20.6 110.38,36.47
+3.3V_WLAN on TOP (solid shape): 43.67,110.6 44.57,110.6 44.72,110.44 44.72,108.08 44.5,107.85 42.77,107.85 42.38,108.25 42.38,110.4 42.58,110.61 43.67,110.61
+3.3V_WLAN on TOP (solid shape): 61.37,110.29 62.13,110.29 62.47,109.95 62.47,107.5 60.67,105.71 59.58,105.71 59.2,105.33 59.2,105.3 59.09,105.19 58.31,105.19 58.22,105.28 58.22,107.9 58.53,108.2 59.73,108.2 60.43,108.9 60.43,110.1 60.62,110.29 61.37,110.29
+3.3V_WLAN on BOTTOM (solid shape): 62.12,108.56 62.12,106.96 61.96,106.8 60.81,106.8 60.65,106.96 60.65,108.6 60.87,108.82 61.87,108.82
+3.3V_WLAN on BOTTOM (solid shape): 43.98,110.46 43.98,107.08 43.82,106.91 42.59,106.91 42.26,107.24 42.26,110.52 42.39,110.65 43.8,110.65
+3.3V_WLAN on IN1 (solid shape): 44.14,110.38 44.14,109.41 44.06,109.33 42.64,109.33 42.51,109.47 42.51,110.38 42.6,110.48 44.04,110.48
+3.3V_WLAN on IN1 (solid shape): 62.11,108.37 62.11,107.5 61.97,107.36 60.31,107.36 60.07,107.6 60.07,108.41 60.18,108.53 61.96,108.53
+3VALW on TOP (solid shape): 57.44,106.58 57.44,104.05 57.15,103.77 56.43,103.77 56.09,104.11 56.09,106.35 56.37,106.63 57.38,106.63
+3VALW on TOP (solid shape): 154.83,14.31 154.83,12.28 154.22,11.66 150.68,11.66 150.39,11.96 150.39,13.17 150.58,13.37 152.77,13.37 153.84,14.44 154.7,14.44
+3VALW on TOP (solid shape): 83.97,18.44 83.97,17.36 83.71,17.11 83.39,17.11 83.14,16.85 83.14,15.96 82.89,15.71 82.19,15.71 82.19,17.93 82.95,17.93 83.08,18.06 83.08,18.44 83.2,18.57 83.84,18.57
+3VALW on TOP (solid shape): 160.42,42.82 160.42,42.19 160.36,42.12 159.91,42.12 159.85,42.06 159.85,40.09 159.91,40.03 160.36,40.03 160.42,39.97 160.42,39.2 160.17,38.95 157.05,38.95 156.8,39.2 156.8,40.03 158.32,41.55 158.32,42.76 158.51,42.95 160.29,42.95
+3VALW on TOP (solid shape): 91.78,15.9 91.78,15.7 91.72,15.7 91.72,14.92 91.65,14.65 91.78,14.41 91.78,13.99 91.59,13.8 89.49,13.8 89.24,14.06 89.24,14.76 89.36,14.88 89.81,14.88 89.93,15.01 89.93,15.64 90.25,15.96 91.71,15.96
+3VALW on TOP (solid shape): 146.03,27.8 146.03,24.25 144.41,22.64 144.41,21.73 144.38,21.69 144.38,20.06 144.32,19.99 144.3,19.99 144.1,19.89 144,19.7 144,19.68 143.97,19.65 143.97,19.13 143.91,19.07 143.53,19.07 143.4,19.2 143.4,20.02 143.59,20.21 143.59,24.92 144.07,25.4 144.3,25.4 144.3,26.21 144.3,26.21 143.78,26.73 143.78,27.14 143.57,27.35 143.56,27.37 143.46,27.58 143.25,27.68 143.24,27.68 142.83,28.09 142.83,28.82 143.2,29.19 144.65,29.19
+3VALW on TOP (solid shape): outline of 127 points within 161.77,23.27 166.39,28.66
+3VALW on BOTTOM (solid shape): 160.61,20.85 160.61,18.62 160.48,18.5 159.98,18.5 159.53,18.94 159.53,20.85 159.72,21.04 160.42,21.04
+3VALW on BOTTOM (solid shape): 144.99,36.98 144.99,35.9 144.93,35.83 143.28,35.83 143.21,35.9 143.21,36.4 143.28,36.47 143.47,36.47 143.53,36.4 144.23,36.4 144.36,36.53 144.36,36.98 144.48,37.1 144.86,37.1
+3VALW on BOTTOM (solid shape): 159.47,42 159.47,41.11 159.28,40.92 159.02,40.92 158.83,40.73 158.83,38.95 158.58,38.7 155.78,38.7 155.66,38.82 155.66,39.84 155.72,39.9 156.74,39.9 158.26,41.43 158.26,42 158.45,42.19 159.28,42.19
+3VALW on BOTTOM (solid shape): 30.19,123.86 30.19,123.27 30.45,123.01 31.01,123.01 31.22,122.8 31.22,122.27 31.17,122.22 28.34,122.22 27.7,121.58 26.73,121.58 26.72,121.58 26.31,121.58 26.15,121.42 25.19,121.42 25.14,121.47 25.14,121.91 25.22,121.99 25.99,121.99 26.19,122.18 26.19,122.58 26.45,122.85 26.99,122.85 28.08,123.93 30.12,123.93
+3VALW on BOTTOM (solid shape): outline of 186 points within 57.06,4.02 83.52,17.8
+3VALW on BOTTOM (solid shape): outline of 333 points within 156.91,11.77 165.83,29.34
+3VALW on IN1 (solid shape): outline of 345 points within 81.68,13.71 93.94,17.3
+3VALW on IN2 (solid shape): 31.23,123.2 31.23,122.29 31.17,122.22 29.09,122.22 28.95,122.36 28.95,123.23 29.02,123.3 31.13,123.3
+3VALW on IN2 (solid shape): 78.13,95.46 78.13,94 77.93,93.81 75.08,93.81 74.63,94.25 74.63,95.01 75.2,95.59 78,95.59
+3VALW on IN2 (solid shape): 165.75,25.04 165.75,23.7 164.99,22.94 164.29,22.94 164.01,23.23 164.01,25.13 164.17,25.29 165.5,25.29
+3VALW on IN2 (solid shape): 57.38,105.39 57.38,103.98 57.16,103.76 55.68,103.76 55.54,103.89 55.54,105.31 55.93,105.69 57.08,105.69
+3VALW on IN2 (solid shape): 161.86,90.16 161.86,88.47 161.75,88.36 159.95,88.36 159.49,88.82 159.49,89.9 159.62,90.04 160.27,90.04 160.55,90.32 161.7,90.32
+3VALW on IN2 (solid shape): 159.44,42.8 159.44,40.57 158.64,39.77 157.88,39.77 157.63,40.02 157.63,40.53 157.94,40.85 157.94,42.91 158.14,43.11 159.14,43.11
+3VALW on VCC: 164.12,23.32 163.34,23.86 163.34,26.35 161.92,27.77 138.89,27.77 138.89,42.06 164.63,42.06 170.64,36.05 170.64,31.49 167.84,28.69 167.84,26.35 167.84,26.34 167.84,25.64 165.52,23.32
+3VALW_PCH on TOP (solid shape): 162.15,28.4 162.15,28.08 162.13,28.06 161.64,28.06 161.64,27.55 162.15,27.55 162.15,27.26 161.64,27.26 161.64,26.75 162.15,26.75 162.15,25.52 162.69,24.97 162.69,24.16 162.11,23.58 160.4,23.58 160.29,23.68 160.29,24.83 159.42,25.71 159.42,28.08 159.8,28.46 162.08,28.46
+3VALW_PCH on TOP (solid shape): outline of 494 points within 111.4,21.9 120.72,38.58
+3VALW_PCH on BOTTOM (solid shape): 130.89,34.41 130.98,34.35 130.96,34.24 131.21,33.69 131.46,34.24 131.44,34.35 131.53,34.41 131.79,34.41 133.43,32.76 133.44,32.76 133.55,32.66 133.55,31.04 133.38,30.87 132.39,30.87 132.3,30.78 131.58,30.78 131.51,30.85 131.51,32.55 131.34,32.73 131.02,32.73 131.02,32.73 130.32,32.73 130.23,32.82 130.23,33.6 130.25,33.61 130.25,34.17 130.49,34.41
+3VALW_PCH on IN1 (solid shape): outline of 2651 points within 107.47,30.27 131.97,41.49
+3VALW_PCH on IN2 (solid shape): outline of 372 points within 109.43,19.03 119.24,23.71
+3VALW_PCH on VCC: 112.84,21.99 110.7,24.13 110.7,26.64 111.31,27.26 130.47,27.26 132.57,25.16 134.49,25.16 136.59,27.27 161.71,27.27 162.83,26.14 162.83,23.96 138.34,23.96 137.01,22.62 126.62,22.62 124.96,24.28 121.27,24.28 120.61,23.62 120.61,23.17 119.42,21.99
+3VALWP on TOP (solid shape): 162.71,42.76 163.59,42.76 163.79,42.56 163.79,39.96 163.56,39.73 161.02,39.73 160.87,39.58 160.61,39.58 160.61,42.57 160.8,42.76 162.71,42.76
+3VALWP on BOTTOM (solid shape): 166.52,44.28 166.52,39.77 165.75,39.01 162.64,39.01 162.45,39.2 162.45,39.58 162.26,39.77 159.09,39.77 159.02,39.84 159.02,40.6 159.15,40.73 159.53,40.73 159.66,40.85 159.66,43.14 159.75,43.24 162.99,43.24 163.21,43.46 163.21,43.84 163.91,44.54 166.26,44.54
+3VGS on BOTTOM (solid shape): 121.55,95.02 122.23,95.02 122.29,94.96 122.29,94.41 121.75,94.41 121.75,93.71 122.29,93.71 122.29,93.21 121.75,93.21 121.75,92.51 122.29,92.51 122.29,91.95 122.19,91.85 119.96,91.85 119.39,92.42 119.39,93.98 119.22,94.14 119.22,94.16 119,94.39 118.98,94.39 118.81,94.55 118.81,94.56 118.15,94.56 117.74,94.97 115.78,94.97 115.69,95.05 115.69,96.22 115.91,96.44 120.14,96.44
+3VGS_OUT on BOTTOM (solid shape): 125.27,95.09 125.27,93.34 125.19,93.26 124.61,93.26 124.6,93.27 123.94,93.27 123.5,92.83 123.5,91.93 123.42,91.85 122.52,91.85 122.41,91.95 122.41,92.63 121.88,92.63 121.88,93.08 122.41,93.08 122.41,93.83 121.88,93.83 121.88,94.28 122.41,94.28 122.41,95.01 122.75,95.34 125.01,95.34
+3VLP on BOTTOM (solid shape): 174.47,42.16 174.47,41.7 174.26,41.5 173.12,41.5 172.97,41.65 172.97,41.95 173.3,42.28 174.34,42.28
+3VS on TOP (solid shape): 61.08,105.44 61.08,103.8 61.01,103.73 57.75,103.73 57.59,103.88 57.59,104.85 57.77,105.03 59.14,105.03 59.61,105.5 61.02,105.5
+3VS on TOP (solid shape): 48.71,17.38 49.89,17.38 50.13,17.14 50.13,16.04 49.94,15.85 48.72,15.85 47.57,17 47.57,17.38 48.11,17.93 48.17,17.93
+3VS on TOP (solid shape): 45.98,21.94 45.98,19.86 45.71,19.58 44.28,19.58 43.96,19.9 42.63,19.9 42.56,19.96 42.56,20.85 42.63,20.92 43.96,20.92 44.66,21.61 44.66,22.06 44.85,22.25 45.68,22.25
+3VS on TOP (solid shape): 67.9,21.04 67.9,18.5 67.68,18.28 66.86,18.28 66.45,18.69 66.45,19.13 66.06,19.52 66.06,20.09 65.93,20.22 64.6,20.22 64.34,20.47 64.34,20.71 64.35,20.72 64.38,20.88 64.34,21.03 64.34,21.04 64.53,21.23 67.71,21.23
+3VS on TOP (solid shape): 81.55,8.15 81.62,8.13 81.66,8.06 81.74,7.89 81.91,7.8 81.97,7.77 82,7.7 82,4.91 81.36,4.28 80.66,4.28 80.35,4.6 80.35,7.21 80.25,7.3 79.94,7.3 79.85,7.39 79.85,8.05 79.95,8.15
+3VS on TOP (solid shape): 129.62,28.19 129.62,27.34 129.23,26.95 127.41,26.95 127.27,26.82 127.27,25.1 128.67,23.7 128.67,22.94 130.89,20.72 130.89,20.55 130.64,20.29 129.6,20.29 127.34,22.56 127.34,23.26 127.14,23.45 127.14,23.47 127.04,23.68 126.83,23.78 126.82,23.78 126.39,24.21 126.08,24.21 125.49,24.8 125.49,27.07 126.89,28.47 129.34,28.47
+3VS on TOP (solid shape): 162.46,23.09 162.46,19.05 161.92,19.05 161.92,18.34 162.46,18.34 162.46,18.27 162.46,18.26 162.46,17.85 161.92,17.85 161.92,17.14 162.46,17.14 162.46,16.07 162.27,15.88 162.27,14.68 162.08,14.49 160.72,14.49 160.39,14.83 160.39,18.41 160.65,18.75 160.39,19.09 160.39,21.11 160.4,21.12 160.4,23.15 160.64,23.39 162.15,23.39
+3VS on TOP (solid shape): 186.31,15.84 186.34,15.77 186.31,15.69 186.29,15.17 186.81,15.19 186.88,15.23 186.96,15.2 187.48,14.68 187.48,13.48 187.32,13.32 184.1,13.32 184.1,14.75 182.97,14.75 182.97,15.9 183.09,16.02 186.14,16.02
+3VS on BOTTOM (solid shape): 126.23,24.45 126.23,24.1 126.13,24 125.67,24 124.77,23.1 122.23,23.1 122,23.33 121.58,23.75 121.58,24.5 121.71,24.63 126.05,24.63
+3VS on BOTTOM (solid shape): 110,17.11 110,16.91 109.81,16.72 109.62,16.72 108.41,15.52 108.16,15.52 108.03,15.64 108.03,16.79 108.41,17.17 108.98,17.17 109.18,17.36 109.75,17.36
+3VS on BOTTOM (solid shape): 209.74,37.72 209.74,37.21 209.86,37.1 213.94,37.1 214.13,36.91 214.13,36.42 214.06,36.36 209.15,36.36 208.99,36.52 208.99,37.71 209.08,37.79 209.68,37.79
+3VS on BOTTOM (solid shape): 228.69,27.29 228.69,26.33 228.7,26.32 228.7,24.38 228.31,24 226.59,24 226.59,24.78 227.78,25.96 227.78,26.36 227.48,26.66 226.4,26.66 226.11,26.95 226.11,27.64 226.18,27.72 228.26,27.72
+3VS on BOTTOM (solid shape): 129.81,30 129.81,29.36 129.94,29.23 130.45,29.23 130.57,29.11 130.57,28.47 130.26,28.15 130.26,27.58 130.1,27.42 128.87,27.42 128.6,27.69 128.6,28.28 128.99,28.66 128.99,30.12 129.05,30.19 129.62,30.19
+3VS on BOTTOM (solid shape): 131.05,95.65 131.05,94.34 129.96,93.25 128.87,93.25 128.87,93.24 126.81,93.24 126.64,93.41 126.64,94.55 126.94,94.85 129.56,94.85 130.55,95.84 130.86,95.84
+3VS on BOTTOM (solid shape): 68.15,21.74 68.15,21.55 68.03,21.42 66.39,21.42 66.25,21.42 65.42,20.6 64.53,20.6 64.47,20.66 64.47,21.11 64.63,21.27 65.01,21.27 65.43,21.69 67.25,21.69 67.41,21.72 67.54,21.8 68.09,21.8
+3VS on BOTTOM (solid shape): 134.5,16.53 134.5,14.42 134.1,14.03 133.15,14.03 132.73,13.61 132.73,13.04 132.35,12.65 131.65,12.65 131.53,12.78 131.53,13.04 131.43,13.14 131.43,13.16 131.41,13.16 131.27,13.3 130.76,13.3 130.64,13.42 130.64,14.06 130.77,14.18 131.21,14.18 132.04,15.01 133.24,15.01 133.33,15.1 133.34,15.1 133.41,15.16 133.47,15.23 133.47,15.24 133.56,15.33 133.56,16.47 133.77,16.68 134.35,16.68
+3VS on BOTTOM (solid shape): 53.93,22.25 53.93,22.06 53.8,21.93 52.29,21.93 52.25,21.9 52.24,21.89 52.13,21.82 52.06,21.71 52.06,21.7 52.02,21.67 52.02,21.61 51.83,21.42 51.83,18.98 51.83,18.97 51.8,18.82 51.83,18.67 51.84,18.64 50.63,17.42 45.61,17.42 43.36,19.68 43.36,19.93 44.02,20.6 44.28,20.6 46.31,18.57 50.06,18.57 50.22,18.73 50.25,18.72 50.59,18.86 50.63,19.23 50.63,19.24 50.63,21.07 50.74,21.3 50.69,21.56 50.67,21.6 51.27,22.19 53.05,22.19 53.21,22.22 53.35,22.31 53.87,22.31
+3VS on BOTTOM (solid shape): outline of 128 points within 212.3,45.47 215.63,47.77
+3VS on IN1 (solid shape): 182.05,52.89 182.05,51.5 181.83,51.28 180.98,51.28 180.24,52.01 180.24,52.85 180.51,53.12 181.82,53.12
+3VS on IN1 (solid shape): 185.6,16.57 185.6,15.38 185.38,15.15 183.17,15.15 183.03,15.3 183.03,16.35 183.03,16.36 183.03,16.6 183.23,16.79 185.38,16.79
+3VS on IN1 (solid shape): outline of 336 points within 221.76,24.2 229.22,54.1
+3VS on IN1 (solid shape): outline of 438 points within 188.27,31.33 191.55,45.85
+3VS on IN1 (solid shape): outline of 911 points within 208.71,36.33 215.52,47.66
+3VS on IN2 (solid shape): 181.91,53.07 181.91,52.55 181.6,52.25 179.1,52.25 179.1,53.21 179.17,53.28 181.7,53.28
+3VS on IN2 (solid shape): 162.33,22.88 162.33,21.93 162.07,21.67 159.91,21.67 159.6,21.99 159.6,23.07 159.91,23.39 161.82,23.39
+3VS on IN2 (solid shape): 163.06,16.46 163.06,15.44 162.87,15.24 161.32,15.24 160.98,15.58 160.98,16.24 161.3,16.56 162.95,16.56
+3VS on IN2 (solid shape): 59.28,105.36 59.28,104.24 59.17,104.13 58.76,103.72 57.74,103.72 57.54,103.92 57.54,105.62 57.77,105.85 58.79,105.85
+3VS on IN2 (solid shape): 185.47,15.56 185.47,15.09 184.93,14.56 181.82,14.56 181.69,14.69 181.69,15.39 181.88,15.58 182.71,15.58 183,15.87 185.16,15.87
+3VS on IN2 (solid shape): 130.89,96.02 131.02,95.99 131.15,96.02 131.16,96.02 131.66,96.02 131.77,95.91 131.77,94.89 131.66,94.78 129.27,94.78 129.13,94.92 129.13,95.88 129.27,96.02 130.88,96.02
+3VS on IN2 (solid shape): outline of 209 points within 69.57,7.04 82.25,17.6
+3VS on IN2 (solid shape): outline of 642 points within 211.13,45.55 224.18,53.88
+3VS on IN3 (solid shape): 46.22,126.84 46.22,123.27 45.95,123.01 41.19,123.01 41.19,123.01 37.32,123.01 35.21,120.9 34.28,120.9 32.57,119.19 32.16,119.19 32.11,119.2 32.05,119.19 31.58,119.19 31.52,119.2 31.35,119.19 31.3,119.14 31.2,119.07 31.13,118.97 31.06,118.9 31.06,104.01 29.06,102 29.06,94.51 27.64,93.1 24.7,93.1 24.39,93.4 24.39,94.17 24.57,94.35 27.22,94.35 27.9,95.03 27.9,102.45 29.93,104.48 29.93,110.07 30.03,110.32 29.93,110.57 29.93,119.32 30.8,120.2 30.82,120.2 30.91,120.19 31,120.21 31.05,120.23 31.1,120.27 32,120.27 33.7,121.96 34.48,121.96 36.59,124.07 40.17,124.07 40.2,124.11 44.11,124.11 44.74,124.74 44.74,126.79 44.95,127 46.07,127
+3VS on VCC: 180.61,9.47 180.61,21.21 178.5,23.33 171.18,23.33 170.39,22.54 170.39,19.81 169.78,19.2 166.73,19.2 165.69,18.16 165.69,16.63 165.21,16.15 138.98,16.15 136.5,13.67 98.55,13.67 96.51,15.71 62.54,15.71 58.95,19.31 58.95,21.8 71.94,21.8 78.61,28.47 90.04,28.47 94.55,32.98 105.05,32.98 105.05,29.07 107.62,26.5 110.19,26.5 110.19,23.92 112.63,21.48 119.63,21.48 121.11,22.96 121.11,23.41 121.48,23.77 124.75,23.77 126.41,22.12 137.22,22.12 138.56,23.45 163.04,23.45 163.88,22.87 163.94,22.81 163.96,22.81 163.98,22.8 164.06,22.81 165.73,22.81 168.36,25.44 168.36,28.49 169.22,29.34 177.6,29.34 184.42,22.52 184.42,18.14 185.72,16.85 220.85,16.85 222.21,18.2 222.21,35.28 224.41,37.48 230.73,37.48 230.73,20.71 229.1,20.71 226.43,18.04 229.1,15.37 230.73,15.37 230.73,9.47
+3VS_CAM on TOP (solid shape): 226.56,35.49 226.56,34.46 226.51,34.41 223.53,34.41 223.41,34.54 223.41,35.53 223.52,35.64 226.4,35.64
+5V_CAM on TOP (solid shape): 217.34,51.14 217.34,50.44 217.48,50.3 219.4,50.3 219.59,50.11 219.59,49.06 219.59,49.06 220.12,49.06 220.12,48.87 219.59,48.87 219.57,48.85 219.57,48.42 219.48,48.33 216.25,48.33 216.18,48.39 216.1,48.43 214.97,49.55 214.97,51.06 215.13,51.22 217.26,51.22
+5V_CAM on BOTTOM (solid shape): 216.74,50.7 216.74,50 216.62,49.87 216.05,49.87 215.92,49.74 215.92,48.66 215.79,48.54 214.97,48.54 214.78,48.73 214.78,50.63 215.09,50.95 216.49,50.95
+5V_HDD on TOP (solid shape): 196.23,20.1 196.23,18.37 195.99,18.18 195.99,17.87 194.63,17.87 194.52,17.99 194.52,20.07 194.7,20.25 196.07,20.25
+5V_HDD on TOP (solid shape): 203.21,19.82 203.21,18.27 203.12,18.18 202.69,18.18 202.69,18.73 202.14,18.73 202.14,18.18 201.89,18.18 201.89,18.73 201.34,18.73 201.34,18.18 200.81,18.18 200.55,18.29 200.29,18.18 200.21,18.18 200.17,18.14 200.17,17.25 200.07,17.15 199.13,17.15 198.98,17.3 198.98,18.25 199.08,18.36 199.08,20 199.22,20.14 202.89,20.14
+5V_HDD on BOTTOM (solid shape): 195.03,18.73 195.03,17.72 194.93,17.64 194.87,17.52 194.81,17.46 194.81,16.61 194.7,16.5 193.48,16.5 193.38,16.6 193.38,18.69 193.58,18.89 194.86,18.89
+5V_HDD on IN1 (solid shape): outline of 85 points within 193.89,17.34 200.17,20.4
+5V_HDMI on TOP (solid shape): 22.74,98.06 22.74,95.23 22.38,94.87 21.34,94.87 21.28,94.94 20.99,95.72 20.51,96.4 20.51,97.96 20.68,98.14 22.66,98.14
+5V_HDMI on IN1 (solid shape): 21.11,98.3 21.11,97.13 20.89,96.91 19.88,96.91 19.75,96.98 19.62,97.05 19.47,97.12 19.31,97.18 19.31,97.96 19.32,97.97 19.32,98.34 19.46,98.48 20.94,98.48
+5V_HDMI on IN1 (solid shape): 13.88,91.45 13.88,91.34 13.04,90.51 12.35,90.51 12.34,90.52 12.13,90.52 12,90.53 11.87,90.52 11.86,90.52 11.58,90.8 11.58,91.17 12.43,92.02 13.3,92.02
+5V_KB_BL on BOTTOM (solid shape): 120.8,9.61 120.8,8.02 121.11,7.71 121.75,7.71 121.88,7.58 121.88,6.56 121.81,6.5 120.22,6.5 120.1,6.63 120.1,7.07 118.83,8.34 116.03,8.34 115.97,8.41 115.97,8.41 115.91,8.48 115.91,9.55 116.03,9.68 120.73,9.68
+5V_OUT on TOP (solid shape): 168.89,21.96 169.6,21.96 171.15,20.42 171.15,17.81 171.06,17.72 170.43,17.72 170.43,18.27 169.67,18.27 169.67,17.72 169.23,17.72 169.23,18.27 168.47,18.27 168.47,17.72 167.94,17.72 167.47,18.19 167.47,20.58 167.62,20.73 167.66,20.76 167.69,20.8 167.76,20.87 167.76,22.13 167.76,22.44 167.76,22.48 167.8,22.52 168.34,22.52
+5V_PVDD on TOP (solid shape): 37.2,24.1 38.71,24.1 38.76,24.05 38.76,19.64 38.06,18.94 35.33,18.94 35.2,18.81 32.09,18.81 31.71,19.2 30.06,19.2 29.99,19.26 29.99,19.39 30.12,19.51 30.88,19.51 31.01,19.39 32.98,19.39 33.17,19.58 33.17,19.89 33.29,20.02 33.87,20.02 34.18,20.34 34.18,21.8 33.68,22.31 31.96,22.31 31.94,22.28 31.91,22.28 31.82,22.19 31.76,22.15 31.72,22.09 30.92,21.29 30.06,21.29 29.99,21.35 29.99,21.48 30.05,21.54 30.09,21.53 30.78,21.53 30.93,21.59 31,21.72 31.01,21.73 31.39,22.12 31.39,22.69 31.83,23.13 33.23,23.13 34.31,24.21 37.09,24.21
+5VALW on TOP (solid shape): 23.65,51.82 23.65,49 23.21,48.56 19.82,48.56 19.57,48.81 19.57,51.82 19.82,52.07 23.4,52.07
+5VALW on TOP (solid shape): 57.74,127.79 57.74,127.21 56.47,125.94 56.03,125.94 55.59,125.51 55.59,125.28 55.52,125.22 55.45,125.22 55.39,125.27 55.39,126.33 55.39,126.33 55.39,126.75 55.52,126.88 55.52,127.79 55.58,127.85 57.68,127.85
+5VALW on TOP (solid shape): 221.24,51.68 221.24,48.67 220.89,48.32 219.73,48.32 219.72,48.33 219.72,48.74 220.25,48.74 220.25,49.18 219.72,49.18 219.72,50.15 219.72,50.16 219.45,50.42 219.45,50.42 219.43,50.44 218.79,50.44 218.71,50.53 218.71,51.18 218.77,51.23 220.06,51.23 220.61,51.78 221.14,51.78
+5VALW on TOP (solid shape): 169.4,25.24 169.5,24.98 169.76,24.88 169.79,24.85 170.08,24.85 171.3,23.64 172.05,23.64 172.05,23.13 172.76,23.13 172.76,23.64 173.25,23.64 173.25,23.13 173.96,23.13 173.96,23.64 175.07,23.64 175.28,23.84 176.23,23.84 176.44,23.64 176.44,22.91 176.31,22.78 175.63,22.78 174.97,22.12 174.97,21.42 174.72,21.17 170.91,21.17 169.89,22.19 169.89,22.9 169.72,23.07 169.34,23.07 168.61,23.81 167.8,23.81 167.75,23.86 167.75,25.63 167.91,25.79 168.84,25.79
+5VALW on BOTTOM (solid shape): 53.17,4.98 53.17,4.41 52.47,3.71 52.47,2.18 52.28,1.99 48.99,1.99 48.86,2.13 48.86,4.6 49.36,5.1 53.04,5.1
+5VALW on BOTTOM (solid shape): 24.07,51.22 24.07,28.51 23.88,28.32 20.7,28.32 20.44,28.58 20.44,47.74 20.59,47.9 20.59,48.37 20.44,48.53 20.44,48.98 20.43,48.99 20.43,51.75 20.56,51.89 23.4,51.89
+5VALW on VCC: 31.71,1.17 31.71,10.44 32.32,10.44 36.91,15.24 36.9,17.06 36.82,17.24 34.74,19.3 34.56,19.38 32.05,19.39 31.92,19.26 29.94,19.26 29.61,18.94 29.61,18.2 29.94,17.87 32.6,17.87 32.85,17.62 32.85,17.35 32.84,14.33 31.83,13.33 29.13,13.32 28.85,13.61 28.86,14.04 28.86,14.04 28.86,14.14 28.86,14.25 28.86,14.25 28.85,15.88 28.72,16 28.72,17.54 28.58,17.68 25.34,17.68 25.16,17.86 25.16,18.32 25.23,18.39 25.23,18.49 25.16,18.55 25.16,22.26 25.48,22.58 25.48,24.59 24.97,25.1 24.97,25.28 24.83,25.42 23.73,25.42 23.54,25.23 21.48,25.23 21.48,30.39 22.61,31.52 28.81,31.52 44.02,16.3 44.02,10.46 47.79,6.69 136.72,6.69 140.46,10.43 168.84,10.43 172.04,13.63 172.04,13.84 172.04,16.8 172.04,17.14 171.89,17.29 170.24,18.94 170.9,19.6 170.9,22.33 171.39,22.82 178.28,22.82 180.1,21 180.1,9.47 178,9.47 176.47,8.83 175.83,7.3 175.83,1.17
+5VALWP on TOP (solid shape): 174.85,26.63 174.85,24.15 174.5,23.81 173.83,23.81 173.83,23.26 173.38,23.26 173.38,23.8 172.63,23.8 172.63,23.26 172.18,23.26 172.18,23.8 171.52,23.8 171.29,24.03 171.29,26.38 171.67,26.76 174.72,26.76
+5VALWP on BOTTOM (solid shape): 175.34,28.79 175.34,22.5 175.28,22.44 174.58,22.44 173.95,23.07 170.14,23.07 170.07,23.14 170.07,23.8 170.08,23.81 170.08,24.75 170.07,24.76 170.07,25.07 170.08,25.08 170.11,25.23 170.08,25.38 170.07,25.39 170.07,25.71 170.08,25.72 170.11,25.87 170.08,26.02 170.07,29.42 170.2,29.55 174.58,29.55
+5VS on TOP (solid shape): 26.18,97.31 26.18,95.15 25.99,94.96 24.28,94.96 24.15,95.08 24.15,97.18 24.47,97.5 25.99,97.5
+5VS on TOP (solid shape): 183.73,51.2 183.73,49.74 183.28,49.29 182.58,49.29 182.33,49.55 182.33,51.71 182.71,52.09 182.84,52.09
+5VS on TOP (solid shape): 38.76,26.56 38.76,25.08 38.65,24.97 37.2,24.97 37.1,25.06 37.1,25.42 36.98,25.55 36.41,25.55 35.71,26.24 35.71,26.56 35.83,26.69 38.63,26.69
+5VS on TOP (solid shape): 187,30.72 187,28.82 186.71,28.53 185.57,28.53 184.61,27.58 183.41,27.58 183.22,27.77 183.22,30.94 183.34,31.07 186.65,31.07
+5VS on TOP (solid shape): 205.25,17.29 205.25,15.83 205.13,15.7 204.3,15.7 203.41,16.59 200.49,16.59 200.3,16.78 200.3,17.15 200.96,17.81 200.96,17.96 201.04,18.04 204.5,18.04
+5VS on TOP (solid shape): 167.74,17.59 168.6,17.59 168.6,18.14 169.1,18.14 169.1,17.59 169.8,17.59 169.8,18.14 170.3,18.14 170.3,17.59 170.31,17.58 170.95,17.58 171,17.53 171,15.85 170.28,15.12 166.59,15.12 166.14,15.57 166.14,18.65 166.15,18.66 166.67,18.66
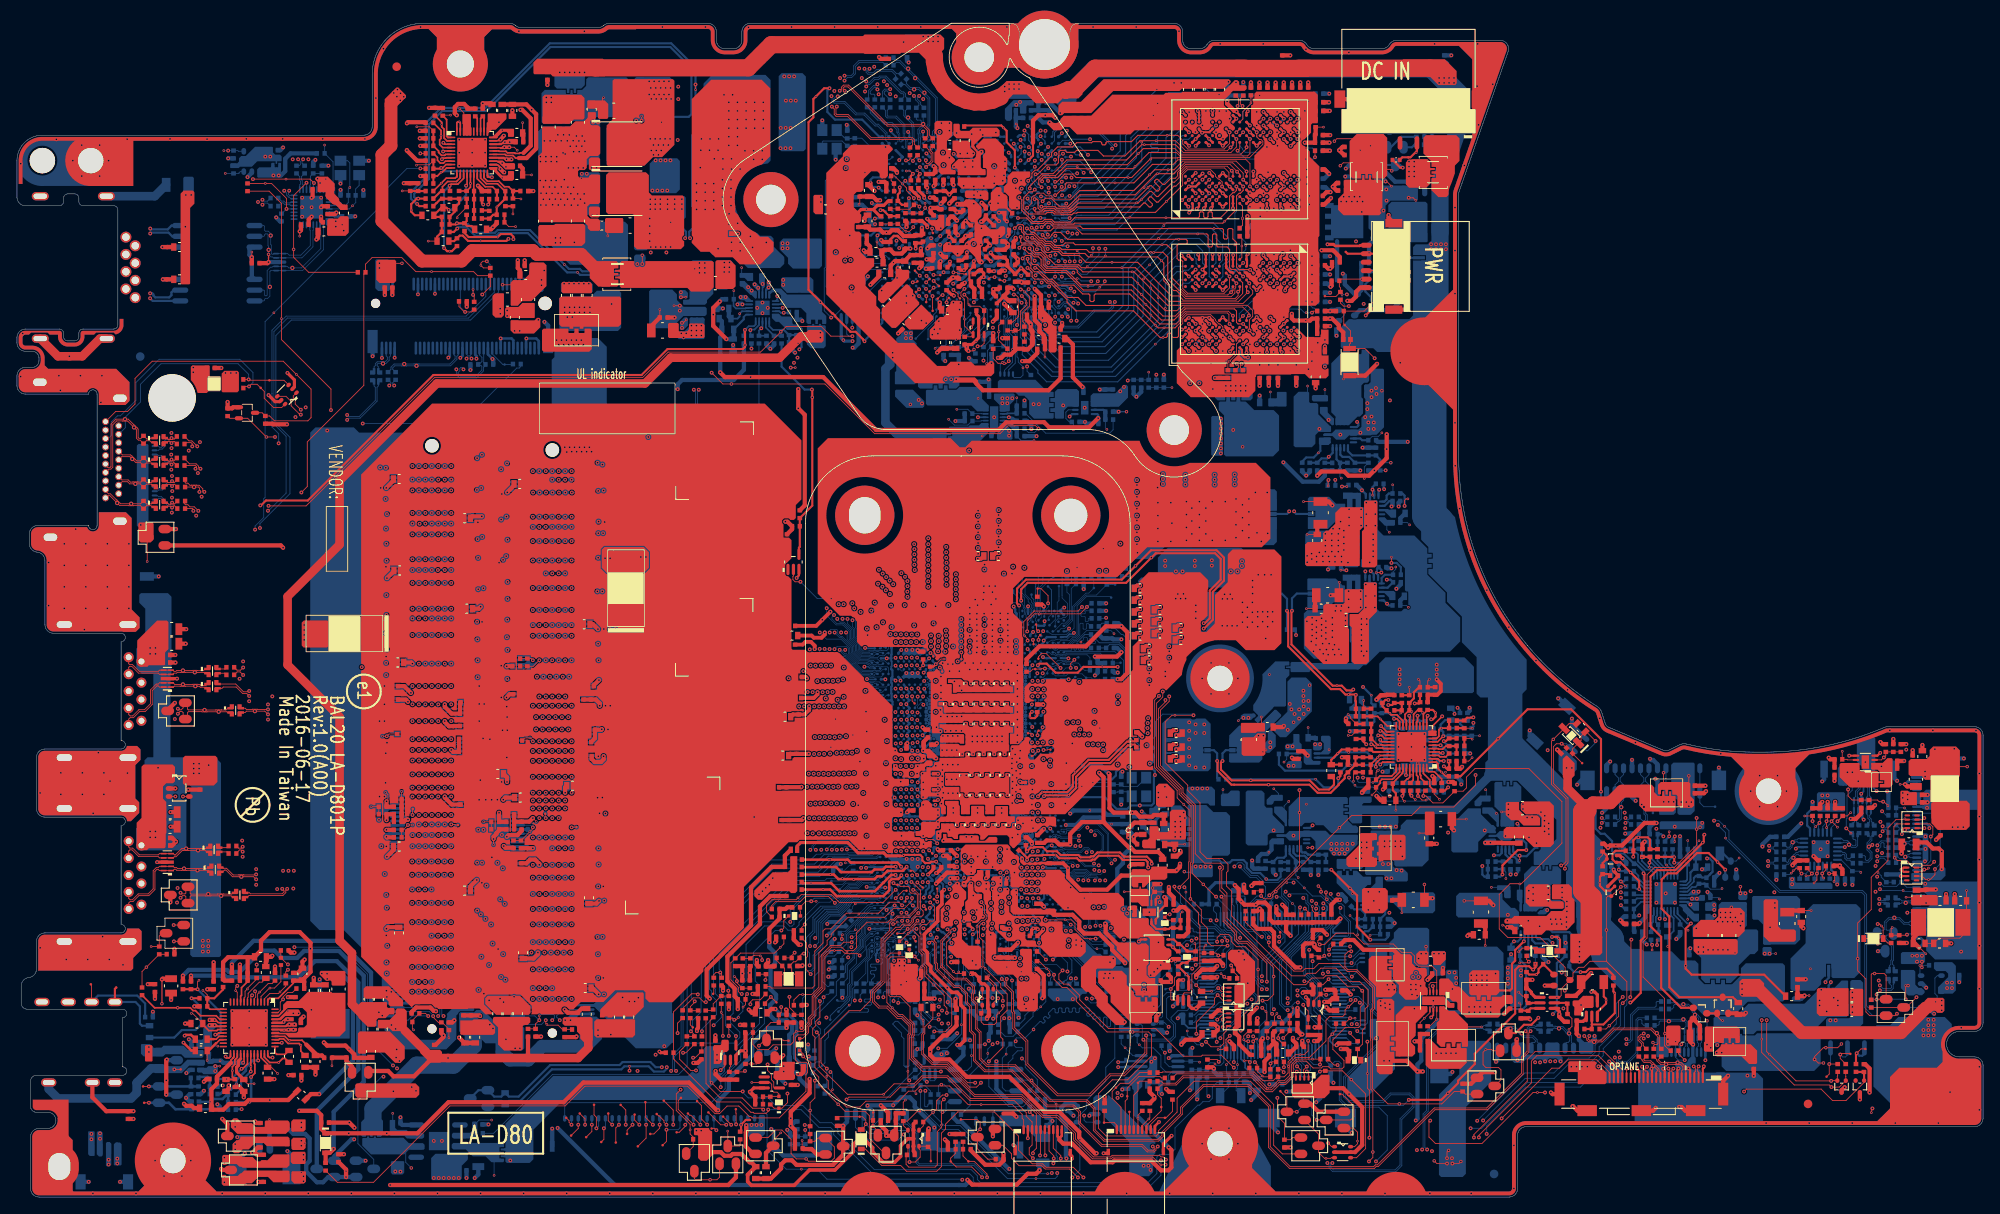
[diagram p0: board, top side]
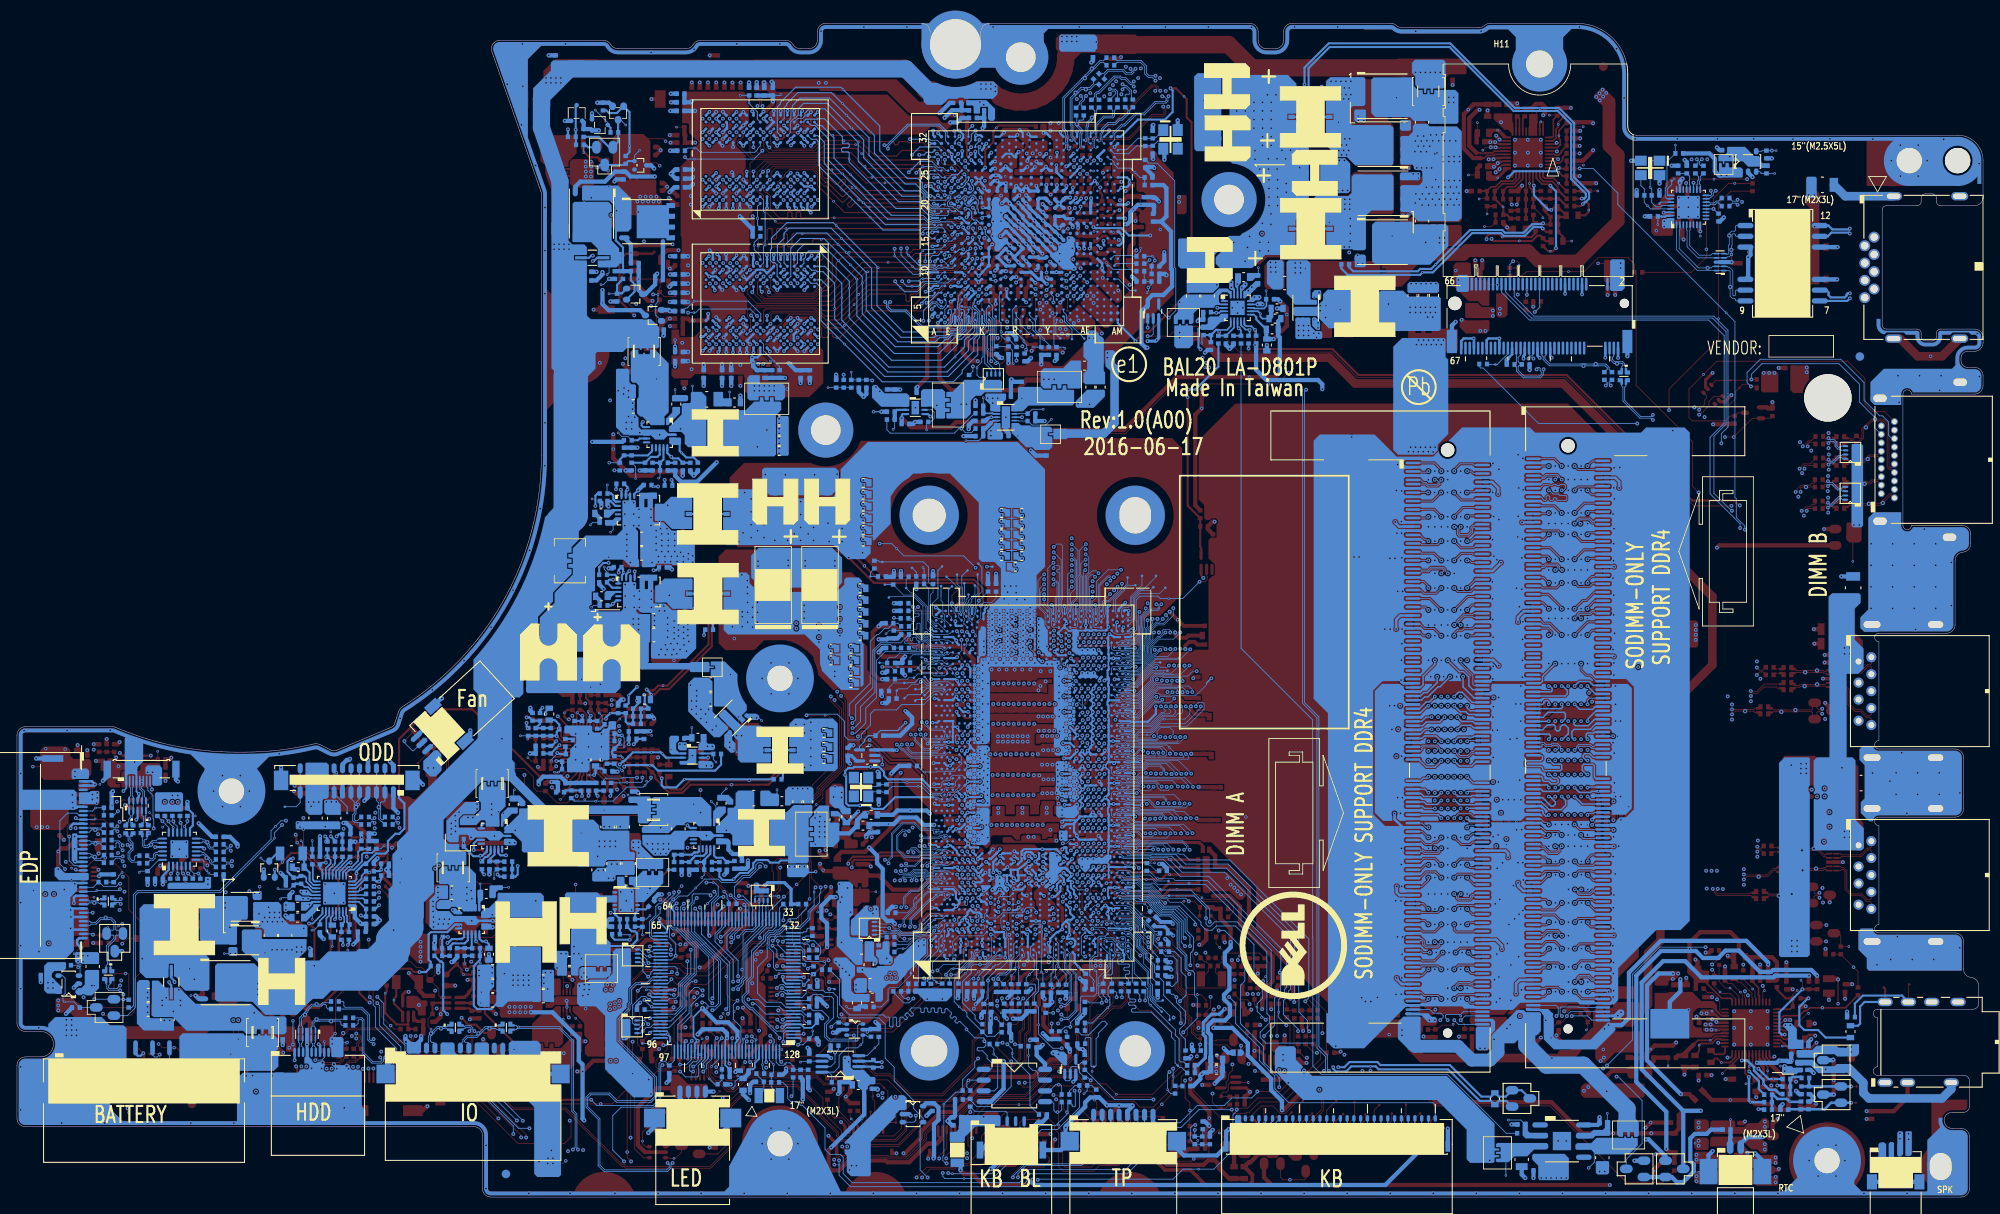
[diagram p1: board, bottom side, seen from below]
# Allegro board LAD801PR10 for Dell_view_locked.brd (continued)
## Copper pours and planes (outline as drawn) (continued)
+5VS on TOP (solid shape): 193.12,48.34 193.12,47.77 193.46,47.44 193.46,47.36 193.54,47.36 193.57,47.33 194.04,47.33 194.05,47.34 194.05,47.87 194.07,47.89 194.29,47.89 194.31,47.88 194.31,47.37 194.34,47.33 194.84,47.33 194.86,47.35 194.86,47.86 194.89,47.89 195.08,47.89 195.11,47.86 195.11,47.37 195.15,47.33 195.59,47.33 195.63,47.29 195.63,45.77 195.35,45.48 192.04,45.48 191.35,46.18 191.35,48.47 191.54,48.66 192.81,48.66
+5VS on BOTTOM (solid shape): 183.58,51.81 183.62,51.81 183.98,51.45 183.98,50.44 183.15,49.61 182.52,49.61 181.82,50.31 181.82,51.74 181.84,51.75 181.84,52.22 182.32,52.7 182.7,52.7
+5VS on BOTTOM (solid shape): 195.46,46.87 195.53,46.87 195.55,46.87 195.66,46.75 195.66,45.36 195.41,45.1 193.76,45.1 193.7,45.17 193.7,45.99 193.7,46 193.7,46.32 193.84,46.46 193.84,46.46 194.27,46.88 194.38,46.88 194.5,46.87 194.61,46.88 195.32,46.88
+5VS on IN1 (solid shape): 26.82,97.36 26.82,94.7 26.56,94.44 25.04,94.44 24.21,95.27 24.21,97.24 24.47,97.49 26.69,97.49
+5VS on IN1 (solid shape): 33.48,40.72 33.48,38.44 33.17,38.12 31.45,38.12 31.14,38.44 31.14,40.34 31.71,40.91 33.29,40.91
+5VS on IN2 (solid shape): 184.8,51.02 184.8,50.23 184.69,50.13 182.55,50.13 182.37,50.31 182.37,51.04 182.5,51.17 184.66,51.17
+5VS on IN2 (solid shape): 187.03,30.05 187.03,28.02 187,27.99 187,27.86 186.71,27.58 184.23,27.58 184.04,27.77 184.04,30.18 184.23,30.37 186.71,30.37
+5VS on IN2 (solid shape): 194.27,47.77 194.71,47.77 195.66,46.82 195.66,46.56 195.54,46.44 194.01,46.44 193.44,47.01 193.44,47.71 193.63,47.9 194.14,47.9
+5VS on IN2 (solid shape): outline of 748 points within 166.64,16.23 201.51,23.64
+5VS on IN3 (solid shape): 195.73,47.2 195.73,46.5 195.54,46.31 193.95,46.31 193.82,46.44 193.82,47.33 194.04,47.55 195.38,47.55
+5VS on VCC: 48,7.2 44.53,10.67 44.53,16.51 29.17,31.88 29.17,38.07 29.97,38.88 32.75,38.88 43.92,27.71 53.95,27.71 58.44,23.22 58.44,19.1 62.33,15.2 96.3,15.2 98.34,13.16 136.71,13.16 139.19,15.64 165.42,15.64 166.2,16.42 166.2,17.95 166.94,18.69 169.78,18.69 171.53,16.93 171.53,13.84 168.63,10.94 140.25,10.94 136.51,7.2
+5VS_ODD on TOP (solid shape): 197.38,48.79 197.38,47.33 197.82,46.88 197.82,46.18 197.57,45.93 196.24,45.93 195.85,46.31 195.85,47.33 195.71,47.47 195.27,47.47 195.24,47.5 195.24,48.01 195.21,48.04 194.74,48.04 194.72,48.02 194.72,47.5 194.69,47.48 194.46,47.48 194.44,47.5 194.44,48.03 194.43,48.04 193.97,48.04 193.94,48.01 193.92,48 193.92,47.55 193.88,47.51 193.6,47.51 193.57,47.54 193.57,48.66 193.89,48.98 197.19,48.98
+5VS_ODD on BOTTOM (solid shape): 197.88,51.14 197.88,47.08 197.88,47.08 197.88,45.54 197.44,45.1 196.04,45.1 195.85,45.29 195.85,46.82 195.66,47.01 195.4,47.01 195.37,47.01 195.12,47.26 195.12,51 195.38,51.26 197.76,51.26
+17.4V_BATT+ on TOP (solid shape): 216.05,24.59 216.05,21.42 215.98,21.35 212.62,21.35 212.29,21.68 212.29,24.48 212.47,24.66 215.98,24.66
+17.4V_BATT+ on BOTTOM (solid shape): outline of 105 points within 200.11,19.2 215.98,25.55
+17.4V_BATT++ on BOTTOM (solid shape): 212.74,18.95 212.74,15.64 211.98,14.88 201.6,14.88 201.06,15.42 201.06,16.63 201.07,16.67 201.11,16.68 201.43,17.04 201.11,17.39 201.07,17.41 201.06,17.44 201.06,18.62 201.51,19.07 202.3,19.07 202.3,19.08 202.78,19.08 202.78,19.07 203.11,19.07 203.11,19.08 205,19.08 205.25,19.33 212.36,19.33
+19V_ADPIN on TOP (solid shape): 161.63,124.99 161.63,120.67 161.62,120.67 161.62,120.55 161.26,120.19 159.85,120.19 159.85,120.72 159.34,120.72 159.34,120.19 159.05,120.19 159.05,120.72 158.54,120.72 158.54,120.19 157.54,120.19 157.18,120.54 157.18,124.61 158.01,125.44 161.18,125.44
+19V_VIN on TOP (solid shape): 158.92,120.06 159.47,120.06 159.47,120.59 159.72,120.59 159.72,120.06 160.83,120.06 161.06,119.83 161.06,116.73 160.83,116.46 160.96,116.12 160.68,115.85 156.47,115.85 155.82,116.49 155.82,117.79 156.48,118.45 156.5,118.47 156.5,119.93 156.62,120.06 158.67,120.06 158.67,120.59 158.92,120.59
+19V_VIN on BOTTOM: 154.36,117.58 155.16,117.58 155.9,118.32 158.74,118.32 159.06,118 159.06,112.82 158.73,112.49 155.24,112.49 154.92,112.81 154.26,112.81 154.03,113.04 154.03,117.25
+19VB on TOP (solid shape): 152.67,134.07 152.67,132.48 152.36,132.16 143.72,132.16 143.21,132.67 143.21,133.69 143.72,134.19 152.55,134.19
+19VB on TOP (solid shape): 206.08,25.23 206.08,24.02 205.7,23.64 203.47,23.64 203.16,23.96 203.16,25.42 203.47,25.74 205.57,25.74
+19VB on TOP (solid shape): 69.49,133.95 69.49,132.42 69.3,132.23 63.2,132.23 62.95,132.48 61.04,132.48 60.92,132.61 60.92,133.88 61.36,134.33 69.11,134.33
+19VB on TOP (solid shape): 169.82,132.86 169.82,131.41 169.63,131.21 167.66,131.21 166.64,132.23 163.79,132.23 163.09,132.93 163.09,133.82 163.53,134.26 168.42,134.26
+19VB on TOP (solid shape): 230.33,46.4 230.33,43.74 229.91,43.32 226.56,43.32 226.16,43.72 226.16,43.77 225.8,44.12 225.8,46.46 226.11,46.76 229.97,46.76
+19VB on TOP (solid shape): 44.99,130.91 45.88,130.02 45.88,129.76 44.54,128.42 43.63,128.42 43.37,128.67 43.37,129.55 44.74,130.92 44.94,130.92
+19VB on TOP (solid shape): 109.37,136.74 109.37,135.57 109.33,135.44 108.03,134.14 107.27,134.14 106.39,135.02 104.29,135.02 104.17,134.9 99.96,134.9 99.59,135.27 99.59,136.8 99.97,137.18 108.92,137.18
+19VB on TOP (solid shape): 70.95,110.22 70.95,109.57 70.42,109.57 70.42,109.07 70.43,109.07 70.43,109.05 70.95,109.05 70.95,108.77 70.42,108.77 70.42,108.26 70.43,108.26 70.43,108.25 70.95,108.25 70.95,107.58 70.79,107.43 68.57,107.43 67.55,108.45 67.55,109.93 68.06,110.44 70.72,110.44
+19VB on TOP (solid shape): 227.35,23.32 227.35,21.99 227.1,21.74 226.46,21.74 226.45,21.77 226.12,21.98 225.8,21.77 225.78,21.74 225.32,21.74 225,22.05 225,23.13 225.38,23.51 227.16,23.51
+19VB on TOP (solid shape): 118.64,131.69 121.2,130.98 123.76,131.69 123.77,131.69 125.58,131.69 125.69,131.59 125.69,130.13 125.19,129.63 123.34,129.63 122.77,129.06 120.4,129.06 120.39,129.07 120.14,129.07 119.11,130.1 117.5,130.1 116.32,128.92 115.27,128.92 115.08,129.11 115.08,130.13 115.99,131.03 116.37,131.34 116.71,131.69 118.63,131.69
+19VB on BOTTOM (solid shape): 108.98,136.93 108.98,135.4 108.73,135.14 104.86,135.14 104.48,135.53 104.48,136.87 104.8,137.18 108.73,137.18
+19VB on BOTTOM (solid shape): 168.93,133.86 168.93,132.93 171.02,130.83 171.02,128.55 170.83,128.36 169.31,128.36 168.99,128.67 168.99,129.44 166.26,132.17 165.06,132.17 164.74,132.48 164.74,133.82 165.06,134.14 168.65,134.14
+19VB on BOTTOM (solid shape): 67.37,133.83 67.37,132.65 66.97,132.26 66.97,131.21 66.56,130.8 65.96,130.8 65.96,130.27 65.66,130.27 65.66,130.8 65.16,130.8 65.16,130.27 64.86,130.27 64.86,130.8 63.68,130.8 63.39,131.09 63.39,133.95 63.65,134.2 67,134.2
+19VB on BOTTOM (solid shape): 159.8,47.13 159.8,46.67 159.63,46.5 158.84,46.5 158.64,46.3 158.64,44.22 158.51,44.09 157.5,44.09 157.13,44.46 157.13,45.17 157.11,45.2 156.59,45.2 156.59,45.45 157.11,45.45 157.11,45.46 157.11,45.99 157.11,46 156.59,46 156.59,46.25 157.11,46.25 157.11,46.26 157.11,47.09 157.29,47.27 159.66,47.27
+19VB on BOTTOM (solid shape): 168.87,114.96 168.87,97.81 167.98,96.92 164.48,96.92 163.65,97.76 163.65,99.53 163.45,99.72 160.42,99.72 159.98,100.16 156.29,100.16 156.13,100.32 156.13,102.63 157.09,103.59 157.49,103.59 157.5,103.59 157.59,103.56 157.69,103.55 157.87,103.55 157.97,103.56 158.06,103.59 158.07,103.59 164.23,103.59 164.67,104.04 164.67,110.51 166.2,110.51 166.2,111.15 164.67,111.15 164.67,112.1 164.99,112.42 166.39,112.42 166.83,112.86 166.83,114.83 167.34,115.34 168.48,115.34
+19VB on BOTTOM (solid shape): 190.47,29.28 191.61,29.28 191.9,29 195.16,29 196.25,27.91 197.93,27.91 198.33,27.51 198.33,25.8 199.01,25.12 199.81,25.12 199.81,25.13 199.81,25.65 200.26,25.65 200.26,25.13 200.28,25.11 201,25.11 201.01,25.13 201.01,25.65 201.46,25.65 201.46,25.13 201.48,25.11 202.25,25.11 202.27,25.12 202.31,25.12 203.35,26.16 203.35,27.01 203.92,27.58 208.11,27.58 208.11,27.58 208.26,27.58 208.53,27.32 208.53,23.3 208.3,23.07 204.17,23.07 202.59,21.5 198.89,21.5 198.14,22.25 198.14,22.27 197.31,23.11 197.28,23.11 197,23.39 195.8,23.39 194.84,24.35 189.33,24.35 185.75,27.93 185.75,28.35 188.14,30.75 189,30.75
+19VB on BOTTOM (solid shape): 118.73,131.64 121,130.99 123.31,131.45 123.37,131.48 124.51,131.48 124.98,131.01 124.98,129.28 124.57,128.88 122.76,128.88 122.05,129.59 120.99,129.59 120.55,129.75 120.12,129.59 116.77,129.59 116.24,130.11 116.24,131.16 116.72,131.64
+19VB on BOTTOM (solid shape): 169.62,80.22 169.62,80.21 170.89,75.6 172.76,71.21 173.39,70.01 174.07,68.83 174.07,68.83 175.95,66.03 178.07,63.41 178.07,59.9 177.12,58.95 172.61,58.95 172.17,59.4 172.17,63.71 170.43,65.45 170.43,68.5 168.67,70.25 168.67,71.33 166.47,73.53 166.47,74.12 167,74.12 167,74.83 166.47,74.83 166.47,75.32 167,75.32 167,76.03 166.47,76.03 166.47,76.71 165.63,77.56 165.63,80.03 166.52,80.92 168.92,80.92
+19VB on BOTTOM (solid shape): 185.76,45.93 185.76,43.19 187.08,41.86 187.08,40.98 187.61,40.44 187.61,36.78 188.07,36.32 188.07,33.01 187.85,32.79 184.09,32.79 183.9,32.97 183.9,34.77 182.71,35.96 182.71,36.58 182.71,36.59 182.71,38.42 182.74,38.43 182.93,38.81 182.62,39.11 182.61,39.11 182.48,39.24 182.48,39.25 182.16,39.49 181.82,39.29 181.69,39.17 181.58,39.17 181.58,39.17 181,39.17 180.98,39.17 180.98,38.64 180.73,38.64 180.73,39.17 180.71,39.17 180.2,39.17 180.18,39.17 180.18,38.64 179.93,38.64 179.93,39.17 179.91,39.17 179.33,39.17 179.33,39.17 178.98,39.17 178.9,39.25 178.9,40.66 179.03,40.79 179.47,40.79 179.73,41.04 179.73,41.61 179.79,41.67 181,41.67 181.57,42.25 181.57,44.53 176.98,49.11 176.91,49.11 176.91,49.12 176.38,49.12 176.38,48.59 176.13,48.59 176.13,49.12 175.58,49.12 175.58,48.59 175.33,48.59 175.33,49.12 173.32,49.12 173.18,49.25 173.18,51.26 173.5,51.58 173.5,53.87 174.77,55.14 176.55,55.14
+19VB on IN1 (solid shape): 118.66,131.41 118.66,130.28 118.29,129.91 117.47,129.91 116.67,129.11 115.65,129.11 115.08,129.69 115.08,130.26 116.61,131.78 118.3,131.78
+19VB on IN1 (solid shape): 109.24,136.93 109.24,135.98 108.95,135.69 108.95,134.63 108.71,134.38 107.23,134.38 106.65,134.96 103.21,134.96 102.95,135.22 102.95,136.55 103.59,137.18 108.98,137.18
+19VB on IN1 (solid shape): 47.43,130.83 47.43,129.72 47.22,129.51 45.69,129.51 45.28,129.11 44.74,129.11 44.08,129.77 44.08,130.37 44.76,131.05 47.21,131.05
+19VB on IN1 (solid shape): 69.3,133.88 69.3,132.42 68.98,132.1 62.82,132.1 62.81,132.11 62.18,132.11 61.9,132.38 61.9,133.45 62.04,133.58 62.67,133.58 63.42,134.33 68,134.33 68.25,134.35 68.5,134.39 68.79,134.39
+19VB on IN2 (solid shape): 68.73,133.75 68.73,132.8 68.41,132.48 64.03,132.48 63.71,132.8 63.71,133.75 64.09,134.14 68.34,134.14
+19VB on IN2 (solid shape): 168.88,115.51 168.88,111.74 168.74,111.59 166.58,111.59 166.39,111.78 166.39,114.9 167.15,115.66 168.74,115.66
+19VB on IN2 (solid shape): 230.16,43.73 230.16,41.71 229.93,41.48 227.89,41.48 227.7,41.67 227.7,43.88 227.81,43.99 229.9,43.99
+19VB on IN2 (solid shape): 170.26,131.53 170.26,128.48 170.07,128.29 168.55,128.29 168.17,128.67 168.17,130.39 167.53,131.02 167.53,132.23 167.6,132.29 169.5,132.29
+19VB on IN2 (solid shape): 227.41,23.89 227.41,22.05 227.16,21.8 226.44,21.8 226.18,21.98 225.88,21.89 225.81,21.86 225.74,21.89 225.57,22.05 225.57,24.15 225.89,24.47 226.84,24.47
+19VB_1.2V on TOP (solid shape): 72.74,110.44 72.82,110.4 72.83,110.31 72.82,110.23 72.82,110.15 73.04,109.76 73.46,109.89 73.89,109.76 74.11,110.15 74.11,110.23 74.09,110.31 74.11,110.4 74.19,110.44 82.04,110.44 82.19,110.3 82.19,107.34 81.68,106.83 79.52,106.83 79.08,107.28 71.27,107.28 71.1,107.45 71.1,108.39 70.55,108.39 70.55,108.39 70.55,108.64 71.1,108.64 71.1,109.18 70.55,109.18 70.55,109.19 70.55,109.43 71.11,109.43 71.11,110.23 71.32,110.44
+19VB_1.2V on BOTTOM (solid shape): 82.14,110.32 82.14,106.59 81.39,105.85 81.39,105.53 81.17,105.31 78.63,105.31 78.57,105.37 78.57,105.81 78.63,105.88 79.2,105.88 79.33,106.01 79.33,110.18 79.7,110.55 81.9,110.55
+19VB_+1.35VGPU on BOTTOM (solid shape): 157.24,99.97 157.24,99.53 157.31,99.46 158.55,99.46 158.6,99.51 158.6,99.97 158.62,100 159.25,100 159.5,99.75 159.5,96.7 159.5,96.7 159.5,96.31 159.28,96.09 158.89,96.09 158.58,95.78 158.58,94.38 158.77,94.19 158.77,92.74 158.77,92.73 158.77,92.47 158.39,92.09 158.13,92.09 157.12,91.08 155.59,91.08 155.53,91.15 155.53,92.1 155.02,92.61 155.02,98.39 156.64,100 157.21,100
+19VB_+1VALW on BOTTOM (solid shape): 156.98,47.04 156.98,46.38 156.46,46.38 156.46,45.87 156.98,45.87 156.98,45.58 156.46,45.58 156.46,45.07 156.98,45.07 156.98,44.42 157.56,43.84 157.94,43.84 158.2,43.58 158.2,43.08 158.07,42.95 155.02,42.95 154.1,43.87 153.21,43.87 153.17,43.91 153.17,43.93 152.96,44.19 152.62,44.16 151.91,44.16 151.51,43.76 150.06,43.76 149.99,43.83 149.99,46.04 151.15,47.21 156.81,47.21
+19VB_GPU on TOP (solid shape): 67.03,114.62 67.03,112.62 66.63,112.23 61.93,112.23 61.49,112.67 61.49,114.51 61.68,114.7 63.37,114.7 63.49,114.83 66.82,114.83
+19VB_GPU on TOP (solid shape): 66.95,129.69 66.95,127.32 66.77,127.15 65.67,127.15 65.17,126.64 62.12,126.64 61.99,126.77 61.99,129.82 62.25,130.07 66.57,130.07
+19VB_GPU on BOTTOM (solid shape): 72.06,114.73 72.06,110.42 71.65,110.01 65.23,110.01 63.07,112.16 63.07,114.51 63.33,114.77 67.01,114.77 67.33,115.09 71.71,115.09
+19VB_GPU on BOTTOM (solid shape): 72.16,131.85 72.16,127.92 71.67,127.43 67.59,127.43 67.12,126.96 65.55,126.96 65.23,126.64 62.06,126.64 61.87,126.83 61.87,130.26 62.25,130.64 64.28,130.64 64.28,130.64 64.74,130.64 64.74,130.14 65.26,130.14 65.29,130.14 65.29,130.64 65.54,130.64 65.54,130.14 66.06,130.14 66.09,130.14 66.09,130.64 66.12,130.64 66.12,130.64 66.66,130.64 67.14,131.12 67.14,131.66 67.15,131.67 67.15,131.91 67.37,132.13 71.89,132.13
+19VB_GPU on IN3 (solid shape): 66.88,130.45 66.88,127.98 66.63,127.72 62.31,127.72 61.8,128.23 61.8,130.26 62.38,130.83 66.5,130.83
+19VB_GPU on IN3 (solid shape): 67.27,114.26 67.27,111.59 67.01,111.34 63.52,111.34 63.2,111.66 63.2,113.82 63.84,114.45 67.07,114.45
+VCC_CORE on TOP (solid shape): 111.73,54.53 111.73,53.52 111.7,53.49 111.26,53.49 111.14,53.6 111.1,53.6 111.09,53.61 108.9,53.61 108.88,53.63 108.88,54.38 109.14,54.63 111.63,54.63
+VCC_CORE on TOP (solid shape): outline of 3525 points within 106.59,45.17 149.14,76.42
+VCC_CORE on BOTTOM (solid shape): outline of 686 points within 132.04,59.84 148.55,73.7
+VCC_CORE on BOTTOM (solid shape): outline of 625 points within 106.56,46.69 109.38,51.45
+VCC_CORE on BOTTOM (solid shape): outline of 788 points within 117.12,45.74 120.07,53.3
+VCC_CORE on IN1 (solid shape): outline of 577 points within 135.22,60.67 148.94,76.68
+VCC_CORE on IN1 (solid shape): outline of 1296 points within 108.1,46.18 118.7,54.66
+VCC_CORE on IN2 (solid shape): outline of 5172 points within 108.16,44.25 149.63,75.84
+VCC_CORE on IN3 (solid shape): outline of 1251 points within 131.69,60.19 148.91,76.5
+VCC_CORE on IN3 (solid shape): outline of 1438 points within 108.24,45.99 118.44,54.64
+VCC_CORE on VCC: 105.56,45.24 105.56,54.3 105.56,54.31 108.96,54.31 109.28,54.63 116.12,54.63 117.63,53.12 117.63,53.11 117.89,52.86 122.3,52.86 125.56,56.12 125.56,68.37 133.15,75.96 148.55,75.96 148.55,59.75 146.54,57.75 137.14,57.75 124.63,45.24
+VCC_GT on TOP (solid shape): outline of 6134 points within 94.44,53.42 147.85,89.55
+VCC_GT on BOTTOM (solid shape): outline of 646 points within 110.64,71.09 148.61,89.11
+VCC_GT on BOTTOM (solid shape): outline of 4095 points within 107.03,52.09 119.2,72.72
+VCC_GT on IN1 (solid shape): outline of 379 points within 134.28,77.06 148.64,87.22
+VCC_GT on IN1 (solid shape): outline of 2414 points within 108.13,53.42 118.4,81.21
+VCC_GT on IN2 (solid shape): outline of 5058 points within 108.61,53.23 148.16,86.7
+VCC_GT on IN3 (solid shape): outline of 610 points within 131.9,75.84 148.38,87.17
+VCC_GT on IN3 (solid shape): outline of 1691 points within 108.24,53.46 118.59,72.43
+VCC_GT on VCC: 105.56,54.81 105.56,59.69 104.52,60.73 100.14,60.73 99.33,61.53 99.33,87.49 106.17,94.32 146.13,94.32 146.13,86.34 148.55,83.92 148.55,76.47 132.94,76.47 125.05,68.58 125.05,56.33 122.09,53.36 118.1,53.36 116.33,55.13 109.08,55.13 108.76,54.81
+VCC_SA on TOP (solid shape): outline of 376 points within 108.42,41.17 122.58,44.91
+VCC_SA on BOTTOM (solid shape): 108.99,43.12 108.99,42.17 108.8,41.98 108.77,41.98 108.54,42.07 108.31,41.98 108.1,41.98 107.98,42.11 107.98,43.12 108.1,43.25 108.86,43.25
+VCC_SA on BOTTOM (solid shape): outline of 122 points within 135.08,50.25 140.8,56.48
+VCC_SA on BOTTOM (solid shape): outline of 496 points within 117.18,41.53 120.09,45.96
+VCC_SA on IN1 (solid shape): outline of 413 points within 108.45,41.56 120.12,44.79
+VCC_SA on IN3 (solid shape): outline of 453 points within 108.48,41.96 118.51,44.71
+VCC_SA on VCC: 105.56,41.87 105.56,44.73 124.84,44.73 137.35,57.24 140.86,57.24 140.86,47.88 139.8,46.82 136,46.82 131.05,41.87
+VDD_CT on IN3 (solid shape): outline of 147 points within 101.48,116.83 108.92,119.91
+VDDR3 on TOP (solid shape): 109.38,115.82 109.38,114.38 109.02,114.02 108.48,114.02 108.3,114.21 108.3,114.24 108.2,114.53 107.9,114.63 107.88,114.63 107.14,115.37 107.14,115.55 107.23,115.64 107.41,115.64 107.76,115.28 108.48,115.28 108.66,115.46 108.66,115.82 108.75,115.91 109.29,115.91
GND on TOP (solid shape): 36.75,67.9 36.75,65.03 36.56,64.84 33.81,64.84 33.59,65.07 33.59,67.79 33.83,68.03 36.62,68.03
GND on TOP (solid shape): 60.58,22.51 60.58,21.73 60.35,21.5 56.51,21.5 55.24,22.77 55.24,23.45 55.54,23.76 59.34,23.76
GND on TOP (solid shape): 67.84,107.72 67.84,106.77 67.71,106.64 64.41,106.64 64.22,106.83 64.22,107.85 64.34,107.97 67.58,107.97
GND on TOP (solid shape): 73.93,24.03 73.93,22.44 72.79,21.3 68.85,21.3 68.79,21.36 68.79,22.12 70.82,24.15 73.81,24.15
GND on TOP (solid shape): 74.54,76.08 74.54,74.26 73.94,73.66 69.55,73.66 68.98,74.23 68.98,76.4 69.29,76.71 73.91,76.71
GND on TOP (solid shape): 95.08,118.13 95.08,116.03 95.02,115.97 94.19,115.97 93.94,116.22 93.94,118.13 94.06,118.26 94.95,118.26
GND on TOP (solid shape): 108.08,103.92 108.08,103.57 106.87,102.37 105.23,102.37 104.71,102.89 104.71,103.38 106.65,105.31 106.69,105.31
GND on TOP (solid shape): 161.69,36.15 161.69,34.05 161.12,33.48 159.02,33.48 158.64,33.86 158.64,36.28 158.83,36.47 161.37,36.47
GND on TOP (solid shape): 217.76,24.47 217.76,21.48 217.63,21.35 216.43,21.35 216.17,21.61 216.17,24.34 216.43,24.59 217.63,24.59
GND on TOP (solid shape): 136.55,47.9 136.55,46.35 136.24,46.04 134.59,46.04 134.35,46.28 134.35,48.44 134.69,48.79 135.66,48.79
GND on TOP (solid shape): 61.74,103.6 61.74,102.64 60.98,101.88 58.6,101.88 58.21,102.27 58.21,103.39 58.27,103.45 61.05,103.45 61.34,103.74 61.59,103.74
GND on TOP (solid shape): 84.77,109.92 84.77,107.46 84.46,107.15 82.51,107.15 82.38,107.28 82.38,110.39 82.54,110.55 84.15,110.55
GND on TOP (solid shape): 45.55,23.2 45.55,22.57 45.48,22.5 44.02,22.5 43.83,22.69 43.83,23.07 43.52,23.39 41.12,23.39 40.89,23.63 40.89,24.6 41.15,24.87 43.88,24.87
GND on TOP (solid shape): 45.74,17.77 45.74,16.34 45.23,15.84 44.6,15.84 43.39,17.04 41.23,17.04 41.1,16.91 40.34,16.91 40.21,17.04 40.21,19.33 40.44,19.55 43.96,19.55
GND on TOP (solid shape): 168.54,28.86 168.54,28.01 167.9,27.37 167.23,27.37 167.19,27.41 167.08,27.41 167.04,27.45 167.04,28.22 166.83,28.43 166.83,28.91 166.94,29.01 168.38,29.01
GND on TOP (solid shape): 203.79,33.62 203.79,31.39 203.09,30.69 197.76,30.69 197.69,30.76 197.69,31.8 198.61,32.71 200.25,32.71 200.67,33.13 200.67,33.91 200.88,34.12 203.28,34.12
GND on TOP (solid shape): 104.45,109.4 105.14,109.4 105.24,109.3 105.24,108.48 102.24,105.48 101.94,105.48 101.57,105.85 101.57,106.93 102.62,107.98 103.09,107.98 103.63,108.52 103.63,109.71 103.81,109.89 103.96,109.89
GND on TOP (solid shape): 169.11,22.88 169.51,22.88 169.54,22.85 169.54,22.4 169.46,22.32 168.78,22.32 168.41,22.69 165.79,22.69 165.77,22.71 165.77,23.64 165.79,23.66 168.33,23.66
GND on TOP (solid shape): 78.06,103.02 78.06,102.2 78.12,102.13 79.01,102.13 79.27,102.39 79.27,102.96 79.39,103.08 80.92,103.08 81.11,102.89 81.11,101.5 80.98,101.37 76.92,101.37 76.79,101.5 76.79,103.02 76.92,103.15 77.93,103.15
GND on TOP (solid shape): 92.04,40.2 92.04,36.11 91.8,35.87 91.3,35.87 91.08,36.09 88.89,36.09 87.87,35.08 87.39,35.08 86.96,35.51 86.96,36.17 89.12,38.32 90.91,38.32 91.2,38.61 91.2,40.15 91.28,40.23 92.01,40.23
GND on TOP (solid shape): 143.15,131.72 143.15,131.59 142.32,130.76 137.37,130.76 137.12,130.51 129.31,130.51 126.7,127.91 123.53,127.91 123.27,127.65 122.96,127.65 122.83,127.78 122.83,128.8 123.27,129.24 125.5,129.24 128.16,131.91 142.96,131.91
GND on TOP (solid shape): 158.76,81.31 158.76,79.05 158.39,78.68 158.39,74.51 158.32,74.45 153.24,74.45 153.24,74.45 152.12,74.45 151.94,74.63 151.94,76.99 152.23,77.28 153.67,77.28 154.07,77.68 154.07,78.32 154.39,78.64 154.7,78.64 155.49,79.42 155.49,80.74 156.15,81.4 158.67,81.4
GND on TOP (solid shape): 181.28,46.18 181.28,41.71 180.87,41.3 178.87,41.3 177.83,42.34 175.49,42.34 175.34,42.48 175.34,43.33 175.69,43.67 179.76,43.67 179.85,43.77 179.85,44.79 179.47,45.17 177.95,45.17 177.38,45.74 177.38,46.37 177.69,46.69 180.77,46.69
GND on TOP (solid shape): 116.14,119.03 116.14,118.65 116.44,118.34 116.56,118.34 116.83,118.07 116.83,116.81 116.65,116.63 115.76,116.63 115.49,116.36 114.95,116.36 114.77,116.54 114.77,116.97 114.59,117.15 114.59,117.44 114.86,117.71 114.86,118.51 115.51,119.17 116,119.17
GND on TOP (solid shape): 166.71,122.14 166.71,121.43 167.24,121.43 167.24,121.18 166.71,121.18 166.71,120.63 167.24,120.63 167.24,120.38 166.71,120.38 166.71,119.58 166.23,119.1 164.19,119.1 163.82,119.47 163.82,121.55 163.82,121.55 163.82,122.09 164.15,122.41 164.19,122.42 164.23,122.43 164.47,122.43 164.51,122.47 166.38,122.47
GND on TOP (solid shape): 183.41,36.53 183.41,35.39 183.73,35.07 183.73,32.41 182.77,31.46 180.36,31.46 179.85,30.95 177.82,30.95 177.69,31.08 177.69,31.72 177.16,32.25 175.58,32.25 175.43,32.4 175.43,32.68 175.64,32.89 176.32,32.89 176.61,33.17 180.42,33.17 180.99,33.74 182.26,33.74 182.58,34.06 182.58,34.82 182.27,35.13 181.12,35.13 181.06,35.2 181.06,36.78 181.19,36.91 183.03,36.91
GND on TOP (solid shape): 158.35,71.71 158.61,71.71 158.72,71.6 158.72,69.48 158.19,68.95 157.04,68.95 156.98,68.89 156.98,67.15 157.12,67.02 157.12,63.21 156.81,62.9 154.08,62.9 151.87,65.11 151.87,68.2 152.24,68.57 153.66,68.57 154.07,68.99 154.07,69.75 154.2,69.87 154.21,69.87 154.31,69.97 156.41,69.97 156.59,70.15 156.59,71.6 156.7,71.72 158.34,71.72
GND on TOP (solid shape): 109.62,42.84 109.62,42.48 109.76,42.35 110.22,42.35 110.45,42.12 111.08,42.12 111.17,42.21 111.17,42.52 111.17,42.65 111.22,42.69 113.3,42.69 113.43,42.56 113.43,42.13 113.51,42.05 114.14,42.05 114.14,42.06 114.19,42.06 114.64,42.5 115.5,42.5 115.64,42.36 115.64,41.9 115.54,41.8 109.14,41.8 109.02,41.92 109.02,42.15 109.24,42.37 109.24,42.84 109.25,42.85 109.61,42.85
GND on TOP (solid shape): 14.7,31.39 14.7,29.2 13.71,28.21 13.71,26.97 13.46,26.71 2.49,26.71 2.5,26.81 2.5,26.9 2.5,30.17 2.74,30.73 3.3,30.96 12.28,30.96 12.79,31.18 12.98,31.69 14.4,31.69
GND on TOP (solid shape): 111.64,60.84 112.08,60.84 112.17,60.75 112.17,60.43 112.36,60.24 112.7,60.24 112.89,60.43 112.89,60.81 112.93,60.85 113.34,60.85 113.38,60.81 113.38,60.43 113.57,60.24 113.91,60.24 114.09,60.43 114.09,60.81 114.13,60.85 114.54,60.85 114.59,60.81 114.59,60.43 114.77,60.24 115.11,60.24 115.3,60.43 115.3,60.81 115.34,60.85 115.75,60.85 115.79,60.81 115.79,60.43 115.98,60.24 116.32,60.24 116.5,60.43 116.5,60.81 116.55,60.85 116.96,60.85 117,60.81 117,60.49 117.02,60.47 117.1,60.35 117.23,60.27 117.25,60.24 117.5,60.24 117.5,59.58 110.89,59.58 110.83,59.52 110.38,59.52 110.38,60.53 110.26,60.66 109.81,60.66 109.81,61.11 111.37,61.11
GND on TOP (solid shape): 111.21,126.54 111.21,125.94 111.34,125.81 112.35,125.81 112.73,126.19 115.59,126.19 115.91,125.88 115.91,125.3 115.72,125.11 113.88,125.11 112.92,124.16 112.92,124.03 113.3,123.47 113.34,123.43 113.46,123.43 113.62,123.59 113.94,123.59 114,123.53 114,123.21 113.69,122.89 113.69,121.49 113.88,121.3 114.19,121.3 114.26,121.24 114.26,120.64 114.19,120.58 110.99,120.58 110.95,120.62 110.95,121.24 110.84,121.36 110.39,121.36 110.28,121.47 110.28,121.75 111.04,122.51 112.86,122.51 113.11,122.76 113.11,122.94 113.12,122.94 113.12,123 113.15,123.14 113.11,123.31 113.11,123.34 112.54,123.91 112.54,124.67 112.29,124.92 110.83,124.92 110.45,125.3 110.45,126.57 110.53,126.66 111.09,126.66
GND on TOP (solid shape): 110.94,58.31 110.94,57.98 111.09,57.83 111.55,57.83 111.68,57.96 111.68,58.31 111.81,58.44 112.07,58.44 112.17,58.33 112.17,58.01 112.36,57.83 112.7,57.83 112.89,58.01 112.89,58.4 112.93,58.44 113.34,58.44 113.38,58.4 113.38,58.01 113.57,57.83 113.91,57.83 114.09,58.01 114.09,58.4 114.13,58.44 114.54,58.44 114.59,58.4 114.59,58.01 114.77,57.83 115.11,57.83 115.3,58.01 115.3,58.4 115.34,58.44 115.75,58.44 115.79,58.4 115.79,58.01 115.98,57.83 116.32,57.83 116.5,58.01 116.5,58.4 116.55,58.44 116.96,58.44 117,58.4 117,58.08 117.02,58.05 117.1,57.93 117.23,57.85 117.25,57.83 117.5,57.83 117.5,57.17 109.37,57.17 109.3,57.23 109.3,57.84 109.13,58.02 108.73,58.02 108.71,58.04 108.71,58.35 108.77,58.41 109.62,58.41 109.72,58.31 109.72,57.96 109.85,57.83 110.36,57.83 110.48,57.96 110.48,58.31 110.61,58.44 110.81,58.44
GND on TOP (solid shape): 14.57,52.82 14.57,51.58 13.96,50.97 13.96,47.03 14.42,46.58 14.42,45.32 13.44,44.34 12.98,44.34 12.77,44.83 12.28,45.04 3.3,45.04 2.74,45.27 2.5,45.83 2.5,51.87 2.74,52.43 3.3,52.66 12.28,52.66 12.73,52.82 12.97,53.23 14.17,53.23
GND on TOP (solid shape): 68.28,127.94 68.28,127.27 68.14,127.13 68.09,127.13 67.6,126.82 68.05,126.46 68.44,126.46 68.51,126.45 68.57,126.45 68.8,126.22 68.8,123.12 68.52,122.84 67.59,122.84 67.2,122.45 67.2,121.44 66.95,121.18 66.31,121.18 66.19,121.05 66.19,120.48 66.38,120.29 67.39,120.29 67.74,120.64 68.69,120.64 68.79,120.55 68.79,117.37 68.6,117.18 67.58,117.18 67.27,116.86 67.27,115.78 67.58,115.47 68.54,115.47 68.79,115.21 68.79,114.13 68.66,114.01 67.63,114.01 67.33,114.31 67.33,114.6 66.91,115.02 61.68,115.02 61.49,115.21 61.49,122.83 61.93,123.28 61.93,126.17 62.1,126.33 65.24,126.33 65.55,126.64 65.55,126.64 65.85,126.94 66.9,126.94 67.33,127.37 67.33,127.98 67.35,128 68.22,128
GND on TOP (solid shape): 6.1,11.5 6.1,6.6 1.85,6.6 1.85,7.1 2.07,7.63 2.6,7.85 3.65,7.85 3.73,7.85 4.37,8.08 4.78,8.62 4.76,9.51 4.15,10.15 3.91,10.23 3.65,10.25 2.3,10.25 1.98,10.38 1.85,10.7 1.85,11.5 5.19,11.5
GND on TOP (solid shape): 13.53,80.13 13.53,69.33 14.47,68.39 14.47,67.15 14.01,66.69 12.53,66.69 12.41,66.72 12.28,66.74 4.3,66.74 3.74,66.97 3.5,67.53 3.5,75.1 3.18,75.92 1.87,76.55 1.66,77.09 1.66,78.25 1.9,78.81 2.46,79.05 8.28,79.05 8.29,79.01 9.07,78.56 9.65,79.25 9.65,80.82 12.85,80.82
GND on TOP (solid shape): outline of 110 points within 108.82,51.96 117.5,56.09
GND on TOP (solid shape): outline of 148 points within 111.56,32.35 114.13,37.17
GND on TOP (solid shape): outline of 160 points within 109.24,110.07 116.57,117.71
GND on TOP (solid shape): outline of 182 points within 103.34,49.44 108.03,51.55
GND on TOP (solid shape): 112.25,49.95 112.25,49.63 112.44,49.45 112.77,49.45 112.96,49.63 112.96,50.01 113,50.06 113.41,50.06 113.46,50.01 113.46,49.63 113.64,49.45 113.98,49.45 114.17,49.63 114.17,50.01 114.21,50.06 114.62,50.06 114.66,50.01 114.66,49.63 114.85,49.45 115.19,49.45 115.38,49.63 115.38,50.01 115.42,50.06 115.83,50.06 115.87,50.01 115.87,49.63 116.06,49.45 116.39,49.45 116.58,49.63 116.58,50.01 116.62,50.06 116.97,50.06 117.05,49.98 117.05,47.68 117.02,47.59 117.04,47.49 116.82,47.19 116.61,47.49 116.59,47.68 116.42,47.77 116.02,47.77 115.85,47.68 115.83,47.49 115.62,47.19 115.4,47.49 115.38,47.68 115.21,47.77 114.81,47.77 114.65,47.68 114.62,47.49 114.41,47.19 114.2,47.49 114.17,47.68 114,47.77 113.61,47.77 113.44,47.68 113.42,47.49 113.2,47.19 112.99,47.49 112.97,47.68 112.8,47.77 112.4,47.77 112.23,47.68 112.21,47.49 112,47.19 111.78,47.49 111.78,47.64 111.66,47.77 111.31,47.77 111.29,47.79 111.29,48.41 111.17,48.53 109.56,48.53 109.46,48.63 109.46,49.49 109.51,49.66 109.46,49.84 109.46,50 109.52,50.06 112.14,50.06
GND on TOP (solid shape): outline of 116 points within 105.99,42.37 117.69,46.75
GND on TOP (solid shape): 12.56,102.92 12.3,102.19 11.64,101.79 11.4,102.02 9.35,102.02 9.09,101.76 7.96,101.76 7.96,101.52 7.62,100.7 6.8,100.36 6,100.36 5.18,100.7 4.84,101.52 4.84,101.76 3.86,101.76 3.6,102.02 1.68,102.02 1.42,101.76 1,101.76 0.76,101.66 0.66,101.42 0.66,100.8 0.76,100.56 1,100.46 1.8,100.46 2.83,100.03 3.26,99 3.26,98.15 3.68,97.73 11.7,97.73 13.28,96.16 13.28,93.95 12.8,93.46 9.65,93.46 9.65,94.75 9.07,95.44 8.29,94.99 8.28,94.95 1,94.95 0.44,95.19 0.2,95.75 0.2,96.9 0.44,97.46 1,97.7 1.8,97.7 2.51,97.99 2.8,98.7 2.8,99 2.51,99.71 1.8,100 1,100 0.44,100.24 0.2,100.8 0.2,101.42 0.44,101.99 1,102.22 5,102.22 5.21,102.13 5.3,101.92 5.3,101.52 5.5,101.03 6,100.82 6.8,100.82 7.3,101.03 7.5,101.52 7.5,101.92 7.59,102.13 7.8,102.22 11.4,102.22 11.9,102.43 12.1,102.92 12.1,103.62 12.56,103.62
GND on TOP (solid shape): outline of 263 points within 0.2,0.2 231.7,138.3
GND on BOTTOM (solid shape): 45.68,4.16 45.68,2.86 45.47,2.66 44.3,2.66 44.1,2.86 44.1,4.13 44.2,4.23 45.6,4.23
GND on BOTTOM (solid shape): 67.9,107.72 67.9,106.83 67.77,106.7 64.34,106.7 64.15,106.89 64.15,107.72 64.41,107.97 67.65,107.97
GND on BOTTOM (solid shape): 141.05,39.11 141.05,37.87 140.93,37.74 138.97,37.74 138.49,38.22 138.49,39.04 138.68,39.24 140.92,39.24
GND on BOTTOM (solid shape): 142.26,91.91 142.26,87.72 142,87.46 140.99,87.46 140.86,87.59 140.86,92.04 140.99,92.16 142,92.16
GND on BOTTOM (solid shape): 145.31,75.72 145.31,73.1 144.12,71.91 135.14,71.91 134.58,72.48 134.58,75.46 135.72,76.6 144.42,76.6
GND on BOTTOM (solid shape): 162.9,44.92 162.9,43.52 162.77,43.39 159.85,43.39 159.66,43.58 159.66,44.92 159.72,44.98 162.83,44.98
GND on BOTTOM (solid shape): 185.95,18.12 185.95,17.16 185.71,16.93 184.4,16.93 184.23,17.1 184.23,18.18 184.36,18.31 185.76,18.31
GND on BOTTOM (solid shape): 199.03,44.21 199.03,43.52 198.9,43.39 193.79,43.39 193.76,43.42 193.76,44.2 193.9,44.34 198.9,44.34
GND on BOTTOM (solid shape): 231.62,47.97 231.62,45.97 231.34,45.69 225.05,45.69 224.86,45.88 224.86,47.76 225.18,48.07 231.52,48.07
GND on BOTTOM (solid shape): 171.85,62.57 171.85,59.65 171.66,59.46 161.31,59.46 160.69,60.08 160.69,62.97 161.4,63.68 170.74,63.68
GND on BOTTOM (solid shape): 93.05,132.22 93.05,124.35 93.04,124.34 93.04,123.67 92.78,123.41 90.16,123.41 89.85,123.73 89.85,132.28 90.19,132.62 92.65,132.62
GND on BOTTOM (solid shape): 94.95,112.98 94.95,109.87 94.64,109.56 91.52,109.56 90.95,110.13 90.95,110.83 89.97,111.81 89.97,112.7 90.38,113.11 94.83,113.11
GND on BOTTOM (solid shape): 152.67,51.71 152.93,51.45 153.69,51.45 153.75,51.39 153.75,51.14 153.63,51.01 152.04,51.01 151.79,51.26 151.79,52.85 152.67,52.85
GND on BOTTOM (solid shape): 169.94,26.76 169.94,23.2 169.75,23.01 168.67,23.01 168.55,23.14 168.55,26.69 168.67,26.82 169.88,26.82
GND on BOTTOM (solid shape): 152.74,60.6 152.74,57.3 149.69,54.25 148.99,54.25 148.04,55.21 148.04,55.46 149.85,57.27 149.85,60.83 150.32,61.3 152.04,61.3
GND on BOTTOM (solid shape): 84.48,110.26 84.48,107.78 83.78,107.08 82.76,107.08 82.51,107.34 82.51,110.35 82.71,110.55 84.18,110.55
GND on BOTTOM (solid shape): 107.02,93.92 107.02,93.31 106.84,93.13 104.9,93.13 103.58,94.45 103.58,95.14 103.7,95.27 105.67,95.27
GND on BOTTOM (solid shape): 217.76,25.3 217.76,20.47 216.93,19.65 213.44,19.65 213.38,19.7 213.38,20.92 213.57,21.11 216.11,21.11 216.24,21.23 216.24,25.42 216.43,25.61 217.44,25.61
GND on BOTTOM (solid shape): 77.11,122.58 77.87,122.58 78.19,122.26 78.19,118.89 77.75,118.45 74.88,118.45 74.63,118.7 74.63,121.94 74.69,122.01 75.27,122.58 76.08,122.58 76.08,122.58 77.11,122.58
GND on BOTTOM (solid shape): 93.94,108.22 93.94,106.76 93.87,106.7 90.83,106.7 90.13,107.4 90.13,108.35 90.32,108.54 93.62,108.54
GND on BOTTOM (solid shape): 133.18,25.49 133.18,24.34 132.93,24.09 132.61,24.09 132.61,24.09 132.14,24.09 131.78,24.09 131.65,24.22 131.65,24.48 131.65,25.74 131.75,25.84 132.83,25.84
GND on BOTTOM (solid shape): 141.31,48.03 141.31,46.25 141.24,46.19 140.73,46.19 140.48,46.44 138.07,46.44 137.94,46.57 137.94,48.16 138.22,48.44 140.9,48.44
GND on BOTTOM (solid shape): 144.01,85.79 144.01,83.72 143.1,82.81 135.82,82.81 134.96,83.67 134.96,85.65 135.37,86.07 143.74,86.07
GND on BOTTOM (solid shape): 168.51,28.89 168.51,27.05 168.21,26.74 168.21,26.21 168.11,26.12 167.12,26.12 167.08,26.16 167.08,26.17 167.03,26.22 167.03,28.13 166.85,28.3 166.85,28.9 167,29.05 168.35,29.05
GND on BOTTOM (solid shape): 85.81,105.43 86.7,105.43 86.76,105.36 86.76,105.3 86.7,105.24 85.81,105.24 85.68,105.11 84.92,105.11 84.79,105.24 84.79,105.43 84.9,105.54 84.93,105.54 84.93,105.57 85.05,105.68 85.55,105.68
GND on BOTTOM (solid shape): 161.12,37.74 161.12,36.43 160.93,36.24 160.93,33.68 160.86,33.62 159.21,33.62 159.15,33.68 159.15,36.28 159.21,36.35 159.53,36.35 160.23,37.04 160.23,37.68 160.36,37.81 161.05,37.81
GND on BOTTOM (solid shape): 177.63,27.27 177.63,22.76 177.31,22.44 176.21,22.44 176.13,22.52 176.13,24.3 175.61,24.82 175.61,27.27 175.8,27.46 177.44,27.46
GND on BOTTOM (solid shape): 81.11,103.59 81.11,101.36 80.98,101.24 78.06,101.24 77.93,101.36 77.93,102 78.12,102.2 78.68,102.2 78.76,102.2 79.33,102.77 79.33,103.66 79.46,103.78 80.92,103.78
GND on BOTTOM (solid shape): 88.23,9.56 88.23,7.45 87.9,7.12 86.05,7.12 85.76,7.41 85.76,8.45 85.76,8.51 85.76,8.58 85.92,8.74 87.35,8.74 87.5,8.9 87.5,9.56 87.64,9.7 88.09,9.7
GND on BOTTOM (solid shape): 228.21,20.41 228.21,19.8 227.22,18.81 227.22,18.48 227.12,18.38 227.12,17.59 227.32,17.39 227.32,13.23 224.56,10.46 221.56,10.46 218.97,13.05 218.97,19.9 219.35,20.28 220.94,20.28 221.91,21.25 227.38,21.25
GND on BOTTOM (solid shape): 204.04,34.69 204.04,32.28 204.04,32.28 204.04,32.02 203.79,31.77 203.03,31.77 202.77,31.51 202.77,30.76 202.71,30.69 197.69,30.69 197.63,30.76 197.63,31.96 197.82,32.15 199.79,32.15 200.71,33.08 200.71,34.47 201.06,34.82 203.92,34.82
GND on BOTTOM (solid shape): 135.08,37.11 135.08,35.68 134.96,35.55 134.96,35.15 135.19,34.92 135.19,29.63 132.95,27.39 132.27,27.39 132.15,27.51 132.15,30.48 132.32,30.65 133.52,30.65 133.7,30.82 133.7,32.93 133.28,33.35 133.28,36.83 133.69,37.23 134.96,37.23
GND on BOTTOM (solid shape): 225.45,42.77 225.45,42.74 225.38,42.54 225.45,42.33 225.45,39.7 225.08,39.34 224.92,39.34 224.77,39.49 224.77,42.11 224.78,42.11 224.78,42.86 224.84,42.92 225.29,42.92
GND on BOTTOM (solid shape): 119.93,129.36 119.93,128.86 119.88,128.81 119.18,128.81 119.06,128.69 119.06,127.94 118.96,127.84 118.38,127.84 118.3,127.92 118.3,128.56 118.21,128.65 117.44,128.65 117.37,128.58 117.37,127.22 117.15,127 116.75,127 116.53,127.22 116.53,128.34 116.53,128.35 116.53,128.42 117.55,129.44 119.86,129.44
GND on BOTTOM (solid shape): 136.07,48.26 136.07,46.5 135.45,45.88 135.02,45.88 134.78,45.64 134.78,45.45 134.5,45.17 133.62,45.17 133.55,45.24 133.55,45.83 133.66,45.94 134.03,45.94 134.39,46.3 134.39,48.25 134.59,48.46 135.87,48.46
GND on BOTTOM (solid shape): 162.32,39.52 162.32,39.15 162.32,39.01 162.48,38.85 163.43,38.85 164.04,38.25 164.04,37.36 163.91,37.23 162.2,37.23 162.2,37.24 161.64,37.24 161.64,37.24 161.55,37.24 161.3,37.49 161.3,37.89 161.2,38 159.15,38 159.02,38.12 159.02,39.46 159.21,39.65 162.2,39.65
GND on BOTTOM (solid shape): 219.2,54.12 219.2,48.71 219.1,48.61 219.02,48.61 219.02,48.61 218.92,48.61 218.89,48.64 218.89,49.74 218.73,49.9 218.05,49.9 217.93,49.78 217.9,49.75 217.9,48.66 217.85,48.61 217.75,48.61 217.69,48.66 217.69,50.69 217.01,51.38 217.01,53.94 217.09,54.02 217.54,54.17 217.99,54.32 218.99,54.32
GND on BOTTOM (solid shape): 67.27,126.39 67.27,125.69 67.74,125.21 68.55,125.21 68.73,125.04 68.73,121.94 68.6,121.82 67.33,121.82 67.14,121.63 67.14,121.37 66.95,121.18 66.31,121.18 66.12,120.99 66.12,119.78 66.5,119.4 68.54,119.4 68.73,119.21 68.73,116.42 68.54,116.23 67.71,116.23 66.63,115.15 61.87,115.15 61.49,115.53 61.49,125.75 62.06,126.33 65.23,126.33 65.55,126.64 67.01,126.64
GND on BOTTOM (solid shape): 154.83,42.76 158.07,42.76 158.13,42.7 158.13,41.62 156.8,40.28 155.21,40.28 154.96,40.54 154.96,40.66 154.64,40.98 153.24,40.98 153.15,41.07 153.15,41.96 153.12,42 152.61,42.51 151.53,42.51 151.09,42.06 150.07,42.06 149.63,42.5 148.61,42.5 148.56,42.55 148.56,42.77 148.61,42.82 149.68,42.82 150.07,43.2 151.72,43.2 151.75,43.23 154.36,43.23
GND on BOTTOM (solid shape): 161.25,97.62 161.25,90.83 160.36,89.95 159.79,89.95 159.72,89.88 157.12,89.88 156.61,89.37 155.59,89.37 155.15,89.81 154.13,89.81 154.07,89.87 154.07,90 154.2,90.12 155.09,90.12 155.47,90.5 155.47,90.51 155.53,90.57 158.26,90.57 158.58,90.89 158.58,91.97 159.04,92.43 159.04,94.17 158.9,94.32 158.9,95.78 159.02,95.91 159.41,95.91 159.66,96.16 159.66,97.56 159.85,97.75 161.12,97.75
GND on BOTTOM (solid shape): 157.34,83.14 157.5,83.14 157.53,83.11 157.53,81.38 158.77,81.38 158.78,81.37 158.78,79.09 158.39,78.7 158.39,75.38 158.2,75.19 158.2,74.38 158.13,74.32 156.74,74.32 156.55,74.51 156.55,74.72 154.7,74.72 154.55,74.57 152.13,74.57 151.95,74.76 151.95,78.15 152.45,78.64 154.67,78.64 155.65,79.62 156.76,79.62 156.89,79.75 156.89,82.38 156.88,82.38 156.41,82.38 156.41,82.39 156.41,83.14 157.34,83.14
GND on BOTTOM (solid shape): 157.47,71.73 158.7,71.73 158.72,71.72 158.72,69.35 158.36,68.98 158.18,68.98 158.14,68.94 157.17,68.94 157.06,68.84 157.06,65.29 157.12,65.24 157.12,63.71 156.93,63.52 152.99,63.52 151.79,64.73 151.79,68.85 152.19,69.26 154.65,69.26 155.43,70.03 156.84,70.03 156.84,72.72 156.59,72.72 156.57,72.72 156.37,72.72 156.37,73.45 157.47,73.45
GND on BOTTOM (solid shape): 182.58,36.53 182.58,35.71 183.25,35.04 183.25,31.9 182.9,31.55 181.2,31.55 180.27,32.47 179.15,32.47 178.77,32.09 177.76,32.09 177.37,32.48 175.97,32.48 175.86,32.38 175.58,32.38 175.53,32.43 175.53,32.76 175.61,32.83 175.89,32.83 175.99,32.73 177.46,32.73 177.69,32.96 177.69,33.11 177.76,33.17 180.36,33.17 180.93,33.74 182.26,33.74 182.52,34 182.52,34.75 182.07,35.2 181.12,35.2 181.06,35.26 181.06,36.72 181.12,36.78 182.33,36.78
GND on BOTTOM (solid shape): 181.25,44.41 181.25,42.19 180.92,41.86 179.92,41.86 179.79,41.99 179.79,42.63 179.66,42.75 178.77,42.75 178.58,42.56 178.58,42.25 178.46,42.12 178.14,42.12 177.82,42.44 176.55,42.44 176.17,42.06 175.02,42.06 174.59,42.5 173.63,42.5 173.57,42.56 173.57,42.63 173.69,42.75 174.45,42.75 174.9,43.2 177.56,43.2 177.82,43.46 177.82,43.46 177.94,43.58 179.73,43.58 179.79,43.64 179.79,44.66 179.28,45.17 177.95,45.17 177.38,45.74 177.38,46.44 177.57,46.63 179.03,46.63
GND on BOTTOM (solid shape): 14.7,31.39 14.7,29.2 13.71,28.21 13.71,26.97 13.46,26.71 2.49,26.71 2.5,26.81 2.5,26.9 2.5,30.17 2.74,30.73 3.3,30.96 12.28,30.96 12.79,31.18 12.98,31.69 14.4,31.69
GND on BOTTOM (solid shape): 47.85,44.39 47.94,44.33 47.92,44.22 47.83,44.07 47.82,43.9 47.83,43.88 47.51,43.55 46.5,43.55 46.42,43.61 46.42,43.71 46.47,43.94 46.38,44.15 46.35,44.22 46.38,44.29 46.41,44.33 46.45,44.39
GND on BOTTOM (solid shape): 118.24,67.2 118.24,67 118.5,66.74 118.5,64.01 118.31,63.82 117.8,63.82 117.61,64.01 117.61,64.49 117.61,64.5 117.63,64.61 117.61,64.72 117.61,64.73 117.61,65.14 117.61,65.15 117.63,65.26 117.61,65.37 117.61,65.38 117.61,65.79 117.61,65.8 117.63,65.91 117.61,66.02 117.61,66.03 117.61,66.44 117.61,66.45 117.63,66.56 117.61,66.67 117.61,66.68 117.61,67.09 117.63,67.15 117.63,67.2 117.76,67.32 118.12,67.32
GND on BOTTOM (solid shape): 162.13,56.03 162.13,55.52 162.21,55.45 162.21,55.37 162.29,55.37 162.39,55.27 162.74,55.27 162.96,55.05 162.96,54.95 163.12,54.79 163.82,54.79 164.04,55.01 164.04,55.52 164.17,55.64 167.21,55.64 167.34,55.51 167.34,54.82 167.22,54.69 166.77,54.69 166.45,54.37 166.01,54.37 165.95,54.31 165.95,53.55 166.64,52.85 166.64,52.02 167.03,51.64 167.03,50.25 166.9,50.12 164.61,50.12 164.36,50.37 164.36,51.2 164.03,51.52 162.19,51.52 162.01,51.71 162.01,55.01 161.88,55.14 161.37,55.14 161.25,55.27 161.25,56.09 161.31,56.16 162.01,56.16
GND on BOTTOM (solid shape): 138.3,8.05 141.8,10.3 145.41,8.22 147.9,3.66 147.9,0.25 134.52,0.25
GND on BOTTOM (solid shape): 14.57,52.82 14.57,51.58 13.96,50.97 13.96,47.03 14.42,46.58 14.42,45.32 13.44,44.34 12.98,44.34 12.77,44.83 12.28,45.04 3.3,45.04 2.74,45.27 2.5,45.83 2.5,51.87 2.74,52.43 3.3,52.66 12.28,52.66 12.73,52.82 12.97,53.23 14.17,53.23
GND on BOTTOM (solid shape): 177.91,18.07 177.91,17.01 178.11,16.81 178.49,16.81 178.6,16.8 178.7,16.81 179.49,16.81 179.6,16.8 179.7,16.81 179.95,16.81 180.3,17.16 180.3,18.05 180.49,18.24 181.76,18.24 181.95,18.05 181.95,16.85 182.31,16.48 182.31,15.93 182.14,15.76 181.97,15.76 181.79,15.94 181.66,16.3 181.28,16.34 181.02,16.34 180.64,16.31 180.5,15.96 180.5,15.89 180.39,15.77 180.13,15.77 180.01,15.9 180,15.92 180,16.06 179.83,16.23 179.76,16.23 179.65,16.25 179.54,16.23 179.21,16.23 179.07,16.26 178.92,16.23 177.97,16.23 177.57,15.83 176.61,15.83 176.23,16.21 176.23,18.05 176.42,18.24 177.74,18.24
GND on BOTTOM (solid shape): 103.74,40.13 103.75,40.12 103.97,40.03 104.19,40.13 104.39,40.13 104.61,40.03 104.84,40.13 105.04,40.13 105.26,40.03 105.49,40.13 105.69,40.13 105.91,40.03 106.13,40.13 106.15,40.14 106.36,40.14 106.38,40.13 106.47,40.08 106.57,40.06 106.78,39.85 106.78,39.34 106.74,39.32 106.64,39.26 106.57,39.17 106.46,39.07 106.46,38.81 106.04,38.39 106,38.38 105.96,38.36 105.79,38.36 105.32,38.83 105.32,39.19 105.18,39.33 103.72,39.33 103.64,39.34 103.57,39.33 103.34,39.33 103.1,39.57 103.1,39.59 103.01,39.77 102.83,39.85 102.8,39.88 102.8,40.3 102.88,40.39 103.48,40.39
GND on BOTTOM (solid shape): 105.08,62.04 105.26,61.98 105.45,62.04 105.73,62.04 105.91,61.98 106.1,62.04 106.38,62.04 106.4,62.03 106.46,62 106.46,61.7 106.74,61.43 106.74,61.26 106.7,61.25 106.63,61.21 106.57,61.16 106.5,61.13 106.42,61.16 106.17,61.27 105.92,61.17 105.85,61.14 105.54,61.27 105.22,61.14 105.15,61.17 104.87,61.27 104.61,61.12 104.57,61.13 104.54,61.15 104.34,61.35 104.34,61.48 104.55,61.62 104.62,61.86 104.62,61.88 104.74,62.01 104.8,62.04
GND on BOTTOM (solid shape): 13.53,80.13 13.53,69.33 14.47,68.39 14.47,67.15 14.01,66.69 12.53,66.69 12.41,66.72 12.28,66.74 4.3,66.74 3.74,66.97 3.5,67.53 3.5,75.1 3.18,75.92 1.87,76.55 1.66,77.09 1.66,78.25 1.9,78.81 2.46,79.05 8.28,79.05 8.29,79.01 9.07,78.56 9.65,79.25 9.65,80.82 12.85,80.82
GND on BOTTOM (solid shape): outline of 146 points within 224.8,28.03 231.62,37.23
GND on BOTTOM (solid shape): outline of 91 points within 109.8,63.76 111.58,68.42
GND on BOTTOM (solid shape): outline of 153 points within 0.25,119.3 8.72,125.05
GND on BOTTOM (solid shape): 110.15,40.62 110.15,38.55 110.21,38.5 110.21,38.49 110.32,38.36 110.47,38.31 110.49,38.31 110.56,38.24 110.56,38.22 110.59,38.12 110.65,38.03 110.65,37.88 110.58,37.76 110.56,37.61 110.53,37.61 110.19,37.35 110.45,37.01 110.47,37.01 110.56,36.93 110.56,36.91 110.61,36.78 110.71,36.68 110.75,36.61 110.72,36.53 110.62,36.43 110.37,36.43 110.06,36.73 109.94,36.73 109.92,36.76 109.77,36.91 109.56,36.93 109.08,37.41 109.04,37.48 108.97,37.54 108.97,37.73 109.1,37.98 108.94,38.22 108.73,38.42 108.71,38.45 108.4,38.64 108.08,38.45 108.07,38.42 107.88,38.42 107.79,38.5 107.79,38.67 108.12,38.99 108.13,38.99 108.67,38.99 108.68,38.99 109.11,39.17 108.86,39.56 108.85,39.57 108.75,39.67 108.72,39.74 108.72,40.1 108.74,40.17 108.76,40.24 108.8,40.28 108.82,40.28 108.96,40.32 109.06,40.42 109.07,40.43 109.24,40.57 109.26,40.57 109.41,40.62 109.51,40.73 110.04,40.73
GND on BOTTOM (solid shape): 107.14,67.05 107.3,67.05 107.43,66.92 107.43,66.42 107.42,66.41 107.39,66.26 107.42,66.11 107.43,66.1 107.43,66.07 107.51,65.98 107.51,65.87 107.37,65.59 107.5,65.31 107.51,65.3 107.51,65.23 107.5,65.21 107.39,64.95 107.51,64.69 107.51,64.55 107.43,64.44 107.4,64.31 107.35,64.27 107.34,64.27 107.14,64.21 107.02,64.05 107.01,64.03 106.99,64 106.96,64 106.77,63.99 106.61,63.89 106.44,63.89 106.18,64.01 105.91,63.9 105.9,63.89 105.81,63.89 105.79,63.9 105.54,64.01 105.28,63.9 105.26,63.89 105.17,63.89 105.16,63.9 104.9,64.01 104.64,63.9 104.63,63.89 104.54,63.89 104.49,63.93 104.4,64.01 104.4,64.24 104.61,64.41 104.62,64.68 104.67,64.73 104.69,64.73 104.78,64.77 104.85,64.84 105.02,64.84 105.26,64.72 105.5,64.84 105.67,64.84 105.91,64.72 106.15,64.84 106.33,64.84 106.81,64.85 106.66,65.32 106.65,65.32 106.62,65.35 106.62,65.64 106.63,65.64 106.63,65.67 106.84,65.93 106.65,66.21 106.65,66.8 106.91,67.06
GND on BOTTOM (solid shape): outline of 240 points within 190.8,8.63 205.95,19.96
GND on BOTTOM (solid shape): 12.56,102.92 12.3,102.19 11.64,101.79 11.4,102.02 9.35,102.02 9.09,101.76 7.96,101.76 7.96,101.52 7.62,100.7 6.8,100.36 6,100.36 5.18,100.7 4.84,101.52 4.84,101.76 3.86,101.76 3.6,102.02 1.68,102.02 1.42,101.76 1,101.76 0.76,101.66 0.66,101.42 0.66,100.8 0.76,100.56 1,100.46 1.8,100.46 2.83,100.03 3.26,99 3.26,98.15 3.68,97.73 11.7,97.73 13.28,96.16 13.28,93.95 12.8,93.46 9.65,93.46 9.65,94.75 9.07,95.44 8.29,94.99 8.28,94.95 1,94.95 0.44,95.19 0.2,95.75 0.2,96.9 0.44,97.46 1,97.7 1.8,97.7 2.51,97.99 2.8,98.7 2.8,99 2.51,99.71 1.8,100 1,100 0.44,100.24 0.2,100.8 0.2,101.42 0.44,101.99 1,102.22 5,102.22 5.21,102.13 5.3,101.92 5.3,101.52 5.5,101.03 6,100.82 6.8,100.82 7.3,101.03 7.5,101.52 7.5,101.92 7.59,102.13 7.8,102.22 11.4,102.22 11.9,102.43 12.1,102.92 12.1,103.62 12.56,103.62
GND on BOTTOM (solid shape): outline of 262 points within 0.2,0.2 231.7,138.3
GND on BOTTOM (solid shape): outline of 15419 points within 34.59,17.55 78.96,90.82
GND on IN1 (solid shape): 64.47,119.42 66.83,119.42 67.2,119.06 67.2,117 67.03,116.82 61.73,116.82 61.48,117.07 61.48,120.06 61.64,120.23 63.67,120.23
GND on IN1 (solid shape): 67.26,125.02 67.26,123.27 67.1,123.1 65.55,123.1 64.29,124.36 62.13,124.36 61.95,124.54 61.95,124.73 62.8,125.58 66.7,125.58
GND on IN1 (solid shape): 65.08,121.71 66.9,121.71 67.03,121.58 67.03,121.3 66.95,121.21 64.77,121.21 64.23,121.75 61.69,121.75 61.49,121.94 61.49,122.9 61.6,123 63.78,123
GND on IN1 (solid shape): 158.75,81.28 158.75,79.06 158.39,78.7 158.39,76.22 158.39,76.22 158.39,74.51 158.32,74.45 152.12,74.45 151.95,74.62 151.95,78.25 152.21,78.51 154.58,78.51 155.49,79.42 155.49,80.74 156.15,81.4 158.63,81.4
GND on IN1 (solid shape): 158.72,71.59 158.72,69.51 157.12,67.91 157.12,63.21 156.74,62.83 154.13,62.83 152.55,64.41 152.55,64.43 151.79,65.19 151.79,68.12 152.24,68.57 153.36,68.57 155.29,70.51 155.29,70.9 155.31,71.02 155.29,71.14 155.29,71.23 155.3,71.24 155.3,71.54 155.48,71.72 158.59,71.72
GND on IN1 (solid shape): 14.7,31.39 14.7,29.2 13.71,28.21 13.71,26.97 13.46,26.71 2.49,26.71 2.5,26.81 2.5,26.9 2.5,30.17 2.74,30.73 3.3,30.96 12.28,30.96 12.79,31.18 12.98,31.69 14.4,31.69
GND on IN1 (solid shape): 14.57,52.82 14.57,51.58 13.96,50.97 13.96,47.03 14.42,46.58 14.42,45.32 13.44,44.34 12.98,44.34 12.77,44.83 12.28,45.04 3.3,45.04 2.74,45.27 2.5,45.83 2.5,51.87 2.74,52.43 3.3,52.66 12.28,52.66 12.73,52.82 12.97,53.23 14.17,53.23
GND on IN1 (solid shape): 13.53,80.13 13.53,69.33 14.47,68.39 14.47,67.15 14.01,66.69 12.53,66.69 12.41,66.72 12.28,66.74 4.3,66.74 3.74,66.97 3.5,67.53 3.5,75.1 3.18,75.92 1.87,76.55 1.66,77.09 1.66,78.25 1.9,78.81 2.46,79.05 8.28,79.05 8.29,79.01 9.07,78.56 9.65,79.25 9.65,80.82 12.85,80.82
GND on IN1 (solid shape): 12.56,102.92 12.3,102.19 11.64,101.79 11.4,102.02 9.35,102.02 9.09,101.76 7.96,101.76 7.96,101.52 7.62,100.7 6.8,100.36 6,100.36 5.18,100.7 4.84,101.52 4.84,101.76 3.86,101.76 3.6,102.02 1.68,102.02 1.42,101.76 1,101.76 0.76,101.66 0.66,101.42 0.66,100.8 0.76,100.56 1,100.46 1.8,100.46 2.83,100.03 3.26,99 3.26,98.15 3.68,97.73 11.7,97.73 13.28,96.16 13.28,93.95 12.8,93.46 9.65,93.46 9.65,94.75 9.07,95.44 8.29,94.99 8.28,94.95 1,94.95 0.44,95.19 0.2,95.75 0.2,96.9 0.44,97.46 1,97.7 1.8,97.7 2.51,97.99 2.8,98.7 2.8,99 2.51,99.71 1.8,100 1,100 0.44,100.24 0.2,100.8 0.2,101.42 0.44,101.99 1,102.22 5,102.22 5.21,102.13 5.3,101.92 5.3,101.52 5.5,101.03 6,100.82 6.8,100.82 7.3,101.03 7.5,101.52 7.5,101.92 7.59,102.13 7.8,102.22 11.4,102.22 11.9,102.43 12.1,102.92 12.1,103.62 12.56,103.62
GND on IN1 (solid shape): outline of 315 points within 77.84,101.24 84.67,110.46
GND on IN1 (solid shape): outline of 283 points within 0.2,0.2 231.7,138.3
GND on IN2 (solid shape): 67.32,125.11 67.32,121.66 66.87,121.21 65.81,121.21 65.6,121.01 65.6,119.97 65.95,119.63 67.11,119.63 67.32,119.42 67.32,117.11 67.03,116.82 61.73,116.82 61.48,117.07 61.48,124.47 62.69,125.68 66.75,125.68
GND on IN2 (solid shape): 158.71,71.61 158.71,69.49 157.12,67.9 157.12,63.21 156.74,62.83 154.13,62.83 152.55,64.41 152.55,64.43 151.79,65.19 151.79,68.12 152.24,68.57 153.66,68.57 154.01,68.92 154.96,69.87 155.4,70.31 155.4,71.39 155.73,71.72 155.75,71.72 155.78,71.76 158.56,71.76
GND on IN2 (solid shape): 158.77,81.31 158.77,79.08 158.39,78.7 158.39,74.51 158.32,74.45 152.12,74.45 151.94,74.63 151.94,78.25 152.2,78.51 154.26,78.51 154.39,78.64 154.7,78.64 155.49,79.43 155.49,80.74 156.2,81.45 158.63,81.45
GND on IN2 (solid shape): 14.7,31.39 14.7,29.2 13.71,28.21 13.71,26.97 13.46,26.71 2.49,26.71 2.5,26.81 2.5,26.9 2.5,30.17 2.74,30.73 3.3,30.96 12.28,30.96 12.79,31.18 12.98,31.69 14.4,31.69
GND on IN2 (solid shape): 14.57,52.82 14.57,51.58 13.96,50.97 13.96,47.03 14.42,46.58 14.42,45.32 13.44,44.34 12.98,44.34 12.77,44.83 12.28,45.04 3.3,45.04 2.74,45.27 2.5,45.83 2.5,51.87 2.74,52.43 3.3,52.66 12.28,52.66 12.73,52.82 12.97,53.23 14.17,53.23
GND on IN2 (solid shape): 13.53,80.13 13.53,69.33 14.47,68.39 14.47,67.15 14.01,66.69 12.53,66.69 12.41,66.72 12.28,66.74 4.3,66.74 3.74,66.97 3.5,67.53 3.5,75.1 3.18,75.92 1.87,76.55 1.66,77.09 1.66,78.25 1.9,78.81 2.46,79.05 8.28,79.05 8.29,79.01 9.07,78.56 9.65,79.25 9.65,80.82 12.85,80.82
